VERSION ""

NS_ :

BS_:

BU_: MBMU PC SBMU IMM ETH DCDC LEMS

BO_ 2336485024 M2P_SUMDATA60__16: 8 MBMU
 SG_ M2P_Measure_Vol_B10_16 : 0|16@1+ (0.1,0) [0|6553.5] "V"  PC,SBMU
 SG_ M2P_Current_B10_16 : 16|16@1+ (1,-20000) [-20000|45535] "A"  PC,SBMU
 SG_ M2P_PermitMaxCharge_I_B10_16 : 32|16@1+ (1,-20000) [-20000|45535] "A"  PC
 SG_ M2P_PermitMaxDisCharge_I_B10_16 : 48|16@1+ (1,-20000) [-20000|45535] "A"  PC

BO_ 2336485025 M2P_SUMDATA60__17: 8 MBMU
 SG_ M2P_Measure_Vol_B10_17 : 0|16@1+ (0.1,0) [0|6553.5] "V"  PC,SBMU
 SG_ M2P_Current_B10_17 : 16|16@1+ (1,-20000) [-20000|45535] "A"  PC,SBMU
 SG_ M2P_PermitMaxCharge_I_B10_17 : 32|16@1+ (1,-20000) [-20000|45535] "A"  PC
 SG_ M2P_PermitMaxDisCharge_I_B10_17 : 48|16@1+ (1,-20000) [-20000|45535] "A"  PC

BO_ 2336485026 M2P_SUMDATA60__18: 8 MBMU
 SG_ M2P_Measure_Vol_B10_18 : 0|16@1+ (0.1,0) [0|6553.5] "V"  PC,SBMU
 SG_ M2P_Current_B10_18 : 16|16@1+ (1,-20000) [-20000|45535] "A"  PC,SBMU
 SG_ M2P_PermitMaxCharge_I_B10_18 : 32|16@1+ (1,-20000) [-20000|45535] "A"  PC
 SG_ M2P_PermitMaxDisCharge_I_B10_18 : 48|16@1+ (1,-20000) [-20000|45535] "A"  PC

BO_ 2336485027 M2P_SUMDATA60__19: 8 MBMU
 SG_ M2P_Measure_Vol_B10_19 : 0|16@1+ (0.1,0) [0|6553.5] "V"  PC,SBMU
 SG_ M2P_Current_B10_19 : 16|16@1+ (1,-20000) [-20000|45535] "A"  PC,SBMU
 SG_ M2P_PermitMaxCharge_I_B10_19 : 32|16@1+ (1,-20000) [-20000|45535] "A"  PC
 SG_ M2P_PermitMaxDisCharge_I_B10_19 : 48|16@1+ (1,-20000) [-20000|45535] "A"  PC

BO_ 2336485028 M2P_SUMDATA60__20: 8 MBMU
 SG_ M2P_Measure_Vol_B10_20 : 0|16@1+ (0.1,0) [0|6553.5] "V"  PC,SBMU
 SG_ M2P_Current_B10_20 : 16|16@1+ (1,-20000) [-20000|45535] "A"  PC,SBMU
 SG_ M2P_PermitMaxCharge_I_B10_20 : 32|16@1+ (1,-20000) [-20000|45535] "A"  PC
 SG_ M2P_PermitMaxDisCharge_I_B10_20 : 48|16@1+ (1,-20000) [-20000|45535] "A"  PC

BO_ 2336485029 M2P_SUMDATA60__21: 8 MBMU
 SG_ M2P_Measure_Vol_B10_21 : 0|16@1+ (0.1,0) [0|6553.5] "V"  PC,SBMU
 SG_ M2P_Current_B10_21 : 16|16@1+ (1,-20000) [-20000|45535] "A"  PC,SBMU
 SG_ M2P_PermitMaxCharge_I_B10_21 : 32|16@1+ (1,-20000) [-20000|45535] "A"  PC
 SG_ M2P_PermitMaxDisCharge_I_B10_21 : 48|16@1+ (1,-20000) [-20000|45535] "A"  PC

BO_ 2336485030 M2P_SUMDATA60__22: 8 MBMU
 SG_ M2P_Measure_Vol_B10_22 : 0|16@1+ (0.1,0) [0|6553.5] "V"  PC,SBMU
 SG_ M2P_Current_B10_22 : 16|16@1+ (1,-20000) [-20000|45535] "A"  PC,SBMU
 SG_ M2P_PermitMaxCharge_I_B10_22 : 32|16@1+ (1,-20000) [-20000|45535] "A"  PC
 SG_ M2P_PermitMaxDisCharge_I_B10_22 : 48|16@1+ (1,-20000) [-20000|45535] "A"  PC

BO_ 2336485031 M2P_SUMDATA60__23: 8 MBMU
 SG_ M2P_Measure_Vol_B10_23 : 0|16@1+ (0.1,0) [0|6553.5] "V"  PC,SBMU
 SG_ M2P_Current_B10_23 : 16|16@1+ (1,-20000) [-20000|45535] "A"  PC,SBMU
 SG_ M2P_PermitMaxCharge_I_B10_23 : 32|16@1+ (1,-20000) [-20000|45535] "A"  PC
 SG_ M2P_PermitMaxDisCharge_I_B10_23 : 48|16@1+ (1,-20000) [-20000|45535] "A"  PC

BO_ 2336485032 M2P_SUMDATA60__24: 8 MBMU
 SG_ M2P_Measure_Vol_B10_24 : 0|16@1+ (0.1,0) [0|6553.5] "V"  PC,SBMU
 SG_ M2P_Current_B10_24 : 16|16@1+ (1,-20000) [-20000|45535] "A"  PC,SBMU
 SG_ M2P_PermitMaxCharge_I_B10_24 : 32|16@1+ (1,-20000) [-20000|45535] "A"  PC
 SG_ M2P_PermitMaxDisCharge_I_B10_24 : 48|16@1+ (1,-20000) [-20000|45535] "A"  PC

BO_ 2336485033 M2P_SUMDATA60__25: 8 MBMU
 SG_ M2P_Measure_Vol_B10_25 : 0|16@1+ (0.1,0) [0|6553.5] "V"  PC,SBMU
 SG_ M2P_Current_B10_25 : 16|16@1+ (1,-20000) [-20000|45535] "A"  PC,SBMU
 SG_ M2P_PermitMaxCharge_I_B10_25 : 32|16@1+ (1,-20000) [-20000|45535] "A"  PC
 SG_ M2P_PermitMaxDisCharge_I_B10_25 : 48|16@1+ (1,-20000) [-20000|45535] "A"  PC

BO_ 2336485034 M2P_SUMDATA60__26: 8 MBMU
 SG_ M2P_Measure_Vol_B10_26 : 0|16@1+ (0.1,0) [0|6553.5] "V"  PC,SBMU
 SG_ M2P_Current_B10_26 : 16|16@1+ (1,-20000) [-20000|45535] "A"  PC,SBMU
 SG_ M2P_PermitMaxCharge_I_B10_26 : 32|16@1+ (1,-20000) [-20000|45535] "A"  PC
 SG_ M2P_PermitMaxDisCharge_I_B10_26 : 48|16@1+ (1,-20000) [-20000|45535] "A"  PC

BO_ 2336485035 M2P_SUMDATA60__27: 8 MBMU
 SG_ M2P_Measure_Vol_B10_27 : 0|16@1+ (0.1,0) [0|6553.5] "V"  PC,SBMU
 SG_ M2P_Current_B10_27 : 16|16@1+ (1,-20000) [-20000|45535] "A"  PC,SBMU
 SG_ M2P_PermitMaxCharge_I_B10_27 : 32|16@1+ (1,-20000) [-20000|45535] "A"  PC
 SG_ M2P_PermitMaxDisCharge_I_B10_27 : 48|16@1+ (1,-20000) [-20000|45535] "A"  PC

BO_ 2336485036 M2P_SUMDATA60__28: 8 MBMU
 SG_ M2P_Measure_Vol_B10_28 : 0|16@1+ (0.1,0) [0|6553.5] "V"  PC,SBMU
 SG_ M2P_Current_B10_28 : 16|16@1+ (1,-20000) [-20000|45535] "A"  PC,SBMU
 SG_ M2P_PermitMaxCharge_I_B10_28 : 32|16@1+ (1,-20000) [-20000|45535] "A"  PC
 SG_ M2P_PermitMaxDisCharge_I_B10_28 : 48|16@1+ (1,-20000) [-20000|45535] "A"  PC

BO_ 2336485037 M2P_SUMDATA60__29: 8 MBMU
 SG_ M2P_Measure_Vol_B10_29 : 0|16@1+ (0.1,0) [0|6553.5] "V"  PC,SBMU
 SG_ M2P_Current_B10_29 : 16|16@1+ (1,-20000) [-20000|45535] "A"  PC,SBMU
 SG_ M2P_PermitMaxCharge_I_B10_29 : 32|16@1+ (1,-20000) [-20000|45535] "A"  PC
 SG_ M2P_PermitMaxDisCharge_I_B10_29 : 48|16@1+ (1,-20000) [-20000|45535] "A"  PC

BO_ 2336485038 M2P_SUMDATA60__30: 8 MBMU
 SG_ M2P_Measure_Vol_B10_30 : 0|16@1+ (0.1,0) [0|6553.5] "V"  PC,SBMU
 SG_ M2P_Current_B10_30 : 16|16@1+ (1,-20000) [-20000|45535] "A"  PC,SBMU
 SG_ M2P_PermitMaxCharge_I_B10_30 : 32|16@1+ (1,-20000) [-20000|45535] "A"  PC
 SG_ M2P_PermitMaxDisCharge_I_B10_30 : 48|16@1+ (1,-20000) [-20000|45535] "A"  PC

BO_ 2336485039 M2P_SUMDATA60__31: 8 MBMU
 SG_ M2P_Measure_Vol_B10_31 : 0|16@1+ (0.1,0) [0|6553.5] "V"  PC,SBMU
 SG_ M2P_Current_B10_31 : 16|16@1+ (1,-20000) [-20000|45535] "A"  PC,SBMU
 SG_ M2P_PermitMaxCharge_I_B10_31 : 32|16@1+ (1,-20000) [-20000|45535] "A"  PC
 SG_ M2P_PermitMaxDisCharge_I_B10_31 : 48|16@1+ (1,-20000) [-20000|45535] "A"  PC

BO_ 2336550545 M2P_SUMDATA61__01: 8 MBMU
 SG_ M2P_PermitMaxVolt_B10_01 : 0|16@1+ (0.1,0) [0|6553.5] "V"  PC
 SG_ M2P_PermitMinVolt_B10_01 : 16|16@1+ (0.1,0) [0|6553.5] "V"  PC
 SG_ M2P_PermitMaxPow_Chg_B10_01 : 32|16@1+ (1,-20000) [-20000|45535] "Kw"  PC
 SG_ M2P_PermitMaxPow_DisChg_B10_01 : 48|16@1+ (1,-20000) [-20000|45535] "Kw"  PC

BO_ 2336550546 M2P_SUMDATA61__02: 8 MBMU
 SG_ M2P_PermitMaxVolt_B10_02 : 0|16@1+ (0.1,0) [0|6553.5] "V"  PC
 SG_ M2P_PermitMinVolt_B10_02 : 16|16@1+ (0.1,0) [0|6553.5] "V"  PC
 SG_ M2P_PermitMaxPow_Chg_B10_02 : 32|16@1+ (1,-20000) [-20000|45535] "Kw"  PC
 SG_ M2P_PermitMaxPow_DisChg_B10_02 : 48|16@1+ (1,-20000) [-20000|45535] "Kw"  PC

BO_ 2336550547 M2P_SUMDATA61__03: 8 MBMU
 SG_ M2P_PermitMaxVolt_B10_03 : 0|16@1+ (0.1,0) [0|6553.5] "V"  PC
 SG_ M2P_PermitMinVolt_B10_03 : 16|16@1+ (0.1,0) [0|6553.5] "V"  PC
 SG_ M2P_PermitMaxPow_Chg_B10_03 : 32|16@1+ (1,-20000) [-20000|45535] "Kw"  PC
 SG_ M2P_PermitMaxPow_DisChg_B10_03 : 48|16@1+ (1,-20000) [-20000|45535] "Kw"  PC

BO_ 2336550548 M2P_SUMDATA61__04: 8 MBMU
 SG_ M2P_PermitMaxVolt_B10_04 : 0|16@1+ (0.1,0) [0|6553.5] "V"  PC
 SG_ M2P_PermitMinVolt_B10_04 : 16|16@1+ (0.1,0) [0|6553.5] "V"  PC
 SG_ M2P_PermitMaxPow_Chg_B10_04 : 32|16@1+ (1,-20000) [-20000|45535] "Kw"  PC
 SG_ M2P_PermitMaxPow_DisChg_B10_04 : 48|16@1+ (1,-20000) [-20000|45535] "Kw"  PC

BO_ 2336550549 M2P_SUMDATA61__05: 8 MBMU
 SG_ M2P_PermitMaxVolt_B10_05 : 0|16@1+ (0.1,0) [0|6553.5] "V"  PC
 SG_ M2P_PermitMinVolt_B10_05 : 16|16@1+ (0.1,0) [0|6553.5] "V"  PC
 SG_ M2P_PermitMaxPow_Chg_B10_05 : 32|16@1+ (1,-20000) [-20000|45535] "Kw"  PC
 SG_ M2P_PermitMaxPow_DisChg_B10_05 : 48|16@1+ (1,-20000) [-20000|45535] "Kw"  PC

BO_ 2336550550 M2P_SUMDATA61__06: 8 MBMU
 SG_ M2P_PermitMaxVolt_B10_06 : 0|16@1+ (0.1,0) [0|6553.5] "V"  PC
 SG_ M2P_PermitMinVolt_B10_06 : 16|16@1+ (0.1,0) [0|6553.5] "V"  PC
 SG_ M2P_PermitMaxPow_Chg_B10_06 : 32|16@1+ (1,-20000) [-20000|45535] "Kw"  PC
 SG_ M2P_PermitMaxPow_DisChg_B10_06 : 48|16@1+ (1,-20000) [-20000|45535] "Kw"  PC

BO_ 2336550551 M2P_SUMDATA61__07: 8 MBMU
 SG_ M2P_PermitMaxVolt_B10_07 : 0|16@1+ (0.1,0) [0|6553.5] "V"  PC
 SG_ M2P_PermitMinVolt_B10_07 : 16|16@1+ (0.1,0) [0|6553.5] "V"  PC
 SG_ M2P_PermitMaxPow_Chg_B10_07 : 32|16@1+ (1,-20000) [-20000|45535] "Kw"  PC
 SG_ M2P_PermitMaxPow_DisChg_B10_07 : 48|16@1+ (1,-20000) [-20000|45535] "Kw"  PC

BO_ 2336550552 M2P_SUMDATA61__08: 8 MBMU
 SG_ M2P_PermitMaxVolt_B10_08 : 0|16@1+ (0.1,0) [0|6553.5] "V"  PC
 SG_ M2P_PermitMinVolt_B10_08 : 16|16@1+ (0.1,0) [0|6553.5] "V"  PC
 SG_ M2P_PermitMaxPow_Chg_B10_08 : 32|16@1+ (1,-20000) [-20000|45535] "Kw"  PC
 SG_ M2P_PermitMaxPow_DisChg_B10_08 : 48|16@1+ (1,-20000) [-20000|45535] "Kw"  PC

BO_ 2336550553 M2P_SUMDATA61__09: 8 MBMU
 SG_ M2P_PermitMaxVolt_B10_09 : 0|16@1+ (0.1,0) [0|6553.5] "V"  PC
 SG_ M2P_PermitMinVolt_B10_09 : 16|16@1+ (0.1,0) [0|6553.5] "V"  PC
 SG_ M2P_PermitMaxPow_Chg_B10_09 : 32|16@1+ (1,-20000) [-20000|45535] "Kw"  PC
 SG_ M2P_PermitMaxPow_DisChg_B10_09 : 48|16@1+ (1,-20000) [-20000|45535] "Kw"  PC

BO_ 2336550554 M2P_SUMDATA61__10: 8 MBMU
 SG_ M2P_PermitMaxVolt_B10_10 : 0|16@1+ (0.1,0) [0|6553.5] "V"  PC
 SG_ M2P_PermitMinVolt_B10_10 : 16|16@1+ (0.1,0) [0|6553.5] "V"  PC
 SG_ M2P_PermitMaxPow_Chg_B10_10 : 32|16@1+ (1,-20000) [-20000|45535] "Kw"  PC
 SG_ M2P_PermitMaxPow_DisChg_B10_10 : 48|16@1+ (1,-20000) [-20000|45535] "Kw"  PC

BO_ 2336550555 M2P_SUMDATA61__11: 8 MBMU
 SG_ M2P_PermitMaxVolt_B10_11 : 0|16@1+ (0.1,0) [0|6553.5] "V"  PC
 SG_ M2P_PermitMinVolt_B10_11 : 16|16@1+ (0.1,0) [0|6553.5] "V"  PC
 SG_ M2P_PermitMaxPow_Chg_B10_11 : 32|16@1+ (1,-20000) [-20000|45535] "Kw"  PC
 SG_ M2P_PermitMaxPow_DisChg_B10_11 : 48|16@1+ (1,-20000) [-20000|45535] "Kw"  PC

BO_ 2336550556 M2P_SUMDATA61__12: 8 MBMU
 SG_ M2P_PermitMaxVolt_B10_12 : 0|16@1+ (0.1,0) [0|6553.5] "V"  PC
 SG_ M2P_PermitMinVolt_B10_12 : 16|16@1+ (0.1,0) [0|6553.5] "V"  PC
 SG_ M2P_PermitMaxPow_Chg_B10_12 : 32|16@1+ (1,-20000) [-20000|45535] "Kw"  PC
 SG_ M2P_PermitMaxPow_DisChg_B10_12 : 48|16@1+ (1,-20000) [-20000|45535] "Kw"  PC

BO_ 2336550557 M2P_SUMDATA61__13: 8 MBMU
 SG_ M2P_PermitMaxVolt_B10_13 : 0|16@1+ (0.1,0) [0|6553.5] "V"  PC
 SG_ M2P_PermitMinVolt_B10_13 : 16|16@1+ (0.1,0) [0|6553.5] "V"  PC
 SG_ M2P_PermitMaxPow_Chg_B10_13 : 32|16@1+ (1,-20000) [-20000|45535] "Kw"  PC
 SG_ M2P_PermitMaxPow_DisChg_B10_13 : 48|16@1+ (1,-20000) [-20000|45535] "Kw"  PC

BO_ 2336550558 M2P_SUMDATA61__14: 8 MBMU
 SG_ M2P_PermitMaxVolt_B10_14 : 0|16@1+ (0.1,0) [0|6553.5] "V"  PC
 SG_ M2P_PermitMinVolt_B10_14 : 16|16@1+ (0.1,0) [0|6553.5] "V"  PC
 SG_ M2P_PermitMaxPow_Chg_B10_14 : 32|16@1+ (1,-20000) [-20000|45535] "Kw"  PC
 SG_ M2P_PermitMaxPow_DisChg_B10_14 : 48|16@1+ (1,-20000) [-20000|45535] "Kw"  PC

BO_ 2336550559 M2P_SUMDATA61__15: 8 MBMU
 SG_ M2P_PermitMaxVolt_B10_15 : 0|16@1+ (0.1,0) [0|6553.5] "V"  PC
 SG_ M2P_PermitMinVolt_B10_15 : 16|16@1+ (0.1,0) [0|6553.5] "V"  PC
 SG_ M2P_PermitMaxPow_Chg_B10_15 : 32|16@1+ (1,-20000) [-20000|45535] "Kw"  PC
 SG_ M2P_PermitMaxPow_DisChg_B10_15 : 48|16@1+ (1,-20000) [-20000|45535] "Kw"  PC

BO_ 2336550560 M2P_SUMDATA61__16: 8 MBMU
 SG_ M2P_PermitMaxVolt_B10_16 : 0|16@1+ (0.1,0) [0|6553.5] "V"  PC
 SG_ M2P_PermitMinVolt_B10_16 : 16|16@1+ (0.1,0) [0|6553.5] "V"  PC
 SG_ M2P_PermitMaxPow_Chg_B10_16 : 32|16@1+ (1,-20000) [-20000|45535] "Kw"  PC
 SG_ M2P_PermitMaxPow_DisChg_B10_16 : 48|16@1+ (1,-20000) [-20000|45535] "Kw"  PC

BO_ 2336550561 M2P_SUMDATA61__17: 8 MBMU
 SG_ M2P_PermitMaxVolt_B10_17 : 0|16@1+ (0.1,0) [0|6553.5] "V"  PC
 SG_ M2P_PermitMinVolt_B10_17 : 16|16@1+ (0.1,0) [0|6553.5] "V"  PC
 SG_ M2P_PermitMaxPow_Chg_B10_17 : 32|16@1+ (1,-20000) [-20000|45535] "Kw"  PC
 SG_ M2P_PermitMaxPow_DisChg_B10_17 : 48|16@1+ (1,-20000) [-20000|45535] "Kw"  PC

BO_ 2336550562 M2P_SUMDATA61__18: 8 MBMU
 SG_ M2P_PermitMaxVolt_B10_18 : 0|16@1+ (0.1,0) [0|6553.5] "V"  PC
 SG_ M2P_PermitMinVolt_B10_18 : 16|16@1+ (0.1,0) [0|6553.5] "V"  PC
 SG_ M2P_PermitMaxPow_Chg_B10_18 : 32|16@1+ (1,-20000) [-20000|45535] "Kw"  PC
 SG_ M2P_PermitMaxPow_DisChg_B10_18 : 48|16@1+ (1,-20000) [-20000|45535] "Kw"  PC

BO_ 2336550563 M2P_SUMDATA61__19: 8 MBMU
 SG_ M2P_PermitMaxVolt_B10_19 : 0|16@1+ (0.1,0) [0|6553.5] "V"  PC
 SG_ M2P_PermitMinVolt_B10_19 : 16|16@1+ (0.1,0) [0|6553.5] "V"  PC
 SG_ M2P_PermitMaxPow_Chg_B10_19 : 32|16@1+ (1,-20000) [-20000|45535] "Kw"  PC
 SG_ M2P_PermitMaxPow_DisChg_B10_19 : 48|16@1+ (1,-20000) [-20000|45535] "Kw"  PC

BO_ 2336550564 M2P_SUMDATA61__20: 8 MBMU
 SG_ M2P_PermitMaxVolt_B10_20 : 0|16@1+ (0.1,0) [0|6553.5] "V"  PC
 SG_ M2P_PermitMinVolt_B10_20 : 16|16@1+ (0.1,0) [0|6553.5] "V"  PC
 SG_ M2P_PermitMaxPow_Chg_B10_20 : 32|16@1+ (1,-20000) [-20000|45535] "Kw"  PC
 SG_ M2P_PermitMaxPow_DisChg_B10_20 : 48|16@1+ (1,-20000) [-20000|45535] "Kw"  PC

BO_ 2336550565 M2P_SUMDATA61__21: 8 MBMU
 SG_ M2P_PermitMaxVolt_B10_21 : 0|16@1+ (0.1,0) [0|6553.5] "V"  PC
 SG_ M2P_PermitMinVolt_B10_21 : 16|16@1+ (0.1,0) [0|6553.5] "V"  PC
 SG_ M2P_PermitMaxPow_Chg_B10_21 : 32|16@1+ (1,-20000) [-20000|45535] "Kw"  PC
 SG_ M2P_PermitMaxPow_DisChg_B10_21 : 48|16@1+ (1,-20000) [-20000|45535] "Kw"  PC

BO_ 2336550566 M2P_SUMDATA61__22: 8 MBMU
 SG_ M2P_PermitMaxVolt_B10_22 : 0|16@1+ (0.1,0) [0|6553.5] "V"  PC
 SG_ M2P_PermitMinVolt_B10_22 : 16|16@1+ (0.1,0) [0|6553.5] "V"  PC
 SG_ M2P_PermitMaxPow_Chg_B10_22 : 32|16@1+ (1,-20000) [-20000|45535] "Kw"  PC
 SG_ M2P_PermitMaxPow_DisChg_B10_22 : 48|16@1+ (1,-20000) [-20000|45535] "Kw"  PC

BO_ 2336550567 M2P_SUMDATA61__23: 8 MBMU
 SG_ M2P_PermitMaxVolt_B10_23 : 0|16@1+ (0.1,0) [0|6553.5] "V"  PC
 SG_ M2P_PermitMinVolt_B10_23 : 16|16@1+ (0.1,0) [0|6553.5] "V"  PC
 SG_ M2P_PermitMaxPow_Chg_B10_23 : 32|16@1+ (1,-20000) [-20000|45535] "Kw"  PC
 SG_ M2P_PermitMaxPow_DisChg_B10_23 : 48|16@1+ (1,-20000) [-20000|45535] "Kw"  PC

BO_ 2336550568 M2P_SUMDATA61__24: 8 MBMU
 SG_ M2P_PermitMaxVolt_B10_24 : 0|16@1+ (0.1,0) [0|6553.5] "V"  PC
 SG_ M2P_PermitMinVolt_B10_24 : 16|16@1+ (0.1,0) [0|6553.5] "V"  PC
 SG_ M2P_PermitMaxPow_Chg_B10_24 : 32|16@1+ (1,-20000) [-20000|45535] "Kw"  PC
 SG_ M2P_PermitMaxPow_DisChg_B10_24 : 48|16@1+ (1,-20000) [-20000|45535] "Kw"  PC

BO_ 2336550569 M2P_SUMDATA61__25: 8 MBMU
 SG_ M2P_PermitMaxVolt_B10_25 : 0|16@1+ (0.1,0) [0|6553.5] "V"  PC
 SG_ M2P_PermitMinVolt_B10_25 : 16|16@1+ (0.1,0) [0|6553.5] "V"  PC
 SG_ M2P_PermitMaxPow_Chg_B10_25 : 32|16@1+ (1,-20000) [-20000|45535] "Kw"  PC
 SG_ M2P_PermitMaxPow_DisChg_B10_25 : 48|16@1+ (1,-20000) [-20000|45535] "Kw"  PC

BO_ 2336550570 M2P_SUMDATA61__26: 8 MBMU
 SG_ M2P_PermitMaxVolt_B10_26 : 0|16@1+ (0.1,0) [0|6553.5] "V"  PC
 SG_ M2P_PermitMinVolt_B10_26 : 16|16@1+ (0.1,0) [0|6553.5] "V"  PC
 SG_ M2P_PermitMaxPow_Chg_B10_26 : 32|16@1+ (1,-20000) [-20000|45535] "Kw"  PC
 SG_ M2P_PermitMaxPow_DisChg_B10_26 : 48|16@1+ (1,-20000) [-20000|45535] "Kw"  PC

BO_ 2336550571 M2P_SUMDATA61__27: 8 MBMU
 SG_ M2P_PermitMaxVolt_B10_27 : 0|16@1+ (0.1,0) [0|6553.5] "V"  PC
 SG_ M2P_PermitMinVolt_B10_27 : 16|16@1+ (0.1,0) [0|6553.5] "V"  PC
 SG_ M2P_PermitMaxPow_Chg_B10_27 : 32|16@1+ (1,-20000) [-20000|45535] "Kw"  PC
 SG_ M2P_PermitMaxPow_DisChg_B10_27 : 48|16@1+ (1,-20000) [-20000|45535] "Kw"  PC

BO_ 2336550572 M2P_SUMDATA61__28: 8 MBMU
 SG_ M2P_PermitMaxVolt_B10_28 : 0|16@1+ (0.1,0) [0|6553.5] "V"  PC
 SG_ M2P_PermitMinVolt_B10_28 : 16|16@1+ (0.1,0) [0|6553.5] "V"  PC
 SG_ M2P_PermitMaxPow_Chg_B10_28 : 32|16@1+ (1,-20000) [-20000|45535] "Kw"  PC
 SG_ M2P_PermitMaxPow_DisChg_B10_28 : 48|16@1+ (1,-20000) [-20000|45535] "Kw"  PC

BO_ 2336550573 M2P_SUMDATA61__29: 8 MBMU
 SG_ M2P_PermitMaxVolt_B10_29 : 0|16@1+ (0.1,0) [0|6553.5] "V"  PC
 SG_ M2P_PermitMinVolt_B10_29 : 16|16@1+ (0.1,0) [0|6553.5] "V"  PC
 SG_ M2P_PermitMaxPow_Chg_B10_29 : 32|16@1+ (1,-20000) [-20000|45535] "Kw"  PC
 SG_ M2P_PermitMaxPow_DisChg_B10_29 : 48|16@1+ (1,-20000) [-20000|45535] "Kw"  PC

BO_ 2336550574 M2P_SUMDATA61__30: 8 MBMU
 SG_ M2P_PermitMaxVolt_B10_30 : 0|16@1+ (0.1,0) [0|6553.5] "V"  PC
 SG_ M2P_PermitMinVolt_B10_30 : 16|16@1+ (0.1,0) [0|6553.5] "V"  PC
 SG_ M2P_PermitMaxPow_Chg_B10_30 : 32|16@1+ (1,-20000) [-20000|45535] "Kw"  PC
 SG_ M2P_PermitMaxPow_DisChg_B10_30 : 48|16@1+ (1,-20000) [-20000|45535] "Kw"  PC

BO_ 2336550575 M2P_SUMDATA61__31: 8 MBMU
 SG_ M2P_PermitMaxVolt_B10_31 : 0|16@1+ (0.1,0) [0|6553.5] "V"  PC
 SG_ M2P_PermitMinVolt_B10_31 : 16|16@1+ (0.1,0) [0|6553.5] "V"  PC
 SG_ M2P_PermitMaxPow_Chg_B10_31 : 32|16@1+ (1,-20000) [-20000|45535] "Kw"  PC
 SG_ M2P_PermitMaxPow_DisChg_B10_31 : 48|16@1+ (1,-20000) [-20000|45535] "Kw"  PC

BO_ 2336616081 M2P_SUMDATA62__01: 8 MBMU
 SG_ M2P_Power_B10_01 : 0|16@1+ (1,-20000) [-20000|45535] "Kw"  PC
 SG_ M2P_SysremEngy_Chg_B10_01 : 16|16@1+ (1,0) [0|65535] "Kwh"  PC
 SG_ M2P_SysremEngy_DisChg_B10_01 : 32|16@1+ (1,0) [0|65535] "Kwh"  PC
 SG_ M2P_SysMaxVolt_B10_01 : 48|16@1+ (1,0) [0|65535] "mv"  PC

BO_ 2336616082 M2P_SUMDATA62__02: 8 MBMU
 SG_ M2P_Power_B10_02 : 0|16@1+ (1,-20000) [-20000|45535] "Kw"  PC
 SG_ M2P_SysremEngy_Chg_B10_02 : 16|16@1+ (1,0) [0|65535] "Kwh"  PC
 SG_ M2P_SysremEngy_DisChg_B10_02 : 32|16@1+ (1,0) [0|65535] "Kwh"  PC
 SG_ M2P_SysMaxVolt_B10_02 : 48|16@1+ (1,0) [0|65535] "mv"  PC

BO_ 2336616083 M2P_SUMDATA62__03: 8 MBMU
 SG_ M2P_Power_B10_03 : 0|16@1+ (1,-20000) [-20000|45535] "Kw"  PC
 SG_ M2P_SysremEngy_Chg_B10_03 : 16|16@1+ (1,0) [0|65535] "Kwh"  PC
 SG_ M2P_SysremEngy_DisChg_B10_03 : 32|16@1+ (1,0) [0|65535] "Kwh"  PC
 SG_ M2P_SysMaxVolt_B10_03 : 48|16@1+ (1,0) [0|65535] "mv"  PC

BO_ 2336616084 M2P_SUMDATA62__04: 8 MBMU
 SG_ M2P_Power_B10_04 : 0|16@1+ (1,-20000) [-20000|45535] "Kw"  PC
 SG_ M2P_SysremEngy_Chg_B10_04 : 16|16@1+ (1,0) [0|65535] "Kwh"  PC
 SG_ M2P_SysremEngy_DisChg_B10_04 : 32|16@1+ (1,0) [0|65535] "Kwh"  PC
 SG_ M2P_SysMaxVolt_B10_04 : 48|16@1+ (1,0) [0|65535] "mv"  PC

BO_ 2336616085 M2P_SUMDATA62__05: 8 MBMU
 SG_ M2P_Power_B10_05 : 0|16@1+ (1,-20000) [-20000|45535] "Kw"  PC
 SG_ M2P_SysremEngy_Chg_B10_05 : 16|16@1+ (1,0) [0|65535] "Kwh"  PC
 SG_ M2P_SysremEngy_DisChg_B10_05 : 32|16@1+ (1,0) [0|65535] "Kwh"  PC
 SG_ M2P_SysMaxVolt_B10_05 : 48|16@1+ (1,0) [0|65535] "mv"  PC

BO_ 2336616086 M2P_SUMDATA62__06: 8 MBMU
 SG_ M2P_Power_B10_06 : 0|16@1+ (1,-20000) [-20000|45535] "Kw"  PC
 SG_ M2P_SysremEngy_Chg_B10_06 : 16|16@1+ (1,0) [0|65535] "Kwh"  PC
 SG_ M2P_SysremEngy_DisChg_B10_06 : 32|16@1+ (1,0) [0|65535] "Kwh"  PC
 SG_ M2P_SysMaxVolt_B10_06 : 48|16@1+ (1,0) [0|65535] "mv"  PC

BO_ 2336616087 M2P_SUMDATA62__07: 8 MBMU
 SG_ M2P_Power_B10_07 : 0|16@1+ (1,-20000) [-20000|45535] "Kw"  PC
 SG_ M2P_SysremEngy_Chg_B10_07 : 16|16@1+ (1,0) [0|65535] "Kwh"  PC
 SG_ M2P_SysremEngy_DisChg_B10_07 : 32|16@1+ (1,0) [0|65535] "Kwh"  PC
 SG_ M2P_SysMaxVolt_B10_07 : 48|16@1+ (1,0) [0|65535] "mv"  PC

BO_ 2336616088 M2P_SUMDATA62__08: 8 MBMU
 SG_ M2P_Power_B10_08 : 0|16@1+ (1,-20000) [-20000|45535] "Kw"  PC
 SG_ M2P_SysremEngy_Chg_B10_08 : 16|16@1+ (1,0) [0|65535] "Kwh"  PC
 SG_ M2P_SysremEngy_DisChg_B10_08 : 32|16@1+ (1,0) [0|65535] "Kwh"  PC
 SG_ M2P_SysMaxVolt_B10_08 : 48|16@1+ (1,0) [0|65535] "mv"  PC

BO_ 2336616089 M2P_SUMDATA62__09: 8 MBMU
 SG_ M2P_Power_B10_09 : 0|16@1+ (1,-20000) [-20000|45535] "Kw"  PC
 SG_ M2P_SysremEngy_Chg_B10_09 : 16|16@1+ (1,0) [0|65535] "Kwh"  PC
 SG_ M2P_SysremEngy_DisChg_B10_09 : 32|16@1+ (1,0) [0|65535] "Kwh"  PC
 SG_ M2P_SysMaxVolt_B10_09 : 48|16@1+ (1,0) [0|65535] "mv"  PC

BO_ 2336616090 M2P_SUMDATA62__10: 8 MBMU
 SG_ M2P_Power_B10_10 : 0|16@1+ (1,-20000) [-20000|45535] "Kw"  PC
 SG_ M2P_SysremEngy_Chg_B10_10 : 16|16@1+ (1,0) [0|65535] "Kwh"  PC
 SG_ M2P_SysremEngy_DisChg_B10_10 : 32|16@1+ (1,0) [0|65535] "Kwh"  PC
 SG_ M2P_SysMaxVolt_B10_10 : 48|16@1+ (1,0) [0|65535] "mv"  PC

BO_ 2336616091 M2P_SUMDATA62__11: 8 MBMU
 SG_ M2P_Power_B10_11 : 0|16@1+ (1,-20000) [-20000|45535] "Kw"  PC
 SG_ M2P_SysremEngy_Chg_B10_11 : 16|16@1+ (1,0) [0|65535] "Kwh"  PC
 SG_ M2P_SysremEngy_DisChg_B10_11 : 32|16@1+ (1,0) [0|65535] "Kwh"  PC
 SG_ M2P_SysMaxVolt_B10_11 : 48|16@1+ (1,0) [0|65535] "mv"  PC

BO_ 2336616092 M2P_SUMDATA62__12: 8 MBMU
 SG_ M2P_Power_B10_12 : 0|16@1+ (1,-20000) [-20000|45535] "Kw"  PC
 SG_ M2P_SysremEngy_Chg_B10_12 : 16|16@1+ (1,0) [0|65535] "Kwh"  PC
 SG_ M2P_SysremEngy_DisChg_B10_12 : 32|16@1+ (1,0) [0|65535] "Kwh"  PC
 SG_ M2P_SysMaxVolt_B10_12 : 48|16@1+ (1,0) [0|65535] "mv"  PC

BO_ 2336616093 M2P_SUMDATA62__13: 8 MBMU
 SG_ M2P_Power_B10_13 : 0|16@1+ (1,-20000) [-20000|45535] "Kw"  PC
 SG_ M2P_SysremEngy_Chg_B10_13 : 16|16@1+ (1,0) [0|65535] "Kwh"  PC
 SG_ M2P_SysremEngy_DisChg_B10_13 : 32|16@1+ (1,0) [0|65535] "Kwh"  PC
 SG_ M2P_SysMaxVolt_B10_13 : 48|16@1+ (1,0) [0|65535] "mv"  PC

BO_ 2336616094 M2P_SUMDATA62__14: 8 MBMU
 SG_ M2P_Power_B10_14 : 0|16@1+ (1,-20000) [-20000|45535] "Kw"  PC
 SG_ M2P_SysremEngy_Chg_B10_14 : 16|16@1+ (1,0) [0|65535] "Kwh"  PC
 SG_ M2P_SysremEngy_DisChg_B10_14 : 32|16@1+ (1,0) [0|65535] "Kwh"  PC
 SG_ M2P_SysMaxVolt_B10_14 : 48|16@1+ (1,0) [0|65535] "mv"  PC

BO_ 2336616095 M2P_SUMDATA62__15: 8 MBMU
 SG_ M2P_Power_B10_15 : 0|16@1+ (1,-20000) [-20000|45535] "Kw"  PC
 SG_ M2P_SysremEngy_Chg_B10_15 : 16|16@1+ (1,0) [0|65535] "Kwh"  PC
 SG_ M2P_SysremEngy_DisChg_B10_15 : 32|16@1+ (1,0) [0|65535] "Kwh"  PC
 SG_ M2P_SysMaxVolt_B10_15 : 48|16@1+ (1,0) [0|65535] "mv"  PC

BO_ 2336616096 M2P_SUMDATA62__16: 8 MBMU
 SG_ M2P_Power_B10_16 : 0|16@1+ (1,-20000) [-20000|45535] "Kw"  PC
 SG_ M2P_SysremEngy_Chg_B10_16 : 16|16@1+ (1,0) [0|65535] "Kwh"  PC
 SG_ M2P_SysremEngy_DisChg_B10_16 : 32|16@1+ (1,0) [0|65535] "Kwh"  PC
 SG_ M2P_SysMaxVolt_B10_16 : 48|16@1+ (1,0) [0|65535] "mv"  PC

BO_ 2336616097 M2P_SUMDATA62__17: 8 MBMU
 SG_ M2P_Power_B10_17 : 0|16@1+ (1,-20000) [-20000|45535] "Kw"  PC
 SG_ M2P_SysremEngy_Chg_B10_17 : 16|16@1+ (1,0) [0|65535] "Kwh"  PC
 SG_ M2P_SysremEngy_DisChg_B10_17 : 32|16@1+ (1,0) [0|65535] "Kwh"  PC
 SG_ M2P_SysMaxVolt_B10_17 : 48|16@1+ (1,0) [0|65535] "mv"  PC

BO_ 2336616098 M2P_SUMDATA62__18: 8 MBMU
 SG_ M2P_Power_B10_18 : 0|16@1+ (1,-20000) [-20000|45535] "Kw"  PC
 SG_ M2P_SysremEngy_Chg_B10_18 : 16|16@1+ (1,0) [0|65535] "Kwh"  PC
 SG_ M2P_SysremEngy_DisChg_B10_18 : 32|16@1+ (1,0) [0|65535] "Kwh"  PC
 SG_ M2P_SysMaxVolt_B10_18 : 48|16@1+ (1,0) [0|65535] "mv"  PC

BO_ 2336616099 M2P_SUMDATA62__19: 8 MBMU
 SG_ M2P_Power_B10_19 : 0|16@1+ (1,-20000) [-20000|45535] "Kw"  PC
 SG_ M2P_SysremEngy_Chg_B10_19 : 16|16@1+ (1,0) [0|65535] "Kwh"  PC
 SG_ M2P_SysremEngy_DisChg_B10_19 : 32|16@1+ (1,0) [0|65535] "Kwh"  PC
 SG_ M2P_SysMaxVolt_B10_19 : 48|16@1+ (1,0) [0|65535] "mv"  PC

BO_ 2336616100 M2P_SUMDATA62__20: 8 MBMU
 SG_ M2P_Power_B10_20 : 0|16@1+ (1,-20000) [-20000|45535] "Kw"  PC
 SG_ M2P_SysremEngy_Chg_B10_20 : 16|16@1+ (1,0) [0|65535] "Kwh"  PC
 SG_ M2P_SysremEngy_DisChg_B10_20 : 32|16@1+ (1,0) [0|65535] "Kwh"  PC
 SG_ M2P_SysMaxVolt_B10_20 : 48|16@1+ (1,0) [0|65535] "mv"  PC

BO_ 2336616101 M2P_SUMDATA62__21: 8 MBMU
 SG_ M2P_Power_B10_21 : 0|16@1+ (1,-20000) [-20000|45535] "Kw"  PC
 SG_ M2P_SysremEngy_Chg_B10_21 : 16|16@1+ (1,0) [0|65535] "Kwh"  PC
 SG_ M2P_SysremEngy_DisChg_B10_21 : 32|16@1+ (1,0) [0|65535] "Kwh"  PC
 SG_ M2P_SysMaxVolt_B10_21 : 48|16@1+ (1,0) [0|65535] "mv"  PC

BO_ 2336616102 M2P_SUMDATA62__22: 8 MBMU
 SG_ M2P_Power_B10_22 : 0|16@1+ (1,-20000) [-20000|45535] "Kw"  PC
 SG_ M2P_SysremEngy_Chg_B10_22 : 16|16@1+ (1,0) [0|65535] "Kwh"  PC
 SG_ M2P_SysremEngy_DisChg_B10_22 : 32|16@1+ (1,0) [0|65535] "Kwh"  PC
 SG_ M2P_SysMaxVolt_B10_22 : 48|16@1+ (1,0) [0|65535] "mv"  PC

BO_ 2336616103 M2P_SUMDATA62__23: 8 MBMU
 SG_ M2P_Power_B10_23 : 0|16@1+ (1,-20000) [-20000|45535] "Kw"  PC
 SG_ M2P_SysremEngy_Chg_B10_23 : 16|16@1+ (1,0) [0|65535] "Kwh"  PC
 SG_ M2P_SysremEngy_DisChg_B10_23 : 32|16@1+ (1,0) [0|65535] "Kwh"  PC
 SG_ M2P_SysMaxVolt_B10_23 : 48|16@1+ (1,0) [0|65535] "mv"  PC

BO_ 2336616104 M2P_SUMDATA62__24: 8 MBMU
 SG_ M2P_Power_B10_24 : 0|16@1+ (1,-20000) [-20000|45535] "Kw"  PC
 SG_ M2P_SysremEngy_Chg_B10_24 : 16|16@1+ (1,0) [0|65535] "Kwh"  PC
 SG_ M2P_SysremEngy_DisChg_B10_24 : 32|16@1+ (1,0) [0|65535] "Kwh"  PC
 SG_ M2P_SysMaxVolt_B10_24 : 48|16@1+ (1,0) [0|65535] "mv"  PC

BO_ 2336616105 M2P_SUMDATA62__25: 8 MBMU
 SG_ M2P_Power_B10_25 : 0|16@1+ (1,-20000) [-20000|45535] "Kw"  PC
 SG_ M2P_SysremEngy_Chg_B10_25 : 16|16@1+ (1,0) [0|65535] "Kwh"  PC
 SG_ M2P_SysremEngy_DisChg_B10_25 : 32|16@1+ (1,0) [0|65535] "Kwh"  PC
 SG_ M2P_SysMaxVolt_B10_25 : 48|16@1+ (1,0) [0|65535] "mv"  PC

BO_ 2336616106 M2P_SUMDATA62__26: 8 MBMU
 SG_ M2P_Power_B10_26 : 0|16@1+ (1,-20000) [-20000|45535] "Kw"  PC
 SG_ M2P_SysremEngy_Chg_B10_26 : 16|16@1+ (1,0) [0|65535] "Kwh"  PC
 SG_ M2P_SysremEngy_DisChg_B10_26 : 32|16@1+ (1,0) [0|65535] "Kwh"  PC
 SG_ M2P_SysMaxVolt_B10_26 : 48|16@1+ (1,0) [0|65535] "mv"  PC

BO_ 2336616107 M2P_SUMDATA62__27: 8 MBMU
 SG_ M2P_Power_B10_27 : 0|16@1+ (1,-20000) [-20000|45535] "Kw"  PC
 SG_ M2P_SysremEngy_Chg_B10_27 : 16|16@1+ (1,0) [0|65535] "Kwh"  PC
 SG_ M2P_SysremEngy_DisChg_B10_27 : 32|16@1+ (1,0) [0|65535] "Kwh"  PC
 SG_ M2P_SysMaxVolt_B10_27 : 48|16@1+ (1,0) [0|65535] "mv"  PC

BO_ 2336616108 M2P_SUMDATA62__28: 8 MBMU
 SG_ M2P_Power_B10_28 : 0|16@1+ (1,-20000) [-20000|45535] "Kw"  PC
 SG_ M2P_SysremEngy_Chg_B10_28 : 16|16@1+ (1,0) [0|65535] "Kwh"  PC
 SG_ M2P_SysremEngy_DisChg_B10_28 : 32|16@1+ (1,0) [0|65535] "Kwh"  PC
 SG_ M2P_SysMaxVolt_B10_28 : 48|16@1+ (1,0) [0|65535] "mv"  PC

BO_ 2336616109 M2P_SUMDATA62__29: 8 MBMU
 SG_ M2P_Power_B10_29 : 0|16@1+ (1,-20000) [-20000|45535] "Kw"  PC
 SG_ M2P_SysremEngy_Chg_B10_29 : 16|16@1+ (1,0) [0|65535] "Kwh"  PC
 SG_ M2P_SysremEngy_DisChg_B10_29 : 32|16@1+ (1,0) [0|65535] "Kwh"  PC
 SG_ M2P_SysMaxVolt_B10_29 : 48|16@1+ (1,0) [0|65535] "mv"  PC

BO_ 2336616110 M2P_SUMDATA62__30: 8 MBMU
 SG_ M2P_Power_B10_30 : 0|16@1+ (1,-20000) [-20000|45535] "Kw"  PC
 SG_ M2P_SysremEngy_Chg_B10_30 : 16|16@1+ (1,0) [0|65535] "Kwh"  PC
 SG_ M2P_SysremEngy_DisChg_B10_30 : 32|16@1+ (1,0) [0|65535] "Kwh"  PC
 SG_ M2P_SysMaxVolt_B10_30 : 48|16@1+ (1,0) [0|65535] "mv"  PC

BO_ 2336616111 M2P_SUMDATA62__31: 8 MBMU
 SG_ M2P_Power_B10_31 : 0|16@1+ (1,-20000) [-20000|45535] "Kw"  PC
 SG_ M2P_SysremEngy_Chg_B10_31 : 16|16@1+ (1,0) [0|65535] "Kwh"  PC
 SG_ M2P_SysremEngy_DisChg_B10_31 : 32|16@1+ (1,0) [0|65535] "Kwh"  PC
 SG_ M2P_SysMaxVolt_B10_31 : 48|16@1+ (1,0) [0|65535] "mv"  PC

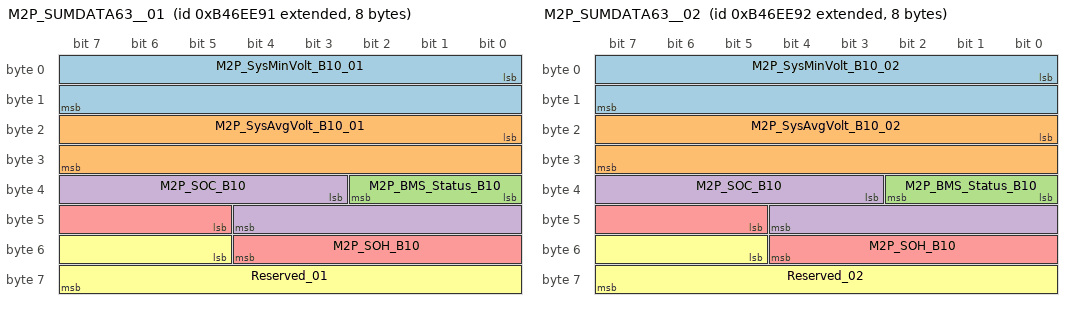
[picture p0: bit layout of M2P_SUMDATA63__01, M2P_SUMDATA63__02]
BO_ 2336681617 M2P_SUMDATA63__01: 8 MBMU
 SG_ M2P_SysMinVolt_B10_01 : 0|16@1+ (1,0) [0|65535] "mv"  PC
 SG_ M2P_SysAvgVolt_B10_01 : 16|16@1+ (1,0) [0|65535] "mv"  PC
 SG_ M2P_BMS_Status_B10 : 32|3@1+ (1,0) [0|7] ""  PC
 SG_ M2P_SOC_B10 : 35|10@1+ (0.1,0) [0|102.3] "%"  PC
 SG_ M2P_SOH_B10 : 45|8@1+ (1,0) [0|255] "%"  PC
 SG_ Reserved_01 : 53|11@1+ (1,0) [0|2047] ""  PC

BO_ 2336681618 M2P_SUMDATA63__02: 8 MBMU
 SG_ M2P_SysMinVolt_B10_02 : 0|16@1+ (1,0) [0|65535] "mv"  PC
 SG_ M2P_SysAvgVolt_B10_02 : 16|16@1+ (1,0) [0|65535] "mv"  PC
 SG_ M2P_BMS_Status_B10 : 32|3@1+ (1,0) [0|7] ""  PC
 SG_ M2P_SOC_B10 : 35|10@1+ (0.1,0) [0|102.3] "%"  PC
 SG_ M2P_SOH_B10 : 45|8@1+ (1,0) [0|255] "%"  PC
 SG_ Reserved_02 : 53|11@1+ (1,0) [0|2047] ""  PC

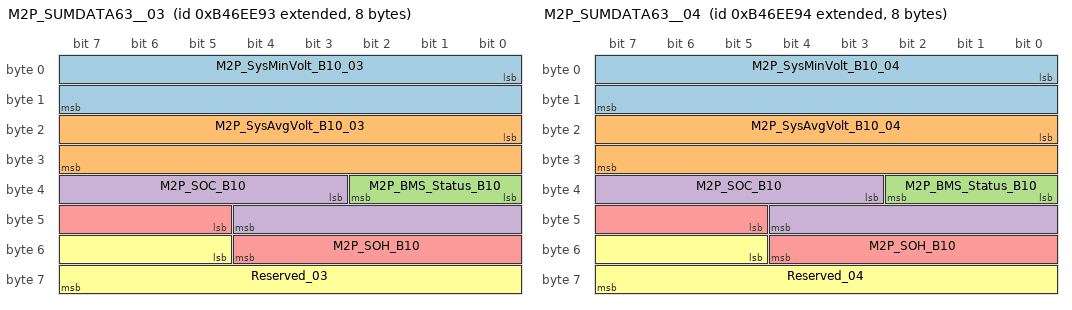
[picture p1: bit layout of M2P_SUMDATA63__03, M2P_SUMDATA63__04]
BO_ 2336681619 M2P_SUMDATA63__03: 8 MBMU
 SG_ M2P_SysMinVolt_B10_03 : 0|16@1+ (1,0) [0|65535] "mv"  PC
 SG_ M2P_SysAvgVolt_B10_03 : 16|16@1+ (1,0) [0|65535] "mv"  PC
 SG_ M2P_BMS_Status_B10 : 32|3@1+ (1,0) [0|7] ""  PC
 SG_ M2P_SOC_B10 : 35|10@1+ (0.1,0) [0|102.3] "%"  PC
 SG_ M2P_SOH_B10 : 45|8@1+ (1,0) [0|255] "%"  PC
 SG_ Reserved_03 : 53|11@1+ (1,0) [0|2047] ""  PC

BO_ 2336681620 M2P_SUMDATA63__04: 8 MBMU
 SG_ M2P_SysMinVolt_B10_04 : 0|16@1+ (1,0) [0|65535] "mv"  PC
 SG_ M2P_SysAvgVolt_B10_04 : 16|16@1+ (1,0) [0|65535] "mv"  PC
 SG_ M2P_BMS_Status_B10 : 32|3@1+ (1,0) [0|7] ""  PC
 SG_ M2P_SOC_B10 : 35|10@1+ (0.1,0) [0|102.3] "%"  PC
 SG_ M2P_SOH_B10 : 45|8@1+ (1,0) [0|255] "%"  PC
 SG_ Reserved_04 : 53|11@1+ (1,0) [0|2047] ""  PC

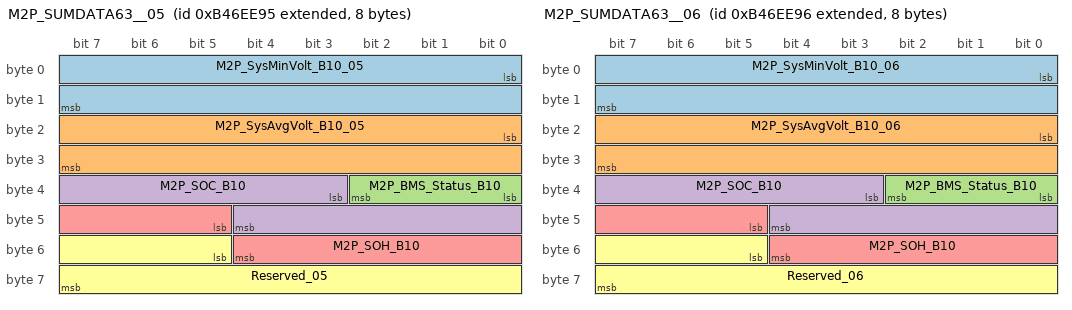
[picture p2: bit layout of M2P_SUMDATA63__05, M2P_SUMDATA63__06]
BO_ 2336681621 M2P_SUMDATA63__05: 8 MBMU
 SG_ M2P_SysMinVolt_B10_05 : 0|16@1+ (1,0) [0|65535] "mv"  PC
 SG_ M2P_SysAvgVolt_B10_05 : 16|16@1+ (1,0) [0|65535] "mv"  PC
 SG_ M2P_BMS_Status_B10 : 32|3@1+ (1,0) [0|7] ""  PC
 SG_ M2P_SOC_B10 : 35|10@1+ (0.1,0) [0|102.3] "%"  PC
 SG_ M2P_SOH_B10 : 45|8@1+ (1,0) [0|255] "%"  PC
 SG_ Reserved_05 : 53|11@1+ (1,0) [0|2047] ""  PC

BO_ 2336681622 M2P_SUMDATA63__06: 8 MBMU
 SG_ M2P_SysMinVolt_B10_06 : 0|16@1+ (1,0) [0|65535] "mv"  PC
 SG_ M2P_SysAvgVolt_B10_06 : 16|16@1+ (1,0) [0|65535] "mv"  PC
 SG_ M2P_BMS_Status_B10 : 32|3@1+ (1,0) [0|7] ""  PC
 SG_ M2P_SOC_B10 : 35|10@1+ (0.1,0) [0|102.3] "%"  PC
 SG_ M2P_SOH_B10 : 45|8@1+ (1,0) [0|255] "%"  PC
 SG_ Reserved_06 : 53|11@1+ (1,0) [0|2047] ""  PC

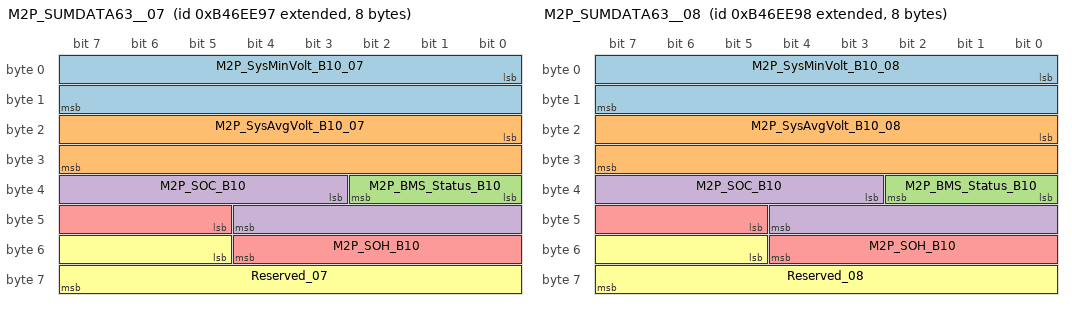
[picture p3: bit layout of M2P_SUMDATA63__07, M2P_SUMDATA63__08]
BO_ 2336681623 M2P_SUMDATA63__07: 8 MBMU
 SG_ M2P_SysMinVolt_B10_07 : 0|16@1+ (1,0) [0|65535] "mv"  PC
 SG_ M2P_SysAvgVolt_B10_07 : 16|16@1+ (1,0) [0|65535] "mv"  PC
 SG_ M2P_BMS_Status_B10 : 32|3@1+ (1,0) [0|7] ""  PC
 SG_ M2P_SOC_B10 : 35|10@1+ (0.1,0) [0|102.3] "%"  PC
 SG_ M2P_SOH_B10 : 45|8@1+ (1,0) [0|255] "%"  PC
 SG_ Reserved_07 : 53|11@1+ (1,0) [0|2047] ""  PC

BO_ 2336681624 M2P_SUMDATA63__08: 8 MBMU
 SG_ M2P_SysMinVolt_B10_08 : 0|16@1+ (1,0) [0|65535] "mv"  PC
 SG_ M2P_SysAvgVolt_B10_08 : 16|16@1+ (1,0) [0|65535] "mv"  PC
 SG_ M2P_BMS_Status_B10 : 32|3@1+ (1,0) [0|7] ""  PC
 SG_ M2P_SOC_B10 : 35|10@1+ (0.1,0) [0|102.3] "%"  PC
 SG_ M2P_SOH_B10 : 45|8@1+ (1,0) [0|255] "%"  PC
 SG_ Reserved_08 : 53|11@1+ (1,0) [0|2047] ""  PC

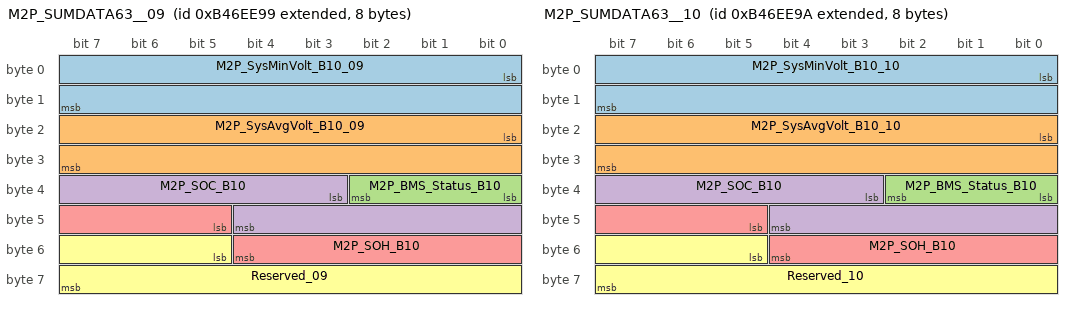
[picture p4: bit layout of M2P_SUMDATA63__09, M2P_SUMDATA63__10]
BO_ 2336681625 M2P_SUMDATA63__09: 8 MBMU
 SG_ M2P_SysMinVolt_B10_09 : 0|16@1+ (1,0) [0|65535] "mv"  PC
 SG_ M2P_SysAvgVolt_B10_09 : 16|16@1+ (1,0) [0|65535] "mv"  PC
 SG_ M2P_BMS_Status_B10 : 32|3@1+ (1,0) [0|7] ""  PC
 SG_ M2P_SOC_B10 : 35|10@1+ (0.1,0) [0|102.3] "%"  PC
 SG_ M2P_SOH_B10 : 45|8@1+ (1,0) [0|255] "%"  PC
 SG_ Reserved_09 : 53|11@1+ (1,0) [0|2047] ""  PC

BO_ 2336681626 M2P_SUMDATA63__10: 8 MBMU
 SG_ M2P_SysMinVolt_B10_10 : 0|16@1+ (1,0) [0|65535] "mv"  PC
 SG_ M2P_SysAvgVolt_B10_10 : 16|16@1+ (1,0) [0|65535] "mv"  PC
 SG_ M2P_BMS_Status_B10 : 32|3@1+ (1,0) [0|7] ""  PC
 SG_ M2P_SOC_B10 : 35|10@1+ (0.1,0) [0|102.3] "%"  PC
 SG_ M2P_SOH_B10 : 45|8@1+ (1,0) [0|255] "%"  PC
 SG_ Reserved_10 : 53|11@1+ (1,0) [0|2047] ""  PC

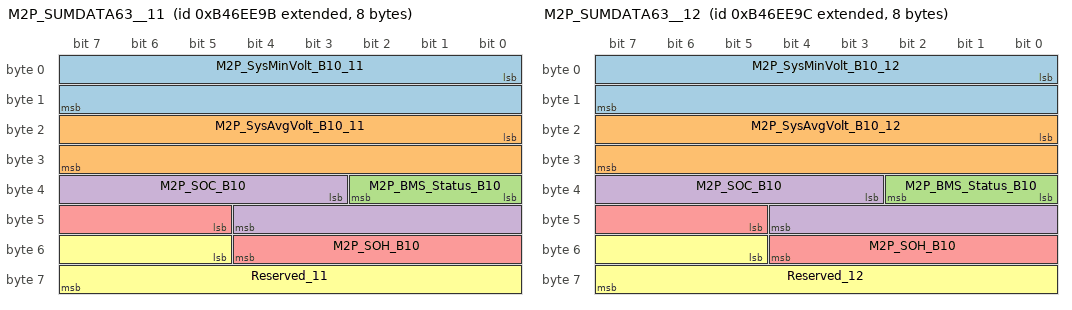
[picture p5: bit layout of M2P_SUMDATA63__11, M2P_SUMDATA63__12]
BO_ 2336681627 M2P_SUMDATA63__11: 8 MBMU
 SG_ M2P_SysMinVolt_B10_11 : 0|16@1+ (1,0) [0|65535] "mv"  PC
 SG_ M2P_SysAvgVolt_B10_11 : 16|16@1+ (1,0) [0|65535] "mv"  PC
 SG_ M2P_BMS_Status_B10 : 32|3@1+ (1,0) [0|7] ""  PC
 SG_ M2P_SOC_B10 : 35|10@1+ (0.1,0) [0|102.3] "%"  PC
 SG_ M2P_SOH_B10 : 45|8@1+ (1,0) [0|255] "%"  PC
 SG_ Reserved_11 : 53|11@1+ (1,0) [0|2047] ""  PC

BO_ 2336681628 M2P_SUMDATA63__12: 8 MBMU
 SG_ M2P_SysMinVolt_B10_12 : 0|16@1+ (1,0) [0|65535] "mv"  PC
 SG_ M2P_SysAvgVolt_B10_12 : 16|16@1+ (1,0) [0|65535] "mv"  PC
 SG_ M2P_BMS_Status_B10 : 32|3@1+ (1,0) [0|7] ""  PC
 SG_ M2P_SOC_B10 : 35|10@1+ (0.1,0) [0|102.3] "%"  PC
 SG_ M2P_SOH_B10 : 45|8@1+ (1,0) [0|255] "%"  PC
 SG_ Reserved_12 : 53|11@1+ (1,0) [0|2047] ""  PC

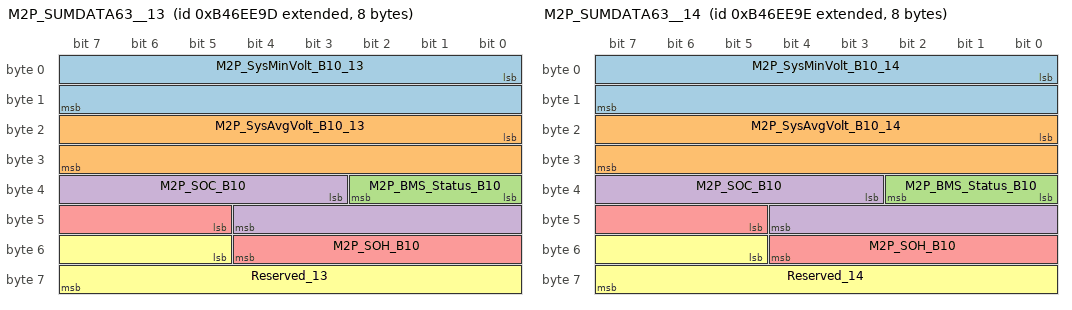
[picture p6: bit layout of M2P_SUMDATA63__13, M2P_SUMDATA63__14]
BO_ 2336681629 M2P_SUMDATA63__13: 8 MBMU
 SG_ M2P_SysMinVolt_B10_13 : 0|16@1+ (1,0) [0|65535] "mv"  PC
 SG_ M2P_SysAvgVolt_B10_13 : 16|16@1+ (1,0) [0|65535] "mv"  PC
 SG_ M2P_BMS_Status_B10 : 32|3@1+ (1,0) [0|7] ""  PC
 SG_ M2P_SOC_B10 : 35|10@1+ (0.1,0) [0|102.3] "%"  PC
 SG_ M2P_SOH_B10 : 45|8@1+ (1,0) [0|255] "%"  PC
 SG_ Reserved_13 : 53|11@1+ (1,0) [0|2047] ""  PC

BO_ 2336681630 M2P_SUMDATA63__14: 8 MBMU
 SG_ M2P_SysMinVolt_B10_14 : 0|16@1+ (1,0) [0|65535] "mv"  PC
 SG_ M2P_SysAvgVolt_B10_14 : 16|16@1+ (1,0) [0|65535] "mv"  PC
 SG_ M2P_BMS_Status_B10 : 32|3@1+ (1,0) [0|7] ""  PC
 SG_ M2P_SOC_B10 : 35|10@1+ (0.1,0) [0|102.3] "%"  PC
 SG_ M2P_SOH_B10 : 45|8@1+ (1,0) [0|255] "%"  PC
 SG_ Reserved_14 : 53|11@1+ (1,0) [0|2047] ""  PC

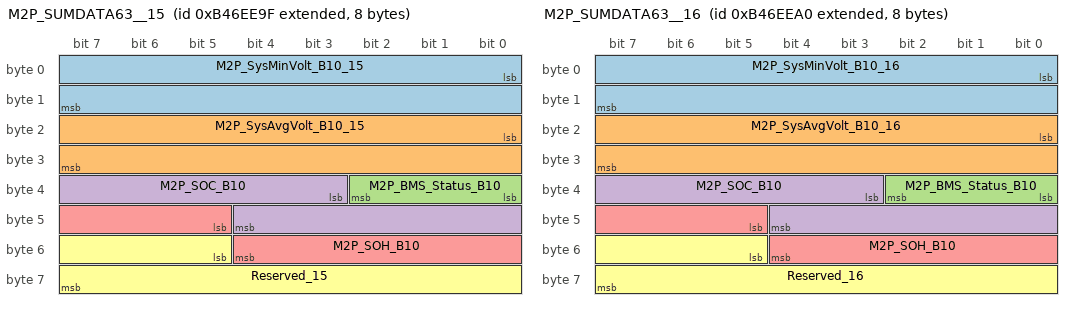
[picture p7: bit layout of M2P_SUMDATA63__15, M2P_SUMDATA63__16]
BO_ 2336681631 M2P_SUMDATA63__15: 8 MBMU
 SG_ M2P_SysMinVolt_B10_15 : 0|16@1+ (1,0) [0|65535] "mv"  PC
 SG_ M2P_SysAvgVolt_B10_15 : 16|16@1+ (1,0) [0|65535] "mv"  PC
 SG_ M2P_BMS_Status_B10 : 32|3@1+ (1,0) [0|7] ""  PC
 SG_ M2P_SOC_B10 : 35|10@1+ (0.1,0) [0|102.3] "%"  PC
 SG_ M2P_SOH_B10 : 45|8@1+ (1,0) [0|255] "%"  PC
 SG_ Reserved_15 : 53|11@1+ (1,0) [0|2047] ""  PC

BO_ 2336681632 M2P_SUMDATA63__16: 8 MBMU
 SG_ M2P_SysMinVolt_B10_16 : 0|16@1+ (1,0) [0|65535] "mv"  PC
 SG_ M2P_SysAvgVolt_B10_16 : 16|16@1+ (1,0) [0|65535] "mv"  PC
 SG_ M2P_BMS_Status_B10 : 32|3@1+ (1,0) [0|7] ""  PC
 SG_ M2P_SOC_B10 : 35|10@1+ (0.1,0) [0|102.3] "%"  PC
 SG_ M2P_SOH_B10 : 45|8@1+ (1,0) [0|255] "%"  PC
 SG_ Reserved_16 : 53|11@1+ (1,0) [0|2047] ""  PC

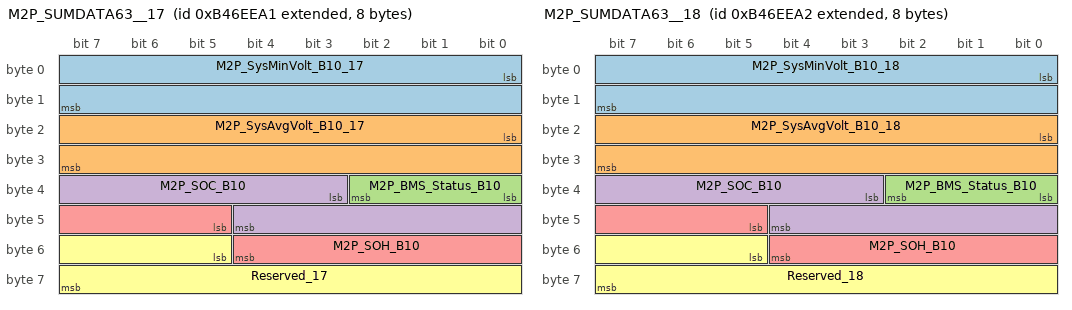
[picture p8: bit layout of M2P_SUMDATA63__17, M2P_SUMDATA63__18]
BO_ 2336681633 M2P_SUMDATA63__17: 8 MBMU
 SG_ M2P_SysMinVolt_B10_17 : 0|16@1+ (1,0) [0|65535] "mv"  PC
 SG_ M2P_SysAvgVolt_B10_17 : 16|16@1+ (1,0) [0|65535] "mv"  PC
 SG_ M2P_BMS_Status_B10 : 32|3@1+ (1,0) [0|7] ""  PC
 SG_ M2P_SOC_B10 : 35|10@1+ (0.1,0) [0|102.3] "%"  PC
 SG_ M2P_SOH_B10 : 45|8@1+ (1,0) [0|255] "%"  PC
 SG_ Reserved_17 : 53|11@1+ (1,0) [0|2047] ""  PC

BO_ 2336681634 M2P_SUMDATA63__18: 8 MBMU
 SG_ M2P_SysMinVolt_B10_18 : 0|16@1+ (1,0) [0|65535] "mv"  PC
 SG_ M2P_SysAvgVolt_B10_18 : 16|16@1+ (1,0) [0|65535] "mv"  PC
 SG_ M2P_BMS_Status_B10 : 32|3@1+ (1,0) [0|7] ""  PC
 SG_ M2P_SOC_B10 : 35|10@1+ (0.1,0) [0|102.3] "%"  PC
 SG_ M2P_SOH_B10 : 45|8@1+ (1,0) [0|255] "%"  PC
 SG_ Reserved_18 : 53|11@1+ (1,0) [0|2047] ""  PC

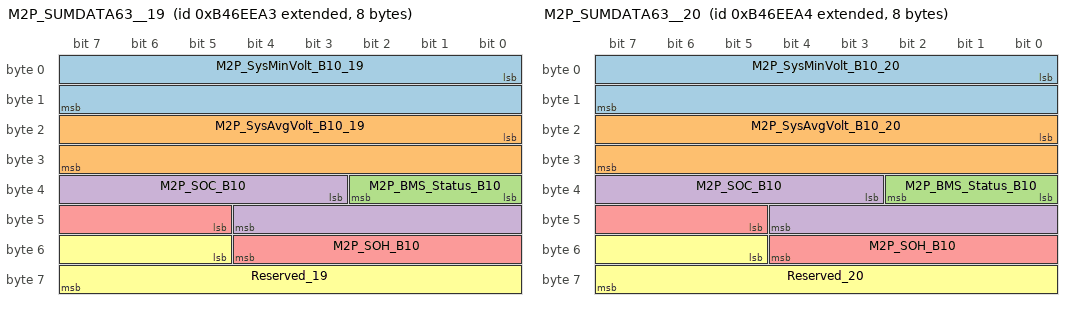
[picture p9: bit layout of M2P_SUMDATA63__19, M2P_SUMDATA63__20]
BO_ 2336681635 M2P_SUMDATA63__19: 8 MBMU
 SG_ M2P_SysMinVolt_B10_19 : 0|16@1+ (1,0) [0|65535] "mv"  PC
 SG_ M2P_SysAvgVolt_B10_19 : 16|16@1+ (1,0) [0|65535] "mv"  PC
 SG_ M2P_BMS_Status_B10 : 32|3@1+ (1,0) [0|7] ""  PC
 SG_ M2P_SOC_B10 : 35|10@1+ (0.1,0) [0|102.3] "%"  PC
 SG_ M2P_SOH_B10 : 45|8@1+ (1,0) [0|255] "%"  PC
 SG_ Reserved_19 : 53|11@1+ (1,0) [0|2047] ""  PC

BO_ 2336681636 M2P_SUMDATA63__20: 8 MBMU
 SG_ M2P_SysMinVolt_B10_20 : 0|16@1+ (1,0) [0|65535] "mv"  PC
 SG_ M2P_SysAvgVolt_B10_20 : 16|16@1+ (1,0) [0|65535] "mv"  PC
 SG_ M2P_BMS_Status_B10 : 32|3@1+ (1,0) [0|7] ""  PC
 SG_ M2P_SOC_B10 : 35|10@1+ (0.1,0) [0|102.3] "%"  PC
 SG_ M2P_SOH_B10 : 45|8@1+ (1,0) [0|255] "%"  PC
 SG_ Reserved_20 : 53|11@1+ (1,0) [0|2047] ""  PC

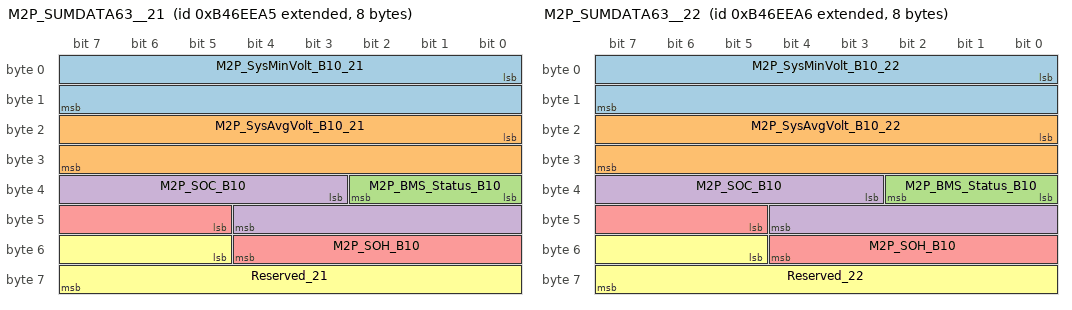
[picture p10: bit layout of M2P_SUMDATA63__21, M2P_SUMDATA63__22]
BO_ 2336681637 M2P_SUMDATA63__21: 8 MBMU
 SG_ M2P_SysMinVolt_B10_21 : 0|16@1+ (1,0) [0|65535] "mv"  PC
 SG_ M2P_SysAvgVolt_B10_21 : 16|16@1+ (1,0) [0|65535] "mv"  PC
 SG_ M2P_BMS_Status_B10 : 32|3@1+ (1,0) [0|7] ""  PC
 SG_ M2P_SOC_B10 : 35|10@1+ (0.1,0) [0|102.3] "%"  PC
 SG_ M2P_SOH_B10 : 45|8@1+ (1,0) [0|255] "%"  PC
 SG_ Reserved_21 : 53|11@1+ (1,0) [0|2047] ""  PC

BO_ 2336681638 M2P_SUMDATA63__22: 8 MBMU
 SG_ M2P_SysMinVolt_B10_22 : 0|16@1+ (1,0) [0|65535] "mv"  PC
 SG_ M2P_SysAvgVolt_B10_22 : 16|16@1+ (1,0) [0|65535] "mv"  PC
 SG_ M2P_BMS_Status_B10 : 32|3@1+ (1,0) [0|7] ""  PC
 SG_ M2P_SOC_B10 : 35|10@1+ (0.1,0) [0|102.3] "%"  PC
 SG_ M2P_SOH_B10 : 45|8@1+ (1,0) [0|255] "%"  PC
 SG_ Reserved_22 : 53|11@1+ (1,0) [0|2047] ""  PC

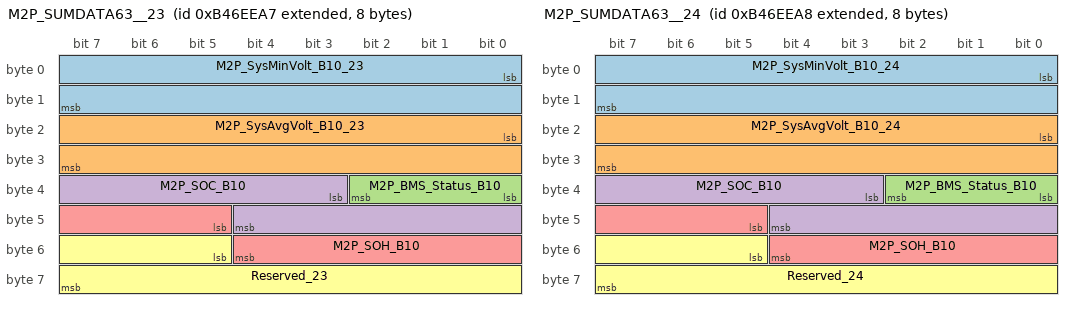
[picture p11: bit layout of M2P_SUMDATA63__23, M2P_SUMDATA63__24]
BO_ 2336681639 M2P_SUMDATA63__23: 8 MBMU
 SG_ M2P_SysMinVolt_B10_23 : 0|16@1+ (1,0) [0|65535] "mv"  PC
 SG_ M2P_SysAvgVolt_B10_23 : 16|16@1+ (1,0) [0|65535] "mv"  PC
 SG_ M2P_BMS_Status_B10 : 32|3@1+ (1,0) [0|7] ""  PC
 SG_ M2P_SOC_B10 : 35|10@1+ (0.1,0) [0|102.3] "%"  PC
 SG_ M2P_SOH_B10 : 45|8@1+ (1,0) [0|255] "%"  PC
 SG_ Reserved_23 : 53|11@1+ (1,0) [0|2047] ""  PC

BO_ 2336681640 M2P_SUMDATA63__24: 8 MBMU
 SG_ M2P_SysMinVolt_B10_24 : 0|16@1+ (1,0) [0|65535] "mv"  PC
 SG_ M2P_SysAvgVolt_B10_24 : 16|16@1+ (1,0) [0|65535] "mv"  PC
 SG_ M2P_BMS_Status_B10 : 32|3@1+ (1,0) [0|7] ""  PC
 SG_ M2P_SOC_B10 : 35|10@1+ (0.1,0) [0|102.3] "%"  PC
 SG_ M2P_SOH_B10 : 45|8@1+ (1,0) [0|255] "%"  PC
 SG_ Reserved_24 : 53|11@1+ (1,0) [0|2047] ""  PC

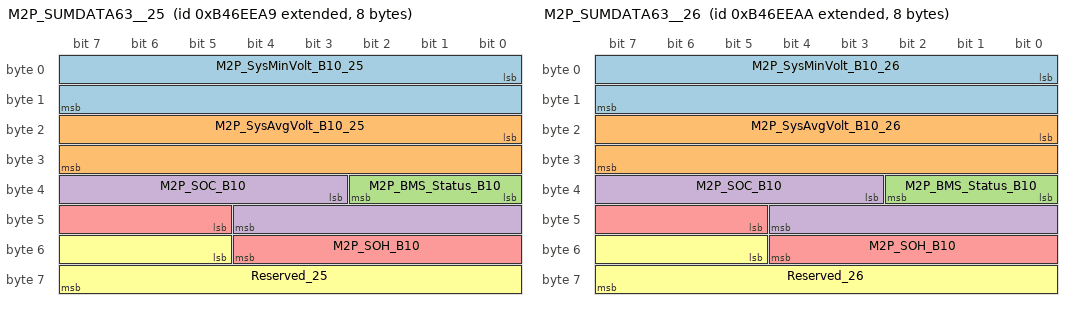
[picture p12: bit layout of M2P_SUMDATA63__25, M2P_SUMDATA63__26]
BO_ 2336681641 M2P_SUMDATA63__25: 8 MBMU
 SG_ M2P_SysMinVolt_B10_25 : 0|16@1+ (1,0) [0|65535] "mv"  PC
 SG_ M2P_SysAvgVolt_B10_25 : 16|16@1+ (1,0) [0|65535] "mv"  PC
 SG_ M2P_BMS_Status_B10 : 32|3@1+ (1,0) [0|7] ""  PC
 SG_ M2P_SOC_B10 : 35|10@1+ (0.1,0) [0|102.3] "%"  PC
 SG_ M2P_SOH_B10 : 45|8@1+ (1,0) [0|255] "%"  PC
 SG_ Reserved_25 : 53|11@1+ (1,0) [0|2047] ""  PC

BO_ 2336681642 M2P_SUMDATA63__26: 8 MBMU
 SG_ M2P_SysMinVolt_B10_26 : 0|16@1+ (1,0) [0|65535] "mv"  PC
 SG_ M2P_SysAvgVolt_B10_26 : 16|16@1+ (1,0) [0|65535] "mv"  PC
 SG_ M2P_BMS_Status_B10 : 32|3@1+ (1,0) [0|7] ""  PC
 SG_ M2P_SOC_B10 : 35|10@1+ (0.1,0) [0|102.3] "%"  PC
 SG_ M2P_SOH_B10 : 45|8@1+ (1,0) [0|255] "%"  PC
 SG_ Reserved_26 : 53|11@1+ (1,0) [0|2047] ""  PC

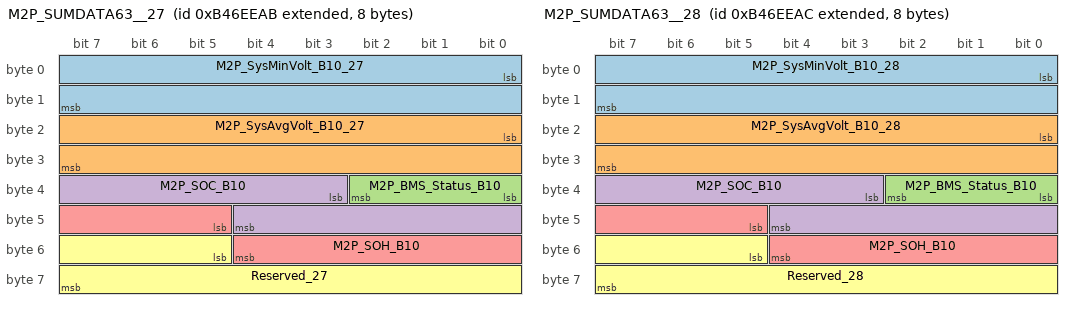
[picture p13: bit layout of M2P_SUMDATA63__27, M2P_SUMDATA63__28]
BO_ 2336681643 M2P_SUMDATA63__27: 8 MBMU
 SG_ M2P_SysMinVolt_B10_27 : 0|16@1+ (1,0) [0|65535] "mv"  PC
 SG_ M2P_SysAvgVolt_B10_27 : 16|16@1+ (1,0) [0|65535] "mv"  PC
 SG_ M2P_BMS_Status_B10 : 32|3@1+ (1,0) [0|7] ""  PC
 SG_ M2P_SOC_B10 : 35|10@1+ (0.1,0) [0|102.3] "%"  PC
 SG_ M2P_SOH_B10 : 45|8@1+ (1,0) [0|255] "%"  PC
 SG_ Reserved_27 : 53|11@1+ (1,0) [0|2047] ""  PC

BO_ 2336681644 M2P_SUMDATA63__28: 8 MBMU
 SG_ M2P_SysMinVolt_B10_28 : 0|16@1+ (1,0) [0|65535] "mv"  PC
 SG_ M2P_SysAvgVolt_B10_28 : 16|16@1+ (1,0) [0|65535] "mv"  PC
 SG_ M2P_BMS_Status_B10 : 32|3@1+ (1,0) [0|7] ""  PC
 SG_ M2P_SOC_B10 : 35|10@1+ (0.1,0) [0|102.3] "%"  PC
 SG_ M2P_SOH_B10 : 45|8@1+ (1,0) [0|255] "%"  PC
 SG_ Reserved_28 : 53|11@1+ (1,0) [0|2047] ""  PC

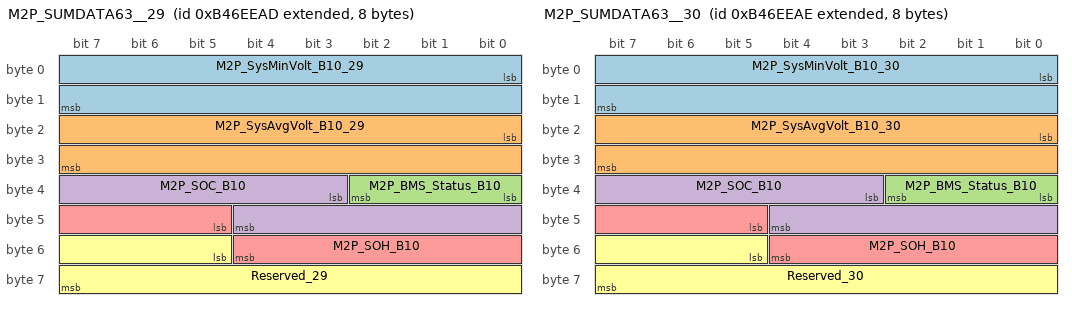
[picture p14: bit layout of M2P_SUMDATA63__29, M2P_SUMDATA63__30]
BO_ 2336681645 M2P_SUMDATA63__29: 8 MBMU
 SG_ M2P_SysMinVolt_B10_29 : 0|16@1+ (1,0) [0|65535] "mv"  PC
 SG_ M2P_SysAvgVolt_B10_29 : 16|16@1+ (1,0) [0|65535] "mv"  PC
 SG_ M2P_BMS_Status_B10 : 32|3@1+ (1,0) [0|7] ""  PC
 SG_ M2P_SOC_B10 : 35|10@1+ (0.1,0) [0|102.3] "%"  PC
 SG_ M2P_SOH_B10 : 45|8@1+ (1,0) [0|255] "%"  PC
 SG_ Reserved_29 : 53|11@1+ (1,0) [0|2047] ""  PC

BO_ 2336681646 M2P_SUMDATA63__30: 8 MBMU
 SG_ M2P_SysMinVolt_B10_30 : 0|16@1+ (1,0) [0|65535] "mv"  PC
 SG_ M2P_SysAvgVolt_B10_30 : 16|16@1+ (1,0) [0|65535] "mv"  PC
 SG_ M2P_BMS_Status_B10 : 32|3@1+ (1,0) [0|7] ""  PC
 SG_ M2P_SOC_B10 : 35|10@1+ (0.1,0) [0|102.3] "%"  PC
 SG_ M2P_SOH_B10 : 45|8@1+ (1,0) [0|255] "%"  PC
 SG_ Reserved_30 : 53|11@1+ (1,0) [0|2047] ""  PC

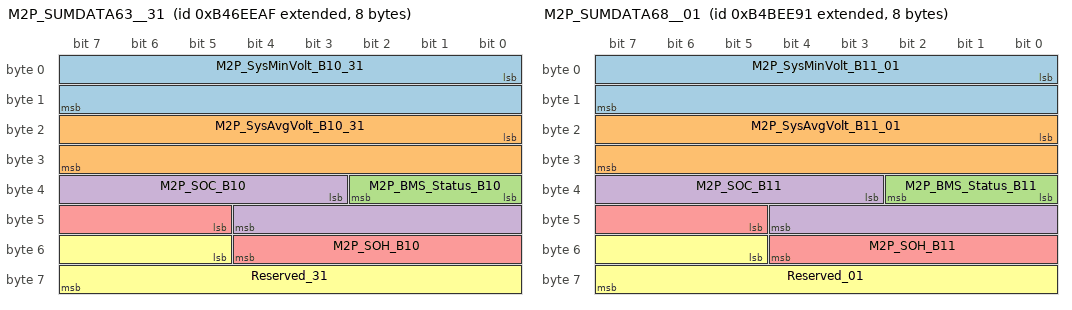
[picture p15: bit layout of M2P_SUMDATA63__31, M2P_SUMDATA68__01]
BO_ 2336681647 M2P_SUMDATA63__31: 8 MBMU
 SG_ M2P_SysMinVolt_B10_31 : 0|16@1+ (1,0) [0|65535] "mv"  PC
 SG_ M2P_SysAvgVolt_B10_31 : 16|16@1+ (1,0) [0|65535] "mv"  PC
 SG_ M2P_BMS_Status_B10 : 32|3@1+ (1,0) [0|7] ""  PC
 SG_ M2P_SOC_B10 : 35|10@1+ (0.1,0) [0|102.3] "%"  PC
 SG_ M2P_SOH_B10 : 45|8@1+ (1,0) [0|255] "%"  PC
 SG_ Reserved_31 : 53|11@1+ (1,0) [0|2047] ""  PC

BO_ 2336747153 M2P_SUMDATA64__01: 8 MBMU
 SG_ M2P_SOE_Charge_B10 : 0|10@1+ (0.1,0) [0|102.3] "%"  PC
 SG_ M2P_SOE_Discharge_B10 : 10|10@1+ (0.1,0) [0|102.3] "%"  PC
 SG_ Reserved_01 : 20|44@1+ (1,0) [0|17592186044415] ""  PC

BO_ 2336747154 M2P_SUMDATA64__02: 8 MBMU
 SG_ M2P_SOE_Charge_B10 : 0|10@1+ (0.1,0) [0|102.3] "%"  PC
 SG_ M2P_SOE_Discharge_B10 : 10|10@1+ (0.1,0) [0|102.3] "%"  PC
 SG_ Reserved_02 : 20|44@1+ (1,0) [0|17592186044415] ""  PC

BO_ 2336747155 M2P_SUMDATA64__03: 8 MBMU
 SG_ M2P_SOE_Charge_B10 : 0|10@1+ (0.1,0) [0|102.3] "%"  PC
 SG_ M2P_SOE_Discharge_B10 : 10|10@1+ (0.1,0) [0|102.3] "%"  PC
 SG_ Reserved_03 : 20|44@1+ (1,0) [0|17592186044415] ""  PC

BO_ 2336747156 M2P_SUMDATA64__04: 8 MBMU
 SG_ M2P_SOE_Charge_B10 : 0|10@1+ (0.1,0) [0|102.3] "%"  PC
 SG_ M2P_SOE_Discharge_B10 : 10|10@1+ (0.1,0) [0|102.3] "%"  PC
 SG_ Reserved_04 : 20|44@1+ (1,0) [0|17592186044415] ""  PC

BO_ 2336747157 M2P_SUMDATA64__05: 8 MBMU
 SG_ M2P_SOE_Charge_B10 : 0|10@1+ (0.1,0) [0|102.3] "%"  PC
 SG_ M2P_SOE_Discharge_B10 : 10|10@1+ (0.1,0) [0|102.3] "%"  PC
 SG_ Reserved_05 : 20|44@1+ (1,0) [0|17592186044415] ""  PC

BO_ 2336747158 M2P_SUMDATA64__06: 8 MBMU
 SG_ M2P_SOE_Charge_B10 : 0|10@1+ (0.1,0) [0|102.3] "%"  PC
 SG_ M2P_SOE_Discharge_B10 : 10|10@1+ (0.1,0) [0|102.3] "%"  PC
 SG_ Reserved_06 : 20|44@1+ (1,0) [0|17592186044415] ""  PC

BO_ 2336747159 M2P_SUMDATA64__07: 8 MBMU
 SG_ M2P_SOE_Charge_B10 : 0|10@1+ (0.1,0) [0|102.3] "%"  PC
 SG_ M2P_SOE_Discharge_B10 : 10|10@1+ (0.1,0) [0|102.3] "%"  PC
 SG_ Reserved_07 : 20|44@1+ (1,0) [0|17592186044415] ""  PC

BO_ 2336747160 M2P_SUMDATA64__08: 8 MBMU
 SG_ M2P_SOE_Charge_B10 : 0|10@1+ (0.1,0) [0|102.3] "%"  PC
 SG_ M2P_SOE_Discharge_B10 : 10|10@1+ (0.1,0) [0|102.3] "%"  PC
 SG_ Reserved_08 : 20|44@1+ (1,0) [0|17592186044415] ""  PC

BO_ 2336747161 M2P_SUMDATA64__09: 8 MBMU
 SG_ M2P_SOE_Charge_B10 : 0|10@1+ (0.1,0) [0|102.3] "%"  PC
 SG_ M2P_SOE_Discharge_B10 : 10|10@1+ (0.1,0) [0|102.3] "%"  PC
 SG_ Reserved_09 : 20|44@1+ (1,0) [0|17592186044415] ""  PC

BO_ 2336747162 M2P_SUMDATA64__10: 8 MBMU
 SG_ M2P_SOE_Charge_B10 : 0|10@1+ (0.1,0) [0|102.3] "%"  PC
 SG_ M2P_SOE_Discharge_B10 : 10|10@1+ (0.1,0) [0|102.3] "%"  PC
 SG_ Reserved_10 : 20|44@1+ (1,0) [0|17592186044415] ""  PC

BO_ 2336747163 M2P_SUMDATA64__11: 8 MBMU
 SG_ M2P_SOE_Charge_B10 : 0|10@1+ (0.1,0) [0|102.3] "%"  PC
 SG_ M2P_SOE_Discharge_B10 : 10|10@1+ (0.1,0) [0|102.3] "%"  PC
 SG_ Reserved_11 : 20|44@1+ (1,0) [0|17592186044415] ""  PC

BO_ 2336747164 M2P_SUMDATA64__12: 8 MBMU
 SG_ M2P_SOE_Charge_B10 : 0|10@1+ (0.1,0) [0|102.3] "%"  PC
 SG_ M2P_SOE_Discharge_B10 : 10|10@1+ (0.1,0) [0|102.3] "%"  PC
 SG_ Reserved_12 : 20|44@1+ (1,0) [0|17592186044415] ""  PC

BO_ 2336747165 M2P_SUMDATA64__13: 8 MBMU
 SG_ M2P_SOE_Charge_B10 : 0|10@1+ (0.1,0) [0|102.3] "%"  PC
 SG_ M2P_SOE_Discharge_B10 : 10|10@1+ (0.1,0) [0|102.3] "%"  PC
 SG_ Reserved_13 : 20|44@1+ (1,0) [0|17592186044415] ""  PC

BO_ 2336747166 M2P_SUMDATA64__14: 8 MBMU
 SG_ M2P_SOE_Charge_B10 : 0|10@1+ (0.1,0) [0|102.3] "%"  PC
 SG_ M2P_SOE_Discharge_B10 : 10|10@1+ (0.1,0) [0|102.3] "%"  PC
 SG_ Reserved_14 : 20|44@1+ (1,0) [0|17592186044415] ""  PC

BO_ 2336747167 M2P_SUMDATA64__15: 8 MBMU
 SG_ M2P_SOE_Charge_B10 : 0|10@1+ (0.1,0) [0|102.3] "%"  PC
 SG_ M2P_SOE_Discharge_B10 : 10|10@1+ (0.1,0) [0|102.3] "%"  PC
 SG_ Reserved_15 : 20|44@1+ (1,0) [0|17592186044415] ""  PC

BO_ 2336747168 M2P_SUMDATA64__16: 8 MBMU
 SG_ M2P_SOE_Charge_B10 : 0|10@1+ (0.1,0) [0|102.3] "%"  PC
 SG_ M2P_SOE_Discharge_B10 : 10|10@1+ (0.1,0) [0|102.3] "%"  PC
 SG_ Reserved_16 : 20|44@1+ (1,0) [0|17592186044415] ""  PC

BO_ 2336747169 M2P_SUMDATA64__17: 8 MBMU
 SG_ M2P_SOE_Charge_B10 : 0|10@1+ (0.1,0) [0|102.3] "%"  PC
 SG_ M2P_SOE_Discharge_B10 : 10|10@1+ (0.1,0) [0|102.3] "%"  PC
 SG_ Reserved_17 : 20|44@1+ (1,0) [0|17592186044415] ""  PC

BO_ 2336747170 M2P_SUMDATA64__18: 8 MBMU
 SG_ M2P_SOE_Charge_B10 : 0|10@1+ (0.1,0) [0|102.3] "%"  PC
 SG_ M2P_SOE_Discharge_B10 : 10|10@1+ (0.1,0) [0|102.3] "%"  PC
 SG_ Reserved_18 : 20|44@1+ (1,0) [0|17592186044415] ""  PC

BO_ 2336747171 M2P_SUMDATA64__19: 8 MBMU
 SG_ M2P_SOE_Charge_B10 : 0|10@1+ (0.1,0) [0|102.3] "%"  PC
 SG_ M2P_SOE_Discharge_B10 : 10|10@1+ (0.1,0) [0|102.3] "%"  PC
 SG_ Reserved_19 : 20|44@1+ (1,0) [0|17592186044415] ""  PC

BO_ 2336747172 M2P_SUMDATA64__20: 8 MBMU
 SG_ M2P_SOE_Charge_B10 : 0|10@1+ (0.1,0) [0|102.3] "%"  PC
 SG_ M2P_SOE_Discharge_B10 : 10|10@1+ (0.1,0) [0|102.3] "%"  PC
 SG_ Reserved_20 : 20|44@1+ (1,0) [0|17592186044415] ""  PC

BO_ 2336747173 M2P_SUMDATA64__21: 8 MBMU
 SG_ M2P_SOE_Charge_B10 : 0|10@1+ (0.1,0) [0|102.3] "%"  PC
 SG_ M2P_SOE_Discharge_B10 : 10|10@1+ (0.1,0) [0|102.3] "%"  PC
 SG_ Reserved_21 : 20|44@1+ (1,0) [0|17592186044415] ""  PC

BO_ 2336747174 M2P_SUMDATA64__22: 8 MBMU
 SG_ M2P_SOE_Charge_B10 : 0|10@1+ (0.1,0) [0|102.3] "%"  PC
 SG_ M2P_SOE_Discharge_B10 : 10|10@1+ (0.1,0) [0|102.3] "%"  PC
 SG_ Reserved_22 : 20|44@1+ (1,0) [0|17592186044415] ""  PC

BO_ 2336747175 M2P_SUMDATA64__23: 8 MBMU
 SG_ M2P_SOE_Charge_B10 : 0|10@1+ (0.1,0) [0|102.3] "%"  PC
 SG_ M2P_SOE_Discharge_B10 : 10|10@1+ (0.1,0) [0|102.3] "%"  PC
 SG_ Reserved_23 : 20|44@1+ (1,0) [0|17592186044415] ""  PC

BO_ 2336747176 M2P_SUMDATA64__24: 8 MBMU
 SG_ M2P_SOE_Charge_B10 : 0|10@1+ (0.1,0) [0|102.3] "%"  PC
 SG_ M2P_SOE_Discharge_B10 : 10|10@1+ (0.1,0) [0|102.3] "%"  PC
 SG_ Reserved_24 : 20|44@1+ (1,0) [0|17592186044415] ""  PC

BO_ 2336747177 M2P_SUMDATA64__25: 8 MBMU
 SG_ M2P_SOE_Charge_B10 : 0|10@1+ (0.1,0) [0|102.3] "%"  PC
 SG_ M2P_SOE_Discharge_B10 : 10|10@1+ (0.1,0) [0|102.3] "%"  PC
 SG_ Reserved_25 : 20|44@1+ (1,0) [0|17592186044415] ""  PC

BO_ 2336747178 M2P_SUMDATA64__26: 8 MBMU
 SG_ M2P_SOE_Charge_B10 : 0|10@1+ (0.1,0) [0|102.3] "%"  PC
 SG_ M2P_SOE_Discharge_B10 : 10|10@1+ (0.1,0) [0|102.3] "%"  PC
 SG_ Reserved_26 : 20|44@1+ (1,0) [0|17592186044415] ""  PC

BO_ 2336747179 M2P_SUMDATA64__27: 8 MBMU
 SG_ M2P_SOE_Charge_B10 : 0|10@1+ (0.1,0) [0|102.3] "%"  PC
 SG_ M2P_SOE_Discharge_B10 : 10|10@1+ (0.1,0) [0|102.3] "%"  PC
 SG_ Reserved_27 : 20|44@1+ (1,0) [0|17592186044415] ""  PC

BO_ 2336747180 M2P_SUMDATA64__28: 8 MBMU
 SG_ M2P_SOE_Charge_B10 : 0|10@1+ (0.1,0) [0|102.3] "%"  PC
 SG_ M2P_SOE_Discharge_B10 : 10|10@1+ (0.1,0) [0|102.3] "%"  PC
 SG_ Reserved_28 : 20|44@1+ (1,0) [0|17592186044415] ""  PC

BO_ 2336747181 M2P_SUMDATA64__29: 8 MBMU
 SG_ M2P_SOE_Charge_B10 : 0|10@1+ (0.1,0) [0|102.3] "%"  PC
 SG_ M2P_SOE_Discharge_B10 : 10|10@1+ (0.1,0) [0|102.3] "%"  PC
 SG_ Reserved_29 : 20|44@1+ (1,0) [0|17592186044415] ""  PC

BO_ 2336747182 M2P_SUMDATA64__30: 8 MBMU
 SG_ M2P_SOE_Charge_B10 : 0|10@1+ (0.1,0) [0|102.3] "%"  PC
 SG_ M2P_SOE_Discharge_B10 : 10|10@1+ (0.1,0) [0|102.3] "%"  PC
 SG_ Reserved_30 : 20|44@1+ (1,0) [0|17592186044415] ""  PC

BO_ 2336747183 M2P_SUMDATA64__31: 8 MBMU
 SG_ M2P_SOE_Charge_B10 : 0|10@1+ (0.1,0) [0|102.3] "%"  PC
 SG_ M2P_SOE_Discharge_B10 : 10|10@1+ (0.1,0) [0|102.3] "%"  PC
 SG_ Reserved_31 : 20|44@1+ (1,0) [0|17592186044415] ""  PC

BO_ 2336812689 M2P_SUMDATA65__01: 8 MBMU
 SG_ M2P_Measure_Vol_B11_01 : 0|16@1+ (0.1,0) [0|6553.5] "V"  PC,SBMU
 SG_ M2P_Current_B11_01 : 16|16@1+ (1,-20000) [-20000|45535] "A"  PC,SBMU
 SG_ M2P_PermitMaxCharge_I_B11_01 : 32|16@1+ (1,-20000) [-20000|45535] "A"  PC
 SG_ M2P_PermitMaxDisCharge_I_B11_01 : 48|16@1+ (1,-20000) [-20000|45535] "A"  PC

BO_ 2336812690 M2P_SUMDATA65__02: 8 MBMU
 SG_ M2P_Measure_Vol_B11_02 : 0|16@1+ (0.1,0) [0|6553.5] "V"  PC,SBMU
 SG_ M2P_Current_B11_02 : 16|16@1+ (1,-20000) [-20000|45535] "A"  PC,SBMU
 SG_ M2P_PermitMaxCharge_I_B11_02 : 32|16@1+ (1,-20000) [-20000|45535] "A"  PC
 SG_ M2P_PermitMaxDisCharge_I_B11_02 : 48|16@1+ (1,-20000) [-20000|45535] "A"  PC

BO_ 2336812691 M2P_SUMDATA65__03: 8 MBMU
 SG_ M2P_Measure_Vol_B11_03 : 0|16@1+ (0.1,0) [0|6553.5] "V"  PC,SBMU
 SG_ M2P_Current_B11_03 : 16|16@1+ (1,-20000) [-20000|45535] "A"  PC,SBMU
 SG_ M2P_PermitMaxCharge_I_B11_03 : 32|16@1+ (1,-20000) [-20000|45535] "A"  PC
 SG_ M2P_PermitMaxDisCharge_I_B11_03 : 48|16@1+ (1,-20000) [-20000|45535] "A"  PC

BO_ 2336812692 M2P_SUMDATA65__04: 8 MBMU
 SG_ M2P_Measure_Vol_B11_04 : 0|16@1+ (0.1,0) [0|6553.5] "V"  PC,SBMU
 SG_ M2P_Current_B11_04 : 16|16@1+ (1,-20000) [-20000|45535] "A"  PC,SBMU
 SG_ M2P_PermitMaxCharge_I_B11_04 : 32|16@1+ (1,-20000) [-20000|45535] "A"  PC
 SG_ M2P_PermitMaxDisCharge_I_B11_04 : 48|16@1+ (1,-20000) [-20000|45535] "A"  PC

BO_ 2336812693 M2P_SUMDATA65__05: 8 MBMU
 SG_ M2P_Measure_Vol_B11_05 : 0|16@1+ (0.1,0) [0|6553.5] "V"  PC,SBMU
 SG_ M2P_Current_B11_05 : 16|16@1+ (1,-20000) [-20000|45535] "A"  PC,SBMU
 SG_ M2P_PermitMaxCharge_I_B11_05 : 32|16@1+ (1,-20000) [-20000|45535] "A"  PC
 SG_ M2P_PermitMaxDisCharge_I_B11_05 : 48|16@1+ (1,-20000) [-20000|45535] "A"  PC

BO_ 2336812694 M2P_SUMDATA65__06: 8 MBMU
 SG_ M2P_Measure_Vol_B11_06 : 0|16@1+ (0.1,0) [0|6553.5] "V"  PC,SBMU
 SG_ M2P_Current_B11_06 : 16|16@1+ (1,-20000) [-20000|45535] "A"  PC,SBMU
 SG_ M2P_PermitMaxCharge_I_B11_06 : 32|16@1+ (1,-20000) [-20000|45535] "A"  PC
 SG_ M2P_PermitMaxDisCharge_I_B11_06 : 48|16@1+ (1,-20000) [-20000|45535] "A"  PC

BO_ 2336812695 M2P_SUMDATA65__07: 8 MBMU
 SG_ M2P_Measure_Vol_B11_07 : 0|16@1+ (0.1,0) [0|6553.5] "V"  PC,SBMU
 SG_ M2P_Current_B11_07 : 16|16@1+ (1,-20000) [-20000|45535] "A"  PC,SBMU
 SG_ M2P_PermitMaxCharge_I_B11_07 : 32|16@1+ (1,-20000) [-20000|45535] "A"  PC
 SG_ M2P_PermitMaxDisCharge_I_B11_07 : 48|16@1+ (1,-20000) [-20000|45535] "A"  PC

BO_ 2336812696 M2P_SUMDATA65__08: 8 MBMU
 SG_ M2P_Measure_Vol_B11_08 : 0|16@1+ (0.1,0) [0|6553.5] "V"  PC,SBMU
 SG_ M2P_Current_B11_08 : 16|16@1+ (1,-20000) [-20000|45535] "A"  PC,SBMU
 SG_ M2P_PermitMaxCharge_I_B11_08 : 32|16@1+ (1,-20000) [-20000|45535] "A"  PC
 SG_ M2P_PermitMaxDisCharge_I_B11_08 : 48|16@1+ (1,-20000) [-20000|45535] "A"  PC

BO_ 2336812697 M2P_SUMDATA65__09: 8 MBMU
 SG_ M2P_Measure_Vol_B11_09 : 0|16@1+ (0.1,0) [0|6553.5] "V"  PC,SBMU
 SG_ M2P_Current_B11_09 : 16|16@1+ (1,-20000) [-20000|45535] "A"  PC,SBMU
 SG_ M2P_PermitMaxCharge_I_B11_09 : 32|16@1+ (1,-20000) [-20000|45535] "A"  PC
 SG_ M2P_PermitMaxDisCharge_I_B11_09 : 48|16@1+ (1,-20000) [-20000|45535] "A"  PC

BO_ 2336812698 M2P_SUMDATA65__10: 8 MBMU
 SG_ M2P_Measure_Vol_B11_10 : 0|16@1+ (0.1,0) [0|6553.5] "V"  PC,SBMU
 SG_ M2P_Current_B11_10 : 16|16@1+ (1,-20000) [-20000|45535] "A"  PC,SBMU
 SG_ M2P_PermitMaxCharge_I_B11_10 : 32|16@1+ (1,-20000) [-20000|45535] "A"  PC
 SG_ M2P_PermitMaxDisCharge_I_B11_10 : 48|16@1+ (1,-20000) [-20000|45535] "A"  PC

BO_ 2336812699 M2P_SUMDATA65__11: 8 MBMU
 SG_ M2P_Measure_Vol_B11_11 : 0|16@1+ (0.1,0) [0|6553.5] "V"  PC,SBMU
 SG_ M2P_Current_B11_11 : 16|16@1+ (1,-20000) [-20000|45535] "A"  PC,SBMU
 SG_ M2P_PermitMaxCharge_I_B11_11 : 32|16@1+ (1,-20000) [-20000|45535] "A"  PC
 SG_ M2P_PermitMaxDisCharge_I_B11_11 : 48|16@1+ (1,-20000) [-20000|45535] "A"  PC

BO_ 2336812700 M2P_SUMDATA65__12: 8 MBMU
 SG_ M2P_Measure_Vol_B11_12 : 0|16@1+ (0.1,0) [0|6553.5] "V"  PC,SBMU
 SG_ M2P_Current_B11_12 : 16|16@1+ (1,-20000) [-20000|45535] "A"  PC,SBMU
 SG_ M2P_PermitMaxCharge_I_B11_12 : 32|16@1+ (1,-20000) [-20000|45535] "A"  PC
 SG_ M2P_PermitMaxDisCharge_I_B11_12 : 48|16@1+ (1,-20000) [-20000|45535] "A"  PC

BO_ 2336812701 M2P_SUMDATA65__13: 8 MBMU
 SG_ M2P_Measure_Vol_B11_13 : 0|16@1+ (0.1,0) [0|6553.5] "V"  PC,SBMU
 SG_ M2P_Current_B11_13 : 16|16@1+ (1,-20000) [-20000|45535] "A"  PC,SBMU
 SG_ M2P_PermitMaxCharge_I_B11_13 : 32|16@1+ (1,-20000) [-20000|45535] "A"  PC
 SG_ M2P_PermitMaxDisCharge_I_B11_13 : 48|16@1+ (1,-20000) [-20000|45535] "A"  PC

BO_ 2336812702 M2P_SUMDATA65__14: 8 MBMU
 SG_ M2P_Measure_Vol_B11_14 : 0|16@1+ (0.1,0) [0|6553.5] "V"  PC,SBMU
 SG_ M2P_Current_B11_14 : 16|16@1+ (1,-20000) [-20000|45535] "A"  PC,SBMU
 SG_ M2P_PermitMaxCharge_I_B11_14 : 32|16@1+ (1,-20000) [-20000|45535] "A"  PC
 SG_ M2P_PermitMaxDisCharge_I_B11_14 : 48|16@1+ (1,-20000) [-20000|45535] "A"  PC

BO_ 2336812703 M2P_SUMDATA65__15: 8 MBMU
 SG_ M2P_Measure_Vol_B11_15 : 0|16@1+ (0.1,0) [0|6553.5] "V"  PC,SBMU
 SG_ M2P_Current_B11_15 : 16|16@1+ (1,-20000) [-20000|45535] "A"  PC,SBMU
 SG_ M2P_PermitMaxCharge_I_B11_15 : 32|16@1+ (1,-20000) [-20000|45535] "A"  PC
 SG_ M2P_PermitMaxDisCharge_I_B11_15 : 48|16@1+ (1,-20000) [-20000|45535] "A"  PC

BO_ 2336812704 M2P_SUMDATA65__16: 8 MBMU
 SG_ M2P_Measure_Vol_B11_16 : 0|16@1+ (0.1,0) [0|6553.5] "V"  PC,SBMU
 SG_ M2P_Current_B11_16 : 16|16@1+ (1,-20000) [-20000|45535] "A"  PC,SBMU
 SG_ M2P_PermitMaxCharge_I_B11_16 : 32|16@1+ (1,-20000) [-20000|45535] "A"  PC
 SG_ M2P_PermitMaxDisCharge_I_B11_16 : 48|16@1+ (1,-20000) [-20000|45535] "A"  PC

BO_ 2336812705 M2P_SUMDATA65__17: 8 MBMU
 SG_ M2P_Measure_Vol_B11_17 : 0|16@1+ (0.1,0) [0|6553.5] "V"  PC,SBMU
 SG_ M2P_Current_B11_17 : 16|16@1+ (1,-20000) [-20000|45535] "A"  PC,SBMU
 SG_ M2P_PermitMaxCharge_I_B11_17 : 32|16@1+ (1,-20000) [-20000|45535] "A"  PC
 SG_ M2P_PermitMaxDisCharge_I_B11_17 : 48|16@1+ (1,-20000) [-20000|45535] "A"  PC

BO_ 2336812706 M2P_SUMDATA65__18: 8 MBMU
 SG_ M2P_Measure_Vol_B11_18 : 0|16@1+ (0.1,0) [0|6553.5] "V"  PC,SBMU
 SG_ M2P_Current_B11_18 : 16|16@1+ (1,-20000) [-20000|45535] "A"  PC,SBMU
 SG_ M2P_PermitMaxCharge_I_B11_18 : 32|16@1+ (1,-20000) [-20000|45535] "A"  PC
 SG_ M2P_PermitMaxDisCharge_I_B11_18 : 48|16@1+ (1,-20000) [-20000|45535] "A"  PC

BO_ 2336812707 M2P_SUMDATA65__19: 8 MBMU
 SG_ M2P_Measure_Vol_B11_19 : 0|16@1+ (0.1,0) [0|6553.5] "V"  PC,SBMU
 SG_ M2P_Current_B11_19 : 16|16@1+ (1,-20000) [-20000|45535] "A"  PC,SBMU
 SG_ M2P_PermitMaxCharge_I_B11_19 : 32|16@1+ (1,-20000) [-20000|45535] "A"  PC
 SG_ M2P_PermitMaxDisCharge_I_B11_19 : 48|16@1+ (1,-20000) [-20000|45535] "A"  PC

BO_ 2336812708 M2P_SUMDATA65__20: 8 MBMU
 SG_ M2P_Measure_Vol_B11_20 : 0|16@1+ (0.1,0) [0|6553.5] "V"  PC,SBMU
 SG_ M2P_Current_B11_20 : 16|16@1+ (1,-20000) [-20000|45535] "A"  PC,SBMU
 SG_ M2P_PermitMaxCharge_I_B11_20 : 32|16@1+ (1,-20000) [-20000|45535] "A"  PC
 SG_ M2P_PermitMaxDisCharge_I_B11_20 : 48|16@1+ (1,-20000) [-20000|45535] "A"  PC

BO_ 2336812709 M2P_SUMDATA65__21: 8 MBMU
 SG_ M2P_Measure_Vol_B11_21 : 0|16@1+ (0.1,0) [0|6553.5] "V"  PC,SBMU
 SG_ M2P_Current_B11_21 : 16|16@1+ (1,-20000) [-20000|45535] "A"  PC,SBMU
 SG_ M2P_PermitMaxCharge_I_B11_21 : 32|16@1+ (1,-20000) [-20000|45535] "A"  PC
 SG_ M2P_PermitMaxDisCharge_I_B11_21 : 48|16@1+ (1,-20000) [-20000|45535] "A"  PC

BO_ 2336812710 M2P_SUMDATA65__22: 8 MBMU
 SG_ M2P_Measure_Vol_B11_22 : 0|16@1+ (0.1,0) [0|6553.5] "V"  PC,SBMU
 SG_ M2P_Current_B11_22 : 16|16@1+ (1,-20000) [-20000|45535] "A"  PC,SBMU
 SG_ M2P_PermitMaxCharge_I_B11_22 : 32|16@1+ (1,-20000) [-20000|45535] "A"  PC
 SG_ M2P_PermitMaxDisCharge_I_B11_22 : 48|16@1+ (1,-20000) [-20000|45535] "A"  PC

BO_ 2336812711 M2P_SUMDATA65__23: 8 MBMU
 SG_ M2P_Measure_Vol_B11_23 : 0|16@1+ (0.1,0) [0|6553.5] "V"  PC,SBMU
 SG_ M2P_Current_B11_23 : 16|16@1+ (1,-20000) [-20000|45535] "A"  PC,SBMU
 SG_ M2P_PermitMaxCharge_I_B11_23 : 32|16@1+ (1,-20000) [-20000|45535] "A"  PC
 SG_ M2P_PermitMaxDisCharge_I_B11_23 : 48|16@1+ (1,-20000) [-20000|45535] "A"  PC

BO_ 2336812712 M2P_SUMDATA65__24: 8 MBMU
 SG_ M2P_Measure_Vol_B11_24 : 0|16@1+ (0.1,0) [0|6553.5] "V"  PC,SBMU
 SG_ M2P_Current_B11_24 : 16|16@1+ (1,-20000) [-20000|45535] "A"  PC,SBMU
 SG_ M2P_PermitMaxCharge_I_B11_24 : 32|16@1+ (1,-20000) [-20000|45535] "A"  PC
 SG_ M2P_PermitMaxDisCharge_I_B11_24 : 48|16@1+ (1,-20000) [-20000|45535] "A"  PC

BO_ 2336812713 M2P_SUMDATA65__25: 8 MBMU
 SG_ M2P_Measure_Vol_B11_25 : 0|16@1+ (0.1,0) [0|6553.5] "V"  PC,SBMU
 SG_ M2P_Current_B11_25 : 16|16@1+ (1,-20000) [-20000|45535] "A"  PC,SBMU
 SG_ M2P_PermitMaxCharge_I_B11_25 : 32|16@1+ (1,-20000) [-20000|45535] "A"  PC
 SG_ M2P_PermitMaxDisCharge_I_B11_25 : 48|16@1+ (1,-20000) [-20000|45535] "A"  PC

BO_ 2336812714 M2P_SUMDATA65__26: 8 MBMU
 SG_ M2P_Measure_Vol_B11_26 : 0|16@1+ (0.1,0) [0|6553.5] "V"  PC,SBMU
 SG_ M2P_Current_B11_26 : 16|16@1+ (1,-20000) [-20000|45535] "A"  PC,SBMU
 SG_ M2P_PermitMaxCharge_I_B11_26 : 32|16@1+ (1,-20000) [-20000|45535] "A"  PC
 SG_ M2P_PermitMaxDisCharge_I_B11_26 : 48|16@1+ (1,-20000) [-20000|45535] "A"  PC

BO_ 2336812715 M2P_SUMDATA65__27: 8 MBMU
 SG_ M2P_Measure_Vol_B11_27 : 0|16@1+ (0.1,0) [0|6553.5] "V"  PC,SBMU
 SG_ M2P_Current_B11_27 : 16|16@1+ (1,-20000) [-20000|45535] "A"  PC,SBMU
 SG_ M2P_PermitMaxCharge_I_B11_27 : 32|16@1+ (1,-20000) [-20000|45535] "A"  PC
 SG_ M2P_PermitMaxDisCharge_I_B11_27 : 48|16@1+ (1,-20000) [-20000|45535] "A"  PC

BO_ 2336812716 M2P_SUMDATA65__28: 8 MBMU
 SG_ M2P_Measure_Vol_B11_28 : 0|16@1+ (0.1,0) [0|6553.5] "V"  PC,SBMU
 SG_ M2P_Current_B11_28 : 16|16@1+ (1,-20000) [-20000|45535] "A"  PC,SBMU
 SG_ M2P_PermitMaxCharge_I_B11_28 : 32|16@1+ (1,-20000) [-20000|45535] "A"  PC
 SG_ M2P_PermitMaxDisCharge_I_B11_28 : 48|16@1+ (1,-20000) [-20000|45535] "A"  PC

BO_ 2336812717 M2P_SUMDATA65__29: 8 MBMU
 SG_ M2P_Measure_Vol_B11_29 : 0|16@1+ (0.1,0) [0|6553.5] "V"  PC,SBMU
 SG_ M2P_Current_B11_29 : 16|16@1+ (1,-20000) [-20000|45535] "A"  PC,SBMU
 SG_ M2P_PermitMaxCharge_I_B11_29 : 32|16@1+ (1,-20000) [-20000|45535] "A"  PC
 SG_ M2P_PermitMaxDisCharge_I_B11_29 : 48|16@1+ (1,-20000) [-20000|45535] "A"  PC

BO_ 2336812718 M2P_SUMDATA65__30: 8 MBMU
 SG_ M2P_Measure_Vol_B11_30 : 0|16@1+ (0.1,0) [0|6553.5] "V"  PC,SBMU
 SG_ M2P_Current_B11_30 : 16|16@1+ (1,-20000) [-20000|45535] "A"  PC,SBMU
 SG_ M2P_PermitMaxCharge_I_B11_30 : 32|16@1+ (1,-20000) [-20000|45535] "A"  PC
 SG_ M2P_PermitMaxDisCharge_I_B11_30 : 48|16@1+ (1,-20000) [-20000|45535] "A"  PC

BO_ 2336812719 M2P_SUMDATA65__31: 8 MBMU
 SG_ M2P_Measure_Vol_B11_31 : 0|16@1+ (0.1,0) [0|6553.5] "V"  PC,SBMU
 SG_ M2P_Current_B11_31 : 16|16@1+ (1,-20000) [-20000|45535] "A"  PC,SBMU
 SG_ M2P_PermitMaxCharge_I_B11_31 : 32|16@1+ (1,-20000) [-20000|45535] "A"  PC
 SG_ M2P_PermitMaxDisCharge_I_B11_31 : 48|16@1+ (1,-20000) [-20000|45535] "A"  PC

BO_ 2336878225 M2P_SUMDATA66__01: 8 MBMU
 SG_ M2P_PermitMaxVolt_B11_01 : 0|16@1+ (0.1,0) [0|6553.5] "V"  PC
 SG_ M2P_PermitMinVolt_B11_01 : 16|16@1+ (0.1,0) [0|6553.5] "V"  PC
 SG_ M2P_PermitMaxPow_Chg_B11_01 : 32|16@1+ (1,-20000) [-20000|45535] "Kw"  PC
 SG_ M2P_PermitMaxPow_DisChg_B11_01 : 48|16@1+ (1,-20000) [-20000|45535] "Kw"  PC

BO_ 2336878226 M2P_SUMDATA66__02: 8 MBMU
 SG_ M2P_PermitMaxVolt_B11_02 : 0|16@1+ (0.1,0) [0|6553.5] "V"  PC
 SG_ M2P_PermitMinVolt_B11_02 : 16|16@1+ (0.1,0) [0|6553.5] "V"  PC
 SG_ M2P_PermitMaxPow_Chg_B11_02 : 32|16@1+ (1,-20000) [-20000|45535] "Kw"  PC
 SG_ M2P_PermitMaxPow_DisChg_B11_02 : 48|16@1+ (1,-20000) [-20000|45535] "Kw"  PC

BO_ 2336878227 M2P_SUMDATA66__03: 8 MBMU
 SG_ M2P_PermitMaxVolt_B11_03 : 0|16@1+ (0.1,0) [0|6553.5] "V"  PC
 SG_ M2P_PermitMinVolt_B11_03 : 16|16@1+ (0.1,0) [0|6553.5] "V"  PC
 SG_ M2P_PermitMaxPow_Chg_B11_03 : 32|16@1+ (1,-20000) [-20000|45535] "Kw"  PC
 SG_ M2P_PermitMaxPow_DisChg_B11_03 : 48|16@1+ (1,-20000) [-20000|45535] "Kw"  PC

BO_ 2336878228 M2P_SUMDATA66__04: 8 MBMU
 SG_ M2P_PermitMaxVolt_B11_04 : 0|16@1+ (0.1,0) [0|6553.5] "V"  PC
 SG_ M2P_PermitMinVolt_B11_04 : 16|16@1+ (0.1,0) [0|6553.5] "V"  PC
 SG_ M2P_PermitMaxPow_Chg_B11_04 : 32|16@1+ (1,-20000) [-20000|45535] "Kw"  PC
 SG_ M2P_PermitMaxPow_DisChg_B11_04 : 48|16@1+ (1,-20000) [-20000|45535] "Kw"  PC

BO_ 2336878229 M2P_SUMDATA66__05: 8 MBMU
 SG_ M2P_PermitMaxVolt_B11_05 : 0|16@1+ (0.1,0) [0|6553.5] "V"  PC
 SG_ M2P_PermitMinVolt_B11_05 : 16|16@1+ (0.1,0) [0|6553.5] "V"  PC
 SG_ M2P_PermitMaxPow_Chg_B11_05 : 32|16@1+ (1,-20000) [-20000|45535] "Kw"  PC
 SG_ M2P_PermitMaxPow_DisChg_B11_05 : 48|16@1+ (1,-20000) [-20000|45535] "Kw"  PC

BO_ 2336878230 M2P_SUMDATA66__06: 8 MBMU
 SG_ M2P_PermitMaxVolt_B11_06 : 0|16@1+ (0.1,0) [0|6553.5] "V"  PC
 SG_ M2P_PermitMinVolt_B11_06 : 16|16@1+ (0.1,0) [0|6553.5] "V"  PC
 SG_ M2P_PermitMaxPow_Chg_B11_06 : 32|16@1+ (1,-20000) [-20000|45535] "Kw"  PC
 SG_ M2P_PermitMaxPow_DisChg_B11_06 : 48|16@1+ (1,-20000) [-20000|45535] "Kw"  PC

BO_ 2336878231 M2P_SUMDATA66__07: 8 MBMU
 SG_ M2P_PermitMaxVolt_B11_07 : 0|16@1+ (0.1,0) [0|6553.5] "V"  PC
 SG_ M2P_PermitMinVolt_B11_07 : 16|16@1+ (0.1,0) [0|6553.5] "V"  PC
 SG_ M2P_PermitMaxPow_Chg_B11_07 : 32|16@1+ (1,-20000) [-20000|45535] "Kw"  PC
 SG_ M2P_PermitMaxPow_DisChg_B11_07 : 48|16@1+ (1,-20000) [-20000|45535] "Kw"  PC

BO_ 2336878232 M2P_SUMDATA66__08: 8 MBMU
 SG_ M2P_PermitMaxVolt_B11_08 : 0|16@1+ (0.1,0) [0|6553.5] "V"  PC
 SG_ M2P_PermitMinVolt_B11_08 : 16|16@1+ (0.1,0) [0|6553.5] "V"  PC
 SG_ M2P_PermitMaxPow_Chg_B11_08 : 32|16@1+ (1,-20000) [-20000|45535] "Kw"  PC
 SG_ M2P_PermitMaxPow_DisChg_B11_08 : 48|16@1+ (1,-20000) [-20000|45535] "Kw"  PC

BO_ 2336878233 M2P_SUMDATA66__09: 8 MBMU
 SG_ M2P_PermitMaxVolt_B11_09 : 0|16@1+ (0.1,0) [0|6553.5] "V"  PC
 SG_ M2P_PermitMinVolt_B11_09 : 16|16@1+ (0.1,0) [0|6553.5] "V"  PC
 SG_ M2P_PermitMaxPow_Chg_B11_09 : 32|16@1+ (1,-20000) [-20000|45535] "Kw"  PC
 SG_ M2P_PermitMaxPow_DisChg_B11_09 : 48|16@1+ (1,-20000) [-20000|45535] "Kw"  PC

BO_ 2336878234 M2P_SUMDATA66__10: 8 MBMU
 SG_ M2P_PermitMaxVolt_B11_10 : 0|16@1+ (0.1,0) [0|6553.5] "V"  PC
 SG_ M2P_PermitMinVolt_B11_10 : 16|16@1+ (0.1,0) [0|6553.5] "V"  PC
 SG_ M2P_PermitMaxPow_Chg_B11_10 : 32|16@1+ (1,-20000) [-20000|45535] "Kw"  PC
 SG_ M2P_PermitMaxPow_DisChg_B11_10 : 48|16@1+ (1,-20000) [-20000|45535] "Kw"  PC

BO_ 2336878235 M2P_SUMDATA66__11: 8 MBMU
 SG_ M2P_PermitMaxVolt_B11_11 : 0|16@1+ (0.1,0) [0|6553.5] "V"  PC
 SG_ M2P_PermitMinVolt_B11_11 : 16|16@1+ (0.1,0) [0|6553.5] "V"  PC
 SG_ M2P_PermitMaxPow_Chg_B11_11 : 32|16@1+ (1,-20000) [-20000|45535] "Kw"  PC
 SG_ M2P_PermitMaxPow_DisChg_B11_11 : 48|16@1+ (1,-20000) [-20000|45535] "Kw"  PC

BO_ 2336878236 M2P_SUMDATA66__12: 8 MBMU
 SG_ M2P_PermitMaxVolt_B11_12 : 0|16@1+ (0.1,0) [0|6553.5] "V"  PC
 SG_ M2P_PermitMinVolt_B11_12 : 16|16@1+ (0.1,0) [0|6553.5] "V"  PC
 SG_ M2P_PermitMaxPow_Chg_B11_12 : 32|16@1+ (1,-20000) [-20000|45535] "Kw"  PC
 SG_ M2P_PermitMaxPow_DisChg_B11_12 : 48|16@1+ (1,-20000) [-20000|45535] "Kw"  PC

BO_ 2336878237 M2P_SUMDATA66__13: 8 MBMU
 SG_ M2P_PermitMaxVolt_B11_13 : 0|16@1+ (0.1,0) [0|6553.5] "V"  PC
 SG_ M2P_PermitMinVolt_B11_13 : 16|16@1+ (0.1,0) [0|6553.5] "V"  PC
 SG_ M2P_PermitMaxPow_Chg_B11_13 : 32|16@1+ (1,-20000) [-20000|45535] "Kw"  PC
 SG_ M2P_PermitMaxPow_DisChg_B11_13 : 48|16@1+ (1,-20000) [-20000|45535] "Kw"  PC

BO_ 2336878238 M2P_SUMDATA66__14: 8 MBMU
 SG_ M2P_PermitMaxVolt_B11_14 : 0|16@1+ (0.1,0) [0|6553.5] "V"  PC
 SG_ M2P_PermitMinVolt_B11_14 : 16|16@1+ (0.1,0) [0|6553.5] "V"  PC
 SG_ M2P_PermitMaxPow_Chg_B11_14 : 32|16@1+ (1,-20000) [-20000|45535] "Kw"  PC
 SG_ M2P_PermitMaxPow_DisChg_B11_14 : 48|16@1+ (1,-20000) [-20000|45535] "Kw"  PC

BO_ 2336878239 M2P_SUMDATA66__15: 8 MBMU
 SG_ M2P_PermitMaxVolt_B11_15 : 0|16@1+ (0.1,0) [0|6553.5] "V"  PC
 SG_ M2P_PermitMinVolt_B11_15 : 16|16@1+ (0.1,0) [0|6553.5] "V"  PC
 SG_ M2P_PermitMaxPow_Chg_B11_15 : 32|16@1+ (1,-20000) [-20000|45535] "Kw"  PC
 SG_ M2P_PermitMaxPow_DisChg_B11_15 : 48|16@1+ (1,-20000) [-20000|45535] "Kw"  PC

BO_ 2336878240 M2P_SUMDATA66__16: 8 MBMU
 SG_ M2P_PermitMaxVolt_B11_16 : 0|16@1+ (0.1,0) [0|6553.5] "V"  PC
 SG_ M2P_PermitMinVolt_B11_16 : 16|16@1+ (0.1,0) [0|6553.5] "V"  PC
 SG_ M2P_PermitMaxPow_Chg_B11_16 : 32|16@1+ (1,-20000) [-20000|45535] "Kw"  PC
 SG_ M2P_PermitMaxPow_DisChg_B11_16 : 48|16@1+ (1,-20000) [-20000|45535] "Kw"  PC

BO_ 2336878241 M2P_SUMDATA66__17: 8 MBMU
 SG_ M2P_PermitMaxVolt_B11_17 : 0|16@1+ (0.1,0) [0|6553.5] "V"  PC
 SG_ M2P_PermitMinVolt_B11_17 : 16|16@1+ (0.1,0) [0|6553.5] "V"  PC
 SG_ M2P_PermitMaxPow_Chg_B11_17 : 32|16@1+ (1,-20000) [-20000|45535] "Kw"  PC
 SG_ M2P_PermitMaxPow_DisChg_B11_17 : 48|16@1+ (1,-20000) [-20000|45535] "Kw"  PC

BO_ 2336878242 M2P_SUMDATA66__18: 8 MBMU
 SG_ M2P_PermitMaxVolt_B11_18 : 0|16@1+ (0.1,0) [0|6553.5] "V"  PC
 SG_ M2P_PermitMinVolt_B11_18 : 16|16@1+ (0.1,0) [0|6553.5] "V"  PC
 SG_ M2P_PermitMaxPow_Chg_B11_18 : 32|16@1+ (1,-20000) [-20000|45535] "Kw"  PC
 SG_ M2P_PermitMaxPow_DisChg_B11_18 : 48|16@1+ (1,-20000) [-20000|45535] "Kw"  PC

BO_ 2336878243 M2P_SUMDATA66__19: 8 MBMU
 SG_ M2P_PermitMaxVolt_B11_19 : 0|16@1+ (0.1,0) [0|6553.5] "V"  PC
 SG_ M2P_PermitMinVolt_B11_19 : 16|16@1+ (0.1,0) [0|6553.5] "V"  PC
 SG_ M2P_PermitMaxPow_Chg_B11_19 : 32|16@1+ (1,-20000) [-20000|45535] "Kw"  PC
 SG_ M2P_PermitMaxPow_DisChg_B11_19 : 48|16@1+ (1,-20000) [-20000|45535] "Kw"  PC

BO_ 2336878244 M2P_SUMDATA66__20: 8 MBMU
 SG_ M2P_PermitMaxVolt_B11_20 : 0|16@1+ (0.1,0) [0|6553.5] "V"  PC
 SG_ M2P_PermitMinVolt_B11_20 : 16|16@1+ (0.1,0) [0|6553.5] "V"  PC
 SG_ M2P_PermitMaxPow_Chg_B11_20 : 32|16@1+ (1,-20000) [-20000|45535] "Kw"  PC
 SG_ M2P_PermitMaxPow_DisChg_B11_20 : 48|16@1+ (1,-20000) [-20000|45535] "Kw"  PC

BO_ 2336878245 M2P_SUMDATA66__21: 8 MBMU
 SG_ M2P_PermitMaxVolt_B11_21 : 0|16@1+ (0.1,0) [0|6553.5] "V"  PC
 SG_ M2P_PermitMinVolt_B11_21 : 16|16@1+ (0.1,0) [0|6553.5] "V"  PC
 SG_ M2P_PermitMaxPow_Chg_B11_21 : 32|16@1+ (1,-20000) [-20000|45535] "Kw"  PC
 SG_ M2P_PermitMaxPow_DisChg_B11_21 : 48|16@1+ (1,-20000) [-20000|45535] "Kw"  PC

BO_ 2336878246 M2P_SUMDATA66__22: 8 MBMU
 SG_ M2P_PermitMaxVolt_B11_22 : 0|16@1+ (0.1,0) [0|6553.5] "V"  PC
 SG_ M2P_PermitMinVolt_B11_22 : 16|16@1+ (0.1,0) [0|6553.5] "V"  PC
 SG_ M2P_PermitMaxPow_Chg_B11_22 : 32|16@1+ (1,-20000) [-20000|45535] "Kw"  PC
 SG_ M2P_PermitMaxPow_DisChg_B11_22 : 48|16@1+ (1,-20000) [-20000|45535] "Kw"  PC

BO_ 2336878247 M2P_SUMDATA66__23: 8 MBMU
 SG_ M2P_PermitMaxVolt_B11_23 : 0|16@1+ (0.1,0) [0|6553.5] "V"  PC
 SG_ M2P_PermitMinVolt_B11_23 : 16|16@1+ (0.1,0) [0|6553.5] "V"  PC
 SG_ M2P_PermitMaxPow_Chg_B11_23 : 32|16@1+ (1,-20000) [-20000|45535] "Kw"  PC
 SG_ M2P_PermitMaxPow_DisChg_B11_23 : 48|16@1+ (1,-20000) [-20000|45535] "Kw"  PC

BO_ 2336878248 M2P_SUMDATA66__24: 8 MBMU
 SG_ M2P_PermitMaxVolt_B11_24 : 0|16@1+ (0.1,0) [0|6553.5] "V"  PC
 SG_ M2P_PermitMinVolt_B11_24 : 16|16@1+ (0.1,0) [0|6553.5] "V"  PC
 SG_ M2P_PermitMaxPow_Chg_B11_24 : 32|16@1+ (1,-20000) [-20000|45535] "Kw"  PC
 SG_ M2P_PermitMaxPow_DisChg_B11_24 : 48|16@1+ (1,-20000) [-20000|45535] "Kw"  PC

BO_ 2336878249 M2P_SUMDATA66__25: 8 MBMU
 SG_ M2P_PermitMaxVolt_B11_25 : 0|16@1+ (0.1,0) [0|6553.5] "V"  PC
 SG_ M2P_PermitMinVolt_B11_25 : 16|16@1+ (0.1,0) [0|6553.5] "V"  PC
 SG_ M2P_PermitMaxPow_Chg_B11_25 : 32|16@1+ (1,-20000) [-20000|45535] "Kw"  PC
 SG_ M2P_PermitMaxPow_DisChg_B11_25 : 48|16@1+ (1,-20000) [-20000|45535] "Kw"  PC

BO_ 2336878250 M2P_SUMDATA66__26: 8 MBMU
 SG_ M2P_PermitMaxVolt_B11_26 : 0|16@1+ (0.1,0) [0|6553.5] "V"  PC
 SG_ M2P_PermitMinVolt_B11_26 : 16|16@1+ (0.1,0) [0|6553.5] "V"  PC
 SG_ M2P_PermitMaxPow_Chg_B11_26 : 32|16@1+ (1,-20000) [-20000|45535] "Kw"  PC
 SG_ M2P_PermitMaxPow_DisChg_B11_26 : 48|16@1+ (1,-20000) [-20000|45535] "Kw"  PC

BO_ 2336878251 M2P_SUMDATA66__27: 8 MBMU
 SG_ M2P_PermitMaxVolt_B11_27 : 0|16@1+ (0.1,0) [0|6553.5] "V"  PC
 SG_ M2P_PermitMinVolt_B11_27 : 16|16@1+ (0.1,0) [0|6553.5] "V"  PC
 SG_ M2P_PermitMaxPow_Chg_B11_27 : 32|16@1+ (1,-20000) [-20000|45535] "Kw"  PC
 SG_ M2P_PermitMaxPow_DisChg_B11_27 : 48|16@1+ (1,-20000) [-20000|45535] "Kw"  PC

BO_ 2336878252 M2P_SUMDATA66__28: 8 MBMU
 SG_ M2P_PermitMaxVolt_B11_28 : 0|16@1+ (0.1,0) [0|6553.5] "V"  PC
 SG_ M2P_PermitMinVolt_B11_28 : 16|16@1+ (0.1,0) [0|6553.5] "V"  PC
 SG_ M2P_PermitMaxPow_Chg_B11_28 : 32|16@1+ (1,-20000) [-20000|45535] "Kw"  PC
 SG_ M2P_PermitMaxPow_DisChg_B11_28 : 48|16@1+ (1,-20000) [-20000|45535] "Kw"  PC

BO_ 2336878253 M2P_SUMDATA66__29: 8 MBMU
 SG_ M2P_PermitMaxVolt_B11_29 : 0|16@1+ (0.1,0) [0|6553.5] "V"  PC
 SG_ M2P_PermitMinVolt_B11_29 : 16|16@1+ (0.1,0) [0|6553.5] "V"  PC
 SG_ M2P_PermitMaxPow_Chg_B11_29 : 32|16@1+ (1,-20000) [-20000|45535] "Kw"  PC
 SG_ M2P_PermitMaxPow_DisChg_B11_29 : 48|16@1+ (1,-20000) [-20000|45535] "Kw"  PC

BO_ 2336878254 M2P_SUMDATA66__30: 8 MBMU
 SG_ M2P_PermitMaxVolt_B11_30 : 0|16@1+ (0.1,0) [0|6553.5] "V"  PC
 SG_ M2P_PermitMinVolt_B11_30 : 16|16@1+ (0.1,0) [0|6553.5] "V"  PC
 SG_ M2P_PermitMaxPow_Chg_B11_30 : 32|16@1+ (1,-20000) [-20000|45535] "Kw"  PC
 SG_ M2P_PermitMaxPow_DisChg_B11_30 : 48|16@1+ (1,-20000) [-20000|45535] "Kw"  PC

BO_ 2336878255 M2P_SUMDATA66__31: 8 MBMU
 SG_ M2P_PermitMaxVolt_B11_31 : 0|16@1+ (0.1,0) [0|6553.5] "V"  PC
 SG_ M2P_PermitMinVolt_B11_31 : 16|16@1+ (0.1,0) [0|6553.5] "V"  PC
 SG_ M2P_PermitMaxPow_Chg_B11_31 : 32|16@1+ (1,-20000) [-20000|45535] "Kw"  PC
 SG_ M2P_PermitMaxPow_DisChg_B11_31 : 48|16@1+ (1,-20000) [-20000|45535] "Kw"  PC

BO_ 2336943761 M2P_SUMDATA67__01: 8 MBMU
 SG_ M2P_Power_B11_01 : 0|16@1+ (1,-20000) [-20000|45535] "Kw"  PC
 SG_ M2P_SysremEngy_Chg_B11_01 : 16|16@1+ (1,0) [0|65535] "Kwh"  PC
 SG_ M2P_SysremEngy_DisChg_B11_01 : 32|16@1+ (1,0) [0|65535] "Kwh"  PC
 SG_ M2P_SysMaxVolt_B11_01 : 48|16@1+ (1,0) [0|65535] "mv"  PC

BO_ 2336943762 M2P_SUMDATA67__02: 8 MBMU
 SG_ M2P_Power_B11_02 : 0|16@1+ (1,-20000) [-20000|45535] "Kw"  PC
 SG_ M2P_SysremEngy_Chg_B11_02 : 16|16@1+ (1,0) [0|65535] "Kwh"  PC
 SG_ M2P_SysremEngy_DisChg_B11_02 : 32|16@1+ (1,0) [0|65535] "Kwh"  PC
 SG_ M2P_SysMaxVolt_B11_02 : 48|16@1+ (1,0) [0|65535] "mv"  PC

BO_ 2336943763 M2P_SUMDATA67__03: 8 MBMU
 SG_ M2P_Power_B11_03 : 0|16@1+ (1,-20000) [-20000|45535] "Kw"  PC
 SG_ M2P_SysremEngy_Chg_B11_03 : 16|16@1+ (1,0) [0|65535] "Kwh"  PC
 SG_ M2P_SysremEngy_DisChg_B11_03 : 32|16@1+ (1,0) [0|65535] "Kwh"  PC
 SG_ M2P_SysMaxVolt_B11_03 : 48|16@1+ (1,0) [0|65535] "mv"  PC

BO_ 2336943764 M2P_SUMDATA67__04: 8 MBMU
 SG_ M2P_Power_B11_04 : 0|16@1+ (1,-20000) [-20000|45535] "Kw"  PC
 SG_ M2P_SysremEngy_Chg_B11_04 : 16|16@1+ (1,0) [0|65535] "Kwh"  PC
 SG_ M2P_SysremEngy_DisChg_B11_04 : 32|16@1+ (1,0) [0|65535] "Kwh"  PC
 SG_ M2P_SysMaxVolt_B11_04 : 48|16@1+ (1,0) [0|65535] "mv"  PC

BO_ 2336943765 M2P_SUMDATA67__05: 8 MBMU
 SG_ M2P_Power_B11_05 : 0|16@1+ (1,-20000) [-20000|45535] "Kw"  PC
 SG_ M2P_SysremEngy_Chg_B11_05 : 16|16@1+ (1,0) [0|65535] "Kwh"  PC
 SG_ M2P_SysremEngy_DisChg_B11_05 : 32|16@1+ (1,0) [0|65535] "Kwh"  PC
 SG_ M2P_SysMaxVolt_B11_05 : 48|16@1+ (1,0) [0|65535] "mv"  PC

BO_ 2336943766 M2P_SUMDATA67__06: 8 MBMU
 SG_ M2P_Power_B11_06 : 0|16@1+ (1,-20000) [-20000|45535] "Kw"  PC
 SG_ M2P_SysremEngy_Chg_B11_06 : 16|16@1+ (1,0) [0|65535] "Kwh"  PC
 SG_ M2P_SysremEngy_DisChg_B11_06 : 32|16@1+ (1,0) [0|65535] "Kwh"  PC
 SG_ M2P_SysMaxVolt_B11_06 : 48|16@1+ (1,0) [0|65535] "mv"  PC

BO_ 2336943767 M2P_SUMDATA67__07: 8 MBMU
 SG_ M2P_Power_B11_07 : 0|16@1+ (1,-20000) [-20000|45535] "Kw"  PC
 SG_ M2P_SysremEngy_Chg_B11_07 : 16|16@1+ (1,0) [0|65535] "Kwh"  PC
 SG_ M2P_SysremEngy_DisChg_B11_07 : 32|16@1+ (1,0) [0|65535] "Kwh"  PC
 SG_ M2P_SysMaxVolt_B11_07 : 48|16@1+ (1,0) [0|65535] "mv"  PC

BO_ 2336943768 M2P_SUMDATA67__08: 8 MBMU
 SG_ M2P_Power_B11_08 : 0|16@1+ (1,-20000) [-20000|45535] "Kw"  PC
 SG_ M2P_SysremEngy_Chg_B11_08 : 16|16@1+ (1,0) [0|65535] "Kwh"  PC
 SG_ M2P_SysremEngy_DisChg_B11_08 : 32|16@1+ (1,0) [0|65535] "Kwh"  PC
 SG_ M2P_SysMaxVolt_B11_08 : 48|16@1+ (1,0) [0|65535] "mv"  PC

BO_ 2336943769 M2P_SUMDATA67__09: 8 MBMU
 SG_ M2P_Power_B11_09 : 0|16@1+ (1,-20000) [-20000|45535] "Kw"  PC
 SG_ M2P_SysremEngy_Chg_B11_09 : 16|16@1+ (1,0) [0|65535] "Kwh"  PC
 SG_ M2P_SysremEngy_DisChg_B11_09 : 32|16@1+ (1,0) [0|65535] "Kwh"  PC
 SG_ M2P_SysMaxVolt_B11_09 : 48|16@1+ (1,0) [0|65535] "mv"  PC

BO_ 2336943770 M2P_SUMDATA67__10: 8 MBMU
 SG_ M2P_Power_B11_10 : 0|16@1+ (1,-20000) [-20000|45535] "Kw"  PC
 SG_ M2P_SysremEngy_Chg_B11_10 : 16|16@1+ (1,0) [0|65535] "Kwh"  PC
 SG_ M2P_SysremEngy_DisChg_B11_10 : 32|16@1+ (1,0) [0|65535] "Kwh"  PC
 SG_ M2P_SysMaxVolt_B11_10 : 48|16@1+ (1,0) [0|65535] "mv"  PC

BO_ 2336943771 M2P_SUMDATA67__11: 8 MBMU
 SG_ M2P_Power_B11_11 : 0|16@1+ (1,-20000) [-20000|45535] "Kw"  PC
 SG_ M2P_SysremEngy_Chg_B11_11 : 16|16@1+ (1,0) [0|65535] "Kwh"  PC
 SG_ M2P_SysremEngy_DisChg_B11_11 : 32|16@1+ (1,0) [0|65535] "Kwh"  PC
 SG_ M2P_SysMaxVolt_B11_11 : 48|16@1+ (1,0) [0|65535] "mv"  PC

BO_ 2336943772 M2P_SUMDATA67__12: 8 MBMU
 SG_ M2P_Power_B11_12 : 0|16@1+ (1,-20000) [-20000|45535] "Kw"  PC
 SG_ M2P_SysremEngy_Chg_B11_12 : 16|16@1+ (1,0) [0|65535] "Kwh"  PC
 SG_ M2P_SysremEngy_DisChg_B11_12 : 32|16@1+ (1,0) [0|65535] "Kwh"  PC
 SG_ M2P_SysMaxVolt_B11_12 : 48|16@1+ (1,0) [0|65535] "mv"  PC

BO_ 2336943773 M2P_SUMDATA67__13: 8 MBMU
 SG_ M2P_Power_B11_13 : 0|16@1+ (1,-20000) [-20000|45535] "Kw"  PC
 SG_ M2P_SysremEngy_Chg_B11_13 : 16|16@1+ (1,0) [0|65535] "Kwh"  PC
 SG_ M2P_SysremEngy_DisChg_B11_13 : 32|16@1+ (1,0) [0|65535] "Kwh"  PC
 SG_ M2P_SysMaxVolt_B11_13 : 48|16@1+ (1,0) [0|65535] "mv"  PC

BO_ 2336943774 M2P_SUMDATA67__14: 8 MBMU
 SG_ M2P_Power_B11_14 : 0|16@1+ (1,-20000) [-20000|45535] "Kw"  PC
 SG_ M2P_SysremEngy_Chg_B11_14 : 16|16@1+ (1,0) [0|65535] "Kwh"  PC
 SG_ M2P_SysremEngy_DisChg_B11_14 : 32|16@1+ (1,0) [0|65535] "Kwh"  PC
 SG_ M2P_SysMaxVolt_B11_14 : 48|16@1+ (1,0) [0|65535] "mv"  PC

BO_ 2336943775 M2P_SUMDATA67__15: 8 MBMU
 SG_ M2P_Power_B11_15 : 0|16@1+ (1,-20000) [-20000|45535] "Kw"  PC
 SG_ M2P_SysremEngy_Chg_B11_15 : 16|16@1+ (1,0) [0|65535] "Kwh"  PC
 SG_ M2P_SysremEngy_DisChg_B11_15 : 32|16@1+ (1,0) [0|65535] "Kwh"  PC
 SG_ M2P_SysMaxVolt_B11_15 : 48|16@1+ (1,0) [0|65535] "mv"  PC

BO_ 2336943776 M2P_SUMDATA67__16: 8 MBMU
 SG_ M2P_Power_B11_16 : 0|16@1+ (1,-20000) [-20000|45535] "Kw"  PC
 SG_ M2P_SysremEngy_Chg_B11_16 : 16|16@1+ (1,0) [0|65535] "Kwh"  PC
 SG_ M2P_SysremEngy_DisChg_B11_16 : 32|16@1+ (1,0) [0|65535] "Kwh"  PC
 SG_ M2P_SysMaxVolt_B11_16 : 48|16@1+ (1,0) [0|65535] "mv"  PC

BO_ 2336943777 M2P_SUMDATA67__17: 8 MBMU
 SG_ M2P_Power_B11_17 : 0|16@1+ (1,-20000) [-20000|45535] "Kw"  PC
 SG_ M2P_SysremEngy_Chg_B11_17 : 16|16@1+ (1,0) [0|65535] "Kwh"  PC
 SG_ M2P_SysremEngy_DisChg_B11_17 : 32|16@1+ (1,0) [0|65535] "Kwh"  PC
 SG_ M2P_SysMaxVolt_B11_17 : 48|16@1+ (1,0) [0|65535] "mv"  PC

BO_ 2336943778 M2P_SUMDATA67__18: 8 MBMU
 SG_ M2P_Power_B11_18 : 0|16@1+ (1,-20000) [-20000|45535] "Kw"  PC
 SG_ M2P_SysremEngy_Chg_B11_18 : 16|16@1+ (1,0) [0|65535] "Kwh"  PC
 SG_ M2P_SysremEngy_DisChg_B11_18 : 32|16@1+ (1,0) [0|65535] "Kwh"  PC
 SG_ M2P_SysMaxVolt_B11_18 : 48|16@1+ (1,0) [0|65535] "mv"  PC

BO_ 2336943779 M2P_SUMDATA67__19: 8 MBMU
 SG_ M2P_Power_B11_19 : 0|16@1+ (1,-20000) [-20000|45535] "Kw"  PC
 SG_ M2P_SysremEngy_Chg_B11_19 : 16|16@1+ (1,0) [0|65535] "Kwh"  PC
 SG_ M2P_SysremEngy_DisChg_B11_19 : 32|16@1+ (1,0) [0|65535] "Kwh"  PC
 SG_ M2P_SysMaxVolt_B11_19 : 48|16@1+ (1,0) [0|65535] "mv"  PC

BO_ 2336943780 M2P_SUMDATA67__20: 8 MBMU
 SG_ M2P_Power_B11_20 : 0|16@1+ (1,-20000) [-20000|45535] "Kw"  PC
 SG_ M2P_SysremEngy_Chg_B11_20 : 16|16@1+ (1,0) [0|65535] "Kwh"  PC
 SG_ M2P_SysremEngy_DisChg_B11_20 : 32|16@1+ (1,0) [0|65535] "Kwh"  PC
 SG_ M2P_SysMaxVolt_B11_20 : 48|16@1+ (1,0) [0|65535] "mv"  PC

BO_ 2336943781 M2P_SUMDATA67__21: 8 MBMU
 SG_ M2P_Power_B11_21 : 0|16@1+ (1,-20000) [-20000|45535] "Kw"  PC
 SG_ M2P_SysremEngy_Chg_B11_21 : 16|16@1+ (1,0) [0|65535] "Kwh"  PC
 SG_ M2P_SysremEngy_DisChg_B11_21 : 32|16@1+ (1,0) [0|65535] "Kwh"  PC
 SG_ M2P_SysMaxVolt_B11_21 : 48|16@1+ (1,0) [0|65535] "mv"  PC

BO_ 2336943782 M2P_SUMDATA67__22: 8 MBMU
 SG_ M2P_Power_B11_22 : 0|16@1+ (1,-20000) [-20000|45535] "Kw"  PC
 SG_ M2P_SysremEngy_Chg_B11_22 : 16|16@1+ (1,0) [0|65535] "Kwh"  PC
 SG_ M2P_SysremEngy_DisChg_B11_22 : 32|16@1+ (1,0) [0|65535] "Kwh"  PC
 SG_ M2P_SysMaxVolt_B11_22 : 48|16@1+ (1,0) [0|65535] "mv"  PC

BO_ 2336943783 M2P_SUMDATA67__23: 8 MBMU
 SG_ M2P_Power_B11_23 : 0|16@1+ (1,-20000) [-20000|45535] "Kw"  PC
 SG_ M2P_SysremEngy_Chg_B11_23 : 16|16@1+ (1,0) [0|65535] "Kwh"  PC
 SG_ M2P_SysremEngy_DisChg_B11_23 : 32|16@1+ (1,0) [0|65535] "Kwh"  PC
 SG_ M2P_SysMaxVolt_B11_23 : 48|16@1+ (1,0) [0|65535] "mv"  PC

BO_ 2336943784 M2P_SUMDATA67__24: 8 MBMU
 SG_ M2P_Power_B11_24 : 0|16@1+ (1,-20000) [-20000|45535] "Kw"  PC
 SG_ M2P_SysremEngy_Chg_B11_24 : 16|16@1+ (1,0) [0|65535] "Kwh"  PC
 SG_ M2P_SysremEngy_DisChg_B11_24 : 32|16@1+ (1,0) [0|65535] "Kwh"  PC
 SG_ M2P_SysMaxVolt_B11_24 : 48|16@1+ (1,0) [0|65535] "mv"  PC

BO_ 2336943785 M2P_SUMDATA67__25: 8 MBMU
 SG_ M2P_Power_B11_25 : 0|16@1+ (1,-20000) [-20000|45535] "Kw"  PC
 SG_ M2P_SysremEngy_Chg_B11_25 : 16|16@1+ (1,0) [0|65535] "Kwh"  PC
 SG_ M2P_SysremEngy_DisChg_B11_25 : 32|16@1+ (1,0) [0|65535] "Kwh"  PC
 SG_ M2P_SysMaxVolt_B11_25 : 48|16@1+ (1,0) [0|65535] "mv"  PC

BO_ 2336943786 M2P_SUMDATA67__26: 8 MBMU
 SG_ M2P_Power_B11_26 : 0|16@1+ (1,-20000) [-20000|45535] "Kw"  PC
 SG_ M2P_SysremEngy_Chg_B11_26 : 16|16@1+ (1,0) [0|65535] "Kwh"  PC
 SG_ M2P_SysremEngy_DisChg_B11_26 : 32|16@1+ (1,0) [0|65535] "Kwh"  PC
 SG_ M2P_SysMaxVolt_B11_26 : 48|16@1+ (1,0) [0|65535] "mv"  PC

BO_ 2336943787 M2P_SUMDATA67__27: 8 MBMU
 SG_ M2P_Power_B11_27 : 0|16@1+ (1,-20000) [-20000|45535] "Kw"  PC
 SG_ M2P_SysremEngy_Chg_B11_27 : 16|16@1+ (1,0) [0|65535] "Kwh"  PC
 SG_ M2P_SysremEngy_DisChg_B11_27 : 32|16@1+ (1,0) [0|65535] "Kwh"  PC
 SG_ M2P_SysMaxVolt_B11_27 : 48|16@1+ (1,0) [0|65535] "mv"  PC

BO_ 2336943788 M2P_SUMDATA67__28: 8 MBMU
 SG_ M2P_Power_B11_28 : 0|16@1+ (1,-20000) [-20000|45535] "Kw"  PC
 SG_ M2P_SysremEngy_Chg_B11_28 : 16|16@1+ (1,0) [0|65535] "Kwh"  PC
 SG_ M2P_SysremEngy_DisChg_B11_28 : 32|16@1+ (1,0) [0|65535] "Kwh"  PC
 SG_ M2P_SysMaxVolt_B11_28 : 48|16@1+ (1,0) [0|65535] "mv"  PC

BO_ 2336943789 M2P_SUMDATA67__29: 8 MBMU
 SG_ M2P_Power_B11_29 : 0|16@1+ (1,-20000) [-20000|45535] "Kw"  PC
 SG_ M2P_SysremEngy_Chg_B11_29 : 16|16@1+ (1,0) [0|65535] "Kwh"  PC
 SG_ M2P_SysremEngy_DisChg_B11_29 : 32|16@1+ (1,0) [0|65535] "Kwh"  PC
 SG_ M2P_SysMaxVolt_B11_29 : 48|16@1+ (1,0) [0|65535] "mv"  PC

BO_ 2336943790 M2P_SUMDATA67__30: 8 MBMU
 SG_ M2P_Power_B11_30 : 0|16@1+ (1,-20000) [-20000|45535] "Kw"  PC
 SG_ M2P_SysremEngy_Chg_B11_30 : 16|16@1+ (1,0) [0|65535] "Kwh"  PC
 SG_ M2P_SysremEngy_DisChg_B11_30 : 32|16@1+ (1,0) [0|65535] "Kwh"  PC
 SG_ M2P_SysMaxVolt_B11_30 : 48|16@1+ (1,0) [0|65535] "mv"  PC

BO_ 2336943791 M2P_SUMDATA67__31: 8 MBMU
 SG_ M2P_Power_B11_31 : 0|16@1+ (1,-20000) [-20000|45535] "Kw"  PC
 SG_ M2P_SysremEngy_Chg_B11_31 : 16|16@1+ (1,0) [0|65535] "Kwh"  PC
 SG_ M2P_SysremEngy_DisChg_B11_31 : 32|16@1+ (1,0) [0|65535] "Kwh"  PC
 SG_ M2P_SysMaxVolt_B11_31 : 48|16@1+ (1,0) [0|65535] "mv"  PC

BO_ 2337009297 M2P_SUMDATA68__01: 8 MBMU
 SG_ M2P_SysMinVolt_B11_01 : 0|16@1+ (1,0) [0|65535] "mv"  PC
 SG_ M2P_SysAvgVolt_B11_01 : 16|16@1+ (1,0) [0|65535] "mv"  PC
 SG_ M2P_BMS_Status_B11 : 32|3@1+ (1,0) [0|7] ""  PC
 SG_ M2P_SOC_B11 : 35|10@1+ (0.1,0) [0|102.3] "%"  PC
 SG_ M2P_SOH_B11 : 45|8@1+ (1,0) [0|255] "%"  PC
 SG_ Reserved_01 : 53|11@1+ (1,0) [0|2047] ""  PC

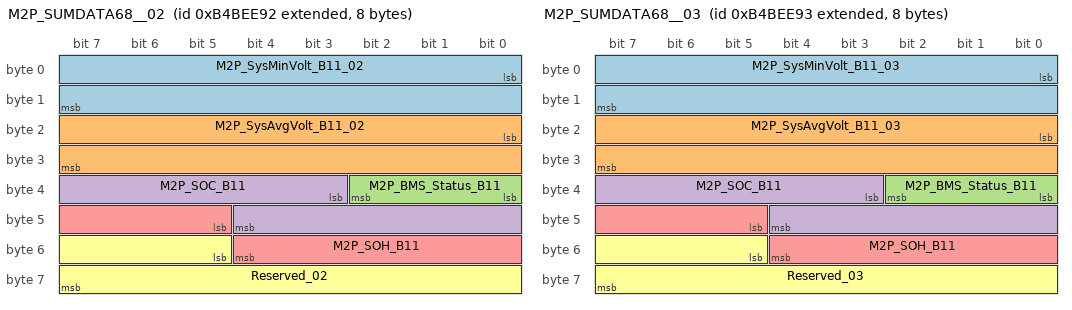
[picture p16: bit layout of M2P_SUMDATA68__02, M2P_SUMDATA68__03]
BO_ 2337009298 M2P_SUMDATA68__02: 8 MBMU
 SG_ M2P_SysMinVolt_B11_02 : 0|16@1+ (1,0) [0|65535] "mv"  PC
 SG_ M2P_SysAvgVolt_B11_02 : 16|16@1+ (1,0) [0|65535] "mv"  PC
 SG_ M2P_BMS_Status_B11 : 32|3@1+ (1,0) [0|7] ""  PC
 SG_ M2P_SOC_B11 : 35|10@1+ (0.1,0) [0|102.3] "%"  PC
 SG_ M2P_SOH_B11 : 45|8@1+ (1,0) [0|255] "%"  PC
 SG_ Reserved_02 : 53|11@1+ (1,0) [0|2047] ""  PC

BO_ 2337009299 M2P_SUMDATA68__03: 8 MBMU
 SG_ M2P_SysMinVolt_B11_03 : 0|16@1+ (1,0) [0|65535] "mv"  PC
 SG_ M2P_SysAvgVolt_B11_03 : 16|16@1+ (1,0) [0|65535] "mv"  PC
 SG_ M2P_BMS_Status_B11 : 32|3@1+ (1,0) [0|7] ""  PC
 SG_ M2P_SOC_B11 : 35|10@1+ (0.1,0) [0|102.3] "%"  PC
 SG_ M2P_SOH_B11 : 45|8@1+ (1,0) [0|255] "%"  PC
 SG_ Reserved_03 : 53|11@1+ (1,0) [0|2047] ""  PC

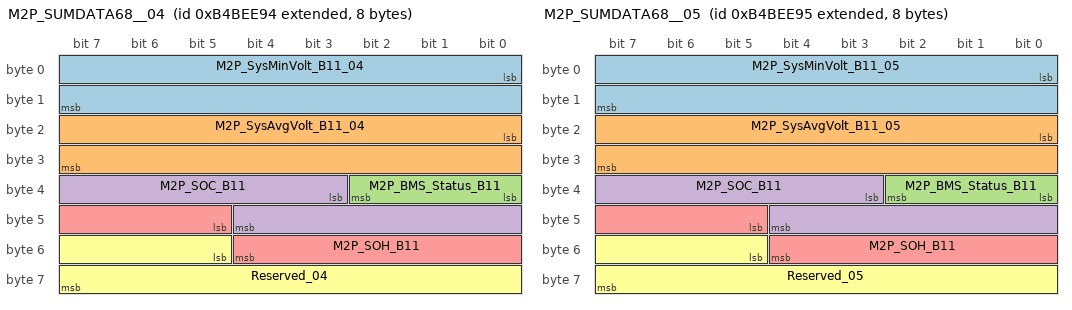
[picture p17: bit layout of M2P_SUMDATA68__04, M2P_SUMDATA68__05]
BO_ 2337009300 M2P_SUMDATA68__04: 8 MBMU
 SG_ M2P_SysMinVolt_B11_04 : 0|16@1+ (1,0) [0|65535] "mv"  PC
 SG_ M2P_SysAvgVolt_B11_04 : 16|16@1+ (1,0) [0|65535] "mv"  PC
 SG_ M2P_BMS_Status_B11 : 32|3@1+ (1,0) [0|7] ""  PC
 SG_ M2P_SOC_B11 : 35|10@1+ (0.1,0) [0|102.3] "%"  PC
 SG_ M2P_SOH_B11 : 45|8@1+ (1,0) [0|255] "%"  PC
 SG_ Reserved_04 : 53|11@1+ (1,0) [0|2047] ""  PC

BO_ 2337009301 M2P_SUMDATA68__05: 8 MBMU
 SG_ M2P_SysMinVolt_B11_05 : 0|16@1+ (1,0) [0|65535] "mv"  PC
 SG_ M2P_SysAvgVolt_B11_05 : 16|16@1+ (1,0) [0|65535] "mv"  PC
 SG_ M2P_BMS_Status_B11 : 32|3@1+ (1,0) [0|7] ""  PC
 SG_ M2P_SOC_B11 : 35|10@1+ (0.1,0) [0|102.3] "%"  PC
 SG_ M2P_SOH_B11 : 45|8@1+ (1,0) [0|255] "%"  PC
 SG_ Reserved_05 : 53|11@1+ (1,0) [0|2047] ""  PC

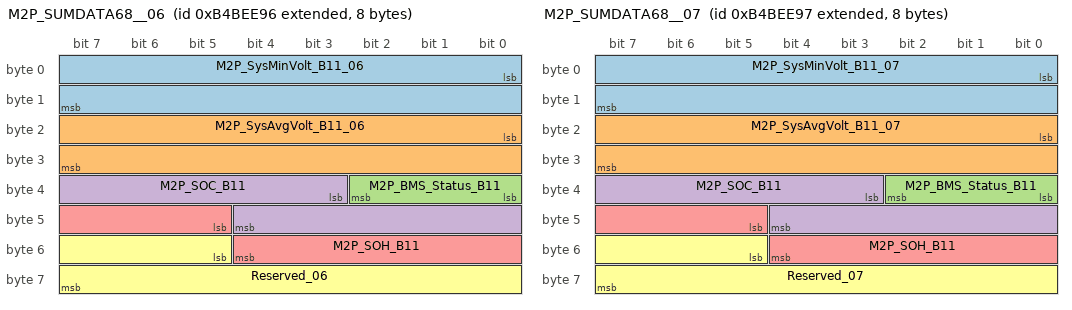
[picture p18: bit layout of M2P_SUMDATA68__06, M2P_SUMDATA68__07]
BO_ 2337009302 M2P_SUMDATA68__06: 8 MBMU
 SG_ M2P_SysMinVolt_B11_06 : 0|16@1+ (1,0) [0|65535] "mv"  PC
 SG_ M2P_SysAvgVolt_B11_06 : 16|16@1+ (1,0) [0|65535] "mv"  PC
 SG_ M2P_BMS_Status_B11 : 32|3@1+ (1,0) [0|7] ""  PC
 SG_ M2P_SOC_B11 : 35|10@1+ (0.1,0) [0|102.3] "%"  PC
 SG_ M2P_SOH_B11 : 45|8@1+ (1,0) [0|255] "%"  PC
 SG_ Reserved_06 : 53|11@1+ (1,0) [0|2047] ""  PC

BO_ 2337009303 M2P_SUMDATA68__07: 8 MBMU
 SG_ M2P_SysMinVolt_B11_07 : 0|16@1+ (1,0) [0|65535] "mv"  PC
 SG_ M2P_SysAvgVolt_B11_07 : 16|16@1+ (1,0) [0|65535] "mv"  PC
 SG_ M2P_BMS_Status_B11 : 32|3@1+ (1,0) [0|7] ""  PC
 SG_ M2P_SOC_B11 : 35|10@1+ (0.1,0) [0|102.3] "%"  PC
 SG_ M2P_SOH_B11 : 45|8@1+ (1,0) [0|255] "%"  PC
 SG_ Reserved_07 : 53|11@1+ (1,0) [0|2047] ""  PC

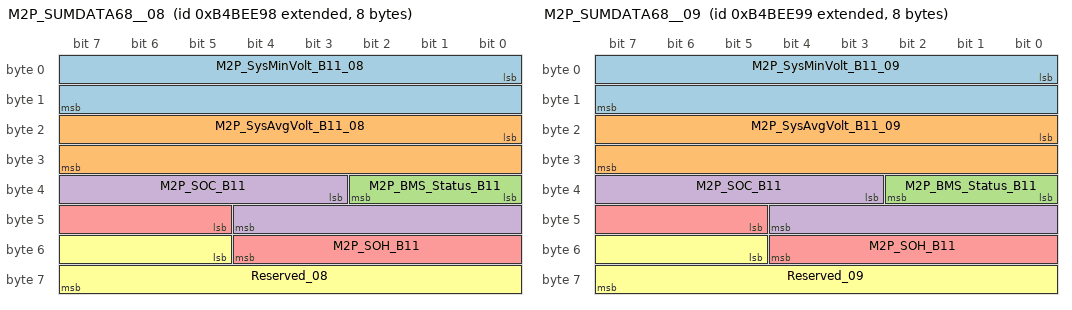
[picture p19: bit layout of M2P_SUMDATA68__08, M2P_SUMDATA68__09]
BO_ 2337009304 M2P_SUMDATA68__08: 8 MBMU
 SG_ M2P_SysMinVolt_B11_08 : 0|16@1+ (1,0) [0|65535] "mv"  PC
 SG_ M2P_SysAvgVolt_B11_08 : 16|16@1+ (1,0) [0|65535] "mv"  PC
 SG_ M2P_BMS_Status_B11 : 32|3@1+ (1,0) [0|7] ""  PC
 SG_ M2P_SOC_B11 : 35|10@1+ (0.1,0) [0|102.3] "%"  PC
 SG_ M2P_SOH_B11 : 45|8@1+ (1,0) [0|255] "%"  PC
 SG_ Reserved_08 : 53|11@1+ (1,0) [0|2047] ""  PC

BO_ 2337009305 M2P_SUMDATA68__09: 8 MBMU
 SG_ M2P_SysMinVolt_B11_09 : 0|16@1+ (1,0) [0|65535] "mv"  PC
 SG_ M2P_SysAvgVolt_B11_09 : 16|16@1+ (1,0) [0|65535] "mv"  PC
 SG_ M2P_BMS_Status_B11 : 32|3@1+ (1,0) [0|7] ""  PC
 SG_ M2P_SOC_B11 : 35|10@1+ (0.1,0) [0|102.3] "%"  PC
 SG_ M2P_SOH_B11 : 45|8@1+ (1,0) [0|255] "%"  PC
 SG_ Reserved_09 : 53|11@1+ (1,0) [0|2047] ""  PC

BO_ 2337009306 M2P_SUMDATA68__10: 8 MBMU
 SG_ M2P_SysMinVolt_B11_10 : 0|16@1+ (1,0) [0|65535] "mv"  PC
 SG_ M2P_SysAvgVolt_B11_10 : 16|16@1+ (1,0) [0|65535] "mv"  PC
 SG_ M2P_BMS_Status_B11 : 32|3@1+ (1,0) [0|7] ""  PC
 SG_ M2P_SOC_B11 : 35|10@1+ (0.1,0) [0|102.3] "%"  PC
 SG_ M2P_SOH_B11 : 45|8@1+ (1,0) [0|255] "%"  PC
 SG_ Reserved_10 : 53|11@1+ (1,0) [0|2047] ""  PC

BO_ 2337009307 M2P_SUMDATA68__11: 8 MBMU
 SG_ M2P_SysMinVolt_B11_11 : 0|16@1+ (1,0) [0|65535] "mv"  PC
 SG_ M2P_SysAvgVolt_B11_11 : 16|16@1+ (1,0) [0|65535] "mv"  PC
 SG_ M2P_BMS_Status_B11 : 32|3@1+ (1,0) [0|7] ""  PC
 SG_ M2P_SOC_B11 : 35|10@1+ (0.1,0) [0|102.3] "%"  PC
 SG_ M2P_SOH_B11 : 45|8@1+ (1,0) [0|255] "%"  PC
 SG_ Reserved_11 : 53|11@1+ (1,0) [0|2047] ""  PC

BO_ 2337009308 M2P_SUMDATA68__12: 8 MBMU
 SG_ M2P_SysMinVolt_B11_12 : 0|16@1+ (1,0) [0|65535] "mv"  PC
 SG_ M2P_SysAvgVolt_B11_12 : 16|16@1+ (1,0) [0|65535] "mv"  PC
 SG_ M2P_BMS_Status_B11 : 32|3@1+ (1,0) [0|7] ""  PC
 SG_ M2P_SOC_B11 : 35|10@1+ (0.1,0) [0|102.3] "%"  PC
 SG_ M2P_SOH_B11 : 45|8@1+ (1,0) [0|255] "%"  PC
 SG_ Reserved_12 : 53|11@1+ (1,0) [0|2047] ""  PC

BO_ 2337009309 M2P_SUMDATA68__13: 8 MBMU
 SG_ M2P_SysMinVolt_B11_13 : 0|16@1+ (1,0) [0|65535] "mv"  PC
 SG_ M2P_SysAvgVolt_B11_13 : 16|16@1+ (1,0) [0|65535] "mv"  PC
 SG_ M2P_BMS_Status_B11 : 32|3@1+ (1,0) [0|7] ""  PC
 SG_ M2P_SOC_B11 : 35|10@1+ (0.1,0) [0|102.3] "%"  PC
 SG_ M2P_SOH_B11 : 45|8@1+ (1,0) [0|255] "%"  PC
 SG_ Reserved_13 : 53|11@1+ (1,0) [0|2047] ""  PC

BO_ 2337009310 M2P_SUMDATA68__14: 8 MBMU
 SG_ M2P_SysMinVolt_B11_14 : 0|16@1+ (1,0) [0|65535] "mv"  PC
 SG_ M2P_SysAvgVolt_B11_14 : 16|16@1+ (1,0) [0|65535] "mv"  PC
 SG_ M2P_BMS_Status_B11 : 32|3@1+ (1,0) [0|7] ""  PC
 SG_ M2P_SOC_B11 : 35|10@1+ (0.1,0) [0|102.3] "%"  PC
 SG_ M2P_SOH_B11 : 45|8@1+ (1,0) [0|255] "%"  PC
 SG_ Reserved_14 : 53|11@1+ (1,0) [0|2047] ""  PC

BO_ 2337009311 M2P_SUMDATA68__15: 8 MBMU
 SG_ M2P_SysMinVolt_B11_15 : 0|16@1+ (1,0) [0|65535] "mv"  PC
 SG_ M2P_SysAvgVolt_B11_15 : 16|16@1+ (1,0) [0|65535] "mv"  PC
 SG_ M2P_BMS_Status_B11 : 32|3@1+ (1,0) [0|7] ""  PC
 SG_ M2P_SOC_B11 : 35|10@1+ (0.1,0) [0|102.3] "%"  PC
 SG_ M2P_SOH_B11 : 45|8@1+ (1,0) [0|255] "%"  PC
 SG_ Reserved_15 : 53|11@1+ (1,0) [0|2047] ""  PC

BO_ 2337009312 M2P_SUMDATA68__16: 8 MBMU
 SG_ M2P_SysMinVolt_B11_16 : 0|16@1+ (1,0) [0|65535] "mv"  PC
 SG_ M2P_SysAvgVolt_B11_16 : 16|16@1+ (1,0) [0|65535] "mv"  PC
 SG_ M2P_BMS_Status_B11 : 32|3@1+ (1,0) [0|7] ""  PC
 SG_ M2P_SOC_B11 : 35|10@1+ (0.1,0) [0|102.3] "%"  PC
 SG_ M2P_SOH_B11 : 45|8@1+ (1,0) [0|255] "%"  PC
 SG_ Reserved_16 : 53|11@1+ (1,0) [0|2047] ""  PC

BO_ 2337009313 M2P_SUMDATA68__17: 8 MBMU
 SG_ M2P_SysMinVolt_B11_17 : 0|16@1+ (1,0) [0|65535] "mv"  PC
 SG_ M2P_SysAvgVolt_B11_17 : 16|16@1+ (1,0) [0|65535] "mv"  PC
 SG_ M2P_BMS_Status_B11 : 32|3@1+ (1,0) [0|7] ""  PC
 SG_ M2P_SOC_B11 : 35|10@1+ (0.1,0) [0|102.3] "%"  PC
 SG_ M2P_SOH_B11 : 45|8@1+ (1,0) [0|255] "%"  PC
 SG_ Reserved_17 : 53|11@1+ (1,0) [0|2047] ""  PC

BO_ 2337009314 M2P_SUMDATA68__18: 8 MBMU
 SG_ M2P_SysMinVolt_B11_18 : 0|16@1+ (1,0) [0|65535] "mv"  PC
 SG_ M2P_SysAvgVolt_B11_18 : 16|16@1+ (1,0) [0|65535] "mv"  PC
 SG_ M2P_BMS_Status_B11 : 32|3@1+ (1,0) [0|7] ""  PC
 SG_ M2P_SOC_B11 : 35|10@1+ (0.1,0) [0|102.3] "%"  PC
 SG_ M2P_SOH_B11 : 45|8@1+ (1,0) [0|255] "%"  PC
 SG_ Reserved_18 : 53|11@1+ (1,0) [0|2047] ""  PC

BO_ 2337009315 M2P_SUMDATA68__19: 8 MBMU
 SG_ M2P_SysMinVolt_B11_19 : 0|16@1+ (1,0) [0|65535] "mv"  PC
 SG_ M2P_SysAvgVolt_B11_19 : 16|16@1+ (1,0) [0|65535] "mv"  PC
 SG_ M2P_BMS_Status_B11 : 32|3@1+ (1,0) [0|7] ""  PC
 SG_ M2P_SOC_B11 : 35|10@1+ (0.1,0) [0|102.3] "%"  PC
 SG_ M2P_SOH_B11 : 45|8@1+ (1,0) [0|255] "%"  PC
 SG_ Reserved_19 : 53|11@1+ (1,0) [0|2047] ""  PC

BO_ 2337009316 M2P_SUMDATA68__20: 8 MBMU
 SG_ M2P_SysMinVolt_B11_20 : 0|16@1+ (1,0) [0|65535] "mv"  PC
 SG_ M2P_SysAvgVolt_B11_20 : 16|16@1+ (1,0) [0|65535] "mv"  PC
 SG_ M2P_BMS_Status_B11 : 32|3@1+ (1,0) [0|7] ""  PC
 SG_ M2P_SOC_B11 : 35|10@1+ (0.1,0) [0|102.3] "%"  PC
 SG_ M2P_SOH_B11 : 45|8@1+ (1,0) [0|255] "%"  PC
 SG_ Reserved_20 : 53|11@1+ (1,0) [0|2047] ""  PC

BO_ 2337009317 M2P_SUMDATA68__21: 8 MBMU
 SG_ M2P_SysMinVolt_B11_21 : 0|16@1+ (1,0) [0|65535] "mv"  PC
 SG_ M2P_SysAvgVolt_B11_21 : 16|16@1+ (1,0) [0|65535] "mv"  PC
 SG_ M2P_BMS_Status_B11 : 32|3@1+ (1,0) [0|7] ""  PC
 SG_ M2P_SOC_B11 : 35|10@1+ (0.1,0) [0|102.3] "%"  PC
 SG_ M2P_SOH_B11 : 45|8@1+ (1,0) [0|255] "%"  PC
 SG_ Reserved_21 : 53|11@1+ (1,0) [0|2047] ""  PC

BO_ 2337009318 M2P_SUMDATA68__22: 8 MBMU
 SG_ M2P_SysMinVolt_B11_22 : 0|16@1+ (1,0) [0|65535] "mv"  PC
 SG_ M2P_SysAvgVolt_B11_22 : 16|16@1+ (1,0) [0|65535] "mv"  PC
 SG_ M2P_BMS_Status_B11 : 32|3@1+ (1,0) [0|7] ""  PC
 SG_ M2P_SOC_B11 : 35|10@1+ (0.1,0) [0|102.3] "%"  PC
 SG_ M2P_SOH_B11 : 45|8@1+ (1,0) [0|255] "%"  PC
 SG_ Reserved_22 : 53|11@1+ (1,0) [0|2047] ""  PC

BO_ 2337009319 M2P_SUMDATA68__23: 8 MBMU
 SG_ M2P_SysMinVolt_B11_23 : 0|16@1+ (1,0) [0|65535] "mv"  PC
 SG_ M2P_SysAvgVolt_B11_23 : 16|16@1+ (1,0) [0|65535] "mv"  PC
 SG_ M2P_BMS_Status_B11 : 32|3@1+ (1,0) [0|7] ""  PC
 SG_ M2P_SOC_B11 : 35|10@1+ (0.1,0) [0|102.3] "%"  PC
 SG_ M2P_SOH_B11 : 45|8@1+ (1,0) [0|255] "%"  PC
 SG_ Reserved_23 : 53|11@1+ (1,0) [0|2047] ""  PC

BO_ 2337009320 M2P_SUMDATA68__24: 8 MBMU
 SG_ M2P_SysMinVolt_B11_24 : 0|16@1+ (1,0) [0|65535] "mv"  PC
 SG_ M2P_SysAvgVolt_B11_24 : 16|16@1+ (1,0) [0|65535] "mv"  PC
 SG_ M2P_BMS_Status_B11 : 32|3@1+ (1,0) [0|7] ""  PC
 SG_ M2P_SOC_B11 : 35|10@1+ (0.1,0) [0|102.3] "%"  PC
 SG_ M2P_SOH_B11 : 45|8@1+ (1,0) [0|255] "%"  PC
 SG_ Reserved_24 : 53|11@1+ (1,0) [0|2047] ""  PC

BO_ 2337009321 M2P_SUMDATA68__25: 8 MBMU
 SG_ M2P_SysMinVolt_B11_25 : 0|16@1+ (1,0) [0|65535] "mv"  PC
 SG_ M2P_SysAvgVolt_B11_25 : 16|16@1+ (1,0) [0|65535] "mv"  PC
 SG_ M2P_BMS_Status_B11 : 32|3@1+ (1,0) [0|7] ""  PC
 SG_ M2P_SOC_B11 : 35|10@1+ (0.1,0) [0|102.3] "%"  PC
 SG_ M2P_SOH_B11 : 45|8@1+ (1,0) [0|255] "%"  PC
 SG_ Reserved_25 : 53|11@1+ (1,0) [0|2047] ""  PC

BO_ 2337009322 M2P_SUMDATA68__26: 8 MBMU
 SG_ M2P_SysMinVolt_B11_26 : 0|16@1+ (1,0) [0|65535] "mv"  PC
 SG_ M2P_SysAvgVolt_B11_26 : 16|16@1+ (1,0) [0|65535] "mv"  PC
 SG_ M2P_BMS_Status_B11 : 32|3@1+ (1,0) [0|7] ""  PC
 SG_ M2P_SOC_B11 : 35|10@1+ (0.1,0) [0|102.3] "%"  PC
 SG_ M2P_SOH_B11 : 45|8@1+ (1,0) [0|255] "%"  PC
 SG_ Reserved_26 : 53|11@1+ (1,0) [0|2047] ""  PC

BO_ 2337009323 M2P_SUMDATA68__27: 8 MBMU
 SG_ M2P_SysMinVolt_B11_27 : 0|16@1+ (1,0) [0|65535] "mv"  PC
 SG_ M2P_SysAvgVolt_B11_27 : 16|16@1+ (1,0) [0|65535] "mv"  PC
 SG_ M2P_BMS_Status_B11 : 32|3@1+ (1,0) [0|7] ""  PC
 SG_ M2P_SOC_B11 : 35|10@1+ (0.1,0) [0|102.3] "%"  PC
 SG_ M2P_SOH_B11 : 45|8@1+ (1,0) [0|255] "%"  PC
 SG_ Reserved_27 : 53|11@1+ (1,0) [0|2047] ""  PC

BO_ 2337009324 M2P_SUMDATA68__28: 8 MBMU
 SG_ M2P_SysMinVolt_B11_28 : 0|16@1+ (1,0) [0|65535] "mv"  PC
 SG_ M2P_SysAvgVolt_B11_28 : 16|16@1+ (1,0) [0|65535] "mv"  PC
 SG_ M2P_BMS_Status_B11 : 32|3@1+ (1,0) [0|7] ""  PC
 SG_ M2P_SOC_B11 : 35|10@1+ (0.1,0) [0|102.3] "%"  PC
 SG_ M2P_SOH_B11 : 45|8@1+ (1,0) [0|255] "%"  PC
 SG_ Reserved_28 : 53|11@1+ (1,0) [0|2047] ""  PC

BO_ 2337009325 M2P_SUMDATA68__29: 8 MBMU
 SG_ M2P_SysMinVolt_B11_29 : 0|16@1+ (1,0) [0|65535] "mv"  PC
 SG_ M2P_SysAvgVolt_B11_29 : 16|16@1+ (1,0) [0|65535] "mv"  PC
 SG_ M2P_BMS_Status_B11 : 32|3@1+ (1,0) [0|7] ""  PC
 SG_ M2P_SOC_B11 : 35|10@1+ (0.1,0) [0|102.3] "%"  PC
 SG_ M2P_SOH_B11 : 45|8@1+ (1,0) [0|255] "%"  PC
 SG_ Reserved_29 : 53|11@1+ (1,0) [0|2047] ""  PC

BO_ 2337009326 M2P_SUMDATA68__30: 8 MBMU
 SG_ M2P_SysMinVolt_B11_30 : 0|16@1+ (1,0) [0|65535] "mv"  PC
 SG_ M2P_SysAvgVolt_B11_30 : 16|16@1+ (1,0) [0|65535] "mv"  PC
 SG_ M2P_BMS_Status_B11 : 32|3@1+ (1,0) [0|7] ""  PC
 SG_ M2P_SOC_B11 : 35|10@1+ (0.1,0) [0|102.3] "%"  PC
 SG_ M2P_SOH_B11 : 45|8@1+ (1,0) [0|255] "%"  PC
 SG_ Reserved_30 : 53|11@1+ (1,0) [0|2047] ""  PC

BO_ 2337009327 M2P_SUMDATA68__31: 8 MBMU
 SG_ M2P_SysMinVolt_B11_31 : 0|16@1+ (1,0) [0|65535] "mv"  PC
 SG_ M2P_SysAvgVolt_B11_31 : 16|16@1+ (1,0) [0|65535] "mv"  PC
 SG_ M2P_BMS_Status_B11 : 32|3@1+ (1,0) [0|7] ""  PC
 SG_ M2P_SOC_B11 : 35|10@1+ (0.1,0) [0|102.3] "%"  PC
 SG_ M2P_SOH_B11 : 45|8@1+ (1,0) [0|255] "%"  PC
 SG_ Reserved_31 : 53|11@1+ (1,0) [0|2047] ""  PC

BO_ 2337074833 M2P_SUMDATA69__01: 8 MBMU
 SG_ M2P_SOE_Charge_B11 : 0|10@1+ (0.1,0) [0|102.3] "%"  PC
 SG_ M2P_SOE_Discharge_B11 : 10|10@1+ (0.1,0) [0|102.3] "%"  PC
 SG_ Reserved_01 : 20|44@1+ (1,0) [0|17592186044415] ""  PC

CM_ SG_ 2336485024 M2P_Measure_Vol_B10_16 "汇流排10所有高压在线电柜外侧电压平均值    ";
CM_ SG_ 2336485024 M2P_Current_B10_16 "汇流排10所有电柜电流累加和";
CM_ SG_ 2336485024 M2P_PermitMaxCharge_I_B10_16 "汇流排10最大允许充电电流";
CM_ SG_ 2336485024 M2P_PermitMaxDisCharge_I_B10_16 "汇流排10最大允许放电电流";
CM_ SG_ 2336485025 M2P_Measure_Vol_B10_17 "汇流排10所有高压在线电柜外侧电压平均值    ";
CM_ SG_ 2336485025 M2P_Current_B10_17 "汇流排10所有电柜电流累加和";
CM_ SG_ 2336485025 M2P_PermitMaxCharge_I_B10_17 "汇流排10最大允许充电电流";
CM_ SG_ 2336485025 M2P_PermitMaxDisCharge_I_B10_17 "汇流排10最大允许放电电流";
CM_ SG_ 2336485026 M2P_Measure_Vol_B10_18 "汇流排10所有高压在线电柜外侧电压平均值    ";
CM_ SG_ 2336485026 M2P_Current_B10_18 "汇流排10所有电柜电流累加和";
CM_ SG_ 2336485026 M2P_PermitMaxCharge_I_B10_18 "汇流排10最大允许充电电流";
CM_ SG_ 2336485026 M2P_PermitMaxDisCharge_I_B10_18 "汇流排10最大允许放电电流";
CM_ SG_ 2336485027 M2P_Measure_Vol_B10_19 "汇流排10所有高压在线电柜外侧电压平均值    ";
CM_ SG_ 2336485027 M2P_Current_B10_19 "汇流排10所有电柜电流累加和";
CM_ SG_ 2336485027 M2P_PermitMaxCharge_I_B10_19 "汇流排10最大允许充电电流";
CM_ SG_ 2336485027 M2P_PermitMaxDisCharge_I_B10_19 "汇流排10最大允许放电电流";
CM_ SG_ 2336485028 M2P_Measure_Vol_B10_20 "汇流排10所有高压在线电柜外侧电压平均值    ";
CM_ SG_ 2336485028 M2P_Current_B10_20 "汇流排10所有电柜电流累加和";
CM_ SG_ 2336485028 M2P_PermitMaxCharge_I_B10_20 "汇流排10最大允许充电电流";
CM_ SG_ 2336485028 M2P_PermitMaxDisCharge_I_B10_20 "汇流排10最大允许放电电流";
CM_ SG_ 2336485029 M2P_Measure_Vol_B10_21 "汇流排10所有高压在线电柜外侧电压平均值    ";
CM_ SG_ 2336485029 M2P_Current_B10_21 "汇流排10所有电柜电流累加和";
CM_ SG_ 2336485029 M2P_PermitMaxCharge_I_B10_21 "汇流排10最大允许充电电流";
CM_ SG_ 2336485029 M2P_PermitMaxDisCharge_I_B10_21 "汇流排10最大允许放电电流";
CM_ SG_ 2336485030 M2P_Measure_Vol_B10_22 "汇流排10所有高压在线电柜外侧电压平均值    ";
CM_ SG_ 2336485030 M2P_Current_B10_22 "汇流排10所有电柜电流累加和";
CM_ SG_ 2336485030 M2P_PermitMaxCharge_I_B10_22 "汇流排10最大允许充电电流";
CM_ SG_ 2336485030 M2P_PermitMaxDisCharge_I_B10_22 "汇流排10最大允许放电电流";
CM_ SG_ 2336485031 M2P_Measure_Vol_B10_23 "汇流排10所有高压在线电柜外侧电压平均值    ";
CM_ SG_ 2336485031 M2P_Current_B10_23 "汇流排10所有电柜电流累加和";
CM_ SG_ 2336485031 M2P_PermitMaxCharge_I_B10_23 "汇流排10最大允许充电电流";
CM_ SG_ 2336485031 M2P_PermitMaxDisCharge_I_B10_23 "汇流排10最大允许放电电流";
CM_ SG_ 2336485032 M2P_Measure_Vol_B10_24 "汇流排10所有高压在线电柜外侧电压平均值    ";
CM_ SG_ 2336485032 M2P_Current_B10_24 "汇流排10所有电柜电流累加和";
CM_ SG_ 2336485032 M2P_PermitMaxCharge_I_B10_24 "汇流排10最大允许充电电流";
CM_ SG_ 2336485032 M2P_PermitMaxDisCharge_I_B10_24 "汇流排10最大允许放电电流";
CM_ SG_ 2336485033 M2P_Measure_Vol_B10_25 "汇流排10所有高压在线电柜外侧电压平均值    ";
CM_ SG_ 2336485033 M2P_Current_B10_25 "汇流排10所有电柜电流累加和";
CM_ SG_ 2336485033 M2P_PermitMaxCharge_I_B10_25 "汇流排10最大允许充电电流";
CM_ SG_ 2336485033 M2P_PermitMaxDisCharge_I_B10_25 "汇流排10最大允许放电电流";
CM_ SG_ 2336485034 M2P_Measure_Vol_B10_26 "汇流排10所有高压在线电柜外侧电压平均值    ";
CM_ SG_ 2336485034 M2P_Current_B10_26 "汇流排10所有电柜电流累加和";
CM_ SG_ 2336485034 M2P_PermitMaxCharge_I_B10_26 "汇流排10最大允许充电电流";
CM_ SG_ 2336485034 M2P_PermitMaxDisCharge_I_B10_26 "汇流排10最大允许放电电流";
CM_ SG_ 2336485035 M2P_Measure_Vol_B10_27 "汇流排10所有高压在线电柜外侧电压平均值    ";
CM_ SG_ 2336485035 M2P_Current_B10_27 "汇流排10所有电柜电流累加和";
CM_ SG_ 2336485035 M2P_PermitMaxCharge_I_B10_27 "汇流排10最大允许充电电流";
CM_ SG_ 2336485035 M2P_PermitMaxDisCharge_I_B10_27 "汇流排10最大允许放电电流";
CM_ SG_ 2336485036 M2P_Measure_Vol_B10_28 "汇流排10所有高压在线电柜外侧电压平均值    ";
CM_ SG_ 2336485036 M2P_Current_B10_28 "汇流排10所有电柜电流累加和";
CM_ SG_ 2336485036 M2P_PermitMaxCharge_I_B10_28 "汇流排10最大允许充电电流";
CM_ SG_ 2336485036 M2P_PermitMaxDisCharge_I_B10_28 "汇流排10最大允许放电电流";
CM_ SG_ 2336485037 M2P_Measure_Vol_B10_29 "汇流排10所有高压在线电柜外侧电压平均值    ";
CM_ SG_ 2336485037 M2P_Current_B10_29 "汇流排10所有电柜电流累加和";
CM_ SG_ 2336485037 M2P_PermitMaxCharge_I_B10_29 "汇流排10最大允许充电电流";
CM_ SG_ 2336485037 M2P_PermitMaxDisCharge_I_B10_29 "汇流排10最大允许放电电流";
CM_ SG_ 2336485038 M2P_Measure_Vol_B10_30 "汇流排10所有高压在线电柜外侧电压平均值    ";
CM_ SG_ 2336485038 M2P_Current_B10_30 "汇流排10所有电柜电流累加和";
CM_ SG_ 2336485038 M2P_PermitMaxCharge_I_B10_30 "汇流排10最大允许充电电流";
CM_ SG_ 2336485038 M2P_PermitMaxDisCharge_I_B10_30 "汇流排10最大允许放电电流";
CM_ SG_ 2336485039 M2P_Measure_Vol_B10_31 "汇流排10所有高压在线电柜外侧电压平均值    ";
CM_ SG_ 2336485039 M2P_Current_B10_31 "汇流排10所有电柜电流累加和";
CM_ SG_ 2336485039 M2P_PermitMaxCharge_I_B10_31 "汇流排10最大允许充电电流";
CM_ SG_ 2336485039 M2P_PermitMaxDisCharge_I_B10_31 "汇流排10最大允许放电电流";
CM_ SG_ 2336550545 M2P_PermitMaxVolt_B10_01 "汇流排10最高允许充电电压 （配置量）";
CM_ SG_ 2336550545 M2P_PermitMinVolt_B10_01 "汇流排10最低允许放电电压 （配置量）";
CM_ SG_ 2336550545 M2P_PermitMaxPow_Chg_B10_01 "汇流排10最大允许充电功率";
CM_ SG_ 2336550545 M2P_PermitMaxPow_DisChg_B10_01 "汇流排10最大允许放电功率";
CM_ SG_ 2336550546 M2P_PermitMaxVolt_B10_02 "汇流排10最高允许充电电压 （配置量）";
CM_ SG_ 2336550546 M2P_PermitMinVolt_B10_02 "汇流排10最低允许放电电压 （配置量）";
CM_ SG_ 2336550546 M2P_PermitMaxPow_Chg_B10_02 "汇流排10最大允许充电功率";
CM_ SG_ 2336550546 M2P_PermitMaxPow_DisChg_B10_02 "汇流排10最大允许放电功率";
CM_ SG_ 2336550547 M2P_PermitMaxVolt_B10_03 "汇流排10最高允许充电电压 （配置量）";
CM_ SG_ 2336550547 M2P_PermitMinVolt_B10_03 "汇流排10最低允许放电电压 （配置量）";
CM_ SG_ 2336550547 M2P_PermitMaxPow_Chg_B10_03 "汇流排10最大允许充电功率";
CM_ SG_ 2336550547 M2P_PermitMaxPow_DisChg_B10_03 "汇流排10最大允许放电功率";
CM_ SG_ 2336550548 M2P_PermitMaxVolt_B10_04 "汇流排10最高允许充电电压 （配置量）";
CM_ SG_ 2336550548 M2P_PermitMinVolt_B10_04 "汇流排10最低允许放电电压 （配置量）";
CM_ SG_ 2336550548 M2P_PermitMaxPow_Chg_B10_04 "汇流排10最大允许充电功率";
CM_ SG_ 2336550548 M2P_PermitMaxPow_DisChg_B10_04 "汇流排10最大允许放电功率";
CM_ SG_ 2336550549 M2P_PermitMaxVolt_B10_05 "汇流排10最高允许充电电压 （配置量）";
CM_ SG_ 2336550549 M2P_PermitMinVolt_B10_05 "汇流排10最低允许放电电压 （配置量）";
CM_ SG_ 2336550549 M2P_PermitMaxPow_Chg_B10_05 "汇流排10最大允许充电功率";
CM_ SG_ 2336550549 M2P_PermitMaxPow_DisChg_B10_05 "汇流排10最大允许放电功率";
CM_ SG_ 2336550550 M2P_PermitMaxVolt_B10_06 "汇流排10最高允许充电电压 （配置量）";
CM_ SG_ 2336550550 M2P_PermitMinVolt_B10_06 "汇流排10最低允许放电电压 （配置量）";
CM_ SG_ 2336550550 M2P_PermitMaxPow_Chg_B10_06 "汇流排10最大允许充电功率";
CM_ SG_ 2336550550 M2P_PermitMaxPow_DisChg_B10_06 "汇流排10最大允许放电功率";
CM_ SG_ 2336550551 M2P_PermitMaxVolt_B10_07 "汇流排10最高允许充电电压 （配置量）";
CM_ SG_ 2336550551 M2P_PermitMinVolt_B10_07 "汇流排10最低允许放电电压 （配置量）";
CM_ SG_ 2336550551 M2P_PermitMaxPow_Chg_B10_07 "汇流排10最大允许充电功率";
CM_ SG_ 2336550551 M2P_PermitMaxPow_DisChg_B10_07 "汇流排10最大允许放电功率";
CM_ SG_ 2336550552 M2P_PermitMaxVolt_B10_08 "汇流排10最高允许充电电压 （配置量）";
CM_ SG_ 2336550552 M2P_PermitMinVolt_B10_08 "汇流排10最低允许放电电压 （配置量）";
CM_ SG_ 2336550552 M2P_PermitMaxPow_Chg_B10_08 "汇流排10最大允许充电功率";
CM_ SG_ 2336550552 M2P_PermitMaxPow_DisChg_B10_08 "汇流排10最大允许放电功率";
CM_ SG_ 2336550553 M2P_PermitMaxVolt_B10_09 "汇流排10最高允许充电电压 （配置量）";
CM_ SG_ 2336550553 M2P_PermitMinVolt_B10_09 "汇流排10最低允许放电电压 （配置量）";
CM_ SG_ 2336550553 M2P_PermitMaxPow_Chg_B10_09 "汇流排10最大允许充电功率";
CM_ SG_ 2336550553 M2P_PermitMaxPow_DisChg_B10_09 "汇流排10最大允许放电功率";
CM_ SG_ 2336550554 M2P_PermitMaxVolt_B10_10 "汇流排10最高允许充电电压 （配置量）";
CM_ SG_ 2336550554 M2P_PermitMinVolt_B10_10 "汇流排10最低允许放电电压 （配置量）";
CM_ SG_ 2336550554 M2P_PermitMaxPow_Chg_B10_10 "汇流排10最大允许充电功率";
CM_ SG_ 2336550554 M2P_PermitMaxPow_DisChg_B10_10 "汇流排10最大允许放电功率";
CM_ SG_ 2336550555 M2P_PermitMaxVolt_B10_11 "汇流排10最高允许充电电压 （配置量）";
CM_ SG_ 2336550555 M2P_PermitMinVolt_B10_11 "汇流排10最低允许放电电压 （配置量）";
CM_ SG_ 2336550555 M2P_PermitMaxPow_Chg_B10_11 "汇流排10最大允许充电功率";
CM_ SG_ 2336550555 M2P_PermitMaxPow_DisChg_B10_11 "汇流排10最大允许放电功率";
CM_ SG_ 2336550556 M2P_PermitMaxVolt_B10_12 "汇流排10最高允许充电电压 （配置量）";
CM_ SG_ 2336550556 M2P_PermitMinVolt_B10_12 "汇流排10最低允许放电电压 （配置量）";
CM_ SG_ 2336550556 M2P_PermitMaxPow_Chg_B10_12 "汇流排10最大允许充电功率";
CM_ SG_ 2336550556 M2P_PermitMaxPow_DisChg_B10_12 "汇流排10最大允许放电功率";
CM_ SG_ 2336550557 M2P_PermitMaxVolt_B10_13 "汇流排10最高允许充电电压 （配置量）";
CM_ SG_ 2336550557 M2P_PermitMinVolt_B10_13 "汇流排10最低允许放电电压 （配置量）";
CM_ SG_ 2336550557 M2P_PermitMaxPow_Chg_B10_13 "汇流排10最大允许充电功率";
CM_ SG_ 2336550557 M2P_PermitMaxPow_DisChg_B10_13 "汇流排10最大允许放电功率";
CM_ SG_ 2336550558 M2P_PermitMaxVolt_B10_14 "汇流排10最高允许充电电压 （配置量）";
CM_ SG_ 2336550558 M2P_PermitMinVolt_B10_14 "汇流排10最低允许放电电压 （配置量）";
CM_ SG_ 2336550558 M2P_PermitMaxPow_Chg_B10_14 "汇流排10最大允许充电功率";
CM_ SG_ 2336550558 M2P_PermitMaxPow_DisChg_B10_14 "汇流排10最大允许放电功率";
CM_ SG_ 2336550559 M2P_PermitMaxVolt_B10_15 "汇流排10最高允许充电电压 （配置量）";
CM_ SG_ 2336550559 M2P_PermitMinVolt_B10_15 "汇流排10最低允许放电电压 （配置量）";
CM_ SG_ 2336550559 M2P_PermitMaxPow_Chg_B10_15 "汇流排10最大允许充电功率";
CM_ SG_ 2336550559 M2P_PermitMaxPow_DisChg_B10_15 "汇流排10最大允许放电功率";
CM_ SG_ 2336550560 M2P_PermitMaxVolt_B10_16 "汇流排10最高允许充电电压 （配置量）";
CM_ SG_ 2336550560 M2P_PermitMinVolt_B10_16 "汇流排10最低允许放电电压 （配置量）";
CM_ SG_ 2336550560 M2P_PermitMaxPow_Chg_B10_16 "汇流排10最大允许充电功率";
CM_ SG_ 2336550560 M2P_PermitMaxPow_DisChg_B10_16 "汇流排10最大允许放电功率";
CM_ SG_ 2336550561 M2P_PermitMaxVolt_B10_17 "汇流排10最高允许充电电压 （配置量）";
CM_ SG_ 2336550561 M2P_PermitMinVolt_B10_17 "汇流排10最低允许放电电压 （配置量）";
CM_ SG_ 2336550561 M2P_PermitMaxPow_Chg_B10_17 "汇流排10最大允许充电功率";
CM_ SG_ 2336550561 M2P_PermitMaxPow_DisChg_B10_17 "汇流排10最大允许放电功率";
CM_ SG_ 2336550562 M2P_PermitMaxVolt_B10_18 "汇流排10最高允许充电电压 （配置量）";
CM_ SG_ 2336550562 M2P_PermitMinVolt_B10_18 "汇流排10最低允许放电电压 （配置量）";
CM_ SG_ 2336550562 M2P_PermitMaxPow_Chg_B10_18 "汇流排10最大允许充电功率";
CM_ SG_ 2336550562 M2P_PermitMaxPow_DisChg_B10_18 "汇流排10最大允许放电功率";
CM_ SG_ 2336550563 M2P_PermitMaxVolt_B10_19 "汇流排10最高允许充电电压 （配置量）";
CM_ SG_ 2336550563 M2P_PermitMinVolt_B10_19 "汇流排10最低允许放电电压 （配置量）";
CM_ SG_ 2336550563 M2P_PermitMaxPow_Chg_B10_19 "汇流排10最大允许充电功率";
CM_ SG_ 2336550563 M2P_PermitMaxPow_DisChg_B10_19 "汇流排10最大允许放电功率";
CM_ SG_ 2336550564 M2P_PermitMaxVolt_B10_20 "汇流排10最高允许充电电压 （配置量）";
CM_ SG_ 2336550564 M2P_PermitMinVolt_B10_20 "汇流排10最低允许放电电压 （配置量）";
CM_ SG_ 2336550564 M2P_PermitMaxPow_Chg_B10_20 "汇流排10最大允许充电功率";
CM_ SG_ 2336550564 M2P_PermitMaxPow_DisChg_B10_20 "汇流排10最大允许放电功率";
CM_ SG_ 2336550565 M2P_PermitMaxVolt_B10_21 "汇流排10最高允许充电电压 （配置量）";
CM_ SG_ 2336550565 M2P_PermitMinVolt_B10_21 "汇流排10最低允许放电电压 （配置量）";
CM_ SG_ 2336550565 M2P_PermitMaxPow_Chg_B10_21 "汇流排10最大允许充电功率";
CM_ SG_ 2336550565 M2P_PermitMaxPow_DisChg_B10_21 "汇流排10最大允许放电功率";
CM_ SG_ 2336550566 M2P_PermitMaxVolt_B10_22 "汇流排10最高允许充电电压 （配置量）";
CM_ SG_ 2336550566 M2P_PermitMinVolt_B10_22 "汇流排10最低允许放电电压 （配置量）";
CM_ SG_ 2336550566 M2P_PermitMaxPow_Chg_B10_22 "汇流排10最大允许充电功率";
CM_ SG_ 2336550566 M2P_PermitMaxPow_DisChg_B10_22 "汇流排10最大允许放电功率";
CM_ SG_ 2336550567 M2P_PermitMaxVolt_B10_23 "汇流排10最高允许充电电压 （配置量）";
CM_ SG_ 2336550567 M2P_PermitMinVolt_B10_23 "汇流排10最低允许放电电压 （配置量）";
CM_ SG_ 2336550567 M2P_PermitMaxPow_Chg_B10_23 "汇流排10最大允许充电功率";
CM_ SG_ 2336550567 M2P_PermitMaxPow_DisChg_B10_23 "汇流排10最大允许放电功率";
CM_ SG_ 2336550568 M2P_PermitMaxVolt_B10_24 "汇流排10最高允许充电电压 （配置量）";
CM_ SG_ 2336550568 M2P_PermitMinVolt_B10_24 "汇流排10最低允许放电电压 （配置量）";
CM_ SG_ 2336550568 M2P_PermitMaxPow_Chg_B10_24 "汇流排10最大允许充电功率";
CM_ SG_ 2336550568 M2P_PermitMaxPow_DisChg_B10_24 "汇流排10最大允许放电功率";
CM_ SG_ 2336550569 M2P_PermitMaxVolt_B10_25 "汇流排10最高允许充电电压 （配置量）";
CM_ SG_ 2336550569 M2P_PermitMinVolt_B10_25 "汇流排10最低允许放电电压 （配置量）";
CM_ SG_ 2336550569 M2P_PermitMaxPow_Chg_B10_25 "汇流排10最大允许充电功率";
CM_ SG_ 2336550569 M2P_PermitMaxPow_DisChg_B10_25 "汇流排10最大允许放电功率";
CM_ SG_ 2336550570 M2P_PermitMaxVolt_B10_26 "汇流排10最高允许充电电压 （配置量）";
CM_ SG_ 2336550570 M2P_PermitMinVolt_B10_26 "汇流排10最低允许放电电压 （配置量）";
CM_ SG_ 2336550570 M2P_PermitMaxPow_Chg_B10_26 "汇流排10最大允许充电功率";
CM_ SG_ 2336550570 M2P_PermitMaxPow_DisChg_B10_26 "汇流排10最大允许放电功率";
CM_ SG_ 2336550571 M2P_PermitMaxVolt_B10_27 "汇流排10最高允许充电电压 （配置量）";
CM_ SG_ 2336550571 M2P_PermitMinVolt_B10_27 "汇流排10最低允许放电电压 （配置量）";
CM_ SG_ 2336550571 M2P_PermitMaxPow_Chg_B10_27 "汇流排10最大允许充电功率";
CM_ SG_ 2336550571 M2P_PermitMaxPow_DisChg_B10_27 "汇流排10最大允许放电功率";
CM_ SG_ 2336550572 M2P_PermitMaxVolt_B10_28 "汇流排10最高允许充电电压 （配置量）";
CM_ SG_ 2336550572 M2P_PermitMinVolt_B10_28 "汇流排10最低允许放电电压 （配置量）";
CM_ SG_ 2336550572 M2P_PermitMaxPow_Chg_B10_28 "汇流排10最大允许充电功率";
CM_ SG_ 2336550572 M2P_PermitMaxPow_DisChg_B10_28 "汇流排10最大允许放电功率";
CM_ SG_ 2336550573 M2P_PermitMaxVolt_B10_29 "汇流排10最高允许充电电压 （配置量）";
CM_ SG_ 2336550573 M2P_PermitMinVolt_B10_29 "汇流排10最低允许放电电压 （配置量）";
CM_ SG_ 2336550573 M2P_PermitMaxPow_Chg_B10_29 "汇流排10最大允许充电功率";
CM_ SG_ 2336550573 M2P_PermitMaxPow_DisChg_B10_29 "汇流排10最大允许放电功率";
CM_ SG_ 2336550574 M2P_PermitMaxVolt_B10_30 "汇流排10最高允许充电电压 （配置量）";
CM_ SG_ 2336550574 M2P_PermitMinVolt_B10_30 "汇流排10最低允许放电电压 （配置量）";
CM_ SG_ 2336550574 M2P_PermitMaxPow_Chg_B10_30 "汇流排10最大允许充电功率";
CM_ SG_ 2336550574 M2P_PermitMaxPow_DisChg_B10_30 "汇流排10最大允许放电功率";
CM_ SG_ 2336550575 M2P_PermitMaxVolt_B10_31 "汇流排10最高允许充电电压 （配置量）";
CM_ SG_ 2336550575 M2P_PermitMinVolt_B10_31 "汇流排10最低允许放电电压 （配置量）";
CM_ SG_ 2336550575 M2P_PermitMaxPow_Chg_B10_31 "汇流排10最大允许充电功率";
CM_ SG_ 2336550575 M2P_PermitMaxPow_DisChg_B10_31 "汇流排10最大允许放电功率";
CM_ SG_ 2336616081 M2P_Power_B10_01 "汇流排10实时功率";
CM_ SG_ 2336616081 M2P_SysremEngy_Chg_B10_01 "汇流排10充电剩余能量";
CM_ SG_ 2336616081 M2P_SysremEngy_DisChg_B10_01 "汇流排10放电剩余能量";
CM_ SG_ 2336616081 M2P_SysMaxVolt_B10_01 "汇流排10单体最大电压  ";
CM_ SG_ 2336616082 M2P_Power_B10_02 "汇流排10实时功率";
CM_ SG_ 2336616082 M2P_SysremEngy_Chg_B10_02 "汇流排10充电剩余能量";
CM_ SG_ 2336616082 M2P_SysremEngy_DisChg_B10_02 "汇流排10放电剩余能量";
CM_ SG_ 2336616082 M2P_SysMaxVolt_B10_02 "汇流排10单体最大电压  ";
CM_ SG_ 2336616083 M2P_Power_B10_03 "汇流排10实时功率";
CM_ SG_ 2336616083 M2P_SysremEngy_Chg_B10_03 "汇流排10充电剩余能量";
CM_ SG_ 2336616083 M2P_SysremEngy_DisChg_B10_03 "汇流排10放电剩余能量";
CM_ SG_ 2336616083 M2P_SysMaxVolt_B10_03 "汇流排10单体最大电压  ";
CM_ SG_ 2336616084 M2P_Power_B10_04 "汇流排10实时功率";
CM_ SG_ 2336616084 M2P_SysremEngy_Chg_B10_04 "汇流排10充电剩余能量";
CM_ SG_ 2336616084 M2P_SysremEngy_DisChg_B10_04 "汇流排10放电剩余能量";
CM_ SG_ 2336616084 M2P_SysMaxVolt_B10_04 "汇流排10单体最大电压  ";
CM_ SG_ 2336616085 M2P_Power_B10_05 "汇流排10实时功率";
CM_ SG_ 2336616085 M2P_SysremEngy_Chg_B10_05 "汇流排10充电剩余能量";
CM_ SG_ 2336616085 M2P_SysremEngy_DisChg_B10_05 "汇流排10放电剩余能量";
CM_ SG_ 2336616085 M2P_SysMaxVolt_B10_05 "汇流排10单体最大电压  ";
CM_ SG_ 2336616086 M2P_Power_B10_06 "汇流排10实时功率";
CM_ SG_ 2336616086 M2P_SysremEngy_Chg_B10_06 "汇流排10充电剩余能量";
CM_ SG_ 2336616086 M2P_SysremEngy_DisChg_B10_06 "汇流排10放电剩余能量";
CM_ SG_ 2336616086 M2P_SysMaxVolt_B10_06 "汇流排10单体最大电压  ";
CM_ SG_ 2336616087 M2P_Power_B10_07 "汇流排10实时功率";
CM_ SG_ 2336616087 M2P_SysremEngy_Chg_B10_07 "汇流排10充电剩余能量";
CM_ SG_ 2336616087 M2P_SysremEngy_DisChg_B10_07 "汇流排10放电剩余能量";
CM_ SG_ 2336616087 M2P_SysMaxVolt_B10_07 "汇流排10单体最大电压  ";
CM_ SG_ 2336616088 M2P_Power_B10_08 "汇流排10实时功率";
CM_ SG_ 2336616088 M2P_SysremEngy_Chg_B10_08 "汇流排10充电剩余能量";
CM_ SG_ 2336616088 M2P_SysremEngy_DisChg_B10_08 "汇流排10放电剩余能量";
CM_ SG_ 2336616088 M2P_SysMaxVolt_B10_08 "汇流排10单体最大电压  ";
CM_ SG_ 2336616089 M2P_Power_B10_09 "汇流排10实时功率";
CM_ SG_ 2336616089 M2P_SysremEngy_Chg_B10_09 "汇流排10充电剩余能量";
CM_ SG_ 2336616089 M2P_SysremEngy_DisChg_B10_09 "汇流排10放电剩余能量";
CM_ SG_ 2336616089 M2P_SysMaxVolt_B10_09 "汇流排10单体最大电压  ";
CM_ SG_ 2336616090 M2P_Power_B10_10 "汇流排10实时功率";
CM_ SG_ 2336616090 M2P_SysremEngy_Chg_B10_10 "汇流排10充电剩余能量";
CM_ SG_ 2336616090 M2P_SysremEngy_DisChg_B10_10 "汇流排10放电剩余能量";
CM_ SG_ 2336616090 M2P_SysMaxVolt_B10_10 "汇流排10单体最大电压  ";
CM_ SG_ 2336616091 M2P_Power_B10_11 "汇流排10实时功率";
CM_ SG_ 2336616091 M2P_SysremEngy_Chg_B10_11 "汇流排10充电剩余能量";
CM_ SG_ 2336616091 M2P_SysremEngy_DisChg_B10_11 "汇流排10放电剩余能量";
CM_ SG_ 2336616091 M2P_SysMaxVolt_B10_11 "汇流排10单体最大电压  ";
CM_ SG_ 2336616092 M2P_Power_B10_12 "汇流排10实时功率";
CM_ SG_ 2336616092 M2P_SysremEngy_Chg_B10_12 "汇流排10充电剩余能量";
CM_ SG_ 2336616092 M2P_SysremEngy_DisChg_B10_12 "汇流排10放电剩余能量";
CM_ SG_ 2336616092 M2P_SysMaxVolt_B10_12 "汇流排10单体最大电压  ";
CM_ SG_ 2336616093 M2P_Power_B10_13 "汇流排10实时功率";
CM_ SG_ 2336616093 M2P_SysremEngy_Chg_B10_13 "汇流排10充电剩余能量";
CM_ SG_ 2336616093 M2P_SysremEngy_DisChg_B10_13 "汇流排10放电剩余能量";
CM_ SG_ 2336616093 M2P_SysMaxVolt_B10_13 "汇流排10单体最大电压  ";
CM_ SG_ 2336616094 M2P_Power_B10_14 "汇流排10实时功率";
CM_ SG_ 2336616094 M2P_SysremEngy_Chg_B10_14 "汇流排10充电剩余能量";
CM_ SG_ 2336616094 M2P_SysremEngy_DisChg_B10_14 "汇流排10放电剩余能量";
CM_ SG_ 2336616094 M2P_SysMaxVolt_B10_14 "汇流排10单体最大电压  ";
CM_ SG_ 2336616095 M2P_Power_B10_15 "汇流排10实时功率";
CM_ SG_ 2336616095 M2P_SysremEngy_Chg_B10_15 "汇流排10充电剩余能量";
CM_ SG_ 2336616095 M2P_SysremEngy_DisChg_B10_15 "汇流排10放电剩余能量";
CM_ SG_ 2336616095 M2P_SysMaxVolt_B10_15 "汇流排10单体最大电压  ";
CM_ SG_ 2336616096 M2P_Power_B10_16 "汇流排10实时功率";
CM_ SG_ 2336616096 M2P_SysremEngy_Chg_B10_16 "汇流排10充电剩余能量";
CM_ SG_ 2336616096 M2P_SysremEngy_DisChg_B10_16 "汇流排10放电剩余能量";
CM_ SG_ 2336616096 M2P_SysMaxVolt_B10_16 "汇流排10单体最大电压  ";
CM_ SG_ 2336616097 M2P_Power_B10_17 "汇流排10实时功率";
CM_ SG_ 2336616097 M2P_SysremEngy_Chg_B10_17 "汇流排10充电剩余能量";
CM_ SG_ 2336616097 M2P_SysremEngy_DisChg_B10_17 "汇流排10放电剩余能量";
CM_ SG_ 2336616097 M2P_SysMaxVolt_B10_17 "汇流排10单体最大电压  ";
CM_ SG_ 2336616098 M2P_Power_B10_18 "汇流排10实时功率";
CM_ SG_ 2336616098 M2P_SysremEngy_Chg_B10_18 "汇流排10充电剩余能量";
CM_ SG_ 2336616098 M2P_SysremEngy_DisChg_B10_18 "汇流排10放电剩余能量";
CM_ SG_ 2336616098 M2P_SysMaxVolt_B10_18 "汇流排10单体最大电压  ";
CM_ SG_ 2336616099 M2P_Power_B10_19 "汇流排10实时功率";
CM_ SG_ 2336616099 M2P_SysremEngy_Chg_B10_19 "汇流排10充电剩余能量";
CM_ SG_ 2336616099 M2P_SysremEngy_DisChg_B10_19 "汇流排10放电剩余能量";
CM_ SG_ 2336616099 M2P_SysMaxVolt_B10_19 "汇流排10单体最大电压  ";
CM_ SG_ 2336616100 M2P_Power_B10_20 "汇流排10实时功率";
CM_ SG_ 2336616100 M2P_SysremEngy_Chg_B10_20 "汇流排10充电剩余能量";
CM_ SG_ 2336616100 M2P_SysremEngy_DisChg_B10_20 "汇流排10放电剩余能量";
CM_ SG_ 2336616100 M2P_SysMaxVolt_B10_20 "汇流排10单体最大电压  ";
CM_ SG_ 2336616101 M2P_Power_B10_21 "汇流排10实时功率";
CM_ SG_ 2336616101 M2P_SysremEngy_Chg_B10_21 "汇流排10充电剩余能量";
CM_ SG_ 2336616101 M2P_SysremEngy_DisChg_B10_21 "汇流排10放电剩余能量";
CM_ SG_ 2336616101 M2P_SysMaxVolt_B10_21 "汇流排10单体最大电压  ";
CM_ SG_ 2336616102 M2P_Power_B10_22 "汇流排10实时功率";
CM_ SG_ 2336616102 M2P_SysremEngy_Chg_B10_22 "汇流排10充电剩余能量";
CM_ SG_ 2336616102 M2P_SysremEngy_DisChg_B10_22 "汇流排10放电剩余能量";
CM_ SG_ 2336616102 M2P_SysMaxVolt_B10_22 "汇流排10单体最大电压  ";
CM_ SG_ 2336616103 M2P_Power_B10_23 "汇流排10实时功率";
CM_ SG_ 2336616103 M2P_SysremEngy_Chg_B10_23 "汇流排10充电剩余能量";
CM_ SG_ 2336616103 M2P_SysremEngy_DisChg_B10_23 "汇流排10放电剩余能量";
CM_ SG_ 2336616103 M2P_SysMaxVolt_B10_23 "汇流排10单体最大电压  ";
CM_ SG_ 2336616104 M2P_Power_B10_24 "汇流排10实时功率";
CM_ SG_ 2336616104 M2P_SysremEngy_Chg_B10_24 "汇流排10充电剩余能量";
CM_ SG_ 2336616104 M2P_SysremEngy_DisChg_B10_24 "汇流排10放电剩余能量";
CM_ SG_ 2336616104 M2P_SysMaxVolt_B10_24 "汇流排10单体最大电压  ";
CM_ SG_ 2336616105 M2P_Power_B10_25 "汇流排10实时功率";
CM_ SG_ 2336616105 M2P_SysremEngy_Chg_B10_25 "汇流排10充电剩余能量";
CM_ SG_ 2336616105 M2P_SysremEngy_DisChg_B10_25 "汇流排10放电剩余能量";
CM_ SG_ 2336616105 M2P_SysMaxVolt_B10_25 "汇流排10单体最大电压  ";
CM_ SG_ 2336616106 M2P_Power_B10_26 "汇流排10实时功率";
CM_ SG_ 2336616106 M2P_SysremEngy_Chg_B10_26 "汇流排10充电剩余能量";
CM_ SG_ 2336616106 M2P_SysremEngy_DisChg_B10_26 "汇流排10放电剩余能量";
CM_ SG_ 2336616106 M2P_SysMaxVolt_B10_26 "汇流排10单体最大电压  ";
CM_ SG_ 2336616107 M2P_Power_B10_27 "汇流排10实时功率";
CM_ SG_ 2336616107 M2P_SysremEngy_Chg_B10_27 "汇流排10充电剩余能量";
CM_ SG_ 2336616107 M2P_SysremEngy_DisChg_B10_27 "汇流排10放电剩余能量";
CM_ SG_ 2336616107 M2P_SysMaxVolt_B10_27 "汇流排10单体最大电压  ";
CM_ SG_ 2336616108 M2P_Power_B10_28 "汇流排10实时功率";
CM_ SG_ 2336616108 M2P_SysremEngy_Chg_B10_28 "汇流排10充电剩余能量";
CM_ SG_ 2336616108 M2P_SysremEngy_DisChg_B10_28 "汇流排10放电剩余能量";
CM_ SG_ 2336616108 M2P_SysMaxVolt_B10_28 "汇流排10单体最大电压  ";
CM_ SG_ 2336616109 M2P_Power_B10_29 "汇流排10实时功率";
CM_ SG_ 2336616109 M2P_SysremEngy_Chg_B10_29 "汇流排10充电剩余能量";
CM_ SG_ 2336616109 M2P_SysremEngy_DisChg_B10_29 "汇流排10放电剩余能量";
CM_ SG_ 2336616109 M2P_SysMaxVolt_B10_29 "汇流排10单体最大电压  ";
CM_ SG_ 2336616110 M2P_Power_B10_30 "汇流排10实时功率";
CM_ SG_ 2336616110 M2P_SysremEngy_Chg_B10_30 "汇流排10充电剩余能量";
CM_ SG_ 2336616110 M2P_SysremEngy_DisChg_B10_30 "汇流排10放电剩余能量";
CM_ SG_ 2336616110 M2P_SysMaxVolt_B10_30 "汇流排10单体最大电压  ";
CM_ SG_ 2336616111 M2P_Power_B10_31 "汇流排10实时功率";
CM_ SG_ 2336616111 M2P_SysremEngy_Chg_B10_31 "汇流排10充电剩余能量";
CM_ SG_ 2336616111 M2P_SysremEngy_DisChg_B10_31 "汇流排10放电剩余能量";
CM_ SG_ 2336616111 M2P_SysMaxVolt_B10_31 "汇流排10单体最大电压  ";
CM_ SG_ 2336681617 M2P_SysMinVolt_B10_01 "汇流排10单体最小电压";
CM_ SG_ 2336681617 M2P_SysAvgVolt_B10_01 "汇流排10单体平均电压";
CM_ SG_ 2336681617 M2P_BMS_Status_B10 "汇流排10能量状态";
CM_ SG_ 2336681617 M2P_SOC_B10 "汇流排10系统SOC";
CM_ SG_ 2336681617 M2P_SOH_B10 "汇流排10系统SOH";
CM_ SG_ 2336681617 Reserved_01 "预留";
CM_ SG_ 2336681618 M2P_SysMinVolt_B10_02 "汇流排10单体最小电压";
CM_ SG_ 2336681618 M2P_SysAvgVolt_B10_02 "汇流排10单体平均电压";
CM_ SG_ 2336681618 M2P_BMS_Status_B10 "汇流排10能量状态";
CM_ SG_ 2336681618 M2P_SOC_B10 "汇流排10系统SOC";
CM_ SG_ 2336681618 M2P_SOH_B10 "汇流排10系统SOH";
CM_ SG_ 2336681618 Reserved_02 "预留";
CM_ SG_ 2336681619 M2P_SysMinVolt_B10_03 "汇流排10单体最小电压";
CM_ SG_ 2336681619 M2P_SysAvgVolt_B10_03 "汇流排10单体平均电压";
CM_ SG_ 2336681619 M2P_BMS_Status_B10 "汇流排10能量状态";
CM_ SG_ 2336681619 M2P_SOC_B10 "汇流排10系统SOC";
CM_ SG_ 2336681619 M2P_SOH_B10 "汇流排10系统SOH";
CM_ SG_ 2336681619 Reserved_03 "预留";
CM_ SG_ 2336681620 M2P_SysMinVolt_B10_04 "汇流排10单体最小电压";
CM_ SG_ 2336681620 M2P_SysAvgVolt_B10_04 "汇流排10单体平均电压";
CM_ SG_ 2336681620 M2P_BMS_Status_B10 "汇流排10能量状态";
CM_ SG_ 2336681620 M2P_SOC_B10 "汇流排10系统SOC";
CM_ SG_ 2336681620 M2P_SOH_B10 "汇流排10系统SOH";
CM_ SG_ 2336681620 Reserved_04 "预留";
CM_ SG_ 2336681621 M2P_SysMinVolt_B10_05 "汇流排10单体最小电压";
CM_ SG_ 2336681621 M2P_SysAvgVolt_B10_05 "汇流排10单体平均电压";
CM_ SG_ 2336681621 M2P_BMS_Status_B10 "汇流排10能量状态";
CM_ SG_ 2336681621 M2P_SOC_B10 "汇流排10系统SOC";
CM_ SG_ 2336681621 M2P_SOH_B10 "汇流排10系统SOH";
CM_ SG_ 2336681621 Reserved_05 "预留";
CM_ SG_ 2336681622 M2P_SysMinVolt_B10_06 "汇流排10单体最小电压";
CM_ SG_ 2336681622 M2P_SysAvgVolt_B10_06 "汇流排10单体平均电压";
CM_ SG_ 2336681622 M2P_BMS_Status_B10 "汇流排10能量状态";
CM_ SG_ 2336681622 M2P_SOC_B10 "汇流排10系统SOC";
CM_ SG_ 2336681622 M2P_SOH_B10 "汇流排10系统SOH";
CM_ SG_ 2336681622 Reserved_06 "预留";
CM_ SG_ 2336681623 M2P_SysMinVolt_B10_07 "汇流排10单体最小电压";
CM_ SG_ 2336681623 M2P_SysAvgVolt_B10_07 "汇流排10单体平均电压";
CM_ SG_ 2336681623 M2P_BMS_Status_B10 "汇流排10能量状态";
CM_ SG_ 2336681623 M2P_SOC_B10 "汇流排10系统SOC";
CM_ SG_ 2336681623 M2P_SOH_B10 "汇流排10系统SOH";
CM_ SG_ 2336681623 Reserved_07 "预留";
CM_ SG_ 2336681624 M2P_SysMinVolt_B10_08 "汇流排10单体最小电压";
CM_ SG_ 2336681624 M2P_SysAvgVolt_B10_08 "汇流排10单体平均电压";
CM_ SG_ 2336681624 M2P_BMS_Status_B10 "汇流排10能量状态";
CM_ SG_ 2336681624 M2P_SOC_B10 "汇流排10系统SOC";
CM_ SG_ 2336681624 M2P_SOH_B10 "汇流排10系统SOH";
CM_ SG_ 2336681624 Reserved_08 "预留";
CM_ SG_ 2336681625 M2P_SysMinVolt_B10_09 "汇流排10单体最小电压";
CM_ SG_ 2336681625 M2P_SysAvgVolt_B10_09 "汇流排10单体平均电压";
CM_ SG_ 2336681625 M2P_BMS_Status_B10 "汇流排10能量状态";
CM_ SG_ 2336681625 M2P_SOC_B10 "汇流排10系统SOC";
CM_ SG_ 2336681625 M2P_SOH_B10 "汇流排10系统SOH";
CM_ SG_ 2336681625 Reserved_09 "预留";
CM_ SG_ 2336681626 M2P_SysMinVolt_B10_10 "汇流排10单体最小电压";
CM_ SG_ 2336681626 M2P_SysAvgVolt_B10_10 "汇流排10单体平均电压";
CM_ SG_ 2336681626 M2P_BMS_Status_B10 "汇流排10能量状态";
CM_ SG_ 2336681626 M2P_SOC_B10 "汇流排10系统SOC";
CM_ SG_ 2336681626 M2P_SOH_B10 "汇流排10系统SOH";
CM_ SG_ 2336681626 Reserved_10 "预留";
CM_ SG_ 2336681627 M2P_SysMinVolt_B10_11 "汇流排10单体最小电压";
CM_ SG_ 2336681627 M2P_SysAvgVolt_B10_11 "汇流排10单体平均电压";
CM_ SG_ 2336681627 M2P_BMS_Status_B10 "汇流排10能量状态";
CM_ SG_ 2336681627 M2P_SOC_B10 "汇流排10系统SOC";
CM_ SG_ 2336681627 M2P_SOH_B10 "汇流排10系统SOH";
CM_ SG_ 2336681627 Reserved_11 "预留";
CM_ SG_ 2336681628 M2P_SysMinVolt_B10_12 "汇流排10单体最小电压";
CM_ SG_ 2336681628 M2P_SysAvgVolt_B10_12 "汇流排10单体平均电压";
CM_ SG_ 2336681628 M2P_BMS_Status_B10 "汇流排10能量状态";
CM_ SG_ 2336681628 M2P_SOC_B10 "汇流排10系统SOC";
CM_ SG_ 2336681628 M2P_SOH_B10 "汇流排10系统SOH";
CM_ SG_ 2336681628 Reserved_12 "预留";
CM_ SG_ 2336681629 M2P_SysMinVolt_B10_13 "汇流排10单体最小电压";
CM_ SG_ 2336681629 M2P_SysAvgVolt_B10_13 "汇流排10单体平均电压";
CM_ SG_ 2336681629 M2P_BMS_Status_B10 "汇流排10能量状态";
CM_ SG_ 2336681629 M2P_SOC_B10 "汇流排10系统SOC";
CM_ SG_ 2336681629 M2P_SOH_B10 "汇流排10系统SOH";
CM_ SG_ 2336681629 Reserved_13 "预留";
CM_ SG_ 2336681630 M2P_SysMinVolt_B10_14 "汇流排10单体最小电压";
CM_ SG_ 2336681630 M2P_SysAvgVolt_B10_14 "汇流排10单体平均电压";
CM_ SG_ 2336681630 M2P_BMS_Status_B10 "汇流排10能量状态";
CM_ SG_ 2336681630 M2P_SOC_B10 "汇流排10系统SOC";
CM_ SG_ 2336681630 M2P_SOH_B10 "汇流排10系统SOH";
CM_ SG_ 2336681630 Reserved_14 "预留";
CM_ SG_ 2336681631 M2P_SysMinVolt_B10_15 "汇流排10单体最小电压";
CM_ SG_ 2336681631 M2P_SysAvgVolt_B10_15 "汇流排10单体平均电压";
CM_ SG_ 2336681631 M2P_BMS_Status_B10 "汇流排10能量状态";
CM_ SG_ 2336681631 M2P_SOC_B10 "汇流排10系统SOC";
CM_ SG_ 2336681631 M2P_SOH_B10 "汇流排10系统SOH";
CM_ SG_ 2336681631 Reserved_15 "预留";
CM_ SG_ 2336681632 M2P_SysMinVolt_B10_16 "汇流排10单体最小电压";
CM_ SG_ 2336681632 M2P_SysAvgVolt_B10_16 "汇流排10单体平均电压";
CM_ SG_ 2336681632 M2P_BMS_Status_B10 "汇流排10能量状态";
CM_ SG_ 2336681632 M2P_SOC_B10 "汇流排10系统SOC";
CM_ SG_ 2336681632 M2P_SOH_B10 "汇流排10系统SOH";
CM_ SG_ 2336681632 Reserved_16 "预留";
CM_ SG_ 2336681633 M2P_SysMinVolt_B10_17 "汇流排10单体最小电压";
CM_ SG_ 2336681633 M2P_SysAvgVolt_B10_17 "汇流排10单体平均电压";
CM_ SG_ 2336681633 M2P_BMS_Status_B10 "汇流排10能量状态";
CM_ SG_ 2336681633 M2P_SOC_B10 "汇流排10系统SOC";
CM_ SG_ 2336681633 M2P_SOH_B10 "汇流排10系统SOH";
CM_ SG_ 2336681633 Reserved_17 "预留";
CM_ SG_ 2336681634 M2P_SysMinVolt_B10_18 "汇流排10单体最小电压";
CM_ SG_ 2336681634 M2P_SysAvgVolt_B10_18 "汇流排10单体平均电压";
CM_ SG_ 2336681634 M2P_BMS_Status_B10 "汇流排10能量状态";
CM_ SG_ 2336681634 M2P_SOC_B10 "汇流排10系统SOC";
CM_ SG_ 2336681634 M2P_SOH_B10 "汇流排10系统SOH";
CM_ SG_ 2336681634 Reserved_18 "预留";
CM_ SG_ 2336681635 M2P_SysMinVolt_B10_19 "汇流排10单体最小电压";
CM_ SG_ 2336681635 M2P_SysAvgVolt_B10_19 "汇流排10单体平均电压";
CM_ SG_ 2336681635 M2P_BMS_Status_B10 "汇流排10能量状态";
CM_ SG_ 2336681635 M2P_SOC_B10 "汇流排10系统SOC";
CM_ SG_ 2336681635 M2P_SOH_B10 "汇流排10系统SOH";
CM_ SG_ 2336681635 Reserved_19 "预留";
CM_ SG_ 2336681636 M2P_SysMinVolt_B10_20 "汇流排10单体最小电压";
CM_ SG_ 2336681636 M2P_SysAvgVolt_B10_20 "汇流排10单体平均电压";
CM_ SG_ 2336681636 M2P_BMS_Status_B10 "汇流排10能量状态";
CM_ SG_ 2336681636 M2P_SOC_B10 "汇流排10系统SOC";
CM_ SG_ 2336681636 M2P_SOH_B10 "汇流排10系统SOH";
CM_ SG_ 2336681636 Reserved_20 "预留";
CM_ SG_ 2336681637 M2P_SysMinVolt_B10_21 "汇流排10单体最小电压";
CM_ SG_ 2336681637 M2P_SysAvgVolt_B10_21 "汇流排10单体平均电压";
CM_ SG_ 2336681637 M2P_BMS_Status_B10 "汇流排10能量状态";
CM_ SG_ 2336681637 M2P_SOC_B10 "汇流排10系统SOC";
CM_ SG_ 2336681637 M2P_SOH_B10 "汇流排10系统SOH";
CM_ SG_ 2336681637 Reserved_21 "预留";
CM_ SG_ 2336681638 M2P_SysMinVolt_B10_22 "汇流排10单体最小电压";
CM_ SG_ 2336681638 M2P_SysAvgVolt_B10_22 "汇流排10单体平均电压";
CM_ SG_ 2336681638 M2P_BMS_Status_B10 "汇流排10能量状态";
CM_ SG_ 2336681638 M2P_SOC_B10 "汇流排10系统SOC";
CM_ SG_ 2336681638 M2P_SOH_B10 "汇流排10系统SOH";
CM_ SG_ 2336681638 Reserved_22 "预留";
CM_ SG_ 2336681639 M2P_SysMinVolt_B10_23 "汇流排10单体最小电压";
CM_ SG_ 2336681639 M2P_SysAvgVolt_B10_23 "汇流排10单体平均电压";
CM_ SG_ 2336681639 M2P_BMS_Status_B10 "汇流排10能量状态";
CM_ SG_ 2336681639 M2P_SOC_B10 "汇流排10系统SOC";
CM_ SG_ 2336681639 M2P_SOH_B10 "汇流排10系统SOH";
CM_ SG_ 2336681639 Reserved_23 "预留";
CM_ SG_ 2336681640 M2P_SysMinVolt_B10_24 "汇流排10单体最小电压";
CM_ SG_ 2336681640 M2P_SysAvgVolt_B10_24 "汇流排10单体平均电压";
CM_ SG_ 2336681640 M2P_BMS_Status_B10 "汇流排10能量状态";
CM_ SG_ 2336681640 M2P_SOC_B10 "汇流排10系统SOC";
CM_ SG_ 2336681640 M2P_SOH_B10 "汇流排10系统SOH";
CM_ SG_ 2336681640 Reserved_24 "预留";
CM_ SG_ 2336681641 M2P_SysMinVolt_B10_25 "汇流排10单体最小电压";
CM_ SG_ 2336681641 M2P_SysAvgVolt_B10_25 "汇流排10单体平均电压";
CM_ SG_ 2336681641 M2P_BMS_Status_B10 "汇流排10能量状态";
CM_ SG_ 2336681641 M2P_SOC_B10 "汇流排10系统SOC";
CM_ SG_ 2336681641 M2P_SOH_B10 "汇流排10系统SOH";
CM_ SG_ 2336681641 Reserved_25 "预留";
CM_ SG_ 2336681642 M2P_SysMinVolt_B10_26 "汇流排10单体最小电压";
CM_ SG_ 2336681642 M2P_SysAvgVolt_B10_26 "汇流排10单体平均电压";
CM_ SG_ 2336681642 M2P_BMS_Status_B10 "汇流排10能量状态";
CM_ SG_ 2336681642 M2P_SOC_B10 "汇流排10系统SOC";
CM_ SG_ 2336681642 M2P_SOH_B10 "汇流排10系统SOH";
CM_ SG_ 2336681642 Reserved_26 "预留";
CM_ SG_ 2336681643 M2P_SysMinVolt_B10_27 "汇流排10单体最小电压";
CM_ SG_ 2336681643 M2P_SysAvgVolt_B10_27 "汇流排10单体平均电压";
CM_ SG_ 2336681643 M2P_BMS_Status_B10 "汇流排10能量状态";
CM_ SG_ 2336681643 M2P_SOC_B10 "汇流排10系统SOC";
CM_ SG_ 2336681643 M2P_SOH_B10 "汇流排10系统SOH";
CM_ SG_ 2336681643 Reserved_27 "预留";
CM_ SG_ 2336681644 M2P_SysMinVolt_B10_28 "汇流排10单体最小电压";
CM_ SG_ 2336681644 M2P_SysAvgVolt_B10_28 "汇流排10单体平均电压";
CM_ SG_ 2336681644 M2P_BMS_Status_B10 "汇流排10能量状态";
CM_ SG_ 2336681644 M2P_SOC_B10 "汇流排10系统SOC";
CM_ SG_ 2336681644 M2P_SOH_B10 "汇流排10系统SOH";
CM_ SG_ 2336681644 Reserved_28 "预留";
CM_ SG_ 2336681645 M2P_SysMinVolt_B10_29 "汇流排10单体最小电压";
CM_ SG_ 2336681645 M2P_SysAvgVolt_B10_29 "汇流排10单体平均电压";
CM_ SG_ 2336681645 M2P_BMS_Status_B10 "汇流排10能量状态";
CM_ SG_ 2336681645 M2P_SOC_B10 "汇流排10系统SOC";
CM_ SG_ 2336681645 M2P_SOH_B10 "汇流排10系统SOH";
CM_ SG_ 2336681645 Reserved_29 "预留";
CM_ SG_ 2336681646 M2P_SysMinVolt_B10_30 "汇流排10单体最小电压";
CM_ SG_ 2336681646 M2P_SysAvgVolt_B10_30 "汇流排10单体平均电压";
CM_ SG_ 2336681646 M2P_BMS_Status_B10 "汇流排10能量状态";
CM_ SG_ 2336681646 M2P_SOC_B10 "汇流排10系统SOC";
CM_ SG_ 2336681646 M2P_SOH_B10 "汇流排10系统SOH";
CM_ SG_ 2336681646 Reserved_30 "预留";
CM_ SG_ 2336681647 M2P_SysMinVolt_B10_31 "汇流排10单体最小电压";
CM_ SG_ 2336681647 M2P_SysAvgVolt_B10_31 "汇流排10单体平均电压";
CM_ SG_ 2336681647 M2P_BMS_Status_B10 "汇流排10能量状态";
CM_ SG_ 2336681647 M2P_SOC_B10 "汇流排10系统SOC";
CM_ SG_ 2336681647 M2P_SOH_B10 "汇流排10系统SOH";
CM_ SG_ 2336681647 Reserved_31 "预留";
CM_ SG_ 2336747153 M2P_SOE_Charge_B10 "汇流排10系可充电SOE";
CM_ SG_ 2336747153 M2P_SOE_Discharge_B10 "汇流排10系可放电SOE";
CM_ SG_ 2336747153 Reserved_01 "预留";
CM_ SG_ 2336747154 M2P_SOE_Charge_B10 "汇流排10系可充电SOE";
CM_ SG_ 2336747154 M2P_SOE_Discharge_B10 "汇流排10系可放电SOE";
CM_ SG_ 2336747154 Reserved_02 "预留";
CM_ SG_ 2336747155 M2P_SOE_Charge_B10 "汇流排10系可充电SOE";
CM_ SG_ 2336747155 M2P_SOE_Discharge_B10 "汇流排10系可放电SOE";
CM_ SG_ 2336747155 Reserved_03 "预留";
CM_ SG_ 2336747156 M2P_SOE_Charge_B10 "汇流排10系可充电SOE";
CM_ SG_ 2336747156 M2P_SOE_Discharge_B10 "汇流排10系可放电SOE";
CM_ SG_ 2336747156 Reserved_04 "预留";
CM_ SG_ 2336747157 M2P_SOE_Charge_B10 "汇流排10系可充电SOE";
CM_ SG_ 2336747157 M2P_SOE_Discharge_B10 "汇流排10系可放电SOE";
CM_ SG_ 2336747157 Reserved_05 "预留";
CM_ SG_ 2336747158 M2P_SOE_Charge_B10 "汇流排10系可充电SOE";
CM_ SG_ 2336747158 M2P_SOE_Discharge_B10 "汇流排10系可放电SOE";
CM_ SG_ 2336747158 Reserved_06 "预留";
CM_ SG_ 2336747159 M2P_SOE_Charge_B10 "汇流排10系可充电SOE";
CM_ SG_ 2336747159 M2P_SOE_Discharge_B10 "汇流排10系可放电SOE";
CM_ SG_ 2336747159 Reserved_07 "预留";
CM_ SG_ 2336747160 M2P_SOE_Charge_B10 "汇流排10系可充电SOE";
CM_ SG_ 2336747160 M2P_SOE_Discharge_B10 "汇流排10系可放电SOE";
CM_ SG_ 2336747160 Reserved_08 "预留";
CM_ SG_ 2336747161 M2P_SOE_Charge_B10 "汇流排10系可充电SOE";
CM_ SG_ 2336747161 M2P_SOE_Discharge_B10 "汇流排10系可放电SOE";
CM_ SG_ 2336747161 Reserved_09 "预留";
CM_ SG_ 2336747162 M2P_SOE_Charge_B10 "汇流排10系可充电SOE";
CM_ SG_ 2336747162 M2P_SOE_Discharge_B10 "汇流排10系可放电SOE";
CM_ SG_ 2336747162 Reserved_10 "预留";
CM_ SG_ 2336747163 M2P_SOE_Charge_B10 "汇流排10系可充电SOE";
CM_ SG_ 2336747163 M2P_SOE_Discharge_B10 "汇流排10系可放电SOE";
CM_ SG_ 2336747163 Reserved_11 "预留";
CM_ SG_ 2336747164 M2P_SOE_Charge_B10 "汇流排10系可充电SOE";
CM_ SG_ 2336747164 M2P_SOE_Discharge_B10 "汇流排10系可放电SOE";
CM_ SG_ 2336747164 Reserved_12 "预留";
CM_ SG_ 2336747165 M2P_SOE_Charge_B10 "汇流排10系可充电SOE";
CM_ SG_ 2336747165 M2P_SOE_Discharge_B10 "汇流排10系可放电SOE";
CM_ SG_ 2336747165 Reserved_13 "预留";
CM_ SG_ 2336747166 M2P_SOE_Charge_B10 "汇流排10系可充电SOE";
CM_ SG_ 2336747166 M2P_SOE_Discharge_B10 "汇流排10系可放电SOE";
CM_ SG_ 2336747166 Reserved_14 "预留";
CM_ SG_ 2336747167 M2P_SOE_Charge_B10 "汇流排10系可充电SOE";
CM_ SG_ 2336747167 M2P_SOE_Discharge_B10 "汇流排10系可放电SOE";
CM_ SG_ 2336747167 Reserved_15 "预留";
CM_ SG_ 2336747168 M2P_SOE_Charge_B10 "汇流排10系可充电SOE";
CM_ SG_ 2336747168 M2P_SOE_Discharge_B10 "汇流排10系可放电SOE";
CM_ SG_ 2336747168 Reserved_16 "预留";
CM_ SG_ 2336747169 M2P_SOE_Charge_B10 "汇流排10系可充电SOE";
CM_ SG_ 2336747169 M2P_SOE_Discharge_B10 "汇流排10系可放电SOE";
CM_ SG_ 2336747169 Reserved_17 "预留";
CM_ SG_ 2336747170 M2P_SOE_Charge_B10 "汇流排10系可充电SOE";
CM_ SG_ 2336747170 M2P_SOE_Discharge_B10 "汇流排10系可放电SOE";
CM_ SG_ 2336747170 Reserved_18 "预留";
CM_ SG_ 2336747171 M2P_SOE_Charge_B10 "汇流排10系可充电SOE";
CM_ SG_ 2336747171 M2P_SOE_Discharge_B10 "汇流排10系可放电SOE";
CM_ SG_ 2336747171 Reserved_19 "预留";
CM_ SG_ 2336747172 M2P_SOE_Charge_B10 "汇流排10系可充电SOE";
CM_ SG_ 2336747172 M2P_SOE_Discharge_B10 "汇流排10系可放电SOE";
CM_ SG_ 2336747172 Reserved_20 "预留";
CM_ SG_ 2336747173 M2P_SOE_Charge_B10 "汇流排10系可充电SOE";
CM_ SG_ 2336747173 M2P_SOE_Discharge_B10 "汇流排10系可放电SOE";
CM_ SG_ 2336747173 Reserved_21 "预留";
CM_ SG_ 2336747174 M2P_SOE_Charge_B10 "汇流排10系可充电SOE";
CM_ SG_ 2336747174 M2P_SOE_Discharge_B10 "汇流排10系可放电SOE";
CM_ SG_ 2336747174 Reserved_22 "预留";
CM_ SG_ 2336747175 M2P_SOE_Charge_B10 "汇流排10系可充电SOE";
CM_ SG_ 2336747175 M2P_SOE_Discharge_B10 "汇流排10系可放电SOE";
CM_ SG_ 2336747175 Reserved_23 "预留";
CM_ SG_ 2336747176 M2P_SOE_Charge_B10 "汇流排10系可充电SOE";
CM_ SG_ 2336747176 M2P_SOE_Discharge_B10 "汇流排10系可放电SOE";
CM_ SG_ 2336747176 Reserved_24 "预留";
CM_ SG_ 2336747177 M2P_SOE_Charge_B10 "汇流排10系可充电SOE";
CM_ SG_ 2336747177 M2P_SOE_Discharge_B10 "汇流排10系可放电SOE";
CM_ SG_ 2336747177 Reserved_25 "预留";
CM_ SG_ 2336747178 M2P_SOE_Charge_B10 "汇流排10系可充电SOE";
CM_ SG_ 2336747178 M2P_SOE_Discharge_B10 "汇流排10系可放电SOE";
CM_ SG_ 2336747178 Reserved_26 "预留";
CM_ SG_ 2336747179 M2P_SOE_Charge_B10 "汇流排10系可充电SOE";
CM_ SG_ 2336747179 M2P_SOE_Discharge_B10 "汇流排10系可放电SOE";
CM_ SG_ 2336747179 Reserved_27 "预留";
CM_ SG_ 2336747180 M2P_SOE_Charge_B10 "汇流排10系可充电SOE";
CM_ SG_ 2336747180 M2P_SOE_Discharge_B10 "汇流排10系可放电SOE";
CM_ SG_ 2336747180 Reserved_28 "预留";
CM_ SG_ 2336747181 M2P_SOE_Charge_B10 "汇流排10系可充电SOE";
CM_ SG_ 2336747181 M2P_SOE_Discharge_B10 "汇流排10系可放电SOE";
CM_ SG_ 2336747181 Reserved_29 "预留";
CM_ SG_ 2336747182 M2P_SOE_Charge_B10 "汇流排10系可充电SOE";
CM_ SG_ 2336747182 M2P_SOE_Discharge_B10 "汇流排10系可放电SOE";
CM_ SG_ 2336747182 Reserved_30 "预留";
CM_ SG_ 2336747183 M2P_SOE_Charge_B10 "汇流排10系可充电SOE";
CM_ SG_ 2336747183 M2P_SOE_Discharge_B10 "汇流排10系可放电SOE";
CM_ SG_ 2336747183 Reserved_31 "预留";
CM_ SG_ 2336812689 M2P_Measure_Vol_B11_01 "汇流排11所有高压在线电柜外侧电压平均值    ";
CM_ SG_ 2336812689 M2P_Current_B11_01 "汇流排11所有电柜电流累加和";
CM_ SG_ 2336812689 M2P_PermitMaxCharge_I_B11_01 "汇流排11最大允许充电电流";
CM_ SG_ 2336812689 M2P_PermitMaxDisCharge_I_B11_01 "汇流排11最大允许放电电流";
CM_ SG_ 2336812690 M2P_Measure_Vol_B11_02 "汇流排11所有高压在线电柜外侧电压平均值    ";
CM_ SG_ 2336812690 M2P_Current_B11_02 "汇流排11所有电柜电流累加和";
CM_ SG_ 2336812690 M2P_PermitMaxCharge_I_B11_02 "汇流排11最大允许充电电流";
CM_ SG_ 2336812690 M2P_PermitMaxDisCharge_I_B11_02 "汇流排11最大允许放电电流";
CM_ SG_ 2336812691 M2P_Measure_Vol_B11_03 "汇流排11所有高压在线电柜外侧电压平均值    ";
CM_ SG_ 2336812691 M2P_Current_B11_03 "汇流排11所有电柜电流累加和";
CM_ SG_ 2336812691 M2P_PermitMaxCharge_I_B11_03 "汇流排11最大允许充电电流";
CM_ SG_ 2336812691 M2P_PermitMaxDisCharge_I_B11_03 "汇流排11最大允许放电电流";
CM_ SG_ 2336812692 M2P_Measure_Vol_B11_04 "汇流排11所有高压在线电柜外侧电压平均值    ";
CM_ SG_ 2336812692 M2P_Current_B11_04 "汇流排11所有电柜电流累加和";
CM_ SG_ 2336812692 M2P_PermitMaxCharge_I_B11_04 "汇流排11最大允许充电电流";
CM_ SG_ 2336812692 M2P_PermitMaxDisCharge_I_B11_04 "汇流排11最大允许放电电流";
CM_ SG_ 2336812693 M2P_Measure_Vol_B11_05 "汇流排11所有高压在线电柜外侧电压平均值    ";
CM_ SG_ 2336812693 M2P_Current_B11_05 "汇流排11所有电柜电流累加和";
CM_ SG_ 2336812693 M2P_PermitMaxCharge_I_B11_05 "汇流排11最大允许充电电流";
CM_ SG_ 2336812693 M2P_PermitMaxDisCharge_I_B11_05 "汇流排11最大允许放电电流";
CM_ SG_ 2336812694 M2P_Measure_Vol_B11_06 "汇流排11所有高压在线电柜外侧电压平均值    ";
CM_ SG_ 2336812694 M2P_Current_B11_06 "汇流排11所有电柜电流累加和";
CM_ SG_ 2336812694 M2P_PermitMaxCharge_I_B11_06 "汇流排11最大允许充电电流";
CM_ SG_ 2336812694 M2P_PermitMaxDisCharge_I_B11_06 "汇流排11最大允许放电电流";
CM_ SG_ 2336812695 M2P_Measure_Vol_B11_07 "汇流排11所有高压在线电柜外侧电压平均值    ";
CM_ SG_ 2336812695 M2P_Current_B11_07 "汇流排11所有电柜电流累加和";
CM_ SG_ 2336812695 M2P_PermitMaxCharge_I_B11_07 "汇流排11最大允许充电电流";
CM_ SG_ 2336812695 M2P_PermitMaxDisCharge_I_B11_07 "汇流排11最大允许放电电流";
CM_ SG_ 2336812696 M2P_Measure_Vol_B11_08 "汇流排11所有高压在线电柜外侧电压平均值    ";
CM_ SG_ 2336812696 M2P_Current_B11_08 "汇流排11所有电柜电流累加和";
CM_ SG_ 2336812696 M2P_PermitMaxCharge_I_B11_08 "汇流排11最大允许充电电流";
CM_ SG_ 2336812696 M2P_PermitMaxDisCharge_I_B11_08 "汇流排11最大允许放电电流";
CM_ SG_ 2336812697 M2P_Measure_Vol_B11_09 "汇流排11所有高压在线电柜外侧电压平均值    ";
CM_ SG_ 2336812697 M2P_Current_B11_09 "汇流排11所有电柜电流累加和";
CM_ SG_ 2336812697 M2P_PermitMaxCharge_I_B11_09 "汇流排11最大允许充电电流";
CM_ SG_ 2336812697 M2P_PermitMaxDisCharge_I_B11_09 "汇流排11最大允许放电电流";
CM_ SG_ 2336812698 M2P_Measure_Vol_B11_10 "汇流排11所有高压在线电柜外侧电压平均值    ";
CM_ SG_ 2336812698 M2P_Current_B11_10 "汇流排11所有电柜电流累加和";
CM_ SG_ 2336812698 M2P_PermitMaxCharge_I_B11_10 "汇流排11最大允许充电电流";
CM_ SG_ 2336812698 M2P_PermitMaxDisCharge_I_B11_10 "汇流排11最大允许放电电流";
CM_ SG_ 2336812699 M2P_Measure_Vol_B11_11 "汇流排11所有高压在线电柜外侧电压平均值    ";
CM_ SG_ 2336812699 M2P_Current_B11_11 "汇流排11所有电柜电流累加和";
CM_ SG_ 2336812699 M2P_PermitMaxCharge_I_B11_11 "汇流排11最大允许充电电流";
CM_ SG_ 2336812699 M2P_PermitMaxDisCharge_I_B11_11 "汇流排11最大允许放电电流";
CM_ SG_ 2336812700 M2P_Measure_Vol_B11_12 "汇流排11所有高压在线电柜外侧电压平均值    ";
CM_ SG_ 2336812700 M2P_Current_B11_12 "汇流排11所有电柜电流累加和";
CM_ SG_ 2336812700 M2P_PermitMaxCharge_I_B11_12 "汇流排11最大允许充电电流";
CM_ SG_ 2336812700 M2P_PermitMaxDisCharge_I_B11_12 "汇流排11最大允许放电电流";
CM_ SG_ 2336812701 M2P_Measure_Vol_B11_13 "汇流排11所有高压在线电柜外侧电压平均值    ";
CM_ SG_ 2336812701 M2P_Current_B11_13 "汇流排11所有电柜电流累加和";
CM_ SG_ 2336812701 M2P_PermitMaxCharge_I_B11_13 "汇流排11最大允许充电电流";
CM_ SG_ 2336812701 M2P_PermitMaxDisCharge_I_B11_13 "汇流排11最大允许放电电流";
CM_ SG_ 2336812702 M2P_Measure_Vol_B11_14 "汇流排11所有高压在线电柜外侧电压平均值    ";
CM_ SG_ 2336812702 M2P_Current_B11_14 "汇流排11所有电柜电流累加和";
CM_ SG_ 2336812702 M2P_PermitMaxCharge_I_B11_14 "汇流排11最大允许充电电流";
CM_ SG_ 2336812702 M2P_PermitMaxDisCharge_I_B11_14 "汇流排11最大允许放电电流";
CM_ SG_ 2336812703 M2P_Measure_Vol_B11_15 "汇流排11所有高压在线电柜外侧电压平均值    ";
CM_ SG_ 2336812703 M2P_Current_B11_15 "汇流排11所有电柜电流累加和";
CM_ SG_ 2336812703 M2P_PermitMaxCharge_I_B11_15 "汇流排11最大允许充电电流";
CM_ SG_ 2336812703 M2P_PermitMaxDisCharge_I_B11_15 "汇流排11最大允许放电电流";
CM_ SG_ 2336812704 M2P_Measure_Vol_B11_16 "汇流排11所有高压在线电柜外侧电压平均值    ";
CM_ SG_ 2336812704 M2P_Current_B11_16 "汇流排11所有电柜电流累加和";
CM_ SG_ 2336812704 M2P_PermitMaxCharge_I_B11_16 "汇流排11最大允许充电电流";
CM_ SG_ 2336812704 M2P_PermitMaxDisCharge_I_B11_16 "汇流排11最大允许放电电流";
CM_ SG_ 2336812705 M2P_Measure_Vol_B11_17 "汇流排11所有高压在线电柜外侧电压平均值    ";
CM_ SG_ 2336812705 M2P_Current_B11_17 "汇流排11所有电柜电流累加和";
CM_ SG_ 2336812705 M2P_PermitMaxCharge_I_B11_17 "汇流排11最大允许充电电流";
CM_ SG_ 2336812705 M2P_PermitMaxDisCharge_I_B11_17 "汇流排11最大允许放电电流";
CM_ SG_ 2336812706 M2P_Measure_Vol_B11_18 "汇流排11所有高压在线电柜外侧电压平均值    ";
CM_ SG_ 2336812706 M2P_Current_B11_18 "汇流排11所有电柜电流累加和";
CM_ SG_ 2336812706 M2P_PermitMaxCharge_I_B11_18 "汇流排11最大允许充电电流";
CM_ SG_ 2336812706 M2P_PermitMaxDisCharge_I_B11_18 "汇流排11最大允许放电电流";
CM_ SG_ 2336812707 M2P_Measure_Vol_B11_19 "汇流排11所有高压在线电柜外侧电压平均值    ";
CM_ SG_ 2336812707 M2P_Current_B11_19 "汇流排11所有电柜电流累加和";
CM_ SG_ 2336812707 M2P_PermitMaxCharge_I_B11_19 "汇流排11最大允许充电电流";
CM_ SG_ 2336812707 M2P_PermitMaxDisCharge_I_B11_19 "汇流排11最大允许放电电流";
CM_ SG_ 2336812708 M2P_Measure_Vol_B11_20 "汇流排11所有高压在线电柜外侧电压平均值    ";
CM_ SG_ 2336812708 M2P_Current_B11_20 "汇流排11所有电柜电流累加和";
CM_ SG_ 2336812708 M2P_PermitMaxCharge_I_B11_20 "汇流排11最大允许充电电流";
CM_ SG_ 2336812708 M2P_PermitMaxDisCharge_I_B11_20 "汇流排11最大允许放电电流";
CM_ SG_ 2336812709 M2P_Measure_Vol_B11_21 "汇流排11所有高压在线电柜外侧电压平均值    ";
CM_ SG_ 2336812709 M2P_Current_B11_21 "汇流排11所有电柜电流累加和";
CM_ SG_ 2336812709 M2P_PermitMaxCharge_I_B11_21 "汇流排11最大允许充电电流";
CM_ SG_ 2336812709 M2P_PermitMaxDisCharge_I_B11_21 "汇流排11最大允许放电电流";
CM_ SG_ 2336812710 M2P_Measure_Vol_B11_22 "汇流排11所有高压在线电柜外侧电压平均值    ";
CM_ SG_ 2336812710 M2P_Current_B11_22 "汇流排11所有电柜电流累加和";
CM_ SG_ 2336812710 M2P_PermitMaxCharge_I_B11_22 "汇流排11最大允许充电电流";
CM_ SG_ 2336812710 M2P_PermitMaxDisCharge_I_B11_22 "汇流排11最大允许放电电流";
CM_ SG_ 2336812711 M2P_Measure_Vol_B11_23 "汇流排11所有高压在线电柜外侧电压平均值    ";
CM_ SG_ 2336812711 M2P_Current_B11_23 "汇流排11所有电柜电流累加和";
CM_ SG_ 2336812711 M2P_PermitMaxCharge_I_B11_23 "汇流排11最大允许充电电流";
CM_ SG_ 2336812711 M2P_PermitMaxDisCharge_I_B11_23 "汇流排11最大允许放电电流";
CM_ SG_ 2336812712 M2P_Measure_Vol_B11_24 "汇流排11所有高压在线电柜外侧电压平均值    ";
CM_ SG_ 2336812712 M2P_Current_B11_24 "汇流排11所有电柜电流累加和";
CM_ SG_ 2336812712 M2P_PermitMaxCharge_I_B11_24 "汇流排11最大允许充电电流";
CM_ SG_ 2336812712 M2P_PermitMaxDisCharge_I_B11_24 "汇流排11最大允许放电电流";
CM_ SG_ 2336812713 M2P_Measure_Vol_B11_25 "汇流排11所有高压在线电柜外侧电压平均值    ";
CM_ SG_ 2336812713 M2P_Current_B11_25 "汇流排11所有电柜电流累加和";
CM_ SG_ 2336812713 M2P_PermitMaxCharge_I_B11_25 "汇流排11最大允许充电电流";
CM_ SG_ 2336812713 M2P_PermitMaxDisCharge_I_B11_25 "汇流排11最大允许放电电流";
CM_ SG_ 2336812714 M2P_Measure_Vol_B11_26 "汇流排11所有高压在线电柜外侧电压平均值    ";
CM_ SG_ 2336812714 M2P_Current_B11_26 "汇流排11所有电柜电流累加和";
CM_ SG_ 2336812714 M2P_PermitMaxCharge_I_B11_26 "汇流排11最大允许充电电流";
CM_ SG_ 2336812714 M2P_PermitMaxDisCharge_I_B11_26 "汇流排11最大允许放电电流";
CM_ SG_ 2336812715 M2P_Measure_Vol_B11_27 "汇流排11所有高压在线电柜外侧电压平均值    ";
CM_ SG_ 2336812715 M2P_Current_B11_27 "汇流排11所有电柜电流累加和";
CM_ SG_ 2336812715 M2P_PermitMaxCharge_I_B11_27 "汇流排11最大允许充电电流";
CM_ SG_ 2336812715 M2P_PermitMaxDisCharge_I_B11_27 "汇流排11最大允许放电电流";
CM_ SG_ 2336812716 M2P_Measure_Vol_B11_28 "汇流排11所有高压在线电柜外侧电压平均值    ";
CM_ SG_ 2336812716 M2P_Current_B11_28 "汇流排11所有电柜电流累加和";
CM_ SG_ 2336812716 M2P_PermitMaxCharge_I_B11_28 "汇流排11最大允许充电电流";
CM_ SG_ 2336812716 M2P_PermitMaxDisCharge_I_B11_28 "汇流排11最大允许放电电流";
CM_ SG_ 2336812717 M2P_Measure_Vol_B11_29 "汇流排11所有高压在线电柜外侧电压平均值    ";
CM_ SG_ 2336812717 M2P_Current_B11_29 "汇流排11所有电柜电流累加和";
CM_ SG_ 2336812717 M2P_PermitMaxCharge_I_B11_29 "汇流排11最大允许充电电流";
CM_ SG_ 2336812717 M2P_PermitMaxDisCharge_I_B11_29 "汇流排11最大允许放电电流";
CM_ SG_ 2336812718 M2P_Measure_Vol_B11_30 "汇流排11所有高压在线电柜外侧电压平均值    ";
CM_ SG_ 2336812718 M2P_Current_B11_30 "汇流排11所有电柜电流累加和";
CM_ SG_ 2336812718 M2P_PermitMaxCharge_I_B11_30 "汇流排11最大允许充电电流";
CM_ SG_ 2336812718 M2P_PermitMaxDisCharge_I_B11_30 "汇流排11最大允许放电电流";
CM_ SG_ 2336812719 M2P_Measure_Vol_B11_31 "汇流排11所有高压在线电柜外侧电压平均值    ";
CM_ SG_ 2336812719 M2P_Current_B11_31 "汇流排11所有电柜电流累加和";
CM_ SG_ 2336812719 M2P_PermitMaxCharge_I_B11_31 "汇流排11最大允许充电电流";
CM_ SG_ 2336812719 M2P_PermitMaxDisCharge_I_B11_31 "汇流排11最大允许放电电流";
CM_ SG_ 2336878225 M2P_PermitMaxVolt_B11_01 "汇流排11最高允许充电电压 （配置量）";
CM_ SG_ 2336878225 M2P_PermitMinVolt_B11_01 "汇流排11最低允许放电电压 （配置量）";
CM_ SG_ 2336878225 M2P_PermitMaxPow_Chg_B11_01 "汇流排11最大允许充电功率";
CM_ SG_ 2336878225 M2P_PermitMaxPow_DisChg_B11_01 "汇流排11最大允许放电功率";
CM_ SG_ 2336878226 M2P_PermitMaxVolt_B11_02 "汇流排11最高允许充电电压 （配置量）";
CM_ SG_ 2336878226 M2P_PermitMinVolt_B11_02 "汇流排11最低允许放电电压 （配置量）";
CM_ SG_ 2336878226 M2P_PermitMaxPow_Chg_B11_02 "汇流排11最大允许充电功率";
CM_ SG_ 2336878226 M2P_PermitMaxPow_DisChg_B11_02 "汇流排11最大允许放电功率";
CM_ SG_ 2336878227 M2P_PermitMaxVolt_B11_03 "汇流排11最高允许充电电压 （配置量）";
CM_ SG_ 2336878227 M2P_PermitMinVolt_B11_03 "汇流排11最低允许放电电压 （配置量）";
CM_ SG_ 2336878227 M2P_PermitMaxPow_Chg_B11_03 "汇流排11最大允许充电功率";
CM_ SG_ 2336878227 M2P_PermitMaxPow_DisChg_B11_03 "汇流排11最大允许放电功率";
CM_ SG_ 2336878228 M2P_PermitMaxVolt_B11_04 "汇流排11最高允许充电电压 （配置量）";
CM_ SG_ 2336878228 M2P_PermitMinVolt_B11_04 "汇流排11最低允许放电电压 （配置量）";
CM_ SG_ 2336878228 M2P_PermitMaxPow_Chg_B11_04 "汇流排11最大允许充电功率";
CM_ SG_ 2336878228 M2P_PermitMaxPow_DisChg_B11_04 "汇流排11最大允许放电功率";
CM_ SG_ 2336878229 M2P_PermitMaxVolt_B11_05 "汇流排11最高允许充电电压 （配置量）";
CM_ SG_ 2336878229 M2P_PermitMinVolt_B11_05 "汇流排11最低允许放电电压 （配置量）";
CM_ SG_ 2336878229 M2P_PermitMaxPow_Chg_B11_05 "汇流排11最大允许充电功率";
CM_ SG_ 2336878229 M2P_PermitMaxPow_DisChg_B11_05 "汇流排11最大允许放电功率";
CM_ SG_ 2336878230 M2P_PermitMaxVolt_B11_06 "汇流排11最高允许充电电压 （配置量）";
CM_ SG_ 2336878230 M2P_PermitMinVolt_B11_06 "汇流排11最低允许放电电压 （配置量）";
CM_ SG_ 2336878230 M2P_PermitMaxPow_Chg_B11_06 "汇流排11最大允许充电功率";
CM_ SG_ 2336878230 M2P_PermitMaxPow_DisChg_B11_06 "汇流排11最大允许放电功率";
CM_ SG_ 2336878231 M2P_PermitMaxVolt_B11_07 "汇流排11最高允许充电电压 （配置量）";
CM_ SG_ 2336878231 M2P_PermitMinVolt_B11_07 "汇流排11最低允许放电电压 （配置量）";
CM_ SG_ 2336878231 M2P_PermitMaxPow_Chg_B11_07 "汇流排11最大允许充电功率";
CM_ SG_ 2336878231 M2P_PermitMaxPow_DisChg_B11_07 "汇流排11最大允许放电功率";
CM_ SG_ 2336878232 M2P_PermitMaxVolt_B11_08 "汇流排11最高允许充电电压 （配置量）";
CM_ SG_ 2336878232 M2P_PermitMinVolt_B11_08 "汇流排11最低允许放电电压 （配置量）";
CM_ SG_ 2336878232 M2P_PermitMaxPow_Chg_B11_08 "汇流排11最大允许充电功率";
CM_ SG_ 2336878232 M2P_PermitMaxPow_DisChg_B11_08 "汇流排11最大允许放电功率";
CM_ SG_ 2336878233 M2P_PermitMaxVolt_B11_09 "汇流排11最高允许充电电压 （配置量）";
CM_ SG_ 2336878233 M2P_PermitMinVolt_B11_09 "汇流排11最低允许放电电压 （配置量）";
CM_ SG_ 2336878233 M2P_PermitMaxPow_Chg_B11_09 "汇流排11最大允许充电功率";
CM_ SG_ 2336878233 M2P_PermitMaxPow_DisChg_B11_09 "汇流排11最大允许放电功率";
CM_ SG_ 2336878234 M2P_PermitMaxVolt_B11_10 "汇流排11最高允许充电电压 （配置量）";
CM_ SG_ 2336878234 M2P_PermitMinVolt_B11_10 "汇流排11最低允许放电电压 （配置量）";
CM_ SG_ 2336878234 M2P_PermitMaxPow_Chg_B11_10 "汇流排11最大允许充电功率";
CM_ SG_ 2336878234 M2P_PermitMaxPow_DisChg_B11_10 "汇流排11最大允许放电功率";
CM_ SG_ 2336878235 M2P_PermitMaxVolt_B11_11 "汇流排11最高允许充电电压 （配置量）";
CM_ SG_ 2336878235 M2P_PermitMinVolt_B11_11 "汇流排11最低允许放电电压 （配置量）";
CM_ SG_ 2336878235 M2P_PermitMaxPow_Chg_B11_11 "汇流排11最大允许充电功率";
CM_ SG_ 2336878235 M2P_PermitMaxPow_DisChg_B11_11 "汇流排11最大允许放电功率";
CM_ SG_ 2336878236 M2P_PermitMaxVolt_B11_12 "汇流排11最高允许充电电压 （配置量）";
CM_ SG_ 2336878236 M2P_PermitMinVolt_B11_12 "汇流排11最低允许放电电压 （配置量）";
CM_ SG_ 2336878236 M2P_PermitMaxPow_Chg_B11_12 "汇流排11最大允许充电功率";
CM_ SG_ 2336878236 M2P_PermitMaxPow_DisChg_B11_12 "汇流排11最大允许放电功率";
CM_ SG_ 2336878237 M2P_PermitMaxVolt_B11_13 "汇流排11最高允许充电电压 （配置量）";
CM_ SG_ 2336878237 M2P_PermitMinVolt_B11_13 "汇流排11最低允许放电电压 （配置量）";
CM_ SG_ 2336878237 M2P_PermitMaxPow_Chg_B11_13 "汇流排11最大允许充电功率";
CM_ SG_ 2336878237 M2P_PermitMaxPow_DisChg_B11_13 "汇流排11最大允许放电功率";
CM_ SG_ 2336878238 M2P_PermitMaxVolt_B11_14 "汇流排11最高允许充电电压 （配置量）";
CM_ SG_ 2336878238 M2P_PermitMinVolt_B11_14 "汇流排11最低允许放电电压 （配置量）";
CM_ SG_ 2336878238 M2P_PermitMaxPow_Chg_B11_14 "汇流排11最大允许充电功率";
CM_ SG_ 2336878238 M2P_PermitMaxPow_DisChg_B11_14 "汇流排11最大允许放电功率";
CM_ SG_ 2336878239 M2P_PermitMaxVolt_B11_15 "汇流排11最高允许充电电压 （配置量）";
CM_ SG_ 2336878239 M2P_PermitMinVolt_B11_15 "汇流排11最低允许放电电压 （配置量）";
CM_ SG_ 2336878239 M2P_PermitMaxPow_Chg_B11_15 "汇流排11最大允许充电功率";
CM_ SG_ 2336878239 M2P_PermitMaxPow_DisChg_B11_15 "汇流排11最大允许放电功率";
CM_ SG_ 2336878240 M2P_PermitMaxVolt_B11_16 "汇流排11最高允许充电电压 （配置量）";
CM_ SG_ 2336878240 M2P_PermitMinVolt_B11_16 "汇流排11最低允许放电电压 （配置量）";
CM_ SG_ 2336878240 M2P_PermitMaxPow_Chg_B11_16 "汇流排11最大允许充电功率";
CM_ SG_ 2336878240 M2P_PermitMaxPow_DisChg_B11_16 "汇流排11最大允许放电功率";
CM_ SG_ 2336878241 M2P_PermitMaxVolt_B11_17 "汇流排11最高允许充电电压 （配置量）";
CM_ SG_ 2336878241 M2P_PermitMinVolt_B11_17 "汇流排11最低允许放电电压 （配置量）";
CM_ SG_ 2336878241 M2P_PermitMaxPow_Chg_B11_17 "汇流排11最大允许充电功率";
CM_ SG_ 2336878241 M2P_PermitMaxPow_DisChg_B11_17 "汇流排11最大允许放电功率";
CM_ SG_ 2336878242 M2P_PermitMaxVolt_B11_18 "汇流排11最高允许充电电压 （配置量）";
CM_ SG_ 2336878242 M2P_PermitMinVolt_B11_18 "汇流排11最低允许放电电压 （配置量）";
CM_ SG_ 2336878242 M2P_PermitMaxPow_Chg_B11_18 "汇流排11最大允许充电功率";
CM_ SG_ 2336878242 M2P_PermitMaxPow_DisChg_B11_18 "汇流排11最大允许放电功率";
CM_ SG_ 2336878243 M2P_PermitMaxVolt_B11_19 "汇流排11最高允许充电电压 （配置量）";
CM_ SG_ 2336878243 M2P_PermitMinVolt_B11_19 "汇流排11最低允许放电电压 （配置量）";
CM_ SG_ 2336878243 M2P_PermitMaxPow_Chg_B11_19 "汇流排11最大允许充电功率";
CM_ SG_ 2336878243 M2P_PermitMaxPow_DisChg_B11_19 "汇流排11最大允许放电功率";
CM_ SG_ 2336878244 M2P_PermitMaxVolt_B11_20 "汇流排11最高允许充电电压 （配置量）";
CM_ SG_ 2336878244 M2P_PermitMinVolt_B11_20 "汇流排11最低允许放电电压 （配置量）";
CM_ SG_ 2336878244 M2P_PermitMaxPow_Chg_B11_20 "汇流排11最大允许充电功率";
CM_ SG_ 2336878244 M2P_PermitMaxPow_DisChg_B11_20 "汇流排11最大允许放电功率";
CM_ SG_ 2336878245 M2P_PermitMaxVolt_B11_21 "汇流排11最高允许充电电压 （配置量）";
CM_ SG_ 2336878245 M2P_PermitMinVolt_B11_21 "汇流排11最低允许放电电压 （配置量）";
CM_ SG_ 2336878245 M2P_PermitMaxPow_Chg_B11_21 "汇流排11最大允许充电功率";
CM_ SG_ 2336878245 M2P_PermitMaxPow_DisChg_B11_21 "汇流排11最大允许放电功率";
CM_ SG_ 2336878246 M2P_PermitMaxVolt_B11_22 "汇流排11最高允许充电电压 （配置量）";
CM_ SG_ 2336878246 M2P_PermitMinVolt_B11_22 "汇流排11最低允许放电电压 （配置量）";
CM_ SG_ 2336878246 M2P_PermitMaxPow_Chg_B11_22 "汇流排11最大允许充电功率";
CM_ SG_ 2336878246 M2P_PermitMaxPow_DisChg_B11_22 "汇流排11最大允许放电功率";
CM_ SG_ 2336878247 M2P_PermitMaxVolt_B11_23 "汇流排11最高允许充电电压 （配置量）";
CM_ SG_ 2336878247 M2P_PermitMinVolt_B11_23 "汇流排11最低允许放电电压 （配置量）";
CM_ SG_ 2336878247 M2P_PermitMaxPow_Chg_B11_23 "汇流排11最大允许充电功率";
CM_ SG_ 2336878247 M2P_PermitMaxPow_DisChg_B11_23 "汇流排11最大允许放电功率";
CM_ SG_ 2336878248 M2P_PermitMaxVolt_B11_24 "汇流排11最高允许充电电压 （配置量）";
CM_ SG_ 2336878248 M2P_PermitMinVolt_B11_24 "汇流排11最低允许放电电压 （配置量）";
CM_ SG_ 2336878248 M2P_PermitMaxPow_Chg_B11_24 "汇流排11最大允许充电功率";
CM_ SG_ 2336878248 M2P_PermitMaxPow_DisChg_B11_24 "汇流排11最大允许放电功率";
CM_ SG_ 2336878249 M2P_PermitMaxVolt_B11_25 "汇流排11最高允许充电电压 （配置量）";
CM_ SG_ 2336878249 M2P_PermitMinVolt_B11_25 "汇流排11最低允许放电电压 （配置量）";
CM_ SG_ 2336878249 M2P_PermitMaxPow_Chg_B11_25 "汇流排11最大允许充电功率";
CM_ SG_ 2336878249 M2P_PermitMaxPow_DisChg_B11_25 "汇流排11最大允许放电功率";
CM_ SG_ 2336878250 M2P_PermitMaxVolt_B11_26 "汇流排11最高允许充电电压 （配置量）";
CM_ SG_ 2336878250 M2P_PermitMinVolt_B11_26 "汇流排11最低允许放电电压 （配置量）";
CM_ SG_ 2336878250 M2P_PermitMaxPow_Chg_B11_26 "汇流排11最大允许充电功率";
CM_ SG_ 2336878250 M2P_PermitMaxPow_DisChg_B11_26 "汇流排11最大允许放电功率";
CM_ SG_ 2336878251 M2P_PermitMaxVolt_B11_27 "汇流排11最高允许充电电压 （配置量）";
CM_ SG_ 2336878251 M2P_PermitMinVolt_B11_27 "汇流排11最低允许放电电压 （配置量）";
CM_ SG_ 2336878251 M2P_PermitMaxPow_Chg_B11_27 "汇流排11最大允许充电功率";
CM_ SG_ 2336878251 M2P_PermitMaxPow_DisChg_B11_27 "汇流排11最大允许放电功率";
CM_ SG_ 2336878252 M2P_PermitMaxVolt_B11_28 "汇流排11最高允许充电电压 （配置量）";
CM_ SG_ 2336878252 M2P_PermitMinVolt_B11_28 "汇流排11最低允许放电电压 （配置量）";
CM_ SG_ 2336878252 M2P_PermitMaxPow_Chg_B11_28 "汇流排11最大允许充电功率";
CM_ SG_ 2336878252 M2P_PermitMaxPow_DisChg_B11_28 "汇流排11最大允许放电功率";
CM_ SG_ 2336878253 M2P_PermitMaxVolt_B11_29 "汇流排11最高允许充电电压 （配置量）";
CM_ SG_ 2336878253 M2P_PermitMinVolt_B11_29 "汇流排11最低允许放电电压 （配置量）";
CM_ SG_ 2336878253 M2P_PermitMaxPow_Chg_B11_29 "汇流排11最大允许充电功率";
CM_ SG_ 2336878253 M2P_PermitMaxPow_DisChg_B11_29 "汇流排11最大允许放电功率";
CM_ SG_ 2336878254 M2P_PermitMaxVolt_B11_30 "汇流排11最高允许充电电压 （配置量）";
CM_ SG_ 2336878254 M2P_PermitMinVolt_B11_30 "汇流排11最低允许放电电压 （配置量）";
CM_ SG_ 2336878254 M2P_PermitMaxPow_Chg_B11_30 "汇流排11最大允许充电功率";
CM_ SG_ 2336878254 M2P_PermitMaxPow_DisChg_B11_30 "汇流排11最大允许放电功率";
CM_ SG_ 2336878255 M2P_PermitMaxVolt_B11_31 "汇流排11最高允许充电电压 （配置量）";
CM_ SG_ 2336878255 M2P_PermitMinVolt_B11_31 "汇流排11最低允许放电电压 （配置量）";
CM_ SG_ 2336878255 M2P_PermitMaxPow_Chg_B11_31 "汇流排11最大允许充电功率";
CM_ SG_ 2336878255 M2P_PermitMaxPow_DisChg_B11_31 "汇流排11最大允许放电功率";
CM_ SG_ 2336943761 M2P_Power_B11_01 "汇流排11实时功率";
CM_ SG_ 2336943761 M2P_SysremEngy_Chg_B11_01 "汇流排11充电剩余能量";
CM_ SG_ 2336943761 M2P_SysremEngy_DisChg_B11_01 "汇流排11放电剩余能量";
CM_ SG_ 2336943761 M2P_SysMaxVolt_B11_01 "汇流排11单体最大电压  ";
CM_ SG_ 2336943762 M2P_Power_B11_02 "汇流排11实时功率";
CM_ SG_ 2336943762 M2P_SysremEngy_Chg_B11_02 "汇流排11充电剩余能量";
CM_ SG_ 2336943762 M2P_SysremEngy_DisChg_B11_02 "汇流排11放电剩余能量";
CM_ SG_ 2336943762 M2P_SysMaxVolt_B11_02 "汇流排11单体最大电压  ";
CM_ SG_ 2336943763 M2P_Power_B11_03 "汇流排11实时功率";
CM_ SG_ 2336943763 M2P_SysremEngy_Chg_B11_03 "汇流排11充电剩余能量";
CM_ SG_ 2336943763 M2P_SysremEngy_DisChg_B11_03 "汇流排11放电剩余能量";
CM_ SG_ 2336943763 M2P_SysMaxVolt_B11_03 "汇流排11单体最大电压  ";
CM_ SG_ 2336943764 M2P_Power_B11_04 "汇流排11实时功率";
CM_ SG_ 2336943764 M2P_SysremEngy_Chg_B11_04 "汇流排11充电剩余能量";
CM_ SG_ 2336943764 M2P_SysremEngy_DisChg_B11_04 "汇流排11放电剩余能量";
CM_ SG_ 2336943764 M2P_SysMaxVolt_B11_04 "汇流排11单体最大电压  ";
CM_ SG_ 2336943765 M2P_Power_B11_05 "汇流排11实时功率";
CM_ SG_ 2336943765 M2P_SysremEngy_Chg_B11_05 "汇流排11充电剩余能量";
CM_ SG_ 2336943765 M2P_SysremEngy_DisChg_B11_05 "汇流排11放电剩余能量";
CM_ SG_ 2336943765 M2P_SysMaxVolt_B11_05 "汇流排11单体最大电压  ";
CM_ SG_ 2336943766 M2P_Power_B11_06 "汇流排11实时功率";
CM_ SG_ 2336943766 M2P_SysremEngy_Chg_B11_06 "汇流排11充电剩余能量";
CM_ SG_ 2336943766 M2P_SysremEngy_DisChg_B11_06 "汇流排11放电剩余能量";
CM_ SG_ 2336943766 M2P_SysMaxVolt_B11_06 "汇流排11单体最大电压  ";
CM_ SG_ 2336943767 M2P_Power_B11_07 "汇流排11实时功率";
CM_ SG_ 2336943767 M2P_SysremEngy_Chg_B11_07 "汇流排11充电剩余能量";
CM_ SG_ 2336943767 M2P_SysremEngy_DisChg_B11_07 "汇流排11放电剩余能量";
CM_ SG_ 2336943767 M2P_SysMaxVolt_B11_07 "汇流排11单体最大电压  ";
CM_ SG_ 2336943768 M2P_Power_B11_08 "汇流排11实时功率";
CM_ SG_ 2336943768 M2P_SysremEngy_Chg_B11_08 "汇流排11充电剩余能量";
CM_ SG_ 2336943768 M2P_SysremEngy_DisChg_B11_08 "汇流排11放电剩余能量";
CM_ SG_ 2336943768 M2P_SysMaxVolt_B11_08 "汇流排11单体最大电压  ";
CM_ SG_ 2336943769 M2P_Power_B11_09 "汇流排11实时功率";
CM_ SG_ 2336943769 M2P_SysremEngy_Chg_B11_09 "汇流排11充电剩余能量";
CM_ SG_ 2336943769 M2P_SysremEngy_DisChg_B11_09 "汇流排11放电剩余能量";
CM_ SG_ 2336943769 M2P_SysMaxVolt_B11_09 "汇流排11单体最大电压  ";
CM_ SG_ 2336943770 M2P_Power_B11_10 "汇流排11实时功率";
CM_ SG_ 2336943770 M2P_SysremEngy_Chg_B11_10 "汇流排11充电剩余能量";
CM_ SG_ 2336943770 M2P_SysremEngy_DisChg_B11_10 "汇流排11放电剩余能量";
CM_ SG_ 2336943770 M2P_SysMaxVolt_B11_10 "汇流排11单体最大电压  ";
CM_ SG_ 2336943771 M2P_Power_B11_11 "汇流排11实时功率";
CM_ SG_ 2336943771 M2P_SysremEngy_Chg_B11_11 "汇流排11充电剩余能量";
CM_ SG_ 2336943771 M2P_SysremEngy_DisChg_B11_11 "汇流排11放电剩余能量";
CM_ SG_ 2336943771 M2P_SysMaxVolt_B11_11 "汇流排11单体最大电压  ";
CM_ SG_ 2336943772 M2P_Power_B11_12 "汇流排11实时功率";
CM_ SG_ 2336943772 M2P_SysremEngy_Chg_B11_12 "汇流排11充电剩余能量";
CM_ SG_ 2336943772 M2P_SysremEngy_DisChg_B11_12 "汇流排11放电剩余能量";
CM_ SG_ 2336943772 M2P_SysMaxVolt_B11_12 "汇流排11单体最大电压  ";
CM_ SG_ 2336943773 M2P_Power_B11_13 "汇流排11实时功率";
CM_ SG_ 2336943773 M2P_SysremEngy_Chg_B11_13 "汇流排11充电剩余能量";
CM_ SG_ 2336943773 M2P_SysremEngy_DisChg_B11_13 "汇流排11放电剩余能量";
CM_ SG_ 2336943773 M2P_SysMaxVolt_B11_13 "汇流排11单体最大电压  ";
CM_ SG_ 2336943774 M2P_Power_B11_14 "汇流排11实时功率";
CM_ SG_ 2336943774 M2P_SysremEngy_Chg_B11_14 "汇流排11充电剩余能量";
CM_ SG_ 2336943774 M2P_SysremEngy_DisChg_B11_14 "汇流排11放电剩余能量";
CM_ SG_ 2336943774 M2P_SysMaxVolt_B11_14 "汇流排11单体最大电压  ";
CM_ SG_ 2336943775 M2P_Power_B11_15 "汇流排11实时功率";
CM_ SG_ 2336943775 M2P_SysremEngy_Chg_B11_15 "汇流排11充电剩余能量";
CM_ SG_ 2336943775 M2P_SysremEngy_DisChg_B11_15 "汇流排11放电剩余能量";
CM_ SG_ 2336943775 M2P_SysMaxVolt_B11_15 "汇流排11单体最大电压  ";
CM_ SG_ 2336943776 M2P_Power_B11_16 "汇流排11实时功率";
CM_ SG_ 2336943776 M2P_SysremEngy_Chg_B11_16 "汇流排11充电剩余能量";
CM_ SG_ 2336943776 M2P_SysremEngy_DisChg_B11_16 "汇流排11放电剩余能量";
CM_ SG_ 2336943776 M2P_SysMaxVolt_B11_16 "汇流排11单体最大电压  ";
CM_ SG_ 2336943777 M2P_Power_B11_17 "汇流排11实时功率";
CM_ SG_ 2336943777 M2P_SysremEngy_Chg_B11_17 "汇流排11充电剩余能量";
CM_ SG_ 2336943777 M2P_SysremEngy_DisChg_B11_17 "汇流排11放电剩余能量";
CM_ SG_ 2336943777 M2P_SysMaxVolt_B11_17 "汇流排11单体最大电压  ";
CM_ SG_ 2336943778 M2P_Power_B11_18 "汇流排11实时功率";
CM_ SG_ 2336943778 M2P_SysremEngy_Chg_B11_18 "汇流排11充电剩余能量";
CM_ SG_ 2336943778 M2P_SysremEngy_DisChg_B11_18 "汇流排11放电剩余能量";
CM_ SG_ 2336943778 M2P_SysMaxVolt_B11_18 "汇流排11单体最大电压  ";
CM_ SG_ 2336943779 M2P_Power_B11_19 "汇流排11实时功率";
CM_ SG_ 2336943779 M2P_SysremEngy_Chg_B11_19 "汇流排11充电剩余能量";
CM_ SG_ 2336943779 M2P_SysremEngy_DisChg_B11_19 "汇流排11放电剩余能量";
CM_ SG_ 2336943779 M2P_SysMaxVolt_B11_19 "汇流排11单体最大电压  ";
CM_ SG_ 2336943780 M2P_Power_B11_20 "汇流排11实时功率";
CM_ SG_ 2336943780 M2P_SysremEngy_Chg_B11_20 "汇流排11充电剩余能量";
CM_ SG_ 2336943780 M2P_SysremEngy_DisChg_B11_20 "汇流排11放电剩余能量";
CM_ SG_ 2336943780 M2P_SysMaxVolt_B11_20 "汇流排11单体最大电压  ";
CM_ SG_ 2336943781 M2P_Power_B11_21 "汇流排11实时功率";
CM_ SG_ 2336943781 M2P_SysremEngy_Chg_B11_21 "汇流排11充电剩余能量";
CM_ SG_ 2336943781 M2P_SysremEngy_DisChg_B11_21 "汇流排11放电剩余能量";
CM_ SG_ 2336943781 M2P_SysMaxVolt_B11_21 "汇流排11单体最大电压  ";
CM_ SG_ 2336943782 M2P_Power_B11_22 "汇流排11实时功率";
CM_ SG_ 2336943782 M2P_SysremEngy_Chg_B11_22 "汇流排11充电剩余能量";
CM_ SG_ 2336943782 M2P_SysremEngy_DisChg_B11_22 "汇流排11放电剩余能量";
CM_ SG_ 2336943782 M2P_SysMaxVolt_B11_22 "汇流排11单体最大电压  ";
CM_ SG_ 2336943783 M2P_Power_B11_23 "汇流排11实时功率";
CM_ SG_ 2336943783 M2P_SysremEngy_Chg_B11_23 "汇流排11充电剩余能量";
CM_ SG_ 2336943783 M2P_SysremEngy_DisChg_B11_23 "汇流排11放电剩余能量";
CM_ SG_ 2336943783 M2P_SysMaxVolt_B11_23 "汇流排11单体最大电压  ";
CM_ SG_ 2336943784 M2P_Power_B11_24 "汇流排11实时功率";
CM_ SG_ 2336943784 M2P_SysremEngy_Chg_B11_24 "汇流排11充电剩余能量";
CM_ SG_ 2336943784 M2P_SysremEngy_DisChg_B11_24 "汇流排11放电剩余能量";
CM_ SG_ 2336943784 M2P_SysMaxVolt_B11_24 "汇流排11单体最大电压  ";
CM_ SG_ 2336943785 M2P_Power_B11_25 "汇流排11实时功率";
CM_ SG_ 2336943785 M2P_SysremEngy_Chg_B11_25 "汇流排11充电剩余能量";
CM_ SG_ 2336943785 M2P_SysremEngy_DisChg_B11_25 "汇流排11放电剩余能量";
CM_ SG_ 2336943785 M2P_SysMaxVolt_B11_25 "汇流排11单体最大电压  ";
CM_ SG_ 2336943786 M2P_Power_B11_26 "汇流排11实时功率";
CM_ SG_ 2336943786 M2P_SysremEngy_Chg_B11_26 "汇流排11充电剩余能量";
CM_ SG_ 2336943786 M2P_SysremEngy_DisChg_B11_26 "汇流排11放电剩余能量";
CM_ SG_ 2336943786 M2P_SysMaxVolt_B11_26 "汇流排11单体最大电压  ";
CM_ SG_ 2336943787 M2P_Power_B11_27 "汇流排11实时功率";
CM_ SG_ 2336943787 M2P_SysremEngy_Chg_B11_27 "汇流排11充电剩余能量";
CM_ SG_ 2336943787 M2P_SysremEngy_DisChg_B11_27 "汇流排11放电剩余能量";
CM_ SG_ 2336943787 M2P_SysMaxVolt_B11_27 "汇流排11单体最大电压  ";
CM_ SG_ 2336943788 M2P_Power_B11_28 "汇流排11实时功率";
CM_ SG_ 2336943788 M2P_SysremEngy_Chg_B11_28 "汇流排11充电剩余能量";
CM_ SG_ 2336943788 M2P_SysremEngy_DisChg_B11_28 "汇流排11放电剩余能量";
CM_ SG_ 2336943788 M2P_SysMaxVolt_B11_28 "汇流排11单体最大电压  ";
CM_ SG_ 2336943789 M2P_Power_B11_29 "汇流排11实时功率";
CM_ SG_ 2336943789 M2P_SysremEngy_Chg_B11_29 "汇流排11充电剩余能量";
CM_ SG_ 2336943789 M2P_SysremEngy_DisChg_B11_29 "汇流排11放电剩余能量";
CM_ SG_ 2336943789 M2P_SysMaxVolt_B11_29 "汇流排11单体最大电压  ";
CM_ SG_ 2336943790 M2P_Power_B11_30 "汇流排11实时功率";
CM_ SG_ 2336943790 M2P_SysremEngy_Chg_B11_30 "汇流排11充电剩余能量";
CM_ SG_ 2336943790 M2P_SysremEngy_DisChg_B11_30 "汇流排11放电剩余能量";
CM_ SG_ 2336943790 M2P_SysMaxVolt_B11_30 "汇流排11单体最大电压  ";
CM_ SG_ 2336943791 M2P_Power_B11_31 "汇流排11实时功率";
CM_ SG_ 2336943791 M2P_SysremEngy_Chg_B11_31 "汇流排11充电剩余能量";
CM_ SG_ 2336943791 M2P_SysremEngy_DisChg_B11_31 "汇流排11放电剩余能量";
CM_ SG_ 2336943791 M2P_SysMaxVolt_B11_31 "汇流排11单体最大电压  ";
CM_ SG_ 2337009297 M2P_SysMinVolt_B11_01 "汇流排11单体最小电压";
CM_ SG_ 2337009297 M2P_SysAvgVolt_B11_01 "汇流排11单体平均电压";
CM_ SG_ 2337009297 M2P_BMS_Status_B11 "汇流排11能量状态";
CM_ SG_ 2337009297 M2P_SOC_B11 "汇流排11系统SOC";
CM_ SG_ 2337009297 M2P_SOH_B11 "汇流排11系统SOH";
CM_ SG_ 2337009297 Reserved_01 "预留";
CM_ SG_ 2337009298 M2P_SysMinVolt_B11_02 "汇流排11单体最小电压";
CM_ SG_ 2337009298 M2P_SysAvgVolt_B11_02 "汇流排11单体平均电压";
CM_ SG_ 2337009298 M2P_BMS_Status_B11 "汇流排11能量状态";
CM_ SG_ 2337009298 M2P_SOC_B11 "汇流排11系统SOC";
CM_ SG_ 2337009298 M2P_SOH_B11 "汇流排11系统SOH";
CM_ SG_ 2337009298 Reserved_02 "预留";
CM_ SG_ 2337009299 M2P_SysMinVolt_B11_03 "汇流排11单体最小电压";
CM_ SG_ 2337009299 M2P_SysAvgVolt_B11_03 "汇流排11单体平均电压";
CM_ SG_ 2337009299 M2P_BMS_Status_B11 "汇流排11能量状态";
CM_ SG_ 2337009299 M2P_SOC_B11 "汇流排11系统SOC";
CM_ SG_ 2337009299 M2P_SOH_B11 "汇流排11系统SOH";
CM_ SG_ 2337009299 Reserved_03 "预留";
CM_ SG_ 2337009300 M2P_SysMinVolt_B11_04 "汇流排11单体最小电压";
CM_ SG_ 2337009300 M2P_SysAvgVolt_B11_04 "汇流排11单体平均电压";
CM_ SG_ 2337009300 M2P_BMS_Status_B11 "汇流排11能量状态";
CM_ SG_ 2337009300 M2P_SOC_B11 "汇流排11系统SOC";
CM_ SG_ 2337009300 M2P_SOH_B11 "汇流排11系统SOH";
CM_ SG_ 2337009300 Reserved_04 "预留";
CM_ SG_ 2337009301 M2P_SysMinVolt_B11_05 "汇流排11单体最小电压";
CM_ SG_ 2337009301 M2P_SysAvgVolt_B11_05 "汇流排11单体平均电压";
CM_ SG_ 2337009301 M2P_BMS_Status_B11 "汇流排11能量状态";
CM_ SG_ 2337009301 M2P_SOC_B11 "汇流排11系统SOC";
CM_ SG_ 2337009301 M2P_SOH_B11 "汇流排11系统SOH";
CM_ SG_ 2337009301 Reserved_05 "预留";
CM_ SG_ 2337009302 M2P_SysMinVolt_B11_06 "汇流排11单体最小电压";
CM_ SG_ 2337009302 M2P_SysAvgVolt_B11_06 "汇流排11单体平均电压";
CM_ SG_ 2337009302 M2P_BMS_Status_B11 "汇流排11能量状态";
CM_ SG_ 2337009302 M2P_SOC_B11 "汇流排11系统SOC";
CM_ SG_ 2337009302 M2P_SOH_B11 "汇流排11系统SOH";
CM_ SG_ 2337009302 Reserved_06 "预留";
CM_ SG_ 2337009303 M2P_SysMinVolt_B11_07 "汇流排11单体最小电压";
CM_ SG_ 2337009303 M2P_SysAvgVolt_B11_07 "汇流排11单体平均电压";
CM_ SG_ 2337009303 M2P_BMS_Status_B11 "汇流排11能量状态";
CM_ SG_ 2337009303 M2P_SOC_B11 "汇流排11系统SOC";
CM_ SG_ 2337009303 M2P_SOH_B11 "汇流排11系统SOH";
CM_ SG_ 2337009303 Reserved_07 "预留";
CM_ SG_ 2337009304 M2P_SysMinVolt_B11_08 "汇流排11单体最小电压";
CM_ SG_ 2337009304 M2P_SysAvgVolt_B11_08 "汇流排11单体平均电压";
CM_ SG_ 2337009304 M2P_BMS_Status_B11 "汇流排11能量状态";
CM_ SG_ 2337009304 M2P_SOC_B11 "汇流排11系统SOC";
CM_ SG_ 2337009304 M2P_SOH_B11 "汇流排11系统SOH";
CM_ SG_ 2337009304 Reserved_08 "预留";
CM_ SG_ 2337009305 M2P_SysMinVolt_B11_09 "汇流排11单体最小电压";
CM_ SG_ 2337009305 M2P_SysAvgVolt_B11_09 "汇流排11单体平均电压";
CM_ SG_ 2337009305 M2P_BMS_Status_B11 "汇流排11能量状态";
CM_ SG_ 2337009305 M2P_SOC_B11 "汇流排11系统SOC";
CM_ SG_ 2337009305 M2P_SOH_B11 "汇流排11系统SOH";
CM_ SG_ 2337009305 Reserved_09 "预留";
CM_ SG_ 2337009306 M2P_SysMinVolt_B11_10 "汇流排11单体最小电压";
CM_ SG_ 2337009306 M2P_SysAvgVolt_B11_10 "汇流排11单体平均电压";
CM_ SG_ 2337009306 M2P_BMS_Status_B11 "汇流排11能量状态";
CM_ SG_ 2337009306 M2P_SOC_B11 "汇流排11系统SOC";
CM_ SG_ 2337009306 M2P_SOH_B11 "汇流排11系统SOH";
CM_ SG_ 2337009306 Reserved_10 "预留";
CM_ SG_ 2337009307 M2P_SysMinVolt_B11_11 "汇流排11单体最小电压";
CM_ SG_ 2337009307 M2P_SysAvgVolt_B11_11 "汇流排11单体平均电压";
CM_ SG_ 2337009307 M2P_BMS_Status_B11 "汇流排11能量状态";
CM_ SG_ 2337009307 M2P_SOC_B11 "汇流排11系统SOC";
CM_ SG_ 2337009307 M2P_SOH_B11 "汇流排11系统SOH";
CM_ SG_ 2337009307 Reserved_11 "预留";
CM_ SG_ 2337009308 M2P_SysMinVolt_B11_12 "汇流排11单体最小电压";
CM_ SG_ 2337009308 M2P_SysAvgVolt_B11_12 "汇流排11单体平均电压";
CM_ SG_ 2337009308 M2P_BMS_Status_B11 "汇流排11能量状态";
CM_ SG_ 2337009308 M2P_SOC_B11 "汇流排11系统SOC";
CM_ SG_ 2337009308 M2P_SOH_B11 "汇流排11系统SOH";
CM_ SG_ 2337009308 Reserved_12 "预留";
CM_ SG_ 2337009309 M2P_SysMinVolt_B11_13 "汇流排11单体最小电压";
CM_ SG_ 2337009309 M2P_SysAvgVolt_B11_13 "汇流排11单体平均电压";
CM_ SG_ 2337009309 M2P_BMS_Status_B11 "汇流排11能量状态";
CM_ SG_ 2337009309 M2P_SOC_B11 "汇流排11系统SOC";
CM_ SG_ 2337009309 M2P_SOH_B11 "汇流排11系统SOH";
CM_ SG_ 2337009309 Reserved_13 "预留";
CM_ SG_ 2337009310 M2P_SysMinVolt_B11_14 "汇流排11单体最小电压";
CM_ SG_ 2337009310 M2P_SysAvgVolt_B11_14 "汇流排11单体平均电压";
CM_ SG_ 2337009310 M2P_BMS_Status_B11 "汇流排11能量状态";
CM_ SG_ 2337009310 M2P_SOC_B11 "汇流排11系统SOC";
CM_ SG_ 2337009310 M2P_SOH_B11 "汇流排11系统SOH";
CM_ SG_ 2337009310 Reserved_14 "预留";
CM_ SG_ 2337009311 M2P_SysMinVolt_B11_15 "汇流排11单体最小电压";
CM_ SG_ 2337009311 M2P_SysAvgVolt_B11_15 "汇流排11单体平均电压";
CM_ SG_ 2337009311 M2P_BMS_Status_B11 "汇流排11能量状态";
CM_ SG_ 2337009311 M2P_SOC_B11 "汇流排11系统SOC";
CM_ SG_ 2337009311 M2P_SOH_B11 "汇流排11系统SOH";
CM_ SG_ 2337009311 Reserved_15 "预留";
CM_ SG_ 2337009312 M2P_SysMinVolt_B11_16 "汇流排11单体最小电压";
CM_ SG_ 2337009312 M2P_SysAvgVolt_B11_16 "汇流排11单体平均电压";
CM_ SG_ 2337009312 M2P_BMS_Status_B11 "汇流排11能量状态";
CM_ SG_ 2337009312 M2P_SOC_B11 "汇流排11系统SOC";
CM_ SG_ 2337009312 M2P_SOH_B11 "汇流排11系统SOH";
CM_ SG_ 2337009312 Reserved_16 "预留";
CM_ SG_ 2337009313 M2P_SysMinVolt_B11_17 "汇流排11单体最小电压";
CM_ SG_ 2337009313 M2P_SysAvgVolt_B11_17 "汇流排11单体平均电压";
CM_ SG_ 2337009313 M2P_BMS_Status_B11 "汇流排11能量状态";
CM_ SG_ 2337009313 M2P_SOC_B11 "汇流排11系统SOC";
CM_ SG_ 2337009313 M2P_SOH_B11 "汇流排11系统SOH";
CM_ SG_ 2337009313 Reserved_17 "预留";
CM_ SG_ 2337009314 M2P_SysMinVolt_B11_18 "汇流排11单体最小电压";
CM_ SG_ 2337009314 M2P_SysAvgVolt_B11_18 "汇流排11单体平均电压";
CM_ SG_ 2337009314 M2P_BMS_Status_B11 "汇流排11能量状态";
CM_ SG_ 2337009314 M2P_SOC_B11 "汇流排11系统SOC";
CM_ SG_ 2337009314 M2P_SOH_B11 "汇流排11系统SOH";
CM_ SG_ 2337009314 Reserved_18 "预留";
CM_ SG_ 2337009315 M2P_SysMinVolt_B11_19 "汇流排11单体最小电压";
CM_ SG_ 2337009315 M2P_SysAvgVolt_B11_19 "汇流排11单体平均电压";
CM_ SG_ 2337009315 M2P_BMS_Status_B11 "汇流排11能量状态";
CM_ SG_ 2337009315 M2P_SOC_B11 "汇流排11系统SOC";
CM_ SG_ 2337009315 M2P_SOH_B11 "汇流排11系统SOH";
CM_ SG_ 2337009315 Reserved_19 "预留";
CM_ SG_ 2337009316 M2P_SysMinVolt_B11_20 "汇流排11单体最小电压";
CM_ SG_ 2337009316 M2P_SysAvgVolt_B11_20 "汇流排11单体平均电压";
CM_ SG_ 2337009316 M2P_BMS_Status_B11 "汇流排11能量状态";
CM_ SG_ 2337009316 M2P_SOC_B11 "汇流排11系统SOC";
CM_ SG_ 2337009316 M2P_SOH_B11 "汇流排11系统SOH";
CM_ SG_ 2337009316 Reserved_20 "预留";
CM_ SG_ 2337009317 M2P_SysMinVolt_B11_21 "汇流排11单体最小电压";
CM_ SG_ 2337009317 M2P_SysAvgVolt_B11_21 "汇流排11单体平均电压";
CM_ SG_ 2337009317 M2P_BMS_Status_B11 "汇流排11能量状态";
CM_ SG_ 2337009317 M2P_SOC_B11 "汇流排11系统SOC";
CM_ SG_ 2337009317 M2P_SOH_B11 "汇流排11系统SOH";
CM_ SG_ 2337009317 Reserved_21 "预留";
CM_ SG_ 2337009318 M2P_SysMinVolt_B11_22 "汇流排11单体最小电压";
CM_ SG_ 2337009318 M2P_SysAvgVolt_B11_22 "汇流排11单体平均电压";
CM_ SG_ 2337009318 M2P_BMS_Status_B11 "汇流排11能量状态";
CM_ SG_ 2337009318 M2P_SOC_B11 "汇流排11系统SOC";
CM_ SG_ 2337009318 M2P_SOH_B11 "汇流排11系统SOH";
CM_ SG_ 2337009318 Reserved_22 "预留";
CM_ SG_ 2337009319 M2P_SysMinVolt_B11_23 "汇流排11单体最小电压";
CM_ SG_ 2337009319 M2P_SysAvgVolt_B11_23 "汇流排11单体平均电压";
CM_ SG_ 2337009319 M2P_BMS_Status_B11 "汇流排11能量状态";
CM_ SG_ 2337009319 M2P_SOC_B11 "汇流排11系统SOC";
CM_ SG_ 2337009319 M2P_SOH_B11 "汇流排11系统SOH";
CM_ SG_ 2337009319 Reserved_23 "预留";
CM_ SG_ 2337009320 M2P_SysMinVolt_B11_24 "汇流排11单体最小电压";
CM_ SG_ 2337009320 M2P_SysAvgVolt_B11_24 "汇流排11单体平均电压";
CM_ SG_ 2337009320 M2P_BMS_Status_B11 "汇流排11能量状态";
CM_ SG_ 2337009320 M2P_SOC_B11 "汇流排11系统SOC";
CM_ SG_ 2337009320 M2P_SOH_B11 "汇流排11系统SOH";
CM_ SG_ 2337009320 Reserved_24 "预留";
CM_ SG_ 2337009321 M2P_SysMinVolt_B11_25 "汇流排11单体最小电压";
CM_ SG_ 2337009321 M2P_SysAvgVolt_B11_25 "汇流排11单体平均电压";
CM_ SG_ 2337009321 M2P_BMS_Status_B11 "汇流排11能量状态";
CM_ SG_ 2337009321 M2P_SOC_B11 "汇流排11系统SOC";
CM_ SG_ 2337009321 M2P_SOH_B11 "汇流排11系统SOH";
CM_ SG_ 2337009321 Reserved_25 "预留";
CM_ SG_ 2337009322 M2P_SysMinVolt_B11_26 "汇流排11单体最小电压";
CM_ SG_ 2337009322 M2P_SysAvgVolt_B11_26 "汇流排11单体平均电压";
CM_ SG_ 2337009322 M2P_BMS_Status_B11 "汇流排11能量状态";
CM_ SG_ 2337009322 M2P_SOC_B11 "汇流排11系统SOC";
CM_ SG_ 2337009322 M2P_SOH_B11 "汇流排11系统SOH";
CM_ SG_ 2337009322 Reserved_26 "预留";
CM_ SG_ 2337009323 M2P_SysMinVolt_B11_27 "汇流排11单体最小电压";
CM_ SG_ 2337009323 M2P_SysAvgVolt_B11_27 "汇流排11单体平均电压";
CM_ SG_ 2337009323 M2P_BMS_Status_B11 "汇流排11能量状态";
CM_ SG_ 2337009323 M2P_SOC_B11 "汇流排11系统SOC";
CM_ SG_ 2337009323 M2P_SOH_B11 "汇流排11系统SOH";
CM_ SG_ 2337009323 Reserved_27 "预留";
CM_ SG_ 2337009324 M2P_SysMinVolt_B11_28 "汇流排11单体最小电压";
CM_ SG_ 2337009324 M2P_SysAvgVolt_B11_28 "汇流排11单体平均电压";
CM_ SG_ 2337009324 M2P_BMS_Status_B11 "汇流排11能量状态";
CM_ SG_ 2337009324 M2P_SOC_B11 "汇流排11系统SOC";
CM_ SG_ 2337009324 M2P_SOH_B11 "汇流排11系统SOH";
CM_ SG_ 2337009324 Reserved_28 "预留";
CM_ SG_ 2337009325 M2P_SysMinVolt_B11_29 "汇流排11单体最小电压";
CM_ SG_ 2337009325 M2P_SysAvgVolt_B11_29 "汇流排11单体平均电压";
CM_ SG_ 2337009325 M2P_BMS_Status_B11 "汇流排11能量状态";
CM_ SG_ 2337009325 M2P_SOC_B11 "汇流排11系统SOC";
CM_ SG_ 2337009325 M2P_SOH_B11 "汇流排11系统SOH";
CM_ SG_ 2337009325 Reserved_29 "预留";
CM_ SG_ 2337009326 M2P_SysMinVolt_B11_30 "汇流排11单体最小电压";
CM_ SG_ 2337009326 M2P_SysAvgVolt_B11_30 "汇流排11单体平均电压";
CM_ SG_ 2337009326 M2P_BMS_Status_B11 "汇流排11能量状态";
CM_ SG_ 2337009326 M2P_SOC_B11 "汇流排11系统SOC";
CM_ SG_ 2337009326 M2P_SOH_B11 "汇流排11系统SOH";
CM_ SG_ 2337009326 Reserved_30 "预留";
CM_ SG_ 2337009327 M2P_SysMinVolt_B11_31 "汇流排11单体最小电压";
CM_ SG_ 2337009327 M2P_SysAvgVolt_B11_31 "汇流排11单体平均电压";
CM_ SG_ 2337009327 M2P_BMS_Status_B11 "汇流排11能量状态";
CM_ SG_ 2337009327 M2P_SOC_B11 "汇流排11系统SOC";
CM_ SG_ 2337009327 M2P_SOH_B11 "汇流排11系统SOH";
CM_ SG_ 2337009327 Reserved_31 "预留";
CM_ SG_ 2337074833 M2P_SOE_Charge_B11 "汇流排11系可充电SOE";
CM_ SG_ 2337074833 M2P_SOE_Discharge_B11 "汇流排11系可放电SOE";
CM_ SG_ 2337074833 Reserved_01 "预留";
VAL_ 2336485024 M2P_Measure_Vol_B10_16 65535 "Invalid" ;
VAL_ 2336485024 M2P_Current_B10_16 65535 "Invalid" ;
VAL_ 2336485024 M2P_PermitMaxCharge_I_B10_16 65535 "Invalid" ;
VAL_ 2336485024 M2P_PermitMaxDisCharge_I_B10_16 65535 "Invalid" ;
VAL_ 2336485025 M2P_Measure_Vol_B10_17 65535 "Invalid" ;
VAL_ 2336485025 M2P_Current_B10_17 65535 "Invalid" ;
VAL_ 2336485025 M2P_PermitMaxCharge_I_B10_17 65535 "Invalid" ;
VAL_ 2336485025 M2P_PermitMaxDisCharge_I_B10_17 65535 "Invalid" ;
VAL_ 2336485026 M2P_Measure_Vol_B10_18 65535 "Invalid" ;
VAL_ 2336485026 M2P_Current_B10_18 65535 "Invalid" ;
VAL_ 2336485026 M2P_PermitMaxCharge_I_B10_18 65535 "Invalid" ;
VAL_ 2336485026 M2P_PermitMaxDisCharge_I_B10_18 65535 "Invalid" ;
VAL_ 2336485027 M2P_Measure_Vol_B10_19 65535 "Invalid" ;
VAL_ 2336485027 M2P_Current_B10_19 65535 "Invalid" ;
VAL_ 2336485027 M2P_PermitMaxCharge_I_B10_19 65535 "Invalid" ;
VAL_ 2336485027 M2P_PermitMaxDisCharge_I_B10_19 65535 "Invalid" ;
VAL_ 2336485028 M2P_Measure_Vol_B10_20 65535 "Invalid" ;
VAL_ 2336485028 M2P_Current_B10_20 65535 "Invalid" ;
VAL_ 2336485028 M2P_PermitMaxCharge_I_B10_20 65535 "Invalid" ;
VAL_ 2336485028 M2P_PermitMaxDisCharge_I_B10_20 65535 "Invalid" ;
VAL_ 2336485029 M2P_Measure_Vol_B10_21 65535 "Invalid" ;
VAL_ 2336485029 M2P_Current_B10_21 65535 "Invalid" ;
VAL_ 2336485029 M2P_PermitMaxCharge_I_B10_21 65535 "Invalid" ;
VAL_ 2336485029 M2P_PermitMaxDisCharge_I_B10_21 65535 "Invalid" ;
VAL_ 2336485030 M2P_Measure_Vol_B10_22 65535 "Invalid" ;
VAL_ 2336485030 M2P_Current_B10_22 65535 "Invalid" ;
VAL_ 2336485030 M2P_PermitMaxCharge_I_B10_22 65535 "Invalid" ;
VAL_ 2336485030 M2P_PermitMaxDisCharge_I_B10_22 65535 "Invalid" ;
VAL_ 2336485031 M2P_Measure_Vol_B10_23 65535 "Invalid" ;
VAL_ 2336485031 M2P_Current_B10_23 65535 "Invalid" ;
VAL_ 2336485031 M2P_PermitMaxCharge_I_B10_23 65535 "Invalid" ;
VAL_ 2336485031 M2P_PermitMaxDisCharge_I_B10_23 65535 "Invalid" ;
VAL_ 2336485032 M2P_Measure_Vol_B10_24 65535 "Invalid" ;
VAL_ 2336485032 M2P_Current_B10_24 65535 "Invalid" ;
VAL_ 2336485032 M2P_PermitMaxCharge_I_B10_24 65535 "Invalid" ;
VAL_ 2336485032 M2P_PermitMaxDisCharge_I_B10_24 65535 "Invalid" ;
VAL_ 2336485033 M2P_Measure_Vol_B10_25 65535 "Invalid" ;
VAL_ 2336485033 M2P_Current_B10_25 65535 "Invalid" ;
VAL_ 2336485033 M2P_PermitMaxCharge_I_B10_25 65535 "Invalid" ;
VAL_ 2336485033 M2P_PermitMaxDisCharge_I_B10_25 65535 "Invalid" ;
VAL_ 2336485034 M2P_Measure_Vol_B10_26 65535 "Invalid" ;
VAL_ 2336485034 M2P_Current_B10_26 65535 "Invalid" ;
VAL_ 2336485034 M2P_PermitMaxCharge_I_B10_26 65535 "Invalid" ;
VAL_ 2336485034 M2P_PermitMaxDisCharge_I_B10_26 65535 "Invalid" ;
VAL_ 2336485035 M2P_Measure_Vol_B10_27 65535 "Invalid" ;
VAL_ 2336485035 M2P_Current_B10_27 65535 "Invalid" ;
VAL_ 2336485035 M2P_PermitMaxCharge_I_B10_27 65535 "Invalid" ;
VAL_ 2336485035 M2P_PermitMaxDisCharge_I_B10_27 65535 "Invalid" ;
VAL_ 2336485036 M2P_Measure_Vol_B10_28 65535 "Invalid" ;
VAL_ 2336485036 M2P_Current_B10_28 65535 "Invalid" ;
VAL_ 2336485036 M2P_PermitMaxCharge_I_B10_28 65535 "Invalid" ;
VAL_ 2336485036 M2P_PermitMaxDisCharge_I_B10_28 65535 "Invalid" ;
VAL_ 2336485037 M2P_Measure_Vol_B10_29 65535 "Invalid" ;
VAL_ 2336485037 M2P_Current_B10_29 65535 "Invalid" ;
VAL_ 2336485037 M2P_PermitMaxCharge_I_B10_29 65535 "Invalid" ;
VAL_ 2336485037 M2P_PermitMaxDisCharge_I_B10_29 65535 "Invalid" ;
VAL_ 2336485038 M2P_Measure_Vol_B10_30 65535 "Invalid" ;
VAL_ 2336485038 M2P_Current_B10_30 65535 "Invalid" ;
VAL_ 2336485038 M2P_PermitMaxCharge_I_B10_30 65535 "Invalid" ;
VAL_ 2336485038 M2P_PermitMaxDisCharge_I_B10_30 65535 "Invalid" ;
VAL_ 2336485039 M2P_Measure_Vol_B10_31 65535 "Invalid" ;
VAL_ 2336485039 M2P_Current_B10_31 65535 "Invalid" ;
VAL_ 2336485039 M2P_PermitMaxCharge_I_B10_31 65535 "Invalid" ;
VAL_ 2336485039 M2P_PermitMaxDisCharge_I_B10_31 65535 "Invalid" ;
VAL_ 2336616081 M2P_SysremEngy_Chg_B10_01 65535 "Invalid" ;
VAL_ 2336616081 M2P_SysremEngy_DisChg_B10_01 65535 "Invalid" ;
VAL_ 2336616082 M2P_SysremEngy_Chg_B10_02 65535 "Invalid" ;
VAL_ 2336616082 M2P_SysremEngy_DisChg_B10_02 65535 "Invalid" ;
VAL_ 2336616083 M2P_SysremEngy_Chg_B10_03 65535 "Invalid" ;
VAL_ 2336616083 M2P_SysremEngy_DisChg_B10_03 65535 "Invalid" ;
VAL_ 2336616084 M2P_SysremEngy_Chg_B10_04 65535 "Invalid" ;
VAL_ 2336616084 M2P_SysremEngy_DisChg_B10_04 65535 "Invalid" ;
VAL_ 2336616085 M2P_SysremEngy_Chg_B10_05 65535 "Invalid" ;
VAL_ 2336616085 M2P_SysremEngy_DisChg_B10_05 65535 "Invalid" ;
VAL_ 2336616086 M2P_SysremEngy_Chg_B10_06 65535 "Invalid" ;
VAL_ 2336616086 M2P_SysremEngy_DisChg_B10_06 65535 "Invalid" ;
VAL_ 2336616087 M2P_SysremEngy_Chg_B10_07 65535 "Invalid" ;
VAL_ 2336616087 M2P_SysremEngy_DisChg_B10_07 65535 "Invalid" ;
VAL_ 2336616088 M2P_SysremEngy_Chg_B10_08 65535 "Invalid" ;
VAL_ 2336616088 M2P_SysremEngy_DisChg_B10_08 65535 "Invalid" ;
VAL_ 2336616089 M2P_SysremEngy_Chg_B10_09 65535 "Invalid" ;
VAL_ 2336616089 M2P_SysremEngy_DisChg_B10_09 65535 "Invalid" ;
VAL_ 2336616090 M2P_SysremEngy_Chg_B10_10 65535 "Invalid" ;
VAL_ 2336616090 M2P_SysremEngy_DisChg_B10_10 65535 "Invalid" ;
VAL_ 2336616091 M2P_SysremEngy_Chg_B10_11 65535 "Invalid" ;
VAL_ 2336616091 M2P_SysremEngy_DisChg_B10_11 65535 "Invalid" ;
VAL_ 2336616092 M2P_SysremEngy_Chg_B10_12 65535 "Invalid" ;
VAL_ 2336616092 M2P_SysremEngy_DisChg_B10_12 65535 "Invalid" ;
VAL_ 2336616093 M2P_SysremEngy_Chg_B10_13 65535 "Invalid" ;
VAL_ 2336616093 M2P_SysremEngy_DisChg_B10_13 65535 "Invalid" ;
VAL_ 2336616094 M2P_SysremEngy_Chg_B10_14 65535 "Invalid" ;
VAL_ 2336616094 M2P_SysremEngy_DisChg_B10_14 65535 "Invalid" ;
VAL_ 2336616095 M2P_SysremEngy_Chg_B10_15 65535 "Invalid" ;
VAL_ 2336616095 M2P_SysremEngy_DisChg_B10_15 65535 "Invalid" ;
VAL_ 2336616096 M2P_SysremEngy_Chg_B10_16 65535 "Invalid" ;
VAL_ 2336616096 M2P_SysremEngy_DisChg_B10_16 65535 "Invalid" ;
VAL_ 2336616097 M2P_SysremEngy_Chg_B10_17 65535 "Invalid" ;
VAL_ 2336616097 M2P_SysremEngy_DisChg_B10_17 65535 "Invalid" ;
VAL_ 2336616098 M2P_SysremEngy_Chg_B10_18 65535 "Invalid" ;
VAL_ 2336616098 M2P_SysremEngy_DisChg_B10_18 65535 "Invalid" ;
VAL_ 2336616099 M2P_SysremEngy_Chg_B10_19 65535 "Invalid" ;
VAL_ 2336616099 M2P_SysremEngy_DisChg_B10_19 65535 "Invalid" ;
VAL_ 2336616100 M2P_SysremEngy_Chg_B10_20 65535 "Invalid" ;
VAL_ 2336616100 M2P_SysremEngy_DisChg_B10_20 65535 "Invalid" ;
VAL_ 2336616101 M2P_SysremEngy_Chg_B10_21 65535 "Invalid" ;
VAL_ 2336616101 M2P_SysremEngy_DisChg_B10_21 65535 "Invalid" ;
VAL_ 2336616102 M2P_SysremEngy_Chg_B10_22 65535 "Invalid" ;
VAL_ 2336616102 M2P_SysremEngy_DisChg_B10_22 65535 "Invalid" ;
VAL_ 2336616103 M2P_SysremEngy_Chg_B10_23 65535 "Invalid" ;
VAL_ 2336616103 M2P_SysremEngy_DisChg_B10_23 65535 "Invalid" ;
VAL_ 2336616104 M2P_SysremEngy_Chg_B10_24 65535 "Invalid" ;
VAL_ 2336616104 M2P_SysremEngy_DisChg_B10_24 65535 "Invalid" ;
VAL_ 2336616105 M2P_SysremEngy_Chg_B10_25 65535 "Invalid" ;
VAL_ 2336616105 M2P_SysremEngy_DisChg_B10_25 65535 "Invalid" ;
VAL_ 2336616106 M2P_SysremEngy_Chg_B10_26 65535 "Invalid" ;
VAL_ 2336616106 M2P_SysremEngy_DisChg_B10_26 65535 "Invalid" ;
VAL_ 2336616107 M2P_SysremEngy_Chg_B10_27 65535 "Invalid" ;
VAL_ 2336616107 M2P_SysremEngy_DisChg_B10_27 65535 "Invalid" ;
VAL_ 2336616108 M2P_SysremEngy_Chg_B10_28 65535 "Invalid" ;
VAL_ 2336616108 M2P_SysremEngy_DisChg_B10_28 65535 "Invalid" ;
VAL_ 2336616109 M2P_SysremEngy_Chg_B10_29 65535 "Invalid" ;
VAL_ 2336616109 M2P_SysremEngy_DisChg_B10_29 65535 "Invalid" ;
VAL_ 2336616110 M2P_SysremEngy_Chg_B10_30 65535 "Invalid" ;
VAL_ 2336616110 M2P_SysremEngy_DisChg_B10_30 65535 "Invalid" ;
VAL_ 2336616111 M2P_SysremEngy_Chg_B10_31 65535 "Invalid" ;
VAL_ 2336616111 M2P_SysremEngy_DisChg_B10_31 65535 "Invalid" ;
VAL_ 2336681617 M2P_BMS_Status_B10 0 "初始化状态" 1 "非满充满放状态" 2 "满充状态" 3 "满放状态" ;
VAL_ 2336681617 M2P_SOC_B10 1023 "Null" ;
VAL_ 2336681617 M2P_SOH_B10 255 "Null" ;
VAL_ 2336681618 M2P_BMS_Status_B10 0 "初始化状态" 1 "非满充满放状态" 2 "满充状态" 3 "满放状态" ;
VAL_ 2336681618 M2P_SOC_B10 1023 "Null" ;
VAL_ 2336681618 M2P_SOH_B10 255 "Null" ;
VAL_ 2336681619 M2P_BMS_Status_B10 0 "初始化状态" 1 "非满充满放状态" 2 "满充状态" 3 "满放状态" ;
VAL_ 2336681619 M2P_SOC_B10 1023 "Null" ;
VAL_ 2336681619 M2P_SOH_B10 255 "Null" ;
VAL_ 2336681620 M2P_BMS_Status_B10 0 "初始化状态" 1 "非满充满放状态" 2 "满充状态" 3 "满放状态" ;
VAL_ 2336681620 M2P_SOC_B10 1023 "Null" ;
VAL_ 2336681620 M2P_SOH_B10 255 "Null" ;
VAL_ 2336681621 M2P_BMS_Status_B10 0 "初始化状态" 1 "非满充满放状态" 2 "满充状态" 3 "满放状态" ;
VAL_ 2336681621 M2P_SOC_B10 1023 "Null" ;
VAL_ 2336681621 M2P_SOH_B10 255 "Null" ;
VAL_ 2336681622 M2P_BMS_Status_B10 0 "初始化状态" 1 "非满充满放状态" 2 "满充状态" 3 "满放状态" ;
VAL_ 2336681622 M2P_SOC_B10 1023 "Null" ;
VAL_ 2336681622 M2P_SOH_B10 255 "Null" ;
VAL_ 2336681623 M2P_BMS_Status_B10 0 "初始化状态" 1 "非满充满放状态" 2 "满充状态" 3 "满放状态" ;
VAL_ 2336681623 M2P_SOC_B10 1023 "Null" ;
VAL_ 2336681623 M2P_SOH_B10 255 "Null" ;
VAL_ 2336681624 M2P_BMS_Status_B10 0 "初始化状态" 1 "非满充满放状态" 2 "满充状态" 3 "满放状态" ;
VAL_ 2336681624 M2P_SOC_B10 1023 "Null" ;
VAL_ 2336681624 M2P_SOH_B10 255 "Null" ;
VAL_ 2336681625 M2P_BMS_Status_B10 0 "初始化状态" 1 "非满充满放状态" 2 "满充状态" 3 "满放状态" ;
VAL_ 2336681625 M2P_SOC_B10 1023 "Null" ;
VAL_ 2336681625 M2P_SOH_B10 255 "Null" ;
VAL_ 2336681626 M2P_BMS_Status_B10 0 "初始化状态" 1 "非满充满放状态" 2 "满充状态" 3 "满放状态" ;
VAL_ 2336681626 M2P_SOC_B10 1023 "Null" ;
VAL_ 2336681626 M2P_SOH_B10 255 "Null" ;
VAL_ 2336681627 M2P_BMS_Status_B10 0 "初始化状态" 1 "非满充满放状态" 2 "满充状态" 3 "满放状态" ;
VAL_ 2336681627 M2P_SOC_B10 1023 "Null" ;
VAL_ 2336681627 M2P_SOH_B10 255 "Null" ;
VAL_ 2336681628 M2P_BMS_Status_B10 0 "初始化状态" 1 "非满充满放状态" 2 "满充状态" 3 "满放状态" ;
VAL_ 2336681628 M2P_SOC_B10 1023 "Null" ;
VAL_ 2336681628 M2P_SOH_B10 255 "Null" ;
VAL_ 2336681629 M2P_BMS_Status_B10 0 "初始化状态" 1 "非满充满放状态" 2 "满充状态" 3 "满放状态" ;
VAL_ 2336681629 M2P_SOC_B10 1023 "Null" ;
VAL_ 2336681629 M2P_SOH_B10 255 "Null" ;
VAL_ 2336681630 M2P_BMS_Status_B10 0 "初始化状态" 1 "非满充满放状态" 2 "满充状态" 3 "满放状态" ;
VAL_ 2336681630 M2P_SOC_B10 1023 "Null" ;
VAL_ 2336681630 M2P_SOH_B10 255 "Null" ;
VAL_ 2336681631 M2P_BMS_Status_B10 0 "初始化状态" 1 "非满充满放状态" 2 "满充状态" 3 "满放状态" ;
VAL_ 2336681631 M2P_SOC_B10 1023 "Null" ;
VAL_ 2336681631 M2P_SOH_B10 255 "Null" ;
VAL_ 2336681632 M2P_BMS_Status_B10 0 "初始化状态" 1 "非满充满放状态" 2 "满充状态" 3 "满放状态" ;
VAL_ 2336681632 M2P_SOC_B10 1023 "Null" ;
VAL_ 2336681632 M2P_SOH_B10 255 "Null" ;
VAL_ 2336681633 M2P_BMS_Status_B10 0 "初始化状态" 1 "非满充满放状态" 2 "满充状态" 3 "满放状态" ;
VAL_ 2336681633 M2P_SOC_B10 1023 "Null" ;
VAL_ 2336681633 M2P_SOH_B10 255 "Null" ;
VAL_ 2336681634 M2P_BMS_Status_B10 0 "初始化状态" 1 "非满充满放状态" 2 "满充状态" 3 "满放状态" ;
VAL_ 2336681634 M2P_SOC_B10 1023 "Null" ;
VAL_ 2336681634 M2P_SOH_B10 255 "Null" ;
VAL_ 2336681635 M2P_BMS_Status_B10 0 "初始化状态" 1 "非满充满放状态" 2 "满充状态" 3 "满放状态" ;
VAL_ 2336681635 M2P_SOC_B10 1023 "Null" ;
VAL_ 2336681635 M2P_SOH_B10 255 "Null" ;
VAL_ 2336681636 M2P_BMS_Status_B10 0 "初始化状态" 1 "非满充满放状态" 2 "满充状态" 3 "满放状态" ;
VAL_ 2336681636 M2P_SOC_B10 1023 "Null" ;
VAL_ 2336681636 M2P_SOH_B10 255 "Null" ;
VAL_ 2336681637 M2P_BMS_Status_B10 0 "初始化状态" 1 "非满充满放状态" 2 "满充状态" 3 "满放状态" ;
VAL_ 2336681637 M2P_SOC_B10 1023 "Null" ;
VAL_ 2336681637 M2P_SOH_B10 255 "Null" ;
VAL_ 2336681638 M2P_BMS_Status_B10 0 "初始化状态" 1 "非满充满放状态" 2 "满充状态" 3 "满放状态" ;
VAL_ 2336681638 M2P_SOC_B10 1023 "Null" ;
VAL_ 2336681638 M2P_SOH_B10 255 "Null" ;
VAL_ 2336681639 M2P_BMS_Status_B10 0 "初始化状态" 1 "非满充满放状态" 2 "满充状态" 3 "满放状态" ;
VAL_ 2336681639 M2P_SOC_B10 1023 "Null" ;
VAL_ 2336681639 M2P_SOH_B10 255 "Null" ;
VAL_ 2336681640 M2P_BMS_Status_B10 0 "初始化状态" 1 "非满充满放状态" 2 "满充状态" 3 "满放状态" ;
VAL_ 2336681640 M2P_SOC_B10 1023 "Null" ;
VAL_ 2336681640 M2P_SOH_B10 255 "Null" ;
VAL_ 2336681641 M2P_BMS_Status_B10 0 "初始化状态" 1 "非满充满放状态" 2 "满充状态" 3 "满放状态" ;
VAL_ 2336681641 M2P_SOC_B10 1023 "Null" ;
VAL_ 2336681641 M2P_SOH_B10 255 "Null" ;
VAL_ 2336681642 M2P_BMS_Status_B10 0 "初始化状态" 1 "非满充满放状态" 2 "满充状态" 3 "满放状态" ;
VAL_ 2336681642 M2P_SOC_B10 1023 "Null" ;
VAL_ 2336681642 M2P_SOH_B10 255 "Null" ;
VAL_ 2336681643 M2P_BMS_Status_B10 0 "初始化状态" 1 "非满充满放状态" 2 "满充状态" 3 "满放状态" ;
VAL_ 2336681643 M2P_SOC_B10 1023 "Null" ;
VAL_ 2336681643 M2P_SOH_B10 255 "Null" ;
VAL_ 2336681644 M2P_BMS_Status_B10 0 "初始化状态" 1 "非满充满放状态" 2 "满充状态" 3 "满放状态" ;
VAL_ 2336681644 M2P_SOC_B10 1023 "Null" ;
VAL_ 2336681644 M2P_SOH_B10 255 "Null" ;
VAL_ 2336681645 M2P_BMS_Status_B10 0 "初始化状态" 1 "非满充满放状态" 2 "满充状态" 3 "满放状态" ;
VAL_ 2336681645 M2P_SOC_B10 1023 "Null" ;
VAL_ 2336681645 M2P_SOH_B10 255 "Null" ;
VAL_ 2336681646 M2P_BMS_Status_B10 0 "初始化状态" 1 "非满充满放状态" 2 "满充状态" 3 "满放状态" ;
VAL_ 2336681646 M2P_SOC_B10 1023 "Null" ;
VAL_ 2336681646 M2P_SOH_B10 255 "Null" ;
VAL_ 2336681647 M2P_BMS_Status_B10 0 "初始化状态" 1 "非满充满放状态" 2 "满充状态" 3 "满放状态" ;
VAL_ 2336681647 M2P_SOC_B10 1023 "Null" ;
VAL_ 2336681647 M2P_SOH_B10 255 "Null" ;
VAL_ 2336747153 M2P_SOE_Charge_B10 1023 "Null" ;
VAL_ 2336747153 M2P_SOE_Discharge_B10 1023 "Null" ;
VAL_ 2336747154 M2P_SOE_Charge_B10 1023 "Null" ;
VAL_ 2336747154 M2P_SOE_Discharge_B10 1023 "Null" ;
VAL_ 2336747155 M2P_SOE_Charge_B10 1023 "Null" ;
VAL_ 2336747155 M2P_SOE_Discharge_B10 1023 "Null" ;
VAL_ 2336747156 M2P_SOE_Charge_B10 1023 "Null" ;
VAL_ 2336747156 M2P_SOE_Discharge_B10 1023 "Null" ;
VAL_ 2336747157 M2P_SOE_Charge_B10 1023 "Null" ;
VAL_ 2336747157 M2P_SOE_Discharge_B10 1023 "Null" ;
VAL_ 2336747158 M2P_SOE_Charge_B10 1023 "Null" ;
VAL_ 2336747158 M2P_SOE_Discharge_B10 1023 "Null" ;
VAL_ 2336747159 M2P_SOE_Charge_B10 1023 "Null" ;
VAL_ 2336747159 M2P_SOE_Discharge_B10 1023 "Null" ;
VAL_ 2336747160 M2P_SOE_Charge_B10 1023 "Null" ;
VAL_ 2336747160 M2P_SOE_Discharge_B10 1023 "Null" ;
VAL_ 2336747161 M2P_SOE_Charge_B10 1023 "Null" ;
VAL_ 2336747161 M2P_SOE_Discharge_B10 1023 "Null" ;
VAL_ 2336747162 M2P_SOE_Charge_B10 1023 "Null" ;
VAL_ 2336747162 M2P_SOE_Discharge_B10 1023 "Null" ;
VAL_ 2336747163 M2P_SOE_Charge_B10 1023 "Null" ;
VAL_ 2336747163 M2P_SOE_Discharge_B10 1023 "Null" ;
VAL_ 2336747164 M2P_SOE_Charge_B10 1023 "Null" ;
VAL_ 2336747164 M2P_SOE_Discharge_B10 1023 "Null" ;
VAL_ 2336747165 M2P_SOE_Charge_B10 1023 "Null" ;
VAL_ 2336747165 M2P_SOE_Discharge_B10 1023 "Null" ;
VAL_ 2336747166 M2P_SOE_Charge_B10 1023 "Null" ;
VAL_ 2336747166 M2P_SOE_Discharge_B10 1023 "Null" ;
VAL_ 2336747167 M2P_SOE_Charge_B10 1023 "Null" ;
VAL_ 2336747167 M2P_SOE_Discharge_B10 1023 "Null" ;
VAL_ 2336747168 M2P_SOE_Charge_B10 1023 "Null" ;
VAL_ 2336747168 M2P_SOE_Discharge_B10 1023 "Null" ;
VAL_ 2336747169 M2P_SOE_Charge_B10 1023 "Null" ;
VAL_ 2336747169 M2P_SOE_Discharge_B10 1023 "Null" ;
VAL_ 2336747170 M2P_SOE_Charge_B10 1023 "Null" ;
VAL_ 2336747170 M2P_SOE_Discharge_B10 1023 "Null" ;
VAL_ 2336747171 M2P_SOE_Charge_B10 1023 "Null" ;
VAL_ 2336747171 M2P_SOE_Discharge_B10 1023 "Null" ;
VAL_ 2336747172 M2P_SOE_Charge_B10 1023 "Null" ;
VAL_ 2336747172 M2P_SOE_Discharge_B10 1023 "Null" ;
VAL_ 2336747173 M2P_SOE_Charge_B10 1023 "Null" ;
VAL_ 2336747173 M2P_SOE_Discharge_B10 1023 "Null" ;
VAL_ 2336747174 M2P_SOE_Charge_B10 1023 "Null" ;
VAL_ 2336747174 M2P_SOE_Discharge_B10 1023 "Null" ;
VAL_ 2336747175 M2P_SOE_Charge_B10 1023 "Null" ;
VAL_ 2336747175 M2P_SOE_Discharge_B10 1023 "Null" ;
VAL_ 2336747176 M2P_SOE_Charge_B10 1023 "Null" ;
VAL_ 2336747176 M2P_SOE_Discharge_B10 1023 "Null" ;
VAL_ 2336747177 M2P_SOE_Charge_B10 1023 "Null" ;
VAL_ 2336747177 M2P_SOE_Discharge_B10 1023 "Null" ;
VAL_ 2336747178 M2P_SOE_Charge_B10 1023 "Null" ;
VAL_ 2336747178 M2P_SOE_Discharge_B10 1023 "Null" ;
VAL_ 2336747179 M2P_SOE_Charge_B10 1023 "Null" ;
VAL_ 2336747179 M2P_SOE_Discharge_B10 1023 "Null" ;
VAL_ 2336747180 M2P_SOE_Charge_B10 1023 "Null" ;
VAL_ 2336747180 M2P_SOE_Discharge_B10 1023 "Null" ;
VAL_ 2336747181 M2P_SOE_Charge_B10 1023 "Null" ;
VAL_ 2336747181 M2P_SOE_Discharge_B10 1023 "Null" ;
VAL_ 2336747182 M2P_SOE_Charge_B10 1023 "Null" ;
VAL_ 2336747182 M2P_SOE_Discharge_B10 1023 "Null" ;
VAL_ 2336747183 M2P_SOE_Charge_B10 1023 "Null" ;
VAL_ 2336747183 M2P_SOE_Discharge_B10 1023 "Null" ;
VAL_ 2336812689 M2P_Measure_Vol_B11_01 65535 "Invalid" ;
VAL_ 2336812689 M2P_Current_B11_01 65535 "Invalid" ;
VAL_ 2336812689 M2P_PermitMaxCharge_I_B11_01 65535 "Invalid" ;
VAL_ 2336812689 M2P_PermitMaxDisCharge_I_B11_01 65535 "Invalid" ;
VAL_ 2336812690 M2P_Measure_Vol_B11_02 65535 "Invalid" ;
VAL_ 2336812690 M2P_Current_B11_02 65535 "Invalid" ;
VAL_ 2336812690 M2P_PermitMaxCharge_I_B11_02 65535 "Invalid" ;
VAL_ 2336812690 M2P_PermitMaxDisCharge_I_B11_02 65535 "Invalid" ;
VAL_ 2336812691 M2P_Measure_Vol_B11_03 65535 "Invalid" ;
VAL_ 2336812691 M2P_Current_B11_03 65535 "Invalid" ;
VAL_ 2336812691 M2P_PermitMaxCharge_I_B11_03 65535 "Invalid" ;
VAL_ 2336812691 M2P_PermitMaxDisCharge_I_B11_03 65535 "Invalid" ;
VAL_ 2336812692 M2P_Measure_Vol_B11_04 65535 "Invalid" ;
VAL_ 2336812692 M2P_Current_B11_04 65535 "Invalid" ;
VAL_ 2336812692 M2P_PermitMaxCharge_I_B11_04 65535 "Invalid" ;
VAL_ 2336812692 M2P_PermitMaxDisCharge_I_B11_04 65535 "Invalid" ;
VAL_ 2336812693 M2P_Measure_Vol_B11_05 65535 "Invalid" ;
VAL_ 2336812693 M2P_Current_B11_05 65535 "Invalid" ;
VAL_ 2336812693 M2P_PermitMaxCharge_I_B11_05 65535 "Invalid" ;
VAL_ 2336812693 M2P_PermitMaxDisCharge_I_B11_05 65535 "Invalid" ;
VAL_ 2336812694 M2P_Measure_Vol_B11_06 65535 "Invalid" ;
VAL_ 2336812694 M2P_Current_B11_06 65535 "Invalid" ;
VAL_ 2336812694 M2P_PermitMaxCharge_I_B11_06 65535 "Invalid" ;
VAL_ 2336812694 M2P_PermitMaxDisCharge_I_B11_06 65535 "Invalid" ;
VAL_ 2336812695 M2P_Measure_Vol_B11_07 65535 "Invalid" ;
VAL_ 2336812695 M2P_Current_B11_07 65535 "Invalid" ;
VAL_ 2336812695 M2P_PermitMaxCharge_I_B11_07 65535 "Invalid" ;
VAL_ 2336812695 M2P_PermitMaxDisCharge_I_B11_07 65535 "Invalid" ;
VAL_ 2336812696 M2P_Measure_Vol_B11_08 65535 "Invalid" ;
VAL_ 2336812696 M2P_Current_B11_08 65535 "Invalid" ;
VAL_ 2336812696 M2P_PermitMaxCharge_I_B11_08 65535 "Invalid" ;
VAL_ 2336812696 M2P_PermitMaxDisCharge_I_B11_08 65535 "Invalid" ;
VAL_ 2336812697 M2P_Measure_Vol_B11_09 65535 "Invalid" ;
VAL_ 2336812697 M2P_Current_B11_09 65535 "Invalid" ;
VAL_ 2336812697 M2P_PermitMaxCharge_I_B11_09 65535 "Invalid" ;
VAL_ 2336812697 M2P_PermitMaxDisCharge_I_B11_09 65535 "Invalid" ;
VAL_ 2336812698 M2P_Measure_Vol_B11_10 65535 "Invalid" ;
VAL_ 2336812698 M2P_Current_B11_10 65535 "Invalid" ;
VAL_ 2336812698 M2P_PermitMaxCharge_I_B11_10 65535 "Invalid" ;
VAL_ 2336812698 M2P_PermitMaxDisCharge_I_B11_10 65535 "Invalid" ;
VAL_ 2336812699 M2P_Measure_Vol_B11_11 65535 "Invalid" ;
VAL_ 2336812699 M2P_Current_B11_11 65535 "Invalid" ;
VAL_ 2336812699 M2P_PermitMaxCharge_I_B11_11 65535 "Invalid" ;
VAL_ 2336812699 M2P_PermitMaxDisCharge_I_B11_11 65535 "Invalid" ;
VAL_ 2336812700 M2P_Measure_Vol_B11_12 65535 "Invalid" ;
VAL_ 2336812700 M2P_Current_B11_12 65535 "Invalid" ;
VAL_ 2336812700 M2P_PermitMaxCharge_I_B11_12 65535 "Invalid" ;
VAL_ 2336812700 M2P_PermitMaxDisCharge_I_B11_12 65535 "Invalid" ;
VAL_ 2336812701 M2P_Measure_Vol_B11_13 65535 "Invalid" ;
VAL_ 2336812701 M2P_Current_B11_13 65535 "Invalid" ;
VAL_ 2336812701 M2P_PermitMaxCharge_I_B11_13 65535 "Invalid" ;
VAL_ 2336812701 M2P_PermitMaxDisCharge_I_B11_13 65535 "Invalid" ;
VAL_ 2336812702 M2P_Measure_Vol_B11_14 65535 "Invalid" ;
VAL_ 2336812702 M2P_Current_B11_14 65535 "Invalid" ;
VAL_ 2336812702 M2P_PermitMaxCharge_I_B11_14 65535 "Invalid" ;
VAL_ 2336812702 M2P_PermitMaxDisCharge_I_B11_14 65535 "Invalid" ;
VAL_ 2336812703 M2P_Measure_Vol_B11_15 65535 "Invalid" ;
VAL_ 2336812703 M2P_Current_B11_15 65535 "Invalid" ;
VAL_ 2336812703 M2P_PermitMaxCharge_I_B11_15 65535 "Invalid" ;
VAL_ 2336812703 M2P_PermitMaxDisCharge_I_B11_15 65535 "Invalid" ;
VAL_ 2336812704 M2P_Measure_Vol_B11_16 65535 "Invalid" ;
VAL_ 2336812704 M2P_Current_B11_16 65535 "Invalid" ;
VAL_ 2336812704 M2P_PermitMaxCharge_I_B11_16 65535 "Invalid" ;
VAL_ 2336812704 M2P_PermitMaxDisCharge_I_B11_16 65535 "Invalid" ;
VAL_ 2336812705 M2P_Measure_Vol_B11_17 65535 "Invalid" ;
VAL_ 2336812705 M2P_Current_B11_17 65535 "Invalid" ;
VAL_ 2336812705 M2P_PermitMaxCharge_I_B11_17 65535 "Invalid" ;
VAL_ 2336812705 M2P_PermitMaxDisCharge_I_B11_17 65535 "Invalid" ;
VAL_ 2336812706 M2P_Measure_Vol_B11_18 65535 "Invalid" ;
VAL_ 2336812706 M2P_Current_B11_18 65535 "Invalid" ;
VAL_ 2336812706 M2P_PermitMaxCharge_I_B11_18 65535 "Invalid" ;
VAL_ 2336812706 M2P_PermitMaxDisCharge_I_B11_18 65535 "Invalid" ;
VAL_ 2336812707 M2P_Measure_Vol_B11_19 65535 "Invalid" ;
VAL_ 2336812707 M2P_Current_B11_19 65535 "Invalid" ;
VAL_ 2336812707 M2P_PermitMaxCharge_I_B11_19 65535 "Invalid" ;
VAL_ 2336812707 M2P_PermitMaxDisCharge_I_B11_19 65535 "Invalid" ;
VAL_ 2336812708 M2P_Measure_Vol_B11_20 65535 "Invalid" ;
VAL_ 2336812708 M2P_Current_B11_20 65535 "Invalid" ;
VAL_ 2336812708 M2P_PermitMaxCharge_I_B11_20 65535 "Invalid" ;
VAL_ 2336812708 M2P_PermitMaxDisCharge_I_B11_20 65535 "Invalid" ;
VAL_ 2336812709 M2P_Measure_Vol_B11_21 65535 "Invalid" ;
VAL_ 2336812709 M2P_Current_B11_21 65535 "Invalid" ;
VAL_ 2336812709 M2P_PermitMaxCharge_I_B11_21 65535 "Invalid" ;
VAL_ 2336812709 M2P_PermitMaxDisCharge_I_B11_21 65535 "Invalid" ;
VAL_ 2336812710 M2P_Measure_Vol_B11_22 65535 "Invalid" ;
VAL_ 2336812710 M2P_Current_B11_22 65535 "Invalid" ;
VAL_ 2336812710 M2P_PermitMaxCharge_I_B11_22 65535 "Invalid" ;
VAL_ 2336812710 M2P_PermitMaxDisCharge_I_B11_22 65535 "Invalid" ;
VAL_ 2336812711 M2P_Measure_Vol_B11_23 65535 "Invalid" ;
VAL_ 2336812711 M2P_Current_B11_23 65535 "Invalid" ;
VAL_ 2336812711 M2P_PermitMaxCharge_I_B11_23 65535 "Invalid" ;
VAL_ 2336812711 M2P_PermitMaxDisCharge_I_B11_23 65535 "Invalid" ;
VAL_ 2336812712 M2P_Measure_Vol_B11_24 65535 "Invalid" ;
VAL_ 2336812712 M2P_Current_B11_24 65535 "Invalid" ;
VAL_ 2336812712 M2P_PermitMaxCharge_I_B11_24 65535 "Invalid" ;
VAL_ 2336812712 M2P_PermitMaxDisCharge_I_B11_24 65535 "Invalid" ;
VAL_ 2336812713 M2P_Measure_Vol_B11_25 65535 "Invalid" ;
VAL_ 2336812713 M2P_Current_B11_25 65535 "Invalid" ;
VAL_ 2336812713 M2P_PermitMaxCharge_I_B11_25 65535 "Invalid" ;
VAL_ 2336812713 M2P_PermitMaxDisCharge_I_B11_25 65535 "Invalid" ;
VAL_ 2336812714 M2P_Measure_Vol_B11_26 65535 "Invalid" ;
VAL_ 2336812714 M2P_Current_B11_26 65535 "Invalid" ;
VAL_ 2336812714 M2P_PermitMaxCharge_I_B11_26 65535 "Invalid" ;
VAL_ 2336812714 M2P_PermitMaxDisCharge_I_B11_26 65535 "Invalid" ;
VAL_ 2336812715 M2P_Measure_Vol_B11_27 65535 "Invalid" ;
VAL_ 2336812715 M2P_Current_B11_27 65535 "Invalid" ;
VAL_ 2336812715 M2P_PermitMaxCharge_I_B11_27 65535 "Invalid" ;
VAL_ 2336812715 M2P_PermitMaxDisCharge_I_B11_27 65535 "Invalid" ;
VAL_ 2336812716 M2P_Measure_Vol_B11_28 65535 "Invalid" ;
VAL_ 2336812716 M2P_Current_B11_28 65535 "Invalid" ;
VAL_ 2336812716 M2P_PermitMaxCharge_I_B11_28 65535 "Invalid" ;
VAL_ 2336812716 M2P_PermitMaxDisCharge_I_B11_28 65535 "Invalid" ;
VAL_ 2336812717 M2P_Measure_Vol_B11_29 65535 "Invalid" ;
VAL_ 2336812717 M2P_Current_B11_29 65535 "Invalid" ;
VAL_ 2336812717 M2P_PermitMaxCharge_I_B11_29 65535 "Invalid" ;
VAL_ 2336812717 M2P_PermitMaxDisCharge_I_B11_29 65535 "Invalid" ;
VAL_ 2336812718 M2P_Measure_Vol_B11_30 65535 "Invalid" ;
VAL_ 2336812718 M2P_Current_B11_30 65535 "Invalid" ;
VAL_ 2336812718 M2P_PermitMaxCharge_I_B11_30 65535 "Invalid" ;
VAL_ 2336812718 M2P_PermitMaxDisCharge_I_B11_30 65535 "Invalid" ;
VAL_ 2336812719 M2P_Measure_Vol_B11_31 65535 "Invalid" ;
VAL_ 2336812719 M2P_Current_B11_31 65535 "Invalid" ;
VAL_ 2336812719 M2P_PermitMaxCharge_I_B11_31 65535 "Invalid" ;
VAL_ 2336812719 M2P_PermitMaxDisCharge_I_B11_31 65535 "Invalid" ;
VAL_ 2336943761 M2P_SysremEngy_Chg_B11_01 65535 "Invalid" ;
VAL_ 2336943761 M2P_SysremEngy_DisChg_B11_01 65535 "Invalid" ;
VAL_ 2336943762 M2P_SysremEngy_Chg_B11_02 65535 "Invalid" ;
VAL_ 2336943762 M2P_SysremEngy_DisChg_B11_02 65535 "Invalid" ;
VAL_ 2336943763 M2P_SysremEngy_Chg_B11_03 65535 "Invalid" ;
VAL_ 2336943763 M2P_SysremEngy_DisChg_B11_03 65535 "Invalid" ;
VAL_ 2336943764 M2P_SysremEngy_Chg_B11_04 65535 "Invalid" ;
VAL_ 2336943764 M2P_SysremEngy_DisChg_B11_04 65535 "Invalid" ;
VAL_ 2336943765 M2P_SysremEngy_Chg_B11_05 65535 "Invalid" ;
VAL_ 2336943765 M2P_SysremEngy_DisChg_B11_05 65535 "Invalid" ;
VAL_ 2336943766 M2P_SysremEngy_Chg_B11_06 65535 "Invalid" ;
VAL_ 2336943766 M2P_SysremEngy_DisChg_B11_06 65535 "Invalid" ;
VAL_ 2336943767 M2P_SysremEngy_Chg_B11_07 65535 "Invalid" ;
VAL_ 2336943767 M2P_SysremEngy_DisChg_B11_07 65535 "Invalid" ;
VAL_ 2336943768 M2P_SysremEngy_Chg_B11_08 65535 "Invalid" ;
VAL_ 2336943768 M2P_SysremEngy_DisChg_B11_08 65535 "Invalid" ;
VAL_ 2336943769 M2P_SysremEngy_Chg_B11_09 65535 "Invalid" ;
VAL_ 2336943769 M2P_SysremEngy_DisChg_B11_09 65535 "Invalid" ;
VAL_ 2336943770 M2P_SysremEngy_Chg_B11_10 65535 "Invalid" ;
VAL_ 2336943770 M2P_SysremEngy_DisChg_B11_10 65535 "Invalid" ;
VAL_ 2336943771 M2P_SysremEngy_Chg_B11_11 65535 "Invalid" ;
VAL_ 2336943771 M2P_SysremEngy_DisChg_B11_11 65535 "Invalid" ;
VAL_ 2336943772 M2P_SysremEngy_Chg_B11_12 65535 "Invalid" ;
VAL_ 2336943772 M2P_SysremEngy_DisChg_B11_12 65535 "Invalid" ;
VAL_ 2336943773 M2P_SysremEngy_Chg_B11_13 65535 "Invalid" ;
VAL_ 2336943773 M2P_SysremEngy_DisChg_B11_13 65535 "Invalid" ;
VAL_ 2336943774 M2P_SysremEngy_Chg_B11_14 65535 "Invalid" ;
VAL_ 2336943774 M2P_SysremEngy_DisChg_B11_14 65535 "Invalid" ;
VAL_ 2336943775 M2P_SysremEngy_Chg_B11_15 65535 "Invalid" ;
VAL_ 2336943775 M2P_SysremEngy_DisChg_B11_15 65535 "Invalid" ;
VAL_ 2336943776 M2P_SysremEngy_Chg_B11_16 65535 "Invalid" ;
VAL_ 2336943776 M2P_SysremEngy_DisChg_B11_16 65535 "Invalid" ;
VAL_ 2336943777 M2P_SysremEngy_Chg_B11_17 65535 "Invalid" ;
VAL_ 2336943777 M2P_SysremEngy_DisChg_B11_17 65535 "Invalid" ;
VAL_ 2336943778 M2P_SysremEngy_Chg_B11_18 65535 "Invalid" ;
VAL_ 2336943778 M2P_SysremEngy_DisChg_B11_18 65535 "Invalid" ;
VAL_ 2336943779 M2P_SysremEngy_Chg_B11_19 65535 "Invalid" ;
VAL_ 2336943779 M2P_SysremEngy_DisChg_B11_19 65535 "Invalid" ;
VAL_ 2336943780 M2P_SysremEngy_Chg_B11_20 65535 "Invalid" ;
VAL_ 2336943780 M2P_SysremEngy_DisChg_B11_20 65535 "Invalid" ;
VAL_ 2336943781 M2P_SysremEngy_Chg_B11_21 65535 "Invalid" ;
VAL_ 2336943781 M2P_SysremEngy_DisChg_B11_21 65535 "Invalid" ;
VAL_ 2336943782 M2P_SysremEngy_Chg_B11_22 65535 "Invalid" ;
VAL_ 2336943782 M2P_SysremEngy_DisChg_B11_22 65535 "Invalid" ;
VAL_ 2336943783 M2P_SysremEngy_Chg_B11_23 65535 "Invalid" ;
VAL_ 2336943783 M2P_SysremEngy_DisChg_B11_23 65535 "Invalid" ;
VAL_ 2336943784 M2P_SysremEngy_Chg_B11_24 65535 "Invalid" ;
VAL_ 2336943784 M2P_SysremEngy_DisChg_B11_24 65535 "Invalid" ;
VAL_ 2336943785 M2P_SysremEngy_Chg_B11_25 65535 "Invalid" ;
VAL_ 2336943785 M2P_SysremEngy_DisChg_B11_25 65535 "Invalid" ;
VAL_ 2336943786 M2P_SysremEngy_Chg_B11_26 65535 "Invalid" ;
VAL_ 2336943786 M2P_SysremEngy_DisChg_B11_26 65535 "Invalid" ;
VAL_ 2336943787 M2P_SysremEngy_Chg_B11_27 65535 "Invalid" ;
VAL_ 2336943787 M2P_SysremEngy_DisChg_B11_27 65535 "Invalid" ;
VAL_ 2336943788 M2P_SysremEngy_Chg_B11_28 65535 "Invalid" ;
VAL_ 2336943788 M2P_SysremEngy_DisChg_B11_28 65535 "Invalid" ;
VAL_ 2336943789 M2P_SysremEngy_Chg_B11_29 65535 "Invalid" ;
VAL_ 2336943789 M2P_SysremEngy_DisChg_B11_29 65535 "Invalid" ;
VAL_ 2336943790 M2P_SysremEngy_Chg_B11_30 65535 "Invalid" ;
VAL_ 2336943790 M2P_SysremEngy_DisChg_B11_30 65535 "Invalid" ;
VAL_ 2336943791 M2P_SysremEngy_Chg_B11_31 65535 "Invalid" ;
VAL_ 2336943791 M2P_SysremEngy_DisChg_B11_31 65535 "Invalid" ;
VAL_ 2337009297 M2P_BMS_Status_B11 0 "初始化状态" 1 "非满充满放状态" 2 "满充状态" 3 "满放状态" ;
VAL_ 2337009297 M2P_SOC_B11 1023 "Null" ;
VAL_ 2337009297 M2P_SOH_B11 255 "Null" ;
VAL_ 2337009298 M2P_BMS_Status_B11 0 "初始化状态" 1 "非满充满放状态" 2 "满充状态" 3 "满放状态" ;
VAL_ 2337009298 M2P_SOC_B11 1023 "Null" ;
VAL_ 2337009298 M2P_SOH_B11 255 "Null" ;
VAL_ 2337009299 M2P_BMS_Status_B11 0 "初始化状态" 1 "非满充满放状态" 2 "满充状态" 3 "满放状态" ;
VAL_ 2337009299 M2P_SOC_B11 1023 "Null" ;
VAL_ 2337009299 M2P_SOH_B11 255 "Null" ;
VAL_ 2337009300 M2P_BMS_Status_B11 0 "初始化状态" 1 "非满充满放状态" 2 "满充状态" 3 "满放状态" ;
VAL_ 2337009300 M2P_SOC_B11 1023 "Null" ;
VAL_ 2337009300 M2P_SOH_B11 255 "Null" ;
VAL_ 2337009301 M2P_BMS_Status_B11 0 "初始化状态" 1 "非满充满放状态" 2 "满充状态" 3 "满放状态" ;
VAL_ 2337009301 M2P_SOC_B11 1023 "Null" ;
VAL_ 2337009301 M2P_SOH_B11 255 "Null" ;
VAL_ 2337009302 M2P_BMS_Status_B11 0 "初始化状态" 1 "非满充满放状态" 2 "满充状态" 3 "满放状态" ;
VAL_ 2337009302 M2P_SOC_B11 1023 "Null" ;
VAL_ 2337009302 M2P_SOH_B11 255 "Null" ;
VAL_ 2337009303 M2P_BMS_Status_B11 0 "初始化状态" 1 "非满充满放状态" 2 "满充状态" 3 "满放状态" ;
VAL_ 2337009303 M2P_SOC_B11 1023 "Null" ;
VAL_ 2337009303 M2P_SOH_B11 255 "Null" ;
VAL_ 2337009304 M2P_BMS_Status_B11 0 "初始化状态" 1 "非满充满放状态" 2 "满充状态" 3 "满放状态" ;
VAL_ 2337009304 M2P_SOC_B11 1023 "Null" ;
VAL_ 2337009304 M2P_SOH_B11 255 "Null" ;
VAL_ 2337009305 M2P_BMS_Status_B11 0 "初始化状态" 1 "非满充满放状态" 2 "满充状态" 3 "满放状态" ;
VAL_ 2337009305 M2P_SOC_B11 1023 "Null" ;
VAL_ 2337009305 M2P_SOH_B11 255 "Null" ;
VAL_ 2337009306 M2P_BMS_Status_B11 0 "初始化状态" 1 "非满充满放状态" 2 "满充状态" 3 "满放状态" ;
VAL_ 2337009306 M2P_SOC_B11 1023 "Null" ;
VAL_ 2337009306 M2P_SOH_B11 255 "Null" ;
VAL_ 2337009307 M2P_BMS_Status_B11 0 "初始化状态" 1 "非满充满放状态" 2 "满充状态" 3 "满放状态" ;
VAL_ 2337009307 M2P_SOC_B11 1023 "Null" ;
VAL_ 2337009307 M2P_SOH_B11 255 "Null" ;
VAL_ 2337009308 M2P_BMS_Status_B11 0 "初始化状态" 1 "非满充满放状态" 2 "满充状态" 3 "满放状态" ;
VAL_ 2337009308 M2P_SOC_B11 1023 "Null" ;
VAL_ 2337009308 M2P_SOH_B11 255 "Null" ;
VAL_ 2337009309 M2P_BMS_Status_B11 0 "初始化状态" 1 "非满充满放状态" 2 "满充状态" 3 "满放状态" ;
VAL_ 2337009309 M2P_SOC_B11 1023 "Null" ;
VAL_ 2337009309 M2P_SOH_B11 255 "Null" ;
VAL_ 2337009310 M2P_BMS_Status_B11 0 "初始化状态" 1 "非满充满放状态" 2 "满充状态" 3 "满放状态" ;
VAL_ 2337009310 M2P_SOC_B11 1023 "Null" ;
VAL_ 2337009310 M2P_SOH_B11 255 "Null" ;
VAL_ 2337009311 M2P_BMS_Status_B11 0 "初始化状态" 1 "非满充满放状态" 2 "满充状态" 3 "满放状态" ;
VAL_ 2337009311 M2P_SOC_B11 1023 "Null" ;
VAL_ 2337009311 M2P_SOH_B11 255 "Null" ;
VAL_ 2337009312 M2P_BMS_Status_B11 0 "初始化状态" 1 "非满充满放状态" 2 "满充状态" 3 "满放状态" ;
VAL_ 2337009312 M2P_SOC_B11 1023 "Null" ;
VAL_ 2337009312 M2P_SOH_B11 255 "Null" ;
VAL_ 2337009313 M2P_BMS_Status_B11 0 "初始化状态" 1 "非满充满放状态" 2 "满充状态" 3 "满放状态" ;
VAL_ 2337009313 M2P_SOC_B11 1023 "Null" ;
VAL_ 2337009313 M2P_SOH_B11 255 "Null" ;
VAL_ 2337009314 M2P_BMS_Status_B11 0 "初始化状态" 1 "非满充满放状态" 2 "满充状态" 3 "满放状态" ;
VAL_ 2337009314 M2P_SOC_B11 1023 "Null" ;
VAL_ 2337009314 M2P_SOH_B11 255 "Null" ;
VAL_ 2337009315 M2P_BMS_Status_B11 0 "初始化状态" 1 "非满充满放状态" 2 "满充状态" 3 "满放状态" ;
VAL_ 2337009315 M2P_SOC_B11 1023 "Null" ;
VAL_ 2337009315 M2P_SOH_B11 255 "Null" ;
VAL_ 2337009316 M2P_BMS_Status_B11 0 "初始化状态" 1 "非满充满放状态" 2 "满充状态" 3 "满放状态" ;
VAL_ 2337009316 M2P_SOC_B11 1023 "Null" ;
VAL_ 2337009316 M2P_SOH_B11 255 "Null" ;
VAL_ 2337009317 M2P_BMS_Status_B11 0 "初始化状态" 1 "非满充满放状态" 2 "满充状态" 3 "满放状态" ;
VAL_ 2337009317 M2P_SOC_B11 1023 "Null" ;
VAL_ 2337009317 M2P_SOH_B11 255 "Null" ;
VAL_ 2337009318 M2P_BMS_Status_B11 0 "初始化状态" 1 "非满充满放状态" 2 "满充状态" 3 "满放状态" ;
VAL_ 2337009318 M2P_SOC_B11 1023 "Null" ;
VAL_ 2337009318 M2P_SOH_B11 255 "Null" ;
VAL_ 2337009319 M2P_BMS_Status_B11 0 "初始化状态" 1 "非满充满放状态" 2 "满充状态" 3 "满放状态" ;
VAL_ 2337009319 M2P_SOC_B11 1023 "Null" ;
VAL_ 2337009319 M2P_SOH_B11 255 "Null" ;
VAL_ 2337009320 M2P_BMS_Status_B11 0 "初始化状态" 1 "非满充满放状态" 2 "满充状态" 3 "满放状态" ;
VAL_ 2337009320 M2P_SOC_B11 1023 "Null" ;
VAL_ 2337009320 M2P_SOH_B11 255 "Null" ;
VAL_ 2337009321 M2P_BMS_Status_B11 0 "初始化状态" 1 "非满充满放状态" 2 "满充状态" 3 "满放状态" ;
VAL_ 2337009321 M2P_SOC_B11 1023 "Null" ;
VAL_ 2337009321 M2P_SOH_B11 255 "Null" ;
VAL_ 2337009322 M2P_BMS_Status_B11 0 "初始化状态" 1 "非满充满放状态" 2 "满充状态" 3 "满放状态" ;
VAL_ 2337009322 M2P_SOC_B11 1023 "Null" ;
VAL_ 2337009322 M2P_SOH_B11 255 "Null" ;
VAL_ 2337009323 M2P_BMS_Status_B11 0 "初始化状态" 1 "非满充满放状态" 2 "满充状态" 3 "满放状态" ;
VAL_ 2337009323 M2P_SOC_B11 1023 "Null" ;
VAL_ 2337009323 M2P_SOH_B11 255 "Null" ;
VAL_ 2337009324 M2P_BMS_Status_B11 0 "初始化状态" 1 "非满充满放状态" 2 "满充状态" 3 "满放状态" ;
VAL_ 2337009324 M2P_SOC_B11 1023 "Null" ;
VAL_ 2337009324 M2P_SOH_B11 255 "Null" ;
VAL_ 2337009325 M2P_BMS_Status_B11 0 "初始化状态" 1 "非满充满放状态" 2 "满充状态" 3 "满放状态" ;
VAL_ 2337009325 M2P_SOC_B11 1023 "Null" ;
VAL_ 2337009325 M2P_SOH_B11 255 "Null" ;
VAL_ 2337009326 M2P_BMS_Status_B11 0 "初始化状态" 1 "非满充满放状态" 2 "满充状态" 3 "满放状态" ;
VAL_ 2337009326 M2P_SOC_B11 1023 "Null" ;
VAL_ 2337009326 M2P_SOH_B11 255 "Null" ;
VAL_ 2337009327 M2P_BMS_Status_B11 0 "初始化状态" 1 "非满充满放状态" 2 "满充状态" 3 "满放状态" ;
VAL_ 2337009327 M2P_SOC_B11 1023 "Null" ;
VAL_ 2337009327 M2P_SOH_B11 255 "Null" ;
VAL_ 2337074833 M2P_SOE_Charge_B11 1023 "Null" ;
VAL_ 2337074833 M2P_SOE_Discharge_B11 1023 "Null" ;
VERSION ""

NS_ :

BS_:

BU_: MBMU PC SBMU IMM ETH DCDC LEMS

BO_ 2337074834 M2P_SUMDATA69__02: 8 MBMU
 SG_ M2P_SOE_Charge_B11 : 0|10@1+ (0.1,0) [0|102.3] "%"  PC
 SG_ M2P_SOE_Discharge_B11 : 10|10@1+ (0.1,0) [0|102.3] "%"  PC
 SG_ Reserved_02 : 20|44@1+ (1,0) [0|17592186044415] ""  PC

BO_ 2337074835 M2P_SUMDATA69__03: 8 MBMU
 SG_ M2P_SOE_Charge_B11 : 0|10@1+ (0.1,0) [0|102.3] "%"  PC
 SG_ M2P_SOE_Discharge_B11 : 10|10@1+ (0.1,0) [0|102.3] "%"  PC
 SG_ Reserved_03 : 20|44@1+ (1,0) [0|17592186044415] ""  PC

BO_ 2337074836 M2P_SUMDATA69__04: 8 MBMU
 SG_ M2P_SOE_Charge_B11 : 0|10@1+ (0.1,0) [0|102.3] "%"  PC
 SG_ M2P_SOE_Discharge_B11 : 10|10@1+ (0.1,0) [0|102.3] "%"  PC
 SG_ Reserved_04 : 20|44@1+ (1,0) [0|17592186044415] ""  PC

BO_ 2337074837 M2P_SUMDATA69__05: 8 MBMU
 SG_ M2P_SOE_Charge_B11 : 0|10@1+ (0.1,0) [0|102.3] "%"  PC
 SG_ M2P_SOE_Discharge_B11 : 10|10@1+ (0.1,0) [0|102.3] "%"  PC
 SG_ Reserved_05 : 20|44@1+ (1,0) [0|17592186044415] ""  PC

BO_ 2337074838 M2P_SUMDATA69__06: 8 MBMU
 SG_ M2P_SOE_Charge_B11 : 0|10@1+ (0.1,0) [0|102.3] "%"  PC
 SG_ M2P_SOE_Discharge_B11 : 10|10@1+ (0.1,0) [0|102.3] "%"  PC
 SG_ Reserved_06 : 20|44@1+ (1,0) [0|17592186044415] ""  PC

BO_ 2337074839 M2P_SUMDATA69__07: 8 MBMU
 SG_ M2P_SOE_Charge_B11 : 0|10@1+ (0.1,0) [0|102.3] "%"  PC
 SG_ M2P_SOE_Discharge_B11 : 10|10@1+ (0.1,0) [0|102.3] "%"  PC
 SG_ Reserved_07 : 20|44@1+ (1,0) [0|17592186044415] ""  PC

BO_ 2337074840 M2P_SUMDATA69__08: 8 MBMU
 SG_ M2P_SOE_Charge_B11 : 0|10@1+ (0.1,0) [0|102.3] "%"  PC
 SG_ M2P_SOE_Discharge_B11 : 10|10@1+ (0.1,0) [0|102.3] "%"  PC
 SG_ Reserved_08 : 20|44@1+ (1,0) [0|17592186044415] ""  PC

BO_ 2337074841 M2P_SUMDATA69__09: 8 MBMU
 SG_ M2P_SOE_Charge_B11 : 0|10@1+ (0.1,0) [0|102.3] "%"  PC
 SG_ M2P_SOE_Discharge_B11 : 10|10@1+ (0.1,0) [0|102.3] "%"  PC
 SG_ Reserved_09 : 20|44@1+ (1,0) [0|17592186044415] ""  PC

BO_ 2337074842 M2P_SUMDATA69__10: 8 MBMU
 SG_ M2P_SOE_Charge_B11 : 0|10@1+ (0.1,0) [0|102.3] "%"  PC
 SG_ M2P_SOE_Discharge_B11 : 10|10@1+ (0.1,0) [0|102.3] "%"  PC
 SG_ Reserved_10 : 20|44@1+ (1,0) [0|17592186044415] ""  PC

BO_ 2337074843 M2P_SUMDATA69__11: 8 MBMU
 SG_ M2P_SOE_Charge_B11 : 0|10@1+ (0.1,0) [0|102.3] "%"  PC
 SG_ M2P_SOE_Discharge_B11 : 10|10@1+ (0.1,0) [0|102.3] "%"  PC
 SG_ Reserved_11 : 20|44@1+ (1,0) [0|17592186044415] ""  PC

BO_ 2337074844 M2P_SUMDATA69__12: 8 MBMU
 SG_ M2P_SOE_Charge_B11 : 0|10@1+ (0.1,0) [0|102.3] "%"  PC
 SG_ M2P_SOE_Discharge_B11 : 10|10@1+ (0.1,0) [0|102.3] "%"  PC
 SG_ Reserved_12 : 20|44@1+ (1,0) [0|17592186044415] ""  PC

BO_ 2337074845 M2P_SUMDATA69__13: 8 MBMU
 SG_ M2P_SOE_Charge_B11 : 0|10@1+ (0.1,0) [0|102.3] "%"  PC
 SG_ M2P_SOE_Discharge_B11 : 10|10@1+ (0.1,0) [0|102.3] "%"  PC
 SG_ Reserved_13 : 20|44@1+ (1,0) [0|17592186044415] ""  PC

BO_ 2337074846 M2P_SUMDATA69__14: 8 MBMU
 SG_ M2P_SOE_Charge_B11 : 0|10@1+ (0.1,0) [0|102.3] "%"  PC
 SG_ M2P_SOE_Discharge_B11 : 10|10@1+ (0.1,0) [0|102.3] "%"  PC
 SG_ Reserved_14 : 20|44@1+ (1,0) [0|17592186044415] ""  PC

BO_ 2337074847 M2P_SUMDATA69__15: 8 MBMU
 SG_ M2P_SOE_Charge_B11 : 0|10@1+ (0.1,0) [0|102.3] "%"  PC
 SG_ M2P_SOE_Discharge_B11 : 10|10@1+ (0.1,0) [0|102.3] "%"  PC
 SG_ Reserved_15 : 20|44@1+ (1,0) [0|17592186044415] ""  PC

BO_ 2337074848 M2P_SUMDATA69__16: 8 MBMU
 SG_ M2P_SOE_Charge_B11 : 0|10@1+ (0.1,0) [0|102.3] "%"  PC
 SG_ M2P_SOE_Discharge_B11 : 10|10@1+ (0.1,0) [0|102.3] "%"  PC
 SG_ Reserved_16 : 20|44@1+ (1,0) [0|17592186044415] ""  PC

BO_ 2337074849 M2P_SUMDATA69__17: 8 MBMU
 SG_ M2P_SOE_Charge_B11 : 0|10@1+ (0.1,0) [0|102.3] "%"  PC
 SG_ M2P_SOE_Discharge_B11 : 10|10@1+ (0.1,0) [0|102.3] "%"  PC
 SG_ Reserved_17 : 20|44@1+ (1,0) [0|17592186044415] ""  PC

BO_ 2337074850 M2P_SUMDATA69__18: 8 MBMU
 SG_ M2P_SOE_Charge_B11 : 0|10@1+ (0.1,0) [0|102.3] "%"  PC
 SG_ M2P_SOE_Discharge_B11 : 10|10@1+ (0.1,0) [0|102.3] "%"  PC
 SG_ Reserved_18 : 20|44@1+ (1,0) [0|17592186044415] ""  PC

BO_ 2337074851 M2P_SUMDATA69__19: 8 MBMU
 SG_ M2P_SOE_Charge_B11 : 0|10@1+ (0.1,0) [0|102.3] "%"  PC
 SG_ M2P_SOE_Discharge_B11 : 10|10@1+ (0.1,0) [0|102.3] "%"  PC
 SG_ Reserved_19 : 20|44@1+ (1,0) [0|17592186044415] ""  PC

BO_ 2337074852 M2P_SUMDATA69__20: 8 MBMU
 SG_ M2P_SOE_Charge_B11 : 0|10@1+ (0.1,0) [0|102.3] "%"  PC
 SG_ M2P_SOE_Discharge_B11 : 10|10@1+ (0.1,0) [0|102.3] "%"  PC
 SG_ Reserved_20 : 20|44@1+ (1,0) [0|17592186044415] ""  PC

BO_ 2337074853 M2P_SUMDATA69__21: 8 MBMU
 SG_ M2P_SOE_Charge_B11 : 0|10@1+ (0.1,0) [0|102.3] "%"  PC
 SG_ M2P_SOE_Discharge_B11 : 10|10@1+ (0.1,0) [0|102.3] "%"  PC
 SG_ Reserved_21 : 20|44@1+ (1,0) [0|17592186044415] ""  PC

BO_ 2337074854 M2P_SUMDATA69__22: 8 MBMU
 SG_ M2P_SOE_Charge_B11 : 0|10@1+ (0.1,0) [0|102.3] "%"  PC
 SG_ M2P_SOE_Discharge_B11 : 10|10@1+ (0.1,0) [0|102.3] "%"  PC
 SG_ Reserved_22 : 20|44@1+ (1,0) [0|17592186044415] ""  PC

BO_ 2337074855 M2P_SUMDATA69__23: 8 MBMU
 SG_ M2P_SOE_Charge_B11 : 0|10@1+ (0.1,0) [0|102.3] "%"  PC
 SG_ M2P_SOE_Discharge_B11 : 10|10@1+ (0.1,0) [0|102.3] "%"  PC
 SG_ Reserved_23 : 20|44@1+ (1,0) [0|17592186044415] ""  PC

BO_ 2337074856 M2P_SUMDATA69__24: 8 MBMU
 SG_ M2P_SOE_Charge_B11 : 0|10@1+ (0.1,0) [0|102.3] "%"  PC
 SG_ M2P_SOE_Discharge_B11 : 10|10@1+ (0.1,0) [0|102.3] "%"  PC
 SG_ Reserved_24 : 20|44@1+ (1,0) [0|17592186044415] ""  PC

BO_ 2337074857 M2P_SUMDATA69__25: 8 MBMU
 SG_ M2P_SOE_Charge_B11 : 0|10@1+ (0.1,0) [0|102.3] "%"  PC
 SG_ M2P_SOE_Discharge_B11 : 10|10@1+ (0.1,0) [0|102.3] "%"  PC
 SG_ Reserved_25 : 20|44@1+ (1,0) [0|17592186044415] ""  PC

BO_ 2337074858 M2P_SUMDATA69__26: 8 MBMU
 SG_ M2P_SOE_Charge_B11 : 0|10@1+ (0.1,0) [0|102.3] "%"  PC
 SG_ M2P_SOE_Discharge_B11 : 10|10@1+ (0.1,0) [0|102.3] "%"  PC
 SG_ Reserved_26 : 20|44@1+ (1,0) [0|17592186044415] ""  PC

BO_ 2337074859 M2P_SUMDATA69__27: 8 MBMU
 SG_ M2P_SOE_Charge_B11 : 0|10@1+ (0.1,0) [0|102.3] "%"  PC
 SG_ M2P_SOE_Discharge_B11 : 10|10@1+ (0.1,0) [0|102.3] "%"  PC
 SG_ Reserved_27 : 20|44@1+ (1,0) [0|17592186044415] ""  PC

BO_ 2337074860 M2P_SUMDATA69__28: 8 MBMU
 SG_ M2P_SOE_Charge_B11 : 0|10@1+ (0.1,0) [0|102.3] "%"  PC
 SG_ M2P_SOE_Discharge_B11 : 10|10@1+ (0.1,0) [0|102.3] "%"  PC
 SG_ Reserved_28 : 20|44@1+ (1,0) [0|17592186044415] ""  PC

BO_ 2337074861 M2P_SUMDATA69__29: 8 MBMU
 SG_ M2P_SOE_Charge_B11 : 0|10@1+ (0.1,0) [0|102.3] "%"  PC
 SG_ M2P_SOE_Discharge_B11 : 10|10@1+ (0.1,0) [0|102.3] "%"  PC
 SG_ Reserved_29 : 20|44@1+ (1,0) [0|17592186044415] ""  PC

BO_ 2337074862 M2P_SUMDATA69__30: 8 MBMU
 SG_ M2P_SOE_Charge_B11 : 0|10@1+ (0.1,0) [0|102.3] "%"  PC
 SG_ M2P_SOE_Discharge_B11 : 10|10@1+ (0.1,0) [0|102.3] "%"  PC
 SG_ Reserved_30 : 20|44@1+ (1,0) [0|17592186044415] ""  PC

BO_ 2337074863 M2P_SUMDATA69__31: 8 MBMU
 SG_ M2P_SOE_Charge_B11 : 0|10@1+ (0.1,0) [0|102.3] "%"  PC
 SG_ M2P_SOE_Discharge_B11 : 10|10@1+ (0.1,0) [0|102.3] "%"  PC
 SG_ Reserved_31 : 20|44@1+ (1,0) [0|17592186044415] ""  PC

BO_ 2337140369 M2P_SUMDATA70__01: 8 MBMU
 SG_ M2P_Measure_Vol_B12_01 : 0|16@1+ (0.1,0) [0|6553.5] "V"  PC,SBMU
 SG_ M2P_Current_B12_01 : 16|16@1+ (1,-20000) [-20000|45535] "A"  PC,SBMU
 SG_ M2P_PermitMaxCharge_I_B12_01 : 32|16@1+ (1,-20000) [-20000|45535] "A"  PC
 SG_ M2P_PermitMaxDisCharge_I_B12_01 : 48|16@1+ (1,-20000) [-20000|45535] "A"  PC

BO_ 2337140370 M2P_SUMDATA70__02: 8 MBMU
 SG_ M2P_Measure_Vol_B12_02 : 0|16@1+ (0.1,0) [0|6553.5] "V"  PC,SBMU
 SG_ M2P_Current_B12_02 : 16|16@1+ (1,-20000) [-20000|45535] "A"  PC,SBMU
 SG_ M2P_PermitMaxCharge_I_B12_02 : 32|16@1+ (1,-20000) [-20000|45535] "A"  PC
 SG_ M2P_PermitMaxDisCharge_I_B12_02 : 48|16@1+ (1,-20000) [-20000|45535] "A"  PC

BO_ 2337140371 M2P_SUMDATA70__03: 8 MBMU
 SG_ M2P_Measure_Vol_B12_03 : 0|16@1+ (0.1,0) [0|6553.5] "V"  PC,SBMU
 SG_ M2P_Current_B12_03 : 16|16@1+ (1,-20000) [-20000|45535] "A"  PC,SBMU
 SG_ M2P_PermitMaxCharge_I_B12_03 : 32|16@1+ (1,-20000) [-20000|45535] "A"  PC
 SG_ M2P_PermitMaxDisCharge_I_B12_03 : 48|16@1+ (1,-20000) [-20000|45535] "A"  PC

BO_ 2337140372 M2P_SUMDATA70__04: 8 MBMU
 SG_ M2P_Measure_Vol_B12_04 : 0|16@1+ (0.1,0) [0|6553.5] "V"  PC,SBMU
 SG_ M2P_Current_B12_04 : 16|16@1+ (1,-20000) [-20000|45535] "A"  PC,SBMU
 SG_ M2P_PermitMaxCharge_I_B12_04 : 32|16@1+ (1,-20000) [-20000|45535] "A"  PC
 SG_ M2P_PermitMaxDisCharge_I_B12_04 : 48|16@1+ (1,-20000) [-20000|45535] "A"  PC

BO_ 2337140373 M2P_SUMDATA70__05: 8 MBMU
 SG_ M2P_Measure_Vol_B12_05 : 0|16@1+ (0.1,0) [0|6553.5] "V"  PC,SBMU
 SG_ M2P_Current_B12_05 : 16|16@1+ (1,-20000) [-20000|45535] "A"  PC,SBMU
 SG_ M2P_PermitMaxCharge_I_B12_05 : 32|16@1+ (1,-20000) [-20000|45535] "A"  PC
 SG_ M2P_PermitMaxDisCharge_I_B12_05 : 48|16@1+ (1,-20000) [-20000|45535] "A"  PC

BO_ 2337140374 M2P_SUMDATA70__06: 8 MBMU
 SG_ M2P_Measure_Vol_B12_06 : 0|16@1+ (0.1,0) [0|6553.5] "V"  PC,SBMU
 SG_ M2P_Current_B12_06 : 16|16@1+ (1,-20000) [-20000|45535] "A"  PC,SBMU
 SG_ M2P_PermitMaxCharge_I_B12_06 : 32|16@1+ (1,-20000) [-20000|45535] "A"  PC
 SG_ M2P_PermitMaxDisCharge_I_B12_06 : 48|16@1+ (1,-20000) [-20000|45535] "A"  PC

BO_ 2337140375 M2P_SUMDATA70__07: 8 MBMU
 SG_ M2P_Measure_Vol_B12_07 : 0|16@1+ (0.1,0) [0|6553.5] "V"  PC,SBMU
 SG_ M2P_Current_B12_07 : 16|16@1+ (1,-20000) [-20000|45535] "A"  PC,SBMU
 SG_ M2P_PermitMaxCharge_I_B12_07 : 32|16@1+ (1,-20000) [-20000|45535] "A"  PC
 SG_ M2P_PermitMaxDisCharge_I_B12_07 : 48|16@1+ (1,-20000) [-20000|45535] "A"  PC

BO_ 2337140376 M2P_SUMDATA70__08: 8 MBMU
 SG_ M2P_Measure_Vol_B12_08 : 0|16@1+ (0.1,0) [0|6553.5] "V"  PC,SBMU
 SG_ M2P_Current_B12_08 : 16|16@1+ (1,-20000) [-20000|45535] "A"  PC,SBMU
 SG_ M2P_PermitMaxCharge_I_B12_08 : 32|16@1+ (1,-20000) [-20000|45535] "A"  PC
 SG_ M2P_PermitMaxDisCharge_I_B12_08 : 48|16@1+ (1,-20000) [-20000|45535] "A"  PC

BO_ 2337140377 M2P_SUMDATA70__09: 8 MBMU
 SG_ M2P_Measure_Vol_B12_09 : 0|16@1+ (0.1,0) [0|6553.5] "V"  PC,SBMU
 SG_ M2P_Current_B12_09 : 16|16@1+ (1,-20000) [-20000|45535] "A"  PC,SBMU
 SG_ M2P_PermitMaxCharge_I_B12_09 : 32|16@1+ (1,-20000) [-20000|45535] "A"  PC
 SG_ M2P_PermitMaxDisCharge_I_B12_09 : 48|16@1+ (1,-20000) [-20000|45535] "A"  PC

BO_ 2337140378 M2P_SUMDATA70__10: 8 MBMU
 SG_ M2P_Measure_Vol_B12_10 : 0|16@1+ (0.1,0) [0|6553.5] "V"  PC,SBMU
 SG_ M2P_Current_B12_10 : 16|16@1+ (1,-20000) [-20000|45535] "A"  PC,SBMU
 SG_ M2P_PermitMaxCharge_I_B12_10 : 32|16@1+ (1,-20000) [-20000|45535] "A"  PC
 SG_ M2P_PermitMaxDisCharge_I_B12_10 : 48|16@1+ (1,-20000) [-20000|45535] "A"  PC

BO_ 2337140379 M2P_SUMDATA70__11: 8 MBMU
 SG_ M2P_Measure_Vol_B12_11 : 0|16@1+ (0.1,0) [0|6553.5] "V"  PC,SBMU
 SG_ M2P_Current_B12_11 : 16|16@1+ (1,-20000) [-20000|45535] "A"  PC,SBMU
 SG_ M2P_PermitMaxCharge_I_B12_11 : 32|16@1+ (1,-20000) [-20000|45535] "A"  PC
 SG_ M2P_PermitMaxDisCharge_I_B12_11 : 48|16@1+ (1,-20000) [-20000|45535] "A"  PC

BO_ 2337140380 M2P_SUMDATA70__12: 8 MBMU
 SG_ M2P_Measure_Vol_B12_12 : 0|16@1+ (0.1,0) [0|6553.5] "V"  PC,SBMU
 SG_ M2P_Current_B12_12 : 16|16@1+ (1,-20000) [-20000|45535] "A"  PC,SBMU
 SG_ M2P_PermitMaxCharge_I_B12_12 : 32|16@1+ (1,-20000) [-20000|45535] "A"  PC
 SG_ M2P_PermitMaxDisCharge_I_B12_12 : 48|16@1+ (1,-20000) [-20000|45535] "A"  PC

BO_ 2337140381 M2P_SUMDATA70__13: 8 MBMU
 SG_ M2P_Measure_Vol_B12_13 : 0|16@1+ (0.1,0) [0|6553.5] "V"  PC,SBMU
 SG_ M2P_Current_B12_13 : 16|16@1+ (1,-20000) [-20000|45535] "A"  PC,SBMU
 SG_ M2P_PermitMaxCharge_I_B12_13 : 32|16@1+ (1,-20000) [-20000|45535] "A"  PC
 SG_ M2P_PermitMaxDisCharge_I_B12_13 : 48|16@1+ (1,-20000) [-20000|45535] "A"  PC

BO_ 2337140382 M2P_SUMDATA70__14: 8 MBMU
 SG_ M2P_Measure_Vol_B12_14 : 0|16@1+ (0.1,0) [0|6553.5] "V"  PC,SBMU
 SG_ M2P_Current_B12_14 : 16|16@1+ (1,-20000) [-20000|45535] "A"  PC,SBMU
 SG_ M2P_PermitMaxCharge_I_B12_14 : 32|16@1+ (1,-20000) [-20000|45535] "A"  PC
 SG_ M2P_PermitMaxDisCharge_I_B12_14 : 48|16@1+ (1,-20000) [-20000|45535] "A"  PC

BO_ 2337140383 M2P_SUMDATA70__15: 8 MBMU
 SG_ M2P_Measure_Vol_B12_15 : 0|16@1+ (0.1,0) [0|6553.5] "V"  PC,SBMU
 SG_ M2P_Current_B12_15 : 16|16@1+ (1,-20000) [-20000|45535] "A"  PC,SBMU
 SG_ M2P_PermitMaxCharge_I_B12_15 : 32|16@1+ (1,-20000) [-20000|45535] "A"  PC
 SG_ M2P_PermitMaxDisCharge_I_B12_15 : 48|16@1+ (1,-20000) [-20000|45535] "A"  PC

BO_ 2337140384 M2P_SUMDATA70__16: 8 MBMU
 SG_ M2P_Measure_Vol_B12_16 : 0|16@1+ (0.1,0) [0|6553.5] "V"  PC,SBMU
 SG_ M2P_Current_B12_16 : 16|16@1+ (1,-20000) [-20000|45535] "A"  PC,SBMU
 SG_ M2P_PermitMaxCharge_I_B12_16 : 32|16@1+ (1,-20000) [-20000|45535] "A"  PC
 SG_ M2P_PermitMaxDisCharge_I_B12_16 : 48|16@1+ (1,-20000) [-20000|45535] "A"  PC

BO_ 2337140385 M2P_SUMDATA70__17: 8 MBMU
 SG_ M2P_Measure_Vol_B12_17 : 0|16@1+ (0.1,0) [0|6553.5] "V"  PC,SBMU
 SG_ M2P_Current_B12_17 : 16|16@1+ (1,-20000) [-20000|45535] "A"  PC,SBMU
 SG_ M2P_PermitMaxCharge_I_B12_17 : 32|16@1+ (1,-20000) [-20000|45535] "A"  PC
 SG_ M2P_PermitMaxDisCharge_I_B12_17 : 48|16@1+ (1,-20000) [-20000|45535] "A"  PC

BO_ 2337140386 M2P_SUMDATA70__18: 8 MBMU
 SG_ M2P_Measure_Vol_B12_18 : 0|16@1+ (0.1,0) [0|6553.5] "V"  PC,SBMU
 SG_ M2P_Current_B12_18 : 16|16@1+ (1,-20000) [-20000|45535] "A"  PC,SBMU
 SG_ M2P_PermitMaxCharge_I_B12_18 : 32|16@1+ (1,-20000) [-20000|45535] "A"  PC
 SG_ M2P_PermitMaxDisCharge_I_B12_18 : 48|16@1+ (1,-20000) [-20000|45535] "A"  PC

BO_ 2337140387 M2P_SUMDATA70__19: 8 MBMU
 SG_ M2P_Measure_Vol_B12_19 : 0|16@1+ (0.1,0) [0|6553.5] "V"  PC,SBMU
 SG_ M2P_Current_B12_19 : 16|16@1+ (1,-20000) [-20000|45535] "A"  PC,SBMU
 SG_ M2P_PermitMaxCharge_I_B12_19 : 32|16@1+ (1,-20000) [-20000|45535] "A"  PC
 SG_ M2P_PermitMaxDisCharge_I_B12_19 : 48|16@1+ (1,-20000) [-20000|45535] "A"  PC

BO_ 2337140388 M2P_SUMDATA70__20: 8 MBMU
 SG_ M2P_Measure_Vol_B12_20 : 0|16@1+ (0.1,0) [0|6553.5] "V"  PC,SBMU
 SG_ M2P_Current_B12_20 : 16|16@1+ (1,-20000) [-20000|45535] "A"  PC,SBMU
 SG_ M2P_PermitMaxCharge_I_B12_20 : 32|16@1+ (1,-20000) [-20000|45535] "A"  PC
 SG_ M2P_PermitMaxDisCharge_I_B12_20 : 48|16@1+ (1,-20000) [-20000|45535] "A"  PC

BO_ 2337140389 M2P_SUMDATA70__21: 8 MBMU
 SG_ M2P_Measure_Vol_B12_21 : 0|16@1+ (0.1,0) [0|6553.5] "V"  PC,SBMU
 SG_ M2P_Current_B12_21 : 16|16@1+ (1,-20000) [-20000|45535] "A"  PC,SBMU
 SG_ M2P_PermitMaxCharge_I_B12_21 : 32|16@1+ (1,-20000) [-20000|45535] "A"  PC
 SG_ M2P_PermitMaxDisCharge_I_B12_21 : 48|16@1+ (1,-20000) [-20000|45535] "A"  PC

BO_ 2337140390 M2P_SUMDATA70__22: 8 MBMU
 SG_ M2P_Measure_Vol_B12_22 : 0|16@1+ (0.1,0) [0|6553.5] "V"  PC,SBMU
 SG_ M2P_Current_B12_22 : 16|16@1+ (1,-20000) [-20000|45535] "A"  PC,SBMU
 SG_ M2P_PermitMaxCharge_I_B12_22 : 32|16@1+ (1,-20000) [-20000|45535] "A"  PC
 SG_ M2P_PermitMaxDisCharge_I_B12_22 : 48|16@1+ (1,-20000) [-20000|45535] "A"  PC

BO_ 2337140391 M2P_SUMDATA70__23: 8 MBMU
 SG_ M2P_Measure_Vol_B12_23 : 0|16@1+ (0.1,0) [0|6553.5] "V"  PC,SBMU
 SG_ M2P_Current_B12_23 : 16|16@1+ (1,-20000) [-20000|45535] "A"  PC,SBMU
 SG_ M2P_PermitMaxCharge_I_B12_23 : 32|16@1+ (1,-20000) [-20000|45535] "A"  PC
 SG_ M2P_PermitMaxDisCharge_I_B12_23 : 48|16@1+ (1,-20000) [-20000|45535] "A"  PC

BO_ 2337140392 M2P_SUMDATA70__24: 8 MBMU
 SG_ M2P_Measure_Vol_B12_24 : 0|16@1+ (0.1,0) [0|6553.5] "V"  PC,SBMU
 SG_ M2P_Current_B12_24 : 16|16@1+ (1,-20000) [-20000|45535] "A"  PC,SBMU
 SG_ M2P_PermitMaxCharge_I_B12_24 : 32|16@1+ (1,-20000) [-20000|45535] "A"  PC
 SG_ M2P_PermitMaxDisCharge_I_B12_24 : 48|16@1+ (1,-20000) [-20000|45535] "A"  PC

BO_ 2337140393 M2P_SUMDATA70__25: 8 MBMU
 SG_ M2P_Measure_Vol_B12_25 : 0|16@1+ (0.1,0) [0|6553.5] "V"  PC,SBMU
 SG_ M2P_Current_B12_25 : 16|16@1+ (1,-20000) [-20000|45535] "A"  PC,SBMU
 SG_ M2P_PermitMaxCharge_I_B12_25 : 32|16@1+ (1,-20000) [-20000|45535] "A"  PC
 SG_ M2P_PermitMaxDisCharge_I_B12_25 : 48|16@1+ (1,-20000) [-20000|45535] "A"  PC

BO_ 2337140394 M2P_SUMDATA70__26: 8 MBMU
 SG_ M2P_Measure_Vol_B12_26 : 0|16@1+ (0.1,0) [0|6553.5] "V"  PC,SBMU
 SG_ M2P_Current_B12_26 : 16|16@1+ (1,-20000) [-20000|45535] "A"  PC,SBMU
 SG_ M2P_PermitMaxCharge_I_B12_26 : 32|16@1+ (1,-20000) [-20000|45535] "A"  PC
 SG_ M2P_PermitMaxDisCharge_I_B12_26 : 48|16@1+ (1,-20000) [-20000|45535] "A"  PC

BO_ 2337140395 M2P_SUMDATA70__27: 8 MBMU
 SG_ M2P_Measure_Vol_B12_27 : 0|16@1+ (0.1,0) [0|6553.5] "V"  PC,SBMU
 SG_ M2P_Current_B12_27 : 16|16@1+ (1,-20000) [-20000|45535] "A"  PC,SBMU
 SG_ M2P_PermitMaxCharge_I_B12_27 : 32|16@1+ (1,-20000) [-20000|45535] "A"  PC
 SG_ M2P_PermitMaxDisCharge_I_B12_27 : 48|16@1+ (1,-20000) [-20000|45535] "A"  PC

BO_ 2337140396 M2P_SUMDATA70__28: 8 MBMU
 SG_ M2P_Measure_Vol_B12_28 : 0|16@1+ (0.1,0) [0|6553.5] "V"  PC,SBMU
 SG_ M2P_Current_B12_28 : 16|16@1+ (1,-20000) [-20000|45535] "A"  PC,SBMU
 SG_ M2P_PermitMaxCharge_I_B12_28 : 32|16@1+ (1,-20000) [-20000|45535] "A"  PC
 SG_ M2P_PermitMaxDisCharge_I_B12_28 : 48|16@1+ (1,-20000) [-20000|45535] "A"  PC

BO_ 2337140397 M2P_SUMDATA70__29: 8 MBMU
 SG_ M2P_Measure_Vol_B12_29 : 0|16@1+ (0.1,0) [0|6553.5] "V"  PC,SBMU
 SG_ M2P_Current_B12_29 : 16|16@1+ (1,-20000) [-20000|45535] "A"  PC,SBMU
 SG_ M2P_PermitMaxCharge_I_B12_29 : 32|16@1+ (1,-20000) [-20000|45535] "A"  PC
 SG_ M2P_PermitMaxDisCharge_I_B12_29 : 48|16@1+ (1,-20000) [-20000|45535] "A"  PC

BO_ 2337140398 M2P_SUMDATA70__30: 8 MBMU
 SG_ M2P_Measure_Vol_B12_30 : 0|16@1+ (0.1,0) [0|6553.5] "V"  PC,SBMU
 SG_ M2P_Current_B12_30 : 16|16@1+ (1,-20000) [-20000|45535] "A"  PC,SBMU
 SG_ M2P_PermitMaxCharge_I_B12_30 : 32|16@1+ (1,-20000) [-20000|45535] "A"  PC
 SG_ M2P_PermitMaxDisCharge_I_B12_30 : 48|16@1+ (1,-20000) [-20000|45535] "A"  PC

BO_ 2337140399 M2P_SUMDATA70__31: 8 MBMU
 SG_ M2P_Measure_Vol_B12_31 : 0|16@1+ (0.1,0) [0|6553.5] "V"  PC,SBMU
 SG_ M2P_Current_B12_31 : 16|16@1+ (1,-20000) [-20000|45535] "A"  PC,SBMU
 SG_ M2P_PermitMaxCharge_I_B12_31 : 32|16@1+ (1,-20000) [-20000|45535] "A"  PC
 SG_ M2P_PermitMaxDisCharge_I_B12_31 : 48|16@1+ (1,-20000) [-20000|45535] "A"  PC

BO_ 2337205905 M2P_SUMDATA71__01: 8 MBMU
 SG_ M2P_PermitMaxVolt_B12_01 : 0|16@1+ (0.1,0) [0|6553.5] "V"  PC
 SG_ M2P_PermitMinVolt_B12_01 : 16|16@1+ (0.1,0) [0|6553.5] "V"  PC
 SG_ M2P_PermitMaxPow_Chg_B12_01 : 32|16@1+ (1,-20000) [-20000|45535] "Kw"  PC
 SG_ M2P_PermitMaxPow_DisChg_B12_01 : 48|16@1+ (1,-20000) [-20000|45535] "Kw"  PC

BO_ 2337205906 M2P_SUMDATA71__02: 8 MBMU
 SG_ M2P_PermitMaxVolt_B12_02 : 0|16@1+ (0.1,0) [0|6553.5] "V"  PC
 SG_ M2P_PermitMinVolt_B12_02 : 16|16@1+ (0.1,0) [0|6553.5] "V"  PC
 SG_ M2P_PermitMaxPow_Chg_B12_02 : 32|16@1+ (1,-20000) [-20000|45535] "Kw"  PC
 SG_ M2P_PermitMaxPow_DisChg_B12_02 : 48|16@1+ (1,-20000) [-20000|45535] "Kw"  PC

BO_ 2337205907 M2P_SUMDATA71__03: 8 MBMU
 SG_ M2P_PermitMaxVolt_B12_03 : 0|16@1+ (0.1,0) [0|6553.5] "V"  PC
 SG_ M2P_PermitMinVolt_B12_03 : 16|16@1+ (0.1,0) [0|6553.5] "V"  PC
 SG_ M2P_PermitMaxPow_Chg_B12_03 : 32|16@1+ (1,-20000) [-20000|45535] "Kw"  PC
 SG_ M2P_PermitMaxPow_DisChg_B12_03 : 48|16@1+ (1,-20000) [-20000|45535] "Kw"  PC

BO_ 2337205908 M2P_SUMDATA71__04: 8 MBMU
 SG_ M2P_PermitMaxVolt_B12_04 : 0|16@1+ (0.1,0) [0|6553.5] "V"  PC
 SG_ M2P_PermitMinVolt_B12_04 : 16|16@1+ (0.1,0) [0|6553.5] "V"  PC
 SG_ M2P_PermitMaxPow_Chg_B12_04 : 32|16@1+ (1,-20000) [-20000|45535] "Kw"  PC
 SG_ M2P_PermitMaxPow_DisChg_B12_04 : 48|16@1+ (1,-20000) [-20000|45535] "Kw"  PC

BO_ 2337205909 M2P_SUMDATA71__05: 8 MBMU
 SG_ M2P_PermitMaxVolt_B12_05 : 0|16@1+ (0.1,0) [0|6553.5] "V"  PC
 SG_ M2P_PermitMinVolt_B12_05 : 16|16@1+ (0.1,0) [0|6553.5] "V"  PC
 SG_ M2P_PermitMaxPow_Chg_B12_05 : 32|16@1+ (1,-20000) [-20000|45535] "Kw"  PC
 SG_ M2P_PermitMaxPow_DisChg_B12_05 : 48|16@1+ (1,-20000) [-20000|45535] "Kw"  PC

BO_ 2337205910 M2P_SUMDATA71__06: 8 MBMU
 SG_ M2P_PermitMaxVolt_B12_06 : 0|16@1+ (0.1,0) [0|6553.5] "V"  PC
 SG_ M2P_PermitMinVolt_B12_06 : 16|16@1+ (0.1,0) [0|6553.5] "V"  PC
 SG_ M2P_PermitMaxPow_Chg_B12_06 : 32|16@1+ (1,-20000) [-20000|45535] "Kw"  PC
 SG_ M2P_PermitMaxPow_DisChg_B12_06 : 48|16@1+ (1,-20000) [-20000|45535] "Kw"  PC

BO_ 2337205911 M2P_SUMDATA71__07: 8 MBMU
 SG_ M2P_PermitMaxVolt_B12_07 : 0|16@1+ (0.1,0) [0|6553.5] "V"  PC
 SG_ M2P_PermitMinVolt_B12_07 : 16|16@1+ (0.1,0) [0|6553.5] "V"  PC
 SG_ M2P_PermitMaxPow_Chg_B12_07 : 32|16@1+ (1,-20000) [-20000|45535] "Kw"  PC
 SG_ M2P_PermitMaxPow_DisChg_B12_07 : 48|16@1+ (1,-20000) [-20000|45535] "Kw"  PC

BO_ 2337205912 M2P_SUMDATA71__08: 8 MBMU
 SG_ M2P_PermitMaxVolt_B12_08 : 0|16@1+ (0.1,0) [0|6553.5] "V"  PC
 SG_ M2P_PermitMinVolt_B12_08 : 16|16@1+ (0.1,0) [0|6553.5] "V"  PC
 SG_ M2P_PermitMaxPow_Chg_B12_08 : 32|16@1+ (1,-20000) [-20000|45535] "Kw"  PC
 SG_ M2P_PermitMaxPow_DisChg_B12_08 : 48|16@1+ (1,-20000) [-20000|45535] "Kw"  PC

BO_ 2337205913 M2P_SUMDATA71__09: 8 MBMU
 SG_ M2P_PermitMaxVolt_B12_09 : 0|16@1+ (0.1,0) [0|6553.5] "V"  PC
 SG_ M2P_PermitMinVolt_B12_09 : 16|16@1+ (0.1,0) [0|6553.5] "V"  PC
 SG_ M2P_PermitMaxPow_Chg_B12_09 : 32|16@1+ (1,-20000) [-20000|45535] "Kw"  PC
 SG_ M2P_PermitMaxPow_DisChg_B12_09 : 48|16@1+ (1,-20000) [-20000|45535] "Kw"  PC

BO_ 2337205914 M2P_SUMDATA71__10: 8 MBMU
 SG_ M2P_PermitMaxVolt_B12_10 : 0|16@1+ (0.1,0) [0|6553.5] "V"  PC
 SG_ M2P_PermitMinVolt_B12_10 : 16|16@1+ (0.1,0) [0|6553.5] "V"  PC
 SG_ M2P_PermitMaxPow_Chg_B12_10 : 32|16@1+ (1,-20000) [-20000|45535] "Kw"  PC
 SG_ M2P_PermitMaxPow_DisChg_B12_10 : 48|16@1+ (1,-20000) [-20000|45535] "Kw"  PC

BO_ 2337205915 M2P_SUMDATA71__11: 8 MBMU
 SG_ M2P_PermitMaxVolt_B12_11 : 0|16@1+ (0.1,0) [0|6553.5] "V"  PC
 SG_ M2P_PermitMinVolt_B12_11 : 16|16@1+ (0.1,0) [0|6553.5] "V"  PC
 SG_ M2P_PermitMaxPow_Chg_B12_11 : 32|16@1+ (1,-20000) [-20000|45535] "Kw"  PC
 SG_ M2P_PermitMaxPow_DisChg_B12_11 : 48|16@1+ (1,-20000) [-20000|45535] "Kw"  PC

BO_ 2337205916 M2P_SUMDATA71__12: 8 MBMU
 SG_ M2P_PermitMaxVolt_B12_12 : 0|16@1+ (0.1,0) [0|6553.5] "V"  PC
 SG_ M2P_PermitMinVolt_B12_12 : 16|16@1+ (0.1,0) [0|6553.5] "V"  PC
 SG_ M2P_PermitMaxPow_Chg_B12_12 : 32|16@1+ (1,-20000) [-20000|45535] "Kw"  PC
 SG_ M2P_PermitMaxPow_DisChg_B12_12 : 48|16@1+ (1,-20000) [-20000|45535] "Kw"  PC

BO_ 2337205917 M2P_SUMDATA71__13: 8 MBMU
 SG_ M2P_PermitMaxVolt_B12_13 : 0|16@1+ (0.1,0) [0|6553.5] "V"  PC
 SG_ M2P_PermitMinVolt_B12_13 : 16|16@1+ (0.1,0) [0|6553.5] "V"  PC
 SG_ M2P_PermitMaxPow_Chg_B12_13 : 32|16@1+ (1,-20000) [-20000|45535] "Kw"  PC
 SG_ M2P_PermitMaxPow_DisChg_B12_13 : 48|16@1+ (1,-20000) [-20000|45535] "Kw"  PC

BO_ 2337205918 M2P_SUMDATA71__14: 8 MBMU
 SG_ M2P_PermitMaxVolt_B12_14 : 0|16@1+ (0.1,0) [0|6553.5] "V"  PC
 SG_ M2P_PermitMinVolt_B12_14 : 16|16@1+ (0.1,0) [0|6553.5] "V"  PC
 SG_ M2P_PermitMaxPow_Chg_B12_14 : 32|16@1+ (1,-20000) [-20000|45535] "Kw"  PC
 SG_ M2P_PermitMaxPow_DisChg_B12_14 : 48|16@1+ (1,-20000) [-20000|45535] "Kw"  PC

BO_ 2337205919 M2P_SUMDATA71__15: 8 MBMU
 SG_ M2P_PermitMaxVolt_B12_15 : 0|16@1+ (0.1,0) [0|6553.5] "V"  PC
 SG_ M2P_PermitMinVolt_B12_15 : 16|16@1+ (0.1,0) [0|6553.5] "V"  PC
 SG_ M2P_PermitMaxPow_Chg_B12_15 : 32|16@1+ (1,-20000) [-20000|45535] "Kw"  PC
 SG_ M2P_PermitMaxPow_DisChg_B12_15 : 48|16@1+ (1,-20000) [-20000|45535] "Kw"  PC

BO_ 2337205920 M2P_SUMDATA71__16: 8 MBMU
 SG_ M2P_PermitMaxVolt_B12_16 : 0|16@1+ (0.1,0) [0|6553.5] "V"  PC
 SG_ M2P_PermitMinVolt_B12_16 : 16|16@1+ (0.1,0) [0|6553.5] "V"  PC
 SG_ M2P_PermitMaxPow_Chg_B12_16 : 32|16@1+ (1,-20000) [-20000|45535] "Kw"  PC
 SG_ M2P_PermitMaxPow_DisChg_B12_16 : 48|16@1+ (1,-20000) [-20000|45535] "Kw"  PC

BO_ 2337205921 M2P_SUMDATA71__17: 8 MBMU
 SG_ M2P_PermitMaxVolt_B12_17 : 0|16@1+ (0.1,0) [0|6553.5] "V"  PC
 SG_ M2P_PermitMinVolt_B12_17 : 16|16@1+ (0.1,0) [0|6553.5] "V"  PC
 SG_ M2P_PermitMaxPow_Chg_B12_17 : 32|16@1+ (1,-20000) [-20000|45535] "Kw"  PC
 SG_ M2P_PermitMaxPow_DisChg_B12_17 : 48|16@1+ (1,-20000) [-20000|45535] "Kw"  PC

BO_ 2337205922 M2P_SUMDATA71__18: 8 MBMU
 SG_ M2P_PermitMaxVolt_B12_18 : 0|16@1+ (0.1,0) [0|6553.5] "V"  PC
 SG_ M2P_PermitMinVolt_B12_18 : 16|16@1+ (0.1,0) [0|6553.5] "V"  PC
 SG_ M2P_PermitMaxPow_Chg_B12_18 : 32|16@1+ (1,-20000) [-20000|45535] "Kw"  PC
 SG_ M2P_PermitMaxPow_DisChg_B12_18 : 48|16@1+ (1,-20000) [-20000|45535] "Kw"  PC

BO_ 2337205923 M2P_SUMDATA71__19: 8 MBMU
 SG_ M2P_PermitMaxVolt_B12_19 : 0|16@1+ (0.1,0) [0|6553.5] "V"  PC
 SG_ M2P_PermitMinVolt_B12_19 : 16|16@1+ (0.1,0) [0|6553.5] "V"  PC
 SG_ M2P_PermitMaxPow_Chg_B12_19 : 32|16@1+ (1,-20000) [-20000|45535] "Kw"  PC
 SG_ M2P_PermitMaxPow_DisChg_B12_19 : 48|16@1+ (1,-20000) [-20000|45535] "Kw"  PC

BO_ 2337205924 M2P_SUMDATA71__20: 8 MBMU
 SG_ M2P_PermitMaxVolt_B12_20 : 0|16@1+ (0.1,0) [0|6553.5] "V"  PC
 SG_ M2P_PermitMinVolt_B12_20 : 16|16@1+ (0.1,0) [0|6553.5] "V"  PC
 SG_ M2P_PermitMaxPow_Chg_B12_20 : 32|16@1+ (1,-20000) [-20000|45535] "Kw"  PC
 SG_ M2P_PermitMaxPow_DisChg_B12_20 : 48|16@1+ (1,-20000) [-20000|45535] "Kw"  PC

BO_ 2337205925 M2P_SUMDATA71__21: 8 MBMU
 SG_ M2P_PermitMaxVolt_B12_21 : 0|16@1+ (0.1,0) [0|6553.5] "V"  PC
 SG_ M2P_PermitMinVolt_B12_21 : 16|16@1+ (0.1,0) [0|6553.5] "V"  PC
 SG_ M2P_PermitMaxPow_Chg_B12_21 : 32|16@1+ (1,-20000) [-20000|45535] "Kw"  PC
 SG_ M2P_PermitMaxPow_DisChg_B12_21 : 48|16@1+ (1,-20000) [-20000|45535] "Kw"  PC

BO_ 2337205926 M2P_SUMDATA71__22: 8 MBMU
 SG_ M2P_PermitMaxVolt_B12_22 : 0|16@1+ (0.1,0) [0|6553.5] "V"  PC
 SG_ M2P_PermitMinVolt_B12_22 : 16|16@1+ (0.1,0) [0|6553.5] "V"  PC
 SG_ M2P_PermitMaxPow_Chg_B12_22 : 32|16@1+ (1,-20000) [-20000|45535] "Kw"  PC
 SG_ M2P_PermitMaxPow_DisChg_B12_22 : 48|16@1+ (1,-20000) [-20000|45535] "Kw"  PC

BO_ 2337205927 M2P_SUMDATA71__23: 8 MBMU
 SG_ M2P_PermitMaxVolt_B12_23 : 0|16@1+ (0.1,0) [0|6553.5] "V"  PC
 SG_ M2P_PermitMinVolt_B12_23 : 16|16@1+ (0.1,0) [0|6553.5] "V"  PC
 SG_ M2P_PermitMaxPow_Chg_B12_23 : 32|16@1+ (1,-20000) [-20000|45535] "Kw"  PC
 SG_ M2P_PermitMaxPow_DisChg_B12_23 : 48|16@1+ (1,-20000) [-20000|45535] "Kw"  PC

BO_ 2337205928 M2P_SUMDATA71__24: 8 MBMU
 SG_ M2P_PermitMaxVolt_B12_24 : 0|16@1+ (0.1,0) [0|6553.5] "V"  PC
 SG_ M2P_PermitMinVolt_B12_24 : 16|16@1+ (0.1,0) [0|6553.5] "V"  PC
 SG_ M2P_PermitMaxPow_Chg_B12_24 : 32|16@1+ (1,-20000) [-20000|45535] "Kw"  PC
 SG_ M2P_PermitMaxPow_DisChg_B12_24 : 48|16@1+ (1,-20000) [-20000|45535] "Kw"  PC

BO_ 2337205929 M2P_SUMDATA71__25: 8 MBMU
 SG_ M2P_PermitMaxVolt_B12_25 : 0|16@1+ (0.1,0) [0|6553.5] "V"  PC
 SG_ M2P_PermitMinVolt_B12_25 : 16|16@1+ (0.1,0) [0|6553.5] "V"  PC
 SG_ M2P_PermitMaxPow_Chg_B12_25 : 32|16@1+ (1,-20000) [-20000|45535] "Kw"  PC
 SG_ M2P_PermitMaxPow_DisChg_B12_25 : 48|16@1+ (1,-20000) [-20000|45535] "Kw"  PC

BO_ 2337205930 M2P_SUMDATA71__26: 8 MBMU
 SG_ M2P_PermitMaxVolt_B12_26 : 0|16@1+ (0.1,0) [0|6553.5] "V"  PC
 SG_ M2P_PermitMinVolt_B12_26 : 16|16@1+ (0.1,0) [0|6553.5] "V"  PC
 SG_ M2P_PermitMaxPow_Chg_B12_26 : 32|16@1+ (1,-20000) [-20000|45535] "Kw"  PC
 SG_ M2P_PermitMaxPow_DisChg_B12_26 : 48|16@1+ (1,-20000) [-20000|45535] "Kw"  PC

BO_ 2337205931 M2P_SUMDATA71__27: 8 MBMU
 SG_ M2P_PermitMaxVolt_B12_27 : 0|16@1+ (0.1,0) [0|6553.5] "V"  PC
 SG_ M2P_PermitMinVolt_B12_27 : 16|16@1+ (0.1,0) [0|6553.5] "V"  PC
 SG_ M2P_PermitMaxPow_Chg_B12_27 : 32|16@1+ (1,-20000) [-20000|45535] "Kw"  PC
 SG_ M2P_PermitMaxPow_DisChg_B12_27 : 48|16@1+ (1,-20000) [-20000|45535] "Kw"  PC

BO_ 2337205932 M2P_SUMDATA71__28: 8 MBMU
 SG_ M2P_PermitMaxVolt_B12_28 : 0|16@1+ (0.1,0) [0|6553.5] "V"  PC
 SG_ M2P_PermitMinVolt_B12_28 : 16|16@1+ (0.1,0) [0|6553.5] "V"  PC
 SG_ M2P_PermitMaxPow_Chg_B12_28 : 32|16@1+ (1,-20000) [-20000|45535] "Kw"  PC
 SG_ M2P_PermitMaxPow_DisChg_B12_28 : 48|16@1+ (1,-20000) [-20000|45535] "Kw"  PC

BO_ 2337205933 M2P_SUMDATA71__29: 8 MBMU
 SG_ M2P_PermitMaxVolt_B12_29 : 0|16@1+ (0.1,0) [0|6553.5] "V"  PC
 SG_ M2P_PermitMinVolt_B12_29 : 16|16@1+ (0.1,0) [0|6553.5] "V"  PC
 SG_ M2P_PermitMaxPow_Chg_B12_29 : 32|16@1+ (1,-20000) [-20000|45535] "Kw"  PC
 SG_ M2P_PermitMaxPow_DisChg_B12_29 : 48|16@1+ (1,-20000) [-20000|45535] "Kw"  PC

BO_ 2337205934 M2P_SUMDATA71__30: 8 MBMU
 SG_ M2P_PermitMaxVolt_B12_30 : 0|16@1+ (0.1,0) [0|6553.5] "V"  PC
 SG_ M2P_PermitMinVolt_B12_30 : 16|16@1+ (0.1,0) [0|6553.5] "V"  PC
 SG_ M2P_PermitMaxPow_Chg_B12_30 : 32|16@1+ (1,-20000) [-20000|45535] "Kw"  PC
 SG_ M2P_PermitMaxPow_DisChg_B12_30 : 48|16@1+ (1,-20000) [-20000|45535] "Kw"  PC

BO_ 2337205935 M2P_SUMDATA71__31: 8 MBMU
 SG_ M2P_PermitMaxVolt_B12_31 : 0|16@1+ (0.1,0) [0|6553.5] "V"  PC
 SG_ M2P_PermitMinVolt_B12_31 : 16|16@1+ (0.1,0) [0|6553.5] "V"  PC
 SG_ M2P_PermitMaxPow_Chg_B12_31 : 32|16@1+ (1,-20000) [-20000|45535] "Kw"  PC
 SG_ M2P_PermitMaxPow_DisChg_B12_31 : 48|16@1+ (1,-20000) [-20000|45535] "Kw"  PC

BO_ 2337271441 M2P_SUMDATA72__01: 8 MBMU
 SG_ M2P_Power_B12_01 : 0|16@1+ (1,-20000) [-20000|45535] "Kw"  PC
 SG_ M2P_SysremEngy_Chg_B12_01 : 16|16@1+ (1,0) [0|65535] "Kwh"  PC
 SG_ M2P_SysremEngy_DisChg_B12_01 : 32|16@1+ (1,0) [0|65535] "Kwh"  PC
 SG_ M2P_SysMaxVolt_B12_01 : 48|16@1+ (1,0) [0|65535] "mv"  PC

BO_ 2337271442 M2P_SUMDATA72__02: 8 MBMU
 SG_ M2P_Power_B12_02 : 0|16@1+ (1,-20000) [-20000|45535] "Kw"  PC
 SG_ M2P_SysremEngy_Chg_B12_02 : 16|16@1+ (1,0) [0|65535] "Kwh"  PC
 SG_ M2P_SysremEngy_DisChg_B12_02 : 32|16@1+ (1,0) [0|65535] "Kwh"  PC
 SG_ M2P_SysMaxVolt_B12_02 : 48|16@1+ (1,0) [0|65535] "mv"  PC

BO_ 2337271443 M2P_SUMDATA72__03: 8 MBMU
 SG_ M2P_Power_B12_03 : 0|16@1+ (1,-20000) [-20000|45535] "Kw"  PC
 SG_ M2P_SysremEngy_Chg_B12_03 : 16|16@1+ (1,0) [0|65535] "Kwh"  PC
 SG_ M2P_SysremEngy_DisChg_B12_03 : 32|16@1+ (1,0) [0|65535] "Kwh"  PC
 SG_ M2P_SysMaxVolt_B12_03 : 48|16@1+ (1,0) [0|65535] "mv"  PC

BO_ 2337271444 M2P_SUMDATA72__04: 8 MBMU
 SG_ M2P_Power_B12_04 : 0|16@1+ (1,-20000) [-20000|45535] "Kw"  PC
 SG_ M2P_SysremEngy_Chg_B12_04 : 16|16@1+ (1,0) [0|65535] "Kwh"  PC
 SG_ M2P_SysremEngy_DisChg_B12_04 : 32|16@1+ (1,0) [0|65535] "Kwh"  PC
 SG_ M2P_SysMaxVolt_B12_04 : 48|16@1+ (1,0) [0|65535] "mv"  PC

BO_ 2337271445 M2P_SUMDATA72__05: 8 MBMU
 SG_ M2P_Power_B12_05 : 0|16@1+ (1,-20000) [-20000|45535] "Kw"  PC
 SG_ M2P_SysremEngy_Chg_B12_05 : 16|16@1+ (1,0) [0|65535] "Kwh"  PC
 SG_ M2P_SysremEngy_DisChg_B12_05 : 32|16@1+ (1,0) [0|65535] "Kwh"  PC
 SG_ M2P_SysMaxVolt_B12_05 : 48|16@1+ (1,0) [0|65535] "mv"  PC

BO_ 2337271446 M2P_SUMDATA72__06: 8 MBMU
 SG_ M2P_Power_B12_06 : 0|16@1+ (1,-20000) [-20000|45535] "Kw"  PC
 SG_ M2P_SysremEngy_Chg_B12_06 : 16|16@1+ (1,0) [0|65535] "Kwh"  PC
 SG_ M2P_SysremEngy_DisChg_B12_06 : 32|16@1+ (1,0) [0|65535] "Kwh"  PC
 SG_ M2P_SysMaxVolt_B12_06 : 48|16@1+ (1,0) [0|65535] "mv"  PC

BO_ 2337271447 M2P_SUMDATA72__07: 8 MBMU
 SG_ M2P_Power_B12_07 : 0|16@1+ (1,-20000) [-20000|45535] "Kw"  PC
 SG_ M2P_SysremEngy_Chg_B12_07 : 16|16@1+ (1,0) [0|65535] "Kwh"  PC
 SG_ M2P_SysremEngy_DisChg_B12_07 : 32|16@1+ (1,0) [0|65535] "Kwh"  PC
 SG_ M2P_SysMaxVolt_B12_07 : 48|16@1+ (1,0) [0|65535] "mv"  PC

BO_ 2337271448 M2P_SUMDATA72__08: 8 MBMU
 SG_ M2P_Power_B12_08 : 0|16@1+ (1,-20000) [-20000|45535] "Kw"  PC
 SG_ M2P_SysremEngy_Chg_B12_08 : 16|16@1+ (1,0) [0|65535] "Kwh"  PC
 SG_ M2P_SysremEngy_DisChg_B12_08 : 32|16@1+ (1,0) [0|65535] "Kwh"  PC
 SG_ M2P_SysMaxVolt_B12_08 : 48|16@1+ (1,0) [0|65535] "mv"  PC

BO_ 2337271449 M2P_SUMDATA72__09: 8 MBMU
 SG_ M2P_Power_B12_09 : 0|16@1+ (1,-20000) [-20000|45535] "Kw"  PC
 SG_ M2P_SysremEngy_Chg_B12_09 : 16|16@1+ (1,0) [0|65535] "Kwh"  PC
 SG_ M2P_SysremEngy_DisChg_B12_09 : 32|16@1+ (1,0) [0|65535] "Kwh"  PC
 SG_ M2P_SysMaxVolt_B12_09 : 48|16@1+ (1,0) [0|65535] "mv"  PC

BO_ 2337271450 M2P_SUMDATA72__10: 8 MBMU
 SG_ M2P_Power_B12_10 : 0|16@1+ (1,-20000) [-20000|45535] "Kw"  PC
 SG_ M2P_SysremEngy_Chg_B12_10 : 16|16@1+ (1,0) [0|65535] "Kwh"  PC
 SG_ M2P_SysremEngy_DisChg_B12_10 : 32|16@1+ (1,0) [0|65535] "Kwh"  PC
 SG_ M2P_SysMaxVolt_B12_10 : 48|16@1+ (1,0) [0|65535] "mv"  PC

BO_ 2337271451 M2P_SUMDATA72__11: 8 MBMU
 SG_ M2P_Power_B12_11 : 0|16@1+ (1,-20000) [-20000|45535] "Kw"  PC
 SG_ M2P_SysremEngy_Chg_B12_11 : 16|16@1+ (1,0) [0|65535] "Kwh"  PC
 SG_ M2P_SysremEngy_DisChg_B12_11 : 32|16@1+ (1,0) [0|65535] "Kwh"  PC
 SG_ M2P_SysMaxVolt_B12_11 : 48|16@1+ (1,0) [0|65535] "mv"  PC

BO_ 2337271452 M2P_SUMDATA72__12: 8 MBMU
 SG_ M2P_Power_B12_12 : 0|16@1+ (1,-20000) [-20000|45535] "Kw"  PC
 SG_ M2P_SysremEngy_Chg_B12_12 : 16|16@1+ (1,0) [0|65535] "Kwh"  PC
 SG_ M2P_SysremEngy_DisChg_B12_12 : 32|16@1+ (1,0) [0|65535] "Kwh"  PC
 SG_ M2P_SysMaxVolt_B12_12 : 48|16@1+ (1,0) [0|65535] "mv"  PC

BO_ 2337271453 M2P_SUMDATA72__13: 8 MBMU
 SG_ M2P_Power_B12_13 : 0|16@1+ (1,-20000) [-20000|45535] "Kw"  PC
 SG_ M2P_SysremEngy_Chg_B12_13 : 16|16@1+ (1,0) [0|65535] "Kwh"  PC
 SG_ M2P_SysremEngy_DisChg_B12_13 : 32|16@1+ (1,0) [0|65535] "Kwh"  PC
 SG_ M2P_SysMaxVolt_B12_13 : 48|16@1+ (1,0) [0|65535] "mv"  PC

BO_ 2337271454 M2P_SUMDATA72__14: 8 MBMU
 SG_ M2P_Power_B12_14 : 0|16@1+ (1,-20000) [-20000|45535] "Kw"  PC
 SG_ M2P_SysremEngy_Chg_B12_14 : 16|16@1+ (1,0) [0|65535] "Kwh"  PC
 SG_ M2P_SysremEngy_DisChg_B12_14 : 32|16@1+ (1,0) [0|65535] "Kwh"  PC
 SG_ M2P_SysMaxVolt_B12_14 : 48|16@1+ (1,0) [0|65535] "mv"  PC

BO_ 2337271455 M2P_SUMDATA72__15: 8 MBMU
 SG_ M2P_Power_B12_15 : 0|16@1+ (1,-20000) [-20000|45535] "Kw"  PC
 SG_ M2P_SysremEngy_Chg_B12_15 : 16|16@1+ (1,0) [0|65535] "Kwh"  PC
 SG_ M2P_SysremEngy_DisChg_B12_15 : 32|16@1+ (1,0) [0|65535] "Kwh"  PC
 SG_ M2P_SysMaxVolt_B12_15 : 48|16@1+ (1,0) [0|65535] "mv"  PC

BO_ 2337271456 M2P_SUMDATA72__16: 8 MBMU
 SG_ M2P_Power_B12_16 : 0|16@1+ (1,-20000) [-20000|45535] "Kw"  PC
 SG_ M2P_SysremEngy_Chg_B12_16 : 16|16@1+ (1,0) [0|65535] "Kwh"  PC
 SG_ M2P_SysremEngy_DisChg_B12_16 : 32|16@1+ (1,0) [0|65535] "Kwh"  PC
 SG_ M2P_SysMaxVolt_B12_16 : 48|16@1+ (1,0) [0|65535] "mv"  PC

BO_ 2337271457 M2P_SUMDATA72__17: 8 MBMU
 SG_ M2P_Power_B12_17 : 0|16@1+ (1,-20000) [-20000|45535] "Kw"  PC
 SG_ M2P_SysremEngy_Chg_B12_17 : 16|16@1+ (1,0) [0|65535] "Kwh"  PC
 SG_ M2P_SysremEngy_DisChg_B12_17 : 32|16@1+ (1,0) [0|65535] "Kwh"  PC
 SG_ M2P_SysMaxVolt_B12_17 : 48|16@1+ (1,0) [0|65535] "mv"  PC

BO_ 2337271458 M2P_SUMDATA72__18: 8 MBMU
 SG_ M2P_Power_B12_18 : 0|16@1+ (1,-20000) [-20000|45535] "Kw"  PC
 SG_ M2P_SysremEngy_Chg_B12_18 : 16|16@1+ (1,0) [0|65535] "Kwh"  PC
 SG_ M2P_SysremEngy_DisChg_B12_18 : 32|16@1+ (1,0) [0|65535] "Kwh"  PC
 SG_ M2P_SysMaxVolt_B12_18 : 48|16@1+ (1,0) [0|65535] "mv"  PC

BO_ 2337271459 M2P_SUMDATA72__19: 8 MBMU
 SG_ M2P_Power_B12_19 : 0|16@1+ (1,-20000) [-20000|45535] "Kw"  PC
 SG_ M2P_SysremEngy_Chg_B12_19 : 16|16@1+ (1,0) [0|65535] "Kwh"  PC
 SG_ M2P_SysremEngy_DisChg_B12_19 : 32|16@1+ (1,0) [0|65535] "Kwh"  PC
 SG_ M2P_SysMaxVolt_B12_19 : 48|16@1+ (1,0) [0|65535] "mv"  PC

BO_ 2337271460 M2P_SUMDATA72__20: 8 MBMU
 SG_ M2P_Power_B12_20 : 0|16@1+ (1,-20000) [-20000|45535] "Kw"  PC
 SG_ M2P_SysremEngy_Chg_B12_20 : 16|16@1+ (1,0) [0|65535] "Kwh"  PC
 SG_ M2P_SysremEngy_DisChg_B12_20 : 32|16@1+ (1,0) [0|65535] "Kwh"  PC
 SG_ M2P_SysMaxVolt_B12_20 : 48|16@1+ (1,0) [0|65535] "mv"  PC

BO_ 2337271461 M2P_SUMDATA72__21: 8 MBMU
 SG_ M2P_Power_B12_21 : 0|16@1+ (1,-20000) [-20000|45535] "Kw"  PC
 SG_ M2P_SysremEngy_Chg_B12_21 : 16|16@1+ (1,0) [0|65535] "Kwh"  PC
 SG_ M2P_SysremEngy_DisChg_B12_21 : 32|16@1+ (1,0) [0|65535] "Kwh"  PC
 SG_ M2P_SysMaxVolt_B12_21 : 48|16@1+ (1,0) [0|65535] "mv"  PC

BO_ 2337271462 M2P_SUMDATA72__22: 8 MBMU
 SG_ M2P_Power_B12_22 : 0|16@1+ (1,-20000) [-20000|45535] "Kw"  PC
 SG_ M2P_SysremEngy_Chg_B12_22 : 16|16@1+ (1,0) [0|65535] "Kwh"  PC
 SG_ M2P_SysremEngy_DisChg_B12_22 : 32|16@1+ (1,0) [0|65535] "Kwh"  PC
 SG_ M2P_SysMaxVolt_B12_22 : 48|16@1+ (1,0) [0|65535] "mv"  PC

BO_ 2337271463 M2P_SUMDATA72__23: 8 MBMU
 SG_ M2P_Power_B12_23 : 0|16@1+ (1,-20000) [-20000|45535] "Kw"  PC
 SG_ M2P_SysremEngy_Chg_B12_23 : 16|16@1+ (1,0) [0|65535] "Kwh"  PC
 SG_ M2P_SysremEngy_DisChg_B12_23 : 32|16@1+ (1,0) [0|65535] "Kwh"  PC
 SG_ M2P_SysMaxVolt_B12_23 : 48|16@1+ (1,0) [0|65535] "mv"  PC

BO_ 2337271464 M2P_SUMDATA72__24: 8 MBMU
 SG_ M2P_Power_B12_24 : 0|16@1+ (1,-20000) [-20000|45535] "Kw"  PC
 SG_ M2P_SysremEngy_Chg_B12_24 : 16|16@1+ (1,0) [0|65535] "Kwh"  PC
 SG_ M2P_SysremEngy_DisChg_B12_24 : 32|16@1+ (1,0) [0|65535] "Kwh"  PC
 SG_ M2P_SysMaxVolt_B12_24 : 48|16@1+ (1,0) [0|65535] "mv"  PC

BO_ 2337271465 M2P_SUMDATA72__25: 8 MBMU
 SG_ M2P_Power_B12_25 : 0|16@1+ (1,-20000) [-20000|45535] "Kw"  PC
 SG_ M2P_SysremEngy_Chg_B12_25 : 16|16@1+ (1,0) [0|65535] "Kwh"  PC
 SG_ M2P_SysremEngy_DisChg_B12_25 : 32|16@1+ (1,0) [0|65535] "Kwh"  PC
 SG_ M2P_SysMaxVolt_B12_25 : 48|16@1+ (1,0) [0|65535] "mv"  PC

BO_ 2337271466 M2P_SUMDATA72__26: 8 MBMU
 SG_ M2P_Power_B12_26 : 0|16@1+ (1,-20000) [-20000|45535] "Kw"  PC
 SG_ M2P_SysremEngy_Chg_B12_26 : 16|16@1+ (1,0) [0|65535] "Kwh"  PC
 SG_ M2P_SysremEngy_DisChg_B12_26 : 32|16@1+ (1,0) [0|65535] "Kwh"  PC
 SG_ M2P_SysMaxVolt_B12_26 : 48|16@1+ (1,0) [0|65535] "mv"  PC

BO_ 2337271467 M2P_SUMDATA72__27: 8 MBMU
 SG_ M2P_Power_B12_27 : 0|16@1+ (1,-20000) [-20000|45535] "Kw"  PC
 SG_ M2P_SysremEngy_Chg_B12_27 : 16|16@1+ (1,0) [0|65535] "Kwh"  PC
 SG_ M2P_SysremEngy_DisChg_B12_27 : 32|16@1+ (1,0) [0|65535] "Kwh"  PC
 SG_ M2P_SysMaxVolt_B12_27 : 48|16@1+ (1,0) [0|65535] "mv"  PC

BO_ 2337271468 M2P_SUMDATA72__28: 8 MBMU
 SG_ M2P_Power_B12_28 : 0|16@1+ (1,-20000) [-20000|45535] "Kw"  PC
 SG_ M2P_SysremEngy_Chg_B12_28 : 16|16@1+ (1,0) [0|65535] "Kwh"  PC
 SG_ M2P_SysremEngy_DisChg_B12_28 : 32|16@1+ (1,0) [0|65535] "Kwh"  PC
 SG_ M2P_SysMaxVolt_B12_28 : 48|16@1+ (1,0) [0|65535] "mv"  PC

BO_ 2337271469 M2P_SUMDATA72__29: 8 MBMU
 SG_ M2P_Power_B12_29 : 0|16@1+ (1,-20000) [-20000|45535] "Kw"  PC
 SG_ M2P_SysremEngy_Chg_B12_29 : 16|16@1+ (1,0) [0|65535] "Kwh"  PC
 SG_ M2P_SysremEngy_DisChg_B12_29 : 32|16@1+ (1,0) [0|65535] "Kwh"  PC
 SG_ M2P_SysMaxVolt_B12_29 : 48|16@1+ (1,0) [0|65535] "mv"  PC

BO_ 2337271470 M2P_SUMDATA72__30: 8 MBMU
 SG_ M2P_Power_B12_30 : 0|16@1+ (1,-20000) [-20000|45535] "Kw"  PC
 SG_ M2P_SysremEngy_Chg_B12_30 : 16|16@1+ (1,0) [0|65535] "Kwh"  PC
 SG_ M2P_SysremEngy_DisChg_B12_30 : 32|16@1+ (1,0) [0|65535] "Kwh"  PC
 SG_ M2P_SysMaxVolt_B12_30 : 48|16@1+ (1,0) [0|65535] "mv"  PC

BO_ 2337271471 M2P_SUMDATA72__31: 8 MBMU
 SG_ M2P_Power_B12_31 : 0|16@1+ (1,-20000) [-20000|45535] "Kw"  PC
 SG_ M2P_SysremEngy_Chg_B12_31 : 16|16@1+ (1,0) [0|65535] "Kwh"  PC
 SG_ M2P_SysremEngy_DisChg_B12_31 : 32|16@1+ (1,0) [0|65535] "Kwh"  PC
 SG_ M2P_SysMaxVolt_B12_31 : 48|16@1+ (1,0) [0|65535] "mv"  PC

BO_ 2337336977 M2P_SUMDATA73__01: 8 MBMU
 SG_ M2P_SysMinVolt_B12_01 : 0|16@1+ (1,0) [0|65535] "mv"  PC
 SG_ M2P_SysAvgVolt_B12_01 : 16|16@1+ (1,0) [0|65535] "mv"  PC
 SG_ M2P_BMS_Status_B12 : 32|3@1+ (1,0) [0|7] ""  PC
 SG_ M2P_SOC_B12 : 35|10@1+ (0.1,0) [0|102.3] "%"  PC
 SG_ M2P_SOH_B12 : 45|8@1+ (1,0) [0|255] "%"  PC
 SG_ Reserved_01 : 53|11@1+ (1,0) [0|2047] ""  PC

BO_ 2337336978 M2P_SUMDATA73__02: 8 MBMU
 SG_ M2P_SysMinVolt_B12_02 : 0|16@1+ (1,0) [0|65535] "mv"  PC
 SG_ M2P_SysAvgVolt_B12_02 : 16|16@1+ (1,0) [0|65535] "mv"  PC
 SG_ M2P_BMS_Status_B12 : 32|3@1+ (1,0) [0|7] ""  PC
 SG_ M2P_SOC_B12 : 35|10@1+ (0.1,0) [0|102.3] "%"  PC
 SG_ M2P_SOH_B12 : 45|8@1+ (1,0) [0|255] "%"  PC
 SG_ Reserved_02 : 53|11@1+ (1,0) [0|2047] ""  PC

BO_ 2337336979 M2P_SUMDATA73__03: 8 MBMU
 SG_ M2P_SysMinVolt_B12_03 : 0|16@1+ (1,0) [0|65535] "mv"  PC
 SG_ M2P_SysAvgVolt_B12_03 : 16|16@1+ (1,0) [0|65535] "mv"  PC
 SG_ M2P_BMS_Status_B12 : 32|3@1+ (1,0) [0|7] ""  PC
 SG_ M2P_SOC_B12 : 35|10@1+ (0.1,0) [0|102.3] "%"  PC
 SG_ M2P_SOH_B12 : 45|8@1+ (1,0) [0|255] "%"  PC
 SG_ Reserved_03 : 53|11@1+ (1,0) [0|2047] ""  PC

BO_ 2337336980 M2P_SUMDATA73__04: 8 MBMU
 SG_ M2P_SysMinVolt_B12_04 : 0|16@1+ (1,0) [0|65535] "mv"  PC
 SG_ M2P_SysAvgVolt_B12_04 : 16|16@1+ (1,0) [0|65535] "mv"  PC
 SG_ M2P_BMS_Status_B12 : 32|3@1+ (1,0) [0|7] ""  PC
 SG_ M2P_SOC_B12 : 35|10@1+ (0.1,0) [0|102.3] "%"  PC
 SG_ M2P_SOH_B12 : 45|8@1+ (1,0) [0|255] "%"  PC
 SG_ Reserved_04 : 53|11@1+ (1,0) [0|2047] ""  PC

BO_ 2337336981 M2P_SUMDATA73__05: 8 MBMU
 SG_ M2P_SysMinVolt_B12_05 : 0|16@1+ (1,0) [0|65535] "mv"  PC
 SG_ M2P_SysAvgVolt_B12_05 : 16|16@1+ (1,0) [0|65535] "mv"  PC
 SG_ M2P_BMS_Status_B12 : 32|3@1+ (1,0) [0|7] ""  PC
 SG_ M2P_SOC_B12 : 35|10@1+ (0.1,0) [0|102.3] "%"  PC
 SG_ M2P_SOH_B12 : 45|8@1+ (1,0) [0|255] "%"  PC
 SG_ Reserved_05 : 53|11@1+ (1,0) [0|2047] ""  PC

BO_ 2337336982 M2P_SUMDATA73__06: 8 MBMU
 SG_ M2P_SysMinVolt_B12_06 : 0|16@1+ (1,0) [0|65535] "mv"  PC
 SG_ M2P_SysAvgVolt_B12_06 : 16|16@1+ (1,0) [0|65535] "mv"  PC
 SG_ M2P_BMS_Status_B12 : 32|3@1+ (1,0) [0|7] ""  PC
 SG_ M2P_SOC_B12 : 35|10@1+ (0.1,0) [0|102.3] "%"  PC
 SG_ M2P_SOH_B12 : 45|8@1+ (1,0) [0|255] "%"  PC
 SG_ Reserved_06 : 53|11@1+ (1,0) [0|2047] ""  PC

BO_ 2337336983 M2P_SUMDATA73__07: 8 MBMU
 SG_ M2P_SysMinVolt_B12_07 : 0|16@1+ (1,0) [0|65535] "mv"  PC
 SG_ M2P_SysAvgVolt_B12_07 : 16|16@1+ (1,0) [0|65535] "mv"  PC
 SG_ M2P_BMS_Status_B12 : 32|3@1+ (1,0) [0|7] ""  PC
 SG_ M2P_SOC_B12 : 35|10@1+ (0.1,0) [0|102.3] "%"  PC
 SG_ M2P_SOH_B12 : 45|8@1+ (1,0) [0|255] "%"  PC
 SG_ Reserved_07 : 53|11@1+ (1,0) [0|2047] ""  PC

BO_ 2337336984 M2P_SUMDATA73__08: 8 MBMU
 SG_ M2P_SysMinVolt_B12_08 : 0|16@1+ (1,0) [0|65535] "mv"  PC
 SG_ M2P_SysAvgVolt_B12_08 : 16|16@1+ (1,0) [0|65535] "mv"  PC
 SG_ M2P_BMS_Status_B12 : 32|3@1+ (1,0) [0|7] ""  PC
 SG_ M2P_SOC_B12 : 35|10@1+ (0.1,0) [0|102.3] "%"  PC
 SG_ M2P_SOH_B12 : 45|8@1+ (1,0) [0|255] "%"  PC
 SG_ Reserved_08 : 53|11@1+ (1,0) [0|2047] ""  PC

BO_ 2337336985 M2P_SUMDATA73__09: 8 MBMU
 SG_ M2P_SysMinVolt_B12_09 : 0|16@1+ (1,0) [0|65535] "mv"  PC
 SG_ M2P_SysAvgVolt_B12_09 : 16|16@1+ (1,0) [0|65535] "mv"  PC
 SG_ M2P_BMS_Status_B12 : 32|3@1+ (1,0) [0|7] ""  PC
 SG_ M2P_SOC_B12 : 35|10@1+ (0.1,0) [0|102.3] "%"  PC
 SG_ M2P_SOH_B12 : 45|8@1+ (1,0) [0|255] "%"  PC
 SG_ Reserved_09 : 53|11@1+ (1,0) [0|2047] ""  PC

BO_ 2337336986 M2P_SUMDATA73__10: 8 MBMU
 SG_ M2P_SysMinVolt_B12_10 : 0|16@1+ (1,0) [0|65535] "mv"  PC
 SG_ M2P_SysAvgVolt_B12_10 : 16|16@1+ (1,0) [0|65535] "mv"  PC
 SG_ M2P_BMS_Status_B12 : 32|3@1+ (1,0) [0|7] ""  PC
 SG_ M2P_SOC_B12 : 35|10@1+ (0.1,0) [0|102.3] "%"  PC
 SG_ M2P_SOH_B12 : 45|8@1+ (1,0) [0|255] "%"  PC
 SG_ Reserved_10 : 53|11@1+ (1,0) [0|2047] ""  PC

BO_ 2337336987 M2P_SUMDATA73__11: 8 MBMU
 SG_ M2P_SysMinVolt_B12_11 : 0|16@1+ (1,0) [0|65535] "mv"  PC
 SG_ M2P_SysAvgVolt_B12_11 : 16|16@1+ (1,0) [0|65535] "mv"  PC
 SG_ M2P_BMS_Status_B12 : 32|3@1+ (1,0) [0|7] ""  PC
 SG_ M2P_SOC_B12 : 35|10@1+ (0.1,0) [0|102.3] "%"  PC
 SG_ M2P_SOH_B12 : 45|8@1+ (1,0) [0|255] "%"  PC
 SG_ Reserved_11 : 53|11@1+ (1,0) [0|2047] ""  PC

BO_ 2337336988 M2P_SUMDATA73__12: 8 MBMU
 SG_ M2P_SysMinVolt_B12_12 : 0|16@1+ (1,0) [0|65535] "mv"  PC
 SG_ M2P_SysAvgVolt_B12_12 : 16|16@1+ (1,0) [0|65535] "mv"  PC
 SG_ M2P_BMS_Status_B12 : 32|3@1+ (1,0) [0|7] ""  PC
 SG_ M2P_SOC_B12 : 35|10@1+ (0.1,0) [0|102.3] "%"  PC
 SG_ M2P_SOH_B12 : 45|8@1+ (1,0) [0|255] "%"  PC
 SG_ Reserved_12 : 53|11@1+ (1,0) [0|2047] ""  PC

BO_ 2337336989 M2P_SUMDATA73__13: 8 MBMU
 SG_ M2P_SysMinVolt_B12_13 : 0|16@1+ (1,0) [0|65535] "mv"  PC
 SG_ M2P_SysAvgVolt_B12_13 : 16|16@1+ (1,0) [0|65535] "mv"  PC
 SG_ M2P_BMS_Status_B12 : 32|3@1+ (1,0) [0|7] ""  PC
 SG_ M2P_SOC_B12 : 35|10@1+ (0.1,0) [0|102.3] "%"  PC
 SG_ M2P_SOH_B12 : 45|8@1+ (1,0) [0|255] "%"  PC
 SG_ Reserved_13 : 53|11@1+ (1,0) [0|2047] ""  PC

BO_ 2337336990 M2P_SUMDATA73__14: 8 MBMU
 SG_ M2P_SysMinVolt_B12_14 : 0|16@1+ (1,0) [0|65535] "mv"  PC
 SG_ M2P_SysAvgVolt_B12_14 : 16|16@1+ (1,0) [0|65535] "mv"  PC
 SG_ M2P_BMS_Status_B12 : 32|3@1+ (1,0) [0|7] ""  PC
 SG_ M2P_SOC_B12 : 35|10@1+ (0.1,0) [0|102.3] "%"  PC
 SG_ M2P_SOH_B12 : 45|8@1+ (1,0) [0|255] "%"  PC
 SG_ Reserved_14 : 53|11@1+ (1,0) [0|2047] ""  PC

BO_ 2337336991 M2P_SUMDATA73__15: 8 MBMU
 SG_ M2P_SysMinVolt_B12_15 : 0|16@1+ (1,0) [0|65535] "mv"  PC
 SG_ M2P_SysAvgVolt_B12_15 : 16|16@1+ (1,0) [0|65535] "mv"  PC
 SG_ M2P_BMS_Status_B12 : 32|3@1+ (1,0) [0|7] ""  PC
 SG_ M2P_SOC_B12 : 35|10@1+ (0.1,0) [0|102.3] "%"  PC
 SG_ M2P_SOH_B12 : 45|8@1+ (1,0) [0|255] "%"  PC
 SG_ Reserved_15 : 53|11@1+ (1,0) [0|2047] ""  PC

BO_ 2337336992 M2P_SUMDATA73__16: 8 MBMU
 SG_ M2P_SysMinVolt_B12_16 : 0|16@1+ (1,0) [0|65535] "mv"  PC
 SG_ M2P_SysAvgVolt_B12_16 : 16|16@1+ (1,0) [0|65535] "mv"  PC
 SG_ M2P_BMS_Status_B12 : 32|3@1+ (1,0) [0|7] ""  PC
 SG_ M2P_SOC_B12 : 35|10@1+ (0.1,0) [0|102.3] "%"  PC
 SG_ M2P_SOH_B12 : 45|8@1+ (1,0) [0|255] "%"  PC
 SG_ Reserved_16 : 53|11@1+ (1,0) [0|2047] ""  PC

BO_ 2337336993 M2P_SUMDATA73__17: 8 MBMU
 SG_ M2P_SysMinVolt_B12_17 : 0|16@1+ (1,0) [0|65535] "mv"  PC
 SG_ M2P_SysAvgVolt_B12_17 : 16|16@1+ (1,0) [0|65535] "mv"  PC
 SG_ M2P_BMS_Status_B12 : 32|3@1+ (1,0) [0|7] ""  PC
 SG_ M2P_SOC_B12 : 35|10@1+ (0.1,0) [0|102.3] "%"  PC
 SG_ M2P_SOH_B12 : 45|8@1+ (1,0) [0|255] "%"  PC
 SG_ Reserved_17 : 53|11@1+ (1,0) [0|2047] ""  PC

BO_ 2337336994 M2P_SUMDATA73__18: 8 MBMU
 SG_ M2P_SysMinVolt_B12_18 : 0|16@1+ (1,0) [0|65535] "mv"  PC
 SG_ M2P_SysAvgVolt_B12_18 : 16|16@1+ (1,0) [0|65535] "mv"  PC
 SG_ M2P_BMS_Status_B12 : 32|3@1+ (1,0) [0|7] ""  PC
 SG_ M2P_SOC_B12 : 35|10@1+ (0.1,0) [0|102.3] "%"  PC
 SG_ M2P_SOH_B12 : 45|8@1+ (1,0) [0|255] "%"  PC
 SG_ Reserved_18 : 53|11@1+ (1,0) [0|2047] ""  PC

BO_ 2337336995 M2P_SUMDATA73__19: 8 MBMU
 SG_ M2P_SysMinVolt_B12_19 : 0|16@1+ (1,0) [0|65535] "mv"  PC
 SG_ M2P_SysAvgVolt_B12_19 : 16|16@1+ (1,0) [0|65535] "mv"  PC
 SG_ M2P_BMS_Status_B12 : 32|3@1+ (1,0) [0|7] ""  PC
 SG_ M2P_SOC_B12 : 35|10@1+ (0.1,0) [0|102.3] "%"  PC
 SG_ M2P_SOH_B12 : 45|8@1+ (1,0) [0|255] "%"  PC
 SG_ Reserved_19 : 53|11@1+ (1,0) [0|2047] ""  PC

BO_ 2337336996 M2P_SUMDATA73__20: 8 MBMU
 SG_ M2P_SysMinVolt_B12_20 : 0|16@1+ (1,0) [0|65535] "mv"  PC
 SG_ M2P_SysAvgVolt_B12_20 : 16|16@1+ (1,0) [0|65535] "mv"  PC
 SG_ M2P_BMS_Status_B12 : 32|3@1+ (1,0) [0|7] ""  PC
 SG_ M2P_SOC_B12 : 35|10@1+ (0.1,0) [0|102.3] "%"  PC
 SG_ M2P_SOH_B12 : 45|8@1+ (1,0) [0|255] "%"  PC
 SG_ Reserved_20 : 53|11@1+ (1,0) [0|2047] ""  PC

BO_ 2337336997 M2P_SUMDATA73__21: 8 MBMU
 SG_ M2P_SysMinVolt_B12_21 : 0|16@1+ (1,0) [0|65535] "mv"  PC
 SG_ M2P_SysAvgVolt_B12_21 : 16|16@1+ (1,0) [0|65535] "mv"  PC
 SG_ M2P_BMS_Status_B12 : 32|3@1+ (1,0) [0|7] ""  PC
 SG_ M2P_SOC_B12 : 35|10@1+ (0.1,0) [0|102.3] "%"  PC
 SG_ M2P_SOH_B12 : 45|8@1+ (1,0) [0|255] "%"  PC
 SG_ Reserved_21 : 53|11@1+ (1,0) [0|2047] ""  PC

BO_ 2337336998 M2P_SUMDATA73__22: 8 MBMU
 SG_ M2P_SysMinVolt_B12_22 : 0|16@1+ (1,0) [0|65535] "mv"  PC
 SG_ M2P_SysAvgVolt_B12_22 : 16|16@1+ (1,0) [0|65535] "mv"  PC
 SG_ M2P_BMS_Status_B12 : 32|3@1+ (1,0) [0|7] ""  PC
 SG_ M2P_SOC_B12 : 35|10@1+ (0.1,0) [0|102.3] "%"  PC
 SG_ M2P_SOH_B12 : 45|8@1+ (1,0) [0|255] "%"  PC
 SG_ Reserved_22 : 53|11@1+ (1,0) [0|2047] ""  PC

BO_ 2337336999 M2P_SUMDATA73__23: 8 MBMU
 SG_ M2P_SysMinVolt_B12_23 : 0|16@1+ (1,0) [0|65535] "mv"  PC
 SG_ M2P_SysAvgVolt_B12_23 : 16|16@1+ (1,0) [0|65535] "mv"  PC
 SG_ M2P_BMS_Status_B12 : 32|3@1+ (1,0) [0|7] ""  PC
 SG_ M2P_SOC_B12 : 35|10@1+ (0.1,0) [0|102.3] "%"  PC
 SG_ M2P_SOH_B12 : 45|8@1+ (1,0) [0|255] "%"  PC
 SG_ Reserved_23 : 53|11@1+ (1,0) [0|2047] ""  PC

BO_ 2337337000 M2P_SUMDATA73__24: 8 MBMU
 SG_ M2P_SysMinVolt_B12_24 : 0|16@1+ (1,0) [0|65535] "mv"  PC
 SG_ M2P_SysAvgVolt_B12_24 : 16|16@1+ (1,0) [0|65535] "mv"  PC
 SG_ M2P_BMS_Status_B12 : 32|3@1+ (1,0) [0|7] ""  PC
 SG_ M2P_SOC_B12 : 35|10@1+ (0.1,0) [0|102.3] "%"  PC
 SG_ M2P_SOH_B12 : 45|8@1+ (1,0) [0|255] "%"  PC
 SG_ Reserved_24 : 53|11@1+ (1,0) [0|2047] ""  PC

BO_ 2337337001 M2P_SUMDATA73__25: 8 MBMU
 SG_ M2P_SysMinVolt_B12_25 : 0|16@1+ (1,0) [0|65535] "mv"  PC
 SG_ M2P_SysAvgVolt_B12_25 : 16|16@1+ (1,0) [0|65535] "mv"  PC
 SG_ M2P_BMS_Status_B12 : 32|3@1+ (1,0) [0|7] ""  PC
 SG_ M2P_SOC_B12 : 35|10@1+ (0.1,0) [0|102.3] "%"  PC
 SG_ M2P_SOH_B12 : 45|8@1+ (1,0) [0|255] "%"  PC
 SG_ Reserved_25 : 53|11@1+ (1,0) [0|2047] ""  PC

BO_ 2337337002 M2P_SUMDATA73__26: 8 MBMU
 SG_ M2P_SysMinVolt_B12_26 : 0|16@1+ (1,0) [0|65535] "mv"  PC
 SG_ M2P_SysAvgVolt_B12_26 : 16|16@1+ (1,0) [0|65535] "mv"  PC
 SG_ M2P_BMS_Status_B12 : 32|3@1+ (1,0) [0|7] ""  PC
 SG_ M2P_SOC_B12 : 35|10@1+ (0.1,0) [0|102.3] "%"  PC
 SG_ M2P_SOH_B12 : 45|8@1+ (1,0) [0|255] "%"  PC
 SG_ Reserved_26 : 53|11@1+ (1,0) [0|2047] ""  PC

BO_ 2337337003 M2P_SUMDATA73__27: 8 MBMU
 SG_ M2P_SysMinVolt_B12_27 : 0|16@1+ (1,0) [0|65535] "mv"  PC
 SG_ M2P_SysAvgVolt_B12_27 : 16|16@1+ (1,0) [0|65535] "mv"  PC
 SG_ M2P_BMS_Status_B12 : 32|3@1+ (1,0) [0|7] ""  PC
 SG_ M2P_SOC_B12 : 35|10@1+ (0.1,0) [0|102.3] "%"  PC
 SG_ M2P_SOH_B12 : 45|8@1+ (1,0) [0|255] "%"  PC
 SG_ Reserved_27 : 53|11@1+ (1,0) [0|2047] ""  PC

BO_ 2337337004 M2P_SUMDATA73__28: 8 MBMU
 SG_ M2P_SysMinVolt_B12_28 : 0|16@1+ (1,0) [0|65535] "mv"  PC
 SG_ M2P_SysAvgVolt_B12_28 : 16|16@1+ (1,0) [0|65535] "mv"  PC
 SG_ M2P_BMS_Status_B12 : 32|3@1+ (1,0) [0|7] ""  PC
 SG_ M2P_SOC_B12 : 35|10@1+ (0.1,0) [0|102.3] "%"  PC
 SG_ M2P_SOH_B12 : 45|8@1+ (1,0) [0|255] "%"  PC
 SG_ Reserved_28 : 53|11@1+ (1,0) [0|2047] ""  PC

BO_ 2337337005 M2P_SUMDATA73__29: 8 MBMU
 SG_ M2P_SysMinVolt_B12_29 : 0|16@1+ (1,0) [0|65535] "mv"  PC
 SG_ M2P_SysAvgVolt_B12_29 : 16|16@1+ (1,0) [0|65535] "mv"  PC
 SG_ M2P_BMS_Status_B12 : 32|3@1+ (1,0) [0|7] ""  PC
 SG_ M2P_SOC_B12 : 35|10@1+ (0.1,0) [0|102.3] "%"  PC
 SG_ M2P_SOH_B12 : 45|8@1+ (1,0) [0|255] "%"  PC
 SG_ Reserved_29 : 53|11@1+ (1,0) [0|2047] ""  PC

BO_ 2337337006 M2P_SUMDATA73__30: 8 MBMU
 SG_ M2P_SysMinVolt_B12_30 : 0|16@1+ (1,0) [0|65535] "mv"  PC
 SG_ M2P_SysAvgVolt_B12_30 : 16|16@1+ (1,0) [0|65535] "mv"  PC
 SG_ M2P_BMS_Status_B12 : 32|3@1+ (1,0) [0|7] ""  PC
 SG_ M2P_SOC_B12 : 35|10@1+ (0.1,0) [0|102.3] "%"  PC
 SG_ M2P_SOH_B12 : 45|8@1+ (1,0) [0|255] "%"  PC
 SG_ Reserved_30 : 53|11@1+ (1,0) [0|2047] ""  PC

BO_ 2337337007 M2P_SUMDATA73__31: 8 MBMU
 SG_ M2P_SysMinVolt_B12_31 : 0|16@1+ (1,0) [0|65535] "mv"  PC
 SG_ M2P_SysAvgVolt_B12_31 : 16|16@1+ (1,0) [0|65535] "mv"  PC
 SG_ M2P_BMS_Status_B12 : 32|3@1+ (1,0) [0|7] ""  PC
 SG_ M2P_SOC_B12 : 35|10@1+ (0.1,0) [0|102.3] "%"  PC
 SG_ M2P_SOH_B12 : 45|8@1+ (1,0) [0|255] "%"  PC
 SG_ Reserved_31 : 53|11@1+ (1,0) [0|2047] ""  PC

BO_ 2337402513 M2P_SUMDATA74__01: 8 MBMU
 SG_ M2P_SOE_Charge_B12 : 0|10@1+ (0.1,0) [0|102.3] "%"  PC
 SG_ M2P_SOE_Discharge_B12 : 10|10@1+ (0.1,0) [0|102.3] "%"  PC
 SG_ Reserved_01 : 20|44@1+ (1,0) [0|17592186044415] ""  PC

BO_ 2337402514 M2P_SUMDATA74__02: 8 MBMU
 SG_ M2P_SOE_Charge_B12 : 0|10@1+ (0.1,0) [0|102.3] "%"  PC
 SG_ M2P_SOE_Discharge_B12 : 10|10@1+ (0.1,0) [0|102.3] "%"  PC
 SG_ Reserved_02 : 20|44@1+ (1,0) [0|17592186044415] ""  PC

BO_ 2337402515 M2P_SUMDATA74__03: 8 MBMU
 SG_ M2P_SOE_Charge_B12 : 0|10@1+ (0.1,0) [0|102.3] "%"  PC
 SG_ M2P_SOE_Discharge_B12 : 10|10@1+ (0.1,0) [0|102.3] "%"  PC
 SG_ Reserved_03 : 20|44@1+ (1,0) [0|17592186044415] ""  PC

BO_ 2337402516 M2P_SUMDATA74__04: 8 MBMU
 SG_ M2P_SOE_Charge_B12 : 0|10@1+ (0.1,0) [0|102.3] "%"  PC
 SG_ M2P_SOE_Discharge_B12 : 10|10@1+ (0.1,0) [0|102.3] "%"  PC
 SG_ Reserved_04 : 20|44@1+ (1,0) [0|17592186044415] ""  PC

BO_ 2337402517 M2P_SUMDATA74__05: 8 MBMU
 SG_ M2P_SOE_Charge_B12 : 0|10@1+ (0.1,0) [0|102.3] "%"  PC
 SG_ M2P_SOE_Discharge_B12 : 10|10@1+ (0.1,0) [0|102.3] "%"  PC
 SG_ Reserved_05 : 20|44@1+ (1,0) [0|17592186044415] ""  PC

BO_ 2337402518 M2P_SUMDATA74__06: 8 MBMU
 SG_ M2P_SOE_Charge_B12 : 0|10@1+ (0.1,0) [0|102.3] "%"  PC
 SG_ M2P_SOE_Discharge_B12 : 10|10@1+ (0.1,0) [0|102.3] "%"  PC
 SG_ Reserved_06 : 20|44@1+ (1,0) [0|17592186044415] ""  PC

BO_ 2337402519 M2P_SUMDATA74__07: 8 MBMU
 SG_ M2P_SOE_Charge_B12 : 0|10@1+ (0.1,0) [0|102.3] "%"  PC
 SG_ M2P_SOE_Discharge_B12 : 10|10@1+ (0.1,0) [0|102.3] "%"  PC
 SG_ Reserved_07 : 20|44@1+ (1,0) [0|17592186044415] ""  PC

BO_ 2337402520 M2P_SUMDATA74__08: 8 MBMU
 SG_ M2P_SOE_Charge_B12 : 0|10@1+ (0.1,0) [0|102.3] "%"  PC
 SG_ M2P_SOE_Discharge_B12 : 10|10@1+ (0.1,0) [0|102.3] "%"  PC
 SG_ Reserved_08 : 20|44@1+ (1,0) [0|17592186044415] ""  PC

BO_ 2337402521 M2P_SUMDATA74__09: 8 MBMU
 SG_ M2P_SOE_Charge_B12 : 0|10@1+ (0.1,0) [0|102.3] "%"  PC
 SG_ M2P_SOE_Discharge_B12 : 10|10@1+ (0.1,0) [0|102.3] "%"  PC
 SG_ Reserved_09 : 20|44@1+ (1,0) [0|17592186044415] ""  PC

BO_ 2337402522 M2P_SUMDATA74__10: 8 MBMU
 SG_ M2P_SOE_Charge_B12 : 0|10@1+ (0.1,0) [0|102.3] "%"  PC
 SG_ M2P_SOE_Discharge_B12 : 10|10@1+ (0.1,0) [0|102.3] "%"  PC
 SG_ Reserved_10 : 20|44@1+ (1,0) [0|17592186044415] ""  PC

BO_ 2337402523 M2P_SUMDATA74__11: 8 MBMU
 SG_ M2P_SOE_Charge_B12 : 0|10@1+ (0.1,0) [0|102.3] "%"  PC
 SG_ M2P_SOE_Discharge_B12 : 10|10@1+ (0.1,0) [0|102.3] "%"  PC
 SG_ Reserved_11 : 20|44@1+ (1,0) [0|17592186044415] ""  PC

BO_ 2337402524 M2P_SUMDATA74__12: 8 MBMU
 SG_ M2P_SOE_Charge_B12 : 0|10@1+ (0.1,0) [0|102.3] "%"  PC
 SG_ M2P_SOE_Discharge_B12 : 10|10@1+ (0.1,0) [0|102.3] "%"  PC
 SG_ Reserved_12 : 20|44@1+ (1,0) [0|17592186044415] ""  PC

BO_ 2337402525 M2P_SUMDATA74__13: 8 MBMU
 SG_ M2P_SOE_Charge_B12 : 0|10@1+ (0.1,0) [0|102.3] "%"  PC
 SG_ M2P_SOE_Discharge_B12 : 10|10@1+ (0.1,0) [0|102.3] "%"  PC
 SG_ Reserved_13 : 20|44@1+ (1,0) [0|17592186044415] ""  PC

BO_ 2337402526 M2P_SUMDATA74__14: 8 MBMU
 SG_ M2P_SOE_Charge_B12 : 0|10@1+ (0.1,0) [0|102.3] "%"  PC
 SG_ M2P_SOE_Discharge_B12 : 10|10@1+ (0.1,0) [0|102.3] "%"  PC
 SG_ Reserved_14 : 20|44@1+ (1,0) [0|17592186044415] ""  PC

BO_ 2337402527 M2P_SUMDATA74__15: 8 MBMU
 SG_ M2P_SOE_Charge_B12 : 0|10@1+ (0.1,0) [0|102.3] "%"  PC
 SG_ M2P_SOE_Discharge_B12 : 10|10@1+ (0.1,0) [0|102.3] "%"  PC
 SG_ Reserved_15 : 20|44@1+ (1,0) [0|17592186044415] ""  PC

BO_ 2337402528 M2P_SUMDATA74__16: 8 MBMU
 SG_ M2P_SOE_Charge_B12 : 0|10@1+ (0.1,0) [0|102.3] "%"  PC
 SG_ M2P_SOE_Discharge_B12 : 10|10@1+ (0.1,0) [0|102.3] "%"  PC
 SG_ Reserved_16 : 20|44@1+ (1,0) [0|17592186044415] ""  PC

BO_ 2337402529 M2P_SUMDATA74__17: 8 MBMU
 SG_ M2P_SOE_Charge_B12 : 0|10@1+ (0.1,0) [0|102.3] "%"  PC
 SG_ M2P_SOE_Discharge_B12 : 10|10@1+ (0.1,0) [0|102.3] "%"  PC
 SG_ Reserved_17 : 20|44@1+ (1,0) [0|17592186044415] ""  PC

BO_ 2337402530 M2P_SUMDATA74__18: 8 MBMU
 SG_ M2P_SOE_Charge_B12 : 0|10@1+ (0.1,0) [0|102.3] "%"  PC
 SG_ M2P_SOE_Discharge_B12 : 10|10@1+ (0.1,0) [0|102.3] "%"  PC
 SG_ Reserved_18 : 20|44@1+ (1,0) [0|17592186044415] ""  PC

BO_ 2337402531 M2P_SUMDATA74__19: 8 MBMU
 SG_ M2P_SOE_Charge_B12 : 0|10@1+ (0.1,0) [0|102.3] "%"  PC
 SG_ M2P_SOE_Discharge_B12 : 10|10@1+ (0.1,0) [0|102.3] "%"  PC
 SG_ Reserved_19 : 20|44@1+ (1,0) [0|17592186044415] ""  PC

BO_ 2337402532 M2P_SUMDATA74__20: 8 MBMU
 SG_ M2P_SOE_Charge_B12 : 0|10@1+ (0.1,0) [0|102.3] "%"  PC
 SG_ M2P_SOE_Discharge_B12 : 10|10@1+ (0.1,0) [0|102.3] "%"  PC
 SG_ Reserved_20 : 20|44@1+ (1,0) [0|17592186044415] ""  PC

BO_ 2337402533 M2P_SUMDATA74__21: 8 MBMU
 SG_ M2P_SOE_Charge_B12 : 0|10@1+ (0.1,0) [0|102.3] "%"  PC
 SG_ M2P_SOE_Discharge_B12 : 10|10@1+ (0.1,0) [0|102.3] "%"  PC
 SG_ Reserved_21 : 20|44@1+ (1,0) [0|17592186044415] ""  PC

BO_ 2337402534 M2P_SUMDATA74__22: 8 MBMU
 SG_ M2P_SOE_Charge_B12 : 0|10@1+ (0.1,0) [0|102.3] "%"  PC
 SG_ M2P_SOE_Discharge_B12 : 10|10@1+ (0.1,0) [0|102.3] "%"  PC
 SG_ Reserved_22 : 20|44@1+ (1,0) [0|17592186044415] ""  PC

BO_ 2337402535 M2P_SUMDATA74__23: 8 MBMU
 SG_ M2P_SOE_Charge_B12 : 0|10@1+ (0.1,0) [0|102.3] "%"  PC
 SG_ M2P_SOE_Discharge_B12 : 10|10@1+ (0.1,0) [0|102.3] "%"  PC
 SG_ Reserved_23 : 20|44@1+ (1,0) [0|17592186044415] ""  PC

BO_ 2337402536 M2P_SUMDATA74__24: 8 MBMU
 SG_ M2P_SOE_Charge_B12 : 0|10@1+ (0.1,0) [0|102.3] "%"  PC
 SG_ M2P_SOE_Discharge_B12 : 10|10@1+ (0.1,0) [0|102.3] "%"  PC
 SG_ Reserved_24 : 20|44@1+ (1,0) [0|17592186044415] ""  PC

BO_ 2337402537 M2P_SUMDATA74__25: 8 MBMU
 SG_ M2P_SOE_Charge_B12 : 0|10@1+ (0.1,0) [0|102.3] "%"  PC
 SG_ M2P_SOE_Discharge_B12 : 10|10@1+ (0.1,0) [0|102.3] "%"  PC
 SG_ Reserved_25 : 20|44@1+ (1,0) [0|17592186044415] ""  PC

BO_ 2337402538 M2P_SUMDATA74__26: 8 MBMU
 SG_ M2P_SOE_Charge_B12 : 0|10@1+ (0.1,0) [0|102.3] "%"  PC
 SG_ M2P_SOE_Discharge_B12 : 10|10@1+ (0.1,0) [0|102.3] "%"  PC
 SG_ Reserved_26 : 20|44@1+ (1,0) [0|17592186044415] ""  PC

BO_ 2337402539 M2P_SUMDATA74__27: 8 MBMU
 SG_ M2P_SOE_Charge_B12 : 0|10@1+ (0.1,0) [0|102.3] "%"  PC
 SG_ M2P_SOE_Discharge_B12 : 10|10@1+ (0.1,0) [0|102.3] "%"  PC
 SG_ Reserved_27 : 20|44@1+ (1,0) [0|17592186044415] ""  PC

BO_ 2337402540 M2P_SUMDATA74__28: 8 MBMU
 SG_ M2P_SOE_Charge_B12 : 0|10@1+ (0.1,0) [0|102.3] "%"  PC
 SG_ M2P_SOE_Discharge_B12 : 10|10@1+ (0.1,0) [0|102.3] "%"  PC
 SG_ Reserved_28 : 20|44@1+ (1,0) [0|17592186044415] ""  PC

BO_ 2337402541 M2P_SUMDATA74__29: 8 MBMU
 SG_ M2P_SOE_Charge_B12 : 0|10@1+ (0.1,0) [0|102.3] "%"  PC
 SG_ M2P_SOE_Discharge_B12 : 10|10@1+ (0.1,0) [0|102.3] "%"  PC
 SG_ Reserved_29 : 20|44@1+ (1,0) [0|17592186044415] ""  PC

BO_ 2337402542 M2P_SUMDATA74__30: 8 MBMU
 SG_ M2P_SOE_Charge_B12 : 0|10@1+ (0.1,0) [0|102.3] "%"  PC
 SG_ M2P_SOE_Discharge_B12 : 10|10@1+ (0.1,0) [0|102.3] "%"  PC
 SG_ Reserved_30 : 20|44@1+ (1,0) [0|17592186044415] ""  PC

BO_ 2337402543 M2P_SUMDATA74__31: 8 MBMU
 SG_ M2P_SOE_Charge_B12 : 0|10@1+ (0.1,0) [0|102.3] "%"  PC
 SG_ M2P_SOE_Discharge_B12 : 10|10@1+ (0.1,0) [0|102.3] "%"  PC
 SG_ Reserved_31 : 20|44@1+ (1,0) [0|17592186044415] ""  PC

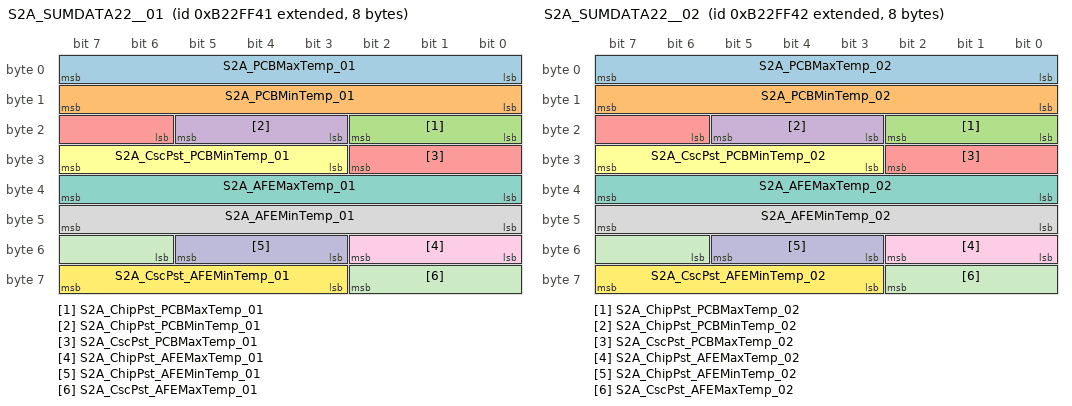
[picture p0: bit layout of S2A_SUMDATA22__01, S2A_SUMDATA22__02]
BO_ 2334326593 S2A_SUMDATA22__01: 8 SBMU
 SG_ S2A_PCBMaxTemp_01 : 0|8@1+ (1,-50) [-50|205] "℃"  PC
 SG_ S2A_PCBMinTemp_01 : 8|8@1+ (1,-50) [-50|205] "℃"  PC
 SG_ S2A_ChipPst_PCBMaxTemp_01 : 16|3@1+ (1,0) [0|7] ""  PC
 SG_ S2A_ChipPst_PCBMinTemp_01 : 19|3@1+ (1,0) [0|7] ""  PC
 SG_ S2A_CscPst_PCBMaxTemp_01 : 22|5@1+ (1,0) [0|31] ""  PC
 SG_ S2A_CscPst_PCBMinTemp_01 : 27|5@1+ (1,0) [0|31] ""  PC
 SG_ S2A_AFEMaxTemp_01 : 32|8@1+ (1,-50) [-50|205] "℃"  PC
 SG_ S2A_AFEMinTemp_01 : 40|8@1+ (1,-50) [-50|205] "℃"  PC
 SG_ S2A_ChipPst_AFEMaxTemp_01 : 48|3@1+ (1,0) [0|7] ""  PC
 SG_ S2A_ChipPst_AFEMinTemp_01 : 51|3@1+ (1,0) [0|7] ""  PC
 SG_ S2A_CscPst_AFEMaxTemp_01 : 54|5@1+ (1,0) [0|31] ""  PC
 SG_ S2A_CscPst_AFEMinTemp_01 : 59|5@1+ (1,0) [0|31] ""  PC

BO_ 2334326594 S2A_SUMDATA22__02: 8 SBMU
 SG_ S2A_PCBMaxTemp_02 : 0|8@1+ (1,-50) [-50|205] "℃"  PC
 SG_ S2A_PCBMinTemp_02 : 8|8@1+ (1,-50) [-50|205] "℃"  PC
 SG_ S2A_ChipPst_PCBMaxTemp_02 : 16|3@1+ (1,0) [0|7] ""  PC
 SG_ S2A_ChipPst_PCBMinTemp_02 : 19|3@1+ (1,0) [0|7] ""  PC
 SG_ S2A_CscPst_PCBMaxTemp_02 : 22|5@1+ (1,0) [0|31] ""  PC
 SG_ S2A_CscPst_PCBMinTemp_02 : 27|5@1+ (1,0) [0|31] ""  PC
 SG_ S2A_AFEMaxTemp_02 : 32|8@1+ (1,-50) [-50|205] "℃"  PC
 SG_ S2A_AFEMinTemp_02 : 40|8@1+ (1,-50) [-50|205] "℃"  PC
 SG_ S2A_ChipPst_AFEMaxTemp_02 : 48|3@1+ (1,0) [0|7] ""  PC
 SG_ S2A_ChipPst_AFEMinTemp_02 : 51|3@1+ (1,0) [0|7] ""  PC
 SG_ S2A_CscPst_AFEMaxTemp_02 : 54|5@1+ (1,0) [0|31] ""  PC
 SG_ S2A_CscPst_AFEMinTemp_02 : 59|5@1+ (1,0) [0|31] ""  PC

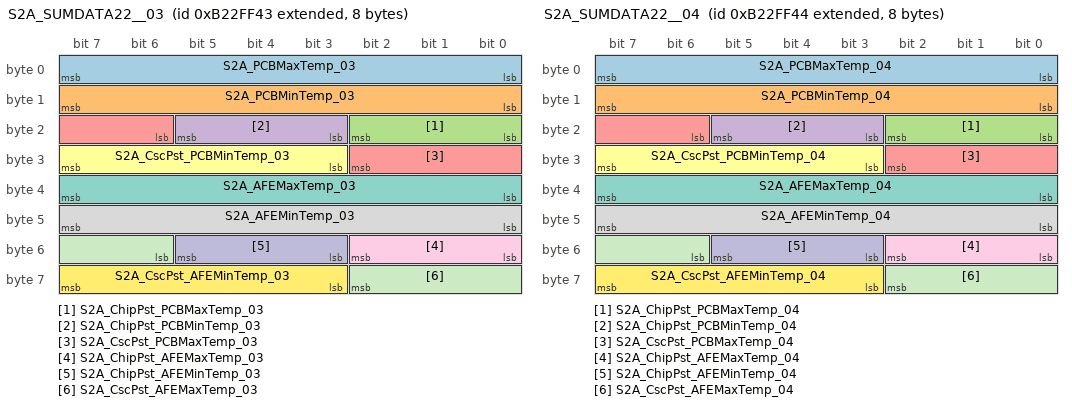
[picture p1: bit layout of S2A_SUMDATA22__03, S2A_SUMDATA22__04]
BO_ 2334326595 S2A_SUMDATA22__03: 8 SBMU
 SG_ S2A_PCBMaxTemp_03 : 0|8@1+ (1,-50) [-50|205] "℃"  PC
 SG_ S2A_PCBMinTemp_03 : 8|8@1+ (1,-50) [-50|205] "℃"  PC
 SG_ S2A_ChipPst_PCBMaxTemp_03 : 16|3@1+ (1,0) [0|7] ""  PC
 SG_ S2A_ChipPst_PCBMinTemp_03 : 19|3@1+ (1,0) [0|7] ""  PC
 SG_ S2A_CscPst_PCBMaxTemp_03 : 22|5@1+ (1,0) [0|31] ""  PC
 SG_ S2A_CscPst_PCBMinTemp_03 : 27|5@1+ (1,0) [0|31] ""  PC
 SG_ S2A_AFEMaxTemp_03 : 32|8@1+ (1,-50) [-50|205] "℃"  PC
 SG_ S2A_AFEMinTemp_03 : 40|8@1+ (1,-50) [-50|205] "℃"  PC
 SG_ S2A_ChipPst_AFEMaxTemp_03 : 48|3@1+ (1,0) [0|7] ""  PC
 SG_ S2A_ChipPst_AFEMinTemp_03 : 51|3@1+ (1,0) [0|7] ""  PC
 SG_ S2A_CscPst_AFEMaxTemp_03 : 54|5@1+ (1,0) [0|31] ""  PC
 SG_ S2A_CscPst_AFEMinTemp_03 : 59|5@1+ (1,0) [0|31] ""  PC

BO_ 2334326596 S2A_SUMDATA22__04: 8 SBMU
 SG_ S2A_PCBMaxTemp_04 : 0|8@1+ (1,-50) [-50|205] "℃"  PC
 SG_ S2A_PCBMinTemp_04 : 8|8@1+ (1,-50) [-50|205] "℃"  PC
 SG_ S2A_ChipPst_PCBMaxTemp_04 : 16|3@1+ (1,0) [0|7] ""  PC
 SG_ S2A_ChipPst_PCBMinTemp_04 : 19|3@1+ (1,0) [0|7] ""  PC
 SG_ S2A_CscPst_PCBMaxTemp_04 : 22|5@1+ (1,0) [0|31] ""  PC
 SG_ S2A_CscPst_PCBMinTemp_04 : 27|5@1+ (1,0) [0|31] ""  PC
 SG_ S2A_AFEMaxTemp_04 : 32|8@1+ (1,-50) [-50|205] "℃"  PC
 SG_ S2A_AFEMinTemp_04 : 40|8@1+ (1,-50) [-50|205] "℃"  PC
 SG_ S2A_ChipPst_AFEMaxTemp_04 : 48|3@1+ (1,0) [0|7] ""  PC
 SG_ S2A_ChipPst_AFEMinTemp_04 : 51|3@1+ (1,0) [0|7] ""  PC
 SG_ S2A_CscPst_AFEMaxTemp_04 : 54|5@1+ (1,0) [0|31] ""  PC
 SG_ S2A_CscPst_AFEMinTemp_04 : 59|5@1+ (1,0) [0|31] ""  PC

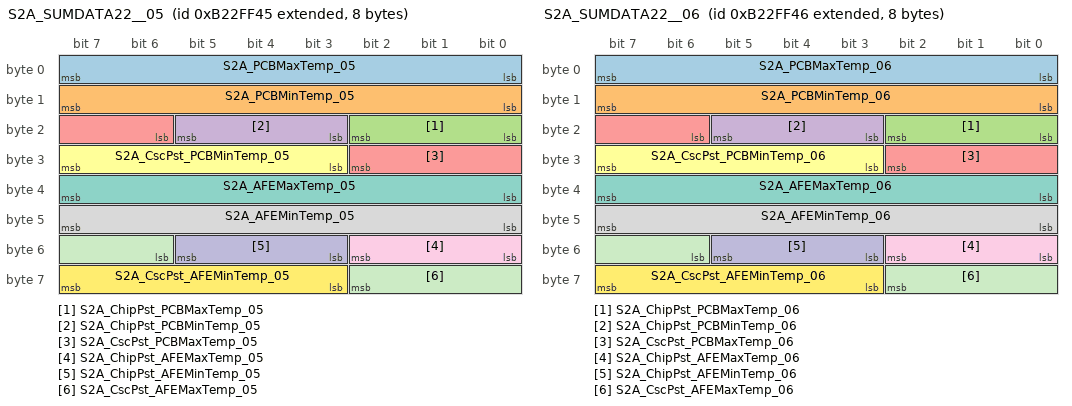
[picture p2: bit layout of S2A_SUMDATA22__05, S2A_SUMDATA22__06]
BO_ 2334326597 S2A_SUMDATA22__05: 8 SBMU
 SG_ S2A_PCBMaxTemp_05 : 0|8@1+ (1,-50) [-50|205] "℃"  PC
 SG_ S2A_PCBMinTemp_05 : 8|8@1+ (1,-50) [-50|205] "℃"  PC
 SG_ S2A_ChipPst_PCBMaxTemp_05 : 16|3@1+ (1,0) [0|7] ""  PC
 SG_ S2A_ChipPst_PCBMinTemp_05 : 19|3@1+ (1,0) [0|7] ""  PC
 SG_ S2A_CscPst_PCBMaxTemp_05 : 22|5@1+ (1,0) [0|31] ""  PC
 SG_ S2A_CscPst_PCBMinTemp_05 : 27|5@1+ (1,0) [0|31] ""  PC
 SG_ S2A_AFEMaxTemp_05 : 32|8@1+ (1,-50) [-50|205] "℃"  PC
 SG_ S2A_AFEMinTemp_05 : 40|8@1+ (1,-50) [-50|205] "℃"  PC
 SG_ S2A_ChipPst_AFEMaxTemp_05 : 48|3@1+ (1,0) [0|7] ""  PC
 SG_ S2A_ChipPst_AFEMinTemp_05 : 51|3@1+ (1,0) [0|7] ""  PC
 SG_ S2A_CscPst_AFEMaxTemp_05 : 54|5@1+ (1,0) [0|31] ""  PC
 SG_ S2A_CscPst_AFEMinTemp_05 : 59|5@1+ (1,0) [0|31] ""  PC

BO_ 2334326598 S2A_SUMDATA22__06: 8 SBMU
 SG_ S2A_PCBMaxTemp_06 : 0|8@1+ (1,-50) [-50|205] "℃"  PC
 SG_ S2A_PCBMinTemp_06 : 8|8@1+ (1,-50) [-50|205] "℃"  PC
 SG_ S2A_ChipPst_PCBMaxTemp_06 : 16|3@1+ (1,0) [0|7] ""  PC
 SG_ S2A_ChipPst_PCBMinTemp_06 : 19|3@1+ (1,0) [0|7] ""  PC
 SG_ S2A_CscPst_PCBMaxTemp_06 : 22|5@1+ (1,0) [0|31] ""  PC
 SG_ S2A_CscPst_PCBMinTemp_06 : 27|5@1+ (1,0) [0|31] ""  PC
 SG_ S2A_AFEMaxTemp_06 : 32|8@1+ (1,-50) [-50|205] "℃"  PC
 SG_ S2A_AFEMinTemp_06 : 40|8@1+ (1,-50) [-50|205] "℃"  PC
 SG_ S2A_ChipPst_AFEMaxTemp_06 : 48|3@1+ (1,0) [0|7] ""  PC
 SG_ S2A_ChipPst_AFEMinTemp_06 : 51|3@1+ (1,0) [0|7] ""  PC
 SG_ S2A_CscPst_AFEMaxTemp_06 : 54|5@1+ (1,0) [0|31] ""  PC
 SG_ S2A_CscPst_AFEMinTemp_06 : 59|5@1+ (1,0) [0|31] ""  PC

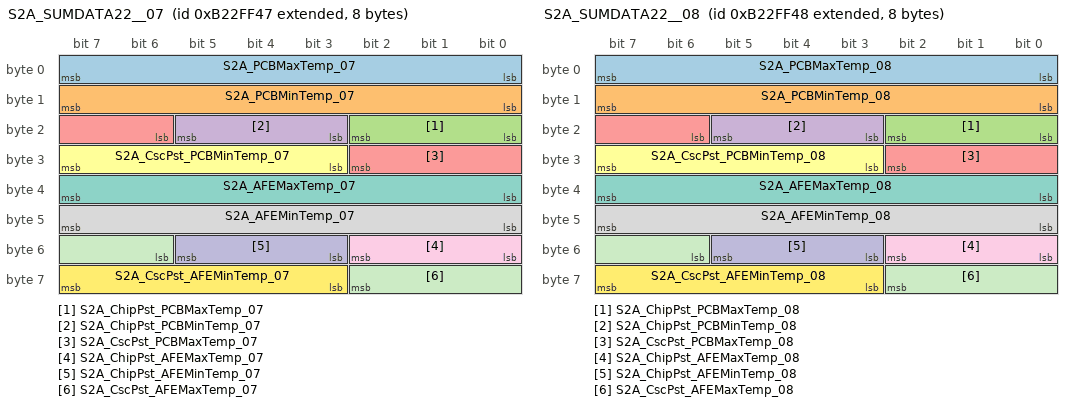
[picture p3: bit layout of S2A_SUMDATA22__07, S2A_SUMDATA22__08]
BO_ 2334326599 S2A_SUMDATA22__07: 8 SBMU
 SG_ S2A_PCBMaxTemp_07 : 0|8@1+ (1,-50) [-50|205] "℃"  PC
 SG_ S2A_PCBMinTemp_07 : 8|8@1+ (1,-50) [-50|205] "℃"  PC
 SG_ S2A_ChipPst_PCBMaxTemp_07 : 16|3@1+ (1,0) [0|7] ""  PC
 SG_ S2A_ChipPst_PCBMinTemp_07 : 19|3@1+ (1,0) [0|7] ""  PC
 SG_ S2A_CscPst_PCBMaxTemp_07 : 22|5@1+ (1,0) [0|31] ""  PC
 SG_ S2A_CscPst_PCBMinTemp_07 : 27|5@1+ (1,0) [0|31] ""  PC
 SG_ S2A_AFEMaxTemp_07 : 32|8@1+ (1,-50) [-50|205] "℃"  PC
 SG_ S2A_AFEMinTemp_07 : 40|8@1+ (1,-50) [-50|205] "℃"  PC
 SG_ S2A_ChipPst_AFEMaxTemp_07 : 48|3@1+ (1,0) [0|7] ""  PC
 SG_ S2A_ChipPst_AFEMinTemp_07 : 51|3@1+ (1,0) [0|7] ""  PC
 SG_ S2A_CscPst_AFEMaxTemp_07 : 54|5@1+ (1,0) [0|31] ""  PC
 SG_ S2A_CscPst_AFEMinTemp_07 : 59|5@1+ (1,0) [0|31] ""  PC

BO_ 2334326600 S2A_SUMDATA22__08: 8 SBMU
 SG_ S2A_PCBMaxTemp_08 : 0|8@1+ (1,-50) [-50|205] "℃"  PC
 SG_ S2A_PCBMinTemp_08 : 8|8@1+ (1,-50) [-50|205] "℃"  PC
 SG_ S2A_ChipPst_PCBMaxTemp_08 : 16|3@1+ (1,0) [0|7] ""  PC
 SG_ S2A_ChipPst_PCBMinTemp_08 : 19|3@1+ (1,0) [0|7] ""  PC
 SG_ S2A_CscPst_PCBMaxTemp_08 : 22|5@1+ (1,0) [0|31] ""  PC
 SG_ S2A_CscPst_PCBMinTemp_08 : 27|5@1+ (1,0) [0|31] ""  PC
 SG_ S2A_AFEMaxTemp_08 : 32|8@1+ (1,-50) [-50|205] "℃"  PC
 SG_ S2A_AFEMinTemp_08 : 40|8@1+ (1,-50) [-50|205] "℃"  PC
 SG_ S2A_ChipPst_AFEMaxTemp_08 : 48|3@1+ (1,0) [0|7] ""  PC
 SG_ S2A_ChipPst_AFEMinTemp_08 : 51|3@1+ (1,0) [0|7] ""  PC
 SG_ S2A_CscPst_AFEMaxTemp_08 : 54|5@1+ (1,0) [0|31] ""  PC
 SG_ S2A_CscPst_AFEMinTemp_08 : 59|5@1+ (1,0) [0|31] ""  PC

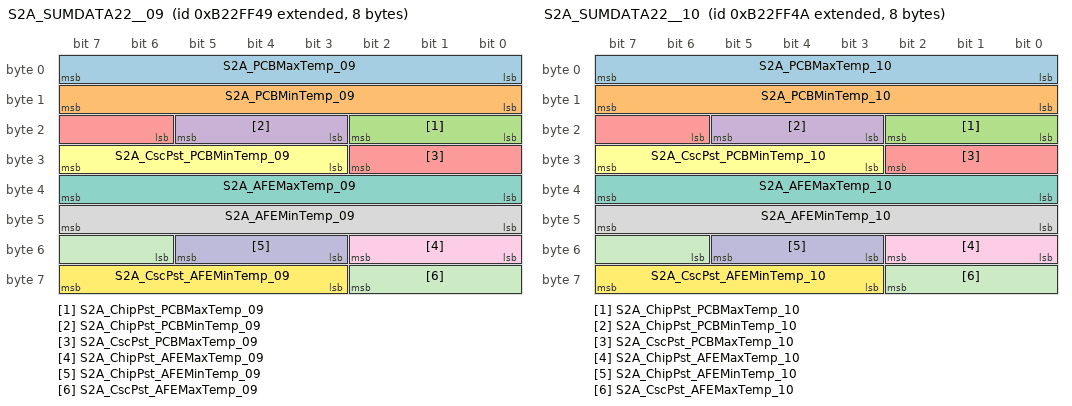
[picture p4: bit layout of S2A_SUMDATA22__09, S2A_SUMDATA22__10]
BO_ 2334326601 S2A_SUMDATA22__09: 8 SBMU
 SG_ S2A_PCBMaxTemp_09 : 0|8@1+ (1,-50) [-50|205] "℃"  PC
 SG_ S2A_PCBMinTemp_09 : 8|8@1+ (1,-50) [-50|205] "℃"  PC
 SG_ S2A_ChipPst_PCBMaxTemp_09 : 16|3@1+ (1,0) [0|7] ""  PC
 SG_ S2A_ChipPst_PCBMinTemp_09 : 19|3@1+ (1,0) [0|7] ""  PC
 SG_ S2A_CscPst_PCBMaxTemp_09 : 22|5@1+ (1,0) [0|31] ""  PC
 SG_ S2A_CscPst_PCBMinTemp_09 : 27|5@1+ (1,0) [0|31] ""  PC
 SG_ S2A_AFEMaxTemp_09 : 32|8@1+ (1,-50) [-50|205] "℃"  PC
 SG_ S2A_AFEMinTemp_09 : 40|8@1+ (1,-50) [-50|205] "℃"  PC
 SG_ S2A_ChipPst_AFEMaxTemp_09 : 48|3@1+ (1,0) [0|7] ""  PC
 SG_ S2A_ChipPst_AFEMinTemp_09 : 51|3@1+ (1,0) [0|7] ""  PC
 SG_ S2A_CscPst_AFEMaxTemp_09 : 54|5@1+ (1,0) [0|31] ""  PC
 SG_ S2A_CscPst_AFEMinTemp_09 : 59|5@1+ (1,0) [0|31] ""  PC

BO_ 2334326602 S2A_SUMDATA22__10: 8 SBMU
 SG_ S2A_PCBMaxTemp_10 : 0|8@1+ (1,-50) [-50|205] "℃"  PC
 SG_ S2A_PCBMinTemp_10 : 8|8@1+ (1,-50) [-50|205] "℃"  PC
 SG_ S2A_ChipPst_PCBMaxTemp_10 : 16|3@1+ (1,0) [0|7] ""  PC
 SG_ S2A_ChipPst_PCBMinTemp_10 : 19|3@1+ (1,0) [0|7] ""  PC
 SG_ S2A_CscPst_PCBMaxTemp_10 : 22|5@1+ (1,0) [0|31] ""  PC
 SG_ S2A_CscPst_PCBMinTemp_10 : 27|5@1+ (1,0) [0|31] ""  PC
 SG_ S2A_AFEMaxTemp_10 : 32|8@1+ (1,-50) [-50|205] "℃"  PC
 SG_ S2A_AFEMinTemp_10 : 40|8@1+ (1,-50) [-50|205] "℃"  PC
 SG_ S2A_ChipPst_AFEMaxTemp_10 : 48|3@1+ (1,0) [0|7] ""  PC
 SG_ S2A_ChipPst_AFEMinTemp_10 : 51|3@1+ (1,0) [0|7] ""  PC
 SG_ S2A_CscPst_AFEMaxTemp_10 : 54|5@1+ (1,0) [0|31] ""  PC
 SG_ S2A_CscPst_AFEMinTemp_10 : 59|5@1+ (1,0) [0|31] ""  PC

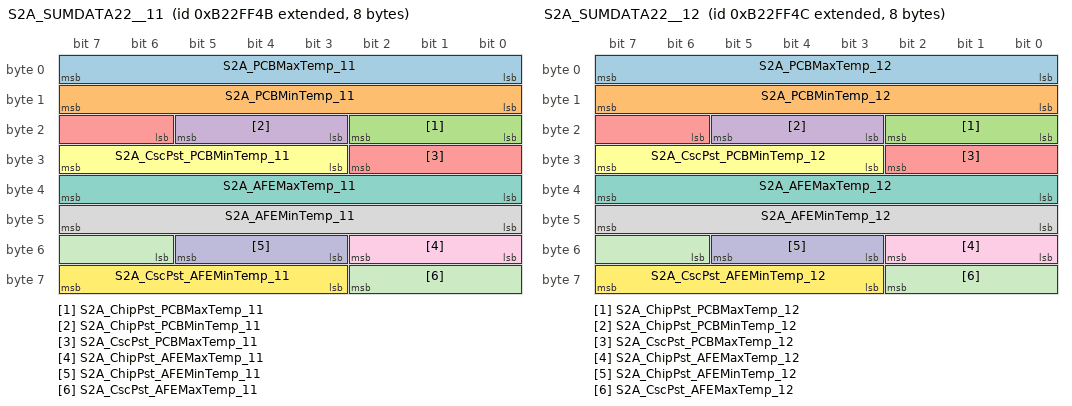
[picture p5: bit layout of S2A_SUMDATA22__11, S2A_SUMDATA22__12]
BO_ 2334326603 S2A_SUMDATA22__11: 8 SBMU
 SG_ S2A_PCBMaxTemp_11 : 0|8@1+ (1,-50) [-50|205] "℃"  PC
 SG_ S2A_PCBMinTemp_11 : 8|8@1+ (1,-50) [-50|205] "℃"  PC
 SG_ S2A_ChipPst_PCBMaxTemp_11 : 16|3@1+ (1,0) [0|7] ""  PC
 SG_ S2A_ChipPst_PCBMinTemp_11 : 19|3@1+ (1,0) [0|7] ""  PC
 SG_ S2A_CscPst_PCBMaxTemp_11 : 22|5@1+ (1,0) [0|31] ""  PC
 SG_ S2A_CscPst_PCBMinTemp_11 : 27|5@1+ (1,0) [0|31] ""  PC
 SG_ S2A_AFEMaxTemp_11 : 32|8@1+ (1,-50) [-50|205] "℃"  PC
 SG_ S2A_AFEMinTemp_11 : 40|8@1+ (1,-50) [-50|205] "℃"  PC
 SG_ S2A_ChipPst_AFEMaxTemp_11 : 48|3@1+ (1,0) [0|7] ""  PC
 SG_ S2A_ChipPst_AFEMinTemp_11 : 51|3@1+ (1,0) [0|7] ""  PC
 SG_ S2A_CscPst_AFEMaxTemp_11 : 54|5@1+ (1,0) [0|31] ""  PC
 SG_ S2A_CscPst_AFEMinTemp_11 : 59|5@1+ (1,0) [0|31] ""  PC

BO_ 2334326604 S2A_SUMDATA22__12: 8 SBMU
 SG_ S2A_PCBMaxTemp_12 : 0|8@1+ (1,-50) [-50|205] "℃"  PC
 SG_ S2A_PCBMinTemp_12 : 8|8@1+ (1,-50) [-50|205] "℃"  PC
 SG_ S2A_ChipPst_PCBMaxTemp_12 : 16|3@1+ (1,0) [0|7] ""  PC
 SG_ S2A_ChipPst_PCBMinTemp_12 : 19|3@1+ (1,0) [0|7] ""  PC
 SG_ S2A_CscPst_PCBMaxTemp_12 : 22|5@1+ (1,0) [0|31] ""  PC
 SG_ S2A_CscPst_PCBMinTemp_12 : 27|5@1+ (1,0) [0|31] ""  PC
 SG_ S2A_AFEMaxTemp_12 : 32|8@1+ (1,-50) [-50|205] "℃"  PC
 SG_ S2A_AFEMinTemp_12 : 40|8@1+ (1,-50) [-50|205] "℃"  PC
 SG_ S2A_ChipPst_AFEMaxTemp_12 : 48|3@1+ (1,0) [0|7] ""  PC
 SG_ S2A_ChipPst_AFEMinTemp_12 : 51|3@1+ (1,0) [0|7] ""  PC
 SG_ S2A_CscPst_AFEMaxTemp_12 : 54|5@1+ (1,0) [0|31] ""  PC
 SG_ S2A_CscPst_AFEMinTemp_12 : 59|5@1+ (1,0) [0|31] ""  PC

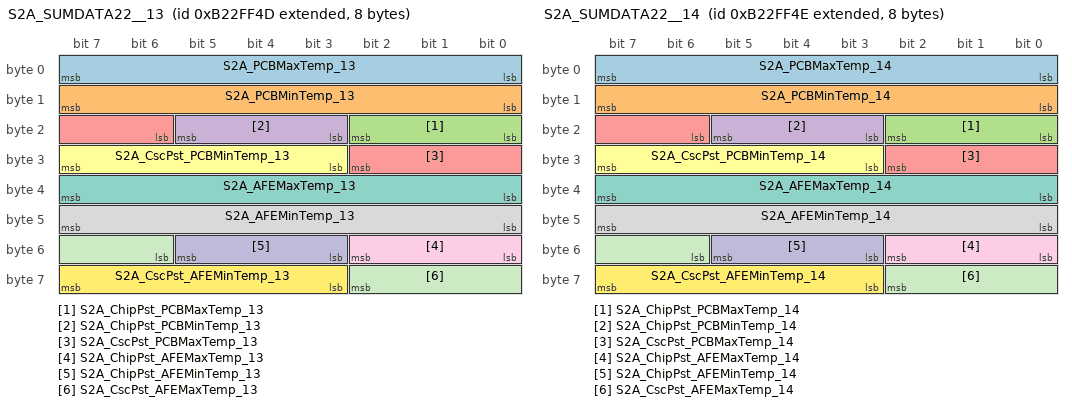
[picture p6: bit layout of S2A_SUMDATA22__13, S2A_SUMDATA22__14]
BO_ 2334326605 S2A_SUMDATA22__13: 8 SBMU
 SG_ S2A_PCBMaxTemp_13 : 0|8@1+ (1,-50) [-50|205] "℃"  PC
 SG_ S2A_PCBMinTemp_13 : 8|8@1+ (1,-50) [-50|205] "℃"  PC
 SG_ S2A_ChipPst_PCBMaxTemp_13 : 16|3@1+ (1,0) [0|7] ""  PC
 SG_ S2A_ChipPst_PCBMinTemp_13 : 19|3@1+ (1,0) [0|7] ""  PC
 SG_ S2A_CscPst_PCBMaxTemp_13 : 22|5@1+ (1,0) [0|31] ""  PC
 SG_ S2A_CscPst_PCBMinTemp_13 : 27|5@1+ (1,0) [0|31] ""  PC
 SG_ S2A_AFEMaxTemp_13 : 32|8@1+ (1,-50) [-50|205] "℃"  PC
 SG_ S2A_AFEMinTemp_13 : 40|8@1+ (1,-50) [-50|205] "℃"  PC
 SG_ S2A_ChipPst_AFEMaxTemp_13 : 48|3@1+ (1,0) [0|7] ""  PC
 SG_ S2A_ChipPst_AFEMinTemp_13 : 51|3@1+ (1,0) [0|7] ""  PC
 SG_ S2A_CscPst_AFEMaxTemp_13 : 54|5@1+ (1,0) [0|31] ""  PC
 SG_ S2A_CscPst_AFEMinTemp_13 : 59|5@1+ (1,0) [0|31] ""  PC

BO_ 2334326606 S2A_SUMDATA22__14: 8 SBMU
 SG_ S2A_PCBMaxTemp_14 : 0|8@1+ (1,-50) [-50|205] "℃"  PC
 SG_ S2A_PCBMinTemp_14 : 8|8@1+ (1,-50) [-50|205] "℃"  PC
 SG_ S2A_ChipPst_PCBMaxTemp_14 : 16|3@1+ (1,0) [0|7] ""  PC
 SG_ S2A_ChipPst_PCBMinTemp_14 : 19|3@1+ (1,0) [0|7] ""  PC
 SG_ S2A_CscPst_PCBMaxTemp_14 : 22|5@1+ (1,0) [0|31] ""  PC
 SG_ S2A_CscPst_PCBMinTemp_14 : 27|5@1+ (1,0) [0|31] ""  PC
 SG_ S2A_AFEMaxTemp_14 : 32|8@1+ (1,-50) [-50|205] "℃"  PC
 SG_ S2A_AFEMinTemp_14 : 40|8@1+ (1,-50) [-50|205] "℃"  PC
 SG_ S2A_ChipPst_AFEMaxTemp_14 : 48|3@1+ (1,0) [0|7] ""  PC
 SG_ S2A_ChipPst_AFEMinTemp_14 : 51|3@1+ (1,0) [0|7] ""  PC
 SG_ S2A_CscPst_AFEMaxTemp_14 : 54|5@1+ (1,0) [0|31] ""  PC
 SG_ S2A_CscPst_AFEMinTemp_14 : 59|5@1+ (1,0) [0|31] ""  PC

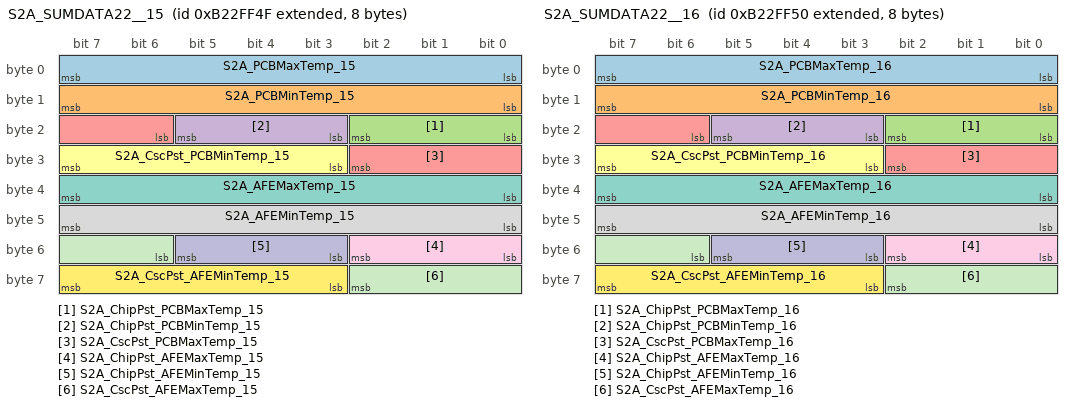
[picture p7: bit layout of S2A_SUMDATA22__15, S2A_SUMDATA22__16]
BO_ 2334326607 S2A_SUMDATA22__15: 8 SBMU
 SG_ S2A_PCBMaxTemp_15 : 0|8@1+ (1,-50) [-50|205] "℃"  PC
 SG_ S2A_PCBMinTemp_15 : 8|8@1+ (1,-50) [-50|205] "℃"  PC
 SG_ S2A_ChipPst_PCBMaxTemp_15 : 16|3@1+ (1,0) [0|7] ""  PC
 SG_ S2A_ChipPst_PCBMinTemp_15 : 19|3@1+ (1,0) [0|7] ""  PC
 SG_ S2A_CscPst_PCBMaxTemp_15 : 22|5@1+ (1,0) [0|31] ""  PC
 SG_ S2A_CscPst_PCBMinTemp_15 : 27|5@1+ (1,0) [0|31] ""  PC
 SG_ S2A_AFEMaxTemp_15 : 32|8@1+ (1,-50) [-50|205] "℃"  PC
 SG_ S2A_AFEMinTemp_15 : 40|8@1+ (1,-50) [-50|205] "℃"  PC
 SG_ S2A_ChipPst_AFEMaxTemp_15 : 48|3@1+ (1,0) [0|7] ""  PC
 SG_ S2A_ChipPst_AFEMinTemp_15 : 51|3@1+ (1,0) [0|7] ""  PC
 SG_ S2A_CscPst_AFEMaxTemp_15 : 54|5@1+ (1,0) [0|31] ""  PC
 SG_ S2A_CscPst_AFEMinTemp_15 : 59|5@1+ (1,0) [0|31] ""  PC

BO_ 2334326608 S2A_SUMDATA22__16: 8 SBMU
 SG_ S2A_PCBMaxTemp_16 : 0|8@1+ (1,-50) [-50|205] "℃"  PC
 SG_ S2A_PCBMinTemp_16 : 8|8@1+ (1,-50) [-50|205] "℃"  PC
 SG_ S2A_ChipPst_PCBMaxTemp_16 : 16|3@1+ (1,0) [0|7] ""  PC
 SG_ S2A_ChipPst_PCBMinTemp_16 : 19|3@1+ (1,0) [0|7] ""  PC
 SG_ S2A_CscPst_PCBMaxTemp_16 : 22|5@1+ (1,0) [0|31] ""  PC
 SG_ S2A_CscPst_PCBMinTemp_16 : 27|5@1+ (1,0) [0|31] ""  PC
 SG_ S2A_AFEMaxTemp_16 : 32|8@1+ (1,-50) [-50|205] "℃"  PC
 SG_ S2A_AFEMinTemp_16 : 40|8@1+ (1,-50) [-50|205] "℃"  PC
 SG_ S2A_ChipPst_AFEMaxTemp_16 : 48|3@1+ (1,0) [0|7] ""  PC
 SG_ S2A_ChipPst_AFEMinTemp_16 : 51|3@1+ (1,0) [0|7] ""  PC
 SG_ S2A_CscPst_AFEMaxTemp_16 : 54|5@1+ (1,0) [0|31] ""  PC
 SG_ S2A_CscPst_AFEMinTemp_16 : 59|5@1+ (1,0) [0|31] ""  PC

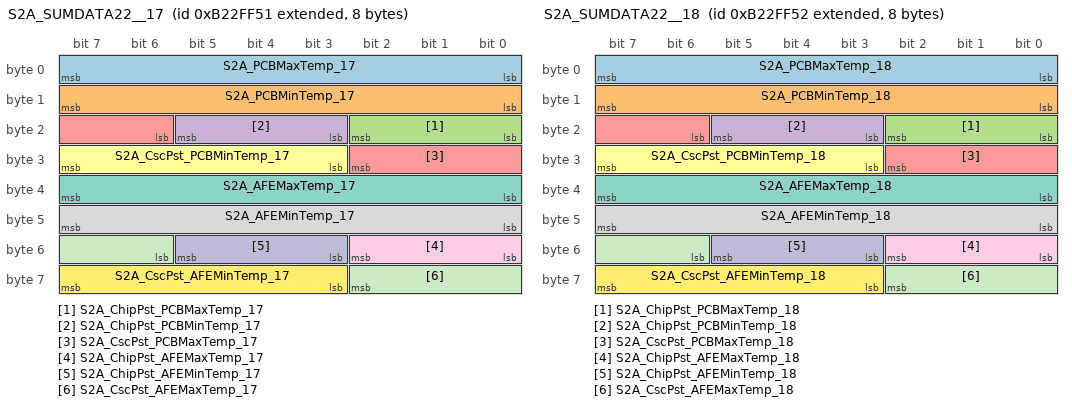
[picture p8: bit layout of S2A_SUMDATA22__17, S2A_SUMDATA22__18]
BO_ 2334326609 S2A_SUMDATA22__17: 8 SBMU
 SG_ S2A_PCBMaxTemp_17 : 0|8@1+ (1,-50) [-50|205] "℃"  PC
 SG_ S2A_PCBMinTemp_17 : 8|8@1+ (1,-50) [-50|205] "℃"  PC
 SG_ S2A_ChipPst_PCBMaxTemp_17 : 16|3@1+ (1,0) [0|7] ""  PC
 SG_ S2A_ChipPst_PCBMinTemp_17 : 19|3@1+ (1,0) [0|7] ""  PC
 SG_ S2A_CscPst_PCBMaxTemp_17 : 22|5@1+ (1,0) [0|31] ""  PC
 SG_ S2A_CscPst_PCBMinTemp_17 : 27|5@1+ (1,0) [0|31] ""  PC
 SG_ S2A_AFEMaxTemp_17 : 32|8@1+ (1,-50) [-50|205] "℃"  PC
 SG_ S2A_AFEMinTemp_17 : 40|8@1+ (1,-50) [-50|205] "℃"  PC
 SG_ S2A_ChipPst_AFEMaxTemp_17 : 48|3@1+ (1,0) [0|7] ""  PC
 SG_ S2A_ChipPst_AFEMinTemp_17 : 51|3@1+ (1,0) [0|7] ""  PC
 SG_ S2A_CscPst_AFEMaxTemp_17 : 54|5@1+ (1,0) [0|31] ""  PC
 SG_ S2A_CscPst_AFEMinTemp_17 : 59|5@1+ (1,0) [0|31] ""  PC

BO_ 2334326610 S2A_SUMDATA22__18: 8 SBMU
 SG_ S2A_PCBMaxTemp_18 : 0|8@1+ (1,-50) [-50|205] "℃"  PC
 SG_ S2A_PCBMinTemp_18 : 8|8@1+ (1,-50) [-50|205] "℃"  PC
 SG_ S2A_ChipPst_PCBMaxTemp_18 : 16|3@1+ (1,0) [0|7] ""  PC
 SG_ S2A_ChipPst_PCBMinTemp_18 : 19|3@1+ (1,0) [0|7] ""  PC
 SG_ S2A_CscPst_PCBMaxTemp_18 : 22|5@1+ (1,0) [0|31] ""  PC
 SG_ S2A_CscPst_PCBMinTemp_18 : 27|5@1+ (1,0) [0|31] ""  PC
 SG_ S2A_AFEMaxTemp_18 : 32|8@1+ (1,-50) [-50|205] "℃"  PC
 SG_ S2A_AFEMinTemp_18 : 40|8@1+ (1,-50) [-50|205] "℃"  PC
 SG_ S2A_ChipPst_AFEMaxTemp_18 : 48|3@1+ (1,0) [0|7] ""  PC
 SG_ S2A_ChipPst_AFEMinTemp_18 : 51|3@1+ (1,0) [0|7] ""  PC
 SG_ S2A_CscPst_AFEMaxTemp_18 : 54|5@1+ (1,0) [0|31] ""  PC
 SG_ S2A_CscPst_AFEMinTemp_18 : 59|5@1+ (1,0) [0|31] ""  PC

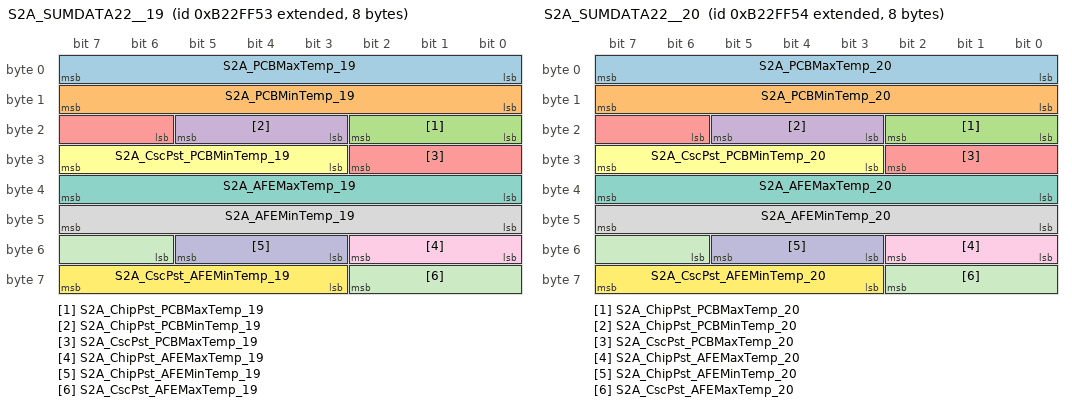
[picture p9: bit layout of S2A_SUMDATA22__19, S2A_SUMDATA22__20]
BO_ 2334326611 S2A_SUMDATA22__19: 8 SBMU
 SG_ S2A_PCBMaxTemp_19 : 0|8@1+ (1,-50) [-50|205] "℃"  PC
 SG_ S2A_PCBMinTemp_19 : 8|8@1+ (1,-50) [-50|205] "℃"  PC
 SG_ S2A_ChipPst_PCBMaxTemp_19 : 16|3@1+ (1,0) [0|7] ""  PC
 SG_ S2A_ChipPst_PCBMinTemp_19 : 19|3@1+ (1,0) [0|7] ""  PC
 SG_ S2A_CscPst_PCBMaxTemp_19 : 22|5@1+ (1,0) [0|31] ""  PC
 SG_ S2A_CscPst_PCBMinTemp_19 : 27|5@1+ (1,0) [0|31] ""  PC
 SG_ S2A_AFEMaxTemp_19 : 32|8@1+ (1,-50) [-50|205] "℃"  PC
 SG_ S2A_AFEMinTemp_19 : 40|8@1+ (1,-50) [-50|205] "℃"  PC
 SG_ S2A_ChipPst_AFEMaxTemp_19 : 48|3@1+ (1,0) [0|7] ""  PC
 SG_ S2A_ChipPst_AFEMinTemp_19 : 51|3@1+ (1,0) [0|7] ""  PC
 SG_ S2A_CscPst_AFEMaxTemp_19 : 54|5@1+ (1,0) [0|31] ""  PC
 SG_ S2A_CscPst_AFEMinTemp_19 : 59|5@1+ (1,0) [0|31] ""  PC

BO_ 2334326612 S2A_SUMDATA22__20: 8 SBMU
 SG_ S2A_PCBMaxTemp_20 : 0|8@1+ (1,-50) [-50|205] "℃"  PC
 SG_ S2A_PCBMinTemp_20 : 8|8@1+ (1,-50) [-50|205] "℃"  PC
 SG_ S2A_ChipPst_PCBMaxTemp_20 : 16|3@1+ (1,0) [0|7] ""  PC
 SG_ S2A_ChipPst_PCBMinTemp_20 : 19|3@1+ (1,0) [0|7] ""  PC
 SG_ S2A_CscPst_PCBMaxTemp_20 : 22|5@1+ (1,0) [0|31] ""  PC
 SG_ S2A_CscPst_PCBMinTemp_20 : 27|5@1+ (1,0) [0|31] ""  PC
 SG_ S2A_AFEMaxTemp_20 : 32|8@1+ (1,-50) [-50|205] "℃"  PC
 SG_ S2A_AFEMinTemp_20 : 40|8@1+ (1,-50) [-50|205] "℃"  PC
 SG_ S2A_ChipPst_AFEMaxTemp_20 : 48|3@1+ (1,0) [0|7] ""  PC
 SG_ S2A_ChipPst_AFEMinTemp_20 : 51|3@1+ (1,0) [0|7] ""  PC
 SG_ S2A_CscPst_AFEMaxTemp_20 : 54|5@1+ (1,0) [0|31] ""  PC
 SG_ S2A_CscPst_AFEMinTemp_20 : 59|5@1+ (1,0) [0|31] ""  PC

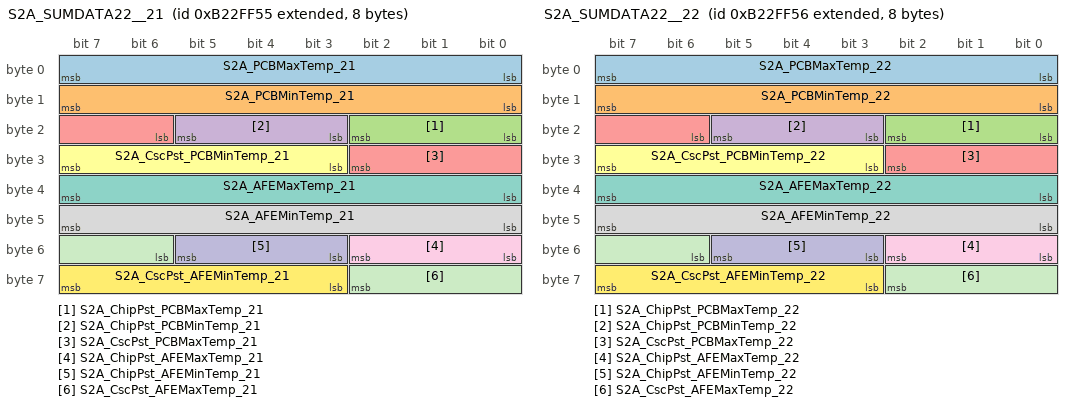
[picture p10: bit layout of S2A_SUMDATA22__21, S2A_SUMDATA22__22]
BO_ 2334326613 S2A_SUMDATA22__21: 8 SBMU
 SG_ S2A_PCBMaxTemp_21 : 0|8@1+ (1,-50) [-50|205] "℃"  PC
 SG_ S2A_PCBMinTemp_21 : 8|8@1+ (1,-50) [-50|205] "℃"  PC
 SG_ S2A_ChipPst_PCBMaxTemp_21 : 16|3@1+ (1,0) [0|7] ""  PC
 SG_ S2A_ChipPst_PCBMinTemp_21 : 19|3@1+ (1,0) [0|7] ""  PC
 SG_ S2A_CscPst_PCBMaxTemp_21 : 22|5@1+ (1,0) [0|31] ""  PC
 SG_ S2A_CscPst_PCBMinTemp_21 : 27|5@1+ (1,0) [0|31] ""  PC
 SG_ S2A_AFEMaxTemp_21 : 32|8@1+ (1,-50) [-50|205] "℃"  PC
 SG_ S2A_AFEMinTemp_21 : 40|8@1+ (1,-50) [-50|205] "℃"  PC
 SG_ S2A_ChipPst_AFEMaxTemp_21 : 48|3@1+ (1,0) [0|7] ""  PC
 SG_ S2A_ChipPst_AFEMinTemp_21 : 51|3@1+ (1,0) [0|7] ""  PC
 SG_ S2A_CscPst_AFEMaxTemp_21 : 54|5@1+ (1,0) [0|31] ""  PC
 SG_ S2A_CscPst_AFEMinTemp_21 : 59|5@1+ (1,0) [0|31] ""  PC

BO_ 2334326614 S2A_SUMDATA22__22: 8 SBMU
 SG_ S2A_PCBMaxTemp_22 : 0|8@1+ (1,-50) [-50|205] "℃"  PC
 SG_ S2A_PCBMinTemp_22 : 8|8@1+ (1,-50) [-50|205] "℃"  PC
 SG_ S2A_ChipPst_PCBMaxTemp_22 : 16|3@1+ (1,0) [0|7] ""  PC
 SG_ S2A_ChipPst_PCBMinTemp_22 : 19|3@1+ (1,0) [0|7] ""  PC
 SG_ S2A_CscPst_PCBMaxTemp_22 : 22|5@1+ (1,0) [0|31] ""  PC
 SG_ S2A_CscPst_PCBMinTemp_22 : 27|5@1+ (1,0) [0|31] ""  PC
 SG_ S2A_AFEMaxTemp_22 : 32|8@1+ (1,-50) [-50|205] "℃"  PC
 SG_ S2A_AFEMinTemp_22 : 40|8@1+ (1,-50) [-50|205] "℃"  PC
 SG_ S2A_ChipPst_AFEMaxTemp_22 : 48|3@1+ (1,0) [0|7] ""  PC
 SG_ S2A_ChipPst_AFEMinTemp_22 : 51|3@1+ (1,0) [0|7] ""  PC
 SG_ S2A_CscPst_AFEMaxTemp_22 : 54|5@1+ (1,0) [0|31] ""  PC
 SG_ S2A_CscPst_AFEMinTemp_22 : 59|5@1+ (1,0) [0|31] ""  PC

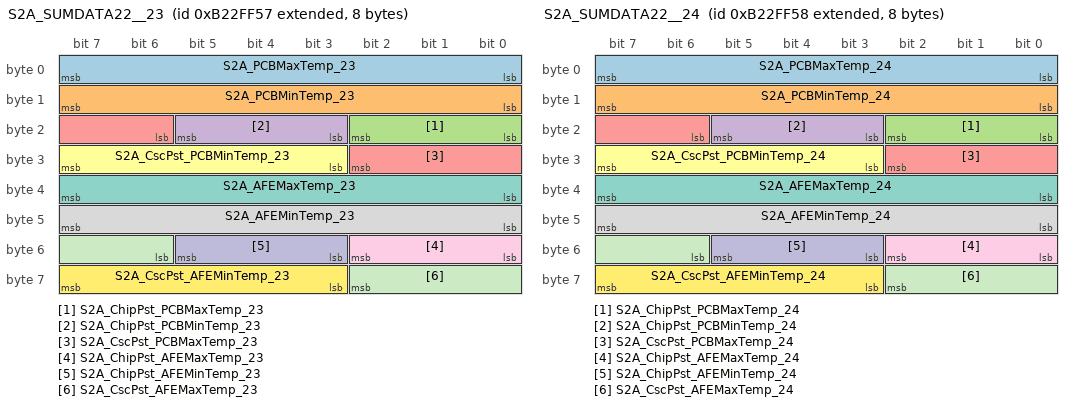
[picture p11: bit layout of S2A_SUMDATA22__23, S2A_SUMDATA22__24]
BO_ 2334326615 S2A_SUMDATA22__23: 8 SBMU
 SG_ S2A_PCBMaxTemp_23 : 0|8@1+ (1,-50) [-50|205] "℃"  PC
 SG_ S2A_PCBMinTemp_23 : 8|8@1+ (1,-50) [-50|205] "℃"  PC
 SG_ S2A_ChipPst_PCBMaxTemp_23 : 16|3@1+ (1,0) [0|7] ""  PC
 SG_ S2A_ChipPst_PCBMinTemp_23 : 19|3@1+ (1,0) [0|7] ""  PC
 SG_ S2A_CscPst_PCBMaxTemp_23 : 22|5@1+ (1,0) [0|31] ""  PC
 SG_ S2A_CscPst_PCBMinTemp_23 : 27|5@1+ (1,0) [0|31] ""  PC
 SG_ S2A_AFEMaxTemp_23 : 32|8@1+ (1,-50) [-50|205] "℃"  PC
 SG_ S2A_AFEMinTemp_23 : 40|8@1+ (1,-50) [-50|205] "℃"  PC
 SG_ S2A_ChipPst_AFEMaxTemp_23 : 48|3@1+ (1,0) [0|7] ""  PC
 SG_ S2A_ChipPst_AFEMinTemp_23 : 51|3@1+ (1,0) [0|7] ""  PC
 SG_ S2A_CscPst_AFEMaxTemp_23 : 54|5@1+ (1,0) [0|31] ""  PC
 SG_ S2A_CscPst_AFEMinTemp_23 : 59|5@1+ (1,0) [0|31] ""  PC

BO_ 2334326616 S2A_SUMDATA22__24: 8 SBMU
 SG_ S2A_PCBMaxTemp_24 : 0|8@1+ (1,-50) [-50|205] "℃"  PC
 SG_ S2A_PCBMinTemp_24 : 8|8@1+ (1,-50) [-50|205] "℃"  PC
 SG_ S2A_ChipPst_PCBMaxTemp_24 : 16|3@1+ (1,0) [0|7] ""  PC
 SG_ S2A_ChipPst_PCBMinTemp_24 : 19|3@1+ (1,0) [0|7] ""  PC
 SG_ S2A_CscPst_PCBMaxTemp_24 : 22|5@1+ (1,0) [0|31] ""  PC
 SG_ S2A_CscPst_PCBMinTemp_24 : 27|5@1+ (1,0) [0|31] ""  PC
 SG_ S2A_AFEMaxTemp_24 : 32|8@1+ (1,-50) [-50|205] "℃"  PC
 SG_ S2A_AFEMinTemp_24 : 40|8@1+ (1,-50) [-50|205] "℃"  PC
 SG_ S2A_ChipPst_AFEMaxTemp_24 : 48|3@1+ (1,0) [0|7] ""  PC
 SG_ S2A_ChipPst_AFEMinTemp_24 : 51|3@1+ (1,0) [0|7] ""  PC
 SG_ S2A_CscPst_AFEMaxTemp_24 : 54|5@1+ (1,0) [0|31] ""  PC
 SG_ S2A_CscPst_AFEMinTemp_24 : 59|5@1+ (1,0) [0|31] ""  PC

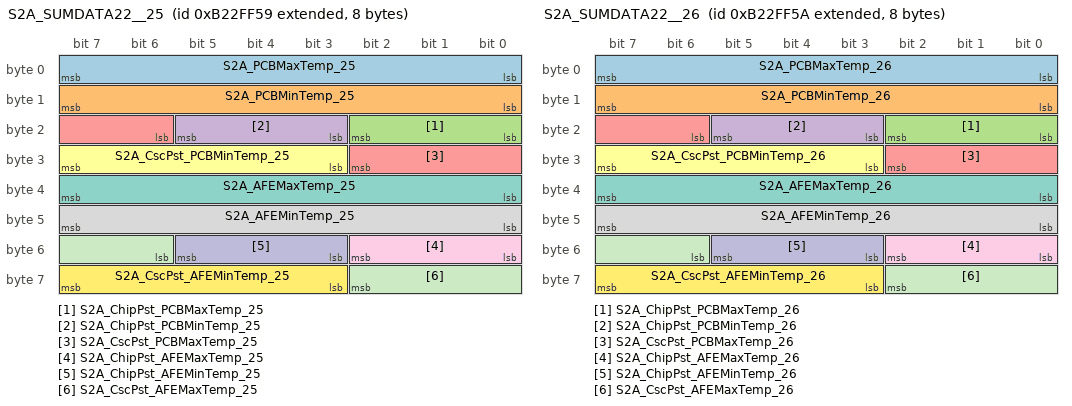
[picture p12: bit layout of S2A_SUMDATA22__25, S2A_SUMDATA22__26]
BO_ 2334326617 S2A_SUMDATA22__25: 8 SBMU
 SG_ S2A_PCBMaxTemp_25 : 0|8@1+ (1,-50) [-50|205] "℃"  PC
 SG_ S2A_PCBMinTemp_25 : 8|8@1+ (1,-50) [-50|205] "℃"  PC
 SG_ S2A_ChipPst_PCBMaxTemp_25 : 16|3@1+ (1,0) [0|7] ""  PC
 SG_ S2A_ChipPst_PCBMinTemp_25 : 19|3@1+ (1,0) [0|7] ""  PC
 SG_ S2A_CscPst_PCBMaxTemp_25 : 22|5@1+ (1,0) [0|31] ""  PC
 SG_ S2A_CscPst_PCBMinTemp_25 : 27|5@1+ (1,0) [0|31] ""  PC
 SG_ S2A_AFEMaxTemp_25 : 32|8@1+ (1,-50) [-50|205] "℃"  PC
 SG_ S2A_AFEMinTemp_25 : 40|8@1+ (1,-50) [-50|205] "℃"  PC
 SG_ S2A_ChipPst_AFEMaxTemp_25 : 48|3@1+ (1,0) [0|7] ""  PC
 SG_ S2A_ChipPst_AFEMinTemp_25 : 51|3@1+ (1,0) [0|7] ""  PC
 SG_ S2A_CscPst_AFEMaxTemp_25 : 54|5@1+ (1,0) [0|31] ""  PC
 SG_ S2A_CscPst_AFEMinTemp_25 : 59|5@1+ (1,0) [0|31] ""  PC

BO_ 2334326618 S2A_SUMDATA22__26: 8 SBMU
 SG_ S2A_PCBMaxTemp_26 : 0|8@1+ (1,-50) [-50|205] "℃"  PC
 SG_ S2A_PCBMinTemp_26 : 8|8@1+ (1,-50) [-50|205] "℃"  PC
 SG_ S2A_ChipPst_PCBMaxTemp_26 : 16|3@1+ (1,0) [0|7] ""  PC
 SG_ S2A_ChipPst_PCBMinTemp_26 : 19|3@1+ (1,0) [0|7] ""  PC
 SG_ S2A_CscPst_PCBMaxTemp_26 : 22|5@1+ (1,0) [0|31] ""  PC
 SG_ S2A_CscPst_PCBMinTemp_26 : 27|5@1+ (1,0) [0|31] ""  PC
 SG_ S2A_AFEMaxTemp_26 : 32|8@1+ (1,-50) [-50|205] "℃"  PC
 SG_ S2A_AFEMinTemp_26 : 40|8@1+ (1,-50) [-50|205] "℃"  PC
 SG_ S2A_ChipPst_AFEMaxTemp_26 : 48|3@1+ (1,0) [0|7] ""  PC
 SG_ S2A_ChipPst_AFEMinTemp_26 : 51|3@1+ (1,0) [0|7] ""  PC
 SG_ S2A_CscPst_AFEMaxTemp_26 : 54|5@1+ (1,0) [0|31] ""  PC
 SG_ S2A_CscPst_AFEMinTemp_26 : 59|5@1+ (1,0) [0|31] ""  PC

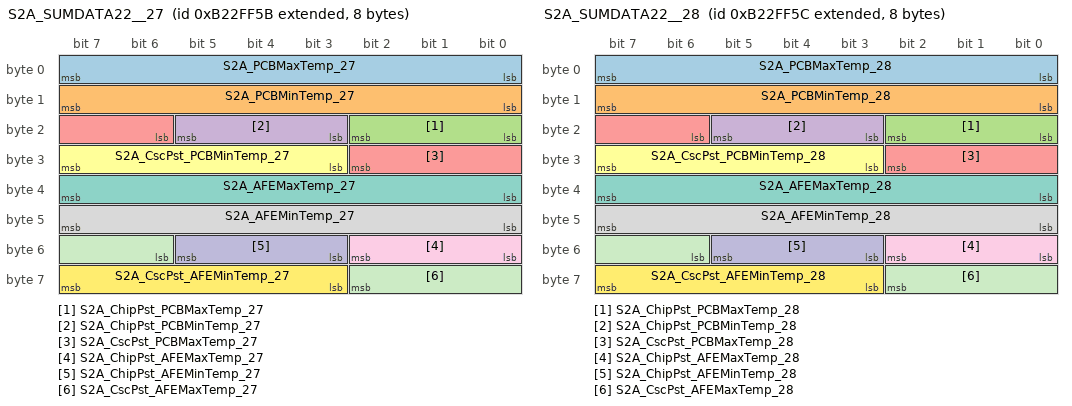
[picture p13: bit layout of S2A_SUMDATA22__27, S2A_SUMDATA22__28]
BO_ 2334326619 S2A_SUMDATA22__27: 8 SBMU
 SG_ S2A_PCBMaxTemp_27 : 0|8@1+ (1,-50) [-50|205] "℃"  PC
 SG_ S2A_PCBMinTemp_27 : 8|8@1+ (1,-50) [-50|205] "℃"  PC
 SG_ S2A_ChipPst_PCBMaxTemp_27 : 16|3@1+ (1,0) [0|7] ""  PC
 SG_ S2A_ChipPst_PCBMinTemp_27 : 19|3@1+ (1,0) [0|7] ""  PC
 SG_ S2A_CscPst_PCBMaxTemp_27 : 22|5@1+ (1,0) [0|31] ""  PC
 SG_ S2A_CscPst_PCBMinTemp_27 : 27|5@1+ (1,0) [0|31] ""  PC
 SG_ S2A_AFEMaxTemp_27 : 32|8@1+ (1,-50) [-50|205] "℃"  PC
 SG_ S2A_AFEMinTemp_27 : 40|8@1+ (1,-50) [-50|205] "℃"  PC
 SG_ S2A_ChipPst_AFEMaxTemp_27 : 48|3@1+ (1,0) [0|7] ""  PC
 SG_ S2A_ChipPst_AFEMinTemp_27 : 51|3@1+ (1,0) [0|7] ""  PC
 SG_ S2A_CscPst_AFEMaxTemp_27 : 54|5@1+ (1,0) [0|31] ""  PC
 SG_ S2A_CscPst_AFEMinTemp_27 : 59|5@1+ (1,0) [0|31] ""  PC

BO_ 2334326620 S2A_SUMDATA22__28: 8 SBMU
 SG_ S2A_PCBMaxTemp_28 : 0|8@1+ (1,-50) [-50|205] "℃"  PC
 SG_ S2A_PCBMinTemp_28 : 8|8@1+ (1,-50) [-50|205] "℃"  PC
 SG_ S2A_ChipPst_PCBMaxTemp_28 : 16|3@1+ (1,0) [0|7] ""  PC
 SG_ S2A_ChipPst_PCBMinTemp_28 : 19|3@1+ (1,0) [0|7] ""  PC
 SG_ S2A_CscPst_PCBMaxTemp_28 : 22|5@1+ (1,0) [0|31] ""  PC
 SG_ S2A_CscPst_PCBMinTemp_28 : 27|5@1+ (1,0) [0|31] ""  PC
 SG_ S2A_AFEMaxTemp_28 : 32|8@1+ (1,-50) [-50|205] "℃"  PC
 SG_ S2A_AFEMinTemp_28 : 40|8@1+ (1,-50) [-50|205] "℃"  PC
 SG_ S2A_ChipPst_AFEMaxTemp_28 : 48|3@1+ (1,0) [0|7] ""  PC
 SG_ S2A_ChipPst_AFEMinTemp_28 : 51|3@1+ (1,0) [0|7] ""  PC
 SG_ S2A_CscPst_AFEMaxTemp_28 : 54|5@1+ (1,0) [0|31] ""  PC
 SG_ S2A_CscPst_AFEMinTemp_28 : 59|5@1+ (1,0) [0|31] ""  PC

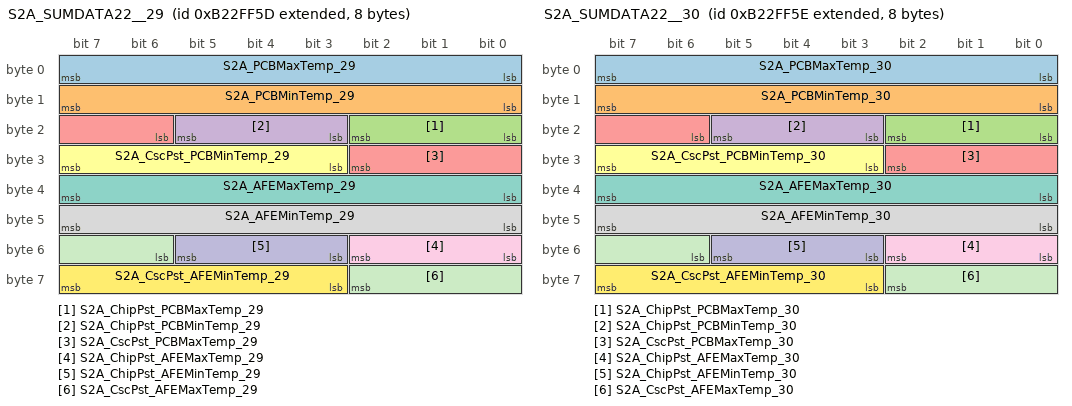
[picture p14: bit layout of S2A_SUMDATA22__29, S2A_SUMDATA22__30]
BO_ 2334326621 S2A_SUMDATA22__29: 8 SBMU
 SG_ S2A_PCBMaxTemp_29 : 0|8@1+ (1,-50) [-50|205] "℃"  PC
 SG_ S2A_PCBMinTemp_29 : 8|8@1+ (1,-50) [-50|205] "℃"  PC
 SG_ S2A_ChipPst_PCBMaxTemp_29 : 16|3@1+ (1,0) [0|7] ""  PC
 SG_ S2A_ChipPst_PCBMinTemp_29 : 19|3@1+ (1,0) [0|7] ""  PC
 SG_ S2A_CscPst_PCBMaxTemp_29 : 22|5@1+ (1,0) [0|31] ""  PC
 SG_ S2A_CscPst_PCBMinTemp_29 : 27|5@1+ (1,0) [0|31] ""  PC
 SG_ S2A_AFEMaxTemp_29 : 32|8@1+ (1,-50) [-50|205] "℃"  PC
 SG_ S2A_AFEMinTemp_29 : 40|8@1+ (1,-50) [-50|205] "℃"  PC
 SG_ S2A_ChipPst_AFEMaxTemp_29 : 48|3@1+ (1,0) [0|7] ""  PC
 SG_ S2A_ChipPst_AFEMinTemp_29 : 51|3@1+ (1,0) [0|7] ""  PC
 SG_ S2A_CscPst_AFEMaxTemp_29 : 54|5@1+ (1,0) [0|31] ""  PC
 SG_ S2A_CscPst_AFEMinTemp_29 : 59|5@1+ (1,0) [0|31] ""  PC

BO_ 2334326622 S2A_SUMDATA22__30: 8 SBMU
 SG_ S2A_PCBMaxTemp_30 : 0|8@1+ (1,-50) [-50|205] "℃"  PC
 SG_ S2A_PCBMinTemp_30 : 8|8@1+ (1,-50) [-50|205] "℃"  PC
 SG_ S2A_ChipPst_PCBMaxTemp_30 : 16|3@1+ (1,0) [0|7] ""  PC
 SG_ S2A_ChipPst_PCBMinTemp_30 : 19|3@1+ (1,0) [0|7] ""  PC
 SG_ S2A_CscPst_PCBMaxTemp_30 : 22|5@1+ (1,0) [0|31] ""  PC
 SG_ S2A_CscPst_PCBMinTemp_30 : 27|5@1+ (1,0) [0|31] ""  PC
 SG_ S2A_AFEMaxTemp_30 : 32|8@1+ (1,-50) [-50|205] "℃"  PC
 SG_ S2A_AFEMinTemp_30 : 40|8@1+ (1,-50) [-50|205] "℃"  PC
 SG_ S2A_ChipPst_AFEMaxTemp_30 : 48|3@1+ (1,0) [0|7] ""  PC
 SG_ S2A_ChipPst_AFEMinTemp_30 : 51|3@1+ (1,0) [0|7] ""  PC
 SG_ S2A_CscPst_AFEMaxTemp_30 : 54|5@1+ (1,0) [0|31] ""  PC
 SG_ S2A_CscPst_AFEMinTemp_30 : 59|5@1+ (1,0) [0|31] ""  PC

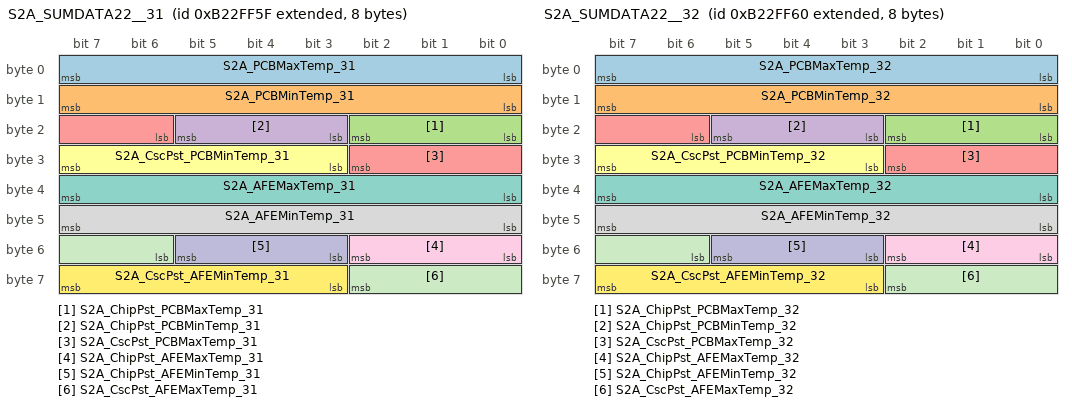
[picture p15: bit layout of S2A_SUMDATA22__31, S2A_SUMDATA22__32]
BO_ 2334326623 S2A_SUMDATA22__31: 8 SBMU
 SG_ S2A_PCBMaxTemp_31 : 0|8@1+ (1,-50) [-50|205] "℃"  PC
 SG_ S2A_PCBMinTemp_31 : 8|8@1+ (1,-50) [-50|205] "℃"  PC
 SG_ S2A_ChipPst_PCBMaxTemp_31 : 16|3@1+ (1,0) [0|7] ""  PC
 SG_ S2A_ChipPst_PCBMinTemp_31 : 19|3@1+ (1,0) [0|7] ""  PC
 SG_ S2A_CscPst_PCBMaxTemp_31 : 22|5@1+ (1,0) [0|31] ""  PC
 SG_ S2A_CscPst_PCBMinTemp_31 : 27|5@1+ (1,0) [0|31] ""  PC
 SG_ S2A_AFEMaxTemp_31 : 32|8@1+ (1,-50) [-50|205] "℃"  PC
 SG_ S2A_AFEMinTemp_31 : 40|8@1+ (1,-50) [-50|205] "℃"  PC
 SG_ S2A_ChipPst_AFEMaxTemp_31 : 48|3@1+ (1,0) [0|7] ""  PC
 SG_ S2A_ChipPst_AFEMinTemp_31 : 51|3@1+ (1,0) [0|7] ""  PC
 SG_ S2A_CscPst_AFEMaxTemp_31 : 54|5@1+ (1,0) [0|31] ""  PC
 SG_ S2A_CscPst_AFEMinTemp_31 : 59|5@1+ (1,0) [0|31] ""  PC

BO_ 2334326624 S2A_SUMDATA22__32: 8 SBMU
 SG_ S2A_PCBMaxTemp_32 : 0|8@1+ (1,-50) [-50|205] "℃"  PC
 SG_ S2A_PCBMinTemp_32 : 8|8@1+ (1,-50) [-50|205] "℃"  PC
 SG_ S2A_ChipPst_PCBMaxTemp_32 : 16|3@1+ (1,0) [0|7] ""  PC
 SG_ S2A_ChipPst_PCBMinTemp_32 : 19|3@1+ (1,0) [0|7] ""  PC
 SG_ S2A_CscPst_PCBMaxTemp_32 : 22|5@1+ (1,0) [0|31] ""  PC
 SG_ S2A_CscPst_PCBMinTemp_32 : 27|5@1+ (1,0) [0|31] ""  PC
 SG_ S2A_AFEMaxTemp_32 : 32|8@1+ (1,-50) [-50|205] "℃"  PC
 SG_ S2A_AFEMinTemp_32 : 40|8@1+ (1,-50) [-50|205] "℃"  PC
 SG_ S2A_ChipPst_AFEMaxTemp_32 : 48|3@1+ (1,0) [0|7] ""  PC
 SG_ S2A_ChipPst_AFEMinTemp_32 : 51|3@1+ (1,0) [0|7] ""  PC
 SG_ S2A_CscPst_AFEMaxTemp_32 : 54|5@1+ (1,0) [0|31] ""  PC
 SG_ S2A_CscPst_AFEMinTemp_32 : 59|5@1+ (1,0) [0|31] ""  PC

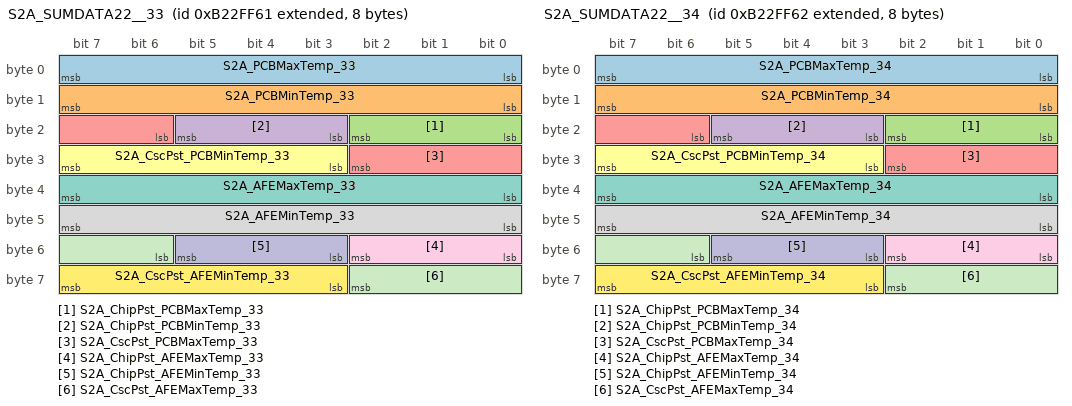
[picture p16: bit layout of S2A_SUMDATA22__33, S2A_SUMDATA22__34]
BO_ 2334326625 S2A_SUMDATA22__33: 8 SBMU
 SG_ S2A_PCBMaxTemp_33 : 0|8@1+ (1,-50) [-50|205] "℃"  PC
 SG_ S2A_PCBMinTemp_33 : 8|8@1+ (1,-50) [-50|205] "℃"  PC
 SG_ S2A_ChipPst_PCBMaxTemp_33 : 16|3@1+ (1,0) [0|7] ""  PC
 SG_ S2A_ChipPst_PCBMinTemp_33 : 19|3@1+ (1,0) [0|7] ""  PC
 SG_ S2A_CscPst_PCBMaxTemp_33 : 22|5@1+ (1,0) [0|31] ""  PC
 SG_ S2A_CscPst_PCBMinTemp_33 : 27|5@1+ (1,0) [0|31] ""  PC
 SG_ S2A_AFEMaxTemp_33 : 32|8@1+ (1,-50) [-50|205] "℃"  PC
 SG_ S2A_AFEMinTemp_33 : 40|8@1+ (1,-50) [-50|205] "℃"  PC
 SG_ S2A_ChipPst_AFEMaxTemp_33 : 48|3@1+ (1,0) [0|7] ""  PC
 SG_ S2A_ChipPst_AFEMinTemp_33 : 51|3@1+ (1,0) [0|7] ""  PC
 SG_ S2A_CscPst_AFEMaxTemp_33 : 54|5@1+ (1,0) [0|31] ""  PC
 SG_ S2A_CscPst_AFEMinTemp_33 : 59|5@1+ (1,0) [0|31] ""  PC

BO_ 2334326626 S2A_SUMDATA22__34: 8 SBMU
 SG_ S2A_PCBMaxTemp_34 : 0|8@1+ (1,-50) [-50|205] "℃"  PC
 SG_ S2A_PCBMinTemp_34 : 8|8@1+ (1,-50) [-50|205] "℃"  PC
 SG_ S2A_ChipPst_PCBMaxTemp_34 : 16|3@1+ (1,0) [0|7] ""  PC
 SG_ S2A_ChipPst_PCBMinTemp_34 : 19|3@1+ (1,0) [0|7] ""  PC
 SG_ S2A_CscPst_PCBMaxTemp_34 : 22|5@1+ (1,0) [0|31] ""  PC
 SG_ S2A_CscPst_PCBMinTemp_34 : 27|5@1+ (1,0) [0|31] ""  PC
 SG_ S2A_AFEMaxTemp_34 : 32|8@1+ (1,-50) [-50|205] "℃"  PC
 SG_ S2A_AFEMinTemp_34 : 40|8@1+ (1,-50) [-50|205] "℃"  PC
 SG_ S2A_ChipPst_AFEMaxTemp_34 : 48|3@1+ (1,0) [0|7] ""  PC
 SG_ S2A_ChipPst_AFEMinTemp_34 : 51|3@1+ (1,0) [0|7] ""  PC
 SG_ S2A_CscPst_AFEMaxTemp_34 : 54|5@1+ (1,0) [0|31] ""  PC
 SG_ S2A_CscPst_AFEMinTemp_34 : 59|5@1+ (1,0) [0|31] ""  PC

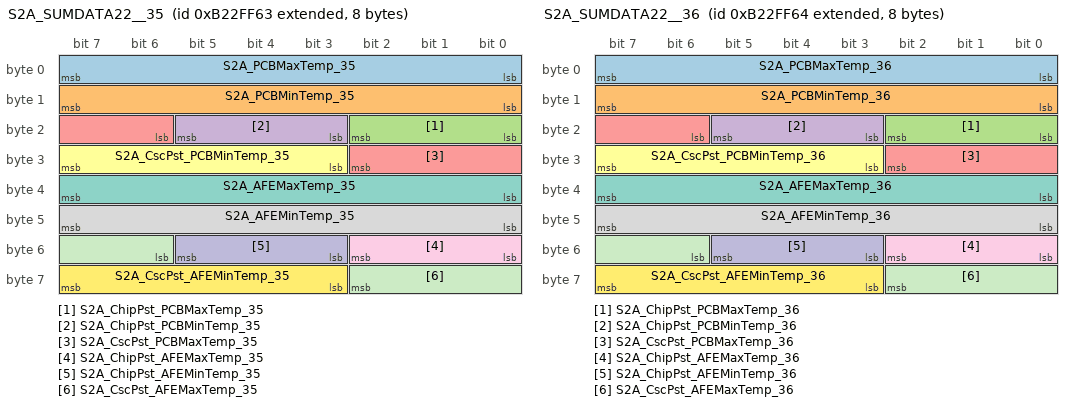
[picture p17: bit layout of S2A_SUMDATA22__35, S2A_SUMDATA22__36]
BO_ 2334326627 S2A_SUMDATA22__35: 8 SBMU
 SG_ S2A_PCBMaxTemp_35 : 0|8@1+ (1,-50) [-50|205] "℃"  PC
 SG_ S2A_PCBMinTemp_35 : 8|8@1+ (1,-50) [-50|205] "℃"  PC
 SG_ S2A_ChipPst_PCBMaxTemp_35 : 16|3@1+ (1,0) [0|7] ""  PC
 SG_ S2A_ChipPst_PCBMinTemp_35 : 19|3@1+ (1,0) [0|7] ""  PC
 SG_ S2A_CscPst_PCBMaxTemp_35 : 22|5@1+ (1,0) [0|31] ""  PC
 SG_ S2A_CscPst_PCBMinTemp_35 : 27|5@1+ (1,0) [0|31] ""  PC
 SG_ S2A_AFEMaxTemp_35 : 32|8@1+ (1,-50) [-50|205] "℃"  PC
 SG_ S2A_AFEMinTemp_35 : 40|8@1+ (1,-50) [-50|205] "℃"  PC
 SG_ S2A_ChipPst_AFEMaxTemp_35 : 48|3@1+ (1,0) [0|7] ""  PC
 SG_ S2A_ChipPst_AFEMinTemp_35 : 51|3@1+ (1,0) [0|7] ""  PC
 SG_ S2A_CscPst_AFEMaxTemp_35 : 54|5@1+ (1,0) [0|31] ""  PC
 SG_ S2A_CscPst_AFEMinTemp_35 : 59|5@1+ (1,0) [0|31] ""  PC

BO_ 2334326628 S2A_SUMDATA22__36: 8 SBMU
 SG_ S2A_PCBMaxTemp_36 : 0|8@1+ (1,-50) [-50|205] "℃"  PC
 SG_ S2A_PCBMinTemp_36 : 8|8@1+ (1,-50) [-50|205] "℃"  PC
 SG_ S2A_ChipPst_PCBMaxTemp_36 : 16|3@1+ (1,0) [0|7] ""  PC
 SG_ S2A_ChipPst_PCBMinTemp_36 : 19|3@1+ (1,0) [0|7] ""  PC
 SG_ S2A_CscPst_PCBMaxTemp_36 : 22|5@1+ (1,0) [0|31] ""  PC
 SG_ S2A_CscPst_PCBMinTemp_36 : 27|5@1+ (1,0) [0|31] ""  PC
 SG_ S2A_AFEMaxTemp_36 : 32|8@1+ (1,-50) [-50|205] "℃"  PC
 SG_ S2A_AFEMinTemp_36 : 40|8@1+ (1,-50) [-50|205] "℃"  PC
 SG_ S2A_ChipPst_AFEMaxTemp_36 : 48|3@1+ (1,0) [0|7] ""  PC
 SG_ S2A_ChipPst_AFEMinTemp_36 : 51|3@1+ (1,0) [0|7] ""  PC
 SG_ S2A_CscPst_AFEMaxTemp_36 : 54|5@1+ (1,0) [0|31] ""  PC
 SG_ S2A_CscPst_AFEMinTemp_36 : 59|5@1+ (1,0) [0|31] ""  PC

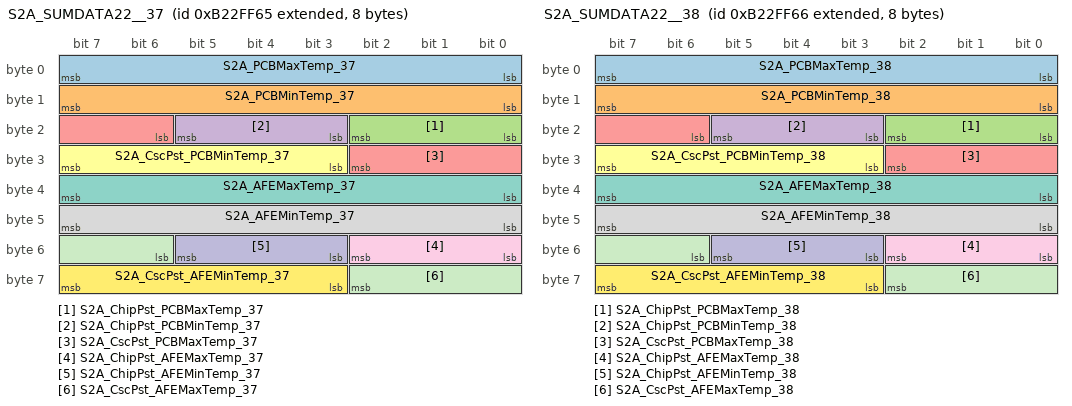
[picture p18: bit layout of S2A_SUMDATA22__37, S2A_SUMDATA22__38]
BO_ 2334326629 S2A_SUMDATA22__37: 8 SBMU
 SG_ S2A_PCBMaxTemp_37 : 0|8@1+ (1,-50) [-50|205] "℃"  PC
 SG_ S2A_PCBMinTemp_37 : 8|8@1+ (1,-50) [-50|205] "℃"  PC
 SG_ S2A_ChipPst_PCBMaxTemp_37 : 16|3@1+ (1,0) [0|7] ""  PC
 SG_ S2A_ChipPst_PCBMinTemp_37 : 19|3@1+ (1,0) [0|7] ""  PC
 SG_ S2A_CscPst_PCBMaxTemp_37 : 22|5@1+ (1,0) [0|31] ""  PC
 SG_ S2A_CscPst_PCBMinTemp_37 : 27|5@1+ (1,0) [0|31] ""  PC
 SG_ S2A_AFEMaxTemp_37 : 32|8@1+ (1,-50) [-50|205] "℃"  PC
 SG_ S2A_AFEMinTemp_37 : 40|8@1+ (1,-50) [-50|205] "℃"  PC
 SG_ S2A_ChipPst_AFEMaxTemp_37 : 48|3@1+ (1,0) [0|7] ""  PC
 SG_ S2A_ChipPst_AFEMinTemp_37 : 51|3@1+ (1,0) [0|7] ""  PC
 SG_ S2A_CscPst_AFEMaxTemp_37 : 54|5@1+ (1,0) [0|31] ""  PC
 SG_ S2A_CscPst_AFEMinTemp_37 : 59|5@1+ (1,0) [0|31] ""  PC

BO_ 2334326630 S2A_SUMDATA22__38: 8 SBMU
 SG_ S2A_PCBMaxTemp_38 : 0|8@1+ (1,-50) [-50|205] "℃"  PC
 SG_ S2A_PCBMinTemp_38 : 8|8@1+ (1,-50) [-50|205] "℃"  PC
 SG_ S2A_ChipPst_PCBMaxTemp_38 : 16|3@1+ (1,0) [0|7] ""  PC
 SG_ S2A_ChipPst_PCBMinTemp_38 : 19|3@1+ (1,0) [0|7] ""  PC
 SG_ S2A_CscPst_PCBMaxTemp_38 : 22|5@1+ (1,0) [0|31] ""  PC
 SG_ S2A_CscPst_PCBMinTemp_38 : 27|5@1+ (1,0) [0|31] ""  PC
 SG_ S2A_AFEMaxTemp_38 : 32|8@1+ (1,-50) [-50|205] "℃"  PC
 SG_ S2A_AFEMinTemp_38 : 40|8@1+ (1,-50) [-50|205] "℃"  PC
 SG_ S2A_ChipPst_AFEMaxTemp_38 : 48|3@1+ (1,0) [0|7] ""  PC
 SG_ S2A_ChipPst_AFEMinTemp_38 : 51|3@1+ (1,0) [0|7] ""  PC
 SG_ S2A_CscPst_AFEMaxTemp_38 : 54|5@1+ (1,0) [0|31] ""  PC
 SG_ S2A_CscPst_AFEMinTemp_38 : 59|5@1+ (1,0) [0|31] ""  PC

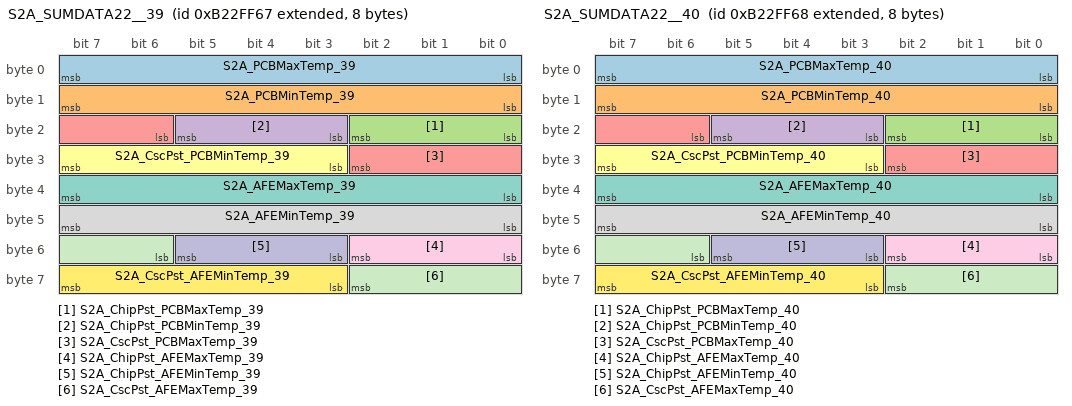
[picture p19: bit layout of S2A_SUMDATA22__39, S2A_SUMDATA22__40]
BO_ 2334326631 S2A_SUMDATA22__39: 8 SBMU
 SG_ S2A_PCBMaxTemp_39 : 0|8@1+ (1,-50) [-50|205] "℃"  PC
 SG_ S2A_PCBMinTemp_39 : 8|8@1+ (1,-50) [-50|205] "℃"  PC
 SG_ S2A_ChipPst_PCBMaxTemp_39 : 16|3@1+ (1,0) [0|7] ""  PC
 SG_ S2A_ChipPst_PCBMinTemp_39 : 19|3@1+ (1,0) [0|7] ""  PC
 SG_ S2A_CscPst_PCBMaxTemp_39 : 22|5@1+ (1,0) [0|31] ""  PC
 SG_ S2A_CscPst_PCBMinTemp_39 : 27|5@1+ (1,0) [0|31] ""  PC
 SG_ S2A_AFEMaxTemp_39 : 32|8@1+ (1,-50) [-50|205] "℃"  PC
 SG_ S2A_AFEMinTemp_39 : 40|8@1+ (1,-50) [-50|205] "℃"  PC
 SG_ S2A_ChipPst_AFEMaxTemp_39 : 48|3@1+ (1,0) [0|7] ""  PC
 SG_ S2A_ChipPst_AFEMinTemp_39 : 51|3@1+ (1,0) [0|7] ""  PC
 SG_ S2A_CscPst_AFEMaxTemp_39 : 54|5@1+ (1,0) [0|31] ""  PC
 SG_ S2A_CscPst_AFEMinTemp_39 : 59|5@1+ (1,0) [0|31] ""  PC

BO_ 2334326632 S2A_SUMDATA22__40: 8 SBMU
 SG_ S2A_PCBMaxTemp_40 : 0|8@1+ (1,-50) [-50|205] "℃"  PC
 SG_ S2A_PCBMinTemp_40 : 8|8@1+ (1,-50) [-50|205] "℃"  PC
 SG_ S2A_ChipPst_PCBMaxTemp_40 : 16|3@1+ (1,0) [0|7] ""  PC
 SG_ S2A_ChipPst_PCBMinTemp_40 : 19|3@1+ (1,0) [0|7] ""  PC
 SG_ S2A_CscPst_PCBMaxTemp_40 : 22|5@1+ (1,0) [0|31] ""  PC
 SG_ S2A_CscPst_PCBMinTemp_40 : 27|5@1+ (1,0) [0|31] ""  PC
 SG_ S2A_AFEMaxTemp_40 : 32|8@1+ (1,-50) [-50|205] "℃"  PC
 SG_ S2A_AFEMinTemp_40 : 40|8@1+ (1,-50) [-50|205] "℃"  PC
 SG_ S2A_ChipPst_AFEMaxTemp_40 : 48|3@1+ (1,0) [0|7] ""  PC
 SG_ S2A_ChipPst_AFEMinTemp_40 : 51|3@1+ (1,0) [0|7] ""  PC
 SG_ S2A_CscPst_AFEMaxTemp_40 : 54|5@1+ (1,0) [0|31] ""  PC
 SG_ S2A_CscPst_AFEMinTemp_40 : 59|5@1+ (1,0) [0|31] ""  PC

BO_ 2334326633 S2A_SUMDATA22__41: 8 SBMU
 SG_ S2A_PCBMaxTemp_41 : 0|8@1+ (1,-50) [-50|205] "℃"  PC
 SG_ S2A_PCBMinTemp_41 : 8|8@1+ (1,-50) [-50|205] "℃"  PC
 SG_ S2A_ChipPst_PCBMaxTemp_41 : 16|3@1+ (1,0) [0|7] ""  PC
 SG_ S2A_ChipPst_PCBMinTemp_41 : 19|3@1+ (1,0) [0|7] ""  PC
 SG_ S2A_CscPst_PCBMaxTemp_41 : 22|5@1+ (1,0) [0|31] ""  PC
 SG_ S2A_CscPst_PCBMinTemp_41 : 27|5@1+ (1,0) [0|31] ""  PC
 SG_ S2A_AFEMaxTemp_41 : 32|8@1+ (1,-50) [-50|205] "℃"  PC
 SG_ S2A_AFEMinTemp_41 : 40|8@1+ (1,-50) [-50|205] "℃"  PC
 SG_ S2A_ChipPst_AFEMaxTemp_41 : 48|3@1+ (1,0) [0|7] ""  PC
 SG_ S2A_ChipPst_AFEMinTemp_41 : 51|3@1+ (1,0) [0|7] ""  PC
 SG_ S2A_CscPst_AFEMaxTemp_41 : 54|5@1+ (1,0) [0|31] ""  PC
 SG_ S2A_CscPst_AFEMinTemp_41 : 59|5@1+ (1,0) [0|31] ""  PC

BO_ 2334326634 S2A_SUMDATA22__42: 8 SBMU
 SG_ S2A_PCBMaxTemp_42 : 0|8@1+ (1,-50) [-50|205] "℃"  PC
 SG_ S2A_PCBMinTemp_42 : 8|8@1+ (1,-50) [-50|205] "℃"  PC
 SG_ S2A_ChipPst_PCBMaxTemp_42 : 16|3@1+ (1,0) [0|7] ""  PC
 SG_ S2A_ChipPst_PCBMinTemp_42 : 19|3@1+ (1,0) [0|7] ""  PC
 SG_ S2A_CscPst_PCBMaxTemp_42 : 22|5@1+ (1,0) [0|31] ""  PC
 SG_ S2A_CscPst_PCBMinTemp_42 : 27|5@1+ (1,0) [0|31] ""  PC
 SG_ S2A_AFEMaxTemp_42 : 32|8@1+ (1,-50) [-50|205] "℃"  PC
 SG_ S2A_AFEMinTemp_42 : 40|8@1+ (1,-50) [-50|205] "℃"  PC
 SG_ S2A_ChipPst_AFEMaxTemp_42 : 48|3@1+ (1,0) [0|7] ""  PC
 SG_ S2A_ChipPst_AFEMinTemp_42 : 51|3@1+ (1,0) [0|7] ""  PC
 SG_ S2A_CscPst_AFEMaxTemp_42 : 54|5@1+ (1,0) [0|31] ""  PC
 SG_ S2A_CscPst_AFEMinTemp_42 : 59|5@1+ (1,0) [0|31] ""  PC

BO_ 2334326635 S2A_SUMDATA22__43: 8 SBMU
 SG_ S2A_PCBMaxTemp_43 : 0|8@1+ (1,-50) [-50|205] "℃"  PC
 SG_ S2A_PCBMinTemp_43 : 8|8@1+ (1,-50) [-50|205] "℃"  PC
 SG_ S2A_ChipPst_PCBMaxTemp_43 : 16|3@1+ (1,0) [0|7] ""  PC
 SG_ S2A_ChipPst_PCBMinTemp_43 : 19|3@1+ (1,0) [0|7] ""  PC
 SG_ S2A_CscPst_PCBMaxTemp_43 : 22|5@1+ (1,0) [0|31] ""  PC
 SG_ S2A_CscPst_PCBMinTemp_43 : 27|5@1+ (1,0) [0|31] ""  PC
 SG_ S2A_AFEMaxTemp_43 : 32|8@1+ (1,-50) [-50|205] "℃"  PC
 SG_ S2A_AFEMinTemp_43 : 40|8@1+ (1,-50) [-50|205] "℃"  PC
 SG_ S2A_ChipPst_AFEMaxTemp_43 : 48|3@1+ (1,0) [0|7] ""  PC
 SG_ S2A_ChipPst_AFEMinTemp_43 : 51|3@1+ (1,0) [0|7] ""  PC
 SG_ S2A_CscPst_AFEMaxTemp_43 : 54|5@1+ (1,0) [0|31] ""  PC
 SG_ S2A_CscPst_AFEMinTemp_43 : 59|5@1+ (1,0) [0|31] ""  PC

CM_ SG_ 2337074834 M2P_SOE_Charge_B11 "汇流排11系可充电SOE";
CM_ SG_ 2337074834 M2P_SOE_Discharge_B11 "汇流排11系可放电SOE";
CM_ SG_ 2337074834 Reserved_02 "预留";
CM_ SG_ 2337074835 M2P_SOE_Charge_B11 "汇流排11系可充电SOE";
CM_ SG_ 2337074835 M2P_SOE_Discharge_B11 "汇流排11系可放电SOE";
CM_ SG_ 2337074835 Reserved_03 "预留";
CM_ SG_ 2337074836 M2P_SOE_Charge_B11 "汇流排11系可充电SOE";
CM_ SG_ 2337074836 M2P_SOE_Discharge_B11 "汇流排11系可放电SOE";
CM_ SG_ 2337074836 Reserved_04 "预留";
CM_ SG_ 2337074837 M2P_SOE_Charge_B11 "汇流排11系可充电SOE";
CM_ SG_ 2337074837 M2P_SOE_Discharge_B11 "汇流排11系可放电SOE";
CM_ SG_ 2337074837 Reserved_05 "预留";
CM_ SG_ 2337074838 M2P_SOE_Charge_B11 "汇流排11系可充电SOE";
CM_ SG_ 2337074838 M2P_SOE_Discharge_B11 "汇流排11系可放电SOE";
CM_ SG_ 2337074838 Reserved_06 "预留";
CM_ SG_ 2337074839 M2P_SOE_Charge_B11 "汇流排11系可充电SOE";
CM_ SG_ 2337074839 M2P_SOE_Discharge_B11 "汇流排11系可放电SOE";
CM_ SG_ 2337074839 Reserved_07 "预留";
CM_ SG_ 2337074840 M2P_SOE_Charge_B11 "汇流排11系可充电SOE";
CM_ SG_ 2337074840 M2P_SOE_Discharge_B11 "汇流排11系可放电SOE";
CM_ SG_ 2337074840 Reserved_08 "预留";
CM_ SG_ 2337074841 M2P_SOE_Charge_B11 "汇流排11系可充电SOE";
CM_ SG_ 2337074841 M2P_SOE_Discharge_B11 "汇流排11系可放电SOE";
CM_ SG_ 2337074841 Reserved_09 "预留";
CM_ SG_ 2337074842 M2P_SOE_Charge_B11 "汇流排11系可充电SOE";
CM_ SG_ 2337074842 M2P_SOE_Discharge_B11 "汇流排11系可放电SOE";
CM_ SG_ 2337074842 Reserved_10 "预留";
CM_ SG_ 2337074843 M2P_SOE_Charge_B11 "汇流排11系可充电SOE";
CM_ SG_ 2337074843 M2P_SOE_Discharge_B11 "汇流排11系可放电SOE";
CM_ SG_ 2337074843 Reserved_11 "预留";
CM_ SG_ 2337074844 M2P_SOE_Charge_B11 "汇流排11系可充电SOE";
CM_ SG_ 2337074844 M2P_SOE_Discharge_B11 "汇流排11系可放电SOE";
CM_ SG_ 2337074844 Reserved_12 "预留";
CM_ SG_ 2337074845 M2P_SOE_Charge_B11 "汇流排11系可充电SOE";
CM_ SG_ 2337074845 M2P_SOE_Discharge_B11 "汇流排11系可放电SOE";
CM_ SG_ 2337074845 Reserved_13 "预留";
CM_ SG_ 2337074846 M2P_SOE_Charge_B11 "汇流排11系可充电SOE";
CM_ SG_ 2337074846 M2P_SOE_Discharge_B11 "汇流排11系可放电SOE";
CM_ SG_ 2337074846 Reserved_14 "预留";
CM_ SG_ 2337074847 M2P_SOE_Charge_B11 "汇流排11系可充电SOE";
CM_ SG_ 2337074847 M2P_SOE_Discharge_B11 "汇流排11系可放电SOE";
CM_ SG_ 2337074847 Reserved_15 "预留";
CM_ SG_ 2337074848 M2P_SOE_Charge_B11 "汇流排11系可充电SOE";
CM_ SG_ 2337074848 M2P_SOE_Discharge_B11 "汇流排11系可放电SOE";
CM_ SG_ 2337074848 Reserved_16 "预留";
CM_ SG_ 2337074849 M2P_SOE_Charge_B11 "汇流排11系可充电SOE";
CM_ SG_ 2337074849 M2P_SOE_Discharge_B11 "汇流排11系可放电SOE";
CM_ SG_ 2337074849 Reserved_17 "预留";
CM_ SG_ 2337074850 M2P_SOE_Charge_B11 "汇流排11系可充电SOE";
CM_ SG_ 2337074850 M2P_SOE_Discharge_B11 "汇流排11系可放电SOE";
CM_ SG_ 2337074850 Reserved_18 "预留";
CM_ SG_ 2337074851 M2P_SOE_Charge_B11 "汇流排11系可充电SOE";
CM_ SG_ 2337074851 M2P_SOE_Discharge_B11 "汇流排11系可放电SOE";
CM_ SG_ 2337074851 Reserved_19 "预留";
CM_ SG_ 2337074852 M2P_SOE_Charge_B11 "汇流排11系可充电SOE";
CM_ SG_ 2337074852 M2P_SOE_Discharge_B11 "汇流排11系可放电SOE";
CM_ SG_ 2337074852 Reserved_20 "预留";
CM_ SG_ 2337074853 M2P_SOE_Charge_B11 "汇流排11系可充电SOE";
CM_ SG_ 2337074853 M2P_SOE_Discharge_B11 "汇流排11系可放电SOE";
CM_ SG_ 2337074853 Reserved_21 "预留";
CM_ SG_ 2337074854 M2P_SOE_Charge_B11 "汇流排11系可充电SOE";
CM_ SG_ 2337074854 M2P_SOE_Discharge_B11 "汇流排11系可放电SOE";
CM_ SG_ 2337074854 Reserved_22 "预留";
CM_ SG_ 2337074855 M2P_SOE_Charge_B11 "汇流排11系可充电SOE";
CM_ SG_ 2337074855 M2P_SOE_Discharge_B11 "汇流排11系可放电SOE";
CM_ SG_ 2337074855 Reserved_23 "预留";
CM_ SG_ 2337074856 M2P_SOE_Charge_B11 "汇流排11系可充电SOE";
CM_ SG_ 2337074856 M2P_SOE_Discharge_B11 "汇流排11系可放电SOE";
CM_ SG_ 2337074856 Reserved_24 "预留";
CM_ SG_ 2337074857 M2P_SOE_Charge_B11 "汇流排11系可充电SOE";
CM_ SG_ 2337074857 M2P_SOE_Discharge_B11 "汇流排11系可放电SOE";
CM_ SG_ 2337074857 Reserved_25 "预留";
CM_ SG_ 2337074858 M2P_SOE_Charge_B11 "汇流排11系可充电SOE";
CM_ SG_ 2337074858 M2P_SOE_Discharge_B11 "汇流排11系可放电SOE";
CM_ SG_ 2337074858 Reserved_26 "预留";
CM_ SG_ 2337074859 M2P_SOE_Charge_B11 "汇流排11系可充电SOE";
CM_ SG_ 2337074859 M2P_SOE_Discharge_B11 "汇流排11系可放电SOE";
CM_ SG_ 2337074859 Reserved_27 "预留";
CM_ SG_ 2337074860 M2P_SOE_Charge_B11 "汇流排11系可充电SOE";
CM_ SG_ 2337074860 M2P_SOE_Discharge_B11 "汇流排11系可放电SOE";
CM_ SG_ 2337074860 Reserved_28 "预留";
CM_ SG_ 2337074861 M2P_SOE_Charge_B11 "汇流排11系可充电SOE";
CM_ SG_ 2337074861 M2P_SOE_Discharge_B11 "汇流排11系可放电SOE";
CM_ SG_ 2337074861 Reserved_29 "预留";
CM_ SG_ 2337074862 M2P_SOE_Charge_B11 "汇流排11系可充电SOE";
CM_ SG_ 2337074862 M2P_SOE_Discharge_B11 "汇流排11系可放电SOE";
CM_ SG_ 2337074862 Reserved_30 "预留";
CM_ SG_ 2337074863 M2P_SOE_Charge_B11 "汇流排11系可充电SOE";
CM_ SG_ 2337074863 M2P_SOE_Discharge_B11 "汇流排11系可放电SOE";
CM_ SG_ 2337074863 Reserved_31 "预留";
CM_ SG_ 2337140369 M2P_Measure_Vol_B12_01 "汇流排12所有高压在线电柜外侧电压平均值    ";
CM_ SG_ 2337140369 M2P_Current_B12_01 "汇流排12所有电柜电流累加和";
CM_ SG_ 2337140369 M2P_PermitMaxCharge_I_B12_01 "汇流排12最大允许充电电流";
CM_ SG_ 2337140369 M2P_PermitMaxDisCharge_I_B12_01 "汇流排12最大允许放电电流";
CM_ SG_ 2337140370 M2P_Measure_Vol_B12_02 "汇流排12所有高压在线电柜外侧电压平均值    ";
CM_ SG_ 2337140370 M2P_Current_B12_02 "汇流排12所有电柜电流累加和";
CM_ SG_ 2337140370 M2P_PermitMaxCharge_I_B12_02 "汇流排12最大允许充电电流";
CM_ SG_ 2337140370 M2P_PermitMaxDisCharge_I_B12_02 "汇流排12最大允许放电电流";
CM_ SG_ 2337140371 M2P_Measure_Vol_B12_03 "汇流排12所有高压在线电柜外侧电压平均值    ";
CM_ SG_ 2337140371 M2P_Current_B12_03 "汇流排12所有电柜电流累加和";
CM_ SG_ 2337140371 M2P_PermitMaxCharge_I_B12_03 "汇流排12最大允许充电电流";
CM_ SG_ 2337140371 M2P_PermitMaxDisCharge_I_B12_03 "汇流排12最大允许放电电流";
CM_ SG_ 2337140372 M2P_Measure_Vol_B12_04 "汇流排12所有高压在线电柜外侧电压平均值    ";
CM_ SG_ 2337140372 M2P_Current_B12_04 "汇流排12所有电柜电流累加和";
CM_ SG_ 2337140372 M2P_PermitMaxCharge_I_B12_04 "汇流排12最大允许充电电流";
CM_ SG_ 2337140372 M2P_PermitMaxDisCharge_I_B12_04 "汇流排12最大允许放电电流";
CM_ SG_ 2337140373 M2P_Measure_Vol_B12_05 "汇流排12所有高压在线电柜外侧电压平均值    ";
CM_ SG_ 2337140373 M2P_Current_B12_05 "汇流排12所有电柜电流累加和";
CM_ SG_ 2337140373 M2P_PermitMaxCharge_I_B12_05 "汇流排12最大允许充电电流";
CM_ SG_ 2337140373 M2P_PermitMaxDisCharge_I_B12_05 "汇流排12最大允许放电电流";
CM_ SG_ 2337140374 M2P_Measure_Vol_B12_06 "汇流排12所有高压在线电柜外侧电压平均值    ";
CM_ SG_ 2337140374 M2P_Current_B12_06 "汇流排12所有电柜电流累加和";
CM_ SG_ 2337140374 M2P_PermitMaxCharge_I_B12_06 "汇流排12最大允许充电电流";
CM_ SG_ 2337140374 M2P_PermitMaxDisCharge_I_B12_06 "汇流排12最大允许放电电流";
CM_ SG_ 2337140375 M2P_Measure_Vol_B12_07 "汇流排12所有高压在线电柜外侧电压平均值    ";
CM_ SG_ 2337140375 M2P_Current_B12_07 "汇流排12所有电柜电流累加和";
CM_ SG_ 2337140375 M2P_PermitMaxCharge_I_B12_07 "汇流排12最大允许充电电流";
CM_ SG_ 2337140375 M2P_PermitMaxDisCharge_I_B12_07 "汇流排12最大允许放电电流";
CM_ SG_ 2337140376 M2P_Measure_Vol_B12_08 "汇流排12所有高压在线电柜外侧电压平均值    ";
CM_ SG_ 2337140376 M2P_Current_B12_08 "汇流排12所有电柜电流累加和";
CM_ SG_ 2337140376 M2P_PermitMaxCharge_I_B12_08 "汇流排12最大允许充电电流";
CM_ SG_ 2337140376 M2P_PermitMaxDisCharge_I_B12_08 "汇流排12最大允许放电电流";
CM_ SG_ 2337140377 M2P_Measure_Vol_B12_09 "汇流排12所有高压在线电柜外侧电压平均值    ";
CM_ SG_ 2337140377 M2P_Current_B12_09 "汇流排12所有电柜电流累加和";
CM_ SG_ 2337140377 M2P_PermitMaxCharge_I_B12_09 "汇流排12最大允许充电电流";
CM_ SG_ 2337140377 M2P_PermitMaxDisCharge_I_B12_09 "汇流排12最大允许放电电流";
CM_ SG_ 2337140378 M2P_Measure_Vol_B12_10 "汇流排12所有高压在线电柜外侧电压平均值    ";
CM_ SG_ 2337140378 M2P_Current_B12_10 "汇流排12所有电柜电流累加和";
CM_ SG_ 2337140378 M2P_PermitMaxCharge_I_B12_10 "汇流排12最大允许充电电流";
CM_ SG_ 2337140378 M2P_PermitMaxDisCharge_I_B12_10 "汇流排12最大允许放电电流";
CM_ SG_ 2337140379 M2P_Measure_Vol_B12_11 "汇流排12所有高压在线电柜外侧电压平均值    ";
CM_ SG_ 2337140379 M2P_Current_B12_11 "汇流排12所有电柜电流累加和";
CM_ SG_ 2337140379 M2P_PermitMaxCharge_I_B12_11 "汇流排12最大允许充电电流";
CM_ SG_ 2337140379 M2P_PermitMaxDisCharge_I_B12_11 "汇流排12最大允许放电电流";
CM_ SG_ 2337140380 M2P_Measure_Vol_B12_12 "汇流排12所有高压在线电柜外侧电压平均值    ";
CM_ SG_ 2337140380 M2P_Current_B12_12 "汇流排12所有电柜电流累加和";
CM_ SG_ 2337140380 M2P_PermitMaxCharge_I_B12_12 "汇流排12最大允许充电电流";
CM_ SG_ 2337140380 M2P_PermitMaxDisCharge_I_B12_12 "汇流排12最大允许放电电流";
CM_ SG_ 2337140381 M2P_Measure_Vol_B12_13 "汇流排12所有高压在线电柜外侧电压平均值    ";
CM_ SG_ 2337140381 M2P_Current_B12_13 "汇流排12所有电柜电流累加和";
CM_ SG_ 2337140381 M2P_PermitMaxCharge_I_B12_13 "汇流排12最大允许充电电流";
CM_ SG_ 2337140381 M2P_PermitMaxDisCharge_I_B12_13 "汇流排12最大允许放电电流";
CM_ SG_ 2337140382 M2P_Measure_Vol_B12_14 "汇流排12所有高压在线电柜外侧电压平均值    ";
CM_ SG_ 2337140382 M2P_Current_B12_14 "汇流排12所有电柜电流累加和";
CM_ SG_ 2337140382 M2P_PermitMaxCharge_I_B12_14 "汇流排12最大允许充电电流";
CM_ SG_ 2337140382 M2P_PermitMaxDisCharge_I_B12_14 "汇流排12最大允许放电电流";
CM_ SG_ 2337140383 M2P_Measure_Vol_B12_15 "汇流排12所有高压在线电柜外侧电压平均值    ";
CM_ SG_ 2337140383 M2P_Current_B12_15 "汇流排12所有电柜电流累加和";
CM_ SG_ 2337140383 M2P_PermitMaxCharge_I_B12_15 "汇流排12最大允许充电电流";
CM_ SG_ 2337140383 M2P_PermitMaxDisCharge_I_B12_15 "汇流排12最大允许放电电流";
CM_ SG_ 2337140384 M2P_Measure_Vol_B12_16 "汇流排12所有高压在线电柜外侧电压平均值    ";
CM_ SG_ 2337140384 M2P_Current_B12_16 "汇流排12所有电柜电流累加和";
CM_ SG_ 2337140384 M2P_PermitMaxCharge_I_B12_16 "汇流排12最大允许充电电流";
CM_ SG_ 2337140384 M2P_PermitMaxDisCharge_I_B12_16 "汇流排12最大允许放电电流";
CM_ SG_ 2337140385 M2P_Measure_Vol_B12_17 "汇流排12所有高压在线电柜外侧电压平均值    ";
CM_ SG_ 2337140385 M2P_Current_B12_17 "汇流排12所有电柜电流累加和";
CM_ SG_ 2337140385 M2P_PermitMaxCharge_I_B12_17 "汇流排12最大允许充电电流";
CM_ SG_ 2337140385 M2P_PermitMaxDisCharge_I_B12_17 "汇流排12最大允许放电电流";
CM_ SG_ 2337140386 M2P_Measure_Vol_B12_18 "汇流排12所有高压在线电柜外侧电压平均值    ";
CM_ SG_ 2337140386 M2P_Current_B12_18 "汇流排12所有电柜电流累加和";
CM_ SG_ 2337140386 M2P_PermitMaxCharge_I_B12_18 "汇流排12最大允许充电电流";
CM_ SG_ 2337140386 M2P_PermitMaxDisCharge_I_B12_18 "汇流排12最大允许放电电流";
CM_ SG_ 2337140387 M2P_Measure_Vol_B12_19 "汇流排12所有高压在线电柜外侧电压平均值    ";
CM_ SG_ 2337140387 M2P_Current_B12_19 "汇流排12所有电柜电流累加和";
CM_ SG_ 2337140387 M2P_PermitMaxCharge_I_B12_19 "汇流排12最大允许充电电流";
CM_ SG_ 2337140387 M2P_PermitMaxDisCharge_I_B12_19 "汇流排12最大允许放电电流";
CM_ SG_ 2337140388 M2P_Measure_Vol_B12_20 "汇流排12所有高压在线电柜外侧电压平均值    ";
CM_ SG_ 2337140388 M2P_Current_B12_20 "汇流排12所有电柜电流累加和";
CM_ SG_ 2337140388 M2P_PermitMaxCharge_I_B12_20 "汇流排12最大允许充电电流";
CM_ SG_ 2337140388 M2P_PermitMaxDisCharge_I_B12_20 "汇流排12最大允许放电电流";
CM_ SG_ 2337140389 M2P_Measure_Vol_B12_21 "汇流排12所有高压在线电柜外侧电压平均值    ";
CM_ SG_ 2337140389 M2P_Current_B12_21 "汇流排12所有电柜电流累加和";
CM_ SG_ 2337140389 M2P_PermitMaxCharge_I_B12_21 "汇流排12最大允许充电电流";
CM_ SG_ 2337140389 M2P_PermitMaxDisCharge_I_B12_21 "汇流排12最大允许放电电流";
CM_ SG_ 2337140390 M2P_Measure_Vol_B12_22 "汇流排12所有高压在线电柜外侧电压平均值    ";
CM_ SG_ 2337140390 M2P_Current_B12_22 "汇流排12所有电柜电流累加和";
CM_ SG_ 2337140390 M2P_PermitMaxCharge_I_B12_22 "汇流排12最大允许充电电流";
CM_ SG_ 2337140390 M2P_PermitMaxDisCharge_I_B12_22 "汇流排12最大允许放电电流";
CM_ SG_ 2337140391 M2P_Measure_Vol_B12_23 "汇流排12所有高压在线电柜外侧电压平均值    ";
CM_ SG_ 2337140391 M2P_Current_B12_23 "汇流排12所有电柜电流累加和";
CM_ SG_ 2337140391 M2P_PermitMaxCharge_I_B12_23 "汇流排12最大允许充电电流";
CM_ SG_ 2337140391 M2P_PermitMaxDisCharge_I_B12_23 "汇流排12最大允许放电电流";
CM_ SG_ 2337140392 M2P_Measure_Vol_B12_24 "汇流排12所有高压在线电柜外侧电压平均值    ";
CM_ SG_ 2337140392 M2P_Current_B12_24 "汇流排12所有电柜电流累加和";
CM_ SG_ 2337140392 M2P_PermitMaxCharge_I_B12_24 "汇流排12最大允许充电电流";
CM_ SG_ 2337140392 M2P_PermitMaxDisCharge_I_B12_24 "汇流排12最大允许放电电流";
CM_ SG_ 2337140393 M2P_Measure_Vol_B12_25 "汇流排12所有高压在线电柜外侧电压平均值    ";
CM_ SG_ 2337140393 M2P_Current_B12_25 "汇流排12所有电柜电流累加和";
CM_ SG_ 2337140393 M2P_PermitMaxCharge_I_B12_25 "汇流排12最大允许充电电流";
CM_ SG_ 2337140393 M2P_PermitMaxDisCharge_I_B12_25 "汇流排12最大允许放电电流";
CM_ SG_ 2337140394 M2P_Measure_Vol_B12_26 "汇流排12所有高压在线电柜外侧电压平均值    ";
CM_ SG_ 2337140394 M2P_Current_B12_26 "汇流排12所有电柜电流累加和";
CM_ SG_ 2337140394 M2P_PermitMaxCharge_I_B12_26 "汇流排12最大允许充电电流";
CM_ SG_ 2337140394 M2P_PermitMaxDisCharge_I_B12_26 "汇流排12最大允许放电电流";
CM_ SG_ 2337140395 M2P_Measure_Vol_B12_27 "汇流排12所有高压在线电柜外侧电压平均值    ";
CM_ SG_ 2337140395 M2P_Current_B12_27 "汇流排12所有电柜电流累加和";
CM_ SG_ 2337140395 M2P_PermitMaxCharge_I_B12_27 "汇流排12最大允许充电电流";
CM_ SG_ 2337140395 M2P_PermitMaxDisCharge_I_B12_27 "汇流排12最大允许放电电流";
CM_ SG_ 2337140396 M2P_Measure_Vol_B12_28 "汇流排12所有高压在线电柜外侧电压平均值    ";
CM_ SG_ 2337140396 M2P_Current_B12_28 "汇流排12所有电柜电流累加和";
CM_ SG_ 2337140396 M2P_PermitMaxCharge_I_B12_28 "汇流排12最大允许充电电流";
CM_ SG_ 2337140396 M2P_PermitMaxDisCharge_I_B12_28 "汇流排12最大允许放电电流";
CM_ SG_ 2337140397 M2P_Measure_Vol_B12_29 "汇流排12所有高压在线电柜外侧电压平均值    ";
CM_ SG_ 2337140397 M2P_Current_B12_29 "汇流排12所有电柜电流累加和";
CM_ SG_ 2337140397 M2P_PermitMaxCharge_I_B12_29 "汇流排12最大允许充电电流";
CM_ SG_ 2337140397 M2P_PermitMaxDisCharge_I_B12_29 "汇流排12最大允许放电电流";
CM_ SG_ 2337140398 M2P_Measure_Vol_B12_30 "汇流排12所有高压在线电柜外侧电压平均值    ";
CM_ SG_ 2337140398 M2P_Current_B12_30 "汇流排12所有电柜电流累加和";
CM_ SG_ 2337140398 M2P_PermitMaxCharge_I_B12_30 "汇流排12最大允许充电电流";
CM_ SG_ 2337140398 M2P_PermitMaxDisCharge_I_B12_30 "汇流排12最大允许放电电流";
CM_ SG_ 2337140399 M2P_Measure_Vol_B12_31 "汇流排12所有高压在线电柜外侧电压平均值    ";
CM_ SG_ 2337140399 M2P_Current_B12_31 "汇流排12所有电柜电流累加和";
CM_ SG_ 2337140399 M2P_PermitMaxCharge_I_B12_31 "汇流排12最大允许充电电流";
CM_ SG_ 2337140399 M2P_PermitMaxDisCharge_I_B12_31 "汇流排12最大允许放电电流";
CM_ SG_ 2337205905 M2P_PermitMaxVolt_B12_01 "汇流排12最高允许充电电压 （配置量）";
CM_ SG_ 2337205905 M2P_PermitMinVolt_B12_01 "汇流排12最低允许放电电压 （配置量）";
CM_ SG_ 2337205905 M2P_PermitMaxPow_Chg_B12_01 "汇流排12最大允许充电功率";
CM_ SG_ 2337205905 M2P_PermitMaxPow_DisChg_B12_01 "汇流排12最大允许放电功率";
CM_ SG_ 2337205906 M2P_PermitMaxVolt_B12_02 "汇流排12最高允许充电电压 （配置量）";
CM_ SG_ 2337205906 M2P_PermitMinVolt_B12_02 "汇流排12最低允许放电电压 （配置量）";
CM_ SG_ 2337205906 M2P_PermitMaxPow_Chg_B12_02 "汇流排12最大允许充电功率";
CM_ SG_ 2337205906 M2P_PermitMaxPow_DisChg_B12_02 "汇流排12最大允许放电功率";
CM_ SG_ 2337205907 M2P_PermitMaxVolt_B12_03 "汇流排12最高允许充电电压 （配置量）";
CM_ SG_ 2337205907 M2P_PermitMinVolt_B12_03 "汇流排12最低允许放电电压 （配置量）";
CM_ SG_ 2337205907 M2P_PermitMaxPow_Chg_B12_03 "汇流排12最大允许充电功率";
CM_ SG_ 2337205907 M2P_PermitMaxPow_DisChg_B12_03 "汇流排12最大允许放电功率";
CM_ SG_ 2337205908 M2P_PermitMaxVolt_B12_04 "汇流排12最高允许充电电压 （配置量）";
CM_ SG_ 2337205908 M2P_PermitMinVolt_B12_04 "汇流排12最低允许放电电压 （配置量）";
CM_ SG_ 2337205908 M2P_PermitMaxPow_Chg_B12_04 "汇流排12最大允许充电功率";
CM_ SG_ 2337205908 M2P_PermitMaxPow_DisChg_B12_04 "汇流排12最大允许放电功率";
CM_ SG_ 2337205909 M2P_PermitMaxVolt_B12_05 "汇流排12最高允许充电电压 （配置量）";
CM_ SG_ 2337205909 M2P_PermitMinVolt_B12_05 "汇流排12最低允许放电电压 （配置量）";
CM_ SG_ 2337205909 M2P_PermitMaxPow_Chg_B12_05 "汇流排12最大允许充电功率";
CM_ SG_ 2337205909 M2P_PermitMaxPow_DisChg_B12_05 "汇流排12最大允许放电功率";
CM_ SG_ 2337205910 M2P_PermitMaxVolt_B12_06 "汇流排12最高允许充电电压 （配置量）";
CM_ SG_ 2337205910 M2P_PermitMinVolt_B12_06 "汇流排12最低允许放电电压 （配置量）";
CM_ SG_ 2337205910 M2P_PermitMaxPow_Chg_B12_06 "汇流排12最大允许充电功率";
CM_ SG_ 2337205910 M2P_PermitMaxPow_DisChg_B12_06 "汇流排12最大允许放电功率";
CM_ SG_ 2337205911 M2P_PermitMaxVolt_B12_07 "汇流排12最高允许充电电压 （配置量）";
CM_ SG_ 2337205911 M2P_PermitMinVolt_B12_07 "汇流排12最低允许放电电压 （配置量）";
CM_ SG_ 2337205911 M2P_PermitMaxPow_Chg_B12_07 "汇流排12最大允许充电功率";
CM_ SG_ 2337205911 M2P_PermitMaxPow_DisChg_B12_07 "汇流排12最大允许放电功率";
CM_ SG_ 2337205912 M2P_PermitMaxVolt_B12_08 "汇流排12最高允许充电电压 （配置量）";
CM_ SG_ 2337205912 M2P_PermitMinVolt_B12_08 "汇流排12最低允许放电电压 （配置量）";
CM_ SG_ 2337205912 M2P_PermitMaxPow_Chg_B12_08 "汇流排12最大允许充电功率";
CM_ SG_ 2337205912 M2P_PermitMaxPow_DisChg_B12_08 "汇流排12最大允许放电功率";
CM_ SG_ 2337205913 M2P_PermitMaxVolt_B12_09 "汇流排12最高允许充电电压 （配置量）";
CM_ SG_ 2337205913 M2P_PermitMinVolt_B12_09 "汇流排12最低允许放电电压 （配置量）";
CM_ SG_ 2337205913 M2P_PermitMaxPow_Chg_B12_09 "汇流排12最大允许充电功率";
CM_ SG_ 2337205913 M2P_PermitMaxPow_DisChg_B12_09 "汇流排12最大允许放电功率";
CM_ SG_ 2337205914 M2P_PermitMaxVolt_B12_10 "汇流排12最高允许充电电压 （配置量）";
CM_ SG_ 2337205914 M2P_PermitMinVolt_B12_10 "汇流排12最低允许放电电压 （配置量）";
CM_ SG_ 2337205914 M2P_PermitMaxPow_Chg_B12_10 "汇流排12最大允许充电功率";
CM_ SG_ 2337205914 M2P_PermitMaxPow_DisChg_B12_10 "汇流排12最大允许放电功率";
CM_ SG_ 2337205915 M2P_PermitMaxVolt_B12_11 "汇流排12最高允许充电电压 （配置量）";
CM_ SG_ 2337205915 M2P_PermitMinVolt_B12_11 "汇流排12最低允许放电电压 （配置量）";
CM_ SG_ 2337205915 M2P_PermitMaxPow_Chg_B12_11 "汇流排12最大允许充电功率";
CM_ SG_ 2337205915 M2P_PermitMaxPow_DisChg_B12_11 "汇流排12最大允许放电功率";
CM_ SG_ 2337205916 M2P_PermitMaxVolt_B12_12 "汇流排12最高允许充电电压 （配置量）";
CM_ SG_ 2337205916 M2P_PermitMinVolt_B12_12 "汇流排12最低允许放电电压 （配置量）";
CM_ SG_ 2337205916 M2P_PermitMaxPow_Chg_B12_12 "汇流排12最大允许充电功率";
CM_ SG_ 2337205916 M2P_PermitMaxPow_DisChg_B12_12 "汇流排12最大允许放电功率";
CM_ SG_ 2337205917 M2P_PermitMaxVolt_B12_13 "汇流排12最高允许充电电压 （配置量）";
CM_ SG_ 2337205917 M2P_PermitMinVolt_B12_13 "汇流排12最低允许放电电压 （配置量）";
CM_ SG_ 2337205917 M2P_PermitMaxPow_Chg_B12_13 "汇流排12最大允许充电功率";
CM_ SG_ 2337205917 M2P_PermitMaxPow_DisChg_B12_13 "汇流排12最大允许放电功率";
CM_ SG_ 2337205918 M2P_PermitMaxVolt_B12_14 "汇流排12最高允许充电电压 （配置量）";
CM_ SG_ 2337205918 M2P_PermitMinVolt_B12_14 "汇流排12最低允许放电电压 （配置量）";
CM_ SG_ 2337205918 M2P_PermitMaxPow_Chg_B12_14 "汇流排12最大允许充电功率";
CM_ SG_ 2337205918 M2P_PermitMaxPow_DisChg_B12_14 "汇流排12最大允许放电功率";
CM_ SG_ 2337205919 M2P_PermitMaxVolt_B12_15 "汇流排12最高允许充电电压 （配置量）";
CM_ SG_ 2337205919 M2P_PermitMinVolt_B12_15 "汇流排12最低允许放电电压 （配置量）";
CM_ SG_ 2337205919 M2P_PermitMaxPow_Chg_B12_15 "汇流排12最大允许充电功率";
CM_ SG_ 2337205919 M2P_PermitMaxPow_DisChg_B12_15 "汇流排12最大允许放电功率";
CM_ SG_ 2337205920 M2P_PermitMaxVolt_B12_16 "汇流排12最高允许充电电压 （配置量）";
CM_ SG_ 2337205920 M2P_PermitMinVolt_B12_16 "汇流排12最低允许放电电压 （配置量）";
CM_ SG_ 2337205920 M2P_PermitMaxPow_Chg_B12_16 "汇流排12最大允许充电功率";
CM_ SG_ 2337205920 M2P_PermitMaxPow_DisChg_B12_16 "汇流排12最大允许放电功率";
CM_ SG_ 2337205921 M2P_PermitMaxVolt_B12_17 "汇流排12最高允许充电电压 （配置量）";
CM_ SG_ 2337205921 M2P_PermitMinVolt_B12_17 "汇流排12最低允许放电电压 （配置量）";
CM_ SG_ 2337205921 M2P_PermitMaxPow_Chg_B12_17 "汇流排12最大允许充电功率";
CM_ SG_ 2337205921 M2P_PermitMaxPow_DisChg_B12_17 "汇流排12最大允许放电功率";
CM_ SG_ 2337205922 M2P_PermitMaxVolt_B12_18 "汇流排12最高允许充电电压 （配置量）";
CM_ SG_ 2337205922 M2P_PermitMinVolt_B12_18 "汇流排12最低允许放电电压 （配置量）";
CM_ SG_ 2337205922 M2P_PermitMaxPow_Chg_B12_18 "汇流排12最大允许充电功率";
CM_ SG_ 2337205922 M2P_PermitMaxPow_DisChg_B12_18 "汇流排12最大允许放电功率";
CM_ SG_ 2337205923 M2P_PermitMaxVolt_B12_19 "汇流排12最高允许充电电压 （配置量）";
CM_ SG_ 2337205923 M2P_PermitMinVolt_B12_19 "汇流排12最低允许放电电压 （配置量）";
CM_ SG_ 2337205923 M2P_PermitMaxPow_Chg_B12_19 "汇流排12最大允许充电功率";
CM_ SG_ 2337205923 M2P_PermitMaxPow_DisChg_B12_19 "汇流排12最大允许放电功率";
CM_ SG_ 2337205924 M2P_PermitMaxVolt_B12_20 "汇流排12最高允许充电电压 （配置量）";
CM_ SG_ 2337205924 M2P_PermitMinVolt_B12_20 "汇流排12最低允许放电电压 （配置量）";
CM_ SG_ 2337205924 M2P_PermitMaxPow_Chg_B12_20 "汇流排12最大允许充电功率";
CM_ SG_ 2337205924 M2P_PermitMaxPow_DisChg_B12_20 "汇流排12最大允许放电功率";
CM_ SG_ 2337205925 M2P_PermitMaxVolt_B12_21 "汇流排12最高允许充电电压 （配置量）";
CM_ SG_ 2337205925 M2P_PermitMinVolt_B12_21 "汇流排12最低允许放电电压 （配置量）";
CM_ SG_ 2337205925 M2P_PermitMaxPow_Chg_B12_21 "汇流排12最大允许充电功率";
CM_ SG_ 2337205925 M2P_PermitMaxPow_DisChg_B12_21 "汇流排12最大允许放电功率";
CM_ SG_ 2337205926 M2P_PermitMaxVolt_B12_22 "汇流排12最高允许充电电压 （配置量）";
CM_ SG_ 2337205926 M2P_PermitMinVolt_B12_22 "汇流排12最低允许放电电压 （配置量）";
CM_ SG_ 2337205926 M2P_PermitMaxPow_Chg_B12_22 "汇流排12最大允许充电功率";
CM_ SG_ 2337205926 M2P_PermitMaxPow_DisChg_B12_22 "汇流排12最大允许放电功率";
CM_ SG_ 2337205927 M2P_PermitMaxVolt_B12_23 "汇流排12最高允许充电电压 （配置量）";
CM_ SG_ 2337205927 M2P_PermitMinVolt_B12_23 "汇流排12最低允许放电电压 （配置量）";
CM_ SG_ 2337205927 M2P_PermitMaxPow_Chg_B12_23 "汇流排12最大允许充电功率";
CM_ SG_ 2337205927 M2P_PermitMaxPow_DisChg_B12_23 "汇流排12最大允许放电功率";
CM_ SG_ 2337205928 M2P_PermitMaxVolt_B12_24 "汇流排12最高允许充电电压 （配置量）";
CM_ SG_ 2337205928 M2P_PermitMinVolt_B12_24 "汇流排12最低允许放电电压 （配置量）";
CM_ SG_ 2337205928 M2P_PermitMaxPow_Chg_B12_24 "汇流排12最大允许充电功率";
CM_ SG_ 2337205928 M2P_PermitMaxPow_DisChg_B12_24 "汇流排12最大允许放电功率";
CM_ SG_ 2337205929 M2P_PermitMaxVolt_B12_25 "汇流排12最高允许充电电压 （配置量）";
CM_ SG_ 2337205929 M2P_PermitMinVolt_B12_25 "汇流排12最低允许放电电压 （配置量）";
CM_ SG_ 2337205929 M2P_PermitMaxPow_Chg_B12_25 "汇流排12最大允许充电功率";
CM_ SG_ 2337205929 M2P_PermitMaxPow_DisChg_B12_25 "汇流排12最大允许放电功率";
CM_ SG_ 2337205930 M2P_PermitMaxVolt_B12_26 "汇流排12最高允许充电电压 （配置量）";
CM_ SG_ 2337205930 M2P_PermitMinVolt_B12_26 "汇流排12最低允许放电电压 （配置量）";
CM_ SG_ 2337205930 M2P_PermitMaxPow_Chg_B12_26 "汇流排12最大允许充电功率";
CM_ SG_ 2337205930 M2P_PermitMaxPow_DisChg_B12_26 "汇流排12最大允许放电功率";
CM_ SG_ 2337205931 M2P_PermitMaxVolt_B12_27 "汇流排12最高允许充电电压 （配置量）";
CM_ SG_ 2337205931 M2P_PermitMinVolt_B12_27 "汇流排12最低允许放电电压 （配置量）";
CM_ SG_ 2337205931 M2P_PermitMaxPow_Chg_B12_27 "汇流排12最大允许充电功率";
CM_ SG_ 2337205931 M2P_PermitMaxPow_DisChg_B12_27 "汇流排12最大允许放电功率";
CM_ SG_ 2337205932 M2P_PermitMaxVolt_B12_28 "汇流排12最高允许充电电压 （配置量）";
CM_ SG_ 2337205932 M2P_PermitMinVolt_B12_28 "汇流排12最低允许放电电压 （配置量）";
CM_ SG_ 2337205932 M2P_PermitMaxPow_Chg_B12_28 "汇流排12最大允许充电功率";
CM_ SG_ 2337205932 M2P_PermitMaxPow_DisChg_B12_28 "汇流排12最大允许放电功率";
CM_ SG_ 2337205933 M2P_PermitMaxVolt_B12_29 "汇流排12最高允许充电电压 （配置量）";
CM_ SG_ 2337205933 M2P_PermitMinVolt_B12_29 "汇流排12最低允许放电电压 （配置量）";
CM_ SG_ 2337205933 M2P_PermitMaxPow_Chg_B12_29 "汇流排12最大允许充电功率";
CM_ SG_ 2337205933 M2P_PermitMaxPow_DisChg_B12_29 "汇流排12最大允许放电功率";
CM_ SG_ 2337205934 M2P_PermitMaxVolt_B12_30 "汇流排12最高允许充电电压 （配置量）";
CM_ SG_ 2337205934 M2P_PermitMinVolt_B12_30 "汇流排12最低允许放电电压 （配置量）";
CM_ SG_ 2337205934 M2P_PermitMaxPow_Chg_B12_30 "汇流排12最大允许充电功率";
CM_ SG_ 2337205934 M2P_PermitMaxPow_DisChg_B12_30 "汇流排12最大允许放电功率";
CM_ SG_ 2337205935 M2P_PermitMaxVolt_B12_31 "汇流排12最高允许充电电压 （配置量）";
CM_ SG_ 2337205935 M2P_PermitMinVolt_B12_31 "汇流排12最低允许放电电压 （配置量）";
CM_ SG_ 2337205935 M2P_PermitMaxPow_Chg_B12_31 "汇流排12最大允许充电功率";
CM_ SG_ 2337205935 M2P_PermitMaxPow_DisChg_B12_31 "汇流排12最大允许放电功率";
CM_ SG_ 2337271441 M2P_Power_B12_01 "汇流排12实时功率";
CM_ SG_ 2337271441 M2P_SysremEngy_Chg_B12_01 "汇流排12充电剩余能量";
CM_ SG_ 2337271441 M2P_SysremEngy_DisChg_B12_01 "汇流排12放电剩余能量";
CM_ SG_ 2337271441 M2P_SysMaxVolt_B12_01 "汇流排12单体最大电压  ";
CM_ SG_ 2337271442 M2P_Power_B12_02 "汇流排12实时功率";
CM_ SG_ 2337271442 M2P_SysremEngy_Chg_B12_02 "汇流排12充电剩余能量";
CM_ SG_ 2337271442 M2P_SysremEngy_DisChg_B12_02 "汇流排12放电剩余能量";
CM_ SG_ 2337271442 M2P_SysMaxVolt_B12_02 "汇流排12单体最大电压  ";
CM_ SG_ 2337271443 M2P_Power_B12_03 "汇流排12实时功率";
CM_ SG_ 2337271443 M2P_SysremEngy_Chg_B12_03 "汇流排12充电剩余能量";
CM_ SG_ 2337271443 M2P_SysremEngy_DisChg_B12_03 "汇流排12放电剩余能量";
CM_ SG_ 2337271443 M2P_SysMaxVolt_B12_03 "汇流排12单体最大电压  ";
CM_ SG_ 2337271444 M2P_Power_B12_04 "汇流排12实时功率";
CM_ SG_ 2337271444 M2P_SysremEngy_Chg_B12_04 "汇流排12充电剩余能量";
CM_ SG_ 2337271444 M2P_SysremEngy_DisChg_B12_04 "汇流排12放电剩余能量";
CM_ SG_ 2337271444 M2P_SysMaxVolt_B12_04 "汇流排12单体最大电压  ";
CM_ SG_ 2337271445 M2P_Power_B12_05 "汇流排12实时功率";
CM_ SG_ 2337271445 M2P_SysremEngy_Chg_B12_05 "汇流排12充电剩余能量";
CM_ SG_ 2337271445 M2P_SysremEngy_DisChg_B12_05 "汇流排12放电剩余能量";
CM_ SG_ 2337271445 M2P_SysMaxVolt_B12_05 "汇流排12单体最大电压  ";
CM_ SG_ 2337271446 M2P_Power_B12_06 "汇流排12实时功率";
CM_ SG_ 2337271446 M2P_SysremEngy_Chg_B12_06 "汇流排12充电剩余能量";
CM_ SG_ 2337271446 M2P_SysremEngy_DisChg_B12_06 "汇流排12放电剩余能量";
CM_ SG_ 2337271446 M2P_SysMaxVolt_B12_06 "汇流排12单体最大电压  ";
CM_ SG_ 2337271447 M2P_Power_B12_07 "汇流排12实时功率";
CM_ SG_ 2337271447 M2P_SysremEngy_Chg_B12_07 "汇流排12充电剩余能量";
CM_ SG_ 2337271447 M2P_SysremEngy_DisChg_B12_07 "汇流排12放电剩余能量";
CM_ SG_ 2337271447 M2P_SysMaxVolt_B12_07 "汇流排12单体最大电压  ";
CM_ SG_ 2337271448 M2P_Power_B12_08 "汇流排12实时功率";
CM_ SG_ 2337271448 M2P_SysremEngy_Chg_B12_08 "汇流排12充电剩余能量";
CM_ SG_ 2337271448 M2P_SysremEngy_DisChg_B12_08 "汇流排12放电剩余能量";
CM_ SG_ 2337271448 M2P_SysMaxVolt_B12_08 "汇流排12单体最大电压  ";
CM_ SG_ 2337271449 M2P_Power_B12_09 "汇流排12实时功率";
CM_ SG_ 2337271449 M2P_SysremEngy_Chg_B12_09 "汇流排12充电剩余能量";
CM_ SG_ 2337271449 M2P_SysremEngy_DisChg_B12_09 "汇流排12放电剩余能量";
CM_ SG_ 2337271449 M2P_SysMaxVolt_B12_09 "汇流排12单体最大电压  ";
CM_ SG_ 2337271450 M2P_Power_B12_10 "汇流排12实时功率";
CM_ SG_ 2337271450 M2P_SysremEngy_Chg_B12_10 "汇流排12充电剩余能量";
CM_ SG_ 2337271450 M2P_SysremEngy_DisChg_B12_10 "汇流排12放电剩余能量";
CM_ SG_ 2337271450 M2P_SysMaxVolt_B12_10 "汇流排12单体最大电压  ";
CM_ SG_ 2337271451 M2P_Power_B12_11 "汇流排12实时功率";
CM_ SG_ 2337271451 M2P_SysremEngy_Chg_B12_11 "汇流排12充电剩余能量";
CM_ SG_ 2337271451 M2P_SysremEngy_DisChg_B12_11 "汇流排12放电剩余能量";
CM_ SG_ 2337271451 M2P_SysMaxVolt_B12_11 "汇流排12单体最大电压  ";
CM_ SG_ 2337271452 M2P_Power_B12_12 "汇流排12实时功率";
CM_ SG_ 2337271452 M2P_SysremEngy_Chg_B12_12 "汇流排12充电剩余能量";
CM_ SG_ 2337271452 M2P_SysremEngy_DisChg_B12_12 "汇流排12放电剩余能量";
CM_ SG_ 2337271452 M2P_SysMaxVolt_B12_12 "汇流排12单体最大电压  ";
CM_ SG_ 2337271453 M2P_Power_B12_13 "汇流排12实时功率";
CM_ SG_ 2337271453 M2P_SysremEngy_Chg_B12_13 "汇流排12充电剩余能量";
CM_ SG_ 2337271453 M2P_SysremEngy_DisChg_B12_13 "汇流排12放电剩余能量";
CM_ SG_ 2337271453 M2P_SysMaxVolt_B12_13 "汇流排12单体最大电压  ";
CM_ SG_ 2337271454 M2P_Power_B12_14 "汇流排12实时功率";
CM_ SG_ 2337271454 M2P_SysremEngy_Chg_B12_14 "汇流排12充电剩余能量";
CM_ SG_ 2337271454 M2P_SysremEngy_DisChg_B12_14 "汇流排12放电剩余能量";
CM_ SG_ 2337271454 M2P_SysMaxVolt_B12_14 "汇流排12单体最大电压  ";
CM_ SG_ 2337271455 M2P_Power_B12_15 "汇流排12实时功率";
CM_ SG_ 2337271455 M2P_SysremEngy_Chg_B12_15 "汇流排12充电剩余能量";
CM_ SG_ 2337271455 M2P_SysremEngy_DisChg_B12_15 "汇流排12放电剩余能量";
CM_ SG_ 2337271455 M2P_SysMaxVolt_B12_15 "汇流排12单体最大电压  ";
CM_ SG_ 2337271456 M2P_Power_B12_16 "汇流排12实时功率";
CM_ SG_ 2337271456 M2P_SysremEngy_Chg_B12_16 "汇流排12充电剩余能量";
CM_ SG_ 2337271456 M2P_SysremEngy_DisChg_B12_16 "汇流排12放电剩余能量";
CM_ SG_ 2337271456 M2P_SysMaxVolt_B12_16 "汇流排12单体最大电压  ";
CM_ SG_ 2337271457 M2P_Power_B12_17 "汇流排12实时功率";
CM_ SG_ 2337271457 M2P_SysremEngy_Chg_B12_17 "汇流排12充电剩余能量";
CM_ SG_ 2337271457 M2P_SysremEngy_DisChg_B12_17 "汇流排12放电剩余能量";
CM_ SG_ 2337271457 M2P_SysMaxVolt_B12_17 "汇流排12单体最大电压  ";
CM_ SG_ 2337271458 M2P_Power_B12_18 "汇流排12实时功率";
CM_ SG_ 2337271458 M2P_SysremEngy_Chg_B12_18 "汇流排12充电剩余能量";
CM_ SG_ 2337271458 M2P_SysremEngy_DisChg_B12_18 "汇流排12放电剩余能量";
CM_ SG_ 2337271458 M2P_SysMaxVolt_B12_18 "汇流排12单体最大电压  ";
CM_ SG_ 2337271459 M2P_Power_B12_19 "汇流排12实时功率";
CM_ SG_ 2337271459 M2P_SysremEngy_Chg_B12_19 "汇流排12充电剩余能量";
CM_ SG_ 2337271459 M2P_SysremEngy_DisChg_B12_19 "汇流排12放电剩余能量";
CM_ SG_ 2337271459 M2P_SysMaxVolt_B12_19 "汇流排12单体最大电压  ";
CM_ SG_ 2337271460 M2P_Power_B12_20 "汇流排12实时功率";
CM_ SG_ 2337271460 M2P_SysremEngy_Chg_B12_20 "汇流排12充电剩余能量";
CM_ SG_ 2337271460 M2P_SysremEngy_DisChg_B12_20 "汇流排12放电剩余能量";
CM_ SG_ 2337271460 M2P_SysMaxVolt_B12_20 "汇流排12单体最大电压  ";
CM_ SG_ 2337271461 M2P_Power_B12_21 "汇流排12实时功率";
CM_ SG_ 2337271461 M2P_SysremEngy_Chg_B12_21 "汇流排12充电剩余能量";
CM_ SG_ 2337271461 M2P_SysremEngy_DisChg_B12_21 "汇流排12放电剩余能量";
CM_ SG_ 2337271461 M2P_SysMaxVolt_B12_21 "汇流排12单体最大电压  ";
CM_ SG_ 2337271462 M2P_Power_B12_22 "汇流排12实时功率";
CM_ SG_ 2337271462 M2P_SysremEngy_Chg_B12_22 "汇流排12充电剩余能量";
CM_ SG_ 2337271462 M2P_SysremEngy_DisChg_B12_22 "汇流排12放电剩余能量";
CM_ SG_ 2337271462 M2P_SysMaxVolt_B12_22 "汇流排12单体最大电压  ";
CM_ SG_ 2337271463 M2P_Power_B12_23 "汇流排12实时功率";
CM_ SG_ 2337271463 M2P_SysremEngy_Chg_B12_23 "汇流排12充电剩余能量";
CM_ SG_ 2337271463 M2P_SysremEngy_DisChg_B12_23 "汇流排12放电剩余能量";
CM_ SG_ 2337271463 M2P_SysMaxVolt_B12_23 "汇流排12单体最大电压  ";
CM_ SG_ 2337271464 M2P_Power_B12_24 "汇流排12实时功率";
CM_ SG_ 2337271464 M2P_SysremEngy_Chg_B12_24 "汇流排12充电剩余能量";
CM_ SG_ 2337271464 M2P_SysremEngy_DisChg_B12_24 "汇流排12放电剩余能量";
CM_ SG_ 2337271464 M2P_SysMaxVolt_B12_24 "汇流排12单体最大电压  ";
CM_ SG_ 2337271465 M2P_Power_B12_25 "汇流排12实时功率";
CM_ SG_ 2337271465 M2P_SysremEngy_Chg_B12_25 "汇流排12充电剩余能量";
CM_ SG_ 2337271465 M2P_SysremEngy_DisChg_B12_25 "汇流排12放电剩余能量";
CM_ SG_ 2337271465 M2P_SysMaxVolt_B12_25 "汇流排12单体最大电压  ";
CM_ SG_ 2337271466 M2P_Power_B12_26 "汇流排12实时功率";
CM_ SG_ 2337271466 M2P_SysremEngy_Chg_B12_26 "汇流排12充电剩余能量";
CM_ SG_ 2337271466 M2P_SysremEngy_DisChg_B12_26 "汇流排12放电剩余能量";
CM_ SG_ 2337271466 M2P_SysMaxVolt_B12_26 "汇流排12单体最大电压  ";
CM_ SG_ 2337271467 M2P_Power_B12_27 "汇流排12实时功率";
CM_ SG_ 2337271467 M2P_SysremEngy_Chg_B12_27 "汇流排12充电剩余能量";
CM_ SG_ 2337271467 M2P_SysremEngy_DisChg_B12_27 "汇流排12放电剩余能量";
CM_ SG_ 2337271467 M2P_SysMaxVolt_B12_27 "汇流排12单体最大电压  ";
CM_ SG_ 2337271468 M2P_Power_B12_28 "汇流排12实时功率";
CM_ SG_ 2337271468 M2P_SysremEngy_Chg_B12_28 "汇流排12充电剩余能量";
CM_ SG_ 2337271468 M2P_SysremEngy_DisChg_B12_28 "汇流排12放电剩余能量";
CM_ SG_ 2337271468 M2P_SysMaxVolt_B12_28 "汇流排12单体最大电压  ";
CM_ SG_ 2337271469 M2P_Power_B12_29 "汇流排12实时功率";
CM_ SG_ 2337271469 M2P_SysremEngy_Chg_B12_29 "汇流排12充电剩余能量";
CM_ SG_ 2337271469 M2P_SysremEngy_DisChg_B12_29 "汇流排12放电剩余能量";
CM_ SG_ 2337271469 M2P_SysMaxVolt_B12_29 "汇流排12单体最大电压  ";
CM_ SG_ 2337271470 M2P_Power_B12_30 "汇流排12实时功率";
CM_ SG_ 2337271470 M2P_SysremEngy_Chg_B12_30 "汇流排12充电剩余能量";
CM_ SG_ 2337271470 M2P_SysremEngy_DisChg_B12_30 "汇流排12放电剩余能量";
CM_ SG_ 2337271470 M2P_SysMaxVolt_B12_30 "汇流排12单体最大电压  ";
CM_ SG_ 2337271471 M2P_Power_B12_31 "汇流排12实时功率";
CM_ SG_ 2337271471 M2P_SysremEngy_Chg_B12_31 "汇流排12充电剩余能量";
CM_ SG_ 2337271471 M2P_SysremEngy_DisChg_B12_31 "汇流排12放电剩余能量";
CM_ SG_ 2337271471 M2P_SysMaxVolt_B12_31 "汇流排12单体最大电压  ";
CM_ SG_ 2337336977 M2P_SysMinVolt_B12_01 "汇流排12单体最小电压";
CM_ SG_ 2337336977 M2P_SysAvgVolt_B12_01 "汇流排12单体平均电压";
CM_ SG_ 2337336977 M2P_BMS_Status_B12 "汇流排12能量状态";
CM_ SG_ 2337336977 M2P_SOC_B12 "汇流排12系统SOC";
CM_ SG_ 2337336977 M2P_SOH_B12 "汇流排12系统SOH";
CM_ SG_ 2337336977 Reserved_01 "预留";
CM_ SG_ 2337336978 M2P_SysMinVolt_B12_02 "汇流排12单体最小电压";
CM_ SG_ 2337336978 M2P_SysAvgVolt_B12_02 "汇流排12单体平均电压";
CM_ SG_ 2337336978 M2P_BMS_Status_B12 "汇流排12能量状态";
CM_ SG_ 2337336978 M2P_SOC_B12 "汇流排12系统SOC";
CM_ SG_ 2337336978 M2P_SOH_B12 "汇流排12系统SOH";
CM_ SG_ 2337336978 Reserved_02 "预留";
CM_ SG_ 2337336979 M2P_SysMinVolt_B12_03 "汇流排12单体最小电压";
CM_ SG_ 2337336979 M2P_SysAvgVolt_B12_03 "汇流排12单体平均电压";
CM_ SG_ 2337336979 M2P_BMS_Status_B12 "汇流排12能量状态";
CM_ SG_ 2337336979 M2P_SOC_B12 "汇流排12系统SOC";
CM_ SG_ 2337336979 M2P_SOH_B12 "汇流排12系统SOH";
CM_ SG_ 2337336979 Reserved_03 "预留";
CM_ SG_ 2337336980 M2P_SysMinVolt_B12_04 "汇流排12单体最小电压";
CM_ SG_ 2337336980 M2P_SysAvgVolt_B12_04 "汇流排12单体平均电压";
CM_ SG_ 2337336980 M2P_BMS_Status_B12 "汇流排12能量状态";
CM_ SG_ 2337336980 M2P_SOC_B12 "汇流排12系统SOC";
CM_ SG_ 2337336980 M2P_SOH_B12 "汇流排12系统SOH";
CM_ SG_ 2337336980 Reserved_04 "预留";
CM_ SG_ 2337336981 M2P_SysMinVolt_B12_05 "汇流排12单体最小电压";
CM_ SG_ 2337336981 M2P_SysAvgVolt_B12_05 "汇流排12单体平均电压";
CM_ SG_ 2337336981 M2P_BMS_Status_B12 "汇流排12能量状态";
CM_ SG_ 2337336981 M2P_SOC_B12 "汇流排12系统SOC";
CM_ SG_ 2337336981 M2P_SOH_B12 "汇流排12系统SOH";
CM_ SG_ 2337336981 Reserved_05 "预留";
CM_ SG_ 2337336982 M2P_SysMinVolt_B12_06 "汇流排12单体最小电压";
CM_ SG_ 2337336982 M2P_SysAvgVolt_B12_06 "汇流排12单体平均电压";
CM_ SG_ 2337336982 M2P_BMS_Status_B12 "汇流排12能量状态";
CM_ SG_ 2337336982 M2P_SOC_B12 "汇流排12系统SOC";
CM_ SG_ 2337336982 M2P_SOH_B12 "汇流排12系统SOH";
CM_ SG_ 2337336982 Reserved_06 "预留";
CM_ SG_ 2337336983 M2P_SysMinVolt_B12_07 "汇流排12单体最小电压";
CM_ SG_ 2337336983 M2P_SysAvgVolt_B12_07 "汇流排12单体平均电压";
CM_ SG_ 2337336983 M2P_BMS_Status_B12 "汇流排12能量状态";
CM_ SG_ 2337336983 M2P_SOC_B12 "汇流排12系统SOC";
CM_ SG_ 2337336983 M2P_SOH_B12 "汇流排12系统SOH";
CM_ SG_ 2337336983 Reserved_07 "预留";
CM_ SG_ 2337336984 M2P_SysMinVolt_B12_08 "汇流排12单体最小电压";
CM_ SG_ 2337336984 M2P_SysAvgVolt_B12_08 "汇流排12单体平均电压";
CM_ SG_ 2337336984 M2P_BMS_Status_B12 "汇流排12能量状态";
CM_ SG_ 2337336984 M2P_SOC_B12 "汇流排12系统SOC";
CM_ SG_ 2337336984 M2P_SOH_B12 "汇流排12系统SOH";
CM_ SG_ 2337336984 Reserved_08 "预留";
CM_ SG_ 2337336985 M2P_SysMinVolt_B12_09 "汇流排12单体最小电压";
CM_ SG_ 2337336985 M2P_SysAvgVolt_B12_09 "汇流排12单体平均电压";
CM_ SG_ 2337336985 M2P_BMS_Status_B12 "汇流排12能量状态";
CM_ SG_ 2337336985 M2P_SOC_B12 "汇流排12系统SOC";
CM_ SG_ 2337336985 M2P_SOH_B12 "汇流排12系统SOH";
CM_ SG_ 2337336985 Reserved_09 "预留";
CM_ SG_ 2337336986 M2P_SysMinVolt_B12_10 "汇流排12单体最小电压";
CM_ SG_ 2337336986 M2P_SysAvgVolt_B12_10 "汇流排12单体平均电压";
CM_ SG_ 2337336986 M2P_BMS_Status_B12 "汇流排12能量状态";
CM_ SG_ 2337336986 M2P_SOC_B12 "汇流排12系统SOC";
CM_ SG_ 2337336986 M2P_SOH_B12 "汇流排12系统SOH";
CM_ SG_ 2337336986 Reserved_10 "预留";
CM_ SG_ 2337336987 M2P_SysMinVolt_B12_11 "汇流排12单体最小电压";
CM_ SG_ 2337336987 M2P_SysAvgVolt_B12_11 "汇流排12单体平均电压";
CM_ SG_ 2337336987 M2P_BMS_Status_B12 "汇流排12能量状态";
CM_ SG_ 2337336987 M2P_SOC_B12 "汇流排12系统SOC";
CM_ SG_ 2337336987 M2P_SOH_B12 "汇流排12系统SOH";
CM_ SG_ 2337336987 Reserved_11 "预留";
CM_ SG_ 2337336988 M2P_SysMinVolt_B12_12 "汇流排12单体最小电压";
CM_ SG_ 2337336988 M2P_SysAvgVolt_B12_12 "汇流排12单体平均电压";
CM_ SG_ 2337336988 M2P_BMS_Status_B12 "汇流排12能量状态";
CM_ SG_ 2337336988 M2P_SOC_B12 "汇流排12系统SOC";
CM_ SG_ 2337336988 M2P_SOH_B12 "汇流排12系统SOH";
CM_ SG_ 2337336988 Reserved_12 "预留";
CM_ SG_ 2337336989 M2P_SysMinVolt_B12_13 "汇流排12单体最小电压";
CM_ SG_ 2337336989 M2P_SysAvgVolt_B12_13 "汇流排12单体平均电压";
CM_ SG_ 2337336989 M2P_BMS_Status_B12 "汇流排12能量状态";
CM_ SG_ 2337336989 M2P_SOC_B12 "汇流排12系统SOC";
CM_ SG_ 2337336989 M2P_SOH_B12 "汇流排12系统SOH";
CM_ SG_ 2337336989 Reserved_13 "预留";
CM_ SG_ 2337336990 M2P_SysMinVolt_B12_14 "汇流排12单体最小电压";
CM_ SG_ 2337336990 M2P_SysAvgVolt_B12_14 "汇流排12单体平均电压";
CM_ SG_ 2337336990 M2P_BMS_Status_B12 "汇流排12能量状态";
CM_ SG_ 2337336990 M2P_SOC_B12 "汇流排12系统SOC";
CM_ SG_ 2337336990 M2P_SOH_B12 "汇流排12系统SOH";
CM_ SG_ 2337336990 Reserved_14 "预留";
CM_ SG_ 2337336991 M2P_SysMinVolt_B12_15 "汇流排12单体最小电压";
CM_ SG_ 2337336991 M2P_SysAvgVolt_B12_15 "汇流排12单体平均电压";
CM_ SG_ 2337336991 M2P_BMS_Status_B12 "汇流排12能量状态";
CM_ SG_ 2337336991 M2P_SOC_B12 "汇流排12系统SOC";
CM_ SG_ 2337336991 M2P_SOH_B12 "汇流排12系统SOH";
CM_ SG_ 2337336991 Reserved_15 "预留";
CM_ SG_ 2337336992 M2P_SysMinVolt_B12_16 "汇流排12单体最小电压";
CM_ SG_ 2337336992 M2P_SysAvgVolt_B12_16 "汇流排12单体平均电压";
CM_ SG_ 2337336992 M2P_BMS_Status_B12 "汇流排12能量状态";
CM_ SG_ 2337336992 M2P_SOC_B12 "汇流排12系统SOC";
CM_ SG_ 2337336992 M2P_SOH_B12 "汇流排12系统SOH";
CM_ SG_ 2337336992 Reserved_16 "预留";
CM_ SG_ 2337336993 M2P_SysMinVolt_B12_17 "汇流排12单体最小电压";
CM_ SG_ 2337336993 M2P_SysAvgVolt_B12_17 "汇流排12单体平均电压";
CM_ SG_ 2337336993 M2P_BMS_Status_B12 "汇流排12能量状态";
CM_ SG_ 2337336993 M2P_SOC_B12 "汇流排12系统SOC";
CM_ SG_ 2337336993 M2P_SOH_B12 "汇流排12系统SOH";
CM_ SG_ 2337336993 Reserved_17 "预留";
CM_ SG_ 2337336994 M2P_SysMinVolt_B12_18 "汇流排12单体最小电压";
CM_ SG_ 2337336994 M2P_SysAvgVolt_B12_18 "汇流排12单体平均电压";
CM_ SG_ 2337336994 M2P_BMS_Status_B12 "汇流排12能量状态";
CM_ SG_ 2337336994 M2P_SOC_B12 "汇流排12系统SOC";
CM_ SG_ 2337336994 M2P_SOH_B12 "汇流排12系统SOH";
CM_ SG_ 2337336994 Reserved_18 "预留";
CM_ SG_ 2337336995 M2P_SysMinVolt_B12_19 "汇流排12单体最小电压";
CM_ SG_ 2337336995 M2P_SysAvgVolt_B12_19 "汇流排12单体平均电压";
CM_ SG_ 2337336995 M2P_BMS_Status_B12 "汇流排12能量状态";
CM_ SG_ 2337336995 M2P_SOC_B12 "汇流排12系统SOC";
CM_ SG_ 2337336995 M2P_SOH_B12 "汇流排12系统SOH";
CM_ SG_ 2337336995 Reserved_19 "预留";
CM_ SG_ 2337336996 M2P_SysMinVolt_B12_20 "汇流排12单体最小电压";
CM_ SG_ 2337336996 M2P_SysAvgVolt_B12_20 "汇流排12单体平均电压";
CM_ SG_ 2337336996 M2P_BMS_Status_B12 "汇流排12能量状态";
CM_ SG_ 2337336996 M2P_SOC_B12 "汇流排12系统SOC";
CM_ SG_ 2337336996 M2P_SOH_B12 "汇流排12系统SOH";
CM_ SG_ 2337336996 Reserved_20 "预留";
CM_ SG_ 2337336997 M2P_SysMinVolt_B12_21 "汇流排12单体最小电压";
CM_ SG_ 2337336997 M2P_SysAvgVolt_B12_21 "汇流排12单体平均电压";
CM_ SG_ 2337336997 M2P_BMS_Status_B12 "汇流排12能量状态";
CM_ SG_ 2337336997 M2P_SOC_B12 "汇流排12系统SOC";
CM_ SG_ 2337336997 M2P_SOH_B12 "汇流排12系统SOH";
CM_ SG_ 2337336997 Reserved_21 "预留";
CM_ SG_ 2337336998 M2P_SysMinVolt_B12_22 "汇流排12单体最小电压";
CM_ SG_ 2337336998 M2P_SysAvgVolt_B12_22 "汇流排12单体平均电压";
CM_ SG_ 2337336998 M2P_BMS_Status_B12 "汇流排12能量状态";
CM_ SG_ 2337336998 M2P_SOC_B12 "汇流排12系统SOC";
CM_ SG_ 2337336998 M2P_SOH_B12 "汇流排12系统SOH";
CM_ SG_ 2337336998 Reserved_22 "预留";
CM_ SG_ 2337336999 M2P_SysMinVolt_B12_23 "汇流排12单体最小电压";
CM_ SG_ 2337336999 M2P_SysAvgVolt_B12_23 "汇流排12单体平均电压";
CM_ SG_ 2337336999 M2P_BMS_Status_B12 "汇流排12能量状态";
CM_ SG_ 2337336999 M2P_SOC_B12 "汇流排12系统SOC";
CM_ SG_ 2337336999 M2P_SOH_B12 "汇流排12系统SOH";
CM_ SG_ 2337336999 Reserved_23 "预留";
CM_ SG_ 2337337000 M2P_SysMinVolt_B12_24 "汇流排12单体最小电压";
CM_ SG_ 2337337000 M2P_SysAvgVolt_B12_24 "汇流排12单体平均电压";
CM_ SG_ 2337337000 M2P_BMS_Status_B12 "汇流排12能量状态";
CM_ SG_ 2337337000 M2P_SOC_B12 "汇流排12系统SOC";
CM_ SG_ 2337337000 M2P_SOH_B12 "汇流排12系统SOH";
CM_ SG_ 2337337000 Reserved_24 "预留";
CM_ SG_ 2337337001 M2P_SysMinVolt_B12_25 "汇流排12单体最小电压";
CM_ SG_ 2337337001 M2P_SysAvgVolt_B12_25 "汇流排12单体平均电压";
CM_ SG_ 2337337001 M2P_BMS_Status_B12 "汇流排12能量状态";
CM_ SG_ 2337337001 M2P_SOC_B12 "汇流排12系统SOC";
CM_ SG_ 2337337001 M2P_SOH_B12 "汇流排12系统SOH";
CM_ SG_ 2337337001 Reserved_25 "预留";
CM_ SG_ 2337337002 M2P_SysMinVolt_B12_26 "汇流排12单体最小电压";
CM_ SG_ 2337337002 M2P_SysAvgVolt_B12_26 "汇流排12单体平均电压";
CM_ SG_ 2337337002 M2P_BMS_Status_B12 "汇流排12能量状态";
CM_ SG_ 2337337002 M2P_SOC_B12 "汇流排12系统SOC";
CM_ SG_ 2337337002 M2P_SOH_B12 "汇流排12系统SOH";
CM_ SG_ 2337337002 Reserved_26 "预留";
CM_ SG_ 2337337003 M2P_SysMinVolt_B12_27 "汇流排12单体最小电压";
CM_ SG_ 2337337003 M2P_SysAvgVolt_B12_27 "汇流排12单体平均电压";
CM_ SG_ 2337337003 M2P_BMS_Status_B12 "汇流排12能量状态";
CM_ SG_ 2337337003 M2P_SOC_B12 "汇流排12系统SOC";
CM_ SG_ 2337337003 M2P_SOH_B12 "汇流排12系统SOH";
CM_ SG_ 2337337003 Reserved_27 "预留";
CM_ SG_ 2337337004 M2P_SysMinVolt_B12_28 "汇流排12单体最小电压";
CM_ SG_ 2337337004 M2P_SysAvgVolt_B12_28 "汇流排12单体平均电压";
CM_ SG_ 2337337004 M2P_BMS_Status_B12 "汇流排12能量状态";
CM_ SG_ 2337337004 M2P_SOC_B12 "汇流排12系统SOC";
CM_ SG_ 2337337004 M2P_SOH_B12 "汇流排12系统SOH";
CM_ SG_ 2337337004 Reserved_28 "预留";
CM_ SG_ 2337337005 M2P_SysMinVolt_B12_29 "汇流排12单体最小电压";
CM_ SG_ 2337337005 M2P_SysAvgVolt_B12_29 "汇流排12单体平均电压";
CM_ SG_ 2337337005 M2P_BMS_Status_B12 "汇流排12能量状态";
CM_ SG_ 2337337005 M2P_SOC_B12 "汇流排12系统SOC";
CM_ SG_ 2337337005 M2P_SOH_B12 "汇流排12系统SOH";
CM_ SG_ 2337337005 Reserved_29 "预留";
CM_ SG_ 2337337006 M2P_SysMinVolt_B12_30 "汇流排12单体最小电压";
CM_ SG_ 2337337006 M2P_SysAvgVolt_B12_30 "汇流排12单体平均电压";
CM_ SG_ 2337337006 M2P_BMS_Status_B12 "汇流排12能量状态";
CM_ SG_ 2337337006 M2P_SOC_B12 "汇流排12系统SOC";
CM_ SG_ 2337337006 M2P_SOH_B12 "汇流排12系统SOH";
CM_ SG_ 2337337006 Reserved_30 "预留";
CM_ SG_ 2337337007 M2P_SysMinVolt_B12_31 "汇流排12单体最小电压";
CM_ SG_ 2337337007 M2P_SysAvgVolt_B12_31 "汇流排12单体平均电压";
CM_ SG_ 2337337007 M2P_BMS_Status_B12 "汇流排12能量状态";
CM_ SG_ 2337337007 M2P_SOC_B12 "汇流排12系统SOC";
CM_ SG_ 2337337007 M2P_SOH_B12 "汇流排12系统SOH";
CM_ SG_ 2337337007 Reserved_31 "预留";
CM_ SG_ 2337402513 M2P_SOE_Charge_B12 "汇流排12系可充电SOE";
CM_ SG_ 2337402513 M2P_SOE_Discharge_B12 "汇流排12系可放电SOE";
CM_ SG_ 2337402513 Reserved_01 "预留";
CM_ SG_ 2337402514 M2P_SOE_Charge_B12 "汇流排12系可充电SOE";
CM_ SG_ 2337402514 M2P_SOE_Discharge_B12 "汇流排12系可放电SOE";
CM_ SG_ 2337402514 Reserved_02 "预留";
CM_ SG_ 2337402515 M2P_SOE_Charge_B12 "汇流排12系可充电SOE";
CM_ SG_ 2337402515 M2P_SOE_Discharge_B12 "汇流排12系可放电SOE";
CM_ SG_ 2337402515 Reserved_03 "预留";
CM_ SG_ 2337402516 M2P_SOE_Charge_B12 "汇流排12系可充电SOE";
CM_ SG_ 2337402516 M2P_SOE_Discharge_B12 "汇流排12系可放电SOE";
CM_ SG_ 2337402516 Reserved_04 "预留";
CM_ SG_ 2337402517 M2P_SOE_Charge_B12 "汇流排12系可充电SOE";
CM_ SG_ 2337402517 M2P_SOE_Discharge_B12 "汇流排12系可放电SOE";
CM_ SG_ 2337402517 Reserved_05 "预留";
CM_ SG_ 2337402518 M2P_SOE_Charge_B12 "汇流排12系可充电SOE";
CM_ SG_ 2337402518 M2P_SOE_Discharge_B12 "汇流排12系可放电SOE";
CM_ SG_ 2337402518 Reserved_06 "预留";
CM_ SG_ 2337402519 M2P_SOE_Charge_B12 "汇流排12系可充电SOE";
CM_ SG_ 2337402519 M2P_SOE_Discharge_B12 "汇流排12系可放电SOE";
CM_ SG_ 2337402519 Reserved_07 "预留";
CM_ SG_ 2337402520 M2P_SOE_Charge_B12 "汇流排12系可充电SOE";
CM_ SG_ 2337402520 M2P_SOE_Discharge_B12 "汇流排12系可放电SOE";
CM_ SG_ 2337402520 Reserved_08 "预留";
CM_ SG_ 2337402521 M2P_SOE_Charge_B12 "汇流排12系可充电SOE";
CM_ SG_ 2337402521 M2P_SOE_Discharge_B12 "汇流排12系可放电SOE";
CM_ SG_ 2337402521 Reserved_09 "预留";
CM_ SG_ 2337402522 M2P_SOE_Charge_B12 "汇流排12系可充电SOE";
CM_ SG_ 2337402522 M2P_SOE_Discharge_B12 "汇流排12系可放电SOE";
CM_ SG_ 2337402522 Reserved_10 "预留";
CM_ SG_ 2337402523 M2P_SOE_Charge_B12 "汇流排12系可充电SOE";
CM_ SG_ 2337402523 M2P_SOE_Discharge_B12 "汇流排12系可放电SOE";
CM_ SG_ 2337402523 Reserved_11 "预留";
CM_ SG_ 2337402524 M2P_SOE_Charge_B12 "汇流排12系可充电SOE";
CM_ SG_ 2337402524 M2P_SOE_Discharge_B12 "汇流排12系可放电SOE";
CM_ SG_ 2337402524 Reserved_12 "预留";
CM_ SG_ 2337402525 M2P_SOE_Charge_B12 "汇流排12系可充电SOE";
CM_ SG_ 2337402525 M2P_SOE_Discharge_B12 "汇流排12系可放电SOE";
CM_ SG_ 2337402525 Reserved_13 "预留";
CM_ SG_ 2337402526 M2P_SOE_Charge_B12 "汇流排12系可充电SOE";
CM_ SG_ 2337402526 M2P_SOE_Discharge_B12 "汇流排12系可放电SOE";
CM_ SG_ 2337402526 Reserved_14 "预留";
CM_ SG_ 2337402527 M2P_SOE_Charge_B12 "汇流排12系可充电SOE";
CM_ SG_ 2337402527 M2P_SOE_Discharge_B12 "汇流排12系可放电SOE";
CM_ SG_ 2337402527 Reserved_15 "预留";
CM_ SG_ 2337402528 M2P_SOE_Charge_B12 "汇流排12系可充电SOE";
CM_ SG_ 2337402528 M2P_SOE_Discharge_B12 "汇流排12系可放电SOE";
CM_ SG_ 2337402528 Reserved_16 "预留";
CM_ SG_ 2337402529 M2P_SOE_Charge_B12 "汇流排12系可充电SOE";
CM_ SG_ 2337402529 M2P_SOE_Discharge_B12 "汇流排12系可放电SOE";
CM_ SG_ 2337402529 Reserved_17 "预留";
CM_ SG_ 2337402530 M2P_SOE_Charge_B12 "汇流排12系可充电SOE";
CM_ SG_ 2337402530 M2P_SOE_Discharge_B12 "汇流排12系可放电SOE";
CM_ SG_ 2337402530 Reserved_18 "预留";
CM_ SG_ 2337402531 M2P_SOE_Charge_B12 "汇流排12系可充电SOE";
CM_ SG_ 2337402531 M2P_SOE_Discharge_B12 "汇流排12系可放电SOE";
CM_ SG_ 2337402531 Reserved_19 "预留";
CM_ SG_ 2337402532 M2P_SOE_Charge_B12 "汇流排12系可充电SOE";
CM_ SG_ 2337402532 M2P_SOE_Discharge_B12 "汇流排12系可放电SOE";
CM_ SG_ 2337402532 Reserved_20 "预留";
CM_ SG_ 2337402533 M2P_SOE_Charge_B12 "汇流排12系可充电SOE";
CM_ SG_ 2337402533 M2P_SOE_Discharge_B12 "汇流排12系可放电SOE";
CM_ SG_ 2337402533 Reserved_21 "预留";
CM_ SG_ 2337402534 M2P_SOE_Charge_B12 "汇流排12系可充电SOE";
CM_ SG_ 2337402534 M2P_SOE_Discharge_B12 "汇流排12系可放电SOE";
CM_ SG_ 2337402534 Reserved_22 "预留";
CM_ SG_ 2337402535 M2P_SOE_Charge_B12 "汇流排12系可充电SOE";
CM_ SG_ 2337402535 M2P_SOE_Discharge_B12 "汇流排12系可放电SOE";
CM_ SG_ 2337402535 Reserved_23 "预留";
CM_ SG_ 2337402536 M2P_SOE_Charge_B12 "汇流排12系可充电SOE";
CM_ SG_ 2337402536 M2P_SOE_Discharge_B12 "汇流排12系可放电SOE";
CM_ SG_ 2337402536 Reserved_24 "预留";
CM_ SG_ 2337402537 M2P_SOE_Charge_B12 "汇流排12系可充电SOE";
CM_ SG_ 2337402537 M2P_SOE_Discharge_B12 "汇流排12系可放电SOE";
CM_ SG_ 2337402537 Reserved_25 "预留";
CM_ SG_ 2337402538 M2P_SOE_Charge_B12 "汇流排12系可充电SOE";
CM_ SG_ 2337402538 M2P_SOE_Discharge_B12 "汇流排12系可放电SOE";
CM_ SG_ 2337402538 Reserved_26 "预留";
CM_ SG_ 2337402539 M2P_SOE_Charge_B12 "汇流排12系可充电SOE";
CM_ SG_ 2337402539 M2P_SOE_Discharge_B12 "汇流排12系可放电SOE";
CM_ SG_ 2337402539 Reserved_27 "预留";
CM_ SG_ 2337402540 M2P_SOE_Charge_B12 "汇流排12系可充电SOE";
CM_ SG_ 2337402540 M2P_SOE_Discharge_B12 "汇流排12系可放电SOE";
CM_ SG_ 2337402540 Reserved_28 "预留";
CM_ SG_ 2337402541 M2P_SOE_Charge_B12 "汇流排12系可充电SOE";
CM_ SG_ 2337402541 M2P_SOE_Discharge_B12 "汇流排12系可放电SOE";
CM_ SG_ 2337402541 Reserved_29 "预留";
CM_ SG_ 2337402542 M2P_SOE_Charge_B12 "汇流排12系可充电SOE";
CM_ SG_ 2337402542 M2P_SOE_Discharge_B12 "汇流排12系可放电SOE";
CM_ SG_ 2337402542 Reserved_30 "预留";
CM_ SG_ 2337402543 M2P_SOE_Charge_B12 "汇流排12系可充电SOE";
CM_ SG_ 2337402543 M2P_SOE_Discharge_B12 "汇流排12系可放电SOE";
CM_ SG_ 2337402543 Reserved_31 "预留";
CM_ SG_ 2334326593 S2A_PCBMaxTemp_01 "最高板温";
CM_ SG_ 2334326593 S2A_PCBMinTemp_01 "最低板温";
CM_ SG_ 2334326593 S2A_ChipPst_PCBMaxTemp_01 "最高板温所在chip号";
CM_ SG_ 2334326593 S2A_ChipPst_PCBMinTemp_01 "最低板温所在chip号";
CM_ SG_ 2334326593 S2A_CscPst_PCBMaxTemp_01 "最高板温所在CSC编号";
CM_ SG_ 2334326593 S2A_CscPst_PCBMinTemp_01 "最低板温所在CSC编号";
CM_ SG_ 2334326593 S2A_AFEMaxTemp_01 "最高AFE温度(只使用104S CSC)";
CM_ SG_ 2334326593 S2A_AFEMinTemp_01 "最低AFE温度(只使用104S CSC)";
CM_ SG_ 2334326593 S2A_ChipPst_AFEMaxTemp_01 "最高AFE温度的chip编号(只使用104S CSC)";
CM_ SG_ 2334326593 S2A_ChipPst_AFEMinTemp_01 "最低AFE温度的chip编号(只使用104S CSC)";
CM_ SG_ 2334326593 S2A_CscPst_AFEMaxTemp_01 "最高AFE温度所在CSC编号(只使用104S CSC)";
CM_ SG_ 2334326593 S2A_CscPst_AFEMinTemp_01 "最低AFE温度所在CSC编号(只使用104S CSC)";
CM_ SG_ 2334326594 S2A_PCBMaxTemp_02 "最高板温";
CM_ SG_ 2334326594 S2A_PCBMinTemp_02 "最低板温";
CM_ SG_ 2334326594 S2A_ChipPst_PCBMaxTemp_02 "最高板温所在chip号";
CM_ SG_ 2334326594 S2A_ChipPst_PCBMinTemp_02 "最低板温所在chip号";
CM_ SG_ 2334326594 S2A_CscPst_PCBMaxTemp_02 "最高板温所在CSC编号";
CM_ SG_ 2334326594 S2A_CscPst_PCBMinTemp_02 "最低板温所在CSC编号";
CM_ SG_ 2334326594 S2A_AFEMaxTemp_02 "最高AFE温度(只使用104S CSC)";
CM_ SG_ 2334326594 S2A_AFEMinTemp_02 "最低AFE温度(只使用104S CSC)";
CM_ SG_ 2334326594 S2A_ChipPst_AFEMaxTemp_02 "最高AFE温度的chip编号(只使用104S CSC)";
CM_ SG_ 2334326594 S2A_ChipPst_AFEMinTemp_02 "最低AFE温度的chip编号(只使用104S CSC)";
CM_ SG_ 2334326594 S2A_CscPst_AFEMaxTemp_02 "最高AFE温度所在CSC编号(只使用104S CSC)";
CM_ SG_ 2334326594 S2A_CscPst_AFEMinTemp_02 "最低AFE温度所在CSC编号(只使用104S CSC)";
CM_ SG_ 2334326595 S2A_PCBMaxTemp_03 "最高板温";
CM_ SG_ 2334326595 S2A_PCBMinTemp_03 "最低板温";
CM_ SG_ 2334326595 S2A_ChipPst_PCBMaxTemp_03 "最高板温所在chip号";
CM_ SG_ 2334326595 S2A_ChipPst_PCBMinTemp_03 "最低板温所在chip号";
CM_ SG_ 2334326595 S2A_CscPst_PCBMaxTemp_03 "最高板温所在CSC编号";
CM_ SG_ 2334326595 S2A_CscPst_PCBMinTemp_03 "最低板温所在CSC编号";
CM_ SG_ 2334326595 S2A_AFEMaxTemp_03 "最高AFE温度(只使用104S CSC)";
CM_ SG_ 2334326595 S2A_AFEMinTemp_03 "最低AFE温度(只使用104S CSC)";
CM_ SG_ 2334326595 S2A_ChipPst_AFEMaxTemp_03 "最高AFE温度的chip编号(只使用104S CSC)";
CM_ SG_ 2334326595 S2A_ChipPst_AFEMinTemp_03 "最低AFE温度的chip编号(只使用104S CSC)";
CM_ SG_ 2334326595 S2A_CscPst_AFEMaxTemp_03 "最高AFE温度所在CSC编号(只使用104S CSC)";
CM_ SG_ 2334326595 S2A_CscPst_AFEMinTemp_03 "最低AFE温度所在CSC编号(只使用104S CSC)";
CM_ SG_ 2334326596 S2A_PCBMaxTemp_04 "最高板温";
CM_ SG_ 2334326596 S2A_PCBMinTemp_04 "最低板温";
CM_ SG_ 2334326596 S2A_ChipPst_PCBMaxTemp_04 "最高板温所在chip号";
CM_ SG_ 2334326596 S2A_ChipPst_PCBMinTemp_04 "最低板温所在chip号";
CM_ SG_ 2334326596 S2A_CscPst_PCBMaxTemp_04 "最高板温所在CSC编号";
CM_ SG_ 2334326596 S2A_CscPst_PCBMinTemp_04 "最低板温所在CSC编号";
CM_ SG_ 2334326596 S2A_AFEMaxTemp_04 "最高AFE温度(只使用104S CSC)";
CM_ SG_ 2334326596 S2A_AFEMinTemp_04 "最低AFE温度(只使用104S CSC)";
CM_ SG_ 2334326596 S2A_ChipPst_AFEMaxTemp_04 "最高AFE温度的chip编号(只使用104S CSC)";
CM_ SG_ 2334326596 S2A_ChipPst_AFEMinTemp_04 "最低AFE温度的chip编号(只使用104S CSC)";
CM_ SG_ 2334326596 S2A_CscPst_AFEMaxTemp_04 "最高AFE温度所在CSC编号(只使用104S CSC)";
CM_ SG_ 2334326596 S2A_CscPst_AFEMinTemp_04 "最低AFE温度所在CSC编号(只使用104S CSC)";
CM_ SG_ 2334326597 S2A_PCBMaxTemp_05 "最高板温";
CM_ SG_ 2334326597 S2A_PCBMinTemp_05 "最低板温";
CM_ SG_ 2334326597 S2A_ChipPst_PCBMaxTemp_05 "最高板温所在chip号";
CM_ SG_ 2334326597 S2A_ChipPst_PCBMinTemp_05 "最低板温所在chip号";
CM_ SG_ 2334326597 S2A_CscPst_PCBMaxTemp_05 "最高板温所在CSC编号";
CM_ SG_ 2334326597 S2A_CscPst_PCBMinTemp_05 "最低板温所在CSC编号";
CM_ SG_ 2334326597 S2A_AFEMaxTemp_05 "最高AFE温度(只使用104S CSC)";
CM_ SG_ 2334326597 S2A_AFEMinTemp_05 "最低AFE温度(只使用104S CSC)";
CM_ SG_ 2334326597 S2A_ChipPst_AFEMaxTemp_05 "最高AFE温度的chip编号(只使用104S CSC)";
CM_ SG_ 2334326597 S2A_ChipPst_AFEMinTemp_05 "最低AFE温度的chip编号(只使用104S CSC)";
CM_ SG_ 2334326597 S2A_CscPst_AFEMaxTemp_05 "最高AFE温度所在CSC编号(只使用104S CSC)";
CM_ SG_ 2334326597 S2A_CscPst_AFEMinTemp_05 "最低AFE温度所在CSC编号(只使用104S CSC)";
CM_ SG_ 2334326598 S2A_PCBMaxTemp_06 "最高板温";
CM_ SG_ 2334326598 S2A_PCBMinTemp_06 "最低板温";
CM_ SG_ 2334326598 S2A_ChipPst_PCBMaxTemp_06 "最高板温所在chip号";
CM_ SG_ 2334326598 S2A_ChipPst_PCBMinTemp_06 "最低板温所在chip号";
CM_ SG_ 2334326598 S2A_CscPst_PCBMaxTemp_06 "最高板温所在CSC编号";
CM_ SG_ 2334326598 S2A_CscPst_PCBMinTemp_06 "最低板温所在CSC编号";
CM_ SG_ 2334326598 S2A_AFEMaxTemp_06 "最高AFE温度(只使用104S CSC)";
CM_ SG_ 2334326598 S2A_AFEMinTemp_06 "最低AFE温度(只使用104S CSC)";
CM_ SG_ 2334326598 S2A_ChipPst_AFEMaxTemp_06 "最高AFE温度的chip编号(只使用104S CSC)";
CM_ SG_ 2334326598 S2A_ChipPst_AFEMinTemp_06 "最低AFE温度的chip编号(只使用104S CSC)";
CM_ SG_ 2334326598 S2A_CscPst_AFEMaxTemp_06 "最高AFE温度所在CSC编号(只使用104S CSC)";
CM_ SG_ 2334326598 S2A_CscPst_AFEMinTemp_06 "最低AFE温度所在CSC编号(只使用104S CSC)";
CM_ SG_ 2334326599 S2A_PCBMaxTemp_07 "最高板温";
CM_ SG_ 2334326599 S2A_PCBMinTemp_07 "最低板温";
CM_ SG_ 2334326599 S2A_ChipPst_PCBMaxTemp_07 "最高板温所在chip号";
CM_ SG_ 2334326599 S2A_ChipPst_PCBMinTemp_07 "最低板温所在chip号";
CM_ SG_ 2334326599 S2A_CscPst_PCBMaxTemp_07 "最高板温所在CSC编号";
CM_ SG_ 2334326599 S2A_CscPst_PCBMinTemp_07 "最低板温所在CSC编号";
CM_ SG_ 2334326599 S2A_AFEMaxTemp_07 "最高AFE温度(只使用104S CSC)";
CM_ SG_ 2334326599 S2A_AFEMinTemp_07 "最低AFE温度(只使用104S CSC)";
CM_ SG_ 2334326599 S2A_ChipPst_AFEMaxTemp_07 "最高AFE温度的chip编号(只使用104S CSC)";
CM_ SG_ 2334326599 S2A_ChipPst_AFEMinTemp_07 "最低AFE温度的chip编号(只使用104S CSC)";
CM_ SG_ 2334326599 S2A_CscPst_AFEMaxTemp_07 "最高AFE温度所在CSC编号(只使用104S CSC)";
CM_ SG_ 2334326599 S2A_CscPst_AFEMinTemp_07 "最低AFE温度所在CSC编号(只使用104S CSC)";
CM_ SG_ 2334326600 S2A_PCBMaxTemp_08 "最高板温";
CM_ SG_ 2334326600 S2A_PCBMinTemp_08 "最低板温";
CM_ SG_ 2334326600 S2A_ChipPst_PCBMaxTemp_08 "最高板温所在chip号";
CM_ SG_ 2334326600 S2A_ChipPst_PCBMinTemp_08 "最低板温所在chip号";
CM_ SG_ 2334326600 S2A_CscPst_PCBMaxTemp_08 "最高板温所在CSC编号";
CM_ SG_ 2334326600 S2A_CscPst_PCBMinTemp_08 "最低板温所在CSC编号";
CM_ SG_ 2334326600 S2A_AFEMaxTemp_08 "最高AFE温度(只使用104S CSC)";
CM_ SG_ 2334326600 S2A_AFEMinTemp_08 "最低AFE温度(只使用104S CSC)";
CM_ SG_ 2334326600 S2A_ChipPst_AFEMaxTemp_08 "最高AFE温度的chip编号(只使用104S CSC)";
CM_ SG_ 2334326600 S2A_ChipPst_AFEMinTemp_08 "最低AFE温度的chip编号(只使用104S CSC)";
CM_ SG_ 2334326600 S2A_CscPst_AFEMaxTemp_08 "最高AFE温度所在CSC编号(只使用104S CSC)";
CM_ SG_ 2334326600 S2A_CscPst_AFEMinTemp_08 "最低AFE温度所在CSC编号(只使用104S CSC)";
CM_ SG_ 2334326601 S2A_PCBMaxTemp_09 "最高板温";
CM_ SG_ 2334326601 S2A_PCBMinTemp_09 "最低板温";
CM_ SG_ 2334326601 S2A_ChipPst_PCBMaxTemp_09 "最高板温所在chip号";
CM_ SG_ 2334326601 S2A_ChipPst_PCBMinTemp_09 "最低板温所在chip号";
CM_ SG_ 2334326601 S2A_CscPst_PCBMaxTemp_09 "最高板温所在CSC编号";
CM_ SG_ 2334326601 S2A_CscPst_PCBMinTemp_09 "最低板温所在CSC编号";
CM_ SG_ 2334326601 S2A_AFEMaxTemp_09 "最高AFE温度(只使用104S CSC)";
CM_ SG_ 2334326601 S2A_AFEMinTemp_09 "最低AFE温度(只使用104S CSC)";
CM_ SG_ 2334326601 S2A_ChipPst_AFEMaxTemp_09 "最高AFE温度的chip编号(只使用104S CSC)";
CM_ SG_ 2334326601 S2A_ChipPst_AFEMinTemp_09 "最低AFE温度的chip编号(只使用104S CSC)";
CM_ SG_ 2334326601 S2A_CscPst_AFEMaxTemp_09 "最高AFE温度所在CSC编号(只使用104S CSC)";
CM_ SG_ 2334326601 S2A_CscPst_AFEMinTemp_09 "最低AFE温度所在CSC编号(只使用104S CSC)";
CM_ SG_ 2334326602 S2A_PCBMaxTemp_10 "最高板温";
CM_ SG_ 2334326602 S2A_PCBMinTemp_10 "最低板温";
CM_ SG_ 2334326602 S2A_ChipPst_PCBMaxTemp_10 "最高板温所在chip号";
CM_ SG_ 2334326602 S2A_ChipPst_PCBMinTemp_10 "最低板温所在chip号";
CM_ SG_ 2334326602 S2A_CscPst_PCBMaxTemp_10 "最高板温所在CSC编号";
CM_ SG_ 2334326602 S2A_CscPst_PCBMinTemp_10 "最低板温所在CSC编号";
CM_ SG_ 2334326602 S2A_AFEMaxTemp_10 "最高AFE温度(只使用104S CSC)";
CM_ SG_ 2334326602 S2A_AFEMinTemp_10 "最低AFE温度(只使用104S CSC)";
CM_ SG_ 2334326602 S2A_ChipPst_AFEMaxTemp_10 "最高AFE温度的chip编号(只使用104S CSC)";
CM_ SG_ 2334326602 S2A_ChipPst_AFEMinTemp_10 "最低AFE温度的chip编号(只使用104S CSC)";
CM_ SG_ 2334326602 S2A_CscPst_AFEMaxTemp_10 "最高AFE温度所在CSC编号(只使用104S CSC)";
CM_ SG_ 2334326602 S2A_CscPst_AFEMinTemp_10 "最低AFE温度所在CSC编号(只使用104S CSC)";
CM_ SG_ 2334326603 S2A_PCBMaxTemp_11 "最高板温";
CM_ SG_ 2334326603 S2A_PCBMinTemp_11 "最低板温";
CM_ SG_ 2334326603 S2A_ChipPst_PCBMaxTemp_11 "最高板温所在chip号";
CM_ SG_ 2334326603 S2A_ChipPst_PCBMinTemp_11 "最低板温所在chip号";
CM_ SG_ 2334326603 S2A_CscPst_PCBMaxTemp_11 "最高板温所在CSC编号";
CM_ SG_ 2334326603 S2A_CscPst_PCBMinTemp_11 "最低板温所在CSC编号";
CM_ SG_ 2334326603 S2A_AFEMaxTemp_11 "最高AFE温度(只使用104S CSC)";
CM_ SG_ 2334326603 S2A_AFEMinTemp_11 "最低AFE温度(只使用104S CSC)";
CM_ SG_ 2334326603 S2A_ChipPst_AFEMaxTemp_11 "最高AFE温度的chip编号(只使用104S CSC)";
CM_ SG_ 2334326603 S2A_ChipPst_AFEMinTemp_11 "最低AFE温度的chip编号(只使用104S CSC)";
CM_ SG_ 2334326603 S2A_CscPst_AFEMaxTemp_11 "最高AFE温度所在CSC编号(只使用104S CSC)";
CM_ SG_ 2334326603 S2A_CscPst_AFEMinTemp_11 "最低AFE温度所在CSC编号(只使用104S CSC)";
CM_ SG_ 2334326604 S2A_PCBMaxTemp_12 "最高板温";
CM_ SG_ 2334326604 S2A_PCBMinTemp_12 "最低板温";
CM_ SG_ 2334326604 S2A_ChipPst_PCBMaxTemp_12 "最高板温所在chip号";
CM_ SG_ 2334326604 S2A_ChipPst_PCBMinTemp_12 "最低板温所在chip号";
CM_ SG_ 2334326604 S2A_CscPst_PCBMaxTemp_12 "最高板温所在CSC编号";
CM_ SG_ 2334326604 S2A_CscPst_PCBMinTemp_12 "最低板温所在CSC编号";
CM_ SG_ 2334326604 S2A_AFEMaxTemp_12 "最高AFE温度(只使用104S CSC)";
CM_ SG_ 2334326604 S2A_AFEMinTemp_12 "最低AFE温度(只使用104S CSC)";
CM_ SG_ 2334326604 S2A_ChipPst_AFEMaxTemp_12 "最高AFE温度的chip编号(只使用104S CSC)";
CM_ SG_ 2334326604 S2A_ChipPst_AFEMinTemp_12 "最低AFE温度的chip编号(只使用104S CSC)";
CM_ SG_ 2334326604 S2A_CscPst_AFEMaxTemp_12 "最高AFE温度所在CSC编号(只使用104S CSC)";
CM_ SG_ 2334326604 S2A_CscPst_AFEMinTemp_12 "最低AFE温度所在CSC编号(只使用104S CSC)";
CM_ SG_ 2334326605 S2A_PCBMaxTemp_13 "最高板温";
CM_ SG_ 2334326605 S2A_PCBMinTemp_13 "最低板温";
CM_ SG_ 2334326605 S2A_ChipPst_PCBMaxTemp_13 "最高板温所在chip号";
CM_ SG_ 2334326605 S2A_ChipPst_PCBMinTemp_13 "最低板温所在chip号";
CM_ SG_ 2334326605 S2A_CscPst_PCBMaxTemp_13 "最高板温所在CSC编号";
CM_ SG_ 2334326605 S2A_CscPst_PCBMinTemp_13 "最低板温所在CSC编号";
CM_ SG_ 2334326605 S2A_AFEMaxTemp_13 "最高AFE温度(只使用104S CSC)";
CM_ SG_ 2334326605 S2A_AFEMinTemp_13 "最低AFE温度(只使用104S CSC)";
CM_ SG_ 2334326605 S2A_ChipPst_AFEMaxTemp_13 "最高AFE温度的chip编号(只使用104S CSC)";
CM_ SG_ 2334326605 S2A_ChipPst_AFEMinTemp_13 "最低AFE温度的chip编号(只使用104S CSC)";
CM_ SG_ 2334326605 S2A_CscPst_AFEMaxTemp_13 "最高AFE温度所在CSC编号(只使用104S CSC)";
CM_ SG_ 2334326605 S2A_CscPst_AFEMinTemp_13 "最低AFE温度所在CSC编号(只使用104S CSC)";
CM_ SG_ 2334326606 S2A_PCBMaxTemp_14 "最高板温";
CM_ SG_ 2334326606 S2A_PCBMinTemp_14 "最低板温";
CM_ SG_ 2334326606 S2A_ChipPst_PCBMaxTemp_14 "最高板温所在chip号";
CM_ SG_ 2334326606 S2A_ChipPst_PCBMinTemp_14 "最低板温所在chip号";
CM_ SG_ 2334326606 S2A_CscPst_PCBMaxTemp_14 "最高板温所在CSC编号";
CM_ SG_ 2334326606 S2A_CscPst_PCBMinTemp_14 "最低板温所在CSC编号";
CM_ SG_ 2334326606 S2A_AFEMaxTemp_14 "最高AFE温度(只使用104S CSC)";
CM_ SG_ 2334326606 S2A_AFEMinTemp_14 "最低AFE温度(只使用104S CSC)";
CM_ SG_ 2334326606 S2A_ChipPst_AFEMaxTemp_14 "最高AFE温度的chip编号(只使用104S CSC)";
CM_ SG_ 2334326606 S2A_ChipPst_AFEMinTemp_14 "最低AFE温度的chip编号(只使用104S CSC)";
CM_ SG_ 2334326606 S2A_CscPst_AFEMaxTemp_14 "最高AFE温度所在CSC编号(只使用104S CSC)";
CM_ SG_ 2334326606 S2A_CscPst_AFEMinTemp_14 "最低AFE温度所在CSC编号(只使用104S CSC)";
CM_ SG_ 2334326607 S2A_PCBMaxTemp_15 "最高板温";
CM_ SG_ 2334326607 S2A_PCBMinTemp_15 "最低板温";
CM_ SG_ 2334326607 S2A_ChipPst_PCBMaxTemp_15 "最高板温所在chip号";
CM_ SG_ 2334326607 S2A_ChipPst_PCBMinTemp_15 "最低板温所在chip号";
CM_ SG_ 2334326607 S2A_CscPst_PCBMaxTemp_15 "最高板温所在CSC编号";
CM_ SG_ 2334326607 S2A_CscPst_PCBMinTemp_15 "最低板温所在CSC编号";
CM_ SG_ 2334326607 S2A_AFEMaxTemp_15 "最高AFE温度(只使用104S CSC)";
CM_ SG_ 2334326607 S2A_AFEMinTemp_15 "最低AFE温度(只使用104S CSC)";
CM_ SG_ 2334326607 S2A_ChipPst_AFEMaxTemp_15 "最高AFE温度的chip编号(只使用104S CSC)";
CM_ SG_ 2334326607 S2A_ChipPst_AFEMinTemp_15 "最低AFE温度的chip编号(只使用104S CSC)";
CM_ SG_ 2334326607 S2A_CscPst_AFEMaxTemp_15 "最高AFE温度所在CSC编号(只使用104S CSC)";
CM_ SG_ 2334326607 S2A_CscPst_AFEMinTemp_15 "最低AFE温度所在CSC编号(只使用104S CSC)";
CM_ SG_ 2334326608 S2A_PCBMaxTemp_16 "最高板温";
CM_ SG_ 2334326608 S2A_PCBMinTemp_16 "最低板温";
CM_ SG_ 2334326608 S2A_ChipPst_PCBMaxTemp_16 "最高板温所在chip号";
CM_ SG_ 2334326608 S2A_ChipPst_PCBMinTemp_16 "最低板温所在chip号";
CM_ SG_ 2334326608 S2A_CscPst_PCBMaxTemp_16 "最高板温所在CSC编号";
CM_ SG_ 2334326608 S2A_CscPst_PCBMinTemp_16 "最低板温所在CSC编号";
CM_ SG_ 2334326608 S2A_AFEMaxTemp_16 "最高AFE温度(只使用104S CSC)";
CM_ SG_ 2334326608 S2A_AFEMinTemp_16 "最低AFE温度(只使用104S CSC)";
CM_ SG_ 2334326608 S2A_ChipPst_AFEMaxTemp_16 "最高AFE温度的chip编号(只使用104S CSC)";
CM_ SG_ 2334326608 S2A_ChipPst_AFEMinTemp_16 "最低AFE温度的chip编号(只使用104S CSC)";
CM_ SG_ 2334326608 S2A_CscPst_AFEMaxTemp_16 "最高AFE温度所在CSC编号(只使用104S CSC)";
CM_ SG_ 2334326608 S2A_CscPst_AFEMinTemp_16 "最低AFE温度所在CSC编号(只使用104S CSC)";
CM_ SG_ 2334326609 S2A_PCBMaxTemp_17 "最高板温";
CM_ SG_ 2334326609 S2A_PCBMinTemp_17 "最低板温";
CM_ SG_ 2334326609 S2A_ChipPst_PCBMaxTemp_17 "最高板温所在chip号";
CM_ SG_ 2334326609 S2A_ChipPst_PCBMinTemp_17 "最低板温所在chip号";
CM_ SG_ 2334326609 S2A_CscPst_PCBMaxTemp_17 "最高板温所在CSC编号";
CM_ SG_ 2334326609 S2A_CscPst_PCBMinTemp_17 "最低板温所在CSC编号";
CM_ SG_ 2334326609 S2A_AFEMaxTemp_17 "最高AFE温度(只使用104S CSC)";
CM_ SG_ 2334326609 S2A_AFEMinTemp_17 "最低AFE温度(只使用104S CSC)";
CM_ SG_ 2334326609 S2A_ChipPst_AFEMaxTemp_17 "最高AFE温度的chip编号(只使用104S CSC)";
CM_ SG_ 2334326609 S2A_ChipPst_AFEMinTemp_17 "最低AFE温度的chip编号(只使用104S CSC)";
CM_ SG_ 2334326609 S2A_CscPst_AFEMaxTemp_17 "最高AFE温度所在CSC编号(只使用104S CSC)";
CM_ SG_ 2334326609 S2A_CscPst_AFEMinTemp_17 "最低AFE温度所在CSC编号(只使用104S CSC)";
CM_ SG_ 2334326610 S2A_PCBMaxTemp_18 "最高板温";
CM_ SG_ 2334326610 S2A_PCBMinTemp_18 "最低板温";
CM_ SG_ 2334326610 S2A_ChipPst_PCBMaxTemp_18 "最高板温所在chip号";
CM_ SG_ 2334326610 S2A_ChipPst_PCBMinTemp_18 "最低板温所在chip号";
CM_ SG_ 2334326610 S2A_CscPst_PCBMaxTemp_18 "最高板温所在CSC编号";
CM_ SG_ 2334326610 S2A_CscPst_PCBMinTemp_18 "最低板温所在CSC编号";
CM_ SG_ 2334326610 S2A_AFEMaxTemp_18 "最高AFE温度(只使用104S CSC)";
CM_ SG_ 2334326610 S2A_AFEMinTemp_18 "最低AFE温度(只使用104S CSC)";
CM_ SG_ 2334326610 S2A_ChipPst_AFEMaxTemp_18 "最高AFE温度的chip编号(只使用104S CSC)";
CM_ SG_ 2334326610 S2A_ChipPst_AFEMinTemp_18 "最低AFE温度的chip编号(只使用104S CSC)";
CM_ SG_ 2334326610 S2A_CscPst_AFEMaxTemp_18 "最高AFE温度所在CSC编号(只使用104S CSC)";
CM_ SG_ 2334326610 S2A_CscPst_AFEMinTemp_18 "最低AFE温度所在CSC编号(只使用104S CSC)";
CM_ SG_ 2334326611 S2A_PCBMaxTemp_19 "最高板温";
CM_ SG_ 2334326611 S2A_PCBMinTemp_19 "最低板温";
CM_ SG_ 2334326611 S2A_ChipPst_PCBMaxTemp_19 "最高板温所在chip号";
CM_ SG_ 2334326611 S2A_ChipPst_PCBMinTemp_19 "最低板温所在chip号";
CM_ SG_ 2334326611 S2A_CscPst_PCBMaxTemp_19 "最高板温所在CSC编号";
CM_ SG_ 2334326611 S2A_CscPst_PCBMinTemp_19 "最低板温所在CSC编号";
CM_ SG_ 2334326611 S2A_AFEMaxTemp_19 "最高AFE温度(只使用104S CSC)";
CM_ SG_ 2334326611 S2A_AFEMinTemp_19 "最低AFE温度(只使用104S CSC)";
CM_ SG_ 2334326611 S2A_ChipPst_AFEMaxTemp_19 "最高AFE温度的chip编号(只使用104S CSC)";
CM_ SG_ 2334326611 S2A_ChipPst_AFEMinTemp_19 "最低AFE温度的chip编号(只使用104S CSC)";
CM_ SG_ 2334326611 S2A_CscPst_AFEMaxTemp_19 "最高AFE温度所在CSC编号(只使用104S CSC)";
CM_ SG_ 2334326611 S2A_CscPst_AFEMinTemp_19 "最低AFE温度所在CSC编号(只使用104S CSC)";
CM_ SG_ 2334326612 S2A_PCBMaxTemp_20 "最高板温";
CM_ SG_ 2334326612 S2A_PCBMinTemp_20 "最低板温";
CM_ SG_ 2334326612 S2A_ChipPst_PCBMaxTemp_20 "最高板温所在chip号";
CM_ SG_ 2334326612 S2A_ChipPst_PCBMinTemp_20 "最低板温所在chip号";
CM_ SG_ 2334326612 S2A_CscPst_PCBMaxTemp_20 "最高板温所在CSC编号";
CM_ SG_ 2334326612 S2A_CscPst_PCBMinTemp_20 "最低板温所在CSC编号";
CM_ SG_ 2334326612 S2A_AFEMaxTemp_20 "最高AFE温度(只使用104S CSC)";
CM_ SG_ 2334326612 S2A_AFEMinTemp_20 "最低AFE温度(只使用104S CSC)";
CM_ SG_ 2334326612 S2A_ChipPst_AFEMaxTemp_20 "最高AFE温度的chip编号(只使用104S CSC)";
CM_ SG_ 2334326612 S2A_ChipPst_AFEMinTemp_20 "最低AFE温度的chip编号(只使用104S CSC)";
CM_ SG_ 2334326612 S2A_CscPst_AFEMaxTemp_20 "最高AFE温度所在CSC编号(只使用104S CSC)";
CM_ SG_ 2334326612 S2A_CscPst_AFEMinTemp_20 "最低AFE温度所在CSC编号(只使用104S CSC)";
CM_ SG_ 2334326613 S2A_PCBMaxTemp_21 "最高板温";
CM_ SG_ 2334326613 S2A_PCBMinTemp_21 "最低板温";
CM_ SG_ 2334326613 S2A_ChipPst_PCBMaxTemp_21 "最高板温所在chip号";
CM_ SG_ 2334326613 S2A_ChipPst_PCBMinTemp_21 "最低板温所在chip号";
CM_ SG_ 2334326613 S2A_CscPst_PCBMaxTemp_21 "最高板温所在CSC编号";
CM_ SG_ 2334326613 S2A_CscPst_PCBMinTemp_21 "最低板温所在CSC编号";
CM_ SG_ 2334326613 S2A_AFEMaxTemp_21 "最高AFE温度(只使用104S CSC)";
CM_ SG_ 2334326613 S2A_AFEMinTemp_21 "最低AFE温度(只使用104S CSC)";
CM_ SG_ 2334326613 S2A_ChipPst_AFEMaxTemp_21 "最高AFE温度的chip编号(只使用104S CSC)";
CM_ SG_ 2334326613 S2A_ChipPst_AFEMinTemp_21 "最低AFE温度的chip编号(只使用104S CSC)";
CM_ SG_ 2334326613 S2A_CscPst_AFEMaxTemp_21 "最高AFE温度所在CSC编号(只使用104S CSC)";
CM_ SG_ 2334326613 S2A_CscPst_AFEMinTemp_21 "最低AFE温度所在CSC编号(只使用104S CSC)";
CM_ SG_ 2334326614 S2A_PCBMaxTemp_22 "最高板温";
CM_ SG_ 2334326614 S2A_PCBMinTemp_22 "最低板温";
CM_ SG_ 2334326614 S2A_ChipPst_PCBMaxTemp_22 "最高板温所在chip号";
CM_ SG_ 2334326614 S2A_ChipPst_PCBMinTemp_22 "最低板温所在chip号";
CM_ SG_ 2334326614 S2A_CscPst_PCBMaxTemp_22 "最高板温所在CSC编号";
CM_ SG_ 2334326614 S2A_CscPst_PCBMinTemp_22 "最低板温所在CSC编号";
CM_ SG_ 2334326614 S2A_AFEMaxTemp_22 "最高AFE温度(只使用104S CSC)";
CM_ SG_ 2334326614 S2A_AFEMinTemp_22 "最低AFE温度(只使用104S CSC)";
CM_ SG_ 2334326614 S2A_ChipPst_AFEMaxTemp_22 "最高AFE温度的chip编号(只使用104S CSC)";
CM_ SG_ 2334326614 S2A_ChipPst_AFEMinTemp_22 "最低AFE温度的chip编号(只使用104S CSC)";
CM_ SG_ 2334326614 S2A_CscPst_AFEMaxTemp_22 "最高AFE温度所在CSC编号(只使用104S CSC)";
CM_ SG_ 2334326614 S2A_CscPst_AFEMinTemp_22 "最低AFE温度所在CSC编号(只使用104S CSC)";
CM_ SG_ 2334326615 S2A_PCBMaxTemp_23 "最高板温";
CM_ SG_ 2334326615 S2A_PCBMinTemp_23 "最低板温";
CM_ SG_ 2334326615 S2A_ChipPst_PCBMaxTemp_23 "最高板温所在chip号";
CM_ SG_ 2334326615 S2A_ChipPst_PCBMinTemp_23 "最低板温所在chip号";
CM_ SG_ 2334326615 S2A_CscPst_PCBMaxTemp_23 "最高板温所在CSC编号";
CM_ SG_ 2334326615 S2A_CscPst_PCBMinTemp_23 "最低板温所在CSC编号";
CM_ SG_ 2334326615 S2A_AFEMaxTemp_23 "最高AFE温度(只使用104S CSC)";
CM_ SG_ 2334326615 S2A_AFEMinTemp_23 "最低AFE温度(只使用104S CSC)";
CM_ SG_ 2334326615 S2A_ChipPst_AFEMaxTemp_23 "最高AFE温度的chip编号(只使用104S CSC)";
CM_ SG_ 2334326615 S2A_ChipPst_AFEMinTemp_23 "最低AFE温度的chip编号(只使用104S CSC)";
CM_ SG_ 2334326615 S2A_CscPst_AFEMaxTemp_23 "最高AFE温度所在CSC编号(只使用104S CSC)";
CM_ SG_ 2334326615 S2A_CscPst_AFEMinTemp_23 "最低AFE温度所在CSC编号(只使用104S CSC)";
CM_ SG_ 2334326616 S2A_PCBMaxTemp_24 "最高板温";
CM_ SG_ 2334326616 S2A_PCBMinTemp_24 "最低板温";
CM_ SG_ 2334326616 S2A_ChipPst_PCBMaxTemp_24 "最高板温所在chip号";
CM_ SG_ 2334326616 S2A_ChipPst_PCBMinTemp_24 "最低板温所在chip号";
CM_ SG_ 2334326616 S2A_CscPst_PCBMaxTemp_24 "最高板温所在CSC编号";
CM_ SG_ 2334326616 S2A_CscPst_PCBMinTemp_24 "最低板温所在CSC编号";
CM_ SG_ 2334326616 S2A_AFEMaxTemp_24 "最高AFE温度(只使用104S CSC)";
CM_ SG_ 2334326616 S2A_AFEMinTemp_24 "最低AFE温度(只使用104S CSC)";
CM_ SG_ 2334326616 S2A_ChipPst_AFEMaxTemp_24 "最高AFE温度的chip编号(只使用104S CSC)";
CM_ SG_ 2334326616 S2A_ChipPst_AFEMinTemp_24 "最低AFE温度的chip编号(只使用104S CSC)";
CM_ SG_ 2334326616 S2A_CscPst_AFEMaxTemp_24 "最高AFE温度所在CSC编号(只使用104S CSC)";
CM_ SG_ 2334326616 S2A_CscPst_AFEMinTemp_24 "最低AFE温度所在CSC编号(只使用104S CSC)";
CM_ SG_ 2334326617 S2A_PCBMaxTemp_25 "最高板温";
CM_ SG_ 2334326617 S2A_PCBMinTemp_25 "最低板温";
CM_ SG_ 2334326617 S2A_ChipPst_PCBMaxTemp_25 "最高板温所在chip号";
CM_ SG_ 2334326617 S2A_ChipPst_PCBMinTemp_25 "最低板温所在chip号";
CM_ SG_ 2334326617 S2A_CscPst_PCBMaxTemp_25 "最高板温所在CSC编号";
CM_ SG_ 2334326617 S2A_CscPst_PCBMinTemp_25 "最低板温所在CSC编号";
CM_ SG_ 2334326617 S2A_AFEMaxTemp_25 "最高AFE温度(只使用104S CSC)";
CM_ SG_ 2334326617 S2A_AFEMinTemp_25 "最低AFE温度(只使用104S CSC)";
CM_ SG_ 2334326617 S2A_ChipPst_AFEMaxTemp_25 "最高AFE温度的chip编号(只使用104S CSC)";
CM_ SG_ 2334326617 S2A_ChipPst_AFEMinTemp_25 "最低AFE温度的chip编号(只使用104S CSC)";
CM_ SG_ 2334326617 S2A_CscPst_AFEMaxTemp_25 "最高AFE温度所在CSC编号(只使用104S CSC)";
CM_ SG_ 2334326617 S2A_CscPst_AFEMinTemp_25 "最低AFE温度所在CSC编号(只使用104S CSC)";
CM_ SG_ 2334326618 S2A_PCBMaxTemp_26 "最高板温";
CM_ SG_ 2334326618 S2A_PCBMinTemp_26 "最低板温";
CM_ SG_ 2334326618 S2A_ChipPst_PCBMaxTemp_26 "最高板温所在chip号";
CM_ SG_ 2334326618 S2A_ChipPst_PCBMinTemp_26 "最低板温所在chip号";
CM_ SG_ 2334326618 S2A_CscPst_PCBMaxTemp_26 "最高板温所在CSC编号";
CM_ SG_ 2334326618 S2A_CscPst_PCBMinTemp_26 "最低板温所在CSC编号";
CM_ SG_ 2334326618 S2A_AFEMaxTemp_26 "最高AFE温度(只使用104S CSC)";
CM_ SG_ 2334326618 S2A_AFEMinTemp_26 "最低AFE温度(只使用104S CSC)";
CM_ SG_ 2334326618 S2A_ChipPst_AFEMaxTemp_26 "最高AFE温度的chip编号(只使用104S CSC)";
CM_ SG_ 2334326618 S2A_ChipPst_AFEMinTemp_26 "最低AFE温度的chip编号(只使用104S CSC)";
CM_ SG_ 2334326618 S2A_CscPst_AFEMaxTemp_26 "最高AFE温度所在CSC编号(只使用104S CSC)";
CM_ SG_ 2334326618 S2A_CscPst_AFEMinTemp_26 "最低AFE温度所在CSC编号(只使用104S CSC)";
CM_ SG_ 2334326619 S2A_PCBMaxTemp_27 "最高板温";
CM_ SG_ 2334326619 S2A_PCBMinTemp_27 "最低板温";
CM_ SG_ 2334326619 S2A_ChipPst_PCBMaxTemp_27 "最高板温所在chip号";
CM_ SG_ 2334326619 S2A_ChipPst_PCBMinTemp_27 "最低板温所在chip号";
CM_ SG_ 2334326619 S2A_CscPst_PCBMaxTemp_27 "最高板温所在CSC编号";
CM_ SG_ 2334326619 S2A_CscPst_PCBMinTemp_27 "最低板温所在CSC编号";
CM_ SG_ 2334326619 S2A_AFEMaxTemp_27 "最高AFE温度(只使用104S CSC)";
CM_ SG_ 2334326619 S2A_AFEMinTemp_27 "最低AFE温度(只使用104S CSC)";
CM_ SG_ 2334326619 S2A_ChipPst_AFEMaxTemp_27 "最高AFE温度的chip编号(只使用104S CSC)";
CM_ SG_ 2334326619 S2A_ChipPst_AFEMinTemp_27 "最低AFE温度的chip编号(只使用104S CSC)";
CM_ SG_ 2334326619 S2A_CscPst_AFEMaxTemp_27 "最高AFE温度所在CSC编号(只使用104S CSC)";
CM_ SG_ 2334326619 S2A_CscPst_AFEMinTemp_27 "最低AFE温度所在CSC编号(只使用104S CSC)";
CM_ SG_ 2334326620 S2A_PCBMaxTemp_28 "最高板温";
CM_ SG_ 2334326620 S2A_PCBMinTemp_28 "最低板温";
CM_ SG_ 2334326620 S2A_ChipPst_PCBMaxTemp_28 "最高板温所在chip号";
CM_ SG_ 2334326620 S2A_ChipPst_PCBMinTemp_28 "最低板温所在chip号";
CM_ SG_ 2334326620 S2A_CscPst_PCBMaxTemp_28 "最高板温所在CSC编号";
CM_ SG_ 2334326620 S2A_CscPst_PCBMinTemp_28 "最低板温所在CSC编号";
CM_ SG_ 2334326620 S2A_AFEMaxTemp_28 "最高AFE温度(只使用104S CSC)";
CM_ SG_ 2334326620 S2A_AFEMinTemp_28 "最低AFE温度(只使用104S CSC)";
CM_ SG_ 2334326620 S2A_ChipPst_AFEMaxTemp_28 "最高AFE温度的chip编号(只使用104S CSC)";
CM_ SG_ 2334326620 S2A_ChipPst_AFEMinTemp_28 "最低AFE温度的chip编号(只使用104S CSC)";
CM_ SG_ 2334326620 S2A_CscPst_AFEMaxTemp_28 "最高AFE温度所在CSC编号(只使用104S CSC)";
CM_ SG_ 2334326620 S2A_CscPst_AFEMinTemp_28 "最低AFE温度所在CSC编号(只使用104S CSC)";
CM_ SG_ 2334326621 S2A_PCBMaxTemp_29 "最高板温";
CM_ SG_ 2334326621 S2A_PCBMinTemp_29 "最低板温";
CM_ SG_ 2334326621 S2A_ChipPst_PCBMaxTemp_29 "最高板温所在chip号";
CM_ SG_ 2334326621 S2A_ChipPst_PCBMinTemp_29 "最低板温所在chip号";
CM_ SG_ 2334326621 S2A_CscPst_PCBMaxTemp_29 "最高板温所在CSC编号";
CM_ SG_ 2334326621 S2A_CscPst_PCBMinTemp_29 "最低板温所在CSC编号";
CM_ SG_ 2334326621 S2A_AFEMaxTemp_29 "最高AFE温度(只使用104S CSC)";
CM_ SG_ 2334326621 S2A_AFEMinTemp_29 "最低AFE温度(只使用104S CSC)";
CM_ SG_ 2334326621 S2A_ChipPst_AFEMaxTemp_29 "最高AFE温度的chip编号(只使用104S CSC)";
CM_ SG_ 2334326621 S2A_ChipPst_AFEMinTemp_29 "最低AFE温度的chip编号(只使用104S CSC)";
CM_ SG_ 2334326621 S2A_CscPst_AFEMaxTemp_29 "最高AFE温度所在CSC编号(只使用104S CSC)";
CM_ SG_ 2334326621 S2A_CscPst_AFEMinTemp_29 "最低AFE温度所在CSC编号(只使用104S CSC)";
CM_ SG_ 2334326622 S2A_PCBMaxTemp_30 "最高板温";
CM_ SG_ 2334326622 S2A_PCBMinTemp_30 "最低板温";
CM_ SG_ 2334326622 S2A_ChipPst_PCBMaxTemp_30 "最高板温所在chip号";
CM_ SG_ 2334326622 S2A_ChipPst_PCBMinTemp_30 "最低板温所在chip号";
CM_ SG_ 2334326622 S2A_CscPst_PCBMaxTemp_30 "最高板温所在CSC编号";
CM_ SG_ 2334326622 S2A_CscPst_PCBMinTemp_30 "最低板温所在CSC编号";
CM_ SG_ 2334326622 S2A_AFEMaxTemp_30 "最高AFE温度(只使用104S CSC)";
CM_ SG_ 2334326622 S2A_AFEMinTemp_30 "最低AFE温度(只使用104S CSC)";
CM_ SG_ 2334326622 S2A_ChipPst_AFEMaxTemp_30 "最高AFE温度的chip编号(只使用104S CSC)";
CM_ SG_ 2334326622 S2A_ChipPst_AFEMinTemp_30 "最低AFE温度的chip编号(只使用104S CSC)";
CM_ SG_ 2334326622 S2A_CscPst_AFEMaxTemp_30 "最高AFE温度所在CSC编号(只使用104S CSC)";
CM_ SG_ 2334326622 S2A_CscPst_AFEMinTemp_30 "最低AFE温度所在CSC编号(只使用104S CSC)";
CM_ SG_ 2334326623 S2A_PCBMaxTemp_31 "最高板温";
CM_ SG_ 2334326623 S2A_PCBMinTemp_31 "最低板温";
CM_ SG_ 2334326623 S2A_ChipPst_PCBMaxTemp_31 "最高板温所在chip号";
CM_ SG_ 2334326623 S2A_ChipPst_PCBMinTemp_31 "最低板温所在chip号";
CM_ SG_ 2334326623 S2A_CscPst_PCBMaxTemp_31 "最高板温所在CSC编号";
CM_ SG_ 2334326623 S2A_CscPst_PCBMinTemp_31 "最低板温所在CSC编号";
CM_ SG_ 2334326623 S2A_AFEMaxTemp_31 "最高AFE温度(只使用104S CSC)";
CM_ SG_ 2334326623 S2A_AFEMinTemp_31 "最低AFE温度(只使用104S CSC)";
CM_ SG_ 2334326623 S2A_ChipPst_AFEMaxTemp_31 "最高AFE温度的chip编号(只使用104S CSC)";
CM_ SG_ 2334326623 S2A_ChipPst_AFEMinTemp_31 "最低AFE温度的chip编号(只使用104S CSC)";
CM_ SG_ 2334326623 S2A_CscPst_AFEMaxTemp_31 "最高AFE温度所在CSC编号(只使用104S CSC)";
CM_ SG_ 2334326623 S2A_CscPst_AFEMinTemp_31 "最低AFE温度所在CSC编号(只使用104S CSC)";
CM_ SG_ 2334326624 S2A_PCBMaxTemp_32 "最高板温";
CM_ SG_ 2334326624 S2A_PCBMinTemp_32 "最低板温";
CM_ SG_ 2334326624 S2A_ChipPst_PCBMaxTemp_32 "最高板温所在chip号";
CM_ SG_ 2334326624 S2A_ChipPst_PCBMinTemp_32 "最低板温所在chip号";
CM_ SG_ 2334326624 S2A_CscPst_PCBMaxTemp_32 "最高板温所在CSC编号";
CM_ SG_ 2334326624 S2A_CscPst_PCBMinTemp_32 "最低板温所在CSC编号";
CM_ SG_ 2334326624 S2A_AFEMaxTemp_32 "最高AFE温度(只使用104S CSC)";
CM_ SG_ 2334326624 S2A_AFEMinTemp_32 "最低AFE温度(只使用104S CSC)";
CM_ SG_ 2334326624 S2A_ChipPst_AFEMaxTemp_32 "最高AFE温度的chip编号(只使用104S CSC)";
CM_ SG_ 2334326624 S2A_ChipPst_AFEMinTemp_32 "最低AFE温度的chip编号(只使用104S CSC)";
CM_ SG_ 2334326624 S2A_CscPst_AFEMaxTemp_32 "最高AFE温度所在CSC编号(只使用104S CSC)";
CM_ SG_ 2334326624 S2A_CscPst_AFEMinTemp_32 "最低AFE温度所在CSC编号(只使用104S CSC)";
CM_ SG_ 2334326625 S2A_PCBMaxTemp_33 "最高板温";
CM_ SG_ 2334326625 S2A_PCBMinTemp_33 "最低板温";
CM_ SG_ 2334326625 S2A_ChipPst_PCBMaxTemp_33 "最高板温所在chip号";
CM_ SG_ 2334326625 S2A_ChipPst_PCBMinTemp_33 "最低板温所在chip号";
CM_ SG_ 2334326625 S2A_CscPst_PCBMaxTemp_33 "最高板温所在CSC编号";
CM_ SG_ 2334326625 S2A_CscPst_PCBMinTemp_33 "最低板温所在CSC编号";
CM_ SG_ 2334326625 S2A_AFEMaxTemp_33 "最高AFE温度(只使用104S CSC)";
CM_ SG_ 2334326625 S2A_AFEMinTemp_33 "最低AFE温度(只使用104S CSC)";
CM_ SG_ 2334326625 S2A_ChipPst_AFEMaxTemp_33 "最高AFE温度的chip编号(只使用104S CSC)";
CM_ SG_ 2334326625 S2A_ChipPst_AFEMinTemp_33 "最低AFE温度的chip编号(只使用104S CSC)";
CM_ SG_ 2334326625 S2A_CscPst_AFEMaxTemp_33 "最高AFE温度所在CSC编号(只使用104S CSC)";
CM_ SG_ 2334326625 S2A_CscPst_AFEMinTemp_33 "最低AFE温度所在CSC编号(只使用104S CSC)";
CM_ SG_ 2334326626 S2A_PCBMaxTemp_34 "最高板温";
CM_ SG_ 2334326626 S2A_PCBMinTemp_34 "最低板温";
CM_ SG_ 2334326626 S2A_ChipPst_PCBMaxTemp_34 "最高板温所在chip号";
CM_ SG_ 2334326626 S2A_ChipPst_PCBMinTemp_34 "最低板温所在chip号";
CM_ SG_ 2334326626 S2A_CscPst_PCBMaxTemp_34 "最高板温所在CSC编号";
CM_ SG_ 2334326626 S2A_CscPst_PCBMinTemp_34 "最低板温所在CSC编号";
CM_ SG_ 2334326626 S2A_AFEMaxTemp_34 "最高AFE温度(只使用104S CSC)";
CM_ SG_ 2334326626 S2A_AFEMinTemp_34 "最低AFE温度(只使用104S CSC)";
CM_ SG_ 2334326626 S2A_ChipPst_AFEMaxTemp_34 "最高AFE温度的chip编号(只使用104S CSC)";
CM_ SG_ 2334326626 S2A_ChipPst_AFEMinTemp_34 "最低AFE温度的chip编号(只使用104S CSC)";
CM_ SG_ 2334326626 S2A_CscPst_AFEMaxTemp_34 "最高AFE温度所在CSC编号(只使用104S CSC)";
CM_ SG_ 2334326626 S2A_CscPst_AFEMinTemp_34 "最低AFE温度所在CSC编号(只使用104S CSC)";
CM_ SG_ 2334326627 S2A_PCBMaxTemp_35 "最高板温";
CM_ SG_ 2334326627 S2A_PCBMinTemp_35 "最低板温";
CM_ SG_ 2334326627 S2A_ChipPst_PCBMaxTemp_35 "最高板温所在chip号";
CM_ SG_ 2334326627 S2A_ChipPst_PCBMinTemp_35 "最低板温所在chip号";
CM_ SG_ 2334326627 S2A_CscPst_PCBMaxTemp_35 "最高板温所在CSC编号";
CM_ SG_ 2334326627 S2A_CscPst_PCBMinTemp_35 "最低板温所在CSC编号";
CM_ SG_ 2334326627 S2A_AFEMaxTemp_35 "最高AFE温度(只使用104S CSC)";
CM_ SG_ 2334326627 S2A_AFEMinTemp_35 "最低AFE温度(只使用104S CSC)";
CM_ SG_ 2334326627 S2A_ChipPst_AFEMaxTemp_35 "最高AFE温度的chip编号(只使用104S CSC)";
CM_ SG_ 2334326627 S2A_ChipPst_AFEMinTemp_35 "最低AFE温度的chip编号(只使用104S CSC)";
CM_ SG_ 2334326627 S2A_CscPst_AFEMaxTemp_35 "最高AFE温度所在CSC编号(只使用104S CSC)";
CM_ SG_ 2334326627 S2A_CscPst_AFEMinTemp_35 "最低AFE温度所在CSC编号(只使用104S CSC)";
CM_ SG_ 2334326628 S2A_PCBMaxTemp_36 "最高板温";
CM_ SG_ 2334326628 S2A_PCBMinTemp_36 "最低板温";
CM_ SG_ 2334326628 S2A_ChipPst_PCBMaxTemp_36 "最高板温所在chip号";
CM_ SG_ 2334326628 S2A_ChipPst_PCBMinTemp_36 "最低板温所在chip号";
CM_ SG_ 2334326628 S2A_CscPst_PCBMaxTemp_36 "最高板温所在CSC编号";
CM_ SG_ 2334326628 S2A_CscPst_PCBMinTemp_36 "最低板温所在CSC编号";
CM_ SG_ 2334326628 S2A_AFEMaxTemp_36 "最高AFE温度(只使用104S CSC)";
CM_ SG_ 2334326628 S2A_AFEMinTemp_36 "最低AFE温度(只使用104S CSC)";
CM_ SG_ 2334326628 S2A_ChipPst_AFEMaxTemp_36 "最高AFE温度的chip编号(只使用104S CSC)";
CM_ SG_ 2334326628 S2A_ChipPst_AFEMinTemp_36 "最低AFE温度的chip编号(只使用104S CSC)";
CM_ SG_ 2334326628 S2A_CscPst_AFEMaxTemp_36 "最高AFE温度所在CSC编号(只使用104S CSC)";
CM_ SG_ 2334326628 S2A_CscPst_AFEMinTemp_36 "最低AFE温度所在CSC编号(只使用104S CSC)";
CM_ SG_ 2334326629 S2A_PCBMaxTemp_37 "最高板温";
CM_ SG_ 2334326629 S2A_PCBMinTemp_37 "最低板温";
CM_ SG_ 2334326629 S2A_ChipPst_PCBMaxTemp_37 "最高板温所在chip号";
CM_ SG_ 2334326629 S2A_ChipPst_PCBMinTemp_37 "最低板温所在chip号";
CM_ SG_ 2334326629 S2A_CscPst_PCBMaxTemp_37 "最高板温所在CSC编号";
CM_ SG_ 2334326629 S2A_CscPst_PCBMinTemp_37 "最低板温所在CSC编号";
CM_ SG_ 2334326629 S2A_AFEMaxTemp_37 "最高AFE温度(只使用104S CSC)";
CM_ SG_ 2334326629 S2A_AFEMinTemp_37 "最低AFE温度(只使用104S CSC)";
CM_ SG_ 2334326629 S2A_ChipPst_AFEMaxTemp_37 "最高AFE温度的chip编号(只使用104S CSC)";
CM_ SG_ 2334326629 S2A_ChipPst_AFEMinTemp_37 "最低AFE温度的chip编号(只使用104S CSC)";
CM_ SG_ 2334326629 S2A_CscPst_AFEMaxTemp_37 "最高AFE温度所在CSC编号(只使用104S CSC)";
CM_ SG_ 2334326629 S2A_CscPst_AFEMinTemp_37 "最低AFE温度所在CSC编号(只使用104S CSC)";
CM_ SG_ 2334326630 S2A_PCBMaxTemp_38 "最高板温";
CM_ SG_ 2334326630 S2A_PCBMinTemp_38 "最低板温";
CM_ SG_ 2334326630 S2A_ChipPst_PCBMaxTemp_38 "最高板温所在chip号";
CM_ SG_ 2334326630 S2A_ChipPst_PCBMinTemp_38 "最低板温所在chip号";
CM_ SG_ 2334326630 S2A_CscPst_PCBMaxTemp_38 "最高板温所在CSC编号";
CM_ SG_ 2334326630 S2A_CscPst_PCBMinTemp_38 "最低板温所在CSC编号";
CM_ SG_ 2334326630 S2A_AFEMaxTemp_38 "最高AFE温度(只使用104S CSC)";
CM_ SG_ 2334326630 S2A_AFEMinTemp_38 "最低AFE温度(只使用104S CSC)";
CM_ SG_ 2334326630 S2A_ChipPst_AFEMaxTemp_38 "最高AFE温度的chip编号(只使用104S CSC)";
CM_ SG_ 2334326630 S2A_ChipPst_AFEMinTemp_38 "最低AFE温度的chip编号(只使用104S CSC)";
CM_ SG_ 2334326630 S2A_CscPst_AFEMaxTemp_38 "最高AFE温度所在CSC编号(只使用104S CSC)";
CM_ SG_ 2334326630 S2A_CscPst_AFEMinTemp_38 "最低AFE温度所在CSC编号(只使用104S CSC)";
CM_ SG_ 2334326631 S2A_PCBMaxTemp_39 "最高板温";
CM_ SG_ 2334326631 S2A_PCBMinTemp_39 "最低板温";
CM_ SG_ 2334326631 S2A_ChipPst_PCBMaxTemp_39 "最高板温所在chip号";
CM_ SG_ 2334326631 S2A_ChipPst_PCBMinTemp_39 "最低板温所在chip号";
CM_ SG_ 2334326631 S2A_CscPst_PCBMaxTemp_39 "最高板温所在CSC编号";
CM_ SG_ 2334326631 S2A_CscPst_PCBMinTemp_39 "最低板温所在CSC编号";
CM_ SG_ 2334326631 S2A_AFEMaxTemp_39 "最高AFE温度(只使用104S CSC)";
CM_ SG_ 2334326631 S2A_AFEMinTemp_39 "最低AFE温度(只使用104S CSC)";
CM_ SG_ 2334326631 S2A_ChipPst_AFEMaxTemp_39 "最高AFE温度的chip编号(只使用104S CSC)";
CM_ SG_ 2334326631 S2A_ChipPst_AFEMinTemp_39 "最低AFE温度的chip编号(只使用104S CSC)";
CM_ SG_ 2334326631 S2A_CscPst_AFEMaxTemp_39 "最高AFE温度所在CSC编号(只使用104S CSC)";
CM_ SG_ 2334326631 S2A_CscPst_AFEMinTemp_39 "最低AFE温度所在CSC编号(只使用104S CSC)";
CM_ SG_ 2334326632 S2A_PCBMaxTemp_40 "最高板温";
CM_ SG_ 2334326632 S2A_PCBMinTemp_40 "最低板温";
CM_ SG_ 2334326632 S2A_ChipPst_PCBMaxTemp_40 "最高板温所在chip号";
CM_ SG_ 2334326632 S2A_ChipPst_PCBMinTemp_40 "最低板温所在chip号";
CM_ SG_ 2334326632 S2A_CscPst_PCBMaxTemp_40 "最高板温所在CSC编号";
CM_ SG_ 2334326632 S2A_CscPst_PCBMinTemp_40 "最低板温所在CSC编号";
CM_ SG_ 2334326632 S2A_AFEMaxTemp_40 "最高AFE温度(只使用104S CSC)";
CM_ SG_ 2334326632 S2A_AFEMinTemp_40 "最低AFE温度(只使用104S CSC)";
CM_ SG_ 2334326632 S2A_ChipPst_AFEMaxTemp_40 "最高AFE温度的chip编号(只使用104S CSC)";
CM_ SG_ 2334326632 S2A_ChipPst_AFEMinTemp_40 "最低AFE温度的chip编号(只使用104S CSC)";
CM_ SG_ 2334326632 S2A_CscPst_AFEMaxTemp_40 "最高AFE温度所在CSC编号(只使用104S CSC)";
CM_ SG_ 2334326632 S2A_CscPst_AFEMinTemp_40 "最低AFE温度所在CSC编号(只使用104S CSC)";
CM_ SG_ 2334326633 S2A_PCBMaxTemp_41 "最高板温";
CM_ SG_ 2334326633 S2A_PCBMinTemp_41 "最低板温";
CM_ SG_ 2334326633 S2A_ChipPst_PCBMaxTemp_41 "最高板温所在chip号";
CM_ SG_ 2334326633 S2A_ChipPst_PCBMinTemp_41 "最低板温所在chip号";
CM_ SG_ 2334326633 S2A_CscPst_PCBMaxTemp_41 "最高板温所在CSC编号";
CM_ SG_ 2334326633 S2A_CscPst_PCBMinTemp_41 "最低板温所在CSC编号";
CM_ SG_ 2334326633 S2A_AFEMaxTemp_41 "最高AFE温度(只使用104S CSC)";
CM_ SG_ 2334326633 S2A_AFEMinTemp_41 "最低AFE温度(只使用104S CSC)";
CM_ SG_ 2334326633 S2A_ChipPst_AFEMaxTemp_41 "最高AFE温度的chip编号(只使用104S CSC)";
CM_ SG_ 2334326633 S2A_ChipPst_AFEMinTemp_41 "最低AFE温度的chip编号(只使用104S CSC)";
CM_ SG_ 2334326633 S2A_CscPst_AFEMaxTemp_41 "最高AFE温度所在CSC编号(只使用104S CSC)";
CM_ SG_ 2334326633 S2A_CscPst_AFEMinTemp_41 "最低AFE温度所在CSC编号(只使用104S CSC)";
CM_ SG_ 2334326634 S2A_PCBMaxTemp_42 "最高板温";
CM_ SG_ 2334326634 S2A_PCBMinTemp_42 "最低板温";
CM_ SG_ 2334326634 S2A_ChipPst_PCBMaxTemp_42 "最高板温所在chip号";
CM_ SG_ 2334326634 S2A_ChipPst_PCBMinTemp_42 "最低板温所在chip号";
CM_ SG_ 2334326634 S2A_CscPst_PCBMaxTemp_42 "最高板温所在CSC编号";
CM_ SG_ 2334326634 S2A_CscPst_PCBMinTemp_42 "最低板温所在CSC编号";
CM_ SG_ 2334326634 S2A_AFEMaxTemp_42 "最高AFE温度(只使用104S CSC)";
CM_ SG_ 2334326634 S2A_AFEMinTemp_42 "最低AFE温度(只使用104S CSC)";
CM_ SG_ 2334326634 S2A_ChipPst_AFEMaxTemp_42 "最高AFE温度的chip编号(只使用104S CSC)";
CM_ SG_ 2334326634 S2A_ChipPst_AFEMinTemp_42 "最低AFE温度的chip编号(只使用104S CSC)";
CM_ SG_ 2334326634 S2A_CscPst_AFEMaxTemp_42 "最高AFE温度所在CSC编号(只使用104S CSC)";
CM_ SG_ 2334326634 S2A_CscPst_AFEMinTemp_42 "最低AFE温度所在CSC编号(只使用104S CSC)";
CM_ SG_ 2334326635 S2A_PCBMaxTemp_43 "最高板温";
CM_ SG_ 2334326635 S2A_PCBMinTemp_43 "最低板温";
CM_ SG_ 2334326635 S2A_ChipPst_PCBMaxTemp_43 "最高板温所在chip号";
CM_ SG_ 2334326635 S2A_ChipPst_PCBMinTemp_43 "最低板温所在chip号";
CM_ SG_ 2334326635 S2A_CscPst_PCBMaxTemp_43 "最高板温所在CSC编号";
CM_ SG_ 2334326635 S2A_CscPst_PCBMinTemp_43 "最低板温所在CSC编号";
CM_ SG_ 2334326635 S2A_AFEMaxTemp_43 "最高AFE温度(只使用104S CSC)";
CM_ SG_ 2334326635 S2A_AFEMinTemp_43 "最低AFE温度(只使用104S CSC)";
CM_ SG_ 2334326635 S2A_ChipPst_AFEMaxTemp_43 "最高AFE温度的chip编号(只使用104S CSC)";
CM_ SG_ 2334326635 S2A_ChipPst_AFEMinTemp_43 "最低AFE温度的chip编号(只使用104S CSC)";
CM_ SG_ 2334326635 S2A_CscPst_AFEMaxTemp_43 "最高AFE温度所在CSC编号(只使用104S CSC)";
CM_ SG_ 2334326635 S2A_CscPst_AFEMinTemp_43 "最低AFE温度所在CSC编号(只使用104S CSC)";
VAL_ 2337074834 M2P_SOE_Charge_B11 1023 "Null" ;
VAL_ 2337074834 M2P_SOE_Discharge_B11 1023 "Null" ;
VAL_ 2337074835 M2P_SOE_Charge_B11 1023 "Null" ;
VAL_ 2337074835 M2P_SOE_Discharge_B11 1023 "Null" ;
VAL_ 2337074836 M2P_SOE_Charge_B11 1023 "Null" ;
VAL_ 2337074836 M2P_SOE_Discharge_B11 1023 "Null" ;
VAL_ 2337074837 M2P_SOE_Charge_B11 1023 "Null" ;
VAL_ 2337074837 M2P_SOE_Discharge_B11 1023 "Null" ;
VAL_ 2337074838 M2P_SOE_Charge_B11 1023 "Null" ;
VAL_ 2337074838 M2P_SOE_Discharge_B11 1023 "Null" ;
VAL_ 2337074839 M2P_SOE_Charge_B11 1023 "Null" ;
VAL_ 2337074839 M2P_SOE_Discharge_B11 1023 "Null" ;
VAL_ 2337074840 M2P_SOE_Charge_B11 1023 "Null" ;
VAL_ 2337074840 M2P_SOE_Discharge_B11 1023 "Null" ;
VAL_ 2337074841 M2P_SOE_Charge_B11 1023 "Null" ;
VAL_ 2337074841 M2P_SOE_Discharge_B11 1023 "Null" ;
VAL_ 2337074842 M2P_SOE_Charge_B11 1023 "Null" ;
VAL_ 2337074842 M2P_SOE_Discharge_B11 1023 "Null" ;
VAL_ 2337074843 M2P_SOE_Charge_B11 1023 "Null" ;
VAL_ 2337074843 M2P_SOE_Discharge_B11 1023 "Null" ;
VAL_ 2337074844 M2P_SOE_Charge_B11 1023 "Null" ;
VAL_ 2337074844 M2P_SOE_Discharge_B11 1023 "Null" ;
VAL_ 2337074845 M2P_SOE_Charge_B11 1023 "Null" ;
VAL_ 2337074845 M2P_SOE_Discharge_B11 1023 "Null" ;
VAL_ 2337074846 M2P_SOE_Charge_B11 1023 "Null" ;
VAL_ 2337074846 M2P_SOE_Discharge_B11 1023 "Null" ;
VAL_ 2337074847 M2P_SOE_Charge_B11 1023 "Null" ;
VAL_ 2337074847 M2P_SOE_Discharge_B11 1023 "Null" ;
VAL_ 2337074848 M2P_SOE_Charge_B11 1023 "Null" ;
VAL_ 2337074848 M2P_SOE_Discharge_B11 1023 "Null" ;
VAL_ 2337074849 M2P_SOE_Charge_B11 1023 "Null" ;
VAL_ 2337074849 M2P_SOE_Discharge_B11 1023 "Null" ;
VAL_ 2337074850 M2P_SOE_Charge_B11 1023 "Null" ;
VAL_ 2337074850 M2P_SOE_Discharge_B11 1023 "Null" ;
VAL_ 2337074851 M2P_SOE_Charge_B11 1023 "Null" ;
VAL_ 2337074851 M2P_SOE_Discharge_B11 1023 "Null" ;
VAL_ 2337074852 M2P_SOE_Charge_B11 1023 "Null" ;
VAL_ 2337074852 M2P_SOE_Discharge_B11 1023 "Null" ;
VAL_ 2337074853 M2P_SOE_Charge_B11 1023 "Null" ;
VAL_ 2337074853 M2P_SOE_Discharge_B11 1023 "Null" ;
VAL_ 2337074854 M2P_SOE_Charge_B11 1023 "Null" ;
VAL_ 2337074854 M2P_SOE_Discharge_B11 1023 "Null" ;
VAL_ 2337074855 M2P_SOE_Charge_B11 1023 "Null" ;
VAL_ 2337074855 M2P_SOE_Discharge_B11 1023 "Null" ;
VAL_ 2337074856 M2P_SOE_Charge_B11 1023 "Null" ;
VAL_ 2337074856 M2P_SOE_Discharge_B11 1023 "Null" ;
VAL_ 2337074857 M2P_SOE_Charge_B11 1023 "Null" ;
VAL_ 2337074857 M2P_SOE_Discharge_B11 1023 "Null" ;
VAL_ 2337074858 M2P_SOE_Charge_B11 1023 "Null" ;
VAL_ 2337074858 M2P_SOE_Discharge_B11 1023 "Null" ;
VAL_ 2337074859 M2P_SOE_Charge_B11 1023 "Null" ;
VAL_ 2337074859 M2P_SOE_Discharge_B11 1023 "Null" ;
VAL_ 2337074860 M2P_SOE_Charge_B11 1023 "Null" ;
VAL_ 2337074860 M2P_SOE_Discharge_B11 1023 "Null" ;
VAL_ 2337074861 M2P_SOE_Charge_B11 1023 "Null" ;
VAL_ 2337074861 M2P_SOE_Discharge_B11 1023 "Null" ;
VAL_ 2337074862 M2P_SOE_Charge_B11 1023 "Null" ;
VAL_ 2337074862 M2P_SOE_Discharge_B11 1023 "Null" ;
VAL_ 2337074863 M2P_SOE_Charge_B11 1023 "Null" ;
VAL_ 2337074863 M2P_SOE_Discharge_B11 1023 "Null" ;
VAL_ 2337140369 M2P_Measure_Vol_B12_01 65535 "Invalid" ;
VAL_ 2337140369 M2P_Current_B12_01 65535 "Invalid" ;
VAL_ 2337140369 M2P_PermitMaxCharge_I_B12_01 65535 "Invalid" ;
VAL_ 2337140369 M2P_PermitMaxDisCharge_I_B12_01 65535 "Invalid" ;
VAL_ 2337140370 M2P_Measure_Vol_B12_02 65535 "Invalid" ;
VAL_ 2337140370 M2P_Current_B12_02 65535 "Invalid" ;
VAL_ 2337140370 M2P_PermitMaxCharge_I_B12_02 65535 "Invalid" ;
VAL_ 2337140370 M2P_PermitMaxDisCharge_I_B12_02 65535 "Invalid" ;
VAL_ 2337140371 M2P_Measure_Vol_B12_03 65535 "Invalid" ;
VAL_ 2337140371 M2P_Current_B12_03 65535 "Invalid" ;
VAL_ 2337140371 M2P_PermitMaxCharge_I_B12_03 65535 "Invalid" ;
VAL_ 2337140371 M2P_PermitMaxDisCharge_I_B12_03 65535 "Invalid" ;
VAL_ 2337140372 M2P_Measure_Vol_B12_04 65535 "Invalid" ;
VAL_ 2337140372 M2P_Current_B12_04 65535 "Invalid" ;
VAL_ 2337140372 M2P_PermitMaxCharge_I_B12_04 65535 "Invalid" ;
VAL_ 2337140372 M2P_PermitMaxDisCharge_I_B12_04 65535 "Invalid" ;
VAL_ 2337140373 M2P_Measure_Vol_B12_05 65535 "Invalid" ;
VAL_ 2337140373 M2P_Current_B12_05 65535 "Invalid" ;
VAL_ 2337140373 M2P_PermitMaxCharge_I_B12_05 65535 "Invalid" ;
VAL_ 2337140373 M2P_PermitMaxDisCharge_I_B12_05 65535 "Invalid" ;
VAL_ 2337140374 M2P_Measure_Vol_B12_06 65535 "Invalid" ;
VAL_ 2337140374 M2P_Current_B12_06 65535 "Invalid" ;
VAL_ 2337140374 M2P_PermitMaxCharge_I_B12_06 65535 "Invalid" ;
VAL_ 2337140374 M2P_PermitMaxDisCharge_I_B12_06 65535 "Invalid" ;
VAL_ 2337140375 M2P_Measure_Vol_B12_07 65535 "Invalid" ;
VAL_ 2337140375 M2P_Current_B12_07 65535 "Invalid" ;
VAL_ 2337140375 M2P_PermitMaxCharge_I_B12_07 65535 "Invalid" ;
VAL_ 2337140375 M2P_PermitMaxDisCharge_I_B12_07 65535 "Invalid" ;
VAL_ 2337140376 M2P_Measure_Vol_B12_08 65535 "Invalid" ;
VAL_ 2337140376 M2P_Current_B12_08 65535 "Invalid" ;
VAL_ 2337140376 M2P_PermitMaxCharge_I_B12_08 65535 "Invalid" ;
VAL_ 2337140376 M2P_PermitMaxDisCharge_I_B12_08 65535 "Invalid" ;
VAL_ 2337140377 M2P_Measure_Vol_B12_09 65535 "Invalid" ;
VAL_ 2337140377 M2P_Current_B12_09 65535 "Invalid" ;
VAL_ 2337140377 M2P_PermitMaxCharge_I_B12_09 65535 "Invalid" ;
VAL_ 2337140377 M2P_PermitMaxDisCharge_I_B12_09 65535 "Invalid" ;
VAL_ 2337140378 M2P_Measure_Vol_B12_10 65535 "Invalid" ;
VAL_ 2337140378 M2P_Current_B12_10 65535 "Invalid" ;
VAL_ 2337140378 M2P_PermitMaxCharge_I_B12_10 65535 "Invalid" ;
VAL_ 2337140378 M2P_PermitMaxDisCharge_I_B12_10 65535 "Invalid" ;
VAL_ 2337140379 M2P_Measure_Vol_B12_11 65535 "Invalid" ;
VAL_ 2337140379 M2P_Current_B12_11 65535 "Invalid" ;
VAL_ 2337140379 M2P_PermitMaxCharge_I_B12_11 65535 "Invalid" ;
VAL_ 2337140379 M2P_PermitMaxDisCharge_I_B12_11 65535 "Invalid" ;
VAL_ 2337140380 M2P_Measure_Vol_B12_12 65535 "Invalid" ;
VAL_ 2337140380 M2P_Current_B12_12 65535 "Invalid" ;
VAL_ 2337140380 M2P_PermitMaxCharge_I_B12_12 65535 "Invalid" ;
VAL_ 2337140380 M2P_PermitMaxDisCharge_I_B12_12 65535 "Invalid" ;
VAL_ 2337140381 M2P_Measure_Vol_B12_13 65535 "Invalid" ;
VAL_ 2337140381 M2P_Current_B12_13 65535 "Invalid" ;
VAL_ 2337140381 M2P_PermitMaxCharge_I_B12_13 65535 "Invalid" ;
VAL_ 2337140381 M2P_PermitMaxDisCharge_I_B12_13 65535 "Invalid" ;
VAL_ 2337140382 M2P_Measure_Vol_B12_14 65535 "Invalid" ;
VAL_ 2337140382 M2P_Current_B12_14 65535 "Invalid" ;
VAL_ 2337140382 M2P_PermitMaxCharge_I_B12_14 65535 "Invalid" ;
VAL_ 2337140382 M2P_PermitMaxDisCharge_I_B12_14 65535 "Invalid" ;
VAL_ 2337140383 M2P_Measure_Vol_B12_15 65535 "Invalid" ;
VAL_ 2337140383 M2P_Current_B12_15 65535 "Invalid" ;
VAL_ 2337140383 M2P_PermitMaxCharge_I_B12_15 65535 "Invalid" ;
VAL_ 2337140383 M2P_PermitMaxDisCharge_I_B12_15 65535 "Invalid" ;
VAL_ 2337140384 M2P_Measure_Vol_B12_16 65535 "Invalid" ;
VAL_ 2337140384 M2P_Current_B12_16 65535 "Invalid" ;
VAL_ 2337140384 M2P_PermitMaxCharge_I_B12_16 65535 "Invalid" ;
VAL_ 2337140384 M2P_PermitMaxDisCharge_I_B12_16 65535 "Invalid" ;
VAL_ 2337140385 M2P_Measure_Vol_B12_17 65535 "Invalid" ;
VAL_ 2337140385 M2P_Current_B12_17 65535 "Invalid" ;
VAL_ 2337140385 M2P_PermitMaxCharge_I_B12_17 65535 "Invalid" ;
VAL_ 2337140385 M2P_PermitMaxDisCharge_I_B12_17 65535 "Invalid" ;
VAL_ 2337140386 M2P_Measure_Vol_B12_18 65535 "Invalid" ;
VAL_ 2337140386 M2P_Current_B12_18 65535 "Invalid" ;
VAL_ 2337140386 M2P_PermitMaxCharge_I_B12_18 65535 "Invalid" ;
VAL_ 2337140386 M2P_PermitMaxDisCharge_I_B12_18 65535 "Invalid" ;
VAL_ 2337140387 M2P_Measure_Vol_B12_19 65535 "Invalid" ;
VAL_ 2337140387 M2P_Current_B12_19 65535 "Invalid" ;
VAL_ 2337140387 M2P_PermitMaxCharge_I_B12_19 65535 "Invalid" ;
VAL_ 2337140387 M2P_PermitMaxDisCharge_I_B12_19 65535 "Invalid" ;
VAL_ 2337140388 M2P_Measure_Vol_B12_20 65535 "Invalid" ;
VAL_ 2337140388 M2P_Current_B12_20 65535 "Invalid" ;
VAL_ 2337140388 M2P_PermitMaxCharge_I_B12_20 65535 "Invalid" ;
VAL_ 2337140388 M2P_PermitMaxDisCharge_I_B12_20 65535 "Invalid" ;
VAL_ 2337140389 M2P_Measure_Vol_B12_21 65535 "Invalid" ;
VAL_ 2337140389 M2P_Current_B12_21 65535 "Invalid" ;
VAL_ 2337140389 M2P_PermitMaxCharge_I_B12_21 65535 "Invalid" ;
VAL_ 2337140389 M2P_PermitMaxDisCharge_I_B12_21 65535 "Invalid" ;
VAL_ 2337140390 M2P_Measure_Vol_B12_22 65535 "Invalid" ;
VAL_ 2337140390 M2P_Current_B12_22 65535 "Invalid" ;
VAL_ 2337140390 M2P_PermitMaxCharge_I_B12_22 65535 "Invalid" ;
VAL_ 2337140390 M2P_PermitMaxDisCharge_I_B12_22 65535 "Invalid" ;
VAL_ 2337140391 M2P_Measure_Vol_B12_23 65535 "Invalid" ;
VAL_ 2337140391 M2P_Current_B12_23 65535 "Invalid" ;
VAL_ 2337140391 M2P_PermitMaxCharge_I_B12_23 65535 "Invalid" ;
VAL_ 2337140391 M2P_PermitMaxDisCharge_I_B12_23 65535 "Invalid" ;
VAL_ 2337140392 M2P_Measure_Vol_B12_24 65535 "Invalid" ;
VAL_ 2337140392 M2P_Current_B12_24 65535 "Invalid" ;
VAL_ 2337140392 M2P_PermitMaxCharge_I_B12_24 65535 "Invalid" ;
VAL_ 2337140392 M2P_PermitMaxDisCharge_I_B12_24 65535 "Invalid" ;
VAL_ 2337140393 M2P_Measure_Vol_B12_25 65535 "Invalid" ;
VAL_ 2337140393 M2P_Current_B12_25 65535 "Invalid" ;
VAL_ 2337140393 M2P_PermitMaxCharge_I_B12_25 65535 "Invalid" ;
VAL_ 2337140393 M2P_PermitMaxDisCharge_I_B12_25 65535 "Invalid" ;
VAL_ 2337140394 M2P_Measure_Vol_B12_26 65535 "Invalid" ;
VAL_ 2337140394 M2P_Current_B12_26 65535 "Invalid" ;
VAL_ 2337140394 M2P_PermitMaxCharge_I_B12_26 65535 "Invalid" ;
VAL_ 2337140394 M2P_PermitMaxDisCharge_I_B12_26 65535 "Invalid" ;
VAL_ 2337140395 M2P_Measure_Vol_B12_27 65535 "Invalid" ;
VAL_ 2337140395 M2P_Current_B12_27 65535 "Invalid" ;
VAL_ 2337140395 M2P_PermitMaxCharge_I_B12_27 65535 "Invalid" ;
VAL_ 2337140395 M2P_PermitMaxDisCharge_I_B12_27 65535 "Invalid" ;
VAL_ 2337140396 M2P_Measure_Vol_B12_28 65535 "Invalid" ;
VAL_ 2337140396 M2P_Current_B12_28 65535 "Invalid" ;
VAL_ 2337140396 M2P_PermitMaxCharge_I_B12_28 65535 "Invalid" ;
VAL_ 2337140396 M2P_PermitMaxDisCharge_I_B12_28 65535 "Invalid" ;
VAL_ 2337140397 M2P_Measure_Vol_B12_29 65535 "Invalid" ;
VAL_ 2337140397 M2P_Current_B12_29 65535 "Invalid" ;
VAL_ 2337140397 M2P_PermitMaxCharge_I_B12_29 65535 "Invalid" ;
VAL_ 2337140397 M2P_PermitMaxDisCharge_I_B12_29 65535 "Invalid" ;
VAL_ 2337140398 M2P_Measure_Vol_B12_30 65535 "Invalid" ;
VAL_ 2337140398 M2P_Current_B12_30 65535 "Invalid" ;
VAL_ 2337140398 M2P_PermitMaxCharge_I_B12_30 65535 "Invalid" ;
VAL_ 2337140398 M2P_PermitMaxDisCharge_I_B12_30 65535 "Invalid" ;
VAL_ 2337140399 M2P_Measure_Vol_B12_31 65535 "Invalid" ;
VAL_ 2337140399 M2P_Current_B12_31 65535 "Invalid" ;
VAL_ 2337140399 M2P_PermitMaxCharge_I_B12_31 65535 "Invalid" ;
VAL_ 2337140399 M2P_PermitMaxDisCharge_I_B12_31 65535 "Invalid" ;
VAL_ 2337271441 M2P_SysremEngy_Chg_B12_01 65535 "Invalid" ;
VAL_ 2337271441 M2P_SysremEngy_DisChg_B12_01 65535 "Invalid" ;
VAL_ 2337271442 M2P_SysremEngy_Chg_B12_02 65535 "Invalid" ;
VAL_ 2337271442 M2P_SysremEngy_DisChg_B12_02 65535 "Invalid" ;
VAL_ 2337271443 M2P_SysremEngy_Chg_B12_03 65535 "Invalid" ;
VAL_ 2337271443 M2P_SysremEngy_DisChg_B12_03 65535 "Invalid" ;
VAL_ 2337271444 M2P_SysremEngy_Chg_B12_04 65535 "Invalid" ;
VAL_ 2337271444 M2P_SysremEngy_DisChg_B12_04 65535 "Invalid" ;
VAL_ 2337271445 M2P_SysremEngy_Chg_B12_05 65535 "Invalid" ;
VAL_ 2337271445 M2P_SysremEngy_DisChg_B12_05 65535 "Invalid" ;
VAL_ 2337271446 M2P_SysremEngy_Chg_B12_06 65535 "Invalid" ;
VAL_ 2337271446 M2P_SysremEngy_DisChg_B12_06 65535 "Invalid" ;
VAL_ 2337271447 M2P_SysremEngy_Chg_B12_07 65535 "Invalid" ;
VAL_ 2337271447 M2P_SysremEngy_DisChg_B12_07 65535 "Invalid" ;
VAL_ 2337271448 M2P_SysremEngy_Chg_B12_08 65535 "Invalid" ;
VAL_ 2337271448 M2P_SysremEngy_DisChg_B12_08 65535 "Invalid" ;
VAL_ 2337271449 M2P_SysremEngy_Chg_B12_09 65535 "Invalid" ;
VAL_ 2337271449 M2P_SysremEngy_DisChg_B12_09 65535 "Invalid" ;
VAL_ 2337271450 M2P_SysremEngy_Chg_B12_10 65535 "Invalid" ;
VAL_ 2337271450 M2P_SysremEngy_DisChg_B12_10 65535 "Invalid" ;
VAL_ 2337271451 M2P_SysremEngy_Chg_B12_11 65535 "Invalid" ;
VAL_ 2337271451 M2P_SysremEngy_DisChg_B12_11 65535 "Invalid" ;
VAL_ 2337271452 M2P_SysremEngy_Chg_B12_12 65535 "Invalid" ;
VAL_ 2337271452 M2P_SysremEngy_DisChg_B12_12 65535 "Invalid" ;
VAL_ 2337271453 M2P_SysremEngy_Chg_B12_13 65535 "Invalid" ;
VAL_ 2337271453 M2P_SysremEngy_DisChg_B12_13 65535 "Invalid" ;
VAL_ 2337271454 M2P_SysremEngy_Chg_B12_14 65535 "Invalid" ;
VAL_ 2337271454 M2P_SysremEngy_DisChg_B12_14 65535 "Invalid" ;
VAL_ 2337271455 M2P_SysremEngy_Chg_B12_15 65535 "Invalid" ;
VAL_ 2337271455 M2P_SysremEngy_DisChg_B12_15 65535 "Invalid" ;
VAL_ 2337271456 M2P_SysremEngy_Chg_B12_16 65535 "Invalid" ;
VAL_ 2337271456 M2P_SysremEngy_DisChg_B12_16 65535 "Invalid" ;
VAL_ 2337271457 M2P_SysremEngy_Chg_B12_17 65535 "Invalid" ;
VAL_ 2337271457 M2P_SysremEngy_DisChg_B12_17 65535 "Invalid" ;
VAL_ 2337271458 M2P_SysremEngy_Chg_B12_18 65535 "Invalid" ;
VAL_ 2337271458 M2P_SysremEngy_DisChg_B12_18 65535 "Invalid" ;
VAL_ 2337271459 M2P_SysremEngy_Chg_B12_19 65535 "Invalid" ;
VAL_ 2337271459 M2P_SysremEngy_DisChg_B12_19 65535 "Invalid" ;
VAL_ 2337271460 M2P_SysremEngy_Chg_B12_20 65535 "Invalid" ;
VAL_ 2337271460 M2P_SysremEngy_DisChg_B12_20 65535 "Invalid" ;
VAL_ 2337271461 M2P_SysremEngy_Chg_B12_21 65535 "Invalid" ;
VAL_ 2337271461 M2P_SysremEngy_DisChg_B12_21 65535 "Invalid" ;
VAL_ 2337271462 M2P_SysremEngy_Chg_B12_22 65535 "Invalid" ;
VAL_ 2337271462 M2P_SysremEngy_DisChg_B12_22 65535 "Invalid" ;
VAL_ 2337271463 M2P_SysremEngy_Chg_B12_23 65535 "Invalid" ;
VAL_ 2337271463 M2P_SysremEngy_DisChg_B12_23 65535 "Invalid" ;
VAL_ 2337271464 M2P_SysremEngy_Chg_B12_24 65535 "Invalid" ;
VAL_ 2337271464 M2P_SysremEngy_DisChg_B12_24 65535 "Invalid" ;
VAL_ 2337271465 M2P_SysremEngy_Chg_B12_25 65535 "Invalid" ;
VAL_ 2337271465 M2P_SysremEngy_DisChg_B12_25 65535 "Invalid" ;
VAL_ 2337271466 M2P_SysremEngy_Chg_B12_26 65535 "Invalid" ;
VAL_ 2337271466 M2P_SysremEngy_DisChg_B12_26 65535 "Invalid" ;
VAL_ 2337271467 M2P_SysremEngy_Chg_B12_27 65535 "Invalid" ;
VAL_ 2337271467 M2P_SysremEngy_DisChg_B12_27 65535 "Invalid" ;
VAL_ 2337271468 M2P_SysremEngy_Chg_B12_28 65535 "Invalid" ;
VAL_ 2337271468 M2P_SysremEngy_DisChg_B12_28 65535 "Invalid" ;
VAL_ 2337271469 M2P_SysremEngy_Chg_B12_29 65535 "Invalid" ;
VAL_ 2337271469 M2P_SysremEngy_DisChg_B12_29 65535 "Invalid" ;
VAL_ 2337271470 M2P_SysremEngy_Chg_B12_30 65535 "Invalid" ;
VAL_ 2337271470 M2P_SysremEngy_DisChg_B12_30 65535 "Invalid" ;
VAL_ 2337271471 M2P_SysremEngy_Chg_B12_31 65535 "Invalid" ;
VAL_ 2337271471 M2P_SysremEngy_DisChg_B12_31 65535 "Invalid" ;
VAL_ 2337336977 M2P_BMS_Status_B12 0 "初始化状态" 1 "非满充满放状态" 2 "满充状态" 3 "满放状态" ;
VAL_ 2337336977 M2P_SOC_B12 1023 "Null" ;
VAL_ 2337336977 M2P_SOH_B12 255 "Null" ;
VAL_ 2337336978 M2P_BMS_Status_B12 0 "初始化状态" 1 "非满充满放状态" 2 "满充状态" 3 "满放状态" ;
VAL_ 2337336978 M2P_SOC_B12 1023 "Null" ;
VAL_ 2337336978 M2P_SOH_B12 255 "Null" ;
VAL_ 2337336979 M2P_BMS_Status_B12 0 "初始化状态" 1 "非满充满放状态" 2 "满充状态" 3 "满放状态" ;
VAL_ 2337336979 M2P_SOC_B12 1023 "Null" ;
VAL_ 2337336979 M2P_SOH_B12 255 "Null" ;
VAL_ 2337336980 M2P_BMS_Status_B12 0 "初始化状态" 1 "非满充满放状态" 2 "满充状态" 3 "满放状态" ;
VAL_ 2337336980 M2P_SOC_B12 1023 "Null" ;
VAL_ 2337336980 M2P_SOH_B12 255 "Null" ;
VAL_ 2337336981 M2P_BMS_Status_B12 0 "初始化状态" 1 "非满充满放状态" 2 "满充状态" 3 "满放状态" ;
VAL_ 2337336981 M2P_SOC_B12 1023 "Null" ;
VAL_ 2337336981 M2P_SOH_B12 255 "Null" ;
VAL_ 2337336982 M2P_BMS_Status_B12 0 "初始化状态" 1 "非满充满放状态" 2 "满充状态" 3 "满放状态" ;
VAL_ 2337336982 M2P_SOC_B12 1023 "Null" ;
VAL_ 2337336982 M2P_SOH_B12 255 "Null" ;
VAL_ 2337336983 M2P_BMS_Status_B12 0 "初始化状态" 1 "非满充满放状态" 2 "满充状态" 3 "满放状态" ;
VAL_ 2337336983 M2P_SOC_B12 1023 "Null" ;
VAL_ 2337336983 M2P_SOH_B12 255 "Null" ;
VAL_ 2337336984 M2P_BMS_Status_B12 0 "初始化状态" 1 "非满充满放状态" 2 "满充状态" 3 "满放状态" ;
VAL_ 2337336984 M2P_SOC_B12 1023 "Null" ;
VAL_ 2337336984 M2P_SOH_B12 255 "Null" ;
VAL_ 2337336985 M2P_BMS_Status_B12 0 "初始化状态" 1 "非满充满放状态" 2 "满充状态" 3 "满放状态" ;
VAL_ 2337336985 M2P_SOC_B12 1023 "Null" ;
VAL_ 2337336985 M2P_SOH_B12 255 "Null" ;
VAL_ 2337336986 M2P_BMS_Status_B12 0 "初始化状态" 1 "非满充满放状态" 2 "满充状态" 3 "满放状态" ;
VAL_ 2337336986 M2P_SOC_B12 1023 "Null" ;
VAL_ 2337336986 M2P_SOH_B12 255 "Null" ;
VAL_ 2337336987 M2P_BMS_Status_B12 0 "初始化状态" 1 "非满充满放状态" 2 "满充状态" 3 "满放状态" ;
VAL_ 2337336987 M2P_SOC_B12 1023 "Null" ;
VAL_ 2337336987 M2P_SOH_B12 255 "Null" ;
VAL_ 2337336988 M2P_BMS_Status_B12 0 "初始化状态" 1 "非满充满放状态" 2 "满充状态" 3 "满放状态" ;
VAL_ 2337336988 M2P_SOC_B12 1023 "Null" ;
VAL_ 2337336988 M2P_SOH_B12 255 "Null" ;
VAL_ 2337336989 M2P_BMS_Status_B12 0 "初始化状态" 1 "非满充满放状态" 2 "满充状态" 3 "满放状态" ;
VAL_ 2337336989 M2P_SOC_B12 1023 "Null" ;
VAL_ 2337336989 M2P_SOH_B12 255 "Null" ;
VAL_ 2337336990 M2P_BMS_Status_B12 0 "初始化状态" 1 "非满充满放状态" 2 "满充状态" 3 "满放状态" ;
VAL_ 2337336990 M2P_SOC_B12 1023 "Null" ;
VAL_ 2337336990 M2P_SOH_B12 255 "Null" ;
VAL_ 2337336991 M2P_BMS_Status_B12 0 "初始化状态" 1 "非满充满放状态" 2 "满充状态" 3 "满放状态" ;
VAL_ 2337336991 M2P_SOC_B12 1023 "Null" ;
VAL_ 2337336991 M2P_SOH_B12 255 "Null" ;
VAL_ 2337336992 M2P_BMS_Status_B12 0 "初始化状态" 1 "非满充满放状态" 2 "满充状态" 3 "满放状态" ;
VAL_ 2337336992 M2P_SOC_B12 1023 "Null" ;
VAL_ 2337336992 M2P_SOH_B12 255 "Null" ;
VAL_ 2337336993 M2P_BMS_Status_B12 0 "初始化状态" 1 "非满充满放状态" 2 "满充状态" 3 "满放状态" ;
VAL_ 2337336993 M2P_SOC_B12 1023 "Null" ;
VAL_ 2337336993 M2P_SOH_B12 255 "Null" ;
VAL_ 2337336994 M2P_BMS_Status_B12 0 "初始化状态" 1 "非满充满放状态" 2 "满充状态" 3 "满放状态" ;
VAL_ 2337336994 M2P_SOC_B12 1023 "Null" ;
VAL_ 2337336994 M2P_SOH_B12 255 "Null" ;
VAL_ 2337336995 M2P_BMS_Status_B12 0 "初始化状态" 1 "非满充满放状态" 2 "满充状态" 3 "满放状态" ;
VAL_ 2337336995 M2P_SOC_B12 1023 "Null" ;
VAL_ 2337336995 M2P_SOH_B12 255 "Null" ;
VAL_ 2337336996 M2P_BMS_Status_B12 0 "初始化状态" 1 "非满充满放状态" 2 "满充状态" 3 "满放状态" ;
VAL_ 2337336996 M2P_SOC_B12 1023 "Null" ;
VAL_ 2337336996 M2P_SOH_B12 255 "Null" ;
VAL_ 2337336997 M2P_BMS_Status_B12 0 "初始化状态" 1 "非满充满放状态" 2 "满充状态" 3 "满放状态" ;
VAL_ 2337336997 M2P_SOC_B12 1023 "Null" ;
VAL_ 2337336997 M2P_SOH_B12 255 "Null" ;
VAL_ 2337336998 M2P_BMS_Status_B12 0 "初始化状态" 1 "非满充满放状态" 2 "满充状态" 3 "满放状态" ;
VAL_ 2337336998 M2P_SOC_B12 1023 "Null" ;
VAL_ 2337336998 M2P_SOH_B12 255 "Null" ;
VAL_ 2337336999 M2P_BMS_Status_B12 0 "初始化状态" 1 "非满充满放状态" 2 "满充状态" 3 "满放状态" ;
VAL_ 2337336999 M2P_SOC_B12 1023 "Null" ;
VAL_ 2337336999 M2P_SOH_B12 255 "Null" ;
VAL_ 2337337000 M2P_BMS_Status_B12 0 "初始化状态" 1 "非满充满放状态" 2 "满充状态" 3 "满放状态" ;
VAL_ 2337337000 M2P_SOC_B12 1023 "Null" ;
VAL_ 2337337000 M2P_SOH_B12 255 "Null" ;
VAL_ 2337337001 M2P_BMS_Status_B12 0 "初始化状态" 1 "非满充满放状态" 2 "满充状态" 3 "满放状态" ;
VAL_ 2337337001 M2P_SOC_B12 1023 "Null" ;
VAL_ 2337337001 M2P_SOH_B12 255 "Null" ;
VAL_ 2337337002 M2P_BMS_Status_B12 0 "初始化状态" 1 "非满充满放状态" 2 "满充状态" 3 "满放状态" ;
VAL_ 2337337002 M2P_SOC_B12 1023 "Null" ;
VAL_ 2337337002 M2P_SOH_B12 255 "Null" ;
VAL_ 2337337003 M2P_BMS_Status_B12 0 "初始化状态" 1 "非满充满放状态" 2 "满充状态" 3 "满放状态" ;
VAL_ 2337337003 M2P_SOC_B12 1023 "Null" ;
VAL_ 2337337003 M2P_SOH_B12 255 "Null" ;
VAL_ 2337337004 M2P_BMS_Status_B12 0 "初始化状态" 1 "非满充满放状态" 2 "满充状态" 3 "满放状态" ;
VAL_ 2337337004 M2P_SOC_B12 1023 "Null" ;
VAL_ 2337337004 M2P_SOH_B12 255 "Null" ;
VAL_ 2337337005 M2P_BMS_Status_B12 0 "初始化状态" 1 "非满充满放状态" 2 "满充状态" 3 "满放状态" ;
VAL_ 2337337005 M2P_SOC_B12 1023 "Null" ;
VAL_ 2337337005 M2P_SOH_B12 255 "Null" ;
VAL_ 2337337006 M2P_BMS_Status_B12 0 "初始化状态" 1 "非满充满放状态" 2 "满充状态" 3 "满放状态" ;
VAL_ 2337337006 M2P_SOC_B12 1023 "Null" ;
VAL_ 2337337006 M2P_SOH_B12 255 "Null" ;
VAL_ 2337337007 M2P_BMS_Status_B12 0 "初始化状态" 1 "非满充满放状态" 2 "满充状态" 3 "满放状态" ;
VAL_ 2337337007 M2P_SOC_B12 1023 "Null" ;
VAL_ 2337337007 M2P_SOH_B12 255 "Null" ;
VAL_ 2337402513 M2P_SOE_Charge_B12 1023 "Null" ;
VAL_ 2337402513 M2P_SOE_Discharge_B12 1023 "Null" ;
VAL_ 2337402514 M2P_SOE_Charge_B12 1023 "Null" ;
VAL_ 2337402514 M2P_SOE_Discharge_B12 1023 "Null" ;
VAL_ 2337402515 M2P_SOE_Charge_B12 1023 "Null" ;
VAL_ 2337402515 M2P_SOE_Discharge_B12 1023 "Null" ;
VAL_ 2337402516 M2P_SOE_Charge_B12 1023 "Null" ;
VAL_ 2337402516 M2P_SOE_Discharge_B12 1023 "Null" ;
VAL_ 2337402517 M2P_SOE_Charge_B12 1023 "Null" ;
VAL_ 2337402517 M2P_SOE_Discharge_B12 1023 "Null" ;
VAL_ 2337402518 M2P_SOE_Charge_B12 1023 "Null" ;
VAL_ 2337402518 M2P_SOE_Discharge_B12 1023 "Null" ;
VAL_ 2337402519 M2P_SOE_Charge_B12 1023 "Null" ;
VAL_ 2337402519 M2P_SOE_Discharge_B12 1023 "Null" ;
VAL_ 2337402520 M2P_SOE_Charge_B12 1023 "Null" ;
VAL_ 2337402520 M2P_SOE_Discharge_B12 1023 "Null" ;
VAL_ 2337402521 M2P_SOE_Charge_B12 1023 "Null" ;
VAL_ 2337402521 M2P_SOE_Discharge_B12 1023 "Null" ;
VAL_ 2337402522 M2P_SOE_Charge_B12 1023 "Null" ;
VAL_ 2337402522 M2P_SOE_Discharge_B12 1023 "Null" ;
VAL_ 2337402523 M2P_SOE_Charge_B12 1023 "Null" ;
VAL_ 2337402523 M2P_SOE_Discharge_B12 1023 "Null" ;
VAL_ 2337402524 M2P_SOE_Charge_B12 1023 "Null" ;
VAL_ 2337402524 M2P_SOE_Discharge_B12 1023 "Null" ;
VAL_ 2337402525 M2P_SOE_Charge_B12 1023 "Null" ;
VAL_ 2337402525 M2P_SOE_Discharge_B12 1023 "Null" ;
VAL_ 2337402526 M2P_SOE_Charge_B12 1023 "Null" ;
VAL_ 2337402526 M2P_SOE_Discharge_B12 1023 "Null" ;
VAL_ 2337402527 M2P_SOE_Charge_B12 1023 "Null" ;
VAL_ 2337402527 M2P_SOE_Discharge_B12 1023 "Null" ;
VAL_ 2337402528 M2P_SOE_Charge_B12 1023 "Null" ;
VAL_ 2337402528 M2P_SOE_Discharge_B12 1023 "Null" ;
VAL_ 2337402529 M2P_SOE_Charge_B12 1023 "Null" ;
VAL_ 2337402529 M2P_SOE_Discharge_B12 1023 "Null" ;
VAL_ 2337402530 M2P_SOE_Charge_B12 1023 "Null" ;
VAL_ 2337402530 M2P_SOE_Discharge_B12 1023 "Null" ;
VAL_ 2337402531 M2P_SOE_Charge_B12 1023 "Null" ;
VAL_ 2337402531 M2P_SOE_Discharge_B12 1023 "Null" ;
VAL_ 2337402532 M2P_SOE_Charge_B12 1023 "Null" ;
VAL_ 2337402532 M2P_SOE_Discharge_B12 1023 "Null" ;
VAL_ 2337402533 M2P_SOE_Charge_B12 1023 "Null" ;
VAL_ 2337402533 M2P_SOE_Discharge_B12 1023 "Null" ;
VAL_ 2337402534 M2P_SOE_Charge_B12 1023 "Null" ;
VAL_ 2337402534 M2P_SOE_Discharge_B12 1023 "Null" ;
VAL_ 2337402535 M2P_SOE_Charge_B12 1023 "Null" ;
VAL_ 2337402535 M2P_SOE_Discharge_B12 1023 "Null" ;
VAL_ 2337402536 M2P_SOE_Charge_B12 1023 "Null" ;
VAL_ 2337402536 M2P_SOE_Discharge_B12 1023 "Null" ;
VAL_ 2337402537 M2P_SOE_Charge_B12 1023 "Null" ;
VAL_ 2337402537 M2P_SOE_Discharge_B12 1023 "Null" ;
VAL_ 2337402538 M2P_SOE_Charge_B12 1023 "Null" ;
VAL_ 2337402538 M2P_SOE_Discharge_B12 1023 "Null" ;
VAL_ 2337402539 M2P_SOE_Charge_B12 1023 "Null" ;
VAL_ 2337402539 M2P_SOE_Discharge_B12 1023 "Null" ;
VAL_ 2337402540 M2P_SOE_Charge_B12 1023 "Null" ;
VAL_ 2337402540 M2P_SOE_Discharge_B12 1023 "Null" ;
VAL_ 2337402541 M2P_SOE_Charge_B12 1023 "Null" ;
VAL_ 2337402541 M2P_SOE_Discharge_B12 1023 "Null" ;
VAL_ 2337402542 M2P_SOE_Charge_B12 1023 "Null" ;
VAL_ 2337402542 M2P_SOE_Discharge_B12 1023 "Null" ;
VAL_ 2337402543 M2P_SOE_Charge_B12 1023 "Null" ;
VAL_ 2337402543 M2P_SOE_Discharge_B12 1023 "Null" ;
VERSION ""

NS_ :

BS_:

BU_: MBMU PC SBMU IMM ETH DCDC LEMS

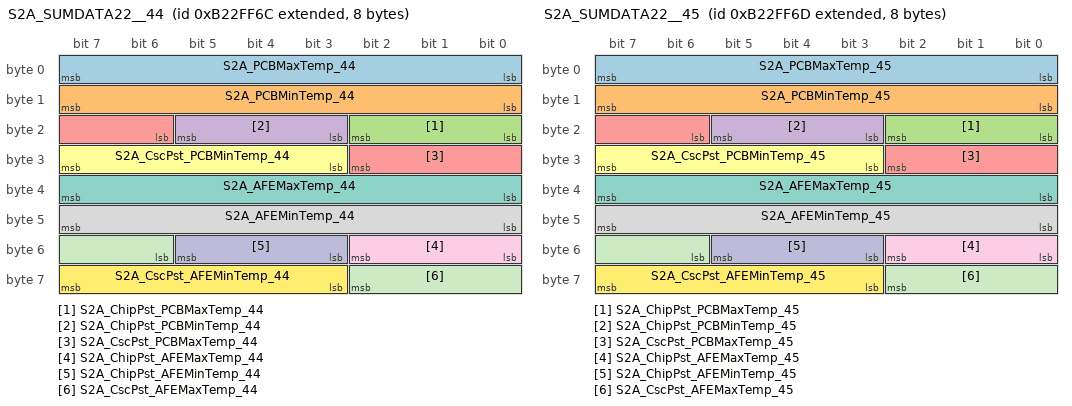
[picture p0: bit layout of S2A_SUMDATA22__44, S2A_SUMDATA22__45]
BO_ 2334326636 S2A_SUMDATA22__44: 8 SBMU
 SG_ S2A_PCBMaxTemp_44 : 0|8@1+ (1,-50) [-50|205] "℃"  PC
 SG_ S2A_PCBMinTemp_44 : 8|8@1+ (1,-50) [-50|205] "℃"  PC
 SG_ S2A_ChipPst_PCBMaxTemp_44 : 16|3@1+ (1,0) [0|7] ""  PC
 SG_ S2A_ChipPst_PCBMinTemp_44 : 19|3@1+ (1,0) [0|7] ""  PC
 SG_ S2A_CscPst_PCBMaxTemp_44 : 22|5@1+ (1,0) [0|31] ""  PC
 SG_ S2A_CscPst_PCBMinTemp_44 : 27|5@1+ (1,0) [0|31] ""  PC
 SG_ S2A_AFEMaxTemp_44 : 32|8@1+ (1,-50) [-50|205] "℃"  PC
 SG_ S2A_AFEMinTemp_44 : 40|8@1+ (1,-50) [-50|205] "℃"  PC
 SG_ S2A_ChipPst_AFEMaxTemp_44 : 48|3@1+ (1,0) [0|7] ""  PC
 SG_ S2A_ChipPst_AFEMinTemp_44 : 51|3@1+ (1,0) [0|7] ""  PC
 SG_ S2A_CscPst_AFEMaxTemp_44 : 54|5@1+ (1,0) [0|31] ""  PC
 SG_ S2A_CscPst_AFEMinTemp_44 : 59|5@1+ (1,0) [0|31] ""  PC

BO_ 2334326637 S2A_SUMDATA22__45: 8 SBMU
 SG_ S2A_PCBMaxTemp_45 : 0|8@1+ (1,-50) [-50|205] "℃"  PC
 SG_ S2A_PCBMinTemp_45 : 8|8@1+ (1,-50) [-50|205] "℃"  PC
 SG_ S2A_ChipPst_PCBMaxTemp_45 : 16|3@1+ (1,0) [0|7] ""  PC
 SG_ S2A_ChipPst_PCBMinTemp_45 : 19|3@1+ (1,0) [0|7] ""  PC
 SG_ S2A_CscPst_PCBMaxTemp_45 : 22|5@1+ (1,0) [0|31] ""  PC
 SG_ S2A_CscPst_PCBMinTemp_45 : 27|5@1+ (1,0) [0|31] ""  PC
 SG_ S2A_AFEMaxTemp_45 : 32|8@1+ (1,-50) [-50|205] "℃"  PC
 SG_ S2A_AFEMinTemp_45 : 40|8@1+ (1,-50) [-50|205] "℃"  PC
 SG_ S2A_ChipPst_AFEMaxTemp_45 : 48|3@1+ (1,0) [0|7] ""  PC
 SG_ S2A_ChipPst_AFEMinTemp_45 : 51|3@1+ (1,0) [0|7] ""  PC
 SG_ S2A_CscPst_AFEMaxTemp_45 : 54|5@1+ (1,0) [0|31] ""  PC
 SG_ S2A_CscPst_AFEMinTemp_45 : 59|5@1+ (1,0) [0|31] ""  PC

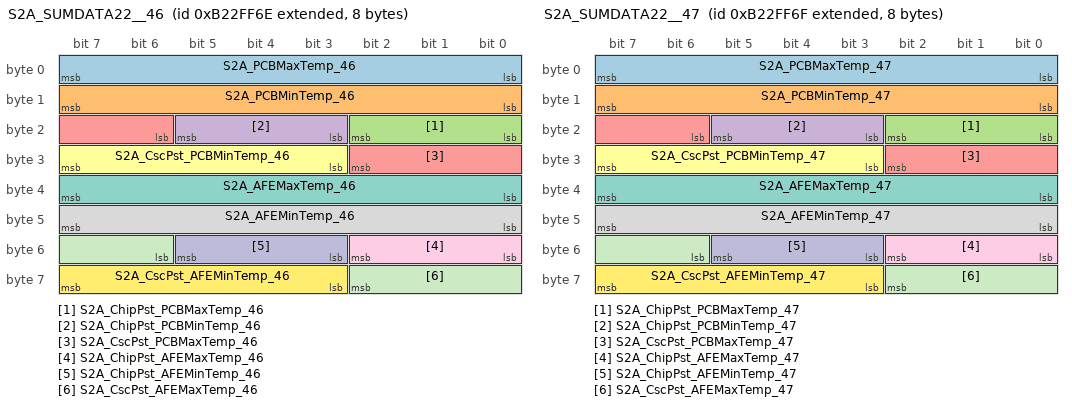
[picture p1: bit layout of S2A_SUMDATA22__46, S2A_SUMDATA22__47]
BO_ 2334326638 S2A_SUMDATA22__46: 8 SBMU
 SG_ S2A_PCBMaxTemp_46 : 0|8@1+ (1,-50) [-50|205] "℃"  PC
 SG_ S2A_PCBMinTemp_46 : 8|8@1+ (1,-50) [-50|205] "℃"  PC
 SG_ S2A_ChipPst_PCBMaxTemp_46 : 16|3@1+ (1,0) [0|7] ""  PC
 SG_ S2A_ChipPst_PCBMinTemp_46 : 19|3@1+ (1,0) [0|7] ""  PC
 SG_ S2A_CscPst_PCBMaxTemp_46 : 22|5@1+ (1,0) [0|31] ""  PC
 SG_ S2A_CscPst_PCBMinTemp_46 : 27|5@1+ (1,0) [0|31] ""  PC
 SG_ S2A_AFEMaxTemp_46 : 32|8@1+ (1,-50) [-50|205] "℃"  PC
 SG_ S2A_AFEMinTemp_46 : 40|8@1+ (1,-50) [-50|205] "℃"  PC
 SG_ S2A_ChipPst_AFEMaxTemp_46 : 48|3@1+ (1,0) [0|7] ""  PC
 SG_ S2A_ChipPst_AFEMinTemp_46 : 51|3@1+ (1,0) [0|7] ""  PC
 SG_ S2A_CscPst_AFEMaxTemp_46 : 54|5@1+ (1,0) [0|31] ""  PC
 SG_ S2A_CscPst_AFEMinTemp_46 : 59|5@1+ (1,0) [0|31] ""  PC

BO_ 2334326639 S2A_SUMDATA22__47: 8 SBMU
 SG_ S2A_PCBMaxTemp_47 : 0|8@1+ (1,-50) [-50|205] "℃"  PC
 SG_ S2A_PCBMinTemp_47 : 8|8@1+ (1,-50) [-50|205] "℃"  PC
 SG_ S2A_ChipPst_PCBMaxTemp_47 : 16|3@1+ (1,0) [0|7] ""  PC
 SG_ S2A_ChipPst_PCBMinTemp_47 : 19|3@1+ (1,0) [0|7] ""  PC
 SG_ S2A_CscPst_PCBMaxTemp_47 : 22|5@1+ (1,0) [0|31] ""  PC
 SG_ S2A_CscPst_PCBMinTemp_47 : 27|5@1+ (1,0) [0|31] ""  PC
 SG_ S2A_AFEMaxTemp_47 : 32|8@1+ (1,-50) [-50|205] "℃"  PC
 SG_ S2A_AFEMinTemp_47 : 40|8@1+ (1,-50) [-50|205] "℃"  PC
 SG_ S2A_ChipPst_AFEMaxTemp_47 : 48|3@1+ (1,0) [0|7] ""  PC
 SG_ S2A_ChipPst_AFEMinTemp_47 : 51|3@1+ (1,0) [0|7] ""  PC
 SG_ S2A_CscPst_AFEMaxTemp_47 : 54|5@1+ (1,0) [0|31] ""  PC
 SG_ S2A_CscPst_AFEMinTemp_47 : 59|5@1+ (1,0) [0|31] ""  PC

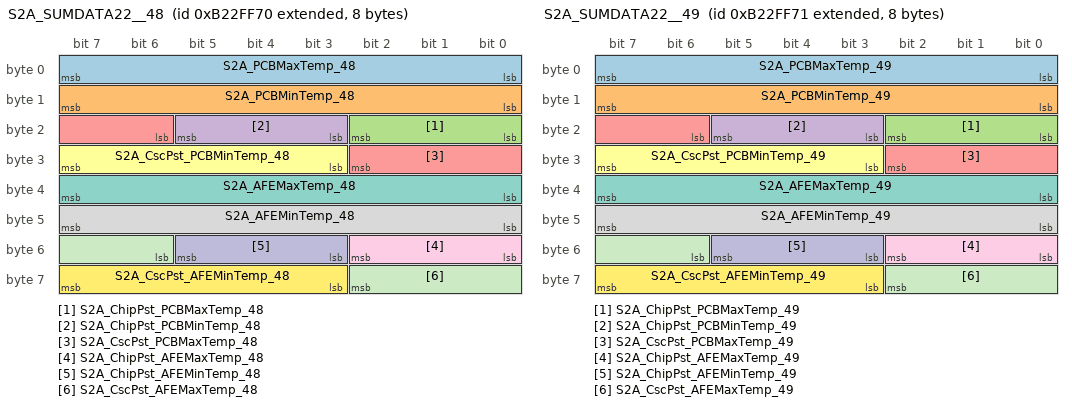
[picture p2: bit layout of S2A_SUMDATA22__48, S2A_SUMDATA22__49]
BO_ 2334326640 S2A_SUMDATA22__48: 8 SBMU
 SG_ S2A_PCBMaxTemp_48 : 0|8@1+ (1,-50) [-50|205] "℃"  PC
 SG_ S2A_PCBMinTemp_48 : 8|8@1+ (1,-50) [-50|205] "℃"  PC
 SG_ S2A_ChipPst_PCBMaxTemp_48 : 16|3@1+ (1,0) [0|7] ""  PC
 SG_ S2A_ChipPst_PCBMinTemp_48 : 19|3@1+ (1,0) [0|7] ""  PC
 SG_ S2A_CscPst_PCBMaxTemp_48 : 22|5@1+ (1,0) [0|31] ""  PC
 SG_ S2A_CscPst_PCBMinTemp_48 : 27|5@1+ (1,0) [0|31] ""  PC
 SG_ S2A_AFEMaxTemp_48 : 32|8@1+ (1,-50) [-50|205] "℃"  PC
 SG_ S2A_AFEMinTemp_48 : 40|8@1+ (1,-50) [-50|205] "℃"  PC
 SG_ S2A_ChipPst_AFEMaxTemp_48 : 48|3@1+ (1,0) [0|7] ""  PC
 SG_ S2A_ChipPst_AFEMinTemp_48 : 51|3@1+ (1,0) [0|7] ""  PC
 SG_ S2A_CscPst_AFEMaxTemp_48 : 54|5@1+ (1,0) [0|31] ""  PC
 SG_ S2A_CscPst_AFEMinTemp_48 : 59|5@1+ (1,0) [0|31] ""  PC

BO_ 2334326641 S2A_SUMDATA22__49: 8 SBMU
 SG_ S2A_PCBMaxTemp_49 : 0|8@1+ (1,-50) [-50|205] "℃"  PC
 SG_ S2A_PCBMinTemp_49 : 8|8@1+ (1,-50) [-50|205] "℃"  PC
 SG_ S2A_ChipPst_PCBMaxTemp_49 : 16|3@1+ (1,0) [0|7] ""  PC
 SG_ S2A_ChipPst_PCBMinTemp_49 : 19|3@1+ (1,0) [0|7] ""  PC
 SG_ S2A_CscPst_PCBMaxTemp_49 : 22|5@1+ (1,0) [0|31] ""  PC
 SG_ S2A_CscPst_PCBMinTemp_49 : 27|5@1+ (1,0) [0|31] ""  PC
 SG_ S2A_AFEMaxTemp_49 : 32|8@1+ (1,-50) [-50|205] "℃"  PC
 SG_ S2A_AFEMinTemp_49 : 40|8@1+ (1,-50) [-50|205] "℃"  PC
 SG_ S2A_ChipPst_AFEMaxTemp_49 : 48|3@1+ (1,0) [0|7] ""  PC
 SG_ S2A_ChipPst_AFEMinTemp_49 : 51|3@1+ (1,0) [0|7] ""  PC
 SG_ S2A_CscPst_AFEMaxTemp_49 : 54|5@1+ (1,0) [0|31] ""  PC
 SG_ S2A_CscPst_AFEMinTemp_49 : 59|5@1+ (1,0) [0|31] ""  PC

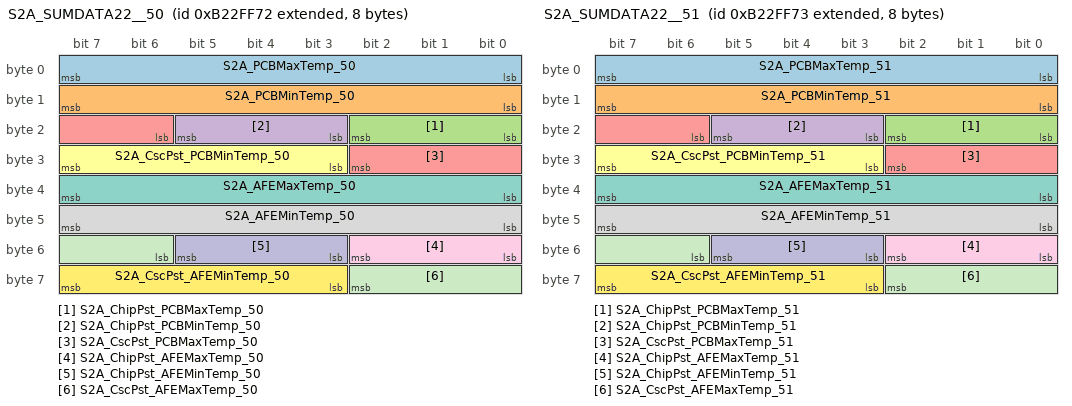
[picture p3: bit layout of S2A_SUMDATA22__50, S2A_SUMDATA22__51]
BO_ 2334326642 S2A_SUMDATA22__50: 8 SBMU
 SG_ S2A_PCBMaxTemp_50 : 0|8@1+ (1,-50) [-50|205] "℃"  PC
 SG_ S2A_PCBMinTemp_50 : 8|8@1+ (1,-50) [-50|205] "℃"  PC
 SG_ S2A_ChipPst_PCBMaxTemp_50 : 16|3@1+ (1,0) [0|7] ""  PC
 SG_ S2A_ChipPst_PCBMinTemp_50 : 19|3@1+ (1,0) [0|7] ""  PC
 SG_ S2A_CscPst_PCBMaxTemp_50 : 22|5@1+ (1,0) [0|31] ""  PC
 SG_ S2A_CscPst_PCBMinTemp_50 : 27|5@1+ (1,0) [0|31] ""  PC
 SG_ S2A_AFEMaxTemp_50 : 32|8@1+ (1,-50) [-50|205] "℃"  PC
 SG_ S2A_AFEMinTemp_50 : 40|8@1+ (1,-50) [-50|205] "℃"  PC
 SG_ S2A_ChipPst_AFEMaxTemp_50 : 48|3@1+ (1,0) [0|7] ""  PC
 SG_ S2A_ChipPst_AFEMinTemp_50 : 51|3@1+ (1,0) [0|7] ""  PC
 SG_ S2A_CscPst_AFEMaxTemp_50 : 54|5@1+ (1,0) [0|31] ""  PC
 SG_ S2A_CscPst_AFEMinTemp_50 : 59|5@1+ (1,0) [0|31] ""  PC

BO_ 2334326643 S2A_SUMDATA22__51: 8 SBMU
 SG_ S2A_PCBMaxTemp_51 : 0|8@1+ (1,-50) [-50|205] "℃"  PC
 SG_ S2A_PCBMinTemp_51 : 8|8@1+ (1,-50) [-50|205] "℃"  PC
 SG_ S2A_ChipPst_PCBMaxTemp_51 : 16|3@1+ (1,0) [0|7] ""  PC
 SG_ S2A_ChipPst_PCBMinTemp_51 : 19|3@1+ (1,0) [0|7] ""  PC
 SG_ S2A_CscPst_PCBMaxTemp_51 : 22|5@1+ (1,0) [0|31] ""  PC
 SG_ S2A_CscPst_PCBMinTemp_51 : 27|5@1+ (1,0) [0|31] ""  PC
 SG_ S2A_AFEMaxTemp_51 : 32|8@1+ (1,-50) [-50|205] "℃"  PC
 SG_ S2A_AFEMinTemp_51 : 40|8@1+ (1,-50) [-50|205] "℃"  PC
 SG_ S2A_ChipPst_AFEMaxTemp_51 : 48|3@1+ (1,0) [0|7] ""  PC
 SG_ S2A_ChipPst_AFEMinTemp_51 : 51|3@1+ (1,0) [0|7] ""  PC
 SG_ S2A_CscPst_AFEMaxTemp_51 : 54|5@1+ (1,0) [0|31] ""  PC
 SG_ S2A_CscPst_AFEMinTemp_51 : 59|5@1+ (1,0) [0|31] ""  PC

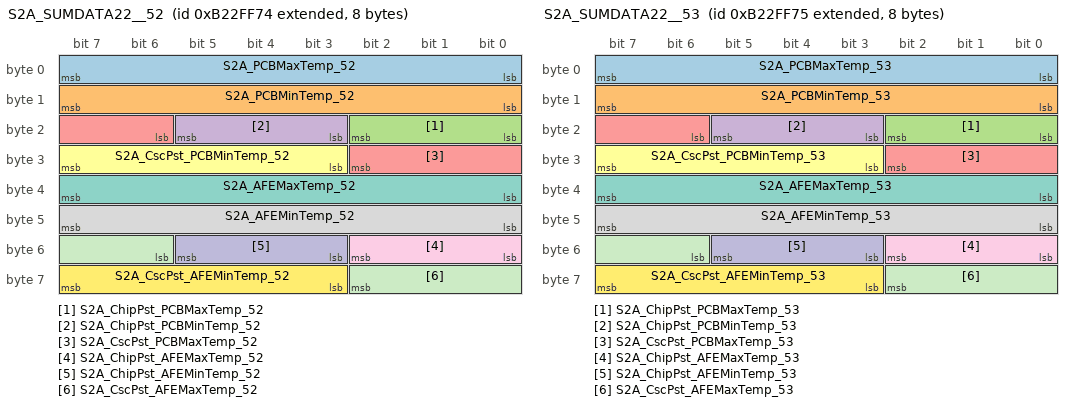
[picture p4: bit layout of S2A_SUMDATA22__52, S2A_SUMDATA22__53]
BO_ 2334326644 S2A_SUMDATA22__52: 8 SBMU
 SG_ S2A_PCBMaxTemp_52 : 0|8@1+ (1,-50) [-50|205] "℃"  PC
 SG_ S2A_PCBMinTemp_52 : 8|8@1+ (1,-50) [-50|205] "℃"  PC
 SG_ S2A_ChipPst_PCBMaxTemp_52 : 16|3@1+ (1,0) [0|7] ""  PC
 SG_ S2A_ChipPst_PCBMinTemp_52 : 19|3@1+ (1,0) [0|7] ""  PC
 SG_ S2A_CscPst_PCBMaxTemp_52 : 22|5@1+ (1,0) [0|31] ""  PC
 SG_ S2A_CscPst_PCBMinTemp_52 : 27|5@1+ (1,0) [0|31] ""  PC
 SG_ S2A_AFEMaxTemp_52 : 32|8@1+ (1,-50) [-50|205] "℃"  PC
 SG_ S2A_AFEMinTemp_52 : 40|8@1+ (1,-50) [-50|205] "℃"  PC
 SG_ S2A_ChipPst_AFEMaxTemp_52 : 48|3@1+ (1,0) [0|7] ""  PC
 SG_ S2A_ChipPst_AFEMinTemp_52 : 51|3@1+ (1,0) [0|7] ""  PC
 SG_ S2A_CscPst_AFEMaxTemp_52 : 54|5@1+ (1,0) [0|31] ""  PC
 SG_ S2A_CscPst_AFEMinTemp_52 : 59|5@1+ (1,0) [0|31] ""  PC

BO_ 2334326645 S2A_SUMDATA22__53: 8 SBMU
 SG_ S2A_PCBMaxTemp_53 : 0|8@1+ (1,-50) [-50|205] "℃"  PC
 SG_ S2A_PCBMinTemp_53 : 8|8@1+ (1,-50) [-50|205] "℃"  PC
 SG_ S2A_ChipPst_PCBMaxTemp_53 : 16|3@1+ (1,0) [0|7] ""  PC
 SG_ S2A_ChipPst_PCBMinTemp_53 : 19|3@1+ (1,0) [0|7] ""  PC
 SG_ S2A_CscPst_PCBMaxTemp_53 : 22|5@1+ (1,0) [0|31] ""  PC
 SG_ S2A_CscPst_PCBMinTemp_53 : 27|5@1+ (1,0) [0|31] ""  PC
 SG_ S2A_AFEMaxTemp_53 : 32|8@1+ (1,-50) [-50|205] "℃"  PC
 SG_ S2A_AFEMinTemp_53 : 40|8@1+ (1,-50) [-50|205] "℃"  PC
 SG_ S2A_ChipPst_AFEMaxTemp_53 : 48|3@1+ (1,0) [0|7] ""  PC
 SG_ S2A_ChipPst_AFEMinTemp_53 : 51|3@1+ (1,0) [0|7] ""  PC
 SG_ S2A_CscPst_AFEMaxTemp_53 : 54|5@1+ (1,0) [0|31] ""  PC
 SG_ S2A_CscPst_AFEMinTemp_53 : 59|5@1+ (1,0) [0|31] ""  PC

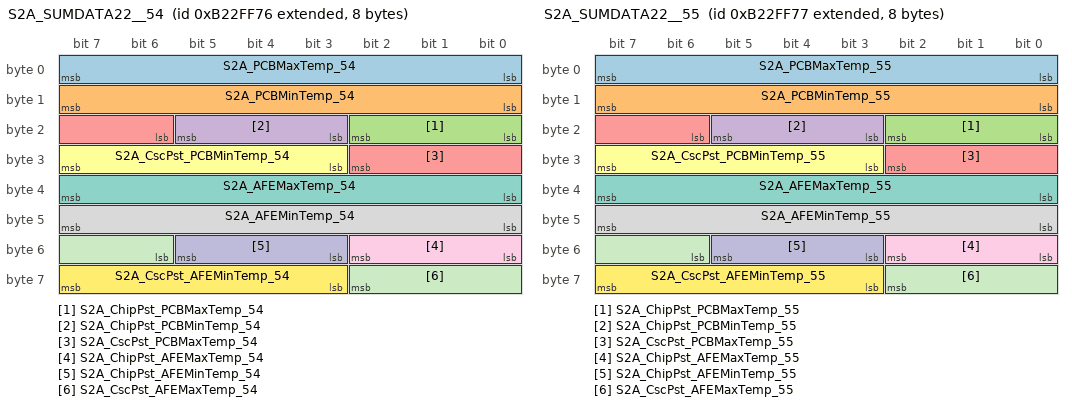
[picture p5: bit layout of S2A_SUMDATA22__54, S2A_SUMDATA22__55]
BO_ 2334326646 S2A_SUMDATA22__54: 8 SBMU
 SG_ S2A_PCBMaxTemp_54 : 0|8@1+ (1,-50) [-50|205] "℃"  PC
 SG_ S2A_PCBMinTemp_54 : 8|8@1+ (1,-50) [-50|205] "℃"  PC
 SG_ S2A_ChipPst_PCBMaxTemp_54 : 16|3@1+ (1,0) [0|7] ""  PC
 SG_ S2A_ChipPst_PCBMinTemp_54 : 19|3@1+ (1,0) [0|7] ""  PC
 SG_ S2A_CscPst_PCBMaxTemp_54 : 22|5@1+ (1,0) [0|31] ""  PC
 SG_ S2A_CscPst_PCBMinTemp_54 : 27|5@1+ (1,0) [0|31] ""  PC
 SG_ S2A_AFEMaxTemp_54 : 32|8@1+ (1,-50) [-50|205] "℃"  PC
 SG_ S2A_AFEMinTemp_54 : 40|8@1+ (1,-50) [-50|205] "℃"  PC
 SG_ S2A_ChipPst_AFEMaxTemp_54 : 48|3@1+ (1,0) [0|7] ""  PC
 SG_ S2A_ChipPst_AFEMinTemp_54 : 51|3@1+ (1,0) [0|7] ""  PC
 SG_ S2A_CscPst_AFEMaxTemp_54 : 54|5@1+ (1,0) [0|31] ""  PC
 SG_ S2A_CscPst_AFEMinTemp_54 : 59|5@1+ (1,0) [0|31] ""  PC

BO_ 2334326647 S2A_SUMDATA22__55: 8 SBMU
 SG_ S2A_PCBMaxTemp_55 : 0|8@1+ (1,-50) [-50|205] "℃"  PC
 SG_ S2A_PCBMinTemp_55 : 8|8@1+ (1,-50) [-50|205] "℃"  PC
 SG_ S2A_ChipPst_PCBMaxTemp_55 : 16|3@1+ (1,0) [0|7] ""  PC
 SG_ S2A_ChipPst_PCBMinTemp_55 : 19|3@1+ (1,0) [0|7] ""  PC
 SG_ S2A_CscPst_PCBMaxTemp_55 : 22|5@1+ (1,0) [0|31] ""  PC
 SG_ S2A_CscPst_PCBMinTemp_55 : 27|5@1+ (1,0) [0|31] ""  PC
 SG_ S2A_AFEMaxTemp_55 : 32|8@1+ (1,-50) [-50|205] "℃"  PC
 SG_ S2A_AFEMinTemp_55 : 40|8@1+ (1,-50) [-50|205] "℃"  PC
 SG_ S2A_ChipPst_AFEMaxTemp_55 : 48|3@1+ (1,0) [0|7] ""  PC
 SG_ S2A_ChipPst_AFEMinTemp_55 : 51|3@1+ (1,0) [0|7] ""  PC
 SG_ S2A_CscPst_AFEMaxTemp_55 : 54|5@1+ (1,0) [0|31] ""  PC
 SG_ S2A_CscPst_AFEMinTemp_55 : 59|5@1+ (1,0) [0|31] ""  PC

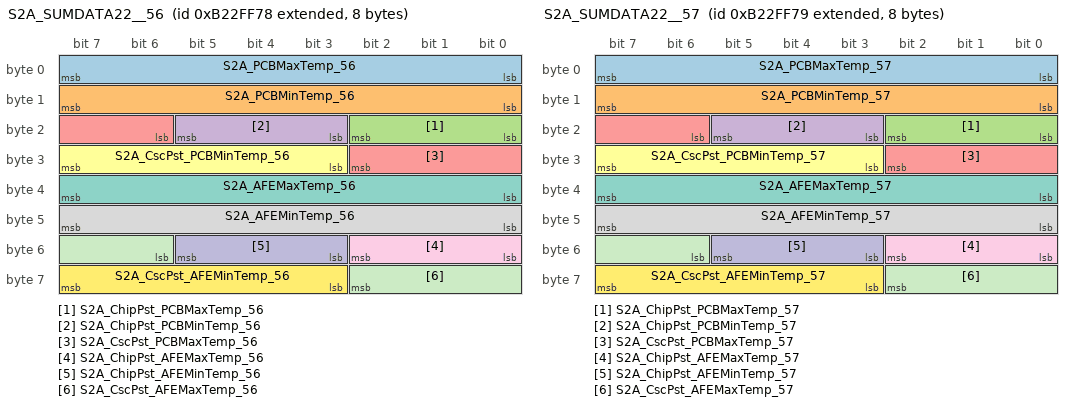
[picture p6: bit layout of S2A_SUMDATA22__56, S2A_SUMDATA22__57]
BO_ 2334326648 S2A_SUMDATA22__56: 8 SBMU
 SG_ S2A_PCBMaxTemp_56 : 0|8@1+ (1,-50) [-50|205] "℃"  PC
 SG_ S2A_PCBMinTemp_56 : 8|8@1+ (1,-50) [-50|205] "℃"  PC
 SG_ S2A_ChipPst_PCBMaxTemp_56 : 16|3@1+ (1,0) [0|7] ""  PC
 SG_ S2A_ChipPst_PCBMinTemp_56 : 19|3@1+ (1,0) [0|7] ""  PC
 SG_ S2A_CscPst_PCBMaxTemp_56 : 22|5@1+ (1,0) [0|31] ""  PC
 SG_ S2A_CscPst_PCBMinTemp_56 : 27|5@1+ (1,0) [0|31] ""  PC
 SG_ S2A_AFEMaxTemp_56 : 32|8@1+ (1,-50) [-50|205] "℃"  PC
 SG_ S2A_AFEMinTemp_56 : 40|8@1+ (1,-50) [-50|205] "℃"  PC
 SG_ S2A_ChipPst_AFEMaxTemp_56 : 48|3@1+ (1,0) [0|7] ""  PC
 SG_ S2A_ChipPst_AFEMinTemp_56 : 51|3@1+ (1,0) [0|7] ""  PC
 SG_ S2A_CscPst_AFEMaxTemp_56 : 54|5@1+ (1,0) [0|31] ""  PC
 SG_ S2A_CscPst_AFEMinTemp_56 : 59|5@1+ (1,0) [0|31] ""  PC

BO_ 2334326649 S2A_SUMDATA22__57: 8 SBMU
 SG_ S2A_PCBMaxTemp_57 : 0|8@1+ (1,-50) [-50|205] "℃"  PC
 SG_ S2A_PCBMinTemp_57 : 8|8@1+ (1,-50) [-50|205] "℃"  PC
 SG_ S2A_ChipPst_PCBMaxTemp_57 : 16|3@1+ (1,0) [0|7] ""  PC
 SG_ S2A_ChipPst_PCBMinTemp_57 : 19|3@1+ (1,0) [0|7] ""  PC
 SG_ S2A_CscPst_PCBMaxTemp_57 : 22|5@1+ (1,0) [0|31] ""  PC
 SG_ S2A_CscPst_PCBMinTemp_57 : 27|5@1+ (1,0) [0|31] ""  PC
 SG_ S2A_AFEMaxTemp_57 : 32|8@1+ (1,-50) [-50|205] "℃"  PC
 SG_ S2A_AFEMinTemp_57 : 40|8@1+ (1,-50) [-50|205] "℃"  PC
 SG_ S2A_ChipPst_AFEMaxTemp_57 : 48|3@1+ (1,0) [0|7] ""  PC
 SG_ S2A_ChipPst_AFEMinTemp_57 : 51|3@1+ (1,0) [0|7] ""  PC
 SG_ S2A_CscPst_AFEMaxTemp_57 : 54|5@1+ (1,0) [0|31] ""  PC
 SG_ S2A_CscPst_AFEMinTemp_57 : 59|5@1+ (1,0) [0|31] ""  PC

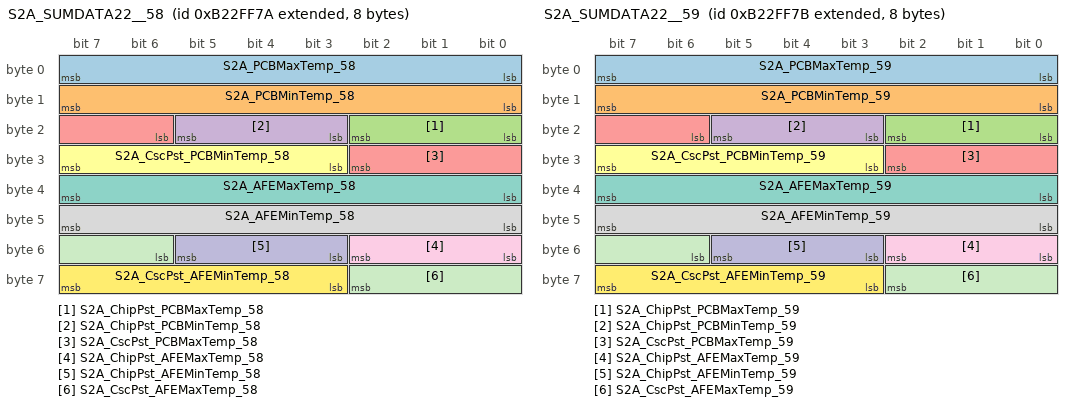
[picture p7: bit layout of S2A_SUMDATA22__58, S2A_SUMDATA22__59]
BO_ 2334326650 S2A_SUMDATA22__58: 8 SBMU
 SG_ S2A_PCBMaxTemp_58 : 0|8@1+ (1,-50) [-50|205] "℃"  PC
 SG_ S2A_PCBMinTemp_58 : 8|8@1+ (1,-50) [-50|205] "℃"  PC
 SG_ S2A_ChipPst_PCBMaxTemp_58 : 16|3@1+ (1,0) [0|7] ""  PC
 SG_ S2A_ChipPst_PCBMinTemp_58 : 19|3@1+ (1,0) [0|7] ""  PC
 SG_ S2A_CscPst_PCBMaxTemp_58 : 22|5@1+ (1,0) [0|31] ""  PC
 SG_ S2A_CscPst_PCBMinTemp_58 : 27|5@1+ (1,0) [0|31] ""  PC
 SG_ S2A_AFEMaxTemp_58 : 32|8@1+ (1,-50) [-50|205] "℃"  PC
 SG_ S2A_AFEMinTemp_58 : 40|8@1+ (1,-50) [-50|205] "℃"  PC
 SG_ S2A_ChipPst_AFEMaxTemp_58 : 48|3@1+ (1,0) [0|7] ""  PC
 SG_ S2A_ChipPst_AFEMinTemp_58 : 51|3@1+ (1,0) [0|7] ""  PC
 SG_ S2A_CscPst_AFEMaxTemp_58 : 54|5@1+ (1,0) [0|31] ""  PC
 SG_ S2A_CscPst_AFEMinTemp_58 : 59|5@1+ (1,0) [0|31] ""  PC

BO_ 2334326651 S2A_SUMDATA22__59: 8 SBMU
 SG_ S2A_PCBMaxTemp_59 : 0|8@1+ (1,-50) [-50|205] "℃"  PC
 SG_ S2A_PCBMinTemp_59 : 8|8@1+ (1,-50) [-50|205] "℃"  PC
 SG_ S2A_ChipPst_PCBMaxTemp_59 : 16|3@1+ (1,0) [0|7] ""  PC
 SG_ S2A_ChipPst_PCBMinTemp_59 : 19|3@1+ (1,0) [0|7] ""  PC
 SG_ S2A_CscPst_PCBMaxTemp_59 : 22|5@1+ (1,0) [0|31] ""  PC
 SG_ S2A_CscPst_PCBMinTemp_59 : 27|5@1+ (1,0) [0|31] ""  PC
 SG_ S2A_AFEMaxTemp_59 : 32|8@1+ (1,-50) [-50|205] "℃"  PC
 SG_ S2A_AFEMinTemp_59 : 40|8@1+ (1,-50) [-50|205] "℃"  PC
 SG_ S2A_ChipPst_AFEMaxTemp_59 : 48|3@1+ (1,0) [0|7] ""  PC
 SG_ S2A_ChipPst_AFEMinTemp_59 : 51|3@1+ (1,0) [0|7] ""  PC
 SG_ S2A_CscPst_AFEMaxTemp_59 : 54|5@1+ (1,0) [0|31] ""  PC
 SG_ S2A_CscPst_AFEMinTemp_59 : 59|5@1+ (1,0) [0|31] ""  PC

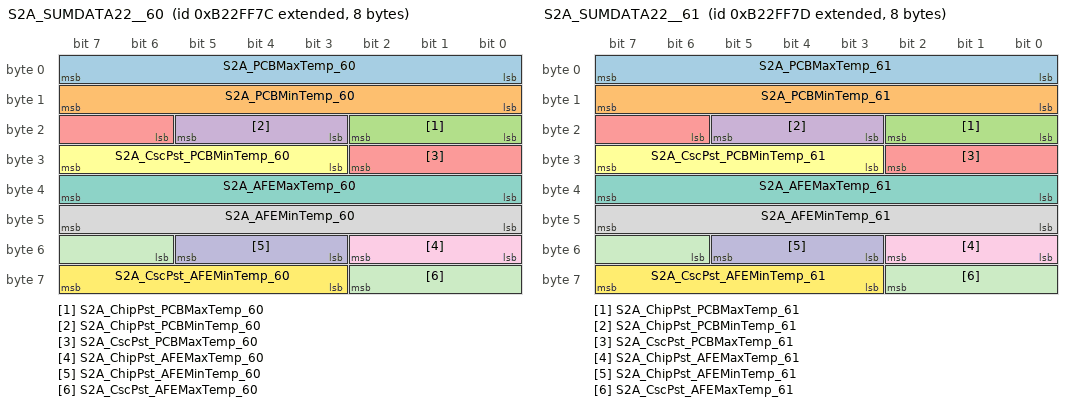
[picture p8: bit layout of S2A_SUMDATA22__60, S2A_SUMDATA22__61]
BO_ 2334326652 S2A_SUMDATA22__60: 8 SBMU
 SG_ S2A_PCBMaxTemp_60 : 0|8@1+ (1,-50) [-50|205] "℃"  PC
 SG_ S2A_PCBMinTemp_60 : 8|8@1+ (1,-50) [-50|205] "℃"  PC
 SG_ S2A_ChipPst_PCBMaxTemp_60 : 16|3@1+ (1,0) [0|7] ""  PC
 SG_ S2A_ChipPst_PCBMinTemp_60 : 19|3@1+ (1,0) [0|7] ""  PC
 SG_ S2A_CscPst_PCBMaxTemp_60 : 22|5@1+ (1,0) [0|31] ""  PC
 SG_ S2A_CscPst_PCBMinTemp_60 : 27|5@1+ (1,0) [0|31] ""  PC
 SG_ S2A_AFEMaxTemp_60 : 32|8@1+ (1,-50) [-50|205] "℃"  PC
 SG_ S2A_AFEMinTemp_60 : 40|8@1+ (1,-50) [-50|205] "℃"  PC
 SG_ S2A_ChipPst_AFEMaxTemp_60 : 48|3@1+ (1,0) [0|7] ""  PC
 SG_ S2A_ChipPst_AFEMinTemp_60 : 51|3@1+ (1,0) [0|7] ""  PC
 SG_ S2A_CscPst_AFEMaxTemp_60 : 54|5@1+ (1,0) [0|31] ""  PC
 SG_ S2A_CscPst_AFEMinTemp_60 : 59|5@1+ (1,0) [0|31] ""  PC

BO_ 2334326653 S2A_SUMDATA22__61: 8 SBMU
 SG_ S2A_PCBMaxTemp_61 : 0|8@1+ (1,-50) [-50|205] "℃"  PC
 SG_ S2A_PCBMinTemp_61 : 8|8@1+ (1,-50) [-50|205] "℃"  PC
 SG_ S2A_ChipPst_PCBMaxTemp_61 : 16|3@1+ (1,0) [0|7] ""  PC
 SG_ S2A_ChipPst_PCBMinTemp_61 : 19|3@1+ (1,0) [0|7] ""  PC
 SG_ S2A_CscPst_PCBMaxTemp_61 : 22|5@1+ (1,0) [0|31] ""  PC
 SG_ S2A_CscPst_PCBMinTemp_61 : 27|5@1+ (1,0) [0|31] ""  PC
 SG_ S2A_AFEMaxTemp_61 : 32|8@1+ (1,-50) [-50|205] "℃"  PC
 SG_ S2A_AFEMinTemp_61 : 40|8@1+ (1,-50) [-50|205] "℃"  PC
 SG_ S2A_ChipPst_AFEMaxTemp_61 : 48|3@1+ (1,0) [0|7] ""  PC
 SG_ S2A_ChipPst_AFEMinTemp_61 : 51|3@1+ (1,0) [0|7] ""  PC
 SG_ S2A_CscPst_AFEMaxTemp_61 : 54|5@1+ (1,0) [0|31] ""  PC
 SG_ S2A_CscPst_AFEMinTemp_61 : 59|5@1+ (1,0) [0|31] ""  PC

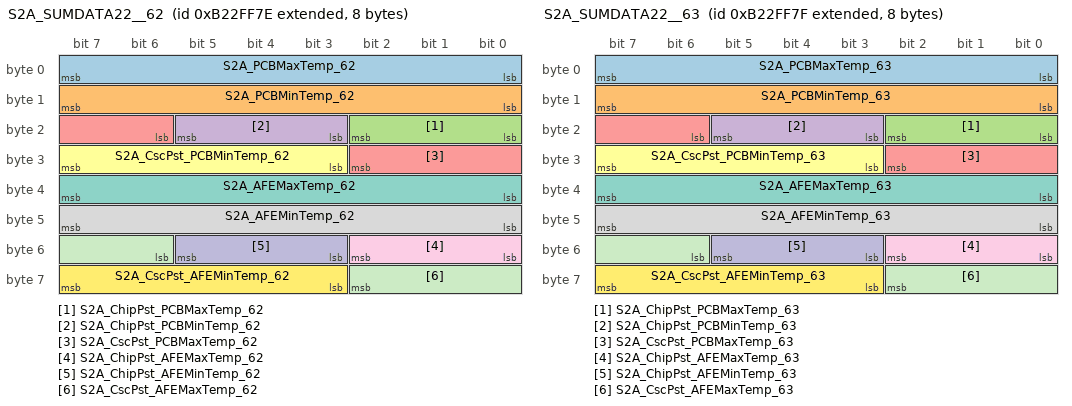
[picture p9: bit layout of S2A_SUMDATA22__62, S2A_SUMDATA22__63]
BO_ 2334326654 S2A_SUMDATA22__62: 8 SBMU
 SG_ S2A_PCBMaxTemp_62 : 0|8@1+ (1,-50) [-50|205] "℃"  PC
 SG_ S2A_PCBMinTemp_62 : 8|8@1+ (1,-50) [-50|205] "℃"  PC
 SG_ S2A_ChipPst_PCBMaxTemp_62 : 16|3@1+ (1,0) [0|7] ""  PC
 SG_ S2A_ChipPst_PCBMinTemp_62 : 19|3@1+ (1,0) [0|7] ""  PC
 SG_ S2A_CscPst_PCBMaxTemp_62 : 22|5@1+ (1,0) [0|31] ""  PC
 SG_ S2A_CscPst_PCBMinTemp_62 : 27|5@1+ (1,0) [0|31] ""  PC
 SG_ S2A_AFEMaxTemp_62 : 32|8@1+ (1,-50) [-50|205] "℃"  PC
 SG_ S2A_AFEMinTemp_62 : 40|8@1+ (1,-50) [-50|205] "℃"  PC
 SG_ S2A_ChipPst_AFEMaxTemp_62 : 48|3@1+ (1,0) [0|7] ""  PC
 SG_ S2A_ChipPst_AFEMinTemp_62 : 51|3@1+ (1,0) [0|7] ""  PC
 SG_ S2A_CscPst_AFEMaxTemp_62 : 54|5@1+ (1,0) [0|31] ""  PC
 SG_ S2A_CscPst_AFEMinTemp_62 : 59|5@1+ (1,0) [0|31] ""  PC

BO_ 2334326655 S2A_SUMDATA22__63: 8 SBMU
 SG_ S2A_PCBMaxTemp_63 : 0|8@1+ (1,-50) [-50|205] "℃"  PC
 SG_ S2A_PCBMinTemp_63 : 8|8@1+ (1,-50) [-50|205] "℃"  PC
 SG_ S2A_ChipPst_PCBMaxTemp_63 : 16|3@1+ (1,0) [0|7] ""  PC
 SG_ S2A_ChipPst_PCBMinTemp_63 : 19|3@1+ (1,0) [0|7] ""  PC
 SG_ S2A_CscPst_PCBMaxTemp_63 : 22|5@1+ (1,0) [0|31] ""  PC
 SG_ S2A_CscPst_PCBMinTemp_63 : 27|5@1+ (1,0) [0|31] ""  PC
 SG_ S2A_AFEMaxTemp_63 : 32|8@1+ (1,-50) [-50|205] "℃"  PC
 SG_ S2A_AFEMinTemp_63 : 40|8@1+ (1,-50) [-50|205] "℃"  PC
 SG_ S2A_ChipPst_AFEMaxTemp_63 : 48|3@1+ (1,0) [0|7] ""  PC
 SG_ S2A_ChipPst_AFEMinTemp_63 : 51|3@1+ (1,0) [0|7] ""  PC
 SG_ S2A_CscPst_AFEMaxTemp_63 : 54|5@1+ (1,0) [0|31] ""  PC
 SG_ S2A_CscPst_AFEMinTemp_63 : 59|5@1+ (1,0) [0|31] ""  PC

BO_ 2400841281 S2P_Detail_Ucell20__01: 8 SBMU
 SG_ CSC_U_No_01 : 0|8@1+ (1,0) [0|255] ""  PC
 SG_ CSC_Ucell_Frame_Index_01 M : 8|8@1+ (1,0) [0|255] ""  PC
 SG_ CSC_Ucell_58_01 m0 : 16|16@1+ (1,0) [0|65535] "mV"  PC
 SG_ CSC_Ucell_59_01 m0 : 32|16@1+ (1,0) [0|65535] "mV"  PC
 SG_ CSC_Ucell_60_01 m0 : 48|16@1+ (1,0) [0|65535] "mV"  PC
 SG_ CSC_Ucell_61_01 m1 : 16|16@1+ (1,0) [0|65535] "mV"  PC
 SG_ CSC_Ucell_62_01 m1 : 32|16@1+ (1,0) [0|65535] "mV"  PC
 SG_ CSC_Ucell_63_01 m1 : 48|16@1+ (1,0) [0|65535] "mV"  PC
 SG_ CSC_Ucell_64_01 m2 : 16|16@1+ (1,0) [0|65535] "mV"  PC
 SG_ CSC_Ucell_65_01 m2 : 32|16@1+ (1,0) [0|65535] "mV"  PC
 SG_ CSC_Ucell_66_01 m2 : 48|16@1+ (1,0) [0|65535] "mV"  PC
 SG_ CSC_Ucell_67_01 m3 : 16|16@1+ (1,0) [0|65535] "mV"  PC
 SG_ CSC_Ucell_68_01 m3 : 32|16@1+ (1,0) [0|65535] "mV"  PC
 SG_ CSC_Ucell_69_01 m3 : 48|16@1+ (1,0) [0|65535] "mV"  PC
 SG_ CSC_Ucell_70_01 m4 : 16|16@1+ (1,0) [0|65535] "mV"  PC
 SG_ CSC_Ucell_71_01 m4 : 32|16@1+ (1,0) [0|65535] "mV"  PC
 SG_ CSC_Ucell_72_01 m4 : 48|16@1+ (1,0) [0|65535] "mV"  PC
 SG_ CSC_Ucell_73_01 m5 : 16|16@1+ (1,0) [0|65535] "mV"  PC
 SG_ CSC_Ucell_74_01 m5 : 32|16@1+ (1,0) [0|65535] "mV"  PC
 SG_ CSC_Ucell_75_01 m5 : 48|16@1+ (1,0) [0|65535] "mV"  PC
 SG_ CSC_Ucell_76_01 m6 : 16|16@1+ (1,0) [0|65535] "mV"  PC
 SG_ CSC_Ucell_77_01 m6 : 32|16@1+ (1,0) [0|65535] "mV"  PC
 SG_ CSC_Ucell_78_01 m6 : 48|16@1+ (1,0) [0|65535] "mV"  PC
 SG_ CSC_Ucell_79_01 m7 : 16|16@1+ (1,0) [0|65535] "mV"  PC
 SG_ CSC_Ucell_80_01 m7 : 32|16@1+ (1,0) [0|65535] "mV"  PC
 SG_ CSC_Ucell_81_01 m7 : 48|16@1+ (1,0) [0|65535] "mV"  PC
 SG_ CSC_Ucell_82_01 m8 : 16|16@1+ (1,0) [0|65535] "mV"  PC
 SG_ CSC_Ucell_83_01 m8 : 32|16@1+ (1,0) [0|65535] "mV"  PC
 SG_ CSC_Ucell_84_01 m8 : 48|16@1+ (1,0) [0|65535] "mV"  PC
 SG_ CSC_Ucell_85_01 m9 : 16|16@1+ (1,0) [0|65535] "mV"  PC
 SG_ CSC_Ucell_86_01 m9 : 32|16@1+ (1,0) [0|65535] "mV"  PC
 SG_ CSC_Ucell_87_01 m9 : 48|16@1+ (1,0) [0|65535] "mV"  PC
 SG_ CSC_Ucell_88_01 m10 : 16|16@1+ (1,0) [0|65535] "mV"  PC
 SG_ CSC_Ucell_89_01 m10 : 32|16@1+ (1,0) [0|65535] "mV"  PC
 SG_ CSC_Ucell_90_01 m10 : 48|16@1+ (1,0) [0|65535] "mV"  PC
 SG_ CSC_Ucell_91_01 m11 : 16|16@1+ (1,0) [0|65535] "mV"  PC
 SG_ CSC_Ucell_92_01 m11 : 32|16@1+ (1,0) [0|65535] "mV"  PC
 SG_ CSC_Ucell_93_01 m11 : 48|16@1+ (1,0) [0|65535] "mV"  PC
 SG_ CSC_Ucell_94_01 m12 : 16|16@1+ (1,0) [0|65535] "mV"  PC
 SG_ CSC_Ucell_95_01 m12 : 32|16@1+ (1,0) [0|65535] "mV"  PC
 SG_ CSC_Ucell_96_01 m12 : 48|16@1+ (1,0) [0|65535] "mV"  PC
 SG_ CSC_Ucell_97_01 m13 : 16|16@1+ (1,0) [0|65535] "mV"  PC
 SG_ CSC_Ucell_98_01 m13 : 32|16@1+ (1,0) [0|65535] "mV"  PC
 SG_ CSC_Ucell_99_01 m13 : 48|16@1+ (1,0) [0|65535] "mV"  PC
 SG_ CSC_Ucell_100_01 m14 : 16|16@1+ (1,0) [0|65535] "mV"  PC
 SG_ CSC_Ucell_101_01 m14 : 32|16@1+ (1,0) [0|65535] "mV"  PC
 SG_ CSC_Ucell_102_01 m14 : 48|16@1+ (1,0) [0|65535] "mV"  PC
 SG_ CSC_Ucell_103_01 m15 : 16|16@1+ (1,0) [0|65535] "mV"  PC
 SG_ CSC_Ucell_104_01 m15 : 32|16@1+ (1,0) [0|65535] "mV"  PC
 SG_ CSC_Ucell_105_01 m15 : 48|16@1+ (1,0) [0|65535] "mV"  PC
 SG_ CSC_Ucell_106_01 m16 : 16|16@1+ (1,0) [0|65535] "mV"  PC
 SG_ CSC_Ucell_107_01 m16 : 32|16@1+ (1,0) [0|65535] "mV"  PC
 SG_ CSC_Ucell_108_01 m16 : 48|16@1+ (1,0) [0|65535] "mV"  PC

BO_ 2400841282 S2P_Detail_Ucell20__02: 8 SBMU
 SG_ CSC_U_No_02 : 0|8@1+ (1,0) [0|255] ""  PC
 SG_ CSC_Ucell_Frame_Index_02 M : 8|8@1+ (1,0) [0|255] ""  PC
 SG_ CSC_Ucell_58_02 m0 : 16|16@1+ (1,0) [0|65535] "mV"  PC
 SG_ CSC_Ucell_59_02 m0 : 32|16@1+ (1,0) [0|65535] "mV"  PC
 SG_ CSC_Ucell_60_02 m0 : 48|16@1+ (1,0) [0|65535] "mV"  PC
 SG_ CSC_Ucell_61_02 m1 : 16|16@1+ (1,0) [0|65535] "mV"  PC
 SG_ CSC_Ucell_62_02 m1 : 32|16@1+ (1,0) [0|65535] "mV"  PC
 SG_ CSC_Ucell_63_02 m1 : 48|16@1+ (1,0) [0|65535] "mV"  PC
 SG_ CSC_Ucell_64_02 m2 : 16|16@1+ (1,0) [0|65535] "mV"  PC
 SG_ CSC_Ucell_65_02 m2 : 32|16@1+ (1,0) [0|65535] "mV"  PC
 SG_ CSC_Ucell_66_02 m2 : 48|16@1+ (1,0) [0|65535] "mV"  PC
 SG_ CSC_Ucell_67_02 m3 : 16|16@1+ (1,0) [0|65535] "mV"  PC
 SG_ CSC_Ucell_68_02 m3 : 32|16@1+ (1,0) [0|65535] "mV"  PC
 SG_ CSC_Ucell_69_02 m3 : 48|16@1+ (1,0) [0|65535] "mV"  PC
 SG_ CSC_Ucell_70_02 m4 : 16|16@1+ (1,0) [0|65535] "mV"  PC
 SG_ CSC_Ucell_71_02 m4 : 32|16@1+ (1,0) [0|65535] "mV"  PC
 SG_ CSC_Ucell_72_02 m4 : 48|16@1+ (1,0) [0|65535] "mV"  PC
 SG_ CSC_Ucell_73_02 m5 : 16|16@1+ (1,0) [0|65535] "mV"  PC
 SG_ CSC_Ucell_74_02 m5 : 32|16@1+ (1,0) [0|65535] "mV"  PC
 SG_ CSC_Ucell_75_02 m5 : 48|16@1+ (1,0) [0|65535] "mV"  PC
 SG_ CSC_Ucell_76_02 m6 : 16|16@1+ (1,0) [0|65535] "mV"  PC
 SG_ CSC_Ucell_77_02 m6 : 32|16@1+ (1,0) [0|65535] "mV"  PC
 SG_ CSC_Ucell_78_02 m6 : 48|16@1+ (1,0) [0|65535] "mV"  PC
 SG_ CSC_Ucell_79_02 m7 : 16|16@1+ (1,0) [0|65535] "mV"  PC
 SG_ CSC_Ucell_80_02 m7 : 32|16@1+ (1,0) [0|65535] "mV"  PC
 SG_ CSC_Ucell_81_02 m7 : 48|16@1+ (1,0) [0|65535] "mV"  PC
 SG_ CSC_Ucell_82_02 m8 : 16|16@1+ (1,0) [0|65535] "mV"  PC
 SG_ CSC_Ucell_83_02 m8 : 32|16@1+ (1,0) [0|65535] "mV"  PC
 SG_ CSC_Ucell_84_02 m8 : 48|16@1+ (1,0) [0|65535] "mV"  PC
 SG_ CSC_Ucell_85_02 m9 : 16|16@1+ (1,0) [0|65535] "mV"  PC
 SG_ CSC_Ucell_86_02 m9 : 32|16@1+ (1,0) [0|65535] "mV"  PC
 SG_ CSC_Ucell_87_02 m9 : 48|16@1+ (1,0) [0|65535] "mV"  PC
 SG_ CSC_Ucell_88_02 m10 : 16|16@1+ (1,0) [0|65535] "mV"  PC
 SG_ CSC_Ucell_89_02 m10 : 32|16@1+ (1,0) [0|65535] "mV"  PC
 SG_ CSC_Ucell_90_02 m10 : 48|16@1+ (1,0) [0|65535] "mV"  PC
 SG_ CSC_Ucell_91_02 m11 : 16|16@1+ (1,0) [0|65535] "mV"  PC
 SG_ CSC_Ucell_92_02 m11 : 32|16@1+ (1,0) [0|65535] "mV"  PC
 SG_ CSC_Ucell_93_02 m11 : 48|16@1+ (1,0) [0|65535] "mV"  PC
 SG_ CSC_Ucell_94_02 m12 : 16|16@1+ (1,0) [0|65535] "mV"  PC
 SG_ CSC_Ucell_95_02 m12 : 32|16@1+ (1,0) [0|65535] "mV"  PC
 SG_ CSC_Ucell_96_02 m12 : 48|16@1+ (1,0) [0|65535] "mV"  PC
 SG_ CSC_Ucell_97_02 m13 : 16|16@1+ (1,0) [0|65535] "mV"  PC
 SG_ CSC_Ucell_98_02 m13 : 32|16@1+ (1,0) [0|65535] "mV"  PC
 SG_ CSC_Ucell_99_02 m13 : 48|16@1+ (1,0) [0|65535] "mV"  PC
 SG_ CSC_Ucell_100_02 m14 : 16|16@1+ (1,0) [0|65535] "mV"  PC
 SG_ CSC_Ucell_101_02 m14 : 32|16@1+ (1,0) [0|65535] "mV"  PC
 SG_ CSC_Ucell_102_02 m14 : 48|16@1+ (1,0) [0|65535] "mV"  PC
 SG_ CSC_Ucell_103_02 m15 : 16|16@1+ (1,0) [0|65535] "mV"  PC
 SG_ CSC_Ucell_104_02 m15 : 32|16@1+ (1,0) [0|65535] "mV"  PC
 SG_ CSC_Ucell_105_02 m15 : 48|16@1+ (1,0) [0|65535] "mV"  PC
 SG_ CSC_Ucell_106_02 m16 : 16|16@1+ (1,0) [0|65535] "mV"  PC
 SG_ CSC_Ucell_107_02 m16 : 32|16@1+ (1,0) [0|65535] "mV"  PC
 SG_ CSC_Ucell_108_02 m16 : 48|16@1+ (1,0) [0|65535] "mV"  PC

BO_ 2400841283 S2P_Detail_Ucell20__03: 8 SBMU
 SG_ CSC_U_No_03 : 0|8@1+ (1,0) [0|255] ""  PC
 SG_ CSC_Ucell_Frame_Index_03 M : 8|8@1+ (1,0) [0|255] ""  PC
 SG_ CSC_Ucell_58_03 m0 : 16|16@1+ (1,0) [0|65535] "mV"  PC
 SG_ CSC_Ucell_59_03 m0 : 32|16@1+ (1,0) [0|65535] "mV"  PC
 SG_ CSC_Ucell_60_03 m0 : 48|16@1+ (1,0) [0|65535] "mV"  PC
 SG_ CSC_Ucell_61_03 m1 : 16|16@1+ (1,0) [0|65535] "mV"  PC
 SG_ CSC_Ucell_62_03 m1 : 32|16@1+ (1,0) [0|65535] "mV"  PC
 SG_ CSC_Ucell_63_03 m1 : 48|16@1+ (1,0) [0|65535] "mV"  PC
 SG_ CSC_Ucell_64_03 m2 : 16|16@1+ (1,0) [0|65535] "mV"  PC
 SG_ CSC_Ucell_65_03 m2 : 32|16@1+ (1,0) [0|65535] "mV"  PC
 SG_ CSC_Ucell_66_03 m2 : 48|16@1+ (1,0) [0|65535] "mV"  PC
 SG_ CSC_Ucell_67_03 m3 : 16|16@1+ (1,0) [0|65535] "mV"  PC
 SG_ CSC_Ucell_68_03 m3 : 32|16@1+ (1,0) [0|65535] "mV"  PC
 SG_ CSC_Ucell_69_03 m3 : 48|16@1+ (1,0) [0|65535] "mV"  PC
 SG_ CSC_Ucell_70_03 m4 : 16|16@1+ (1,0) [0|65535] "mV"  PC
 SG_ CSC_Ucell_71_03 m4 : 32|16@1+ (1,0) [0|65535] "mV"  PC
 SG_ CSC_Ucell_72_03 m4 : 48|16@1+ (1,0) [0|65535] "mV"  PC
 SG_ CSC_Ucell_73_03 m5 : 16|16@1+ (1,0) [0|65535] "mV"  PC
 SG_ CSC_Ucell_74_03 m5 : 32|16@1+ (1,0) [0|65535] "mV"  PC
 SG_ CSC_Ucell_75_03 m5 : 48|16@1+ (1,0) [0|65535] "mV"  PC
 SG_ CSC_Ucell_76_03 m6 : 16|16@1+ (1,0) [0|65535] "mV"  PC
 SG_ CSC_Ucell_77_03 m6 : 32|16@1+ (1,0) [0|65535] "mV"  PC
 SG_ CSC_Ucell_78_03 m6 : 48|16@1+ (1,0) [0|65535] "mV"  PC
 SG_ CSC_Ucell_79_03 m7 : 16|16@1+ (1,0) [0|65535] "mV"  PC
 SG_ CSC_Ucell_80_03 m7 : 32|16@1+ (1,0) [0|65535] "mV"  PC
 SG_ CSC_Ucell_81_03 m7 : 48|16@1+ (1,0) [0|65535] "mV"  PC
 SG_ CSC_Ucell_82_03 m8 : 16|16@1+ (1,0) [0|65535] "mV"  PC
 SG_ CSC_Ucell_83_03 m8 : 32|16@1+ (1,0) [0|65535] "mV"  PC
 SG_ CSC_Ucell_84_03 m8 : 48|16@1+ (1,0) [0|65535] "mV"  PC
 SG_ CSC_Ucell_85_03 m9 : 16|16@1+ (1,0) [0|65535] "mV"  PC
 SG_ CSC_Ucell_86_03 m9 : 32|16@1+ (1,0) [0|65535] "mV"  PC
 SG_ CSC_Ucell_87_03 m9 : 48|16@1+ (1,0) [0|65535] "mV"  PC
 SG_ CSC_Ucell_88_03 m10 : 16|16@1+ (1,0) [0|65535] "mV"  PC
 SG_ CSC_Ucell_89_03 m10 : 32|16@1+ (1,0) [0|65535] "mV"  PC
 SG_ CSC_Ucell_90_03 m10 : 48|16@1+ (1,0) [0|65535] "mV"  PC
 SG_ CSC_Ucell_91_03 m11 : 16|16@1+ (1,0) [0|65535] "mV"  PC
 SG_ CSC_Ucell_92_03 m11 : 32|16@1+ (1,0) [0|65535] "mV"  PC
 SG_ CSC_Ucell_93_03 m11 : 48|16@1+ (1,0) [0|65535] "mV"  PC
 SG_ CSC_Ucell_94_03 m12 : 16|16@1+ (1,0) [0|65535] "mV"  PC
 SG_ CSC_Ucell_95_03 m12 : 32|16@1+ (1,0) [0|65535] "mV"  PC
 SG_ CSC_Ucell_96_03 m12 : 48|16@1+ (1,0) [0|65535] "mV"  PC
 SG_ CSC_Ucell_97_03 m13 : 16|16@1+ (1,0) [0|65535] "mV"  PC
 SG_ CSC_Ucell_98_03 m13 : 32|16@1+ (1,0) [0|65535] "mV"  PC
 SG_ CSC_Ucell_99_03 m13 : 48|16@1+ (1,0) [0|65535] "mV"  PC
 SG_ CSC_Ucell_100_03 m14 : 16|16@1+ (1,0) [0|65535] "mV"  PC
 SG_ CSC_Ucell_101_03 m14 : 32|16@1+ (1,0) [0|65535] "mV"  PC
 SG_ CSC_Ucell_102_03 m14 : 48|16@1+ (1,0) [0|65535] "mV"  PC
 SG_ CSC_Ucell_103_03 m15 : 16|16@1+ (1,0) [0|65535] "mV"  PC
 SG_ CSC_Ucell_104_03 m15 : 32|16@1+ (1,0) [0|65535] "mV"  PC
 SG_ CSC_Ucell_105_03 m15 : 48|16@1+ (1,0) [0|65535] "mV"  PC
 SG_ CSC_Ucell_106_03 m16 : 16|16@1+ (1,0) [0|65535] "mV"  PC
 SG_ CSC_Ucell_107_03 m16 : 32|16@1+ (1,0) [0|65535] "mV"  PC
 SG_ CSC_Ucell_108_03 m16 : 48|16@1+ (1,0) [0|65535] "mV"  PC

BO_ 2400841284 S2P_Detail_Ucell20__04: 8 SBMU
 SG_ CSC_U_No_04 : 0|8@1+ (1,0) [0|255] ""  PC
 SG_ CSC_Ucell_Frame_Index_04 M : 8|8@1+ (1,0) [0|255] ""  PC
 SG_ CSC_Ucell_58_04 m0 : 16|16@1+ (1,0) [0|65535] "mV"  PC
 SG_ CSC_Ucell_59_04 m0 : 32|16@1+ (1,0) [0|65535] "mV"  PC
 SG_ CSC_Ucell_60_04 m0 : 48|16@1+ (1,0) [0|65535] "mV"  PC
 SG_ CSC_Ucell_61_04 m1 : 16|16@1+ (1,0) [0|65535] "mV"  PC
 SG_ CSC_Ucell_62_04 m1 : 32|16@1+ (1,0) [0|65535] "mV"  PC
 SG_ CSC_Ucell_63_04 m1 : 48|16@1+ (1,0) [0|65535] "mV"  PC
 SG_ CSC_Ucell_64_04 m2 : 16|16@1+ (1,0) [0|65535] "mV"  PC
 SG_ CSC_Ucell_65_04 m2 : 32|16@1+ (1,0) [0|65535] "mV"  PC
 SG_ CSC_Ucell_66_04 m2 : 48|16@1+ (1,0) [0|65535] "mV"  PC
 SG_ CSC_Ucell_67_04 m3 : 16|16@1+ (1,0) [0|65535] "mV"  PC
 SG_ CSC_Ucell_68_04 m3 : 32|16@1+ (1,0) [0|65535] "mV"  PC
 SG_ CSC_Ucell_69_04 m3 : 48|16@1+ (1,0) [0|65535] "mV"  PC
 SG_ CSC_Ucell_70_04 m4 : 16|16@1+ (1,0) [0|65535] "mV"  PC
 SG_ CSC_Ucell_71_04 m4 : 32|16@1+ (1,0) [0|65535] "mV"  PC
 SG_ CSC_Ucell_72_04 m4 : 48|16@1+ (1,0) [0|65535] "mV"  PC
 SG_ CSC_Ucell_73_04 m5 : 16|16@1+ (1,0) [0|65535] "mV"  PC
 SG_ CSC_Ucell_74_04 m5 : 32|16@1+ (1,0) [0|65535] "mV"  PC
 SG_ CSC_Ucell_75_04 m5 : 48|16@1+ (1,0) [0|65535] "mV"  PC
 SG_ CSC_Ucell_76_04 m6 : 16|16@1+ (1,0) [0|65535] "mV"  PC
 SG_ CSC_Ucell_77_04 m6 : 32|16@1+ (1,0) [0|65535] "mV"  PC
 SG_ CSC_Ucell_78_04 m6 : 48|16@1+ (1,0) [0|65535] "mV"  PC
 SG_ CSC_Ucell_79_04 m7 : 16|16@1+ (1,0) [0|65535] "mV"  PC
 SG_ CSC_Ucell_80_04 m7 : 32|16@1+ (1,0) [0|65535] "mV"  PC
 SG_ CSC_Ucell_81_04 m7 : 48|16@1+ (1,0) [0|65535] "mV"  PC
 SG_ CSC_Ucell_82_04 m8 : 16|16@1+ (1,0) [0|65535] "mV"  PC
 SG_ CSC_Ucell_83_04 m8 : 32|16@1+ (1,0) [0|65535] "mV"  PC
 SG_ CSC_Ucell_84_04 m8 : 48|16@1+ (1,0) [0|65535] "mV"  PC
 SG_ CSC_Ucell_85_04 m9 : 16|16@1+ (1,0) [0|65535] "mV"  PC
 SG_ CSC_Ucell_86_04 m9 : 32|16@1+ (1,0) [0|65535] "mV"  PC
 SG_ CSC_Ucell_87_04 m9 : 48|16@1+ (1,0) [0|65535] "mV"  PC
 SG_ CSC_Ucell_88_04 m10 : 16|16@1+ (1,0) [0|65535] "mV"  PC
 SG_ CSC_Ucell_89_04 m10 : 32|16@1+ (1,0) [0|65535] "mV"  PC
 SG_ CSC_Ucell_90_04 m10 : 48|16@1+ (1,0) [0|65535] "mV"  PC
 SG_ CSC_Ucell_91_04 m11 : 16|16@1+ (1,0) [0|65535] "mV"  PC
 SG_ CSC_Ucell_92_04 m11 : 32|16@1+ (1,0) [0|65535] "mV"  PC
 SG_ CSC_Ucell_93_04 m11 : 48|16@1+ (1,0) [0|65535] "mV"  PC
 SG_ CSC_Ucell_94_04 m12 : 16|16@1+ (1,0) [0|65535] "mV"  PC
 SG_ CSC_Ucell_95_04 m12 : 32|16@1+ (1,0) [0|65535] "mV"  PC
 SG_ CSC_Ucell_96_04 m12 : 48|16@1+ (1,0) [0|65535] "mV"  PC
 SG_ CSC_Ucell_97_04 m13 : 16|16@1+ (1,0) [0|65535] "mV"  PC
 SG_ CSC_Ucell_98_04 m13 : 32|16@1+ (1,0) [0|65535] "mV"  PC
 SG_ CSC_Ucell_99_04 m13 : 48|16@1+ (1,0) [0|65535] "mV"  PC
 SG_ CSC_Ucell_100_04 m14 : 16|16@1+ (1,0) [0|65535] "mV"  PC
 SG_ CSC_Ucell_101_04 m14 : 32|16@1+ (1,0) [0|65535] "mV"  PC
 SG_ CSC_Ucell_102_04 m14 : 48|16@1+ (1,0) [0|65535] "mV"  PC
 SG_ CSC_Ucell_103_04 m15 : 16|16@1+ (1,0) [0|65535] "mV"  PC
 SG_ CSC_Ucell_104_04 m15 : 32|16@1+ (1,0) [0|65535] "mV"  PC
 SG_ CSC_Ucell_105_04 m15 : 48|16@1+ (1,0) [0|65535] "mV"  PC
 SG_ CSC_Ucell_106_04 m16 : 16|16@1+ (1,0) [0|65535] "mV"  PC
 SG_ CSC_Ucell_107_04 m16 : 32|16@1+ (1,0) [0|65535] "mV"  PC
 SG_ CSC_Ucell_108_04 m16 : 48|16@1+ (1,0) [0|65535] "mV"  PC

BO_ 2400841285 S2P_Detail_Ucell20__05: 8 SBMU
 SG_ CSC_U_No_05 : 0|8@1+ (1,0) [0|255] ""  PC
 SG_ CSC_Ucell_Frame_Index_05 M : 8|8@1+ (1,0) [0|255] ""  PC
 SG_ CSC_Ucell_58_05 m0 : 16|16@1+ (1,0) [0|65535] "mV"  PC
 SG_ CSC_Ucell_59_05 m0 : 32|16@1+ (1,0) [0|65535] "mV"  PC
 SG_ CSC_Ucell_60_05 m0 : 48|16@1+ (1,0) [0|65535] "mV"  PC
 SG_ CSC_Ucell_61_05 m1 : 16|16@1+ (1,0) [0|65535] "mV"  PC
 SG_ CSC_Ucell_62_05 m1 : 32|16@1+ (1,0) [0|65535] "mV"  PC
 SG_ CSC_Ucell_63_05 m1 : 48|16@1+ (1,0) [0|65535] "mV"  PC
 SG_ CSC_Ucell_64_05 m2 : 16|16@1+ (1,0) [0|65535] "mV"  PC
 SG_ CSC_Ucell_65_05 m2 : 32|16@1+ (1,0) [0|65535] "mV"  PC
 SG_ CSC_Ucell_66_05 m2 : 48|16@1+ (1,0) [0|65535] "mV"  PC
 SG_ CSC_Ucell_67_05 m3 : 16|16@1+ (1,0) [0|65535] "mV"  PC
 SG_ CSC_Ucell_68_05 m3 : 32|16@1+ (1,0) [0|65535] "mV"  PC
 SG_ CSC_Ucell_69_05 m3 : 48|16@1+ (1,0) [0|65535] "mV"  PC
 SG_ CSC_Ucell_70_05 m4 : 16|16@1+ (1,0) [0|65535] "mV"  PC
 SG_ CSC_Ucell_71_05 m4 : 32|16@1+ (1,0) [0|65535] "mV"  PC
 SG_ CSC_Ucell_72_05 m4 : 48|16@1+ (1,0) [0|65535] "mV"  PC
 SG_ CSC_Ucell_73_05 m5 : 16|16@1+ (1,0) [0|65535] "mV"  PC
 SG_ CSC_Ucell_74_05 m5 : 32|16@1+ (1,0) [0|65535] "mV"  PC
 SG_ CSC_Ucell_75_05 m5 : 48|16@1+ (1,0) [0|65535] "mV"  PC
 SG_ CSC_Ucell_76_05 m6 : 16|16@1+ (1,0) [0|65535] "mV"  PC
 SG_ CSC_Ucell_77_05 m6 : 32|16@1+ (1,0) [0|65535] "mV"  PC
 SG_ CSC_Ucell_78_05 m6 : 48|16@1+ (1,0) [0|65535] "mV"  PC
 SG_ CSC_Ucell_79_05 m7 : 16|16@1+ (1,0) [0|65535] "mV"  PC
 SG_ CSC_Ucell_80_05 m7 : 32|16@1+ (1,0) [0|65535] "mV"  PC
 SG_ CSC_Ucell_81_05 m7 : 48|16@1+ (1,0) [0|65535] "mV"  PC
 SG_ CSC_Ucell_82_05 m8 : 16|16@1+ (1,0) [0|65535] "mV"  PC
 SG_ CSC_Ucell_83_05 m8 : 32|16@1+ (1,0) [0|65535] "mV"  PC
 SG_ CSC_Ucell_84_05 m8 : 48|16@1+ (1,0) [0|65535] "mV"  PC
 SG_ CSC_Ucell_85_05 m9 : 16|16@1+ (1,0) [0|65535] "mV"  PC
 SG_ CSC_Ucell_86_05 m9 : 32|16@1+ (1,0) [0|65535] "mV"  PC
 SG_ CSC_Ucell_87_05 m9 : 48|16@1+ (1,0) [0|65535] "mV"  PC
 SG_ CSC_Ucell_88_05 m10 : 16|16@1+ (1,0) [0|65535] "mV"  PC
 SG_ CSC_Ucell_89_05 m10 : 32|16@1+ (1,0) [0|65535] "mV"  PC
 SG_ CSC_Ucell_90_05 m10 : 48|16@1+ (1,0) [0|65535] "mV"  PC
 SG_ CSC_Ucell_91_05 m11 : 16|16@1+ (1,0) [0|65535] "mV"  PC
 SG_ CSC_Ucell_92_05 m11 : 32|16@1+ (1,0) [0|65535] "mV"  PC
 SG_ CSC_Ucell_93_05 m11 : 48|16@1+ (1,0) [0|65535] "mV"  PC
 SG_ CSC_Ucell_94_05 m12 : 16|16@1+ (1,0) [0|65535] "mV"  PC
 SG_ CSC_Ucell_95_05 m12 : 32|16@1+ (1,0) [0|65535] "mV"  PC
 SG_ CSC_Ucell_96_05 m12 : 48|16@1+ (1,0) [0|65535] "mV"  PC
 SG_ CSC_Ucell_97_05 m13 : 16|16@1+ (1,0) [0|65535] "mV"  PC
 SG_ CSC_Ucell_98_05 m13 : 32|16@1+ (1,0) [0|65535] "mV"  PC
 SG_ CSC_Ucell_99_05 m13 : 48|16@1+ (1,0) [0|65535] "mV"  PC
 SG_ CSC_Ucell_100_05 m14 : 16|16@1+ (1,0) [0|65535] "mV"  PC
 SG_ CSC_Ucell_101_05 m14 : 32|16@1+ (1,0) [0|65535] "mV"  PC
 SG_ CSC_Ucell_102_05 m14 : 48|16@1+ (1,0) [0|65535] "mV"  PC
 SG_ CSC_Ucell_103_05 m15 : 16|16@1+ (1,0) [0|65535] "mV"  PC
 SG_ CSC_Ucell_104_05 m15 : 32|16@1+ (1,0) [0|65535] "mV"  PC
 SG_ CSC_Ucell_105_05 m15 : 48|16@1+ (1,0) [0|65535] "mV"  PC
 SG_ CSC_Ucell_106_05 m16 : 16|16@1+ (1,0) [0|65535] "mV"  PC
 SG_ CSC_Ucell_107_05 m16 : 32|16@1+ (1,0) [0|65535] "mV"  PC
 SG_ CSC_Ucell_108_05 m16 : 48|16@1+ (1,0) [0|65535] "mV"  PC

BO_ 2400841286 S2P_Detail_Ucell20__06: 8 SBMU
 SG_ CSC_U_No_06 : 0|8@1+ (1,0) [0|255] ""  PC
 SG_ CSC_Ucell_Frame_Index_06 M : 8|8@1+ (1,0) [0|255] ""  PC
 SG_ CSC_Ucell_58_06 m0 : 16|16@1+ (1,0) [0|65535] "mV"  PC
 SG_ CSC_Ucell_59_06 m0 : 32|16@1+ (1,0) [0|65535] "mV"  PC
 SG_ CSC_Ucell_60_06 m0 : 48|16@1+ (1,0) [0|65535] "mV"  PC
 SG_ CSC_Ucell_61_06 m1 : 16|16@1+ (1,0) [0|65535] "mV"  PC
 SG_ CSC_Ucell_62_06 m1 : 32|16@1+ (1,0) [0|65535] "mV"  PC
 SG_ CSC_Ucell_63_06 m1 : 48|16@1+ (1,0) [0|65535] "mV"  PC
 SG_ CSC_Ucell_64_06 m2 : 16|16@1+ (1,0) [0|65535] "mV"  PC
 SG_ CSC_Ucell_65_06 m2 : 32|16@1+ (1,0) [0|65535] "mV"  PC
 SG_ CSC_Ucell_66_06 m2 : 48|16@1+ (1,0) [0|65535] "mV"  PC
 SG_ CSC_Ucell_67_06 m3 : 16|16@1+ (1,0) [0|65535] "mV"  PC
 SG_ CSC_Ucell_68_06 m3 : 32|16@1+ (1,0) [0|65535] "mV"  PC
 SG_ CSC_Ucell_69_06 m3 : 48|16@1+ (1,0) [0|65535] "mV"  PC
 SG_ CSC_Ucell_70_06 m4 : 16|16@1+ (1,0) [0|65535] "mV"  PC
 SG_ CSC_Ucell_71_06 m4 : 32|16@1+ (1,0) [0|65535] "mV"  PC
 SG_ CSC_Ucell_72_06 m4 : 48|16@1+ (1,0) [0|65535] "mV"  PC
 SG_ CSC_Ucell_73_06 m5 : 16|16@1+ (1,0) [0|65535] "mV"  PC
 SG_ CSC_Ucell_74_06 m5 : 32|16@1+ (1,0) [0|65535] "mV"  PC
 SG_ CSC_Ucell_75_06 m5 : 48|16@1+ (1,0) [0|65535] "mV"  PC
 SG_ CSC_Ucell_76_06 m6 : 16|16@1+ (1,0) [0|65535] "mV"  PC
 SG_ CSC_Ucell_77_06 m6 : 32|16@1+ (1,0) [0|65535] "mV"  PC
 SG_ CSC_Ucell_78_06 m6 : 48|16@1+ (1,0) [0|65535] "mV"  PC
 SG_ CSC_Ucell_79_06 m7 : 16|16@1+ (1,0) [0|65535] "mV"  PC
 SG_ CSC_Ucell_80_06 m7 : 32|16@1+ (1,0) [0|65535] "mV"  PC
 SG_ CSC_Ucell_81_06 m7 : 48|16@1+ (1,0) [0|65535] "mV"  PC
 SG_ CSC_Ucell_82_06 m8 : 16|16@1+ (1,0) [0|65535] "mV"  PC
 SG_ CSC_Ucell_83_06 m8 : 32|16@1+ (1,0) [0|65535] "mV"  PC
 SG_ CSC_Ucell_84_06 m8 : 48|16@1+ (1,0) [0|65535] "mV"  PC
 SG_ CSC_Ucell_85_06 m9 : 16|16@1+ (1,0) [0|65535] "mV"  PC
 SG_ CSC_Ucell_86_06 m9 : 32|16@1+ (1,0) [0|65535] "mV"  PC
 SG_ CSC_Ucell_87_06 m9 : 48|16@1+ (1,0) [0|65535] "mV"  PC
 SG_ CSC_Ucell_88_06 m10 : 16|16@1+ (1,0) [0|65535] "mV"  PC
 SG_ CSC_Ucell_89_06 m10 : 32|16@1+ (1,0) [0|65535] "mV"  PC
 SG_ CSC_Ucell_90_06 m10 : 48|16@1+ (1,0) [0|65535] "mV"  PC
 SG_ CSC_Ucell_91_06 m11 : 16|16@1+ (1,0) [0|65535] "mV"  PC
 SG_ CSC_Ucell_92_06 m11 : 32|16@1+ (1,0) [0|65535] "mV"  PC
 SG_ CSC_Ucell_93_06 m11 : 48|16@1+ (1,0) [0|65535] "mV"  PC
 SG_ CSC_Ucell_94_06 m12 : 16|16@1+ (1,0) [0|65535] "mV"  PC
 SG_ CSC_Ucell_95_06 m12 : 32|16@1+ (1,0) [0|65535] "mV"  PC
 SG_ CSC_Ucell_96_06 m12 : 48|16@1+ (1,0) [0|65535] "mV"  PC
 SG_ CSC_Ucell_97_06 m13 : 16|16@1+ (1,0) [0|65535] "mV"  PC
 SG_ CSC_Ucell_98_06 m13 : 32|16@1+ (1,0) [0|65535] "mV"  PC
 SG_ CSC_Ucell_99_06 m13 : 48|16@1+ (1,0) [0|65535] "mV"  PC
 SG_ CSC_Ucell_100_06 m14 : 16|16@1+ (1,0) [0|65535] "mV"  PC
 SG_ CSC_Ucell_101_06 m14 : 32|16@1+ (1,0) [0|65535] "mV"  PC
 SG_ CSC_Ucell_102_06 m14 : 48|16@1+ (1,0) [0|65535] "mV"  PC
 SG_ CSC_Ucell_103_06 m15 : 16|16@1+ (1,0) [0|65535] "mV"  PC
 SG_ CSC_Ucell_104_06 m15 : 32|16@1+ (1,0) [0|65535] "mV"  PC
 SG_ CSC_Ucell_105_06 m15 : 48|16@1+ (1,0) [0|65535] "mV"  PC
 SG_ CSC_Ucell_106_06 m16 : 16|16@1+ (1,0) [0|65535] "mV"  PC
 SG_ CSC_Ucell_107_06 m16 : 32|16@1+ (1,0) [0|65535] "mV"  PC
 SG_ CSC_Ucell_108_06 m16 : 48|16@1+ (1,0) [0|65535] "mV"  PC

BO_ 2400841287 S2P_Detail_Ucell20__07: 8 SBMU
 SG_ CSC_U_No_07 : 0|8@1+ (1,0) [0|255] ""  PC
 SG_ CSC_Ucell_Frame_Index_07 M : 8|8@1+ (1,0) [0|255] ""  PC
 SG_ CSC_Ucell_58_07 m0 : 16|16@1+ (1,0) [0|65535] "mV"  PC
 SG_ CSC_Ucell_59_07 m0 : 32|16@1+ (1,0) [0|65535] "mV"  PC
 SG_ CSC_Ucell_60_07 m0 : 48|16@1+ (1,0) [0|65535] "mV"  PC
 SG_ CSC_Ucell_61_07 m1 : 16|16@1+ (1,0) [0|65535] "mV"  PC
 SG_ CSC_Ucell_62_07 m1 : 32|16@1+ (1,0) [0|65535] "mV"  PC
 SG_ CSC_Ucell_63_07 m1 : 48|16@1+ (1,0) [0|65535] "mV"  PC
 SG_ CSC_Ucell_64_07 m2 : 16|16@1+ (1,0) [0|65535] "mV"  PC
 SG_ CSC_Ucell_65_07 m2 : 32|16@1+ (1,0) [0|65535] "mV"  PC
 SG_ CSC_Ucell_66_07 m2 : 48|16@1+ (1,0) [0|65535] "mV"  PC
 SG_ CSC_Ucell_67_07 m3 : 16|16@1+ (1,0) [0|65535] "mV"  PC
 SG_ CSC_Ucell_68_07 m3 : 32|16@1+ (1,0) [0|65535] "mV"  PC
 SG_ CSC_Ucell_69_07 m3 : 48|16@1+ (1,0) [0|65535] "mV"  PC
 SG_ CSC_Ucell_70_07 m4 : 16|16@1+ (1,0) [0|65535] "mV"  PC
 SG_ CSC_Ucell_71_07 m4 : 32|16@1+ (1,0) [0|65535] "mV"  PC
 SG_ CSC_Ucell_72_07 m4 : 48|16@1+ (1,0) [0|65535] "mV"  PC
 SG_ CSC_Ucell_73_07 m5 : 16|16@1+ (1,0) [0|65535] "mV"  PC
 SG_ CSC_Ucell_74_07 m5 : 32|16@1+ (1,0) [0|65535] "mV"  PC
 SG_ CSC_Ucell_75_07 m5 : 48|16@1+ (1,0) [0|65535] "mV"  PC
 SG_ CSC_Ucell_76_07 m6 : 16|16@1+ (1,0) [0|65535] "mV"  PC
 SG_ CSC_Ucell_77_07 m6 : 32|16@1+ (1,0) [0|65535] "mV"  PC
 SG_ CSC_Ucell_78_07 m6 : 48|16@1+ (1,0) [0|65535] "mV"  PC
 SG_ CSC_Ucell_79_07 m7 : 16|16@1+ (1,0) [0|65535] "mV"  PC
 SG_ CSC_Ucell_80_07 m7 : 32|16@1+ (1,0) [0|65535] "mV"  PC
 SG_ CSC_Ucell_81_07 m7 : 48|16@1+ (1,0) [0|65535] "mV"  PC
 SG_ CSC_Ucell_82_07 m8 : 16|16@1+ (1,0) [0|65535] "mV"  PC
 SG_ CSC_Ucell_83_07 m8 : 32|16@1+ (1,0) [0|65535] "mV"  PC
 SG_ CSC_Ucell_84_07 m8 : 48|16@1+ (1,0) [0|65535] "mV"  PC
 SG_ CSC_Ucell_85_07 m9 : 16|16@1+ (1,0) [0|65535] "mV"  PC
 SG_ CSC_Ucell_86_07 m9 : 32|16@1+ (1,0) [0|65535] "mV"  PC
 SG_ CSC_Ucell_87_07 m9 : 48|16@1+ (1,0) [0|65535] "mV"  PC
 SG_ CSC_Ucell_88_07 m10 : 16|16@1+ (1,0) [0|65535] "mV"  PC
 SG_ CSC_Ucell_89_07 m10 : 32|16@1+ (1,0) [0|65535] "mV"  PC
 SG_ CSC_Ucell_90_07 m10 : 48|16@1+ (1,0) [0|65535] "mV"  PC
 SG_ CSC_Ucell_91_07 m11 : 16|16@1+ (1,0) [0|65535] "mV"  PC
 SG_ CSC_Ucell_92_07 m11 : 32|16@1+ (1,0) [0|65535] "mV"  PC
 SG_ CSC_Ucell_93_07 m11 : 48|16@1+ (1,0) [0|65535] "mV"  PC
 SG_ CSC_Ucell_94_07 m12 : 16|16@1+ (1,0) [0|65535] "mV"  PC
 SG_ CSC_Ucell_95_07 m12 : 32|16@1+ (1,0) [0|65535] "mV"  PC
 SG_ CSC_Ucell_96_07 m12 : 48|16@1+ (1,0) [0|65535] "mV"  PC
 SG_ CSC_Ucell_97_07 m13 : 16|16@1+ (1,0) [0|65535] "mV"  PC
 SG_ CSC_Ucell_98_07 m13 : 32|16@1+ (1,0) [0|65535] "mV"  PC
 SG_ CSC_Ucell_99_07 m13 : 48|16@1+ (1,0) [0|65535] "mV"  PC
 SG_ CSC_Ucell_100_07 m14 : 16|16@1+ (1,0) [0|65535] "mV"  PC
 SG_ CSC_Ucell_101_07 m14 : 32|16@1+ (1,0) [0|65535] "mV"  PC
 SG_ CSC_Ucell_102_07 m14 : 48|16@1+ (1,0) [0|65535] "mV"  PC
 SG_ CSC_Ucell_103_07 m15 : 16|16@1+ (1,0) [0|65535] "mV"  PC
 SG_ CSC_Ucell_104_07 m15 : 32|16@1+ (1,0) [0|65535] "mV"  PC
 SG_ CSC_Ucell_105_07 m15 : 48|16@1+ (1,0) [0|65535] "mV"  PC
 SG_ CSC_Ucell_106_07 m16 : 16|16@1+ (1,0) [0|65535] "mV"  PC
 SG_ CSC_Ucell_107_07 m16 : 32|16@1+ (1,0) [0|65535] "mV"  PC
 SG_ CSC_Ucell_108_07 m16 : 48|16@1+ (1,0) [0|65535] "mV"  PC

BO_ 2400841288 S2P_Detail_Ucell20__08: 8 SBMU
 SG_ CSC_U_No_08 : 0|8@1+ (1,0) [0|255] ""  PC
 SG_ CSC_Ucell_Frame_Index_08 M : 8|8@1+ (1,0) [0|255] ""  PC
 SG_ CSC_Ucell_58_08 m0 : 16|16@1+ (1,0) [0|65535] "mV"  PC
 SG_ CSC_Ucell_59_08 m0 : 32|16@1+ (1,0) [0|65535] "mV"  PC
 SG_ CSC_Ucell_60_08 m0 : 48|16@1+ (1,0) [0|65535] "mV"  PC
 SG_ CSC_Ucell_61_08 m1 : 16|16@1+ (1,0) [0|65535] "mV"  PC
 SG_ CSC_Ucell_62_08 m1 : 32|16@1+ (1,0) [0|65535] "mV"  PC
 SG_ CSC_Ucell_63_08 m1 : 48|16@1+ (1,0) [0|65535] "mV"  PC
 SG_ CSC_Ucell_64_08 m2 : 16|16@1+ (1,0) [0|65535] "mV"  PC
 SG_ CSC_Ucell_65_08 m2 : 32|16@1+ (1,0) [0|65535] "mV"  PC
 SG_ CSC_Ucell_66_08 m2 : 48|16@1+ (1,0) [0|65535] "mV"  PC
 SG_ CSC_Ucell_67_08 m3 : 16|16@1+ (1,0) [0|65535] "mV"  PC
 SG_ CSC_Ucell_68_08 m3 : 32|16@1+ (1,0) [0|65535] "mV"  PC
 SG_ CSC_Ucell_69_08 m3 : 48|16@1+ (1,0) [0|65535] "mV"  PC
 SG_ CSC_Ucell_70_08 m4 : 16|16@1+ (1,0) [0|65535] "mV"  PC
 SG_ CSC_Ucell_71_08 m4 : 32|16@1+ (1,0) [0|65535] "mV"  PC
 SG_ CSC_Ucell_72_08 m4 : 48|16@1+ (1,0) [0|65535] "mV"  PC
 SG_ CSC_Ucell_73_08 m5 : 16|16@1+ (1,0) [0|65535] "mV"  PC
 SG_ CSC_Ucell_74_08 m5 : 32|16@1+ (1,0) [0|65535] "mV"  PC
 SG_ CSC_Ucell_75_08 m5 : 48|16@1+ (1,0) [0|65535] "mV"  PC
 SG_ CSC_Ucell_76_08 m6 : 16|16@1+ (1,0) [0|65535] "mV"  PC
 SG_ CSC_Ucell_77_08 m6 : 32|16@1+ (1,0) [0|65535] "mV"  PC
 SG_ CSC_Ucell_78_08 m6 : 48|16@1+ (1,0) [0|65535] "mV"  PC
 SG_ CSC_Ucell_79_08 m7 : 16|16@1+ (1,0) [0|65535] "mV"  PC
 SG_ CSC_Ucell_80_08 m7 : 32|16@1+ (1,0) [0|65535] "mV"  PC
 SG_ CSC_Ucell_81_08 m7 : 48|16@1+ (1,0) [0|65535] "mV"  PC
 SG_ CSC_Ucell_82_08 m8 : 16|16@1+ (1,0) [0|65535] "mV"  PC
 SG_ CSC_Ucell_83_08 m8 : 32|16@1+ (1,0) [0|65535] "mV"  PC
 SG_ CSC_Ucell_84_08 m8 : 48|16@1+ (1,0) [0|65535] "mV"  PC
 SG_ CSC_Ucell_85_08 m9 : 16|16@1+ (1,0) [0|65535] "mV"  PC
 SG_ CSC_Ucell_86_08 m9 : 32|16@1+ (1,0) [0|65535] "mV"  PC
 SG_ CSC_Ucell_87_08 m9 : 48|16@1+ (1,0) [0|65535] "mV"  PC
 SG_ CSC_Ucell_88_08 m10 : 16|16@1+ (1,0) [0|65535] "mV"  PC
 SG_ CSC_Ucell_89_08 m10 : 32|16@1+ (1,0) [0|65535] "mV"  PC
 SG_ CSC_Ucell_90_08 m10 : 48|16@1+ (1,0) [0|65535] "mV"  PC
 SG_ CSC_Ucell_91_08 m11 : 16|16@1+ (1,0) [0|65535] "mV"  PC
 SG_ CSC_Ucell_92_08 m11 : 32|16@1+ (1,0) [0|65535] "mV"  PC
 SG_ CSC_Ucell_93_08 m11 : 48|16@1+ (1,0) [0|65535] "mV"  PC
 SG_ CSC_Ucell_94_08 m12 : 16|16@1+ (1,0) [0|65535] "mV"  PC
 SG_ CSC_Ucell_95_08 m12 : 32|16@1+ (1,0) [0|65535] "mV"  PC
 SG_ CSC_Ucell_96_08 m12 : 48|16@1+ (1,0) [0|65535] "mV"  PC
 SG_ CSC_Ucell_97_08 m13 : 16|16@1+ (1,0) [0|65535] "mV"  PC
 SG_ CSC_Ucell_98_08 m13 : 32|16@1+ (1,0) [0|65535] "mV"  PC
 SG_ CSC_Ucell_99_08 m13 : 48|16@1+ (1,0) [0|65535] "mV"  PC
 SG_ CSC_Ucell_100_08 m14 : 16|16@1+ (1,0) [0|65535] "mV"  PC
 SG_ CSC_Ucell_101_08 m14 : 32|16@1+ (1,0) [0|65535] "mV"  PC
 SG_ CSC_Ucell_102_08 m14 : 48|16@1+ (1,0) [0|65535] "mV"  PC
 SG_ CSC_Ucell_103_08 m15 : 16|16@1+ (1,0) [0|65535] "mV"  PC
 SG_ CSC_Ucell_104_08 m15 : 32|16@1+ (1,0) [0|65535] "mV"  PC
 SG_ CSC_Ucell_105_08 m15 : 48|16@1+ (1,0) [0|65535] "mV"  PC
 SG_ CSC_Ucell_106_08 m16 : 16|16@1+ (1,0) [0|65535] "mV"  PC
 SG_ CSC_Ucell_107_08 m16 : 32|16@1+ (1,0) [0|65535] "mV"  PC
 SG_ CSC_Ucell_108_08 m16 : 48|16@1+ (1,0) [0|65535] "mV"  PC

BO_ 2400841289 S2P_Detail_Ucell20__09: 8 SBMU
 SG_ CSC_U_No_09 : 0|8@1+ (1,0) [0|255] ""  PC
 SG_ CSC_Ucell_Frame_Index_09 M : 8|8@1+ (1,0) [0|255] ""  PC
 SG_ CSC_Ucell_58_09 m0 : 16|16@1+ (1,0) [0|65535] "mV"  PC
 SG_ CSC_Ucell_59_09 m0 : 32|16@1+ (1,0) [0|65535] "mV"  PC
 SG_ CSC_Ucell_60_09 m0 : 48|16@1+ (1,0) [0|65535] "mV"  PC
 SG_ CSC_Ucell_61_09 m1 : 16|16@1+ (1,0) [0|65535] "mV"  PC
 SG_ CSC_Ucell_62_09 m1 : 32|16@1+ (1,0) [0|65535] "mV"  PC
 SG_ CSC_Ucell_63_09 m1 : 48|16@1+ (1,0) [0|65535] "mV"  PC
 SG_ CSC_Ucell_64_09 m2 : 16|16@1+ (1,0) [0|65535] "mV"  PC
 SG_ CSC_Ucell_65_09 m2 : 32|16@1+ (1,0) [0|65535] "mV"  PC
 SG_ CSC_Ucell_66_09 m2 : 48|16@1+ (1,0) [0|65535] "mV"  PC
 SG_ CSC_Ucell_67_09 m3 : 16|16@1+ (1,0) [0|65535] "mV"  PC
 SG_ CSC_Ucell_68_09 m3 : 32|16@1+ (1,0) [0|65535] "mV"  PC
 SG_ CSC_Ucell_69_09 m3 : 48|16@1+ (1,0) [0|65535] "mV"  PC
 SG_ CSC_Ucell_70_09 m4 : 16|16@1+ (1,0) [0|65535] "mV"  PC
 SG_ CSC_Ucell_71_09 m4 : 32|16@1+ (1,0) [0|65535] "mV"  PC
 SG_ CSC_Ucell_72_09 m4 : 48|16@1+ (1,0) [0|65535] "mV"  PC
 SG_ CSC_Ucell_73_09 m5 : 16|16@1+ (1,0) [0|65535] "mV"  PC
 SG_ CSC_Ucell_74_09 m5 : 32|16@1+ (1,0) [0|65535] "mV"  PC
 SG_ CSC_Ucell_75_09 m5 : 48|16@1+ (1,0) [0|65535] "mV"  PC
 SG_ CSC_Ucell_76_09 m6 : 16|16@1+ (1,0) [0|65535] "mV"  PC
 SG_ CSC_Ucell_77_09 m6 : 32|16@1+ (1,0) [0|65535] "mV"  PC
 SG_ CSC_Ucell_78_09 m6 : 48|16@1+ (1,0) [0|65535] "mV"  PC
 SG_ CSC_Ucell_79_09 m7 : 16|16@1+ (1,0) [0|65535] "mV"  PC
 SG_ CSC_Ucell_80_09 m7 : 32|16@1+ (1,0) [0|65535] "mV"  PC
 SG_ CSC_Ucell_81_09 m7 : 48|16@1+ (1,0) [0|65535] "mV"  PC
 SG_ CSC_Ucell_82_09 m8 : 16|16@1+ (1,0) [0|65535] "mV"  PC
 SG_ CSC_Ucell_83_09 m8 : 32|16@1+ (1,0) [0|65535] "mV"  PC
 SG_ CSC_Ucell_84_09 m8 : 48|16@1+ (1,0) [0|65535] "mV"  PC
 SG_ CSC_Ucell_85_09 m9 : 16|16@1+ (1,0) [0|65535] "mV"  PC
 SG_ CSC_Ucell_86_09 m9 : 32|16@1+ (1,0) [0|65535] "mV"  PC
 SG_ CSC_Ucell_87_09 m9 : 48|16@1+ (1,0) [0|65535] "mV"  PC
 SG_ CSC_Ucell_88_09 m10 : 16|16@1+ (1,0) [0|65535] "mV"  PC
 SG_ CSC_Ucell_89_09 m10 : 32|16@1+ (1,0) [0|65535] "mV"  PC
 SG_ CSC_Ucell_90_09 m10 : 48|16@1+ (1,0) [0|65535] "mV"  PC
 SG_ CSC_Ucell_91_09 m11 : 16|16@1+ (1,0) [0|65535] "mV"  PC
 SG_ CSC_Ucell_92_09 m11 : 32|16@1+ (1,0) [0|65535] "mV"  PC
 SG_ CSC_Ucell_93_09 m11 : 48|16@1+ (1,0) [0|65535] "mV"  PC
 SG_ CSC_Ucell_94_09 m12 : 16|16@1+ (1,0) [0|65535] "mV"  PC
 SG_ CSC_Ucell_95_09 m12 : 32|16@1+ (1,0) [0|65535] "mV"  PC
 SG_ CSC_Ucell_96_09 m12 : 48|16@1+ (1,0) [0|65535] "mV"  PC
 SG_ CSC_Ucell_97_09 m13 : 16|16@1+ (1,0) [0|65535] "mV"  PC
 SG_ CSC_Ucell_98_09 m13 : 32|16@1+ (1,0) [0|65535] "mV"  PC
 SG_ CSC_Ucell_99_09 m13 : 48|16@1+ (1,0) [0|65535] "mV"  PC
 SG_ CSC_Ucell_100_09 m14 : 16|16@1+ (1,0) [0|65535] "mV"  PC
 SG_ CSC_Ucell_101_09 m14 : 32|16@1+ (1,0) [0|65535] "mV"  PC
 SG_ CSC_Ucell_102_09 m14 : 48|16@1+ (1,0) [0|65535] "mV"  PC
 SG_ CSC_Ucell_103_09 m15 : 16|16@1+ (1,0) [0|65535] "mV"  PC
 SG_ CSC_Ucell_104_09 m15 : 32|16@1+ (1,0) [0|65535] "mV"  PC
 SG_ CSC_Ucell_105_09 m15 : 48|16@1+ (1,0) [0|65535] "mV"  PC
 SG_ CSC_Ucell_106_09 m16 : 16|16@1+ (1,0) [0|65535] "mV"  PC
 SG_ CSC_Ucell_107_09 m16 : 32|16@1+ (1,0) [0|65535] "mV"  PC
 SG_ CSC_Ucell_108_09 m16 : 48|16@1+ (1,0) [0|65535] "mV"  PC

BO_ 2400841290 S2P_Detail_Ucell20__10: 8 SBMU
 SG_ CSC_U_No_10 : 0|8@1+ (1,0) [0|255] ""  PC
 SG_ CSC_Ucell_Frame_Index_10 M : 8|8@1+ (1,0) [0|255] ""  PC
 SG_ CSC_Ucell_58_10 m0 : 16|16@1+ (1,0) [0|65535] "mV"  PC
 SG_ CSC_Ucell_59_10 m0 : 32|16@1+ (1,0) [0|65535] "mV"  PC
 SG_ CSC_Ucell_60_10 m0 : 48|16@1+ (1,0) [0|65535] "mV"  PC
 SG_ CSC_Ucell_61_10 m1 : 16|16@1+ (1,0) [0|65535] "mV"  PC
 SG_ CSC_Ucell_62_10 m1 : 32|16@1+ (1,0) [0|65535] "mV"  PC
 SG_ CSC_Ucell_63_10 m1 : 48|16@1+ (1,0) [0|65535] "mV"  PC
 SG_ CSC_Ucell_64_10 m2 : 16|16@1+ (1,0) [0|65535] "mV"  PC
 SG_ CSC_Ucell_65_10 m2 : 32|16@1+ (1,0) [0|65535] "mV"  PC
 SG_ CSC_Ucell_66_10 m2 : 48|16@1+ (1,0) [0|65535] "mV"  PC
 SG_ CSC_Ucell_67_10 m3 : 16|16@1+ (1,0) [0|65535] "mV"  PC
 SG_ CSC_Ucell_68_10 m3 : 32|16@1+ (1,0) [0|65535] "mV"  PC
 SG_ CSC_Ucell_69_10 m3 : 48|16@1+ (1,0) [0|65535] "mV"  PC
 SG_ CSC_Ucell_70_10 m4 : 16|16@1+ (1,0) [0|65535] "mV"  PC
 SG_ CSC_Ucell_71_10 m4 : 32|16@1+ (1,0) [0|65535] "mV"  PC
 SG_ CSC_Ucell_72_10 m4 : 48|16@1+ (1,0) [0|65535] "mV"  PC
 SG_ CSC_Ucell_73_10 m5 : 16|16@1+ (1,0) [0|65535] "mV"  PC
 SG_ CSC_Ucell_74_10 m5 : 32|16@1+ (1,0) [0|65535] "mV"  PC
 SG_ CSC_Ucell_75_10 m5 : 48|16@1+ (1,0) [0|65535] "mV"  PC
 SG_ CSC_Ucell_76_10 m6 : 16|16@1+ (1,0) [0|65535] "mV"  PC
 SG_ CSC_Ucell_77_10 m6 : 32|16@1+ (1,0) [0|65535] "mV"  PC
 SG_ CSC_Ucell_78_10 m6 : 48|16@1+ (1,0) [0|65535] "mV"  PC
 SG_ CSC_Ucell_79_10 m7 : 16|16@1+ (1,0) [0|65535] "mV"  PC
 SG_ CSC_Ucell_80_10 m7 : 32|16@1+ (1,0) [0|65535] "mV"  PC
 SG_ CSC_Ucell_81_10 m7 : 48|16@1+ (1,0) [0|65535] "mV"  PC
 SG_ CSC_Ucell_82_10 m8 : 16|16@1+ (1,0) [0|65535] "mV"  PC
 SG_ CSC_Ucell_83_10 m8 : 32|16@1+ (1,0) [0|65535] "mV"  PC
 SG_ CSC_Ucell_84_10 m8 : 48|16@1+ (1,0) [0|65535] "mV"  PC
 SG_ CSC_Ucell_85_10 m9 : 16|16@1+ (1,0) [0|65535] "mV"  PC
 SG_ CSC_Ucell_86_10 m9 : 32|16@1+ (1,0) [0|65535] "mV"  PC
 SG_ CSC_Ucell_87_10 m9 : 48|16@1+ (1,0) [0|65535] "mV"  PC
 SG_ CSC_Ucell_88_10 m10 : 16|16@1+ (1,0) [0|65535] "mV"  PC
 SG_ CSC_Ucell_89_10 m10 : 32|16@1+ (1,0) [0|65535] "mV"  PC
 SG_ CSC_Ucell_90_10 m10 : 48|16@1+ (1,0) [0|65535] "mV"  PC
 SG_ CSC_Ucell_91_10 m11 : 16|16@1+ (1,0) [0|65535] "mV"  PC
 SG_ CSC_Ucell_92_10 m11 : 32|16@1+ (1,0) [0|65535] "mV"  PC
 SG_ CSC_Ucell_93_10 m11 : 48|16@1+ (1,0) [0|65535] "mV"  PC
 SG_ CSC_Ucell_94_10 m12 : 16|16@1+ (1,0) [0|65535] "mV"  PC
 SG_ CSC_Ucell_95_10 m12 : 32|16@1+ (1,0) [0|65535] "mV"  PC
 SG_ CSC_Ucell_96_10 m12 : 48|16@1+ (1,0) [0|65535] "mV"  PC
 SG_ CSC_Ucell_97_10 m13 : 16|16@1+ (1,0) [0|65535] "mV"  PC
 SG_ CSC_Ucell_98_10 m13 : 32|16@1+ (1,0) [0|65535] "mV"  PC
 SG_ CSC_Ucell_99_10 m13 : 48|16@1+ (1,0) [0|65535] "mV"  PC
 SG_ CSC_Ucell_100_10 m14 : 16|16@1+ (1,0) [0|65535] "mV"  PC
 SG_ CSC_Ucell_101_10 m14 : 32|16@1+ (1,0) [0|65535] "mV"  PC
 SG_ CSC_Ucell_102_10 m14 : 48|16@1+ (1,0) [0|65535] "mV"  PC
 SG_ CSC_Ucell_103_10 m15 : 16|16@1+ (1,0) [0|65535] "mV"  PC
 SG_ CSC_Ucell_104_10 m15 : 32|16@1+ (1,0) [0|65535] "mV"  PC
 SG_ CSC_Ucell_105_10 m15 : 48|16@1+ (1,0) [0|65535] "mV"  PC
 SG_ CSC_Ucell_106_10 m16 : 16|16@1+ (1,0) [0|65535] "mV"  PC
 SG_ CSC_Ucell_107_10 m16 : 32|16@1+ (1,0) [0|65535] "mV"  PC
 SG_ CSC_Ucell_108_10 m16 : 48|16@1+ (1,0) [0|65535] "mV"  PC

BO_ 2400841291 S2P_Detail_Ucell20__11: 8 SBMU
 SG_ CSC_U_No_11 : 0|8@1+ (1,0) [0|255] ""  PC
 SG_ CSC_Ucell_Frame_Index_11 M : 8|8@1+ (1,0) [0|255] ""  PC
 SG_ CSC_Ucell_58_11 m0 : 16|16@1+ (1,0) [0|65535] "mV"  PC
 SG_ CSC_Ucell_59_11 m0 : 32|16@1+ (1,0) [0|65535] "mV"  PC
 SG_ CSC_Ucell_60_11 m0 : 48|16@1+ (1,0) [0|65535] "mV"  PC
 SG_ CSC_Ucell_61_11 m1 : 16|16@1+ (1,0) [0|65535] "mV"  PC
 SG_ CSC_Ucell_62_11 m1 : 32|16@1+ (1,0) [0|65535] "mV"  PC
 SG_ CSC_Ucell_63_11 m1 : 48|16@1+ (1,0) [0|65535] "mV"  PC
 SG_ CSC_Ucell_64_11 m2 : 16|16@1+ (1,0) [0|65535] "mV"  PC
 SG_ CSC_Ucell_65_11 m2 : 32|16@1+ (1,0) [0|65535] "mV"  PC
 SG_ CSC_Ucell_66_11 m2 : 48|16@1+ (1,0) [0|65535] "mV"  PC
 SG_ CSC_Ucell_67_11 m3 : 16|16@1+ (1,0) [0|65535] "mV"  PC
 SG_ CSC_Ucell_68_11 m3 : 32|16@1+ (1,0) [0|65535] "mV"  PC
 SG_ CSC_Ucell_69_11 m3 : 48|16@1+ (1,0) [0|65535] "mV"  PC
 SG_ CSC_Ucell_70_11 m4 : 16|16@1+ (1,0) [0|65535] "mV"  PC
 SG_ CSC_Ucell_71_11 m4 : 32|16@1+ (1,0) [0|65535] "mV"  PC
 SG_ CSC_Ucell_72_11 m4 : 48|16@1+ (1,0) [0|65535] "mV"  PC
 SG_ CSC_Ucell_73_11 m5 : 16|16@1+ (1,0) [0|65535] "mV"  PC
 SG_ CSC_Ucell_74_11 m5 : 32|16@1+ (1,0) [0|65535] "mV"  PC
 SG_ CSC_Ucell_75_11 m5 : 48|16@1+ (1,0) [0|65535] "mV"  PC
 SG_ CSC_Ucell_76_11 m6 : 16|16@1+ (1,0) [0|65535] "mV"  PC
 SG_ CSC_Ucell_77_11 m6 : 32|16@1+ (1,0) [0|65535] "mV"  PC
 SG_ CSC_Ucell_78_11 m6 : 48|16@1+ (1,0) [0|65535] "mV"  PC
 SG_ CSC_Ucell_79_11 m7 : 16|16@1+ (1,0) [0|65535] "mV"  PC
 SG_ CSC_Ucell_80_11 m7 : 32|16@1+ (1,0) [0|65535] "mV"  PC
 SG_ CSC_Ucell_81_11 m7 : 48|16@1+ (1,0) [0|65535] "mV"  PC
 SG_ CSC_Ucell_82_11 m8 : 16|16@1+ (1,0) [0|65535] "mV"  PC
 SG_ CSC_Ucell_83_11 m8 : 32|16@1+ (1,0) [0|65535] "mV"  PC
 SG_ CSC_Ucell_84_11 m8 : 48|16@1+ (1,0) [0|65535] "mV"  PC
 SG_ CSC_Ucell_85_11 m9 : 16|16@1+ (1,0) [0|65535] "mV"  PC
 SG_ CSC_Ucell_86_11 m9 : 32|16@1+ (1,0) [0|65535] "mV"  PC
 SG_ CSC_Ucell_87_11 m9 : 48|16@1+ (1,0) [0|65535] "mV"  PC
 SG_ CSC_Ucell_88_11 m10 : 16|16@1+ (1,0) [0|65535] "mV"  PC
 SG_ CSC_Ucell_89_11 m10 : 32|16@1+ (1,0) [0|65535] "mV"  PC
 SG_ CSC_Ucell_90_11 m10 : 48|16@1+ (1,0) [0|65535] "mV"  PC
 SG_ CSC_Ucell_91_11 m11 : 16|16@1+ (1,0) [0|65535] "mV"  PC
 SG_ CSC_Ucell_92_11 m11 : 32|16@1+ (1,0) [0|65535] "mV"  PC
 SG_ CSC_Ucell_93_11 m11 : 48|16@1+ (1,0) [0|65535] "mV"  PC
 SG_ CSC_Ucell_94_11 m12 : 16|16@1+ (1,0) [0|65535] "mV"  PC
 SG_ CSC_Ucell_95_11 m12 : 32|16@1+ (1,0) [0|65535] "mV"  PC
 SG_ CSC_Ucell_96_11 m12 : 48|16@1+ (1,0) [0|65535] "mV"  PC
 SG_ CSC_Ucell_97_11 m13 : 16|16@1+ (1,0) [0|65535] "mV"  PC
 SG_ CSC_Ucell_98_11 m13 : 32|16@1+ (1,0) [0|65535] "mV"  PC
 SG_ CSC_Ucell_99_11 m13 : 48|16@1+ (1,0) [0|65535] "mV"  PC
 SG_ CSC_Ucell_100_11 m14 : 16|16@1+ (1,0) [0|65535] "mV"  PC
 SG_ CSC_Ucell_101_11 m14 : 32|16@1+ (1,0) [0|65535] "mV"  PC
 SG_ CSC_Ucell_102_11 m14 : 48|16@1+ (1,0) [0|65535] "mV"  PC
 SG_ CSC_Ucell_103_11 m15 : 16|16@1+ (1,0) [0|65535] "mV"  PC
 SG_ CSC_Ucell_104_11 m15 : 32|16@1+ (1,0) [0|65535] "mV"  PC
 SG_ CSC_Ucell_105_11 m15 : 48|16@1+ (1,0) [0|65535] "mV"  PC
 SG_ CSC_Ucell_106_11 m16 : 16|16@1+ (1,0) [0|65535] "mV"  PC
 SG_ CSC_Ucell_107_11 m16 : 32|16@1+ (1,0) [0|65535] "mV"  PC
 SG_ CSC_Ucell_108_11 m16 : 48|16@1+ (1,0) [0|65535] "mV"  PC

BO_ 2400841292 S2P_Detail_Ucell20__12: 8 SBMU
 SG_ CSC_U_No_12 : 0|8@1+ (1,0) [0|255] ""  PC
 SG_ CSC_Ucell_Frame_Index_12 M : 8|8@1+ (1,0) [0|255] ""  PC
 SG_ CSC_Ucell_58_12 m0 : 16|16@1+ (1,0) [0|65535] "mV"  PC
 SG_ CSC_Ucell_59_12 m0 : 32|16@1+ (1,0) [0|65535] "mV"  PC
 SG_ CSC_Ucell_60_12 m0 : 48|16@1+ (1,0) [0|65535] "mV"  PC
 SG_ CSC_Ucell_61_12 m1 : 16|16@1+ (1,0) [0|65535] "mV"  PC
 SG_ CSC_Ucell_62_12 m1 : 32|16@1+ (1,0) [0|65535] "mV"  PC
 SG_ CSC_Ucell_63_12 m1 : 48|16@1+ (1,0) [0|65535] "mV"  PC
 SG_ CSC_Ucell_64_12 m2 : 16|16@1+ (1,0) [0|65535] "mV"  PC
 SG_ CSC_Ucell_65_12 m2 : 32|16@1+ (1,0) [0|65535] "mV"  PC
 SG_ CSC_Ucell_66_12 m2 : 48|16@1+ (1,0) [0|65535] "mV"  PC
 SG_ CSC_Ucell_67_12 m3 : 16|16@1+ (1,0) [0|65535] "mV"  PC
 SG_ CSC_Ucell_68_12 m3 : 32|16@1+ (1,0) [0|65535] "mV"  PC
 SG_ CSC_Ucell_69_12 m3 : 48|16@1+ (1,0) [0|65535] "mV"  PC
 SG_ CSC_Ucell_70_12 m4 : 16|16@1+ (1,0) [0|65535] "mV"  PC
 SG_ CSC_Ucell_71_12 m4 : 32|16@1+ (1,0) [0|65535] "mV"  PC
 SG_ CSC_Ucell_72_12 m4 : 48|16@1+ (1,0) [0|65535] "mV"  PC
 SG_ CSC_Ucell_73_12 m5 : 16|16@1+ (1,0) [0|65535] "mV"  PC
 SG_ CSC_Ucell_74_12 m5 : 32|16@1+ (1,0) [0|65535] "mV"  PC
 SG_ CSC_Ucell_75_12 m5 : 48|16@1+ (1,0) [0|65535] "mV"  PC
 SG_ CSC_Ucell_76_12 m6 : 16|16@1+ (1,0) [0|65535] "mV"  PC
 SG_ CSC_Ucell_77_12 m6 : 32|16@1+ (1,0) [0|65535] "mV"  PC
 SG_ CSC_Ucell_78_12 m6 : 48|16@1+ (1,0) [0|65535] "mV"  PC
 SG_ CSC_Ucell_79_12 m7 : 16|16@1+ (1,0) [0|65535] "mV"  PC
 SG_ CSC_Ucell_80_12 m7 : 32|16@1+ (1,0) [0|65535] "mV"  PC
 SG_ CSC_Ucell_81_12 m7 : 48|16@1+ (1,0) [0|65535] "mV"  PC
 SG_ CSC_Ucell_82_12 m8 : 16|16@1+ (1,0) [0|65535] "mV"  PC
 SG_ CSC_Ucell_83_12 m8 : 32|16@1+ (1,0) [0|65535] "mV"  PC
 SG_ CSC_Ucell_84_12 m8 : 48|16@1+ (1,0) [0|65535] "mV"  PC
 SG_ CSC_Ucell_85_12 m9 : 16|16@1+ (1,0) [0|65535] "mV"  PC
 SG_ CSC_Ucell_86_12 m9 : 32|16@1+ (1,0) [0|65535] "mV"  PC
 SG_ CSC_Ucell_87_12 m9 : 48|16@1+ (1,0) [0|65535] "mV"  PC
 SG_ CSC_Ucell_88_12 m10 : 16|16@1+ (1,0) [0|65535] "mV"  PC
 SG_ CSC_Ucell_89_12 m10 : 32|16@1+ (1,0) [0|65535] "mV"  PC
 SG_ CSC_Ucell_90_12 m10 : 48|16@1+ (1,0) [0|65535] "mV"  PC
 SG_ CSC_Ucell_91_12 m11 : 16|16@1+ (1,0) [0|65535] "mV"  PC
 SG_ CSC_Ucell_92_12 m11 : 32|16@1+ (1,0) [0|65535] "mV"  PC
 SG_ CSC_Ucell_93_12 m11 : 48|16@1+ (1,0) [0|65535] "mV"  PC
 SG_ CSC_Ucell_94_12 m12 : 16|16@1+ (1,0) [0|65535] "mV"  PC
 SG_ CSC_Ucell_95_12 m12 : 32|16@1+ (1,0) [0|65535] "mV"  PC
 SG_ CSC_Ucell_96_12 m12 : 48|16@1+ (1,0) [0|65535] "mV"  PC
 SG_ CSC_Ucell_97_12 m13 : 16|16@1+ (1,0) [0|65535] "mV"  PC
 SG_ CSC_Ucell_98_12 m13 : 32|16@1+ (1,0) [0|65535] "mV"  PC
 SG_ CSC_Ucell_99_12 m13 : 48|16@1+ (1,0) [0|65535] "mV"  PC
 SG_ CSC_Ucell_100_12 m14 : 16|16@1+ (1,0) [0|65535] "mV"  PC
 SG_ CSC_Ucell_101_12 m14 : 32|16@1+ (1,0) [0|65535] "mV"  PC
 SG_ CSC_Ucell_102_12 m14 : 48|16@1+ (1,0) [0|65535] "mV"  PC
 SG_ CSC_Ucell_103_12 m15 : 16|16@1+ (1,0) [0|65535] "mV"  PC
 SG_ CSC_Ucell_104_12 m15 : 32|16@1+ (1,0) [0|65535] "mV"  PC
 SG_ CSC_Ucell_105_12 m15 : 48|16@1+ (1,0) [0|65535] "mV"  PC
 SG_ CSC_Ucell_106_12 m16 : 16|16@1+ (1,0) [0|65535] "mV"  PC
 SG_ CSC_Ucell_107_12 m16 : 32|16@1+ (1,0) [0|65535] "mV"  PC
 SG_ CSC_Ucell_108_12 m16 : 48|16@1+ (1,0) [0|65535] "mV"  PC

BO_ 2400841293 S2P_Detail_Ucell20__13: 8 SBMU
 SG_ CSC_U_No_13 : 0|8@1+ (1,0) [0|255] ""  PC
 SG_ CSC_Ucell_Frame_Index_13 M : 8|8@1+ (1,0) [0|255] ""  PC
 SG_ CSC_Ucell_58_13 m0 : 16|16@1+ (1,0) [0|65535] "mV"  PC
 SG_ CSC_Ucell_59_13 m0 : 32|16@1+ (1,0) [0|65535] "mV"  PC
 SG_ CSC_Ucell_60_13 m0 : 48|16@1+ (1,0) [0|65535] "mV"  PC
 SG_ CSC_Ucell_61_13 m1 : 16|16@1+ (1,0) [0|65535] "mV"  PC
 SG_ CSC_Ucell_62_13 m1 : 32|16@1+ (1,0) [0|65535] "mV"  PC
 SG_ CSC_Ucell_63_13 m1 : 48|16@1+ (1,0) [0|65535] "mV"  PC
 SG_ CSC_Ucell_64_13 m2 : 16|16@1+ (1,0) [0|65535] "mV"  PC
 SG_ CSC_Ucell_65_13 m2 : 32|16@1+ (1,0) [0|65535] "mV"  PC
 SG_ CSC_Ucell_66_13 m2 : 48|16@1+ (1,0) [0|65535] "mV"  PC
 SG_ CSC_Ucell_67_13 m3 : 16|16@1+ (1,0) [0|65535] "mV"  PC
 SG_ CSC_Ucell_68_13 m3 : 32|16@1+ (1,0) [0|65535] "mV"  PC
 SG_ CSC_Ucell_69_13 m3 : 48|16@1+ (1,0) [0|65535] "mV"  PC
 SG_ CSC_Ucell_70_13 m4 : 16|16@1+ (1,0) [0|65535] "mV"  PC
 SG_ CSC_Ucell_71_13 m4 : 32|16@1+ (1,0) [0|65535] "mV"  PC
 SG_ CSC_Ucell_72_13 m4 : 48|16@1+ (1,0) [0|65535] "mV"  PC
 SG_ CSC_Ucell_73_13 m5 : 16|16@1+ (1,0) [0|65535] "mV"  PC
 SG_ CSC_Ucell_74_13 m5 : 32|16@1+ (1,0) [0|65535] "mV"  PC
 SG_ CSC_Ucell_75_13 m5 : 48|16@1+ (1,0) [0|65535] "mV"  PC
 SG_ CSC_Ucell_76_13 m6 : 16|16@1+ (1,0) [0|65535] "mV"  PC
 SG_ CSC_Ucell_77_13 m6 : 32|16@1+ (1,0) [0|65535] "mV"  PC
 SG_ CSC_Ucell_78_13 m6 : 48|16@1+ (1,0) [0|65535] "mV"  PC
 SG_ CSC_Ucell_79_13 m7 : 16|16@1+ (1,0) [0|65535] "mV"  PC
 SG_ CSC_Ucell_80_13 m7 : 32|16@1+ (1,0) [0|65535] "mV"  PC
 SG_ CSC_Ucell_81_13 m7 : 48|16@1+ (1,0) [0|65535] "mV"  PC
 SG_ CSC_Ucell_82_13 m8 : 16|16@1+ (1,0) [0|65535] "mV"  PC
 SG_ CSC_Ucell_83_13 m8 : 32|16@1+ (1,0) [0|65535] "mV"  PC
 SG_ CSC_Ucell_84_13 m8 : 48|16@1+ (1,0) [0|65535] "mV"  PC
 SG_ CSC_Ucell_85_13 m9 : 16|16@1+ (1,0) [0|65535] "mV"  PC
 SG_ CSC_Ucell_86_13 m9 : 32|16@1+ (1,0) [0|65535] "mV"  PC
 SG_ CSC_Ucell_87_13 m9 : 48|16@1+ (1,0) [0|65535] "mV"  PC
 SG_ CSC_Ucell_88_13 m10 : 16|16@1+ (1,0) [0|65535] "mV"  PC
 SG_ CSC_Ucell_89_13 m10 : 32|16@1+ (1,0) [0|65535] "mV"  PC
 SG_ CSC_Ucell_90_13 m10 : 48|16@1+ (1,0) [0|65535] "mV"  PC
 SG_ CSC_Ucell_91_13 m11 : 16|16@1+ (1,0) [0|65535] "mV"  PC
 SG_ CSC_Ucell_92_13 m11 : 32|16@1+ (1,0) [0|65535] "mV"  PC
 SG_ CSC_Ucell_93_13 m11 : 48|16@1+ (1,0) [0|65535] "mV"  PC
 SG_ CSC_Ucell_94_13 m12 : 16|16@1+ (1,0) [0|65535] "mV"  PC
 SG_ CSC_Ucell_95_13 m12 : 32|16@1+ (1,0) [0|65535] "mV"  PC
 SG_ CSC_Ucell_96_13 m12 : 48|16@1+ (1,0) [0|65535] "mV"  PC
 SG_ CSC_Ucell_97_13 m13 : 16|16@1+ (1,0) [0|65535] "mV"  PC
 SG_ CSC_Ucell_98_13 m13 : 32|16@1+ (1,0) [0|65535] "mV"  PC
 SG_ CSC_Ucell_99_13 m13 : 48|16@1+ (1,0) [0|65535] "mV"  PC
 SG_ CSC_Ucell_100_13 m14 : 16|16@1+ (1,0) [0|65535] "mV"  PC
 SG_ CSC_Ucell_101_13 m14 : 32|16@1+ (1,0) [0|65535] "mV"  PC
 SG_ CSC_Ucell_102_13 m14 : 48|16@1+ (1,0) [0|65535] "mV"  PC
 SG_ CSC_Ucell_103_13 m15 : 16|16@1+ (1,0) [0|65535] "mV"  PC
 SG_ CSC_Ucell_104_13 m15 : 32|16@1+ (1,0) [0|65535] "mV"  PC
 SG_ CSC_Ucell_105_13 m15 : 48|16@1+ (1,0) [0|65535] "mV"  PC
 SG_ CSC_Ucell_106_13 m16 : 16|16@1+ (1,0) [0|65535] "mV"  PC
 SG_ CSC_Ucell_107_13 m16 : 32|16@1+ (1,0) [0|65535] "mV"  PC
 SG_ CSC_Ucell_108_13 m16 : 48|16@1+ (1,0) [0|65535] "mV"  PC

BO_ 2400841294 S2P_Detail_Ucell20__14: 8 SBMU
 SG_ CSC_U_No_14 : 0|8@1+ (1,0) [0|255] ""  PC
 SG_ CSC_Ucell_Frame_Index_14 M : 8|8@1+ (1,0) [0|255] ""  PC
 SG_ CSC_Ucell_58_14 m0 : 16|16@1+ (1,0) [0|65535] "mV"  PC
 SG_ CSC_Ucell_59_14 m0 : 32|16@1+ (1,0) [0|65535] "mV"  PC
 SG_ CSC_Ucell_60_14 m0 : 48|16@1+ (1,0) [0|65535] "mV"  PC
 SG_ CSC_Ucell_61_14 m1 : 16|16@1+ (1,0) [0|65535] "mV"  PC
 SG_ CSC_Ucell_62_14 m1 : 32|16@1+ (1,0) [0|65535] "mV"  PC
 SG_ CSC_Ucell_63_14 m1 : 48|16@1+ (1,0) [0|65535] "mV"  PC
 SG_ CSC_Ucell_64_14 m2 : 16|16@1+ (1,0) [0|65535] "mV"  PC
 SG_ CSC_Ucell_65_14 m2 : 32|16@1+ (1,0) [0|65535] "mV"  PC
 SG_ CSC_Ucell_66_14 m2 : 48|16@1+ (1,0) [0|65535] "mV"  PC
 SG_ CSC_Ucell_67_14 m3 : 16|16@1+ (1,0) [0|65535] "mV"  PC
 SG_ CSC_Ucell_68_14 m3 : 32|16@1+ (1,0) [0|65535] "mV"  PC
 SG_ CSC_Ucell_69_14 m3 : 48|16@1+ (1,0) [0|65535] "mV"  PC
 SG_ CSC_Ucell_70_14 m4 : 16|16@1+ (1,0) [0|65535] "mV"  PC
 SG_ CSC_Ucell_71_14 m4 : 32|16@1+ (1,0) [0|65535] "mV"  PC
 SG_ CSC_Ucell_72_14 m4 : 48|16@1+ (1,0) [0|65535] "mV"  PC
 SG_ CSC_Ucell_73_14 m5 : 16|16@1+ (1,0) [0|65535] "mV"  PC
 SG_ CSC_Ucell_74_14 m5 : 32|16@1+ (1,0) [0|65535] "mV"  PC
 SG_ CSC_Ucell_75_14 m5 : 48|16@1+ (1,0) [0|65535] "mV"  PC
 SG_ CSC_Ucell_76_14 m6 : 16|16@1+ (1,0) [0|65535] "mV"  PC
 SG_ CSC_Ucell_77_14 m6 : 32|16@1+ (1,0) [0|65535] "mV"  PC
 SG_ CSC_Ucell_78_14 m6 : 48|16@1+ (1,0) [0|65535] "mV"  PC
 SG_ CSC_Ucell_79_14 m7 : 16|16@1+ (1,0) [0|65535] "mV"  PC
 SG_ CSC_Ucell_80_14 m7 : 32|16@1+ (1,0) [0|65535] "mV"  PC
 SG_ CSC_Ucell_81_14 m7 : 48|16@1+ (1,0) [0|65535] "mV"  PC
 SG_ CSC_Ucell_82_14 m8 : 16|16@1+ (1,0) [0|65535] "mV"  PC
 SG_ CSC_Ucell_83_14 m8 : 32|16@1+ (1,0) [0|65535] "mV"  PC
 SG_ CSC_Ucell_84_14 m8 : 48|16@1+ (1,0) [0|65535] "mV"  PC
 SG_ CSC_Ucell_85_14 m9 : 16|16@1+ (1,0) [0|65535] "mV"  PC
 SG_ CSC_Ucell_86_14 m9 : 32|16@1+ (1,0) [0|65535] "mV"  PC
 SG_ CSC_Ucell_87_14 m9 : 48|16@1+ (1,0) [0|65535] "mV"  PC
 SG_ CSC_Ucell_88_14 m10 : 16|16@1+ (1,0) [0|65535] "mV"  PC
 SG_ CSC_Ucell_89_14 m10 : 32|16@1+ (1,0) [0|65535] "mV"  PC
 SG_ CSC_Ucell_90_14 m10 : 48|16@1+ (1,0) [0|65535] "mV"  PC
 SG_ CSC_Ucell_91_14 m11 : 16|16@1+ (1,0) [0|65535] "mV"  PC
 SG_ CSC_Ucell_92_14 m11 : 32|16@1+ (1,0) [0|65535] "mV"  PC
 SG_ CSC_Ucell_93_14 m11 : 48|16@1+ (1,0) [0|65535] "mV"  PC
 SG_ CSC_Ucell_94_14 m12 : 16|16@1+ (1,0) [0|65535] "mV"  PC
 SG_ CSC_Ucell_95_14 m12 : 32|16@1+ (1,0) [0|65535] "mV"  PC
 SG_ CSC_Ucell_96_14 m12 : 48|16@1+ (1,0) [0|65535] "mV"  PC
 SG_ CSC_Ucell_97_14 m13 : 16|16@1+ (1,0) [0|65535] "mV"  PC
 SG_ CSC_Ucell_98_14 m13 : 32|16@1+ (1,0) [0|65535] "mV"  PC
 SG_ CSC_Ucell_99_14 m13 : 48|16@1+ (1,0) [0|65535] "mV"  PC
 SG_ CSC_Ucell_100_14 m14 : 16|16@1+ (1,0) [0|65535] "mV"  PC
 SG_ CSC_Ucell_101_14 m14 : 32|16@1+ (1,0) [0|65535] "mV"  PC
 SG_ CSC_Ucell_102_14 m14 : 48|16@1+ (1,0) [0|65535] "mV"  PC
 SG_ CSC_Ucell_103_14 m15 : 16|16@1+ (1,0) [0|65535] "mV"  PC
 SG_ CSC_Ucell_104_14 m15 : 32|16@1+ (1,0) [0|65535] "mV"  PC
 SG_ CSC_Ucell_105_14 m15 : 48|16@1+ (1,0) [0|65535] "mV"  PC
 SG_ CSC_Ucell_106_14 m16 : 16|16@1+ (1,0) [0|65535] "mV"  PC
 SG_ CSC_Ucell_107_14 m16 : 32|16@1+ (1,0) [0|65535] "mV"  PC
 SG_ CSC_Ucell_108_14 m16 : 48|16@1+ (1,0) [0|65535] "mV"  PC

BO_ 2400841295 S2P_Detail_Ucell20__15: 8 SBMU
 SG_ CSC_U_No_15 : 0|8@1+ (1,0) [0|255] ""  PC
 SG_ CSC_Ucell_Frame_Index_15 M : 8|8@1+ (1,0) [0|255] ""  PC
 SG_ CSC_Ucell_58_15 m0 : 16|16@1+ (1,0) [0|65535] "mV"  PC
 SG_ CSC_Ucell_59_15 m0 : 32|16@1+ (1,0) [0|65535] "mV"  PC
 SG_ CSC_Ucell_60_15 m0 : 48|16@1+ (1,0) [0|65535] "mV"  PC
 SG_ CSC_Ucell_61_15 m1 : 16|16@1+ (1,0) [0|65535] "mV"  PC
 SG_ CSC_Ucell_62_15 m1 : 32|16@1+ (1,0) [0|65535] "mV"  PC
 SG_ CSC_Ucell_63_15 m1 : 48|16@1+ (1,0) [0|65535] "mV"  PC
 SG_ CSC_Ucell_64_15 m2 : 16|16@1+ (1,0) [0|65535] "mV"  PC
 SG_ CSC_Ucell_65_15 m2 : 32|16@1+ (1,0) [0|65535] "mV"  PC
 SG_ CSC_Ucell_66_15 m2 : 48|16@1+ (1,0) [0|65535] "mV"  PC
 SG_ CSC_Ucell_67_15 m3 : 16|16@1+ (1,0) [0|65535] "mV"  PC
 SG_ CSC_Ucell_68_15 m3 : 32|16@1+ (1,0) [0|65535] "mV"  PC
 SG_ CSC_Ucell_69_15 m3 : 48|16@1+ (1,0) [0|65535] "mV"  PC
 SG_ CSC_Ucell_70_15 m4 : 16|16@1+ (1,0) [0|65535] "mV"  PC
 SG_ CSC_Ucell_71_15 m4 : 32|16@1+ (1,0) [0|65535] "mV"  PC
 SG_ CSC_Ucell_72_15 m4 : 48|16@1+ (1,0) [0|65535] "mV"  PC
 SG_ CSC_Ucell_73_15 m5 : 16|16@1+ (1,0) [0|65535] "mV"  PC
 SG_ CSC_Ucell_74_15 m5 : 32|16@1+ (1,0) [0|65535] "mV"  PC
 SG_ CSC_Ucell_75_15 m5 : 48|16@1+ (1,0) [0|65535] "mV"  PC
 SG_ CSC_Ucell_76_15 m6 : 16|16@1+ (1,0) [0|65535] "mV"  PC
 SG_ CSC_Ucell_77_15 m6 : 32|16@1+ (1,0) [0|65535] "mV"  PC
 SG_ CSC_Ucell_78_15 m6 : 48|16@1+ (1,0) [0|65535] "mV"  PC
 SG_ CSC_Ucell_79_15 m7 : 16|16@1+ (1,0) [0|65535] "mV"  PC
 SG_ CSC_Ucell_80_15 m7 : 32|16@1+ (1,0) [0|65535] "mV"  PC
 SG_ CSC_Ucell_81_15 m7 : 48|16@1+ (1,0) [0|65535] "mV"  PC
 SG_ CSC_Ucell_82_15 m8 : 16|16@1+ (1,0) [0|65535] "mV"  PC
 SG_ CSC_Ucell_83_15 m8 : 32|16@1+ (1,0) [0|65535] "mV"  PC
 SG_ CSC_Ucell_84_15 m8 : 48|16@1+ (1,0) [0|65535] "mV"  PC
 SG_ CSC_Ucell_85_15 m9 : 16|16@1+ (1,0) [0|65535] "mV"  PC
 SG_ CSC_Ucell_86_15 m9 : 32|16@1+ (1,0) [0|65535] "mV"  PC
 SG_ CSC_Ucell_87_15 m9 : 48|16@1+ (1,0) [0|65535] "mV"  PC
 SG_ CSC_Ucell_88_15 m10 : 16|16@1+ (1,0) [0|65535] "mV"  PC
 SG_ CSC_Ucell_89_15 m10 : 32|16@1+ (1,0) [0|65535] "mV"  PC
 SG_ CSC_Ucell_90_15 m10 : 48|16@1+ (1,0) [0|65535] "mV"  PC
 SG_ CSC_Ucell_91_15 m11 : 16|16@1+ (1,0) [0|65535] "mV"  PC
 SG_ CSC_Ucell_92_15 m11 : 32|16@1+ (1,0) [0|65535] "mV"  PC
 SG_ CSC_Ucell_93_15 m11 : 48|16@1+ (1,0) [0|65535] "mV"  PC
 SG_ CSC_Ucell_94_15 m12 : 16|16@1+ (1,0) [0|65535] "mV"  PC
 SG_ CSC_Ucell_95_15 m12 : 32|16@1+ (1,0) [0|65535] "mV"  PC
 SG_ CSC_Ucell_96_15 m12 : 48|16@1+ (1,0) [0|65535] "mV"  PC
 SG_ CSC_Ucell_97_15 m13 : 16|16@1+ (1,0) [0|65535] "mV"  PC
 SG_ CSC_Ucell_98_15 m13 : 32|16@1+ (1,0) [0|65535] "mV"  PC
 SG_ CSC_Ucell_99_15 m13 : 48|16@1+ (1,0) [0|65535] "mV"  PC
 SG_ CSC_Ucell_100_15 m14 : 16|16@1+ (1,0) [0|65535] "mV"  PC
 SG_ CSC_Ucell_101_15 m14 : 32|16@1+ (1,0) [0|65535] "mV"  PC
 SG_ CSC_Ucell_102_15 m14 : 48|16@1+ (1,0) [0|65535] "mV"  PC
 SG_ CSC_Ucell_103_15 m15 : 16|16@1+ (1,0) [0|65535] "mV"  PC
 SG_ CSC_Ucell_104_15 m15 : 32|16@1+ (1,0) [0|65535] "mV"  PC
 SG_ CSC_Ucell_105_15 m15 : 48|16@1+ (1,0) [0|65535] "mV"  PC
 SG_ CSC_Ucell_106_15 m16 : 16|16@1+ (1,0) [0|65535] "mV"  PC
 SG_ CSC_Ucell_107_15 m16 : 32|16@1+ (1,0) [0|65535] "mV"  PC
 SG_ CSC_Ucell_108_15 m16 : 48|16@1+ (1,0) [0|65535] "mV"  PC

BO_ 2400841296 S2P_Detail_Ucell20__16: 8 SBMU
 SG_ CSC_U_No_16 : 0|8@1+ (1,0) [0|255] ""  PC
 SG_ CSC_Ucell_Frame_Index_16 M : 8|8@1+ (1,0) [0|255] ""  PC
 SG_ CSC_Ucell_58_16 m0 : 16|16@1+ (1,0) [0|65535] "mV"  PC
 SG_ CSC_Ucell_59_16 m0 : 32|16@1+ (1,0) [0|65535] "mV"  PC
 SG_ CSC_Ucell_60_16 m0 : 48|16@1+ (1,0) [0|65535] "mV"  PC
 SG_ CSC_Ucell_61_16 m1 : 16|16@1+ (1,0) [0|65535] "mV"  PC
 SG_ CSC_Ucell_62_16 m1 : 32|16@1+ (1,0) [0|65535] "mV"  PC
 SG_ CSC_Ucell_63_16 m1 : 48|16@1+ (1,0) [0|65535] "mV"  PC
 SG_ CSC_Ucell_64_16 m2 : 16|16@1+ (1,0) [0|65535] "mV"  PC
 SG_ CSC_Ucell_65_16 m2 : 32|16@1+ (1,0) [0|65535] "mV"  PC
 SG_ CSC_Ucell_66_16 m2 : 48|16@1+ (1,0) [0|65535] "mV"  PC
 SG_ CSC_Ucell_67_16 m3 : 16|16@1+ (1,0) [0|65535] "mV"  PC
 SG_ CSC_Ucell_68_16 m3 : 32|16@1+ (1,0) [0|65535] "mV"  PC
 SG_ CSC_Ucell_69_16 m3 : 48|16@1+ (1,0) [0|65535] "mV"  PC
 SG_ CSC_Ucell_70_16 m4 : 16|16@1+ (1,0) [0|65535] "mV"  PC
 SG_ CSC_Ucell_71_16 m4 : 32|16@1+ (1,0) [0|65535] "mV"  PC
 SG_ CSC_Ucell_72_16 m4 : 48|16@1+ (1,0) [0|65535] "mV"  PC
 SG_ CSC_Ucell_73_16 m5 : 16|16@1+ (1,0) [0|65535] "mV"  PC
 SG_ CSC_Ucell_74_16 m5 : 32|16@1+ (1,0) [0|65535] "mV"  PC
 SG_ CSC_Ucell_75_16 m5 : 48|16@1+ (1,0) [0|65535] "mV"  PC
 SG_ CSC_Ucell_76_16 m6 : 16|16@1+ (1,0) [0|65535] "mV"  PC
 SG_ CSC_Ucell_77_16 m6 : 32|16@1+ (1,0) [0|65535] "mV"  PC
 SG_ CSC_Ucell_78_16 m6 : 48|16@1+ (1,0) [0|65535] "mV"  PC
 SG_ CSC_Ucell_79_16 m7 : 16|16@1+ (1,0) [0|65535] "mV"  PC
 SG_ CSC_Ucell_80_16 m7 : 32|16@1+ (1,0) [0|65535] "mV"  PC
 SG_ CSC_Ucell_81_16 m7 : 48|16@1+ (1,0) [0|65535] "mV"  PC
 SG_ CSC_Ucell_82_16 m8 : 16|16@1+ (1,0) [0|65535] "mV"  PC
 SG_ CSC_Ucell_83_16 m8 : 32|16@1+ (1,0) [0|65535] "mV"  PC
 SG_ CSC_Ucell_84_16 m8 : 48|16@1+ (1,0) [0|65535] "mV"  PC
 SG_ CSC_Ucell_85_16 m9 : 16|16@1+ (1,0) [0|65535] "mV"  PC
 SG_ CSC_Ucell_86_16 m9 : 32|16@1+ (1,0) [0|65535] "mV"  PC
 SG_ CSC_Ucell_87_16 m9 : 48|16@1+ (1,0) [0|65535] "mV"  PC
 SG_ CSC_Ucell_88_16 m10 : 16|16@1+ (1,0) [0|65535] "mV"  PC
 SG_ CSC_Ucell_89_16 m10 : 32|16@1+ (1,0) [0|65535] "mV"  PC
 SG_ CSC_Ucell_90_16 m10 : 48|16@1+ (1,0) [0|65535] "mV"  PC
 SG_ CSC_Ucell_91_16 m11 : 16|16@1+ (1,0) [0|65535] "mV"  PC
 SG_ CSC_Ucell_92_16 m11 : 32|16@1+ (1,0) [0|65535] "mV"  PC
 SG_ CSC_Ucell_93_16 m11 : 48|16@1+ (1,0) [0|65535] "mV"  PC
 SG_ CSC_Ucell_94_16 m12 : 16|16@1+ (1,0) [0|65535] "mV"  PC
 SG_ CSC_Ucell_95_16 m12 : 32|16@1+ (1,0) [0|65535] "mV"  PC
 SG_ CSC_Ucell_96_16 m12 : 48|16@1+ (1,0) [0|65535] "mV"  PC
 SG_ CSC_Ucell_97_16 m13 : 16|16@1+ (1,0) [0|65535] "mV"  PC
 SG_ CSC_Ucell_98_16 m13 : 32|16@1+ (1,0) [0|65535] "mV"  PC
 SG_ CSC_Ucell_99_16 m13 : 48|16@1+ (1,0) [0|65535] "mV"  PC
 SG_ CSC_Ucell_100_16 m14 : 16|16@1+ (1,0) [0|65535] "mV"  PC
 SG_ CSC_Ucell_101_16 m14 : 32|16@1+ (1,0) [0|65535] "mV"  PC
 SG_ CSC_Ucell_102_16 m14 : 48|16@1+ (1,0) [0|65535] "mV"  PC
 SG_ CSC_Ucell_103_16 m15 : 16|16@1+ (1,0) [0|65535] "mV"  PC
 SG_ CSC_Ucell_104_16 m15 : 32|16@1+ (1,0) [0|65535] "mV"  PC
 SG_ CSC_Ucell_105_16 m15 : 48|16@1+ (1,0) [0|65535] "mV"  PC
 SG_ CSC_Ucell_106_16 m16 : 16|16@1+ (1,0) [0|65535] "mV"  PC
 SG_ CSC_Ucell_107_16 m16 : 32|16@1+ (1,0) [0|65535] "mV"  PC
 SG_ CSC_Ucell_108_16 m16 : 48|16@1+ (1,0) [0|65535] "mV"  PC

BO_ 2400841297 S2P_Detail_Ucell20__17: 8 SBMU
 SG_ CSC_U_No_17 : 0|8@1+ (1,0) [0|255] ""  PC
 SG_ CSC_Ucell_Frame_Index_17 M : 8|8@1+ (1,0) [0|255] ""  PC
 SG_ CSC_Ucell_58_17 m0 : 16|16@1+ (1,0) [0|65535] "mV"  PC
 SG_ CSC_Ucell_59_17 m0 : 32|16@1+ (1,0) [0|65535] "mV"  PC
 SG_ CSC_Ucell_60_17 m0 : 48|16@1+ (1,0) [0|65535] "mV"  PC
 SG_ CSC_Ucell_61_17 m1 : 16|16@1+ (1,0) [0|65535] "mV"  PC
 SG_ CSC_Ucell_62_17 m1 : 32|16@1+ (1,0) [0|65535] "mV"  PC
 SG_ CSC_Ucell_63_17 m1 : 48|16@1+ (1,0) [0|65535] "mV"  PC
 SG_ CSC_Ucell_64_17 m2 : 16|16@1+ (1,0) [0|65535] "mV"  PC
 SG_ CSC_Ucell_65_17 m2 : 32|16@1+ (1,0) [0|65535] "mV"  PC
 SG_ CSC_Ucell_66_17 m2 : 48|16@1+ (1,0) [0|65535] "mV"  PC
 SG_ CSC_Ucell_67_17 m3 : 16|16@1+ (1,0) [0|65535] "mV"  PC
 SG_ CSC_Ucell_68_17 m3 : 32|16@1+ (1,0) [0|65535] "mV"  PC
 SG_ CSC_Ucell_69_17 m3 : 48|16@1+ (1,0) [0|65535] "mV"  PC
 SG_ CSC_Ucell_70_17 m4 : 16|16@1+ (1,0) [0|65535] "mV"  PC
 SG_ CSC_Ucell_71_17 m4 : 32|16@1+ (1,0) [0|65535] "mV"  PC
 SG_ CSC_Ucell_72_17 m4 : 48|16@1+ (1,0) [0|65535] "mV"  PC
 SG_ CSC_Ucell_73_17 m5 : 16|16@1+ (1,0) [0|65535] "mV"  PC
 SG_ CSC_Ucell_74_17 m5 : 32|16@1+ (1,0) [0|65535] "mV"  PC
 SG_ CSC_Ucell_75_17 m5 : 48|16@1+ (1,0) [0|65535] "mV"  PC
 SG_ CSC_Ucell_76_17 m6 : 16|16@1+ (1,0) [0|65535] "mV"  PC
 SG_ CSC_Ucell_77_17 m6 : 32|16@1+ (1,0) [0|65535] "mV"  PC
 SG_ CSC_Ucell_78_17 m6 : 48|16@1+ (1,0) [0|65535] "mV"  PC
 SG_ CSC_Ucell_79_17 m7 : 16|16@1+ (1,0) [0|65535] "mV"  PC
 SG_ CSC_Ucell_80_17 m7 : 32|16@1+ (1,0) [0|65535] "mV"  PC
 SG_ CSC_Ucell_81_17 m7 : 48|16@1+ (1,0) [0|65535] "mV"  PC
 SG_ CSC_Ucell_82_17 m8 : 16|16@1+ (1,0) [0|65535] "mV"  PC
 SG_ CSC_Ucell_83_17 m8 : 32|16@1+ (1,0) [0|65535] "mV"  PC
 SG_ CSC_Ucell_84_17 m8 : 48|16@1+ (1,0) [0|65535] "mV"  PC
 SG_ CSC_Ucell_85_17 m9 : 16|16@1+ (1,0) [0|65535] "mV"  PC
 SG_ CSC_Ucell_86_17 m9 : 32|16@1+ (1,0) [0|65535] "mV"  PC
 SG_ CSC_Ucell_87_17 m9 : 48|16@1+ (1,0) [0|65535] "mV"  PC
 SG_ CSC_Ucell_88_17 m10 : 16|16@1+ (1,0) [0|65535] "mV"  PC
 SG_ CSC_Ucell_89_17 m10 : 32|16@1+ (1,0) [0|65535] "mV"  PC
 SG_ CSC_Ucell_90_17 m10 : 48|16@1+ (1,0) [0|65535] "mV"  PC
 SG_ CSC_Ucell_91_17 m11 : 16|16@1+ (1,0) [0|65535] "mV"  PC
 SG_ CSC_Ucell_92_17 m11 : 32|16@1+ (1,0) [0|65535] "mV"  PC
 SG_ CSC_Ucell_93_17 m11 : 48|16@1+ (1,0) [0|65535] "mV"  PC
 SG_ CSC_Ucell_94_17 m12 : 16|16@1+ (1,0) [0|65535] "mV"  PC
 SG_ CSC_Ucell_95_17 m12 : 32|16@1+ (1,0) [0|65535] "mV"  PC
 SG_ CSC_Ucell_96_17 m12 : 48|16@1+ (1,0) [0|65535] "mV"  PC
 SG_ CSC_Ucell_97_17 m13 : 16|16@1+ (1,0) [0|65535] "mV"  PC
 SG_ CSC_Ucell_98_17 m13 : 32|16@1+ (1,0) [0|65535] "mV"  PC
 SG_ CSC_Ucell_99_17 m13 : 48|16@1+ (1,0) [0|65535] "mV"  PC
 SG_ CSC_Ucell_100_17 m14 : 16|16@1+ (1,0) [0|65535] "mV"  PC
 SG_ CSC_Ucell_101_17 m14 : 32|16@1+ (1,0) [0|65535] "mV"  PC
 SG_ CSC_Ucell_102_17 m14 : 48|16@1+ (1,0) [0|65535] "mV"  PC
 SG_ CSC_Ucell_103_17 m15 : 16|16@1+ (1,0) [0|65535] "mV"  PC
 SG_ CSC_Ucell_104_17 m15 : 32|16@1+ (1,0) [0|65535] "mV"  PC
 SG_ CSC_Ucell_105_17 m15 : 48|16@1+ (1,0) [0|65535] "mV"  PC
 SG_ CSC_Ucell_106_17 m16 : 16|16@1+ (1,0) [0|65535] "mV"  PC
 SG_ CSC_Ucell_107_17 m16 : 32|16@1+ (1,0) [0|65535] "mV"  PC
 SG_ CSC_Ucell_108_17 m16 : 48|16@1+ (1,0) [0|65535] "mV"  PC

BO_ 2400841298 S2P_Detail_Ucell20__18: 8 SBMU
 SG_ CSC_U_No_18 : 0|8@1+ (1,0) [0|255] ""  PC
 SG_ CSC_Ucell_Frame_Index_18 M : 8|8@1+ (1,0) [0|255] ""  PC
 SG_ CSC_Ucell_58_18 m0 : 16|16@1+ (1,0) [0|65535] "mV"  PC
 SG_ CSC_Ucell_59_18 m0 : 32|16@1+ (1,0) [0|65535] "mV"  PC
 SG_ CSC_Ucell_60_18 m0 : 48|16@1+ (1,0) [0|65535] "mV"  PC
 SG_ CSC_Ucell_61_18 m1 : 16|16@1+ (1,0) [0|65535] "mV"  PC
 SG_ CSC_Ucell_62_18 m1 : 32|16@1+ (1,0) [0|65535] "mV"  PC
 SG_ CSC_Ucell_63_18 m1 : 48|16@1+ (1,0) [0|65535] "mV"  PC
 SG_ CSC_Ucell_64_18 m2 : 16|16@1+ (1,0) [0|65535] "mV"  PC
 SG_ CSC_Ucell_65_18 m2 : 32|16@1+ (1,0) [0|65535] "mV"  PC
 SG_ CSC_Ucell_66_18 m2 : 48|16@1+ (1,0) [0|65535] "mV"  PC
 SG_ CSC_Ucell_67_18 m3 : 16|16@1+ (1,0) [0|65535] "mV"  PC
 SG_ CSC_Ucell_68_18 m3 : 32|16@1+ (1,0) [0|65535] "mV"  PC
 SG_ CSC_Ucell_69_18 m3 : 48|16@1+ (1,0) [0|65535] "mV"  PC
 SG_ CSC_Ucell_70_18 m4 : 16|16@1+ (1,0) [0|65535] "mV"  PC
 SG_ CSC_Ucell_71_18 m4 : 32|16@1+ (1,0) [0|65535] "mV"  PC
 SG_ CSC_Ucell_72_18 m4 : 48|16@1+ (1,0) [0|65535] "mV"  PC
 SG_ CSC_Ucell_73_18 m5 : 16|16@1+ (1,0) [0|65535] "mV"  PC
 SG_ CSC_Ucell_74_18 m5 : 32|16@1+ (1,0) [0|65535] "mV"  PC
 SG_ CSC_Ucell_75_18 m5 : 48|16@1+ (1,0) [0|65535] "mV"  PC
 SG_ CSC_Ucell_76_18 m6 : 16|16@1+ (1,0) [0|65535] "mV"  PC
 SG_ CSC_Ucell_77_18 m6 : 32|16@1+ (1,0) [0|65535] "mV"  PC
 SG_ CSC_Ucell_78_18 m6 : 48|16@1+ (1,0) [0|65535] "mV"  PC
 SG_ CSC_Ucell_79_18 m7 : 16|16@1+ (1,0) [0|65535] "mV"  PC
 SG_ CSC_Ucell_80_18 m7 : 32|16@1+ (1,0) [0|65535] "mV"  PC
 SG_ CSC_Ucell_81_18 m7 : 48|16@1+ (1,0) [0|65535] "mV"  PC
 SG_ CSC_Ucell_82_18 m8 : 16|16@1+ (1,0) [0|65535] "mV"  PC
 SG_ CSC_Ucell_83_18 m8 : 32|16@1+ (1,0) [0|65535] "mV"  PC
 SG_ CSC_Ucell_84_18 m8 : 48|16@1+ (1,0) [0|65535] "mV"  PC
 SG_ CSC_Ucell_85_18 m9 : 16|16@1+ (1,0) [0|65535] "mV"  PC
 SG_ CSC_Ucell_86_18 m9 : 32|16@1+ (1,0) [0|65535] "mV"  PC
 SG_ CSC_Ucell_87_18 m9 : 48|16@1+ (1,0) [0|65535] "mV"  PC
 SG_ CSC_Ucell_88_18 m10 : 16|16@1+ (1,0) [0|65535] "mV"  PC
 SG_ CSC_Ucell_89_18 m10 : 32|16@1+ (1,0) [0|65535] "mV"  PC
 SG_ CSC_Ucell_90_18 m10 : 48|16@1+ (1,0) [0|65535] "mV"  PC
 SG_ CSC_Ucell_91_18 m11 : 16|16@1+ (1,0) [0|65535] "mV"  PC
 SG_ CSC_Ucell_92_18 m11 : 32|16@1+ (1,0) [0|65535] "mV"  PC
 SG_ CSC_Ucell_93_18 m11 : 48|16@1+ (1,0) [0|65535] "mV"  PC
 SG_ CSC_Ucell_94_18 m12 : 16|16@1+ (1,0) [0|65535] "mV"  PC
 SG_ CSC_Ucell_95_18 m12 : 32|16@1+ (1,0) [0|65535] "mV"  PC
 SG_ CSC_Ucell_96_18 m12 : 48|16@1+ (1,0) [0|65535] "mV"  PC
 SG_ CSC_Ucell_97_18 m13 : 16|16@1+ (1,0) [0|65535] "mV"  PC
 SG_ CSC_Ucell_98_18 m13 : 32|16@1+ (1,0) [0|65535] "mV"  PC
 SG_ CSC_Ucell_99_18 m13 : 48|16@1+ (1,0) [0|65535] "mV"  PC
 SG_ CSC_Ucell_100_18 m14 : 16|16@1+ (1,0) [0|65535] "mV"  PC
 SG_ CSC_Ucell_101_18 m14 : 32|16@1+ (1,0) [0|65535] "mV"  PC
 SG_ CSC_Ucell_102_18 m14 : 48|16@1+ (1,0) [0|65535] "mV"  PC
 SG_ CSC_Ucell_103_18 m15 : 16|16@1+ (1,0) [0|65535] "mV"  PC
 SG_ CSC_Ucell_104_18 m15 : 32|16@1+ (1,0) [0|65535] "mV"  PC
 SG_ CSC_Ucell_105_18 m15 : 48|16@1+ (1,0) [0|65535] "mV"  PC
 SG_ CSC_Ucell_106_18 m16 : 16|16@1+ (1,0) [0|65535] "mV"  PC
 SG_ CSC_Ucell_107_18 m16 : 32|16@1+ (1,0) [0|65535] "mV"  PC
 SG_ CSC_Ucell_108_18 m16 : 48|16@1+ (1,0) [0|65535] "mV"  PC

CM_ SG_ 2334326636 S2A_PCBMaxTemp_44 "最高板温";
CM_ SG_ 2334326636 S2A_PCBMinTemp_44 "最低板温";
CM_ SG_ 2334326636 S2A_ChipPst_PCBMaxTemp_44 "最高板温所在chip号";
CM_ SG_ 2334326636 S2A_ChipPst_PCBMinTemp_44 "最低板温所在chip号";
CM_ SG_ 2334326636 S2A_CscPst_PCBMaxTemp_44 "最高板温所在CSC编号";
CM_ SG_ 2334326636 S2A_CscPst_PCBMinTemp_44 "最低板温所在CSC编号";
CM_ SG_ 2334326636 S2A_AFEMaxTemp_44 "最高AFE温度(只使用104S CSC)";
CM_ SG_ 2334326636 S2A_AFEMinTemp_44 "最低AFE温度(只使用104S CSC)";
CM_ SG_ 2334326636 S2A_ChipPst_AFEMaxTemp_44 "最高AFE温度的chip编号(只使用104S CSC)";
CM_ SG_ 2334326636 S2A_ChipPst_AFEMinTemp_44 "最低AFE温度的chip编号(只使用104S CSC)";
CM_ SG_ 2334326636 S2A_CscPst_AFEMaxTemp_44 "最高AFE温度所在CSC编号(只使用104S CSC)";
CM_ SG_ 2334326636 S2A_CscPst_AFEMinTemp_44 "最低AFE温度所在CSC编号(只使用104S CSC)";
CM_ SG_ 2334326637 S2A_PCBMaxTemp_45 "最高板温";
CM_ SG_ 2334326637 S2A_PCBMinTemp_45 "最低板温";
CM_ SG_ 2334326637 S2A_ChipPst_PCBMaxTemp_45 "最高板温所在chip号";
CM_ SG_ 2334326637 S2A_ChipPst_PCBMinTemp_45 "最低板温所在chip号";
CM_ SG_ 2334326637 S2A_CscPst_PCBMaxTemp_45 "最高板温所在CSC编号";
CM_ SG_ 2334326637 S2A_CscPst_PCBMinTemp_45 "最低板温所在CSC编号";
CM_ SG_ 2334326637 S2A_AFEMaxTemp_45 "最高AFE温度(只使用104S CSC)";
CM_ SG_ 2334326637 S2A_AFEMinTemp_45 "最低AFE温度(只使用104S CSC)";
CM_ SG_ 2334326637 S2A_ChipPst_AFEMaxTemp_45 "最高AFE温度的chip编号(只使用104S CSC)";
CM_ SG_ 2334326637 S2A_ChipPst_AFEMinTemp_45 "最低AFE温度的chip编号(只使用104S CSC)";
CM_ SG_ 2334326637 S2A_CscPst_AFEMaxTemp_45 "最高AFE温度所在CSC编号(只使用104S CSC)";
CM_ SG_ 2334326637 S2A_CscPst_AFEMinTemp_45 "最低AFE温度所在CSC编号(只使用104S CSC)";
CM_ SG_ 2334326638 S2A_PCBMaxTemp_46 "最高板温";
CM_ SG_ 2334326638 S2A_PCBMinTemp_46 "最低板温";
CM_ SG_ 2334326638 S2A_ChipPst_PCBMaxTemp_46 "最高板温所在chip号";
CM_ SG_ 2334326638 S2A_ChipPst_PCBMinTemp_46 "最低板温所在chip号";
CM_ SG_ 2334326638 S2A_CscPst_PCBMaxTemp_46 "最高板温所在CSC编号";
CM_ SG_ 2334326638 S2A_CscPst_PCBMinTemp_46 "最低板温所在CSC编号";
CM_ SG_ 2334326638 S2A_AFEMaxTemp_46 "最高AFE温度(只使用104S CSC)";
CM_ SG_ 2334326638 S2A_AFEMinTemp_46 "最低AFE温度(只使用104S CSC)";
CM_ SG_ 2334326638 S2A_ChipPst_AFEMaxTemp_46 "最高AFE温度的chip编号(只使用104S CSC)";
CM_ SG_ 2334326638 S2A_ChipPst_AFEMinTemp_46 "最低AFE温度的chip编号(只使用104S CSC)";
CM_ SG_ 2334326638 S2A_CscPst_AFEMaxTemp_46 "最高AFE温度所在CSC编号(只使用104S CSC)";
CM_ SG_ 2334326638 S2A_CscPst_AFEMinTemp_46 "最低AFE温度所在CSC编号(只使用104S CSC)";
CM_ SG_ 2334326639 S2A_PCBMaxTemp_47 "最高板温";
CM_ SG_ 2334326639 S2A_PCBMinTemp_47 "最低板温";
CM_ SG_ 2334326639 S2A_ChipPst_PCBMaxTemp_47 "最高板温所在chip号";
CM_ SG_ 2334326639 S2A_ChipPst_PCBMinTemp_47 "最低板温所在chip号";
CM_ SG_ 2334326639 S2A_CscPst_PCBMaxTemp_47 "最高板温所在CSC编号";
CM_ SG_ 2334326639 S2A_CscPst_PCBMinTemp_47 "最低板温所在CSC编号";
CM_ SG_ 2334326639 S2A_AFEMaxTemp_47 "最高AFE温度(只使用104S CSC)";
CM_ SG_ 2334326639 S2A_AFEMinTemp_47 "最低AFE温度(只使用104S CSC)";
CM_ SG_ 2334326639 S2A_ChipPst_AFEMaxTemp_47 "最高AFE温度的chip编号(只使用104S CSC)";
CM_ SG_ 2334326639 S2A_ChipPst_AFEMinTemp_47 "最低AFE温度的chip编号(只使用104S CSC)";
CM_ SG_ 2334326639 S2A_CscPst_AFEMaxTemp_47 "最高AFE温度所在CSC编号(只使用104S CSC)";
CM_ SG_ 2334326639 S2A_CscPst_AFEMinTemp_47 "最低AFE温度所在CSC编号(只使用104S CSC)";
CM_ SG_ 2334326640 S2A_PCBMaxTemp_48 "最高板温";
CM_ SG_ 2334326640 S2A_PCBMinTemp_48 "最低板温";
CM_ SG_ 2334326640 S2A_ChipPst_PCBMaxTemp_48 "最高板温所在chip号";
CM_ SG_ 2334326640 S2A_ChipPst_PCBMinTemp_48 "最低板温所在chip号";
CM_ SG_ 2334326640 S2A_CscPst_PCBMaxTemp_48 "最高板温所在CSC编号";
CM_ SG_ 2334326640 S2A_CscPst_PCBMinTemp_48 "最低板温所在CSC编号";
CM_ SG_ 2334326640 S2A_AFEMaxTemp_48 "最高AFE温度(只使用104S CSC)";
CM_ SG_ 2334326640 S2A_AFEMinTemp_48 "最低AFE温度(只使用104S CSC)";
CM_ SG_ 2334326640 S2A_ChipPst_AFEMaxTemp_48 "最高AFE温度的chip编号(只使用104S CSC)";
CM_ SG_ 2334326640 S2A_ChipPst_AFEMinTemp_48 "最低AFE温度的chip编号(只使用104S CSC)";
CM_ SG_ 2334326640 S2A_CscPst_AFEMaxTemp_48 "最高AFE温度所在CSC编号(只使用104S CSC)";
CM_ SG_ 2334326640 S2A_CscPst_AFEMinTemp_48 "最低AFE温度所在CSC编号(只使用104S CSC)";
CM_ SG_ 2334326641 S2A_PCBMaxTemp_49 "最高板温";
CM_ SG_ 2334326641 S2A_PCBMinTemp_49 "最低板温";
CM_ SG_ 2334326641 S2A_ChipPst_PCBMaxTemp_49 "最高板温所在chip号";
CM_ SG_ 2334326641 S2A_ChipPst_PCBMinTemp_49 "最低板温所在chip号";
CM_ SG_ 2334326641 S2A_CscPst_PCBMaxTemp_49 "最高板温所在CSC编号";
CM_ SG_ 2334326641 S2A_CscPst_PCBMinTemp_49 "最低板温所在CSC编号";
CM_ SG_ 2334326641 S2A_AFEMaxTemp_49 "最高AFE温度(只使用104S CSC)";
CM_ SG_ 2334326641 S2A_AFEMinTemp_49 "最低AFE温度(只使用104S CSC)";
CM_ SG_ 2334326641 S2A_ChipPst_AFEMaxTemp_49 "最高AFE温度的chip编号(只使用104S CSC)";
CM_ SG_ 2334326641 S2A_ChipPst_AFEMinTemp_49 "最低AFE温度的chip编号(只使用104S CSC)";
CM_ SG_ 2334326641 S2A_CscPst_AFEMaxTemp_49 "最高AFE温度所在CSC编号(只使用104S CSC)";
CM_ SG_ 2334326641 S2A_CscPst_AFEMinTemp_49 "最低AFE温度所在CSC编号(只使用104S CSC)";
CM_ SG_ 2334326642 S2A_PCBMaxTemp_50 "最高板温";
CM_ SG_ 2334326642 S2A_PCBMinTemp_50 "最低板温";
CM_ SG_ 2334326642 S2A_ChipPst_PCBMaxTemp_50 "最高板温所在chip号";
CM_ SG_ 2334326642 S2A_ChipPst_PCBMinTemp_50 "最低板温所在chip号";
CM_ SG_ 2334326642 S2A_CscPst_PCBMaxTemp_50 "最高板温所在CSC编号";
CM_ SG_ 2334326642 S2A_CscPst_PCBMinTemp_50 "最低板温所在CSC编号";
CM_ SG_ 2334326642 S2A_AFEMaxTemp_50 "最高AFE温度(只使用104S CSC)";
CM_ SG_ 2334326642 S2A_AFEMinTemp_50 "最低AFE温度(只使用104S CSC)";
CM_ SG_ 2334326642 S2A_ChipPst_AFEMaxTemp_50 "最高AFE温度的chip编号(只使用104S CSC)";
CM_ SG_ 2334326642 S2A_ChipPst_AFEMinTemp_50 "最低AFE温度的chip编号(只使用104S CSC)";
CM_ SG_ 2334326642 S2A_CscPst_AFEMaxTemp_50 "最高AFE温度所在CSC编号(只使用104S CSC)";
CM_ SG_ 2334326642 S2A_CscPst_AFEMinTemp_50 "最低AFE温度所在CSC编号(只使用104S CSC)";
CM_ SG_ 2334326643 S2A_PCBMaxTemp_51 "最高板温";
CM_ SG_ 2334326643 S2A_PCBMinTemp_51 "最低板温";
CM_ SG_ 2334326643 S2A_ChipPst_PCBMaxTemp_51 "最高板温所在chip号";
CM_ SG_ 2334326643 S2A_ChipPst_PCBMinTemp_51 "最低板温所在chip号";
CM_ SG_ 2334326643 S2A_CscPst_PCBMaxTemp_51 "最高板温所在CSC编号";
CM_ SG_ 2334326643 S2A_CscPst_PCBMinTemp_51 "最低板温所在CSC编号";
CM_ SG_ 2334326643 S2A_AFEMaxTemp_51 "最高AFE温度(只使用104S CSC)";
CM_ SG_ 2334326643 S2A_AFEMinTemp_51 "最低AFE温度(只使用104S CSC)";
CM_ SG_ 2334326643 S2A_ChipPst_AFEMaxTemp_51 "最高AFE温度的chip编号(只使用104S CSC)";
CM_ SG_ 2334326643 S2A_ChipPst_AFEMinTemp_51 "最低AFE温度的chip编号(只使用104S CSC)";
CM_ SG_ 2334326643 S2A_CscPst_AFEMaxTemp_51 "最高AFE温度所在CSC编号(只使用104S CSC)";
CM_ SG_ 2334326643 S2A_CscPst_AFEMinTemp_51 "最低AFE温度所在CSC编号(只使用104S CSC)";
CM_ SG_ 2334326644 S2A_PCBMaxTemp_52 "最高板温";
CM_ SG_ 2334326644 S2A_PCBMinTemp_52 "最低板温";
CM_ SG_ 2334326644 S2A_ChipPst_PCBMaxTemp_52 "最高板温所在chip号";
CM_ SG_ 2334326644 S2A_ChipPst_PCBMinTemp_52 "最低板温所在chip号";
CM_ SG_ 2334326644 S2A_CscPst_PCBMaxTemp_52 "最高板温所在CSC编号";
CM_ SG_ 2334326644 S2A_CscPst_PCBMinTemp_52 "最低板温所在CSC编号";
CM_ SG_ 2334326644 S2A_AFEMaxTemp_52 "最高AFE温度(只使用104S CSC)";
CM_ SG_ 2334326644 S2A_AFEMinTemp_52 "最低AFE温度(只使用104S CSC)";
CM_ SG_ 2334326644 S2A_ChipPst_AFEMaxTemp_52 "最高AFE温度的chip编号(只使用104S CSC)";
CM_ SG_ 2334326644 S2A_ChipPst_AFEMinTemp_52 "最低AFE温度的chip编号(只使用104S CSC)";
CM_ SG_ 2334326644 S2A_CscPst_AFEMaxTemp_52 "最高AFE温度所在CSC编号(只使用104S CSC)";
CM_ SG_ 2334326644 S2A_CscPst_AFEMinTemp_52 "最低AFE温度所在CSC编号(只使用104S CSC)";
CM_ SG_ 2334326645 S2A_PCBMaxTemp_53 "最高板温";
CM_ SG_ 2334326645 S2A_PCBMinTemp_53 "最低板温";
CM_ SG_ 2334326645 S2A_ChipPst_PCBMaxTemp_53 "最高板温所在chip号";
CM_ SG_ 2334326645 S2A_ChipPst_PCBMinTemp_53 "最低板温所在chip号";
CM_ SG_ 2334326645 S2A_CscPst_PCBMaxTemp_53 "最高板温所在CSC编号";
CM_ SG_ 2334326645 S2A_CscPst_PCBMinTemp_53 "最低板温所在CSC编号";
CM_ SG_ 2334326645 S2A_AFEMaxTemp_53 "最高AFE温度(只使用104S CSC)";
CM_ SG_ 2334326645 S2A_AFEMinTemp_53 "最低AFE温度(只使用104S CSC)";
CM_ SG_ 2334326645 S2A_ChipPst_AFEMaxTemp_53 "最高AFE温度的chip编号(只使用104S CSC)";
CM_ SG_ 2334326645 S2A_ChipPst_AFEMinTemp_53 "最低AFE温度的chip编号(只使用104S CSC)";
CM_ SG_ 2334326645 S2A_CscPst_AFEMaxTemp_53 "最高AFE温度所在CSC编号(只使用104S CSC)";
CM_ SG_ 2334326645 S2A_CscPst_AFEMinTemp_53 "最低AFE温度所在CSC编号(只使用104S CSC)";
CM_ SG_ 2334326646 S2A_PCBMaxTemp_54 "最高板温";
CM_ SG_ 2334326646 S2A_PCBMinTemp_54 "最低板温";
CM_ SG_ 2334326646 S2A_ChipPst_PCBMaxTemp_54 "最高板温所在chip号";
CM_ SG_ 2334326646 S2A_ChipPst_PCBMinTemp_54 "最低板温所在chip号";
CM_ SG_ 2334326646 S2A_CscPst_PCBMaxTemp_54 "最高板温所在CSC编号";
CM_ SG_ 2334326646 S2A_CscPst_PCBMinTemp_54 "最低板温所在CSC编号";
CM_ SG_ 2334326646 S2A_AFEMaxTemp_54 "最高AFE温度(只使用104S CSC)";
CM_ SG_ 2334326646 S2A_AFEMinTemp_54 "最低AFE温度(只使用104S CSC)";
CM_ SG_ 2334326646 S2A_ChipPst_AFEMaxTemp_54 "最高AFE温度的chip编号(只使用104S CSC)";
CM_ SG_ 2334326646 S2A_ChipPst_AFEMinTemp_54 "最低AFE温度的chip编号(只使用104S CSC)";
CM_ SG_ 2334326646 S2A_CscPst_AFEMaxTemp_54 "最高AFE温度所在CSC编号(只使用104S CSC)";
CM_ SG_ 2334326646 S2A_CscPst_AFEMinTemp_54 "最低AFE温度所在CSC编号(只使用104S CSC)";
CM_ SG_ 2334326647 S2A_PCBMaxTemp_55 "最高板温";
CM_ SG_ 2334326647 S2A_PCBMinTemp_55 "最低板温";
CM_ SG_ 2334326647 S2A_ChipPst_PCBMaxTemp_55 "最高板温所在chip号";
CM_ SG_ 2334326647 S2A_ChipPst_PCBMinTemp_55 "最低板温所在chip号";
CM_ SG_ 2334326647 S2A_CscPst_PCBMaxTemp_55 "最高板温所在CSC编号";
CM_ SG_ 2334326647 S2A_CscPst_PCBMinTemp_55 "最低板温所在CSC编号";
CM_ SG_ 2334326647 S2A_AFEMaxTemp_55 "最高AFE温度(只使用104S CSC)";
CM_ SG_ 2334326647 S2A_AFEMinTemp_55 "最低AFE温度(只使用104S CSC)";
CM_ SG_ 2334326647 S2A_ChipPst_AFEMaxTemp_55 "最高AFE温度的chip编号(只使用104S CSC)";
CM_ SG_ 2334326647 S2A_ChipPst_AFEMinTemp_55 "最低AFE温度的chip编号(只使用104S CSC)";
CM_ SG_ 2334326647 S2A_CscPst_AFEMaxTemp_55 "最高AFE温度所在CSC编号(只使用104S CSC)";
CM_ SG_ 2334326647 S2A_CscPst_AFEMinTemp_55 "最低AFE温度所在CSC编号(只使用104S CSC)";
CM_ SG_ 2334326648 S2A_PCBMaxTemp_56 "最高板温";
CM_ SG_ 2334326648 S2A_PCBMinTemp_56 "最低板温";
CM_ SG_ 2334326648 S2A_ChipPst_PCBMaxTemp_56 "最高板温所在chip号";
CM_ SG_ 2334326648 S2A_ChipPst_PCBMinTemp_56 "最低板温所在chip号";
CM_ SG_ 2334326648 S2A_CscPst_PCBMaxTemp_56 "最高板温所在CSC编号";
CM_ SG_ 2334326648 S2A_CscPst_PCBMinTemp_56 "最低板温所在CSC编号";
CM_ SG_ 2334326648 S2A_AFEMaxTemp_56 "最高AFE温度(只使用104S CSC)";
CM_ SG_ 2334326648 S2A_AFEMinTemp_56 "最低AFE温度(只使用104S CSC)";
CM_ SG_ 2334326648 S2A_ChipPst_AFEMaxTemp_56 "最高AFE温度的chip编号(只使用104S CSC)";
CM_ SG_ 2334326648 S2A_ChipPst_AFEMinTemp_56 "最低AFE温度的chip编号(只使用104S CSC)";
CM_ SG_ 2334326648 S2A_CscPst_AFEMaxTemp_56 "最高AFE温度所在CSC编号(只使用104S CSC)";
CM_ SG_ 2334326648 S2A_CscPst_AFEMinTemp_56 "最低AFE温度所在CSC编号(只使用104S CSC)";
CM_ SG_ 2334326649 S2A_PCBMaxTemp_57 "最高板温";
CM_ SG_ 2334326649 S2A_PCBMinTemp_57 "最低板温";
CM_ SG_ 2334326649 S2A_ChipPst_PCBMaxTemp_57 "最高板温所在chip号";
CM_ SG_ 2334326649 S2A_ChipPst_PCBMinTemp_57 "最低板温所在chip号";
CM_ SG_ 2334326649 S2A_CscPst_PCBMaxTemp_57 "最高板温所在CSC编号";
CM_ SG_ 2334326649 S2A_CscPst_PCBMinTemp_57 "最低板温所在CSC编号";
CM_ SG_ 2334326649 S2A_AFEMaxTemp_57 "最高AFE温度(只使用104S CSC)";
CM_ SG_ 2334326649 S2A_AFEMinTemp_57 "最低AFE温度(只使用104S CSC)";
CM_ SG_ 2334326649 S2A_ChipPst_AFEMaxTemp_57 "最高AFE温度的chip编号(只使用104S CSC)";
CM_ SG_ 2334326649 S2A_ChipPst_AFEMinTemp_57 "最低AFE温度的chip编号(只使用104S CSC)";
CM_ SG_ 2334326649 S2A_CscPst_AFEMaxTemp_57 "最高AFE温度所在CSC编号(只使用104S CSC)";
CM_ SG_ 2334326649 S2A_CscPst_AFEMinTemp_57 "最低AFE温度所在CSC编号(只使用104S CSC)";
CM_ SG_ 2334326650 S2A_PCBMaxTemp_58 "最高板温";
CM_ SG_ 2334326650 S2A_PCBMinTemp_58 "最低板温";
CM_ SG_ 2334326650 S2A_ChipPst_PCBMaxTemp_58 "最高板温所在chip号";
CM_ SG_ 2334326650 S2A_ChipPst_PCBMinTemp_58 "最低板温所在chip号";
CM_ SG_ 2334326650 S2A_CscPst_PCBMaxTemp_58 "最高板温所在CSC编号";
CM_ SG_ 2334326650 S2A_CscPst_PCBMinTemp_58 "最低板温所在CSC编号";
CM_ SG_ 2334326650 S2A_AFEMaxTemp_58 "最高AFE温度(只使用104S CSC)";
CM_ SG_ 2334326650 S2A_AFEMinTemp_58 "最低AFE温度(只使用104S CSC)";
CM_ SG_ 2334326650 S2A_ChipPst_AFEMaxTemp_58 "最高AFE温度的chip编号(只使用104S CSC)";
CM_ SG_ 2334326650 S2A_ChipPst_AFEMinTemp_58 "最低AFE温度的chip编号(只使用104S CSC)";
CM_ SG_ 2334326650 S2A_CscPst_AFEMaxTemp_58 "最高AFE温度所在CSC编号(只使用104S CSC)";
CM_ SG_ 2334326650 S2A_CscPst_AFEMinTemp_58 "最低AFE温度所在CSC编号(只使用104S CSC)";
CM_ SG_ 2334326651 S2A_PCBMaxTemp_59 "最高板温";
CM_ SG_ 2334326651 S2A_PCBMinTemp_59 "最低板温";
CM_ SG_ 2334326651 S2A_ChipPst_PCBMaxTemp_59 "最高板温所在chip号";
CM_ SG_ 2334326651 S2A_ChipPst_PCBMinTemp_59 "最低板温所在chip号";
CM_ SG_ 2334326651 S2A_CscPst_PCBMaxTemp_59 "最高板温所在CSC编号";
CM_ SG_ 2334326651 S2A_CscPst_PCBMinTemp_59 "最低板温所在CSC编号";
CM_ SG_ 2334326651 S2A_AFEMaxTemp_59 "最高AFE温度(只使用104S CSC)";
CM_ SG_ 2334326651 S2A_AFEMinTemp_59 "最低AFE温度(只使用104S CSC)";
CM_ SG_ 2334326651 S2A_ChipPst_AFEMaxTemp_59 "最高AFE温度的chip编号(只使用104S CSC)";
CM_ SG_ 2334326651 S2A_ChipPst_AFEMinTemp_59 "最低AFE温度的chip编号(只使用104S CSC)";
CM_ SG_ 2334326651 S2A_CscPst_AFEMaxTemp_59 "最高AFE温度所在CSC编号(只使用104S CSC)";
CM_ SG_ 2334326651 S2A_CscPst_AFEMinTemp_59 "最低AFE温度所在CSC编号(只使用104S CSC)";
CM_ SG_ 2334326652 S2A_PCBMaxTemp_60 "最高板温";
CM_ SG_ 2334326652 S2A_PCBMinTemp_60 "最低板温";
CM_ SG_ 2334326652 S2A_ChipPst_PCBMaxTemp_60 "最高板温所在chip号";
CM_ SG_ 2334326652 S2A_ChipPst_PCBMinTemp_60 "最低板温所在chip号";
CM_ SG_ 2334326652 S2A_CscPst_PCBMaxTemp_60 "最高板温所在CSC编号";
CM_ SG_ 2334326652 S2A_CscPst_PCBMinTemp_60 "最低板温所在CSC编号";
CM_ SG_ 2334326652 S2A_AFEMaxTemp_60 "最高AFE温度(只使用104S CSC)";
CM_ SG_ 2334326652 S2A_AFEMinTemp_60 "最低AFE温度(只使用104S CSC)";
CM_ SG_ 2334326652 S2A_ChipPst_AFEMaxTemp_60 "最高AFE温度的chip编号(只使用104S CSC)";
CM_ SG_ 2334326652 S2A_ChipPst_AFEMinTemp_60 "最低AFE温度的chip编号(只使用104S CSC)";
CM_ SG_ 2334326652 S2A_CscPst_AFEMaxTemp_60 "最高AFE温度所在CSC编号(只使用104S CSC)";
CM_ SG_ 2334326652 S2A_CscPst_AFEMinTemp_60 "最低AFE温度所在CSC编号(只使用104S CSC)";
CM_ SG_ 2334326653 S2A_PCBMaxTemp_61 "最高板温";
CM_ SG_ 2334326653 S2A_PCBMinTemp_61 "最低板温";
CM_ SG_ 2334326653 S2A_ChipPst_PCBMaxTemp_61 "最高板温所在chip号";
CM_ SG_ 2334326653 S2A_ChipPst_PCBMinTemp_61 "最低板温所在chip号";
CM_ SG_ 2334326653 S2A_CscPst_PCBMaxTemp_61 "最高板温所在CSC编号";
CM_ SG_ 2334326653 S2A_CscPst_PCBMinTemp_61 "最低板温所在CSC编号";
CM_ SG_ 2334326653 S2A_AFEMaxTemp_61 "最高AFE温度(只使用104S CSC)";
CM_ SG_ 2334326653 S2A_AFEMinTemp_61 "最低AFE温度(只使用104S CSC)";
CM_ SG_ 2334326653 S2A_ChipPst_AFEMaxTemp_61 "最高AFE温度的chip编号(只使用104S CSC)";
CM_ SG_ 2334326653 S2A_ChipPst_AFEMinTemp_61 "最低AFE温度的chip编号(只使用104S CSC)";
CM_ SG_ 2334326653 S2A_CscPst_AFEMaxTemp_61 "最高AFE温度所在CSC编号(只使用104S CSC)";
CM_ SG_ 2334326653 S2A_CscPst_AFEMinTemp_61 "最低AFE温度所在CSC编号(只使用104S CSC)";
CM_ SG_ 2334326654 S2A_PCBMaxTemp_62 "最高板温";
CM_ SG_ 2334326654 S2A_PCBMinTemp_62 "最低板温";
CM_ SG_ 2334326654 S2A_ChipPst_PCBMaxTemp_62 "最高板温所在chip号";
CM_ SG_ 2334326654 S2A_ChipPst_PCBMinTemp_62 "最低板温所在chip号";
CM_ SG_ 2334326654 S2A_CscPst_PCBMaxTemp_62 "最高板温所在CSC编号";
CM_ SG_ 2334326654 S2A_CscPst_PCBMinTemp_62 "最低板温所在CSC编号";
CM_ SG_ 2334326654 S2A_AFEMaxTemp_62 "最高AFE温度(只使用104S CSC)";
CM_ SG_ 2334326654 S2A_AFEMinTemp_62 "最低AFE温度(只使用104S CSC)";
CM_ SG_ 2334326654 S2A_ChipPst_AFEMaxTemp_62 "最高AFE温度的chip编号(只使用104S CSC)";
CM_ SG_ 2334326654 S2A_ChipPst_AFEMinTemp_62 "最低AFE温度的chip编号(只使用104S CSC)";
CM_ SG_ 2334326654 S2A_CscPst_AFEMaxTemp_62 "最高AFE温度所在CSC编号(只使用104S CSC)";
CM_ SG_ 2334326654 S2A_CscPst_AFEMinTemp_62 "最低AFE温度所在CSC编号(只使用104S CSC)";
CM_ SG_ 2334326655 S2A_PCBMaxTemp_63 "最高板温";
CM_ SG_ 2334326655 S2A_PCBMinTemp_63 "最低板温";
CM_ SG_ 2334326655 S2A_ChipPst_PCBMaxTemp_63 "最高板温所在chip号";
CM_ SG_ 2334326655 S2A_ChipPst_PCBMinTemp_63 "最低板温所在chip号";
CM_ SG_ 2334326655 S2A_CscPst_PCBMaxTemp_63 "最高板温所在CSC编号";
CM_ SG_ 2334326655 S2A_CscPst_PCBMinTemp_63 "最低板温所在CSC编号";
CM_ SG_ 2334326655 S2A_AFEMaxTemp_63 "最高AFE温度(只使用104S CSC)";
CM_ SG_ 2334326655 S2A_AFEMinTemp_63 "最低AFE温度(只使用104S CSC)";
CM_ SG_ 2334326655 S2A_ChipPst_AFEMaxTemp_63 "最高AFE温度的chip编号(只使用104S CSC)";
CM_ SG_ 2334326655 S2A_ChipPst_AFEMinTemp_63 "最低AFE温度的chip编号(只使用104S CSC)";
CM_ SG_ 2334326655 S2A_CscPst_AFEMaxTemp_63 "最高AFE温度所在CSC编号(只使用104S CSC)";
CM_ SG_ 2334326655 S2A_CscPst_AFEMinTemp_63 "最低AFE温度所在CSC编号(只使用104S CSC)";
CM_ SG_ 2400841281 CSC_U_No_01 "CSC号";
CM_ SG_ 2400841281 CSC_Ucell_Frame_Index_01 "当前CSC中单体电压数据帧序号";
CM_ SG_ 2400841281 CSC_Ucell_58_01 "58 电池单体电压";
CM_ SG_ 2400841281 CSC_Ucell_59_01 "59 电池单体电压";
CM_ SG_ 2400841281 CSC_Ucell_60_01 "60 电池单体电压";
CM_ SG_ 2400841281 CSC_Ucell_61_01 "61 电池单体电压";
CM_ SG_ 2400841281 CSC_Ucell_62_01 "62 电池单体电压";
CM_ SG_ 2400841281 CSC_Ucell_63_01 "63 电池单体电压";
CM_ SG_ 2400841281 CSC_Ucell_64_01 "64 电池单体电压";
CM_ SG_ 2400841281 CSC_Ucell_65_01 "65 电池单体电压";
CM_ SG_ 2400841281 CSC_Ucell_66_01 "66 电池单体电压";
CM_ SG_ 2400841281 CSC_Ucell_67_01 "67 电池单体电压";
CM_ SG_ 2400841281 CSC_Ucell_68_01 "68 电池单体电压";
CM_ SG_ 2400841281 CSC_Ucell_69_01 "69 电池单体电压";
CM_ SG_ 2400841281 CSC_Ucell_70_01 "70 电池单体电压";
CM_ SG_ 2400841281 CSC_Ucell_71_01 "71 电池单体电压";
CM_ SG_ 2400841281 CSC_Ucell_72_01 "72 电池单体电压";
CM_ SG_ 2400841281 CSC_Ucell_73_01 "73 电池单体电压";
CM_ SG_ 2400841281 CSC_Ucell_74_01 "74 电池单体电压";
CM_ SG_ 2400841281 CSC_Ucell_75_01 "75 电池单体电压";
CM_ SG_ 2400841281 CSC_Ucell_76_01 "76 电池单体电压";
CM_ SG_ 2400841281 CSC_Ucell_77_01 "77 电池单体电压";
CM_ SG_ 2400841281 CSC_Ucell_78_01 "78 电池单体电压";
CM_ SG_ 2400841281 CSC_Ucell_79_01 "79 电池单体电压";
CM_ SG_ 2400841281 CSC_Ucell_80_01 "80 电池单体电压";
CM_ SG_ 2400841281 CSC_Ucell_81_01 "81 电池单体电压";
CM_ SG_ 2400841281 CSC_Ucell_82_01 "82 电池单体电压";
CM_ SG_ 2400841281 CSC_Ucell_83_01 "83 电池单体电压";
CM_ SG_ 2400841281 CSC_Ucell_84_01 "84 电池单体电压";
CM_ SG_ 2400841281 CSC_Ucell_85_01 "85 电池单体电压";
CM_ SG_ 2400841281 CSC_Ucell_86_01 "86 电池单体电压";
CM_ SG_ 2400841281 CSC_Ucell_87_01 "87 电池单体电压";
CM_ SG_ 2400841281 CSC_Ucell_88_01 "88 电池单体电压";
CM_ SG_ 2400841281 CSC_Ucell_89_01 "89 电池单体电压";
CM_ SG_ 2400841281 CSC_Ucell_90_01 "90 电池单体电压";
CM_ SG_ 2400841281 CSC_Ucell_91_01 "91 电池单体电压";
CM_ SG_ 2400841281 CSC_Ucell_92_01 "92 电池单体电压";
CM_ SG_ 2400841281 CSC_Ucell_93_01 "93 电池单体电压";
CM_ SG_ 2400841281 CSC_Ucell_94_01 "94 电池单体电压";
CM_ SG_ 2400841281 CSC_Ucell_95_01 "95 电池单体电压";
CM_ SG_ 2400841281 CSC_Ucell_96_01 "96 电池单体电压";
CM_ SG_ 2400841281 CSC_Ucell_97_01 "97 电池单体电压";
CM_ SG_ 2400841281 CSC_Ucell_98_01 "98 电池单体电压";
CM_ SG_ 2400841281 CSC_Ucell_99_01 "99 电池单体电压";
CM_ SG_ 2400841281 CSC_Ucell_100_01 "100 电池单体电压";
CM_ SG_ 2400841281 CSC_Ucell_101_01 "101 电池单体电压";
CM_ SG_ 2400841281 CSC_Ucell_102_01 "102 电池单体电压";
CM_ SG_ 2400841281 CSC_Ucell_103_01 "103 电池单体电压";
CM_ SG_ 2400841281 CSC_Ucell_104_01 "104 电池单体电压";
CM_ SG_ 2400841281 CSC_Ucell_105_01 "105 电池单体电压";
CM_ SG_ 2400841281 CSC_Ucell_106_01 "106 电池单体电压";
CM_ SG_ 2400841281 CSC_Ucell_107_01 "107 电池单体电压";
CM_ SG_ 2400841281 CSC_Ucell_108_01 "108 电池单体电压";
CM_ SG_ 2400841282 CSC_U_No_02 "CSC号";
CM_ SG_ 2400841282 CSC_Ucell_Frame_Index_02 "当前CSC中单体电压数据帧序号";
CM_ SG_ 2400841282 CSC_Ucell_58_02 "58 电池单体电压";
CM_ SG_ 2400841282 CSC_Ucell_59_02 "59 电池单体电压";
CM_ SG_ 2400841282 CSC_Ucell_60_02 "60 电池单体电压";
CM_ SG_ 2400841282 CSC_Ucell_61_02 "61 电池单体电压";
CM_ SG_ 2400841282 CSC_Ucell_62_02 "62 电池单体电压";
CM_ SG_ 2400841282 CSC_Ucell_63_02 "63 电池单体电压";
CM_ SG_ 2400841282 CSC_Ucell_64_02 "64 电池单体电压";
CM_ SG_ 2400841282 CSC_Ucell_65_02 "65 电池单体电压";
CM_ SG_ 2400841282 CSC_Ucell_66_02 "66 电池单体电压";
CM_ SG_ 2400841282 CSC_Ucell_67_02 "67 电池单体电压";
CM_ SG_ 2400841282 CSC_Ucell_68_02 "68 电池单体电压";
CM_ SG_ 2400841282 CSC_Ucell_69_02 "69 电池单体电压";
CM_ SG_ 2400841282 CSC_Ucell_70_02 "70 电池单体电压";
CM_ SG_ 2400841282 CSC_Ucell_71_02 "71 电池单体电压";
CM_ SG_ 2400841282 CSC_Ucell_72_02 "72 电池单体电压";
CM_ SG_ 2400841282 CSC_Ucell_73_02 "73 电池单体电压";
CM_ SG_ 2400841282 CSC_Ucell_74_02 "74 电池单体电压";
CM_ SG_ 2400841282 CSC_Ucell_75_02 "75 电池单体电压";
CM_ SG_ 2400841282 CSC_Ucell_76_02 "76 电池单体电压";
CM_ SG_ 2400841282 CSC_Ucell_77_02 "77 电池单体电压";
CM_ SG_ 2400841282 CSC_Ucell_78_02 "78 电池单体电压";
CM_ SG_ 2400841282 CSC_Ucell_79_02 "79 电池单体电压";
CM_ SG_ 2400841282 CSC_Ucell_80_02 "80 电池单体电压";
CM_ SG_ 2400841282 CSC_Ucell_81_02 "81 电池单体电压";
CM_ SG_ 2400841282 CSC_Ucell_82_02 "82 电池单体电压";
CM_ SG_ 2400841282 CSC_Ucell_83_02 "83 电池单体电压";
CM_ SG_ 2400841282 CSC_Ucell_84_02 "84 电池单体电压";
CM_ SG_ 2400841282 CSC_Ucell_85_02 "85 电池单体电压";
CM_ SG_ 2400841282 CSC_Ucell_86_02 "86 电池单体电压";
CM_ SG_ 2400841282 CSC_Ucell_87_02 "87 电池单体电压";
CM_ SG_ 2400841282 CSC_Ucell_88_02 "88 电池单体电压";
CM_ SG_ 2400841282 CSC_Ucell_89_02 "89 电池单体电压";
CM_ SG_ 2400841282 CSC_Ucell_90_02 "90 电池单体电压";
CM_ SG_ 2400841282 CSC_Ucell_91_02 "91 电池单体电压";
CM_ SG_ 2400841282 CSC_Ucell_92_02 "92 电池单体电压";
CM_ SG_ 2400841282 CSC_Ucell_93_02 "93 电池单体电压";
CM_ SG_ 2400841282 CSC_Ucell_94_02 "94 电池单体电压";
CM_ SG_ 2400841282 CSC_Ucell_95_02 "95 电池单体电压";
CM_ SG_ 2400841282 CSC_Ucell_96_02 "96 电池单体电压";
CM_ SG_ 2400841282 CSC_Ucell_97_02 "97 电池单体电压";
CM_ SG_ 2400841282 CSC_Ucell_98_02 "98 电池单体电压";
CM_ SG_ 2400841282 CSC_Ucell_99_02 "99 电池单体电压";
CM_ SG_ 2400841282 CSC_Ucell_100_02 "100 电池单体电压";
CM_ SG_ 2400841282 CSC_Ucell_101_02 "101 电池单体电压";
CM_ SG_ 2400841282 CSC_Ucell_102_02 "102 电池单体电压";
CM_ SG_ 2400841282 CSC_Ucell_103_02 "103 电池单体电压";
CM_ SG_ 2400841282 CSC_Ucell_104_02 "104 电池单体电压";
CM_ SG_ 2400841282 CSC_Ucell_105_02 "105 电池单体电压";
CM_ SG_ 2400841282 CSC_Ucell_106_02 "106 电池单体电压";
CM_ SG_ 2400841282 CSC_Ucell_107_02 "107 电池单体电压";
CM_ SG_ 2400841282 CSC_Ucell_108_02 "108 电池单体电压";
CM_ SG_ 2400841283 CSC_U_No_03 "CSC号";
CM_ SG_ 2400841283 CSC_Ucell_Frame_Index_03 "当前CSC中单体电压数据帧序号";
CM_ SG_ 2400841283 CSC_Ucell_58_03 "58 电池单体电压";
CM_ SG_ 2400841283 CSC_Ucell_59_03 "59 电池单体电压";
CM_ SG_ 2400841283 CSC_Ucell_60_03 "60 电池单体电压";
CM_ SG_ 2400841283 CSC_Ucell_61_03 "61 电池单体电压";
CM_ SG_ 2400841283 CSC_Ucell_62_03 "62 电池单体电压";
CM_ SG_ 2400841283 CSC_Ucell_63_03 "63 电池单体电压";
CM_ SG_ 2400841283 CSC_Ucell_64_03 "64 电池单体电压";
CM_ SG_ 2400841283 CSC_Ucell_65_03 "65 电池单体电压";
CM_ SG_ 2400841283 CSC_Ucell_66_03 "66 电池单体电压";
CM_ SG_ 2400841283 CSC_Ucell_67_03 "67 电池单体电压";
CM_ SG_ 2400841283 CSC_Ucell_68_03 "68 电池单体电压";
CM_ SG_ 2400841283 CSC_Ucell_69_03 "69 电池单体电压";
CM_ SG_ 2400841283 CSC_Ucell_70_03 "70 电池单体电压";
CM_ SG_ 2400841283 CSC_Ucell_71_03 "71 电池单体电压";
CM_ SG_ 2400841283 CSC_Ucell_72_03 "72 电池单体电压";
CM_ SG_ 2400841283 CSC_Ucell_73_03 "73 电池单体电压";
CM_ SG_ 2400841283 CSC_Ucell_74_03 "74 电池单体电压";
CM_ SG_ 2400841283 CSC_Ucell_75_03 "75 电池单体电压";
CM_ SG_ 2400841283 CSC_Ucell_76_03 "76 电池单体电压";
CM_ SG_ 2400841283 CSC_Ucell_77_03 "77 电池单体电压";
CM_ SG_ 2400841283 CSC_Ucell_78_03 "78 电池单体电压";
CM_ SG_ 2400841283 CSC_Ucell_79_03 "79 电池单体电压";
CM_ SG_ 2400841283 CSC_Ucell_80_03 "80 电池单体电压";
CM_ SG_ 2400841283 CSC_Ucell_81_03 "81 电池单体电压";
CM_ SG_ 2400841283 CSC_Ucell_82_03 "82 电池单体电压";
CM_ SG_ 2400841283 CSC_Ucell_83_03 "83 电池单体电压";
CM_ SG_ 2400841283 CSC_Ucell_84_03 "84 电池单体电压";
CM_ SG_ 2400841283 CSC_Ucell_85_03 "85 电池单体电压";
CM_ SG_ 2400841283 CSC_Ucell_86_03 "86 电池单体电压";
CM_ SG_ 2400841283 CSC_Ucell_87_03 "87 电池单体电压";
CM_ SG_ 2400841283 CSC_Ucell_88_03 "88 电池单体电压";
CM_ SG_ 2400841283 CSC_Ucell_89_03 "89 电池单体电压";
CM_ SG_ 2400841283 CSC_Ucell_90_03 "90 电池单体电压";
CM_ SG_ 2400841283 CSC_Ucell_91_03 "91 电池单体电压";
CM_ SG_ 2400841283 CSC_Ucell_92_03 "92 电池单体电压";
CM_ SG_ 2400841283 CSC_Ucell_93_03 "93 电池单体电压";
CM_ SG_ 2400841283 CSC_Ucell_94_03 "94 电池单体电压";
CM_ SG_ 2400841283 CSC_Ucell_95_03 "95 电池单体电压";
CM_ SG_ 2400841283 CSC_Ucell_96_03 "96 电池单体电压";
CM_ SG_ 2400841283 CSC_Ucell_97_03 "97 电池单体电压";
CM_ SG_ 2400841283 CSC_Ucell_98_03 "98 电池单体电压";
CM_ SG_ 2400841283 CSC_Ucell_99_03 "99 电池单体电压";
CM_ SG_ 2400841283 CSC_Ucell_100_03 "100 电池单体电压";
CM_ SG_ 2400841283 CSC_Ucell_101_03 "101 电池单体电压";
CM_ SG_ 2400841283 CSC_Ucell_102_03 "102 电池单体电压";
CM_ SG_ 2400841283 CSC_Ucell_103_03 "103 电池单体电压";
CM_ SG_ 2400841283 CSC_Ucell_104_03 "104 电池单体电压";
CM_ SG_ 2400841283 CSC_Ucell_105_03 "105 电池单体电压";
CM_ SG_ 2400841283 CSC_Ucell_106_03 "106 电池单体电压";
CM_ SG_ 2400841283 CSC_Ucell_107_03 "107 电池单体电压";
CM_ SG_ 2400841283 CSC_Ucell_108_03 "108 电池单体电压";
CM_ SG_ 2400841284 CSC_U_No_04 "CSC号";
CM_ SG_ 2400841284 CSC_Ucell_Frame_Index_04 "当前CSC中单体电压数据帧序号";
CM_ SG_ 2400841284 CSC_Ucell_58_04 "58 电池单体电压";
CM_ SG_ 2400841284 CSC_Ucell_59_04 "59 电池单体电压";
CM_ SG_ 2400841284 CSC_Ucell_60_04 "60 电池单体电压";
CM_ SG_ 2400841284 CSC_Ucell_61_04 "61 电池单体电压";
CM_ SG_ 2400841284 CSC_Ucell_62_04 "62 电池单体电压";
CM_ SG_ 2400841284 CSC_Ucell_63_04 "63 电池单体电压";
CM_ SG_ 2400841284 CSC_Ucell_64_04 "64 电池单体电压";
CM_ SG_ 2400841284 CSC_Ucell_65_04 "65 电池单体电压";
CM_ SG_ 2400841284 CSC_Ucell_66_04 "66 电池单体电压";
CM_ SG_ 2400841284 CSC_Ucell_67_04 "67 电池单体电压";
CM_ SG_ 2400841284 CSC_Ucell_68_04 "68 电池单体电压";
CM_ SG_ 2400841284 CSC_Ucell_69_04 "69 电池单体电压";
CM_ SG_ 2400841284 CSC_Ucell_70_04 "70 电池单体电压";
CM_ SG_ 2400841284 CSC_Ucell_71_04 "71 电池单体电压";
CM_ SG_ 2400841284 CSC_Ucell_72_04 "72 电池单体电压";
CM_ SG_ 2400841284 CSC_Ucell_73_04 "73 电池单体电压";
CM_ SG_ 2400841284 CSC_Ucell_74_04 "74 电池单体电压";
CM_ SG_ 2400841284 CSC_Ucell_75_04 "75 电池单体电压";
CM_ SG_ 2400841284 CSC_Ucell_76_04 "76 电池单体电压";
CM_ SG_ 2400841284 CSC_Ucell_77_04 "77 电池单体电压";
CM_ SG_ 2400841284 CSC_Ucell_78_04 "78 电池单体电压";
CM_ SG_ 2400841284 CSC_Ucell_79_04 "79 电池单体电压";
CM_ SG_ 2400841284 CSC_Ucell_80_04 "80 电池单体电压";
CM_ SG_ 2400841284 CSC_Ucell_81_04 "81 电池单体电压";
CM_ SG_ 2400841284 CSC_Ucell_82_04 "82 电池单体电压";
CM_ SG_ 2400841284 CSC_Ucell_83_04 "83 电池单体电压";
CM_ SG_ 2400841284 CSC_Ucell_84_04 "84 电池单体电压";
CM_ SG_ 2400841284 CSC_Ucell_85_04 "85 电池单体电压";
CM_ SG_ 2400841284 CSC_Ucell_86_04 "86 电池单体电压";
CM_ SG_ 2400841284 CSC_Ucell_87_04 "87 电池单体电压";
CM_ SG_ 2400841284 CSC_Ucell_88_04 "88 电池单体电压";
CM_ SG_ 2400841284 CSC_Ucell_89_04 "89 电池单体电压";
CM_ SG_ 2400841284 CSC_Ucell_90_04 "90 电池单体电压";
CM_ SG_ 2400841284 CSC_Ucell_91_04 "91 电池单体电压";
CM_ SG_ 2400841284 CSC_Ucell_92_04 "92 电池单体电压";
CM_ SG_ 2400841284 CSC_Ucell_93_04 "93 电池单体电压";
CM_ SG_ 2400841284 CSC_Ucell_94_04 "94 电池单体电压";
CM_ SG_ 2400841284 CSC_Ucell_95_04 "95 电池单体电压";
CM_ SG_ 2400841284 CSC_Ucell_96_04 "96 电池单体电压";
CM_ SG_ 2400841284 CSC_Ucell_97_04 "97 电池单体电压";
CM_ SG_ 2400841284 CSC_Ucell_98_04 "98 电池单体电压";
CM_ SG_ 2400841284 CSC_Ucell_99_04 "99 电池单体电压";
CM_ SG_ 2400841284 CSC_Ucell_100_04 "100 电池单体电压";
CM_ SG_ 2400841284 CSC_Ucell_101_04 "101 电池单体电压";
CM_ SG_ 2400841284 CSC_Ucell_102_04 "102 电池单体电压";
CM_ SG_ 2400841284 CSC_Ucell_103_04 "103 电池单体电压";
CM_ SG_ 2400841284 CSC_Ucell_104_04 "104 电池单体电压";
CM_ SG_ 2400841284 CSC_Ucell_105_04 "105 电池单体电压";
CM_ SG_ 2400841284 CSC_Ucell_106_04 "106 电池单体电压";
CM_ SG_ 2400841284 CSC_Ucell_107_04 "107 电池单体电压";
CM_ SG_ 2400841284 CSC_Ucell_108_04 "108 电池单体电压";
CM_ SG_ 2400841285 CSC_U_No_05 "CSC号";
CM_ SG_ 2400841285 CSC_Ucell_Frame_Index_05 "当前CSC中单体电压数据帧序号";
CM_ SG_ 2400841285 CSC_Ucell_58_05 "58 电池单体电压";
CM_ SG_ 2400841285 CSC_Ucell_59_05 "59 电池单体电压";
CM_ SG_ 2400841285 CSC_Ucell_60_05 "60 电池单体电压";
CM_ SG_ 2400841285 CSC_Ucell_61_05 "61 电池单体电压";
CM_ SG_ 2400841285 CSC_Ucell_62_05 "62 电池单体电压";
CM_ SG_ 2400841285 CSC_Ucell_63_05 "63 电池单体电压";
CM_ SG_ 2400841285 CSC_Ucell_64_05 "64 电池单体电压";
CM_ SG_ 2400841285 CSC_Ucell_65_05 "65 电池单体电压";
CM_ SG_ 2400841285 CSC_Ucell_66_05 "66 电池单体电压";
CM_ SG_ 2400841285 CSC_Ucell_67_05 "67 电池单体电压";
CM_ SG_ 2400841285 CSC_Ucell_68_05 "68 电池单体电压";
CM_ SG_ 2400841285 CSC_Ucell_69_05 "69 电池单体电压";
CM_ SG_ 2400841285 CSC_Ucell_70_05 "70 电池单体电压";
CM_ SG_ 2400841285 CSC_Ucell_71_05 "71 电池单体电压";
CM_ SG_ 2400841285 CSC_Ucell_72_05 "72 电池单体电压";
CM_ SG_ 2400841285 CSC_Ucell_73_05 "73 电池单体电压";
CM_ SG_ 2400841285 CSC_Ucell_74_05 "74 电池单体电压";
CM_ SG_ 2400841285 CSC_Ucell_75_05 "75 电池单体电压";
CM_ SG_ 2400841285 CSC_Ucell_76_05 "76 电池单体电压";
CM_ SG_ 2400841285 CSC_Ucell_77_05 "77 电池单体电压";
CM_ SG_ 2400841285 CSC_Ucell_78_05 "78 电池单体电压";
CM_ SG_ 2400841285 CSC_Ucell_79_05 "79 电池单体电压";
CM_ SG_ 2400841285 CSC_Ucell_80_05 "80 电池单体电压";
CM_ SG_ 2400841285 CSC_Ucell_81_05 "81 电池单体电压";
CM_ SG_ 2400841285 CSC_Ucell_82_05 "82 电池单体电压";
CM_ SG_ 2400841285 CSC_Ucell_83_05 "83 电池单体电压";
CM_ SG_ 2400841285 CSC_Ucell_84_05 "84 电池单体电压";
CM_ SG_ 2400841285 CSC_Ucell_85_05 "85 电池单体电压";
CM_ SG_ 2400841285 CSC_Ucell_86_05 "86 电池单体电压";
CM_ SG_ 2400841285 CSC_Ucell_87_05 "87 电池单体电压";
CM_ SG_ 2400841285 CSC_Ucell_88_05 "88 电池单体电压";
CM_ SG_ 2400841285 CSC_Ucell_89_05 "89 电池单体电压";
CM_ SG_ 2400841285 CSC_Ucell_90_05 "90 电池单体电压";
CM_ SG_ 2400841285 CSC_Ucell_91_05 "91 电池单体电压";
CM_ SG_ 2400841285 CSC_Ucell_92_05 "92 电池单体电压";
CM_ SG_ 2400841285 CSC_Ucell_93_05 "93 电池单体电压";
CM_ SG_ 2400841285 CSC_Ucell_94_05 "94 电池单体电压";
CM_ SG_ 2400841285 CSC_Ucell_95_05 "95 电池单体电压";
CM_ SG_ 2400841285 CSC_Ucell_96_05 "96 电池单体电压";
CM_ SG_ 2400841285 CSC_Ucell_97_05 "97 电池单体电压";
CM_ SG_ 2400841285 CSC_Ucell_98_05 "98 电池单体电压";
CM_ SG_ 2400841285 CSC_Ucell_99_05 "99 电池单体电压";
CM_ SG_ 2400841285 CSC_Ucell_100_05 "100 电池单体电压";
CM_ SG_ 2400841285 CSC_Ucell_101_05 "101 电池单体电压";
CM_ SG_ 2400841285 CSC_Ucell_102_05 "102 电池单体电压";
CM_ SG_ 2400841285 CSC_Ucell_103_05 "103 电池单体电压";
CM_ SG_ 2400841285 CSC_Ucell_104_05 "104 电池单体电压";
CM_ SG_ 2400841285 CSC_Ucell_105_05 "105 电池单体电压";
CM_ SG_ 2400841285 CSC_Ucell_106_05 "106 电池单体电压";
CM_ SG_ 2400841285 CSC_Ucell_107_05 "107 电池单体电压";
CM_ SG_ 2400841285 CSC_Ucell_108_05 "108 电池单体电压";
CM_ SG_ 2400841286 CSC_U_No_06 "CSC号";
CM_ SG_ 2400841286 CSC_Ucell_Frame_Index_06 "当前CSC中单体电压数据帧序号";
CM_ SG_ 2400841286 CSC_Ucell_58_06 "58 电池单体电压";
CM_ SG_ 2400841286 CSC_Ucell_59_06 "59 电池单体电压";
CM_ SG_ 2400841286 CSC_Ucell_60_06 "60 电池单体电压";
CM_ SG_ 2400841286 CSC_Ucell_61_06 "61 电池单体电压";
CM_ SG_ 2400841286 CSC_Ucell_62_06 "62 电池单体电压";
CM_ SG_ 2400841286 CSC_Ucell_63_06 "63 电池单体电压";
CM_ SG_ 2400841286 CSC_Ucell_64_06 "64 电池单体电压";
CM_ SG_ 2400841286 CSC_Ucell_65_06 "65 电池单体电压";
CM_ SG_ 2400841286 CSC_Ucell_66_06 "66 电池单体电压";
CM_ SG_ 2400841286 CSC_Ucell_67_06 "67 电池单体电压";
CM_ SG_ 2400841286 CSC_Ucell_68_06 "68 电池单体电压";
CM_ SG_ 2400841286 CSC_Ucell_69_06 "69 电池单体电压";
CM_ SG_ 2400841286 CSC_Ucell_70_06 "70 电池单体电压";
CM_ SG_ 2400841286 CSC_Ucell_71_06 "71 电池单体电压";
CM_ SG_ 2400841286 CSC_Ucell_72_06 "72 电池单体电压";
CM_ SG_ 2400841286 CSC_Ucell_73_06 "73 电池单体电压";
CM_ SG_ 2400841286 CSC_Ucell_74_06 "74 电池单体电压";
CM_ SG_ 2400841286 CSC_Ucell_75_06 "75 电池单体电压";
CM_ SG_ 2400841286 CSC_Ucell_76_06 "76 电池单体电压";
CM_ SG_ 2400841286 CSC_Ucell_77_06 "77 电池单体电压";
CM_ SG_ 2400841286 CSC_Ucell_78_06 "78 电池单体电压";
CM_ SG_ 2400841286 CSC_Ucell_79_06 "79 电池单体电压";
CM_ SG_ 2400841286 CSC_Ucell_80_06 "80 电池单体电压";
CM_ SG_ 2400841286 CSC_Ucell_81_06 "81 电池单体电压";
CM_ SG_ 2400841286 CSC_Ucell_82_06 "82 电池单体电压";
CM_ SG_ 2400841286 CSC_Ucell_83_06 "83 电池单体电压";
CM_ SG_ 2400841286 CSC_Ucell_84_06 "84 电池单体电压";
CM_ SG_ 2400841286 CSC_Ucell_85_06 "85 电池单体电压";
CM_ SG_ 2400841286 CSC_Ucell_86_06 "86 电池单体电压";
CM_ SG_ 2400841286 CSC_Ucell_87_06 "87 电池单体电压";
CM_ SG_ 2400841286 CSC_Ucell_88_06 "88 电池单体电压";
CM_ SG_ 2400841286 CSC_Ucell_89_06 "89 电池单体电压";
CM_ SG_ 2400841286 CSC_Ucell_90_06 "90 电池单体电压";
CM_ SG_ 2400841286 CSC_Ucell_91_06 "91 电池单体电压";
CM_ SG_ 2400841286 CSC_Ucell_92_06 "92 电池单体电压";
CM_ SG_ 2400841286 CSC_Ucell_93_06 "93 电池单体电压";
CM_ SG_ 2400841286 CSC_Ucell_94_06 "94 电池单体电压";
CM_ SG_ 2400841286 CSC_Ucell_95_06 "95 电池单体电压";
CM_ SG_ 2400841286 CSC_Ucell_96_06 "96 电池单体电压";
CM_ SG_ 2400841286 CSC_Ucell_97_06 "97 电池单体电压";
CM_ SG_ 2400841286 CSC_Ucell_98_06 "98 电池单体电压";
CM_ SG_ 2400841286 CSC_Ucell_99_06 "99 电池单体电压";
CM_ SG_ 2400841286 CSC_Ucell_100_06 "100 电池单体电压";
CM_ SG_ 2400841286 CSC_Ucell_101_06 "101 电池单体电压";
CM_ SG_ 2400841286 CSC_Ucell_102_06 "102 电池单体电压";
CM_ SG_ 2400841286 CSC_Ucell_103_06 "103 电池单体电压";
CM_ SG_ 2400841286 CSC_Ucell_104_06 "104 电池单体电压";
CM_ SG_ 2400841286 CSC_Ucell_105_06 "105 电池单体电压";
CM_ SG_ 2400841286 CSC_Ucell_106_06 "106 电池单体电压";
CM_ SG_ 2400841286 CSC_Ucell_107_06 "107 电池单体电压";
CM_ SG_ 2400841286 CSC_Ucell_108_06 "108 电池单体电压";
CM_ SG_ 2400841287 CSC_U_No_07 "CSC号";
CM_ SG_ 2400841287 CSC_Ucell_Frame_Index_07 "当前CSC中单体电压数据帧序号";
CM_ SG_ 2400841287 CSC_Ucell_58_07 "58 电池单体电压";
CM_ SG_ 2400841287 CSC_Ucell_59_07 "59 电池单体电压";
CM_ SG_ 2400841287 CSC_Ucell_60_07 "60 电池单体电压";
CM_ SG_ 2400841287 CSC_Ucell_61_07 "61 电池单体电压";
CM_ SG_ 2400841287 CSC_Ucell_62_07 "62 电池单体电压";
CM_ SG_ 2400841287 CSC_Ucell_63_07 "63 电池单体电压";
CM_ SG_ 2400841287 CSC_Ucell_64_07 "64 电池单体电压";
CM_ SG_ 2400841287 CSC_Ucell_65_07 "65 电池单体电压";
CM_ SG_ 2400841287 CSC_Ucell_66_07 "66 电池单体电压";
CM_ SG_ 2400841287 CSC_Ucell_67_07 "67 电池单体电压";
CM_ SG_ 2400841287 CSC_Ucell_68_07 "68 电池单体电压";
CM_ SG_ 2400841287 CSC_Ucell_69_07 "69 电池单体电压";
CM_ SG_ 2400841287 CSC_Ucell_70_07 "70 电池单体电压";
CM_ SG_ 2400841287 CSC_Ucell_71_07 "71 电池单体电压";
CM_ SG_ 2400841287 CSC_Ucell_72_07 "72 电池单体电压";
CM_ SG_ 2400841287 CSC_Ucell_73_07 "73 电池单体电压";
CM_ SG_ 2400841287 CSC_Ucell_74_07 "74 电池单体电压";
CM_ SG_ 2400841287 CSC_Ucell_75_07 "75 电池单体电压";
CM_ SG_ 2400841287 CSC_Ucell_76_07 "76 电池单体电压";
CM_ SG_ 2400841287 CSC_Ucell_77_07 "77 电池单体电压";
CM_ SG_ 2400841287 CSC_Ucell_78_07 "78 电池单体电压";
CM_ SG_ 2400841287 CSC_Ucell_79_07 "79 电池单体电压";
CM_ SG_ 2400841287 CSC_Ucell_80_07 "80 电池单体电压";
CM_ SG_ 2400841287 CSC_Ucell_81_07 "81 电池单体电压";
CM_ SG_ 2400841287 CSC_Ucell_82_07 "82 电池单体电压";
CM_ SG_ 2400841287 CSC_Ucell_83_07 "83 电池单体电压";
CM_ SG_ 2400841287 CSC_Ucell_84_07 "84 电池单体电压";
CM_ SG_ 2400841287 CSC_Ucell_85_07 "85 电池单体电压";
CM_ SG_ 2400841287 CSC_Ucell_86_07 "86 电池单体电压";
CM_ SG_ 2400841287 CSC_Ucell_87_07 "87 电池单体电压";
CM_ SG_ 2400841287 CSC_Ucell_88_07 "88 电池单体电压";
CM_ SG_ 2400841287 CSC_Ucell_89_07 "89 电池单体电压";
CM_ SG_ 2400841287 CSC_Ucell_90_07 "90 电池单体电压";
CM_ SG_ 2400841287 CSC_Ucell_91_07 "91 电池单体电压";
CM_ SG_ 2400841287 CSC_Ucell_92_07 "92 电池单体电压";
CM_ SG_ 2400841287 CSC_Ucell_93_07 "93 电池单体电压";
CM_ SG_ 2400841287 CSC_Ucell_94_07 "94 电池单体电压";
CM_ SG_ 2400841287 CSC_Ucell_95_07 "95 电池单体电压";
CM_ SG_ 2400841287 CSC_Ucell_96_07 "96 电池单体电压";
CM_ SG_ 2400841287 CSC_Ucell_97_07 "97 电池单体电压";
CM_ SG_ 2400841287 CSC_Ucell_98_07 "98 电池单体电压";
CM_ SG_ 2400841287 CSC_Ucell_99_07 "99 电池单体电压";
CM_ SG_ 2400841287 CSC_Ucell_100_07 "100 电池单体电压";
CM_ SG_ 2400841287 CSC_Ucell_101_07 "101 电池单体电压";
CM_ SG_ 2400841287 CSC_Ucell_102_07 "102 电池单体电压";
CM_ SG_ 2400841287 CSC_Ucell_103_07 "103 电池单体电压";
CM_ SG_ 2400841287 CSC_Ucell_104_07 "104 电池单体电压";
CM_ SG_ 2400841287 CSC_Ucell_105_07 "105 电池单体电压";
CM_ SG_ 2400841287 CSC_Ucell_106_07 "106 电池单体电压";
CM_ SG_ 2400841287 CSC_Ucell_107_07 "107 电池单体电压";
CM_ SG_ 2400841287 CSC_Ucell_108_07 "108 电池单体电压";
CM_ SG_ 2400841288 CSC_U_No_08 "CSC号";
CM_ SG_ 2400841288 CSC_Ucell_Frame_Index_08 "当前CSC中单体电压数据帧序号";
CM_ SG_ 2400841288 CSC_Ucell_58_08 "58 电池单体电压";
CM_ SG_ 2400841288 CSC_Ucell_59_08 "59 电池单体电压";
CM_ SG_ 2400841288 CSC_Ucell_60_08 "60 电池单体电压";
CM_ SG_ 2400841288 CSC_Ucell_61_08 "61 电池单体电压";
CM_ SG_ 2400841288 CSC_Ucell_62_08 "62 电池单体电压";
CM_ SG_ 2400841288 CSC_Ucell_63_08 "63 电池单体电压";
CM_ SG_ 2400841288 CSC_Ucell_64_08 "64 电池单体电压";
CM_ SG_ 2400841288 CSC_Ucell_65_08 "65 电池单体电压";
CM_ SG_ 2400841288 CSC_Ucell_66_08 "66 电池单体电压";
CM_ SG_ 2400841288 CSC_Ucell_67_08 "67 电池单体电压";
CM_ SG_ 2400841288 CSC_Ucell_68_08 "68 电池单体电压";
CM_ SG_ 2400841288 CSC_Ucell_69_08 "69 电池单体电压";
CM_ SG_ 2400841288 CSC_Ucell_70_08 "70 电池单体电压";
CM_ SG_ 2400841288 CSC_Ucell_71_08 "71 电池单体电压";
CM_ SG_ 2400841288 CSC_Ucell_72_08 "72 电池单体电压";
CM_ SG_ 2400841288 CSC_Ucell_73_08 "73 电池单体电压";
CM_ SG_ 2400841288 CSC_Ucell_74_08 "74 电池单体电压";
CM_ SG_ 2400841288 CSC_Ucell_75_08 "75 电池单体电压";
CM_ SG_ 2400841288 CSC_Ucell_76_08 "76 电池单体电压";
CM_ SG_ 2400841288 CSC_Ucell_77_08 "77 电池单体电压";
CM_ SG_ 2400841288 CSC_Ucell_78_08 "78 电池单体电压";
CM_ SG_ 2400841288 CSC_Ucell_79_08 "79 电池单体电压";
CM_ SG_ 2400841288 CSC_Ucell_80_08 "80 电池单体电压";
CM_ SG_ 2400841288 CSC_Ucell_81_08 "81 电池单体电压";
CM_ SG_ 2400841288 CSC_Ucell_82_08 "82 电池单体电压";
CM_ SG_ 2400841288 CSC_Ucell_83_08 "83 电池单体电压";
CM_ SG_ 2400841288 CSC_Ucell_84_08 "84 电池单体电压";
CM_ SG_ 2400841288 CSC_Ucell_85_08 "85 电池单体电压";
CM_ SG_ 2400841288 CSC_Ucell_86_08 "86 电池单体电压";
CM_ SG_ 2400841288 CSC_Ucell_87_08 "87 电池单体电压";
CM_ SG_ 2400841288 CSC_Ucell_88_08 "88 电池单体电压";
CM_ SG_ 2400841288 CSC_Ucell_89_08 "89 电池单体电压";
CM_ SG_ 2400841288 CSC_Ucell_90_08 "90 电池单体电压";
CM_ SG_ 2400841288 CSC_Ucell_91_08 "91 电池单体电压";
CM_ SG_ 2400841288 CSC_Ucell_92_08 "92 电池单体电压";
CM_ SG_ 2400841288 CSC_Ucell_93_08 "93 电池单体电压";
CM_ SG_ 2400841288 CSC_Ucell_94_08 "94 电池单体电压";
CM_ SG_ 2400841288 CSC_Ucell_95_08 "95 电池单体电压";
CM_ SG_ 2400841288 CSC_Ucell_96_08 "96 电池单体电压";
CM_ SG_ 2400841288 CSC_Ucell_97_08 "97 电池单体电压";
CM_ SG_ 2400841288 CSC_Ucell_98_08 "98 电池单体电压";
CM_ SG_ 2400841288 CSC_Ucell_99_08 "99 电池单体电压";
CM_ SG_ 2400841288 CSC_Ucell_100_08 "100 电池单体电压";
CM_ SG_ 2400841288 CSC_Ucell_101_08 "101 电池单体电压";
CM_ SG_ 2400841288 CSC_Ucell_102_08 "102 电池单体电压";
CM_ SG_ 2400841288 CSC_Ucell_103_08 "103 电池单体电压";
CM_ SG_ 2400841288 CSC_Ucell_104_08 "104 电池单体电压";
CM_ SG_ 2400841288 CSC_Ucell_105_08 "105 电池单体电压";
CM_ SG_ 2400841288 CSC_Ucell_106_08 "106 电池单体电压";
CM_ SG_ 2400841288 CSC_Ucell_107_08 "107 电池单体电压";
CM_ SG_ 2400841288 CSC_Ucell_108_08 "108 电池单体电压";
CM_ SG_ 2400841289 CSC_U_No_09 "CSC号";
CM_ SG_ 2400841289 CSC_Ucell_Frame_Index_09 "当前CSC中单体电压数据帧序号";
CM_ SG_ 2400841289 CSC_Ucell_58_09 "58 电池单体电压";
CM_ SG_ 2400841289 CSC_Ucell_59_09 "59 电池单体电压";
CM_ SG_ 2400841289 CSC_Ucell_60_09 "60 电池单体电压";
CM_ SG_ 2400841289 CSC_Ucell_61_09 "61 电池单体电压";
CM_ SG_ 2400841289 CSC_Ucell_62_09 "62 电池单体电压";
CM_ SG_ 2400841289 CSC_Ucell_63_09 "63 电池单体电压";
CM_ SG_ 2400841289 CSC_Ucell_64_09 "64 电池单体电压";
CM_ SG_ 2400841289 CSC_Ucell_65_09 "65 电池单体电压";
CM_ SG_ 2400841289 CSC_Ucell_66_09 "66 电池单体电压";
CM_ SG_ 2400841289 CSC_Ucell_67_09 "67 电池单体电压";
CM_ SG_ 2400841289 CSC_Ucell_68_09 "68 电池单体电压";
CM_ SG_ 2400841289 CSC_Ucell_69_09 "69 电池单体电压";
CM_ SG_ 2400841289 CSC_Ucell_70_09 "70 电池单体电压";
CM_ SG_ 2400841289 CSC_Ucell_71_09 "71 电池单体电压";
CM_ SG_ 2400841289 CSC_Ucell_72_09 "72 电池单体电压";
CM_ SG_ 2400841289 CSC_Ucell_73_09 "73 电池单体电压";
CM_ SG_ 2400841289 CSC_Ucell_74_09 "74 电池单体电压";
CM_ SG_ 2400841289 CSC_Ucell_75_09 "75 电池单体电压";
CM_ SG_ 2400841289 CSC_Ucell_76_09 "76 电池单体电压";
CM_ SG_ 2400841289 CSC_Ucell_77_09 "77 电池单体电压";
CM_ SG_ 2400841289 CSC_Ucell_78_09 "78 电池单体电压";
CM_ SG_ 2400841289 CSC_Ucell_79_09 "79 电池单体电压";
CM_ SG_ 2400841289 CSC_Ucell_80_09 "80 电池单体电压";
CM_ SG_ 2400841289 CSC_Ucell_81_09 "81 电池单体电压";
CM_ SG_ 2400841289 CSC_Ucell_82_09 "82 电池单体电压";
CM_ SG_ 2400841289 CSC_Ucell_83_09 "83 电池单体电压";
CM_ SG_ 2400841289 CSC_Ucell_84_09 "84 电池单体电压";
CM_ SG_ 2400841289 CSC_Ucell_85_09 "85 电池单体电压";
CM_ SG_ 2400841289 CSC_Ucell_86_09 "86 电池单体电压";
CM_ SG_ 2400841289 CSC_Ucell_87_09 "87 电池单体电压";
CM_ SG_ 2400841289 CSC_Ucell_88_09 "88 电池单体电压";
CM_ SG_ 2400841289 CSC_Ucell_89_09 "89 电池单体电压";
CM_ SG_ 2400841289 CSC_Ucell_90_09 "90 电池单体电压";
CM_ SG_ 2400841289 CSC_Ucell_91_09 "91 电池单体电压";
CM_ SG_ 2400841289 CSC_Ucell_92_09 "92 电池单体电压";
CM_ SG_ 2400841289 CSC_Ucell_93_09 "93 电池单体电压";
CM_ SG_ 2400841289 CSC_Ucell_94_09 "94 电池单体电压";
CM_ SG_ 2400841289 CSC_Ucell_95_09 "95 电池单体电压";
CM_ SG_ 2400841289 CSC_Ucell_96_09 "96 电池单体电压";
CM_ SG_ 2400841289 CSC_Ucell_97_09 "97 电池单体电压";
CM_ SG_ 2400841289 CSC_Ucell_98_09 "98 电池单体电压";
CM_ SG_ 2400841289 CSC_Ucell_99_09 "99 电池单体电压";
CM_ SG_ 2400841289 CSC_Ucell_100_09 "100 电池单体电压";
CM_ SG_ 2400841289 CSC_Ucell_101_09 "101 电池单体电压";
CM_ SG_ 2400841289 CSC_Ucell_102_09 "102 电池单体电压";
CM_ SG_ 2400841289 CSC_Ucell_103_09 "103 电池单体电压";
CM_ SG_ 2400841289 CSC_Ucell_104_09 "104 电池单体电压";
CM_ SG_ 2400841289 CSC_Ucell_105_09 "105 电池单体电压";
CM_ SG_ 2400841289 CSC_Ucell_106_09 "106 电池单体电压";
CM_ SG_ 2400841289 CSC_Ucell_107_09 "107 电池单体电压";
CM_ SG_ 2400841289 CSC_Ucell_108_09 "108 电池单体电压";
CM_ SG_ 2400841290 CSC_U_No_10 "CSC号";
CM_ SG_ 2400841290 CSC_Ucell_Frame_Index_10 "当前CSC中单体电压数据帧序号";
CM_ SG_ 2400841290 CSC_Ucell_58_10 "58 电池单体电压";
CM_ SG_ 2400841290 CSC_Ucell_59_10 "59 电池单体电压";
CM_ SG_ 2400841290 CSC_Ucell_60_10 "60 电池单体电压";
CM_ SG_ 2400841290 CSC_Ucell_61_10 "61 电池单体电压";
CM_ SG_ 2400841290 CSC_Ucell_62_10 "62 电池单体电压";
CM_ SG_ 2400841290 CSC_Ucell_63_10 "63 电池单体电压";
CM_ SG_ 2400841290 CSC_Ucell_64_10 "64 电池单体电压";
CM_ SG_ 2400841290 CSC_Ucell_65_10 "65 电池单体电压";
CM_ SG_ 2400841290 CSC_Ucell_66_10 "66 电池单体电压";
CM_ SG_ 2400841290 CSC_Ucell_67_10 "67 电池单体电压";
CM_ SG_ 2400841290 CSC_Ucell_68_10 "68 电池单体电压";
CM_ SG_ 2400841290 CSC_Ucell_69_10 "69 电池单体电压";
CM_ SG_ 2400841290 CSC_Ucell_70_10 "70 电池单体电压";
CM_ SG_ 2400841290 CSC_Ucell_71_10 "71 电池单体电压";
CM_ SG_ 2400841290 CSC_Ucell_72_10 "72 电池单体电压";
CM_ SG_ 2400841290 CSC_Ucell_73_10 "73 电池单体电压";
CM_ SG_ 2400841290 CSC_Ucell_74_10 "74 电池单体电压";
CM_ SG_ 2400841290 CSC_Ucell_75_10 "75 电池单体电压";
CM_ SG_ 2400841290 CSC_Ucell_76_10 "76 电池单体电压";
CM_ SG_ 2400841290 CSC_Ucell_77_10 "77 电池单体电压";
CM_ SG_ 2400841290 CSC_Ucell_78_10 "78 电池单体电压";
CM_ SG_ 2400841290 CSC_Ucell_79_10 "79 电池单体电压";
CM_ SG_ 2400841290 CSC_Ucell_80_10 "80 电池单体电压";
CM_ SG_ 2400841290 CSC_Ucell_81_10 "81 电池单体电压";
CM_ SG_ 2400841290 CSC_Ucell_82_10 "82 电池单体电压";
CM_ SG_ 2400841290 CSC_Ucell_83_10 "83 电池单体电压";
CM_ SG_ 2400841290 CSC_Ucell_84_10 "84 电池单体电压";
CM_ SG_ 2400841290 CSC_Ucell_85_10 "85 电池单体电压";
CM_ SG_ 2400841290 CSC_Ucell_86_10 "86 电池单体电压";
CM_ SG_ 2400841290 CSC_Ucell_87_10 "87 电池单体电压";
CM_ SG_ 2400841290 CSC_Ucell_88_10 "88 电池单体电压";
CM_ SG_ 2400841290 CSC_Ucell_89_10 "89 电池单体电压";
CM_ SG_ 2400841290 CSC_Ucell_90_10 "90 电池单体电压";
CM_ SG_ 2400841290 CSC_Ucell_91_10 "91 电池单体电压";
CM_ SG_ 2400841290 CSC_Ucell_92_10 "92 电池单体电压";
CM_ SG_ 2400841290 CSC_Ucell_93_10 "93 电池单体电压";
CM_ SG_ 2400841290 CSC_Ucell_94_10 "94 电池单体电压";
CM_ SG_ 2400841290 CSC_Ucell_95_10 "95 电池单体电压";
CM_ SG_ 2400841290 CSC_Ucell_96_10 "96 电池单体电压";
CM_ SG_ 2400841290 CSC_Ucell_97_10 "97 电池单体电压";
CM_ SG_ 2400841290 CSC_Ucell_98_10 "98 电池单体电压";
CM_ SG_ 2400841290 CSC_Ucell_99_10 "99 电池单体电压";
CM_ SG_ 2400841290 CSC_Ucell_100_10 "100 电池单体电压";
CM_ SG_ 2400841290 CSC_Ucell_101_10 "101 电池单体电压";
CM_ SG_ 2400841290 CSC_Ucell_102_10 "102 电池单体电压";
CM_ SG_ 2400841290 CSC_Ucell_103_10 "103 电池单体电压";
CM_ SG_ 2400841290 CSC_Ucell_104_10 "104 电池单体电压";
CM_ SG_ 2400841290 CSC_Ucell_105_10 "105 电池单体电压";
CM_ SG_ 2400841290 CSC_Ucell_106_10 "106 电池单体电压";
CM_ SG_ 2400841290 CSC_Ucell_107_10 "107 电池单体电压";
CM_ SG_ 2400841290 CSC_Ucell_108_10 "108 电池单体电压";
CM_ SG_ 2400841291 CSC_U_No_11 "CSC号";
CM_ SG_ 2400841291 CSC_Ucell_Frame_Index_11 "当前CSC中单体电压数据帧序号";
CM_ SG_ 2400841291 CSC_Ucell_58_11 "58 电池单体电压";
CM_ SG_ 2400841291 CSC_Ucell_59_11 "59 电池单体电压";
CM_ SG_ 2400841291 CSC_Ucell_60_11 "60 电池单体电压";
CM_ SG_ 2400841291 CSC_Ucell_61_11 "61 电池单体电压";
CM_ SG_ 2400841291 CSC_Ucell_62_11 "62 电池单体电压";
CM_ SG_ 2400841291 CSC_Ucell_63_11 "63 电池单体电压";
CM_ SG_ 2400841291 CSC_Ucell_64_11 "64 电池单体电压";
CM_ SG_ 2400841291 CSC_Ucell_65_11 "65 电池单体电压";
CM_ SG_ 2400841291 CSC_Ucell_66_11 "66 电池单体电压";
CM_ SG_ 2400841291 CSC_Ucell_67_11 "67 电池单体电压";
CM_ SG_ 2400841291 CSC_Ucell_68_11 "68 电池单体电压";
CM_ SG_ 2400841291 CSC_Ucell_69_11 "69 电池单体电压";
CM_ SG_ 2400841291 CSC_Ucell_70_11 "70 电池单体电压";
CM_ SG_ 2400841291 CSC_Ucell_71_11 "71 电池单体电压";
CM_ SG_ 2400841291 CSC_Ucell_72_11 "72 电池单体电压";
CM_ SG_ 2400841291 CSC_Ucell_73_11 "73 电池单体电压";
CM_ SG_ 2400841291 CSC_Ucell_74_11 "74 电池单体电压";
CM_ SG_ 2400841291 CSC_Ucell_75_11 "75 电池单体电压";
CM_ SG_ 2400841291 CSC_Ucell_76_11 "76 电池单体电压";
CM_ SG_ 2400841291 CSC_Ucell_77_11 "77 电池单体电压";
CM_ SG_ 2400841291 CSC_Ucell_78_11 "78 电池单体电压";
CM_ SG_ 2400841291 CSC_Ucell_79_11 "79 电池单体电压";
CM_ SG_ 2400841291 CSC_Ucell_80_11 "80 电池单体电压";
CM_ SG_ 2400841291 CSC_Ucell_81_11 "81 电池单体电压";
CM_ SG_ 2400841291 CSC_Ucell_82_11 "82 电池单体电压";
CM_ SG_ 2400841291 CSC_Ucell_83_11 "83 电池单体电压";
CM_ SG_ 2400841291 CSC_Ucell_84_11 "84 电池单体电压";
CM_ SG_ 2400841291 CSC_Ucell_85_11 "85 电池单体电压";
CM_ SG_ 2400841291 CSC_Ucell_86_11 "86 电池单体电压";
CM_ SG_ 2400841291 CSC_Ucell_87_11 "87 电池单体电压";
CM_ SG_ 2400841291 CSC_Ucell_88_11 "88 电池单体电压";
CM_ SG_ 2400841291 CSC_Ucell_89_11 "89 电池单体电压";
CM_ SG_ 2400841291 CSC_Ucell_90_11 "90 电池单体电压";
CM_ SG_ 2400841291 CSC_Ucell_91_11 "91 电池单体电压";
CM_ SG_ 2400841291 CSC_Ucell_92_11 "92 电池单体电压";
CM_ SG_ 2400841291 CSC_Ucell_93_11 "93 电池单体电压";
CM_ SG_ 2400841291 CSC_Ucell_94_11 "94 电池单体电压";
CM_ SG_ 2400841291 CSC_Ucell_95_11 "95 电池单体电压";
CM_ SG_ 2400841291 CSC_Ucell_96_11 "96 电池单体电压";
CM_ SG_ 2400841291 CSC_Ucell_97_11 "97 电池单体电压";
CM_ SG_ 2400841291 CSC_Ucell_98_11 "98 电池单体电压";
CM_ SG_ 2400841291 CSC_Ucell_99_11 "99 电池单体电压";
CM_ SG_ 2400841291 CSC_Ucell_100_11 "100 电池单体电压";
CM_ SG_ 2400841291 CSC_Ucell_101_11 "101 电池单体电压";
CM_ SG_ 2400841291 CSC_Ucell_102_11 "102 电池单体电压";
CM_ SG_ 2400841291 CSC_Ucell_103_11 "103 电池单体电压";
CM_ SG_ 2400841291 CSC_Ucell_104_11 "104 电池单体电压";
CM_ SG_ 2400841291 CSC_Ucell_105_11 "105 电池单体电压";
CM_ SG_ 2400841291 CSC_Ucell_106_11 "106 电池单体电压";
CM_ SG_ 2400841291 CSC_Ucell_107_11 "107 电池单体电压";
CM_ SG_ 2400841291 CSC_Ucell_108_11 "108 电池单体电压";
CM_ SG_ 2400841292 CSC_U_No_12 "CSC号";
CM_ SG_ 2400841292 CSC_Ucell_Frame_Index_12 "当前CSC中单体电压数据帧序号";
CM_ SG_ 2400841292 CSC_Ucell_58_12 "58 电池单体电压";
CM_ SG_ 2400841292 CSC_Ucell_59_12 "59 电池单体电压";
CM_ SG_ 2400841292 CSC_Ucell_60_12 "60 电池单体电压";
CM_ SG_ 2400841292 CSC_Ucell_61_12 "61 电池单体电压";
CM_ SG_ 2400841292 CSC_Ucell_62_12 "62 电池单体电压";
CM_ SG_ 2400841292 CSC_Ucell_63_12 "63 电池单体电压";
CM_ SG_ 2400841292 CSC_Ucell_64_12 "64 电池单体电压";
CM_ SG_ 2400841292 CSC_Ucell_65_12 "65 电池单体电压";
CM_ SG_ 2400841292 CSC_Ucell_66_12 "66 电池单体电压";
CM_ SG_ 2400841292 CSC_Ucell_67_12 "67 电池单体电压";
CM_ SG_ 2400841292 CSC_Ucell_68_12 "68 电池单体电压";
CM_ SG_ 2400841292 CSC_Ucell_69_12 "69 电池单体电压";
CM_ SG_ 2400841292 CSC_Ucell_70_12 "70 电池单体电压";
CM_ SG_ 2400841292 CSC_Ucell_71_12 "71 电池单体电压";
CM_ SG_ 2400841292 CSC_Ucell_72_12 "72 电池单体电压";
CM_ SG_ 2400841292 CSC_Ucell_73_12 "73 电池单体电压";
CM_ SG_ 2400841292 CSC_Ucell_74_12 "74 电池单体电压";
CM_ SG_ 2400841292 CSC_Ucell_75_12 "75 电池单体电压";
CM_ SG_ 2400841292 CSC_Ucell_76_12 "76 电池单体电压";
CM_ SG_ 2400841292 CSC_Ucell_77_12 "77 电池单体电压";
CM_ SG_ 2400841292 CSC_Ucell_78_12 "78 电池单体电压";
CM_ SG_ 2400841292 CSC_Ucell_79_12 "79 电池单体电压";
CM_ SG_ 2400841292 CSC_Ucell_80_12 "80 电池单体电压";
CM_ SG_ 2400841292 CSC_Ucell_81_12 "81 电池单体电压";
CM_ SG_ 2400841292 CSC_Ucell_82_12 "82 电池单体电压";
CM_ SG_ 2400841292 CSC_Ucell_83_12 "83 电池单体电压";
CM_ SG_ 2400841292 CSC_Ucell_84_12 "84 电池单体电压";
CM_ SG_ 2400841292 CSC_Ucell_85_12 "85 电池单体电压";
CM_ SG_ 2400841292 CSC_Ucell_86_12 "86 电池单体电压";
CM_ SG_ 2400841292 CSC_Ucell_87_12 "87 电池单体电压";
CM_ SG_ 2400841292 CSC_Ucell_88_12 "88 电池单体电压";
CM_ SG_ 2400841292 CSC_Ucell_89_12 "89 电池单体电压";
CM_ SG_ 2400841292 CSC_Ucell_90_12 "90 电池单体电压";
CM_ SG_ 2400841292 CSC_Ucell_91_12 "91 电池单体电压";
CM_ SG_ 2400841292 CSC_Ucell_92_12 "92 电池单体电压";
CM_ SG_ 2400841292 CSC_Ucell_93_12 "93 电池单体电压";
CM_ SG_ 2400841292 CSC_Ucell_94_12 "94 电池单体电压";
CM_ SG_ 2400841292 CSC_Ucell_95_12 "95 电池单体电压";
CM_ SG_ 2400841292 CSC_Ucell_96_12 "96 电池单体电压";
CM_ SG_ 2400841292 CSC_Ucell_97_12 "97 电池单体电压";
CM_ SG_ 2400841292 CSC_Ucell_98_12 "98 电池单体电压";
CM_ SG_ 2400841292 CSC_Ucell_99_12 "99 电池单体电压";
CM_ SG_ 2400841292 CSC_Ucell_100_12 "100 电池单体电压";
CM_ SG_ 2400841292 CSC_Ucell_101_12 "101 电池单体电压";
CM_ SG_ 2400841292 CSC_Ucell_102_12 "102 电池单体电压";
CM_ SG_ 2400841292 CSC_Ucell_103_12 "103 电池单体电压";
CM_ SG_ 2400841292 CSC_Ucell_104_12 "104 电池单体电压";
CM_ SG_ 2400841292 CSC_Ucell_105_12 "105 电池单体电压";
CM_ SG_ 2400841292 CSC_Ucell_106_12 "106 电池单体电压";
CM_ SG_ 2400841292 CSC_Ucell_107_12 "107 电池单体电压";
CM_ SG_ 2400841292 CSC_Ucell_108_12 "108 电池单体电压";
CM_ SG_ 2400841293 CSC_U_No_13 "CSC号";
CM_ SG_ 2400841293 CSC_Ucell_Frame_Index_13 "当前CSC中单体电压数据帧序号";
CM_ SG_ 2400841293 CSC_Ucell_58_13 "58 电池单体电压";
CM_ SG_ 2400841293 CSC_Ucell_59_13 "59 电池单体电压";
CM_ SG_ 2400841293 CSC_Ucell_60_13 "60 电池单体电压";
CM_ SG_ 2400841293 CSC_Ucell_61_13 "61 电池单体电压";
CM_ SG_ 2400841293 CSC_Ucell_62_13 "62 电池单体电压";
CM_ SG_ 2400841293 CSC_Ucell_63_13 "63 电池单体电压";
CM_ SG_ 2400841293 CSC_Ucell_64_13 "64 电池单体电压";
CM_ SG_ 2400841293 CSC_Ucell_65_13 "65 电池单体电压";
CM_ SG_ 2400841293 CSC_Ucell_66_13 "66 电池单体电压";
CM_ SG_ 2400841293 CSC_Ucell_67_13 "67 电池单体电压";
CM_ SG_ 2400841293 CSC_Ucell_68_13 "68 电池单体电压";
CM_ SG_ 2400841293 CSC_Ucell_69_13 "69 电池单体电压";
CM_ SG_ 2400841293 CSC_Ucell_70_13 "70 电池单体电压";
CM_ SG_ 2400841293 CSC_Ucell_71_13 "71 电池单体电压";
CM_ SG_ 2400841293 CSC_Ucell_72_13 "72 电池单体电压";
CM_ SG_ 2400841293 CSC_Ucell_73_13 "73 电池单体电压";
CM_ SG_ 2400841293 CSC_Ucell_74_13 "74 电池单体电压";
CM_ SG_ 2400841293 CSC_Ucell_75_13 "75 电池单体电压";
CM_ SG_ 2400841293 CSC_Ucell_76_13 "76 电池单体电压";
CM_ SG_ 2400841293 CSC_Ucell_77_13 "77 电池单体电压";
CM_ SG_ 2400841293 CSC_Ucell_78_13 "78 电池单体电压";
CM_ SG_ 2400841293 CSC_Ucell_79_13 "79 电池单体电压";
CM_ SG_ 2400841293 CSC_Ucell_80_13 "80 电池单体电压";
CM_ SG_ 2400841293 CSC_Ucell_81_13 "81 电池单体电压";
CM_ SG_ 2400841293 CSC_Ucell_82_13 "82 电池单体电压";
CM_ SG_ 2400841293 CSC_Ucell_83_13 "83 电池单体电压";
CM_ SG_ 2400841293 CSC_Ucell_84_13 "84 电池单体电压";
CM_ SG_ 2400841293 CSC_Ucell_85_13 "85 电池单体电压";
CM_ SG_ 2400841293 CSC_Ucell_86_13 "86 电池单体电压";
CM_ SG_ 2400841293 CSC_Ucell_87_13 "87 电池单体电压";
CM_ SG_ 2400841293 CSC_Ucell_88_13 "88 电池单体电压";
CM_ SG_ 2400841293 CSC_Ucell_89_13 "89 电池单体电压";
CM_ SG_ 2400841293 CSC_Ucell_90_13 "90 电池单体电压";
CM_ SG_ 2400841293 CSC_Ucell_91_13 "91 电池单体电压";
CM_ SG_ 2400841293 CSC_Ucell_92_13 "92 电池单体电压";
CM_ SG_ 2400841293 CSC_Ucell_93_13 "93 电池单体电压";
CM_ SG_ 2400841293 CSC_Ucell_94_13 "94 电池单体电压";
CM_ SG_ 2400841293 CSC_Ucell_95_13 "95 电池单体电压";
CM_ SG_ 2400841293 CSC_Ucell_96_13 "96 电池单体电压";
CM_ SG_ 2400841293 CSC_Ucell_97_13 "97 电池单体电压";
CM_ SG_ 2400841293 CSC_Ucell_98_13 "98 电池单体电压";
CM_ SG_ 2400841293 CSC_Ucell_99_13 "99 电池单体电压";
CM_ SG_ 2400841293 CSC_Ucell_100_13 "100 电池单体电压";
CM_ SG_ 2400841293 CSC_Ucell_101_13 "101 电池单体电压";
CM_ SG_ 2400841293 CSC_Ucell_102_13 "102 电池单体电压";
CM_ SG_ 2400841293 CSC_Ucell_103_13 "103 电池单体电压";
CM_ SG_ 2400841293 CSC_Ucell_104_13 "104 电池单体电压";
CM_ SG_ 2400841293 CSC_Ucell_105_13 "105 电池单体电压";
CM_ SG_ 2400841293 CSC_Ucell_106_13 "106 电池单体电压";
CM_ SG_ 2400841293 CSC_Ucell_107_13 "107 电池单体电压";
CM_ SG_ 2400841293 CSC_Ucell_108_13 "108 电池单体电压";
CM_ SG_ 2400841294 CSC_U_No_14 "CSC号";
CM_ SG_ 2400841294 CSC_Ucell_Frame_Index_14 "当前CSC中单体电压数据帧序号";
CM_ SG_ 2400841294 CSC_Ucell_58_14 "58 电池单体电压";
CM_ SG_ 2400841294 CSC_Ucell_59_14 "59 电池单体电压";
CM_ SG_ 2400841294 CSC_Ucell_60_14 "60 电池单体电压";
CM_ SG_ 2400841294 CSC_Ucell_61_14 "61 电池单体电压";
CM_ SG_ 2400841294 CSC_Ucell_62_14 "62 电池单体电压";
CM_ SG_ 2400841294 CSC_Ucell_63_14 "63 电池单体电压";
CM_ SG_ 2400841294 CSC_Ucell_64_14 "64 电池单体电压";
CM_ SG_ 2400841294 CSC_Ucell_65_14 "65 电池单体电压";
CM_ SG_ 2400841294 CSC_Ucell_66_14 "66 电池单体电压";
CM_ SG_ 2400841294 CSC_Ucell_67_14 "67 电池单体电压";
CM_ SG_ 2400841294 CSC_Ucell_68_14 "68 电池单体电压";
CM_ SG_ 2400841294 CSC_Ucell_69_14 "69 电池单体电压";
CM_ SG_ 2400841294 CSC_Ucell_70_14 "70 电池单体电压";
CM_ SG_ 2400841294 CSC_Ucell_71_14 "71 电池单体电压";
CM_ SG_ 2400841294 CSC_Ucell_72_14 "72 电池单体电压";
CM_ SG_ 2400841294 CSC_Ucell_73_14 "73 电池单体电压";
CM_ SG_ 2400841294 CSC_Ucell_74_14 "74 电池单体电压";
CM_ SG_ 2400841294 CSC_Ucell_75_14 "75 电池单体电压";
CM_ SG_ 2400841294 CSC_Ucell_76_14 "76 电池单体电压";
CM_ SG_ 2400841294 CSC_Ucell_77_14 "77 电池单体电压";
CM_ SG_ 2400841294 CSC_Ucell_78_14 "78 电池单体电压";
CM_ SG_ 2400841294 CSC_Ucell_79_14 "79 电池单体电压";
CM_ SG_ 2400841294 CSC_Ucell_80_14 "80 电池单体电压";
CM_ SG_ 2400841294 CSC_Ucell_81_14 "81 电池单体电压";
CM_ SG_ 2400841294 CSC_Ucell_82_14 "82 电池单体电压";
CM_ SG_ 2400841294 CSC_Ucell_83_14 "83 电池单体电压";
CM_ SG_ 2400841294 CSC_Ucell_84_14 "84 电池单体电压";
CM_ SG_ 2400841294 CSC_Ucell_85_14 "85 电池单体电压";
CM_ SG_ 2400841294 CSC_Ucell_86_14 "86 电池单体电压";
CM_ SG_ 2400841294 CSC_Ucell_87_14 "87 电池单体电压";
CM_ SG_ 2400841294 CSC_Ucell_88_14 "88 电池单体电压";
CM_ SG_ 2400841294 CSC_Ucell_89_14 "89 电池单体电压";
CM_ SG_ 2400841294 CSC_Ucell_90_14 "90 电池单体电压";
CM_ SG_ 2400841294 CSC_Ucell_91_14 "91 电池单体电压";
CM_ SG_ 2400841294 CSC_Ucell_92_14 "92 电池单体电压";
CM_ SG_ 2400841294 CSC_Ucell_93_14 "93 电池单体电压";
CM_ SG_ 2400841294 CSC_Ucell_94_14 "94 电池单体电压";
CM_ SG_ 2400841294 CSC_Ucell_95_14 "95 电池单体电压";
CM_ SG_ 2400841294 CSC_Ucell_96_14 "96 电池单体电压";
CM_ SG_ 2400841294 CSC_Ucell_97_14 "97 电池单体电压";
CM_ SG_ 2400841294 CSC_Ucell_98_14 "98 电池单体电压";
CM_ SG_ 2400841294 CSC_Ucell_99_14 "99 电池单体电压";
CM_ SG_ 2400841294 CSC_Ucell_100_14 "100 电池单体电压";
CM_ SG_ 2400841294 CSC_Ucell_101_14 "101 电池单体电压";
CM_ SG_ 2400841294 CSC_Ucell_102_14 "102 电池单体电压";
CM_ SG_ 2400841294 CSC_Ucell_103_14 "103 电池单体电压";
CM_ SG_ 2400841294 CSC_Ucell_104_14 "104 电池单体电压";
CM_ SG_ 2400841294 CSC_Ucell_105_14 "105 电池单体电压";
CM_ SG_ 2400841294 CSC_Ucell_106_14 "106 电池单体电压";
CM_ SG_ 2400841294 CSC_Ucell_107_14 "107 电池单体电压";
CM_ SG_ 2400841294 CSC_Ucell_108_14 "108 电池单体电压";
CM_ SG_ 2400841295 CSC_U_No_15 "CSC号";
CM_ SG_ 2400841295 CSC_Ucell_Frame_Index_15 "当前CSC中单体电压数据帧序号";
CM_ SG_ 2400841295 CSC_Ucell_58_15 "58 电池单体电压";
CM_ SG_ 2400841295 CSC_Ucell_59_15 "59 电池单体电压";
CM_ SG_ 2400841295 CSC_Ucell_60_15 "60 电池单体电压";
CM_ SG_ 2400841295 CSC_Ucell_61_15 "61 电池单体电压";
CM_ SG_ 2400841295 CSC_Ucell_62_15 "62 电池单体电压";
CM_ SG_ 2400841295 CSC_Ucell_63_15 "63 电池单体电压";
CM_ SG_ 2400841295 CSC_Ucell_64_15 "64 电池单体电压";
CM_ SG_ 2400841295 CSC_Ucell_65_15 "65 电池单体电压";
CM_ SG_ 2400841295 CSC_Ucell_66_15 "66 电池单体电压";
CM_ SG_ 2400841295 CSC_Ucell_67_15 "67 电池单体电压";
CM_ SG_ 2400841295 CSC_Ucell_68_15 "68 电池单体电压";
CM_ SG_ 2400841295 CSC_Ucell_69_15 "69 电池单体电压";
CM_ SG_ 2400841295 CSC_Ucell_70_15 "70 电池单体电压";
CM_ SG_ 2400841295 CSC_Ucell_71_15 "71 电池单体电压";
CM_ SG_ 2400841295 CSC_Ucell_72_15 "72 电池单体电压";
CM_ SG_ 2400841295 CSC_Ucell_73_15 "73 电池单体电压";
CM_ SG_ 2400841295 CSC_Ucell_74_15 "74 电池单体电压";
CM_ SG_ 2400841295 CSC_Ucell_75_15 "75 电池单体电压";
CM_ SG_ 2400841295 CSC_Ucell_76_15 "76 电池单体电压";
CM_ SG_ 2400841295 CSC_Ucell_77_15 "77 电池单体电压";
CM_ SG_ 2400841295 CSC_Ucell_78_15 "78 电池单体电压";
CM_ SG_ 2400841295 CSC_Ucell_79_15 "79 电池单体电压";
CM_ SG_ 2400841295 CSC_Ucell_80_15 "80 电池单体电压";
CM_ SG_ 2400841295 CSC_Ucell_81_15 "81 电池单体电压";
CM_ SG_ 2400841295 CSC_Ucell_82_15 "82 电池单体电压";
CM_ SG_ 2400841295 CSC_Ucell_83_15 "83 电池单体电压";
CM_ SG_ 2400841295 CSC_Ucell_84_15 "84 电池单体电压";
CM_ SG_ 2400841295 CSC_Ucell_85_15 "85 电池单体电压";
CM_ SG_ 2400841295 CSC_Ucell_86_15 "86 电池单体电压";
CM_ SG_ 2400841295 CSC_Ucell_87_15 "87 电池单体电压";
CM_ SG_ 2400841295 CSC_Ucell_88_15 "88 电池单体电压";
CM_ SG_ 2400841295 CSC_Ucell_89_15 "89 电池单体电压";
CM_ SG_ 2400841295 CSC_Ucell_90_15 "90 电池单体电压";
CM_ SG_ 2400841295 CSC_Ucell_91_15 "91 电池单体电压";
CM_ SG_ 2400841295 CSC_Ucell_92_15 "92 电池单体电压";
CM_ SG_ 2400841295 CSC_Ucell_93_15 "93 电池单体电压";
CM_ SG_ 2400841295 CSC_Ucell_94_15 "94 电池单体电压";
CM_ SG_ 2400841295 CSC_Ucell_95_15 "95 电池单体电压";
CM_ SG_ 2400841295 CSC_Ucell_96_15 "96 电池单体电压";
CM_ SG_ 2400841295 CSC_Ucell_97_15 "97 电池单体电压";
CM_ SG_ 2400841295 CSC_Ucell_98_15 "98 电池单体电压";
CM_ SG_ 2400841295 CSC_Ucell_99_15 "99 电池单体电压";
CM_ SG_ 2400841295 CSC_Ucell_100_15 "100 电池单体电压";
CM_ SG_ 2400841295 CSC_Ucell_101_15 "101 电池单体电压";
CM_ SG_ 2400841295 CSC_Ucell_102_15 "102 电池单体电压";
CM_ SG_ 2400841295 CSC_Ucell_103_15 "103 电池单体电压";
CM_ SG_ 2400841295 CSC_Ucell_104_15 "104 电池单体电压";
CM_ SG_ 2400841295 CSC_Ucell_105_15 "105 电池单体电压";
CM_ SG_ 2400841295 CSC_Ucell_106_15 "106 电池单体电压";
CM_ SG_ 2400841295 CSC_Ucell_107_15 "107 电池单体电压";
CM_ SG_ 2400841295 CSC_Ucell_108_15 "108 电池单体电压";
CM_ SG_ 2400841296 CSC_U_No_16 "CSC号";
CM_ SG_ 2400841296 CSC_Ucell_Frame_Index_16 "当前CSC中单体电压数据帧序号";
CM_ SG_ 2400841296 CSC_Ucell_58_16 "58 电池单体电压";
CM_ SG_ 2400841296 CSC_Ucell_59_16 "59 电池单体电压";
CM_ SG_ 2400841296 CSC_Ucell_60_16 "60 电池单体电压";
CM_ SG_ 2400841296 CSC_Ucell_61_16 "61 电池单体电压";
CM_ SG_ 2400841296 CSC_Ucell_62_16 "62 电池单体电压";
CM_ SG_ 2400841296 CSC_Ucell_63_16 "63 电池单体电压";
CM_ SG_ 2400841296 CSC_Ucell_64_16 "64 电池单体电压";
CM_ SG_ 2400841296 CSC_Ucell_65_16 "65 电池单体电压";
CM_ SG_ 2400841296 CSC_Ucell_66_16 "66 电池单体电压";
CM_ SG_ 2400841296 CSC_Ucell_67_16 "67 电池单体电压";
CM_ SG_ 2400841296 CSC_Ucell_68_16 "68 电池单体电压";
CM_ SG_ 2400841296 CSC_Ucell_69_16 "69 电池单体电压";
CM_ SG_ 2400841296 CSC_Ucell_70_16 "70 电池单体电压";
CM_ SG_ 2400841296 CSC_Ucell_71_16 "71 电池单体电压";
CM_ SG_ 2400841296 CSC_Ucell_72_16 "72 电池单体电压";
CM_ SG_ 2400841296 CSC_Ucell_73_16 "73 电池单体电压";
CM_ SG_ 2400841296 CSC_Ucell_74_16 "74 电池单体电压";
CM_ SG_ 2400841296 CSC_Ucell_75_16 "75 电池单体电压";
CM_ SG_ 2400841296 CSC_Ucell_76_16 "76 电池单体电压";
CM_ SG_ 2400841296 CSC_Ucell_77_16 "77 电池单体电压";
CM_ SG_ 2400841296 CSC_Ucell_78_16 "78 电池单体电压";
CM_ SG_ 2400841296 CSC_Ucell_79_16 "79 电池单体电压";
CM_ SG_ 2400841296 CSC_Ucell_80_16 "80 电池单体电压";
CM_ SG_ 2400841296 CSC_Ucell_81_16 "81 电池单体电压";
CM_ SG_ 2400841296 CSC_Ucell_82_16 "82 电池单体电压";
CM_ SG_ 2400841296 CSC_Ucell_83_16 "83 电池单体电压";
CM_ SG_ 2400841296 CSC_Ucell_84_16 "84 电池单体电压";
CM_ SG_ 2400841296 CSC_Ucell_85_16 "85 电池单体电压";
CM_ SG_ 2400841296 CSC_Ucell_86_16 "86 电池单体电压";
CM_ SG_ 2400841296 CSC_Ucell_87_16 "87 电池单体电压";
CM_ SG_ 2400841296 CSC_Ucell_88_16 "88 电池单体电压";
CM_ SG_ 2400841296 CSC_Ucell_89_16 "89 电池单体电压";
CM_ SG_ 2400841296 CSC_Ucell_90_16 "90 电池单体电压";
CM_ SG_ 2400841296 CSC_Ucell_91_16 "91 电池单体电压";
CM_ SG_ 2400841296 CSC_Ucell_92_16 "92 电池单体电压";
CM_ SG_ 2400841296 CSC_Ucell_93_16 "93 电池单体电压";
CM_ SG_ 2400841296 CSC_Ucell_94_16 "94 电池单体电压";
CM_ SG_ 2400841296 CSC_Ucell_95_16 "95 电池单体电压";
CM_ SG_ 2400841296 CSC_Ucell_96_16 "96 电池单体电压";
CM_ SG_ 2400841296 CSC_Ucell_97_16 "97 电池单体电压";
CM_ SG_ 2400841296 CSC_Ucell_98_16 "98 电池单体电压";
CM_ SG_ 2400841296 CSC_Ucell_99_16 "99 电池单体电压";
CM_ SG_ 2400841296 CSC_Ucell_100_16 "100 电池单体电压";
CM_ SG_ 2400841296 CSC_Ucell_101_16 "101 电池单体电压";
CM_ SG_ 2400841296 CSC_Ucell_102_16 "102 电池单体电压";
CM_ SG_ 2400841296 CSC_Ucell_103_16 "103 电池单体电压";
CM_ SG_ 2400841296 CSC_Ucell_104_16 "104 电池单体电压";
CM_ SG_ 2400841296 CSC_Ucell_105_16 "105 电池单体电压";
CM_ SG_ 2400841296 CSC_Ucell_106_16 "106 电池单体电压";
CM_ SG_ 2400841296 CSC_Ucell_107_16 "107 电池单体电压";
CM_ SG_ 2400841296 CSC_Ucell_108_16 "108 电池单体电压";
CM_ SG_ 2400841297 CSC_U_No_17 "CSC号";
CM_ SG_ 2400841297 CSC_Ucell_Frame_Index_17 "当前CSC中单体电压数据帧序号";
CM_ SG_ 2400841297 CSC_Ucell_58_17 "58 电池单体电压";
CM_ SG_ 2400841297 CSC_Ucell_59_17 "59 电池单体电压";
CM_ SG_ 2400841297 CSC_Ucell_60_17 "60 电池单体电压";
CM_ SG_ 2400841297 CSC_Ucell_61_17 "61 电池单体电压";
CM_ SG_ 2400841297 CSC_Ucell_62_17 "62 电池单体电压";
CM_ SG_ 2400841297 CSC_Ucell_63_17 "63 电池单体电压";
CM_ SG_ 2400841297 CSC_Ucell_64_17 "64 电池单体电压";
CM_ SG_ 2400841297 CSC_Ucell_65_17 "65 电池单体电压";
CM_ SG_ 2400841297 CSC_Ucell_66_17 "66 电池单体电压";
CM_ SG_ 2400841297 CSC_Ucell_67_17 "67 电池单体电压";
CM_ SG_ 2400841297 CSC_Ucell_68_17 "68 电池单体电压";
CM_ SG_ 2400841297 CSC_Ucell_69_17 "69 电池单体电压";
CM_ SG_ 2400841297 CSC_Ucell_70_17 "70 电池单体电压";
CM_ SG_ 2400841297 CSC_Ucell_71_17 "71 电池单体电压";
CM_ SG_ 2400841297 CSC_Ucell_72_17 "72 电池单体电压";
CM_ SG_ 2400841297 CSC_Ucell_73_17 "73 电池单体电压";
CM_ SG_ 2400841297 CSC_Ucell_74_17 "74 电池单体电压";
CM_ SG_ 2400841297 CSC_Ucell_75_17 "75 电池单体电压";
CM_ SG_ 2400841297 CSC_Ucell_76_17 "76 电池单体电压";
CM_ SG_ 2400841297 CSC_Ucell_77_17 "77 电池单体电压";
CM_ SG_ 2400841297 CSC_Ucell_78_17 "78 电池单体电压";
CM_ SG_ 2400841297 CSC_Ucell_79_17 "79 电池单体电压";
CM_ SG_ 2400841297 CSC_Ucell_80_17 "80 电池单体电压";
CM_ SG_ 2400841297 CSC_Ucell_81_17 "81 电池单体电压";
CM_ SG_ 2400841297 CSC_Ucell_82_17 "82 电池单体电压";
CM_ SG_ 2400841297 CSC_Ucell_83_17 "83 电池单体电压";
CM_ SG_ 2400841297 CSC_Ucell_84_17 "84 电池单体电压";
CM_ SG_ 2400841297 CSC_Ucell_85_17 "85 电池单体电压";
CM_ SG_ 2400841297 CSC_Ucell_86_17 "86 电池单体电压";
CM_ SG_ 2400841297 CSC_Ucell_87_17 "87 电池单体电压";
CM_ SG_ 2400841297 CSC_Ucell_88_17 "88 电池单体电压";
CM_ SG_ 2400841297 CSC_Ucell_89_17 "89 电池单体电压";
CM_ SG_ 2400841297 CSC_Ucell_90_17 "90 电池单体电压";
CM_ SG_ 2400841297 CSC_Ucell_91_17 "91 电池单体电压";
CM_ SG_ 2400841297 CSC_Ucell_92_17 "92 电池单体电压";
CM_ SG_ 2400841297 CSC_Ucell_93_17 "93 电池单体电压";
CM_ SG_ 2400841297 CSC_Ucell_94_17 "94 电池单体电压";
CM_ SG_ 2400841297 CSC_Ucell_95_17 "95 电池单体电压";
CM_ SG_ 2400841297 CSC_Ucell_96_17 "96 电池单体电压";
CM_ SG_ 2400841297 CSC_Ucell_97_17 "97 电池单体电压";
CM_ SG_ 2400841297 CSC_Ucell_98_17 "98 电池单体电压";
CM_ SG_ 2400841297 CSC_Ucell_99_17 "99 电池单体电压";
CM_ SG_ 2400841297 CSC_Ucell_100_17 "100 电池单体电压";
CM_ SG_ 2400841297 CSC_Ucell_101_17 "101 电池单体电压";
CM_ SG_ 2400841297 CSC_Ucell_102_17 "102 电池单体电压";
CM_ SG_ 2400841297 CSC_Ucell_103_17 "103 电池单体电压";
CM_ SG_ 2400841297 CSC_Ucell_104_17 "104 电池单体电压";
CM_ SG_ 2400841297 CSC_Ucell_105_17 "105 电池单体电压";
CM_ SG_ 2400841297 CSC_Ucell_106_17 "106 电池单体电压";
CM_ SG_ 2400841297 CSC_Ucell_107_17 "107 电池单体电压";
CM_ SG_ 2400841297 CSC_Ucell_108_17 "108 电池单体电压";
CM_ SG_ 2400841298 CSC_U_No_18 "CSC号";
CM_ SG_ 2400841298 CSC_Ucell_Frame_Index_18 "当前CSC中单体电压数据帧序号";
CM_ SG_ 2400841298 CSC_Ucell_58_18 "58 电池单体电压";
CM_ SG_ 2400841298 CSC_Ucell_59_18 "59 电池单体电压";
CM_ SG_ 2400841298 CSC_Ucell_60_18 "60 电池单体电压";
CM_ SG_ 2400841298 CSC_Ucell_61_18 "61 电池单体电压";
CM_ SG_ 2400841298 CSC_Ucell_62_18 "62 电池单体电压";
CM_ SG_ 2400841298 CSC_Ucell_63_18 "63 电池单体电压";
CM_ SG_ 2400841298 CSC_Ucell_64_18 "64 电池单体电压";
CM_ SG_ 2400841298 CSC_Ucell_65_18 "65 电池单体电压";
CM_ SG_ 2400841298 CSC_Ucell_66_18 "66 电池单体电压";
CM_ SG_ 2400841298 CSC_Ucell_67_18 "67 电池单体电压";
CM_ SG_ 2400841298 CSC_Ucell_68_18 "68 电池单体电压";
CM_ SG_ 2400841298 CSC_Ucell_69_18 "69 电池单体电压";
CM_ SG_ 2400841298 CSC_Ucell_70_18 "70 电池单体电压";
CM_ SG_ 2400841298 CSC_Ucell_71_18 "71 电池单体电压";
CM_ SG_ 2400841298 CSC_Ucell_72_18 "72 电池单体电压";
CM_ SG_ 2400841298 CSC_Ucell_73_18 "73 电池单体电压";
CM_ SG_ 2400841298 CSC_Ucell_74_18 "74 电池单体电压";
CM_ SG_ 2400841298 CSC_Ucell_75_18 "75 电池单体电压";
CM_ SG_ 2400841298 CSC_Ucell_76_18 "76 电池单体电压";
CM_ SG_ 2400841298 CSC_Ucell_77_18 "77 电池单体电压";
CM_ SG_ 2400841298 CSC_Ucell_78_18 "78 电池单体电压";
CM_ SG_ 2400841298 CSC_Ucell_79_18 "79 电池单体电压";
CM_ SG_ 2400841298 CSC_Ucell_80_18 "80 电池单体电压";
CM_ SG_ 2400841298 CSC_Ucell_81_18 "81 电池单体电压";
CM_ SG_ 2400841298 CSC_Ucell_82_18 "82 电池单体电压";
CM_ SG_ 2400841298 CSC_Ucell_83_18 "83 电池单体电压";
CM_ SG_ 2400841298 CSC_Ucell_84_18 "84 电池单体电压";
CM_ SG_ 2400841298 CSC_Ucell_85_18 "85 电池单体电压";
CM_ SG_ 2400841298 CSC_Ucell_86_18 "86 电池单体电压";
CM_ SG_ 2400841298 CSC_Ucell_87_18 "87 电池单体电压";
CM_ SG_ 2400841298 CSC_Ucell_88_18 "88 电池单体电压";
CM_ SG_ 2400841298 CSC_Ucell_89_18 "89 电池单体电压";
CM_ SG_ 2400841298 CSC_Ucell_90_18 "90 电池单体电压";
CM_ SG_ 2400841298 CSC_Ucell_91_18 "91 电池单体电压";
CM_ SG_ 2400841298 CSC_Ucell_92_18 "92 电池单体电压";
CM_ SG_ 2400841298 CSC_Ucell_93_18 "93 电池单体电压";
CM_ SG_ 2400841298 CSC_Ucell_94_18 "94 电池单体电压";
CM_ SG_ 2400841298 CSC_Ucell_95_18 "95 电池单体电压";
CM_ SG_ 2400841298 CSC_Ucell_96_18 "96 电池单体电压";
CM_ SG_ 2400841298 CSC_Ucell_97_18 "97 电池单体电压";
CM_ SG_ 2400841298 CSC_Ucell_98_18 "98 电池单体电压";
CM_ SG_ 2400841298 CSC_Ucell_99_18 "99 电池单体电压";
CM_ SG_ 2400841298 CSC_Ucell_100_18 "100 电池单体电压";
CM_ SG_ 2400841298 CSC_Ucell_101_18 "101 电池单体电压";
CM_ SG_ 2400841298 CSC_Ucell_102_18 "102 电池单体电压";
CM_ SG_ 2400841298 CSC_Ucell_103_18 "103 电池单体电压";
CM_ SG_ 2400841298 CSC_Ucell_104_18 "104 电池单体电压";
CM_ SG_ 2400841298 CSC_Ucell_105_18 "105 电池单体电压";
CM_ SG_ 2400841298 CSC_Ucell_106_18 "106 电池单体电压";
CM_ SG_ 2400841298 CSC_Ucell_107_18 "107 电池单体电压";
CM_ SG_ 2400841298 CSC_Ucell_108_18 "108 电池单体电压";
VAL_ 2400841281 CSC_U_No_01 1 "CSC 1" 2 "CSC 2" 3 "CSC 3" 4 "CSC 4" 5 "CSC 5" 6 "CSC 6" ;
VAL_ 2400841281 CSC_Ucell_58_01 65535 "Invalid" ;
VAL_ 2400841281 CSC_Ucell_59_01 65535 "Invalid" ;
VAL_ 2400841281 CSC_Ucell_60_01 65535 "Invalid" ;
VAL_ 2400841281 CSC_Ucell_61_01 65535 "Invalid" ;
VAL_ 2400841281 CSC_Ucell_62_01 65535 "Invalid" ;
VAL_ 2400841281 CSC_Ucell_63_01 65535 "Invalid" ;
VAL_ 2400841281 CSC_Ucell_64_01 65535 "Invalid" ;
VAL_ 2400841281 CSC_Ucell_65_01 65535 "Invalid" ;
VAL_ 2400841281 CSC_Ucell_66_01 65535 "Invalid" ;
VAL_ 2400841281 CSC_Ucell_67_01 65535 "Invalid" ;
VAL_ 2400841281 CSC_Ucell_68_01 65535 "Invalid" ;
VAL_ 2400841281 CSC_Ucell_69_01 65535 "Invalid" ;
VAL_ 2400841281 CSC_Ucell_70_01 65535 "Invalid" ;
VAL_ 2400841281 CSC_Ucell_71_01 65535 "Invalid" ;
VAL_ 2400841281 CSC_Ucell_72_01 65535 "Invalid" ;
VAL_ 2400841281 CSC_Ucell_73_01 65535 "Invalid" ;
VAL_ 2400841281 CSC_Ucell_74_01 65535 "Invalid" ;
VAL_ 2400841281 CSC_Ucell_75_01 65535 "Invalid" ;
VAL_ 2400841281 CSC_Ucell_76_01 65535 "Invalid" ;
VAL_ 2400841281 CSC_Ucell_77_01 65535 "Invalid" ;
VAL_ 2400841281 CSC_Ucell_78_01 65535 "Invalid" ;
VAL_ 2400841281 CSC_Ucell_79_01 65535 "Invalid" ;
VAL_ 2400841281 CSC_Ucell_80_01 65535 "Invalid" ;
VAL_ 2400841281 CSC_Ucell_81_01 65535 "Invalid" ;
VAL_ 2400841281 CSC_Ucell_82_01 65535 "Invalid" ;
VAL_ 2400841281 CSC_Ucell_83_01 65535 "Invalid" ;
VAL_ 2400841281 CSC_Ucell_84_01 65535 "Invalid" ;
VAL_ 2400841281 CSC_Ucell_85_01 65535 "Invalid" ;
VAL_ 2400841281 CSC_Ucell_86_01 65535 "Invalid" ;
VAL_ 2400841281 CSC_Ucell_87_01 65535 "Invalid" ;
VAL_ 2400841281 CSC_Ucell_88_01 65535 "Invalid" ;
VAL_ 2400841281 CSC_Ucell_89_01 65535 "Invalid" ;
VAL_ 2400841281 CSC_Ucell_90_01 65535 "Invalid" ;
VAL_ 2400841281 CSC_Ucell_91_01 65535 "Invalid" ;
VAL_ 2400841281 CSC_Ucell_92_01 65535 "Invalid" ;
VAL_ 2400841281 CSC_Ucell_93_01 65535 "Invalid" ;
VAL_ 2400841281 CSC_Ucell_94_01 65535 "Invalid" ;
VAL_ 2400841281 CSC_Ucell_95_01 65535 "Invalid" ;
VAL_ 2400841281 CSC_Ucell_96_01 65535 "Invalid" ;
VAL_ 2400841281 CSC_Ucell_97_01 65535 "Invalid" ;
VAL_ 2400841281 CSC_Ucell_98_01 65535 "Invalid" ;
VAL_ 2400841281 CSC_Ucell_99_01 65535 "Invalid" ;
VAL_ 2400841281 CSC_Ucell_100_01 65535 "Invalid" ;
VAL_ 2400841281 CSC_Ucell_101_01 65535 "Invalid" ;
VAL_ 2400841281 CSC_Ucell_102_01 65535 "Invalid" ;
VAL_ 2400841281 CSC_Ucell_103_01 65535 "Invalid" ;
VAL_ 2400841281 CSC_Ucell_104_01 65535 "Invalid" ;
VAL_ 2400841281 CSC_Ucell_105_01 65535 "Invalid" ;
VAL_ 2400841281 CSC_Ucell_106_01 65535 "Invalid" ;
VAL_ 2400841281 CSC_Ucell_107_01 65535 "Invalid" ;
VAL_ 2400841281 CSC_Ucell_108_01 65535 "Invalid" ;
VAL_ 2400841282 CSC_U_No_02 1 "CSC 1" 2 "CSC 2" 3 "CSC 3" 4 "CSC 4" 5 "CSC 5" 6 "CSC 6" ;
VAL_ 2400841282 CSC_Ucell_58_02 65535 "Invalid" ;
VAL_ 2400841282 CSC_Ucell_59_02 65535 "Invalid" ;
VAL_ 2400841282 CSC_Ucell_60_02 65535 "Invalid" ;
VAL_ 2400841282 CSC_Ucell_61_02 65535 "Invalid" ;
VAL_ 2400841282 CSC_Ucell_62_02 65535 "Invalid" ;
VAL_ 2400841282 CSC_Ucell_63_02 65535 "Invalid" ;
VAL_ 2400841282 CSC_Ucell_64_02 65535 "Invalid" ;
VAL_ 2400841282 CSC_Ucell_65_02 65535 "Invalid" ;
VAL_ 2400841282 CSC_Ucell_66_02 65535 "Invalid" ;
VAL_ 2400841282 CSC_Ucell_67_02 65535 "Invalid" ;
VAL_ 2400841282 CSC_Ucell_68_02 65535 "Invalid" ;
VAL_ 2400841282 CSC_Ucell_69_02 65535 "Invalid" ;
VAL_ 2400841282 CSC_Ucell_70_02 65535 "Invalid" ;
VAL_ 2400841282 CSC_Ucell_71_02 65535 "Invalid" ;
VAL_ 2400841282 CSC_Ucell_72_02 65535 "Invalid" ;
VAL_ 2400841282 CSC_Ucell_73_02 65535 "Invalid" ;
VAL_ 2400841282 CSC_Ucell_74_02 65535 "Invalid" ;
VAL_ 2400841282 CSC_Ucell_75_02 65535 "Invalid" ;
VAL_ 2400841282 CSC_Ucell_76_02 65535 "Invalid" ;
VAL_ 2400841282 CSC_Ucell_77_02 65535 "Invalid" ;
VAL_ 2400841282 CSC_Ucell_78_02 65535 "Invalid" ;
VAL_ 2400841282 CSC_Ucell_79_02 65535 "Invalid" ;
VAL_ 2400841282 CSC_Ucell_80_02 65535 "Invalid" ;
VAL_ 2400841282 CSC_Ucell_81_02 65535 "Invalid" ;
VAL_ 2400841282 CSC_Ucell_82_02 65535 "Invalid" ;
VAL_ 2400841282 CSC_Ucell_83_02 65535 "Invalid" ;
VAL_ 2400841282 CSC_Ucell_84_02 65535 "Invalid" ;
VAL_ 2400841282 CSC_Ucell_85_02 65535 "Invalid" ;
VAL_ 2400841282 CSC_Ucell_86_02 65535 "Invalid" ;
VAL_ 2400841282 CSC_Ucell_87_02 65535 "Invalid" ;
VAL_ 2400841282 CSC_Ucell_88_02 65535 "Invalid" ;
VAL_ 2400841282 CSC_Ucell_89_02 65535 "Invalid" ;
VAL_ 2400841282 CSC_Ucell_90_02 65535 "Invalid" ;
VAL_ 2400841282 CSC_Ucell_91_02 65535 "Invalid" ;
VAL_ 2400841282 CSC_Ucell_92_02 65535 "Invalid" ;
VAL_ 2400841282 CSC_Ucell_93_02 65535 "Invalid" ;
VAL_ 2400841282 CSC_Ucell_94_02 65535 "Invalid" ;
VAL_ 2400841282 CSC_Ucell_95_02 65535 "Invalid" ;
VAL_ 2400841282 CSC_Ucell_96_02 65535 "Invalid" ;
VAL_ 2400841282 CSC_Ucell_97_02 65535 "Invalid" ;
VAL_ 2400841282 CSC_Ucell_98_02 65535 "Invalid" ;
VAL_ 2400841282 CSC_Ucell_99_02 65535 "Invalid" ;
VAL_ 2400841282 CSC_Ucell_100_02 65535 "Invalid" ;
VAL_ 2400841282 CSC_Ucell_101_02 65535 "Invalid" ;
VAL_ 2400841282 CSC_Ucell_102_02 65535 "Invalid" ;
VAL_ 2400841282 CSC_Ucell_103_02 65535 "Invalid" ;
VAL_ 2400841282 CSC_Ucell_104_02 65535 "Invalid" ;
VAL_ 2400841282 CSC_Ucell_105_02 65535 "Invalid" ;
VAL_ 2400841282 CSC_Ucell_106_02 65535 "Invalid" ;
VAL_ 2400841282 CSC_Ucell_107_02 65535 "Invalid" ;
VAL_ 2400841282 CSC_Ucell_108_02 65535 "Invalid" ;
VAL_ 2400841283 CSC_U_No_03 1 "CSC 1" 2 "CSC 2" 3 "CSC 3" 4 "CSC 4" 5 "CSC 5" 6 "CSC 6" ;
VAL_ 2400841283 CSC_Ucell_58_03 65535 "Invalid" ;
VAL_ 2400841283 CSC_Ucell_59_03 65535 "Invalid" ;
VAL_ 2400841283 CSC_Ucell_60_03 65535 "Invalid" ;
VAL_ 2400841283 CSC_Ucell_61_03 65535 "Invalid" ;
VAL_ 2400841283 CSC_Ucell_62_03 65535 "Invalid" ;
VAL_ 2400841283 CSC_Ucell_63_03 65535 "Invalid" ;
VAL_ 2400841283 CSC_Ucell_64_03 65535 "Invalid" ;
VAL_ 2400841283 CSC_Ucell_65_03 65535 "Invalid" ;
VAL_ 2400841283 CSC_Ucell_66_03 65535 "Invalid" ;
VAL_ 2400841283 CSC_Ucell_67_03 65535 "Invalid" ;
VAL_ 2400841283 CSC_Ucell_68_03 65535 "Invalid" ;
VAL_ 2400841283 CSC_Ucell_69_03 65535 "Invalid" ;
VAL_ 2400841283 CSC_Ucell_70_03 65535 "Invalid" ;
VAL_ 2400841283 CSC_Ucell_71_03 65535 "Invalid" ;
VAL_ 2400841283 CSC_Ucell_72_03 65535 "Invalid" ;
VAL_ 2400841283 CSC_Ucell_73_03 65535 "Invalid" ;
VAL_ 2400841283 CSC_Ucell_74_03 65535 "Invalid" ;
VAL_ 2400841283 CSC_Ucell_75_03 65535 "Invalid" ;
VAL_ 2400841283 CSC_Ucell_76_03 65535 "Invalid" ;
VAL_ 2400841283 CSC_Ucell_77_03 65535 "Invalid" ;
VAL_ 2400841283 CSC_Ucell_78_03 65535 "Invalid" ;
VAL_ 2400841283 CSC_Ucell_79_03 65535 "Invalid" ;
VAL_ 2400841283 CSC_Ucell_80_03 65535 "Invalid" ;
VAL_ 2400841283 CSC_Ucell_81_03 65535 "Invalid" ;
VAL_ 2400841283 CSC_Ucell_82_03 65535 "Invalid" ;
VAL_ 2400841283 CSC_Ucell_83_03 65535 "Invalid" ;
VAL_ 2400841283 CSC_Ucell_84_03 65535 "Invalid" ;
VAL_ 2400841283 CSC_Ucell_85_03 65535 "Invalid" ;
VAL_ 2400841283 CSC_Ucell_86_03 65535 "Invalid" ;
VAL_ 2400841283 CSC_Ucell_87_03 65535 "Invalid" ;
VAL_ 2400841283 CSC_Ucell_88_03 65535 "Invalid" ;
VAL_ 2400841283 CSC_Ucell_89_03 65535 "Invalid" ;
VAL_ 2400841283 CSC_Ucell_90_03 65535 "Invalid" ;
VAL_ 2400841283 CSC_Ucell_91_03 65535 "Invalid" ;
VAL_ 2400841283 CSC_Ucell_92_03 65535 "Invalid" ;
VAL_ 2400841283 CSC_Ucell_93_03 65535 "Invalid" ;
VAL_ 2400841283 CSC_Ucell_94_03 65535 "Invalid" ;
VAL_ 2400841283 CSC_Ucell_95_03 65535 "Invalid" ;
VAL_ 2400841283 CSC_Ucell_96_03 65535 "Invalid" ;
VAL_ 2400841283 CSC_Ucell_97_03 65535 "Invalid" ;
VAL_ 2400841283 CSC_Ucell_98_03 65535 "Invalid" ;
VAL_ 2400841283 CSC_Ucell_99_03 65535 "Invalid" ;
VAL_ 2400841283 CSC_Ucell_100_03 65535 "Invalid" ;
VAL_ 2400841283 CSC_Ucell_101_03 65535 "Invalid" ;
VAL_ 2400841283 CSC_Ucell_102_03 65535 "Invalid" ;
VAL_ 2400841283 CSC_Ucell_103_03 65535 "Invalid" ;
VAL_ 2400841283 CSC_Ucell_104_03 65535 "Invalid" ;
VAL_ 2400841283 CSC_Ucell_105_03 65535 "Invalid" ;
VAL_ 2400841283 CSC_Ucell_106_03 65535 "Invalid" ;
VAL_ 2400841283 CSC_Ucell_107_03 65535 "Invalid" ;
VAL_ 2400841283 CSC_Ucell_108_03 65535 "Invalid" ;
VAL_ 2400841284 CSC_U_No_04 1 "CSC 1" 2 "CSC 2" 3 "CSC 3" 4 "CSC 4" 5 "CSC 5" 6 "CSC 6" ;
VAL_ 2400841284 CSC_Ucell_58_04 65535 "Invalid" ;
VAL_ 2400841284 CSC_Ucell_59_04 65535 "Invalid" ;
VAL_ 2400841284 CSC_Ucell_60_04 65535 "Invalid" ;
VAL_ 2400841284 CSC_Ucell_61_04 65535 "Invalid" ;
VAL_ 2400841284 CSC_Ucell_62_04 65535 "Invalid" ;
VAL_ 2400841284 CSC_Ucell_63_04 65535 "Invalid" ;
VAL_ 2400841284 CSC_Ucell_64_04 65535 "Invalid" ;
VAL_ 2400841284 CSC_Ucell_65_04 65535 "Invalid" ;
VAL_ 2400841284 CSC_Ucell_66_04 65535 "Invalid" ;
VAL_ 2400841284 CSC_Ucell_67_04 65535 "Invalid" ;
VAL_ 2400841284 CSC_Ucell_68_04 65535 "Invalid" ;
VAL_ 2400841284 CSC_Ucell_69_04 65535 "Invalid" ;
VAL_ 2400841284 CSC_Ucell_70_04 65535 "Invalid" ;
VAL_ 2400841284 CSC_Ucell_71_04 65535 "Invalid" ;
VAL_ 2400841284 CSC_Ucell_72_04 65535 "Invalid" ;
VAL_ 2400841284 CSC_Ucell_73_04 65535 "Invalid" ;
VAL_ 2400841284 CSC_Ucell_74_04 65535 "Invalid" ;
VAL_ 2400841284 CSC_Ucell_75_04 65535 "Invalid" ;
VAL_ 2400841284 CSC_Ucell_76_04 65535 "Invalid" ;
VAL_ 2400841284 CSC_Ucell_77_04 65535 "Invalid" ;
VAL_ 2400841284 CSC_Ucell_78_04 65535 "Invalid" ;
VAL_ 2400841284 CSC_Ucell_79_04 65535 "Invalid" ;
VAL_ 2400841284 CSC_Ucell_80_04 65535 "Invalid" ;
VAL_ 2400841284 CSC_Ucell_81_04 65535 "Invalid" ;
VAL_ 2400841284 CSC_Ucell_82_04 65535 "Invalid" ;
VAL_ 2400841284 CSC_Ucell_83_04 65535 "Invalid" ;
VAL_ 2400841284 CSC_Ucell_84_04 65535 "Invalid" ;
VAL_ 2400841284 CSC_Ucell_85_04 65535 "Invalid" ;
VAL_ 2400841284 CSC_Ucell_86_04 65535 "Invalid" ;
VAL_ 2400841284 CSC_Ucell_87_04 65535 "Invalid" ;
VAL_ 2400841284 CSC_Ucell_88_04 65535 "Invalid" ;
VAL_ 2400841284 CSC_Ucell_89_04 65535 "Invalid" ;
VAL_ 2400841284 CSC_Ucell_90_04 65535 "Invalid" ;
VAL_ 2400841284 CSC_Ucell_91_04 65535 "Invalid" ;
VAL_ 2400841284 CSC_Ucell_92_04 65535 "Invalid" ;
VAL_ 2400841284 CSC_Ucell_93_04 65535 "Invalid" ;
VAL_ 2400841284 CSC_Ucell_94_04 65535 "Invalid" ;
VAL_ 2400841284 CSC_Ucell_95_04 65535 "Invalid" ;
VAL_ 2400841284 CSC_Ucell_96_04 65535 "Invalid" ;
VAL_ 2400841284 CSC_Ucell_97_04 65535 "Invalid" ;
VAL_ 2400841284 CSC_Ucell_98_04 65535 "Invalid" ;
VAL_ 2400841284 CSC_Ucell_99_04 65535 "Invalid" ;
VAL_ 2400841284 CSC_Ucell_100_04 65535 "Invalid" ;
VAL_ 2400841284 CSC_Ucell_101_04 65535 "Invalid" ;
VAL_ 2400841284 CSC_Ucell_102_04 65535 "Invalid" ;
VAL_ 2400841284 CSC_Ucell_103_04 65535 "Invalid" ;
VAL_ 2400841284 CSC_Ucell_104_04 65535 "Invalid" ;
VAL_ 2400841284 CSC_Ucell_105_04 65535 "Invalid" ;
VAL_ 2400841284 CSC_Ucell_106_04 65535 "Invalid" ;
VAL_ 2400841284 CSC_Ucell_107_04 65535 "Invalid" ;
VAL_ 2400841284 CSC_Ucell_108_04 65535 "Invalid" ;
VAL_ 2400841285 CSC_U_No_05 1 "CSC 1" 2 "CSC 2" 3 "CSC 3" 4 "CSC 4" 5 "CSC 5" 6 "CSC 6" ;
VAL_ 2400841285 CSC_Ucell_58_05 65535 "Invalid" ;
VAL_ 2400841285 CSC_Ucell_59_05 65535 "Invalid" ;
VAL_ 2400841285 CSC_Ucell_60_05 65535 "Invalid" ;
VAL_ 2400841285 CSC_Ucell_61_05 65535 "Invalid" ;
VAL_ 2400841285 CSC_Ucell_62_05 65535 "Invalid" ;
VAL_ 2400841285 CSC_Ucell_63_05 65535 "Invalid" ;
VAL_ 2400841285 CSC_Ucell_64_05 65535 "Invalid" ;
VAL_ 2400841285 CSC_Ucell_65_05 65535 "Invalid" ;
VAL_ 2400841285 CSC_Ucell_66_05 65535 "Invalid" ;
VAL_ 2400841285 CSC_Ucell_67_05 65535 "Invalid" ;
VAL_ 2400841285 CSC_Ucell_68_05 65535 "Invalid" ;
VAL_ 2400841285 CSC_Ucell_69_05 65535 "Invalid" ;
VAL_ 2400841285 CSC_Ucell_70_05 65535 "Invalid" ;
VAL_ 2400841285 CSC_Ucell_71_05 65535 "Invalid" ;
VAL_ 2400841285 CSC_Ucell_72_05 65535 "Invalid" ;
VAL_ 2400841285 CSC_Ucell_73_05 65535 "Invalid" ;
VAL_ 2400841285 CSC_Ucell_74_05 65535 "Invalid" ;
VAL_ 2400841285 CSC_Ucell_75_05 65535 "Invalid" ;
VAL_ 2400841285 CSC_Ucell_76_05 65535 "Invalid" ;
VAL_ 2400841285 CSC_Ucell_77_05 65535 "Invalid" ;
VAL_ 2400841285 CSC_Ucell_78_05 65535 "Invalid" ;
VAL_ 2400841285 CSC_Ucell_79_05 65535 "Invalid" ;
VAL_ 2400841285 CSC_Ucell_80_05 65535 "Invalid" ;
VAL_ 2400841285 CSC_Ucell_81_05 65535 "Invalid" ;
VAL_ 2400841285 CSC_Ucell_82_05 65535 "Invalid" ;
VAL_ 2400841285 CSC_Ucell_83_05 65535 "Invalid" ;
VAL_ 2400841285 CSC_Ucell_84_05 65535 "Invalid" ;
VAL_ 2400841285 CSC_Ucell_85_05 65535 "Invalid" ;
VAL_ 2400841285 CSC_Ucell_86_05 65535 "Invalid" ;
VAL_ 2400841285 CSC_Ucell_87_05 65535 "Invalid" ;
VAL_ 2400841285 CSC_Ucell_88_05 65535 "Invalid" ;
VAL_ 2400841285 CSC_Ucell_89_05 65535 "Invalid" ;
VAL_ 2400841285 CSC_Ucell_90_05 65535 "Invalid" ;
VAL_ 2400841285 CSC_Ucell_91_05 65535 "Invalid" ;
VAL_ 2400841285 CSC_Ucell_92_05 65535 "Invalid" ;
VAL_ 2400841285 CSC_Ucell_93_05 65535 "Invalid" ;
VAL_ 2400841285 CSC_Ucell_94_05 65535 "Invalid" ;
VAL_ 2400841285 CSC_Ucell_95_05 65535 "Invalid" ;
VAL_ 2400841285 CSC_Ucell_96_05 65535 "Invalid" ;
VAL_ 2400841285 CSC_Ucell_97_05 65535 "Invalid" ;
VAL_ 2400841285 CSC_Ucell_98_05 65535 "Invalid" ;
VAL_ 2400841285 CSC_Ucell_99_05 65535 "Invalid" ;
VAL_ 2400841285 CSC_Ucell_100_05 65535 "Invalid" ;
VAL_ 2400841285 CSC_Ucell_101_05 65535 "Invalid" ;
VAL_ 2400841285 CSC_Ucell_102_05 65535 "Invalid" ;
VAL_ 2400841285 CSC_Ucell_103_05 65535 "Invalid" ;
VAL_ 2400841285 CSC_Ucell_104_05 65535 "Invalid" ;
VAL_ 2400841285 CSC_Ucell_105_05 65535 "Invalid" ;
VAL_ 2400841285 CSC_Ucell_106_05 65535 "Invalid" ;
VAL_ 2400841285 CSC_Ucell_107_05 65535 "Invalid" ;
VAL_ 2400841285 CSC_Ucell_108_05 65535 "Invalid" ;
VAL_ 2400841286 CSC_U_No_06 1 "CSC 1" 2 "CSC 2" 3 "CSC 3" 4 "CSC 4" 5 "CSC 5" 6 "CSC 6" ;
VAL_ 2400841286 CSC_Ucell_58_06 65535 "Invalid" ;
VAL_ 2400841286 CSC_Ucell_59_06 65535 "Invalid" ;
VAL_ 2400841286 CSC_Ucell_60_06 65535 "Invalid" ;
VAL_ 2400841286 CSC_Ucell_61_06 65535 "Invalid" ;
VAL_ 2400841286 CSC_Ucell_62_06 65535 "Invalid" ;
VAL_ 2400841286 CSC_Ucell_63_06 65535 "Invalid" ;
VAL_ 2400841286 CSC_Ucell_64_06 65535 "Invalid" ;
VAL_ 2400841286 CSC_Ucell_65_06 65535 "Invalid" ;
VAL_ 2400841286 CSC_Ucell_66_06 65535 "Invalid" ;
VAL_ 2400841286 CSC_Ucell_67_06 65535 "Invalid" ;
VAL_ 2400841286 CSC_Ucell_68_06 65535 "Invalid" ;
VAL_ 2400841286 CSC_Ucell_69_06 65535 "Invalid" ;
VAL_ 2400841286 CSC_Ucell_70_06 65535 "Invalid" ;
VAL_ 2400841286 CSC_Ucell_71_06 65535 "Invalid" ;
VAL_ 2400841286 CSC_Ucell_72_06 65535 "Invalid" ;
VAL_ 2400841286 CSC_Ucell_73_06 65535 "Invalid" ;
VAL_ 2400841286 CSC_Ucell_74_06 65535 "Invalid" ;
VAL_ 2400841286 CSC_Ucell_75_06 65535 "Invalid" ;
VAL_ 2400841286 CSC_Ucell_76_06 65535 "Invalid" ;
VAL_ 2400841286 CSC_Ucell_77_06 65535 "Invalid" ;
VAL_ 2400841286 CSC_Ucell_78_06 65535 "Invalid" ;
VAL_ 2400841286 CSC_Ucell_79_06 65535 "Invalid" ;
VAL_ 2400841286 CSC_Ucell_80_06 65535 "Invalid" ;
VAL_ 2400841286 CSC_Ucell_81_06 65535 "Invalid" ;
VAL_ 2400841286 CSC_Ucell_82_06 65535 "Invalid" ;
VAL_ 2400841286 CSC_Ucell_83_06 65535 "Invalid" ;
VAL_ 2400841286 CSC_Ucell_84_06 65535 "Invalid" ;
VAL_ 2400841286 CSC_Ucell_85_06 65535 "Invalid" ;
VAL_ 2400841286 CSC_Ucell_86_06 65535 "Invalid" ;
VAL_ 2400841286 CSC_Ucell_87_06 65535 "Invalid" ;
VAL_ 2400841286 CSC_Ucell_88_06 65535 "Invalid" ;
VAL_ 2400841286 CSC_Ucell_89_06 65535 "Invalid" ;
VAL_ 2400841286 CSC_Ucell_90_06 65535 "Invalid" ;
VAL_ 2400841286 CSC_Ucell_91_06 65535 "Invalid" ;
VAL_ 2400841286 CSC_Ucell_92_06 65535 "Invalid" ;
VAL_ 2400841286 CSC_Ucell_93_06 65535 "Invalid" ;
VAL_ 2400841286 CSC_Ucell_94_06 65535 "Invalid" ;
VAL_ 2400841286 CSC_Ucell_95_06 65535 "Invalid" ;
VAL_ 2400841286 CSC_Ucell_96_06 65535 "Invalid" ;
VAL_ 2400841286 CSC_Ucell_97_06 65535 "Invalid" ;
VAL_ 2400841286 CSC_Ucell_98_06 65535 "Invalid" ;
VAL_ 2400841286 CSC_Ucell_99_06 65535 "Invalid" ;
VAL_ 2400841286 CSC_Ucell_100_06 65535 "Invalid" ;
VAL_ 2400841286 CSC_Ucell_101_06 65535 "Invalid" ;
VAL_ 2400841286 CSC_Ucell_102_06 65535 "Invalid" ;
VAL_ 2400841286 CSC_Ucell_103_06 65535 "Invalid" ;
VAL_ 2400841286 CSC_Ucell_104_06 65535 "Invalid" ;
VAL_ 2400841286 CSC_Ucell_105_06 65535 "Invalid" ;
VAL_ 2400841286 CSC_Ucell_106_06 65535 "Invalid" ;
VAL_ 2400841286 CSC_Ucell_107_06 65535 "Invalid" ;
VAL_ 2400841286 CSC_Ucell_108_06 65535 "Invalid" ;
VAL_ 2400841287 CSC_U_No_07 1 "CSC 1" 2 "CSC 2" 3 "CSC 3" 4 "CSC 4" 5 "CSC 5" 6 "CSC 6" ;
VAL_ 2400841287 CSC_Ucell_58_07 65535 "Invalid" ;
VAL_ 2400841287 CSC_Ucell_59_07 65535 "Invalid" ;
VAL_ 2400841287 CSC_Ucell_60_07 65535 "Invalid" ;
VAL_ 2400841287 CSC_Ucell_61_07 65535 "Invalid" ;
VAL_ 2400841287 CSC_Ucell_62_07 65535 "Invalid" ;
VAL_ 2400841287 CSC_Ucell_63_07 65535 "Invalid" ;
VAL_ 2400841287 CSC_Ucell_64_07 65535 "Invalid" ;
VAL_ 2400841287 CSC_Ucell_65_07 65535 "Invalid" ;
VAL_ 2400841287 CSC_Ucell_66_07 65535 "Invalid" ;
VAL_ 2400841287 CSC_Ucell_67_07 65535 "Invalid" ;
VAL_ 2400841287 CSC_Ucell_68_07 65535 "Invalid" ;
VAL_ 2400841287 CSC_Ucell_69_07 65535 "Invalid" ;
VAL_ 2400841287 CSC_Ucell_70_07 65535 "Invalid" ;
VAL_ 2400841287 CSC_Ucell_71_07 65535 "Invalid" ;
VAL_ 2400841287 CSC_Ucell_72_07 65535 "Invalid" ;
VAL_ 2400841287 CSC_Ucell_73_07 65535 "Invalid" ;
VAL_ 2400841287 CSC_Ucell_74_07 65535 "Invalid" ;
VAL_ 2400841287 CSC_Ucell_75_07 65535 "Invalid" ;
VAL_ 2400841287 CSC_Ucell_76_07 65535 "Invalid" ;
VAL_ 2400841287 CSC_Ucell_77_07 65535 "Invalid" ;
VAL_ 2400841287 CSC_Ucell_78_07 65535 "Invalid" ;
VAL_ 2400841287 CSC_Ucell_79_07 65535 "Invalid" ;
VAL_ 2400841287 CSC_Ucell_80_07 65535 "Invalid" ;
VAL_ 2400841287 CSC_Ucell_81_07 65535 "Invalid" ;
VAL_ 2400841287 CSC_Ucell_82_07 65535 "Invalid" ;
VAL_ 2400841287 CSC_Ucell_83_07 65535 "Invalid" ;
VAL_ 2400841287 CSC_Ucell_84_07 65535 "Invalid" ;
VAL_ 2400841287 CSC_Ucell_85_07 65535 "Invalid" ;
VAL_ 2400841287 CSC_Ucell_86_07 65535 "Invalid" ;
VAL_ 2400841287 CSC_Ucell_87_07 65535 "Invalid" ;
VAL_ 2400841287 CSC_Ucell_88_07 65535 "Invalid" ;
VAL_ 2400841287 CSC_Ucell_89_07 65535 "Invalid" ;
VAL_ 2400841287 CSC_Ucell_90_07 65535 "Invalid" ;
VAL_ 2400841287 CSC_Ucell_91_07 65535 "Invalid" ;
VAL_ 2400841287 CSC_Ucell_92_07 65535 "Invalid" ;
VAL_ 2400841287 CSC_Ucell_93_07 65535 "Invalid" ;
VAL_ 2400841287 CSC_Ucell_94_07 65535 "Invalid" ;
VAL_ 2400841287 CSC_Ucell_95_07 65535 "Invalid" ;
VAL_ 2400841287 CSC_Ucell_96_07 65535 "Invalid" ;
VAL_ 2400841287 CSC_Ucell_97_07 65535 "Invalid" ;
VAL_ 2400841287 CSC_Ucell_98_07 65535 "Invalid" ;
VAL_ 2400841287 CSC_Ucell_99_07 65535 "Invalid" ;
VAL_ 2400841287 CSC_Ucell_100_07 65535 "Invalid" ;
VAL_ 2400841287 CSC_Ucell_101_07 65535 "Invalid" ;
VAL_ 2400841287 CSC_Ucell_102_07 65535 "Invalid" ;
VAL_ 2400841287 CSC_Ucell_103_07 65535 "Invalid" ;
VAL_ 2400841287 CSC_Ucell_104_07 65535 "Invalid" ;
VAL_ 2400841287 CSC_Ucell_105_07 65535 "Invalid" ;
VAL_ 2400841287 CSC_Ucell_106_07 65535 "Invalid" ;
VAL_ 2400841287 CSC_Ucell_107_07 65535 "Invalid" ;
VAL_ 2400841287 CSC_Ucell_108_07 65535 "Invalid" ;
VAL_ 2400841288 CSC_U_No_08 1 "CSC 1" 2 "CSC 2" 3 "CSC 3" 4 "CSC 4" 5 "CSC 5" 6 "CSC 6" ;
VAL_ 2400841288 CSC_Ucell_58_08 65535 "Invalid" ;
VAL_ 2400841288 CSC_Ucell_59_08 65535 "Invalid" ;
VAL_ 2400841288 CSC_Ucell_60_08 65535 "Invalid" ;
VAL_ 2400841288 CSC_Ucell_61_08 65535 "Invalid" ;
VAL_ 2400841288 CSC_Ucell_62_08 65535 "Invalid" ;
VAL_ 2400841288 CSC_Ucell_63_08 65535 "Invalid" ;
VAL_ 2400841288 CSC_Ucell_64_08 65535 "Invalid" ;
VAL_ 2400841288 CSC_Ucell_65_08 65535 "Invalid" ;
VAL_ 2400841288 CSC_Ucell_66_08 65535 "Invalid" ;
VAL_ 2400841288 CSC_Ucell_67_08 65535 "Invalid" ;
VAL_ 2400841288 CSC_Ucell_68_08 65535 "Invalid" ;
VAL_ 2400841288 CSC_Ucell_69_08 65535 "Invalid" ;
VAL_ 2400841288 CSC_Ucell_70_08 65535 "Invalid" ;
VAL_ 2400841288 CSC_Ucell_71_08 65535 "Invalid" ;
VAL_ 2400841288 CSC_Ucell_72_08 65535 "Invalid" ;
VAL_ 2400841288 CSC_Ucell_73_08 65535 "Invalid" ;
VAL_ 2400841288 CSC_Ucell_74_08 65535 "Invalid" ;
VAL_ 2400841288 CSC_Ucell_75_08 65535 "Invalid" ;
VAL_ 2400841288 CSC_Ucell_76_08 65535 "Invalid" ;
VAL_ 2400841288 CSC_Ucell_77_08 65535 "Invalid" ;
VAL_ 2400841288 CSC_Ucell_78_08 65535 "Invalid" ;
VAL_ 2400841288 CSC_Ucell_79_08 65535 "Invalid" ;
VAL_ 2400841288 CSC_Ucell_80_08 65535 "Invalid" ;
VAL_ 2400841288 CSC_Ucell_81_08 65535 "Invalid" ;
VAL_ 2400841288 CSC_Ucell_82_08 65535 "Invalid" ;
VAL_ 2400841288 CSC_Ucell_83_08 65535 "Invalid" ;
VAL_ 2400841288 CSC_Ucell_84_08 65535 "Invalid" ;
VAL_ 2400841288 CSC_Ucell_85_08 65535 "Invalid" ;
VAL_ 2400841288 CSC_Ucell_86_08 65535 "Invalid" ;
VAL_ 2400841288 CSC_Ucell_87_08 65535 "Invalid" ;
VAL_ 2400841288 CSC_Ucell_88_08 65535 "Invalid" ;
VAL_ 2400841288 CSC_Ucell_89_08 65535 "Invalid" ;
VAL_ 2400841288 CSC_Ucell_90_08 65535 "Invalid" ;
VAL_ 2400841288 CSC_Ucell_91_08 65535 "Invalid" ;
VAL_ 2400841288 CSC_Ucell_92_08 65535 "Invalid" ;
VAL_ 2400841288 CSC_Ucell_93_08 65535 "Invalid" ;
VAL_ 2400841288 CSC_Ucell_94_08 65535 "Invalid" ;
VAL_ 2400841288 CSC_Ucell_95_08 65535 "Invalid" ;
VAL_ 2400841288 CSC_Ucell_96_08 65535 "Invalid" ;
VAL_ 2400841288 CSC_Ucell_97_08 65535 "Invalid" ;
VAL_ 2400841288 CSC_Ucell_98_08 65535 "Invalid" ;
VAL_ 2400841288 CSC_Ucell_99_08 65535 "Invalid" ;
VAL_ 2400841288 CSC_Ucell_100_08 65535 "Invalid" ;
VAL_ 2400841288 CSC_Ucell_101_08 65535 "Invalid" ;
VAL_ 2400841288 CSC_Ucell_102_08 65535 "Invalid" ;
VAL_ 2400841288 CSC_Ucell_103_08 65535 "Invalid" ;
VAL_ 2400841288 CSC_Ucell_104_08 65535 "Invalid" ;
VAL_ 2400841288 CSC_Ucell_105_08 65535 "Invalid" ;
VAL_ 2400841288 CSC_Ucell_106_08 65535 "Invalid" ;
VAL_ 2400841288 CSC_Ucell_107_08 65535 "Invalid" ;
VAL_ 2400841288 CSC_Ucell_108_08 65535 "Invalid" ;
VAL_ 2400841289 CSC_U_No_09 1 "CSC 1" 2 "CSC 2" 3 "CSC 3" 4 "CSC 4" 5 "CSC 5" 6 "CSC 6" ;
VAL_ 2400841289 CSC_Ucell_58_09 65535 "Invalid" ;
VAL_ 2400841289 CSC_Ucell_59_09 65535 "Invalid" ;
VAL_ 2400841289 CSC_Ucell_60_09 65535 "Invalid" ;
VAL_ 2400841289 CSC_Ucell_61_09 65535 "Invalid" ;
VAL_ 2400841289 CSC_Ucell_62_09 65535 "Invalid" ;
VAL_ 2400841289 CSC_Ucell_63_09 65535 "Invalid" ;
VAL_ 2400841289 CSC_Ucell_64_09 65535 "Invalid" ;
VAL_ 2400841289 CSC_Ucell_65_09 65535 "Invalid" ;
VAL_ 2400841289 CSC_Ucell_66_09 65535 "Invalid" ;
VAL_ 2400841289 CSC_Ucell_67_09 65535 "Invalid" ;
VAL_ 2400841289 CSC_Ucell_68_09 65535 "Invalid" ;
VAL_ 2400841289 CSC_Ucell_69_09 65535 "Invalid" ;
VAL_ 2400841289 CSC_Ucell_70_09 65535 "Invalid" ;
VAL_ 2400841289 CSC_Ucell_71_09 65535 "Invalid" ;
VAL_ 2400841289 CSC_Ucell_72_09 65535 "Invalid" ;
VAL_ 2400841289 CSC_Ucell_73_09 65535 "Invalid" ;
VAL_ 2400841289 CSC_Ucell_74_09 65535 "Invalid" ;
VAL_ 2400841289 CSC_Ucell_75_09 65535 "Invalid" ;
VAL_ 2400841289 CSC_Ucell_76_09 65535 "Invalid" ;
VAL_ 2400841289 CSC_Ucell_77_09 65535 "Invalid" ;
VAL_ 2400841289 CSC_Ucell_78_09 65535 "Invalid" ;
VAL_ 2400841289 CSC_Ucell_79_09 65535 "Invalid" ;
VAL_ 2400841289 CSC_Ucell_80_09 65535 "Invalid" ;
VAL_ 2400841289 CSC_Ucell_81_09 65535 "Invalid" ;
VAL_ 2400841289 CSC_Ucell_82_09 65535 "Invalid" ;
VAL_ 2400841289 CSC_Ucell_83_09 65535 "Invalid" ;
VAL_ 2400841289 CSC_Ucell_84_09 65535 "Invalid" ;
VAL_ 2400841289 CSC_Ucell_85_09 65535 "Invalid" ;
VAL_ 2400841289 CSC_Ucell_86_09 65535 "Invalid" ;
VAL_ 2400841289 CSC_Ucell_87_09 65535 "Invalid" ;
VAL_ 2400841289 CSC_Ucell_88_09 65535 "Invalid" ;
VAL_ 2400841289 CSC_Ucell_89_09 65535 "Invalid" ;
VAL_ 2400841289 CSC_Ucell_90_09 65535 "Invalid" ;
VAL_ 2400841289 CSC_Ucell_91_09 65535 "Invalid" ;
VAL_ 2400841289 CSC_Ucell_92_09 65535 "Invalid" ;
VAL_ 2400841289 CSC_Ucell_93_09 65535 "Invalid" ;
VAL_ 2400841289 CSC_Ucell_94_09 65535 "Invalid" ;
VAL_ 2400841289 CSC_Ucell_95_09 65535 "Invalid" ;
VAL_ 2400841289 CSC_Ucell_96_09 65535 "Invalid" ;
VAL_ 2400841289 CSC_Ucell_97_09 65535 "Invalid" ;
VAL_ 2400841289 CSC_Ucell_98_09 65535 "Invalid" ;
VAL_ 2400841289 CSC_Ucell_99_09 65535 "Invalid" ;
VAL_ 2400841289 CSC_Ucell_100_09 65535 "Invalid" ;
VAL_ 2400841289 CSC_Ucell_101_09 65535 "Invalid" ;
VAL_ 2400841289 CSC_Ucell_102_09 65535 "Invalid" ;
VAL_ 2400841289 CSC_Ucell_103_09 65535 "Invalid" ;
VAL_ 2400841289 CSC_Ucell_104_09 65535 "Invalid" ;
VAL_ 2400841289 CSC_Ucell_105_09 65535 "Invalid" ;
VAL_ 2400841289 CSC_Ucell_106_09 65535 "Invalid" ;
VAL_ 2400841289 CSC_Ucell_107_09 65535 "Invalid" ;
VAL_ 2400841289 CSC_Ucell_108_09 65535 "Invalid" ;
VAL_ 2400841290 CSC_U_No_10 1 "CSC 1" 2 "CSC 2" 3 "CSC 3" 4 "CSC 4" 5 "CSC 5" 6 "CSC 6" ;
VAL_ 2400841290 CSC_Ucell_58_10 65535 "Invalid" ;
VAL_ 2400841290 CSC_Ucell_59_10 65535 "Invalid" ;
VAL_ 2400841290 CSC_Ucell_60_10 65535 "Invalid" ;
VAL_ 2400841290 CSC_Ucell_61_10 65535 "Invalid" ;
VAL_ 2400841290 CSC_Ucell_62_10 65535 "Invalid" ;
VAL_ 2400841290 CSC_Ucell_63_10 65535 "Invalid" ;
VAL_ 2400841290 CSC_Ucell_64_10 65535 "Invalid" ;
VAL_ 2400841290 CSC_Ucell_65_10 65535 "Invalid" ;
VAL_ 2400841290 CSC_Ucell_66_10 65535 "Invalid" ;
VAL_ 2400841290 CSC_Ucell_67_10 65535 "Invalid" ;
VAL_ 2400841290 CSC_Ucell_68_10 65535 "Invalid" ;
VAL_ 2400841290 CSC_Ucell_69_10 65535 "Invalid" ;
VAL_ 2400841290 CSC_Ucell_70_10 65535 "Invalid" ;
VAL_ 2400841290 CSC_Ucell_71_10 65535 "Invalid" ;
VAL_ 2400841290 CSC_Ucell_72_10 65535 "Invalid" ;
VAL_ 2400841290 CSC_Ucell_73_10 65535 "Invalid" ;
VAL_ 2400841290 CSC_Ucell_74_10 65535 "Invalid" ;
VAL_ 2400841290 CSC_Ucell_75_10 65535 "Invalid" ;
VAL_ 2400841290 CSC_Ucell_76_10 65535 "Invalid" ;
VAL_ 2400841290 CSC_Ucell_77_10 65535 "Invalid" ;
VAL_ 2400841290 CSC_Ucell_78_10 65535 "Invalid" ;
VAL_ 2400841290 CSC_Ucell_79_10 65535 "Invalid" ;
VAL_ 2400841290 CSC_Ucell_80_10 65535 "Invalid" ;
VAL_ 2400841290 CSC_Ucell_81_10 65535 "Invalid" ;
VAL_ 2400841290 CSC_Ucell_82_10 65535 "Invalid" ;
VAL_ 2400841290 CSC_Ucell_83_10 65535 "Invalid" ;
VAL_ 2400841290 CSC_Ucell_84_10 65535 "Invalid" ;
VAL_ 2400841290 CSC_Ucell_85_10 65535 "Invalid" ;
VAL_ 2400841290 CSC_Ucell_86_10 65535 "Invalid" ;
VAL_ 2400841290 CSC_Ucell_87_10 65535 "Invalid" ;
VAL_ 2400841290 CSC_Ucell_88_10 65535 "Invalid" ;
VAL_ 2400841290 CSC_Ucell_89_10 65535 "Invalid" ;
VAL_ 2400841290 CSC_Ucell_90_10 65535 "Invalid" ;
VAL_ 2400841290 CSC_Ucell_91_10 65535 "Invalid" ;
VAL_ 2400841290 CSC_Ucell_92_10 65535 "Invalid" ;
VAL_ 2400841290 CSC_Ucell_93_10 65535 "Invalid" ;
VAL_ 2400841290 CSC_Ucell_94_10 65535 "Invalid" ;
VAL_ 2400841290 CSC_Ucell_95_10 65535 "Invalid" ;
VAL_ 2400841290 CSC_Ucell_96_10 65535 "Invalid" ;
VAL_ 2400841290 CSC_Ucell_97_10 65535 "Invalid" ;
VAL_ 2400841290 CSC_Ucell_98_10 65535 "Invalid" ;
VAL_ 2400841290 CSC_Ucell_99_10 65535 "Invalid" ;
VAL_ 2400841290 CSC_Ucell_100_10 65535 "Invalid" ;
VAL_ 2400841290 CSC_Ucell_101_10 65535 "Invalid" ;
VAL_ 2400841290 CSC_Ucell_102_10 65535 "Invalid" ;
VAL_ 2400841290 CSC_Ucell_103_10 65535 "Invalid" ;
VAL_ 2400841290 CSC_Ucell_104_10 65535 "Invalid" ;
VAL_ 2400841290 CSC_Ucell_105_10 65535 "Invalid" ;
VAL_ 2400841290 CSC_Ucell_106_10 65535 "Invalid" ;
VAL_ 2400841290 CSC_Ucell_107_10 65535 "Invalid" ;
VAL_ 2400841290 CSC_Ucell_108_10 65535 "Invalid" ;
VAL_ 2400841291 CSC_U_No_11 1 "CSC 1" 2 "CSC 2" 3 "CSC 3" 4 "CSC 4" 5 "CSC 5" 6 "CSC 6" ;
VAL_ 2400841291 CSC_Ucell_58_11 65535 "Invalid" ;
VAL_ 2400841291 CSC_Ucell_59_11 65535 "Invalid" ;
VAL_ 2400841291 CSC_Ucell_60_11 65535 "Invalid" ;
VAL_ 2400841291 CSC_Ucell_61_11 65535 "Invalid" ;
VAL_ 2400841291 CSC_Ucell_62_11 65535 "Invalid" ;
VAL_ 2400841291 CSC_Ucell_63_11 65535 "Invalid" ;
VAL_ 2400841291 CSC_Ucell_64_11 65535 "Invalid" ;
VAL_ 2400841291 CSC_Ucell_65_11 65535 "Invalid" ;
VAL_ 2400841291 CSC_Ucell_66_11 65535 "Invalid" ;
VAL_ 2400841291 CSC_Ucell_67_11 65535 "Invalid" ;
VAL_ 2400841291 CSC_Ucell_68_11 65535 "Invalid" ;
VAL_ 2400841291 CSC_Ucell_69_11 65535 "Invalid" ;
VAL_ 2400841291 CSC_Ucell_70_11 65535 "Invalid" ;
VAL_ 2400841291 CSC_Ucell_71_11 65535 "Invalid" ;
VAL_ 2400841291 CSC_Ucell_72_11 65535 "Invalid" ;
VAL_ 2400841291 CSC_Ucell_73_11 65535 "Invalid" ;
VAL_ 2400841291 CSC_Ucell_74_11 65535 "Invalid" ;
VAL_ 2400841291 CSC_Ucell_75_11 65535 "Invalid" ;
VAL_ 2400841291 CSC_Ucell_76_11 65535 "Invalid" ;
VAL_ 2400841291 CSC_Ucell_77_11 65535 "Invalid" ;
VAL_ 2400841291 CSC_Ucell_78_11 65535 "Invalid" ;
VAL_ 2400841291 CSC_Ucell_79_11 65535 "Invalid" ;
VAL_ 2400841291 CSC_Ucell_80_11 65535 "Invalid" ;
VAL_ 2400841291 CSC_Ucell_81_11 65535 "Invalid" ;
VAL_ 2400841291 CSC_Ucell_82_11 65535 "Invalid" ;
VAL_ 2400841291 CSC_Ucell_83_11 65535 "Invalid" ;
VAL_ 2400841291 CSC_Ucell_84_11 65535 "Invalid" ;
VAL_ 2400841291 CSC_Ucell_85_11 65535 "Invalid" ;
VAL_ 2400841291 CSC_Ucell_86_11 65535 "Invalid" ;
VAL_ 2400841291 CSC_Ucell_87_11 65535 "Invalid" ;
VAL_ 2400841291 CSC_Ucell_88_11 65535 "Invalid" ;
VAL_ 2400841291 CSC_Ucell_89_11 65535 "Invalid" ;
VAL_ 2400841291 CSC_Ucell_90_11 65535 "Invalid" ;
VAL_ 2400841291 CSC_Ucell_91_11 65535 "Invalid" ;
VAL_ 2400841291 CSC_Ucell_92_11 65535 "Invalid" ;
VAL_ 2400841291 CSC_Ucell_93_11 65535 "Invalid" ;
VAL_ 2400841291 CSC_Ucell_94_11 65535 "Invalid" ;
VAL_ 2400841291 CSC_Ucell_95_11 65535 "Invalid" ;
VAL_ 2400841291 CSC_Ucell_96_11 65535 "Invalid" ;
VAL_ 2400841291 CSC_Ucell_97_11 65535 "Invalid" ;
VAL_ 2400841291 CSC_Ucell_98_11 65535 "Invalid" ;
VAL_ 2400841291 CSC_Ucell_99_11 65535 "Invalid" ;
VAL_ 2400841291 CSC_Ucell_100_11 65535 "Invalid" ;
VAL_ 2400841291 CSC_Ucell_101_11 65535 "Invalid" ;
VAL_ 2400841291 CSC_Ucell_102_11 65535 "Invalid" ;
VAL_ 2400841291 CSC_Ucell_103_11 65535 "Invalid" ;
VAL_ 2400841291 CSC_Ucell_104_11 65535 "Invalid" ;
VAL_ 2400841291 CSC_Ucell_105_11 65535 "Invalid" ;
VAL_ 2400841291 CSC_Ucell_106_11 65535 "Invalid" ;
VAL_ 2400841291 CSC_Ucell_107_11 65535 "Invalid" ;
VAL_ 2400841291 CSC_Ucell_108_11 65535 "Invalid" ;
VAL_ 2400841292 CSC_U_No_12 1 "CSC 1" 2 "CSC 2" 3 "CSC 3" 4 "CSC 4" 5 "CSC 5" 6 "CSC 6" ;
VAL_ 2400841292 CSC_Ucell_58_12 65535 "Invalid" ;
VAL_ 2400841292 CSC_Ucell_59_12 65535 "Invalid" ;
VAL_ 2400841292 CSC_Ucell_60_12 65535 "Invalid" ;
VAL_ 2400841292 CSC_Ucell_61_12 65535 "Invalid" ;
VAL_ 2400841292 CSC_Ucell_62_12 65535 "Invalid" ;
VAL_ 2400841292 CSC_Ucell_63_12 65535 "Invalid" ;
VAL_ 2400841292 CSC_Ucell_64_12 65535 "Invalid" ;
VAL_ 2400841292 CSC_Ucell_65_12 65535 "Invalid" ;
VAL_ 2400841292 CSC_Ucell_66_12 65535 "Invalid" ;
VAL_ 2400841292 CSC_Ucell_67_12 65535 "Invalid" ;
VAL_ 2400841292 CSC_Ucell_68_12 65535 "Invalid" ;
VAL_ 2400841292 CSC_Ucell_69_12 65535 "Invalid" ;
VAL_ 2400841292 CSC_Ucell_70_12 65535 "Invalid" ;
VAL_ 2400841292 CSC_Ucell_71_12 65535 "Invalid" ;
VAL_ 2400841292 CSC_Ucell_72_12 65535 "Invalid" ;
VAL_ 2400841292 CSC_Ucell_73_12 65535 "Invalid" ;
VAL_ 2400841292 CSC_Ucell_74_12 65535 "Invalid" ;
VAL_ 2400841292 CSC_Ucell_75_12 65535 "Invalid" ;
VAL_ 2400841292 CSC_Ucell_76_12 65535 "Invalid" ;
VAL_ 2400841292 CSC_Ucell_77_12 65535 "Invalid" ;
VAL_ 2400841292 CSC_Ucell_78_12 65535 "Invalid" ;
VAL_ 2400841292 CSC_Ucell_79_12 65535 "Invalid" ;
VAL_ 2400841292 CSC_Ucell_80_12 65535 "Invalid" ;
VAL_ 2400841292 CSC_Ucell_81_12 65535 "Invalid" ;
VAL_ 2400841292 CSC_Ucell_82_12 65535 "Invalid" ;
VAL_ 2400841292 CSC_Ucell_83_12 65535 "Invalid" ;
VAL_ 2400841292 CSC_Ucell_84_12 65535 "Invalid" ;
VAL_ 2400841292 CSC_Ucell_85_12 65535 "Invalid" ;
VAL_ 2400841292 CSC_Ucell_86_12 65535 "Invalid" ;
VAL_ 2400841292 CSC_Ucell_87_12 65535 "Invalid" ;
VAL_ 2400841292 CSC_Ucell_88_12 65535 "Invalid" ;
VAL_ 2400841292 CSC_Ucell_89_12 65535 "Invalid" ;
VAL_ 2400841292 CSC_Ucell_90_12 65535 "Invalid" ;
VAL_ 2400841292 CSC_Ucell_91_12 65535 "Invalid" ;
VAL_ 2400841292 CSC_Ucell_92_12 65535 "Invalid" ;
VAL_ 2400841292 CSC_Ucell_93_12 65535 "Invalid" ;
VAL_ 2400841292 CSC_Ucell_94_12 65535 "Invalid" ;
VAL_ 2400841292 CSC_Ucell_95_12 65535 "Invalid" ;
VAL_ 2400841292 CSC_Ucell_96_12 65535 "Invalid" ;
VAL_ 2400841292 CSC_Ucell_97_12 65535 "Invalid" ;
VAL_ 2400841292 CSC_Ucell_98_12 65535 "Invalid" ;
VAL_ 2400841292 CSC_Ucell_99_12 65535 "Invalid" ;
VAL_ 2400841292 CSC_Ucell_100_12 65535 "Invalid" ;
VAL_ 2400841292 CSC_Ucell_101_12 65535 "Invalid" ;
VAL_ 2400841292 CSC_Ucell_102_12 65535 "Invalid" ;
VAL_ 2400841292 CSC_Ucell_103_12 65535 "Invalid" ;
VAL_ 2400841292 CSC_Ucell_104_12 65535 "Invalid" ;
VAL_ 2400841292 CSC_Ucell_105_12 65535 "Invalid" ;
VAL_ 2400841292 CSC_Ucell_106_12 65535 "Invalid" ;
VAL_ 2400841292 CSC_Ucell_107_12 65535 "Invalid" ;
VAL_ 2400841292 CSC_Ucell_108_12 65535 "Invalid" ;
VAL_ 2400841293 CSC_U_No_13 1 "CSC 1" 2 "CSC 2" 3 "CSC 3" 4 "CSC 4" 5 "CSC 5" 6 "CSC 6" ;
VAL_ 2400841293 CSC_Ucell_58_13 65535 "Invalid" ;
VAL_ 2400841293 CSC_Ucell_59_13 65535 "Invalid" ;
VAL_ 2400841293 CSC_Ucell_60_13 65535 "Invalid" ;
VAL_ 2400841293 CSC_Ucell_61_13 65535 "Invalid" ;
VAL_ 2400841293 CSC_Ucell_62_13 65535 "Invalid" ;
VAL_ 2400841293 CSC_Ucell_63_13 65535 "Invalid" ;
VAL_ 2400841293 CSC_Ucell_64_13 65535 "Invalid" ;
VAL_ 2400841293 CSC_Ucell_65_13 65535 "Invalid" ;
VAL_ 2400841293 CSC_Ucell_66_13 65535 "Invalid" ;
VAL_ 2400841293 CSC_Ucell_67_13 65535 "Invalid" ;
VAL_ 2400841293 CSC_Ucell_68_13 65535 "Invalid" ;
VAL_ 2400841293 CSC_Ucell_69_13 65535 "Invalid" ;
VAL_ 2400841293 CSC_Ucell_70_13 65535 "Invalid" ;
VAL_ 2400841293 CSC_Ucell_71_13 65535 "Invalid" ;
VAL_ 2400841293 CSC_Ucell_72_13 65535 "Invalid" ;
VAL_ 2400841293 CSC_Ucell_73_13 65535 "Invalid" ;
VAL_ 2400841293 CSC_Ucell_74_13 65535 "Invalid" ;
VAL_ 2400841293 CSC_Ucell_75_13 65535 "Invalid" ;
VAL_ 2400841293 CSC_Ucell_76_13 65535 "Invalid" ;
VAL_ 2400841293 CSC_Ucell_77_13 65535 "Invalid" ;
VAL_ 2400841293 CSC_Ucell_78_13 65535 "Invalid" ;
VAL_ 2400841293 CSC_Ucell_79_13 65535 "Invalid" ;
VAL_ 2400841293 CSC_Ucell_80_13 65535 "Invalid" ;
VAL_ 2400841293 CSC_Ucell_81_13 65535 "Invalid" ;
VAL_ 2400841293 CSC_Ucell_82_13 65535 "Invalid" ;
VAL_ 2400841293 CSC_Ucell_83_13 65535 "Invalid" ;
VAL_ 2400841293 CSC_Ucell_84_13 65535 "Invalid" ;
VAL_ 2400841293 CSC_Ucell_85_13 65535 "Invalid" ;
VAL_ 2400841293 CSC_Ucell_86_13 65535 "Invalid" ;
VAL_ 2400841293 CSC_Ucell_87_13 65535 "Invalid" ;
VAL_ 2400841293 CSC_Ucell_88_13 65535 "Invalid" ;
VAL_ 2400841293 CSC_Ucell_89_13 65535 "Invalid" ;
VAL_ 2400841293 CSC_Ucell_90_13 65535 "Invalid" ;
VAL_ 2400841293 CSC_Ucell_91_13 65535 "Invalid" ;
VAL_ 2400841293 CSC_Ucell_92_13 65535 "Invalid" ;
VAL_ 2400841293 CSC_Ucell_93_13 65535 "Invalid" ;
VAL_ 2400841293 CSC_Ucell_94_13 65535 "Invalid" ;
VAL_ 2400841293 CSC_Ucell_95_13 65535 "Invalid" ;
VAL_ 2400841293 CSC_Ucell_96_13 65535 "Invalid" ;
VAL_ 2400841293 CSC_Ucell_97_13 65535 "Invalid" ;
VAL_ 2400841293 CSC_Ucell_98_13 65535 "Invalid" ;
VAL_ 2400841293 CSC_Ucell_99_13 65535 "Invalid" ;
VAL_ 2400841293 CSC_Ucell_100_13 65535 "Invalid" ;
VAL_ 2400841293 CSC_Ucell_101_13 65535 "Invalid" ;
VAL_ 2400841293 CSC_Ucell_102_13 65535 "Invalid" ;
VAL_ 2400841293 CSC_Ucell_103_13 65535 "Invalid" ;
VAL_ 2400841293 CSC_Ucell_104_13 65535 "Invalid" ;
VAL_ 2400841293 CSC_Ucell_105_13 65535 "Invalid" ;
VAL_ 2400841293 CSC_Ucell_106_13 65535 "Invalid" ;
VAL_ 2400841293 CSC_Ucell_107_13 65535 "Invalid" ;
VAL_ 2400841293 CSC_Ucell_108_13 65535 "Invalid" ;
VAL_ 2400841294 CSC_U_No_14 1 "CSC 1" 2 "CSC 2" 3 "CSC 3" 4 "CSC 4" 5 "CSC 5" 6 "CSC 6" ;
VAL_ 2400841294 CSC_Ucell_58_14 65535 "Invalid" ;
VAL_ 2400841294 CSC_Ucell_59_14 65535 "Invalid" ;
VAL_ 2400841294 CSC_Ucell_60_14 65535 "Invalid" ;
VAL_ 2400841294 CSC_Ucell_61_14 65535 "Invalid" ;
VAL_ 2400841294 CSC_Ucell_62_14 65535 "Invalid" ;
VAL_ 2400841294 CSC_Ucell_63_14 65535 "Invalid" ;
VAL_ 2400841294 CSC_Ucell_64_14 65535 "Invalid" ;
VAL_ 2400841294 CSC_Ucell_65_14 65535 "Invalid" ;
VAL_ 2400841294 CSC_Ucell_66_14 65535 "Invalid" ;
VAL_ 2400841294 CSC_Ucell_67_14 65535 "Invalid" ;
VAL_ 2400841294 CSC_Ucell_68_14 65535 "Invalid" ;
VAL_ 2400841294 CSC_Ucell_69_14 65535 "Invalid" ;
VAL_ 2400841294 CSC_Ucell_70_14 65535 "Invalid" ;
VAL_ 2400841294 CSC_Ucell_71_14 65535 "Invalid" ;
VAL_ 2400841294 CSC_Ucell_72_14 65535 "Invalid" ;
VAL_ 2400841294 CSC_Ucell_73_14 65535 "Invalid" ;
VAL_ 2400841294 CSC_Ucell_74_14 65535 "Invalid" ;
VAL_ 2400841294 CSC_Ucell_75_14 65535 "Invalid" ;
VAL_ 2400841294 CSC_Ucell_76_14 65535 "Invalid" ;
VAL_ 2400841294 CSC_Ucell_77_14 65535 "Invalid" ;
VAL_ 2400841294 CSC_Ucell_78_14 65535 "Invalid" ;
VAL_ 2400841294 CSC_Ucell_79_14 65535 "Invalid" ;
VAL_ 2400841294 CSC_Ucell_80_14 65535 "Invalid" ;
VAL_ 2400841294 CSC_Ucell_81_14 65535 "Invalid" ;
VAL_ 2400841294 CSC_Ucell_82_14 65535 "Invalid" ;
VAL_ 2400841294 CSC_Ucell_83_14 65535 "Invalid" ;
VAL_ 2400841294 CSC_Ucell_84_14 65535 "Invalid" ;
VAL_ 2400841294 CSC_Ucell_85_14 65535 "Invalid" ;
VAL_ 2400841294 CSC_Ucell_86_14 65535 "Invalid" ;
VAL_ 2400841294 CSC_Ucell_87_14 65535 "Invalid" ;
VAL_ 2400841294 CSC_Ucell_88_14 65535 "Invalid" ;
VAL_ 2400841294 CSC_Ucell_89_14 65535 "Invalid" ;
VAL_ 2400841294 CSC_Ucell_90_14 65535 "Invalid" ;
VAL_ 2400841294 CSC_Ucell_91_14 65535 "Invalid" ;
VAL_ 2400841294 CSC_Ucell_92_14 65535 "Invalid" ;
VAL_ 2400841294 CSC_Ucell_93_14 65535 "Invalid" ;
VAL_ 2400841294 CSC_Ucell_94_14 65535 "Invalid" ;
VAL_ 2400841294 CSC_Ucell_95_14 65535 "Invalid" ;
VAL_ 2400841294 CSC_Ucell_96_14 65535 "Invalid" ;
VAL_ 2400841294 CSC_Ucell_97_14 65535 "Invalid" ;
VAL_ 2400841294 CSC_Ucell_98_14 65535 "Invalid" ;
VAL_ 2400841294 CSC_Ucell_99_14 65535 "Invalid" ;
VAL_ 2400841294 CSC_Ucell_100_14 65535 "Invalid" ;
VAL_ 2400841294 CSC_Ucell_101_14 65535 "Invalid" ;
VAL_ 2400841294 CSC_Ucell_102_14 65535 "Invalid" ;
VAL_ 2400841294 CSC_Ucell_103_14 65535 "Invalid" ;
VAL_ 2400841294 CSC_Ucell_104_14 65535 "Invalid" ;
VAL_ 2400841294 CSC_Ucell_105_14 65535 "Invalid" ;
VAL_ 2400841294 CSC_Ucell_106_14 65535 "Invalid" ;
VAL_ 2400841294 CSC_Ucell_107_14 65535 "Invalid" ;
VAL_ 2400841294 CSC_Ucell_108_14 65535 "Invalid" ;
VAL_ 2400841295 CSC_U_No_15 1 "CSC 1" 2 "CSC 2" 3 "CSC 3" 4 "CSC 4" 5 "CSC 5" 6 "CSC 6" ;
VAL_ 2400841295 CSC_Ucell_58_15 65535 "Invalid" ;
VAL_ 2400841295 CSC_Ucell_59_15 65535 "Invalid" ;
VAL_ 2400841295 CSC_Ucell_60_15 65535 "Invalid" ;
VAL_ 2400841295 CSC_Ucell_61_15 65535 "Invalid" ;
VAL_ 2400841295 CSC_Ucell_62_15 65535 "Invalid" ;
VAL_ 2400841295 CSC_Ucell_63_15 65535 "Invalid" ;
VAL_ 2400841295 CSC_Ucell_64_15 65535 "Invalid" ;
VAL_ 2400841295 CSC_Ucell_65_15 65535 "Invalid" ;
VAL_ 2400841295 CSC_Ucell_66_15 65535 "Invalid" ;
VAL_ 2400841295 CSC_Ucell_67_15 65535 "Invalid" ;
VAL_ 2400841295 CSC_Ucell_68_15 65535 "Invalid" ;
VAL_ 2400841295 CSC_Ucell_69_15 65535 "Invalid" ;
VAL_ 2400841295 CSC_Ucell_70_15 65535 "Invalid" ;
VAL_ 2400841295 CSC_Ucell_71_15 65535 "Invalid" ;
VAL_ 2400841295 CSC_Ucell_72_15 65535 "Invalid" ;
VAL_ 2400841295 CSC_Ucell_73_15 65535 "Invalid" ;
VAL_ 2400841295 CSC_Ucell_74_15 65535 "Invalid" ;
VAL_ 2400841295 CSC_Ucell_75_15 65535 "Invalid" ;
VAL_ 2400841295 CSC_Ucell_76_15 65535 "Invalid" ;
VAL_ 2400841295 CSC_Ucell_77_15 65535 "Invalid" ;
VAL_ 2400841295 CSC_Ucell_78_15 65535 "Invalid" ;
VAL_ 2400841295 CSC_Ucell_79_15 65535 "Invalid" ;
VAL_ 2400841295 CSC_Ucell_80_15 65535 "Invalid" ;
VAL_ 2400841295 CSC_Ucell_81_15 65535 "Invalid" ;
VAL_ 2400841295 CSC_Ucell_82_15 65535 "Invalid" ;
VAL_ 2400841295 CSC_Ucell_83_15 65535 "Invalid" ;
VAL_ 2400841295 CSC_Ucell_84_15 65535 "Invalid" ;
VAL_ 2400841295 CSC_Ucell_85_15 65535 "Invalid" ;
VAL_ 2400841295 CSC_Ucell_86_15 65535 "Invalid" ;
VAL_ 2400841295 CSC_Ucell_87_15 65535 "Invalid" ;
VAL_ 2400841295 CSC_Ucell_88_15 65535 "Invalid" ;
VAL_ 2400841295 CSC_Ucell_89_15 65535 "Invalid" ;
VAL_ 2400841295 CSC_Ucell_90_15 65535 "Invalid" ;
VAL_ 2400841295 CSC_Ucell_91_15 65535 "Invalid" ;
VAL_ 2400841295 CSC_Ucell_92_15 65535 "Invalid" ;
VAL_ 2400841295 CSC_Ucell_93_15 65535 "Invalid" ;
VAL_ 2400841295 CSC_Ucell_94_15 65535 "Invalid" ;
VAL_ 2400841295 CSC_Ucell_95_15 65535 "Invalid" ;
VAL_ 2400841295 CSC_Ucell_96_15 65535 "Invalid" ;
VAL_ 2400841295 CSC_Ucell_97_15 65535 "Invalid" ;
VAL_ 2400841295 CSC_Ucell_98_15 65535 "Invalid" ;
VAL_ 2400841295 CSC_Ucell_99_15 65535 "Invalid" ;
VAL_ 2400841295 CSC_Ucell_100_15 65535 "Invalid" ;
VAL_ 2400841295 CSC_Ucell_101_15 65535 "Invalid" ;
VAL_ 2400841295 CSC_Ucell_102_15 65535 "Invalid" ;
VAL_ 2400841295 CSC_Ucell_103_15 65535 "Invalid" ;
VAL_ 2400841295 CSC_Ucell_104_15 65535 "Invalid" ;
VAL_ 2400841295 CSC_Ucell_105_15 65535 "Invalid" ;
VAL_ 2400841295 CSC_Ucell_106_15 65535 "Invalid" ;
VAL_ 2400841295 CSC_Ucell_107_15 65535 "Invalid" ;
VAL_ 2400841295 CSC_Ucell_108_15 65535 "Invalid" ;
VAL_ 2400841296 CSC_U_No_16 1 "CSC 1" 2 "CSC 2" 3 "CSC 3" 4 "CSC 4" 5 "CSC 5" 6 "CSC 6" ;
VAL_ 2400841296 CSC_Ucell_58_16 65535 "Invalid" ;
VAL_ 2400841296 CSC_Ucell_59_16 65535 "Invalid" ;
VAL_ 2400841296 CSC_Ucell_60_16 65535 "Invalid" ;
VAL_ 2400841296 CSC_Ucell_61_16 65535 "Invalid" ;
VAL_ 2400841296 CSC_Ucell_62_16 65535 "Invalid" ;
VAL_ 2400841296 CSC_Ucell_63_16 65535 "Invalid" ;
VAL_ 2400841296 CSC_Ucell_64_16 65535 "Invalid" ;
VAL_ 2400841296 CSC_Ucell_65_16 65535 "Invalid" ;
VAL_ 2400841296 CSC_Ucell_66_16 65535 "Invalid" ;
VAL_ 2400841296 CSC_Ucell_67_16 65535 "Invalid" ;
VAL_ 2400841296 CSC_Ucell_68_16 65535 "Invalid" ;
VAL_ 2400841296 CSC_Ucell_69_16 65535 "Invalid" ;
VAL_ 2400841296 CSC_Ucell_70_16 65535 "Invalid" ;
VAL_ 2400841296 CSC_Ucell_71_16 65535 "Invalid" ;
VAL_ 2400841296 CSC_Ucell_72_16 65535 "Invalid" ;
VAL_ 2400841296 CSC_Ucell_73_16 65535 "Invalid" ;
VAL_ 2400841296 CSC_Ucell_74_16 65535 "Invalid" ;
VAL_ 2400841296 CSC_Ucell_75_16 65535 "Invalid" ;
VAL_ 2400841296 CSC_Ucell_76_16 65535 "Invalid" ;
VAL_ 2400841296 CSC_Ucell_77_16 65535 "Invalid" ;
VAL_ 2400841296 CSC_Ucell_78_16 65535 "Invalid" ;
VAL_ 2400841296 CSC_Ucell_79_16 65535 "Invalid" ;
VAL_ 2400841296 CSC_Ucell_80_16 65535 "Invalid" ;
VAL_ 2400841296 CSC_Ucell_81_16 65535 "Invalid" ;
VAL_ 2400841296 CSC_Ucell_82_16 65535 "Invalid" ;
VAL_ 2400841296 CSC_Ucell_83_16 65535 "Invalid" ;
VAL_ 2400841296 CSC_Ucell_84_16 65535 "Invalid" ;
VAL_ 2400841296 CSC_Ucell_85_16 65535 "Invalid" ;
VAL_ 2400841296 CSC_Ucell_86_16 65535 "Invalid" ;
VAL_ 2400841296 CSC_Ucell_87_16 65535 "Invalid" ;
VAL_ 2400841296 CSC_Ucell_88_16 65535 "Invalid" ;
VAL_ 2400841296 CSC_Ucell_89_16 65535 "Invalid" ;
VAL_ 2400841296 CSC_Ucell_90_16 65535 "Invalid" ;
VAL_ 2400841296 CSC_Ucell_91_16 65535 "Invalid" ;
VAL_ 2400841296 CSC_Ucell_92_16 65535 "Invalid" ;
VAL_ 2400841296 CSC_Ucell_93_16 65535 "Invalid" ;
VAL_ 2400841296 CSC_Ucell_94_16 65535 "Invalid" ;
VAL_ 2400841296 CSC_Ucell_95_16 65535 "Invalid" ;
VAL_ 2400841296 CSC_Ucell_96_16 65535 "Invalid" ;
VAL_ 2400841296 CSC_Ucell_97_16 65535 "Invalid" ;
VAL_ 2400841296 CSC_Ucell_98_16 65535 "Invalid" ;
VAL_ 2400841296 CSC_Ucell_99_16 65535 "Invalid" ;
VAL_ 2400841296 CSC_Ucell_100_16 65535 "Invalid" ;
VAL_ 2400841296 CSC_Ucell_101_16 65535 "Invalid" ;
VAL_ 2400841296 CSC_Ucell_102_16 65535 "Invalid" ;
VAL_ 2400841296 CSC_Ucell_103_16 65535 "Invalid" ;
VAL_ 2400841296 CSC_Ucell_104_16 65535 "Invalid" ;
VAL_ 2400841296 CSC_Ucell_105_16 65535 "Invalid" ;
VAL_ 2400841296 CSC_Ucell_106_16 65535 "Invalid" ;
VAL_ 2400841296 CSC_Ucell_107_16 65535 "Invalid" ;
VAL_ 2400841296 CSC_Ucell_108_16 65535 "Invalid" ;
VAL_ 2400841297 CSC_U_No_17 1 "CSC 1" 2 "CSC 2" 3 "CSC 3" 4 "CSC 4" 5 "CSC 5" 6 "CSC 6" ;
VAL_ 2400841297 CSC_Ucell_58_17 65535 "Invalid" ;
VAL_ 2400841297 CSC_Ucell_59_17 65535 "Invalid" ;
VAL_ 2400841297 CSC_Ucell_60_17 65535 "Invalid" ;
VAL_ 2400841297 CSC_Ucell_61_17 65535 "Invalid" ;
VAL_ 2400841297 CSC_Ucell_62_17 65535 "Invalid" ;
VAL_ 2400841297 CSC_Ucell_63_17 65535 "Invalid" ;
VAL_ 2400841297 CSC_Ucell_64_17 65535 "Invalid" ;
VAL_ 2400841297 CSC_Ucell_65_17 65535 "Invalid" ;
VAL_ 2400841297 CSC_Ucell_66_17 65535 "Invalid" ;
VAL_ 2400841297 CSC_Ucell_67_17 65535 "Invalid" ;
VAL_ 2400841297 CSC_Ucell_68_17 65535 "Invalid" ;
VAL_ 2400841297 CSC_Ucell_69_17 65535 "Invalid" ;
VAL_ 2400841297 CSC_Ucell_70_17 65535 "Invalid" ;
VAL_ 2400841297 CSC_Ucell_71_17 65535 "Invalid" ;
VAL_ 2400841297 CSC_Ucell_72_17 65535 "Invalid" ;
VAL_ 2400841297 CSC_Ucell_73_17 65535 "Invalid" ;
VAL_ 2400841297 CSC_Ucell_74_17 65535 "Invalid" ;
VAL_ 2400841297 CSC_Ucell_75_17 65535 "Invalid" ;
VAL_ 2400841297 CSC_Ucell_76_17 65535 "Invalid" ;
VAL_ 2400841297 CSC_Ucell_77_17 65535 "Invalid" ;
VAL_ 2400841297 CSC_Ucell_78_17 65535 "Invalid" ;
VAL_ 2400841297 CSC_Ucell_79_17 65535 "Invalid" ;
VAL_ 2400841297 CSC_Ucell_80_17 65535 "Invalid" ;
VAL_ 2400841297 CSC_Ucell_81_17 65535 "Invalid" ;
VAL_ 2400841297 CSC_Ucell_82_17 65535 "Invalid" ;
VAL_ 2400841297 CSC_Ucell_83_17 65535 "Invalid" ;
VAL_ 2400841297 CSC_Ucell_84_17 65535 "Invalid" ;
VAL_ 2400841297 CSC_Ucell_85_17 65535 "Invalid" ;
VAL_ 2400841297 CSC_Ucell_86_17 65535 "Invalid" ;
VAL_ 2400841297 CSC_Ucell_87_17 65535 "Invalid" ;
VAL_ 2400841297 CSC_Ucell_88_17 65535 "Invalid" ;
VAL_ 2400841297 CSC_Ucell_89_17 65535 "Invalid" ;
VAL_ 2400841297 CSC_Ucell_90_17 65535 "Invalid" ;
VAL_ 2400841297 CSC_Ucell_91_17 65535 "Invalid" ;
VAL_ 2400841297 CSC_Ucell_92_17 65535 "Invalid" ;
VAL_ 2400841297 CSC_Ucell_93_17 65535 "Invalid" ;
VAL_ 2400841297 CSC_Ucell_94_17 65535 "Invalid" ;
VAL_ 2400841297 CSC_Ucell_95_17 65535 "Invalid" ;
VAL_ 2400841297 CSC_Ucell_96_17 65535 "Invalid" ;
VAL_ 2400841297 CSC_Ucell_97_17 65535 "Invalid" ;
VAL_ 2400841297 CSC_Ucell_98_17 65535 "Invalid" ;
VAL_ 2400841297 CSC_Ucell_99_17 65535 "Invalid" ;
VAL_ 2400841297 CSC_Ucell_100_17 65535 "Invalid" ;
VAL_ 2400841297 CSC_Ucell_101_17 65535 "Invalid" ;
VAL_ 2400841297 CSC_Ucell_102_17 65535 "Invalid" ;
VAL_ 2400841297 CSC_Ucell_103_17 65535 "Invalid" ;
VAL_ 2400841297 CSC_Ucell_104_17 65535 "Invalid" ;
VAL_ 2400841297 CSC_Ucell_105_17 65535 "Invalid" ;
VAL_ 2400841297 CSC_Ucell_106_17 65535 "Invalid" ;
VAL_ 2400841297 CSC_Ucell_107_17 65535 "Invalid" ;
VAL_ 2400841297 CSC_Ucell_108_17 65535 "Invalid" ;
VAL_ 2400841298 CSC_U_No_18 1 "CSC 1" 2 "CSC 2" 3 "CSC 3" 4 "CSC 4" 5 "CSC 5" 6 "CSC 6" ;
VAL_ 2400841298 CSC_Ucell_58_18 65535 "Invalid" ;
VAL_ 2400841298 CSC_Ucell_59_18 65535 "Invalid" ;
VAL_ 2400841298 CSC_Ucell_60_18 65535 "Invalid" ;
VAL_ 2400841298 CSC_Ucell_61_18 65535 "Invalid" ;
VAL_ 2400841298 CSC_Ucell_62_18 65535 "Invalid" ;
VAL_ 2400841298 CSC_Ucell_63_18 65535 "Invalid" ;
VAL_ 2400841298 CSC_Ucell_64_18 65535 "Invalid" ;
VAL_ 2400841298 CSC_Ucell_65_18 65535 "Invalid" ;
VAL_ 2400841298 CSC_Ucell_66_18 65535 "Invalid" ;
VAL_ 2400841298 CSC_Ucell_67_18 65535 "Invalid" ;
VAL_ 2400841298 CSC_Ucell_68_18 65535 "Invalid" ;
VAL_ 2400841298 CSC_Ucell_69_18 65535 "Invalid" ;
VAL_ 2400841298 CSC_Ucell_70_18 65535 "Invalid" ;
VAL_ 2400841298 CSC_Ucell_71_18 65535 "Invalid" ;
VAL_ 2400841298 CSC_Ucell_72_18 65535 "Invalid" ;
VAL_ 2400841298 CSC_Ucell_73_18 65535 "Invalid" ;
VAL_ 2400841298 CSC_Ucell_74_18 65535 "Invalid" ;
VAL_ 2400841298 CSC_Ucell_75_18 65535 "Invalid" ;
VAL_ 2400841298 CSC_Ucell_76_18 65535 "Invalid" ;
VAL_ 2400841298 CSC_Ucell_77_18 65535 "Invalid" ;
VAL_ 2400841298 CSC_Ucell_78_18 65535 "Invalid" ;
VAL_ 2400841298 CSC_Ucell_79_18 65535 "Invalid" ;
VAL_ 2400841298 CSC_Ucell_80_18 65535 "Invalid" ;
VAL_ 2400841298 CSC_Ucell_81_18 65535 "Invalid" ;
VAL_ 2400841298 CSC_Ucell_82_18 65535 "Invalid" ;
VAL_ 2400841298 CSC_Ucell_83_18 65535 "Invalid" ;
VAL_ 2400841298 CSC_Ucell_84_18 65535 "Invalid" ;
VAL_ 2400841298 CSC_Ucell_85_18 65535 "Invalid" ;
VAL_ 2400841298 CSC_Ucell_86_18 65535 "Invalid" ;
VAL_ 2400841298 CSC_Ucell_87_18 65535 "Invalid" ;
VAL_ 2400841298 CSC_Ucell_88_18 65535 "Invalid" ;
VAL_ 2400841298 CSC_Ucell_89_18 65535 "Invalid" ;
VAL_ 2400841298 CSC_Ucell_90_18 65535 "Invalid" ;
VAL_ 2400841298 CSC_Ucell_91_18 65535 "Invalid" ;
VAL_ 2400841298 CSC_Ucell_92_18 65535 "Invalid" ;
VAL_ 2400841298 CSC_Ucell_93_18 65535 "Invalid" ;
VAL_ 2400841298 CSC_Ucell_94_18 65535 "Invalid" ;
VAL_ 2400841298 CSC_Ucell_95_18 65535 "Invalid" ;
VAL_ 2400841298 CSC_Ucell_96_18 65535 "Invalid" ;
VAL_ 2400841298 CSC_Ucell_97_18 65535 "Invalid" ;
VAL_ 2400841298 CSC_Ucell_98_18 65535 "Invalid" ;
VAL_ 2400841298 CSC_Ucell_99_18 65535 "Invalid" ;
VAL_ 2400841298 CSC_Ucell_100_18 65535 "Invalid" ;
VAL_ 2400841298 CSC_Ucell_101_18 65535 "Invalid" ;
VAL_ 2400841298 CSC_Ucell_102_18 65535 "Invalid" ;
VAL_ 2400841298 CSC_Ucell_103_18 65535 "Invalid" ;
VAL_ 2400841298 CSC_Ucell_104_18 65535 "Invalid" ;
VAL_ 2400841298 CSC_Ucell_105_18 65535 "Invalid" ;
VAL_ 2400841298 CSC_Ucell_106_18 65535 "Invalid" ;
VAL_ 2400841298 CSC_Ucell_107_18 65535 "Invalid" ;
VAL_ 2400841298 CSC_Ucell_108_18 65535 "Invalid" ;
VERSION ""

NS_ :

BS_:

BU_: MBMU PC SBMU IMM ETH DCDC LEMS

BO_ 2400841343 S2P_Detail_Ucell20__63: 8 SBMU
 SG_ CSC_U_No_63 : 0|8@1+ (1,0) [0|255] ""  PC
 SG_ CSC_Ucell_Frame_Index_63 M : 8|8@1+ (1,0) [0|255] ""  PC
 SG_ CSC_Ucell_58_63 m0 : 16|16@1+ (1,0) [0|65535] "mV"  PC
 SG_ CSC_Ucell_59_63 m0 : 32|16@1+ (1,0) [0|65535] "mV"  PC
 SG_ CSC_Ucell_60_63 m0 : 48|16@1+ (1,0) [0|65535] "mV"  PC
 SG_ CSC_Ucell_61_63 m1 : 16|16@1+ (1,0) [0|65535] "mV"  PC
 SG_ CSC_Ucell_62_63 m1 : 32|16@1+ (1,0) [0|65535] "mV"  PC
 SG_ CSC_Ucell_63_63 m1 : 48|16@1+ (1,0) [0|65535] "mV"  PC
 SG_ CSC_Ucell_64_63 m2 : 16|16@1+ (1,0) [0|65535] "mV"  PC
 SG_ CSC_Ucell_65_63 m2 : 32|16@1+ (1,0) [0|65535] "mV"  PC
 SG_ CSC_Ucell_66_63 m2 : 48|16@1+ (1,0) [0|65535] "mV"  PC
 SG_ CSC_Ucell_67_63 m3 : 16|16@1+ (1,0) [0|65535] "mV"  PC
 SG_ CSC_Ucell_68_63 m3 : 32|16@1+ (1,0) [0|65535] "mV"  PC
 SG_ CSC_Ucell_69_63 m3 : 48|16@1+ (1,0) [0|65535] "mV"  PC
 SG_ CSC_Ucell_70_63 m4 : 16|16@1+ (1,0) [0|65535] "mV"  PC
 SG_ CSC_Ucell_71_63 m4 : 32|16@1+ (1,0) [0|65535] "mV"  PC
 SG_ CSC_Ucell_72_63 m4 : 48|16@1+ (1,0) [0|65535] "mV"  PC
 SG_ CSC_Ucell_73_63 m5 : 16|16@1+ (1,0) [0|65535] "mV"  PC
 SG_ CSC_Ucell_74_63 m5 : 32|16@1+ (1,0) [0|65535] "mV"  PC
 SG_ CSC_Ucell_75_63 m5 : 48|16@1+ (1,0) [0|65535] "mV"  PC
 SG_ CSC_Ucell_76_63 m6 : 16|16@1+ (1,0) [0|65535] "mV"  PC
 SG_ CSC_Ucell_77_63 m6 : 32|16@1+ (1,0) [0|65535] "mV"  PC
 SG_ CSC_Ucell_78_63 m6 : 48|16@1+ (1,0) [0|65535] "mV"  PC
 SG_ CSC_Ucell_79_63 m7 : 16|16@1+ (1,0) [0|65535] "mV"  PC
 SG_ CSC_Ucell_80_63 m7 : 32|16@1+ (1,0) [0|65535] "mV"  PC
 SG_ CSC_Ucell_81_63 m7 : 48|16@1+ (1,0) [0|65535] "mV"  PC
 SG_ CSC_Ucell_82_63 m8 : 16|16@1+ (1,0) [0|65535] "mV"  PC
 SG_ CSC_Ucell_83_63 m8 : 32|16@1+ (1,0) [0|65535] "mV"  PC
 SG_ CSC_Ucell_84_63 m8 : 48|16@1+ (1,0) [0|65535] "mV"  PC
 SG_ CSC_Ucell_85_63 m9 : 16|16@1+ (1,0) [0|65535] "mV"  PC
 SG_ CSC_Ucell_86_63 m9 : 32|16@1+ (1,0) [0|65535] "mV"  PC
 SG_ CSC_Ucell_87_63 m9 : 48|16@1+ (1,0) [0|65535] "mV"  PC
 SG_ CSC_Ucell_88_63 m10 : 16|16@1+ (1,0) [0|65535] "mV"  PC
 SG_ CSC_Ucell_89_63 m10 : 32|16@1+ (1,0) [0|65535] "mV"  PC
 SG_ CSC_Ucell_90_63 m10 : 48|16@1+ (1,0) [0|65535] "mV"  PC
 SG_ CSC_Ucell_91_63 m11 : 16|16@1+ (1,0) [0|65535] "mV"  PC
 SG_ CSC_Ucell_92_63 m11 : 32|16@1+ (1,0) [0|65535] "mV"  PC
 SG_ CSC_Ucell_93_63 m11 : 48|16@1+ (1,0) [0|65535] "mV"  PC
 SG_ CSC_Ucell_94_63 m12 : 16|16@1+ (1,0) [0|65535] "mV"  PC
 SG_ CSC_Ucell_95_63 m12 : 32|16@1+ (1,0) [0|65535] "mV"  PC
 SG_ CSC_Ucell_96_63 m12 : 48|16@1+ (1,0) [0|65535] "mV"  PC
 SG_ CSC_Ucell_97_63 m13 : 16|16@1+ (1,0) [0|65535] "mV"  PC
 SG_ CSC_Ucell_98_63 m13 : 32|16@1+ (1,0) [0|65535] "mV"  PC
 SG_ CSC_Ucell_99_63 m13 : 48|16@1+ (1,0) [0|65535] "mV"  PC
 SG_ CSC_Ucell_100_63 m14 : 16|16@1+ (1,0) [0|65535] "mV"  PC
 SG_ CSC_Ucell_101_63 m14 : 32|16@1+ (1,0) [0|65535] "mV"  PC
 SG_ CSC_Ucell_102_63 m14 : 48|16@1+ (1,0) [0|65535] "mV"  PC
 SG_ CSC_Ucell_103_63 m15 : 16|16@1+ (1,0) [0|65535] "mV"  PC
 SG_ CSC_Ucell_104_63 m15 : 32|16@1+ (1,0) [0|65535] "mV"  PC
 SG_ CSC_Ucell_105_63 m15 : 48|16@1+ (1,0) [0|65535] "mV"  PC
 SG_ CSC_Ucell_106_63 m16 : 16|16@1+ (1,0) [0|65535] "mV"  PC
 SG_ CSC_Ucell_107_63 m16 : 32|16@1+ (1,0) [0|65535] "mV"  PC
 SG_ CSC_Ucell_108_63 m16 : 48|16@1+ (1,0) [0|65535] "mV"  PC

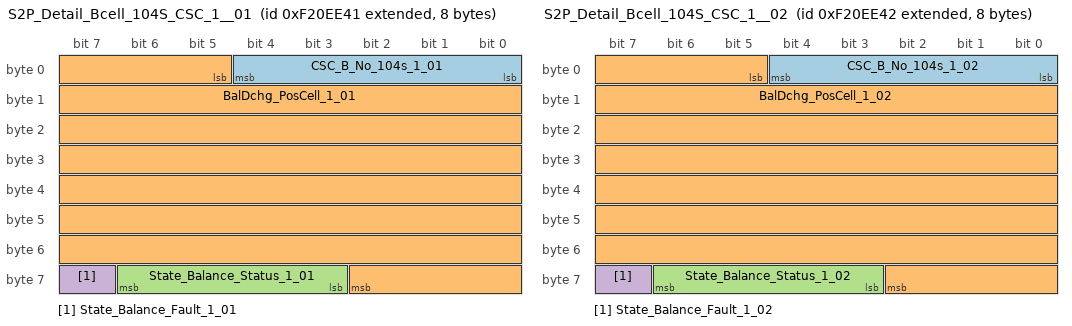
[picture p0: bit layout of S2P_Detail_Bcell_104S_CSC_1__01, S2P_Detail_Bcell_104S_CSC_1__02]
BO_ 2401300033 S2P_Detail_Bcell_104S_CSC_1__01: 8 SBMU
 SG_ CSC_B_No_104s_1_01 : 0|5@1+ (1,0) [0|31] ""  PC
 SG_ BalDchg_PosCell_1_01 : 5|54@1+ (1,0) [0|1.8014398509482E+016] ""  PC
 SG_ State_Balance_Status_1_01 : 59|4@1+ (1,0) [0|15] ""  PC
 SG_ State_Balance_Fault_1_01 : 63|1@1+ (1,0) [0|1] ""  PC

BO_ 2401300034 S2P_Detail_Bcell_104S_CSC_1__02: 8 SBMU
 SG_ CSC_B_No_104s_1_02 : 0|5@1+ (1,0) [0|31] ""  PC
 SG_ BalDchg_PosCell_1_02 : 5|54@1+ (1,0) [0|1.8014398509482E+016] ""  PC
 SG_ State_Balance_Status_1_02 : 59|4@1+ (1,0) [0|15] ""  PC
 SG_ State_Balance_Fault_1_02 : 63|1@1+ (1,0) [0|1] ""  PC

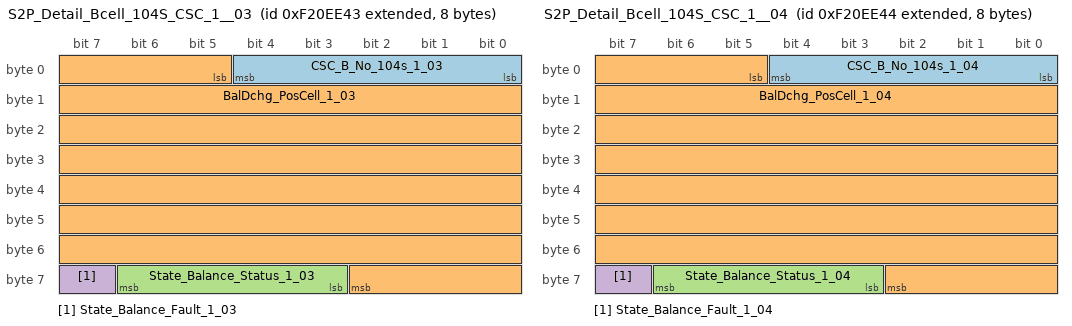
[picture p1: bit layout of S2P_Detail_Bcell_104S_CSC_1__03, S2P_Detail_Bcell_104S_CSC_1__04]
BO_ 2401300035 S2P_Detail_Bcell_104S_CSC_1__03: 8 SBMU
 SG_ CSC_B_No_104s_1_03 : 0|5@1+ (1,0) [0|31] ""  PC
 SG_ BalDchg_PosCell_1_03 : 5|54@1+ (1,0) [0|1.8014398509482E+016] ""  PC
 SG_ State_Balance_Status_1_03 : 59|4@1+ (1,0) [0|15] ""  PC
 SG_ State_Balance_Fault_1_03 : 63|1@1+ (1,0) [0|1] ""  PC

BO_ 2401300036 S2P_Detail_Bcell_104S_CSC_1__04: 8 SBMU
 SG_ CSC_B_No_104s_1_04 : 0|5@1+ (1,0) [0|31] ""  PC
 SG_ BalDchg_PosCell_1_04 : 5|54@1+ (1,0) [0|1.8014398509482E+016] ""  PC
 SG_ State_Balance_Status_1_04 : 59|4@1+ (1,0) [0|15] ""  PC
 SG_ State_Balance_Fault_1_04 : 63|1@1+ (1,0) [0|1] ""  PC

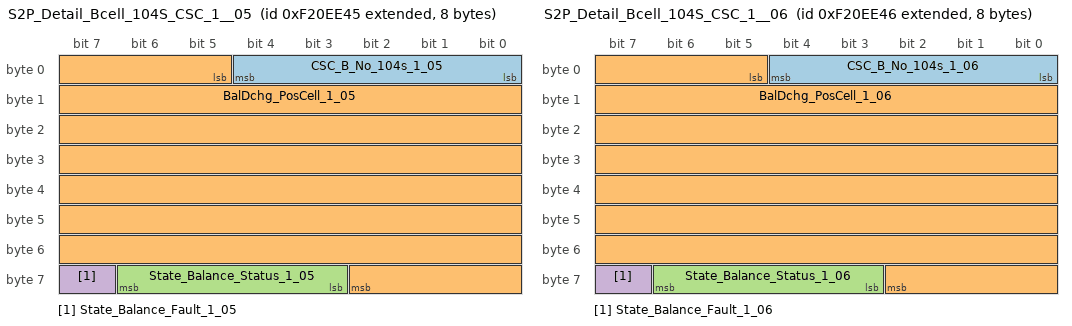
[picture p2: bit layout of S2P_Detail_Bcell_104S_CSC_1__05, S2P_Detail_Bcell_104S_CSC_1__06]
BO_ 2401300037 S2P_Detail_Bcell_104S_CSC_1__05: 8 SBMU
 SG_ CSC_B_No_104s_1_05 : 0|5@1+ (1,0) [0|31] ""  PC
 SG_ BalDchg_PosCell_1_05 : 5|54@1+ (1,0) [0|1.8014398509482E+016] ""  PC
 SG_ State_Balance_Status_1_05 : 59|4@1+ (1,0) [0|15] ""  PC
 SG_ State_Balance_Fault_1_05 : 63|1@1+ (1,0) [0|1] ""  PC

BO_ 2401300038 S2P_Detail_Bcell_104S_CSC_1__06: 8 SBMU
 SG_ CSC_B_No_104s_1_06 : 0|5@1+ (1,0) [0|31] ""  PC
 SG_ BalDchg_PosCell_1_06 : 5|54@1+ (1,0) [0|1.8014398509482E+016] ""  PC
 SG_ State_Balance_Status_1_06 : 59|4@1+ (1,0) [0|15] ""  PC
 SG_ State_Balance_Fault_1_06 : 63|1@1+ (1,0) [0|1] ""  PC

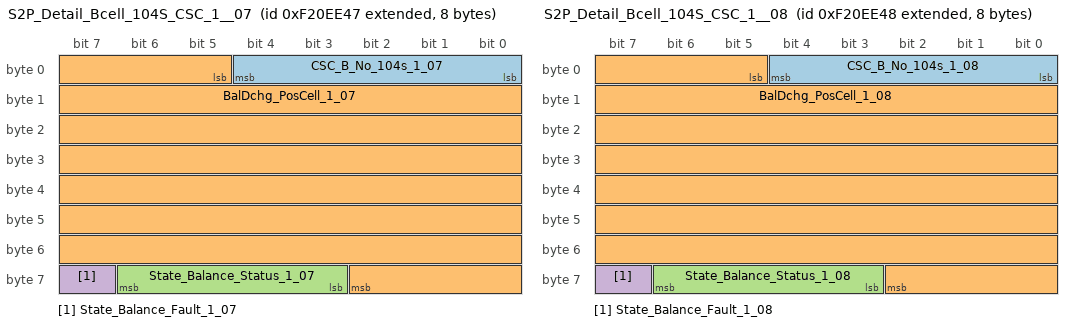
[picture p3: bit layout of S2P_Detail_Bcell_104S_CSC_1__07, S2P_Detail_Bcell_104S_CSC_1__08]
BO_ 2401300039 S2P_Detail_Bcell_104S_CSC_1__07: 8 SBMU
 SG_ CSC_B_No_104s_1_07 : 0|5@1+ (1,0) [0|31] ""  PC
 SG_ BalDchg_PosCell_1_07 : 5|54@1+ (1,0) [0|1.8014398509482E+016] ""  PC
 SG_ State_Balance_Status_1_07 : 59|4@1+ (1,0) [0|15] ""  PC
 SG_ State_Balance_Fault_1_07 : 63|1@1+ (1,0) [0|1] ""  PC

BO_ 2401300040 S2P_Detail_Bcell_104S_CSC_1__08: 8 SBMU
 SG_ CSC_B_No_104s_1_08 : 0|5@1+ (1,0) [0|31] ""  PC
 SG_ BalDchg_PosCell_1_08 : 5|54@1+ (1,0) [0|1.8014398509482E+016] ""  PC
 SG_ State_Balance_Status_1_08 : 59|4@1+ (1,0) [0|15] ""  PC
 SG_ State_Balance_Fault_1_08 : 63|1@1+ (1,0) [0|1] ""  PC

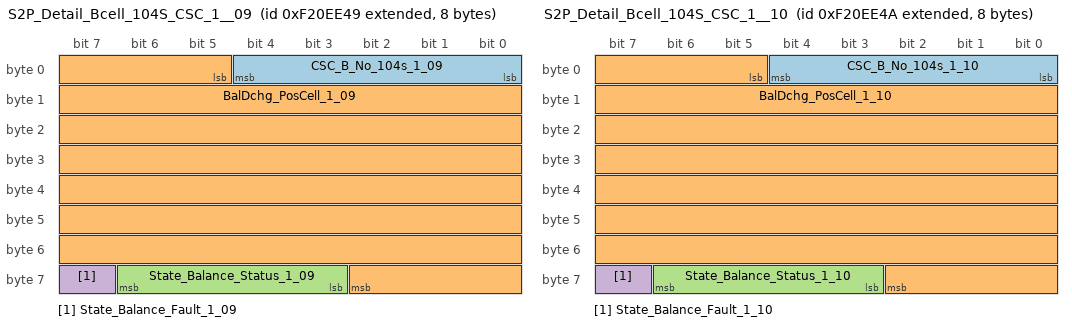
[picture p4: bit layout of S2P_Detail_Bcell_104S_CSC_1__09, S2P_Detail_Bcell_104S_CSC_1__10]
BO_ 2401300041 S2P_Detail_Bcell_104S_CSC_1__09: 8 SBMU
 SG_ CSC_B_No_104s_1_09 : 0|5@1+ (1,0) [0|31] ""  PC
 SG_ BalDchg_PosCell_1_09 : 5|54@1+ (1,0) [0|1.8014398509482E+016] ""  PC
 SG_ State_Balance_Status_1_09 : 59|4@1+ (1,0) [0|15] ""  PC
 SG_ State_Balance_Fault_1_09 : 63|1@1+ (1,0) [0|1] ""  PC

BO_ 2401300042 S2P_Detail_Bcell_104S_CSC_1__10: 8 SBMU
 SG_ CSC_B_No_104s_1_10 : 0|5@1+ (1,0) [0|31] ""  PC
 SG_ BalDchg_PosCell_1_10 : 5|54@1+ (1,0) [0|1.8014398509482E+016] ""  PC
 SG_ State_Balance_Status_1_10 : 59|4@1+ (1,0) [0|15] ""  PC
 SG_ State_Balance_Fault_1_10 : 63|1@1+ (1,0) [0|1] ""  PC

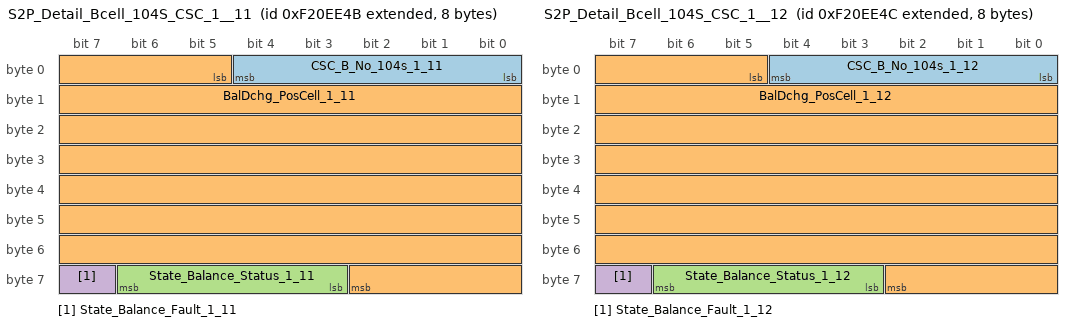
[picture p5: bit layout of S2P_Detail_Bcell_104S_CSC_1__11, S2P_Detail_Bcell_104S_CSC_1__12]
BO_ 2401300043 S2P_Detail_Bcell_104S_CSC_1__11: 8 SBMU
 SG_ CSC_B_No_104s_1_11 : 0|5@1+ (1,0) [0|31] ""  PC
 SG_ BalDchg_PosCell_1_11 : 5|54@1+ (1,0) [0|1.8014398509482E+016] ""  PC
 SG_ State_Balance_Status_1_11 : 59|4@1+ (1,0) [0|15] ""  PC
 SG_ State_Balance_Fault_1_11 : 63|1@1+ (1,0) [0|1] ""  PC

BO_ 2401300044 S2P_Detail_Bcell_104S_CSC_1__12: 8 SBMU
 SG_ CSC_B_No_104s_1_12 : 0|5@1+ (1,0) [0|31] ""  PC
 SG_ BalDchg_PosCell_1_12 : 5|54@1+ (1,0) [0|1.8014398509482E+016] ""  PC
 SG_ State_Balance_Status_1_12 : 59|4@1+ (1,0) [0|15] ""  PC
 SG_ State_Balance_Fault_1_12 : 63|1@1+ (1,0) [0|1] ""  PC

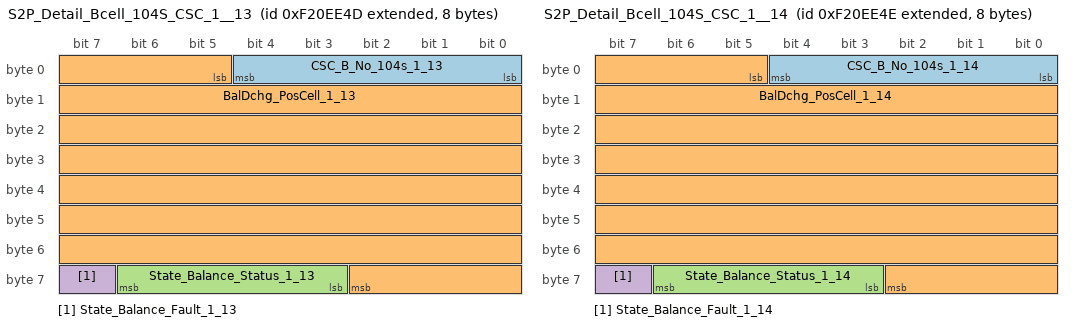
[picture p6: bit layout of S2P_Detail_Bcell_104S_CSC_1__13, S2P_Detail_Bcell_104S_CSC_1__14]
BO_ 2401300045 S2P_Detail_Bcell_104S_CSC_1__13: 8 SBMU
 SG_ CSC_B_No_104s_1_13 : 0|5@1+ (1,0) [0|31] ""  PC
 SG_ BalDchg_PosCell_1_13 : 5|54@1+ (1,0) [0|1.8014398509482E+016] ""  PC
 SG_ State_Balance_Status_1_13 : 59|4@1+ (1,0) [0|15] ""  PC
 SG_ State_Balance_Fault_1_13 : 63|1@1+ (1,0) [0|1] ""  PC

BO_ 2401300046 S2P_Detail_Bcell_104S_CSC_1__14: 8 SBMU
 SG_ CSC_B_No_104s_1_14 : 0|5@1+ (1,0) [0|31] ""  PC
 SG_ BalDchg_PosCell_1_14 : 5|54@1+ (1,0) [0|1.8014398509482E+016] ""  PC
 SG_ State_Balance_Status_1_14 : 59|4@1+ (1,0) [0|15] ""  PC
 SG_ State_Balance_Fault_1_14 : 63|1@1+ (1,0) [0|1] ""  PC

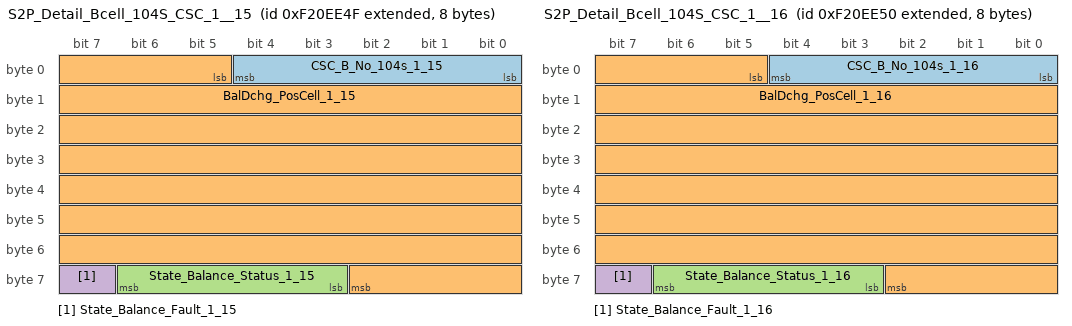
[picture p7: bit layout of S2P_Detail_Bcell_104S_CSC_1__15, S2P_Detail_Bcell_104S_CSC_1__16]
BO_ 2401300047 S2P_Detail_Bcell_104S_CSC_1__15: 8 SBMU
 SG_ CSC_B_No_104s_1_15 : 0|5@1+ (1,0) [0|31] ""  PC
 SG_ BalDchg_PosCell_1_15 : 5|54@1+ (1,0) [0|1.8014398509482E+016] ""  PC
 SG_ State_Balance_Status_1_15 : 59|4@1+ (1,0) [0|15] ""  PC
 SG_ State_Balance_Fault_1_15 : 63|1@1+ (1,0) [0|1] ""  PC

BO_ 2401300048 S2P_Detail_Bcell_104S_CSC_1__16: 8 SBMU
 SG_ CSC_B_No_104s_1_16 : 0|5@1+ (1,0) [0|31] ""  PC
 SG_ BalDchg_PosCell_1_16 : 5|54@1+ (1,0) [0|1.8014398509482E+016] ""  PC
 SG_ State_Balance_Status_1_16 : 59|4@1+ (1,0) [0|15] ""  PC
 SG_ State_Balance_Fault_1_16 : 63|1@1+ (1,0) [0|1] ""  PC

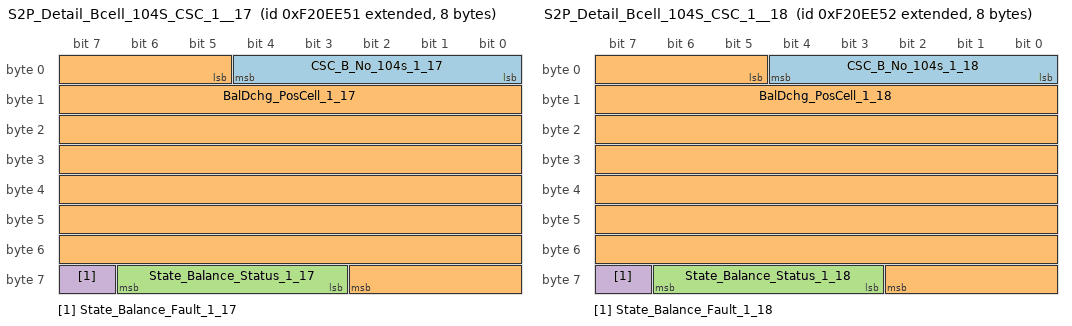
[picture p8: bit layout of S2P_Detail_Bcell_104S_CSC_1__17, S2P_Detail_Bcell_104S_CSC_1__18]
BO_ 2401300049 S2P_Detail_Bcell_104S_CSC_1__17: 8 SBMU
 SG_ CSC_B_No_104s_1_17 : 0|5@1+ (1,0) [0|31] ""  PC
 SG_ BalDchg_PosCell_1_17 : 5|54@1+ (1,0) [0|1.8014398509482E+016] ""  PC
 SG_ State_Balance_Status_1_17 : 59|4@1+ (1,0) [0|15] ""  PC
 SG_ State_Balance_Fault_1_17 : 63|1@1+ (1,0) [0|1] ""  PC

BO_ 2401300050 S2P_Detail_Bcell_104S_CSC_1__18: 8 SBMU
 SG_ CSC_B_No_104s_1_18 : 0|5@1+ (1,0) [0|31] ""  PC
 SG_ BalDchg_PosCell_1_18 : 5|54@1+ (1,0) [0|1.8014398509482E+016] ""  PC
 SG_ State_Balance_Status_1_18 : 59|4@1+ (1,0) [0|15] ""  PC
 SG_ State_Balance_Fault_1_18 : 63|1@1+ (1,0) [0|1] ""  PC

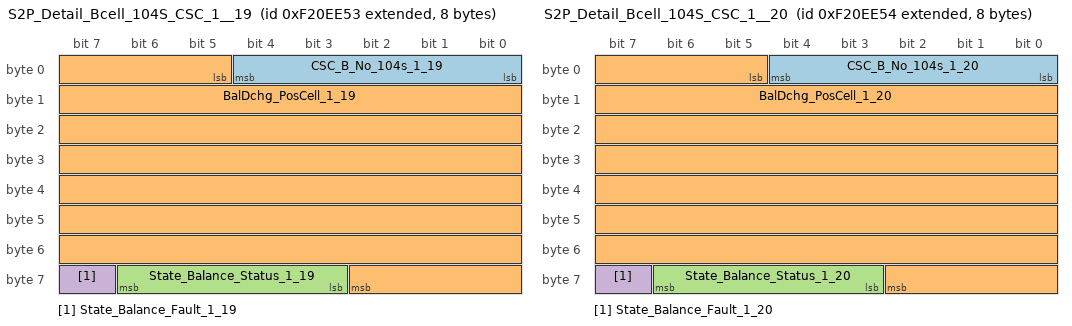
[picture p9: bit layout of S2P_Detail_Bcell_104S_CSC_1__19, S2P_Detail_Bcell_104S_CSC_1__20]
BO_ 2401300051 S2P_Detail_Bcell_104S_CSC_1__19: 8 SBMU
 SG_ CSC_B_No_104s_1_19 : 0|5@1+ (1,0) [0|31] ""  PC
 SG_ BalDchg_PosCell_1_19 : 5|54@1+ (1,0) [0|1.8014398509482E+016] ""  PC
 SG_ State_Balance_Status_1_19 : 59|4@1+ (1,0) [0|15] ""  PC
 SG_ State_Balance_Fault_1_19 : 63|1@1+ (1,0) [0|1] ""  PC

BO_ 2401300052 S2P_Detail_Bcell_104S_CSC_1__20: 8 SBMU
 SG_ CSC_B_No_104s_1_20 : 0|5@1+ (1,0) [0|31] ""  PC
 SG_ BalDchg_PosCell_1_20 : 5|54@1+ (1,0) [0|1.8014398509482E+016] ""  PC
 SG_ State_Balance_Status_1_20 : 59|4@1+ (1,0) [0|15] ""  PC
 SG_ State_Balance_Fault_1_20 : 63|1@1+ (1,0) [0|1] ""  PC

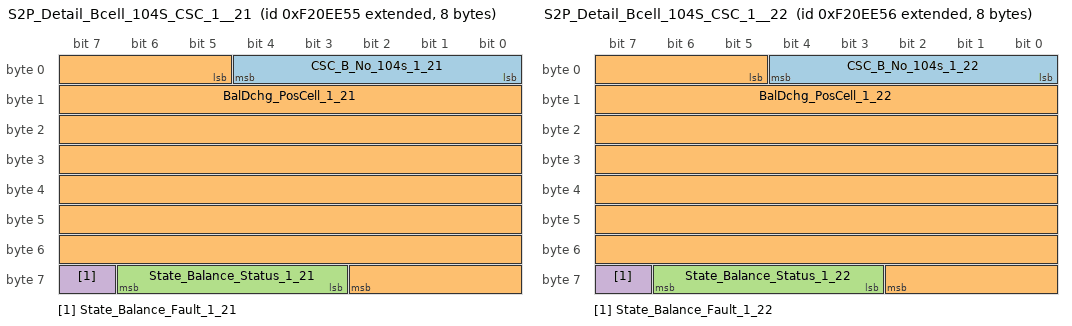
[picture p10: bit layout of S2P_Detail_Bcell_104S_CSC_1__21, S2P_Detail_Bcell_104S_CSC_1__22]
BO_ 2401300053 S2P_Detail_Bcell_104S_CSC_1__21: 8 SBMU
 SG_ CSC_B_No_104s_1_21 : 0|5@1+ (1,0) [0|31] ""  PC
 SG_ BalDchg_PosCell_1_21 : 5|54@1+ (1,0) [0|1.8014398509482E+016] ""  PC
 SG_ State_Balance_Status_1_21 : 59|4@1+ (1,0) [0|15] ""  PC
 SG_ State_Balance_Fault_1_21 : 63|1@1+ (1,0) [0|1] ""  PC

BO_ 2401300054 S2P_Detail_Bcell_104S_CSC_1__22: 8 SBMU
 SG_ CSC_B_No_104s_1_22 : 0|5@1+ (1,0) [0|31] ""  PC
 SG_ BalDchg_PosCell_1_22 : 5|54@1+ (1,0) [0|1.8014398509482E+016] ""  PC
 SG_ State_Balance_Status_1_22 : 59|4@1+ (1,0) [0|15] ""  PC
 SG_ State_Balance_Fault_1_22 : 63|1@1+ (1,0) [0|1] ""  PC

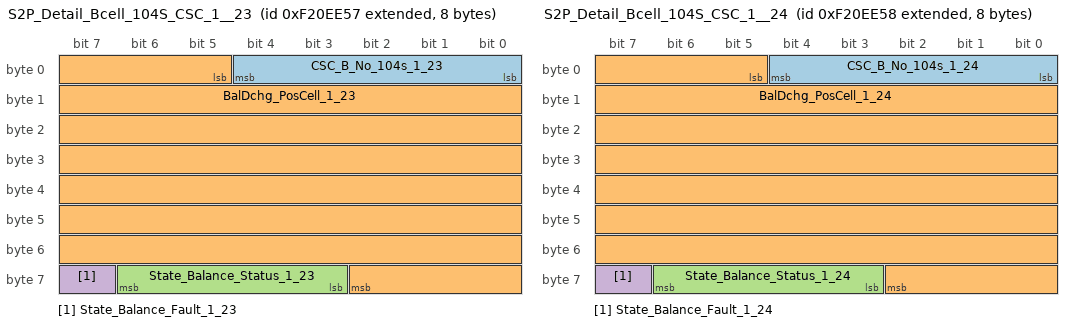
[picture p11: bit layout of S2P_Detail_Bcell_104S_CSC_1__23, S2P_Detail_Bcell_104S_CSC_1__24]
BO_ 2401300055 S2P_Detail_Bcell_104S_CSC_1__23: 8 SBMU
 SG_ CSC_B_No_104s_1_23 : 0|5@1+ (1,0) [0|31] ""  PC
 SG_ BalDchg_PosCell_1_23 : 5|54@1+ (1,0) [0|1.8014398509482E+016] ""  PC
 SG_ State_Balance_Status_1_23 : 59|4@1+ (1,0) [0|15] ""  PC
 SG_ State_Balance_Fault_1_23 : 63|1@1+ (1,0) [0|1] ""  PC

BO_ 2401300056 S2P_Detail_Bcell_104S_CSC_1__24: 8 SBMU
 SG_ CSC_B_No_104s_1_24 : 0|5@1+ (1,0) [0|31] ""  PC
 SG_ BalDchg_PosCell_1_24 : 5|54@1+ (1,0) [0|1.8014398509482E+016] ""  PC
 SG_ State_Balance_Status_1_24 : 59|4@1+ (1,0) [0|15] ""  PC
 SG_ State_Balance_Fault_1_24 : 63|1@1+ (1,0) [0|1] ""  PC

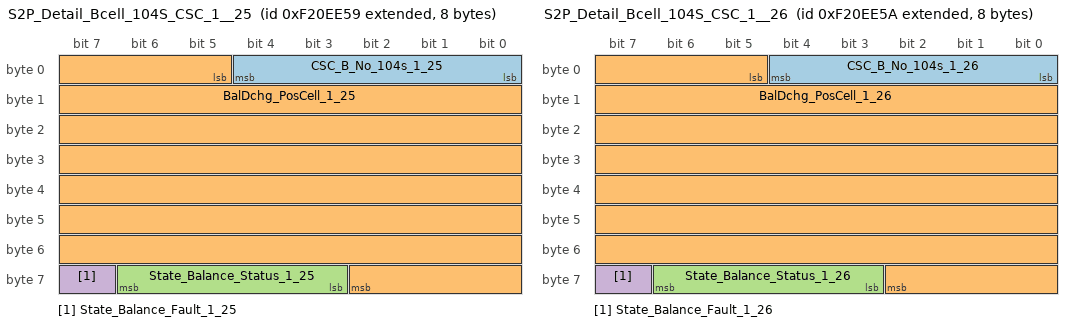
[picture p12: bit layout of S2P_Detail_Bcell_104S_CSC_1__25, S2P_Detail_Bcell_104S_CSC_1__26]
BO_ 2401300057 S2P_Detail_Bcell_104S_CSC_1__25: 8 SBMU
 SG_ CSC_B_No_104s_1_25 : 0|5@1+ (1,0) [0|31] ""  PC
 SG_ BalDchg_PosCell_1_25 : 5|54@1+ (1,0) [0|1.8014398509482E+016] ""  PC
 SG_ State_Balance_Status_1_25 : 59|4@1+ (1,0) [0|15] ""  PC
 SG_ State_Balance_Fault_1_25 : 63|1@1+ (1,0) [0|1] ""  PC

BO_ 2401300058 S2P_Detail_Bcell_104S_CSC_1__26: 8 SBMU
 SG_ CSC_B_No_104s_1_26 : 0|5@1+ (1,0) [0|31] ""  PC
 SG_ BalDchg_PosCell_1_26 : 5|54@1+ (1,0) [0|1.8014398509482E+016] ""  PC
 SG_ State_Balance_Status_1_26 : 59|4@1+ (1,0) [0|15] ""  PC
 SG_ State_Balance_Fault_1_26 : 63|1@1+ (1,0) [0|1] ""  PC

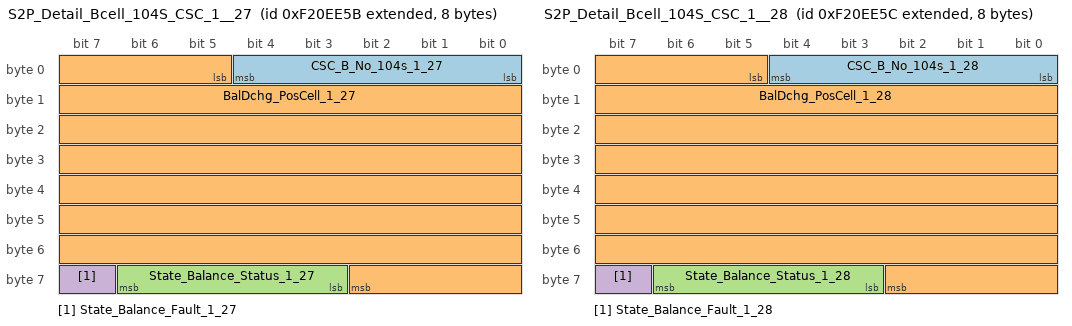
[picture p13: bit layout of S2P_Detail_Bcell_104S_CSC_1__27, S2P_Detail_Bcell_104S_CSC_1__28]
BO_ 2401300059 S2P_Detail_Bcell_104S_CSC_1__27: 8 SBMU
 SG_ CSC_B_No_104s_1_27 : 0|5@1+ (1,0) [0|31] ""  PC
 SG_ BalDchg_PosCell_1_27 : 5|54@1+ (1,0) [0|1.8014398509482E+016] ""  PC
 SG_ State_Balance_Status_1_27 : 59|4@1+ (1,0) [0|15] ""  PC
 SG_ State_Balance_Fault_1_27 : 63|1@1+ (1,0) [0|1] ""  PC

BO_ 2401300060 S2P_Detail_Bcell_104S_CSC_1__28: 8 SBMU
 SG_ CSC_B_No_104s_1_28 : 0|5@1+ (1,0) [0|31] ""  PC
 SG_ BalDchg_PosCell_1_28 : 5|54@1+ (1,0) [0|1.8014398509482E+016] ""  PC
 SG_ State_Balance_Status_1_28 : 59|4@1+ (1,0) [0|15] ""  PC
 SG_ State_Balance_Fault_1_28 : 63|1@1+ (1,0) [0|1] ""  PC

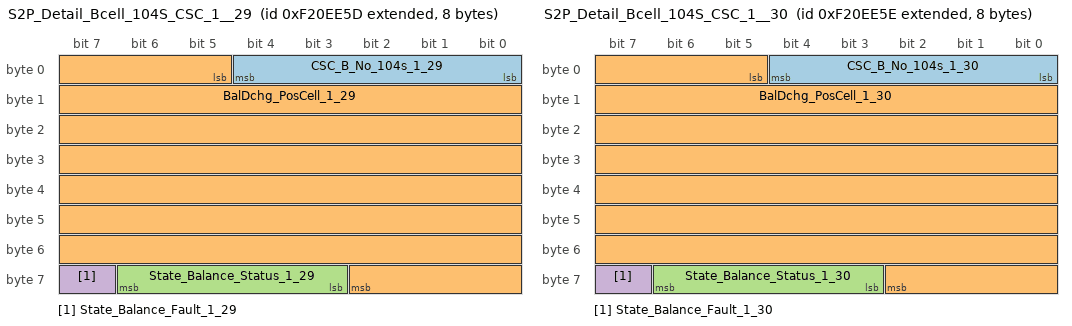
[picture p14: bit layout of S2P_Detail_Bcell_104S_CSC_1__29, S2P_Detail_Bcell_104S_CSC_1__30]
BO_ 2401300061 S2P_Detail_Bcell_104S_CSC_1__29: 8 SBMU
 SG_ CSC_B_No_104s_1_29 : 0|5@1+ (1,0) [0|31] ""  PC
 SG_ BalDchg_PosCell_1_29 : 5|54@1+ (1,0) [0|1.8014398509482E+016] ""  PC
 SG_ State_Balance_Status_1_29 : 59|4@1+ (1,0) [0|15] ""  PC
 SG_ State_Balance_Fault_1_29 : 63|1@1+ (1,0) [0|1] ""  PC

BO_ 2401300062 S2P_Detail_Bcell_104S_CSC_1__30: 8 SBMU
 SG_ CSC_B_No_104s_1_30 : 0|5@1+ (1,0) [0|31] ""  PC
 SG_ BalDchg_PosCell_1_30 : 5|54@1+ (1,0) [0|1.8014398509482E+016] ""  PC
 SG_ State_Balance_Status_1_30 : 59|4@1+ (1,0) [0|15] ""  PC
 SG_ State_Balance_Fault_1_30 : 63|1@1+ (1,0) [0|1] ""  PC

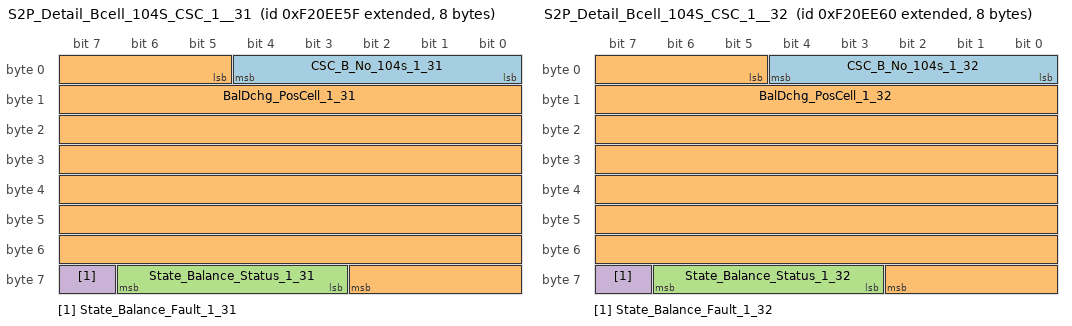
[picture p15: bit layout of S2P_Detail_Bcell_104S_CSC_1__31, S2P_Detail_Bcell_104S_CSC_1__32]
BO_ 2401300063 S2P_Detail_Bcell_104S_CSC_1__31: 8 SBMU
 SG_ CSC_B_No_104s_1_31 : 0|5@1+ (1,0) [0|31] ""  PC
 SG_ BalDchg_PosCell_1_31 : 5|54@1+ (1,0) [0|1.8014398509482E+016] ""  PC
 SG_ State_Balance_Status_1_31 : 59|4@1+ (1,0) [0|15] ""  PC
 SG_ State_Balance_Fault_1_31 : 63|1@1+ (1,0) [0|1] ""  PC

BO_ 2401300064 S2P_Detail_Bcell_104S_CSC_1__32: 8 SBMU
 SG_ CSC_B_No_104s_1_32 : 0|5@1+ (1,0) [0|31] ""  PC
 SG_ BalDchg_PosCell_1_32 : 5|54@1+ (1,0) [0|1.8014398509482E+016] ""  PC
 SG_ State_Balance_Status_1_32 : 59|4@1+ (1,0) [0|15] ""  PC
 SG_ State_Balance_Fault_1_32 : 63|1@1+ (1,0) [0|1] ""  PC

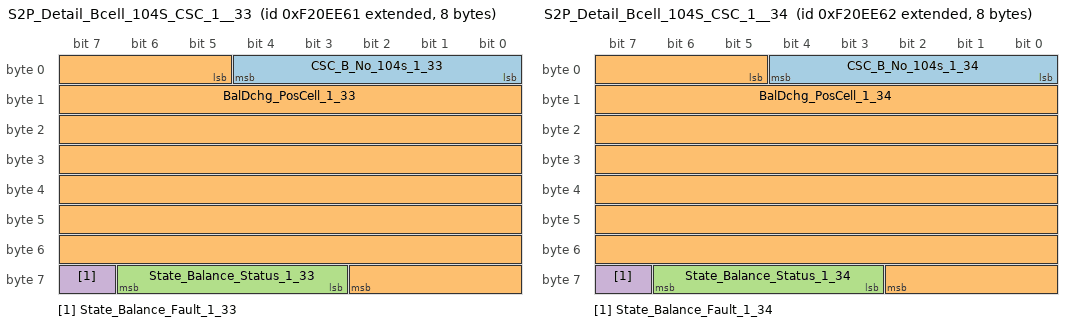
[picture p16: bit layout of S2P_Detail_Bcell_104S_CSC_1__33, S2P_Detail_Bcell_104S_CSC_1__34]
BO_ 2401300065 S2P_Detail_Bcell_104S_CSC_1__33: 8 SBMU
 SG_ CSC_B_No_104s_1_33 : 0|5@1+ (1,0) [0|31] ""  PC
 SG_ BalDchg_PosCell_1_33 : 5|54@1+ (1,0) [0|1.8014398509482E+016] ""  PC
 SG_ State_Balance_Status_1_33 : 59|4@1+ (1,0) [0|15] ""  PC
 SG_ State_Balance_Fault_1_33 : 63|1@1+ (1,0) [0|1] ""  PC

BO_ 2401300066 S2P_Detail_Bcell_104S_CSC_1__34: 8 SBMU
 SG_ CSC_B_No_104s_1_34 : 0|5@1+ (1,0) [0|31] ""  PC
 SG_ BalDchg_PosCell_1_34 : 5|54@1+ (1,0) [0|1.8014398509482E+016] ""  PC
 SG_ State_Balance_Status_1_34 : 59|4@1+ (1,0) [0|15] ""  PC
 SG_ State_Balance_Fault_1_34 : 63|1@1+ (1,0) [0|1] ""  PC

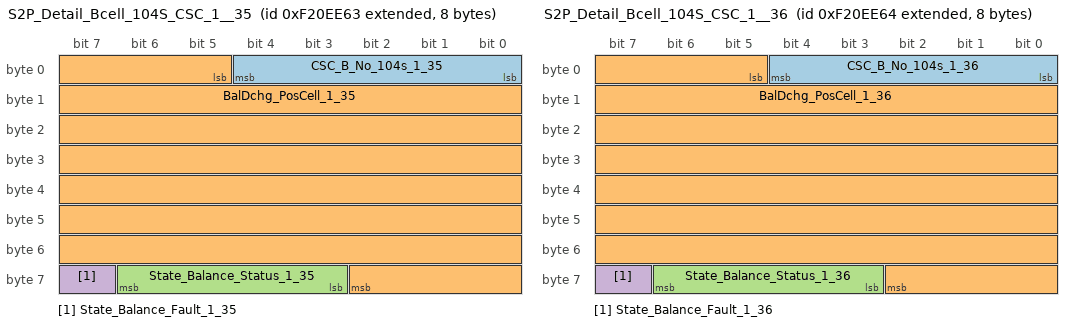
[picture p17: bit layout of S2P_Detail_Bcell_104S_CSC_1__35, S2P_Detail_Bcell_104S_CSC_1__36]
BO_ 2401300067 S2P_Detail_Bcell_104S_CSC_1__35: 8 SBMU
 SG_ CSC_B_No_104s_1_35 : 0|5@1+ (1,0) [0|31] ""  PC
 SG_ BalDchg_PosCell_1_35 : 5|54@1+ (1,0) [0|1.8014398509482E+016] ""  PC
 SG_ State_Balance_Status_1_35 : 59|4@1+ (1,0) [0|15] ""  PC
 SG_ State_Balance_Fault_1_35 : 63|1@1+ (1,0) [0|1] ""  PC

BO_ 2401300068 S2P_Detail_Bcell_104S_CSC_1__36: 8 SBMU
 SG_ CSC_B_No_104s_1_36 : 0|5@1+ (1,0) [0|31] ""  PC
 SG_ BalDchg_PosCell_1_36 : 5|54@1+ (1,0) [0|1.8014398509482E+016] ""  PC
 SG_ State_Balance_Status_1_36 : 59|4@1+ (1,0) [0|15] ""  PC
 SG_ State_Balance_Fault_1_36 : 63|1@1+ (1,0) [0|1] ""  PC

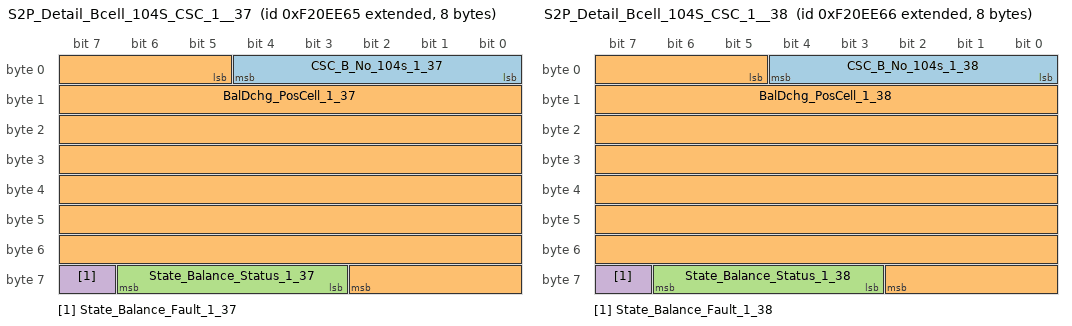
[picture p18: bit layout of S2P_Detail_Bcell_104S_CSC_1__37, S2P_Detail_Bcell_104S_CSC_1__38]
BO_ 2401300069 S2P_Detail_Bcell_104S_CSC_1__37: 8 SBMU
 SG_ CSC_B_No_104s_1_37 : 0|5@1+ (1,0) [0|31] ""  PC
 SG_ BalDchg_PosCell_1_37 : 5|54@1+ (1,0) [0|1.8014398509482E+016] ""  PC
 SG_ State_Balance_Status_1_37 : 59|4@1+ (1,0) [0|15] ""  PC
 SG_ State_Balance_Fault_1_37 : 63|1@1+ (1,0) [0|1] ""  PC

BO_ 2401300070 S2P_Detail_Bcell_104S_CSC_1__38: 8 SBMU
 SG_ CSC_B_No_104s_1_38 : 0|5@1+ (1,0) [0|31] ""  PC
 SG_ BalDchg_PosCell_1_38 : 5|54@1+ (1,0) [0|1.8014398509482E+016] ""  PC
 SG_ State_Balance_Status_1_38 : 59|4@1+ (1,0) [0|15] ""  PC
 SG_ State_Balance_Fault_1_38 : 63|1@1+ (1,0) [0|1] ""  PC

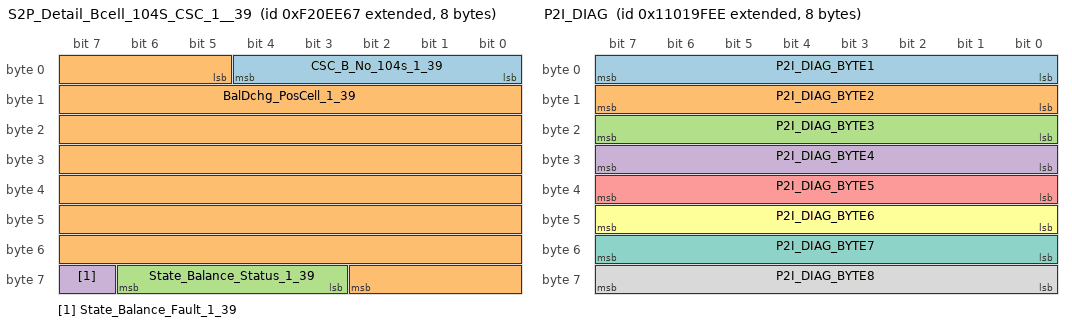
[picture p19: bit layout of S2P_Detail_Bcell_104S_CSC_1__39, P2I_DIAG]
BO_ 2401300071 S2P_Detail_Bcell_104S_CSC_1__39: 8 SBMU
 SG_ CSC_B_No_104s_1_39 : 0|5@1+ (1,0) [0|31] ""  PC
 SG_ BalDchg_PosCell_1_39 : 5|54@1+ (1,0) [0|1.8014398509482E+016] ""  PC
 SG_ State_Balance_Status_1_39 : 59|4@1+ (1,0) [0|15] ""  PC
 SG_ State_Balance_Fault_1_39 : 63|1@1+ (1,0) [0|1] ""  PC

BO_ 2401300072 S2P_Detail_Bcell_104S_CSC_1__40: 8 SBMU
 SG_ CSC_B_No_104s_1_40 : 0|5@1+ (1,0) [0|31] ""  PC
 SG_ BalDchg_PosCell_1_40 : 5|54@1+ (1,0) [0|1.8014398509482E+016] ""  PC
 SG_ State_Balance_Status_1_40 : 59|4@1+ (1,0) [0|15] ""  PC
 SG_ State_Balance_Fault_1_40 : 63|1@1+ (1,0) [0|1] ""  PC

BO_ 2401300073 S2P_Detail_Bcell_104S_CSC_1__41: 8 SBMU
 SG_ CSC_B_No_104s_1_41 : 0|5@1+ (1,0) [0|31] ""  PC
 SG_ BalDchg_PosCell_1_41 : 5|54@1+ (1,0) [0|1.8014398509482E+016] ""  PC
 SG_ State_Balance_Status_1_41 : 59|4@1+ (1,0) [0|15] ""  PC
 SG_ State_Balance_Fault_1_41 : 63|1@1+ (1,0) [0|1] ""  PC

BO_ 2401300074 S2P_Detail_Bcell_104S_CSC_1__42: 8 SBMU
 SG_ CSC_B_No_104s_1_42 : 0|5@1+ (1,0) [0|31] ""  PC
 SG_ BalDchg_PosCell_1_42 : 5|54@1+ (1,0) [0|1.8014398509482E+016] ""  PC
 SG_ State_Balance_Status_1_42 : 59|4@1+ (1,0) [0|15] ""  PC
 SG_ State_Balance_Fault_1_42 : 63|1@1+ (1,0) [0|1] ""  PC

BO_ 2401300075 S2P_Detail_Bcell_104S_CSC_1__43: 8 SBMU
 SG_ CSC_B_No_104s_1_43 : 0|5@1+ (1,0) [0|31] ""  PC
 SG_ BalDchg_PosCell_1_43 : 5|54@1+ (1,0) [0|1.8014398509482E+016] ""  PC
 SG_ State_Balance_Status_1_43 : 59|4@1+ (1,0) [0|15] ""  PC
 SG_ State_Balance_Fault_1_43 : 63|1@1+ (1,0) [0|1] ""  PC

BO_ 2401300076 S2P_Detail_Bcell_104S_CSC_1__44: 8 SBMU
 SG_ CSC_B_No_104s_1_44 : 0|5@1+ (1,0) [0|31] ""  PC
 SG_ BalDchg_PosCell_1_44 : 5|54@1+ (1,0) [0|1.8014398509482E+016] ""  PC
 SG_ State_Balance_Status_1_44 : 59|4@1+ (1,0) [0|15] ""  PC
 SG_ State_Balance_Fault_1_44 : 63|1@1+ (1,0) [0|1] ""  PC

BO_ 2401300077 S2P_Detail_Bcell_104S_CSC_1__45: 8 SBMU
 SG_ CSC_B_No_104s_1_45 : 0|5@1+ (1,0) [0|31] ""  PC
 SG_ BalDchg_PosCell_1_45 : 5|54@1+ (1,0) [0|1.8014398509482E+016] ""  PC
 SG_ State_Balance_Status_1_45 : 59|4@1+ (1,0) [0|15] ""  PC
 SG_ State_Balance_Fault_1_45 : 63|1@1+ (1,0) [0|1] ""  PC

BO_ 2401300078 S2P_Detail_Bcell_104S_CSC_1__46: 8 SBMU
 SG_ CSC_B_No_104s_1_46 : 0|5@1+ (1,0) [0|31] ""  PC
 SG_ BalDchg_PosCell_1_46 : 5|54@1+ (1,0) [0|1.8014398509482E+016] ""  PC
 SG_ State_Balance_Status_1_46 : 59|4@1+ (1,0) [0|15] ""  PC
 SG_ State_Balance_Fault_1_46 : 63|1@1+ (1,0) [0|1] ""  PC

BO_ 2401300079 S2P_Detail_Bcell_104S_CSC_1__47: 8 SBMU
 SG_ CSC_B_No_104s_1_47 : 0|5@1+ (1,0) [0|31] ""  PC
 SG_ BalDchg_PosCell_1_47 : 5|54@1+ (1,0) [0|1.8014398509482E+016] ""  PC
 SG_ State_Balance_Status_1_47 : 59|4@1+ (1,0) [0|15] ""  PC
 SG_ State_Balance_Fault_1_47 : 63|1@1+ (1,0) [0|1] ""  PC

BO_ 2401300080 S2P_Detail_Bcell_104S_CSC_1__48: 8 SBMU
 SG_ CSC_B_No_104s_1_48 : 0|5@1+ (1,0) [0|31] ""  PC
 SG_ BalDchg_PosCell_1_48 : 5|54@1+ (1,0) [0|1.8014398509482E+016] ""  PC
 SG_ State_Balance_Status_1_48 : 59|4@1+ (1,0) [0|15] ""  PC
 SG_ State_Balance_Fault_1_48 : 63|1@1+ (1,0) [0|1] ""  PC

BO_ 2401300081 S2P_Detail_Bcell_104S_CSC_1__49: 8 SBMU
 SG_ CSC_B_No_104s_1_49 : 0|5@1+ (1,0) [0|31] ""  PC
 SG_ BalDchg_PosCell_1_49 : 5|54@1+ (1,0) [0|1.8014398509482E+016] ""  PC
 SG_ State_Balance_Status_1_49 : 59|4@1+ (1,0) [0|15] ""  PC
 SG_ State_Balance_Fault_1_49 : 63|1@1+ (1,0) [0|1] ""  PC

BO_ 2401300082 S2P_Detail_Bcell_104S_CSC_1__50: 8 SBMU
 SG_ CSC_B_No_104s_1_50 : 0|5@1+ (1,0) [0|31] ""  PC
 SG_ BalDchg_PosCell_1_50 : 5|54@1+ (1,0) [0|1.8014398509482E+016] ""  PC
 SG_ State_Balance_Status_1_50 : 59|4@1+ (1,0) [0|15] ""  PC
 SG_ State_Balance_Fault_1_50 : 63|1@1+ (1,0) [0|1] ""  PC

BO_ 2401300083 S2P_Detail_Bcell_104S_CSC_1__51: 8 SBMU
 SG_ CSC_B_No_104s_1_51 : 0|5@1+ (1,0) [0|31] ""  PC
 SG_ BalDchg_PosCell_1_51 : 5|54@1+ (1,0) [0|1.8014398509482E+016] ""  PC
 SG_ State_Balance_Status_1_51 : 59|4@1+ (1,0) [0|15] ""  PC
 SG_ State_Balance_Fault_1_51 : 63|1@1+ (1,0) [0|1] ""  PC

BO_ 2401300084 S2P_Detail_Bcell_104S_CSC_1__52: 8 SBMU
 SG_ CSC_B_No_104s_1_52 : 0|5@1+ (1,0) [0|31] ""  PC
 SG_ BalDchg_PosCell_1_52 : 5|54@1+ (1,0) [0|1.8014398509482E+016] ""  PC
 SG_ State_Balance_Status_1_52 : 59|4@1+ (1,0) [0|15] ""  PC
 SG_ State_Balance_Fault_1_52 : 63|1@1+ (1,0) [0|1] ""  PC

BO_ 2401300085 S2P_Detail_Bcell_104S_CSC_1__53: 8 SBMU
 SG_ CSC_B_No_104s_1_53 : 0|5@1+ (1,0) [0|31] ""  PC
 SG_ BalDchg_PosCell_1_53 : 5|54@1+ (1,0) [0|1.8014398509482E+016] ""  PC
 SG_ State_Balance_Status_1_53 : 59|4@1+ (1,0) [0|15] ""  PC
 SG_ State_Balance_Fault_1_53 : 63|1@1+ (1,0) [0|1] ""  PC

BO_ 2401300086 S2P_Detail_Bcell_104S_CSC_1__54: 8 SBMU
 SG_ CSC_B_No_104s_1_54 : 0|5@1+ (1,0) [0|31] ""  PC
 SG_ BalDchg_PosCell_1_54 : 5|54@1+ (1,0) [0|1.8014398509482E+016] ""  PC
 SG_ State_Balance_Status_1_54 : 59|4@1+ (1,0) [0|15] ""  PC
 SG_ State_Balance_Fault_1_54 : 63|1@1+ (1,0) [0|1] ""  PC

BO_ 2401300087 S2P_Detail_Bcell_104S_CSC_1__55: 8 SBMU
 SG_ CSC_B_No_104s_1_55 : 0|5@1+ (1,0) [0|31] ""  PC
 SG_ BalDchg_PosCell_1_55 : 5|54@1+ (1,0) [0|1.8014398509482E+016] ""  PC
 SG_ State_Balance_Status_1_55 : 59|4@1+ (1,0) [0|15] ""  PC
 SG_ State_Balance_Fault_1_55 : 63|1@1+ (1,0) [0|1] ""  PC

BO_ 2401300088 S2P_Detail_Bcell_104S_CSC_1__56: 8 SBMU
 SG_ CSC_B_No_104s_1_56 : 0|5@1+ (1,0) [0|31] ""  PC
 SG_ BalDchg_PosCell_1_56 : 5|54@1+ (1,0) [0|1.8014398509482E+016] ""  PC
 SG_ State_Balance_Status_1_56 : 59|4@1+ (1,0) [0|15] ""  PC
 SG_ State_Balance_Fault_1_56 : 63|1@1+ (1,0) [0|1] ""  PC

BO_ 2401300089 S2P_Detail_Bcell_104S_CSC_1__57: 8 SBMU
 SG_ CSC_B_No_104s_1_57 : 0|5@1+ (1,0) [0|31] ""  PC
 SG_ BalDchg_PosCell_1_57 : 5|54@1+ (1,0) [0|1.8014398509482E+016] ""  PC
 SG_ State_Balance_Status_1_57 : 59|4@1+ (1,0) [0|15] ""  PC
 SG_ State_Balance_Fault_1_57 : 63|1@1+ (1,0) [0|1] ""  PC

BO_ 2401300090 S2P_Detail_Bcell_104S_CSC_1__58: 8 SBMU
 SG_ CSC_B_No_104s_1_58 : 0|5@1+ (1,0) [0|31] ""  PC
 SG_ BalDchg_PosCell_1_58 : 5|54@1+ (1,0) [0|1.8014398509482E+016] ""  PC
 SG_ State_Balance_Status_1_58 : 59|4@1+ (1,0) [0|15] ""  PC
 SG_ State_Balance_Fault_1_58 : 63|1@1+ (1,0) [0|1] ""  PC

BO_ 2401300091 S2P_Detail_Bcell_104S_CSC_1__59: 8 SBMU
 SG_ CSC_B_No_104s_1_59 : 0|5@1+ (1,0) [0|31] ""  PC
 SG_ BalDchg_PosCell_1_59 : 5|54@1+ (1,0) [0|1.8014398509482E+016] ""  PC
 SG_ State_Balance_Status_1_59 : 59|4@1+ (1,0) [0|15] ""  PC
 SG_ State_Balance_Fault_1_59 : 63|1@1+ (1,0) [0|1] ""  PC

BO_ 2401300092 S2P_Detail_Bcell_104S_CSC_1__60: 8 SBMU
 SG_ CSC_B_No_104s_1_60 : 0|5@1+ (1,0) [0|31] ""  PC
 SG_ BalDchg_PosCell_1_60 : 5|54@1+ (1,0) [0|1.8014398509482E+016] ""  PC
 SG_ State_Balance_Status_1_60 : 59|4@1+ (1,0) [0|15] ""  PC
 SG_ State_Balance_Fault_1_60 : 63|1@1+ (1,0) [0|1] ""  PC

BO_ 2401300093 S2P_Detail_Bcell_104S_CSC_1__61: 8 SBMU
 SG_ CSC_B_No_104s_1_61 : 0|5@1+ (1,0) [0|31] ""  PC
 SG_ BalDchg_PosCell_1_61 : 5|54@1+ (1,0) [0|1.8014398509482E+016] ""  PC
 SG_ State_Balance_Status_1_61 : 59|4@1+ (1,0) [0|15] ""  PC
 SG_ State_Balance_Fault_1_61 : 63|1@1+ (1,0) [0|1] ""  PC

BO_ 2401300094 S2P_Detail_Bcell_104S_CSC_1__62: 8 SBMU
 SG_ CSC_B_No_104s_1_62 : 0|5@1+ (1,0) [0|31] ""  PC
 SG_ BalDchg_PosCell_1_62 : 5|54@1+ (1,0) [0|1.8014398509482E+016] ""  PC
 SG_ State_Balance_Status_1_62 : 59|4@1+ (1,0) [0|15] ""  PC
 SG_ State_Balance_Fault_1_62 : 63|1@1+ (1,0) [0|1] ""  PC

BO_ 2401300095 S2P_Detail_Bcell_104S_CSC_1__63: 8 SBMU
 SG_ CSC_B_No_104s_1_63 : 0|5@1+ (1,0) [0|31] ""  PC
 SG_ BalDchg_PosCell_1_63 : 5|54@1+ (1,0) [0|1.8014398509482E+016] ""  PC
 SG_ State_Balance_Status_1_63 : 59|4@1+ (1,0) [0|15] ""  PC
 SG_ State_Balance_Fault_1_63 : 63|1@1+ (1,0) [0|1] ""  PC

BO_ 2401365569 S2P_Detail_Bcell_104S_CSC_2__01: 8 SBMU
 SG_ CSC_B_No_104s_2_01 : 0|5@1+ (1,0) [0|31] ""  PC
 SG_ BalDchg_PosCell_2_01 : 5|54@1+ (1,0) [0|1.8014398509482E+016] ""  PC
 SG_ State_Balance_Status_2_01 : 59|4@1+ (1,0) [0|15] ""  PC
 SG_ State_Balance_Fault_2_01 : 63|1@1+ (1,0) [0|1] ""  PC

BO_ 2401365570 S2P_Detail_Bcell_104S_CSC_2__02: 8 SBMU
 SG_ CSC_B_No_104s_2_02 : 0|5@1+ (1,0) [0|31] ""  PC
 SG_ BalDchg_PosCell_2_02 : 5|54@1+ (1,0) [0|1.8014398509482E+016] ""  PC
 SG_ State_Balance_Status_2_02 : 59|4@1+ (1,0) [0|15] ""  PC
 SG_ State_Balance_Fault_2_02 : 63|1@1+ (1,0) [0|1] ""  PC

BO_ 2401365571 S2P_Detail_Bcell_104S_CSC_2__03: 8 SBMU
 SG_ CSC_B_No_104s_2_03 : 0|5@1+ (1,0) [0|31] ""  PC
 SG_ BalDchg_PosCell_2_03 : 5|54@1+ (1,0) [0|1.8014398509482E+016] ""  PC
 SG_ State_Balance_Status_2_03 : 59|4@1+ (1,0) [0|15] ""  PC
 SG_ State_Balance_Fault_2_03 : 63|1@1+ (1,0) [0|1] ""  PC

BO_ 2401365572 S2P_Detail_Bcell_104S_CSC_2__04: 8 SBMU
 SG_ CSC_B_No_104s_2_04 : 0|5@1+ (1,0) [0|31] ""  PC
 SG_ BalDchg_PosCell_2_04 : 5|54@1+ (1,0) [0|1.8014398509482E+016] ""  PC
 SG_ State_Balance_Status_2_04 : 59|4@1+ (1,0) [0|15] ""  PC
 SG_ State_Balance_Fault_2_04 : 63|1@1+ (1,0) [0|1] ""  PC

BO_ 2401365573 S2P_Detail_Bcell_104S_CSC_2__05: 8 SBMU
 SG_ CSC_B_No_104s_2_05 : 0|5@1+ (1,0) [0|31] ""  PC
 SG_ BalDchg_PosCell_2_05 : 5|54@1+ (1,0) [0|1.8014398509482E+016] ""  PC
 SG_ State_Balance_Status_2_05 : 59|4@1+ (1,0) [0|15] ""  PC
 SG_ State_Balance_Fault_2_05 : 63|1@1+ (1,0) [0|1] ""  PC

BO_ 2401365574 S2P_Detail_Bcell_104S_CSC_2__06: 8 SBMU
 SG_ CSC_B_No_104s_2_06 : 0|5@1+ (1,0) [0|31] ""  PC
 SG_ BalDchg_PosCell_2_06 : 5|54@1+ (1,0) [0|1.8014398509482E+016] ""  PC
 SG_ State_Balance_Status_2_06 : 59|4@1+ (1,0) [0|15] ""  PC
 SG_ State_Balance_Fault_2_06 : 63|1@1+ (1,0) [0|1] ""  PC

BO_ 2401365575 S2P_Detail_Bcell_104S_CSC_2__07: 8 SBMU
 SG_ CSC_B_No_104s_2_07 : 0|5@1+ (1,0) [0|31] ""  PC
 SG_ BalDchg_PosCell_2_07 : 5|54@1+ (1,0) [0|1.8014398509482E+016] ""  PC
 SG_ State_Balance_Status_2_07 : 59|4@1+ (1,0) [0|15] ""  PC
 SG_ State_Balance_Fault_2_07 : 63|1@1+ (1,0) [0|1] ""  PC

BO_ 2401365576 S2P_Detail_Bcell_104S_CSC_2__08: 8 SBMU
 SG_ CSC_B_No_104s_2_08 : 0|5@1+ (1,0) [0|31] ""  PC
 SG_ BalDchg_PosCell_2_08 : 5|54@1+ (1,0) [0|1.8014398509482E+016] ""  PC
 SG_ State_Balance_Status_2_08 : 59|4@1+ (1,0) [0|15] ""  PC
 SG_ State_Balance_Fault_2_08 : 63|1@1+ (1,0) [0|1] ""  PC

BO_ 2401365577 S2P_Detail_Bcell_104S_CSC_2__09: 8 SBMU
 SG_ CSC_B_No_104s_2_09 : 0|5@1+ (1,0) [0|31] ""  PC
 SG_ BalDchg_PosCell_2_09 : 5|54@1+ (1,0) [0|1.8014398509482E+016] ""  PC
 SG_ State_Balance_Status_2_09 : 59|4@1+ (1,0) [0|15] ""  PC
 SG_ State_Balance_Fault_2_09 : 63|1@1+ (1,0) [0|1] ""  PC

BO_ 2401365578 S2P_Detail_Bcell_104S_CSC_2__10: 8 SBMU
 SG_ CSC_B_No_104s_2_10 : 0|5@1+ (1,0) [0|31] ""  PC
 SG_ BalDchg_PosCell_2_10 : 5|54@1+ (1,0) [0|1.8014398509482E+016] ""  PC
 SG_ State_Balance_Status_2_10 : 59|4@1+ (1,0) [0|15] ""  PC
 SG_ State_Balance_Fault_2_10 : 63|1@1+ (1,0) [0|1] ""  PC

BO_ 2401365579 S2P_Detail_Bcell_104S_CSC_2__11: 8 SBMU
 SG_ CSC_B_No_104s_2_11 : 0|5@1+ (1,0) [0|31] ""  PC
 SG_ BalDchg_PosCell_2_11 : 5|54@1+ (1,0) [0|1.8014398509482E+016] ""  PC
 SG_ State_Balance_Status_2_11 : 59|4@1+ (1,0) [0|15] ""  PC
 SG_ State_Balance_Fault_2_11 : 63|1@1+ (1,0) [0|1] ""  PC

BO_ 2401365580 S2P_Detail_Bcell_104S_CSC_2__12: 8 SBMU
 SG_ CSC_B_No_104s_2_12 : 0|5@1+ (1,0) [0|31] ""  PC
 SG_ BalDchg_PosCell_2_12 : 5|54@1+ (1,0) [0|1.8014398509482E+016] ""  PC
 SG_ State_Balance_Status_2_12 : 59|4@1+ (1,0) [0|15] ""  PC
 SG_ State_Balance_Fault_2_12 : 63|1@1+ (1,0) [0|1] ""  PC

BO_ 2401365581 S2P_Detail_Bcell_104S_CSC_2__13: 8 SBMU
 SG_ CSC_B_No_104s_2_13 : 0|5@1+ (1,0) [0|31] ""  PC
 SG_ BalDchg_PosCell_2_13 : 5|54@1+ (1,0) [0|1.8014398509482E+016] ""  PC
 SG_ State_Balance_Status_2_13 : 59|4@1+ (1,0) [0|15] ""  PC
 SG_ State_Balance_Fault_2_13 : 63|1@1+ (1,0) [0|1] ""  PC

BO_ 2401365582 S2P_Detail_Bcell_104S_CSC_2__14: 8 SBMU
 SG_ CSC_B_No_104s_2_14 : 0|5@1+ (1,0) [0|31] ""  PC
 SG_ BalDchg_PosCell_2_14 : 5|54@1+ (1,0) [0|1.8014398509482E+016] ""  PC
 SG_ State_Balance_Status_2_14 : 59|4@1+ (1,0) [0|15] ""  PC
 SG_ State_Balance_Fault_2_14 : 63|1@1+ (1,0) [0|1] ""  PC

BO_ 2401365583 S2P_Detail_Bcell_104S_CSC_2__15: 8 SBMU
 SG_ CSC_B_No_104s_2_15 : 0|5@1+ (1,0) [0|31] ""  PC
 SG_ BalDchg_PosCell_2_15 : 5|54@1+ (1,0) [0|1.8014398509482E+016] ""  PC
 SG_ State_Balance_Status_2_15 : 59|4@1+ (1,0) [0|15] ""  PC
 SG_ State_Balance_Fault_2_15 : 63|1@1+ (1,0) [0|1] ""  PC

BO_ 2401365584 S2P_Detail_Bcell_104S_CSC_2__16: 8 SBMU
 SG_ CSC_B_No_104s_2_16 : 0|5@1+ (1,0) [0|31] ""  PC
 SG_ BalDchg_PosCell_2_16 : 5|54@1+ (1,0) [0|1.8014398509482E+016] ""  PC
 SG_ State_Balance_Status_2_16 : 59|4@1+ (1,0) [0|15] ""  PC
 SG_ State_Balance_Fault_2_16 : 63|1@1+ (1,0) [0|1] ""  PC

BO_ 2401365585 S2P_Detail_Bcell_104S_CSC_2__17: 8 SBMU
 SG_ CSC_B_No_104s_2_17 : 0|5@1+ (1,0) [0|31] ""  PC
 SG_ BalDchg_PosCell_2_17 : 5|54@1+ (1,0) [0|1.8014398509482E+016] ""  PC
 SG_ State_Balance_Status_2_17 : 59|4@1+ (1,0) [0|15] ""  PC
 SG_ State_Balance_Fault_2_17 : 63|1@1+ (1,0) [0|1] ""  PC

BO_ 2401365586 S2P_Detail_Bcell_104S_CSC_2__18: 8 SBMU
 SG_ CSC_B_No_104s_2_18 : 0|5@1+ (1,0) [0|31] ""  PC
 SG_ BalDchg_PosCell_2_18 : 5|54@1+ (1,0) [0|1.8014398509482E+016] ""  PC
 SG_ State_Balance_Status_2_18 : 59|4@1+ (1,0) [0|15] ""  PC
 SG_ State_Balance_Fault_2_18 : 63|1@1+ (1,0) [0|1] ""  PC

BO_ 2401365587 S2P_Detail_Bcell_104S_CSC_2__19: 8 SBMU
 SG_ CSC_B_No_104s_2_19 : 0|5@1+ (1,0) [0|31] ""  PC
 SG_ BalDchg_PosCell_2_19 : 5|54@1+ (1,0) [0|1.8014398509482E+016] ""  PC
 SG_ State_Balance_Status_2_19 : 59|4@1+ (1,0) [0|15] ""  PC
 SG_ State_Balance_Fault_2_19 : 63|1@1+ (1,0) [0|1] ""  PC

BO_ 2401365588 S2P_Detail_Bcell_104S_CSC_2__20: 8 SBMU
 SG_ CSC_B_No_104s_2_20 : 0|5@1+ (1,0) [0|31] ""  PC
 SG_ BalDchg_PosCell_2_20 : 5|54@1+ (1,0) [0|1.8014398509482E+016] ""  PC
 SG_ State_Balance_Status_2_20 : 59|4@1+ (1,0) [0|15] ""  PC
 SG_ State_Balance_Fault_2_20 : 63|1@1+ (1,0) [0|1] ""  PC

BO_ 2401365589 S2P_Detail_Bcell_104S_CSC_2__21: 8 SBMU
 SG_ CSC_B_No_104s_2_21 : 0|5@1+ (1,0) [0|31] ""  PC
 SG_ BalDchg_PosCell_2_21 : 5|54@1+ (1,0) [0|1.8014398509482E+016] ""  PC
 SG_ State_Balance_Status_2_21 : 59|4@1+ (1,0) [0|15] ""  PC
 SG_ State_Balance_Fault_2_21 : 63|1@1+ (1,0) [0|1] ""  PC

BO_ 2401365590 S2P_Detail_Bcell_104S_CSC_2__22: 8 SBMU
 SG_ CSC_B_No_104s_2_22 : 0|5@1+ (1,0) [0|31] ""  PC
 SG_ BalDchg_PosCell_2_22 : 5|54@1+ (1,0) [0|1.8014398509482E+016] ""  PC
 SG_ State_Balance_Status_2_22 : 59|4@1+ (1,0) [0|15] ""  PC
 SG_ State_Balance_Fault_2_22 : 63|1@1+ (1,0) [0|1] ""  PC

BO_ 2401365591 S2P_Detail_Bcell_104S_CSC_2__23: 8 SBMU
 SG_ CSC_B_No_104s_2_23 : 0|5@1+ (1,0) [0|31] ""  PC
 SG_ BalDchg_PosCell_2_23 : 5|54@1+ (1,0) [0|1.8014398509482E+016] ""  PC
 SG_ State_Balance_Status_2_23 : 59|4@1+ (1,0) [0|15] ""  PC
 SG_ State_Balance_Fault_2_23 : 63|1@1+ (1,0) [0|1] ""  PC

BO_ 2401365592 S2P_Detail_Bcell_104S_CSC_2__24: 8 SBMU
 SG_ CSC_B_No_104s_2_24 : 0|5@1+ (1,0) [0|31] ""  PC
 SG_ BalDchg_PosCell_2_24 : 5|54@1+ (1,0) [0|1.8014398509482E+016] ""  PC
 SG_ State_Balance_Status_2_24 : 59|4@1+ (1,0) [0|15] ""  PC
 SG_ State_Balance_Fault_2_24 : 63|1@1+ (1,0) [0|1] ""  PC

BO_ 2401365593 S2P_Detail_Bcell_104S_CSC_2__25: 8 SBMU
 SG_ CSC_B_No_104s_2_25 : 0|5@1+ (1,0) [0|31] ""  PC
 SG_ BalDchg_PosCell_2_25 : 5|54@1+ (1,0) [0|1.8014398509482E+016] ""  PC
 SG_ State_Balance_Status_2_25 : 59|4@1+ (1,0) [0|15] ""  PC
 SG_ State_Balance_Fault_2_25 : 63|1@1+ (1,0) [0|1] ""  PC

BO_ 2401365594 S2P_Detail_Bcell_104S_CSC_2__26: 8 SBMU
 SG_ CSC_B_No_104s_2_26 : 0|5@1+ (1,0) [0|31] ""  PC
 SG_ BalDchg_PosCell_2_26 : 5|54@1+ (1,0) [0|1.8014398509482E+016] ""  PC
 SG_ State_Balance_Status_2_26 : 59|4@1+ (1,0) [0|15] ""  PC
 SG_ State_Balance_Fault_2_26 : 63|1@1+ (1,0) [0|1] ""  PC

BO_ 2401365595 S2P_Detail_Bcell_104S_CSC_2__27: 8 SBMU
 SG_ CSC_B_No_104s_2_27 : 0|5@1+ (1,0) [0|31] ""  PC
 SG_ BalDchg_PosCell_2_27 : 5|54@1+ (1,0) [0|1.8014398509482E+016] ""  PC
 SG_ State_Balance_Status_2_27 : 59|4@1+ (1,0) [0|15] ""  PC
 SG_ State_Balance_Fault_2_27 : 63|1@1+ (1,0) [0|1] ""  PC

BO_ 2401365596 S2P_Detail_Bcell_104S_CSC_2__28: 8 SBMU
 SG_ CSC_B_No_104s_2_28 : 0|5@1+ (1,0) [0|31] ""  PC
 SG_ BalDchg_PosCell_2_28 : 5|54@1+ (1,0) [0|1.8014398509482E+016] ""  PC
 SG_ State_Balance_Status_2_28 : 59|4@1+ (1,0) [0|15] ""  PC
 SG_ State_Balance_Fault_2_28 : 63|1@1+ (1,0) [0|1] ""  PC

BO_ 2401365597 S2P_Detail_Bcell_104S_CSC_2__29: 8 SBMU
 SG_ CSC_B_No_104s_2_29 : 0|5@1+ (1,0) [0|31] ""  PC
 SG_ BalDchg_PosCell_2_29 : 5|54@1+ (1,0) [0|1.8014398509482E+016] ""  PC
 SG_ State_Balance_Status_2_29 : 59|4@1+ (1,0) [0|15] ""  PC
 SG_ State_Balance_Fault_2_29 : 63|1@1+ (1,0) [0|1] ""  PC

BO_ 2401365598 S2P_Detail_Bcell_104S_CSC_2__30: 8 SBMU
 SG_ CSC_B_No_104s_2_30 : 0|5@1+ (1,0) [0|31] ""  PC
 SG_ BalDchg_PosCell_2_30 : 5|54@1+ (1,0) [0|1.8014398509482E+016] ""  PC
 SG_ State_Balance_Status_2_30 : 59|4@1+ (1,0) [0|15] ""  PC
 SG_ State_Balance_Fault_2_30 : 63|1@1+ (1,0) [0|1] ""  PC

BO_ 2401365599 S2P_Detail_Bcell_104S_CSC_2__31: 8 SBMU
 SG_ CSC_B_No_104s_2_31 : 0|5@1+ (1,0) [0|31] ""  PC
 SG_ BalDchg_PosCell_2_31 : 5|54@1+ (1,0) [0|1.8014398509482E+016] ""  PC
 SG_ State_Balance_Status_2_31 : 59|4@1+ (1,0) [0|15] ""  PC
 SG_ State_Balance_Fault_2_31 : 63|1@1+ (1,0) [0|1] ""  PC

BO_ 2401365600 S2P_Detail_Bcell_104S_CSC_2__32: 8 SBMU
 SG_ CSC_B_No_104s_2_32 : 0|5@1+ (1,0) [0|31] ""  PC
 SG_ BalDchg_PosCell_2_32 : 5|54@1+ (1,0) [0|1.8014398509482E+016] ""  PC
 SG_ State_Balance_Status_2_32 : 59|4@1+ (1,0) [0|15] ""  PC
 SG_ State_Balance_Fault_2_32 : 63|1@1+ (1,0) [0|1] ""  PC

BO_ 2401365601 S2P_Detail_Bcell_104S_CSC_2__33: 8 SBMU
 SG_ CSC_B_No_104s_2_33 : 0|5@1+ (1,0) [0|31] ""  PC
 SG_ BalDchg_PosCell_2_33 : 5|54@1+ (1,0) [0|1.8014398509482E+016] ""  PC
 SG_ State_Balance_Status_2_33 : 59|4@1+ (1,0) [0|15] ""  PC
 SG_ State_Balance_Fault_2_33 : 63|1@1+ (1,0) [0|1] ""  PC

BO_ 2401365602 S2P_Detail_Bcell_104S_CSC_2__34: 8 SBMU
 SG_ CSC_B_No_104s_2_34 : 0|5@1+ (1,0) [0|31] ""  PC
 SG_ BalDchg_PosCell_2_34 : 5|54@1+ (1,0) [0|1.8014398509482E+016] ""  PC
 SG_ State_Balance_Status_2_34 : 59|4@1+ (1,0) [0|15] ""  PC
 SG_ State_Balance_Fault_2_34 : 63|1@1+ (1,0) [0|1] ""  PC

BO_ 2401365603 S2P_Detail_Bcell_104S_CSC_2__35: 8 SBMU
 SG_ CSC_B_No_104s_2_35 : 0|5@1+ (1,0) [0|31] ""  PC
 SG_ BalDchg_PosCell_2_35 : 5|54@1+ (1,0) [0|1.8014398509482E+016] ""  PC
 SG_ State_Balance_Status_2_35 : 59|4@1+ (1,0) [0|15] ""  PC
 SG_ State_Balance_Fault_2_35 : 63|1@1+ (1,0) [0|1] ""  PC

BO_ 2401365604 S2P_Detail_Bcell_104S_CSC_2__36: 8 SBMU
 SG_ CSC_B_No_104s_2_36 : 0|5@1+ (1,0) [0|31] ""  PC
 SG_ BalDchg_PosCell_2_36 : 5|54@1+ (1,0) [0|1.8014398509482E+016] ""  PC
 SG_ State_Balance_Status_2_36 : 59|4@1+ (1,0) [0|15] ""  PC
 SG_ State_Balance_Fault_2_36 : 63|1@1+ (1,0) [0|1] ""  PC

BO_ 2401365605 S2P_Detail_Bcell_104S_CSC_2__37: 8 SBMU
 SG_ CSC_B_No_104s_2_37 : 0|5@1+ (1,0) [0|31] ""  PC
 SG_ BalDchg_PosCell_2_37 : 5|54@1+ (1,0) [0|1.8014398509482E+016] ""  PC
 SG_ State_Balance_Status_2_37 : 59|4@1+ (1,0) [0|15] ""  PC
 SG_ State_Balance_Fault_2_37 : 63|1@1+ (1,0) [0|1] ""  PC

BO_ 2401365606 S2P_Detail_Bcell_104S_CSC_2__38: 8 SBMU
 SG_ CSC_B_No_104s_2_38 : 0|5@1+ (1,0) [0|31] ""  PC
 SG_ BalDchg_PosCell_2_38 : 5|54@1+ (1,0) [0|1.8014398509482E+016] ""  PC
 SG_ State_Balance_Status_2_38 : 59|4@1+ (1,0) [0|15] ""  PC
 SG_ State_Balance_Fault_2_38 : 63|1@1+ (1,0) [0|1] ""  PC

BO_ 2401365607 S2P_Detail_Bcell_104S_CSC_2__39: 8 SBMU
 SG_ CSC_B_No_104s_2_39 : 0|5@1+ (1,0) [0|31] ""  PC
 SG_ BalDchg_PosCell_2_39 : 5|54@1+ (1,0) [0|1.8014398509482E+016] ""  PC
 SG_ State_Balance_Status_2_39 : 59|4@1+ (1,0) [0|15] ""  PC
 SG_ State_Balance_Fault_2_39 : 63|1@1+ (1,0) [0|1] ""  PC

BO_ 2401365608 S2P_Detail_Bcell_104S_CSC_2__40: 8 SBMU
 SG_ CSC_B_No_104s_2_40 : 0|5@1+ (1,0) [0|31] ""  PC
 SG_ BalDchg_PosCell_2_40 : 5|54@1+ (1,0) [0|1.8014398509482E+016] ""  PC
 SG_ State_Balance_Status_2_40 : 59|4@1+ (1,0) [0|15] ""  PC
 SG_ State_Balance_Fault_2_40 : 63|1@1+ (1,0) [0|1] ""  PC

BO_ 2401365609 S2P_Detail_Bcell_104S_CSC_2__41: 8 SBMU
 SG_ CSC_B_No_104s_2_41 : 0|5@1+ (1,0) [0|31] ""  PC
 SG_ BalDchg_PosCell_2_41 : 5|54@1+ (1,0) [0|1.8014398509482E+016] ""  PC
 SG_ State_Balance_Status_2_41 : 59|4@1+ (1,0) [0|15] ""  PC
 SG_ State_Balance_Fault_2_41 : 63|1@1+ (1,0) [0|1] ""  PC

BO_ 2401365610 S2P_Detail_Bcell_104S_CSC_2__42: 8 SBMU
 SG_ CSC_B_No_104s_2_42 : 0|5@1+ (1,0) [0|31] ""  PC
 SG_ BalDchg_PosCell_2_42 : 5|54@1+ (1,0) [0|1.8014398509482E+016] ""  PC
 SG_ State_Balance_Status_2_42 : 59|4@1+ (1,0) [0|15] ""  PC
 SG_ State_Balance_Fault_2_42 : 63|1@1+ (1,0) [0|1] ""  PC

BO_ 2401365611 S2P_Detail_Bcell_104S_CSC_2__43: 8 SBMU
 SG_ CSC_B_No_104s_2_43 : 0|5@1+ (1,0) [0|31] ""  PC
 SG_ BalDchg_PosCell_2_43 : 5|54@1+ (1,0) [0|1.8014398509482E+016] ""  PC
 SG_ State_Balance_Status_2_43 : 59|4@1+ (1,0) [0|15] ""  PC
 SG_ State_Balance_Fault_2_43 : 63|1@1+ (1,0) [0|1] ""  PC

BO_ 2401365612 S2P_Detail_Bcell_104S_CSC_2__44: 8 SBMU
 SG_ CSC_B_No_104s_2_44 : 0|5@1+ (1,0) [0|31] ""  PC
 SG_ BalDchg_PosCell_2_44 : 5|54@1+ (1,0) [0|1.8014398509482E+016] ""  PC
 SG_ State_Balance_Status_2_44 : 59|4@1+ (1,0) [0|15] ""  PC
 SG_ State_Balance_Fault_2_44 : 63|1@1+ (1,0) [0|1] ""  PC

BO_ 2401365613 S2P_Detail_Bcell_104S_CSC_2__45: 8 SBMU
 SG_ CSC_B_No_104s_2_45 : 0|5@1+ (1,0) [0|31] ""  PC
 SG_ BalDchg_PosCell_2_45 : 5|54@1+ (1,0) [0|1.8014398509482E+016] ""  PC
 SG_ State_Balance_Status_2_45 : 59|4@1+ (1,0) [0|15] ""  PC
 SG_ State_Balance_Fault_2_45 : 63|1@1+ (1,0) [0|1] ""  PC

BO_ 2401365614 S2P_Detail_Bcell_104S_CSC_2__46: 8 SBMU
 SG_ CSC_B_No_104s_2_46 : 0|5@1+ (1,0) [0|31] ""  PC
 SG_ BalDchg_PosCell_2_46 : 5|54@1+ (1,0) [0|1.8014398509482E+016] ""  PC
 SG_ State_Balance_Status_2_46 : 59|4@1+ (1,0) [0|15] ""  PC
 SG_ State_Balance_Fault_2_46 : 63|1@1+ (1,0) [0|1] ""  PC

BO_ 2401365615 S2P_Detail_Bcell_104S_CSC_2__47: 8 SBMU
 SG_ CSC_B_No_104s_2_47 : 0|5@1+ (1,0) [0|31] ""  PC
 SG_ BalDchg_PosCell_2_47 : 5|54@1+ (1,0) [0|1.8014398509482E+016] ""  PC
 SG_ State_Balance_Status_2_47 : 59|4@1+ (1,0) [0|15] ""  PC
 SG_ State_Balance_Fault_2_47 : 63|1@1+ (1,0) [0|1] ""  PC

BO_ 2401365616 S2P_Detail_Bcell_104S_CSC_2__48: 8 SBMU
 SG_ CSC_B_No_104s_2_48 : 0|5@1+ (1,0) [0|31] ""  PC
 SG_ BalDchg_PosCell_2_48 : 5|54@1+ (1,0) [0|1.8014398509482E+016] ""  PC
 SG_ State_Balance_Status_2_48 : 59|4@1+ (1,0) [0|15] ""  PC
 SG_ State_Balance_Fault_2_48 : 63|1@1+ (1,0) [0|1] ""  PC

BO_ 2401365617 S2P_Detail_Bcell_104S_CSC_2__49: 8 SBMU
 SG_ CSC_B_No_104s_2_49 : 0|5@1+ (1,0) [0|31] ""  PC
 SG_ BalDchg_PosCell_2_49 : 5|54@1+ (1,0) [0|1.8014398509482E+016] ""  PC
 SG_ State_Balance_Status_2_49 : 59|4@1+ (1,0) [0|15] ""  PC
 SG_ State_Balance_Fault_2_49 : 63|1@1+ (1,0) [0|1] ""  PC

BO_ 2401365618 S2P_Detail_Bcell_104S_CSC_2__50: 8 SBMU
 SG_ CSC_B_No_104s_2_50 : 0|5@1+ (1,0) [0|31] ""  PC
 SG_ BalDchg_PosCell_2_50 : 5|54@1+ (1,0) [0|1.8014398509482E+016] ""  PC
 SG_ State_Balance_Status_2_50 : 59|4@1+ (1,0) [0|15] ""  PC
 SG_ State_Balance_Fault_2_50 : 63|1@1+ (1,0) [0|1] ""  PC

BO_ 2401365619 S2P_Detail_Bcell_104S_CSC_2__51: 8 SBMU
 SG_ CSC_B_No_104s_2_51 : 0|5@1+ (1,0) [0|31] ""  PC
 SG_ BalDchg_PosCell_2_51 : 5|54@1+ (1,0) [0|1.8014398509482E+016] ""  PC
 SG_ State_Balance_Status_2_51 : 59|4@1+ (1,0) [0|15] ""  PC
 SG_ State_Balance_Fault_2_51 : 63|1@1+ (1,0) [0|1] ""  PC

BO_ 2401365620 S2P_Detail_Bcell_104S_CSC_2__52: 8 SBMU
 SG_ CSC_B_No_104s_2_52 : 0|5@1+ (1,0) [0|31] ""  PC
 SG_ BalDchg_PosCell_2_52 : 5|54@1+ (1,0) [0|1.8014398509482E+016] ""  PC
 SG_ State_Balance_Status_2_52 : 59|4@1+ (1,0) [0|15] ""  PC
 SG_ State_Balance_Fault_2_52 : 63|1@1+ (1,0) [0|1] ""  PC

BO_ 2401365621 S2P_Detail_Bcell_104S_CSC_2__53: 8 SBMU
 SG_ CSC_B_No_104s_2_53 : 0|5@1+ (1,0) [0|31] ""  PC
 SG_ BalDchg_PosCell_2_53 : 5|54@1+ (1,0) [0|1.8014398509482E+016] ""  PC
 SG_ State_Balance_Status_2_53 : 59|4@1+ (1,0) [0|15] ""  PC
 SG_ State_Balance_Fault_2_53 : 63|1@1+ (1,0) [0|1] ""  PC

BO_ 2401365622 S2P_Detail_Bcell_104S_CSC_2__54: 8 SBMU
 SG_ CSC_B_No_104s_2_54 : 0|5@1+ (1,0) [0|31] ""  PC
 SG_ BalDchg_PosCell_2_54 : 5|54@1+ (1,0) [0|1.8014398509482E+016] ""  PC
 SG_ State_Balance_Status_2_54 : 59|4@1+ (1,0) [0|15] ""  PC
 SG_ State_Balance_Fault_2_54 : 63|1@1+ (1,0) [0|1] ""  PC

BO_ 2401365623 S2P_Detail_Bcell_104S_CSC_2__55: 8 SBMU
 SG_ CSC_B_No_104s_2_55 : 0|5@1+ (1,0) [0|31] ""  PC
 SG_ BalDchg_PosCell_2_55 : 5|54@1+ (1,0) [0|1.8014398509482E+016] ""  PC
 SG_ State_Balance_Status_2_55 : 59|4@1+ (1,0) [0|15] ""  PC
 SG_ State_Balance_Fault_2_55 : 63|1@1+ (1,0) [0|1] ""  PC

BO_ 2401365624 S2P_Detail_Bcell_104S_CSC_2__56: 8 SBMU
 SG_ CSC_B_No_104s_2_56 : 0|5@1+ (1,0) [0|31] ""  PC
 SG_ BalDchg_PosCell_2_56 : 5|54@1+ (1,0) [0|1.8014398509482E+016] ""  PC
 SG_ State_Balance_Status_2_56 : 59|4@1+ (1,0) [0|15] ""  PC
 SG_ State_Balance_Fault_2_56 : 63|1@1+ (1,0) [0|1] ""  PC

BO_ 2401365625 S2P_Detail_Bcell_104S_CSC_2__57: 8 SBMU
 SG_ CSC_B_No_104s_2_57 : 0|5@1+ (1,0) [0|31] ""  PC
 SG_ BalDchg_PosCell_2_57 : 5|54@1+ (1,0) [0|1.8014398509482E+016] ""  PC
 SG_ State_Balance_Status_2_57 : 59|4@1+ (1,0) [0|15] ""  PC
 SG_ State_Balance_Fault_2_57 : 63|1@1+ (1,0) [0|1] ""  PC

BO_ 2401365626 S2P_Detail_Bcell_104S_CSC_2__58: 8 SBMU
 SG_ CSC_B_No_104s_2_58 : 0|5@1+ (1,0) [0|31] ""  PC
 SG_ BalDchg_PosCell_2_58 : 5|54@1+ (1,0) [0|1.8014398509482E+016] ""  PC
 SG_ State_Balance_Status_2_58 : 59|4@1+ (1,0) [0|15] ""  PC
 SG_ State_Balance_Fault_2_58 : 63|1@1+ (1,0) [0|1] ""  PC

BO_ 2401365627 S2P_Detail_Bcell_104S_CSC_2__59: 8 SBMU
 SG_ CSC_B_No_104s_2_59 : 0|5@1+ (1,0) [0|31] ""  PC
 SG_ BalDchg_PosCell_2_59 : 5|54@1+ (1,0) [0|1.8014398509482E+016] ""  PC
 SG_ State_Balance_Status_2_59 : 59|4@1+ (1,0) [0|15] ""  PC
 SG_ State_Balance_Fault_2_59 : 63|1@1+ (1,0) [0|1] ""  PC

BO_ 2401365628 S2P_Detail_Bcell_104S_CSC_2__60: 8 SBMU
 SG_ CSC_B_No_104s_2_60 : 0|5@1+ (1,0) [0|31] ""  PC
 SG_ BalDchg_PosCell_2_60 : 5|54@1+ (1,0) [0|1.8014398509482E+016] ""  PC
 SG_ State_Balance_Status_2_60 : 59|4@1+ (1,0) [0|15] ""  PC
 SG_ State_Balance_Fault_2_60 : 63|1@1+ (1,0) [0|1] ""  PC

BO_ 2401365629 S2P_Detail_Bcell_104S_CSC_2__61: 8 SBMU
 SG_ CSC_B_No_104s_2_61 : 0|5@1+ (1,0) [0|31] ""  PC
 SG_ BalDchg_PosCell_2_61 : 5|54@1+ (1,0) [0|1.8014398509482E+016] ""  PC
 SG_ State_Balance_Status_2_61 : 59|4@1+ (1,0) [0|15] ""  PC
 SG_ State_Balance_Fault_2_61 : 63|1@1+ (1,0) [0|1] ""  PC

BO_ 2401365630 S2P_Detail_Bcell_104S_CSC_2__62: 8 SBMU
 SG_ CSC_B_No_104s_2_62 : 0|5@1+ (1,0) [0|31] ""  PC
 SG_ BalDchg_PosCell_2_62 : 5|54@1+ (1,0) [0|1.8014398509482E+016] ""  PC
 SG_ State_Balance_Status_2_62 : 59|4@1+ (1,0) [0|15] ""  PC
 SG_ State_Balance_Fault_2_62 : 63|1@1+ (1,0) [0|1] ""  PC

BO_ 2401365631 S2P_Detail_Bcell_104S_CSC_2__63: 8 SBMU
 SG_ CSC_B_No_104s_2_63 : 0|5@1+ (1,0) [0|31] ""  PC
 SG_ BalDchg_PosCell_2_63 : 5|54@1+ (1,0) [0|1.8014398509482E+016] ""  PC
 SG_ State_Balance_Status_2_63 : 59|4@1+ (1,0) [0|15] ""  PC
 SG_ State_Balance_Fault_2_63 : 63|1@1+ (1,0) [0|1] ""  PC

BO_ 2432802798 P2I_DIAG: 8 PC
 SG_ P2I_DIAG_BYTE1 : 0|8@1+ (1,0) [0|255] ""  MBMU
 SG_ P2I_DIAG_BYTE2 : 8|8@1+ (1,0) [0|255] ""  MBMU
 SG_ P2I_DIAG_BYTE3 : 16|8@1+ (1,0) [0|255] ""  MBMU
 SG_ P2I_DIAG_BYTE4 : 24|8@1+ (1,0) [0|255] ""  MBMU
 SG_ P2I_DIAG_BYTE5 : 32|8@1+ (1,0) [0|255] ""  MBMU
 SG_ P2I_DIAG_BYTE6 : 40|8@1+ (1,0) [0|255] ""  MBMU
 SG_ P2I_DIAG_BYTE7 : 48|8@1+ (1,0) [0|255] ""  MBMU
 SG_ P2I_DIAG_BYTE8 : 56|8@1+ (1,0) [0|255] ""  MBMU

BO_ 2418273857 S2P_Lmt18__01: 8 SBMU
 SG_ S2P_Lmt18_Over_Idischarge1_01 : 0|16@1+ (0.01,0) [0|655.35] "A"  PC
 SG_ S2P_Lmt18_Over_Idischarge2_01 : 16|16@1+ (0.01,0) [0|655.35] "A"  PC
 SG_ S2P_Lmt18_Over_Idischarge3_01 : 32|16@1+ (0.01,0) [0|655.35] "A"  PC
 SG_ S2P_Lmt18_Over_Idischarge4_01 : 48|16@1+ (0.01,0) [0|655.35] "A"  PC

BO_ 2418273858 S2P_Lmt18__02: 8 SBMU
 SG_ S2P_Lmt18_Over_Idischarge1_02 : 0|16@1+ (0.01,0) [0|655.35] "A"  PC
 SG_ S2P_Lmt18_Over_Idischarge2_02 : 16|16@1+ (0.01,0) [0|655.35] "A"  PC
 SG_ S2P_Lmt18_Over_Idischarge3_02 : 32|16@1+ (0.01,0) [0|655.35] "A"  PC
 SG_ S2P_Lmt18_Over_Idischarge4_02 : 48|16@1+ (0.01,0) [0|655.35] "A"  PC

BO_ 2418273859 S2P_Lmt18__03: 8 SBMU
 SG_ S2P_Lmt18_Over_Idischarge1_03 : 0|16@1+ (0.01,0) [0|655.35] "A"  PC
 SG_ S2P_Lmt18_Over_Idischarge2_03 : 16|16@1+ (0.01,0) [0|655.35] "A"  PC
 SG_ S2P_Lmt18_Over_Idischarge3_03 : 32|16@1+ (0.01,0) [0|655.35] "A"  PC
 SG_ S2P_Lmt18_Over_Idischarge4_03 : 48|16@1+ (0.01,0) [0|655.35] "A"  PC

BO_ 2418273860 S2P_Lmt18__04: 8 SBMU
 SG_ S2P_Lmt18_Over_Idischarge1_04 : 0|16@1+ (0.01,0) [0|655.35] "A"  PC
 SG_ S2P_Lmt18_Over_Idischarge2_04 : 16|16@1+ (0.01,0) [0|655.35] "A"  PC
 SG_ S2P_Lmt18_Over_Idischarge3_04 : 32|16@1+ (0.01,0) [0|655.35] "A"  PC
 SG_ S2P_Lmt18_Over_Idischarge4_04 : 48|16@1+ (0.01,0) [0|655.35] "A"  PC

BO_ 2418273861 S2P_Lmt18__05: 8 SBMU
 SG_ S2P_Lmt18_Over_Idischarge1_05 : 0|16@1+ (0.01,0) [0|655.35] "A"  PC
 SG_ S2P_Lmt18_Over_Idischarge2_05 : 16|16@1+ (0.01,0) [0|655.35] "A"  PC
 SG_ S2P_Lmt18_Over_Idischarge3_05 : 32|16@1+ (0.01,0) [0|655.35] "A"  PC
 SG_ S2P_Lmt18_Over_Idischarge4_05 : 48|16@1+ (0.01,0) [0|655.35] "A"  PC

BO_ 2418273862 S2P_Lmt18__06: 8 SBMU
 SG_ S2P_Lmt18_Over_Idischarge1_06 : 0|16@1+ (0.01,0) [0|655.35] "A"  PC
 SG_ S2P_Lmt18_Over_Idischarge2_06 : 16|16@1+ (0.01,0) [0|655.35] "A"  PC
 SG_ S2P_Lmt18_Over_Idischarge3_06 : 32|16@1+ (0.01,0) [0|655.35] "A"  PC
 SG_ S2P_Lmt18_Over_Idischarge4_06 : 48|16@1+ (0.01,0) [0|655.35] "A"  PC

BO_ 2418273863 S2P_Lmt18__07: 8 SBMU
 SG_ S2P_Lmt18_Over_Idischarge1_07 : 0|16@1+ (0.01,0) [0|655.35] "A"  PC
 SG_ S2P_Lmt18_Over_Idischarge2_07 : 16|16@1+ (0.01,0) [0|655.35] "A"  PC
 SG_ S2P_Lmt18_Over_Idischarge3_07 : 32|16@1+ (0.01,0) [0|655.35] "A"  PC
 SG_ S2P_Lmt18_Over_Idischarge4_07 : 48|16@1+ (0.01,0) [0|655.35] "A"  PC

BO_ 2418273864 S2P_Lmt18__08: 8 SBMU
 SG_ S2P_Lmt18_Over_Idischarge1_08 : 0|16@1+ (0.01,0) [0|655.35] "A"  PC
 SG_ S2P_Lmt18_Over_Idischarge2_08 : 16|16@1+ (0.01,0) [0|655.35] "A"  PC
 SG_ S2P_Lmt18_Over_Idischarge3_08 : 32|16@1+ (0.01,0) [0|655.35] "A"  PC
 SG_ S2P_Lmt18_Over_Idischarge4_08 : 48|16@1+ (0.01,0) [0|655.35] "A"  PC

BO_ 2418273865 S2P_Lmt18__09: 8 SBMU
 SG_ S2P_Lmt18_Over_Idischarge1_09 : 0|16@1+ (0.01,0) [0|655.35] "A"  PC
 SG_ S2P_Lmt18_Over_Idischarge2_09 : 16|16@1+ (0.01,0) [0|655.35] "A"  PC
 SG_ S2P_Lmt18_Over_Idischarge3_09 : 32|16@1+ (0.01,0) [0|655.35] "A"  PC
 SG_ S2P_Lmt18_Over_Idischarge4_09 : 48|16@1+ (0.01,0) [0|655.35] "A"  PC

BO_ 2418273866 S2P_Lmt18__10: 8 SBMU
 SG_ S2P_Lmt18_Over_Idischarge1_10 : 0|16@1+ (0.01,0) [0|655.35] "A"  PC
 SG_ S2P_Lmt18_Over_Idischarge2_10 : 16|16@1+ (0.01,0) [0|655.35] "A"  PC
 SG_ S2P_Lmt18_Over_Idischarge3_10 : 32|16@1+ (0.01,0) [0|655.35] "A"  PC
 SG_ S2P_Lmt18_Over_Idischarge4_10 : 48|16@1+ (0.01,0) [0|655.35] "A"  PC

BO_ 2418273867 S2P_Lmt18__11: 8 SBMU
 SG_ S2P_Lmt18_Over_Idischarge1_11 : 0|16@1+ (0.01,0) [0|655.35] "A"  PC
 SG_ S2P_Lmt18_Over_Idischarge2_11 : 16|16@1+ (0.01,0) [0|655.35] "A"  PC
 SG_ S2P_Lmt18_Over_Idischarge3_11 : 32|16@1+ (0.01,0) [0|655.35] "A"  PC
 SG_ S2P_Lmt18_Over_Idischarge4_11 : 48|16@1+ (0.01,0) [0|655.35] "A"  PC

BO_ 2418273868 S2P_Lmt18__12: 8 SBMU
 SG_ S2P_Lmt18_Over_Idischarge1_12 : 0|16@1+ (0.01,0) [0|655.35] "A"  PC
 SG_ S2P_Lmt18_Over_Idischarge2_12 : 16|16@1+ (0.01,0) [0|655.35] "A"  PC
 SG_ S2P_Lmt18_Over_Idischarge3_12 : 32|16@1+ (0.01,0) [0|655.35] "A"  PC
 SG_ S2P_Lmt18_Over_Idischarge4_12 : 48|16@1+ (0.01,0) [0|655.35] "A"  PC

BO_ 2418273869 S2P_Lmt18__13: 8 SBMU
 SG_ S2P_Lmt18_Over_Idischarge1_13 : 0|16@1+ (0.01,0) [0|655.35] "A"  PC
 SG_ S2P_Lmt18_Over_Idischarge2_13 : 16|16@1+ (0.01,0) [0|655.35] "A"  PC
 SG_ S2P_Lmt18_Over_Idischarge3_13 : 32|16@1+ (0.01,0) [0|655.35] "A"  PC
 SG_ S2P_Lmt18_Over_Idischarge4_13 : 48|16@1+ (0.01,0) [0|655.35] "A"  PC

BO_ 2418273870 S2P_Lmt18__14: 8 SBMU
 SG_ S2P_Lmt18_Over_Idischarge1_14 : 0|16@1+ (0.01,0) [0|655.35] "A"  PC
 SG_ S2P_Lmt18_Over_Idischarge2_14 : 16|16@1+ (0.01,0) [0|655.35] "A"  PC
 SG_ S2P_Lmt18_Over_Idischarge3_14 : 32|16@1+ (0.01,0) [0|655.35] "A"  PC
 SG_ S2P_Lmt18_Over_Idischarge4_14 : 48|16@1+ (0.01,0) [0|655.35] "A"  PC

BO_ 2418273871 S2P_Lmt18__15: 8 SBMU
 SG_ S2P_Lmt18_Over_Idischarge1_15 : 0|16@1+ (0.01,0) [0|655.35] "A"  PC
 SG_ S2P_Lmt18_Over_Idischarge2_15 : 16|16@1+ (0.01,0) [0|655.35] "A"  PC
 SG_ S2P_Lmt18_Over_Idischarge3_15 : 32|16@1+ (0.01,0) [0|655.35] "A"  PC
 SG_ S2P_Lmt18_Over_Idischarge4_15 : 48|16@1+ (0.01,0) [0|655.35] "A"  PC

BO_ 2418273872 S2P_Lmt18__16: 8 SBMU
 SG_ S2P_Lmt18_Over_Idischarge1_16 : 0|16@1+ (0.01,0) [0|655.35] "A"  PC
 SG_ S2P_Lmt18_Over_Idischarge2_16 : 16|16@1+ (0.01,0) [0|655.35] "A"  PC
 SG_ S2P_Lmt18_Over_Idischarge3_16 : 32|16@1+ (0.01,0) [0|655.35] "A"  PC
 SG_ S2P_Lmt18_Over_Idischarge4_16 : 48|16@1+ (0.01,0) [0|655.35] "A"  PC

BO_ 2418273873 S2P_Lmt18__17: 8 SBMU
 SG_ S2P_Lmt18_Over_Idischarge1_17 : 0|16@1+ (0.01,0) [0|655.35] "A"  PC
 SG_ S2P_Lmt18_Over_Idischarge2_17 : 16|16@1+ (0.01,0) [0|655.35] "A"  PC
 SG_ S2P_Lmt18_Over_Idischarge3_17 : 32|16@1+ (0.01,0) [0|655.35] "A"  PC
 SG_ S2P_Lmt18_Over_Idischarge4_17 : 48|16@1+ (0.01,0) [0|655.35] "A"  PC

BO_ 2418273874 S2P_Lmt18__18: 8 SBMU
 SG_ S2P_Lmt18_Over_Idischarge1_18 : 0|16@1+ (0.01,0) [0|655.35] "A"  PC
 SG_ S2P_Lmt18_Over_Idischarge2_18 : 16|16@1+ (0.01,0) [0|655.35] "A"  PC
 SG_ S2P_Lmt18_Over_Idischarge3_18 : 32|16@1+ (0.01,0) [0|655.35] "A"  PC
 SG_ S2P_Lmt18_Over_Idischarge4_18 : 48|16@1+ (0.01,0) [0|655.35] "A"  PC

BO_ 2418273875 S2P_Lmt18__19: 8 SBMU
 SG_ S2P_Lmt18_Over_Idischarge1_19 : 0|16@1+ (0.01,0) [0|655.35] "A"  PC
 SG_ S2P_Lmt18_Over_Idischarge2_19 : 16|16@1+ (0.01,0) [0|655.35] "A"  PC
 SG_ S2P_Lmt18_Over_Idischarge3_19 : 32|16@1+ (0.01,0) [0|655.35] "A"  PC
 SG_ S2P_Lmt18_Over_Idischarge4_19 : 48|16@1+ (0.01,0) [0|655.35] "A"  PC

BO_ 2418273876 S2P_Lmt18__20: 8 SBMU
 SG_ S2P_Lmt18_Over_Idischarge1_20 : 0|16@1+ (0.01,0) [0|655.35] "A"  PC
 SG_ S2P_Lmt18_Over_Idischarge2_20 : 16|16@1+ (0.01,0) [0|655.35] "A"  PC
 SG_ S2P_Lmt18_Over_Idischarge3_20 : 32|16@1+ (0.01,0) [0|655.35] "A"  PC
 SG_ S2P_Lmt18_Over_Idischarge4_20 : 48|16@1+ (0.01,0) [0|655.35] "A"  PC

BO_ 2418273877 S2P_Lmt18__21: 8 SBMU
 SG_ S2P_Lmt18_Over_Idischarge1_21 : 0|16@1+ (0.01,0) [0|655.35] "A"  PC
 SG_ S2P_Lmt18_Over_Idischarge2_21 : 16|16@1+ (0.01,0) [0|655.35] "A"  PC
 SG_ S2P_Lmt18_Over_Idischarge3_21 : 32|16@1+ (0.01,0) [0|655.35] "A"  PC
 SG_ S2P_Lmt18_Over_Idischarge4_21 : 48|16@1+ (0.01,0) [0|655.35] "A"  PC

BO_ 2418273878 S2P_Lmt18__22: 8 SBMU
 SG_ S2P_Lmt18_Over_Idischarge1_22 : 0|16@1+ (0.01,0) [0|655.35] "A"  PC
 SG_ S2P_Lmt18_Over_Idischarge2_22 : 16|16@1+ (0.01,0) [0|655.35] "A"  PC
 SG_ S2P_Lmt18_Over_Idischarge3_22 : 32|16@1+ (0.01,0) [0|655.35] "A"  PC
 SG_ S2P_Lmt18_Over_Idischarge4_22 : 48|16@1+ (0.01,0) [0|655.35] "A"  PC

BO_ 2418273879 S2P_Lmt18__23: 8 SBMU
 SG_ S2P_Lmt18_Over_Idischarge1_23 : 0|16@1+ (0.01,0) [0|655.35] "A"  PC
 SG_ S2P_Lmt18_Over_Idischarge2_23 : 16|16@1+ (0.01,0) [0|655.35] "A"  PC
 SG_ S2P_Lmt18_Over_Idischarge3_23 : 32|16@1+ (0.01,0) [0|655.35] "A"  PC
 SG_ S2P_Lmt18_Over_Idischarge4_23 : 48|16@1+ (0.01,0) [0|655.35] "A"  PC

BO_ 2418273880 S2P_Lmt18__24: 8 SBMU
 SG_ S2P_Lmt18_Over_Idischarge1_24 : 0|16@1+ (0.01,0) [0|655.35] "A"  PC
 SG_ S2P_Lmt18_Over_Idischarge2_24 : 16|16@1+ (0.01,0) [0|655.35] "A"  PC
 SG_ S2P_Lmt18_Over_Idischarge3_24 : 32|16@1+ (0.01,0) [0|655.35] "A"  PC
 SG_ S2P_Lmt18_Over_Idischarge4_24 : 48|16@1+ (0.01,0) [0|655.35] "A"  PC

BO_ 2418273881 S2P_Lmt18__25: 8 SBMU
 SG_ S2P_Lmt18_Over_Idischarge1_25 : 0|16@1+ (0.01,0) [0|655.35] "A"  PC
 SG_ S2P_Lmt18_Over_Idischarge2_25 : 16|16@1+ (0.01,0) [0|655.35] "A"  PC
 SG_ S2P_Lmt18_Over_Idischarge3_25 : 32|16@1+ (0.01,0) [0|655.35] "A"  PC
 SG_ S2P_Lmt18_Over_Idischarge4_25 : 48|16@1+ (0.01,0) [0|655.35] "A"  PC

BO_ 2418273882 S2P_Lmt18__26: 8 SBMU
 SG_ S2P_Lmt18_Over_Idischarge1_26 : 0|16@1+ (0.01,0) [0|655.35] "A"  PC
 SG_ S2P_Lmt18_Over_Idischarge2_26 : 16|16@1+ (0.01,0) [0|655.35] "A"  PC
 SG_ S2P_Lmt18_Over_Idischarge3_26 : 32|16@1+ (0.01,0) [0|655.35] "A"  PC
 SG_ S2P_Lmt18_Over_Idischarge4_26 : 48|16@1+ (0.01,0) [0|655.35] "A"  PC

BO_ 2418273883 S2P_Lmt18__27: 8 SBMU
 SG_ S2P_Lmt18_Over_Idischarge1_27 : 0|16@1+ (0.01,0) [0|655.35] "A"  PC
 SG_ S2P_Lmt18_Over_Idischarge2_27 : 16|16@1+ (0.01,0) [0|655.35] "A"  PC
 SG_ S2P_Lmt18_Over_Idischarge3_27 : 32|16@1+ (0.01,0) [0|655.35] "A"  PC
 SG_ S2P_Lmt18_Over_Idischarge4_27 : 48|16@1+ (0.01,0) [0|655.35] "A"  PC

BO_ 2418273884 S2P_Lmt18__28: 8 SBMU
 SG_ S2P_Lmt18_Over_Idischarge1_28 : 0|16@1+ (0.01,0) [0|655.35] "A"  PC
 SG_ S2P_Lmt18_Over_Idischarge2_28 : 16|16@1+ (0.01,0) [0|655.35] "A"  PC
 SG_ S2P_Lmt18_Over_Idischarge3_28 : 32|16@1+ (0.01,0) [0|655.35] "A"  PC
 SG_ S2P_Lmt18_Over_Idischarge4_28 : 48|16@1+ (0.01,0) [0|655.35] "A"  PC

BO_ 2418273885 S2P_Lmt18__29: 8 SBMU
 SG_ S2P_Lmt18_Over_Idischarge1_29 : 0|16@1+ (0.01,0) [0|655.35] "A"  PC
 SG_ S2P_Lmt18_Over_Idischarge2_29 : 16|16@1+ (0.01,0) [0|655.35] "A"  PC
 SG_ S2P_Lmt18_Over_Idischarge3_29 : 32|16@1+ (0.01,0) [0|655.35] "A"  PC
 SG_ S2P_Lmt18_Over_Idischarge4_29 : 48|16@1+ (0.01,0) [0|655.35] "A"  PC

BO_ 2418273886 S2P_Lmt18__30: 8 SBMU
 SG_ S2P_Lmt18_Over_Idischarge1_30 : 0|16@1+ (0.01,0) [0|655.35] "A"  PC
 SG_ S2P_Lmt18_Over_Idischarge2_30 : 16|16@1+ (0.01,0) [0|655.35] "A"  PC
 SG_ S2P_Lmt18_Over_Idischarge3_30 : 32|16@1+ (0.01,0) [0|655.35] "A"  PC
 SG_ S2P_Lmt18_Over_Idischarge4_30 : 48|16@1+ (0.01,0) [0|655.35] "A"  PC

BO_ 2418273887 S2P_Lmt18__31: 8 SBMU
 SG_ S2P_Lmt18_Over_Idischarge1_31 : 0|16@1+ (0.01,0) [0|655.35] "A"  PC
 SG_ S2P_Lmt18_Over_Idischarge2_31 : 16|16@1+ (0.01,0) [0|655.35] "A"  PC
 SG_ S2P_Lmt18_Over_Idischarge3_31 : 32|16@1+ (0.01,0) [0|655.35] "A"  PC
 SG_ S2P_Lmt18_Over_Idischarge4_31 : 48|16@1+ (0.01,0) [0|655.35] "A"  PC

BO_ 2418273888 S2P_Lmt18__32: 8 SBMU
 SG_ S2P_Lmt18_Over_Idischarge1_32 : 0|16@1+ (0.01,0) [0|655.35] "A"  PC
 SG_ S2P_Lmt18_Over_Idischarge2_32 : 16|16@1+ (0.01,0) [0|655.35] "A"  PC
 SG_ S2P_Lmt18_Over_Idischarge3_32 : 32|16@1+ (0.01,0) [0|655.35] "A"  PC
 SG_ S2P_Lmt18_Over_Idischarge4_32 : 48|16@1+ (0.01,0) [0|655.35] "A"  PC

BO_ 2418273889 S2P_Lmt18__33: 8 SBMU
 SG_ S2P_Lmt18_Over_Idischarge1_33 : 0|16@1+ (0.01,0) [0|655.35] "A"  PC
 SG_ S2P_Lmt18_Over_Idischarge2_33 : 16|16@1+ (0.01,0) [0|655.35] "A"  PC
 SG_ S2P_Lmt18_Over_Idischarge3_33 : 32|16@1+ (0.01,0) [0|655.35] "A"  PC
 SG_ S2P_Lmt18_Over_Idischarge4_33 : 48|16@1+ (0.01,0) [0|655.35] "A"  PC

BO_ 2418273890 S2P_Lmt18__34: 8 SBMU
 SG_ S2P_Lmt18_Over_Idischarge1_34 : 0|16@1+ (0.01,0) [0|655.35] "A"  PC
 SG_ S2P_Lmt18_Over_Idischarge2_34 : 16|16@1+ (0.01,0) [0|655.35] "A"  PC
 SG_ S2P_Lmt18_Over_Idischarge3_34 : 32|16@1+ (0.01,0) [0|655.35] "A"  PC
 SG_ S2P_Lmt18_Over_Idischarge4_34 : 48|16@1+ (0.01,0) [0|655.35] "A"  PC

BO_ 2418273891 S2P_Lmt18__35: 8 SBMU
 SG_ S2P_Lmt18_Over_Idischarge1_35 : 0|16@1+ (0.01,0) [0|655.35] "A"  PC
 SG_ S2P_Lmt18_Over_Idischarge2_35 : 16|16@1+ (0.01,0) [0|655.35] "A"  PC
 SG_ S2P_Lmt18_Over_Idischarge3_35 : 32|16@1+ (0.01,0) [0|655.35] "A"  PC
 SG_ S2P_Lmt18_Over_Idischarge4_35 : 48|16@1+ (0.01,0) [0|655.35] "A"  PC

BO_ 2418273892 S2P_Lmt18__36: 8 SBMU
 SG_ S2P_Lmt18_Over_Idischarge1_36 : 0|16@1+ (0.01,0) [0|655.35] "A"  PC
 SG_ S2P_Lmt18_Over_Idischarge2_36 : 16|16@1+ (0.01,0) [0|655.35] "A"  PC
 SG_ S2P_Lmt18_Over_Idischarge3_36 : 32|16@1+ (0.01,0) [0|655.35] "A"  PC
 SG_ S2P_Lmt18_Over_Idischarge4_36 : 48|16@1+ (0.01,0) [0|655.35] "A"  PC

BO_ 2418273893 S2P_Lmt18__37: 8 SBMU
 SG_ S2P_Lmt18_Over_Idischarge1_37 : 0|16@1+ (0.01,0) [0|655.35] "A"  PC
 SG_ S2P_Lmt18_Over_Idischarge2_37 : 16|16@1+ (0.01,0) [0|655.35] "A"  PC
 SG_ S2P_Lmt18_Over_Idischarge3_37 : 32|16@1+ (0.01,0) [0|655.35] "A"  PC
 SG_ S2P_Lmt18_Over_Idischarge4_37 : 48|16@1+ (0.01,0) [0|655.35] "A"  PC

BO_ 2418273894 S2P_Lmt18__38: 8 SBMU
 SG_ S2P_Lmt18_Over_Idischarge1_38 : 0|16@1+ (0.01,0) [0|655.35] "A"  PC
 SG_ S2P_Lmt18_Over_Idischarge2_38 : 16|16@1+ (0.01,0) [0|655.35] "A"  PC
 SG_ S2P_Lmt18_Over_Idischarge3_38 : 32|16@1+ (0.01,0) [0|655.35] "A"  PC
 SG_ S2P_Lmt18_Over_Idischarge4_38 : 48|16@1+ (0.01,0) [0|655.35] "A"  PC

BO_ 2418273895 S2P_Lmt18__39: 8 SBMU
 SG_ S2P_Lmt18_Over_Idischarge1_39 : 0|16@1+ (0.01,0) [0|655.35] "A"  PC
 SG_ S2P_Lmt18_Over_Idischarge2_39 : 16|16@1+ (0.01,0) [0|655.35] "A"  PC
 SG_ S2P_Lmt18_Over_Idischarge3_39 : 32|16@1+ (0.01,0) [0|655.35] "A"  PC
 SG_ S2P_Lmt18_Over_Idischarge4_39 : 48|16@1+ (0.01,0) [0|655.35] "A"  PC

BO_ 2418273896 S2P_Lmt18__40: 8 SBMU
 SG_ S2P_Lmt18_Over_Idischarge1_40 : 0|16@1+ (0.01,0) [0|655.35] "A"  PC
 SG_ S2P_Lmt18_Over_Idischarge2_40 : 16|16@1+ (0.01,0) [0|655.35] "A"  PC
 SG_ S2P_Lmt18_Over_Idischarge3_40 : 32|16@1+ (0.01,0) [0|655.35] "A"  PC
 SG_ S2P_Lmt18_Over_Idischarge4_40 : 48|16@1+ (0.01,0) [0|655.35] "A"  PC

BO_ 2418273897 S2P_Lmt18__41: 8 SBMU
 SG_ S2P_Lmt18_Over_Idischarge1_41 : 0|16@1+ (0.01,0) [0|655.35] "A"  PC
 SG_ S2P_Lmt18_Over_Idischarge2_41 : 16|16@1+ (0.01,0) [0|655.35] "A"  PC
 SG_ S2P_Lmt18_Over_Idischarge3_41 : 32|16@1+ (0.01,0) [0|655.35] "A"  PC
 SG_ S2P_Lmt18_Over_Idischarge4_41 : 48|16@1+ (0.01,0) [0|655.35] "A"  PC

BO_ 2418273898 S2P_Lmt18__42: 8 SBMU
 SG_ S2P_Lmt18_Over_Idischarge1_42 : 0|16@1+ (0.01,0) [0|655.35] "A"  PC
 SG_ S2P_Lmt18_Over_Idischarge2_42 : 16|16@1+ (0.01,0) [0|655.35] "A"  PC
 SG_ S2P_Lmt18_Over_Idischarge3_42 : 32|16@1+ (0.01,0) [0|655.35] "A"  PC
 SG_ S2P_Lmt18_Over_Idischarge4_42 : 48|16@1+ (0.01,0) [0|655.35] "A"  PC

BO_ 2418273899 S2P_Lmt18__43: 8 SBMU
 SG_ S2P_Lmt18_Over_Idischarge1_43 : 0|16@1+ (0.01,0) [0|655.35] "A"  PC
 SG_ S2P_Lmt18_Over_Idischarge2_43 : 16|16@1+ (0.01,0) [0|655.35] "A"  PC
 SG_ S2P_Lmt18_Over_Idischarge3_43 : 32|16@1+ (0.01,0) [0|655.35] "A"  PC
 SG_ S2P_Lmt18_Over_Idischarge4_43 : 48|16@1+ (0.01,0) [0|655.35] "A"  PC

BO_ 2418273900 S2P_Lmt18__44: 8 SBMU
 SG_ S2P_Lmt18_Over_Idischarge1_44 : 0|16@1+ (0.01,0) [0|655.35] "A"  PC
 SG_ S2P_Lmt18_Over_Idischarge2_44 : 16|16@1+ (0.01,0) [0|655.35] "A"  PC
 SG_ S2P_Lmt18_Over_Idischarge3_44 : 32|16@1+ (0.01,0) [0|655.35] "A"  PC
 SG_ S2P_Lmt18_Over_Idischarge4_44 : 48|16@1+ (0.01,0) [0|655.35] "A"  PC

BO_ 2418273901 S2P_Lmt18__45: 8 SBMU
 SG_ S2P_Lmt18_Over_Idischarge1_45 : 0|16@1+ (0.01,0) [0|655.35] "A"  PC
 SG_ S2P_Lmt18_Over_Idischarge2_45 : 16|16@1+ (0.01,0) [0|655.35] "A"  PC
 SG_ S2P_Lmt18_Over_Idischarge3_45 : 32|16@1+ (0.01,0) [0|655.35] "A"  PC
 SG_ S2P_Lmt18_Over_Idischarge4_45 : 48|16@1+ (0.01,0) [0|655.35] "A"  PC

BO_ 2418273902 S2P_Lmt18__46: 8 SBMU
 SG_ S2P_Lmt18_Over_Idischarge1_46 : 0|16@1+ (0.01,0) [0|655.35] "A"  PC
 SG_ S2P_Lmt18_Over_Idischarge2_46 : 16|16@1+ (0.01,0) [0|655.35] "A"  PC
 SG_ S2P_Lmt18_Over_Idischarge3_46 : 32|16@1+ (0.01,0) [0|655.35] "A"  PC
 SG_ S2P_Lmt18_Over_Idischarge4_46 : 48|16@1+ (0.01,0) [0|655.35] "A"  PC

BO_ 2418273903 S2P_Lmt18__47: 8 SBMU
 SG_ S2P_Lmt18_Over_Idischarge1_47 : 0|16@1+ (0.01,0) [0|655.35] "A"  PC
 SG_ S2P_Lmt18_Over_Idischarge2_47 : 16|16@1+ (0.01,0) [0|655.35] "A"  PC
 SG_ S2P_Lmt18_Over_Idischarge3_47 : 32|16@1+ (0.01,0) [0|655.35] "A"  PC
 SG_ S2P_Lmt18_Over_Idischarge4_47 : 48|16@1+ (0.01,0) [0|655.35] "A"  PC

BO_ 2418273904 S2P_Lmt18__48: 8 SBMU
 SG_ S2P_Lmt18_Over_Idischarge1_48 : 0|16@1+ (0.01,0) [0|655.35] "A"  PC
 SG_ S2P_Lmt18_Over_Idischarge2_48 : 16|16@1+ (0.01,0) [0|655.35] "A"  PC
 SG_ S2P_Lmt18_Over_Idischarge3_48 : 32|16@1+ (0.01,0) [0|655.35] "A"  PC
 SG_ S2P_Lmt18_Over_Idischarge4_48 : 48|16@1+ (0.01,0) [0|655.35] "A"  PC

BO_ 2418273905 S2P_Lmt18__49: 8 SBMU
 SG_ S2P_Lmt18_Over_Idischarge1_49 : 0|16@1+ (0.01,0) [0|655.35] "A"  PC
 SG_ S2P_Lmt18_Over_Idischarge2_49 : 16|16@1+ (0.01,0) [0|655.35] "A"  PC
 SG_ S2P_Lmt18_Over_Idischarge3_49 : 32|16@1+ (0.01,0) [0|655.35] "A"  PC
 SG_ S2P_Lmt18_Over_Idischarge4_49 : 48|16@1+ (0.01,0) [0|655.35] "A"  PC

BO_ 2418273906 S2P_Lmt18__50: 8 SBMU
 SG_ S2P_Lmt18_Over_Idischarge1_50 : 0|16@1+ (0.01,0) [0|655.35] "A"  PC
 SG_ S2P_Lmt18_Over_Idischarge2_50 : 16|16@1+ (0.01,0) [0|655.35] "A"  PC
 SG_ S2P_Lmt18_Over_Idischarge3_50 : 32|16@1+ (0.01,0) [0|655.35] "A"  PC
 SG_ S2P_Lmt18_Over_Idischarge4_50 : 48|16@1+ (0.01,0) [0|655.35] "A"  PC

BO_ 2418273907 S2P_Lmt18__51: 8 SBMU
 SG_ S2P_Lmt18_Over_Idischarge1_51 : 0|16@1+ (0.01,0) [0|655.35] "A"  PC
 SG_ S2P_Lmt18_Over_Idischarge2_51 : 16|16@1+ (0.01,0) [0|655.35] "A"  PC
 SG_ S2P_Lmt18_Over_Idischarge3_51 : 32|16@1+ (0.01,0) [0|655.35] "A"  PC
 SG_ S2P_Lmt18_Over_Idischarge4_51 : 48|16@1+ (0.01,0) [0|655.35] "A"  PC

BO_ 2418273908 S2P_Lmt18__52: 8 SBMU
 SG_ S2P_Lmt18_Over_Idischarge1_52 : 0|16@1+ (0.01,0) [0|655.35] "A"  PC
 SG_ S2P_Lmt18_Over_Idischarge2_52 : 16|16@1+ (0.01,0) [0|655.35] "A"  PC
 SG_ S2P_Lmt18_Over_Idischarge3_52 : 32|16@1+ (0.01,0) [0|655.35] "A"  PC
 SG_ S2P_Lmt18_Over_Idischarge4_52 : 48|16@1+ (0.01,0) [0|655.35] "A"  PC

BO_ 2418273909 S2P_Lmt18__53: 8 SBMU
 SG_ S2P_Lmt18_Over_Idischarge1_53 : 0|16@1+ (0.01,0) [0|655.35] "A"  PC
 SG_ S2P_Lmt18_Over_Idischarge2_53 : 16|16@1+ (0.01,0) [0|655.35] "A"  PC
 SG_ S2P_Lmt18_Over_Idischarge3_53 : 32|16@1+ (0.01,0) [0|655.35] "A"  PC
 SG_ S2P_Lmt18_Over_Idischarge4_53 : 48|16@1+ (0.01,0) [0|655.35] "A"  PC

BO_ 2418273910 S2P_Lmt18__54: 8 SBMU
 SG_ S2P_Lmt18_Over_Idischarge1_54 : 0|16@1+ (0.01,0) [0|655.35] "A"  PC
 SG_ S2P_Lmt18_Over_Idischarge2_54 : 16|16@1+ (0.01,0) [0|655.35] "A"  PC
 SG_ S2P_Lmt18_Over_Idischarge3_54 : 32|16@1+ (0.01,0) [0|655.35] "A"  PC
 SG_ S2P_Lmt18_Over_Idischarge4_54 : 48|16@1+ (0.01,0) [0|655.35] "A"  PC

BO_ 2418273911 S2P_Lmt18__55: 8 SBMU
 SG_ S2P_Lmt18_Over_Idischarge1_55 : 0|16@1+ (0.01,0) [0|655.35] "A"  PC
 SG_ S2P_Lmt18_Over_Idischarge2_55 : 16|16@1+ (0.01,0) [0|655.35] "A"  PC
 SG_ S2P_Lmt18_Over_Idischarge3_55 : 32|16@1+ (0.01,0) [0|655.35] "A"  PC
 SG_ S2P_Lmt18_Over_Idischarge4_55 : 48|16@1+ (0.01,0) [0|655.35] "A"  PC

BO_ 2418273912 S2P_Lmt18__56: 8 SBMU
 SG_ S2P_Lmt18_Over_Idischarge1_56 : 0|16@1+ (0.01,0) [0|655.35] "A"  PC
 SG_ S2P_Lmt18_Over_Idischarge2_56 : 16|16@1+ (0.01,0) [0|655.35] "A"  PC
 SG_ S2P_Lmt18_Over_Idischarge3_56 : 32|16@1+ (0.01,0) [0|655.35] "A"  PC
 SG_ S2P_Lmt18_Over_Idischarge4_56 : 48|16@1+ (0.01,0) [0|655.35] "A"  PC

BO_ 2418273913 S2P_Lmt18__57: 8 SBMU
 SG_ S2P_Lmt18_Over_Idischarge1_57 : 0|16@1+ (0.01,0) [0|655.35] "A"  PC
 SG_ S2P_Lmt18_Over_Idischarge2_57 : 16|16@1+ (0.01,0) [0|655.35] "A"  PC
 SG_ S2P_Lmt18_Over_Idischarge3_57 : 32|16@1+ (0.01,0) [0|655.35] "A"  PC
 SG_ S2P_Lmt18_Over_Idischarge4_57 : 48|16@1+ (0.01,0) [0|655.35] "A"  PC

BO_ 2418273914 S2P_Lmt18__58: 8 SBMU
 SG_ S2P_Lmt18_Over_Idischarge1_58 : 0|16@1+ (0.01,0) [0|655.35] "A"  PC
 SG_ S2P_Lmt18_Over_Idischarge2_58 : 16|16@1+ (0.01,0) [0|655.35] "A"  PC
 SG_ S2P_Lmt18_Over_Idischarge3_58 : 32|16@1+ (0.01,0) [0|655.35] "A"  PC
 SG_ S2P_Lmt18_Over_Idischarge4_58 : 48|16@1+ (0.01,0) [0|655.35] "A"  PC

BO_ 2418273915 S2P_Lmt18__59: 8 SBMU
 SG_ S2P_Lmt18_Over_Idischarge1_59 : 0|16@1+ (0.01,0) [0|655.35] "A"  PC
 SG_ S2P_Lmt18_Over_Idischarge2_59 : 16|16@1+ (0.01,0) [0|655.35] "A"  PC
 SG_ S2P_Lmt18_Over_Idischarge3_59 : 32|16@1+ (0.01,0) [0|655.35] "A"  PC
 SG_ S2P_Lmt18_Over_Idischarge4_59 : 48|16@1+ (0.01,0) [0|655.35] "A"  PC

BO_ 2418273916 S2P_Lmt18__60: 8 SBMU
 SG_ S2P_Lmt18_Over_Idischarge1_60 : 0|16@1+ (0.01,0) [0|655.35] "A"  PC
 SG_ S2P_Lmt18_Over_Idischarge2_60 : 16|16@1+ (0.01,0) [0|655.35] "A"  PC
 SG_ S2P_Lmt18_Over_Idischarge3_60 : 32|16@1+ (0.01,0) [0|655.35] "A"  PC
 SG_ S2P_Lmt18_Over_Idischarge4_60 : 48|16@1+ (0.01,0) [0|655.35] "A"  PC

BO_ 2418273917 S2P_Lmt18__61: 8 SBMU
 SG_ S2P_Lmt18_Over_Idischarge1_61 : 0|16@1+ (0.01,0) [0|655.35] "A"  PC
 SG_ S2P_Lmt18_Over_Idischarge2_61 : 16|16@1+ (0.01,0) [0|655.35] "A"  PC
 SG_ S2P_Lmt18_Over_Idischarge3_61 : 32|16@1+ (0.01,0) [0|655.35] "A"  PC
 SG_ S2P_Lmt18_Over_Idischarge4_61 : 48|16@1+ (0.01,0) [0|655.35] "A"  PC

BO_ 2418273918 S2P_Lmt18__62: 8 SBMU
 SG_ S2P_Lmt18_Over_Idischarge1_62 : 0|16@1+ (0.01,0) [0|655.35] "A"  PC
 SG_ S2P_Lmt18_Over_Idischarge2_62 : 16|16@1+ (0.01,0) [0|655.35] "A"  PC
 SG_ S2P_Lmt18_Over_Idischarge3_62 : 32|16@1+ (0.01,0) [0|655.35] "A"  PC
 SG_ S2P_Lmt18_Over_Idischarge4_62 : 48|16@1+ (0.01,0) [0|655.35] "A"  PC

BO_ 2418273919 S2P_Lmt18__63: 8 SBMU
 SG_ S2P_Lmt18_Over_Idischarge1_63 : 0|16@1+ (0.01,0) [0|655.35] "A"  PC
 SG_ S2P_Lmt18_Over_Idischarge2_63 : 16|16@1+ (0.01,0) [0|655.35] "A"  PC
 SG_ S2P_Lmt18_Over_Idischarge3_63 : 32|16@1+ (0.01,0) [0|655.35] "A"  PC
 SG_ S2P_Lmt18_Over_Idischarge4_63 : 48|16@1+ (0.01,0) [0|655.35] "A"  PC

BO_ 2418339393 S2P_Lmt19__01: 8 SBMU
 SG_ S2P_Lmt19_Over_DeltUModule1_01 : 0|16@1+ (1,0) [0|65535] "V"  PC
 SG_ S2P_Lmt19_Over_DeltUModule2_01 : 16|16@1+ (1,0) [0|65535] "V"  PC
 SG_ S2P_Lmt19_Over_DeltUModule3_01 : 32|16@1+ (1,0) [0|65535] "V"  PC
 SG_ S2P_Lmt19_Over_DeltUModule4_01 : 48|16@1+ (1,0) [0|65535] "mV"  PC

BO_ 2418339394 S2P_Lmt19__02: 8 SBMU
 SG_ S2P_Lmt19_Over_DeltUModule1_02 : 0|16@1+ (1,0) [0|65535] "V"  PC
 SG_ S2P_Lmt19_Over_DeltUModule2_02 : 16|16@1+ (1,0) [0|65535] "V"  PC
 SG_ S2P_Lmt19_Over_DeltUModule3_02 : 32|16@1+ (1,0) [0|65535] "V"  PC
 SG_ S2P_Lmt19_Over_DeltUModule4_02 : 48|16@1+ (1,0) [0|65535] "mV"  PC

BO_ 2418339395 S2P_Lmt19__03: 8 SBMU
 SG_ S2P_Lmt19_Over_DeltUModule1_03 : 0|16@1+ (1,0) [0|65535] "V"  PC
 SG_ S2P_Lmt19_Over_DeltUModule2_03 : 16|16@1+ (1,0) [0|65535] "V"  PC
 SG_ S2P_Lmt19_Over_DeltUModule3_03 : 32|16@1+ (1,0) [0|65535] "V"  PC
 SG_ S2P_Lmt19_Over_DeltUModule4_03 : 48|16@1+ (1,0) [0|65535] "mV"  PC

BO_ 2418339396 S2P_Lmt19__04: 8 SBMU
 SG_ S2P_Lmt19_Over_DeltUModule1_04 : 0|16@1+ (1,0) [0|65535] "V"  PC
 SG_ S2P_Lmt19_Over_DeltUModule2_04 : 16|16@1+ (1,0) [0|65535] "V"  PC
 SG_ S2P_Lmt19_Over_DeltUModule3_04 : 32|16@1+ (1,0) [0|65535] "V"  PC
 SG_ S2P_Lmt19_Over_DeltUModule4_04 : 48|16@1+ (1,0) [0|65535] "mV"  PC

BO_ 2418339397 S2P_Lmt19__05: 8 SBMU
 SG_ S2P_Lmt19_Over_DeltUModule1_05 : 0|16@1+ (1,0) [0|65535] "V"  PC
 SG_ S2P_Lmt19_Over_DeltUModule2_05 : 16|16@1+ (1,0) [0|65535] "V"  PC
 SG_ S2P_Lmt19_Over_DeltUModule3_05 : 32|16@1+ (1,0) [0|65535] "V"  PC
 SG_ S2P_Lmt19_Over_DeltUModule4_05 : 48|16@1+ (1,0) [0|65535] "mV"  PC

BO_ 2418339398 S2P_Lmt19__06: 8 SBMU
 SG_ S2P_Lmt19_Over_DeltUModule1_06 : 0|16@1+ (1,0) [0|65535] "V"  PC
 SG_ S2P_Lmt19_Over_DeltUModule2_06 : 16|16@1+ (1,0) [0|65535] "V"  PC
 SG_ S2P_Lmt19_Over_DeltUModule3_06 : 32|16@1+ (1,0) [0|65535] "V"  PC
 SG_ S2P_Lmt19_Over_DeltUModule4_06 : 48|16@1+ (1,0) [0|65535] "mV"  PC

BO_ 2418339399 S2P_Lmt19__07: 8 SBMU
 SG_ S2P_Lmt19_Over_DeltUModule1_07 : 0|16@1+ (1,0) [0|65535] "V"  PC
 SG_ S2P_Lmt19_Over_DeltUModule2_07 : 16|16@1+ (1,0) [0|65535] "V"  PC
 SG_ S2P_Lmt19_Over_DeltUModule3_07 : 32|16@1+ (1,0) [0|65535] "V"  PC
 SG_ S2P_Lmt19_Over_DeltUModule4_07 : 48|16@1+ (1,0) [0|65535] "mV"  PC

BO_ 2418339400 S2P_Lmt19__08: 8 SBMU
 SG_ S2P_Lmt19_Over_DeltUModule1_08 : 0|16@1+ (1,0) [0|65535] "V"  PC
 SG_ S2P_Lmt19_Over_DeltUModule2_08 : 16|16@1+ (1,0) [0|65535] "V"  PC
 SG_ S2P_Lmt19_Over_DeltUModule3_08 : 32|16@1+ (1,0) [0|65535] "V"  PC
 SG_ S2P_Lmt19_Over_DeltUModule4_08 : 48|16@1+ (1,0) [0|65535] "mV"  PC

BO_ 2418339401 S2P_Lmt19__09: 8 SBMU
 SG_ S2P_Lmt19_Over_DeltUModule1_09 : 0|16@1+ (1,0) [0|65535] "V"  PC
 SG_ S2P_Lmt19_Over_DeltUModule2_09 : 16|16@1+ (1,0) [0|65535] "V"  PC
 SG_ S2P_Lmt19_Over_DeltUModule3_09 : 32|16@1+ (1,0) [0|65535] "V"  PC
 SG_ S2P_Lmt19_Over_DeltUModule4_09 : 48|16@1+ (1,0) [0|65535] "mV"  PC

BO_ 2418339402 S2P_Lmt19__10: 8 SBMU
 SG_ S2P_Lmt19_Over_DeltUModule1_10 : 0|16@1+ (1,0) [0|65535] "V"  PC
 SG_ S2P_Lmt19_Over_DeltUModule2_10 : 16|16@1+ (1,0) [0|65535] "V"  PC
 SG_ S2P_Lmt19_Over_DeltUModule3_10 : 32|16@1+ (1,0) [0|65535] "V"  PC
 SG_ S2P_Lmt19_Over_DeltUModule4_10 : 48|16@1+ (1,0) [0|65535] "mV"  PC

BO_ 2418339403 S2P_Lmt19__11: 8 SBMU
 SG_ S2P_Lmt19_Over_DeltUModule1_11 : 0|16@1+ (1,0) [0|65535] "V"  PC
 SG_ S2P_Lmt19_Over_DeltUModule2_11 : 16|16@1+ (1,0) [0|65535] "V"  PC
 SG_ S2P_Lmt19_Over_DeltUModule3_11 : 32|16@1+ (1,0) [0|65535] "V"  PC
 SG_ S2P_Lmt19_Over_DeltUModule4_11 : 48|16@1+ (1,0) [0|65535] "mV"  PC

BO_ 2418339404 S2P_Lmt19__12: 8 SBMU
 SG_ S2P_Lmt19_Over_DeltUModule1_12 : 0|16@1+ (1,0) [0|65535] "V"  PC
 SG_ S2P_Lmt19_Over_DeltUModule2_12 : 16|16@1+ (1,0) [0|65535] "V"  PC
 SG_ S2P_Lmt19_Over_DeltUModule3_12 : 32|16@1+ (1,0) [0|65535] "V"  PC
 SG_ S2P_Lmt19_Over_DeltUModule4_12 : 48|16@1+ (1,0) [0|65535] "mV"  PC

BO_ 2418339405 S2P_Lmt19__13: 8 SBMU
 SG_ S2P_Lmt19_Over_DeltUModule1_13 : 0|16@1+ (1,0) [0|65535] "V"  PC
 SG_ S2P_Lmt19_Over_DeltUModule2_13 : 16|16@1+ (1,0) [0|65535] "V"  PC
 SG_ S2P_Lmt19_Over_DeltUModule3_13 : 32|16@1+ (1,0) [0|65535] "V"  PC
 SG_ S2P_Lmt19_Over_DeltUModule4_13 : 48|16@1+ (1,0) [0|65535] "mV"  PC

BO_ 2418339406 S2P_Lmt19__14: 8 SBMU
 SG_ S2P_Lmt19_Over_DeltUModule1_14 : 0|16@1+ (1,0) [0|65535] "V"  PC
 SG_ S2P_Lmt19_Over_DeltUModule2_14 : 16|16@1+ (1,0) [0|65535] "V"  PC
 SG_ S2P_Lmt19_Over_DeltUModule3_14 : 32|16@1+ (1,0) [0|65535] "V"  PC
 SG_ S2P_Lmt19_Over_DeltUModule4_14 : 48|16@1+ (1,0) [0|65535] "mV"  PC

BO_ 2418339407 S2P_Lmt19__15: 8 SBMU
 SG_ S2P_Lmt19_Over_DeltUModule1_15 : 0|16@1+ (1,0) [0|65535] "V"  PC
 SG_ S2P_Lmt19_Over_DeltUModule2_15 : 16|16@1+ (1,0) [0|65535] "V"  PC
 SG_ S2P_Lmt19_Over_DeltUModule3_15 : 32|16@1+ (1,0) [0|65535] "V"  PC
 SG_ S2P_Lmt19_Over_DeltUModule4_15 : 48|16@1+ (1,0) [0|65535] "mV"  PC

BO_ 2418339408 S2P_Lmt19__16: 8 SBMU
 SG_ S2P_Lmt19_Over_DeltUModule1_16 : 0|16@1+ (1,0) [0|65535] "V"  PC
 SG_ S2P_Lmt19_Over_DeltUModule2_16 : 16|16@1+ (1,0) [0|65535] "V"  PC
 SG_ S2P_Lmt19_Over_DeltUModule3_16 : 32|16@1+ (1,0) [0|65535] "V"  PC
 SG_ S2P_Lmt19_Over_DeltUModule4_16 : 48|16@1+ (1,0) [0|65535] "mV"  PC

BO_ 2418339409 S2P_Lmt19__17: 8 SBMU
 SG_ S2P_Lmt19_Over_DeltUModule1_17 : 0|16@1+ (1,0) [0|65535] "V"  PC
 SG_ S2P_Lmt19_Over_DeltUModule2_17 : 16|16@1+ (1,0) [0|65535] "V"  PC
 SG_ S2P_Lmt19_Over_DeltUModule3_17 : 32|16@1+ (1,0) [0|65535] "V"  PC
 SG_ S2P_Lmt19_Over_DeltUModule4_17 : 48|16@1+ (1,0) [0|65535] "mV"  PC

BO_ 2418339410 S2P_Lmt19__18: 8 SBMU
 SG_ S2P_Lmt19_Over_DeltUModule1_18 : 0|16@1+ (1,0) [0|65535] "V"  PC
 SG_ S2P_Lmt19_Over_DeltUModule2_18 : 16|16@1+ (1,0) [0|65535] "V"  PC
 SG_ S2P_Lmt19_Over_DeltUModule3_18 : 32|16@1+ (1,0) [0|65535] "V"  PC
 SG_ S2P_Lmt19_Over_DeltUModule4_18 : 48|16@1+ (1,0) [0|65535] "mV"  PC

BO_ 2418339411 S2P_Lmt19__19: 8 SBMU
 SG_ S2P_Lmt19_Over_DeltUModule1_19 : 0|16@1+ (1,0) [0|65535] "V"  PC
 SG_ S2P_Lmt19_Over_DeltUModule2_19 : 16|16@1+ (1,0) [0|65535] "V"  PC
 SG_ S2P_Lmt19_Over_DeltUModule3_19 : 32|16@1+ (1,0) [0|65535] "V"  PC
 SG_ S2P_Lmt19_Over_DeltUModule4_19 : 48|16@1+ (1,0) [0|65535] "mV"  PC

BO_ 2418339412 S2P_Lmt19__20: 8 SBMU
 SG_ S2P_Lmt19_Over_DeltUModule1_20 : 0|16@1+ (1,0) [0|65535] "V"  PC
 SG_ S2P_Lmt19_Over_DeltUModule2_20 : 16|16@1+ (1,0) [0|65535] "V"  PC
 SG_ S2P_Lmt19_Over_DeltUModule3_20 : 32|16@1+ (1,0) [0|65535] "V"  PC
 SG_ S2P_Lmt19_Over_DeltUModule4_20 : 48|16@1+ (1,0) [0|65535] "mV"  PC

BO_ 2418339413 S2P_Lmt19__21: 8 SBMU
 SG_ S2P_Lmt19_Over_DeltUModule1_21 : 0|16@1+ (1,0) [0|65535] "V"  PC
 SG_ S2P_Lmt19_Over_DeltUModule2_21 : 16|16@1+ (1,0) [0|65535] "V"  PC
 SG_ S2P_Lmt19_Over_DeltUModule3_21 : 32|16@1+ (1,0) [0|65535] "V"  PC
 SG_ S2P_Lmt19_Over_DeltUModule4_21 : 48|16@1+ (1,0) [0|65535] "mV"  PC

BO_ 2418339414 S2P_Lmt19__22: 8 SBMU
 SG_ S2P_Lmt19_Over_DeltUModule1_22 : 0|16@1+ (1,0) [0|65535] "V"  PC
 SG_ S2P_Lmt19_Over_DeltUModule2_22 : 16|16@1+ (1,0) [0|65535] "V"  PC
 SG_ S2P_Lmt19_Over_DeltUModule3_22 : 32|16@1+ (1,0) [0|65535] "V"  PC
 SG_ S2P_Lmt19_Over_DeltUModule4_22 : 48|16@1+ (1,0) [0|65535] "mV"  PC

BO_ 2418339415 S2P_Lmt19__23: 8 SBMU
 SG_ S2P_Lmt19_Over_DeltUModule1_23 : 0|16@1+ (1,0) [0|65535] "V"  PC
 SG_ S2P_Lmt19_Over_DeltUModule2_23 : 16|16@1+ (1,0) [0|65535] "V"  PC
 SG_ S2P_Lmt19_Over_DeltUModule3_23 : 32|16@1+ (1,0) [0|65535] "V"  PC
 SG_ S2P_Lmt19_Over_DeltUModule4_23 : 48|16@1+ (1,0) [0|65535] "mV"  PC

BO_ 2418339416 S2P_Lmt19__24: 8 SBMU
 SG_ S2P_Lmt19_Over_DeltUModule1_24 : 0|16@1+ (1,0) [0|65535] "V"  PC
 SG_ S2P_Lmt19_Over_DeltUModule2_24 : 16|16@1+ (1,0) [0|65535] "V"  PC
 SG_ S2P_Lmt19_Over_DeltUModule3_24 : 32|16@1+ (1,0) [0|65535] "V"  PC
 SG_ S2P_Lmt19_Over_DeltUModule4_24 : 48|16@1+ (1,0) [0|65535] "mV"  PC

BO_ 2418339417 S2P_Lmt19__25: 8 SBMU
 SG_ S2P_Lmt19_Over_DeltUModule1_25 : 0|16@1+ (1,0) [0|65535] "V"  PC
 SG_ S2P_Lmt19_Over_DeltUModule2_25 : 16|16@1+ (1,0) [0|65535] "V"  PC
 SG_ S2P_Lmt19_Over_DeltUModule3_25 : 32|16@1+ (1,0) [0|65535] "V"  PC
 SG_ S2P_Lmt19_Over_DeltUModule4_25 : 48|16@1+ (1,0) [0|65535] "mV"  PC

BO_ 2418339418 S2P_Lmt19__26: 8 SBMU
 SG_ S2P_Lmt19_Over_DeltUModule1_26 : 0|16@1+ (1,0) [0|65535] "V"  PC
 SG_ S2P_Lmt19_Over_DeltUModule2_26 : 16|16@1+ (1,0) [0|65535] "V"  PC
 SG_ S2P_Lmt19_Over_DeltUModule3_26 : 32|16@1+ (1,0) [0|65535] "V"  PC
 SG_ S2P_Lmt19_Over_DeltUModule4_26 : 48|16@1+ (1,0) [0|65535] "mV"  PC

BO_ 2418339419 S2P_Lmt19__27: 8 SBMU
 SG_ S2P_Lmt19_Over_DeltUModule1_27 : 0|16@1+ (1,0) [0|65535] "V"  PC
 SG_ S2P_Lmt19_Over_DeltUModule2_27 : 16|16@1+ (1,0) [0|65535] "V"  PC
 SG_ S2P_Lmt19_Over_DeltUModule3_27 : 32|16@1+ (1,0) [0|65535] "V"  PC
 SG_ S2P_Lmt19_Over_DeltUModule4_27 : 48|16@1+ (1,0) [0|65535] "mV"  PC

BO_ 2418339420 S2P_Lmt19__28: 8 SBMU
 SG_ S2P_Lmt19_Over_DeltUModule1_28 : 0|16@1+ (1,0) [0|65535] "V"  PC
 SG_ S2P_Lmt19_Over_DeltUModule2_28 : 16|16@1+ (1,0) [0|65535] "V"  PC
 SG_ S2P_Lmt19_Over_DeltUModule3_28 : 32|16@1+ (1,0) [0|65535] "V"  PC
 SG_ S2P_Lmt19_Over_DeltUModule4_28 : 48|16@1+ (1,0) [0|65535] "mV"  PC

BO_ 2418339421 S2P_Lmt19__29: 8 SBMU
 SG_ S2P_Lmt19_Over_DeltUModule1_29 : 0|16@1+ (1,0) [0|65535] "V"  PC
 SG_ S2P_Lmt19_Over_DeltUModule2_29 : 16|16@1+ (1,0) [0|65535] "V"  PC
 SG_ S2P_Lmt19_Over_DeltUModule3_29 : 32|16@1+ (1,0) [0|65535] "V"  PC
 SG_ S2P_Lmt19_Over_DeltUModule4_29 : 48|16@1+ (1,0) [0|65535] "mV"  PC

BO_ 2418339422 S2P_Lmt19__30: 8 SBMU
 SG_ S2P_Lmt19_Over_DeltUModule1_30 : 0|16@1+ (1,0) [0|65535] "V"  PC
 SG_ S2P_Lmt19_Over_DeltUModule2_30 : 16|16@1+ (1,0) [0|65535] "V"  PC
 SG_ S2P_Lmt19_Over_DeltUModule3_30 : 32|16@1+ (1,0) [0|65535] "V"  PC
 SG_ S2P_Lmt19_Over_DeltUModule4_30 : 48|16@1+ (1,0) [0|65535] "mV"  PC

BO_ 2418339423 S2P_Lmt19__31: 8 SBMU
 SG_ S2P_Lmt19_Over_DeltUModule1_31 : 0|16@1+ (1,0) [0|65535] "V"  PC
 SG_ S2P_Lmt19_Over_DeltUModule2_31 : 16|16@1+ (1,0) [0|65535] "V"  PC
 SG_ S2P_Lmt19_Over_DeltUModule3_31 : 32|16@1+ (1,0) [0|65535] "V"  PC
 SG_ S2P_Lmt19_Over_DeltUModule4_31 : 48|16@1+ (1,0) [0|65535] "mV"  PC

BO_ 2418339424 S2P_Lmt19__32: 8 SBMU
 SG_ S2P_Lmt19_Over_DeltUModule1_32 : 0|16@1+ (1,0) [0|65535] "V"  PC
 SG_ S2P_Lmt19_Over_DeltUModule2_32 : 16|16@1+ (1,0) [0|65535] "V"  PC
 SG_ S2P_Lmt19_Over_DeltUModule3_32 : 32|16@1+ (1,0) [0|65535] "V"  PC
 SG_ S2P_Lmt19_Over_DeltUModule4_32 : 48|16@1+ (1,0) [0|65535] "mV"  PC

BO_ 2418339425 S2P_Lmt19__33: 8 SBMU
 SG_ S2P_Lmt19_Over_DeltUModule1_33 : 0|16@1+ (1,0) [0|65535] "V"  PC
 SG_ S2P_Lmt19_Over_DeltUModule2_33 : 16|16@1+ (1,0) [0|65535] "V"  PC
 SG_ S2P_Lmt19_Over_DeltUModule3_33 : 32|16@1+ (1,0) [0|65535] "V"  PC
 SG_ S2P_Lmt19_Over_DeltUModule4_33 : 48|16@1+ (1,0) [0|65535] "mV"  PC

BO_ 2418339426 S2P_Lmt19__34: 8 SBMU
 SG_ S2P_Lmt19_Over_DeltUModule1_34 : 0|16@1+ (1,0) [0|65535] "V"  PC
 SG_ S2P_Lmt19_Over_DeltUModule2_34 : 16|16@1+ (1,0) [0|65535] "V"  PC
 SG_ S2P_Lmt19_Over_DeltUModule3_34 : 32|16@1+ (1,0) [0|65535] "V"  PC
 SG_ S2P_Lmt19_Over_DeltUModule4_34 : 48|16@1+ (1,0) [0|65535] "mV"  PC

BO_ 2418339427 S2P_Lmt19__35: 8 SBMU
 SG_ S2P_Lmt19_Over_DeltUModule1_35 : 0|16@1+ (1,0) [0|65535] "V"  PC
 SG_ S2P_Lmt19_Over_DeltUModule2_35 : 16|16@1+ (1,0) [0|65535] "V"  PC
 SG_ S2P_Lmt19_Over_DeltUModule3_35 : 32|16@1+ (1,0) [0|65535] "V"  PC
 SG_ S2P_Lmt19_Over_DeltUModule4_35 : 48|16@1+ (1,0) [0|65535] "mV"  PC

BO_ 2418339428 S2P_Lmt19__36: 8 SBMU
 SG_ S2P_Lmt19_Over_DeltUModule1_36 : 0|16@1+ (1,0) [0|65535] "V"  PC
 SG_ S2P_Lmt19_Over_DeltUModule2_36 : 16|16@1+ (1,0) [0|65535] "V"  PC
 SG_ S2P_Lmt19_Over_DeltUModule3_36 : 32|16@1+ (1,0) [0|65535] "V"  PC
 SG_ S2P_Lmt19_Over_DeltUModule4_36 : 48|16@1+ (1,0) [0|65535] "mV"  PC

BO_ 2418339429 S2P_Lmt19__37: 8 SBMU
 SG_ S2P_Lmt19_Over_DeltUModule1_37 : 0|16@1+ (1,0) [0|65535] "V"  PC
 SG_ S2P_Lmt19_Over_DeltUModule2_37 : 16|16@1+ (1,0) [0|65535] "V"  PC
 SG_ S2P_Lmt19_Over_DeltUModule3_37 : 32|16@1+ (1,0) [0|65535] "V"  PC
 SG_ S2P_Lmt19_Over_DeltUModule4_37 : 48|16@1+ (1,0) [0|65535] "mV"  PC

BO_ 2418339430 S2P_Lmt19__38: 8 SBMU
 SG_ S2P_Lmt19_Over_DeltUModule1_38 : 0|16@1+ (1,0) [0|65535] "V"  PC
 SG_ S2P_Lmt19_Over_DeltUModule2_38 : 16|16@1+ (1,0) [0|65535] "V"  PC
 SG_ S2P_Lmt19_Over_DeltUModule3_38 : 32|16@1+ (1,0) [0|65535] "V"  PC
 SG_ S2P_Lmt19_Over_DeltUModule4_38 : 48|16@1+ (1,0) [0|65535] "mV"  PC

BO_ 2418339431 S2P_Lmt19__39: 8 SBMU
 SG_ S2P_Lmt19_Over_DeltUModule1_39 : 0|16@1+ (1,0) [0|65535] "V"  PC
 SG_ S2P_Lmt19_Over_DeltUModule2_39 : 16|16@1+ (1,0) [0|65535] "V"  PC
 SG_ S2P_Lmt19_Over_DeltUModule3_39 : 32|16@1+ (1,0) [0|65535] "V"  PC
 SG_ S2P_Lmt19_Over_DeltUModule4_39 : 48|16@1+ (1,0) [0|65535] "mV"  PC

BO_ 2418339432 S2P_Lmt19__40: 8 SBMU
 SG_ S2P_Lmt19_Over_DeltUModule1_40 : 0|16@1+ (1,0) [0|65535] "V"  PC
 SG_ S2P_Lmt19_Over_DeltUModule2_40 : 16|16@1+ (1,0) [0|65535] "V"  PC
 SG_ S2P_Lmt19_Over_DeltUModule3_40 : 32|16@1+ (1,0) [0|65535] "V"  PC
 SG_ S2P_Lmt19_Over_DeltUModule4_40 : 48|16@1+ (1,0) [0|65535] "mV"  PC

BO_ 2418339433 S2P_Lmt19__41: 8 SBMU
 SG_ S2P_Lmt19_Over_DeltUModule1_41 : 0|16@1+ (1,0) [0|65535] "V"  PC
 SG_ S2P_Lmt19_Over_DeltUModule2_41 : 16|16@1+ (1,0) [0|65535] "V"  PC
 SG_ S2P_Lmt19_Over_DeltUModule3_41 : 32|16@1+ (1,0) [0|65535] "V"  PC
 SG_ S2P_Lmt19_Over_DeltUModule4_41 : 48|16@1+ (1,0) [0|65535] "mV"  PC

BO_ 2418339434 S2P_Lmt19__42: 8 SBMU
 SG_ S2P_Lmt19_Over_DeltUModule1_42 : 0|16@1+ (1,0) [0|65535] "V"  PC
 SG_ S2P_Lmt19_Over_DeltUModule2_42 : 16|16@1+ (1,0) [0|65535] "V"  PC
 SG_ S2P_Lmt19_Over_DeltUModule3_42 : 32|16@1+ (1,0) [0|65535] "V"  PC
 SG_ S2P_Lmt19_Over_DeltUModule4_42 : 48|16@1+ (1,0) [0|65535] "mV"  PC

BO_ 2418339435 S2P_Lmt19__43: 8 SBMU
 SG_ S2P_Lmt19_Over_DeltUModule1_43 : 0|16@1+ (1,0) [0|65535] "V"  PC
 SG_ S2P_Lmt19_Over_DeltUModule2_43 : 16|16@1+ (1,0) [0|65535] "V"  PC
 SG_ S2P_Lmt19_Over_DeltUModule3_43 : 32|16@1+ (1,0) [0|65535] "V"  PC
 SG_ S2P_Lmt19_Over_DeltUModule4_43 : 48|16@1+ (1,0) [0|65535] "mV"  PC

BO_ 2418339436 S2P_Lmt19__44: 8 SBMU
 SG_ S2P_Lmt19_Over_DeltUModule1_44 : 0|16@1+ (1,0) [0|65535] "V"  PC
 SG_ S2P_Lmt19_Over_DeltUModule2_44 : 16|16@1+ (1,0) [0|65535] "V"  PC
 SG_ S2P_Lmt19_Over_DeltUModule3_44 : 32|16@1+ (1,0) [0|65535] "V"  PC
 SG_ S2P_Lmt19_Over_DeltUModule4_44 : 48|16@1+ (1,0) [0|65535] "mV"  PC

BO_ 2418339437 S2P_Lmt19__45: 8 SBMU
 SG_ S2P_Lmt19_Over_DeltUModule1_45 : 0|16@1+ (1,0) [0|65535] "V"  PC
 SG_ S2P_Lmt19_Over_DeltUModule2_45 : 16|16@1+ (1,0) [0|65535] "V"  PC
 SG_ S2P_Lmt19_Over_DeltUModule3_45 : 32|16@1+ (1,0) [0|65535] "V"  PC
 SG_ S2P_Lmt19_Over_DeltUModule4_45 : 48|16@1+ (1,0) [0|65535] "mV"  PC

BO_ 2418339438 S2P_Lmt19__46: 8 SBMU
 SG_ S2P_Lmt19_Over_DeltUModule1_46 : 0|16@1+ (1,0) [0|65535] "V"  PC
 SG_ S2P_Lmt19_Over_DeltUModule2_46 : 16|16@1+ (1,0) [0|65535] "V"  PC
 SG_ S2P_Lmt19_Over_DeltUModule3_46 : 32|16@1+ (1,0) [0|65535] "V"  PC
 SG_ S2P_Lmt19_Over_DeltUModule4_46 : 48|16@1+ (1,0) [0|65535] "mV"  PC

BO_ 2418339439 S2P_Lmt19__47: 8 SBMU
 SG_ S2P_Lmt19_Over_DeltUModule1_47 : 0|16@1+ (1,0) [0|65535] "V"  PC
 SG_ S2P_Lmt19_Over_DeltUModule2_47 : 16|16@1+ (1,0) [0|65535] "V"  PC
 SG_ S2P_Lmt19_Over_DeltUModule3_47 : 32|16@1+ (1,0) [0|65535] "V"  PC
 SG_ S2P_Lmt19_Over_DeltUModule4_47 : 48|16@1+ (1,0) [0|65535] "mV"  PC

BO_ 2418339440 S2P_Lmt19__48: 8 SBMU
 SG_ S2P_Lmt19_Over_DeltUModule1_48 : 0|16@1+ (1,0) [0|65535] "V"  PC
 SG_ S2P_Lmt19_Over_DeltUModule2_48 : 16|16@1+ (1,0) [0|65535] "V"  PC
 SG_ S2P_Lmt19_Over_DeltUModule3_48 : 32|16@1+ (1,0) [0|65535] "V"  PC
 SG_ S2P_Lmt19_Over_DeltUModule4_48 : 48|16@1+ (1,0) [0|65535] "mV"  PC

BO_ 2418339441 S2P_Lmt19__49: 8 SBMU
 SG_ S2P_Lmt19_Over_DeltUModule1_49 : 0|16@1+ (1,0) [0|65535] "V"  PC
 SG_ S2P_Lmt19_Over_DeltUModule2_49 : 16|16@1+ (1,0) [0|65535] "V"  PC
 SG_ S2P_Lmt19_Over_DeltUModule3_49 : 32|16@1+ (1,0) [0|65535] "V"  PC
 SG_ S2P_Lmt19_Over_DeltUModule4_49 : 48|16@1+ (1,0) [0|65535] "mV"  PC

BO_ 2418339442 S2P_Lmt19__50: 8 SBMU
 SG_ S2P_Lmt19_Over_DeltUModule1_50 : 0|16@1+ (1,0) [0|65535] "V"  PC
 SG_ S2P_Lmt19_Over_DeltUModule2_50 : 16|16@1+ (1,0) [0|65535] "V"  PC
 SG_ S2P_Lmt19_Over_DeltUModule3_50 : 32|16@1+ (1,0) [0|65535] "V"  PC
 SG_ S2P_Lmt19_Over_DeltUModule4_50 : 48|16@1+ (1,0) [0|65535] "mV"  PC

BO_ 2418339443 S2P_Lmt19__51: 8 SBMU
 SG_ S2P_Lmt19_Over_DeltUModule1_51 : 0|16@1+ (1,0) [0|65535] "V"  PC
 SG_ S2P_Lmt19_Over_DeltUModule2_51 : 16|16@1+ (1,0) [0|65535] "V"  PC
 SG_ S2P_Lmt19_Over_DeltUModule3_51 : 32|16@1+ (1,0) [0|65535] "V"  PC
 SG_ S2P_Lmt19_Over_DeltUModule4_51 : 48|16@1+ (1,0) [0|65535] "mV"  PC

BO_ 2418339444 S2P_Lmt19__52: 8 SBMU
 SG_ S2P_Lmt19_Over_DeltUModule1_52 : 0|16@1+ (1,0) [0|65535] "V"  PC
 SG_ S2P_Lmt19_Over_DeltUModule2_52 : 16|16@1+ (1,0) [0|65535] "V"  PC
 SG_ S2P_Lmt19_Over_DeltUModule3_52 : 32|16@1+ (1,0) [0|65535] "V"  PC
 SG_ S2P_Lmt19_Over_DeltUModule4_52 : 48|16@1+ (1,0) [0|65535] "mV"  PC

BO_ 2418339445 S2P_Lmt19__53: 8 SBMU
 SG_ S2P_Lmt19_Over_DeltUModule1_53 : 0|16@1+ (1,0) [0|65535] "V"  PC
 SG_ S2P_Lmt19_Over_DeltUModule2_53 : 16|16@1+ (1,0) [0|65535] "V"  PC
 SG_ S2P_Lmt19_Over_DeltUModule3_53 : 32|16@1+ (1,0) [0|65535] "V"  PC
 SG_ S2P_Lmt19_Over_DeltUModule4_53 : 48|16@1+ (1,0) [0|65535] "mV"  PC

BO_ 2418339446 S2P_Lmt19__54: 8 SBMU
 SG_ S2P_Lmt19_Over_DeltUModule1_54 : 0|16@1+ (1,0) [0|65535] "V"  PC
 SG_ S2P_Lmt19_Over_DeltUModule2_54 : 16|16@1+ (1,0) [0|65535] "V"  PC
 SG_ S2P_Lmt19_Over_DeltUModule3_54 : 32|16@1+ (1,0) [0|65535] "V"  PC
 SG_ S2P_Lmt19_Over_DeltUModule4_54 : 48|16@1+ (1,0) [0|65535] "mV"  PC

BO_ 2418339447 S2P_Lmt19__55: 8 SBMU
 SG_ S2P_Lmt19_Over_DeltUModule1_55 : 0|16@1+ (1,0) [0|65535] "V"  PC
 SG_ S2P_Lmt19_Over_DeltUModule2_55 : 16|16@1+ (1,0) [0|65535] "V"  PC
 SG_ S2P_Lmt19_Over_DeltUModule3_55 : 32|16@1+ (1,0) [0|65535] "V"  PC
 SG_ S2P_Lmt19_Over_DeltUModule4_55 : 48|16@1+ (1,0) [0|65535] "mV"  PC

BO_ 2418339448 S2P_Lmt19__56: 8 SBMU
 SG_ S2P_Lmt19_Over_DeltUModule1_56 : 0|16@1+ (1,0) [0|65535] "V"  PC
 SG_ S2P_Lmt19_Over_DeltUModule2_56 : 16|16@1+ (1,0) [0|65535] "V"  PC
 SG_ S2P_Lmt19_Over_DeltUModule3_56 : 32|16@1+ (1,0) [0|65535] "V"  PC
 SG_ S2P_Lmt19_Over_DeltUModule4_56 : 48|16@1+ (1,0) [0|65535] "mV"  PC

BO_ 2418339449 S2P_Lmt19__57: 8 SBMU
 SG_ S2P_Lmt19_Over_DeltUModule1_57 : 0|16@1+ (1,0) [0|65535] "V"  PC
 SG_ S2P_Lmt19_Over_DeltUModule2_57 : 16|16@1+ (1,0) [0|65535] "V"  PC
 SG_ S2P_Lmt19_Over_DeltUModule3_57 : 32|16@1+ (1,0) [0|65535] "V"  PC
 SG_ S2P_Lmt19_Over_DeltUModule4_57 : 48|16@1+ (1,0) [0|65535] "mV"  PC

BO_ 2418339450 S2P_Lmt19__58: 8 SBMU
 SG_ S2P_Lmt19_Over_DeltUModule1_58 : 0|16@1+ (1,0) [0|65535] "V"  PC
 SG_ S2P_Lmt19_Over_DeltUModule2_58 : 16|16@1+ (1,0) [0|65535] "V"  PC
 SG_ S2P_Lmt19_Over_DeltUModule3_58 : 32|16@1+ (1,0) [0|65535] "V"  PC
 SG_ S2P_Lmt19_Over_DeltUModule4_58 : 48|16@1+ (1,0) [0|65535] "mV"  PC

BO_ 2418339451 S2P_Lmt19__59: 8 SBMU
 SG_ S2P_Lmt19_Over_DeltUModule1_59 : 0|16@1+ (1,0) [0|65535] "V"  PC
 SG_ S2P_Lmt19_Over_DeltUModule2_59 : 16|16@1+ (1,0) [0|65535] "V"  PC
 SG_ S2P_Lmt19_Over_DeltUModule3_59 : 32|16@1+ (1,0) [0|65535] "V"  PC
 SG_ S2P_Lmt19_Over_DeltUModule4_59 : 48|16@1+ (1,0) [0|65535] "mV"  PC

BO_ 2418339452 S2P_Lmt19__60: 8 SBMU
 SG_ S2P_Lmt19_Over_DeltUModule1_60 : 0|16@1+ (1,0) [0|65535] "V"  PC
 SG_ S2P_Lmt19_Over_DeltUModule2_60 : 16|16@1+ (1,0) [0|65535] "V"  PC
 SG_ S2P_Lmt19_Over_DeltUModule3_60 : 32|16@1+ (1,0) [0|65535] "V"  PC
 SG_ S2P_Lmt19_Over_DeltUModule4_60 : 48|16@1+ (1,0) [0|65535] "mV"  PC

BO_ 2418339453 S2P_Lmt19__61: 8 SBMU
 SG_ S2P_Lmt19_Over_DeltUModule1_61 : 0|16@1+ (1,0) [0|65535] "V"  PC
 SG_ S2P_Lmt19_Over_DeltUModule2_61 : 16|16@1+ (1,0) [0|65535] "V"  PC
 SG_ S2P_Lmt19_Over_DeltUModule3_61 : 32|16@1+ (1,0) [0|65535] "V"  PC
 SG_ S2P_Lmt19_Over_DeltUModule4_61 : 48|16@1+ (1,0) [0|65535] "mV"  PC

BO_ 2418339454 S2P_Lmt19__62: 8 SBMU
 SG_ S2P_Lmt19_Over_DeltUModule1_62 : 0|16@1+ (1,0) [0|65535] "V"  PC
 SG_ S2P_Lmt19_Over_DeltUModule2_62 : 16|16@1+ (1,0) [0|65535] "V"  PC
 SG_ S2P_Lmt19_Over_DeltUModule3_62 : 32|16@1+ (1,0) [0|65535] "V"  PC
 SG_ S2P_Lmt19_Over_DeltUModule4_62 : 48|16@1+ (1,0) [0|65535] "mV"  PC

BO_ 2418339455 S2P_Lmt19__63: 8 SBMU
 SG_ S2P_Lmt19_Over_DeltUModule1_63 : 0|16@1+ (1,0) [0|65535] "V"  PC
 SG_ S2P_Lmt19_Over_DeltUModule2_63 : 16|16@1+ (1,0) [0|65535] "V"  PC
 SG_ S2P_Lmt19_Over_DeltUModule3_63 : 32|16@1+ (1,0) [0|65535] "V"  PC
 SG_ S2P_Lmt19_Over_DeltUModule4_63 : 48|16@1+ (1,0) [0|65535] "mV"  PC

BO_ 2418404929 S2P_Lmt20__01: 8 SBMU
 SG_ S2P_Lmt20_Over_DeltUcell4_01 : 0|16@1+ (1,0) [0|65535] "mV"  PC
 SG_ S2P_Lmt20_Over_DeltTcell4_01 : 16|8@1+ (1,-50) [-50|205] "℃"  PC
 SG_ S2P_Lmt20_Over_Ucell4_01 : 24|16@1+ (1,0) [0|65535] "mV"  PC
 SG_ S2P_Lmt20_Under_Ucell4_01 : 40|16@1+ (1,0) [0|65535] "mV"  PC
 SG_ S2P_Lmt20_Over_Tcell4_01 : 56|8@1+ (1,-50) [-50|205] "℃"  PC

BO_ 2418404930 S2P_Lmt20__02: 8 SBMU
 SG_ S2P_Lmt20_Over_DeltUcell4_02 : 0|16@1+ (1,0) [0|65535] "mV"  PC
 SG_ S2P_Lmt20_Over_DeltTcell4_02 : 16|8@1+ (1,-50) [-50|205] "℃"  PC
 SG_ S2P_Lmt20_Over_Ucell4_02 : 24|16@1+ (1,0) [0|65535] "mV"  PC
 SG_ S2P_Lmt20_Under_Ucell4_02 : 40|16@1+ (1,0) [0|65535] "mV"  PC
 SG_ S2P_Lmt20_Over_Tcell4_02 : 56|8@1+ (1,-50) [-50|205] "℃"  PC

BO_ 2418404931 S2P_Lmt20__03: 8 SBMU
 SG_ S2P_Lmt20_Over_DeltUcell4_03 : 0|16@1+ (1,0) [0|65535] "mV"  PC
 SG_ S2P_Lmt20_Over_DeltTcell4_03 : 16|8@1+ (1,-50) [-50|205] "℃"  PC
 SG_ S2P_Lmt20_Over_Ucell4_03 : 24|16@1+ (1,0) [0|65535] "mV"  PC
 SG_ S2P_Lmt20_Under_Ucell4_03 : 40|16@1+ (1,0) [0|65535] "mV"  PC
 SG_ S2P_Lmt20_Over_Tcell4_03 : 56|8@1+ (1,-50) [-50|205] "℃"  PC

BO_ 2418404932 S2P_Lmt20__04: 8 SBMU
 SG_ S2P_Lmt20_Over_DeltUcell4_04 : 0|16@1+ (1,0) [0|65535] "mV"  PC
 SG_ S2P_Lmt20_Over_DeltTcell4_04 : 16|8@1+ (1,-50) [-50|205] "℃"  PC
 SG_ S2P_Lmt20_Over_Ucell4_04 : 24|16@1+ (1,0) [0|65535] "mV"  PC
 SG_ S2P_Lmt20_Under_Ucell4_04 : 40|16@1+ (1,0) [0|65535] "mV"  PC
 SG_ S2P_Lmt20_Over_Tcell4_04 : 56|8@1+ (1,-50) [-50|205] "℃"  PC

BO_ 2418404933 S2P_Lmt20__05: 8 SBMU
 SG_ S2P_Lmt20_Over_DeltUcell4_05 : 0|16@1+ (1,0) [0|65535] "mV"  PC
 SG_ S2P_Lmt20_Over_DeltTcell4_05 : 16|8@1+ (1,-50) [-50|205] "℃"  PC
 SG_ S2P_Lmt20_Over_Ucell4_05 : 24|16@1+ (1,0) [0|65535] "mV"  PC
 SG_ S2P_Lmt20_Under_Ucell4_05 : 40|16@1+ (1,0) [0|65535] "mV"  PC
 SG_ S2P_Lmt20_Over_Tcell4_05 : 56|8@1+ (1,-50) [-50|205] "℃"  PC

BO_ 2418404934 S2P_Lmt20__06: 8 SBMU
 SG_ S2P_Lmt20_Over_DeltUcell4_06 : 0|16@1+ (1,0) [0|65535] "mV"  PC
 SG_ S2P_Lmt20_Over_DeltTcell4_06 : 16|8@1+ (1,-50) [-50|205] "℃"  PC
 SG_ S2P_Lmt20_Over_Ucell4_06 : 24|16@1+ (1,0) [0|65535] "mV"  PC
 SG_ S2P_Lmt20_Under_Ucell4_06 : 40|16@1+ (1,0) [0|65535] "mV"  PC
 SG_ S2P_Lmt20_Over_Tcell4_06 : 56|8@1+ (1,-50) [-50|205] "℃"  PC

BO_ 2418404935 S2P_Lmt20__07: 8 SBMU
 SG_ S2P_Lmt20_Over_DeltUcell4_07 : 0|16@1+ (1,0) [0|65535] "mV"  PC
 SG_ S2P_Lmt20_Over_DeltTcell4_07 : 16|8@1+ (1,-50) [-50|205] "℃"  PC
 SG_ S2P_Lmt20_Over_Ucell4_07 : 24|16@1+ (1,0) [0|65535] "mV"  PC
 SG_ S2P_Lmt20_Under_Ucell4_07 : 40|16@1+ (1,0) [0|65535] "mV"  PC
 SG_ S2P_Lmt20_Over_Tcell4_07 : 56|8@1+ (1,-50) [-50|205] "℃"  PC

BO_ 2418404936 S2P_Lmt20__08: 8 SBMU
 SG_ S2P_Lmt20_Over_DeltUcell4_08 : 0|16@1+ (1,0) [0|65535] "mV"  PC
 SG_ S2P_Lmt20_Over_DeltTcell4_08 : 16|8@1+ (1,-50) [-50|205] "℃"  PC
 SG_ S2P_Lmt20_Over_Ucell4_08 : 24|16@1+ (1,0) [0|65535] "mV"  PC
 SG_ S2P_Lmt20_Under_Ucell4_08 : 40|16@1+ (1,0) [0|65535] "mV"  PC
 SG_ S2P_Lmt20_Over_Tcell4_08 : 56|8@1+ (1,-50) [-50|205] "℃"  PC

BO_ 2418404937 S2P_Lmt20__09: 8 SBMU
 SG_ S2P_Lmt20_Over_DeltUcell4_09 : 0|16@1+ (1,0) [0|65535] "mV"  PC
 SG_ S2P_Lmt20_Over_DeltTcell4_09 : 16|8@1+ (1,-50) [-50|205] "℃"  PC
 SG_ S2P_Lmt20_Over_Ucell4_09 : 24|16@1+ (1,0) [0|65535] "mV"  PC
 SG_ S2P_Lmt20_Under_Ucell4_09 : 40|16@1+ (1,0) [0|65535] "mV"  PC
 SG_ S2P_Lmt20_Over_Tcell4_09 : 56|8@1+ (1,-50) [-50|205] "℃"  PC

BO_ 2418404938 S2P_Lmt20__10: 8 SBMU
 SG_ S2P_Lmt20_Over_DeltUcell4_10 : 0|16@1+ (1,0) [0|65535] "mV"  PC
 SG_ S2P_Lmt20_Over_DeltTcell4_10 : 16|8@1+ (1,-50) [-50|205] "℃"  PC
 SG_ S2P_Lmt20_Over_Ucell4_10 : 24|16@1+ (1,0) [0|65535] "mV"  PC
 SG_ S2P_Lmt20_Under_Ucell4_10 : 40|16@1+ (1,0) [0|65535] "mV"  PC
 SG_ S2P_Lmt20_Over_Tcell4_10 : 56|8@1+ (1,-50) [-50|205] "℃"  PC

BO_ 2418404939 S2P_Lmt20__11: 8 SBMU
 SG_ S2P_Lmt20_Over_DeltUcell4_11 : 0|16@1+ (1,0) [0|65535] "mV"  PC
 SG_ S2P_Lmt20_Over_DeltTcell4_11 : 16|8@1+ (1,-50) [-50|205] "℃"  PC
 SG_ S2P_Lmt20_Over_Ucell4_11 : 24|16@1+ (1,0) [0|65535] "mV"  PC
 SG_ S2P_Lmt20_Under_Ucell4_11 : 40|16@1+ (1,0) [0|65535] "mV"  PC
 SG_ S2P_Lmt20_Over_Tcell4_11 : 56|8@1+ (1,-50) [-50|205] "℃"  PC

BO_ 2418404940 S2P_Lmt20__12: 8 SBMU
 SG_ S2P_Lmt20_Over_DeltUcell4_12 : 0|16@1+ (1,0) [0|65535] "mV"  PC
 SG_ S2P_Lmt20_Over_DeltTcell4_12 : 16|8@1+ (1,-50) [-50|205] "℃"  PC
 SG_ S2P_Lmt20_Over_Ucell4_12 : 24|16@1+ (1,0) [0|65535] "mV"  PC
 SG_ S2P_Lmt20_Under_Ucell4_12 : 40|16@1+ (1,0) [0|65535] "mV"  PC
 SG_ S2P_Lmt20_Over_Tcell4_12 : 56|8@1+ (1,-50) [-50|205] "℃"  PC

BO_ 2418404941 S2P_Lmt20__13: 8 SBMU
 SG_ S2P_Lmt20_Over_DeltUcell4_13 : 0|16@1+ (1,0) [0|65535] "mV"  PC
 SG_ S2P_Lmt20_Over_DeltTcell4_13 : 16|8@1+ (1,-50) [-50|205] "℃"  PC
 SG_ S2P_Lmt20_Over_Ucell4_13 : 24|16@1+ (1,0) [0|65535] "mV"  PC
 SG_ S2P_Lmt20_Under_Ucell4_13 : 40|16@1+ (1,0) [0|65535] "mV"  PC
 SG_ S2P_Lmt20_Over_Tcell4_13 : 56|8@1+ (1,-50) [-50|205] "℃"  PC

BO_ 2418404942 S2P_Lmt20__14: 8 SBMU
 SG_ S2P_Lmt20_Over_DeltUcell4_14 : 0|16@1+ (1,0) [0|65535] "mV"  PC
 SG_ S2P_Lmt20_Over_DeltTcell4_14 : 16|8@1+ (1,-50) [-50|205] "℃"  PC
 SG_ S2P_Lmt20_Over_Ucell4_14 : 24|16@1+ (1,0) [0|65535] "mV"  PC
 SG_ S2P_Lmt20_Under_Ucell4_14 : 40|16@1+ (1,0) [0|65535] "mV"  PC
 SG_ S2P_Lmt20_Over_Tcell4_14 : 56|8@1+ (1,-50) [-50|205] "℃"  PC

BO_ 2418404943 S2P_Lmt20__15: 8 SBMU
 SG_ S2P_Lmt20_Over_DeltUcell4_15 : 0|16@1+ (1,0) [0|65535] "mV"  PC
 SG_ S2P_Lmt20_Over_DeltTcell4_15 : 16|8@1+ (1,-50) [-50|205] "℃"  PC
 SG_ S2P_Lmt20_Over_Ucell4_15 : 24|16@1+ (1,0) [0|65535] "mV"  PC
 SG_ S2P_Lmt20_Under_Ucell4_15 : 40|16@1+ (1,0) [0|65535] "mV"  PC
 SG_ S2P_Lmt20_Over_Tcell4_15 : 56|8@1+ (1,-50) [-50|205] "℃"  PC

CM_ SG_ 2400841343 CSC_U_No_63 "CSC号";
CM_ SG_ 2400841343 CSC_Ucell_Frame_Index_63 "当前CSC中单体电压数据帧序号";
CM_ SG_ 2400841343 CSC_Ucell_58_63 "58 电池单体电压";
CM_ SG_ 2400841343 CSC_Ucell_59_63 "59 电池单体电压";
CM_ SG_ 2400841343 CSC_Ucell_60_63 "60 电池单体电压";
CM_ SG_ 2400841343 CSC_Ucell_61_63 "61 电池单体电压";
CM_ SG_ 2400841343 CSC_Ucell_62_63 "62 电池单体电压";
CM_ SG_ 2400841343 CSC_Ucell_63_63 "63 电池单体电压";
CM_ SG_ 2400841343 CSC_Ucell_64_63 "64 电池单体电压";
CM_ SG_ 2400841343 CSC_Ucell_65_63 "65 电池单体电压";
CM_ SG_ 2400841343 CSC_Ucell_66_63 "66 电池单体电压";
CM_ SG_ 2400841343 CSC_Ucell_67_63 "67 电池单体电压";
CM_ SG_ 2400841343 CSC_Ucell_68_63 "68 电池单体电压";
CM_ SG_ 2400841343 CSC_Ucell_69_63 "69 电池单体电压";
CM_ SG_ 2400841343 CSC_Ucell_70_63 "70 电池单体电压";
CM_ SG_ 2400841343 CSC_Ucell_71_63 "71 电池单体电压";
CM_ SG_ 2400841343 CSC_Ucell_72_63 "72 电池单体电压";
CM_ SG_ 2400841343 CSC_Ucell_73_63 "73 电池单体电压";
CM_ SG_ 2400841343 CSC_Ucell_74_63 "74 电池单体电压";
CM_ SG_ 2400841343 CSC_Ucell_75_63 "75 电池单体电压";
CM_ SG_ 2400841343 CSC_Ucell_76_63 "76 电池单体电压";
CM_ SG_ 2400841343 CSC_Ucell_77_63 "77 电池单体电压";
CM_ SG_ 2400841343 CSC_Ucell_78_63 "78 电池单体电压";
CM_ SG_ 2400841343 CSC_Ucell_79_63 "79 电池单体电压";
CM_ SG_ 2400841343 CSC_Ucell_80_63 "80 电池单体电压";
CM_ SG_ 2400841343 CSC_Ucell_81_63 "81 电池单体电压";
CM_ SG_ 2400841343 CSC_Ucell_82_63 "82 电池单体电压";
CM_ SG_ 2400841343 CSC_Ucell_83_63 "83 电池单体电压";
CM_ SG_ 2400841343 CSC_Ucell_84_63 "84 电池单体电压";
CM_ SG_ 2400841343 CSC_Ucell_85_63 "85 电池单体电压";
CM_ SG_ 2400841343 CSC_Ucell_86_63 "86 电池单体电压";
CM_ SG_ 2400841343 CSC_Ucell_87_63 "87 电池单体电压";
CM_ SG_ 2400841343 CSC_Ucell_88_63 "88 电池单体电压";
CM_ SG_ 2400841343 CSC_Ucell_89_63 "89 电池单体电压";
CM_ SG_ 2400841343 CSC_Ucell_90_63 "90 电池单体电压";
CM_ SG_ 2400841343 CSC_Ucell_91_63 "91 电池单体电压";
CM_ SG_ 2400841343 CSC_Ucell_92_63 "92 电池单体电压";
CM_ SG_ 2400841343 CSC_Ucell_93_63 "93 电池单体电压";
CM_ SG_ 2400841343 CSC_Ucell_94_63 "94 电池单体电压";
CM_ SG_ 2400841343 CSC_Ucell_95_63 "95 电池单体电压";
CM_ SG_ 2400841343 CSC_Ucell_96_63 "96 电池单体电压";
CM_ SG_ 2400841343 CSC_Ucell_97_63 "97 电池单体电压";
CM_ SG_ 2400841343 CSC_Ucell_98_63 "98 电池单体电压";
CM_ SG_ 2400841343 CSC_Ucell_99_63 "99 电池单体电压";
CM_ SG_ 2400841343 CSC_Ucell_100_63 "100 电池单体电压";
CM_ SG_ 2400841343 CSC_Ucell_101_63 "101 电池单体电压";
CM_ SG_ 2400841343 CSC_Ucell_102_63 "102 电池单体电压";
CM_ SG_ 2400841343 CSC_Ucell_103_63 "103 电池单体电压";
CM_ SG_ 2400841343 CSC_Ucell_104_63 "104 电池单体电压";
CM_ SG_ 2400841343 CSC_Ucell_105_63 "105 电池单体电压";
CM_ SG_ 2400841343 CSC_Ucell_106_63 "106 电池单体电压";
CM_ SG_ 2400841343 CSC_Ucell_107_63 "107 电池单体电压";
CM_ SG_ 2400841343 CSC_Ucell_108_63 "108 电池单体电压";
CM_ SG_ 2401300033 CSC_B_No_104s_1_01 "CSC号";
CM_ SG_ 2401300033 BalDchg_PosCell_1_01 "放电均衡电芯位置(填充前54个去空CELL)";
CM_ SG_ 2401300033 State_Balance_Status_1_01 "均衡状态";
CM_ SG_ 2401300033 State_Balance_Fault_1_01 "均衡关闭故障";
CM_ SG_ 2401300034 CSC_B_No_104s_1_02 "CSC号";
CM_ SG_ 2401300034 BalDchg_PosCell_1_02 "放电均衡电芯位置(填充前54个去空CELL)";
CM_ SG_ 2401300034 State_Balance_Status_1_02 "均衡状态";
CM_ SG_ 2401300034 State_Balance_Fault_1_02 "均衡关闭故障";
CM_ SG_ 2401300035 CSC_B_No_104s_1_03 "CSC号";
CM_ SG_ 2401300035 BalDchg_PosCell_1_03 "放电均衡电芯位置(填充前54个去空CELL)";
CM_ SG_ 2401300035 State_Balance_Status_1_03 "均衡状态";
CM_ SG_ 2401300035 State_Balance_Fault_1_03 "均衡关闭故障";
CM_ SG_ 2401300036 CSC_B_No_104s_1_04 "CSC号";
CM_ SG_ 2401300036 BalDchg_PosCell_1_04 "放电均衡电芯位置(填充前54个去空CELL)";
CM_ SG_ 2401300036 State_Balance_Status_1_04 "均衡状态";
CM_ SG_ 2401300036 State_Balance_Fault_1_04 "均衡关闭故障";
CM_ SG_ 2401300037 CSC_B_No_104s_1_05 "CSC号";
CM_ SG_ 2401300037 BalDchg_PosCell_1_05 "放电均衡电芯位置(填充前54个去空CELL)";
CM_ SG_ 2401300037 State_Balance_Status_1_05 "均衡状态";
CM_ SG_ 2401300037 State_Balance_Fault_1_05 "均衡关闭故障";
CM_ SG_ 2401300038 CSC_B_No_104s_1_06 "CSC号";
CM_ SG_ 2401300038 BalDchg_PosCell_1_06 "放电均衡电芯位置(填充前54个去空CELL)";
CM_ SG_ 2401300038 State_Balance_Status_1_06 "均衡状态";
CM_ SG_ 2401300038 State_Balance_Fault_1_06 "均衡关闭故障";
CM_ SG_ 2401300039 CSC_B_No_104s_1_07 "CSC号";
CM_ SG_ 2401300039 BalDchg_PosCell_1_07 "放电均衡电芯位置(填充前54个去空CELL)";
CM_ SG_ 2401300039 State_Balance_Status_1_07 "均衡状态";
CM_ SG_ 2401300039 State_Balance_Fault_1_07 "均衡关闭故障";
CM_ SG_ 2401300040 CSC_B_No_104s_1_08 "CSC号";
CM_ SG_ 2401300040 BalDchg_PosCell_1_08 "放电均衡电芯位置(填充前54个去空CELL)";
CM_ SG_ 2401300040 State_Balance_Status_1_08 "均衡状态";
CM_ SG_ 2401300040 State_Balance_Fault_1_08 "均衡关闭故障";
CM_ SG_ 2401300041 CSC_B_No_104s_1_09 "CSC号";
CM_ SG_ 2401300041 BalDchg_PosCell_1_09 "放电均衡电芯位置(填充前54个去空CELL)";
CM_ SG_ 2401300041 State_Balance_Status_1_09 "均衡状态";
CM_ SG_ 2401300041 State_Balance_Fault_1_09 "均衡关闭故障";
CM_ SG_ 2401300042 CSC_B_No_104s_1_10 "CSC号";
CM_ SG_ 2401300042 BalDchg_PosCell_1_10 "放电均衡电芯位置(填充前54个去空CELL)";
CM_ SG_ 2401300042 State_Balance_Status_1_10 "均衡状态";
CM_ SG_ 2401300042 State_Balance_Fault_1_10 "均衡关闭故障";
CM_ SG_ 2401300043 CSC_B_No_104s_1_11 "CSC号";
CM_ SG_ 2401300043 BalDchg_PosCell_1_11 "放电均衡电芯位置(填充前54个去空CELL)";
CM_ SG_ 2401300043 State_Balance_Status_1_11 "均衡状态";
CM_ SG_ 2401300043 State_Balance_Fault_1_11 "均衡关闭故障";
CM_ SG_ 2401300044 CSC_B_No_104s_1_12 "CSC号";
CM_ SG_ 2401300044 BalDchg_PosCell_1_12 "放电均衡电芯位置(填充前54个去空CELL)";
CM_ SG_ 2401300044 State_Balance_Status_1_12 "均衡状态";
CM_ SG_ 2401300044 State_Balance_Fault_1_12 "均衡关闭故障";
CM_ SG_ 2401300045 CSC_B_No_104s_1_13 "CSC号";
CM_ SG_ 2401300045 BalDchg_PosCell_1_13 "放电均衡电芯位置(填充前54个去空CELL)";
CM_ SG_ 2401300045 State_Balance_Status_1_13 "均衡状态";
CM_ SG_ 2401300045 State_Balance_Fault_1_13 "均衡关闭故障";
CM_ SG_ 2401300046 CSC_B_No_104s_1_14 "CSC号";
CM_ SG_ 2401300046 BalDchg_PosCell_1_14 "放电均衡电芯位置(填充前54个去空CELL)";
CM_ SG_ 2401300046 State_Balance_Status_1_14 "均衡状态";
CM_ SG_ 2401300046 State_Balance_Fault_1_14 "均衡关闭故障";
CM_ SG_ 2401300047 CSC_B_No_104s_1_15 "CSC号";
CM_ SG_ 2401300047 BalDchg_PosCell_1_15 "放电均衡电芯位置(填充前54个去空CELL)";
CM_ SG_ 2401300047 State_Balance_Status_1_15 "均衡状态";
CM_ SG_ 2401300047 State_Balance_Fault_1_15 "均衡关闭故障";
CM_ SG_ 2401300048 CSC_B_No_104s_1_16 "CSC号";
CM_ SG_ 2401300048 BalDchg_PosCell_1_16 "放电均衡电芯位置(填充前54个去空CELL)";
CM_ SG_ 2401300048 State_Balance_Status_1_16 "均衡状态";
CM_ SG_ 2401300048 State_Balance_Fault_1_16 "均衡关闭故障";
CM_ SG_ 2401300049 CSC_B_No_104s_1_17 "CSC号";
CM_ SG_ 2401300049 BalDchg_PosCell_1_17 "放电均衡电芯位置(填充前54个去空CELL)";
CM_ SG_ 2401300049 State_Balance_Status_1_17 "均衡状态";
CM_ SG_ 2401300049 State_Balance_Fault_1_17 "均衡关闭故障";
CM_ SG_ 2401300050 CSC_B_No_104s_1_18 "CSC号";
CM_ SG_ 2401300050 BalDchg_PosCell_1_18 "放电均衡电芯位置(填充前54个去空CELL)";
CM_ SG_ 2401300050 State_Balance_Status_1_18 "均衡状态";
CM_ SG_ 2401300050 State_Balance_Fault_1_18 "均衡关闭故障";
CM_ SG_ 2401300051 CSC_B_No_104s_1_19 "CSC号";
CM_ SG_ 2401300051 BalDchg_PosCell_1_19 "放电均衡电芯位置(填充前54个去空CELL)";
CM_ SG_ 2401300051 State_Balance_Status_1_19 "均衡状态";
CM_ SG_ 2401300051 State_Balance_Fault_1_19 "均衡关闭故障";
CM_ SG_ 2401300052 CSC_B_No_104s_1_20 "CSC号";
CM_ SG_ 2401300052 BalDchg_PosCell_1_20 "放电均衡电芯位置(填充前54个去空CELL)";
CM_ SG_ 2401300052 State_Balance_Status_1_20 "均衡状态";
CM_ SG_ 2401300052 State_Balance_Fault_1_20 "均衡关闭故障";
CM_ SG_ 2401300053 CSC_B_No_104s_1_21 "CSC号";
CM_ SG_ 2401300053 BalDchg_PosCell_1_21 "放电均衡电芯位置(填充前54个去空CELL)";
CM_ SG_ 2401300053 State_Balance_Status_1_21 "均衡状态";
CM_ SG_ 2401300053 State_Balance_Fault_1_21 "均衡关闭故障";
CM_ SG_ 2401300054 CSC_B_No_104s_1_22 "CSC号";
CM_ SG_ 2401300054 BalDchg_PosCell_1_22 "放电均衡电芯位置(填充前54个去空CELL)";
CM_ SG_ 2401300054 State_Balance_Status_1_22 "均衡状态";
CM_ SG_ 2401300054 State_Balance_Fault_1_22 "均衡关闭故障";
CM_ SG_ 2401300055 CSC_B_No_104s_1_23 "CSC号";
CM_ SG_ 2401300055 BalDchg_PosCell_1_23 "放电均衡电芯位置(填充前54个去空CELL)";
CM_ SG_ 2401300055 State_Balance_Status_1_23 "均衡状态";
CM_ SG_ 2401300055 State_Balance_Fault_1_23 "均衡关闭故障";
CM_ SG_ 2401300056 CSC_B_No_104s_1_24 "CSC号";
CM_ SG_ 2401300056 BalDchg_PosCell_1_24 "放电均衡电芯位置(填充前54个去空CELL)";
CM_ SG_ 2401300056 State_Balance_Status_1_24 "均衡状态";
CM_ SG_ 2401300056 State_Balance_Fault_1_24 "均衡关闭故障";
CM_ SG_ 2401300057 CSC_B_No_104s_1_25 "CSC号";
CM_ SG_ 2401300057 BalDchg_PosCell_1_25 "放电均衡电芯位置(填充前54个去空CELL)";
CM_ SG_ 2401300057 State_Balance_Status_1_25 "均衡状态";
CM_ SG_ 2401300057 State_Balance_Fault_1_25 "均衡关闭故障";
CM_ SG_ 2401300058 CSC_B_No_104s_1_26 "CSC号";
CM_ SG_ 2401300058 BalDchg_PosCell_1_26 "放电均衡电芯位置(填充前54个去空CELL)";
CM_ SG_ 2401300058 State_Balance_Status_1_26 "均衡状态";
CM_ SG_ 2401300058 State_Balance_Fault_1_26 "均衡关闭故障";
CM_ SG_ 2401300059 CSC_B_No_104s_1_27 "CSC号";
CM_ SG_ 2401300059 BalDchg_PosCell_1_27 "放电均衡电芯位置(填充前54个去空CELL)";
CM_ SG_ 2401300059 State_Balance_Status_1_27 "均衡状态";
CM_ SG_ 2401300059 State_Balance_Fault_1_27 "均衡关闭故障";
CM_ SG_ 2401300060 CSC_B_No_104s_1_28 "CSC号";
CM_ SG_ 2401300060 BalDchg_PosCell_1_28 "放电均衡电芯位置(填充前54个去空CELL)";
CM_ SG_ 2401300060 State_Balance_Status_1_28 "均衡状态";
CM_ SG_ 2401300060 State_Balance_Fault_1_28 "均衡关闭故障";
CM_ SG_ 2401300061 CSC_B_No_104s_1_29 "CSC号";
CM_ SG_ 2401300061 BalDchg_PosCell_1_29 "放电均衡电芯位置(填充前54个去空CELL)";
CM_ SG_ 2401300061 State_Balance_Status_1_29 "均衡状态";
CM_ SG_ 2401300061 State_Balance_Fault_1_29 "均衡关闭故障";
CM_ SG_ 2401300062 CSC_B_No_104s_1_30 "CSC号";
CM_ SG_ 2401300062 BalDchg_PosCell_1_30 "放电均衡电芯位置(填充前54个去空CELL)";
CM_ SG_ 2401300062 State_Balance_Status_1_30 "均衡状态";
CM_ SG_ 2401300062 State_Balance_Fault_1_30 "均衡关闭故障";
CM_ SG_ 2401300063 CSC_B_No_104s_1_31 "CSC号";
CM_ SG_ 2401300063 BalDchg_PosCell_1_31 "放电均衡电芯位置(填充前54个去空CELL)";
CM_ SG_ 2401300063 State_Balance_Status_1_31 "均衡状态";
CM_ SG_ 2401300063 State_Balance_Fault_1_31 "均衡关闭故障";
CM_ SG_ 2401300064 CSC_B_No_104s_1_32 "CSC号";
CM_ SG_ 2401300064 BalDchg_PosCell_1_32 "放电均衡电芯位置(填充前54个去空CELL)";
CM_ SG_ 2401300064 State_Balance_Status_1_32 "均衡状态";
CM_ SG_ 2401300064 State_Balance_Fault_1_32 "均衡关闭故障";
CM_ SG_ 2401300065 CSC_B_No_104s_1_33 "CSC号";
CM_ SG_ 2401300065 BalDchg_PosCell_1_33 "放电均衡电芯位置(填充前54个去空CELL)";
CM_ SG_ 2401300065 State_Balance_Status_1_33 "均衡状态";
CM_ SG_ 2401300065 State_Balance_Fault_1_33 "均衡关闭故障";
CM_ SG_ 2401300066 CSC_B_No_104s_1_34 "CSC号";
CM_ SG_ 2401300066 BalDchg_PosCell_1_34 "放电均衡电芯位置(填充前54个去空CELL)";
CM_ SG_ 2401300066 State_Balance_Status_1_34 "均衡状态";
CM_ SG_ 2401300066 State_Balance_Fault_1_34 "均衡关闭故障";
CM_ SG_ 2401300067 CSC_B_No_104s_1_35 "CSC号";
CM_ SG_ 2401300067 BalDchg_PosCell_1_35 "放电均衡电芯位置(填充前54个去空CELL)";
CM_ SG_ 2401300067 State_Balance_Status_1_35 "均衡状态";
CM_ SG_ 2401300067 State_Balance_Fault_1_35 "均衡关闭故障";
CM_ SG_ 2401300068 CSC_B_No_104s_1_36 "CSC号";
CM_ SG_ 2401300068 BalDchg_PosCell_1_36 "放电均衡电芯位置(填充前54个去空CELL)";
CM_ SG_ 2401300068 State_Balance_Status_1_36 "均衡状态";
CM_ SG_ 2401300068 State_Balance_Fault_1_36 "均衡关闭故障";
CM_ SG_ 2401300069 CSC_B_No_104s_1_37 "CSC号";
CM_ SG_ 2401300069 BalDchg_PosCell_1_37 "放电均衡电芯位置(填充前54个去空CELL)";
CM_ SG_ 2401300069 State_Balance_Status_1_37 "均衡状态";
CM_ SG_ 2401300069 State_Balance_Fault_1_37 "均衡关闭故障";
CM_ SG_ 2401300070 CSC_B_No_104s_1_38 "CSC号";
CM_ SG_ 2401300070 BalDchg_PosCell_1_38 "放电均衡电芯位置(填充前54个去空CELL)";
CM_ SG_ 2401300070 State_Balance_Status_1_38 "均衡状态";
CM_ SG_ 2401300070 State_Balance_Fault_1_38 "均衡关闭故障";
CM_ SG_ 2401300071 CSC_B_No_104s_1_39 "CSC号";
CM_ SG_ 2401300071 BalDchg_PosCell_1_39 "放电均衡电芯位置(填充前54个去空CELL)";
CM_ SG_ 2401300071 State_Balance_Status_1_39 "均衡状态";
CM_ SG_ 2401300071 State_Balance_Fault_1_39 "均衡关闭故障";
CM_ SG_ 2401300072 CSC_B_No_104s_1_40 "CSC号";
CM_ SG_ 2401300072 BalDchg_PosCell_1_40 "放电均衡电芯位置(填充前54个去空CELL)";
CM_ SG_ 2401300072 State_Balance_Status_1_40 "均衡状态";
CM_ SG_ 2401300072 State_Balance_Fault_1_40 "均衡关闭故障";
CM_ SG_ 2401300073 CSC_B_No_104s_1_41 "CSC号";
CM_ SG_ 2401300073 BalDchg_PosCell_1_41 "放电均衡电芯位置(填充前54个去空CELL)";
CM_ SG_ 2401300073 State_Balance_Status_1_41 "均衡状态";
CM_ SG_ 2401300073 State_Balance_Fault_1_41 "均衡关闭故障";
CM_ SG_ 2401300074 CSC_B_No_104s_1_42 "CSC号";
CM_ SG_ 2401300074 BalDchg_PosCell_1_42 "放电均衡电芯位置(填充前54个去空CELL)";
CM_ SG_ 2401300074 State_Balance_Status_1_42 "均衡状态";
CM_ SG_ 2401300074 State_Balance_Fault_1_42 "均衡关闭故障";
CM_ SG_ 2401300075 CSC_B_No_104s_1_43 "CSC号";
CM_ SG_ 2401300075 BalDchg_PosCell_1_43 "放电均衡电芯位置(填充前54个去空CELL)";
CM_ SG_ 2401300075 State_Balance_Status_1_43 "均衡状态";
CM_ SG_ 2401300075 State_Balance_Fault_1_43 "均衡关闭故障";
CM_ SG_ 2401300076 CSC_B_No_104s_1_44 "CSC号";
CM_ SG_ 2401300076 BalDchg_PosCell_1_44 "放电均衡电芯位置(填充前54个去空CELL)";
CM_ SG_ 2401300076 State_Balance_Status_1_44 "均衡状态";
CM_ SG_ 2401300076 State_Balance_Fault_1_44 "均衡关闭故障";
CM_ SG_ 2401300077 CSC_B_No_104s_1_45 "CSC号";
CM_ SG_ 2401300077 BalDchg_PosCell_1_45 "放电均衡电芯位置(填充前54个去空CELL)";
CM_ SG_ 2401300077 State_Balance_Status_1_45 "均衡状态";
CM_ SG_ 2401300077 State_Balance_Fault_1_45 "均衡关闭故障";
CM_ SG_ 2401300078 CSC_B_No_104s_1_46 "CSC号";
CM_ SG_ 2401300078 BalDchg_PosCell_1_46 "放电均衡电芯位置(填充前54个去空CELL)";
CM_ SG_ 2401300078 State_Balance_Status_1_46 "均衡状态";
CM_ SG_ 2401300078 State_Balance_Fault_1_46 "均衡关闭故障";
CM_ SG_ 2401300079 CSC_B_No_104s_1_47 "CSC号";
CM_ SG_ 2401300079 BalDchg_PosCell_1_47 "放电均衡电芯位置(填充前54个去空CELL)";
CM_ SG_ 2401300079 State_Balance_Status_1_47 "均衡状态";
CM_ SG_ 2401300079 State_Balance_Fault_1_47 "均衡关闭故障";
CM_ SG_ 2401300080 CSC_B_No_104s_1_48 "CSC号";
CM_ SG_ 2401300080 BalDchg_PosCell_1_48 "放电均衡电芯位置(填充前54个去空CELL)";
CM_ SG_ 2401300080 State_Balance_Status_1_48 "均衡状态";
CM_ SG_ 2401300080 State_Balance_Fault_1_48 "均衡关闭故障";
CM_ SG_ 2401300081 CSC_B_No_104s_1_49 "CSC号";
CM_ SG_ 2401300081 BalDchg_PosCell_1_49 "放电均衡电芯位置(填充前54个去空CELL)";
CM_ SG_ 2401300081 State_Balance_Status_1_49 "均衡状态";
CM_ SG_ 2401300081 State_Balance_Fault_1_49 "均衡关闭故障";
CM_ SG_ 2401300082 CSC_B_No_104s_1_50 "CSC号";
CM_ SG_ 2401300082 BalDchg_PosCell_1_50 "放电均衡电芯位置(填充前54个去空CELL)";
CM_ SG_ 2401300082 State_Balance_Status_1_50 "均衡状态";
CM_ SG_ 2401300082 State_Balance_Fault_1_50 "均衡关闭故障";
CM_ SG_ 2401300083 CSC_B_No_104s_1_51 "CSC号";
CM_ SG_ 2401300083 BalDchg_PosCell_1_51 "放电均衡电芯位置(填充前54个去空CELL)";
CM_ SG_ 2401300083 State_Balance_Status_1_51 "均衡状态";
CM_ SG_ 2401300083 State_Balance_Fault_1_51 "均衡关闭故障";
CM_ SG_ 2401300084 CSC_B_No_104s_1_52 "CSC号";
CM_ SG_ 2401300084 BalDchg_PosCell_1_52 "放电均衡电芯位置(填充前54个去空CELL)";
CM_ SG_ 2401300084 State_Balance_Status_1_52 "均衡状态";
CM_ SG_ 2401300084 State_Balance_Fault_1_52 "均衡关闭故障";
CM_ SG_ 2401300085 CSC_B_No_104s_1_53 "CSC号";
CM_ SG_ 2401300085 BalDchg_PosCell_1_53 "放电均衡电芯位置(填充前54个去空CELL)";
CM_ SG_ 2401300085 State_Balance_Status_1_53 "均衡状态";
CM_ SG_ 2401300085 State_Balance_Fault_1_53 "均衡关闭故障";
CM_ SG_ 2401300086 CSC_B_No_104s_1_54 "CSC号";
CM_ SG_ 2401300086 BalDchg_PosCell_1_54 "放电均衡电芯位置(填充前54个去空CELL)";
CM_ SG_ 2401300086 State_Balance_Status_1_54 "均衡状态";
CM_ SG_ 2401300086 State_Balance_Fault_1_54 "均衡关闭故障";
CM_ SG_ 2401300087 CSC_B_No_104s_1_55 "CSC号";
CM_ SG_ 2401300087 BalDchg_PosCell_1_55 "放电均衡电芯位置(填充前54个去空CELL)";
CM_ SG_ 2401300087 State_Balance_Status_1_55 "均衡状态";
CM_ SG_ 2401300087 State_Balance_Fault_1_55 "均衡关闭故障";
CM_ SG_ 2401300088 CSC_B_No_104s_1_56 "CSC号";
CM_ SG_ 2401300088 BalDchg_PosCell_1_56 "放电均衡电芯位置(填充前54个去空CELL)";
CM_ SG_ 2401300088 State_Balance_Status_1_56 "均衡状态";
CM_ SG_ 2401300088 State_Balance_Fault_1_56 "均衡关闭故障";
CM_ SG_ 2401300089 CSC_B_No_104s_1_57 "CSC号";
CM_ SG_ 2401300089 BalDchg_PosCell_1_57 "放电均衡电芯位置(填充前54个去空CELL)";
CM_ SG_ 2401300089 State_Balance_Status_1_57 "均衡状态";
CM_ SG_ 2401300089 State_Balance_Fault_1_57 "均衡关闭故障";
CM_ SG_ 2401300090 CSC_B_No_104s_1_58 "CSC号";
CM_ SG_ 2401300090 BalDchg_PosCell_1_58 "放电均衡电芯位置(填充前54个去空CELL)";
CM_ SG_ 2401300090 State_Balance_Status_1_58 "均衡状态";
CM_ SG_ 2401300090 State_Balance_Fault_1_58 "均衡关闭故障";
CM_ SG_ 2401300091 CSC_B_No_104s_1_59 "CSC号";
CM_ SG_ 2401300091 BalDchg_PosCell_1_59 "放电均衡电芯位置(填充前54个去空CELL)";
CM_ SG_ 2401300091 State_Balance_Status_1_59 "均衡状态";
CM_ SG_ 2401300091 State_Balance_Fault_1_59 "均衡关闭故障";
CM_ SG_ 2401300092 CSC_B_No_104s_1_60 "CSC号";
CM_ SG_ 2401300092 BalDchg_PosCell_1_60 "放电均衡电芯位置(填充前54个去空CELL)";
CM_ SG_ 2401300092 State_Balance_Status_1_60 "均衡状态";
CM_ SG_ 2401300092 State_Balance_Fault_1_60 "均衡关闭故障";
CM_ SG_ 2401300093 CSC_B_No_104s_1_61 "CSC号";
CM_ SG_ 2401300093 BalDchg_PosCell_1_61 "放电均衡电芯位置(填充前54个去空CELL)";
CM_ SG_ 2401300093 State_Balance_Status_1_61 "均衡状态";
CM_ SG_ 2401300093 State_Balance_Fault_1_61 "均衡关闭故障";
CM_ SG_ 2401300094 CSC_B_No_104s_1_62 "CSC号";
CM_ SG_ 2401300094 BalDchg_PosCell_1_62 "放电均衡电芯位置(填充前54个去空CELL)";
CM_ SG_ 2401300094 State_Balance_Status_1_62 "均衡状态";
CM_ SG_ 2401300094 State_Balance_Fault_1_62 "均衡关闭故障";
CM_ SG_ 2401300095 CSC_B_No_104s_1_63 "CSC号";
CM_ SG_ 2401300095 BalDchg_PosCell_1_63 "放电均衡电芯位置(填充前54个去空CELL)";
CM_ SG_ 2401300095 State_Balance_Status_1_63 "均衡状态";
CM_ SG_ 2401300095 State_Balance_Fault_1_63 "均衡关闭故障";
CM_ SG_ 2401365569 CSC_B_No_104s_2_01 "CSC号";
CM_ SG_ 2401365569 BalDchg_PosCell_2_01 "放电均衡电芯位置(填充前54个去空CELL)";
CM_ SG_ 2401365569 State_Balance_Status_2_01 "均衡状态";
CM_ SG_ 2401365569 State_Balance_Fault_2_01 "均衡关闭故障";
CM_ SG_ 2401365570 CSC_B_No_104s_2_02 "CSC号";
CM_ SG_ 2401365570 BalDchg_PosCell_2_02 "放电均衡电芯位置(填充前54个去空CELL)";
CM_ SG_ 2401365570 State_Balance_Status_2_02 "均衡状态";
CM_ SG_ 2401365570 State_Balance_Fault_2_02 "均衡关闭故障";
CM_ SG_ 2401365571 CSC_B_No_104s_2_03 "CSC号";
CM_ SG_ 2401365571 BalDchg_PosCell_2_03 "放电均衡电芯位置(填充前54个去空CELL)";
CM_ SG_ 2401365571 State_Balance_Status_2_03 "均衡状态";
CM_ SG_ 2401365571 State_Balance_Fault_2_03 "均衡关闭故障";
CM_ SG_ 2401365572 CSC_B_No_104s_2_04 "CSC号";
CM_ SG_ 2401365572 BalDchg_PosCell_2_04 "放电均衡电芯位置(填充前54个去空CELL)";
CM_ SG_ 2401365572 State_Balance_Status_2_04 "均衡状态";
CM_ SG_ 2401365572 State_Balance_Fault_2_04 "均衡关闭故障";
CM_ SG_ 2401365573 CSC_B_No_104s_2_05 "CSC号";
CM_ SG_ 2401365573 BalDchg_PosCell_2_05 "放电均衡电芯位置(填充前54个去空CELL)";
CM_ SG_ 2401365573 State_Balance_Status_2_05 "均衡状态";
CM_ SG_ 2401365573 State_Balance_Fault_2_05 "均衡关闭故障";
CM_ SG_ 2401365574 CSC_B_No_104s_2_06 "CSC号";
CM_ SG_ 2401365574 BalDchg_PosCell_2_06 "放电均衡电芯位置(填充前54个去空CELL)";
CM_ SG_ 2401365574 State_Balance_Status_2_06 "均衡状态";
CM_ SG_ 2401365574 State_Balance_Fault_2_06 "均衡关闭故障";
CM_ SG_ 2401365575 CSC_B_No_104s_2_07 "CSC号";
CM_ SG_ 2401365575 BalDchg_PosCell_2_07 "放电均衡电芯位置(填充前54个去空CELL)";
CM_ SG_ 2401365575 State_Balance_Status_2_07 "均衡状态";
CM_ SG_ 2401365575 State_Balance_Fault_2_07 "均衡关闭故障";
CM_ SG_ 2401365576 CSC_B_No_104s_2_08 "CSC号";
CM_ SG_ 2401365576 BalDchg_PosCell_2_08 "放电均衡电芯位置(填充前54个去空CELL)";
CM_ SG_ 2401365576 State_Balance_Status_2_08 "均衡状态";
CM_ SG_ 2401365576 State_Balance_Fault_2_08 "均衡关闭故障";
CM_ SG_ 2401365577 CSC_B_No_104s_2_09 "CSC号";
CM_ SG_ 2401365577 BalDchg_PosCell_2_09 "放电均衡电芯位置(填充前54个去空CELL)";
CM_ SG_ 2401365577 State_Balance_Status_2_09 "均衡状态";
CM_ SG_ 2401365577 State_Balance_Fault_2_09 "均衡关闭故障";
CM_ SG_ 2401365578 CSC_B_No_104s_2_10 "CSC号";
CM_ SG_ 2401365578 BalDchg_PosCell_2_10 "放电均衡电芯位置(填充前54个去空CELL)";
CM_ SG_ 2401365578 State_Balance_Status_2_10 "均衡状态";
CM_ SG_ 2401365578 State_Balance_Fault_2_10 "均衡关闭故障";
CM_ SG_ 2401365579 CSC_B_No_104s_2_11 "CSC号";
CM_ SG_ 2401365579 BalDchg_PosCell_2_11 "放电均衡电芯位置(填充前54个去空CELL)";
CM_ SG_ 2401365579 State_Balance_Status_2_11 "均衡状态";
CM_ SG_ 2401365579 State_Balance_Fault_2_11 "均衡关闭故障";
CM_ SG_ 2401365580 CSC_B_No_104s_2_12 "CSC号";
CM_ SG_ 2401365580 BalDchg_PosCell_2_12 "放电均衡电芯位置(填充前54个去空CELL)";
CM_ SG_ 2401365580 State_Balance_Status_2_12 "均衡状态";
CM_ SG_ 2401365580 State_Balance_Fault_2_12 "均衡关闭故障";
CM_ SG_ 2401365581 CSC_B_No_104s_2_13 "CSC号";
CM_ SG_ 2401365581 BalDchg_PosCell_2_13 "放电均衡电芯位置(填充前54个去空CELL)";
CM_ SG_ 2401365581 State_Balance_Status_2_13 "均衡状态";
CM_ SG_ 2401365581 State_Balance_Fault_2_13 "均衡关闭故障";
CM_ SG_ 2401365582 CSC_B_No_104s_2_14 "CSC号";
CM_ SG_ 2401365582 BalDchg_PosCell_2_14 "放电均衡电芯位置(填充前54个去空CELL)";
CM_ SG_ 2401365582 State_Balance_Status_2_14 "均衡状态";
CM_ SG_ 2401365582 State_Balance_Fault_2_14 "均衡关闭故障";
CM_ SG_ 2401365583 CSC_B_No_104s_2_15 "CSC号";
CM_ SG_ 2401365583 BalDchg_PosCell_2_15 "放电均衡电芯位置(填充前54个去空CELL)";
CM_ SG_ 2401365583 State_Balance_Status_2_15 "均衡状态";
CM_ SG_ 2401365583 State_Balance_Fault_2_15 "均衡关闭故障";
CM_ SG_ 2401365584 CSC_B_No_104s_2_16 "CSC号";
CM_ SG_ 2401365584 BalDchg_PosCell_2_16 "放电均衡电芯位置(填充前54个去空CELL)";
CM_ SG_ 2401365584 State_Balance_Status_2_16 "均衡状态";
CM_ SG_ 2401365584 State_Balance_Fault_2_16 "均衡关闭故障";
CM_ SG_ 2401365585 CSC_B_No_104s_2_17 "CSC号";
CM_ SG_ 2401365585 BalDchg_PosCell_2_17 "放电均衡电芯位置(填充前54个去空CELL)";
CM_ SG_ 2401365585 State_Balance_Status_2_17 "均衡状态";
CM_ SG_ 2401365585 State_Balance_Fault_2_17 "均衡关闭故障";
CM_ SG_ 2401365586 CSC_B_No_104s_2_18 "CSC号";
CM_ SG_ 2401365586 BalDchg_PosCell_2_18 "放电均衡电芯位置(填充前54个去空CELL)";
CM_ SG_ 2401365586 State_Balance_Status_2_18 "均衡状态";
CM_ SG_ 2401365586 State_Balance_Fault_2_18 "均衡关闭故障";
CM_ SG_ 2401365587 CSC_B_No_104s_2_19 "CSC号";
CM_ SG_ 2401365587 BalDchg_PosCell_2_19 "放电均衡电芯位置(填充前54个去空CELL)";
CM_ SG_ 2401365587 State_Balance_Status_2_19 "均衡状态";
CM_ SG_ 2401365587 State_Balance_Fault_2_19 "均衡关闭故障";
CM_ SG_ 2401365588 CSC_B_No_104s_2_20 "CSC号";
CM_ SG_ 2401365588 BalDchg_PosCell_2_20 "放电均衡电芯位置(填充前54个去空CELL)";
CM_ SG_ 2401365588 State_Balance_Status_2_20 "均衡状态";
CM_ SG_ 2401365588 State_Balance_Fault_2_20 "均衡关闭故障";
CM_ SG_ 2401365589 CSC_B_No_104s_2_21 "CSC号";
CM_ SG_ 2401365589 BalDchg_PosCell_2_21 "放电均衡电芯位置(填充前54个去空CELL)";
CM_ SG_ 2401365589 State_Balance_Status_2_21 "均衡状态";
CM_ SG_ 2401365589 State_Balance_Fault_2_21 "均衡关闭故障";
CM_ SG_ 2401365590 CSC_B_No_104s_2_22 "CSC号";
CM_ SG_ 2401365590 BalDchg_PosCell_2_22 "放电均衡电芯位置(填充前54个去空CELL)";
CM_ SG_ 2401365590 State_Balance_Status_2_22 "均衡状态";
CM_ SG_ 2401365590 State_Balance_Fault_2_22 "均衡关闭故障";
CM_ SG_ 2401365591 CSC_B_No_104s_2_23 "CSC号";
CM_ SG_ 2401365591 BalDchg_PosCell_2_23 "放电均衡电芯位置(填充前54个去空CELL)";
CM_ SG_ 2401365591 State_Balance_Status_2_23 "均衡状态";
CM_ SG_ 2401365591 State_Balance_Fault_2_23 "均衡关闭故障";
CM_ SG_ 2401365592 CSC_B_No_104s_2_24 "CSC号";
CM_ SG_ 2401365592 BalDchg_PosCell_2_24 "放电均衡电芯位置(填充前54个去空CELL)";
CM_ SG_ 2401365592 State_Balance_Status_2_24 "均衡状态";
CM_ SG_ 2401365592 State_Balance_Fault_2_24 "均衡关闭故障";
CM_ SG_ 2401365593 CSC_B_No_104s_2_25 "CSC号";
CM_ SG_ 2401365593 BalDchg_PosCell_2_25 "放电均衡电芯位置(填充前54个去空CELL)";
CM_ SG_ 2401365593 State_Balance_Status_2_25 "均衡状态";
CM_ SG_ 2401365593 State_Balance_Fault_2_25 "均衡关闭故障";
CM_ SG_ 2401365594 CSC_B_No_104s_2_26 "CSC号";
CM_ SG_ 2401365594 BalDchg_PosCell_2_26 "放电均衡电芯位置(填充前54个去空CELL)";
CM_ SG_ 2401365594 State_Balance_Status_2_26 "均衡状态";
CM_ SG_ 2401365594 State_Balance_Fault_2_26 "均衡关闭故障";
CM_ SG_ 2401365595 CSC_B_No_104s_2_27 "CSC号";
CM_ SG_ 2401365595 BalDchg_PosCell_2_27 "放电均衡电芯位置(填充前54个去空CELL)";
CM_ SG_ 2401365595 State_Balance_Status_2_27 "均衡状态";
CM_ SG_ 2401365595 State_Balance_Fault_2_27 "均衡关闭故障";
CM_ SG_ 2401365596 CSC_B_No_104s_2_28 "CSC号";
CM_ SG_ 2401365596 BalDchg_PosCell_2_28 "放电均衡电芯位置(填充前54个去空CELL)";
CM_ SG_ 2401365596 State_Balance_Status_2_28 "均衡状态";
CM_ SG_ 2401365596 State_Balance_Fault_2_28 "均衡关闭故障";
CM_ SG_ 2401365597 CSC_B_No_104s_2_29 "CSC号";
CM_ SG_ 2401365597 BalDchg_PosCell_2_29 "放电均衡电芯位置(填充前54个去空CELL)";
CM_ SG_ 2401365597 State_Balance_Status_2_29 "均衡状态";
CM_ SG_ 2401365597 State_Balance_Fault_2_29 "均衡关闭故障";
CM_ SG_ 2401365598 CSC_B_No_104s_2_30 "CSC号";
CM_ SG_ 2401365598 BalDchg_PosCell_2_30 "放电均衡电芯位置(填充前54个去空CELL)";
CM_ SG_ 2401365598 State_Balance_Status_2_30 "均衡状态";
CM_ SG_ 2401365598 State_Balance_Fault_2_30 "均衡关闭故障";
CM_ SG_ 2401365599 CSC_B_No_104s_2_31 "CSC号";
CM_ SG_ 2401365599 BalDchg_PosCell_2_31 "放电均衡电芯位置(填充前54个去空CELL)";
CM_ SG_ 2401365599 State_Balance_Status_2_31 "均衡状态";
CM_ SG_ 2401365599 State_Balance_Fault_2_31 "均衡关闭故障";
CM_ SG_ 2401365600 CSC_B_No_104s_2_32 "CSC号";
CM_ SG_ 2401365600 BalDchg_PosCell_2_32 "放电均衡电芯位置(填充前54个去空CELL)";
CM_ SG_ 2401365600 State_Balance_Status_2_32 "均衡状态";
CM_ SG_ 2401365600 State_Balance_Fault_2_32 "均衡关闭故障";
CM_ SG_ 2401365601 CSC_B_No_104s_2_33 "CSC号";
CM_ SG_ 2401365601 BalDchg_PosCell_2_33 "放电均衡电芯位置(填充前54个去空CELL)";
CM_ SG_ 2401365601 State_Balance_Status_2_33 "均衡状态";
CM_ SG_ 2401365601 State_Balance_Fault_2_33 "均衡关闭故障";
CM_ SG_ 2401365602 CSC_B_No_104s_2_34 "CSC号";
CM_ SG_ 2401365602 BalDchg_PosCell_2_34 "放电均衡电芯位置(填充前54个去空CELL)";
CM_ SG_ 2401365602 State_Balance_Status_2_34 "均衡状态";
CM_ SG_ 2401365602 State_Balance_Fault_2_34 "均衡关闭故障";
CM_ SG_ 2401365603 CSC_B_No_104s_2_35 "CSC号";
CM_ SG_ 2401365603 BalDchg_PosCell_2_35 "放电均衡电芯位置(填充前54个去空CELL)";
CM_ SG_ 2401365603 State_Balance_Status_2_35 "均衡状态";
CM_ SG_ 2401365603 State_Balance_Fault_2_35 "均衡关闭故障";
CM_ SG_ 2401365604 CSC_B_No_104s_2_36 "CSC号";
CM_ SG_ 2401365604 BalDchg_PosCell_2_36 "放电均衡电芯位置(填充前54个去空CELL)";
CM_ SG_ 2401365604 State_Balance_Status_2_36 "均衡状态";
CM_ SG_ 2401365604 State_Balance_Fault_2_36 "均衡关闭故障";
CM_ SG_ 2401365605 CSC_B_No_104s_2_37 "CSC号";
CM_ SG_ 2401365605 BalDchg_PosCell_2_37 "放电均衡电芯位置(填充前54个去空CELL)";
CM_ SG_ 2401365605 State_Balance_Status_2_37 "均衡状态";
CM_ SG_ 2401365605 State_Balance_Fault_2_37 "均衡关闭故障";
CM_ SG_ 2401365606 CSC_B_No_104s_2_38 "CSC号";
CM_ SG_ 2401365606 BalDchg_PosCell_2_38 "放电均衡电芯位置(填充前54个去空CELL)";
CM_ SG_ 2401365606 State_Balance_Status_2_38 "均衡状态";
CM_ SG_ 2401365606 State_Balance_Fault_2_38 "均衡关闭故障";
CM_ SG_ 2401365607 CSC_B_No_104s_2_39 "CSC号";
CM_ SG_ 2401365607 BalDchg_PosCell_2_39 "放电均衡电芯位置(填充前54个去空CELL)";
CM_ SG_ 2401365607 State_Balance_Status_2_39 "均衡状态";
CM_ SG_ 2401365607 State_Balance_Fault_2_39 "均衡关闭故障";
CM_ SG_ 2401365608 CSC_B_No_104s_2_40 "CSC号";
CM_ SG_ 2401365608 BalDchg_PosCell_2_40 "放电均衡电芯位置(填充前54个去空CELL)";
CM_ SG_ 2401365608 State_Balance_Status_2_40 "均衡状态";
CM_ SG_ 2401365608 State_Balance_Fault_2_40 "均衡关闭故障";
CM_ SG_ 2401365609 CSC_B_No_104s_2_41 "CSC号";
CM_ SG_ 2401365609 BalDchg_PosCell_2_41 "放电均衡电芯位置(填充前54个去空CELL)";
CM_ SG_ 2401365609 State_Balance_Status_2_41 "均衡状态";
CM_ SG_ 2401365609 State_Balance_Fault_2_41 "均衡关闭故障";
CM_ SG_ 2401365610 CSC_B_No_104s_2_42 "CSC号";
CM_ SG_ 2401365610 BalDchg_PosCell_2_42 "放电均衡电芯位置(填充前54个去空CELL)";
CM_ SG_ 2401365610 State_Balance_Status_2_42 "均衡状态";
CM_ SG_ 2401365610 State_Balance_Fault_2_42 "均衡关闭故障";
CM_ SG_ 2401365611 CSC_B_No_104s_2_43 "CSC号";
CM_ SG_ 2401365611 BalDchg_PosCell_2_43 "放电均衡电芯位置(填充前54个去空CELL)";
CM_ SG_ 2401365611 State_Balance_Status_2_43 "均衡状态";
CM_ SG_ 2401365611 State_Balance_Fault_2_43 "均衡关闭故障";
CM_ SG_ 2401365612 CSC_B_No_104s_2_44 "CSC号";
CM_ SG_ 2401365612 BalDchg_PosCell_2_44 "放电均衡电芯位置(填充前54个去空CELL)";
CM_ SG_ 2401365612 State_Balance_Status_2_44 "均衡状态";
CM_ SG_ 2401365612 State_Balance_Fault_2_44 "均衡关闭故障";
CM_ SG_ 2401365613 CSC_B_No_104s_2_45 "CSC号";
CM_ SG_ 2401365613 BalDchg_PosCell_2_45 "放电均衡电芯位置(填充前54个去空CELL)";
CM_ SG_ 2401365613 State_Balance_Status_2_45 "均衡状态";
CM_ SG_ 2401365613 State_Balance_Fault_2_45 "均衡关闭故障";
CM_ SG_ 2401365614 CSC_B_No_104s_2_46 "CSC号";
CM_ SG_ 2401365614 BalDchg_PosCell_2_46 "放电均衡电芯位置(填充前54个去空CELL)";
CM_ SG_ 2401365614 State_Balance_Status_2_46 "均衡状态";
CM_ SG_ 2401365614 State_Balance_Fault_2_46 "均衡关闭故障";
CM_ SG_ 2401365615 CSC_B_No_104s_2_47 "CSC号";
CM_ SG_ 2401365615 BalDchg_PosCell_2_47 "放电均衡电芯位置(填充前54个去空CELL)";
CM_ SG_ 2401365615 State_Balance_Status_2_47 "均衡状态";
CM_ SG_ 2401365615 State_Balance_Fault_2_47 "均衡关闭故障";
CM_ SG_ 2401365616 CSC_B_No_104s_2_48 "CSC号";
CM_ SG_ 2401365616 BalDchg_PosCell_2_48 "放电均衡电芯位置(填充前54个去空CELL)";
CM_ SG_ 2401365616 State_Balance_Status_2_48 "均衡状态";
CM_ SG_ 2401365616 State_Balance_Fault_2_48 "均衡关闭故障";
CM_ SG_ 2401365617 CSC_B_No_104s_2_49 "CSC号";
CM_ SG_ 2401365617 BalDchg_PosCell_2_49 "放电均衡电芯位置(填充前54个去空CELL)";
CM_ SG_ 2401365617 State_Balance_Status_2_49 "均衡状态";
CM_ SG_ 2401365617 State_Balance_Fault_2_49 "均衡关闭故障";
CM_ SG_ 2401365618 CSC_B_No_104s_2_50 "CSC号";
CM_ SG_ 2401365618 BalDchg_PosCell_2_50 "放电均衡电芯位置(填充前54个去空CELL)";
CM_ SG_ 2401365618 State_Balance_Status_2_50 "均衡状态";
CM_ SG_ 2401365618 State_Balance_Fault_2_50 "均衡关闭故障";
CM_ SG_ 2401365619 CSC_B_No_104s_2_51 "CSC号";
CM_ SG_ 2401365619 BalDchg_PosCell_2_51 "放电均衡电芯位置(填充前54个去空CELL)";
CM_ SG_ 2401365619 State_Balance_Status_2_51 "均衡状态";
CM_ SG_ 2401365619 State_Balance_Fault_2_51 "均衡关闭故障";
CM_ SG_ 2401365620 CSC_B_No_104s_2_52 "CSC号";
CM_ SG_ 2401365620 BalDchg_PosCell_2_52 "放电均衡电芯位置(填充前54个去空CELL)";
CM_ SG_ 2401365620 State_Balance_Status_2_52 "均衡状态";
CM_ SG_ 2401365620 State_Balance_Fault_2_52 "均衡关闭故障";
CM_ SG_ 2401365621 CSC_B_No_104s_2_53 "CSC号";
CM_ SG_ 2401365621 BalDchg_PosCell_2_53 "放电均衡电芯位置(填充前54个去空CELL)";
CM_ SG_ 2401365621 State_Balance_Status_2_53 "均衡状态";
CM_ SG_ 2401365621 State_Balance_Fault_2_53 "均衡关闭故障";
CM_ SG_ 2401365622 CSC_B_No_104s_2_54 "CSC号";
CM_ SG_ 2401365622 BalDchg_PosCell_2_54 "放电均衡电芯位置(填充前54个去空CELL)";
CM_ SG_ 2401365622 State_Balance_Status_2_54 "均衡状态";
CM_ SG_ 2401365622 State_Balance_Fault_2_54 "均衡关闭故障";
CM_ SG_ 2401365623 CSC_B_No_104s_2_55 "CSC号";
CM_ SG_ 2401365623 BalDchg_PosCell_2_55 "放电均衡电芯位置(填充前54个去空CELL)";
CM_ SG_ 2401365623 State_Balance_Status_2_55 "均衡状态";
CM_ SG_ 2401365623 State_Balance_Fault_2_55 "均衡关闭故障";
CM_ SG_ 2401365624 CSC_B_No_104s_2_56 "CSC号";
CM_ SG_ 2401365624 BalDchg_PosCell_2_56 "放电均衡电芯位置(填充前54个去空CELL)";
CM_ SG_ 2401365624 State_Balance_Status_2_56 "均衡状态";
CM_ SG_ 2401365624 State_Balance_Fault_2_56 "均衡关闭故障";
CM_ SG_ 2401365625 CSC_B_No_104s_2_57 "CSC号";
CM_ SG_ 2401365625 BalDchg_PosCell_2_57 "放电均衡电芯位置(填充前54个去空CELL)";
CM_ SG_ 2401365625 State_Balance_Status_2_57 "均衡状态";
CM_ SG_ 2401365625 State_Balance_Fault_2_57 "均衡关闭故障";
CM_ SG_ 2401365626 CSC_B_No_104s_2_58 "CSC号";
CM_ SG_ 2401365626 BalDchg_PosCell_2_58 "放电均衡电芯位置(填充前54个去空CELL)";
CM_ SG_ 2401365626 State_Balance_Status_2_58 "均衡状态";
CM_ SG_ 2401365626 State_Balance_Fault_2_58 "均衡关闭故障";
CM_ SG_ 2401365627 CSC_B_No_104s_2_59 "CSC号";
CM_ SG_ 2401365627 BalDchg_PosCell_2_59 "放电均衡电芯位置(填充前54个去空CELL)";
CM_ SG_ 2401365627 State_Balance_Status_2_59 "均衡状态";
CM_ SG_ 2401365627 State_Balance_Fault_2_59 "均衡关闭故障";
CM_ SG_ 2401365628 CSC_B_No_104s_2_60 "CSC号";
CM_ SG_ 2401365628 BalDchg_PosCell_2_60 "放电均衡电芯位置(填充前54个去空CELL)";
CM_ SG_ 2401365628 State_Balance_Status_2_60 "均衡状态";
CM_ SG_ 2401365628 State_Balance_Fault_2_60 "均衡关闭故障";
CM_ SG_ 2401365629 CSC_B_No_104s_2_61 "CSC号";
CM_ SG_ 2401365629 BalDchg_PosCell_2_61 "放电均衡电芯位置(填充前54个去空CELL)";
CM_ SG_ 2401365629 State_Balance_Status_2_61 "均衡状态";
CM_ SG_ 2401365629 State_Balance_Fault_2_61 "均衡关闭故障";
CM_ SG_ 2401365630 CSC_B_No_104s_2_62 "CSC号";
CM_ SG_ 2401365630 BalDchg_PosCell_2_62 "放电均衡电芯位置(填充前54个去空CELL)";
CM_ SG_ 2401365630 State_Balance_Status_2_62 "均衡状态";
CM_ SG_ 2401365630 State_Balance_Fault_2_62 "均衡关闭故障";
CM_ SG_ 2401365631 CSC_B_No_104s_2_63 "CSC号";
CM_ SG_ 2401365631 BalDchg_PosCell_2_63 "放电均衡电芯位置(填充前54个去空CELL)";
CM_ SG_ 2401365631 State_Balance_Status_2_63 "均衡状态";
CM_ SG_ 2401365631 State_Balance_Fault_2_63 "均衡关闭故障";
CM_ SG_ 2432802798 P2I_DIAG_BYTE1 "PC给IMM的诊断报文字节1（详见调试协议）";
CM_ SG_ 2432802798 P2I_DIAG_BYTE2 "PC给IMM的诊断报文字节2（详见调试协议）";
CM_ SG_ 2432802798 P2I_DIAG_BYTE3 "PC给IMM的诊断报文字节3（详见调试协议）";
CM_ SG_ 2432802798 P2I_DIAG_BYTE4 "PC给IMM的诊断报文字节4（详见调试协议）";
CM_ SG_ 2432802798 P2I_DIAG_BYTE5 "PC给IMM的诊断报文字节5（详见调试协议）";
CM_ SG_ 2432802798 P2I_DIAG_BYTE6 "PC给IMM的诊断报文字节6（详见调试协议）";
CM_ SG_ 2432802798 P2I_DIAG_BYTE7 "PC给IMM的诊断报文字节7（详见调试协议）";
CM_ SG_ 2432802798 P2I_DIAG_BYTE8 "PC给IMM的诊断报文字节8（详见调试协议）";
CM_ SG_ 2418273857 S2P_Lmt18_Over_Idischarge1_01 "电池簇放电电流一级报警值";
CM_ SG_ 2418273857 S2P_Lmt18_Over_Idischarge2_01 "电池簇放电电流二级报警值";
CM_ SG_ 2418273857 S2P_Lmt18_Over_Idischarge3_01 "电池簇放电电流三级报警值";
CM_ SG_ 2418273857 S2P_Lmt18_Over_Idischarge4_01 "电池簇放电电流截止值";
CM_ SG_ 2418273858 S2P_Lmt18_Over_Idischarge1_02 "电池簇放电电流一级报警值";
CM_ SG_ 2418273858 S2P_Lmt18_Over_Idischarge2_02 "电池簇放电电流二级报警值";
CM_ SG_ 2418273858 S2P_Lmt18_Over_Idischarge3_02 "电池簇放电电流三级报警值";
CM_ SG_ 2418273858 S2P_Lmt18_Over_Idischarge4_02 "电池簇放电电流截止值";
CM_ SG_ 2418273859 S2P_Lmt18_Over_Idischarge1_03 "电池簇放电电流一级报警值";
CM_ SG_ 2418273859 S2P_Lmt18_Over_Idischarge2_03 "电池簇放电电流二级报警值";
CM_ SG_ 2418273859 S2P_Lmt18_Over_Idischarge3_03 "电池簇放电电流三级报警值";
CM_ SG_ 2418273859 S2P_Lmt18_Over_Idischarge4_03 "电池簇放电电流截止值";
CM_ SG_ 2418273860 S2P_Lmt18_Over_Idischarge1_04 "电池簇放电电流一级报警值";
CM_ SG_ 2418273860 S2P_Lmt18_Over_Idischarge2_04 "电池簇放电电流二级报警值";
CM_ SG_ 2418273860 S2P_Lmt18_Over_Idischarge3_04 "电池簇放电电流三级报警值";
CM_ SG_ 2418273860 S2P_Lmt18_Over_Idischarge4_04 "电池簇放电电流截止值";
CM_ SG_ 2418273861 S2P_Lmt18_Over_Idischarge1_05 "电池簇放电电流一级报警值";
CM_ SG_ 2418273861 S2P_Lmt18_Over_Idischarge2_05 "电池簇放电电流二级报警值";
CM_ SG_ 2418273861 S2P_Lmt18_Over_Idischarge3_05 "电池簇放电电流三级报警值";
CM_ SG_ 2418273861 S2P_Lmt18_Over_Idischarge4_05 "电池簇放电电流截止值";
CM_ SG_ 2418273862 S2P_Lmt18_Over_Idischarge1_06 "电池簇放电电流一级报警值";
CM_ SG_ 2418273862 S2P_Lmt18_Over_Idischarge2_06 "电池簇放电电流二级报警值";
CM_ SG_ 2418273862 S2P_Lmt18_Over_Idischarge3_06 "电池簇放电电流三级报警值";
CM_ SG_ 2418273862 S2P_Lmt18_Over_Idischarge4_06 "电池簇放电电流截止值";
CM_ SG_ 2418273863 S2P_Lmt18_Over_Idischarge1_07 "电池簇放电电流一级报警值";
CM_ SG_ 2418273863 S2P_Lmt18_Over_Idischarge2_07 "电池簇放电电流二级报警值";
CM_ SG_ 2418273863 S2P_Lmt18_Over_Idischarge3_07 "电池簇放电电流三级报警值";
CM_ SG_ 2418273863 S2P_Lmt18_Over_Idischarge4_07 "电池簇放电电流截止值";
CM_ SG_ 2418273864 S2P_Lmt18_Over_Idischarge1_08 "电池簇放电电流一级报警值";
CM_ SG_ 2418273864 S2P_Lmt18_Over_Idischarge2_08 "电池簇放电电流二级报警值";
CM_ SG_ 2418273864 S2P_Lmt18_Over_Idischarge3_08 "电池簇放电电流三级报警值";
CM_ SG_ 2418273864 S2P_Lmt18_Over_Idischarge4_08 "电池簇放电电流截止值";
CM_ SG_ 2418273865 S2P_Lmt18_Over_Idischarge1_09 "电池簇放电电流一级报警值";
CM_ SG_ 2418273865 S2P_Lmt18_Over_Idischarge2_09 "电池簇放电电流二级报警值";
CM_ SG_ 2418273865 S2P_Lmt18_Over_Idischarge3_09 "电池簇放电电流三级报警值";
CM_ SG_ 2418273865 S2P_Lmt18_Over_Idischarge4_09 "电池簇放电电流截止值";
CM_ SG_ 2418273866 S2P_Lmt18_Over_Idischarge1_10 "电池簇放电电流一级报警值";
CM_ SG_ 2418273866 S2P_Lmt18_Over_Idischarge2_10 "电池簇放电电流二级报警值";
CM_ SG_ 2418273866 S2P_Lmt18_Over_Idischarge3_10 "电池簇放电电流三级报警值";
CM_ SG_ 2418273866 S2P_Lmt18_Over_Idischarge4_10 "电池簇放电电流截止值";
CM_ SG_ 2418273867 S2P_Lmt18_Over_Idischarge1_11 "电池簇放电电流一级报警值";
CM_ SG_ 2418273867 S2P_Lmt18_Over_Idischarge2_11 "电池簇放电电流二级报警值";
CM_ SG_ 2418273867 S2P_Lmt18_Over_Idischarge3_11 "电池簇放电电流三级报警值";
CM_ SG_ 2418273867 S2P_Lmt18_Over_Idischarge4_11 "电池簇放电电流截止值";
CM_ SG_ 2418273868 S2P_Lmt18_Over_Idischarge1_12 "电池簇放电电流一级报警值";
CM_ SG_ 2418273868 S2P_Lmt18_Over_Idischarge2_12 "电池簇放电电流二级报警值";
CM_ SG_ 2418273868 S2P_Lmt18_Over_Idischarge3_12 "电池簇放电电流三级报警值";
CM_ SG_ 2418273868 S2P_Lmt18_Over_Idischarge4_12 "电池簇放电电流截止值";
CM_ SG_ 2418273869 S2P_Lmt18_Over_Idischarge1_13 "电池簇放电电流一级报警值";
CM_ SG_ 2418273869 S2P_Lmt18_Over_Idischarge2_13 "电池簇放电电流二级报警值";
CM_ SG_ 2418273869 S2P_Lmt18_Over_Idischarge3_13 "电池簇放电电流三级报警值";
CM_ SG_ 2418273869 S2P_Lmt18_Over_Idischarge4_13 "电池簇放电电流截止值";
CM_ SG_ 2418273870 S2P_Lmt18_Over_Idischarge1_14 "电池簇放电电流一级报警值";
CM_ SG_ 2418273870 S2P_Lmt18_Over_Idischarge2_14 "电池簇放电电流二级报警值";
CM_ SG_ 2418273870 S2P_Lmt18_Over_Idischarge3_14 "电池簇放电电流三级报警值";
CM_ SG_ 2418273870 S2P_Lmt18_Over_Idischarge4_14 "电池簇放电电流截止值";
CM_ SG_ 2418273871 S2P_Lmt18_Over_Idischarge1_15 "电池簇放电电流一级报警值";
CM_ SG_ 2418273871 S2P_Lmt18_Over_Idischarge2_15 "电池簇放电电流二级报警值";
CM_ SG_ 2418273871 S2P_Lmt18_Over_Idischarge3_15 "电池簇放电电流三级报警值";
CM_ SG_ 2418273871 S2P_Lmt18_Over_Idischarge4_15 "电池簇放电电流截止值";
CM_ SG_ 2418273872 S2P_Lmt18_Over_Idischarge1_16 "电池簇放电电流一级报警值";
CM_ SG_ 2418273872 S2P_Lmt18_Over_Idischarge2_16 "电池簇放电电流二级报警值";
CM_ SG_ 2418273872 S2P_Lmt18_Over_Idischarge3_16 "电池簇放电电流三级报警值";
CM_ SG_ 2418273872 S2P_Lmt18_Over_Idischarge4_16 "电池簇放电电流截止值";
CM_ SG_ 2418273873 S2P_Lmt18_Over_Idischarge1_17 "电池簇放电电流一级报警值";
CM_ SG_ 2418273873 S2P_Lmt18_Over_Idischarge2_17 "电池簇放电电流二级报警值";
CM_ SG_ 2418273873 S2P_Lmt18_Over_Idischarge3_17 "电池簇放电电流三级报警值";
CM_ SG_ 2418273873 S2P_Lmt18_Over_Idischarge4_17 "电池簇放电电流截止值";
CM_ SG_ 2418273874 S2P_Lmt18_Over_Idischarge1_18 "电池簇放电电流一级报警值";
CM_ SG_ 2418273874 S2P_Lmt18_Over_Idischarge2_18 "电池簇放电电流二级报警值";
CM_ SG_ 2418273874 S2P_Lmt18_Over_Idischarge3_18 "电池簇放电电流三级报警值";
CM_ SG_ 2418273874 S2P_Lmt18_Over_Idischarge4_18 "电池簇放电电流截止值";
CM_ SG_ 2418273875 S2P_Lmt18_Over_Idischarge1_19 "电池簇放电电流一级报警值";
CM_ SG_ 2418273875 S2P_Lmt18_Over_Idischarge2_19 "电池簇放电电流二级报警值";
CM_ SG_ 2418273875 S2P_Lmt18_Over_Idischarge3_19 "电池簇放电电流三级报警值";
CM_ SG_ 2418273875 S2P_Lmt18_Over_Idischarge4_19 "电池簇放电电流截止值";
CM_ SG_ 2418273876 S2P_Lmt18_Over_Idischarge1_20 "电池簇放电电流一级报警值";
CM_ SG_ 2418273876 S2P_Lmt18_Over_Idischarge2_20 "电池簇放电电流二级报警值";
CM_ SG_ 2418273876 S2P_Lmt18_Over_Idischarge3_20 "电池簇放电电流三级报警值";
CM_ SG_ 2418273876 S2P_Lmt18_Over_Idischarge4_20 "电池簇放电电流截止值";
CM_ SG_ 2418273877 S2P_Lmt18_Over_Idischarge1_21 "电池簇放电电流一级报警值";
CM_ SG_ 2418273877 S2P_Lmt18_Over_Idischarge2_21 "电池簇放电电流二级报警值";
CM_ SG_ 2418273877 S2P_Lmt18_Over_Idischarge3_21 "电池簇放电电流三级报警值";
CM_ SG_ 2418273877 S2P_Lmt18_Over_Idischarge4_21 "电池簇放电电流截止值";
CM_ SG_ 2418273878 S2P_Lmt18_Over_Idischarge1_22 "电池簇放电电流一级报警值";
CM_ SG_ 2418273878 S2P_Lmt18_Over_Idischarge2_22 "电池簇放电电流二级报警值";
CM_ SG_ 2418273878 S2P_Lmt18_Over_Idischarge3_22 "电池簇放电电流三级报警值";
CM_ SG_ 2418273878 S2P_Lmt18_Over_Idischarge4_22 "电池簇放电电流截止值";
CM_ SG_ 2418273879 S2P_Lmt18_Over_Idischarge1_23 "电池簇放电电流一级报警值";
CM_ SG_ 2418273879 S2P_Lmt18_Over_Idischarge2_23 "电池簇放电电流二级报警值";
CM_ SG_ 2418273879 S2P_Lmt18_Over_Idischarge3_23 "电池簇放电电流三级报警值";
CM_ SG_ 2418273879 S2P_Lmt18_Over_Idischarge4_23 "电池簇放电电流截止值";
CM_ SG_ 2418273880 S2P_Lmt18_Over_Idischarge1_24 "电池簇放电电流一级报警值";
CM_ SG_ 2418273880 S2P_Lmt18_Over_Idischarge2_24 "电池簇放电电流二级报警值";
CM_ SG_ 2418273880 S2P_Lmt18_Over_Idischarge3_24 "电池簇放电电流三级报警值";
CM_ SG_ 2418273880 S2P_Lmt18_Over_Idischarge4_24 "电池簇放电电流截止值";
CM_ SG_ 2418273881 S2P_Lmt18_Over_Idischarge1_25 "电池簇放电电流一级报警值";
CM_ SG_ 2418273881 S2P_Lmt18_Over_Idischarge2_25 "电池簇放电电流二级报警值";
CM_ SG_ 2418273881 S2P_Lmt18_Over_Idischarge3_25 "电池簇放电电流三级报警值";
CM_ SG_ 2418273881 S2P_Lmt18_Over_Idischarge4_25 "电池簇放电电流截止值";
CM_ SG_ 2418273882 S2P_Lmt18_Over_Idischarge1_26 "电池簇放电电流一级报警值";
CM_ SG_ 2418273882 S2P_Lmt18_Over_Idischarge2_26 "电池簇放电电流二级报警值";
CM_ SG_ 2418273882 S2P_Lmt18_Over_Idischarge3_26 "电池簇放电电流三级报警值";
CM_ SG_ 2418273882 S2P_Lmt18_Over_Idischarge4_26 "电池簇放电电流截止值";
CM_ SG_ 2418273883 S2P_Lmt18_Over_Idischarge1_27 "电池簇放电电流一级报警值";
CM_ SG_ 2418273883 S2P_Lmt18_Over_Idischarge2_27 "电池簇放电电流二级报警值";
CM_ SG_ 2418273883 S2P_Lmt18_Over_Idischarge3_27 "电池簇放电电流三级报警值";
CM_ SG_ 2418273883 S2P_Lmt18_Over_Idischarge4_27 "电池簇放电电流截止值";
CM_ SG_ 2418273884 S2P_Lmt18_Over_Idischarge1_28 "电池簇放电电流一级报警值";
CM_ SG_ 2418273884 S2P_Lmt18_Over_Idischarge2_28 "电池簇放电电流二级报警值";
CM_ SG_ 2418273884 S2P_Lmt18_Over_Idischarge3_28 "电池簇放电电流三级报警值";
CM_ SG_ 2418273884 S2P_Lmt18_Over_Idischarge4_28 "电池簇放电电流截止值";
CM_ SG_ 2418273885 S2P_Lmt18_Over_Idischarge1_29 "电池簇放电电流一级报警值";
CM_ SG_ 2418273885 S2P_Lmt18_Over_Idischarge2_29 "电池簇放电电流二级报警值";
CM_ SG_ 2418273885 S2P_Lmt18_Over_Idischarge3_29 "电池簇放电电流三级报警值";
CM_ SG_ 2418273885 S2P_Lmt18_Over_Idischarge4_29 "电池簇放电电流截止值";
CM_ SG_ 2418273886 S2P_Lmt18_Over_Idischarge1_30 "电池簇放电电流一级报警值";
CM_ SG_ 2418273886 S2P_Lmt18_Over_Idischarge2_30 "电池簇放电电流二级报警值";
CM_ SG_ 2418273886 S2P_Lmt18_Over_Idischarge3_30 "电池簇放电电流三级报警值";
CM_ SG_ 2418273886 S2P_Lmt18_Over_Idischarge4_30 "电池簇放电电流截止值";
CM_ SG_ 2418273887 S2P_Lmt18_Over_Idischarge1_31 "电池簇放电电流一级报警值";
CM_ SG_ 2418273887 S2P_Lmt18_Over_Idischarge2_31 "电池簇放电电流二级报警值";
CM_ SG_ 2418273887 S2P_Lmt18_Over_Idischarge3_31 "电池簇放电电流三级报警值";
CM_ SG_ 2418273887 S2P_Lmt18_Over_Idischarge4_31 "电池簇放电电流截止值";
CM_ SG_ 2418273888 S2P_Lmt18_Over_Idischarge1_32 "电池簇放电电流一级报警值";
CM_ SG_ 2418273888 S2P_Lmt18_Over_Idischarge2_32 "电池簇放电电流二级报警值";
CM_ SG_ 2418273888 S2P_Lmt18_Over_Idischarge3_32 "电池簇放电电流三级报警值";
CM_ SG_ 2418273888 S2P_Lmt18_Over_Idischarge4_32 "电池簇放电电流截止值";
CM_ SG_ 2418273889 S2P_Lmt18_Over_Idischarge1_33 "电池簇放电电流一级报警值";
CM_ SG_ 2418273889 S2P_Lmt18_Over_Idischarge2_33 "电池簇放电电流二级报警值";
CM_ SG_ 2418273889 S2P_Lmt18_Over_Idischarge3_33 "电池簇放电电流三级报警值";
CM_ SG_ 2418273889 S2P_Lmt18_Over_Idischarge4_33 "电池簇放电电流截止值";
CM_ SG_ 2418273890 S2P_Lmt18_Over_Idischarge1_34 "电池簇放电电流一级报警值";
CM_ SG_ 2418273890 S2P_Lmt18_Over_Idischarge2_34 "电池簇放电电流二级报警值";
CM_ SG_ 2418273890 S2P_Lmt18_Over_Idischarge3_34 "电池簇放电电流三级报警值";
CM_ SG_ 2418273890 S2P_Lmt18_Over_Idischarge4_34 "电池簇放电电流截止值";
CM_ SG_ 2418273891 S2P_Lmt18_Over_Idischarge1_35 "电池簇放电电流一级报警值";
CM_ SG_ 2418273891 S2P_Lmt18_Over_Idischarge2_35 "电池簇放电电流二级报警值";
CM_ SG_ 2418273891 S2P_Lmt18_Over_Idischarge3_35 "电池簇放电电流三级报警值";
CM_ SG_ 2418273891 S2P_Lmt18_Over_Idischarge4_35 "电池簇放电电流截止值";
CM_ SG_ 2418273892 S2P_Lmt18_Over_Idischarge1_36 "电池簇放电电流一级报警值";
CM_ SG_ 2418273892 S2P_Lmt18_Over_Idischarge2_36 "电池簇放电电流二级报警值";
CM_ SG_ 2418273892 S2P_Lmt18_Over_Idischarge3_36 "电池簇放电电流三级报警值";
CM_ SG_ 2418273892 S2P_Lmt18_Over_Idischarge4_36 "电池簇放电电流截止值";
CM_ SG_ 2418273893 S2P_Lmt18_Over_Idischarge1_37 "电池簇放电电流一级报警值";
CM_ SG_ 2418273893 S2P_Lmt18_Over_Idischarge2_37 "电池簇放电电流二级报警值";
CM_ SG_ 2418273893 S2P_Lmt18_Over_Idischarge3_37 "电池簇放电电流三级报警值";
CM_ SG_ 2418273893 S2P_Lmt18_Over_Idischarge4_37 "电池簇放电电流截止值";
CM_ SG_ 2418273894 S2P_Lmt18_Over_Idischarge1_38 "电池簇放电电流一级报警值";
CM_ SG_ 2418273894 S2P_Lmt18_Over_Idischarge2_38 "电池簇放电电流二级报警值";
CM_ SG_ 2418273894 S2P_Lmt18_Over_Idischarge3_38 "电池簇放电电流三级报警值";
CM_ SG_ 2418273894 S2P_Lmt18_Over_Idischarge4_38 "电池簇放电电流截止值";
CM_ SG_ 2418273895 S2P_Lmt18_Over_Idischarge1_39 "电池簇放电电流一级报警值";
CM_ SG_ 2418273895 S2P_Lmt18_Over_Idischarge2_39 "电池簇放电电流二级报警值";
CM_ SG_ 2418273895 S2P_Lmt18_Over_Idischarge3_39 "电池簇放电电流三级报警值";
CM_ SG_ 2418273895 S2P_Lmt18_Over_Idischarge4_39 "电池簇放电电流截止值";
CM_ SG_ 2418273896 S2P_Lmt18_Over_Idischarge1_40 "电池簇放电电流一级报警值";
CM_ SG_ 2418273896 S2P_Lmt18_Over_Idischarge2_40 "电池簇放电电流二级报警值";
CM_ SG_ 2418273896 S2P_Lmt18_Over_Idischarge3_40 "电池簇放电电流三级报警值";
CM_ SG_ 2418273896 S2P_Lmt18_Over_Idischarge4_40 "电池簇放电电流截止值";
CM_ SG_ 2418273897 S2P_Lmt18_Over_Idischarge1_41 "电池簇放电电流一级报警值";
CM_ SG_ 2418273897 S2P_Lmt18_Over_Idischarge2_41 "电池簇放电电流二级报警值";
CM_ SG_ 2418273897 S2P_Lmt18_Over_Idischarge3_41 "电池簇放电电流三级报警值";
CM_ SG_ 2418273897 S2P_Lmt18_Over_Idischarge4_41 "电池簇放电电流截止值";
CM_ SG_ 2418273898 S2P_Lmt18_Over_Idischarge1_42 "电池簇放电电流一级报警值";
CM_ SG_ 2418273898 S2P_Lmt18_Over_Idischarge2_42 "电池簇放电电流二级报警值";
CM_ SG_ 2418273898 S2P_Lmt18_Over_Idischarge3_42 "电池簇放电电流三级报警值";
CM_ SG_ 2418273898 S2P_Lmt18_Over_Idischarge4_42 "电池簇放电电流截止值";
CM_ SG_ 2418273899 S2P_Lmt18_Over_Idischarge1_43 "电池簇放电电流一级报警值";
CM_ SG_ 2418273899 S2P_Lmt18_Over_Idischarge2_43 "电池簇放电电流二级报警值";
CM_ SG_ 2418273899 S2P_Lmt18_Over_Idischarge3_43 "电池簇放电电流三级报警值";
CM_ SG_ 2418273899 S2P_Lmt18_Over_Idischarge4_43 "电池簇放电电流截止值";
CM_ SG_ 2418273900 S2P_Lmt18_Over_Idischarge1_44 "电池簇放电电流一级报警值";
CM_ SG_ 2418273900 S2P_Lmt18_Over_Idischarge2_44 "电池簇放电电流二级报警值";
CM_ SG_ 2418273900 S2P_Lmt18_Over_Idischarge3_44 "电池簇放电电流三级报警值";
CM_ SG_ 2418273900 S2P_Lmt18_Over_Idischarge4_44 "电池簇放电电流截止值";
CM_ SG_ 2418273901 S2P_Lmt18_Over_Idischarge1_45 "电池簇放电电流一级报警值";
CM_ SG_ 2418273901 S2P_Lmt18_Over_Idischarge2_45 "电池簇放电电流二级报警值";
CM_ SG_ 2418273901 S2P_Lmt18_Over_Idischarge3_45 "电池簇放电电流三级报警值";
CM_ SG_ 2418273901 S2P_Lmt18_Over_Idischarge4_45 "电池簇放电电流截止值";
CM_ SG_ 2418273902 S2P_Lmt18_Over_Idischarge1_46 "电池簇放电电流一级报警值";
CM_ SG_ 2418273902 S2P_Lmt18_Over_Idischarge2_46 "电池簇放电电流二级报警值";
CM_ SG_ 2418273902 S2P_Lmt18_Over_Idischarge3_46 "电池簇放电电流三级报警值";
CM_ SG_ 2418273902 S2P_Lmt18_Over_Idischarge4_46 "电池簇放电电流截止值";
CM_ SG_ 2418273903 S2P_Lmt18_Over_Idischarge1_47 "电池簇放电电流一级报警值";
CM_ SG_ 2418273903 S2P_Lmt18_Over_Idischarge2_47 "电池簇放电电流二级报警值";
CM_ SG_ 2418273903 S2P_Lmt18_Over_Idischarge3_47 "电池簇放电电流三级报警值";
CM_ SG_ 2418273903 S2P_Lmt18_Over_Idischarge4_47 "电池簇放电电流截止值";
CM_ SG_ 2418273904 S2P_Lmt18_Over_Idischarge1_48 "电池簇放电电流一级报警值";
CM_ SG_ 2418273904 S2P_Lmt18_Over_Idischarge2_48 "电池簇放电电流二级报警值";
CM_ SG_ 2418273904 S2P_Lmt18_Over_Idischarge3_48 "电池簇放电电流三级报警值";
CM_ SG_ 2418273904 S2P_Lmt18_Over_Idischarge4_48 "电池簇放电电流截止值";
CM_ SG_ 2418273905 S2P_Lmt18_Over_Idischarge1_49 "电池簇放电电流一级报警值";
CM_ SG_ 2418273905 S2P_Lmt18_Over_Idischarge2_49 "电池簇放电电流二级报警值";
CM_ SG_ 2418273905 S2P_Lmt18_Over_Idischarge3_49 "电池簇放电电流三级报警值";
CM_ SG_ 2418273905 S2P_Lmt18_Over_Idischarge4_49 "电池簇放电电流截止值";
CM_ SG_ 2418273906 S2P_Lmt18_Over_Idischarge1_50 "电池簇放电电流一级报警值";
CM_ SG_ 2418273906 S2P_Lmt18_Over_Idischarge2_50 "电池簇放电电流二级报警值";
CM_ SG_ 2418273906 S2P_Lmt18_Over_Idischarge3_50 "电池簇放电电流三级报警值";
CM_ SG_ 2418273906 S2P_Lmt18_Over_Idischarge4_50 "电池簇放电电流截止值";
CM_ SG_ 2418273907 S2P_Lmt18_Over_Idischarge1_51 "电池簇放电电流一级报警值";
CM_ SG_ 2418273907 S2P_Lmt18_Over_Idischarge2_51 "电池簇放电电流二级报警值";
CM_ SG_ 2418273907 S2P_Lmt18_Over_Idischarge3_51 "电池簇放电电流三级报警值";
CM_ SG_ 2418273907 S2P_Lmt18_Over_Idischarge4_51 "电池簇放电电流截止值";
CM_ SG_ 2418273908 S2P_Lmt18_Over_Idischarge1_52 "电池簇放电电流一级报警值";
CM_ SG_ 2418273908 S2P_Lmt18_Over_Idischarge2_52 "电池簇放电电流二级报警值";
CM_ SG_ 2418273908 S2P_Lmt18_Over_Idischarge3_52 "电池簇放电电流三级报警值";
CM_ SG_ 2418273908 S2P_Lmt18_Over_Idischarge4_52 "电池簇放电电流截止值";
CM_ SG_ 2418273909 S2P_Lmt18_Over_Idischarge1_53 "电池簇放电电流一级报警值";
CM_ SG_ 2418273909 S2P_Lmt18_Over_Idischarge2_53 "电池簇放电电流二级报警值";
CM_ SG_ 2418273909 S2P_Lmt18_Over_Idischarge3_53 "电池簇放电电流三级报警值";
CM_ SG_ 2418273909 S2P_Lmt18_Over_Idischarge4_53 "电池簇放电电流截止值";
CM_ SG_ 2418273910 S2P_Lmt18_Over_Idischarge1_54 "电池簇放电电流一级报警值";
CM_ SG_ 2418273910 S2P_Lmt18_Over_Idischarge2_54 "电池簇放电电流二级报警值";
CM_ SG_ 2418273910 S2P_Lmt18_Over_Idischarge3_54 "电池簇放电电流三级报警值";
CM_ SG_ 2418273910 S2P_Lmt18_Over_Idischarge4_54 "电池簇放电电流截止值";
CM_ SG_ 2418273911 S2P_Lmt18_Over_Idischarge1_55 "电池簇放电电流一级报警值";
CM_ SG_ 2418273911 S2P_Lmt18_Over_Idischarge2_55 "电池簇放电电流二级报警值";
CM_ SG_ 2418273911 S2P_Lmt18_Over_Idischarge3_55 "电池簇放电电流三级报警值";
CM_ SG_ 2418273911 S2P_Lmt18_Over_Idischarge4_55 "电池簇放电电流截止值";
CM_ SG_ 2418273912 S2P_Lmt18_Over_Idischarge1_56 "电池簇放电电流一级报警值";
CM_ SG_ 2418273912 S2P_Lmt18_Over_Idischarge2_56 "电池簇放电电流二级报警值";
CM_ SG_ 2418273912 S2P_Lmt18_Over_Idischarge3_56 "电池簇放电电流三级报警值";
CM_ SG_ 2418273912 S2P_Lmt18_Over_Idischarge4_56 "电池簇放电电流截止值";
CM_ SG_ 2418273913 S2P_Lmt18_Over_Idischarge1_57 "电池簇放电电流一级报警值";
CM_ SG_ 2418273913 S2P_Lmt18_Over_Idischarge2_57 "电池簇放电电流二级报警值";
CM_ SG_ 2418273913 S2P_Lmt18_Over_Idischarge3_57 "电池簇放电电流三级报警值";
CM_ SG_ 2418273913 S2P_Lmt18_Over_Idischarge4_57 "电池簇放电电流截止值";
CM_ SG_ 2418273914 S2P_Lmt18_Over_Idischarge1_58 "电池簇放电电流一级报警值";
CM_ SG_ 2418273914 S2P_Lmt18_Over_Idischarge2_58 "电池簇放电电流二级报警值";
CM_ SG_ 2418273914 S2P_Lmt18_Over_Idischarge3_58 "电池簇放电电流三级报警值";
CM_ SG_ 2418273914 S2P_Lmt18_Over_Idischarge4_58 "电池簇放电电流截止值";
CM_ SG_ 2418273915 S2P_Lmt18_Over_Idischarge1_59 "电池簇放电电流一级报警值";
CM_ SG_ 2418273915 S2P_Lmt18_Over_Idischarge2_59 "电池簇放电电流二级报警值";
CM_ SG_ 2418273915 S2P_Lmt18_Over_Idischarge3_59 "电池簇放电电流三级报警值";
CM_ SG_ 2418273915 S2P_Lmt18_Over_Idischarge4_59 "电池簇放电电流截止值";
CM_ SG_ 2418273916 S2P_Lmt18_Over_Idischarge1_60 "电池簇放电电流一级报警值";
CM_ SG_ 2418273916 S2P_Lmt18_Over_Idischarge2_60 "电池簇放电电流二级报警值";
CM_ SG_ 2418273916 S2P_Lmt18_Over_Idischarge3_60 "电池簇放电电流三级报警值";
CM_ SG_ 2418273916 S2P_Lmt18_Over_Idischarge4_60 "电池簇放电电流截止值";
CM_ SG_ 2418273917 S2P_Lmt18_Over_Idischarge1_61 "电池簇放电电流一级报警值";
CM_ SG_ 2418273917 S2P_Lmt18_Over_Idischarge2_61 "电池簇放电电流二级报警值";
CM_ SG_ 2418273917 S2P_Lmt18_Over_Idischarge3_61 "电池簇放电电流三级报警值";
CM_ SG_ 2418273917 S2P_Lmt18_Over_Idischarge4_61 "电池簇放电电流截止值";
CM_ SG_ 2418273918 S2P_Lmt18_Over_Idischarge1_62 "电池簇放电电流一级报警值";
CM_ SG_ 2418273918 S2P_Lmt18_Over_Idischarge2_62 "电池簇放电电流二级报警值";
CM_ SG_ 2418273918 S2P_Lmt18_Over_Idischarge3_62 "电池簇放电电流三级报警值";
CM_ SG_ 2418273918 S2P_Lmt18_Over_Idischarge4_62 "电池簇放电电流截止值";
CM_ SG_ 2418273919 S2P_Lmt18_Over_Idischarge1_63 "电池簇放电电流一级报警值";
CM_ SG_ 2418273919 S2P_Lmt18_Over_Idischarge2_63 "电池簇放电电流二级报警值";
CM_ SG_ 2418273919 S2P_Lmt18_Over_Idischarge3_63 "电池簇放电电流三级报警值";
CM_ SG_ 2418273919 S2P_Lmt18_Over_Idischarge4_63 "电池簇放电电流截止值";
CM_ SG_ 2418339393 S2P_Lmt19_Over_DeltUModule1_01 "电池模块电压极差一级报警值";
CM_ SG_ 2418339393 S2P_Lmt19_Over_DeltUModule2_01 "电池模块电压极差二级报警值";
CM_ SG_ 2418339393 S2P_Lmt19_Over_DeltUModule3_01 "电池模块电压极差三级报警值";
CM_ SG_ 2418339393 S2P_Lmt19_Over_DeltUModule4_01 "电池模块电压极差截止值";
CM_ SG_ 2418339394 S2P_Lmt19_Over_DeltUModule1_02 "电池模块电压极差一级报警值";
CM_ SG_ 2418339394 S2P_Lmt19_Over_DeltUModule2_02 "电池模块电压极差二级报警值";
CM_ SG_ 2418339394 S2P_Lmt19_Over_DeltUModule3_02 "电池模块电压极差三级报警值";
CM_ SG_ 2418339394 S2P_Lmt19_Over_DeltUModule4_02 "电池模块电压极差截止值";
CM_ SG_ 2418339395 S2P_Lmt19_Over_DeltUModule1_03 "电池模块电压极差一级报警值";
CM_ SG_ 2418339395 S2P_Lmt19_Over_DeltUModule2_03 "电池模块电压极差二级报警值";
CM_ SG_ 2418339395 S2P_Lmt19_Over_DeltUModule3_03 "电池模块电压极差三级报警值";
CM_ SG_ 2418339395 S2P_Lmt19_Over_DeltUModule4_03 "电池模块电压极差截止值";
CM_ SG_ 2418339396 S2P_Lmt19_Over_DeltUModule1_04 "电池模块电压极差一级报警值";
CM_ SG_ 2418339396 S2P_Lmt19_Over_DeltUModule2_04 "电池模块电压极差二级报警值";
CM_ SG_ 2418339396 S2P_Lmt19_Over_DeltUModule3_04 "电池模块电压极差三级报警值";
CM_ SG_ 2418339396 S2P_Lmt19_Over_DeltUModule4_04 "电池模块电压极差截止值";
CM_ SG_ 2418339397 S2P_Lmt19_Over_DeltUModule1_05 "电池模块电压极差一级报警值";
CM_ SG_ 2418339397 S2P_Lmt19_Over_DeltUModule2_05 "电池模块电压极差二级报警值";
CM_ SG_ 2418339397 S2P_Lmt19_Over_DeltUModule3_05 "电池模块电压极差三级报警值";
CM_ SG_ 2418339397 S2P_Lmt19_Over_DeltUModule4_05 "电池模块电压极差截止值";
CM_ SG_ 2418339398 S2P_Lmt19_Over_DeltUModule1_06 "电池模块电压极差一级报警值";
CM_ SG_ 2418339398 S2P_Lmt19_Over_DeltUModule2_06 "电池模块电压极差二级报警值";
CM_ SG_ 2418339398 S2P_Lmt19_Over_DeltUModule3_06 "电池模块电压极差三级报警值";
CM_ SG_ 2418339398 S2P_Lmt19_Over_DeltUModule4_06 "电池模块电压极差截止值";
CM_ SG_ 2418339399 S2P_Lmt19_Over_DeltUModule1_07 "电池模块电压极差一级报警值";
CM_ SG_ 2418339399 S2P_Lmt19_Over_DeltUModule2_07 "电池模块电压极差二级报警值";
CM_ SG_ 2418339399 S2P_Lmt19_Over_DeltUModule3_07 "电池模块电压极差三级报警值";
CM_ SG_ 2418339399 S2P_Lmt19_Over_DeltUModule4_07 "电池模块电压极差截止值";
CM_ SG_ 2418339400 S2P_Lmt19_Over_DeltUModule1_08 "电池模块电压极差一级报警值";
CM_ SG_ 2418339400 S2P_Lmt19_Over_DeltUModule2_08 "电池模块电压极差二级报警值";
CM_ SG_ 2418339400 S2P_Lmt19_Over_DeltUModule3_08 "电池模块电压极差三级报警值";
CM_ SG_ 2418339400 S2P_Lmt19_Over_DeltUModule4_08 "电池模块电压极差截止值";
CM_ SG_ 2418339401 S2P_Lmt19_Over_DeltUModule1_09 "电池模块电压极差一级报警值";
CM_ SG_ 2418339401 S2P_Lmt19_Over_DeltUModule2_09 "电池模块电压极差二级报警值";
CM_ SG_ 2418339401 S2P_Lmt19_Over_DeltUModule3_09 "电池模块电压极差三级报警值";
CM_ SG_ 2418339401 S2P_Lmt19_Over_DeltUModule4_09 "电池模块电压极差截止值";
CM_ SG_ 2418339402 S2P_Lmt19_Over_DeltUModule1_10 "电池模块电压极差一级报警值";
CM_ SG_ 2418339402 S2P_Lmt19_Over_DeltUModule2_10 "电池模块电压极差二级报警值";
CM_ SG_ 2418339402 S2P_Lmt19_Over_DeltUModule3_10 "电池模块电压极差三级报警值";
CM_ SG_ 2418339402 S2P_Lmt19_Over_DeltUModule4_10 "电池模块电压极差截止值";
CM_ SG_ 2418339403 S2P_Lmt19_Over_DeltUModule1_11 "电池模块电压极差一级报警值";
CM_ SG_ 2418339403 S2P_Lmt19_Over_DeltUModule2_11 "电池模块电压极差二级报警值";
CM_ SG_ 2418339403 S2P_Lmt19_Over_DeltUModule3_11 "电池模块电压极差三级报警值";
CM_ SG_ 2418339403 S2P_Lmt19_Over_DeltUModule4_11 "电池模块电压极差截止值";
CM_ SG_ 2418339404 S2P_Lmt19_Over_DeltUModule1_12 "电池模块电压极差一级报警值";
CM_ SG_ 2418339404 S2P_Lmt19_Over_DeltUModule2_12 "电池模块电压极差二级报警值";
CM_ SG_ 2418339404 S2P_Lmt19_Over_DeltUModule3_12 "电池模块电压极差三级报警值";
CM_ SG_ 2418339404 S2P_Lmt19_Over_DeltUModule4_12 "电池模块电压极差截止值";
CM_ SG_ 2418339405 S2P_Lmt19_Over_DeltUModule1_13 "电池模块电压极差一级报警值";
CM_ SG_ 2418339405 S2P_Lmt19_Over_DeltUModule2_13 "电池模块电压极差二级报警值";
CM_ SG_ 2418339405 S2P_Lmt19_Over_DeltUModule3_13 "电池模块电压极差三级报警值";
CM_ SG_ 2418339405 S2P_Lmt19_Over_DeltUModule4_13 "电池模块电压极差截止值";
CM_ SG_ 2418339406 S2P_Lmt19_Over_DeltUModule1_14 "电池模块电压极差一级报警值";
CM_ SG_ 2418339406 S2P_Lmt19_Over_DeltUModule2_14 "电池模块电压极差二级报警值";
CM_ SG_ 2418339406 S2P_Lmt19_Over_DeltUModule3_14 "电池模块电压极差三级报警值";
CM_ SG_ 2418339406 S2P_Lmt19_Over_DeltUModule4_14 "电池模块电压极差截止值";
CM_ SG_ 2418339407 S2P_Lmt19_Over_DeltUModule1_15 "电池模块电压极差一级报警值";
CM_ SG_ 2418339407 S2P_Lmt19_Over_DeltUModule2_15 "电池模块电压极差二级报警值";
CM_ SG_ 2418339407 S2P_Lmt19_Over_DeltUModule3_15 "电池模块电压极差三级报警值";
CM_ SG_ 2418339407 S2P_Lmt19_Over_DeltUModule4_15 "电池模块电压极差截止值";
CM_ SG_ 2418339408 S2P_Lmt19_Over_DeltUModule1_16 "电池模块电压极差一级报警值";
CM_ SG_ 2418339408 S2P_Lmt19_Over_DeltUModule2_16 "电池模块电压极差二级报警值";
CM_ SG_ 2418339408 S2P_Lmt19_Over_DeltUModule3_16 "电池模块电压极差三级报警值";
CM_ SG_ 2418339408 S2P_Lmt19_Over_DeltUModule4_16 "电池模块电压极差截止值";
CM_ SG_ 2418339409 S2P_Lmt19_Over_DeltUModule1_17 "电池模块电压极差一级报警值";
CM_ SG_ 2418339409 S2P_Lmt19_Over_DeltUModule2_17 "电池模块电压极差二级报警值";
CM_ SG_ 2418339409 S2P_Lmt19_Over_DeltUModule3_17 "电池模块电压极差三级报警值";
CM_ SG_ 2418339409 S2P_Lmt19_Over_DeltUModule4_17 "电池模块电压极差截止值";
CM_ SG_ 2418339410 S2P_Lmt19_Over_DeltUModule1_18 "电池模块电压极差一级报警值";
CM_ SG_ 2418339410 S2P_Lmt19_Over_DeltUModule2_18 "电池模块电压极差二级报警值";
CM_ SG_ 2418339410 S2P_Lmt19_Over_DeltUModule3_18 "电池模块电压极差三级报警值";
CM_ SG_ 2418339410 S2P_Lmt19_Over_DeltUModule4_18 "电池模块电压极差截止值";
CM_ SG_ 2418339411 S2P_Lmt19_Over_DeltUModule1_19 "电池模块电压极差一级报警值";
CM_ SG_ 2418339411 S2P_Lmt19_Over_DeltUModule2_19 "电池模块电压极差二级报警值";
CM_ SG_ 2418339411 S2P_Lmt19_Over_DeltUModule3_19 "电池模块电压极差三级报警值";
CM_ SG_ 2418339411 S2P_Lmt19_Over_DeltUModule4_19 "电池模块电压极差截止值";
CM_ SG_ 2418339412 S2P_Lmt19_Over_DeltUModule1_20 "电池模块电压极差一级报警值";
CM_ SG_ 2418339412 S2P_Lmt19_Over_DeltUModule2_20 "电池模块电压极差二级报警值";
CM_ SG_ 2418339412 S2P_Lmt19_Over_DeltUModule3_20 "电池模块电压极差三级报警值";
CM_ SG_ 2418339412 S2P_Lmt19_Over_DeltUModule4_20 "电池模块电压极差截止值";
CM_ SG_ 2418339413 S2P_Lmt19_Over_DeltUModule1_21 "电池模块电压极差一级报警值";
CM_ SG_ 2418339413 S2P_Lmt19_Over_DeltUModule2_21 "电池模块电压极差二级报警值";
CM_ SG_ 2418339413 S2P_Lmt19_Over_DeltUModule3_21 "电池模块电压极差三级报警值";
CM_ SG_ 2418339413 S2P_Lmt19_Over_DeltUModule4_21 "电池模块电压极差截止值";
CM_ SG_ 2418339414 S2P_Lmt19_Over_DeltUModule1_22 "电池模块电压极差一级报警值";
CM_ SG_ 2418339414 S2P_Lmt19_Over_DeltUModule2_22 "电池模块电压极差二级报警值";
CM_ SG_ 2418339414 S2P_Lmt19_Over_DeltUModule3_22 "电池模块电压极差三级报警值";
CM_ SG_ 2418339414 S2P_Lmt19_Over_DeltUModule4_22 "电池模块电压极差截止值";
CM_ SG_ 2418339415 S2P_Lmt19_Over_DeltUModule1_23 "电池模块电压极差一级报警值";
CM_ SG_ 2418339415 S2P_Lmt19_Over_DeltUModule2_23 "电池模块电压极差二级报警值";
CM_ SG_ 2418339415 S2P_Lmt19_Over_DeltUModule3_23 "电池模块电压极差三级报警值";
CM_ SG_ 2418339415 S2P_Lmt19_Over_DeltUModule4_23 "电池模块电压极差截止值";
CM_ SG_ 2418339416 S2P_Lmt19_Over_DeltUModule1_24 "电池模块电压极差一级报警值";
CM_ SG_ 2418339416 S2P_Lmt19_Over_DeltUModule2_24 "电池模块电压极差二级报警值";
CM_ SG_ 2418339416 S2P_Lmt19_Over_DeltUModule3_24 "电池模块电压极差三级报警值";
CM_ SG_ 2418339416 S2P_Lmt19_Over_DeltUModule4_24 "电池模块电压极差截止值";
CM_ SG_ 2418339417 S2P_Lmt19_Over_DeltUModule1_25 "电池模块电压极差一级报警值";
CM_ SG_ 2418339417 S2P_Lmt19_Over_DeltUModule2_25 "电池模块电压极差二级报警值";
CM_ SG_ 2418339417 S2P_Lmt19_Over_DeltUModule3_25 "电池模块电压极差三级报警值";
CM_ SG_ 2418339417 S2P_Lmt19_Over_DeltUModule4_25 "电池模块电压极差截止值";
CM_ SG_ 2418339418 S2P_Lmt19_Over_DeltUModule1_26 "电池模块电压极差一级报警值";
CM_ SG_ 2418339418 S2P_Lmt19_Over_DeltUModule2_26 "电池模块电压极差二级报警值";
CM_ SG_ 2418339418 S2P_Lmt19_Over_DeltUModule3_26 "电池模块电压极差三级报警值";
CM_ SG_ 2418339418 S2P_Lmt19_Over_DeltUModule4_26 "电池模块电压极差截止值";
CM_ SG_ 2418339419 S2P_Lmt19_Over_DeltUModule1_27 "电池模块电压极差一级报警值";
CM_ SG_ 2418339419 S2P_Lmt19_Over_DeltUModule2_27 "电池模块电压极差二级报警值";
CM_ SG_ 2418339419 S2P_Lmt19_Over_DeltUModule3_27 "电池模块电压极差三级报警值";
CM_ SG_ 2418339419 S2P_Lmt19_Over_DeltUModule4_27 "电池模块电压极差截止值";
CM_ SG_ 2418339420 S2P_Lmt19_Over_DeltUModule1_28 "电池模块电压极差一级报警值";
CM_ SG_ 2418339420 S2P_Lmt19_Over_DeltUModule2_28 "电池模块电压极差二级报警值";
CM_ SG_ 2418339420 S2P_Lmt19_Over_DeltUModule3_28 "电池模块电压极差三级报警值";
CM_ SG_ 2418339420 S2P_Lmt19_Over_DeltUModule4_28 "电池模块电压极差截止值";
CM_ SG_ 2418339421 S2P_Lmt19_Over_DeltUModule1_29 "电池模块电压极差一级报警值";
CM_ SG_ 2418339421 S2P_Lmt19_Over_DeltUModule2_29 "电池模块电压极差二级报警值";
CM_ SG_ 2418339421 S2P_Lmt19_Over_DeltUModule3_29 "电池模块电压极差三级报警值";
CM_ SG_ 2418339421 S2P_Lmt19_Over_DeltUModule4_29 "电池模块电压极差截止值";
CM_ SG_ 2418339422 S2P_Lmt19_Over_DeltUModule1_30 "电池模块电压极差一级报警值";
CM_ SG_ 2418339422 S2P_Lmt19_Over_DeltUModule2_30 "电池模块电压极差二级报警值";
CM_ SG_ 2418339422 S2P_Lmt19_Over_DeltUModule3_30 "电池模块电压极差三级报警值";
CM_ SG_ 2418339422 S2P_Lmt19_Over_DeltUModule4_30 "电池模块电压极差截止值";
CM_ SG_ 2418339423 S2P_Lmt19_Over_DeltUModule1_31 "电池模块电压极差一级报警值";
CM_ SG_ 2418339423 S2P_Lmt19_Over_DeltUModule2_31 "电池模块电压极差二级报警值";
CM_ SG_ 2418339423 S2P_Lmt19_Over_DeltUModule3_31 "电池模块电压极差三级报警值";
CM_ SG_ 2418339423 S2P_Lmt19_Over_DeltUModule4_31 "电池模块电压极差截止值";
CM_ SG_ 2418339424 S2P_Lmt19_Over_DeltUModule1_32 "电池模块电压极差一级报警值";
CM_ SG_ 2418339424 S2P_Lmt19_Over_DeltUModule2_32 "电池模块电压极差二级报警值";
CM_ SG_ 2418339424 S2P_Lmt19_Over_DeltUModule3_32 "电池模块电压极差三级报警值";
CM_ SG_ 2418339424 S2P_Lmt19_Over_DeltUModule4_32 "电池模块电压极差截止值";
CM_ SG_ 2418339425 S2P_Lmt19_Over_DeltUModule1_33 "电池模块电压极差一级报警值";
CM_ SG_ 2418339425 S2P_Lmt19_Over_DeltUModule2_33 "电池模块电压极差二级报警值";
CM_ SG_ 2418339425 S2P_Lmt19_Over_DeltUModule3_33 "电池模块电压极差三级报警值";
CM_ SG_ 2418339425 S2P_Lmt19_Over_DeltUModule4_33 "电池模块电压极差截止值";
CM_ SG_ 2418339426 S2P_Lmt19_Over_DeltUModule1_34 "电池模块电压极差一级报警值";
CM_ SG_ 2418339426 S2P_Lmt19_Over_DeltUModule2_34 "电池模块电压极差二级报警值";
CM_ SG_ 2418339426 S2P_Lmt19_Over_DeltUModule3_34 "电池模块电压极差三级报警值";
CM_ SG_ 2418339426 S2P_Lmt19_Over_DeltUModule4_34 "电池模块电压极差截止值";
CM_ SG_ 2418339427 S2P_Lmt19_Over_DeltUModule1_35 "电池模块电压极差一级报警值";
CM_ SG_ 2418339427 S2P_Lmt19_Over_DeltUModule2_35 "电池模块电压极差二级报警值";
CM_ SG_ 2418339427 S2P_Lmt19_Over_DeltUModule3_35 "电池模块电压极差三级报警值";
CM_ SG_ 2418339427 S2P_Lmt19_Over_DeltUModule4_35 "电池模块电压极差截止值";
CM_ SG_ 2418339428 S2P_Lmt19_Over_DeltUModule1_36 "电池模块电压极差一级报警值";
CM_ SG_ 2418339428 S2P_Lmt19_Over_DeltUModule2_36 "电池模块电压极差二级报警值";
CM_ SG_ 2418339428 S2P_Lmt19_Over_DeltUModule3_36 "电池模块电压极差三级报警值";
CM_ SG_ 2418339428 S2P_Lmt19_Over_DeltUModule4_36 "电池模块电压极差截止值";
CM_ SG_ 2418339429 S2P_Lmt19_Over_DeltUModule1_37 "电池模块电压极差一级报警值";
CM_ SG_ 2418339429 S2P_Lmt19_Over_DeltUModule2_37 "电池模块电压极差二级报警值";
CM_ SG_ 2418339429 S2P_Lmt19_Over_DeltUModule3_37 "电池模块电压极差三级报警值";
CM_ SG_ 2418339429 S2P_Lmt19_Over_DeltUModule4_37 "电池模块电压极差截止值";
CM_ SG_ 2418339430 S2P_Lmt19_Over_DeltUModule1_38 "电池模块电压极差一级报警值";
CM_ SG_ 2418339430 S2P_Lmt19_Over_DeltUModule2_38 "电池模块电压极差二级报警值";
CM_ SG_ 2418339430 S2P_Lmt19_Over_DeltUModule3_38 "电池模块电压极差三级报警值";
CM_ SG_ 2418339430 S2P_Lmt19_Over_DeltUModule4_38 "电池模块电压极差截止值";
CM_ SG_ 2418339431 S2P_Lmt19_Over_DeltUModule1_39 "电池模块电压极差一级报警值";
CM_ SG_ 2418339431 S2P_Lmt19_Over_DeltUModule2_39 "电池模块电压极差二级报警值";
CM_ SG_ 2418339431 S2P_Lmt19_Over_DeltUModule3_39 "电池模块电压极差三级报警值";
CM_ SG_ 2418339431 S2P_Lmt19_Over_DeltUModule4_39 "电池模块电压极差截止值";
CM_ SG_ 2418339432 S2P_Lmt19_Over_DeltUModule1_40 "电池模块电压极差一级报警值";
CM_ SG_ 2418339432 S2P_Lmt19_Over_DeltUModule2_40 "电池模块电压极差二级报警值";
CM_ SG_ 2418339432 S2P_Lmt19_Over_DeltUModule3_40 "电池模块电压极差三级报警值";
CM_ SG_ 2418339432 S2P_Lmt19_Over_DeltUModule4_40 "电池模块电压极差截止值";
CM_ SG_ 2418339433 S2P_Lmt19_Over_DeltUModule1_41 "电池模块电压极差一级报警值";
CM_ SG_ 2418339433 S2P_Lmt19_Over_DeltUModule2_41 "电池模块电压极差二级报警值";
CM_ SG_ 2418339433 S2P_Lmt19_Over_DeltUModule3_41 "电池模块电压极差三级报警值";
CM_ SG_ 2418339433 S2P_Lmt19_Over_DeltUModule4_41 "电池模块电压极差截止值";
CM_ SG_ 2418339434 S2P_Lmt19_Over_DeltUModule1_42 "电池模块电压极差一级报警值";
CM_ SG_ 2418339434 S2P_Lmt19_Over_DeltUModule2_42 "电池模块电压极差二级报警值";
CM_ SG_ 2418339434 S2P_Lmt19_Over_DeltUModule3_42 "电池模块电压极差三级报警值";
CM_ SG_ 2418339434 S2P_Lmt19_Over_DeltUModule4_42 "电池模块电压极差截止值";
CM_ SG_ 2418339435 S2P_Lmt19_Over_DeltUModule1_43 "电池模块电压极差一级报警值";
CM_ SG_ 2418339435 S2P_Lmt19_Over_DeltUModule2_43 "电池模块电压极差二级报警值";
CM_ SG_ 2418339435 S2P_Lmt19_Over_DeltUModule3_43 "电池模块电压极差三级报警值";
CM_ SG_ 2418339435 S2P_Lmt19_Over_DeltUModule4_43 "电池模块电压极差截止值";
CM_ SG_ 2418339436 S2P_Lmt19_Over_DeltUModule1_44 "电池模块电压极差一级报警值";
CM_ SG_ 2418339436 S2P_Lmt19_Over_DeltUModule2_44 "电池模块电压极差二级报警值";
CM_ SG_ 2418339436 S2P_Lmt19_Over_DeltUModule3_44 "电池模块电压极差三级报警值";
CM_ SG_ 2418339436 S2P_Lmt19_Over_DeltUModule4_44 "电池模块电压极差截止值";
CM_ SG_ 2418339437 S2P_Lmt19_Over_DeltUModule1_45 "电池模块电压极差一级报警值";
CM_ SG_ 2418339437 S2P_Lmt19_Over_DeltUModule2_45 "电池模块电压极差二级报警值";
CM_ SG_ 2418339437 S2P_Lmt19_Over_DeltUModule3_45 "电池模块电压极差三级报警值";
CM_ SG_ 2418339437 S2P_Lmt19_Over_DeltUModule4_45 "电池模块电压极差截止值";
CM_ SG_ 2418339438 S2P_Lmt19_Over_DeltUModule1_46 "电池模块电压极差一级报警值";
CM_ SG_ 2418339438 S2P_Lmt19_Over_DeltUModule2_46 "电池模块电压极差二级报警值";
CM_ SG_ 2418339438 S2P_Lmt19_Over_DeltUModule3_46 "电池模块电压极差三级报警值";
CM_ SG_ 2418339438 S2P_Lmt19_Over_DeltUModule4_46 "电池模块电压极差截止值";
CM_ SG_ 2418339439 S2P_Lmt19_Over_DeltUModule1_47 "电池模块电压极差一级报警值";
CM_ SG_ 2418339439 S2P_Lmt19_Over_DeltUModule2_47 "电池模块电压极差二级报警值";
CM_ SG_ 2418339439 S2P_Lmt19_Over_DeltUModule3_47 "电池模块电压极差三级报警值";
CM_ SG_ 2418339439 S2P_Lmt19_Over_DeltUModule4_47 "电池模块电压极差截止值";
CM_ SG_ 2418339440 S2P_Lmt19_Over_DeltUModule1_48 "电池模块电压极差一级报警值";
CM_ SG_ 2418339440 S2P_Lmt19_Over_DeltUModule2_48 "电池模块电压极差二级报警值";
CM_ SG_ 2418339440 S2P_Lmt19_Over_DeltUModule3_48 "电池模块电压极差三级报警值";
CM_ SG_ 2418339440 S2P_Lmt19_Over_DeltUModule4_48 "电池模块电压极差截止值";
CM_ SG_ 2418339441 S2P_Lmt19_Over_DeltUModule1_49 "电池模块电压极差一级报警值";
CM_ SG_ 2418339441 S2P_Lmt19_Over_DeltUModule2_49 "电池模块电压极差二级报警值";
CM_ SG_ 2418339441 S2P_Lmt19_Over_DeltUModule3_49 "电池模块电压极差三级报警值";
CM_ SG_ 2418339441 S2P_Lmt19_Over_DeltUModule4_49 "电池模块电压极差截止值";
CM_ SG_ 2418339442 S2P_Lmt19_Over_DeltUModule1_50 "电池模块电压极差一级报警值";
CM_ SG_ 2418339442 S2P_Lmt19_Over_DeltUModule2_50 "电池模块电压极差二级报警值";
CM_ SG_ 2418339442 S2P_Lmt19_Over_DeltUModule3_50 "电池模块电压极差三级报警值";
CM_ SG_ 2418339442 S2P_Lmt19_Over_DeltUModule4_50 "电池模块电压极差截止值";
CM_ SG_ 2418339443 S2P_Lmt19_Over_DeltUModule1_51 "电池模块电压极差一级报警值";
CM_ SG_ 2418339443 S2P_Lmt19_Over_DeltUModule2_51 "电池模块电压极差二级报警值";
CM_ SG_ 2418339443 S2P_Lmt19_Over_DeltUModule3_51 "电池模块电压极差三级报警值";
CM_ SG_ 2418339443 S2P_Lmt19_Over_DeltUModule4_51 "电池模块电压极差截止值";
CM_ SG_ 2418339444 S2P_Lmt19_Over_DeltUModule1_52 "电池模块电压极差一级报警值";
CM_ SG_ 2418339444 S2P_Lmt19_Over_DeltUModule2_52 "电池模块电压极差二级报警值";
CM_ SG_ 2418339444 S2P_Lmt19_Over_DeltUModule3_52 "电池模块电压极差三级报警值";
CM_ SG_ 2418339444 S2P_Lmt19_Over_DeltUModule4_52 "电池模块电压极差截止值";
CM_ SG_ 2418339445 S2P_Lmt19_Over_DeltUModule1_53 "电池模块电压极差一级报警值";
CM_ SG_ 2418339445 S2P_Lmt19_Over_DeltUModule2_53 "电池模块电压极差二级报警值";
CM_ SG_ 2418339445 S2P_Lmt19_Over_DeltUModule3_53 "电池模块电压极差三级报警值";
CM_ SG_ 2418339445 S2P_Lmt19_Over_DeltUModule4_53 "电池模块电压极差截止值";
CM_ SG_ 2418339446 S2P_Lmt19_Over_DeltUModule1_54 "电池模块电压极差一级报警值";
CM_ SG_ 2418339446 S2P_Lmt19_Over_DeltUModule2_54 "电池模块电压极差二级报警值";
CM_ SG_ 2418339446 S2P_Lmt19_Over_DeltUModule3_54 "电池模块电压极差三级报警值";
CM_ SG_ 2418339446 S2P_Lmt19_Over_DeltUModule4_54 "电池模块电压极差截止值";
CM_ SG_ 2418339447 S2P_Lmt19_Over_DeltUModule1_55 "电池模块电压极差一级报警值";
CM_ SG_ 2418339447 S2P_Lmt19_Over_DeltUModule2_55 "电池模块电压极差二级报警值";
CM_ SG_ 2418339447 S2P_Lmt19_Over_DeltUModule3_55 "电池模块电压极差三级报警值";
CM_ SG_ 2418339447 S2P_Lmt19_Over_DeltUModule4_55 "电池模块电压极差截止值";
CM_ SG_ 2418339448 S2P_Lmt19_Over_DeltUModule1_56 "电池模块电压极差一级报警值";
CM_ SG_ 2418339448 S2P_Lmt19_Over_DeltUModule2_56 "电池模块电压极差二级报警值";
CM_ SG_ 2418339448 S2P_Lmt19_Over_DeltUModule3_56 "电池模块电压极差三级报警值";
CM_ SG_ 2418339448 S2P_Lmt19_Over_DeltUModule4_56 "电池模块电压极差截止值";
CM_ SG_ 2418339449 S2P_Lmt19_Over_DeltUModule1_57 "电池模块电压极差一级报警值";
CM_ SG_ 2418339449 S2P_Lmt19_Over_DeltUModule2_57 "电池模块电压极差二级报警值";
CM_ SG_ 2418339449 S2P_Lmt19_Over_DeltUModule3_57 "电池模块电压极差三级报警值";
CM_ SG_ 2418339449 S2P_Lmt19_Over_DeltUModule4_57 "电池模块电压极差截止值";
CM_ SG_ 2418339450 S2P_Lmt19_Over_DeltUModule1_58 "电池模块电压极差一级报警值";
CM_ SG_ 2418339450 S2P_Lmt19_Over_DeltUModule2_58 "电池模块电压极差二级报警值";
CM_ SG_ 2418339450 S2P_Lmt19_Over_DeltUModule3_58 "电池模块电压极差三级报警值";
CM_ SG_ 2418339450 S2P_Lmt19_Over_DeltUModule4_58 "电池模块电压极差截止值";
CM_ SG_ 2418339451 S2P_Lmt19_Over_DeltUModule1_59 "电池模块电压极差一级报警值";
CM_ SG_ 2418339451 S2P_Lmt19_Over_DeltUModule2_59 "电池模块电压极差二级报警值";
CM_ SG_ 2418339451 S2P_Lmt19_Over_DeltUModule3_59 "电池模块电压极差三级报警值";
CM_ SG_ 2418339451 S2P_Lmt19_Over_DeltUModule4_59 "电池模块电压极差截止值";
CM_ SG_ 2418339452 S2P_Lmt19_Over_DeltUModule1_60 "电池模块电压极差一级报警值";
CM_ SG_ 2418339452 S2P_Lmt19_Over_DeltUModule2_60 "电池模块电压极差二级报警值";
CM_ SG_ 2418339452 S2P_Lmt19_Over_DeltUModule3_60 "电池模块电压极差三级报警值";
CM_ SG_ 2418339452 S2P_Lmt19_Over_DeltUModule4_60 "电池模块电压极差截止值";
CM_ SG_ 2418339453 S2P_Lmt19_Over_DeltUModule1_61 "电池模块电压极差一级报警值";
CM_ SG_ 2418339453 S2P_Lmt19_Over_DeltUModule2_61 "电池模块电压极差二级报警值";
CM_ SG_ 2418339453 S2P_Lmt19_Over_DeltUModule3_61 "电池模块电压极差三级报警值";
CM_ SG_ 2418339453 S2P_Lmt19_Over_DeltUModule4_61 "电池模块电压极差截止值";
CM_ SG_ 2418339454 S2P_Lmt19_Over_DeltUModule1_62 "电池模块电压极差一级报警值";
CM_ SG_ 2418339454 S2P_Lmt19_Over_DeltUModule2_62 "电池模块电压极差二级报警值";
CM_ SG_ 2418339454 S2P_Lmt19_Over_DeltUModule3_62 "电池模块电压极差三级报警值";
CM_ SG_ 2418339454 S2P_Lmt19_Over_DeltUModule4_62 "电池模块电压极差截止值";
CM_ SG_ 2418339455 S2P_Lmt19_Over_DeltUModule1_63 "电池模块电压极差一级报警值";
CM_ SG_ 2418339455 S2P_Lmt19_Over_DeltUModule2_63 "电池模块电压极差二级报警值";
CM_ SG_ 2418339455 S2P_Lmt19_Over_DeltUModule3_63 "电池模块电压极差三级报警值";
CM_ SG_ 2418339455 S2P_Lmt19_Over_DeltUModule4_63 "电池模块电压极差截止值";
CM_ SG_ 2418404929 S2P_Lmt20_Over_DeltUcell4_01 "电池单体电压极差截止值";
CM_ SG_ 2418404929 S2P_Lmt20_Over_DeltTcell4_01 "电池单体温度极差截止值";
CM_ SG_ 2418404929 S2P_Lmt20_Over_Ucell4_01 "电池单体充电截止电压";
CM_ SG_ 2418404929 S2P_Lmt20_Under_Ucell4_01 "电池单体放电截止电压";
CM_ SG_ 2418404929 S2P_Lmt20_Over_Tcell4_01 "电池单体高温截止温度";
CM_ SG_ 2418404930 S2P_Lmt20_Over_DeltUcell4_02 "电池单体电压极差截止值";
CM_ SG_ 2418404930 S2P_Lmt20_Over_DeltTcell4_02 "电池单体温度极差截止值";
CM_ SG_ 2418404930 S2P_Lmt20_Over_Ucell4_02 "电池单体充电截止电压";
CM_ SG_ 2418404930 S2P_Lmt20_Under_Ucell4_02 "电池单体放电截止电压";
CM_ SG_ 2418404930 S2P_Lmt20_Over_Tcell4_02 "电池单体高温截止温度";
CM_ SG_ 2418404931 S2P_Lmt20_Over_DeltUcell4_03 "电池单体电压极差截止值";
CM_ SG_ 2418404931 S2P_Lmt20_Over_DeltTcell4_03 "电池单体温度极差截止值";
CM_ SG_ 2418404931 S2P_Lmt20_Over_Ucell4_03 "电池单体充电截止电压";
CM_ SG_ 2418404931 S2P_Lmt20_Under_Ucell4_03 "电池单体放电截止电压";
CM_ SG_ 2418404931 S2P_Lmt20_Over_Tcell4_03 "电池单体高温截止温度";
CM_ SG_ 2418404932 S2P_Lmt20_Over_DeltUcell4_04 "电池单体电压极差截止值";
CM_ SG_ 2418404932 S2P_Lmt20_Over_DeltTcell4_04 "电池单体温度极差截止值";
CM_ SG_ 2418404932 S2P_Lmt20_Over_Ucell4_04 "电池单体充电截止电压";
CM_ SG_ 2418404932 S2P_Lmt20_Under_Ucell4_04 "电池单体放电截止电压";
CM_ SG_ 2418404932 S2P_Lmt20_Over_Tcell4_04 "电池单体高温截止温度";
CM_ SG_ 2418404933 S2P_Lmt20_Over_DeltUcell4_05 "电池单体电压极差截止值";
CM_ SG_ 2418404933 S2P_Lmt20_Over_DeltTcell4_05 "电池单体温度极差截止值";
CM_ SG_ 2418404933 S2P_Lmt20_Over_Ucell4_05 "电池单体充电截止电压";
CM_ SG_ 2418404933 S2P_Lmt20_Under_Ucell4_05 "电池单体放电截止电压";
CM_ SG_ 2418404933 S2P_Lmt20_Over_Tcell4_05 "电池单体高温截止温度";
CM_ SG_ 2418404934 S2P_Lmt20_Over_DeltUcell4_06 "电池单体电压极差截止值";
CM_ SG_ 2418404934 S2P_Lmt20_Over_DeltTcell4_06 "电池单体温度极差截止值";
CM_ SG_ 2418404934 S2P_Lmt20_Over_Ucell4_06 "电池单体充电截止电压";
CM_ SG_ 2418404934 S2P_Lmt20_Under_Ucell4_06 "电池单体放电截止电压";
CM_ SG_ 2418404934 S2P_Lmt20_Over_Tcell4_06 "电池单体高温截止温度";
CM_ SG_ 2418404935 S2P_Lmt20_Over_DeltUcell4_07 "电池单体电压极差截止值";
CM_ SG_ 2418404935 S2P_Lmt20_Over_DeltTcell4_07 "电池单体温度极差截止值";
CM_ SG_ 2418404935 S2P_Lmt20_Over_Ucell4_07 "电池单体充电截止电压";
CM_ SG_ 2418404935 S2P_Lmt20_Under_Ucell4_07 "电池单体放电截止电压";
CM_ SG_ 2418404935 S2P_Lmt20_Over_Tcell4_07 "电池单体高温截止温度";
CM_ SG_ 2418404936 S2P_Lmt20_Over_DeltUcell4_08 "电池单体电压极差截止值";
CM_ SG_ 2418404936 S2P_Lmt20_Over_DeltTcell4_08 "电池单体温度极差截止值";
CM_ SG_ 2418404936 S2P_Lmt20_Over_Ucell4_08 "电池单体充电截止电压";
CM_ SG_ 2418404936 S2P_Lmt20_Under_Ucell4_08 "电池单体放电截止电压";
CM_ SG_ 2418404936 S2P_Lmt20_Over_Tcell4_08 "电池单体高温截止温度";
CM_ SG_ 2418404937 S2P_Lmt20_Over_DeltUcell4_09 "电池单体电压极差截止值";
CM_ SG_ 2418404937 S2P_Lmt20_Over_DeltTcell4_09 "电池单体温度极差截止值";
CM_ SG_ 2418404937 S2P_Lmt20_Over_Ucell4_09 "电池单体充电截止电压";
CM_ SG_ 2418404937 S2P_Lmt20_Under_Ucell4_09 "电池单体放电截止电压";
CM_ SG_ 2418404937 S2P_Lmt20_Over_Tcell4_09 "电池单体高温截止温度";
CM_ SG_ 2418404938 S2P_Lmt20_Over_DeltUcell4_10 "电池单体电压极差截止值";
CM_ SG_ 2418404938 S2P_Lmt20_Over_DeltTcell4_10 "电池单体温度极差截止值";
CM_ SG_ 2418404938 S2P_Lmt20_Over_Ucell4_10 "电池单体充电截止电压";
CM_ SG_ 2418404938 S2P_Lmt20_Under_Ucell4_10 "电池单体放电截止电压";
CM_ SG_ 2418404938 S2P_Lmt20_Over_Tcell4_10 "电池单体高温截止温度";
CM_ SG_ 2418404939 S2P_Lmt20_Over_DeltUcell4_11 "电池单体电压极差截止值";
CM_ SG_ 2418404939 S2P_Lmt20_Over_DeltTcell4_11 "电池单体温度极差截止值";
CM_ SG_ 2418404939 S2P_Lmt20_Over_Ucell4_11 "电池单体充电截止电压";
CM_ SG_ 2418404939 S2P_Lmt20_Under_Ucell4_11 "电池单体放电截止电压";
CM_ SG_ 2418404939 S2P_Lmt20_Over_Tcell4_11 "电池单体高温截止温度";
CM_ SG_ 2418404940 S2P_Lmt20_Over_DeltUcell4_12 "电池单体电压极差截止值";
CM_ SG_ 2418404940 S2P_Lmt20_Over_DeltTcell4_12 "电池单体温度极差截止值";
CM_ SG_ 2418404940 S2P_Lmt20_Over_Ucell4_12 "电池单体充电截止电压";
CM_ SG_ 2418404940 S2P_Lmt20_Under_Ucell4_12 "电池单体放电截止电压";
CM_ SG_ 2418404940 S2P_Lmt20_Over_Tcell4_12 "电池单体高温截止温度";
CM_ SG_ 2418404941 S2P_Lmt20_Over_DeltUcell4_13 "电池单体电压极差截止值";
CM_ SG_ 2418404941 S2P_Lmt20_Over_DeltTcell4_13 "电池单体温度极差截止值";
CM_ SG_ 2418404941 S2P_Lmt20_Over_Ucell4_13 "电池单体充电截止电压";
CM_ SG_ 2418404941 S2P_Lmt20_Under_Ucell4_13 "电池单体放电截止电压";
CM_ SG_ 2418404941 S2P_Lmt20_Over_Tcell4_13 "电池单体高温截止温度";
CM_ SG_ 2418404942 S2P_Lmt20_Over_DeltUcell4_14 "电池单体电压极差截止值";
CM_ SG_ 2418404942 S2P_Lmt20_Over_DeltTcell4_14 "电池单体温度极差截止值";
CM_ SG_ 2418404942 S2P_Lmt20_Over_Ucell4_14 "电池单体充电截止电压";
CM_ SG_ 2418404942 S2P_Lmt20_Under_Ucell4_14 "电池单体放电截止电压";
CM_ SG_ 2418404942 S2P_Lmt20_Over_Tcell4_14 "电池单体高温截止温度";
CM_ SG_ 2418404943 S2P_Lmt20_Over_DeltUcell4_15 "电池单体电压极差截止值";
CM_ SG_ 2418404943 S2P_Lmt20_Over_DeltTcell4_15 "电池单体温度极差截止值";
CM_ SG_ 2418404943 S2P_Lmt20_Over_Ucell4_15 "电池单体充电截止电压";
CM_ SG_ 2418404943 S2P_Lmt20_Under_Ucell4_15 "电池单体放电截止电压";
CM_ SG_ 2418404943 S2P_Lmt20_Over_Tcell4_15 "电池单体高温截止温度";
VAL_ 2400841343 CSC_U_No_63 1 "CSC 1" 2 "CSC 2" 3 "CSC 3" 4 "CSC 4" 5 "CSC 5" 6 "CSC 6" ;
VAL_ 2400841343 CSC_Ucell_58_63 65535 "Invalid" ;
VAL_ 2400841343 CSC_Ucell_59_63 65535 "Invalid" ;
VAL_ 2400841343 CSC_Ucell_60_63 65535 "Invalid" ;
VAL_ 2400841343 CSC_Ucell_61_63 65535 "Invalid" ;
VAL_ 2400841343 CSC_Ucell_62_63 65535 "Invalid" ;
VAL_ 2400841343 CSC_Ucell_63_63 65535 "Invalid" ;
VAL_ 2400841343 CSC_Ucell_64_63 65535 "Invalid" ;
VAL_ 2400841343 CSC_Ucell_65_63 65535 "Invalid" ;
VAL_ 2400841343 CSC_Ucell_66_63 65535 "Invalid" ;
VAL_ 2400841343 CSC_Ucell_67_63 65535 "Invalid" ;
VAL_ 2400841343 CSC_Ucell_68_63 65535 "Invalid" ;
VAL_ 2400841343 CSC_Ucell_69_63 65535 "Invalid" ;
VAL_ 2400841343 CSC_Ucell_70_63 65535 "Invalid" ;
VAL_ 2400841343 CSC_Ucell_71_63 65535 "Invalid" ;
VAL_ 2400841343 CSC_Ucell_72_63 65535 "Invalid" ;
VAL_ 2400841343 CSC_Ucell_73_63 65535 "Invalid" ;
VAL_ 2400841343 CSC_Ucell_74_63 65535 "Invalid" ;
VAL_ 2400841343 CSC_Ucell_75_63 65535 "Invalid" ;
VAL_ 2400841343 CSC_Ucell_76_63 65535 "Invalid" ;
VAL_ 2400841343 CSC_Ucell_77_63 65535 "Invalid" ;
VAL_ 2400841343 CSC_Ucell_78_63 65535 "Invalid" ;
VAL_ 2400841343 CSC_Ucell_79_63 65535 "Invalid" ;
VAL_ 2400841343 CSC_Ucell_80_63 65535 "Invalid" ;
VAL_ 2400841343 CSC_Ucell_81_63 65535 "Invalid" ;
VAL_ 2400841343 CSC_Ucell_82_63 65535 "Invalid" ;
VAL_ 2400841343 CSC_Ucell_83_63 65535 "Invalid" ;
VAL_ 2400841343 CSC_Ucell_84_63 65535 "Invalid" ;
VAL_ 2400841343 CSC_Ucell_85_63 65535 "Invalid" ;
VAL_ 2400841343 CSC_Ucell_86_63 65535 "Invalid" ;
VAL_ 2400841343 CSC_Ucell_87_63 65535 "Invalid" ;
VAL_ 2400841343 CSC_Ucell_88_63 65535 "Invalid" ;
VAL_ 2400841343 CSC_Ucell_89_63 65535 "Invalid" ;
VAL_ 2400841343 CSC_Ucell_90_63 65535 "Invalid" ;
VAL_ 2400841343 CSC_Ucell_91_63 65535 "Invalid" ;
VAL_ 2400841343 CSC_Ucell_92_63 65535 "Invalid" ;
VAL_ 2400841343 CSC_Ucell_93_63 65535 "Invalid" ;
VAL_ 2400841343 CSC_Ucell_94_63 65535 "Invalid" ;
VAL_ 2400841343 CSC_Ucell_95_63 65535 "Invalid" ;
VAL_ 2400841343 CSC_Ucell_96_63 65535 "Invalid" ;
VAL_ 2400841343 CSC_Ucell_97_63 65535 "Invalid" ;
VAL_ 2400841343 CSC_Ucell_98_63 65535 "Invalid" ;
VAL_ 2400841343 CSC_Ucell_99_63 65535 "Invalid" ;
VAL_ 2400841343 CSC_Ucell_100_63 65535 "Invalid" ;
VAL_ 2400841343 CSC_Ucell_101_63 65535 "Invalid" ;
VAL_ 2400841343 CSC_Ucell_102_63 65535 "Invalid" ;
VAL_ 2400841343 CSC_Ucell_103_63 65535 "Invalid" ;
VAL_ 2400841343 CSC_Ucell_104_63 65535 "Invalid" ;
VAL_ 2400841343 CSC_Ucell_105_63 65535 "Invalid" ;
VAL_ 2400841343 CSC_Ucell_106_63 65535 "Invalid" ;
VAL_ 2400841343 CSC_Ucell_107_63 65535 "Invalid" ;
VAL_ 2400841343 CSC_Ucell_108_63 65535 "Invalid" ;
VAL_ 2401300033 State_Balance_Status_1_01 0 "forbid balance" 1 "on balance" 2 "permit balance" 3 "balancing stopped" 4 "waitting for balance" ;
VAL_ 2401300033 State_Balance_Fault_1_01 0 "Normal" 1 "Failure" ;
VAL_ 2401300034 State_Balance_Status_1_02 0 "forbid balance" 1 "on balance" 2 "permit balance" 3 "balancing stopped" 4 "waitting for balance" ;
VAL_ 2401300034 State_Balance_Fault_1_02 0 "Normal" 1 "Failure" ;
VAL_ 2401300035 State_Balance_Status_1_03 0 "forbid balance" 1 "on balance" 2 "permit balance" 3 "balancing stopped" 4 "waitting for balance" ;
VAL_ 2401300035 State_Balance_Fault_1_03 0 "Normal" 1 "Failure" ;
VAL_ 2401300036 State_Balance_Status_1_04 0 "forbid balance" 1 "on balance" 2 "permit balance" 3 "balancing stopped" 4 "waitting for balance" ;
VAL_ 2401300036 State_Balance_Fault_1_04 0 "Normal" 1 "Failure" ;
VAL_ 2401300037 State_Balance_Status_1_05 0 "forbid balance" 1 "on balance" 2 "permit balance" 3 "balancing stopped" 4 "waitting for balance" ;
VAL_ 2401300037 State_Balance_Fault_1_05 0 "Normal" 1 "Failure" ;
VAL_ 2401300038 State_Balance_Status_1_06 0 "forbid balance" 1 "on balance" 2 "permit balance" 3 "balancing stopped" 4 "waitting for balance" ;
VAL_ 2401300038 State_Balance_Fault_1_06 0 "Normal" 1 "Failure" ;
VAL_ 2401300039 State_Balance_Status_1_07 0 "forbid balance" 1 "on balance" 2 "permit balance" 3 "balancing stopped" 4 "waitting for balance" ;
VAL_ 2401300039 State_Balance_Fault_1_07 0 "Normal" 1 "Failure" ;
VAL_ 2401300040 State_Balance_Status_1_08 0 "forbid balance" 1 "on balance" 2 "permit balance" 3 "balancing stopped" 4 "waitting for balance" ;
VAL_ 2401300040 State_Balance_Fault_1_08 0 "Normal" 1 "Failure" ;
VAL_ 2401300041 State_Balance_Status_1_09 0 "forbid balance" 1 "on balance" 2 "permit balance" 3 "balancing stopped" 4 "waitting for balance" ;
VAL_ 2401300041 State_Balance_Fault_1_09 0 "Normal" 1 "Failure" ;
VAL_ 2401300042 State_Balance_Status_1_10 0 "forbid balance" 1 "on balance" 2 "permit balance" 3 "balancing stopped" 4 "waitting for balance" ;
VAL_ 2401300042 State_Balance_Fault_1_10 0 "Normal" 1 "Failure" ;
VAL_ 2401300043 State_Balance_Status_1_11 0 "forbid balance" 1 "on balance" 2 "permit balance" 3 "balancing stopped" 4 "waitting for balance" ;
VAL_ 2401300043 State_Balance_Fault_1_11 0 "Normal" 1 "Failure" ;
VAL_ 2401300044 State_Balance_Status_1_12 0 "forbid balance" 1 "on balance" 2 "permit balance" 3 "balancing stopped" 4 "waitting for balance" ;
VAL_ 2401300044 State_Balance_Fault_1_12 0 "Normal" 1 "Failure" ;
VAL_ 2401300045 State_Balance_Status_1_13 0 "forbid balance" 1 "on balance" 2 "permit balance" 3 "balancing stopped" 4 "waitting for balance" ;
VAL_ 2401300045 State_Balance_Fault_1_13 0 "Normal" 1 "Failure" ;
VAL_ 2401300046 State_Balance_Status_1_14 0 "forbid balance" 1 "on balance" 2 "permit balance" 3 "balancing stopped" 4 "waitting for balance" ;
VAL_ 2401300046 State_Balance_Fault_1_14 0 "Normal" 1 "Failure" ;
VAL_ 2401300047 State_Balance_Status_1_15 0 "forbid balance" 1 "on balance" 2 "permit balance" 3 "balancing stopped" 4 "waitting for balance" ;
VAL_ 2401300047 State_Balance_Fault_1_15 0 "Normal" 1 "Failure" ;
VAL_ 2401300048 State_Balance_Status_1_16 0 "forbid balance" 1 "on balance" 2 "permit balance" 3 "balancing stopped" 4 "waitting for balance" ;
VAL_ 2401300048 State_Balance_Fault_1_16 0 "Normal" 1 "Failure" ;
VAL_ 2401300049 State_Balance_Status_1_17 0 "forbid balance" 1 "on balance" 2 "permit balance" 3 "balancing stopped" 4 "waitting for balance" ;
VAL_ 2401300049 State_Balance_Fault_1_17 0 "Normal" 1 "Failure" ;
VAL_ 2401300050 State_Balance_Status_1_18 0 "forbid balance" 1 "on balance" 2 "permit balance" 3 "balancing stopped" 4 "waitting for balance" ;
VAL_ 2401300050 State_Balance_Fault_1_18 0 "Normal" 1 "Failure" ;
VAL_ 2401300051 State_Balance_Status_1_19 0 "forbid balance" 1 "on balance" 2 "permit balance" 3 "balancing stopped" 4 "waitting for balance" ;
VAL_ 2401300051 State_Balance_Fault_1_19 0 "Normal" 1 "Failure" ;
VAL_ 2401300052 State_Balance_Status_1_20 0 "forbid balance" 1 "on balance" 2 "permit balance" 3 "balancing stopped" 4 "waitting for balance" ;
VAL_ 2401300052 State_Balance_Fault_1_20 0 "Normal" 1 "Failure" ;
VAL_ 2401300053 State_Balance_Status_1_21 0 "forbid balance" 1 "on balance" 2 "permit balance" 3 "balancing stopped" 4 "waitting for balance" ;
VAL_ 2401300053 State_Balance_Fault_1_21 0 "Normal" 1 "Failure" ;
VAL_ 2401300054 State_Balance_Status_1_22 0 "forbid balance" 1 "on balance" 2 "permit balance" 3 "balancing stopped" 4 "waitting for balance" ;
VAL_ 2401300054 State_Balance_Fault_1_22 0 "Normal" 1 "Failure" ;
VAL_ 2401300055 State_Balance_Status_1_23 0 "forbid balance" 1 "on balance" 2 "permit balance" 3 "balancing stopped" 4 "waitting for balance" ;
VAL_ 2401300055 State_Balance_Fault_1_23 0 "Normal" 1 "Failure" ;
VAL_ 2401300056 State_Balance_Status_1_24 0 "forbid balance" 1 "on balance" 2 "permit balance" 3 "balancing stopped" 4 "waitting for balance" ;
VAL_ 2401300056 State_Balance_Fault_1_24 0 "Normal" 1 "Failure" ;
VAL_ 2401300057 State_Balance_Status_1_25 0 "forbid balance" 1 "on balance" 2 "permit balance" 3 "balancing stopped" 4 "waitting for balance" ;
VAL_ 2401300057 State_Balance_Fault_1_25 0 "Normal" 1 "Failure" ;
VAL_ 2401300058 State_Balance_Status_1_26 0 "forbid balance" 1 "on balance" 2 "permit balance" 3 "balancing stopped" 4 "waitting for balance" ;
VAL_ 2401300058 State_Balance_Fault_1_26 0 "Normal" 1 "Failure" ;
VAL_ 2401300059 State_Balance_Status_1_27 0 "forbid balance" 1 "on balance" 2 "permit balance" 3 "balancing stopped" 4 "waitting for balance" ;
VAL_ 2401300059 State_Balance_Fault_1_27 0 "Normal" 1 "Failure" ;
VAL_ 2401300060 State_Balance_Status_1_28 0 "forbid balance" 1 "on balance" 2 "permit balance" 3 "balancing stopped" 4 "waitting for balance" ;
VAL_ 2401300060 State_Balance_Fault_1_28 0 "Normal" 1 "Failure" ;
VAL_ 2401300061 State_Balance_Status_1_29 0 "forbid balance" 1 "on balance" 2 "permit balance" 3 "balancing stopped" 4 "waitting for balance" ;
VAL_ 2401300061 State_Balance_Fault_1_29 0 "Normal" 1 "Failure" ;
VAL_ 2401300062 State_Balance_Status_1_30 0 "forbid balance" 1 "on balance" 2 "permit balance" 3 "balancing stopped" 4 "waitting for balance" ;
VAL_ 2401300062 State_Balance_Fault_1_30 0 "Normal" 1 "Failure" ;
VAL_ 2401300063 State_Balance_Status_1_31 0 "forbid balance" 1 "on balance" 2 "permit balance" 3 "balancing stopped" 4 "waitting for balance" ;
VAL_ 2401300063 State_Balance_Fault_1_31 0 "Normal" 1 "Failure" ;
VAL_ 2401300064 State_Balance_Status_1_32 0 "forbid balance" 1 "on balance" 2 "permit balance" 3 "balancing stopped" 4 "waitting for balance" ;
VAL_ 2401300064 State_Balance_Fault_1_32 0 "Normal" 1 "Failure" ;
VAL_ 2401300065 State_Balance_Status_1_33 0 "forbid balance" 1 "on balance" 2 "permit balance" 3 "balancing stopped" 4 "waitting for balance" ;
VAL_ 2401300065 State_Balance_Fault_1_33 0 "Normal" 1 "Failure" ;
VAL_ 2401300066 State_Balance_Status_1_34 0 "forbid balance" 1 "on balance" 2 "permit balance" 3 "balancing stopped" 4 "waitting for balance" ;
VAL_ 2401300066 State_Balance_Fault_1_34 0 "Normal" 1 "Failure" ;
VAL_ 2401300067 State_Balance_Status_1_35 0 "forbid balance" 1 "on balance" 2 "permit balance" 3 "balancing stopped" 4 "waitting for balance" ;
VAL_ 2401300067 State_Balance_Fault_1_35 0 "Normal" 1 "Failure" ;
VAL_ 2401300068 State_Balance_Status_1_36 0 "forbid balance" 1 "on balance" 2 "permit balance" 3 "balancing stopped" 4 "waitting for balance" ;
VAL_ 2401300068 State_Balance_Fault_1_36 0 "Normal" 1 "Failure" ;
VAL_ 2401300069 State_Balance_Status_1_37 0 "forbid balance" 1 "on balance" 2 "permit balance" 3 "balancing stopped" 4 "waitting for balance" ;
VAL_ 2401300069 State_Balance_Fault_1_37 0 "Normal" 1 "Failure" ;
VAL_ 2401300070 State_Balance_Status_1_38 0 "forbid balance" 1 "on balance" 2 "permit balance" 3 "balancing stopped" 4 "waitting for balance" ;
VAL_ 2401300070 State_Balance_Fault_1_38 0 "Normal" 1 "Failure" ;
VAL_ 2401300071 State_Balance_Status_1_39 0 "forbid balance" 1 "on balance" 2 "permit balance" 3 "balancing stopped" 4 "waitting for balance" ;
VAL_ 2401300071 State_Balance_Fault_1_39 0 "Normal" 1 "Failure" ;
VAL_ 2401300072 State_Balance_Status_1_40 0 "forbid balance" 1 "on balance" 2 "permit balance" 3 "balancing stopped" 4 "waitting for balance" ;
VAL_ 2401300072 State_Balance_Fault_1_40 0 "Normal" 1 "Failure" ;
VAL_ 2401300073 State_Balance_Status_1_41 0 "forbid balance" 1 "on balance" 2 "permit balance" 3 "balancing stopped" 4 "waitting for balance" ;
VAL_ 2401300073 State_Balance_Fault_1_41 0 "Normal" 1 "Failure" ;
VAL_ 2401300074 State_Balance_Status_1_42 0 "forbid balance" 1 "on balance" 2 "permit balance" 3 "balancing stopped" 4 "waitting for balance" ;
VAL_ 2401300074 State_Balance_Fault_1_42 0 "Normal" 1 "Failure" ;
VAL_ 2401300075 State_Balance_Status_1_43 0 "forbid balance" 1 "on balance" 2 "permit balance" 3 "balancing stopped" 4 "waitting for balance" ;
VAL_ 2401300075 State_Balance_Fault_1_43 0 "Normal" 1 "Failure" ;
VAL_ 2401300076 State_Balance_Status_1_44 0 "forbid balance" 1 "on balance" 2 "permit balance" 3 "balancing stopped" 4 "waitting for balance" ;
VAL_ 2401300076 State_Balance_Fault_1_44 0 "Normal" 1 "Failure" ;
VAL_ 2401300077 State_Balance_Status_1_45 0 "forbid balance" 1 "on balance" 2 "permit balance" 3 "balancing stopped" 4 "waitting for balance" ;
VAL_ 2401300077 State_Balance_Fault_1_45 0 "Normal" 1 "Failure" ;
VAL_ 2401300078 State_Balance_Status_1_46 0 "forbid balance" 1 "on balance" 2 "permit balance" 3 "balancing stopped" 4 "waitting for balance" ;
VAL_ 2401300078 State_Balance_Fault_1_46 0 "Normal" 1 "Failure" ;
VAL_ 2401300079 State_Balance_Status_1_47 0 "forbid balance" 1 "on balance" 2 "permit balance" 3 "balancing stopped" 4 "waitting for balance" ;
VAL_ 2401300079 State_Balance_Fault_1_47 0 "Normal" 1 "Failure" ;
VAL_ 2401300080 State_Balance_Status_1_48 0 "forbid balance" 1 "on balance" 2 "permit balance" 3 "balancing stopped" 4 "waitting for balance" ;
VAL_ 2401300080 State_Balance_Fault_1_48 0 "Normal" 1 "Failure" ;
VAL_ 2401300081 State_Balance_Status_1_49 0 "forbid balance" 1 "on balance" 2 "permit balance" 3 "balancing stopped" 4 "waitting for balance" ;
VAL_ 2401300081 State_Balance_Fault_1_49 0 "Normal" 1 "Failure" ;
VAL_ 2401300082 State_Balance_Status_1_50 0 "forbid balance" 1 "on balance" 2 "permit balance" 3 "balancing stopped" 4 "waitting for balance" ;
VAL_ 2401300082 State_Balance_Fault_1_50 0 "Normal" 1 "Failure" ;
VAL_ 2401300083 State_Balance_Status_1_51 0 "forbid balance" 1 "on balance" 2 "permit balance" 3 "balancing stopped" 4 "waitting for balance" ;
VAL_ 2401300083 State_Balance_Fault_1_51 0 "Normal" 1 "Failure" ;
VAL_ 2401300084 State_Balance_Status_1_52 0 "forbid balance" 1 "on balance" 2 "permit balance" 3 "balancing stopped" 4 "waitting for balance" ;
VAL_ 2401300084 State_Balance_Fault_1_52 0 "Normal" 1 "Failure" ;
VAL_ 2401300085 State_Balance_Status_1_53 0 "forbid balance" 1 "on balance" 2 "permit balance" 3 "balancing stopped" 4 "waitting for balance" ;
VAL_ 2401300085 State_Balance_Fault_1_53 0 "Normal" 1 "Failure" ;
VAL_ 2401300086 State_Balance_Status_1_54 0 "forbid balance" 1 "on balance" 2 "permit balance" 3 "balancing stopped" 4 "waitting for balance" ;
VAL_ 2401300086 State_Balance_Fault_1_54 0 "Normal" 1 "Failure" ;
VAL_ 2401300087 State_Balance_Status_1_55 0 "forbid balance" 1 "on balance" 2 "permit balance" 3 "balancing stopped" 4 "waitting for balance" ;
VAL_ 2401300087 State_Balance_Fault_1_55 0 "Normal" 1 "Failure" ;
VAL_ 2401300088 State_Balance_Status_1_56 0 "forbid balance" 1 "on balance" 2 "permit balance" 3 "balancing stopped" 4 "waitting for balance" ;
VAL_ 2401300088 State_Balance_Fault_1_56 0 "Normal" 1 "Failure" ;
VAL_ 2401300089 State_Balance_Status_1_57 0 "forbid balance" 1 "on balance" 2 "permit balance" 3 "balancing stopped" 4 "waitting for balance" ;
VAL_ 2401300089 State_Balance_Fault_1_57 0 "Normal" 1 "Failure" ;
VAL_ 2401300090 State_Balance_Status_1_58 0 "forbid balance" 1 "on balance" 2 "permit balance" 3 "balancing stopped" 4 "waitting for balance" ;
VAL_ 2401300090 State_Balance_Fault_1_58 0 "Normal" 1 "Failure" ;
VAL_ 2401300091 State_Balance_Status_1_59 0 "forbid balance" 1 "on balance" 2 "permit balance" 3 "balancing stopped" 4 "waitting for balance" ;
VAL_ 2401300091 State_Balance_Fault_1_59 0 "Normal" 1 "Failure" ;
VAL_ 2401300092 State_Balance_Status_1_60 0 "forbid balance" 1 "on balance" 2 "permit balance" 3 "balancing stopped" 4 "waitting for balance" ;
VAL_ 2401300092 State_Balance_Fault_1_60 0 "Normal" 1 "Failure" ;
VAL_ 2401300093 State_Balance_Status_1_61 0 "forbid balance" 1 "on balance" 2 "permit balance" 3 "balancing stopped" 4 "waitting for balance" ;
VAL_ 2401300093 State_Balance_Fault_1_61 0 "Normal" 1 "Failure" ;
VAL_ 2401300094 State_Balance_Status_1_62 0 "forbid balance" 1 "on balance" 2 "permit balance" 3 "balancing stopped" 4 "waitting for balance" ;
VAL_ 2401300094 State_Balance_Fault_1_62 0 "Normal" 1 "Failure" ;
VAL_ 2401300095 State_Balance_Status_1_63 0 "forbid balance" 1 "on balance" 2 "permit balance" 3 "balancing stopped" 4 "waitting for balance" ;
VAL_ 2401300095 State_Balance_Fault_1_63 0 "Normal" 1 "Failure" ;
VAL_ 2401365569 State_Balance_Status_2_01 0 "forbid balance" 1 "on balance" 2 "permit balance" 3 "balancing stopped" 4 "waitting for balance" ;
VAL_ 2401365569 State_Balance_Fault_2_01 0 "Normal" 1 "Failure" ;
VAL_ 2401365570 State_Balance_Status_2_02 0 "forbid balance" 1 "on balance" 2 "permit balance" 3 "balancing stopped" 4 "waitting for balance" ;
VAL_ 2401365570 State_Balance_Fault_2_02 0 "Normal" 1 "Failure" ;
VAL_ 2401365571 State_Balance_Status_2_03 0 "forbid balance" 1 "on balance" 2 "permit balance" 3 "balancing stopped" 4 "waitting for balance" ;
VAL_ 2401365571 State_Balance_Fault_2_03 0 "Normal" 1 "Failure" ;
VAL_ 2401365572 State_Balance_Status_2_04 0 "forbid balance" 1 "on balance" 2 "permit balance" 3 "balancing stopped" 4 "waitting for balance" ;
VAL_ 2401365572 State_Balance_Fault_2_04 0 "Normal" 1 "Failure" ;
VAL_ 2401365573 State_Balance_Status_2_05 0 "forbid balance" 1 "on balance" 2 "permit balance" 3 "balancing stopped" 4 "waitting for balance" ;
VAL_ 2401365573 State_Balance_Fault_2_05 0 "Normal" 1 "Failure" ;
VAL_ 2401365574 State_Balance_Status_2_06 0 "forbid balance" 1 "on balance" 2 "permit balance" 3 "balancing stopped" 4 "waitting for balance" ;
VAL_ 2401365574 State_Balance_Fault_2_06 0 "Normal" 1 "Failure" ;
VAL_ 2401365575 State_Balance_Status_2_07 0 "forbid balance" 1 "on balance" 2 "permit balance" 3 "balancing stopped" 4 "waitting for balance" ;
VAL_ 2401365575 State_Balance_Fault_2_07 0 "Normal" 1 "Failure" ;
VAL_ 2401365576 State_Balance_Status_2_08 0 "forbid balance" 1 "on balance" 2 "permit balance" 3 "balancing stopped" 4 "waitting for balance" ;
VAL_ 2401365576 State_Balance_Fault_2_08 0 "Normal" 1 "Failure" ;
VAL_ 2401365577 State_Balance_Status_2_09 0 "forbid balance" 1 "on balance" 2 "permit balance" 3 "balancing stopped" 4 "waitting for balance" ;
VAL_ 2401365577 State_Balance_Fault_2_09 0 "Normal" 1 "Failure" ;
VAL_ 2401365578 State_Balance_Status_2_10 0 "forbid balance" 1 "on balance" 2 "permit balance" 3 "balancing stopped" 4 "waitting for balance" ;
VAL_ 2401365578 State_Balance_Fault_2_10 0 "Normal" 1 "Failure" ;
VAL_ 2401365579 State_Balance_Status_2_11 0 "forbid balance" 1 "on balance" 2 "permit balance" 3 "balancing stopped" 4 "waitting for balance" ;
VAL_ 2401365579 State_Balance_Fault_2_11 0 "Normal" 1 "Failure" ;
VAL_ 2401365580 State_Balance_Status_2_12 0 "forbid balance" 1 "on balance" 2 "permit balance" 3 "balancing stopped" 4 "waitting for balance" ;
VAL_ 2401365580 State_Balance_Fault_2_12 0 "Normal" 1 "Failure" ;
VAL_ 2401365581 State_Balance_Status_2_13 0 "forbid balance" 1 "on balance" 2 "permit balance" 3 "balancing stopped" 4 "waitting for balance" ;
VAL_ 2401365581 State_Balance_Fault_2_13 0 "Normal" 1 "Failure" ;
VAL_ 2401365582 State_Balance_Status_2_14 0 "forbid balance" 1 "on balance" 2 "permit balance" 3 "balancing stopped" 4 "waitting for balance" ;
VAL_ 2401365582 State_Balance_Fault_2_14 0 "Normal" 1 "Failure" ;
VAL_ 2401365583 State_Balance_Status_2_15 0 "forbid balance" 1 "on balance" 2 "permit balance" 3 "balancing stopped" 4 "waitting for balance" ;
VAL_ 2401365583 State_Balance_Fault_2_15 0 "Normal" 1 "Failure" ;
VAL_ 2401365584 State_Balance_Status_2_16 0 "forbid balance" 1 "on balance" 2 "permit balance" 3 "balancing stopped" 4 "waitting for balance" ;
VAL_ 2401365584 State_Balance_Fault_2_16 0 "Normal" 1 "Failure" ;
VAL_ 2401365585 State_Balance_Status_2_17 0 "forbid balance" 1 "on balance" 2 "permit balance" 3 "balancing stopped" 4 "waitting for balance" ;
VAL_ 2401365585 State_Balance_Fault_2_17 0 "Normal" 1 "Failure" ;
VAL_ 2401365586 State_Balance_Status_2_18 0 "forbid balance" 1 "on balance" 2 "permit balance" 3 "balancing stopped" 4 "waitting for balance" ;
VAL_ 2401365586 State_Balance_Fault_2_18 0 "Normal" 1 "Failure" ;
VAL_ 2401365587 State_Balance_Status_2_19 0 "forbid balance" 1 "on balance" 2 "permit balance" 3 "balancing stopped" 4 "waitting for balance" ;
VAL_ 2401365587 State_Balance_Fault_2_19 0 "Normal" 1 "Failure" ;
VAL_ 2401365588 State_Balance_Status_2_20 0 "forbid balance" 1 "on balance" 2 "permit balance" 3 "balancing stopped" 4 "waitting for balance" ;
VAL_ 2401365588 State_Balance_Fault_2_20 0 "Normal" 1 "Failure" ;
VAL_ 2401365589 State_Balance_Status_2_21 0 "forbid balance" 1 "on balance" 2 "permit balance" 3 "balancing stopped" 4 "waitting for balance" ;
VAL_ 2401365589 State_Balance_Fault_2_21 0 "Normal" 1 "Failure" ;
VAL_ 2401365590 State_Balance_Status_2_22 0 "forbid balance" 1 "on balance" 2 "permit balance" 3 "balancing stopped" 4 "waitting for balance" ;
VAL_ 2401365590 State_Balance_Fault_2_22 0 "Normal" 1 "Failure" ;
VAL_ 2401365591 State_Balance_Status_2_23 0 "forbid balance" 1 "on balance" 2 "permit balance" 3 "balancing stopped" 4 "waitting for balance" ;
VAL_ 2401365591 State_Balance_Fault_2_23 0 "Normal" 1 "Failure" ;
VAL_ 2401365592 State_Balance_Status_2_24 0 "forbid balance" 1 "on balance" 2 "permit balance" 3 "balancing stopped" 4 "waitting for balance" ;
VAL_ 2401365592 State_Balance_Fault_2_24 0 "Normal" 1 "Failure" ;
VAL_ 2401365593 State_Balance_Status_2_25 0 "forbid balance" 1 "on balance" 2 "permit balance" 3 "balancing stopped" 4 "waitting for balance" ;
VAL_ 2401365593 State_Balance_Fault_2_25 0 "Normal" 1 "Failure" ;
VAL_ 2401365594 State_Balance_Status_2_26 0 "forbid balance" 1 "on balance" 2 "permit balance" 3 "balancing stopped" 4 "waitting for balance" ;
VAL_ 2401365594 State_Balance_Fault_2_26 0 "Normal" 1 "Failure" ;
VAL_ 2401365595 State_Balance_Status_2_27 0 "forbid balance" 1 "on balance" 2 "permit balance" 3 "balancing stopped" 4 "waitting for balance" ;
VAL_ 2401365595 State_Balance_Fault_2_27 0 "Normal" 1 "Failure" ;
VAL_ 2401365596 State_Balance_Status_2_28 0 "forbid balance" 1 "on balance" 2 "permit balance" 3 "balancing stopped" 4 "waitting for balance" ;
VAL_ 2401365596 State_Balance_Fault_2_28 0 "Normal" 1 "Failure" ;
VAL_ 2401365597 State_Balance_Status_2_29 0 "forbid balance" 1 "on balance" 2 "permit balance" 3 "balancing stopped" 4 "waitting for balance" ;
VAL_ 2401365597 State_Balance_Fault_2_29 0 "Normal" 1 "Failure" ;
VAL_ 2401365598 State_Balance_Status_2_30 0 "forbid balance" 1 "on balance" 2 "permit balance" 3 "balancing stopped" 4 "waitting for balance" ;
VAL_ 2401365598 State_Balance_Fault_2_30 0 "Normal" 1 "Failure" ;
VAL_ 2401365599 State_Balance_Status_2_31 0 "forbid balance" 1 "on balance" 2 "permit balance" 3 "balancing stopped" 4 "waitting for balance" ;
VAL_ 2401365599 State_Balance_Fault_2_31 0 "Normal" 1 "Failure" ;
VAL_ 2401365600 State_Balance_Status_2_32 0 "forbid balance" 1 "on balance" 2 "permit balance" 3 "balancing stopped" 4 "waitting for balance" ;
VAL_ 2401365600 State_Balance_Fault_2_32 0 "Normal" 1 "Failure" ;
VAL_ 2401365601 State_Balance_Status_2_33 0 "forbid balance" 1 "on balance" 2 "permit balance" 3 "balancing stopped" 4 "waitting for balance" ;
VAL_ 2401365601 State_Balance_Fault_2_33 0 "Normal" 1 "Failure" ;
VAL_ 2401365602 State_Balance_Status_2_34 0 "forbid balance" 1 "on balance" 2 "permit balance" 3 "balancing stopped" 4 "waitting for balance" ;
VAL_ 2401365602 State_Balance_Fault_2_34 0 "Normal" 1 "Failure" ;
VAL_ 2401365603 State_Balance_Status_2_35 0 "forbid balance" 1 "on balance" 2 "permit balance" 3 "balancing stopped" 4 "waitting for balance" ;
VAL_ 2401365603 State_Balance_Fault_2_35 0 "Normal" 1 "Failure" ;
VAL_ 2401365604 State_Balance_Status_2_36 0 "forbid balance" 1 "on balance" 2 "permit balance" 3 "balancing stopped" 4 "waitting for balance" ;
VAL_ 2401365604 State_Balance_Fault_2_36 0 "Normal" 1 "Failure" ;
VAL_ 2401365605 State_Balance_Status_2_37 0 "forbid balance" 1 "on balance" 2 "permit balance" 3 "balancing stopped" 4 "waitting for balance" ;
VAL_ 2401365605 State_Balance_Fault_2_37 0 "Normal" 1 "Failure" ;
VAL_ 2401365606 State_Balance_Status_2_38 0 "forbid balance" 1 "on balance" 2 "permit balance" 3 "balancing stopped" 4 "waitting for balance" ;
VAL_ 2401365606 State_Balance_Fault_2_38 0 "Normal" 1 "Failure" ;
VAL_ 2401365607 State_Balance_Status_2_39 0 "forbid balance" 1 "on balance" 2 "permit balance" 3 "balancing stopped" 4 "waitting for balance" ;
VAL_ 2401365607 State_Balance_Fault_2_39 0 "Normal" 1 "Failure" ;
VAL_ 2401365608 State_Balance_Status_2_40 0 "forbid balance" 1 "on balance" 2 "permit balance" 3 "balancing stopped" 4 "waitting for balance" ;
VAL_ 2401365608 State_Balance_Fault_2_40 0 "Normal" 1 "Failure" ;
VAL_ 2401365609 State_Balance_Status_2_41 0 "forbid balance" 1 "on balance" 2 "permit balance" 3 "balancing stopped" 4 "waitting for balance" ;
VAL_ 2401365609 State_Balance_Fault_2_41 0 "Normal" 1 "Failure" ;
VAL_ 2401365610 State_Balance_Status_2_42 0 "forbid balance" 1 "on balance" 2 "permit balance" 3 "balancing stopped" 4 "waitting for balance" ;
VAL_ 2401365610 State_Balance_Fault_2_42 0 "Normal" 1 "Failure" ;
VAL_ 2401365611 State_Balance_Status_2_43 0 "forbid balance" 1 "on balance" 2 "permit balance" 3 "balancing stopped" 4 "waitting for balance" ;
VAL_ 2401365611 State_Balance_Fault_2_43 0 "Normal" 1 "Failure" ;
VAL_ 2401365612 State_Balance_Status_2_44 0 "forbid balance" 1 "on balance" 2 "permit balance" 3 "balancing stopped" 4 "waitting for balance" ;
VAL_ 2401365612 State_Balance_Fault_2_44 0 "Normal" 1 "Failure" ;
VAL_ 2401365613 State_Balance_Status_2_45 0 "forbid balance" 1 "on balance" 2 "permit balance" 3 "balancing stopped" 4 "waitting for balance" ;
VAL_ 2401365613 State_Balance_Fault_2_45 0 "Normal" 1 "Failure" ;
VAL_ 2401365614 State_Balance_Status_2_46 0 "forbid balance" 1 "on balance" 2 "permit balance" 3 "balancing stopped" 4 "waitting for balance" ;
VAL_ 2401365614 State_Balance_Fault_2_46 0 "Normal" 1 "Failure" ;
VAL_ 2401365615 State_Balance_Status_2_47 0 "forbid balance" 1 "on balance" 2 "permit balance" 3 "balancing stopped" 4 "waitting for balance" ;
VAL_ 2401365615 State_Balance_Fault_2_47 0 "Normal" 1 "Failure" ;
VAL_ 2401365616 State_Balance_Status_2_48 0 "forbid balance" 1 "on balance" 2 "permit balance" 3 "balancing stopped" 4 "waitting for balance" ;
VAL_ 2401365616 State_Balance_Fault_2_48 0 "Normal" 1 "Failure" ;
VAL_ 2401365617 State_Balance_Status_2_49 0 "forbid balance" 1 "on balance" 2 "permit balance" 3 "balancing stopped" 4 "waitting for balance" ;
VAL_ 2401365617 State_Balance_Fault_2_49 0 "Normal" 1 "Failure" ;
VAL_ 2401365618 State_Balance_Status_2_50 0 "forbid balance" 1 "on balance" 2 "permit balance" 3 "balancing stopped" 4 "waitting for balance" ;
VAL_ 2401365618 State_Balance_Fault_2_50 0 "Normal" 1 "Failure" ;
VAL_ 2401365619 State_Balance_Status_2_51 0 "forbid balance" 1 "on balance" 2 "permit balance" 3 "balancing stopped" 4 "waitting for balance" ;
VAL_ 2401365619 State_Balance_Fault_2_51 0 "Normal" 1 "Failure" ;
VAL_ 2401365620 State_Balance_Status_2_52 0 "forbid balance" 1 "on balance" 2 "permit balance" 3 "balancing stopped" 4 "waitting for balance" ;
VAL_ 2401365620 State_Balance_Fault_2_52 0 "Normal" 1 "Failure" ;
VAL_ 2401365621 State_Balance_Status_2_53 0 "forbid balance" 1 "on balance" 2 "permit balance" 3 "balancing stopped" 4 "waitting for balance" ;
VAL_ 2401365621 State_Balance_Fault_2_53 0 "Normal" 1 "Failure" ;
VAL_ 2401365622 State_Balance_Status_2_54 0 "forbid balance" 1 "on balance" 2 "permit balance" 3 "balancing stopped" 4 "waitting for balance" ;
VAL_ 2401365622 State_Balance_Fault_2_54 0 "Normal" 1 "Failure" ;
VAL_ 2401365623 State_Balance_Status_2_55 0 "forbid balance" 1 "on balance" 2 "permit balance" 3 "balancing stopped" 4 "waitting for balance" ;
VAL_ 2401365623 State_Balance_Fault_2_55 0 "Normal" 1 "Failure" ;
VAL_ 2401365624 State_Balance_Status_2_56 0 "forbid balance" 1 "on balance" 2 "permit balance" 3 "balancing stopped" 4 "waitting for balance" ;
VAL_ 2401365624 State_Balance_Fault_2_56 0 "Normal" 1 "Failure" ;
VAL_ 2401365625 State_Balance_Status_2_57 0 "forbid balance" 1 "on balance" 2 "permit balance" 3 "balancing stopped" 4 "waitting for balance" ;
VAL_ 2401365625 State_Balance_Fault_2_57 0 "Normal" 1 "Failure" ;
VAL_ 2401365626 State_Balance_Status_2_58 0 "forbid balance" 1 "on balance" 2 "permit balance" 3 "balancing stopped" 4 "waitting for balance" ;
VAL_ 2401365626 State_Balance_Fault_2_58 0 "Normal" 1 "Failure" ;
VAL_ 2401365627 State_Balance_Status_2_59 0 "forbid balance" 1 "on balance" 2 "permit balance" 3 "balancing stopped" 4 "waitting for balance" ;
VAL_ 2401365627 State_Balance_Fault_2_59 0 "Normal" 1 "Failure" ;
VAL_ 2401365628 State_Balance_Status_2_60 0 "forbid balance" 1 "on balance" 2 "permit balance" 3 "balancing stopped" 4 "waitting for balance" ;
VAL_ 2401365628 State_Balance_Fault_2_60 0 "Normal" 1 "Failure" ;
VAL_ 2401365629 State_Balance_Status_2_61 0 "forbid balance" 1 "on balance" 2 "permit balance" 3 "balancing stopped" 4 "waitting for balance" ;
VAL_ 2401365629 State_Balance_Fault_2_61 0 "Normal" 1 "Failure" ;
VAL_ 2401365630 State_Balance_Status_2_62 0 "forbid balance" 1 "on balance" 2 "permit balance" 3 "balancing stopped" 4 "waitting for balance" ;
VAL_ 2401365630 State_Balance_Fault_2_62 0 "Normal" 1 "Failure" ;
VAL_ 2401365631 State_Balance_Status_2_63 0 "forbid balance" 1 "on balance" 2 "permit balance" 3 "balancing stopped" 4 "waitting for balance" ;
VAL_ 2401365631 State_Balance_Fault_2_63 0 "Normal" 1 "Failure" ;
VERSION ""

NS_ :

BS_:

BU_: MBMU PC SBMU IMM ETH DCDC LEMS

BO_ 2418404944 S2P_Lmt20__16: 8 SBMU
 SG_ S2P_Lmt20_Over_DeltUcell4_16 : 0|16@1+ (1,0) [0|65535] "mV"  PC
 SG_ S2P_Lmt20_Over_DeltTcell4_16 : 16|8@1+ (1,-50) [-50|205] "℃"  PC
 SG_ S2P_Lmt20_Over_Ucell4_16 : 24|16@1+ (1,0) [0|65535] "mV"  PC
 SG_ S2P_Lmt20_Under_Ucell4_16 : 40|16@1+ (1,0) [0|65535] "mV"  PC
 SG_ S2P_Lmt20_Over_Tcell4_16 : 56|8@1+ (1,-50) [-50|205] "℃"  PC

BO_ 2418404945 S2P_Lmt20__17: 8 SBMU
 SG_ S2P_Lmt20_Over_DeltUcell4_17 : 0|16@1+ (1,0) [0|65535] "mV"  PC
 SG_ S2P_Lmt20_Over_DeltTcell4_17 : 16|8@1+ (1,-50) [-50|205] "℃"  PC
 SG_ S2P_Lmt20_Over_Ucell4_17 : 24|16@1+ (1,0) [0|65535] "mV"  PC
 SG_ S2P_Lmt20_Under_Ucell4_17 : 40|16@1+ (1,0) [0|65535] "mV"  PC
 SG_ S2P_Lmt20_Over_Tcell4_17 : 56|8@1+ (1,-50) [-50|205] "℃"  PC

BO_ 2418404946 S2P_Lmt20__18: 8 SBMU
 SG_ S2P_Lmt20_Over_DeltUcell4_18 : 0|16@1+ (1,0) [0|65535] "mV"  PC
 SG_ S2P_Lmt20_Over_DeltTcell4_18 : 16|8@1+ (1,-50) [-50|205] "℃"  PC
 SG_ S2P_Lmt20_Over_Ucell4_18 : 24|16@1+ (1,0) [0|65535] "mV"  PC
 SG_ S2P_Lmt20_Under_Ucell4_18 : 40|16@1+ (1,0) [0|65535] "mV"  PC
 SG_ S2P_Lmt20_Over_Tcell4_18 : 56|8@1+ (1,-50) [-50|205] "℃"  PC

BO_ 2418404947 S2P_Lmt20__19: 8 SBMU
 SG_ S2P_Lmt20_Over_DeltUcell4_19 : 0|16@1+ (1,0) [0|65535] "mV"  PC
 SG_ S2P_Lmt20_Over_DeltTcell4_19 : 16|8@1+ (1,-50) [-50|205] "℃"  PC
 SG_ S2P_Lmt20_Over_Ucell4_19 : 24|16@1+ (1,0) [0|65535] "mV"  PC
 SG_ S2P_Lmt20_Under_Ucell4_19 : 40|16@1+ (1,0) [0|65535] "mV"  PC
 SG_ S2P_Lmt20_Over_Tcell4_19 : 56|8@1+ (1,-50) [-50|205] "℃"  PC

BO_ 2418404948 S2P_Lmt20__20: 8 SBMU
 SG_ S2P_Lmt20_Over_DeltUcell4_20 : 0|16@1+ (1,0) [0|65535] "mV"  PC
 SG_ S2P_Lmt20_Over_DeltTcell4_20 : 16|8@1+ (1,-50) [-50|205] "℃"  PC
 SG_ S2P_Lmt20_Over_Ucell4_20 : 24|16@1+ (1,0) [0|65535] "mV"  PC
 SG_ S2P_Lmt20_Under_Ucell4_20 : 40|16@1+ (1,0) [0|65535] "mV"  PC
 SG_ S2P_Lmt20_Over_Tcell4_20 : 56|8@1+ (1,-50) [-50|205] "℃"  PC

BO_ 2418404949 S2P_Lmt20__21: 8 SBMU
 SG_ S2P_Lmt20_Over_DeltUcell4_21 : 0|16@1+ (1,0) [0|65535] "mV"  PC
 SG_ S2P_Lmt20_Over_DeltTcell4_21 : 16|8@1+ (1,-50) [-50|205] "℃"  PC
 SG_ S2P_Lmt20_Over_Ucell4_21 : 24|16@1+ (1,0) [0|65535] "mV"  PC
 SG_ S2P_Lmt20_Under_Ucell4_21 : 40|16@1+ (1,0) [0|65535] "mV"  PC
 SG_ S2P_Lmt20_Over_Tcell4_21 : 56|8@1+ (1,-50) [-50|205] "℃"  PC

BO_ 2418404950 S2P_Lmt20__22: 8 SBMU
 SG_ S2P_Lmt20_Over_DeltUcell4_22 : 0|16@1+ (1,0) [0|65535] "mV"  PC
 SG_ S2P_Lmt20_Over_DeltTcell4_22 : 16|8@1+ (1,-50) [-50|205] "℃"  PC
 SG_ S2P_Lmt20_Over_Ucell4_22 : 24|16@1+ (1,0) [0|65535] "mV"  PC
 SG_ S2P_Lmt20_Under_Ucell4_22 : 40|16@1+ (1,0) [0|65535] "mV"  PC
 SG_ S2P_Lmt20_Over_Tcell4_22 : 56|8@1+ (1,-50) [-50|205] "℃"  PC

BO_ 2418404951 S2P_Lmt20__23: 8 SBMU
 SG_ S2P_Lmt20_Over_DeltUcell4_23 : 0|16@1+ (1,0) [0|65535] "mV"  PC
 SG_ S2P_Lmt20_Over_DeltTcell4_23 : 16|8@1+ (1,-50) [-50|205] "℃"  PC
 SG_ S2P_Lmt20_Over_Ucell4_23 : 24|16@1+ (1,0) [0|65535] "mV"  PC
 SG_ S2P_Lmt20_Under_Ucell4_23 : 40|16@1+ (1,0) [0|65535] "mV"  PC
 SG_ S2P_Lmt20_Over_Tcell4_23 : 56|8@1+ (1,-50) [-50|205] "℃"  PC

BO_ 2418404952 S2P_Lmt20__24: 8 SBMU
 SG_ S2P_Lmt20_Over_DeltUcell4_24 : 0|16@1+ (1,0) [0|65535] "mV"  PC
 SG_ S2P_Lmt20_Over_DeltTcell4_24 : 16|8@1+ (1,-50) [-50|205] "℃"  PC
 SG_ S2P_Lmt20_Over_Ucell4_24 : 24|16@1+ (1,0) [0|65535] "mV"  PC
 SG_ S2P_Lmt20_Under_Ucell4_24 : 40|16@1+ (1,0) [0|65535] "mV"  PC
 SG_ S2P_Lmt20_Over_Tcell4_24 : 56|8@1+ (1,-50) [-50|205] "℃"  PC

BO_ 2418404953 S2P_Lmt20__25: 8 SBMU
 SG_ S2P_Lmt20_Over_DeltUcell4_25 : 0|16@1+ (1,0) [0|65535] "mV"  PC
 SG_ S2P_Lmt20_Over_DeltTcell4_25 : 16|8@1+ (1,-50) [-50|205] "℃"  PC
 SG_ S2P_Lmt20_Over_Ucell4_25 : 24|16@1+ (1,0) [0|65535] "mV"  PC
 SG_ S2P_Lmt20_Under_Ucell4_25 : 40|16@1+ (1,0) [0|65535] "mV"  PC
 SG_ S2P_Lmt20_Over_Tcell4_25 : 56|8@1+ (1,-50) [-50|205] "℃"  PC

BO_ 2418404954 S2P_Lmt20__26: 8 SBMU
 SG_ S2P_Lmt20_Over_DeltUcell4_26 : 0|16@1+ (1,0) [0|65535] "mV"  PC
 SG_ S2P_Lmt20_Over_DeltTcell4_26 : 16|8@1+ (1,-50) [-50|205] "℃"  PC
 SG_ S2P_Lmt20_Over_Ucell4_26 : 24|16@1+ (1,0) [0|65535] "mV"  PC
 SG_ S2P_Lmt20_Under_Ucell4_26 : 40|16@1+ (1,0) [0|65535] "mV"  PC
 SG_ S2P_Lmt20_Over_Tcell4_26 : 56|8@1+ (1,-50) [-50|205] "℃"  PC

BO_ 2418404955 S2P_Lmt20__27: 8 SBMU
 SG_ S2P_Lmt20_Over_DeltUcell4_27 : 0|16@1+ (1,0) [0|65535] "mV"  PC
 SG_ S2P_Lmt20_Over_DeltTcell4_27 : 16|8@1+ (1,-50) [-50|205] "℃"  PC
 SG_ S2P_Lmt20_Over_Ucell4_27 : 24|16@1+ (1,0) [0|65535] "mV"  PC
 SG_ S2P_Lmt20_Under_Ucell4_27 : 40|16@1+ (1,0) [0|65535] "mV"  PC
 SG_ S2P_Lmt20_Over_Tcell4_27 : 56|8@1+ (1,-50) [-50|205] "℃"  PC

BO_ 2418404956 S2P_Lmt20__28: 8 SBMU
 SG_ S2P_Lmt20_Over_DeltUcell4_28 : 0|16@1+ (1,0) [0|65535] "mV"  PC
 SG_ S2P_Lmt20_Over_DeltTcell4_28 : 16|8@1+ (1,-50) [-50|205] "℃"  PC
 SG_ S2P_Lmt20_Over_Ucell4_28 : 24|16@1+ (1,0) [0|65535] "mV"  PC
 SG_ S2P_Lmt20_Under_Ucell4_28 : 40|16@1+ (1,0) [0|65535] "mV"  PC
 SG_ S2P_Lmt20_Over_Tcell4_28 : 56|8@1+ (1,-50) [-50|205] "℃"  PC

BO_ 2418404957 S2P_Lmt20__29: 8 SBMU
 SG_ S2P_Lmt20_Over_DeltUcell4_29 : 0|16@1+ (1,0) [0|65535] "mV"  PC
 SG_ S2P_Lmt20_Over_DeltTcell4_29 : 16|8@1+ (1,-50) [-50|205] "℃"  PC
 SG_ S2P_Lmt20_Over_Ucell4_29 : 24|16@1+ (1,0) [0|65535] "mV"  PC
 SG_ S2P_Lmt20_Under_Ucell4_29 : 40|16@1+ (1,0) [0|65535] "mV"  PC
 SG_ S2P_Lmt20_Over_Tcell4_29 : 56|8@1+ (1,-50) [-50|205] "℃"  PC

BO_ 2418404958 S2P_Lmt20__30: 8 SBMU
 SG_ S2P_Lmt20_Over_DeltUcell4_30 : 0|16@1+ (1,0) [0|65535] "mV"  PC
 SG_ S2P_Lmt20_Over_DeltTcell4_30 : 16|8@1+ (1,-50) [-50|205] "℃"  PC
 SG_ S2P_Lmt20_Over_Ucell4_30 : 24|16@1+ (1,0) [0|65535] "mV"  PC
 SG_ S2P_Lmt20_Under_Ucell4_30 : 40|16@1+ (1,0) [0|65535] "mV"  PC
 SG_ S2P_Lmt20_Over_Tcell4_30 : 56|8@1+ (1,-50) [-50|205] "℃"  PC

BO_ 2418404959 S2P_Lmt20__31: 8 SBMU
 SG_ S2P_Lmt20_Over_DeltUcell4_31 : 0|16@1+ (1,0) [0|65535] "mV"  PC
 SG_ S2P_Lmt20_Over_DeltTcell4_31 : 16|8@1+ (1,-50) [-50|205] "℃"  PC
 SG_ S2P_Lmt20_Over_Ucell4_31 : 24|16@1+ (1,0) [0|65535] "mV"  PC
 SG_ S2P_Lmt20_Under_Ucell4_31 : 40|16@1+ (1,0) [0|65535] "mV"  PC
 SG_ S2P_Lmt20_Over_Tcell4_31 : 56|8@1+ (1,-50) [-50|205] "℃"  PC

BO_ 2418404960 S2P_Lmt20__32: 8 SBMU
 SG_ S2P_Lmt20_Over_DeltUcell4_32 : 0|16@1+ (1,0) [0|65535] "mV"  PC
 SG_ S2P_Lmt20_Over_DeltTcell4_32 : 16|8@1+ (1,-50) [-50|205] "℃"  PC
 SG_ S2P_Lmt20_Over_Ucell4_32 : 24|16@1+ (1,0) [0|65535] "mV"  PC
 SG_ S2P_Lmt20_Under_Ucell4_32 : 40|16@1+ (1,0) [0|65535] "mV"  PC
 SG_ S2P_Lmt20_Over_Tcell4_32 : 56|8@1+ (1,-50) [-50|205] "℃"  PC

BO_ 2418404961 S2P_Lmt20__33: 8 SBMU
 SG_ S2P_Lmt20_Over_DeltUcell4_33 : 0|16@1+ (1,0) [0|65535] "mV"  PC
 SG_ S2P_Lmt20_Over_DeltTcell4_33 : 16|8@1+ (1,-50) [-50|205] "℃"  PC
 SG_ S2P_Lmt20_Over_Ucell4_33 : 24|16@1+ (1,0) [0|65535] "mV"  PC
 SG_ S2P_Lmt20_Under_Ucell4_33 : 40|16@1+ (1,0) [0|65535] "mV"  PC
 SG_ S2P_Lmt20_Over_Tcell4_33 : 56|8@1+ (1,-50) [-50|205] "℃"  PC

BO_ 2418404962 S2P_Lmt20__34: 8 SBMU
 SG_ S2P_Lmt20_Over_DeltUcell4_34 : 0|16@1+ (1,0) [0|65535] "mV"  PC
 SG_ S2P_Lmt20_Over_DeltTcell4_34 : 16|8@1+ (1,-50) [-50|205] "℃"  PC
 SG_ S2P_Lmt20_Over_Ucell4_34 : 24|16@1+ (1,0) [0|65535] "mV"  PC
 SG_ S2P_Lmt20_Under_Ucell4_34 : 40|16@1+ (1,0) [0|65535] "mV"  PC
 SG_ S2P_Lmt20_Over_Tcell4_34 : 56|8@1+ (1,-50) [-50|205] "℃"  PC

BO_ 2418404963 S2P_Lmt20__35: 8 SBMU
 SG_ S2P_Lmt20_Over_DeltUcell4_35 : 0|16@1+ (1,0) [0|65535] "mV"  PC
 SG_ S2P_Lmt20_Over_DeltTcell4_35 : 16|8@1+ (1,-50) [-50|205] "℃"  PC
 SG_ S2P_Lmt20_Over_Ucell4_35 : 24|16@1+ (1,0) [0|65535] "mV"  PC
 SG_ S2P_Lmt20_Under_Ucell4_35 : 40|16@1+ (1,0) [0|65535] "mV"  PC
 SG_ S2P_Lmt20_Over_Tcell4_35 : 56|8@1+ (1,-50) [-50|205] "℃"  PC

BO_ 2418404964 S2P_Lmt20__36: 8 SBMU
 SG_ S2P_Lmt20_Over_DeltUcell4_36 : 0|16@1+ (1,0) [0|65535] "mV"  PC
 SG_ S2P_Lmt20_Over_DeltTcell4_36 : 16|8@1+ (1,-50) [-50|205] "℃"  PC
 SG_ S2P_Lmt20_Over_Ucell4_36 : 24|16@1+ (1,0) [0|65535] "mV"  PC
 SG_ S2P_Lmt20_Under_Ucell4_36 : 40|16@1+ (1,0) [0|65535] "mV"  PC
 SG_ S2P_Lmt20_Over_Tcell4_36 : 56|8@1+ (1,-50) [-50|205] "℃"  PC

BO_ 2418404965 S2P_Lmt20__37: 8 SBMU
 SG_ S2P_Lmt20_Over_DeltUcell4_37 : 0|16@1+ (1,0) [0|65535] "mV"  PC
 SG_ S2P_Lmt20_Over_DeltTcell4_37 : 16|8@1+ (1,-50) [-50|205] "℃"  PC
 SG_ S2P_Lmt20_Over_Ucell4_37 : 24|16@1+ (1,0) [0|65535] "mV"  PC
 SG_ S2P_Lmt20_Under_Ucell4_37 : 40|16@1+ (1,0) [0|65535] "mV"  PC
 SG_ S2P_Lmt20_Over_Tcell4_37 : 56|8@1+ (1,-50) [-50|205] "℃"  PC

BO_ 2418404966 S2P_Lmt20__38: 8 SBMU
 SG_ S2P_Lmt20_Over_DeltUcell4_38 : 0|16@1+ (1,0) [0|65535] "mV"  PC
 SG_ S2P_Lmt20_Over_DeltTcell4_38 : 16|8@1+ (1,-50) [-50|205] "℃"  PC
 SG_ S2P_Lmt20_Over_Ucell4_38 : 24|16@1+ (1,0) [0|65535] "mV"  PC
 SG_ S2P_Lmt20_Under_Ucell4_38 : 40|16@1+ (1,0) [0|65535] "mV"  PC
 SG_ S2P_Lmt20_Over_Tcell4_38 : 56|8@1+ (1,-50) [-50|205] "℃"  PC

BO_ 2418404967 S2P_Lmt20__39: 8 SBMU
 SG_ S2P_Lmt20_Over_DeltUcell4_39 : 0|16@1+ (1,0) [0|65535] "mV"  PC
 SG_ S2P_Lmt20_Over_DeltTcell4_39 : 16|8@1+ (1,-50) [-50|205] "℃"  PC
 SG_ S2P_Lmt20_Over_Ucell4_39 : 24|16@1+ (1,0) [0|65535] "mV"  PC
 SG_ S2P_Lmt20_Under_Ucell4_39 : 40|16@1+ (1,0) [0|65535] "mV"  PC
 SG_ S2P_Lmt20_Over_Tcell4_39 : 56|8@1+ (1,-50) [-50|205] "℃"  PC

BO_ 2418404968 S2P_Lmt20__40: 8 SBMU
 SG_ S2P_Lmt20_Over_DeltUcell4_40 : 0|16@1+ (1,0) [0|65535] "mV"  PC
 SG_ S2P_Lmt20_Over_DeltTcell4_40 : 16|8@1+ (1,-50) [-50|205] "℃"  PC
 SG_ S2P_Lmt20_Over_Ucell4_40 : 24|16@1+ (1,0) [0|65535] "mV"  PC
 SG_ S2P_Lmt20_Under_Ucell4_40 : 40|16@1+ (1,0) [0|65535] "mV"  PC
 SG_ S2P_Lmt20_Over_Tcell4_40 : 56|8@1+ (1,-50) [-50|205] "℃"  PC

BO_ 2418404969 S2P_Lmt20__41: 8 SBMU
 SG_ S2P_Lmt20_Over_DeltUcell4_41 : 0|16@1+ (1,0) [0|65535] "mV"  PC
 SG_ S2P_Lmt20_Over_DeltTcell4_41 : 16|8@1+ (1,-50) [-50|205] "℃"  PC
 SG_ S2P_Lmt20_Over_Ucell4_41 : 24|16@1+ (1,0) [0|65535] "mV"  PC
 SG_ S2P_Lmt20_Under_Ucell4_41 : 40|16@1+ (1,0) [0|65535] "mV"  PC
 SG_ S2P_Lmt20_Over_Tcell4_41 : 56|8@1+ (1,-50) [-50|205] "℃"  PC

BO_ 2418404970 S2P_Lmt20__42: 8 SBMU
 SG_ S2P_Lmt20_Over_DeltUcell4_42 : 0|16@1+ (1,0) [0|65535] "mV"  PC
 SG_ S2P_Lmt20_Over_DeltTcell4_42 : 16|8@1+ (1,-50) [-50|205] "℃"  PC
 SG_ S2P_Lmt20_Over_Ucell4_42 : 24|16@1+ (1,0) [0|65535] "mV"  PC
 SG_ S2P_Lmt20_Under_Ucell4_42 : 40|16@1+ (1,0) [0|65535] "mV"  PC
 SG_ S2P_Lmt20_Over_Tcell4_42 : 56|8@1+ (1,-50) [-50|205] "℃"  PC

BO_ 2418404971 S2P_Lmt20__43: 8 SBMU
 SG_ S2P_Lmt20_Over_DeltUcell4_43 : 0|16@1+ (1,0) [0|65535] "mV"  PC
 SG_ S2P_Lmt20_Over_DeltTcell4_43 : 16|8@1+ (1,-50) [-50|205] "℃"  PC
 SG_ S2P_Lmt20_Over_Ucell4_43 : 24|16@1+ (1,0) [0|65535] "mV"  PC
 SG_ S2P_Lmt20_Under_Ucell4_43 : 40|16@1+ (1,0) [0|65535] "mV"  PC
 SG_ S2P_Lmt20_Over_Tcell4_43 : 56|8@1+ (1,-50) [-50|205] "℃"  PC

BO_ 2418404972 S2P_Lmt20__44: 8 SBMU
 SG_ S2P_Lmt20_Over_DeltUcell4_44 : 0|16@1+ (1,0) [0|65535] "mV"  PC
 SG_ S2P_Lmt20_Over_DeltTcell4_44 : 16|8@1+ (1,-50) [-50|205] "℃"  PC
 SG_ S2P_Lmt20_Over_Ucell4_44 : 24|16@1+ (1,0) [0|65535] "mV"  PC
 SG_ S2P_Lmt20_Under_Ucell4_44 : 40|16@1+ (1,0) [0|65535] "mV"  PC
 SG_ S2P_Lmt20_Over_Tcell4_44 : 56|8@1+ (1,-50) [-50|205] "℃"  PC

BO_ 2418404973 S2P_Lmt20__45: 8 SBMU
 SG_ S2P_Lmt20_Over_DeltUcell4_45 : 0|16@1+ (1,0) [0|65535] "mV"  PC
 SG_ S2P_Lmt20_Over_DeltTcell4_45 : 16|8@1+ (1,-50) [-50|205] "℃"  PC
 SG_ S2P_Lmt20_Over_Ucell4_45 : 24|16@1+ (1,0) [0|65535] "mV"  PC
 SG_ S2P_Lmt20_Under_Ucell4_45 : 40|16@1+ (1,0) [0|65535] "mV"  PC
 SG_ S2P_Lmt20_Over_Tcell4_45 : 56|8@1+ (1,-50) [-50|205] "℃"  PC

BO_ 2418404974 S2P_Lmt20__46: 8 SBMU
 SG_ S2P_Lmt20_Over_DeltUcell4_46 : 0|16@1+ (1,0) [0|65535] "mV"  PC
 SG_ S2P_Lmt20_Over_DeltTcell4_46 : 16|8@1+ (1,-50) [-50|205] "℃"  PC
 SG_ S2P_Lmt20_Over_Ucell4_46 : 24|16@1+ (1,0) [0|65535] "mV"  PC
 SG_ S2P_Lmt20_Under_Ucell4_46 : 40|16@1+ (1,0) [0|65535] "mV"  PC
 SG_ S2P_Lmt20_Over_Tcell4_46 : 56|8@1+ (1,-50) [-50|205] "℃"  PC

BO_ 2418404975 S2P_Lmt20__47: 8 SBMU
 SG_ S2P_Lmt20_Over_DeltUcell4_47 : 0|16@1+ (1,0) [0|65535] "mV"  PC
 SG_ S2P_Lmt20_Over_DeltTcell4_47 : 16|8@1+ (1,-50) [-50|205] "℃"  PC
 SG_ S2P_Lmt20_Over_Ucell4_47 : 24|16@1+ (1,0) [0|65535] "mV"  PC
 SG_ S2P_Lmt20_Under_Ucell4_47 : 40|16@1+ (1,0) [0|65535] "mV"  PC
 SG_ S2P_Lmt20_Over_Tcell4_47 : 56|8@1+ (1,-50) [-50|205] "℃"  PC

BO_ 2418404976 S2P_Lmt20__48: 8 SBMU
 SG_ S2P_Lmt20_Over_DeltUcell4_48 : 0|16@1+ (1,0) [0|65535] "mV"  PC
 SG_ S2P_Lmt20_Over_DeltTcell4_48 : 16|8@1+ (1,-50) [-50|205] "℃"  PC
 SG_ S2P_Lmt20_Over_Ucell4_48 : 24|16@1+ (1,0) [0|65535] "mV"  PC
 SG_ S2P_Lmt20_Under_Ucell4_48 : 40|16@1+ (1,0) [0|65535] "mV"  PC
 SG_ S2P_Lmt20_Over_Tcell4_48 : 56|8@1+ (1,-50) [-50|205] "℃"  PC

BO_ 2418404977 S2P_Lmt20__49: 8 SBMU
 SG_ S2P_Lmt20_Over_DeltUcell4_49 : 0|16@1+ (1,0) [0|65535] "mV"  PC
 SG_ S2P_Lmt20_Over_DeltTcell4_49 : 16|8@1+ (1,-50) [-50|205] "℃"  PC
 SG_ S2P_Lmt20_Over_Ucell4_49 : 24|16@1+ (1,0) [0|65535] "mV"  PC
 SG_ S2P_Lmt20_Under_Ucell4_49 : 40|16@1+ (1,0) [0|65535] "mV"  PC
 SG_ S2P_Lmt20_Over_Tcell4_49 : 56|8@1+ (1,-50) [-50|205] "℃"  PC

BO_ 2418404978 S2P_Lmt20__50: 8 SBMU
 SG_ S2P_Lmt20_Over_DeltUcell4_50 : 0|16@1+ (1,0) [0|65535] "mV"  PC
 SG_ S2P_Lmt20_Over_DeltTcell4_50 : 16|8@1+ (1,-50) [-50|205] "℃"  PC
 SG_ S2P_Lmt20_Over_Ucell4_50 : 24|16@1+ (1,0) [0|65535] "mV"  PC
 SG_ S2P_Lmt20_Under_Ucell4_50 : 40|16@1+ (1,0) [0|65535] "mV"  PC
 SG_ S2P_Lmt20_Over_Tcell4_50 : 56|8@1+ (1,-50) [-50|205] "℃"  PC

BO_ 2418404979 S2P_Lmt20__51: 8 SBMU
 SG_ S2P_Lmt20_Over_DeltUcell4_51 : 0|16@1+ (1,0) [0|65535] "mV"  PC
 SG_ S2P_Lmt20_Over_DeltTcell4_51 : 16|8@1+ (1,-50) [-50|205] "℃"  PC
 SG_ S2P_Lmt20_Over_Ucell4_51 : 24|16@1+ (1,0) [0|65535] "mV"  PC
 SG_ S2P_Lmt20_Under_Ucell4_51 : 40|16@1+ (1,0) [0|65535] "mV"  PC
 SG_ S2P_Lmt20_Over_Tcell4_51 : 56|8@1+ (1,-50) [-50|205] "℃"  PC

BO_ 2418404980 S2P_Lmt20__52: 8 SBMU
 SG_ S2P_Lmt20_Over_DeltUcell4_52 : 0|16@1+ (1,0) [0|65535] "mV"  PC
 SG_ S2P_Lmt20_Over_DeltTcell4_52 : 16|8@1+ (1,-50) [-50|205] "℃"  PC
 SG_ S2P_Lmt20_Over_Ucell4_52 : 24|16@1+ (1,0) [0|65535] "mV"  PC
 SG_ S2P_Lmt20_Under_Ucell4_52 : 40|16@1+ (1,0) [0|65535] "mV"  PC
 SG_ S2P_Lmt20_Over_Tcell4_52 : 56|8@1+ (1,-50) [-50|205] "℃"  PC

BO_ 2418404981 S2P_Lmt20__53: 8 SBMU
 SG_ S2P_Lmt20_Over_DeltUcell4_53 : 0|16@1+ (1,0) [0|65535] "mV"  PC
 SG_ S2P_Lmt20_Over_DeltTcell4_53 : 16|8@1+ (1,-50) [-50|205] "℃"  PC
 SG_ S2P_Lmt20_Over_Ucell4_53 : 24|16@1+ (1,0) [0|65535] "mV"  PC
 SG_ S2P_Lmt20_Under_Ucell4_53 : 40|16@1+ (1,0) [0|65535] "mV"  PC
 SG_ S2P_Lmt20_Over_Tcell4_53 : 56|8@1+ (1,-50) [-50|205] "℃"  PC

BO_ 2418404982 S2P_Lmt20__54: 8 SBMU
 SG_ S2P_Lmt20_Over_DeltUcell4_54 : 0|16@1+ (1,0) [0|65535] "mV"  PC
 SG_ S2P_Lmt20_Over_DeltTcell4_54 : 16|8@1+ (1,-50) [-50|205] "℃"  PC
 SG_ S2P_Lmt20_Over_Ucell4_54 : 24|16@1+ (1,0) [0|65535] "mV"  PC
 SG_ S2P_Lmt20_Under_Ucell4_54 : 40|16@1+ (1,0) [0|65535] "mV"  PC
 SG_ S2P_Lmt20_Over_Tcell4_54 : 56|8@1+ (1,-50) [-50|205] "℃"  PC

BO_ 2418404983 S2P_Lmt20__55: 8 SBMU
 SG_ S2P_Lmt20_Over_DeltUcell4_55 : 0|16@1+ (1,0) [0|65535] "mV"  PC
 SG_ S2P_Lmt20_Over_DeltTcell4_55 : 16|8@1+ (1,-50) [-50|205] "℃"  PC
 SG_ S2P_Lmt20_Over_Ucell4_55 : 24|16@1+ (1,0) [0|65535] "mV"  PC
 SG_ S2P_Lmt20_Under_Ucell4_55 : 40|16@1+ (1,0) [0|65535] "mV"  PC
 SG_ S2P_Lmt20_Over_Tcell4_55 : 56|8@1+ (1,-50) [-50|205] "℃"  PC

BO_ 2418404984 S2P_Lmt20__56: 8 SBMU
 SG_ S2P_Lmt20_Over_DeltUcell4_56 : 0|16@1+ (1,0) [0|65535] "mV"  PC
 SG_ S2P_Lmt20_Over_DeltTcell4_56 : 16|8@1+ (1,-50) [-50|205] "℃"  PC
 SG_ S2P_Lmt20_Over_Ucell4_56 : 24|16@1+ (1,0) [0|65535] "mV"  PC
 SG_ S2P_Lmt20_Under_Ucell4_56 : 40|16@1+ (1,0) [0|65535] "mV"  PC
 SG_ S2P_Lmt20_Over_Tcell4_56 : 56|8@1+ (1,-50) [-50|205] "℃"  PC

BO_ 2418404985 S2P_Lmt20__57: 8 SBMU
 SG_ S2P_Lmt20_Over_DeltUcell4_57 : 0|16@1+ (1,0) [0|65535] "mV"  PC
 SG_ S2P_Lmt20_Over_DeltTcell4_57 : 16|8@1+ (1,-50) [-50|205] "℃"  PC
 SG_ S2P_Lmt20_Over_Ucell4_57 : 24|16@1+ (1,0) [0|65535] "mV"  PC
 SG_ S2P_Lmt20_Under_Ucell4_57 : 40|16@1+ (1,0) [0|65535] "mV"  PC
 SG_ S2P_Lmt20_Over_Tcell4_57 : 56|8@1+ (1,-50) [-50|205] "℃"  PC

BO_ 2418404986 S2P_Lmt20__58: 8 SBMU
 SG_ S2P_Lmt20_Over_DeltUcell4_58 : 0|16@1+ (1,0) [0|65535] "mV"  PC
 SG_ S2P_Lmt20_Over_DeltTcell4_58 : 16|8@1+ (1,-50) [-50|205] "℃"  PC
 SG_ S2P_Lmt20_Over_Ucell4_58 : 24|16@1+ (1,0) [0|65535] "mV"  PC
 SG_ S2P_Lmt20_Under_Ucell4_58 : 40|16@1+ (1,0) [0|65535] "mV"  PC
 SG_ S2P_Lmt20_Over_Tcell4_58 : 56|8@1+ (1,-50) [-50|205] "℃"  PC

BO_ 2418404987 S2P_Lmt20__59: 8 SBMU
 SG_ S2P_Lmt20_Over_DeltUcell4_59 : 0|16@1+ (1,0) [0|65535] "mV"  PC
 SG_ S2P_Lmt20_Over_DeltTcell4_59 : 16|8@1+ (1,-50) [-50|205] "℃"  PC
 SG_ S2P_Lmt20_Over_Ucell4_59 : 24|16@1+ (1,0) [0|65535] "mV"  PC
 SG_ S2P_Lmt20_Under_Ucell4_59 : 40|16@1+ (1,0) [0|65535] "mV"  PC
 SG_ S2P_Lmt20_Over_Tcell4_59 : 56|8@1+ (1,-50) [-50|205] "℃"  PC

BO_ 2418404988 S2P_Lmt20__60: 8 SBMU
 SG_ S2P_Lmt20_Over_DeltUcell4_60 : 0|16@1+ (1,0) [0|65535] "mV"  PC
 SG_ S2P_Lmt20_Over_DeltTcell4_60 : 16|8@1+ (1,-50) [-50|205] "℃"  PC
 SG_ S2P_Lmt20_Over_Ucell4_60 : 24|16@1+ (1,0) [0|65535] "mV"  PC
 SG_ S2P_Lmt20_Under_Ucell4_60 : 40|16@1+ (1,0) [0|65535] "mV"  PC
 SG_ S2P_Lmt20_Over_Tcell4_60 : 56|8@1+ (1,-50) [-50|205] "℃"  PC

BO_ 2418404989 S2P_Lmt20__61: 8 SBMU
 SG_ S2P_Lmt20_Over_DeltUcell4_61 : 0|16@1+ (1,0) [0|65535] "mV"  PC
 SG_ S2P_Lmt20_Over_DeltTcell4_61 : 16|8@1+ (1,-50) [-50|205] "℃"  PC
 SG_ S2P_Lmt20_Over_Ucell4_61 : 24|16@1+ (1,0) [0|65535] "mV"  PC
 SG_ S2P_Lmt20_Under_Ucell4_61 : 40|16@1+ (1,0) [0|65535] "mV"  PC
 SG_ S2P_Lmt20_Over_Tcell4_61 : 56|8@1+ (1,-50) [-50|205] "℃"  PC

BO_ 2418404990 S2P_Lmt20__62: 8 SBMU
 SG_ S2P_Lmt20_Over_DeltUcell4_62 : 0|16@1+ (1,0) [0|65535] "mV"  PC
 SG_ S2P_Lmt20_Over_DeltTcell4_62 : 16|8@1+ (1,-50) [-50|205] "℃"  PC
 SG_ S2P_Lmt20_Over_Ucell4_62 : 24|16@1+ (1,0) [0|65535] "mV"  PC
 SG_ S2P_Lmt20_Under_Ucell4_62 : 40|16@1+ (1,0) [0|65535] "mV"  PC
 SG_ S2P_Lmt20_Over_Tcell4_62 : 56|8@1+ (1,-50) [-50|205] "℃"  PC

BO_ 2418404991 S2P_Lmt20__63: 8 SBMU
 SG_ S2P_Lmt20_Over_DeltUcell4_63 : 0|16@1+ (1,0) [0|65535] "mV"  PC
 SG_ S2P_Lmt20_Over_DeltTcell4_63 : 16|8@1+ (1,-50) [-50|205] "℃"  PC
 SG_ S2P_Lmt20_Over_Ucell4_63 : 24|16@1+ (1,0) [0|65535] "mV"  PC
 SG_ S2P_Lmt20_Under_Ucell4_63 : 40|16@1+ (1,0) [0|65535] "mV"  PC
 SG_ S2P_Lmt20_Over_Tcell4_63 : 56|8@1+ (1,-50) [-50|205] "℃"  PC

BO_ 2418470465 S2P_Lmt21__01: 8 SBMU
 SG_ S2P_Lmt21_Under_Tcell4_01 : 0|8@1+ (1,-50) [-50|205] "℃"  PC

BO_ 2418470466 S2P_Lmt21__02: 8 SBMU
 SG_ S2P_Lmt21_Under_Tcell4_02 : 0|8@1+ (1,-50) [-50|205] "℃"  PC

BO_ 2418470467 S2P_Lmt21__03: 8 SBMU
 SG_ S2P_Lmt21_Under_Tcell4_03 : 0|8@1+ (1,-50) [-50|205] "℃"  PC

BO_ 2418470468 S2P_Lmt21__04: 8 SBMU
 SG_ S2P_Lmt21_Under_Tcell4_04 : 0|8@1+ (1,-50) [-50|205] "℃"  PC

BO_ 2418470469 S2P_Lmt21__05: 8 SBMU
 SG_ S2P_Lmt21_Under_Tcell4_05 : 0|8@1+ (1,-50) [-50|205] "℃"  PC

BO_ 2418470470 S2P_Lmt21__06: 8 SBMU
 SG_ S2P_Lmt21_Under_Tcell4_06 : 0|8@1+ (1,-50) [-50|205] "℃"  PC

BO_ 2418470471 S2P_Lmt21__07: 8 SBMU
 SG_ S2P_Lmt21_Under_Tcell4_07 : 0|8@1+ (1,-50) [-50|205] "℃"  PC

BO_ 2418470472 S2P_Lmt21__08: 8 SBMU
 SG_ S2P_Lmt21_Under_Tcell4_08 : 0|8@1+ (1,-50) [-50|205] "℃"  PC

BO_ 2418470473 S2P_Lmt21__09: 8 SBMU
 SG_ S2P_Lmt21_Under_Tcell4_09 : 0|8@1+ (1,-50) [-50|205] "℃"  PC

BO_ 2418470474 S2P_Lmt21__10: 8 SBMU
 SG_ S2P_Lmt21_Under_Tcell4_10 : 0|8@1+ (1,-50) [-50|205] "℃"  PC

BO_ 2418470475 S2P_Lmt21__11: 8 SBMU
 SG_ S2P_Lmt21_Under_Tcell4_11 : 0|8@1+ (1,-50) [-50|205] "℃"  PC

BO_ 2418470476 S2P_Lmt21__12: 8 SBMU
 SG_ S2P_Lmt21_Under_Tcell4_12 : 0|8@1+ (1,-50) [-50|205] "℃"  PC

BO_ 2418470477 S2P_Lmt21__13: 8 SBMU
 SG_ S2P_Lmt21_Under_Tcell4_13 : 0|8@1+ (1,-50) [-50|205] "℃"  PC

BO_ 2418470478 S2P_Lmt21__14: 8 SBMU
 SG_ S2P_Lmt21_Under_Tcell4_14 : 0|8@1+ (1,-50) [-50|205] "℃"  PC

BO_ 2418470479 S2P_Lmt21__15: 8 SBMU
 SG_ S2P_Lmt21_Under_Tcell4_15 : 0|8@1+ (1,-50) [-50|205] "℃"  PC

BO_ 2418470480 S2P_Lmt21__16: 8 SBMU
 SG_ S2P_Lmt21_Under_Tcell4_16 : 0|8@1+ (1,-50) [-50|205] "℃"  PC

BO_ 2418470481 S2P_Lmt21__17: 8 SBMU
 SG_ S2P_Lmt21_Under_Tcell4_17 : 0|8@1+ (1,-50) [-50|205] "℃"  PC

BO_ 2418470482 S2P_Lmt21__18: 8 SBMU
 SG_ S2P_Lmt21_Under_Tcell4_18 : 0|8@1+ (1,-50) [-50|205] "℃"  PC

BO_ 2418470483 S2P_Lmt21__19: 8 SBMU
 SG_ S2P_Lmt21_Under_Tcell4_19 : 0|8@1+ (1,-50) [-50|205] "℃"  PC

BO_ 2418470484 S2P_Lmt21__20: 8 SBMU
 SG_ S2P_Lmt21_Under_Tcell4_20 : 0|8@1+ (1,-50) [-50|205] "℃"  PC

BO_ 2418470485 S2P_Lmt21__21: 8 SBMU
 SG_ S2P_Lmt21_Under_Tcell4_21 : 0|8@1+ (1,-50) [-50|205] "℃"  PC

BO_ 2418470486 S2P_Lmt21__22: 8 SBMU
 SG_ S2P_Lmt21_Under_Tcell4_22 : 0|8@1+ (1,-50) [-50|205] "℃"  PC

BO_ 2418470487 S2P_Lmt21__23: 8 SBMU
 SG_ S2P_Lmt21_Under_Tcell4_23 : 0|8@1+ (1,-50) [-50|205] "℃"  PC

BO_ 2418470488 S2P_Lmt21__24: 8 SBMU
 SG_ S2P_Lmt21_Under_Tcell4_24 : 0|8@1+ (1,-50) [-50|205] "℃"  PC

BO_ 2418470489 S2P_Lmt21__25: 8 SBMU
 SG_ S2P_Lmt21_Under_Tcell4_25 : 0|8@1+ (1,-50) [-50|205] "℃"  PC

BO_ 2418470490 S2P_Lmt21__26: 8 SBMU
 SG_ S2P_Lmt21_Under_Tcell4_26 : 0|8@1+ (1,-50) [-50|205] "℃"  PC

BO_ 2418470491 S2P_Lmt21__27: 8 SBMU
 SG_ S2P_Lmt21_Under_Tcell4_27 : 0|8@1+ (1,-50) [-50|205] "℃"  PC

BO_ 2418470492 S2P_Lmt21__28: 8 SBMU
 SG_ S2P_Lmt21_Under_Tcell4_28 : 0|8@1+ (1,-50) [-50|205] "℃"  PC

BO_ 2418470493 S2P_Lmt21__29: 8 SBMU
 SG_ S2P_Lmt21_Under_Tcell4_29 : 0|8@1+ (1,-50) [-50|205] "℃"  PC

BO_ 2418470494 S2P_Lmt21__30: 8 SBMU
 SG_ S2P_Lmt21_Under_Tcell4_30 : 0|8@1+ (1,-50) [-50|205] "℃"  PC

BO_ 2418470495 S2P_Lmt21__31: 8 SBMU
 SG_ S2P_Lmt21_Under_Tcell4_31 : 0|8@1+ (1,-50) [-50|205] "℃"  PC

BO_ 2418470496 S2P_Lmt21__32: 8 SBMU
 SG_ S2P_Lmt21_Under_Tcell4_32 : 0|8@1+ (1,-50) [-50|205] "℃"  PC

BO_ 2418470497 S2P_Lmt21__33: 8 SBMU
 SG_ S2P_Lmt21_Under_Tcell4_33 : 0|8@1+ (1,-50) [-50|205] "℃"  PC

BO_ 2418470498 S2P_Lmt21__34: 8 SBMU
 SG_ S2P_Lmt21_Under_Tcell4_34 : 0|8@1+ (1,-50) [-50|205] "℃"  PC

BO_ 2418470499 S2P_Lmt21__35: 8 SBMU
 SG_ S2P_Lmt21_Under_Tcell4_35 : 0|8@1+ (1,-50) [-50|205] "℃"  PC

BO_ 2418470500 S2P_Lmt21__36: 8 SBMU
 SG_ S2P_Lmt21_Under_Tcell4_36 : 0|8@1+ (1,-50) [-50|205] "℃"  PC

BO_ 2418470501 S2P_Lmt21__37: 8 SBMU
 SG_ S2P_Lmt21_Under_Tcell4_37 : 0|8@1+ (1,-50) [-50|205] "℃"  PC

BO_ 2418470502 S2P_Lmt21__38: 8 SBMU
 SG_ S2P_Lmt21_Under_Tcell4_38 : 0|8@1+ (1,-50) [-50|205] "℃"  PC

BO_ 2418470503 S2P_Lmt21__39: 8 SBMU
 SG_ S2P_Lmt21_Under_Tcell4_39 : 0|8@1+ (1,-50) [-50|205] "℃"  PC

BO_ 2418470504 S2P_Lmt21__40: 8 SBMU
 SG_ S2P_Lmt21_Under_Tcell4_40 : 0|8@1+ (1,-50) [-50|205] "℃"  PC

BO_ 2418470505 S2P_Lmt21__41: 8 SBMU
 SG_ S2P_Lmt21_Under_Tcell4_41 : 0|8@1+ (1,-50) [-50|205] "℃"  PC

BO_ 2418470506 S2P_Lmt21__42: 8 SBMU
 SG_ S2P_Lmt21_Under_Tcell4_42 : 0|8@1+ (1,-50) [-50|205] "℃"  PC

BO_ 2418470507 S2P_Lmt21__43: 8 SBMU
 SG_ S2P_Lmt21_Under_Tcell4_43 : 0|8@1+ (1,-50) [-50|205] "℃"  PC

BO_ 2418470508 S2P_Lmt21__44: 8 SBMU
 SG_ S2P_Lmt21_Under_Tcell4_44 : 0|8@1+ (1,-50) [-50|205] "℃"  PC

BO_ 2418470509 S2P_Lmt21__45: 8 SBMU
 SG_ S2P_Lmt21_Under_Tcell4_45 : 0|8@1+ (1,-50) [-50|205] "℃"  PC

BO_ 2418470510 S2P_Lmt21__46: 8 SBMU
 SG_ S2P_Lmt21_Under_Tcell4_46 : 0|8@1+ (1,-50) [-50|205] "℃"  PC

BO_ 2418470511 S2P_Lmt21__47: 8 SBMU
 SG_ S2P_Lmt21_Under_Tcell4_47 : 0|8@1+ (1,-50) [-50|205] "℃"  PC

BO_ 2418470512 S2P_Lmt21__48: 8 SBMU
 SG_ S2P_Lmt21_Under_Tcell4_48 : 0|8@1+ (1,-50) [-50|205] "℃"  PC

BO_ 2418470513 S2P_Lmt21__49: 8 SBMU
 SG_ S2P_Lmt21_Under_Tcell4_49 : 0|8@1+ (1,-50) [-50|205] "℃"  PC

BO_ 2418470514 S2P_Lmt21__50: 8 SBMU
 SG_ S2P_Lmt21_Under_Tcell4_50 : 0|8@1+ (1,-50) [-50|205] "℃"  PC

BO_ 2418470515 S2P_Lmt21__51: 8 SBMU
 SG_ S2P_Lmt21_Under_Tcell4_51 : 0|8@1+ (1,-50) [-50|205] "℃"  PC

BO_ 2418470516 S2P_Lmt21__52: 8 SBMU
 SG_ S2P_Lmt21_Under_Tcell4_52 : 0|8@1+ (1,-50) [-50|205] "℃"  PC

BO_ 2418470517 S2P_Lmt21__53: 8 SBMU
 SG_ S2P_Lmt21_Under_Tcell4_53 : 0|8@1+ (1,-50) [-50|205] "℃"  PC

BO_ 2418470518 S2P_Lmt21__54: 8 SBMU
 SG_ S2P_Lmt21_Under_Tcell4_54 : 0|8@1+ (1,-50) [-50|205] "℃"  PC

BO_ 2418470519 S2P_Lmt21__55: 8 SBMU
 SG_ S2P_Lmt21_Under_Tcell4_55 : 0|8@1+ (1,-50) [-50|205] "℃"  PC

BO_ 2418470520 S2P_Lmt21__56: 8 SBMU
 SG_ S2P_Lmt21_Under_Tcell4_56 : 0|8@1+ (1,-50) [-50|205] "℃"  PC

BO_ 2418470521 S2P_Lmt21__57: 8 SBMU
 SG_ S2P_Lmt21_Under_Tcell4_57 : 0|8@1+ (1,-50) [-50|205] "℃"  PC

BO_ 2418470522 S2P_Lmt21__58: 8 SBMU
 SG_ S2P_Lmt21_Under_Tcell4_58 : 0|8@1+ (1,-50) [-50|205] "℃"  PC

BO_ 2418470523 S2P_Lmt21__59: 8 SBMU
 SG_ S2P_Lmt21_Under_Tcell4_59 : 0|8@1+ (1,-50) [-50|205] "℃"  PC

BO_ 2418470524 S2P_Lmt21__60: 8 SBMU
 SG_ S2P_Lmt21_Under_Tcell4_60 : 0|8@1+ (1,-50) [-50|205] "℃"  PC

BO_ 2418470525 S2P_Lmt21__61: 8 SBMU
 SG_ S2P_Lmt21_Under_Tcell4_61 : 0|8@1+ (1,-50) [-50|205] "℃"  PC

BO_ 2418470526 S2P_Lmt21__62: 8 SBMU
 SG_ S2P_Lmt21_Under_Tcell4_62 : 0|8@1+ (1,-50) [-50|205] "℃"  PC

BO_ 2418470527 S2P_Lmt21__63: 8 SBMU
 SG_ S2P_Lmt21_Under_Tcell4_63 : 0|8@1+ (1,-50) [-50|205] "℃"  PC

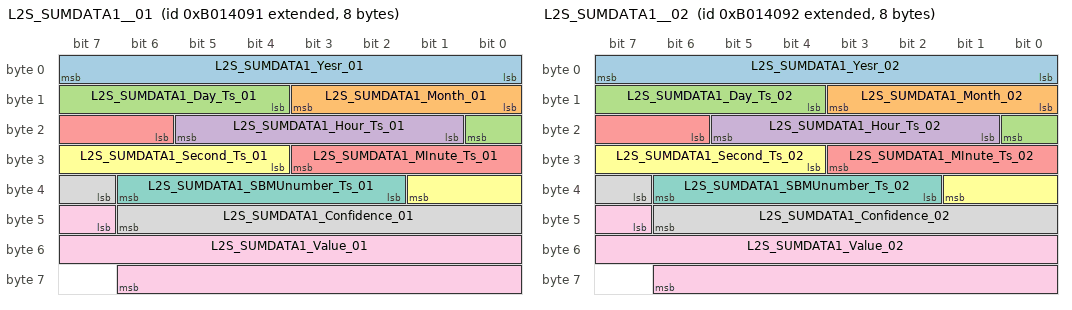
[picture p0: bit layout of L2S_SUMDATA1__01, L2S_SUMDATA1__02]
BO_ 2332115089 L2S_SUMDATA1__01: 8 LEMS
 SG_ L2S_SUMDATA1_Yesr_01 : 0|8@1+ (1,2000) [2000|2255] ""  SBMU
 SG_ L2S_SUMDATA1_Month_01 : 8|4@1+ (1,0) [0|15] ""  SBMU
 SG_ L2S_SUMDATA1_Day_Ts_01 : 12|5@1+ (1,0) [0|31] ""  SBMU
 SG_ L2S_SUMDATA1_Hour_Ts_01 : 17|5@1+ (1,0) [0|31] ""  SBMU
 SG_ L2S_SUMDATA1_MInute_Ts_01 : 22|6@1+ (1,0) [0|63] ""  SBMU
 SG_ L2S_SUMDATA1_Second_Ts_01 : 28|6@1+ (1,0) [0|63] ""  SBMU
 SG_ L2S_SUMDATA1_SBMUnumber_Ts_01 : 34|5@1+ (1,0) [0|31] ""  SBMU
 SG_ L2S_SUMDATA1_Confidence_01 : 39|8@1+ (1,0) [0|255] ""  SBMU
 SG_ L2S_SUMDATA1_Value_01 : 47|16@1+ (0.01,-100) [-100|555.35] "%"  SBMU

BO_ 2332115090 L2S_SUMDATA1__02: 8 LEMS
 SG_ L2S_SUMDATA1_Yesr_02 : 0|8@1+ (1,2000) [2000|2255] ""  SBMU
 SG_ L2S_SUMDATA1_Month_02 : 8|4@1+ (1,0) [0|15] ""  SBMU
 SG_ L2S_SUMDATA1_Day_Ts_02 : 12|5@1+ (1,0) [0|31] ""  SBMU
 SG_ L2S_SUMDATA1_Hour_Ts_02 : 17|5@1+ (1,0) [0|31] ""  SBMU
 SG_ L2S_SUMDATA1_MInute_Ts_02 : 22|6@1+ (1,0) [0|63] ""  SBMU
 SG_ L2S_SUMDATA1_Second_Ts_02 : 28|6@1+ (1,0) [0|63] ""  SBMU
 SG_ L2S_SUMDATA1_SBMUnumber_Ts_02 : 34|5@1+ (1,0) [0|31] ""  SBMU
 SG_ L2S_SUMDATA1_Confidence_02 : 39|8@1+ (1,0) [0|255] ""  SBMU
 SG_ L2S_SUMDATA1_Value_02 : 47|16@1+ (0.01,-100) [-100|555.35] "%"  SBMU

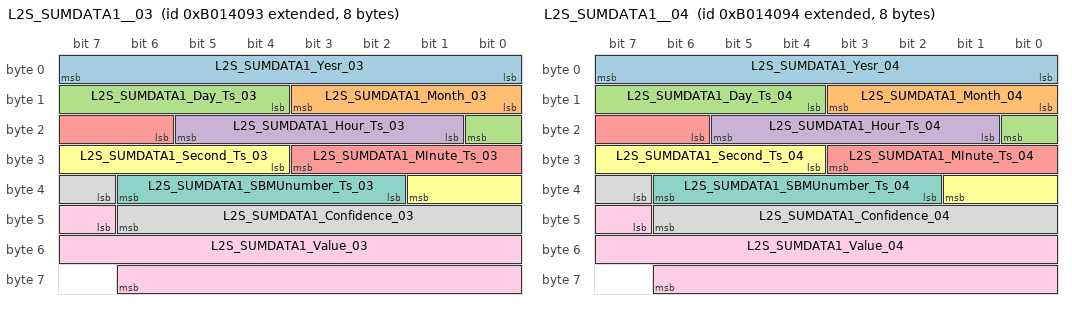
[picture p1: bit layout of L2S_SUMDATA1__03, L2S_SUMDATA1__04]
BO_ 2332115091 L2S_SUMDATA1__03: 8 LEMS
 SG_ L2S_SUMDATA1_Yesr_03 : 0|8@1+ (1,2000) [2000|2255] ""  SBMU
 SG_ L2S_SUMDATA1_Month_03 : 8|4@1+ (1,0) [0|15] ""  SBMU
 SG_ L2S_SUMDATA1_Day_Ts_03 : 12|5@1+ (1,0) [0|31] ""  SBMU
 SG_ L2S_SUMDATA1_Hour_Ts_03 : 17|5@1+ (1,0) [0|31] ""  SBMU
 SG_ L2S_SUMDATA1_MInute_Ts_03 : 22|6@1+ (1,0) [0|63] ""  SBMU
 SG_ L2S_SUMDATA1_Second_Ts_03 : 28|6@1+ (1,0) [0|63] ""  SBMU
 SG_ L2S_SUMDATA1_SBMUnumber_Ts_03 : 34|5@1+ (1,0) [0|31] ""  SBMU
 SG_ L2S_SUMDATA1_Confidence_03 : 39|8@1+ (1,0) [0|255] ""  SBMU
 SG_ L2S_SUMDATA1_Value_03 : 47|16@1+ (0.01,-100) [-100|555.35] "%"  SBMU

BO_ 2332115092 L2S_SUMDATA1__04: 8 LEMS
 SG_ L2S_SUMDATA1_Yesr_04 : 0|8@1+ (1,2000) [2000|2255] ""  SBMU
 SG_ L2S_SUMDATA1_Month_04 : 8|4@1+ (1,0) [0|15] ""  SBMU
 SG_ L2S_SUMDATA1_Day_Ts_04 : 12|5@1+ (1,0) [0|31] ""  SBMU
 SG_ L2S_SUMDATA1_Hour_Ts_04 : 17|5@1+ (1,0) [0|31] ""  SBMU
 SG_ L2S_SUMDATA1_MInute_Ts_04 : 22|6@1+ (1,0) [0|63] ""  SBMU
 SG_ L2S_SUMDATA1_Second_Ts_04 : 28|6@1+ (1,0) [0|63] ""  SBMU
 SG_ L2S_SUMDATA1_SBMUnumber_Ts_04 : 34|5@1+ (1,0) [0|31] ""  SBMU
 SG_ L2S_SUMDATA1_Confidence_04 : 39|8@1+ (1,0) [0|255] ""  SBMU
 SG_ L2S_SUMDATA1_Value_04 : 47|16@1+ (0.01,-100) [-100|555.35] "%"  SBMU

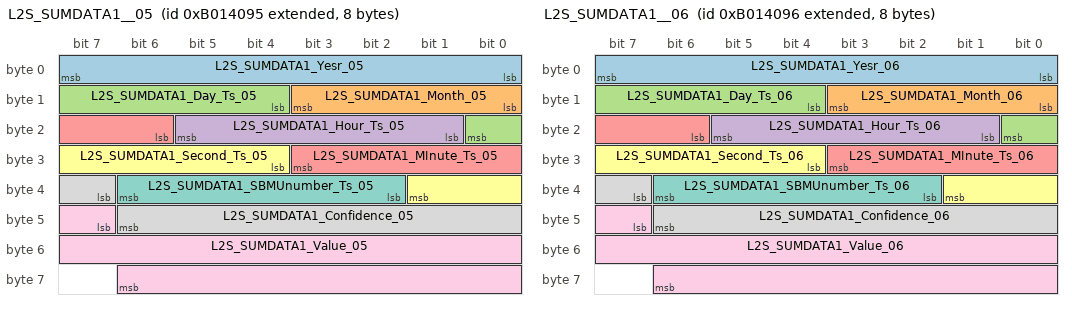
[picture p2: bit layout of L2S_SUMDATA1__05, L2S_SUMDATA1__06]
BO_ 2332115093 L2S_SUMDATA1__05: 8 LEMS
 SG_ L2S_SUMDATA1_Yesr_05 : 0|8@1+ (1,2000) [2000|2255] ""  SBMU
 SG_ L2S_SUMDATA1_Month_05 : 8|4@1+ (1,0) [0|15] ""  SBMU
 SG_ L2S_SUMDATA1_Day_Ts_05 : 12|5@1+ (1,0) [0|31] ""  SBMU
 SG_ L2S_SUMDATA1_Hour_Ts_05 : 17|5@1+ (1,0) [0|31] ""  SBMU
 SG_ L2S_SUMDATA1_MInute_Ts_05 : 22|6@1+ (1,0) [0|63] ""  SBMU
 SG_ L2S_SUMDATA1_Second_Ts_05 : 28|6@1+ (1,0) [0|63] ""  SBMU
 SG_ L2S_SUMDATA1_SBMUnumber_Ts_05 : 34|5@1+ (1,0) [0|31] ""  SBMU
 SG_ L2S_SUMDATA1_Confidence_05 : 39|8@1+ (1,0) [0|255] ""  SBMU
 SG_ L2S_SUMDATA1_Value_05 : 47|16@1+ (0.01,-100) [-100|555.35] "%"  SBMU

BO_ 2332115094 L2S_SUMDATA1__06: 8 LEMS
 SG_ L2S_SUMDATA1_Yesr_06 : 0|8@1+ (1,2000) [2000|2255] ""  SBMU
 SG_ L2S_SUMDATA1_Month_06 : 8|4@1+ (1,0) [0|15] ""  SBMU
 SG_ L2S_SUMDATA1_Day_Ts_06 : 12|5@1+ (1,0) [0|31] ""  SBMU
 SG_ L2S_SUMDATA1_Hour_Ts_06 : 17|5@1+ (1,0) [0|31] ""  SBMU
 SG_ L2S_SUMDATA1_MInute_Ts_06 : 22|6@1+ (1,0) [0|63] ""  SBMU
 SG_ L2S_SUMDATA1_Second_Ts_06 : 28|6@1+ (1,0) [0|63] ""  SBMU
 SG_ L2S_SUMDATA1_SBMUnumber_Ts_06 : 34|5@1+ (1,0) [0|31] ""  SBMU
 SG_ L2S_SUMDATA1_Confidence_06 : 39|8@1+ (1,0) [0|255] ""  SBMU
 SG_ L2S_SUMDATA1_Value_06 : 47|16@1+ (0.01,-100) [-100|555.35] "%"  SBMU

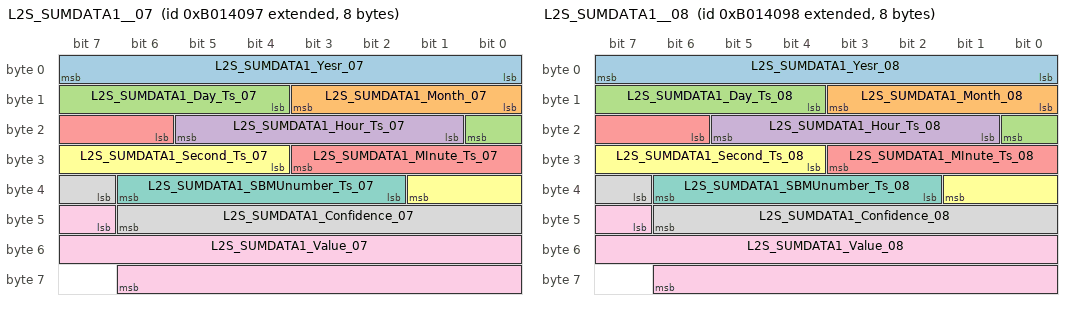
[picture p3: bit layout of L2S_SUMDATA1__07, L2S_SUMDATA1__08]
BO_ 2332115095 L2S_SUMDATA1__07: 8 LEMS
 SG_ L2S_SUMDATA1_Yesr_07 : 0|8@1+ (1,2000) [2000|2255] ""  SBMU
 SG_ L2S_SUMDATA1_Month_07 : 8|4@1+ (1,0) [0|15] ""  SBMU
 SG_ L2S_SUMDATA1_Day_Ts_07 : 12|5@1+ (1,0) [0|31] ""  SBMU
 SG_ L2S_SUMDATA1_Hour_Ts_07 : 17|5@1+ (1,0) [0|31] ""  SBMU
 SG_ L2S_SUMDATA1_MInute_Ts_07 : 22|6@1+ (1,0) [0|63] ""  SBMU
 SG_ L2S_SUMDATA1_Second_Ts_07 : 28|6@1+ (1,0) [0|63] ""  SBMU
 SG_ L2S_SUMDATA1_SBMUnumber_Ts_07 : 34|5@1+ (1,0) [0|31] ""  SBMU
 SG_ L2S_SUMDATA1_Confidence_07 : 39|8@1+ (1,0) [0|255] ""  SBMU
 SG_ L2S_SUMDATA1_Value_07 : 47|16@1+ (0.01,-100) [-100|555.35] "%"  SBMU

BO_ 2332115096 L2S_SUMDATA1__08: 8 LEMS
 SG_ L2S_SUMDATA1_Yesr_08 : 0|8@1+ (1,2000) [2000|2255] ""  SBMU
 SG_ L2S_SUMDATA1_Month_08 : 8|4@1+ (1,0) [0|15] ""  SBMU
 SG_ L2S_SUMDATA1_Day_Ts_08 : 12|5@1+ (1,0) [0|31] ""  SBMU
 SG_ L2S_SUMDATA1_Hour_Ts_08 : 17|5@1+ (1,0) [0|31] ""  SBMU
 SG_ L2S_SUMDATA1_MInute_Ts_08 : 22|6@1+ (1,0) [0|63] ""  SBMU
 SG_ L2S_SUMDATA1_Second_Ts_08 : 28|6@1+ (1,0) [0|63] ""  SBMU
 SG_ L2S_SUMDATA1_SBMUnumber_Ts_08 : 34|5@1+ (1,0) [0|31] ""  SBMU
 SG_ L2S_SUMDATA1_Confidence_08 : 39|8@1+ (1,0) [0|255] ""  SBMU
 SG_ L2S_SUMDATA1_Value_08 : 47|16@1+ (0.01,-100) [-100|555.35] "%"  SBMU

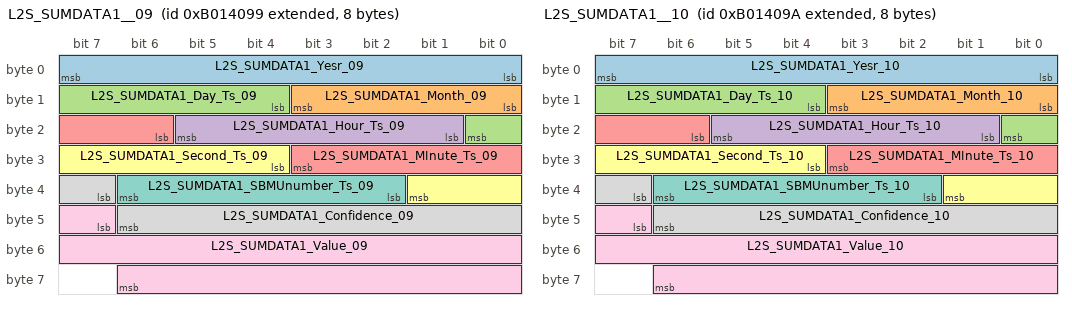
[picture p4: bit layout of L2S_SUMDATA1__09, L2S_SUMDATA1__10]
BO_ 2332115097 L2S_SUMDATA1__09: 8 LEMS
 SG_ L2S_SUMDATA1_Yesr_09 : 0|8@1+ (1,2000) [2000|2255] ""  SBMU
 SG_ L2S_SUMDATA1_Month_09 : 8|4@1+ (1,0) [0|15] ""  SBMU
 SG_ L2S_SUMDATA1_Day_Ts_09 : 12|5@1+ (1,0) [0|31] ""  SBMU
 SG_ L2S_SUMDATA1_Hour_Ts_09 : 17|5@1+ (1,0) [0|31] ""  SBMU
 SG_ L2S_SUMDATA1_MInute_Ts_09 : 22|6@1+ (1,0) [0|63] ""  SBMU
 SG_ L2S_SUMDATA1_Second_Ts_09 : 28|6@1+ (1,0) [0|63] ""  SBMU
 SG_ L2S_SUMDATA1_SBMUnumber_Ts_09 : 34|5@1+ (1,0) [0|31] ""  SBMU
 SG_ L2S_SUMDATA1_Confidence_09 : 39|8@1+ (1,0) [0|255] ""  SBMU
 SG_ L2S_SUMDATA1_Value_09 : 47|16@1+ (0.01,-100) [-100|555.35] "%"  SBMU

BO_ 2332115098 L2S_SUMDATA1__10: 8 LEMS
 SG_ L2S_SUMDATA1_Yesr_10 : 0|8@1+ (1,2000) [2000|2255] ""  SBMU
 SG_ L2S_SUMDATA1_Month_10 : 8|4@1+ (1,0) [0|15] ""  SBMU
 SG_ L2S_SUMDATA1_Day_Ts_10 : 12|5@1+ (1,0) [0|31] ""  SBMU
 SG_ L2S_SUMDATA1_Hour_Ts_10 : 17|5@1+ (1,0) [0|31] ""  SBMU
 SG_ L2S_SUMDATA1_MInute_Ts_10 : 22|6@1+ (1,0) [0|63] ""  SBMU
 SG_ L2S_SUMDATA1_Second_Ts_10 : 28|6@1+ (1,0) [0|63] ""  SBMU
 SG_ L2S_SUMDATA1_SBMUnumber_Ts_10 : 34|5@1+ (1,0) [0|31] ""  SBMU
 SG_ L2S_SUMDATA1_Confidence_10 : 39|8@1+ (1,0) [0|255] ""  SBMU
 SG_ L2S_SUMDATA1_Value_10 : 47|16@1+ (0.01,-100) [-100|555.35] "%"  SBMU

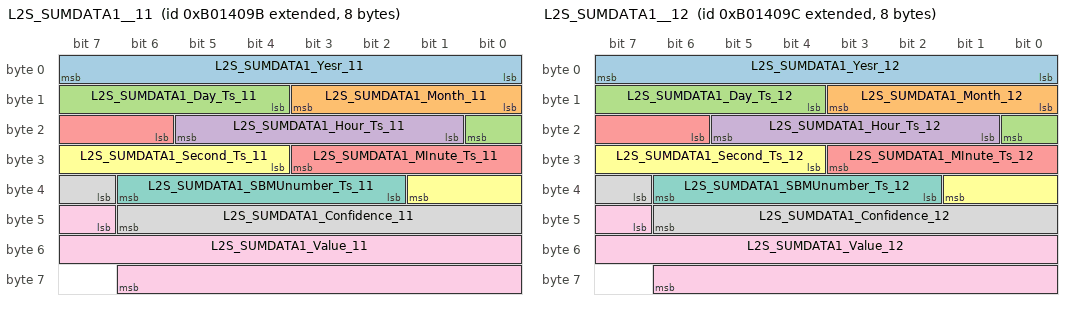
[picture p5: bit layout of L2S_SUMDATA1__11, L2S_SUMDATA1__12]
BO_ 2332115099 L2S_SUMDATA1__11: 8 LEMS
 SG_ L2S_SUMDATA1_Yesr_11 : 0|8@1+ (1,2000) [2000|2255] ""  SBMU
 SG_ L2S_SUMDATA1_Month_11 : 8|4@1+ (1,0) [0|15] ""  SBMU
 SG_ L2S_SUMDATA1_Day_Ts_11 : 12|5@1+ (1,0) [0|31] ""  SBMU
 SG_ L2S_SUMDATA1_Hour_Ts_11 : 17|5@1+ (1,0) [0|31] ""  SBMU
 SG_ L2S_SUMDATA1_MInute_Ts_11 : 22|6@1+ (1,0) [0|63] ""  SBMU
 SG_ L2S_SUMDATA1_Second_Ts_11 : 28|6@1+ (1,0) [0|63] ""  SBMU
 SG_ L2S_SUMDATA1_SBMUnumber_Ts_11 : 34|5@1+ (1,0) [0|31] ""  SBMU
 SG_ L2S_SUMDATA1_Confidence_11 : 39|8@1+ (1,0) [0|255] ""  SBMU
 SG_ L2S_SUMDATA1_Value_11 : 47|16@1+ (0.01,-100) [-100|555.35] "%"  SBMU

BO_ 2332115100 L2S_SUMDATA1__12: 8 LEMS
 SG_ L2S_SUMDATA1_Yesr_12 : 0|8@1+ (1,2000) [2000|2255] ""  SBMU
 SG_ L2S_SUMDATA1_Month_12 : 8|4@1+ (1,0) [0|15] ""  SBMU
 SG_ L2S_SUMDATA1_Day_Ts_12 : 12|5@1+ (1,0) [0|31] ""  SBMU
 SG_ L2S_SUMDATA1_Hour_Ts_12 : 17|5@1+ (1,0) [0|31] ""  SBMU
 SG_ L2S_SUMDATA1_MInute_Ts_12 : 22|6@1+ (1,0) [0|63] ""  SBMU
 SG_ L2S_SUMDATA1_Second_Ts_12 : 28|6@1+ (1,0) [0|63] ""  SBMU
 SG_ L2S_SUMDATA1_SBMUnumber_Ts_12 : 34|5@1+ (1,0) [0|31] ""  SBMU
 SG_ L2S_SUMDATA1_Confidence_12 : 39|8@1+ (1,0) [0|255] ""  SBMU
 SG_ L2S_SUMDATA1_Value_12 : 47|16@1+ (0.01,-100) [-100|555.35] "%"  SBMU

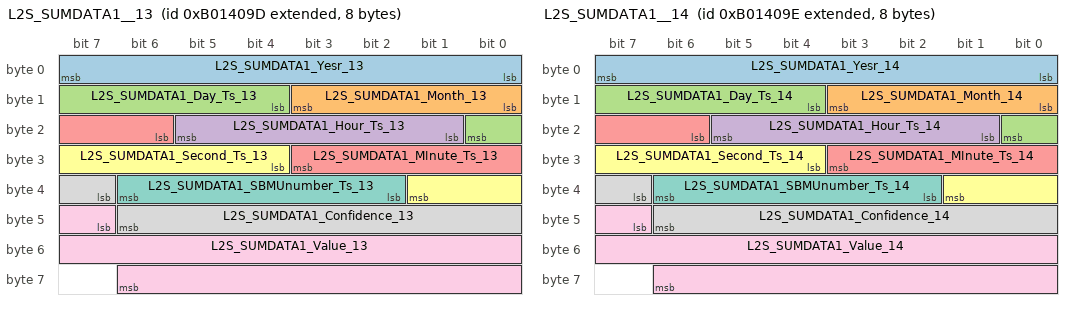
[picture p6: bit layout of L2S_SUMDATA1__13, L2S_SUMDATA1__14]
BO_ 2332115101 L2S_SUMDATA1__13: 8 LEMS
 SG_ L2S_SUMDATA1_Yesr_13 : 0|8@1+ (1,2000) [2000|2255] ""  SBMU
 SG_ L2S_SUMDATA1_Month_13 : 8|4@1+ (1,0) [0|15] ""  SBMU
 SG_ L2S_SUMDATA1_Day_Ts_13 : 12|5@1+ (1,0) [0|31] ""  SBMU
 SG_ L2S_SUMDATA1_Hour_Ts_13 : 17|5@1+ (1,0) [0|31] ""  SBMU
 SG_ L2S_SUMDATA1_MInute_Ts_13 : 22|6@1+ (1,0) [0|63] ""  SBMU
 SG_ L2S_SUMDATA1_Second_Ts_13 : 28|6@1+ (1,0) [0|63] ""  SBMU
 SG_ L2S_SUMDATA1_SBMUnumber_Ts_13 : 34|5@1+ (1,0) [0|31] ""  SBMU
 SG_ L2S_SUMDATA1_Confidence_13 : 39|8@1+ (1,0) [0|255] ""  SBMU
 SG_ L2S_SUMDATA1_Value_13 : 47|16@1+ (0.01,-100) [-100|555.35] "%"  SBMU

BO_ 2332115102 L2S_SUMDATA1__14: 8 LEMS
 SG_ L2S_SUMDATA1_Yesr_14 : 0|8@1+ (1,2000) [2000|2255] ""  SBMU
 SG_ L2S_SUMDATA1_Month_14 : 8|4@1+ (1,0) [0|15] ""  SBMU
 SG_ L2S_SUMDATA1_Day_Ts_14 : 12|5@1+ (1,0) [0|31] ""  SBMU
 SG_ L2S_SUMDATA1_Hour_Ts_14 : 17|5@1+ (1,0) [0|31] ""  SBMU
 SG_ L2S_SUMDATA1_MInute_Ts_14 : 22|6@1+ (1,0) [0|63] ""  SBMU
 SG_ L2S_SUMDATA1_Second_Ts_14 : 28|6@1+ (1,0) [0|63] ""  SBMU
 SG_ L2S_SUMDATA1_SBMUnumber_Ts_14 : 34|5@1+ (1,0) [0|31] ""  SBMU
 SG_ L2S_SUMDATA1_Confidence_14 : 39|8@1+ (1,0) [0|255] ""  SBMU
 SG_ L2S_SUMDATA1_Value_14 : 47|16@1+ (0.01,-100) [-100|555.35] "%"  SBMU

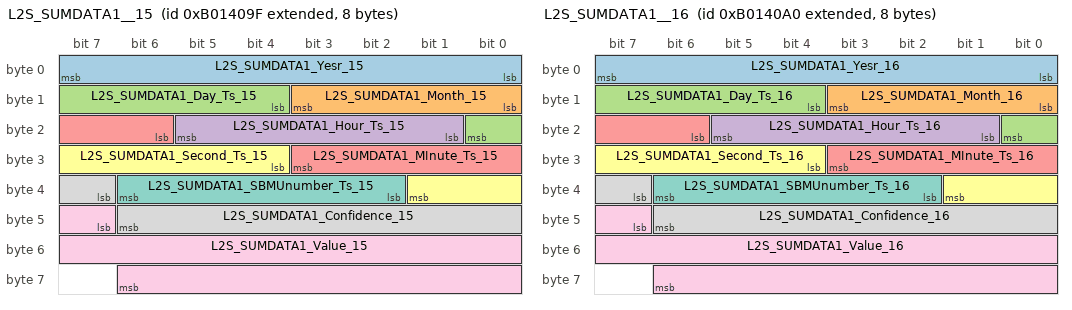
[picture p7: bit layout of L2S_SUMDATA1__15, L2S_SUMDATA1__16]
BO_ 2332115103 L2S_SUMDATA1__15: 8 LEMS
 SG_ L2S_SUMDATA1_Yesr_15 : 0|8@1+ (1,2000) [2000|2255] ""  SBMU
 SG_ L2S_SUMDATA1_Month_15 : 8|4@1+ (1,0) [0|15] ""  SBMU
 SG_ L2S_SUMDATA1_Day_Ts_15 : 12|5@1+ (1,0) [0|31] ""  SBMU
 SG_ L2S_SUMDATA1_Hour_Ts_15 : 17|5@1+ (1,0) [0|31] ""  SBMU
 SG_ L2S_SUMDATA1_MInute_Ts_15 : 22|6@1+ (1,0) [0|63] ""  SBMU
 SG_ L2S_SUMDATA1_Second_Ts_15 : 28|6@1+ (1,0) [0|63] ""  SBMU
 SG_ L2S_SUMDATA1_SBMUnumber_Ts_15 : 34|5@1+ (1,0) [0|31] ""  SBMU
 SG_ L2S_SUMDATA1_Confidence_15 : 39|8@1+ (1,0) [0|255] ""  SBMU
 SG_ L2S_SUMDATA1_Value_15 : 47|16@1+ (0.01,-100) [-100|555.35] "%"  SBMU

BO_ 2332115104 L2S_SUMDATA1__16: 8 LEMS
 SG_ L2S_SUMDATA1_Yesr_16 : 0|8@1+ (1,2000) [2000|2255] ""  SBMU
 SG_ L2S_SUMDATA1_Month_16 : 8|4@1+ (1,0) [0|15] ""  SBMU
 SG_ L2S_SUMDATA1_Day_Ts_16 : 12|5@1+ (1,0) [0|31] ""  SBMU
 SG_ L2S_SUMDATA1_Hour_Ts_16 : 17|5@1+ (1,0) [0|31] ""  SBMU
 SG_ L2S_SUMDATA1_MInute_Ts_16 : 22|6@1+ (1,0) [0|63] ""  SBMU
 SG_ L2S_SUMDATA1_Second_Ts_16 : 28|6@1+ (1,0) [0|63] ""  SBMU
 SG_ L2S_SUMDATA1_SBMUnumber_Ts_16 : 34|5@1+ (1,0) [0|31] ""  SBMU
 SG_ L2S_SUMDATA1_Confidence_16 : 39|8@1+ (1,0) [0|255] ""  SBMU
 SG_ L2S_SUMDATA1_Value_16 : 47|16@1+ (0.01,-100) [-100|555.35] "%"  SBMU

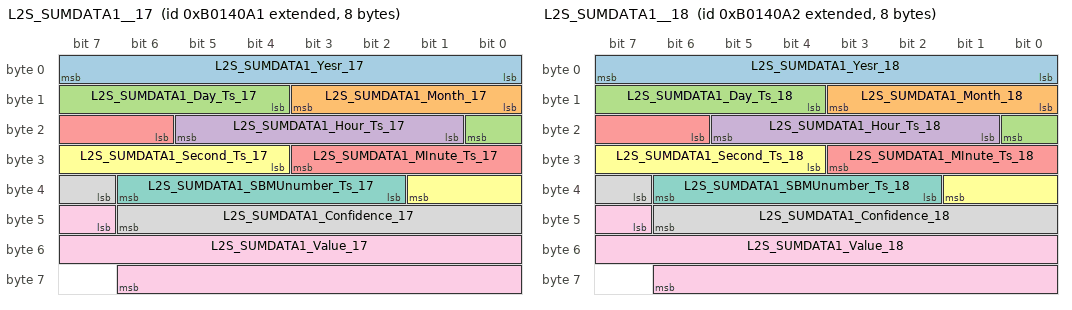
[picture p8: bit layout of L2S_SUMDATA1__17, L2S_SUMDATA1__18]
BO_ 2332115105 L2S_SUMDATA1__17: 8 LEMS
 SG_ L2S_SUMDATA1_Yesr_17 : 0|8@1+ (1,2000) [2000|2255] ""  SBMU
 SG_ L2S_SUMDATA1_Month_17 : 8|4@1+ (1,0) [0|15] ""  SBMU
 SG_ L2S_SUMDATA1_Day_Ts_17 : 12|5@1+ (1,0) [0|31] ""  SBMU
 SG_ L2S_SUMDATA1_Hour_Ts_17 : 17|5@1+ (1,0) [0|31] ""  SBMU
 SG_ L2S_SUMDATA1_MInute_Ts_17 : 22|6@1+ (1,0) [0|63] ""  SBMU
 SG_ L2S_SUMDATA1_Second_Ts_17 : 28|6@1+ (1,0) [0|63] ""  SBMU
 SG_ L2S_SUMDATA1_SBMUnumber_Ts_17 : 34|5@1+ (1,0) [0|31] ""  SBMU
 SG_ L2S_SUMDATA1_Confidence_17 : 39|8@1+ (1,0) [0|255] ""  SBMU
 SG_ L2S_SUMDATA1_Value_17 : 47|16@1+ (0.01,-100) [-100|555.35] "%"  SBMU

BO_ 2332115106 L2S_SUMDATA1__18: 8 LEMS
 SG_ L2S_SUMDATA1_Yesr_18 : 0|8@1+ (1,2000) [2000|2255] ""  SBMU
 SG_ L2S_SUMDATA1_Month_18 : 8|4@1+ (1,0) [0|15] ""  SBMU
 SG_ L2S_SUMDATA1_Day_Ts_18 : 12|5@1+ (1,0) [0|31] ""  SBMU
 SG_ L2S_SUMDATA1_Hour_Ts_18 : 17|5@1+ (1,0) [0|31] ""  SBMU
 SG_ L2S_SUMDATA1_MInute_Ts_18 : 22|6@1+ (1,0) [0|63] ""  SBMU
 SG_ L2S_SUMDATA1_Second_Ts_18 : 28|6@1+ (1,0) [0|63] ""  SBMU
 SG_ L2S_SUMDATA1_SBMUnumber_Ts_18 : 34|5@1+ (1,0) [0|31] ""  SBMU
 SG_ L2S_SUMDATA1_Confidence_18 : 39|8@1+ (1,0) [0|255] ""  SBMU
 SG_ L2S_SUMDATA1_Value_18 : 47|16@1+ (0.01,-100) [-100|555.35] "%"  SBMU

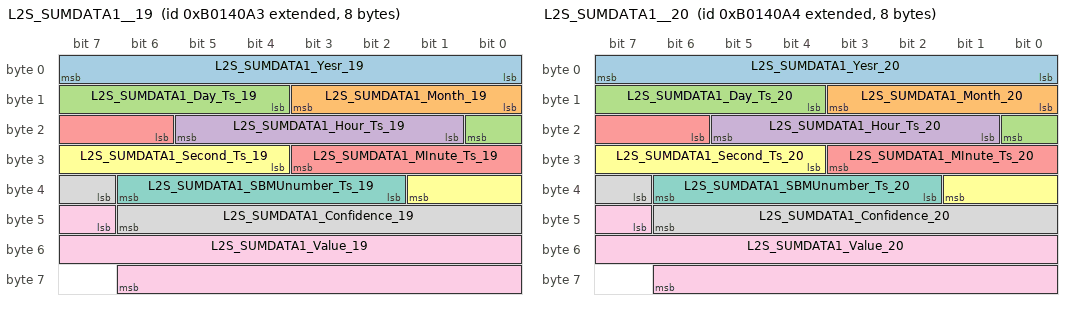
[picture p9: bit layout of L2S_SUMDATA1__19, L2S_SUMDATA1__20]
BO_ 2332115107 L2S_SUMDATA1__19: 8 LEMS
 SG_ L2S_SUMDATA1_Yesr_19 : 0|8@1+ (1,2000) [2000|2255] ""  SBMU
 SG_ L2S_SUMDATA1_Month_19 : 8|4@1+ (1,0) [0|15] ""  SBMU
 SG_ L2S_SUMDATA1_Day_Ts_19 : 12|5@1+ (1,0) [0|31] ""  SBMU
 SG_ L2S_SUMDATA1_Hour_Ts_19 : 17|5@1+ (1,0) [0|31] ""  SBMU
 SG_ L2S_SUMDATA1_MInute_Ts_19 : 22|6@1+ (1,0) [0|63] ""  SBMU
 SG_ L2S_SUMDATA1_Second_Ts_19 : 28|6@1+ (1,0) [0|63] ""  SBMU
 SG_ L2S_SUMDATA1_SBMUnumber_Ts_19 : 34|5@1+ (1,0) [0|31] ""  SBMU
 SG_ L2S_SUMDATA1_Confidence_19 : 39|8@1+ (1,0) [0|255] ""  SBMU
 SG_ L2S_SUMDATA1_Value_19 : 47|16@1+ (0.01,-100) [-100|555.35] "%"  SBMU

BO_ 2332115108 L2S_SUMDATA1__20: 8 LEMS
 SG_ L2S_SUMDATA1_Yesr_20 : 0|8@1+ (1,2000) [2000|2255] ""  SBMU
 SG_ L2S_SUMDATA1_Month_20 : 8|4@1+ (1,0) [0|15] ""  SBMU
 SG_ L2S_SUMDATA1_Day_Ts_20 : 12|5@1+ (1,0) [0|31] ""  SBMU
 SG_ L2S_SUMDATA1_Hour_Ts_20 : 17|5@1+ (1,0) [0|31] ""  SBMU
 SG_ L2S_SUMDATA1_MInute_Ts_20 : 22|6@1+ (1,0) [0|63] ""  SBMU
 SG_ L2S_SUMDATA1_Second_Ts_20 : 28|6@1+ (1,0) [0|63] ""  SBMU
 SG_ L2S_SUMDATA1_SBMUnumber_Ts_20 : 34|5@1+ (1,0) [0|31] ""  SBMU
 SG_ L2S_SUMDATA1_Confidence_20 : 39|8@1+ (1,0) [0|255] ""  SBMU
 SG_ L2S_SUMDATA1_Value_20 : 47|16@1+ (0.01,-100) [-100|555.35] "%"  SBMU

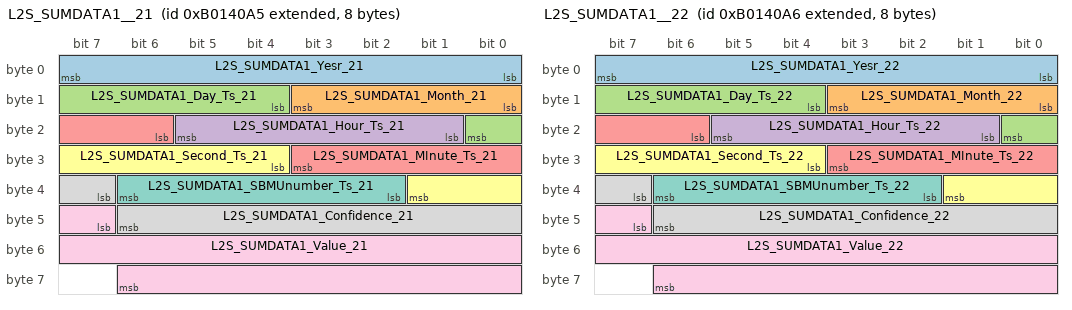
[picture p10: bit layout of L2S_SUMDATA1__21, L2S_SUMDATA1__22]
BO_ 2332115109 L2S_SUMDATA1__21: 8 LEMS
 SG_ L2S_SUMDATA1_Yesr_21 : 0|8@1+ (1,2000) [2000|2255] ""  SBMU
 SG_ L2S_SUMDATA1_Month_21 : 8|4@1+ (1,0) [0|15] ""  SBMU
 SG_ L2S_SUMDATA1_Day_Ts_21 : 12|5@1+ (1,0) [0|31] ""  SBMU
 SG_ L2S_SUMDATA1_Hour_Ts_21 : 17|5@1+ (1,0) [0|31] ""  SBMU
 SG_ L2S_SUMDATA1_MInute_Ts_21 : 22|6@1+ (1,0) [0|63] ""  SBMU
 SG_ L2S_SUMDATA1_Second_Ts_21 : 28|6@1+ (1,0) [0|63] ""  SBMU
 SG_ L2S_SUMDATA1_SBMUnumber_Ts_21 : 34|5@1+ (1,0) [0|31] ""  SBMU
 SG_ L2S_SUMDATA1_Confidence_21 : 39|8@1+ (1,0) [0|255] ""  SBMU
 SG_ L2S_SUMDATA1_Value_21 : 47|16@1+ (0.01,-100) [-100|555.35] "%"  SBMU

BO_ 2332115110 L2S_SUMDATA1__22: 8 LEMS
 SG_ L2S_SUMDATA1_Yesr_22 : 0|8@1+ (1,2000) [2000|2255] ""  SBMU
 SG_ L2S_SUMDATA1_Month_22 : 8|4@1+ (1,0) [0|15] ""  SBMU
 SG_ L2S_SUMDATA1_Day_Ts_22 : 12|5@1+ (1,0) [0|31] ""  SBMU
 SG_ L2S_SUMDATA1_Hour_Ts_22 : 17|5@1+ (1,0) [0|31] ""  SBMU
 SG_ L2S_SUMDATA1_MInute_Ts_22 : 22|6@1+ (1,0) [0|63] ""  SBMU
 SG_ L2S_SUMDATA1_Second_Ts_22 : 28|6@1+ (1,0) [0|63] ""  SBMU
 SG_ L2S_SUMDATA1_SBMUnumber_Ts_22 : 34|5@1+ (1,0) [0|31] ""  SBMU
 SG_ L2S_SUMDATA1_Confidence_22 : 39|8@1+ (1,0) [0|255] ""  SBMU
 SG_ L2S_SUMDATA1_Value_22 : 47|16@1+ (0.01,-100) [-100|555.35] "%"  SBMU

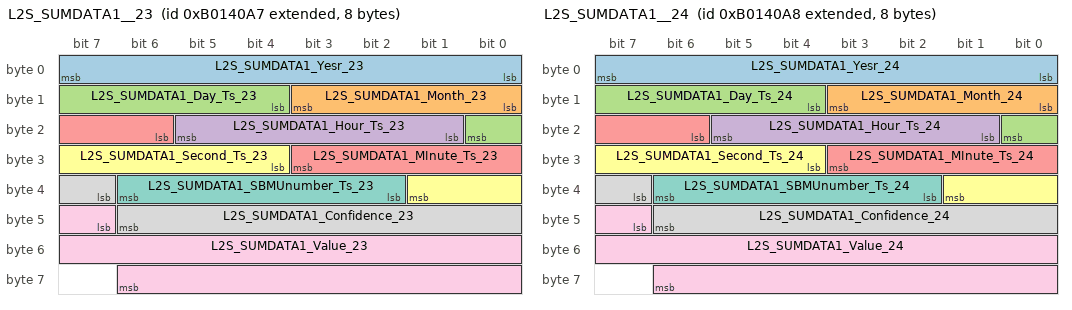
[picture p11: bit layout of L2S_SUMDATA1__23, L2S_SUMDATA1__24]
BO_ 2332115111 L2S_SUMDATA1__23: 8 LEMS
 SG_ L2S_SUMDATA1_Yesr_23 : 0|8@1+ (1,2000) [2000|2255] ""  SBMU
 SG_ L2S_SUMDATA1_Month_23 : 8|4@1+ (1,0) [0|15] ""  SBMU
 SG_ L2S_SUMDATA1_Day_Ts_23 : 12|5@1+ (1,0) [0|31] ""  SBMU
 SG_ L2S_SUMDATA1_Hour_Ts_23 : 17|5@1+ (1,0) [0|31] ""  SBMU
 SG_ L2S_SUMDATA1_MInute_Ts_23 : 22|6@1+ (1,0) [0|63] ""  SBMU
 SG_ L2S_SUMDATA1_Second_Ts_23 : 28|6@1+ (1,0) [0|63] ""  SBMU
 SG_ L2S_SUMDATA1_SBMUnumber_Ts_23 : 34|5@1+ (1,0) [0|31] ""  SBMU
 SG_ L2S_SUMDATA1_Confidence_23 : 39|8@1+ (1,0) [0|255] ""  SBMU
 SG_ L2S_SUMDATA1_Value_23 : 47|16@1+ (0.01,-100) [-100|555.35] "%"  SBMU

BO_ 2332115112 L2S_SUMDATA1__24: 8 LEMS
 SG_ L2S_SUMDATA1_Yesr_24 : 0|8@1+ (1,2000) [2000|2255] ""  SBMU
 SG_ L2S_SUMDATA1_Month_24 : 8|4@1+ (1,0) [0|15] ""  SBMU
 SG_ L2S_SUMDATA1_Day_Ts_24 : 12|5@1+ (1,0) [0|31] ""  SBMU
 SG_ L2S_SUMDATA1_Hour_Ts_24 : 17|5@1+ (1,0) [0|31] ""  SBMU
 SG_ L2S_SUMDATA1_MInute_Ts_24 : 22|6@1+ (1,0) [0|63] ""  SBMU
 SG_ L2S_SUMDATA1_Second_Ts_24 : 28|6@1+ (1,0) [0|63] ""  SBMU
 SG_ L2S_SUMDATA1_SBMUnumber_Ts_24 : 34|5@1+ (1,0) [0|31] ""  SBMU
 SG_ L2S_SUMDATA1_Confidence_24 : 39|8@1+ (1,0) [0|255] ""  SBMU
 SG_ L2S_SUMDATA1_Value_24 : 47|16@1+ (0.01,-100) [-100|555.35] "%"  SBMU

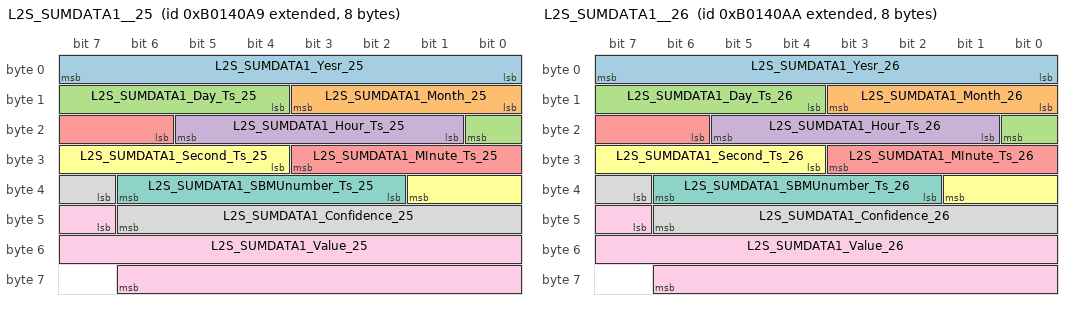
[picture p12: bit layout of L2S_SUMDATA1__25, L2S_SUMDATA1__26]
BO_ 2332115113 L2S_SUMDATA1__25: 8 LEMS
 SG_ L2S_SUMDATA1_Yesr_25 : 0|8@1+ (1,2000) [2000|2255] ""  SBMU
 SG_ L2S_SUMDATA1_Month_25 : 8|4@1+ (1,0) [0|15] ""  SBMU
 SG_ L2S_SUMDATA1_Day_Ts_25 : 12|5@1+ (1,0) [0|31] ""  SBMU
 SG_ L2S_SUMDATA1_Hour_Ts_25 : 17|5@1+ (1,0) [0|31] ""  SBMU
 SG_ L2S_SUMDATA1_MInute_Ts_25 : 22|6@1+ (1,0) [0|63] ""  SBMU
 SG_ L2S_SUMDATA1_Second_Ts_25 : 28|6@1+ (1,0) [0|63] ""  SBMU
 SG_ L2S_SUMDATA1_SBMUnumber_Ts_25 : 34|5@1+ (1,0) [0|31] ""  SBMU
 SG_ L2S_SUMDATA1_Confidence_25 : 39|8@1+ (1,0) [0|255] ""  SBMU
 SG_ L2S_SUMDATA1_Value_25 : 47|16@1+ (0.01,-100) [-100|555.35] "%"  SBMU

BO_ 2332115114 L2S_SUMDATA1__26: 8 LEMS
 SG_ L2S_SUMDATA1_Yesr_26 : 0|8@1+ (1,2000) [2000|2255] ""  SBMU
 SG_ L2S_SUMDATA1_Month_26 : 8|4@1+ (1,0) [0|15] ""  SBMU
 SG_ L2S_SUMDATA1_Day_Ts_26 : 12|5@1+ (1,0) [0|31] ""  SBMU
 SG_ L2S_SUMDATA1_Hour_Ts_26 : 17|5@1+ (1,0) [0|31] ""  SBMU
 SG_ L2S_SUMDATA1_MInute_Ts_26 : 22|6@1+ (1,0) [0|63] ""  SBMU
 SG_ L2S_SUMDATA1_Second_Ts_26 : 28|6@1+ (1,0) [0|63] ""  SBMU
 SG_ L2S_SUMDATA1_SBMUnumber_Ts_26 : 34|5@1+ (1,0) [0|31] ""  SBMU
 SG_ L2S_SUMDATA1_Confidence_26 : 39|8@1+ (1,0) [0|255] ""  SBMU
 SG_ L2S_SUMDATA1_Value_26 : 47|16@1+ (0.01,-100) [-100|555.35] "%"  SBMU

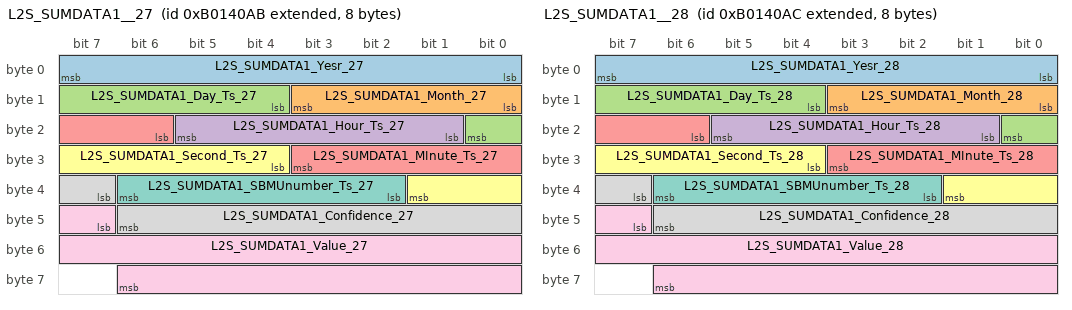
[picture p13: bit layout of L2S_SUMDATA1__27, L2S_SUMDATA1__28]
BO_ 2332115115 L2S_SUMDATA1__27: 8 LEMS
 SG_ L2S_SUMDATA1_Yesr_27 : 0|8@1+ (1,2000) [2000|2255] ""  SBMU
 SG_ L2S_SUMDATA1_Month_27 : 8|4@1+ (1,0) [0|15] ""  SBMU
 SG_ L2S_SUMDATA1_Day_Ts_27 : 12|5@1+ (1,0) [0|31] ""  SBMU
 SG_ L2S_SUMDATA1_Hour_Ts_27 : 17|5@1+ (1,0) [0|31] ""  SBMU
 SG_ L2S_SUMDATA1_MInute_Ts_27 : 22|6@1+ (1,0) [0|63] ""  SBMU
 SG_ L2S_SUMDATA1_Second_Ts_27 : 28|6@1+ (1,0) [0|63] ""  SBMU
 SG_ L2S_SUMDATA1_SBMUnumber_Ts_27 : 34|5@1+ (1,0) [0|31] ""  SBMU
 SG_ L2S_SUMDATA1_Confidence_27 : 39|8@1+ (1,0) [0|255] ""  SBMU
 SG_ L2S_SUMDATA1_Value_27 : 47|16@1+ (0.01,-100) [-100|555.35] "%"  SBMU

BO_ 2332115116 L2S_SUMDATA1__28: 8 LEMS
 SG_ L2S_SUMDATA1_Yesr_28 : 0|8@1+ (1,2000) [2000|2255] ""  SBMU
 SG_ L2S_SUMDATA1_Month_28 : 8|4@1+ (1,0) [0|15] ""  SBMU
 SG_ L2S_SUMDATA1_Day_Ts_28 : 12|5@1+ (1,0) [0|31] ""  SBMU
 SG_ L2S_SUMDATA1_Hour_Ts_28 : 17|5@1+ (1,0) [0|31] ""  SBMU
 SG_ L2S_SUMDATA1_MInute_Ts_28 : 22|6@1+ (1,0) [0|63] ""  SBMU
 SG_ L2S_SUMDATA1_Second_Ts_28 : 28|6@1+ (1,0) [0|63] ""  SBMU
 SG_ L2S_SUMDATA1_SBMUnumber_Ts_28 : 34|5@1+ (1,0) [0|31] ""  SBMU
 SG_ L2S_SUMDATA1_Confidence_28 : 39|8@1+ (1,0) [0|255] ""  SBMU
 SG_ L2S_SUMDATA1_Value_28 : 47|16@1+ (0.01,-100) [-100|555.35] "%"  SBMU

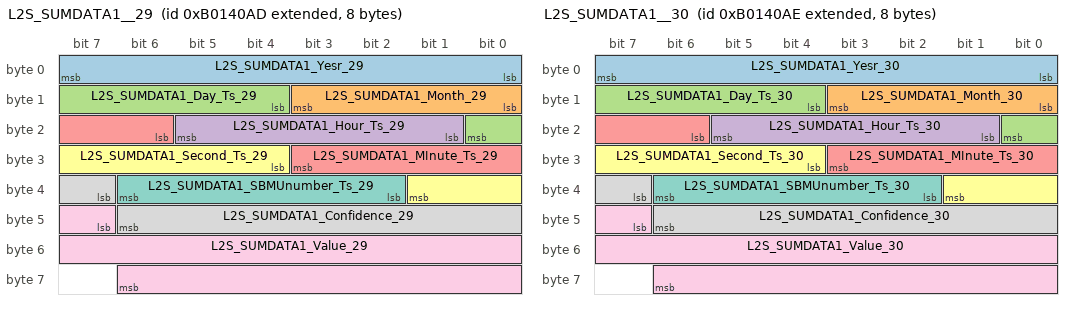
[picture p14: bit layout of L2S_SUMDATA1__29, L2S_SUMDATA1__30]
BO_ 2332115117 L2S_SUMDATA1__29: 8 LEMS
 SG_ L2S_SUMDATA1_Yesr_29 : 0|8@1+ (1,2000) [2000|2255] ""  SBMU
 SG_ L2S_SUMDATA1_Month_29 : 8|4@1+ (1,0) [0|15] ""  SBMU
 SG_ L2S_SUMDATA1_Day_Ts_29 : 12|5@1+ (1,0) [0|31] ""  SBMU
 SG_ L2S_SUMDATA1_Hour_Ts_29 : 17|5@1+ (1,0) [0|31] ""  SBMU
 SG_ L2S_SUMDATA1_MInute_Ts_29 : 22|6@1+ (1,0) [0|63] ""  SBMU
 SG_ L2S_SUMDATA1_Second_Ts_29 : 28|6@1+ (1,0) [0|63] ""  SBMU
 SG_ L2S_SUMDATA1_SBMUnumber_Ts_29 : 34|5@1+ (1,0) [0|31] ""  SBMU
 SG_ L2S_SUMDATA1_Confidence_29 : 39|8@1+ (1,0) [0|255] ""  SBMU
 SG_ L2S_SUMDATA1_Value_29 : 47|16@1+ (0.01,-100) [-100|555.35] "%"  SBMU

BO_ 2332115118 L2S_SUMDATA1__30: 8 LEMS
 SG_ L2S_SUMDATA1_Yesr_30 : 0|8@1+ (1,2000) [2000|2255] ""  SBMU
 SG_ L2S_SUMDATA1_Month_30 : 8|4@1+ (1,0) [0|15] ""  SBMU
 SG_ L2S_SUMDATA1_Day_Ts_30 : 12|5@1+ (1,0) [0|31] ""  SBMU
 SG_ L2S_SUMDATA1_Hour_Ts_30 : 17|5@1+ (1,0) [0|31] ""  SBMU
 SG_ L2S_SUMDATA1_MInute_Ts_30 : 22|6@1+ (1,0) [0|63] ""  SBMU
 SG_ L2S_SUMDATA1_Second_Ts_30 : 28|6@1+ (1,0) [0|63] ""  SBMU
 SG_ L2S_SUMDATA1_SBMUnumber_Ts_30 : 34|5@1+ (1,0) [0|31] ""  SBMU
 SG_ L2S_SUMDATA1_Confidence_30 : 39|8@1+ (1,0) [0|255] ""  SBMU
 SG_ L2S_SUMDATA1_Value_30 : 47|16@1+ (0.01,-100) [-100|555.35] "%"  SBMU

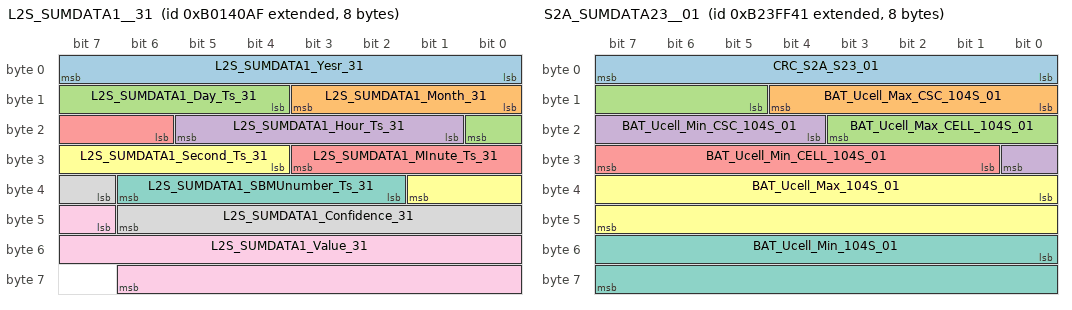
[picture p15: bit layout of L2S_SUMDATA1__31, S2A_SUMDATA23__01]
BO_ 2332115119 L2S_SUMDATA1__31: 8 LEMS
 SG_ L2S_SUMDATA1_Yesr_31 : 0|8@1+ (1,2000) [2000|2255] ""  SBMU
 SG_ L2S_SUMDATA1_Month_31 : 8|4@1+ (1,0) [0|15] ""  SBMU
 SG_ L2S_SUMDATA1_Day_Ts_31 : 12|5@1+ (1,0) [0|31] ""  SBMU
 SG_ L2S_SUMDATA1_Hour_Ts_31 : 17|5@1+ (1,0) [0|31] ""  SBMU
 SG_ L2S_SUMDATA1_MInute_Ts_31 : 22|6@1+ (1,0) [0|63] ""  SBMU
 SG_ L2S_SUMDATA1_Second_Ts_31 : 28|6@1+ (1,0) [0|63] ""  SBMU
 SG_ L2S_SUMDATA1_SBMUnumber_Ts_31 : 34|5@1+ (1,0) [0|31] ""  SBMU
 SG_ L2S_SUMDATA1_Confidence_31 : 39|8@1+ (1,0) [0|255] ""  SBMU
 SG_ L2S_SUMDATA1_Value_31 : 47|16@1+ (0.01,-100) [-100|555.35] "%"  SBMU

BO_ 2334392129 S2A_SUMDATA23__01: 8 SBMU
 SG_ CRC_S2A_S23_01 : 0|8@1+ (1,0) [0|255] ""  MBMU,PC
 SG_ BAT_Ucell_Max_CSC_104S_01 : 8|5@1+ (1,0) [0|31] ""  MBMU,PC
 SG_ BAT_Ucell_Max_CELL_104S_01 : 13|7@1+ (1,0) [0|127] ""  MBMU,PC
 SG_ BAT_Ucell_Min_CSC_104S_01 : 20|5@1+ (1,0) [0|31] ""  MBMU,PC
 SG_ BAT_Ucell_Min_CELL_104S_01 : 25|7@1+ (1,0) [0|127] ""  MBMU,PC
 SG_ BAT_Ucell_Max_104S_01 : 32|16@1+ (1,0) [0|65535] "mV"  MBMU,PC
 SG_ BAT_Ucell_Min_104S_01 : 48|16@1+ (1,0) [0|65535] "mV"  MBMU,PC

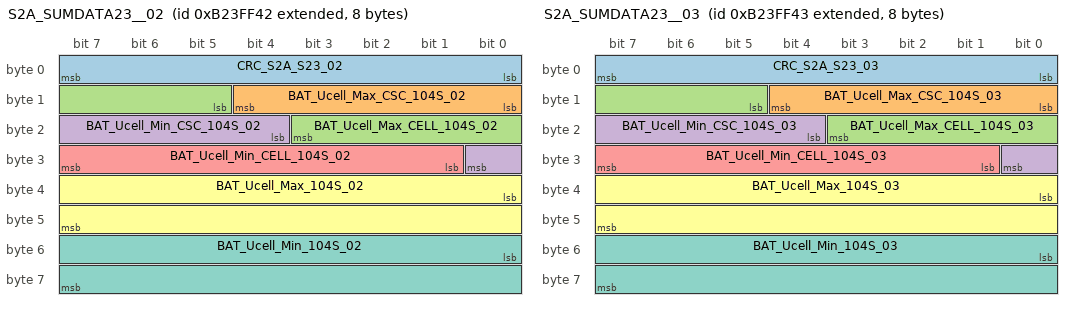
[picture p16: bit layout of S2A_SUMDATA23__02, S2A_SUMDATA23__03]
BO_ 2334392130 S2A_SUMDATA23__02: 8 SBMU
 SG_ CRC_S2A_S23_02 : 0|8@1+ (1,0) [0|255] ""  MBMU,PC
 SG_ BAT_Ucell_Max_CSC_104S_02 : 8|5@1+ (1,0) [0|31] ""  MBMU,PC
 SG_ BAT_Ucell_Max_CELL_104S_02 : 13|7@1+ (1,0) [0|127] ""  MBMU,PC
 SG_ BAT_Ucell_Min_CSC_104S_02 : 20|5@1+ (1,0) [0|31] ""  MBMU,PC
 SG_ BAT_Ucell_Min_CELL_104S_02 : 25|7@1+ (1,0) [0|127] ""  MBMU,PC
 SG_ BAT_Ucell_Max_104S_02 : 32|16@1+ (1,0) [0|65535] "mV"  MBMU,PC
 SG_ BAT_Ucell_Min_104S_02 : 48|16@1+ (1,0) [0|65535] "mV"  MBMU,PC

BO_ 2334392131 S2A_SUMDATA23__03: 8 SBMU
 SG_ CRC_S2A_S23_03 : 0|8@1+ (1,0) [0|255] ""  MBMU,PC
 SG_ BAT_Ucell_Max_CSC_104S_03 : 8|5@1+ (1,0) [0|31] ""  MBMU,PC
 SG_ BAT_Ucell_Max_CELL_104S_03 : 13|7@1+ (1,0) [0|127] ""  MBMU,PC
 SG_ BAT_Ucell_Min_CSC_104S_03 : 20|5@1+ (1,0) [0|31] ""  MBMU,PC
 SG_ BAT_Ucell_Min_CELL_104S_03 : 25|7@1+ (1,0) [0|127] ""  MBMU,PC
 SG_ BAT_Ucell_Max_104S_03 : 32|16@1+ (1,0) [0|65535] "mV"  MBMU,PC
 SG_ BAT_Ucell_Min_104S_03 : 48|16@1+ (1,0) [0|65535] "mV"  MBMU,PC

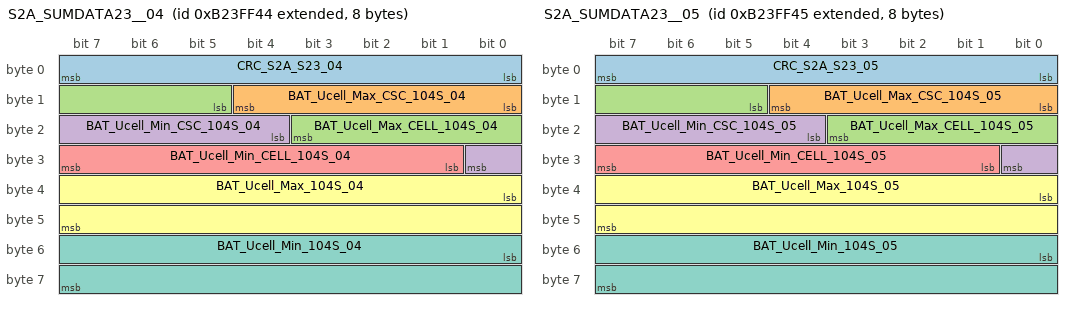
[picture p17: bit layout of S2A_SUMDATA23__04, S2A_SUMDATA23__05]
BO_ 2334392132 S2A_SUMDATA23__04: 8 SBMU
 SG_ CRC_S2A_S23_04 : 0|8@1+ (1,0) [0|255] ""  MBMU,PC
 SG_ BAT_Ucell_Max_CSC_104S_04 : 8|5@1+ (1,0) [0|31] ""  MBMU,PC
 SG_ BAT_Ucell_Max_CELL_104S_04 : 13|7@1+ (1,0) [0|127] ""  MBMU,PC
 SG_ BAT_Ucell_Min_CSC_104S_04 : 20|5@1+ (1,0) [0|31] ""  MBMU,PC
 SG_ BAT_Ucell_Min_CELL_104S_04 : 25|7@1+ (1,0) [0|127] ""  MBMU,PC
 SG_ BAT_Ucell_Max_104S_04 : 32|16@1+ (1,0) [0|65535] "mV"  MBMU,PC
 SG_ BAT_Ucell_Min_104S_04 : 48|16@1+ (1,0) [0|65535] "mV"  MBMU,PC

BO_ 2334392133 S2A_SUMDATA23__05: 8 SBMU
 SG_ CRC_S2A_S23_05 : 0|8@1+ (1,0) [0|255] ""  MBMU,PC
 SG_ BAT_Ucell_Max_CSC_104S_05 : 8|5@1+ (1,0) [0|31] ""  MBMU,PC
 SG_ BAT_Ucell_Max_CELL_104S_05 : 13|7@1+ (1,0) [0|127] ""  MBMU,PC
 SG_ BAT_Ucell_Min_CSC_104S_05 : 20|5@1+ (1,0) [0|31] ""  MBMU,PC
 SG_ BAT_Ucell_Min_CELL_104S_05 : 25|7@1+ (1,0) [0|127] ""  MBMU,PC
 SG_ BAT_Ucell_Max_104S_05 : 32|16@1+ (1,0) [0|65535] "mV"  MBMU,PC
 SG_ BAT_Ucell_Min_104S_05 : 48|16@1+ (1,0) [0|65535] "mV"  MBMU,PC

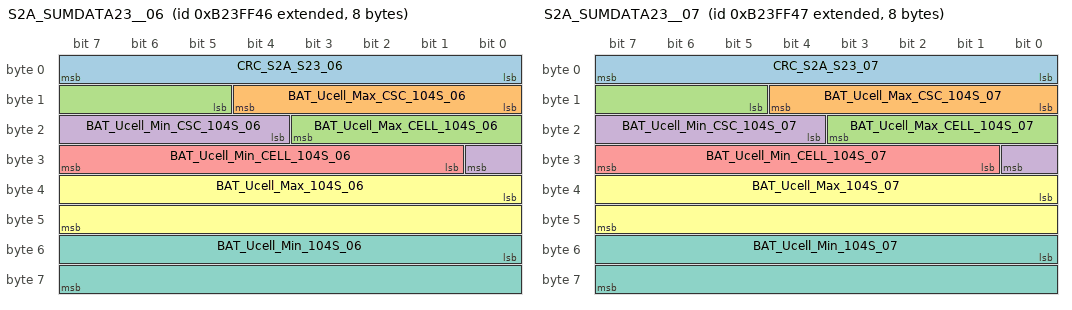
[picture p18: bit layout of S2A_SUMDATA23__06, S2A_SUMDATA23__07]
BO_ 2334392134 S2A_SUMDATA23__06: 8 SBMU
 SG_ CRC_S2A_S23_06 : 0|8@1+ (1,0) [0|255] ""  MBMU,PC
 SG_ BAT_Ucell_Max_CSC_104S_06 : 8|5@1+ (1,0) [0|31] ""  MBMU,PC
 SG_ BAT_Ucell_Max_CELL_104S_06 : 13|7@1+ (1,0) [0|127] ""  MBMU,PC
 SG_ BAT_Ucell_Min_CSC_104S_06 : 20|5@1+ (1,0) [0|31] ""  MBMU,PC
 SG_ BAT_Ucell_Min_CELL_104S_06 : 25|7@1+ (1,0) [0|127] ""  MBMU,PC
 SG_ BAT_Ucell_Max_104S_06 : 32|16@1+ (1,0) [0|65535] "mV"  MBMU,PC
 SG_ BAT_Ucell_Min_104S_06 : 48|16@1+ (1,0) [0|65535] "mV"  MBMU,PC

BO_ 2334392135 S2A_SUMDATA23__07: 8 SBMU
 SG_ CRC_S2A_S23_07 : 0|8@1+ (1,0) [0|255] ""  MBMU,PC
 SG_ BAT_Ucell_Max_CSC_104S_07 : 8|5@1+ (1,0) [0|31] ""  MBMU,PC
 SG_ BAT_Ucell_Max_CELL_104S_07 : 13|7@1+ (1,0) [0|127] ""  MBMU,PC
 SG_ BAT_Ucell_Min_CSC_104S_07 : 20|5@1+ (1,0) [0|31] ""  MBMU,PC
 SG_ BAT_Ucell_Min_CELL_104S_07 : 25|7@1+ (1,0) [0|127] ""  MBMU,PC
 SG_ BAT_Ucell_Max_104S_07 : 32|16@1+ (1,0) [0|65535] "mV"  MBMU,PC
 SG_ BAT_Ucell_Min_104S_07 : 48|16@1+ (1,0) [0|65535] "mV"  MBMU,PC

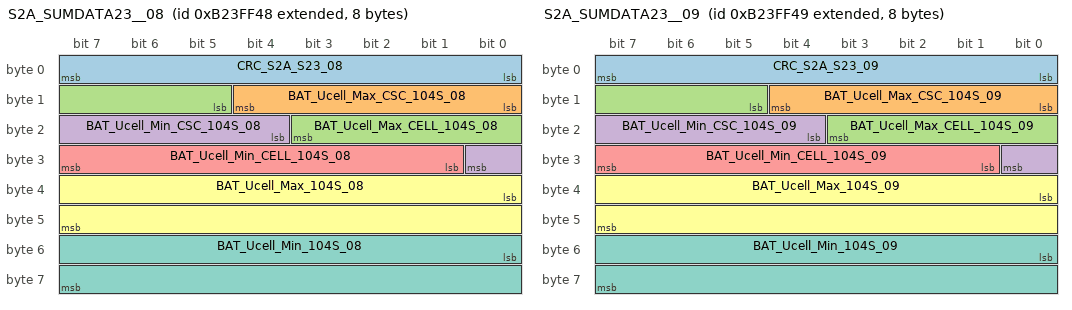
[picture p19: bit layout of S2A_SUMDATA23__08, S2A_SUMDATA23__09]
BO_ 2334392136 S2A_SUMDATA23__08: 8 SBMU
 SG_ CRC_S2A_S23_08 : 0|8@1+ (1,0) [0|255] ""  MBMU,PC
 SG_ BAT_Ucell_Max_CSC_104S_08 : 8|5@1+ (1,0) [0|31] ""  MBMU,PC
 SG_ BAT_Ucell_Max_CELL_104S_08 : 13|7@1+ (1,0) [0|127] ""  MBMU,PC
 SG_ BAT_Ucell_Min_CSC_104S_08 : 20|5@1+ (1,0) [0|31] ""  MBMU,PC
 SG_ BAT_Ucell_Min_CELL_104S_08 : 25|7@1+ (1,0) [0|127] ""  MBMU,PC
 SG_ BAT_Ucell_Max_104S_08 : 32|16@1+ (1,0) [0|65535] "mV"  MBMU,PC
 SG_ BAT_Ucell_Min_104S_08 : 48|16@1+ (1,0) [0|65535] "mV"  MBMU,PC

BO_ 2334392137 S2A_SUMDATA23__09: 8 SBMU
 SG_ CRC_S2A_S23_09 : 0|8@1+ (1,0) [0|255] ""  MBMU,PC
 SG_ BAT_Ucell_Max_CSC_104S_09 : 8|5@1+ (1,0) [0|31] ""  MBMU,PC
 SG_ BAT_Ucell_Max_CELL_104S_09 : 13|7@1+ (1,0) [0|127] ""  MBMU,PC
 SG_ BAT_Ucell_Min_CSC_104S_09 : 20|5@1+ (1,0) [0|31] ""  MBMU,PC
 SG_ BAT_Ucell_Min_CELL_104S_09 : 25|7@1+ (1,0) [0|127] ""  MBMU,PC
 SG_ BAT_Ucell_Max_104S_09 : 32|16@1+ (1,0) [0|65535] "mV"  MBMU,PC
 SG_ BAT_Ucell_Min_104S_09 : 48|16@1+ (1,0) [0|65535] "mV"  MBMU,PC

BO_ 2334392138 S2A_SUMDATA23__10: 8 SBMU
 SG_ CRC_S2A_S23_10 : 0|8@1+ (1,0) [0|255] ""  MBMU,PC
 SG_ BAT_Ucell_Max_CSC_104S_10 : 8|5@1+ (1,0) [0|31] ""  MBMU,PC
 SG_ BAT_Ucell_Max_CELL_104S_10 : 13|7@1+ (1,0) [0|127] ""  MBMU,PC
 SG_ BAT_Ucell_Min_CSC_104S_10 : 20|5@1+ (1,0) [0|31] ""  MBMU,PC
 SG_ BAT_Ucell_Min_CELL_104S_10 : 25|7@1+ (1,0) [0|127] ""  MBMU,PC
 SG_ BAT_Ucell_Max_104S_10 : 32|16@1+ (1,0) [0|65535] "mV"  MBMU,PC
 SG_ BAT_Ucell_Min_104S_10 : 48|16@1+ (1,0) [0|65535] "mV"  MBMU,PC

BO_ 2334392139 S2A_SUMDATA23__11: 8 SBMU
 SG_ CRC_S2A_S23_11 : 0|8@1+ (1,0) [0|255] ""  MBMU,PC
 SG_ BAT_Ucell_Max_CSC_104S_11 : 8|5@1+ (1,0) [0|31] ""  MBMU,PC
 SG_ BAT_Ucell_Max_CELL_104S_11 : 13|7@1+ (1,0) [0|127] ""  MBMU,PC
 SG_ BAT_Ucell_Min_CSC_104S_11 : 20|5@1+ (1,0) [0|31] ""  MBMU,PC
 SG_ BAT_Ucell_Min_CELL_104S_11 : 25|7@1+ (1,0) [0|127] ""  MBMU,PC
 SG_ BAT_Ucell_Max_104S_11 : 32|16@1+ (1,0) [0|65535] "mV"  MBMU,PC
 SG_ BAT_Ucell_Min_104S_11 : 48|16@1+ (1,0) [0|65535] "mV"  MBMU,PC

BO_ 2334392140 S2A_SUMDATA23__12: 8 SBMU
 SG_ CRC_S2A_S23_12 : 0|8@1+ (1,0) [0|255] ""  MBMU,PC
 SG_ BAT_Ucell_Max_CSC_104S_12 : 8|5@1+ (1,0) [0|31] ""  MBMU,PC
 SG_ BAT_Ucell_Max_CELL_104S_12 : 13|7@1+ (1,0) [0|127] ""  MBMU,PC
 SG_ BAT_Ucell_Min_CSC_104S_12 : 20|5@1+ (1,0) [0|31] ""  MBMU,PC
 SG_ BAT_Ucell_Min_CELL_104S_12 : 25|7@1+ (1,0) [0|127] ""  MBMU,PC
 SG_ BAT_Ucell_Max_104S_12 : 32|16@1+ (1,0) [0|65535] "mV"  MBMU,PC
 SG_ BAT_Ucell_Min_104S_12 : 48|16@1+ (1,0) [0|65535] "mV"  MBMU,PC

BO_ 2334392141 S2A_SUMDATA23__13: 8 SBMU
 SG_ CRC_S2A_S23_13 : 0|8@1+ (1,0) [0|255] ""  MBMU,PC
 SG_ BAT_Ucell_Max_CSC_104S_13 : 8|5@1+ (1,0) [0|31] ""  MBMU,PC
 SG_ BAT_Ucell_Max_CELL_104S_13 : 13|7@1+ (1,0) [0|127] ""  MBMU,PC
 SG_ BAT_Ucell_Min_CSC_104S_13 : 20|5@1+ (1,0) [0|31] ""  MBMU,PC
 SG_ BAT_Ucell_Min_CELL_104S_13 : 25|7@1+ (1,0) [0|127] ""  MBMU,PC
 SG_ BAT_Ucell_Max_104S_13 : 32|16@1+ (1,0) [0|65535] "mV"  MBMU,PC
 SG_ BAT_Ucell_Min_104S_13 : 48|16@1+ (1,0) [0|65535] "mV"  MBMU,PC

BO_ 2334392142 S2A_SUMDATA23__14: 8 SBMU
 SG_ CRC_S2A_S23_14 : 0|8@1+ (1,0) [0|255] ""  MBMU,PC
 SG_ BAT_Ucell_Max_CSC_104S_14 : 8|5@1+ (1,0) [0|31] ""  MBMU,PC
 SG_ BAT_Ucell_Max_CELL_104S_14 : 13|7@1+ (1,0) [0|127] ""  MBMU,PC
 SG_ BAT_Ucell_Min_CSC_104S_14 : 20|5@1+ (1,0) [0|31] ""  MBMU,PC
 SG_ BAT_Ucell_Min_CELL_104S_14 : 25|7@1+ (1,0) [0|127] ""  MBMU,PC
 SG_ BAT_Ucell_Max_104S_14 : 32|16@1+ (1,0) [0|65535] "mV"  MBMU,PC
 SG_ BAT_Ucell_Min_104S_14 : 48|16@1+ (1,0) [0|65535] "mV"  MBMU,PC

BO_ 2334392143 S2A_SUMDATA23__15: 8 SBMU
 SG_ CRC_S2A_S23_15 : 0|8@1+ (1,0) [0|255] ""  MBMU,PC
 SG_ BAT_Ucell_Max_CSC_104S_15 : 8|5@1+ (1,0) [0|31] ""  MBMU,PC
 SG_ BAT_Ucell_Max_CELL_104S_15 : 13|7@1+ (1,0) [0|127] ""  MBMU,PC
 SG_ BAT_Ucell_Min_CSC_104S_15 : 20|5@1+ (1,0) [0|31] ""  MBMU,PC
 SG_ BAT_Ucell_Min_CELL_104S_15 : 25|7@1+ (1,0) [0|127] ""  MBMU,PC
 SG_ BAT_Ucell_Max_104S_15 : 32|16@1+ (1,0) [0|65535] "mV"  MBMU,PC
 SG_ BAT_Ucell_Min_104S_15 : 48|16@1+ (1,0) [0|65535] "mV"  MBMU,PC

BO_ 2334392144 S2A_SUMDATA23__16: 8 SBMU
 SG_ CRC_S2A_S23_16 : 0|8@1+ (1,0) [0|255] ""  MBMU,PC
 SG_ BAT_Ucell_Max_CSC_104S_16 : 8|5@1+ (1,0) [0|31] ""  MBMU,PC
 SG_ BAT_Ucell_Max_CELL_104S_16 : 13|7@1+ (1,0) [0|127] ""  MBMU,PC
 SG_ BAT_Ucell_Min_CSC_104S_16 : 20|5@1+ (1,0) [0|31] ""  MBMU,PC
 SG_ BAT_Ucell_Min_CELL_104S_16 : 25|7@1+ (1,0) [0|127] ""  MBMU,PC
 SG_ BAT_Ucell_Max_104S_16 : 32|16@1+ (1,0) [0|65535] "mV"  MBMU,PC
 SG_ BAT_Ucell_Min_104S_16 : 48|16@1+ (1,0) [0|65535] "mV"  MBMU,PC

BO_ 2334392145 S2A_SUMDATA23__17: 8 SBMU
 SG_ CRC_S2A_S23_17 : 0|8@1+ (1,0) [0|255] ""  MBMU,PC
 SG_ BAT_Ucell_Max_CSC_104S_17 : 8|5@1+ (1,0) [0|31] ""  MBMU,PC
 SG_ BAT_Ucell_Max_CELL_104S_17 : 13|7@1+ (1,0) [0|127] ""  MBMU,PC
 SG_ BAT_Ucell_Min_CSC_104S_17 : 20|5@1+ (1,0) [0|31] ""  MBMU,PC
 SG_ BAT_Ucell_Min_CELL_104S_17 : 25|7@1+ (1,0) [0|127] ""  MBMU,PC
 SG_ BAT_Ucell_Max_104S_17 : 32|16@1+ (1,0) [0|65535] "mV"  MBMU,PC
 SG_ BAT_Ucell_Min_104S_17 : 48|16@1+ (1,0) [0|65535] "mV"  MBMU,PC

BO_ 2334392146 S2A_SUMDATA23__18: 8 SBMU
 SG_ CRC_S2A_S23_18 : 0|8@1+ (1,0) [0|255] ""  MBMU,PC
 SG_ BAT_Ucell_Max_CSC_104S_18 : 8|5@1+ (1,0) [0|31] ""  MBMU,PC
 SG_ BAT_Ucell_Max_CELL_104S_18 : 13|7@1+ (1,0) [0|127] ""  MBMU,PC
 SG_ BAT_Ucell_Min_CSC_104S_18 : 20|5@1+ (1,0) [0|31] ""  MBMU,PC
 SG_ BAT_Ucell_Min_CELL_104S_18 : 25|7@1+ (1,0) [0|127] ""  MBMU,PC
 SG_ BAT_Ucell_Max_104S_18 : 32|16@1+ (1,0) [0|65535] "mV"  MBMU,PC
 SG_ BAT_Ucell_Min_104S_18 : 48|16@1+ (1,0) [0|65535] "mV"  MBMU,PC

BO_ 2334392147 S2A_SUMDATA23__19: 8 SBMU
 SG_ CRC_S2A_S23_19 : 0|8@1+ (1,0) [0|255] ""  MBMU,PC
 SG_ BAT_Ucell_Max_CSC_104S_19 : 8|5@1+ (1,0) [0|31] ""  MBMU,PC
 SG_ BAT_Ucell_Max_CELL_104S_19 : 13|7@1+ (1,0) [0|127] ""  MBMU,PC
 SG_ BAT_Ucell_Min_CSC_104S_19 : 20|5@1+ (1,0) [0|31] ""  MBMU,PC
 SG_ BAT_Ucell_Min_CELL_104S_19 : 25|7@1+ (1,0) [0|127] ""  MBMU,PC
 SG_ BAT_Ucell_Max_104S_19 : 32|16@1+ (1,0) [0|65535] "mV"  MBMU,PC
 SG_ BAT_Ucell_Min_104S_19 : 48|16@1+ (1,0) [0|65535] "mV"  MBMU,PC

BO_ 2334392148 S2A_SUMDATA23__20: 8 SBMU
 SG_ CRC_S2A_S23_20 : 0|8@1+ (1,0) [0|255] ""  MBMU,PC
 SG_ BAT_Ucell_Max_CSC_104S_20 : 8|5@1+ (1,0) [0|31] ""  MBMU,PC
 SG_ BAT_Ucell_Max_CELL_104S_20 : 13|7@1+ (1,0) [0|127] ""  MBMU,PC
 SG_ BAT_Ucell_Min_CSC_104S_20 : 20|5@1+ (1,0) [0|31] ""  MBMU,PC
 SG_ BAT_Ucell_Min_CELL_104S_20 : 25|7@1+ (1,0) [0|127] ""  MBMU,PC
 SG_ BAT_Ucell_Max_104S_20 : 32|16@1+ (1,0) [0|65535] "mV"  MBMU,PC
 SG_ BAT_Ucell_Min_104S_20 : 48|16@1+ (1,0) [0|65535] "mV"  MBMU,PC

BO_ 2334392149 S2A_SUMDATA23__21: 8 SBMU
 SG_ CRC_S2A_S23_21 : 0|8@1+ (1,0) [0|255] ""  MBMU,PC
 SG_ BAT_Ucell_Max_CSC_104S_21 : 8|5@1+ (1,0) [0|31] ""  MBMU,PC
 SG_ BAT_Ucell_Max_CELL_104S_21 : 13|7@1+ (1,0) [0|127] ""  MBMU,PC
 SG_ BAT_Ucell_Min_CSC_104S_21 : 20|5@1+ (1,0) [0|31] ""  MBMU,PC
 SG_ BAT_Ucell_Min_CELL_104S_21 : 25|7@1+ (1,0) [0|127] ""  MBMU,PC
 SG_ BAT_Ucell_Max_104S_21 : 32|16@1+ (1,0) [0|65535] "mV"  MBMU,PC
 SG_ BAT_Ucell_Min_104S_21 : 48|16@1+ (1,0) [0|65535] "mV"  MBMU,PC

BO_ 2334392150 S2A_SUMDATA23__22: 8 SBMU
 SG_ CRC_S2A_S23_22 : 0|8@1+ (1,0) [0|255] ""  MBMU,PC
 SG_ BAT_Ucell_Max_CSC_104S_22 : 8|5@1+ (1,0) [0|31] ""  MBMU,PC
 SG_ BAT_Ucell_Max_CELL_104S_22 : 13|7@1+ (1,0) [0|127] ""  MBMU,PC
 SG_ BAT_Ucell_Min_CSC_104S_22 : 20|5@1+ (1,0) [0|31] ""  MBMU,PC
 SG_ BAT_Ucell_Min_CELL_104S_22 : 25|7@1+ (1,0) [0|127] ""  MBMU,PC
 SG_ BAT_Ucell_Max_104S_22 : 32|16@1+ (1,0) [0|65535] "mV"  MBMU,PC
 SG_ BAT_Ucell_Min_104S_22 : 48|16@1+ (1,0) [0|65535] "mV"  MBMU,PC

BO_ 2334392151 S2A_SUMDATA23__23: 8 SBMU
 SG_ CRC_S2A_S23_23 : 0|8@1+ (1,0) [0|255] ""  MBMU,PC
 SG_ BAT_Ucell_Max_CSC_104S_23 : 8|5@1+ (1,0) [0|31] ""  MBMU,PC
 SG_ BAT_Ucell_Max_CELL_104S_23 : 13|7@1+ (1,0) [0|127] ""  MBMU,PC
 SG_ BAT_Ucell_Min_CSC_104S_23 : 20|5@1+ (1,0) [0|31] ""  MBMU,PC
 SG_ BAT_Ucell_Min_CELL_104S_23 : 25|7@1+ (1,0) [0|127] ""  MBMU,PC
 SG_ BAT_Ucell_Max_104S_23 : 32|16@1+ (1,0) [0|65535] "mV"  MBMU,PC
 SG_ BAT_Ucell_Min_104S_23 : 48|16@1+ (1,0) [0|65535] "mV"  MBMU,PC

BO_ 2334392152 S2A_SUMDATA23__24: 8 SBMU
 SG_ CRC_S2A_S23_24 : 0|8@1+ (1,0) [0|255] ""  MBMU,PC
 SG_ BAT_Ucell_Max_CSC_104S_24 : 8|5@1+ (1,0) [0|31] ""  MBMU,PC
 SG_ BAT_Ucell_Max_CELL_104S_24 : 13|7@1+ (1,0) [0|127] ""  MBMU,PC
 SG_ BAT_Ucell_Min_CSC_104S_24 : 20|5@1+ (1,0) [0|31] ""  MBMU,PC
 SG_ BAT_Ucell_Min_CELL_104S_24 : 25|7@1+ (1,0) [0|127] ""  MBMU,PC
 SG_ BAT_Ucell_Max_104S_24 : 32|16@1+ (1,0) [0|65535] "mV"  MBMU,PC
 SG_ BAT_Ucell_Min_104S_24 : 48|16@1+ (1,0) [0|65535] "mV"  MBMU,PC

BO_ 2334392153 S2A_SUMDATA23__25: 8 SBMU
 SG_ CRC_S2A_S23_25 : 0|8@1+ (1,0) [0|255] ""  MBMU,PC
 SG_ BAT_Ucell_Max_CSC_104S_25 : 8|5@1+ (1,0) [0|31] ""  MBMU,PC
 SG_ BAT_Ucell_Max_CELL_104S_25 : 13|7@1+ (1,0) [0|127] ""  MBMU,PC
 SG_ BAT_Ucell_Min_CSC_104S_25 : 20|5@1+ (1,0) [0|31] ""  MBMU,PC
 SG_ BAT_Ucell_Min_CELL_104S_25 : 25|7@1+ (1,0) [0|127] ""  MBMU,PC
 SG_ BAT_Ucell_Max_104S_25 : 32|16@1+ (1,0) [0|65535] "mV"  MBMU,PC
 SG_ BAT_Ucell_Min_104S_25 : 48|16@1+ (1,0) [0|65535] "mV"  MBMU,PC

BO_ 2334392154 S2A_SUMDATA23__26: 8 SBMU
 SG_ CRC_S2A_S23_26 : 0|8@1+ (1,0) [0|255] ""  MBMU,PC
 SG_ BAT_Ucell_Max_CSC_104S_26 : 8|5@1+ (1,0) [0|31] ""  MBMU,PC
 SG_ BAT_Ucell_Max_CELL_104S_26 : 13|7@1+ (1,0) [0|127] ""  MBMU,PC
 SG_ BAT_Ucell_Min_CSC_104S_26 : 20|5@1+ (1,0) [0|31] ""  MBMU,PC
 SG_ BAT_Ucell_Min_CELL_104S_26 : 25|7@1+ (1,0) [0|127] ""  MBMU,PC
 SG_ BAT_Ucell_Max_104S_26 : 32|16@1+ (1,0) [0|65535] "mV"  MBMU,PC
 SG_ BAT_Ucell_Min_104S_26 : 48|16@1+ (1,0) [0|65535] "mV"  MBMU,PC

BO_ 2334392155 S2A_SUMDATA23__27: 8 SBMU
 SG_ CRC_S2A_S23_27 : 0|8@1+ (1,0) [0|255] ""  MBMU,PC
 SG_ BAT_Ucell_Max_CSC_104S_27 : 8|5@1+ (1,0) [0|31] ""  MBMU,PC
 SG_ BAT_Ucell_Max_CELL_104S_27 : 13|7@1+ (1,0) [0|127] ""  MBMU,PC
 SG_ BAT_Ucell_Min_CSC_104S_27 : 20|5@1+ (1,0) [0|31] ""  MBMU,PC
 SG_ BAT_Ucell_Min_CELL_104S_27 : 25|7@1+ (1,0) [0|127] ""  MBMU,PC
 SG_ BAT_Ucell_Max_104S_27 : 32|16@1+ (1,0) [0|65535] "mV"  MBMU,PC
 SG_ BAT_Ucell_Min_104S_27 : 48|16@1+ (1,0) [0|65535] "mV"  MBMU,PC

BO_ 2334392156 S2A_SUMDATA23__28: 8 SBMU
 SG_ CRC_S2A_S23_28 : 0|8@1+ (1,0) [0|255] ""  MBMU,PC
 SG_ BAT_Ucell_Max_CSC_104S_28 : 8|5@1+ (1,0) [0|31] ""  MBMU,PC
 SG_ BAT_Ucell_Max_CELL_104S_28 : 13|7@1+ (1,0) [0|127] ""  MBMU,PC
 SG_ BAT_Ucell_Min_CSC_104S_28 : 20|5@1+ (1,0) [0|31] ""  MBMU,PC
 SG_ BAT_Ucell_Min_CELL_104S_28 : 25|7@1+ (1,0) [0|127] ""  MBMU,PC
 SG_ BAT_Ucell_Max_104S_28 : 32|16@1+ (1,0) [0|65535] "mV"  MBMU,PC
 SG_ BAT_Ucell_Min_104S_28 : 48|16@1+ (1,0) [0|65535] "mV"  MBMU,PC

BO_ 2334392157 S2A_SUMDATA23__29: 8 SBMU
 SG_ CRC_S2A_S23_29 : 0|8@1+ (1,0) [0|255] ""  MBMU,PC
 SG_ BAT_Ucell_Max_CSC_104S_29 : 8|5@1+ (1,0) [0|31] ""  MBMU,PC
 SG_ BAT_Ucell_Max_CELL_104S_29 : 13|7@1+ (1,0) [0|127] ""  MBMU,PC
 SG_ BAT_Ucell_Min_CSC_104S_29 : 20|5@1+ (1,0) [0|31] ""  MBMU,PC
 SG_ BAT_Ucell_Min_CELL_104S_29 : 25|7@1+ (1,0) [0|127] ""  MBMU,PC
 SG_ BAT_Ucell_Max_104S_29 : 32|16@1+ (1,0) [0|65535] "mV"  MBMU,PC
 SG_ BAT_Ucell_Min_104S_29 : 48|16@1+ (1,0) [0|65535] "mV"  MBMU,PC

BO_ 2334392158 S2A_SUMDATA23__30: 8 SBMU
 SG_ CRC_S2A_S23_30 : 0|8@1+ (1,0) [0|255] ""  MBMU,PC
 SG_ BAT_Ucell_Max_CSC_104S_30 : 8|5@1+ (1,0) [0|31] ""  MBMU,PC
 SG_ BAT_Ucell_Max_CELL_104S_30 : 13|7@1+ (1,0) [0|127] ""  MBMU,PC
 SG_ BAT_Ucell_Min_CSC_104S_30 : 20|5@1+ (1,0) [0|31] ""  MBMU,PC
 SG_ BAT_Ucell_Min_CELL_104S_30 : 25|7@1+ (1,0) [0|127] ""  MBMU,PC
 SG_ BAT_Ucell_Max_104S_30 : 32|16@1+ (1,0) [0|65535] "mV"  MBMU,PC
 SG_ BAT_Ucell_Min_104S_30 : 48|16@1+ (1,0) [0|65535] "mV"  MBMU,PC

BO_ 2334392159 S2A_SUMDATA23__31: 8 SBMU
 SG_ CRC_S2A_S23_31 : 0|8@1+ (1,0) [0|255] ""  MBMU,PC
 SG_ BAT_Ucell_Max_CSC_104S_31 : 8|5@1+ (1,0) [0|31] ""  MBMU,PC
 SG_ BAT_Ucell_Max_CELL_104S_31 : 13|7@1+ (1,0) [0|127] ""  MBMU,PC
 SG_ BAT_Ucell_Min_CSC_104S_31 : 20|5@1+ (1,0) [0|31] ""  MBMU,PC
 SG_ BAT_Ucell_Min_CELL_104S_31 : 25|7@1+ (1,0) [0|127] ""  MBMU,PC
 SG_ BAT_Ucell_Max_104S_31 : 32|16@1+ (1,0) [0|65535] "mV"  MBMU,PC
 SG_ BAT_Ucell_Min_104S_31 : 48|16@1+ (1,0) [0|65535] "mV"  MBMU,PC

BO_ 2334392160 S2A_SUMDATA23__32: 8 SBMU
 SG_ CRC_S2A_S23_32 : 0|8@1+ (1,0) [0|255] ""  MBMU,PC
 SG_ BAT_Ucell_Max_CSC_104S_32 : 8|5@1+ (1,0) [0|31] ""  MBMU,PC
 SG_ BAT_Ucell_Max_CELL_104S_32 : 13|7@1+ (1,0) [0|127] ""  MBMU,PC
 SG_ BAT_Ucell_Min_CSC_104S_32 : 20|5@1+ (1,0) [0|31] ""  MBMU,PC
 SG_ BAT_Ucell_Min_CELL_104S_32 : 25|7@1+ (1,0) [0|127] ""  MBMU,PC
 SG_ BAT_Ucell_Max_104S_32 : 32|16@1+ (1,0) [0|65535] "mV"  MBMU,PC
 SG_ BAT_Ucell_Min_104S_32 : 48|16@1+ (1,0) [0|65535] "mV"  MBMU,PC

BO_ 2334392161 S2A_SUMDATA23__33: 8 SBMU
 SG_ CRC_S2A_S23_33 : 0|8@1+ (1,0) [0|255] ""  MBMU,PC
 SG_ BAT_Ucell_Max_CSC_104S_33 : 8|5@1+ (1,0) [0|31] ""  MBMU,PC
 SG_ BAT_Ucell_Max_CELL_104S_33 : 13|7@1+ (1,0) [0|127] ""  MBMU,PC
 SG_ BAT_Ucell_Min_CSC_104S_33 : 20|5@1+ (1,0) [0|31] ""  MBMU,PC
 SG_ BAT_Ucell_Min_CELL_104S_33 : 25|7@1+ (1,0) [0|127] ""  MBMU,PC
 SG_ BAT_Ucell_Max_104S_33 : 32|16@1+ (1,0) [0|65535] "mV"  MBMU,PC
 SG_ BAT_Ucell_Min_104S_33 : 48|16@1+ (1,0) [0|65535] "mV"  MBMU,PC

BO_ 2334392162 S2A_SUMDATA23__34: 8 SBMU
 SG_ CRC_S2A_S23_34 : 0|8@1+ (1,0) [0|255] ""  MBMU,PC
 SG_ BAT_Ucell_Max_CSC_104S_34 : 8|5@1+ (1,0) [0|31] ""  MBMU,PC
 SG_ BAT_Ucell_Max_CELL_104S_34 : 13|7@1+ (1,0) [0|127] ""  MBMU,PC
 SG_ BAT_Ucell_Min_CSC_104S_34 : 20|5@1+ (1,0) [0|31] ""  MBMU,PC
 SG_ BAT_Ucell_Min_CELL_104S_34 : 25|7@1+ (1,0) [0|127] ""  MBMU,PC
 SG_ BAT_Ucell_Max_104S_34 : 32|16@1+ (1,0) [0|65535] "mV"  MBMU,PC
 SG_ BAT_Ucell_Min_104S_34 : 48|16@1+ (1,0) [0|65535] "mV"  MBMU,PC

BO_ 2334392163 S2A_SUMDATA23__35: 8 SBMU
 SG_ CRC_S2A_S23_35 : 0|8@1+ (1,0) [0|255] ""  MBMU,PC
 SG_ BAT_Ucell_Max_CSC_104S_35 : 8|5@1+ (1,0) [0|31] ""  MBMU,PC
 SG_ BAT_Ucell_Max_CELL_104S_35 : 13|7@1+ (1,0) [0|127] ""  MBMU,PC
 SG_ BAT_Ucell_Min_CSC_104S_35 : 20|5@1+ (1,0) [0|31] ""  MBMU,PC
 SG_ BAT_Ucell_Min_CELL_104S_35 : 25|7@1+ (1,0) [0|127] ""  MBMU,PC
 SG_ BAT_Ucell_Max_104S_35 : 32|16@1+ (1,0) [0|65535] "mV"  MBMU,PC
 SG_ BAT_Ucell_Min_104S_35 : 48|16@1+ (1,0) [0|65535] "mV"  MBMU,PC

BO_ 2334392164 S2A_SUMDATA23__36: 8 SBMU
 SG_ CRC_S2A_S23_36 : 0|8@1+ (1,0) [0|255] ""  MBMU,PC
 SG_ BAT_Ucell_Max_CSC_104S_36 : 8|5@1+ (1,0) [0|31] ""  MBMU,PC
 SG_ BAT_Ucell_Max_CELL_104S_36 : 13|7@1+ (1,0) [0|127] ""  MBMU,PC
 SG_ BAT_Ucell_Min_CSC_104S_36 : 20|5@1+ (1,0) [0|31] ""  MBMU,PC
 SG_ BAT_Ucell_Min_CELL_104S_36 : 25|7@1+ (1,0) [0|127] ""  MBMU,PC
 SG_ BAT_Ucell_Max_104S_36 : 32|16@1+ (1,0) [0|65535] "mV"  MBMU,PC
 SG_ BAT_Ucell_Min_104S_36 : 48|16@1+ (1,0) [0|65535] "mV"  MBMU,PC

BO_ 2334392165 S2A_SUMDATA23__37: 8 SBMU
 SG_ CRC_S2A_S23_37 : 0|8@1+ (1,0) [0|255] ""  MBMU,PC
 SG_ BAT_Ucell_Max_CSC_104S_37 : 8|5@1+ (1,0) [0|31] ""  MBMU,PC
 SG_ BAT_Ucell_Max_CELL_104S_37 : 13|7@1+ (1,0) [0|127] ""  MBMU,PC
 SG_ BAT_Ucell_Min_CSC_104S_37 : 20|5@1+ (1,0) [0|31] ""  MBMU,PC
 SG_ BAT_Ucell_Min_CELL_104S_37 : 25|7@1+ (1,0) [0|127] ""  MBMU,PC
 SG_ BAT_Ucell_Max_104S_37 : 32|16@1+ (1,0) [0|65535] "mV"  MBMU,PC
 SG_ BAT_Ucell_Min_104S_37 : 48|16@1+ (1,0) [0|65535] "mV"  MBMU,PC

BO_ 2334392166 S2A_SUMDATA23__38: 8 SBMU
 SG_ CRC_S2A_S23_38 : 0|8@1+ (1,0) [0|255] ""  MBMU,PC
 SG_ BAT_Ucell_Max_CSC_104S_38 : 8|5@1+ (1,0) [0|31] ""  MBMU,PC
 SG_ BAT_Ucell_Max_CELL_104S_38 : 13|7@1+ (1,0) [0|127] ""  MBMU,PC
 SG_ BAT_Ucell_Min_CSC_104S_38 : 20|5@1+ (1,0) [0|31] ""  MBMU,PC
 SG_ BAT_Ucell_Min_CELL_104S_38 : 25|7@1+ (1,0) [0|127] ""  MBMU,PC
 SG_ BAT_Ucell_Max_104S_38 : 32|16@1+ (1,0) [0|65535] "mV"  MBMU,PC
 SG_ BAT_Ucell_Min_104S_38 : 48|16@1+ (1,0) [0|65535] "mV"  MBMU,PC

BO_ 2334392167 S2A_SUMDATA23__39: 8 SBMU
 SG_ CRC_S2A_S23_39 : 0|8@1+ (1,0) [0|255] ""  MBMU,PC
 SG_ BAT_Ucell_Max_CSC_104S_39 : 8|5@1+ (1,0) [0|31] ""  MBMU,PC
 SG_ BAT_Ucell_Max_CELL_104S_39 : 13|7@1+ (1,0) [0|127] ""  MBMU,PC
 SG_ BAT_Ucell_Min_CSC_104S_39 : 20|5@1+ (1,0) [0|31] ""  MBMU,PC
 SG_ BAT_Ucell_Min_CELL_104S_39 : 25|7@1+ (1,0) [0|127] ""  MBMU,PC
 SG_ BAT_Ucell_Max_104S_39 : 32|16@1+ (1,0) [0|65535] "mV"  MBMU,PC
 SG_ BAT_Ucell_Min_104S_39 : 48|16@1+ (1,0) [0|65535] "mV"  MBMU,PC

BO_ 2334392168 S2A_SUMDATA23__40: 8 SBMU
 SG_ CRC_S2A_S23_40 : 0|8@1+ (1,0) [0|255] ""  MBMU,PC
 SG_ BAT_Ucell_Max_CSC_104S_40 : 8|5@1+ (1,0) [0|31] ""  MBMU,PC
 SG_ BAT_Ucell_Max_CELL_104S_40 : 13|7@1+ (1,0) [0|127] ""  MBMU,PC
 SG_ BAT_Ucell_Min_CSC_104S_40 : 20|5@1+ (1,0) [0|31] ""  MBMU,PC
 SG_ BAT_Ucell_Min_CELL_104S_40 : 25|7@1+ (1,0) [0|127] ""  MBMU,PC
 SG_ BAT_Ucell_Max_104S_40 : 32|16@1+ (1,0) [0|65535] "mV"  MBMU,PC
 SG_ BAT_Ucell_Min_104S_40 : 48|16@1+ (1,0) [0|65535] "mV"  MBMU,PC

BO_ 2334392169 S2A_SUMDATA23__41: 8 SBMU
 SG_ CRC_S2A_S23_41 : 0|8@1+ (1,0) [0|255] ""  MBMU,PC
 SG_ BAT_Ucell_Max_CSC_104S_41 : 8|5@1+ (1,0) [0|31] ""  MBMU,PC
 SG_ BAT_Ucell_Max_CELL_104S_41 : 13|7@1+ (1,0) [0|127] ""  MBMU,PC
 SG_ BAT_Ucell_Min_CSC_104S_41 : 20|5@1+ (1,0) [0|31] ""  MBMU,PC
 SG_ BAT_Ucell_Min_CELL_104S_41 : 25|7@1+ (1,0) [0|127] ""  MBMU,PC
 SG_ BAT_Ucell_Max_104S_41 : 32|16@1+ (1,0) [0|65535] "mV"  MBMU,PC
 SG_ BAT_Ucell_Min_104S_41 : 48|16@1+ (1,0) [0|65535] "mV"  MBMU,PC

BO_ 2334392170 S2A_SUMDATA23__42: 8 SBMU
 SG_ CRC_S2A_S23_42 : 0|8@1+ (1,0) [0|255] ""  MBMU,PC
 SG_ BAT_Ucell_Max_CSC_104S_42 : 8|5@1+ (1,0) [0|31] ""  MBMU,PC
 SG_ BAT_Ucell_Max_CELL_104S_42 : 13|7@1+ (1,0) [0|127] ""  MBMU,PC
 SG_ BAT_Ucell_Min_CSC_104S_42 : 20|5@1+ (1,0) [0|31] ""  MBMU,PC
 SG_ BAT_Ucell_Min_CELL_104S_42 : 25|7@1+ (1,0) [0|127] ""  MBMU,PC
 SG_ BAT_Ucell_Max_104S_42 : 32|16@1+ (1,0) [0|65535] "mV"  MBMU,PC
 SG_ BAT_Ucell_Min_104S_42 : 48|16@1+ (1,0) [0|65535] "mV"  MBMU,PC

BO_ 2334392171 S2A_SUMDATA23__43: 8 SBMU
 SG_ CRC_S2A_S23_43 : 0|8@1+ (1,0) [0|255] ""  MBMU,PC
 SG_ BAT_Ucell_Max_CSC_104S_43 : 8|5@1+ (1,0) [0|31] ""  MBMU,PC
 SG_ BAT_Ucell_Max_CELL_104S_43 : 13|7@1+ (1,0) [0|127] ""  MBMU,PC
 SG_ BAT_Ucell_Min_CSC_104S_43 : 20|5@1+ (1,0) [0|31] ""  MBMU,PC
 SG_ BAT_Ucell_Min_CELL_104S_43 : 25|7@1+ (1,0) [0|127] ""  MBMU,PC
 SG_ BAT_Ucell_Max_104S_43 : 32|16@1+ (1,0) [0|65535] "mV"  MBMU,PC
 SG_ BAT_Ucell_Min_104S_43 : 48|16@1+ (1,0) [0|65535] "mV"  MBMU,PC

BO_ 2334392172 S2A_SUMDATA23__44: 8 SBMU
 SG_ CRC_S2A_S23_44 : 0|8@1+ (1,0) [0|255] ""  MBMU,PC
 SG_ BAT_Ucell_Max_CSC_104S_44 : 8|5@1+ (1,0) [0|31] ""  MBMU,PC
 SG_ BAT_Ucell_Max_CELL_104S_44 : 13|7@1+ (1,0) [0|127] ""  MBMU,PC
 SG_ BAT_Ucell_Min_CSC_104S_44 : 20|5@1+ (1,0) [0|31] ""  MBMU,PC
 SG_ BAT_Ucell_Min_CELL_104S_44 : 25|7@1+ (1,0) [0|127] ""  MBMU,PC
 SG_ BAT_Ucell_Max_104S_44 : 32|16@1+ (1,0) [0|65535] "mV"  MBMU,PC
 SG_ BAT_Ucell_Min_104S_44 : 48|16@1+ (1,0) [0|65535] "mV"  MBMU,PC

BO_ 2334392173 S2A_SUMDATA23__45: 8 SBMU
 SG_ CRC_S2A_S23_45 : 0|8@1+ (1,0) [0|255] ""  MBMU,PC
 SG_ BAT_Ucell_Max_CSC_104S_45 : 8|5@1+ (1,0) [0|31] ""  MBMU,PC
 SG_ BAT_Ucell_Max_CELL_104S_45 : 13|7@1+ (1,0) [0|127] ""  MBMU,PC
 SG_ BAT_Ucell_Min_CSC_104S_45 : 20|5@1+ (1,0) [0|31] ""  MBMU,PC
 SG_ BAT_Ucell_Min_CELL_104S_45 : 25|7@1+ (1,0) [0|127] ""  MBMU,PC
 SG_ BAT_Ucell_Max_104S_45 : 32|16@1+ (1,0) [0|65535] "mV"  MBMU,PC
 SG_ BAT_Ucell_Min_104S_45 : 48|16@1+ (1,0) [0|65535] "mV"  MBMU,PC

BO_ 2334392174 S2A_SUMDATA23__46: 8 SBMU
 SG_ CRC_S2A_S23_46 : 0|8@1+ (1,0) [0|255] ""  MBMU,PC
 SG_ BAT_Ucell_Max_CSC_104S_46 : 8|5@1+ (1,0) [0|31] ""  MBMU,PC
 SG_ BAT_Ucell_Max_CELL_104S_46 : 13|7@1+ (1,0) [0|127] ""  MBMU,PC
 SG_ BAT_Ucell_Min_CSC_104S_46 : 20|5@1+ (1,0) [0|31] ""  MBMU,PC
 SG_ BAT_Ucell_Min_CELL_104S_46 : 25|7@1+ (1,0) [0|127] ""  MBMU,PC
 SG_ BAT_Ucell_Max_104S_46 : 32|16@1+ (1,0) [0|65535] "mV"  MBMU,PC
 SG_ BAT_Ucell_Min_104S_46 : 48|16@1+ (1,0) [0|65535] "mV"  MBMU,PC

BO_ 2334392175 S2A_SUMDATA23__47: 8 SBMU
 SG_ CRC_S2A_S23_47 : 0|8@1+ (1,0) [0|255] ""  MBMU,PC
 SG_ BAT_Ucell_Max_CSC_104S_47 : 8|5@1+ (1,0) [0|31] ""  MBMU,PC
 SG_ BAT_Ucell_Max_CELL_104S_47 : 13|7@1+ (1,0) [0|127] ""  MBMU,PC
 SG_ BAT_Ucell_Min_CSC_104S_47 : 20|5@1+ (1,0) [0|31] ""  MBMU,PC
 SG_ BAT_Ucell_Min_CELL_104S_47 : 25|7@1+ (1,0) [0|127] ""  MBMU,PC
 SG_ BAT_Ucell_Max_104S_47 : 32|16@1+ (1,0) [0|65535] "mV"  MBMU,PC
 SG_ BAT_Ucell_Min_104S_47 : 48|16@1+ (1,0) [0|65535] "mV"  MBMU,PC

BO_ 2334392176 S2A_SUMDATA23__48: 8 SBMU
 SG_ CRC_S2A_S23_48 : 0|8@1+ (1,0) [0|255] ""  MBMU,PC
 SG_ BAT_Ucell_Max_CSC_104S_48 : 8|5@1+ (1,0) [0|31] ""  MBMU,PC
 SG_ BAT_Ucell_Max_CELL_104S_48 : 13|7@1+ (1,0) [0|127] ""  MBMU,PC
 SG_ BAT_Ucell_Min_CSC_104S_48 : 20|5@1+ (1,0) [0|31] ""  MBMU,PC
 SG_ BAT_Ucell_Min_CELL_104S_48 : 25|7@1+ (1,0) [0|127] ""  MBMU,PC
 SG_ BAT_Ucell_Max_104S_48 : 32|16@1+ (1,0) [0|65535] "mV"  MBMU,PC
 SG_ BAT_Ucell_Min_104S_48 : 48|16@1+ (1,0) [0|65535] "mV"  MBMU,PC

BO_ 2334392177 S2A_SUMDATA23__49: 8 SBMU
 SG_ CRC_S2A_S23_49 : 0|8@1+ (1,0) [0|255] ""  MBMU,PC
 SG_ BAT_Ucell_Max_CSC_104S_49 : 8|5@1+ (1,0) [0|31] ""  MBMU,PC
 SG_ BAT_Ucell_Max_CELL_104S_49 : 13|7@1+ (1,0) [0|127] ""  MBMU,PC
 SG_ BAT_Ucell_Min_CSC_104S_49 : 20|5@1+ (1,0) [0|31] ""  MBMU,PC
 SG_ BAT_Ucell_Min_CELL_104S_49 : 25|7@1+ (1,0) [0|127] ""  MBMU,PC
 SG_ BAT_Ucell_Max_104S_49 : 32|16@1+ (1,0) [0|65535] "mV"  MBMU,PC
 SG_ BAT_Ucell_Min_104S_49 : 48|16@1+ (1,0) [0|65535] "mV"  MBMU,PC

BO_ 2334392178 S2A_SUMDATA23__50: 8 SBMU
 SG_ CRC_S2A_S23_50 : 0|8@1+ (1,0) [0|255] ""  MBMU,PC
 SG_ BAT_Ucell_Max_CSC_104S_50 : 8|5@1+ (1,0) [0|31] ""  MBMU,PC
 SG_ BAT_Ucell_Max_CELL_104S_50 : 13|7@1+ (1,0) [0|127] ""  MBMU,PC
 SG_ BAT_Ucell_Min_CSC_104S_50 : 20|5@1+ (1,0) [0|31] ""  MBMU,PC
 SG_ BAT_Ucell_Min_CELL_104S_50 : 25|7@1+ (1,0) [0|127] ""  MBMU,PC
 SG_ BAT_Ucell_Max_104S_50 : 32|16@1+ (1,0) [0|65535] "mV"  MBMU,PC
 SG_ BAT_Ucell_Min_104S_50 : 48|16@1+ (1,0) [0|65535] "mV"  MBMU,PC

BO_ 2334392179 S2A_SUMDATA23__51: 8 SBMU
 SG_ CRC_S2A_S23_51 : 0|8@1+ (1,0) [0|255] ""  MBMU,PC
 SG_ BAT_Ucell_Max_CSC_104S_51 : 8|5@1+ (1,0) [0|31] ""  MBMU,PC
 SG_ BAT_Ucell_Max_CELL_104S_51 : 13|7@1+ (1,0) [0|127] ""  MBMU,PC
 SG_ BAT_Ucell_Min_CSC_104S_51 : 20|5@1+ (1,0) [0|31] ""  MBMU,PC
 SG_ BAT_Ucell_Min_CELL_104S_51 : 25|7@1+ (1,0) [0|127] ""  MBMU,PC
 SG_ BAT_Ucell_Max_104S_51 : 32|16@1+ (1,0) [0|65535] "mV"  MBMU,PC
 SG_ BAT_Ucell_Min_104S_51 : 48|16@1+ (1,0) [0|65535] "mV"  MBMU,PC

BO_ 2334392180 S2A_SUMDATA23__52: 8 SBMU
 SG_ CRC_S2A_S23_52 : 0|8@1+ (1,0) [0|255] ""  MBMU,PC
 SG_ BAT_Ucell_Max_CSC_104S_52 : 8|5@1+ (1,0) [0|31] ""  MBMU,PC
 SG_ BAT_Ucell_Max_CELL_104S_52 : 13|7@1+ (1,0) [0|127] ""  MBMU,PC
 SG_ BAT_Ucell_Min_CSC_104S_52 : 20|5@1+ (1,0) [0|31] ""  MBMU,PC
 SG_ BAT_Ucell_Min_CELL_104S_52 : 25|7@1+ (1,0) [0|127] ""  MBMU,PC
 SG_ BAT_Ucell_Max_104S_52 : 32|16@1+ (1,0) [0|65535] "mV"  MBMU,PC
 SG_ BAT_Ucell_Min_104S_52 : 48|16@1+ (1,0) [0|65535] "mV"  MBMU,PC

BO_ 2334392181 S2A_SUMDATA23__53: 8 SBMU
 SG_ CRC_S2A_S23_53 : 0|8@1+ (1,0) [0|255] ""  MBMU,PC
 SG_ BAT_Ucell_Max_CSC_104S_53 : 8|5@1+ (1,0) [0|31] ""  MBMU,PC
 SG_ BAT_Ucell_Max_CELL_104S_53 : 13|7@1+ (1,0) [0|127] ""  MBMU,PC
 SG_ BAT_Ucell_Min_CSC_104S_53 : 20|5@1+ (1,0) [0|31] ""  MBMU,PC
 SG_ BAT_Ucell_Min_CELL_104S_53 : 25|7@1+ (1,0) [0|127] ""  MBMU,PC
 SG_ BAT_Ucell_Max_104S_53 : 32|16@1+ (1,0) [0|65535] "mV"  MBMU,PC
 SG_ BAT_Ucell_Min_104S_53 : 48|16@1+ (1,0) [0|65535] "mV"  MBMU,PC

BO_ 2334392182 S2A_SUMDATA23__54: 8 SBMU
 SG_ CRC_S2A_S23_54 : 0|8@1+ (1,0) [0|255] ""  MBMU,PC
 SG_ BAT_Ucell_Max_CSC_104S_54 : 8|5@1+ (1,0) [0|31] ""  MBMU,PC
 SG_ BAT_Ucell_Max_CELL_104S_54 : 13|7@1+ (1,0) [0|127] ""  MBMU,PC
 SG_ BAT_Ucell_Min_CSC_104S_54 : 20|5@1+ (1,0) [0|31] ""  MBMU,PC
 SG_ BAT_Ucell_Min_CELL_104S_54 : 25|7@1+ (1,0) [0|127] ""  MBMU,PC
 SG_ BAT_Ucell_Max_104S_54 : 32|16@1+ (1,0) [0|65535] "mV"  MBMU,PC
 SG_ BAT_Ucell_Min_104S_54 : 48|16@1+ (1,0) [0|65535] "mV"  MBMU,PC

BO_ 2334392183 S2A_SUMDATA23__55: 8 SBMU
 SG_ CRC_S2A_S23_55 : 0|8@1+ (1,0) [0|255] ""  MBMU,PC
 SG_ BAT_Ucell_Max_CSC_104S_55 : 8|5@1+ (1,0) [0|31] ""  MBMU,PC
 SG_ BAT_Ucell_Max_CELL_104S_55 : 13|7@1+ (1,0) [0|127] ""  MBMU,PC
 SG_ BAT_Ucell_Min_CSC_104S_55 : 20|5@1+ (1,0) [0|31] ""  MBMU,PC
 SG_ BAT_Ucell_Min_CELL_104S_55 : 25|7@1+ (1,0) [0|127] ""  MBMU,PC
 SG_ BAT_Ucell_Max_104S_55 : 32|16@1+ (1,0) [0|65535] "mV"  MBMU,PC
 SG_ BAT_Ucell_Min_104S_55 : 48|16@1+ (1,0) [0|65535] "mV"  MBMU,PC

BO_ 2334392184 S2A_SUMDATA23__56: 8 SBMU
 SG_ CRC_S2A_S23_56 : 0|8@1+ (1,0) [0|255] ""  MBMU,PC
 SG_ BAT_Ucell_Max_CSC_104S_56 : 8|5@1+ (1,0) [0|31] ""  MBMU,PC
 SG_ BAT_Ucell_Max_CELL_104S_56 : 13|7@1+ (1,0) [0|127] ""  MBMU,PC
 SG_ BAT_Ucell_Min_CSC_104S_56 : 20|5@1+ (1,0) [0|31] ""  MBMU,PC
 SG_ BAT_Ucell_Min_CELL_104S_56 : 25|7@1+ (1,0) [0|127] ""  MBMU,PC
 SG_ BAT_Ucell_Max_104S_56 : 32|16@1+ (1,0) [0|65535] "mV"  MBMU,PC
 SG_ BAT_Ucell_Min_104S_56 : 48|16@1+ (1,0) [0|65535] "mV"  MBMU,PC

BO_ 2334392185 S2A_SUMDATA23__57: 8 SBMU
 SG_ CRC_S2A_S23_57 : 0|8@1+ (1,0) [0|255] ""  MBMU,PC
 SG_ BAT_Ucell_Max_CSC_104S_57 : 8|5@1+ (1,0) [0|31] ""  MBMU,PC
 SG_ BAT_Ucell_Max_CELL_104S_57 : 13|7@1+ (1,0) [0|127] ""  MBMU,PC
 SG_ BAT_Ucell_Min_CSC_104S_57 : 20|5@1+ (1,0) [0|31] ""  MBMU,PC
 SG_ BAT_Ucell_Min_CELL_104S_57 : 25|7@1+ (1,0) [0|127] ""  MBMU,PC
 SG_ BAT_Ucell_Max_104S_57 : 32|16@1+ (1,0) [0|65535] "mV"  MBMU,PC
 SG_ BAT_Ucell_Min_104S_57 : 48|16@1+ (1,0) [0|65535] "mV"  MBMU,PC

BO_ 2334392186 S2A_SUMDATA23__58: 8 SBMU
 SG_ CRC_S2A_S23_58 : 0|8@1+ (1,0) [0|255] ""  MBMU,PC
 SG_ BAT_Ucell_Max_CSC_104S_58 : 8|5@1+ (1,0) [0|31] ""  MBMU,PC
 SG_ BAT_Ucell_Max_CELL_104S_58 : 13|7@1+ (1,0) [0|127] ""  MBMU,PC
 SG_ BAT_Ucell_Min_CSC_104S_58 : 20|5@1+ (1,0) [0|31] ""  MBMU,PC
 SG_ BAT_Ucell_Min_CELL_104S_58 : 25|7@1+ (1,0) [0|127] ""  MBMU,PC
 SG_ BAT_Ucell_Max_104S_58 : 32|16@1+ (1,0) [0|65535] "mV"  MBMU,PC
 SG_ BAT_Ucell_Min_104S_58 : 48|16@1+ (1,0) [0|65535] "mV"  MBMU,PC

BO_ 2334392187 S2A_SUMDATA23__59: 8 SBMU
 SG_ CRC_S2A_S23_59 : 0|8@1+ (1,0) [0|255] ""  MBMU,PC
 SG_ BAT_Ucell_Max_CSC_104S_59 : 8|5@1+ (1,0) [0|31] ""  MBMU,PC
 SG_ BAT_Ucell_Max_CELL_104S_59 : 13|7@1+ (1,0) [0|127] ""  MBMU,PC
 SG_ BAT_Ucell_Min_CSC_104S_59 : 20|5@1+ (1,0) [0|31] ""  MBMU,PC
 SG_ BAT_Ucell_Min_CELL_104S_59 : 25|7@1+ (1,0) [0|127] ""  MBMU,PC
 SG_ BAT_Ucell_Max_104S_59 : 32|16@1+ (1,0) [0|65535] "mV"  MBMU,PC
 SG_ BAT_Ucell_Min_104S_59 : 48|16@1+ (1,0) [0|65535] "mV"  MBMU,PC

BO_ 2334392188 S2A_SUMDATA23__60: 8 SBMU
 SG_ CRC_S2A_S23_60 : 0|8@1+ (1,0) [0|255] ""  MBMU,PC
 SG_ BAT_Ucell_Max_CSC_104S_60 : 8|5@1+ (1,0) [0|31] ""  MBMU,PC
 SG_ BAT_Ucell_Max_CELL_104S_60 : 13|7@1+ (1,0) [0|127] ""  MBMU,PC
 SG_ BAT_Ucell_Min_CSC_104S_60 : 20|5@1+ (1,0) [0|31] ""  MBMU,PC
 SG_ BAT_Ucell_Min_CELL_104S_60 : 25|7@1+ (1,0) [0|127] ""  MBMU,PC
 SG_ BAT_Ucell_Max_104S_60 : 32|16@1+ (1,0) [0|65535] "mV"  MBMU,PC
 SG_ BAT_Ucell_Min_104S_60 : 48|16@1+ (1,0) [0|65535] "mV"  MBMU,PC

BO_ 2334392189 S2A_SUMDATA23__61: 8 SBMU
 SG_ CRC_S2A_S23_61 : 0|8@1+ (1,0) [0|255] ""  MBMU,PC
 SG_ BAT_Ucell_Max_CSC_104S_61 : 8|5@1+ (1,0) [0|31] ""  MBMU,PC
 SG_ BAT_Ucell_Max_CELL_104S_61 : 13|7@1+ (1,0) [0|127] ""  MBMU,PC
 SG_ BAT_Ucell_Min_CSC_104S_61 : 20|5@1+ (1,0) [0|31] ""  MBMU,PC
 SG_ BAT_Ucell_Min_CELL_104S_61 : 25|7@1+ (1,0) [0|127] ""  MBMU,PC
 SG_ BAT_Ucell_Max_104S_61 : 32|16@1+ (1,0) [0|65535] "mV"  MBMU,PC
 SG_ BAT_Ucell_Min_104S_61 : 48|16@1+ (1,0) [0|65535] "mV"  MBMU,PC

BO_ 2334392190 S2A_SUMDATA23__62: 8 SBMU
 SG_ CRC_S2A_S23_62 : 0|8@1+ (1,0) [0|255] ""  MBMU,PC
 SG_ BAT_Ucell_Max_CSC_104S_62 : 8|5@1+ (1,0) [0|31] ""  MBMU,PC
 SG_ BAT_Ucell_Max_CELL_104S_62 : 13|7@1+ (1,0) [0|127] ""  MBMU,PC
 SG_ BAT_Ucell_Min_CSC_104S_62 : 20|5@1+ (1,0) [0|31] ""  MBMU,PC
 SG_ BAT_Ucell_Min_CELL_104S_62 : 25|7@1+ (1,0) [0|127] ""  MBMU,PC
 SG_ BAT_Ucell_Max_104S_62 : 32|16@1+ (1,0) [0|65535] "mV"  MBMU,PC
 SG_ BAT_Ucell_Min_104S_62 : 48|16@1+ (1,0) [0|65535] "mV"  MBMU,PC

BO_ 2334392191 S2A_SUMDATA23__63: 8 SBMU
 SG_ CRC_S2A_S23_63 : 0|8@1+ (1,0) [0|255] ""  MBMU,PC
 SG_ BAT_Ucell_Max_CSC_104S_63 : 8|5@1+ (1,0) [0|31] ""  MBMU,PC
 SG_ BAT_Ucell_Max_CELL_104S_63 : 13|7@1+ (1,0) [0|127] ""  MBMU,PC
 SG_ BAT_Ucell_Min_CSC_104S_63 : 20|5@1+ (1,0) [0|31] ""  MBMU,PC
 SG_ BAT_Ucell_Min_CELL_104S_63 : 25|7@1+ (1,0) [0|127] ""  MBMU,PC
 SG_ BAT_Ucell_Max_104S_63 : 32|16@1+ (1,0) [0|65535] "mV"  MBMU,PC
 SG_ BAT_Ucell_Min_104S_63 : 48|16@1+ (1,0) [0|65535] "mV"  MBMU,PC

BO_ 2417946177 S2P_BL_Meg_104s__01: 8 SBMU
 SG_ S2P_Bal_CSCNum_104s_01 : 0|5@1+ (1,0) [0|31] ""  PC
 SG_ S2P_Bal_CellNum_104s_01 : 5|7@1+ (1,0) [0|127] ""  PC
 SG_ S2P_Bal_Type_104s_01 : 12|2@1+ (1,0) [0|3] ""  PC
 SG_ S2P_Bal_TimeRemain_104s_01 : 14|9@1+ (1,0) [0|511] ""  PC
 SG_ S2P_Bal_DeltaVolt_104s_01 : 23|10@1+ (1,0) [0|1023] ""  PC
 SG_ S2P_Bal_TypeLevel_104s_01 : 44|3@1+ (1,0) [0|7] ""  PC
 SG_ S2P_Bal_Strategy_104s_01 : 49|1@1+ (1,0) [0|1] ""  PC
 SG_ S2P_Bal_ForceBalMode_104s_01 : 50|2@1+ (1,0) [0|3] ""  PC
 SG_ S2P_Bal_CellTempFault_104s_01 : 52|1@1+ (1,0) [0|1] ""  PC
 SG_ S2P_Bal_CellVoltFail_104s_01 : 53|1@1+ (1,0) [0|1] ""  PC
 SG_ S2P_Bal_CloseBalIstr_104s_01 : 54|1@1+ (1,0) [0|1] ""  PC
 SG_ S2P_Bal_CCanTimeOut_104s_01 : 55|1@1+ (1,0) [0|1] ""  PC
 SG_ S2P_Bal_CellOffLine_104s_01 : 56|1@1+ (1,0) [0|1] ""  PC
 SG_ S2P_Bal_BalanCirFlt_104s_01 : 57|1@1+ (1,0) [0|1] ""  PC
 SG_ S2P_Bal_CellVoOverFlt104s_01 : 59|1@1+ (1,0) [0|1] ""  PC
 SG_ S2P_Bal_CellVoLowFlt104s_01 : 60|1@1+ (1,0) [0|1] ""  PC
 SG_ S2P_Bal_CSCPCBTeFlt104s_01 : 61|1@1+ (1,0) [0|1] ""  PC

BO_ 2417946178 S2P_BL_Meg_104s__02: 8 SBMU
 SG_ S2P_Bal_CSCNum_104s_02 : 0|5@1+ (1,0) [0|31] ""  PC
 SG_ S2P_Bal_CellNum_104s_02 : 5|7@1+ (1,0) [0|127] ""  PC
 SG_ S2P_Bal_Type_104s_02 : 12|2@1+ (1,0) [0|3] ""  PC
 SG_ S2P_Bal_TimeRemain_104s_02 : 14|9@1+ (1,0) [0|511] ""  PC
 SG_ S2P_Bal_DeltaVolt_104s_02 : 23|10@1+ (1,0) [0|1023] ""  PC
 SG_ S2P_Bal_TypeLevel_104s_02 : 44|3@1+ (1,0) [0|7] ""  PC
 SG_ S2P_Bal_Strategy_104s_02 : 49|1@1+ (1,0) [0|1] ""  PC
 SG_ S2P_Bal_ForceBalMode_104s_02 : 50|2@1+ (1,0) [0|3] ""  PC
 SG_ S2P_Bal_CellTempFault_104s_02 : 52|1@1+ (1,0) [0|1] ""  PC
 SG_ S2P_Bal_CellVoltFail_104s_02 : 53|1@1+ (1,0) [0|1] ""  PC
 SG_ S2P_Bal_CloseBalIstr_104s_02 : 54|1@1+ (1,0) [0|1] ""  PC
 SG_ S2P_Bal_CCanTimeOut_104s_02 : 55|1@1+ (1,0) [0|1] ""  PC
 SG_ S2P_Bal_CellOffLine_104s_02 : 56|1@1+ (1,0) [0|1] ""  PC
 SG_ S2P_Bal_BalanCirFlt_104s_02 : 57|1@1+ (1,0) [0|1] ""  PC
 SG_ S2P_Bal_CellVoOverFlt104s_02 : 59|1@1+ (1,0) [0|1] ""  PC
 SG_ S2P_Bal_CellVoLowFlt104s_02 : 60|1@1+ (1,0) [0|1] ""  PC
 SG_ S2P_Bal_CSCPCBTeFlt104s_02 : 61|1@1+ (1,0) [0|1] ""  PC

BO_ 2417946179 S2P_BL_Meg_104s__03: 8 SBMU
 SG_ S2P_Bal_CSCNum_104s_03 : 0|5@1+ (1,0) [0|31] ""  PC
 SG_ S2P_Bal_CellNum_104s_03 : 5|7@1+ (1,0) [0|127] ""  PC
 SG_ S2P_Bal_Type_104s_03 : 12|2@1+ (1,0) [0|3] ""  PC
 SG_ S2P_Bal_TimeRemain_104s_03 : 14|9@1+ (1,0) [0|511] ""  PC
 SG_ S2P_Bal_DeltaVolt_104s_03 : 23|10@1+ (1,0) [0|1023] ""  PC
 SG_ S2P_Bal_TypeLevel_104s_03 : 44|3@1+ (1,0) [0|7] ""  PC
 SG_ S2P_Bal_Strategy_104s_03 : 49|1@1+ (1,0) [0|1] ""  PC
 SG_ S2P_Bal_ForceBalMode_104s_03 : 50|2@1+ (1,0) [0|3] ""  PC
 SG_ S2P_Bal_CellTempFault_104s_03 : 52|1@1+ (1,0) [0|1] ""  PC
 SG_ S2P_Bal_CellVoltFail_104s_03 : 53|1@1+ (1,0) [0|1] ""  PC
 SG_ S2P_Bal_CloseBalIstr_104s_03 : 54|1@1+ (1,0) [0|1] ""  PC
 SG_ S2P_Bal_CCanTimeOut_104s_03 : 55|1@1+ (1,0) [0|1] ""  PC
 SG_ S2P_Bal_CellOffLine_104s_03 : 56|1@1+ (1,0) [0|1] ""  PC
 SG_ S2P_Bal_BalanCirFlt_104s_03 : 57|1@1+ (1,0) [0|1] ""  PC
 SG_ S2P_Bal_CellVoOverFlt104s_03 : 59|1@1+ (1,0) [0|1] ""  PC
 SG_ S2P_Bal_CellVoLowFlt104s_03 : 60|1@1+ (1,0) [0|1] ""  PC
 SG_ S2P_Bal_CSCPCBTeFlt104s_03 : 61|1@1+ (1,0) [0|1] ""  PC

BO_ 2417946180 S2P_BL_Meg_104s__04: 8 SBMU
 SG_ S2P_Bal_CSCNum_104s_04 : 0|5@1+ (1,0) [0|31] ""  PC
 SG_ S2P_Bal_CellNum_104s_04 : 5|7@1+ (1,0) [0|127] ""  PC
 SG_ S2P_Bal_Type_104s_04 : 12|2@1+ (1,0) [0|3] ""  PC
 SG_ S2P_Bal_TimeRemain_104s_04 : 14|9@1+ (1,0) [0|511] ""  PC
 SG_ S2P_Bal_DeltaVolt_104s_04 : 23|10@1+ (1,0) [0|1023] ""  PC
 SG_ S2P_Bal_TypeLevel_104s_04 : 44|3@1+ (1,0) [0|7] ""  PC
 SG_ S2P_Bal_Strategy_104s_04 : 49|1@1+ (1,0) [0|1] ""  PC
 SG_ S2P_Bal_ForceBalMode_104s_04 : 50|2@1+ (1,0) [0|3] ""  PC
 SG_ S2P_Bal_CellTempFault_104s_04 : 52|1@1+ (1,0) [0|1] ""  PC
 SG_ S2P_Bal_CellVoltFail_104s_04 : 53|1@1+ (1,0) [0|1] ""  PC
 SG_ S2P_Bal_CloseBalIstr_104s_04 : 54|1@1+ (1,0) [0|1] ""  PC
 SG_ S2P_Bal_CCanTimeOut_104s_04 : 55|1@1+ (1,0) [0|1] ""  PC
 SG_ S2P_Bal_CellOffLine_104s_04 : 56|1@1+ (1,0) [0|1] ""  PC
 SG_ S2P_Bal_BalanCirFlt_104s_04 : 57|1@1+ (1,0) [0|1] ""  PC
 SG_ S2P_Bal_CellVoOverFlt104s_04 : 59|1@1+ (1,0) [0|1] ""  PC
 SG_ S2P_Bal_CellVoLowFlt104s_04 : 60|1@1+ (1,0) [0|1] ""  PC
 SG_ S2P_Bal_CSCPCBTeFlt104s_04 : 61|1@1+ (1,0) [0|1] ""  PC

BO_ 2417946181 S2P_BL_Meg_104s__05: 8 SBMU
 SG_ S2P_Bal_CSCNum_104s_05 : 0|5@1+ (1,0) [0|31] ""  PC
 SG_ S2P_Bal_CellNum_104s_05 : 5|7@1+ (1,0) [0|127] ""  PC
 SG_ S2P_Bal_Type_104s_05 : 12|2@1+ (1,0) [0|3] ""  PC
 SG_ S2P_Bal_TimeRemain_104s_05 : 14|9@1+ (1,0) [0|511] ""  PC
 SG_ S2P_Bal_DeltaVolt_104s_05 : 23|10@1+ (1,0) [0|1023] ""  PC
 SG_ S2P_Bal_TypeLevel_104s_05 : 44|3@1+ (1,0) [0|7] ""  PC
 SG_ S2P_Bal_Strategy_104s_05 : 49|1@1+ (1,0) [0|1] ""  PC
 SG_ S2P_Bal_ForceBalMode_104s_05 : 50|2@1+ (1,0) [0|3] ""  PC
 SG_ S2P_Bal_CellTempFault_104s_05 : 52|1@1+ (1,0) [0|1] ""  PC
 SG_ S2P_Bal_CellVoltFail_104s_05 : 53|1@1+ (1,0) [0|1] ""  PC
 SG_ S2P_Bal_CloseBalIstr_104s_05 : 54|1@1+ (1,0) [0|1] ""  PC
 SG_ S2P_Bal_CCanTimeOut_104s_05 : 55|1@1+ (1,0) [0|1] ""  PC
 SG_ S2P_Bal_CellOffLine_104s_05 : 56|1@1+ (1,0) [0|1] ""  PC
 SG_ S2P_Bal_BalanCirFlt_104s_05 : 57|1@1+ (1,0) [0|1] ""  PC
 SG_ S2P_Bal_CellVoOverFlt104s_05 : 59|1@1+ (1,0) [0|1] ""  PC
 SG_ S2P_Bal_CellVoLowFlt104s_05 : 60|1@1+ (1,0) [0|1] ""  PC
 SG_ S2P_Bal_CSCPCBTeFlt104s_05 : 61|1@1+ (1,0) [0|1] ""  PC

BO_ 2417946182 S2P_BL_Meg_104s__06: 8 SBMU
 SG_ S2P_Bal_CSCNum_104s_06 : 0|5@1+ (1,0) [0|31] ""  PC
 SG_ S2P_Bal_CellNum_104s_06 : 5|7@1+ (1,0) [0|127] ""  PC
 SG_ S2P_Bal_Type_104s_06 : 12|2@1+ (1,0) [0|3] ""  PC
 SG_ S2P_Bal_TimeRemain_104s_06 : 14|9@1+ (1,0) [0|511] ""  PC
 SG_ S2P_Bal_DeltaVolt_104s_06 : 23|10@1+ (1,0) [0|1023] ""  PC
 SG_ S2P_Bal_TypeLevel_104s_06 : 44|3@1+ (1,0) [0|7] ""  PC
 SG_ S2P_Bal_Strategy_104s_06 : 49|1@1+ (1,0) [0|1] ""  PC
 SG_ S2P_Bal_ForceBalMode_104s_06 : 50|2@1+ (1,0) [0|3] ""  PC
 SG_ S2P_Bal_CellTempFault_104s_06 : 52|1@1+ (1,0) [0|1] ""  PC
 SG_ S2P_Bal_CellVoltFail_104s_06 : 53|1@1+ (1,0) [0|1] ""  PC
 SG_ S2P_Bal_CloseBalIstr_104s_06 : 54|1@1+ (1,0) [0|1] ""  PC
 SG_ S2P_Bal_CCanTimeOut_104s_06 : 55|1@1+ (1,0) [0|1] ""  PC
 SG_ S2P_Bal_CellOffLine_104s_06 : 56|1@1+ (1,0) [0|1] ""  PC
 SG_ S2P_Bal_BalanCirFlt_104s_06 : 57|1@1+ (1,0) [0|1] ""  PC
 SG_ S2P_Bal_CellVoOverFlt104s_06 : 59|1@1+ (1,0) [0|1] ""  PC
 SG_ S2P_Bal_CellVoLowFlt104s_06 : 60|1@1+ (1,0) [0|1] ""  PC
 SG_ S2P_Bal_CSCPCBTeFlt104s_06 : 61|1@1+ (1,0) [0|1] ""  PC

BO_ 2417946183 S2P_BL_Meg_104s__07: 8 SBMU
 SG_ S2P_Bal_CSCNum_104s_07 : 0|5@1+ (1,0) [0|31] ""  PC
 SG_ S2P_Bal_CellNum_104s_07 : 5|7@1+ (1,0) [0|127] ""  PC
 SG_ S2P_Bal_Type_104s_07 : 12|2@1+ (1,0) [0|3] ""  PC
 SG_ S2P_Bal_TimeRemain_104s_07 : 14|9@1+ (1,0) [0|511] ""  PC
 SG_ S2P_Bal_DeltaVolt_104s_07 : 23|10@1+ (1,0) [0|1023] ""  PC
 SG_ S2P_Bal_TypeLevel_104s_07 : 44|3@1+ (1,0) [0|7] ""  PC
 SG_ S2P_Bal_Strategy_104s_07 : 49|1@1+ (1,0) [0|1] ""  PC
 SG_ S2P_Bal_ForceBalMode_104s_07 : 50|2@1+ (1,0) [0|3] ""  PC
 SG_ S2P_Bal_CellTempFault_104s_07 : 52|1@1+ (1,0) [0|1] ""  PC
 SG_ S2P_Bal_CellVoltFail_104s_07 : 53|1@1+ (1,0) [0|1] ""  PC
 SG_ S2P_Bal_CloseBalIstr_104s_07 : 54|1@1+ (1,0) [0|1] ""  PC
 SG_ S2P_Bal_CCanTimeOut_104s_07 : 55|1@1+ (1,0) [0|1] ""  PC
 SG_ S2P_Bal_CellOffLine_104s_07 : 56|1@1+ (1,0) [0|1] ""  PC
 SG_ S2P_Bal_BalanCirFlt_104s_07 : 57|1@1+ (1,0) [0|1] ""  PC
 SG_ S2P_Bal_CellVoOverFlt104s_07 : 59|1@1+ (1,0) [0|1] ""  PC
 SG_ S2P_Bal_CellVoLowFlt104s_07 : 60|1@1+ (1,0) [0|1] ""  PC
 SG_ S2P_Bal_CSCPCBTeFlt104s_07 : 61|1@1+ (1,0) [0|1] ""  PC

BO_ 2417946184 S2P_BL_Meg_104s__08: 8 SBMU
 SG_ S2P_Bal_CSCNum_104s_08 : 0|5@1+ (1,0) [0|31] ""  PC
 SG_ S2P_Bal_CellNum_104s_08 : 5|7@1+ (1,0) [0|127] ""  PC
 SG_ S2P_Bal_Type_104s_08 : 12|2@1+ (1,0) [0|3] ""  PC
 SG_ S2P_Bal_TimeRemain_104s_08 : 14|9@1+ (1,0) [0|511] ""  PC
 SG_ S2P_Bal_DeltaVolt_104s_08 : 23|10@1+ (1,0) [0|1023] ""  PC
 SG_ S2P_Bal_TypeLevel_104s_08 : 44|3@1+ (1,0) [0|7] ""  PC
 SG_ S2P_Bal_Strategy_104s_08 : 49|1@1+ (1,0) [0|1] ""  PC
 SG_ S2P_Bal_ForceBalMode_104s_08 : 50|2@1+ (1,0) [0|3] ""  PC
 SG_ S2P_Bal_CellTempFault_104s_08 : 52|1@1+ (1,0) [0|1] ""  PC
 SG_ S2P_Bal_CellVoltFail_104s_08 : 53|1@1+ (1,0) [0|1] ""  PC
 SG_ S2P_Bal_CloseBalIstr_104s_08 : 54|1@1+ (1,0) [0|1] ""  PC
 SG_ S2P_Bal_CCanTimeOut_104s_08 : 55|1@1+ (1,0) [0|1] ""  PC
 SG_ S2P_Bal_CellOffLine_104s_08 : 56|1@1+ (1,0) [0|1] ""  PC
 SG_ S2P_Bal_BalanCirFlt_104s_08 : 57|1@1+ (1,0) [0|1] ""  PC
 SG_ S2P_Bal_CellVoOverFlt104s_08 : 59|1@1+ (1,0) [0|1] ""  PC
 SG_ S2P_Bal_CellVoLowFlt104s_08 : 60|1@1+ (1,0) [0|1] ""  PC
 SG_ S2P_Bal_CSCPCBTeFlt104s_08 : 61|1@1+ (1,0) [0|1] ""  PC

BO_ 2417946185 S2P_BL_Meg_104s__09: 8 SBMU
 SG_ S2P_Bal_CSCNum_104s_09 : 0|5@1+ (1,0) [0|31] ""  PC
 SG_ S2P_Bal_CellNum_104s_09 : 5|7@1+ (1,0) [0|127] ""  PC
 SG_ S2P_Bal_Type_104s_09 : 12|2@1+ (1,0) [0|3] ""  PC
 SG_ S2P_Bal_TimeRemain_104s_09 : 14|9@1+ (1,0) [0|511] ""  PC
 SG_ S2P_Bal_DeltaVolt_104s_09 : 23|10@1+ (1,0) [0|1023] ""  PC
 SG_ S2P_Bal_TypeLevel_104s_09 : 44|3@1+ (1,0) [0|7] ""  PC
 SG_ S2P_Bal_Strategy_104s_09 : 49|1@1+ (1,0) [0|1] ""  PC
 SG_ S2P_Bal_ForceBalMode_104s_09 : 50|2@1+ (1,0) [0|3] ""  PC
 SG_ S2P_Bal_CellTempFault_104s_09 : 52|1@1+ (1,0) [0|1] ""  PC
 SG_ S2P_Bal_CellVoltFail_104s_09 : 53|1@1+ (1,0) [0|1] ""  PC
 SG_ S2P_Bal_CloseBalIstr_104s_09 : 54|1@1+ (1,0) [0|1] ""  PC
 SG_ S2P_Bal_CCanTimeOut_104s_09 : 55|1@1+ (1,0) [0|1] ""  PC
 SG_ S2P_Bal_CellOffLine_104s_09 : 56|1@1+ (1,0) [0|1] ""  PC
 SG_ S2P_Bal_BalanCirFlt_104s_09 : 57|1@1+ (1,0) [0|1] ""  PC
 SG_ S2P_Bal_CellVoOverFlt104s_09 : 59|1@1+ (1,0) [0|1] ""  PC
 SG_ S2P_Bal_CellVoLowFlt104s_09 : 60|1@1+ (1,0) [0|1] ""  PC
 SG_ S2P_Bal_CSCPCBTeFlt104s_09 : 61|1@1+ (1,0) [0|1] ""  PC

BO_ 2417946186 S2P_BL_Meg_104s__10: 8 SBMU
 SG_ S2P_Bal_CSCNum_104s_10 : 0|5@1+ (1,0) [0|31] ""  PC
 SG_ S2P_Bal_CellNum_104s_10 : 5|7@1+ (1,0) [0|127] ""  PC
 SG_ S2P_Bal_Type_104s_10 : 12|2@1+ (1,0) [0|3] ""  PC
 SG_ S2P_Bal_TimeRemain_104s_10 : 14|9@1+ (1,0) [0|511] ""  PC
 SG_ S2P_Bal_DeltaVolt_104s_10 : 23|10@1+ (1,0) [0|1023] ""  PC
 SG_ S2P_Bal_TypeLevel_104s_10 : 44|3@1+ (1,0) [0|7] ""  PC
 SG_ S2P_Bal_Strategy_104s_10 : 49|1@1+ (1,0) [0|1] ""  PC
 SG_ S2P_Bal_ForceBalMode_104s_10 : 50|2@1+ (1,0) [0|3] ""  PC
 SG_ S2P_Bal_CellTempFault_104s_10 : 52|1@1+ (1,0) [0|1] ""  PC
 SG_ S2P_Bal_CellVoltFail_104s_10 : 53|1@1+ (1,0) [0|1] ""  PC
 SG_ S2P_Bal_CloseBalIstr_104s_10 : 54|1@1+ (1,0) [0|1] ""  PC
 SG_ S2P_Bal_CCanTimeOut_104s_10 : 55|1@1+ (1,0) [0|1] ""  PC
 SG_ S2P_Bal_CellOffLine_104s_10 : 56|1@1+ (1,0) [0|1] ""  PC
 SG_ S2P_Bal_BalanCirFlt_104s_10 : 57|1@1+ (1,0) [0|1] ""  PC
 SG_ S2P_Bal_CellVoOverFlt104s_10 : 59|1@1+ (1,0) [0|1] ""  PC
 SG_ S2P_Bal_CellVoLowFlt104s_10 : 60|1@1+ (1,0) [0|1] ""  PC
 SG_ S2P_Bal_CSCPCBTeFlt104s_10 : 61|1@1+ (1,0) [0|1] ""  PC

BO_ 2417946187 S2P_BL_Meg_104s__11: 8 SBMU
 SG_ S2P_Bal_CSCNum_104s_11 : 0|5@1+ (1,0) [0|31] ""  PC
 SG_ S2P_Bal_CellNum_104s_11 : 5|7@1+ (1,0) [0|127] ""  PC
 SG_ S2P_Bal_Type_104s_11 : 12|2@1+ (1,0) [0|3] ""  PC
 SG_ S2P_Bal_TimeRemain_104s_11 : 14|9@1+ (1,0) [0|511] ""  PC
 SG_ S2P_Bal_DeltaVolt_104s_11 : 23|10@1+ (1,0) [0|1023] ""  PC
 SG_ S2P_Bal_TypeLevel_104s_11 : 44|3@1+ (1,0) [0|7] ""  PC
 SG_ S2P_Bal_Strategy_104s_11 : 49|1@1+ (1,0) [0|1] ""  PC
 SG_ S2P_Bal_ForceBalMode_104s_11 : 50|2@1+ (1,0) [0|3] ""  PC
 SG_ S2P_Bal_CellTempFault_104s_11 : 52|1@1+ (1,0) [0|1] ""  PC
 SG_ S2P_Bal_CellVoltFail_104s_11 : 53|1@1+ (1,0) [0|1] ""  PC
 SG_ S2P_Bal_CloseBalIstr_104s_11 : 54|1@1+ (1,0) [0|1] ""  PC
 SG_ S2P_Bal_CCanTimeOut_104s_11 : 55|1@1+ (1,0) [0|1] ""  PC
 SG_ S2P_Bal_CellOffLine_104s_11 : 56|1@1+ (1,0) [0|1] ""  PC
 SG_ S2P_Bal_BalanCirFlt_104s_11 : 57|1@1+ (1,0) [0|1] ""  PC
 SG_ S2P_Bal_CellVoOverFlt104s_11 : 59|1@1+ (1,0) [0|1] ""  PC
 SG_ S2P_Bal_CellVoLowFlt104s_11 : 60|1@1+ (1,0) [0|1] ""  PC
 SG_ S2P_Bal_CSCPCBTeFlt104s_11 : 61|1@1+ (1,0) [0|1] ""  PC

BO_ 2417946188 S2P_BL_Meg_104s__12: 8 SBMU
 SG_ S2P_Bal_CSCNum_104s_12 : 0|5@1+ (1,0) [0|31] ""  PC
 SG_ S2P_Bal_CellNum_104s_12 : 5|7@1+ (1,0) [0|127] ""  PC
 SG_ S2P_Bal_Type_104s_12 : 12|2@1+ (1,0) [0|3] ""  PC
 SG_ S2P_Bal_TimeRemain_104s_12 : 14|9@1+ (1,0) [0|511] ""  PC
 SG_ S2P_Bal_DeltaVolt_104s_12 : 23|10@1+ (1,0) [0|1023] ""  PC
 SG_ S2P_Bal_TypeLevel_104s_12 : 44|3@1+ (1,0) [0|7] ""  PC
 SG_ S2P_Bal_Strategy_104s_12 : 49|1@1+ (1,0) [0|1] ""  PC
 SG_ S2P_Bal_ForceBalMode_104s_12 : 50|2@1+ (1,0) [0|3] ""  PC
 SG_ S2P_Bal_CellTempFault_104s_12 : 52|1@1+ (1,0) [0|1] ""  PC
 SG_ S2P_Bal_CellVoltFail_104s_12 : 53|1@1+ (1,0) [0|1] ""  PC
 SG_ S2P_Bal_CloseBalIstr_104s_12 : 54|1@1+ (1,0) [0|1] ""  PC
 SG_ S2P_Bal_CCanTimeOut_104s_12 : 55|1@1+ (1,0) [0|1] ""  PC
 SG_ S2P_Bal_CellOffLine_104s_12 : 56|1@1+ (1,0) [0|1] ""  PC
 SG_ S2P_Bal_BalanCirFlt_104s_12 : 57|1@1+ (1,0) [0|1] ""  PC
 SG_ S2P_Bal_CellVoOverFlt104s_12 : 59|1@1+ (1,0) [0|1] ""  PC
 SG_ S2P_Bal_CellVoLowFlt104s_12 : 60|1@1+ (1,0) [0|1] ""  PC
 SG_ S2P_Bal_CSCPCBTeFlt104s_12 : 61|1@1+ (1,0) [0|1] ""  PC

CM_ SG_ 2418404944 S2P_Lmt20_Over_DeltUcell4_16 "电池单体电压极差截止值";
CM_ SG_ 2418404944 S2P_Lmt20_Over_DeltTcell4_16 "电池单体温度极差截止值";
CM_ SG_ 2418404944 S2P_Lmt20_Over_Ucell4_16 "电池单体充电截止电压";
CM_ SG_ 2418404944 S2P_Lmt20_Under_Ucell4_16 "电池单体放电截止电压";
CM_ SG_ 2418404944 S2P_Lmt20_Over_Tcell4_16 "电池单体高温截止温度";
CM_ SG_ 2418404945 S2P_Lmt20_Over_DeltUcell4_17 "电池单体电压极差截止值";
CM_ SG_ 2418404945 S2P_Lmt20_Over_DeltTcell4_17 "电池单体温度极差截止值";
CM_ SG_ 2418404945 S2P_Lmt20_Over_Ucell4_17 "电池单体充电截止电压";
CM_ SG_ 2418404945 S2P_Lmt20_Under_Ucell4_17 "电池单体放电截止电压";
CM_ SG_ 2418404945 S2P_Lmt20_Over_Tcell4_17 "电池单体高温截止温度";
CM_ SG_ 2418404946 S2P_Lmt20_Over_DeltUcell4_18 "电池单体电压极差截止值";
CM_ SG_ 2418404946 S2P_Lmt20_Over_DeltTcell4_18 "电池单体温度极差截止值";
CM_ SG_ 2418404946 S2P_Lmt20_Over_Ucell4_18 "电池单体充电截止电压";
CM_ SG_ 2418404946 S2P_Lmt20_Under_Ucell4_18 "电池单体放电截止电压";
CM_ SG_ 2418404946 S2P_Lmt20_Over_Tcell4_18 "电池单体高温截止温度";
CM_ SG_ 2418404947 S2P_Lmt20_Over_DeltUcell4_19 "电池单体电压极差截止值";
CM_ SG_ 2418404947 S2P_Lmt20_Over_DeltTcell4_19 "电池单体温度极差截止值";
CM_ SG_ 2418404947 S2P_Lmt20_Over_Ucell4_19 "电池单体充电截止电压";
CM_ SG_ 2418404947 S2P_Lmt20_Under_Ucell4_19 "电池单体放电截止电压";
CM_ SG_ 2418404947 S2P_Lmt20_Over_Tcell4_19 "电池单体高温截止温度";
CM_ SG_ 2418404948 S2P_Lmt20_Over_DeltUcell4_20 "电池单体电压极差截止值";
CM_ SG_ 2418404948 S2P_Lmt20_Over_DeltTcell4_20 "电池单体温度极差截止值";
CM_ SG_ 2418404948 S2P_Lmt20_Over_Ucell4_20 "电池单体充电截止电压";
CM_ SG_ 2418404948 S2P_Lmt20_Under_Ucell4_20 "电池单体放电截止电压";
CM_ SG_ 2418404948 S2P_Lmt20_Over_Tcell4_20 "电池单体高温截止温度";
CM_ SG_ 2418404949 S2P_Lmt20_Over_DeltUcell4_21 "电池单体电压极差截止值";
CM_ SG_ 2418404949 S2P_Lmt20_Over_DeltTcell4_21 "电池单体温度极差截止值";
CM_ SG_ 2418404949 S2P_Lmt20_Over_Ucell4_21 "电池单体充电截止电压";
CM_ SG_ 2418404949 S2P_Lmt20_Under_Ucell4_21 "电池单体放电截止电压";
CM_ SG_ 2418404949 S2P_Lmt20_Over_Tcell4_21 "电池单体高温截止温度";
CM_ SG_ 2418404950 S2P_Lmt20_Over_DeltUcell4_22 "电池单体电压极差截止值";
CM_ SG_ 2418404950 S2P_Lmt20_Over_DeltTcell4_22 "电池单体温度极差截止值";
CM_ SG_ 2418404950 S2P_Lmt20_Over_Ucell4_22 "电池单体充电截止电压";
CM_ SG_ 2418404950 S2P_Lmt20_Under_Ucell4_22 "电池单体放电截止电压";
CM_ SG_ 2418404950 S2P_Lmt20_Over_Tcell4_22 "电池单体高温截止温度";
CM_ SG_ 2418404951 S2P_Lmt20_Over_DeltUcell4_23 "电池单体电压极差截止值";
CM_ SG_ 2418404951 S2P_Lmt20_Over_DeltTcell4_23 "电池单体温度极差截止值";
CM_ SG_ 2418404951 S2P_Lmt20_Over_Ucell4_23 "电池单体充电截止电压";
CM_ SG_ 2418404951 S2P_Lmt20_Under_Ucell4_23 "电池单体放电截止电压";
CM_ SG_ 2418404951 S2P_Lmt20_Over_Tcell4_23 "电池单体高温截止温度";
CM_ SG_ 2418404952 S2P_Lmt20_Over_DeltUcell4_24 "电池单体电压极差截止值";
CM_ SG_ 2418404952 S2P_Lmt20_Over_DeltTcell4_24 "电池单体温度极差截止值";
CM_ SG_ 2418404952 S2P_Lmt20_Over_Ucell4_24 "电池单体充电截止电压";
CM_ SG_ 2418404952 S2P_Lmt20_Under_Ucell4_24 "电池单体放电截止电压";
CM_ SG_ 2418404952 S2P_Lmt20_Over_Tcell4_24 "电池单体高温截止温度";
CM_ SG_ 2418404953 S2P_Lmt20_Over_DeltUcell4_25 "电池单体电压极差截止值";
CM_ SG_ 2418404953 S2P_Lmt20_Over_DeltTcell4_25 "电池单体温度极差截止值";
CM_ SG_ 2418404953 S2P_Lmt20_Over_Ucell4_25 "电池单体充电截止电压";
CM_ SG_ 2418404953 S2P_Lmt20_Under_Ucell4_25 "电池单体放电截止电压";
CM_ SG_ 2418404953 S2P_Lmt20_Over_Tcell4_25 "电池单体高温截止温度";
CM_ SG_ 2418404954 S2P_Lmt20_Over_DeltUcell4_26 "电池单体电压极差截止值";
CM_ SG_ 2418404954 S2P_Lmt20_Over_DeltTcell4_26 "电池单体温度极差截止值";
CM_ SG_ 2418404954 S2P_Lmt20_Over_Ucell4_26 "电池单体充电截止电压";
CM_ SG_ 2418404954 S2P_Lmt20_Under_Ucell4_26 "电池单体放电截止电压";
CM_ SG_ 2418404954 S2P_Lmt20_Over_Tcell4_26 "电池单体高温截止温度";
CM_ SG_ 2418404955 S2P_Lmt20_Over_DeltUcell4_27 "电池单体电压极差截止值";
CM_ SG_ 2418404955 S2P_Lmt20_Over_DeltTcell4_27 "电池单体温度极差截止值";
CM_ SG_ 2418404955 S2P_Lmt20_Over_Ucell4_27 "电池单体充电截止电压";
CM_ SG_ 2418404955 S2P_Lmt20_Under_Ucell4_27 "电池单体放电截止电压";
CM_ SG_ 2418404955 S2P_Lmt20_Over_Tcell4_27 "电池单体高温截止温度";
CM_ SG_ 2418404956 S2P_Lmt20_Over_DeltUcell4_28 "电池单体电压极差截止值";
CM_ SG_ 2418404956 S2P_Lmt20_Over_DeltTcell4_28 "电池单体温度极差截止值";
CM_ SG_ 2418404956 S2P_Lmt20_Over_Ucell4_28 "电池单体充电截止电压";
CM_ SG_ 2418404956 S2P_Lmt20_Under_Ucell4_28 "电池单体放电截止电压";
CM_ SG_ 2418404956 S2P_Lmt20_Over_Tcell4_28 "电池单体高温截止温度";
CM_ SG_ 2418404957 S2P_Lmt20_Over_DeltUcell4_29 "电池单体电压极差截止值";
CM_ SG_ 2418404957 S2P_Lmt20_Over_DeltTcell4_29 "电池单体温度极差截止值";
CM_ SG_ 2418404957 S2P_Lmt20_Over_Ucell4_29 "电池单体充电截止电压";
CM_ SG_ 2418404957 S2P_Lmt20_Under_Ucell4_29 "电池单体放电截止电压";
CM_ SG_ 2418404957 S2P_Lmt20_Over_Tcell4_29 "电池单体高温截止温度";
CM_ SG_ 2418404958 S2P_Lmt20_Over_DeltUcell4_30 "电池单体电压极差截止值";
CM_ SG_ 2418404958 S2P_Lmt20_Over_DeltTcell4_30 "电池单体温度极差截止值";
CM_ SG_ 2418404958 S2P_Lmt20_Over_Ucell4_30 "电池单体充电截止电压";
CM_ SG_ 2418404958 S2P_Lmt20_Under_Ucell4_30 "电池单体放电截止电压";
CM_ SG_ 2418404958 S2P_Lmt20_Over_Tcell4_30 "电池单体高温截止温度";
CM_ SG_ 2418404959 S2P_Lmt20_Over_DeltUcell4_31 "电池单体电压极差截止值";
CM_ SG_ 2418404959 S2P_Lmt20_Over_DeltTcell4_31 "电池单体温度极差截止值";
CM_ SG_ 2418404959 S2P_Lmt20_Over_Ucell4_31 "电池单体充电截止电压";
CM_ SG_ 2418404959 S2P_Lmt20_Under_Ucell4_31 "电池单体放电截止电压";
CM_ SG_ 2418404959 S2P_Lmt20_Over_Tcell4_31 "电池单体高温截止温度";
CM_ SG_ 2418404960 S2P_Lmt20_Over_DeltUcell4_32 "电池单体电压极差截止值";
CM_ SG_ 2418404960 S2P_Lmt20_Over_DeltTcell4_32 "电池单体温度极差截止值";
CM_ SG_ 2418404960 S2P_Lmt20_Over_Ucell4_32 "电池单体充电截止电压";
CM_ SG_ 2418404960 S2P_Lmt20_Under_Ucell4_32 "电池单体放电截止电压";
CM_ SG_ 2418404960 S2P_Lmt20_Over_Tcell4_32 "电池单体高温截止温度";
CM_ SG_ 2418404961 S2P_Lmt20_Over_DeltUcell4_33 "电池单体电压极差截止值";
CM_ SG_ 2418404961 S2P_Lmt20_Over_DeltTcell4_33 "电池单体温度极差截止值";
CM_ SG_ 2418404961 S2P_Lmt20_Over_Ucell4_33 "电池单体充电截止电压";
CM_ SG_ 2418404961 S2P_Lmt20_Under_Ucell4_33 "电池单体放电截止电压";
CM_ SG_ 2418404961 S2P_Lmt20_Over_Tcell4_33 "电池单体高温截止温度";
CM_ SG_ 2418404962 S2P_Lmt20_Over_DeltUcell4_34 "电池单体电压极差截止值";
CM_ SG_ 2418404962 S2P_Lmt20_Over_DeltTcell4_34 "电池单体温度极差截止值";
CM_ SG_ 2418404962 S2P_Lmt20_Over_Ucell4_34 "电池单体充电截止电压";
CM_ SG_ 2418404962 S2P_Lmt20_Under_Ucell4_34 "电池单体放电截止电压";
CM_ SG_ 2418404962 S2P_Lmt20_Over_Tcell4_34 "电池单体高温截止温度";
CM_ SG_ 2418404963 S2P_Lmt20_Over_DeltUcell4_35 "电池单体电压极差截止值";
CM_ SG_ 2418404963 S2P_Lmt20_Over_DeltTcell4_35 "电池单体温度极差截止值";
CM_ SG_ 2418404963 S2P_Lmt20_Over_Ucell4_35 "电池单体充电截止电压";
CM_ SG_ 2418404963 S2P_Lmt20_Under_Ucell4_35 "电池单体放电截止电压";
CM_ SG_ 2418404963 S2P_Lmt20_Over_Tcell4_35 "电池单体高温截止温度";
CM_ SG_ 2418404964 S2P_Lmt20_Over_DeltUcell4_36 "电池单体电压极差截止值";
CM_ SG_ 2418404964 S2P_Lmt20_Over_DeltTcell4_36 "电池单体温度极差截止值";
CM_ SG_ 2418404964 S2P_Lmt20_Over_Ucell4_36 "电池单体充电截止电压";
CM_ SG_ 2418404964 S2P_Lmt20_Under_Ucell4_36 "电池单体放电截止电压";
CM_ SG_ 2418404964 S2P_Lmt20_Over_Tcell4_36 "电池单体高温截止温度";
CM_ SG_ 2418404965 S2P_Lmt20_Over_DeltUcell4_37 "电池单体电压极差截止值";
CM_ SG_ 2418404965 S2P_Lmt20_Over_DeltTcell4_37 "电池单体温度极差截止值";
CM_ SG_ 2418404965 S2P_Lmt20_Over_Ucell4_37 "电池单体充电截止电压";
CM_ SG_ 2418404965 S2P_Lmt20_Under_Ucell4_37 "电池单体放电截止电压";
CM_ SG_ 2418404965 S2P_Lmt20_Over_Tcell4_37 "电池单体高温截止温度";
CM_ SG_ 2418404966 S2P_Lmt20_Over_DeltUcell4_38 "电池单体电压极差截止值";
CM_ SG_ 2418404966 S2P_Lmt20_Over_DeltTcell4_38 "电池单体温度极差截止值";
CM_ SG_ 2418404966 S2P_Lmt20_Over_Ucell4_38 "电池单体充电截止电压";
CM_ SG_ 2418404966 S2P_Lmt20_Under_Ucell4_38 "电池单体放电截止电压";
CM_ SG_ 2418404966 S2P_Lmt20_Over_Tcell4_38 "电池单体高温截止温度";
CM_ SG_ 2418404967 S2P_Lmt20_Over_DeltUcell4_39 "电池单体电压极差截止值";
CM_ SG_ 2418404967 S2P_Lmt20_Over_DeltTcell4_39 "电池单体温度极差截止值";
CM_ SG_ 2418404967 S2P_Lmt20_Over_Ucell4_39 "电池单体充电截止电压";
CM_ SG_ 2418404967 S2P_Lmt20_Under_Ucell4_39 "电池单体放电截止电压";
CM_ SG_ 2418404967 S2P_Lmt20_Over_Tcell4_39 "电池单体高温截止温度";
CM_ SG_ 2418404968 S2P_Lmt20_Over_DeltUcell4_40 "电池单体电压极差截止值";
CM_ SG_ 2418404968 S2P_Lmt20_Over_DeltTcell4_40 "电池单体温度极差截止值";
CM_ SG_ 2418404968 S2P_Lmt20_Over_Ucell4_40 "电池单体充电截止电压";
CM_ SG_ 2418404968 S2P_Lmt20_Under_Ucell4_40 "电池单体放电截止电压";
CM_ SG_ 2418404968 S2P_Lmt20_Over_Tcell4_40 "电池单体高温截止温度";
CM_ SG_ 2418404969 S2P_Lmt20_Over_DeltUcell4_41 "电池单体电压极差截止值";
CM_ SG_ 2418404969 S2P_Lmt20_Over_DeltTcell4_41 "电池单体温度极差截止值";
CM_ SG_ 2418404969 S2P_Lmt20_Over_Ucell4_41 "电池单体充电截止电压";
CM_ SG_ 2418404969 S2P_Lmt20_Under_Ucell4_41 "电池单体放电截止电压";
CM_ SG_ 2418404969 S2P_Lmt20_Over_Tcell4_41 "电池单体高温截止温度";
CM_ SG_ 2418404970 S2P_Lmt20_Over_DeltUcell4_42 "电池单体电压极差截止值";
CM_ SG_ 2418404970 S2P_Lmt20_Over_DeltTcell4_42 "电池单体温度极差截止值";
CM_ SG_ 2418404970 S2P_Lmt20_Over_Ucell4_42 "电池单体充电截止电压";
CM_ SG_ 2418404970 S2P_Lmt20_Under_Ucell4_42 "电池单体放电截止电压";
CM_ SG_ 2418404970 S2P_Lmt20_Over_Tcell4_42 "电池单体高温截止温度";
CM_ SG_ 2418404971 S2P_Lmt20_Over_DeltUcell4_43 "电池单体电压极差截止值";
CM_ SG_ 2418404971 S2P_Lmt20_Over_DeltTcell4_43 "电池单体温度极差截止值";
CM_ SG_ 2418404971 S2P_Lmt20_Over_Ucell4_43 "电池单体充电截止电压";
CM_ SG_ 2418404971 S2P_Lmt20_Under_Ucell4_43 "电池单体放电截止电压";
CM_ SG_ 2418404971 S2P_Lmt20_Over_Tcell4_43 "电池单体高温截止温度";
CM_ SG_ 2418404972 S2P_Lmt20_Over_DeltUcell4_44 "电池单体电压极差截止值";
CM_ SG_ 2418404972 S2P_Lmt20_Over_DeltTcell4_44 "电池单体温度极差截止值";
CM_ SG_ 2418404972 S2P_Lmt20_Over_Ucell4_44 "电池单体充电截止电压";
CM_ SG_ 2418404972 S2P_Lmt20_Under_Ucell4_44 "电池单体放电截止电压";
CM_ SG_ 2418404972 S2P_Lmt20_Over_Tcell4_44 "电池单体高温截止温度";
CM_ SG_ 2418404973 S2P_Lmt20_Over_DeltUcell4_45 "电池单体电压极差截止值";
CM_ SG_ 2418404973 S2P_Lmt20_Over_DeltTcell4_45 "电池单体温度极差截止值";
CM_ SG_ 2418404973 S2P_Lmt20_Over_Ucell4_45 "电池单体充电截止电压";
CM_ SG_ 2418404973 S2P_Lmt20_Under_Ucell4_45 "电池单体放电截止电压";
CM_ SG_ 2418404973 S2P_Lmt20_Over_Tcell4_45 "电池单体高温截止温度";
CM_ SG_ 2418404974 S2P_Lmt20_Over_DeltUcell4_46 "电池单体电压极差截止值";
CM_ SG_ 2418404974 S2P_Lmt20_Over_DeltTcell4_46 "电池单体温度极差截止值";
CM_ SG_ 2418404974 S2P_Lmt20_Over_Ucell4_46 "电池单体充电截止电压";
CM_ SG_ 2418404974 S2P_Lmt20_Under_Ucell4_46 "电池单体放电截止电压";
CM_ SG_ 2418404974 S2P_Lmt20_Over_Tcell4_46 "电池单体高温截止温度";
CM_ SG_ 2418404975 S2P_Lmt20_Over_DeltUcell4_47 "电池单体电压极差截止值";
CM_ SG_ 2418404975 S2P_Lmt20_Over_DeltTcell4_47 "电池单体温度极差截止值";
CM_ SG_ 2418404975 S2P_Lmt20_Over_Ucell4_47 "电池单体充电截止电压";
CM_ SG_ 2418404975 S2P_Lmt20_Under_Ucell4_47 "电池单体放电截止电压";
CM_ SG_ 2418404975 S2P_Lmt20_Over_Tcell4_47 "电池单体高温截止温度";
CM_ SG_ 2418404976 S2P_Lmt20_Over_DeltUcell4_48 "电池单体电压极差截止值";
CM_ SG_ 2418404976 S2P_Lmt20_Over_DeltTcell4_48 "电池单体温度极差截止值";
CM_ SG_ 2418404976 S2P_Lmt20_Over_Ucell4_48 "电池单体充电截止电压";
CM_ SG_ 2418404976 S2P_Lmt20_Under_Ucell4_48 "电池单体放电截止电压";
CM_ SG_ 2418404976 S2P_Lmt20_Over_Tcell4_48 "电池单体高温截止温度";
CM_ SG_ 2418404977 S2P_Lmt20_Over_DeltUcell4_49 "电池单体电压极差截止值";
CM_ SG_ 2418404977 S2P_Lmt20_Over_DeltTcell4_49 "电池单体温度极差截止值";
CM_ SG_ 2418404977 S2P_Lmt20_Over_Ucell4_49 "电池单体充电截止电压";
CM_ SG_ 2418404977 S2P_Lmt20_Under_Ucell4_49 "电池单体放电截止电压";
CM_ SG_ 2418404977 S2P_Lmt20_Over_Tcell4_49 "电池单体高温截止温度";
CM_ SG_ 2418404978 S2P_Lmt20_Over_DeltUcell4_50 "电池单体电压极差截止值";
CM_ SG_ 2418404978 S2P_Lmt20_Over_DeltTcell4_50 "电池单体温度极差截止值";
CM_ SG_ 2418404978 S2P_Lmt20_Over_Ucell4_50 "电池单体充电截止电压";
CM_ SG_ 2418404978 S2P_Lmt20_Under_Ucell4_50 "电池单体放电截止电压";
CM_ SG_ 2418404978 S2P_Lmt20_Over_Tcell4_50 "电池单体高温截止温度";
CM_ SG_ 2418404979 S2P_Lmt20_Over_DeltUcell4_51 "电池单体电压极差截止值";
CM_ SG_ 2418404979 S2P_Lmt20_Over_DeltTcell4_51 "电池单体温度极差截止值";
CM_ SG_ 2418404979 S2P_Lmt20_Over_Ucell4_51 "电池单体充电截止电压";
CM_ SG_ 2418404979 S2P_Lmt20_Under_Ucell4_51 "电池单体放电截止电压";
CM_ SG_ 2418404979 S2P_Lmt20_Over_Tcell4_51 "电池单体高温截止温度";
CM_ SG_ 2418404980 S2P_Lmt20_Over_DeltUcell4_52 "电池单体电压极差截止值";
CM_ SG_ 2418404980 S2P_Lmt20_Over_DeltTcell4_52 "电池单体温度极差截止值";
CM_ SG_ 2418404980 S2P_Lmt20_Over_Ucell4_52 "电池单体充电截止电压";
CM_ SG_ 2418404980 S2P_Lmt20_Under_Ucell4_52 "电池单体放电截止电压";
CM_ SG_ 2418404980 S2P_Lmt20_Over_Tcell4_52 "电池单体高温截止温度";
CM_ SG_ 2418404981 S2P_Lmt20_Over_DeltUcell4_53 "电池单体电压极差截止值";
CM_ SG_ 2418404981 S2P_Lmt20_Over_DeltTcell4_53 "电池单体温度极差截止值";
CM_ SG_ 2418404981 S2P_Lmt20_Over_Ucell4_53 "电池单体充电截止电压";
CM_ SG_ 2418404981 S2P_Lmt20_Under_Ucell4_53 "电池单体放电截止电压";
CM_ SG_ 2418404981 S2P_Lmt20_Over_Tcell4_53 "电池单体高温截止温度";
CM_ SG_ 2418404982 S2P_Lmt20_Over_DeltUcell4_54 "电池单体电压极差截止值";
CM_ SG_ 2418404982 S2P_Lmt20_Over_DeltTcell4_54 "电池单体温度极差截止值";
CM_ SG_ 2418404982 S2P_Lmt20_Over_Ucell4_54 "电池单体充电截止电压";
CM_ SG_ 2418404982 S2P_Lmt20_Under_Ucell4_54 "电池单体放电截止电压";
CM_ SG_ 2418404982 S2P_Lmt20_Over_Tcell4_54 "电池单体高温截止温度";
CM_ SG_ 2418404983 S2P_Lmt20_Over_DeltUcell4_55 "电池单体电压极差截止值";
CM_ SG_ 2418404983 S2P_Lmt20_Over_DeltTcell4_55 "电池单体温度极差截止值";
CM_ SG_ 2418404983 S2P_Lmt20_Over_Ucell4_55 "电池单体充电截止电压";
CM_ SG_ 2418404983 S2P_Lmt20_Under_Ucell4_55 "电池单体放电截止电压";
CM_ SG_ 2418404983 S2P_Lmt20_Over_Tcell4_55 "电池单体高温截止温度";
CM_ SG_ 2418404984 S2P_Lmt20_Over_DeltUcell4_56 "电池单体电压极差截止值";
CM_ SG_ 2418404984 S2P_Lmt20_Over_DeltTcell4_56 "电池单体温度极差截止值";
CM_ SG_ 2418404984 S2P_Lmt20_Over_Ucell4_56 "电池单体充电截止电压";
CM_ SG_ 2418404984 S2P_Lmt20_Under_Ucell4_56 "电池单体放电截止电压";
CM_ SG_ 2418404984 S2P_Lmt20_Over_Tcell4_56 "电池单体高温截止温度";
CM_ SG_ 2418404985 S2P_Lmt20_Over_DeltUcell4_57 "电池单体电压极差截止值";
CM_ SG_ 2418404985 S2P_Lmt20_Over_DeltTcell4_57 "电池单体温度极差截止值";
CM_ SG_ 2418404985 S2P_Lmt20_Over_Ucell4_57 "电池单体充电截止电压";
CM_ SG_ 2418404985 S2P_Lmt20_Under_Ucell4_57 "电池单体放电截止电压";
CM_ SG_ 2418404985 S2P_Lmt20_Over_Tcell4_57 "电池单体高温截止温度";
CM_ SG_ 2418404986 S2P_Lmt20_Over_DeltUcell4_58 "电池单体电压极差截止值";
CM_ SG_ 2418404986 S2P_Lmt20_Over_DeltTcell4_58 "电池单体温度极差截止值";
CM_ SG_ 2418404986 S2P_Lmt20_Over_Ucell4_58 "电池单体充电截止电压";
CM_ SG_ 2418404986 S2P_Lmt20_Under_Ucell4_58 "电池单体放电截止电压";
CM_ SG_ 2418404986 S2P_Lmt20_Over_Tcell4_58 "电池单体高温截止温度";
CM_ SG_ 2418404987 S2P_Lmt20_Over_DeltUcell4_59 "电池单体电压极差截止值";
CM_ SG_ 2418404987 S2P_Lmt20_Over_DeltTcell4_59 "电池单体温度极差截止值";
CM_ SG_ 2418404987 S2P_Lmt20_Over_Ucell4_59 "电池单体充电截止电压";
CM_ SG_ 2418404987 S2P_Lmt20_Under_Ucell4_59 "电池单体放电截止电压";
CM_ SG_ 2418404987 S2P_Lmt20_Over_Tcell4_59 "电池单体高温截止温度";
CM_ SG_ 2418404988 S2P_Lmt20_Over_DeltUcell4_60 "电池单体电压极差截止值";
CM_ SG_ 2418404988 S2P_Lmt20_Over_DeltTcell4_60 "电池单体温度极差截止值";
CM_ SG_ 2418404988 S2P_Lmt20_Over_Ucell4_60 "电池单体充电截止电压";
CM_ SG_ 2418404988 S2P_Lmt20_Under_Ucell4_60 "电池单体放电截止电压";
CM_ SG_ 2418404988 S2P_Lmt20_Over_Tcell4_60 "电池单体高温截止温度";
CM_ SG_ 2418404989 S2P_Lmt20_Over_DeltUcell4_61 "电池单体电压极差截止值";
CM_ SG_ 2418404989 S2P_Lmt20_Over_DeltTcell4_61 "电池单体温度极差截止值";
CM_ SG_ 2418404989 S2P_Lmt20_Over_Ucell4_61 "电池单体充电截止电压";
CM_ SG_ 2418404989 S2P_Lmt20_Under_Ucell4_61 "电池单体放电截止电压";
CM_ SG_ 2418404989 S2P_Lmt20_Over_Tcell4_61 "电池单体高温截止温度";
CM_ SG_ 2418404990 S2P_Lmt20_Over_DeltUcell4_62 "电池单体电压极差截止值";
CM_ SG_ 2418404990 S2P_Lmt20_Over_DeltTcell4_62 "电池单体温度极差截止值";
CM_ SG_ 2418404990 S2P_Lmt20_Over_Ucell4_62 "电池单体充电截止电压";
CM_ SG_ 2418404990 S2P_Lmt20_Under_Ucell4_62 "电池单体放电截止电压";
CM_ SG_ 2418404990 S2P_Lmt20_Over_Tcell4_62 "电池单体高温截止温度";
CM_ SG_ 2418404991 S2P_Lmt20_Over_DeltUcell4_63 "电池单体电压极差截止值";
CM_ SG_ 2418404991 S2P_Lmt20_Over_DeltTcell4_63 "电池单体温度极差截止值";
CM_ SG_ 2418404991 S2P_Lmt20_Over_Ucell4_63 "电池单体充电截止电压";
CM_ SG_ 2418404991 S2P_Lmt20_Under_Ucell4_63 "电池单体放电截止电压";
CM_ SG_ 2418404991 S2P_Lmt20_Over_Tcell4_63 "电池单体高温截止温度";
CM_ SG_ 2418470465 S2P_Lmt21_Under_Tcell4_01 "电池单体低温截止温度";
CM_ SG_ 2418470466 S2P_Lmt21_Under_Tcell4_02 "电池单体低温截止温度";
CM_ SG_ 2418470467 S2P_Lmt21_Under_Tcell4_03 "电池单体低温截止温度";
CM_ SG_ 2418470468 S2P_Lmt21_Under_Tcell4_04 "电池单体低温截止温度";
CM_ SG_ 2418470469 S2P_Lmt21_Under_Tcell4_05 "电池单体低温截止温度";
CM_ SG_ 2418470470 S2P_Lmt21_Under_Tcell4_06 "电池单体低温截止温度";
CM_ SG_ 2418470471 S2P_Lmt21_Under_Tcell4_07 "电池单体低温截止温度";
CM_ SG_ 2418470472 S2P_Lmt21_Under_Tcell4_08 "电池单体低温截止温度";
CM_ SG_ 2418470473 S2P_Lmt21_Under_Tcell4_09 "电池单体低温截止温度";
CM_ SG_ 2418470474 S2P_Lmt21_Under_Tcell4_10 "电池单体低温截止温度";
CM_ SG_ 2418470475 S2P_Lmt21_Under_Tcell4_11 "电池单体低温截止温度";
CM_ SG_ 2418470476 S2P_Lmt21_Under_Tcell4_12 "电池单体低温截止温度";
CM_ SG_ 2418470477 S2P_Lmt21_Under_Tcell4_13 "电池单体低温截止温度";
CM_ SG_ 2418470478 S2P_Lmt21_Under_Tcell4_14 "电池单体低温截止温度";
CM_ SG_ 2418470479 S2P_Lmt21_Under_Tcell4_15 "电池单体低温截止温度";
CM_ SG_ 2418470480 S2P_Lmt21_Under_Tcell4_16 "电池单体低温截止温度";
CM_ SG_ 2418470481 S2P_Lmt21_Under_Tcell4_17 "电池单体低温截止温度";
CM_ SG_ 2418470482 S2P_Lmt21_Under_Tcell4_18 "电池单体低温截止温度";
CM_ SG_ 2418470483 S2P_Lmt21_Under_Tcell4_19 "电池单体低温截止温度";
CM_ SG_ 2418470484 S2P_Lmt21_Under_Tcell4_20 "电池单体低温截止温度";
CM_ SG_ 2418470485 S2P_Lmt21_Under_Tcell4_21 "电池单体低温截止温度";
CM_ SG_ 2418470486 S2P_Lmt21_Under_Tcell4_22 "电池单体低温截止温度";
CM_ SG_ 2418470487 S2P_Lmt21_Under_Tcell4_23 "电池单体低温截止温度";
CM_ SG_ 2418470488 S2P_Lmt21_Under_Tcell4_24 "电池单体低温截止温度";
CM_ SG_ 2418470489 S2P_Lmt21_Under_Tcell4_25 "电池单体低温截止温度";
CM_ SG_ 2418470490 S2P_Lmt21_Under_Tcell4_26 "电池单体低温截止温度";
CM_ SG_ 2418470491 S2P_Lmt21_Under_Tcell4_27 "电池单体低温截止温度";
CM_ SG_ 2418470492 S2P_Lmt21_Under_Tcell4_28 "电池单体低温截止温度";
CM_ SG_ 2418470493 S2P_Lmt21_Under_Tcell4_29 "电池单体低温截止温度";
CM_ SG_ 2418470494 S2P_Lmt21_Under_Tcell4_30 "电池单体低温截止温度";
CM_ SG_ 2418470495 S2P_Lmt21_Under_Tcell4_31 "电池单体低温截止温度";
CM_ SG_ 2418470496 S2P_Lmt21_Under_Tcell4_32 "电池单体低温截止温度";
CM_ SG_ 2418470497 S2P_Lmt21_Under_Tcell4_33 "电池单体低温截止温度";
CM_ SG_ 2418470498 S2P_Lmt21_Under_Tcell4_34 "电池单体低温截止温度";
CM_ SG_ 2418470499 S2P_Lmt21_Under_Tcell4_35 "电池单体低温截止温度";
CM_ SG_ 2418470500 S2P_Lmt21_Under_Tcell4_36 "电池单体低温截止温度";
CM_ SG_ 2418470501 S2P_Lmt21_Under_Tcell4_37 "电池单体低温截止温度";
CM_ SG_ 2418470502 S2P_Lmt21_Under_Tcell4_38 "电池单体低温截止温度";
CM_ SG_ 2418470503 S2P_Lmt21_Under_Tcell4_39 "电池单体低温截止温度";
CM_ SG_ 2418470504 S2P_Lmt21_Under_Tcell4_40 "电池单体低温截止温度";
CM_ SG_ 2418470505 S2P_Lmt21_Under_Tcell4_41 "电池单体低温截止温度";
CM_ SG_ 2418470506 S2P_Lmt21_Under_Tcell4_42 "电池单体低温截止温度";
CM_ SG_ 2418470507 S2P_Lmt21_Under_Tcell4_43 "电池单体低温截止温度";
CM_ SG_ 2418470508 S2P_Lmt21_Under_Tcell4_44 "电池单体低温截止温度";
CM_ SG_ 2418470509 S2P_Lmt21_Under_Tcell4_45 "电池单体低温截止温度";
CM_ SG_ 2418470510 S2P_Lmt21_Under_Tcell4_46 "电池单体低温截止温度";
CM_ SG_ 2418470511 S2P_Lmt21_Under_Tcell4_47 "电池单体低温截止温度";
CM_ SG_ 2418470512 S2P_Lmt21_Under_Tcell4_48 "电池单体低温截止温度";
CM_ SG_ 2418470513 S2P_Lmt21_Under_Tcell4_49 "电池单体低温截止温度";
CM_ SG_ 2418470514 S2P_Lmt21_Under_Tcell4_50 "电池单体低温截止温度";
CM_ SG_ 2418470515 S2P_Lmt21_Under_Tcell4_51 "电池单体低温截止温度";
CM_ SG_ 2418470516 S2P_Lmt21_Under_Tcell4_52 "电池单体低温截止温度";
CM_ SG_ 2418470517 S2P_Lmt21_Under_Tcell4_53 "电池单体低温截止温度";
CM_ SG_ 2418470518 S2P_Lmt21_Under_Tcell4_54 "电池单体低温截止温度";
CM_ SG_ 2418470519 S2P_Lmt21_Under_Tcell4_55 "电池单体低温截止温度";
CM_ SG_ 2418470520 S2P_Lmt21_Under_Tcell4_56 "电池单体低温截止温度";
CM_ SG_ 2418470521 S2P_Lmt21_Under_Tcell4_57 "电池单体低温截止温度";
CM_ SG_ 2418470522 S2P_Lmt21_Under_Tcell4_58 "电池单体低温截止温度";
CM_ SG_ 2418470523 S2P_Lmt21_Under_Tcell4_59 "电池单体低温截止温度";
CM_ SG_ 2418470524 S2P_Lmt21_Under_Tcell4_60 "电池单体低温截止温度";
CM_ SG_ 2418470525 S2P_Lmt21_Under_Tcell4_61 "电池单体低温截止温度";
CM_ SG_ 2418470526 S2P_Lmt21_Under_Tcell4_62 "电池单体低温截止温度";
CM_ SG_ 2418470527 S2P_Lmt21_Under_Tcell4_63 "电池单体低温截止温度";
CM_ SG_ 2332115089 L2S_SUMDATA1_Yesr_01 "LEMS发送的算法计算时间-年";
CM_ SG_ 2332115089 L2S_SUMDATA1_Month_01 "LEMS发送的算法计算时间-月";
CM_ SG_ 2332115089 L2S_SUMDATA1_Day_Ts_01 "LEMS发送的算法计算时间-日";
CM_ SG_ 2332115089 L2S_SUMDATA1_Hour_Ts_01 "LEMS发送的算法计算时间-时";
CM_ SG_ 2332115089 L2S_SUMDATA1_MInute_Ts_01 "LEMS发送的算法计算时间-分";
CM_ SG_ 2332115089 L2S_SUMDATA1_Second_Ts_01 "LEMS发送的算法计算时间-秒";
CM_ SG_ 2332115089 L2S_SUMDATA1_SBMUnumber_Ts_01 "LEMS发送的SBMU号";
CM_ SG_ 2332115089 L2S_SUMDATA1_Confidence_01 "LEMS向SBMU发送的置信度";
CM_ SG_ 2332115089 L2S_SUMDATA1_Value_01 "LEMS向SBMU发送的计算结果";
CM_ SG_ 2332115090 L2S_SUMDATA1_Yesr_02 "LEMS发送的算法计算时间-年";
CM_ SG_ 2332115090 L2S_SUMDATA1_Month_02 "LEMS发送的算法计算时间-月";
CM_ SG_ 2332115090 L2S_SUMDATA1_Day_Ts_02 "LEMS发送的算法计算时间-日";
CM_ SG_ 2332115090 L2S_SUMDATA1_Hour_Ts_02 "LEMS发送的算法计算时间-时";
CM_ SG_ 2332115090 L2S_SUMDATA1_MInute_Ts_02 "LEMS发送的算法计算时间-分";
CM_ SG_ 2332115090 L2S_SUMDATA1_Second_Ts_02 "LEMS发送的算法计算时间-秒";
CM_ SG_ 2332115090 L2S_SUMDATA1_SBMUnumber_Ts_02 "LEMS发送的SBMU号";
CM_ SG_ 2332115090 L2S_SUMDATA1_Confidence_02 "LEMS向SBMU发送的置信度";
CM_ SG_ 2332115090 L2S_SUMDATA1_Value_02 "LEMS向SBMU发送的计算结果";
CM_ SG_ 2332115091 L2S_SUMDATA1_Yesr_03 "LEMS发送的算法计算时间-年";
CM_ SG_ 2332115091 L2S_SUMDATA1_Month_03 "LEMS发送的算法计算时间-月";
CM_ SG_ 2332115091 L2S_SUMDATA1_Day_Ts_03 "LEMS发送的算法计算时间-日";
CM_ SG_ 2332115091 L2S_SUMDATA1_Hour_Ts_03 "LEMS发送的算法计算时间-时";
CM_ SG_ 2332115091 L2S_SUMDATA1_MInute_Ts_03 "LEMS发送的算法计算时间-分";
CM_ SG_ 2332115091 L2S_SUMDATA1_Second_Ts_03 "LEMS发送的算法计算时间-秒";
CM_ SG_ 2332115091 L2S_SUMDATA1_SBMUnumber_Ts_03 "LEMS发送的SBMU号";
CM_ SG_ 2332115091 L2S_SUMDATA1_Confidence_03 "LEMS向SBMU发送的置信度";
CM_ SG_ 2332115091 L2S_SUMDATA1_Value_03 "LEMS向SBMU发送的计算结果";
CM_ SG_ 2332115092 L2S_SUMDATA1_Yesr_04 "LEMS发送的算法计算时间-年";
CM_ SG_ 2332115092 L2S_SUMDATA1_Month_04 "LEMS发送的算法计算时间-月";
CM_ SG_ 2332115092 L2S_SUMDATA1_Day_Ts_04 "LEMS发送的算法计算时间-日";
CM_ SG_ 2332115092 L2S_SUMDATA1_Hour_Ts_04 "LEMS发送的算法计算时间-时";
CM_ SG_ 2332115092 L2S_SUMDATA1_MInute_Ts_04 "LEMS发送的算法计算时间-分";
CM_ SG_ 2332115092 L2S_SUMDATA1_Second_Ts_04 "LEMS发送的算法计算时间-秒";
CM_ SG_ 2332115092 L2S_SUMDATA1_SBMUnumber_Ts_04 "LEMS发送的SBMU号";
CM_ SG_ 2332115092 L2S_SUMDATA1_Confidence_04 "LEMS向SBMU发送的置信度";
CM_ SG_ 2332115092 L2S_SUMDATA1_Value_04 "LEMS向SBMU发送的计算结果";
CM_ SG_ 2332115093 L2S_SUMDATA1_Yesr_05 "LEMS发送的算法计算时间-年";
CM_ SG_ 2332115093 L2S_SUMDATA1_Month_05 "LEMS发送的算法计算时间-月";
CM_ SG_ 2332115093 L2S_SUMDATA1_Day_Ts_05 "LEMS发送的算法计算时间-日";
CM_ SG_ 2332115093 L2S_SUMDATA1_Hour_Ts_05 "LEMS发送的算法计算时间-时";
CM_ SG_ 2332115093 L2S_SUMDATA1_MInute_Ts_05 "LEMS发送的算法计算时间-分";
CM_ SG_ 2332115093 L2S_SUMDATA1_Second_Ts_05 "LEMS发送的算法计算时间-秒";
CM_ SG_ 2332115093 L2S_SUMDATA1_SBMUnumber_Ts_05 "LEMS发送的SBMU号";
CM_ SG_ 2332115093 L2S_SUMDATA1_Confidence_05 "LEMS向SBMU发送的置信度";
CM_ SG_ 2332115093 L2S_SUMDATA1_Value_05 "LEMS向SBMU发送的计算结果";
CM_ SG_ 2332115094 L2S_SUMDATA1_Yesr_06 "LEMS发送的算法计算时间-年";
CM_ SG_ 2332115094 L2S_SUMDATA1_Month_06 "LEMS发送的算法计算时间-月";
CM_ SG_ 2332115094 L2S_SUMDATA1_Day_Ts_06 "LEMS发送的算法计算时间-日";
CM_ SG_ 2332115094 L2S_SUMDATA1_Hour_Ts_06 "LEMS发送的算法计算时间-时";
CM_ SG_ 2332115094 L2S_SUMDATA1_MInute_Ts_06 "LEMS发送的算法计算时间-分";
CM_ SG_ 2332115094 L2S_SUMDATA1_Second_Ts_06 "LEMS发送的算法计算时间-秒";
CM_ SG_ 2332115094 L2S_SUMDATA1_SBMUnumber_Ts_06 "LEMS发送的SBMU号";
CM_ SG_ 2332115094 L2S_SUMDATA1_Confidence_06 "LEMS向SBMU发送的置信度";
CM_ SG_ 2332115094 L2S_SUMDATA1_Value_06 "LEMS向SBMU发送的计算结果";
CM_ SG_ 2332115095 L2S_SUMDATA1_Yesr_07 "LEMS发送的算法计算时间-年";
CM_ SG_ 2332115095 L2S_SUMDATA1_Month_07 "LEMS发送的算法计算时间-月";
CM_ SG_ 2332115095 L2S_SUMDATA1_Day_Ts_07 "LEMS发送的算法计算时间-日";
CM_ SG_ 2332115095 L2S_SUMDATA1_Hour_Ts_07 "LEMS发送的算法计算时间-时";
CM_ SG_ 2332115095 L2S_SUMDATA1_MInute_Ts_07 "LEMS发送的算法计算时间-分";
CM_ SG_ 2332115095 L2S_SUMDATA1_Second_Ts_07 "LEMS发送的算法计算时间-秒";
CM_ SG_ 2332115095 L2S_SUMDATA1_SBMUnumber_Ts_07 "LEMS发送的SBMU号";
CM_ SG_ 2332115095 L2S_SUMDATA1_Confidence_07 "LEMS向SBMU发送的置信度";
CM_ SG_ 2332115095 L2S_SUMDATA1_Value_07 "LEMS向SBMU发送的计算结果";
CM_ SG_ 2332115096 L2S_SUMDATA1_Yesr_08 "LEMS发送的算法计算时间-年";
CM_ SG_ 2332115096 L2S_SUMDATA1_Month_08 "LEMS发送的算法计算时间-月";
CM_ SG_ 2332115096 L2S_SUMDATA1_Day_Ts_08 "LEMS发送的算法计算时间-日";
CM_ SG_ 2332115096 L2S_SUMDATA1_Hour_Ts_08 "LEMS发送的算法计算时间-时";
CM_ SG_ 2332115096 L2S_SUMDATA1_MInute_Ts_08 "LEMS发送的算法计算时间-分";
CM_ SG_ 2332115096 L2S_SUMDATA1_Second_Ts_08 "LEMS发送的算法计算时间-秒";
CM_ SG_ 2332115096 L2S_SUMDATA1_SBMUnumber_Ts_08 "LEMS发送的SBMU号";
CM_ SG_ 2332115096 L2S_SUMDATA1_Confidence_08 "LEMS向SBMU发送的置信度";
CM_ SG_ 2332115096 L2S_SUMDATA1_Value_08 "LEMS向SBMU发送的计算结果";
CM_ SG_ 2332115097 L2S_SUMDATA1_Yesr_09 "LEMS发送的算法计算时间-年";
CM_ SG_ 2332115097 L2S_SUMDATA1_Month_09 "LEMS发送的算法计算时间-月";
CM_ SG_ 2332115097 L2S_SUMDATA1_Day_Ts_09 "LEMS发送的算法计算时间-日";
CM_ SG_ 2332115097 L2S_SUMDATA1_Hour_Ts_09 "LEMS发送的算法计算时间-时";
CM_ SG_ 2332115097 L2S_SUMDATA1_MInute_Ts_09 "LEMS发送的算法计算时间-分";
CM_ SG_ 2332115097 L2S_SUMDATA1_Second_Ts_09 "LEMS发送的算法计算时间-秒";
CM_ SG_ 2332115097 L2S_SUMDATA1_SBMUnumber_Ts_09 "LEMS发送的SBMU号";
CM_ SG_ 2332115097 L2S_SUMDATA1_Confidence_09 "LEMS向SBMU发送的置信度";
CM_ SG_ 2332115097 L2S_SUMDATA1_Value_09 "LEMS向SBMU发送的计算结果";
CM_ SG_ 2332115098 L2S_SUMDATA1_Yesr_10 "LEMS发送的算法计算时间-年";
CM_ SG_ 2332115098 L2S_SUMDATA1_Month_10 "LEMS发送的算法计算时间-月";
CM_ SG_ 2332115098 L2S_SUMDATA1_Day_Ts_10 "LEMS发送的算法计算时间-日";
CM_ SG_ 2332115098 L2S_SUMDATA1_Hour_Ts_10 "LEMS发送的算法计算时间-时";
CM_ SG_ 2332115098 L2S_SUMDATA1_MInute_Ts_10 "LEMS发送的算法计算时间-分";
CM_ SG_ 2332115098 L2S_SUMDATA1_Second_Ts_10 "LEMS发送的算法计算时间-秒";
CM_ SG_ 2332115098 L2S_SUMDATA1_SBMUnumber_Ts_10 "LEMS发送的SBMU号";
CM_ SG_ 2332115098 L2S_SUMDATA1_Confidence_10 "LEMS向SBMU发送的置信度";
CM_ SG_ 2332115098 L2S_SUMDATA1_Value_10 "LEMS向SBMU发送的计算结果";
CM_ SG_ 2332115099 L2S_SUMDATA1_Yesr_11 "LEMS发送的算法计算时间-年";
CM_ SG_ 2332115099 L2S_SUMDATA1_Month_11 "LEMS发送的算法计算时间-月";
CM_ SG_ 2332115099 L2S_SUMDATA1_Day_Ts_11 "LEMS发送的算法计算时间-日";
CM_ SG_ 2332115099 L2S_SUMDATA1_Hour_Ts_11 "LEMS发送的算法计算时间-时";
CM_ SG_ 2332115099 L2S_SUMDATA1_MInute_Ts_11 "LEMS发送的算法计算时间-分";
CM_ SG_ 2332115099 L2S_SUMDATA1_Second_Ts_11 "LEMS发送的算法计算时间-秒";
CM_ SG_ 2332115099 L2S_SUMDATA1_SBMUnumber_Ts_11 "LEMS发送的SBMU号";
CM_ SG_ 2332115099 L2S_SUMDATA1_Confidence_11 "LEMS向SBMU发送的置信度";
CM_ SG_ 2332115099 L2S_SUMDATA1_Value_11 "LEMS向SBMU发送的计算结果";
CM_ SG_ 2332115100 L2S_SUMDATA1_Yesr_12 "LEMS发送的算法计算时间-年";
CM_ SG_ 2332115100 L2S_SUMDATA1_Month_12 "LEMS发送的算法计算时间-月";
CM_ SG_ 2332115100 L2S_SUMDATA1_Day_Ts_12 "LEMS发送的算法计算时间-日";
CM_ SG_ 2332115100 L2S_SUMDATA1_Hour_Ts_12 "LEMS发送的算法计算时间-时";
CM_ SG_ 2332115100 L2S_SUMDATA1_MInute_Ts_12 "LEMS发送的算法计算时间-分";
CM_ SG_ 2332115100 L2S_SUMDATA1_Second_Ts_12 "LEMS发送的算法计算时间-秒";
CM_ SG_ 2332115100 L2S_SUMDATA1_SBMUnumber_Ts_12 "LEMS发送的SBMU号";
CM_ SG_ 2332115100 L2S_SUMDATA1_Confidence_12 "LEMS向SBMU发送的置信度";
CM_ SG_ 2332115100 L2S_SUMDATA1_Value_12 "LEMS向SBMU发送的计算结果";
CM_ SG_ 2332115101 L2S_SUMDATA1_Yesr_13 "LEMS发送的算法计算时间-年";
CM_ SG_ 2332115101 L2S_SUMDATA1_Month_13 "LEMS发送的算法计算时间-月";
CM_ SG_ 2332115101 L2S_SUMDATA1_Day_Ts_13 "LEMS发送的算法计算时间-日";
CM_ SG_ 2332115101 L2S_SUMDATA1_Hour_Ts_13 "LEMS发送的算法计算时间-时";
CM_ SG_ 2332115101 L2S_SUMDATA1_MInute_Ts_13 "LEMS发送的算法计算时间-分";
CM_ SG_ 2332115101 L2S_SUMDATA1_Second_Ts_13 "LEMS发送的算法计算时间-秒";
CM_ SG_ 2332115101 L2S_SUMDATA1_SBMUnumber_Ts_13 "LEMS发送的SBMU号";
CM_ SG_ 2332115101 L2S_SUMDATA1_Confidence_13 "LEMS向SBMU发送的置信度";
CM_ SG_ 2332115101 L2S_SUMDATA1_Value_13 "LEMS向SBMU发送的计算结果";
CM_ SG_ 2332115102 L2S_SUMDATA1_Yesr_14 "LEMS发送的算法计算时间-年";
CM_ SG_ 2332115102 L2S_SUMDATA1_Month_14 "LEMS发送的算法计算时间-月";
CM_ SG_ 2332115102 L2S_SUMDATA1_Day_Ts_14 "LEMS发送的算法计算时间-日";
CM_ SG_ 2332115102 L2S_SUMDATA1_Hour_Ts_14 "LEMS发送的算法计算时间-时";
CM_ SG_ 2332115102 L2S_SUMDATA1_MInute_Ts_14 "LEMS发送的算法计算时间-分";
CM_ SG_ 2332115102 L2S_SUMDATA1_Second_Ts_14 "LEMS发送的算法计算时间-秒";
CM_ SG_ 2332115102 L2S_SUMDATA1_SBMUnumber_Ts_14 "LEMS发送的SBMU号";
CM_ SG_ 2332115102 L2S_SUMDATA1_Confidence_14 "LEMS向SBMU发送的置信度";
CM_ SG_ 2332115102 L2S_SUMDATA1_Value_14 "LEMS向SBMU发送的计算结果";
CM_ SG_ 2332115103 L2S_SUMDATA1_Yesr_15 "LEMS发送的算法计算时间-年";
CM_ SG_ 2332115103 L2S_SUMDATA1_Month_15 "LEMS发送的算法计算时间-月";
CM_ SG_ 2332115103 L2S_SUMDATA1_Day_Ts_15 "LEMS发送的算法计算时间-日";
CM_ SG_ 2332115103 L2S_SUMDATA1_Hour_Ts_15 "LEMS发送的算法计算时间-时";
CM_ SG_ 2332115103 L2S_SUMDATA1_MInute_Ts_15 "LEMS发送的算法计算时间-分";
CM_ SG_ 2332115103 L2S_SUMDATA1_Second_Ts_15 "LEMS发送的算法计算时间-秒";
CM_ SG_ 2332115103 L2S_SUMDATA1_SBMUnumber_Ts_15 "LEMS发送的SBMU号";
CM_ SG_ 2332115103 L2S_SUMDATA1_Confidence_15 "LEMS向SBMU发送的置信度";
CM_ SG_ 2332115103 L2S_SUMDATA1_Value_15 "LEMS向SBMU发送的计算结果";
CM_ SG_ 2332115104 L2S_SUMDATA1_Yesr_16 "LEMS发送的算法计算时间-年";
CM_ SG_ 2332115104 L2S_SUMDATA1_Month_16 "LEMS发送的算法计算时间-月";
CM_ SG_ 2332115104 L2S_SUMDATA1_Day_Ts_16 "LEMS发送的算法计算时间-日";
CM_ SG_ 2332115104 L2S_SUMDATA1_Hour_Ts_16 "LEMS发送的算法计算时间-时";
CM_ SG_ 2332115104 L2S_SUMDATA1_MInute_Ts_16 "LEMS发送的算法计算时间-分";
CM_ SG_ 2332115104 L2S_SUMDATA1_Second_Ts_16 "LEMS发送的算法计算时间-秒";
CM_ SG_ 2332115104 L2S_SUMDATA1_SBMUnumber_Ts_16 "LEMS发送的SBMU号";
CM_ SG_ 2332115104 L2S_SUMDATA1_Confidence_16 "LEMS向SBMU发送的置信度";
CM_ SG_ 2332115104 L2S_SUMDATA1_Value_16 "LEMS向SBMU发送的计算结果";
CM_ SG_ 2332115105 L2S_SUMDATA1_Yesr_17 "LEMS发送的算法计算时间-年";
CM_ SG_ 2332115105 L2S_SUMDATA1_Month_17 "LEMS发送的算法计算时间-月";
CM_ SG_ 2332115105 L2S_SUMDATA1_Day_Ts_17 "LEMS发送的算法计算时间-日";
CM_ SG_ 2332115105 L2S_SUMDATA1_Hour_Ts_17 "LEMS发送的算法计算时间-时";
CM_ SG_ 2332115105 L2S_SUMDATA1_MInute_Ts_17 "LEMS发送的算法计算时间-分";
CM_ SG_ 2332115105 L2S_SUMDATA1_Second_Ts_17 "LEMS发送的算法计算时间-秒";
CM_ SG_ 2332115105 L2S_SUMDATA1_SBMUnumber_Ts_17 "LEMS发送的SBMU号";
CM_ SG_ 2332115105 L2S_SUMDATA1_Confidence_17 "LEMS向SBMU发送的置信度";
CM_ SG_ 2332115105 L2S_SUMDATA1_Value_17 "LEMS向SBMU发送的计算结果";
CM_ SG_ 2332115106 L2S_SUMDATA1_Yesr_18 "LEMS发送的算法计算时间-年";
CM_ SG_ 2332115106 L2S_SUMDATA1_Month_18 "LEMS发送的算法计算时间-月";
CM_ SG_ 2332115106 L2S_SUMDATA1_Day_Ts_18 "LEMS发送的算法计算时间-日";
CM_ SG_ 2332115106 L2S_SUMDATA1_Hour_Ts_18 "LEMS发送的算法计算时间-时";
CM_ SG_ 2332115106 L2S_SUMDATA1_MInute_Ts_18 "LEMS发送的算法计算时间-分";
CM_ SG_ 2332115106 L2S_SUMDATA1_Second_Ts_18 "LEMS发送的算法计算时间-秒";
CM_ SG_ 2332115106 L2S_SUMDATA1_SBMUnumber_Ts_18 "LEMS发送的SBMU号";
CM_ SG_ 2332115106 L2S_SUMDATA1_Confidence_18 "LEMS向SBMU发送的置信度";
CM_ SG_ 2332115106 L2S_SUMDATA1_Value_18 "LEMS向SBMU发送的计算结果";
CM_ SG_ 2332115107 L2S_SUMDATA1_Yesr_19 "LEMS发送的算法计算时间-年";
CM_ SG_ 2332115107 L2S_SUMDATA1_Month_19 "LEMS发送的算法计算时间-月";
CM_ SG_ 2332115107 L2S_SUMDATA1_Day_Ts_19 "LEMS发送的算法计算时间-日";
CM_ SG_ 2332115107 L2S_SUMDATA1_Hour_Ts_19 "LEMS发送的算法计算时间-时";
CM_ SG_ 2332115107 L2S_SUMDATA1_MInute_Ts_19 "LEMS发送的算法计算时间-分";
CM_ SG_ 2332115107 L2S_SUMDATA1_Second_Ts_19 "LEMS发送的算法计算时间-秒";
CM_ SG_ 2332115107 L2S_SUMDATA1_SBMUnumber_Ts_19 "LEMS发送的SBMU号";
CM_ SG_ 2332115107 L2S_SUMDATA1_Confidence_19 "LEMS向SBMU发送的置信度";
CM_ SG_ 2332115107 L2S_SUMDATA1_Value_19 "LEMS向SBMU发送的计算结果";
CM_ SG_ 2332115108 L2S_SUMDATA1_Yesr_20 "LEMS发送的算法计算时间-年";
CM_ SG_ 2332115108 L2S_SUMDATA1_Month_20 "LEMS发送的算法计算时间-月";
CM_ SG_ 2332115108 L2S_SUMDATA1_Day_Ts_20 "LEMS发送的算法计算时间-日";
CM_ SG_ 2332115108 L2S_SUMDATA1_Hour_Ts_20 "LEMS发送的算法计算时间-时";
CM_ SG_ 2332115108 L2S_SUMDATA1_MInute_Ts_20 "LEMS发送的算法计算时间-分";
CM_ SG_ 2332115108 L2S_SUMDATA1_Second_Ts_20 "LEMS发送的算法计算时间-秒";
CM_ SG_ 2332115108 L2S_SUMDATA1_SBMUnumber_Ts_20 "LEMS发送的SBMU号";
CM_ SG_ 2332115108 L2S_SUMDATA1_Confidence_20 "LEMS向SBMU发送的置信度";
CM_ SG_ 2332115108 L2S_SUMDATA1_Value_20 "LEMS向SBMU发送的计算结果";
CM_ SG_ 2332115109 L2S_SUMDATA1_Yesr_21 "LEMS发送的算法计算时间-年";
CM_ SG_ 2332115109 L2S_SUMDATA1_Month_21 "LEMS发送的算法计算时间-月";
CM_ SG_ 2332115109 L2S_SUMDATA1_Day_Ts_21 "LEMS发送的算法计算时间-日";
CM_ SG_ 2332115109 L2S_SUMDATA1_Hour_Ts_21 "LEMS发送的算法计算时间-时";
CM_ SG_ 2332115109 L2S_SUMDATA1_MInute_Ts_21 "LEMS发送的算法计算时间-分";
CM_ SG_ 2332115109 L2S_SUMDATA1_Second_Ts_21 "LEMS发送的算法计算时间-秒";
CM_ SG_ 2332115109 L2S_SUMDATA1_SBMUnumber_Ts_21 "LEMS发送的SBMU号";
CM_ SG_ 2332115109 L2S_SUMDATA1_Confidence_21 "LEMS向SBMU发送的置信度";
CM_ SG_ 2332115109 L2S_SUMDATA1_Value_21 "LEMS向SBMU发送的计算结果";
CM_ SG_ 2332115110 L2S_SUMDATA1_Yesr_22 "LEMS发送的算法计算时间-年";
CM_ SG_ 2332115110 L2S_SUMDATA1_Month_22 "LEMS发送的算法计算时间-月";
CM_ SG_ 2332115110 L2S_SUMDATA1_Day_Ts_22 "LEMS发送的算法计算时间-日";
CM_ SG_ 2332115110 L2S_SUMDATA1_Hour_Ts_22 "LEMS发送的算法计算时间-时";
CM_ SG_ 2332115110 L2S_SUMDATA1_MInute_Ts_22 "LEMS发送的算法计算时间-分";
CM_ SG_ 2332115110 L2S_SUMDATA1_Second_Ts_22 "LEMS发送的算法计算时间-秒";
CM_ SG_ 2332115110 L2S_SUMDATA1_SBMUnumber_Ts_22 "LEMS发送的SBMU号";
CM_ SG_ 2332115110 L2S_SUMDATA1_Confidence_22 "LEMS向SBMU发送的置信度";
CM_ SG_ 2332115110 L2S_SUMDATA1_Value_22 "LEMS向SBMU发送的计算结果";
CM_ SG_ 2332115111 L2S_SUMDATA1_Yesr_23 "LEMS发送的算法计算时间-年";
CM_ SG_ 2332115111 L2S_SUMDATA1_Month_23 "LEMS发送的算法计算时间-月";
CM_ SG_ 2332115111 L2S_SUMDATA1_Day_Ts_23 "LEMS发送的算法计算时间-日";
CM_ SG_ 2332115111 L2S_SUMDATA1_Hour_Ts_23 "LEMS发送的算法计算时间-时";
CM_ SG_ 2332115111 L2S_SUMDATA1_MInute_Ts_23 "LEMS发送的算法计算时间-分";
CM_ SG_ 2332115111 L2S_SUMDATA1_Second_Ts_23 "LEMS发送的算法计算时间-秒";
CM_ SG_ 2332115111 L2S_SUMDATA1_SBMUnumber_Ts_23 "LEMS发送的SBMU号";
CM_ SG_ 2332115111 L2S_SUMDATA1_Confidence_23 "LEMS向SBMU发送的置信度";
CM_ SG_ 2332115111 L2S_SUMDATA1_Value_23 "LEMS向SBMU发送的计算结果";
CM_ SG_ 2332115112 L2S_SUMDATA1_Yesr_24 "LEMS发送的算法计算时间-年";
CM_ SG_ 2332115112 L2S_SUMDATA1_Month_24 "LEMS发送的算法计算时间-月";
CM_ SG_ 2332115112 L2S_SUMDATA1_Day_Ts_24 "LEMS发送的算法计算时间-日";
CM_ SG_ 2332115112 L2S_SUMDATA1_Hour_Ts_24 "LEMS发送的算法计算时间-时";
CM_ SG_ 2332115112 L2S_SUMDATA1_MInute_Ts_24 "LEMS发送的算法计算时间-分";
CM_ SG_ 2332115112 L2S_SUMDATA1_Second_Ts_24 "LEMS发送的算法计算时间-秒";
CM_ SG_ 2332115112 L2S_SUMDATA1_SBMUnumber_Ts_24 "LEMS发送的SBMU号";
CM_ SG_ 2332115112 L2S_SUMDATA1_Confidence_24 "LEMS向SBMU发送的置信度";
CM_ SG_ 2332115112 L2S_SUMDATA1_Value_24 "LEMS向SBMU发送的计算结果";
CM_ SG_ 2332115113 L2S_SUMDATA1_Yesr_25 "LEMS发送的算法计算时间-年";
CM_ SG_ 2332115113 L2S_SUMDATA1_Month_25 "LEMS发送的算法计算时间-月";
CM_ SG_ 2332115113 L2S_SUMDATA1_Day_Ts_25 "LEMS发送的算法计算时间-日";
CM_ SG_ 2332115113 L2S_SUMDATA1_Hour_Ts_25 "LEMS发送的算法计算时间-时";
CM_ SG_ 2332115113 L2S_SUMDATA1_MInute_Ts_25 "LEMS发送的算法计算时间-分";
CM_ SG_ 2332115113 L2S_SUMDATA1_Second_Ts_25 "LEMS发送的算法计算时间-秒";
CM_ SG_ 2332115113 L2S_SUMDATA1_SBMUnumber_Ts_25 "LEMS发送的SBMU号";
CM_ SG_ 2332115113 L2S_SUMDATA1_Confidence_25 "LEMS向SBMU发送的置信度";
CM_ SG_ 2332115113 L2S_SUMDATA1_Value_25 "LEMS向SBMU发送的计算结果";
CM_ SG_ 2332115114 L2S_SUMDATA1_Yesr_26 "LEMS发送的算法计算时间-年";
CM_ SG_ 2332115114 L2S_SUMDATA1_Month_26 "LEMS发送的算法计算时间-月";
CM_ SG_ 2332115114 L2S_SUMDATA1_Day_Ts_26 "LEMS发送的算法计算时间-日";
CM_ SG_ 2332115114 L2S_SUMDATA1_Hour_Ts_26 "LEMS发送的算法计算时间-时";
CM_ SG_ 2332115114 L2S_SUMDATA1_MInute_Ts_26 "LEMS发送的算法计算时间-分";
CM_ SG_ 2332115114 L2S_SUMDATA1_Second_Ts_26 "LEMS发送的算法计算时间-秒";
CM_ SG_ 2332115114 L2S_SUMDATA1_SBMUnumber_Ts_26 "LEMS发送的SBMU号";
CM_ SG_ 2332115114 L2S_SUMDATA1_Confidence_26 "LEMS向SBMU发送的置信度";
CM_ SG_ 2332115114 L2S_SUMDATA1_Value_26 "LEMS向SBMU发送的计算结果";
CM_ SG_ 2332115115 L2S_SUMDATA1_Yesr_27 "LEMS发送的算法计算时间-年";
CM_ SG_ 2332115115 L2S_SUMDATA1_Month_27 "LEMS发送的算法计算时间-月";
CM_ SG_ 2332115115 L2S_SUMDATA1_Day_Ts_27 "LEMS发送的算法计算时间-日";
CM_ SG_ 2332115115 L2S_SUMDATA1_Hour_Ts_27 "LEMS发送的算法计算时间-时";
CM_ SG_ 2332115115 L2S_SUMDATA1_MInute_Ts_27 "LEMS发送的算法计算时间-分";
CM_ SG_ 2332115115 L2S_SUMDATA1_Second_Ts_27 "LEMS发送的算法计算时间-秒";
CM_ SG_ 2332115115 L2S_SUMDATA1_SBMUnumber_Ts_27 "LEMS发送的SBMU号";
CM_ SG_ 2332115115 L2S_SUMDATA1_Confidence_27 "LEMS向SBMU发送的置信度";
CM_ SG_ 2332115115 L2S_SUMDATA1_Value_27 "LEMS向SBMU发送的计算结果";
CM_ SG_ 2332115116 L2S_SUMDATA1_Yesr_28 "LEMS发送的算法计算时间-年";
CM_ SG_ 2332115116 L2S_SUMDATA1_Month_28 "LEMS发送的算法计算时间-月";
CM_ SG_ 2332115116 L2S_SUMDATA1_Day_Ts_28 "LEMS发送的算法计算时间-日";
CM_ SG_ 2332115116 L2S_SUMDATA1_Hour_Ts_28 "LEMS发送的算法计算时间-时";
CM_ SG_ 2332115116 L2S_SUMDATA1_MInute_Ts_28 "LEMS发送的算法计算时间-分";
CM_ SG_ 2332115116 L2S_SUMDATA1_Second_Ts_28 "LEMS发送的算法计算时间-秒";
CM_ SG_ 2332115116 L2S_SUMDATA1_SBMUnumber_Ts_28 "LEMS发送的SBMU号";
CM_ SG_ 2332115116 L2S_SUMDATA1_Confidence_28 "LEMS向SBMU发送的置信度";
CM_ SG_ 2332115116 L2S_SUMDATA1_Value_28 "LEMS向SBMU发送的计算结果";
CM_ SG_ 2332115117 L2S_SUMDATA1_Yesr_29 "LEMS发送的算法计算时间-年";
CM_ SG_ 2332115117 L2S_SUMDATA1_Month_29 "LEMS发送的算法计算时间-月";
CM_ SG_ 2332115117 L2S_SUMDATA1_Day_Ts_29 "LEMS发送的算法计算时间-日";
CM_ SG_ 2332115117 L2S_SUMDATA1_Hour_Ts_29 "LEMS发送的算法计算时间-时";
CM_ SG_ 2332115117 L2S_SUMDATA1_MInute_Ts_29 "LEMS发送的算法计算时间-分";
CM_ SG_ 2332115117 L2S_SUMDATA1_Second_Ts_29 "LEMS发送的算法计算时间-秒";
CM_ SG_ 2332115117 L2S_SUMDATA1_SBMUnumber_Ts_29 "LEMS发送的SBMU号";
CM_ SG_ 2332115117 L2S_SUMDATA1_Confidence_29 "LEMS向SBMU发送的置信度";
CM_ SG_ 2332115117 L2S_SUMDATA1_Value_29 "LEMS向SBMU发送的计算结果";
CM_ SG_ 2332115118 L2S_SUMDATA1_Yesr_30 "LEMS发送的算法计算时间-年";
CM_ SG_ 2332115118 L2S_SUMDATA1_Month_30 "LEMS发送的算法计算时间-月";
CM_ SG_ 2332115118 L2S_SUMDATA1_Day_Ts_30 "LEMS发送的算法计算时间-日";
CM_ SG_ 2332115118 L2S_SUMDATA1_Hour_Ts_30 "LEMS发送的算法计算时间-时";
CM_ SG_ 2332115118 L2S_SUMDATA1_MInute_Ts_30 "LEMS发送的算法计算时间-分";
CM_ SG_ 2332115118 L2S_SUMDATA1_Second_Ts_30 "LEMS发送的算法计算时间-秒";
CM_ SG_ 2332115118 L2S_SUMDATA1_SBMUnumber_Ts_30 "LEMS发送的SBMU号";
CM_ SG_ 2332115118 L2S_SUMDATA1_Confidence_30 "LEMS向SBMU发送的置信度";
CM_ SG_ 2332115118 L2S_SUMDATA1_Value_30 "LEMS向SBMU发送的计算结果";
CM_ SG_ 2332115119 L2S_SUMDATA1_Yesr_31 "LEMS发送的算法计算时间-年";
CM_ SG_ 2332115119 L2S_SUMDATA1_Month_31 "LEMS发送的算法计算时间-月";
CM_ SG_ 2332115119 L2S_SUMDATA1_Day_Ts_31 "LEMS发送的算法计算时间-日";
CM_ SG_ 2332115119 L2S_SUMDATA1_Hour_Ts_31 "LEMS发送的算法计算时间-时";
CM_ SG_ 2332115119 L2S_SUMDATA1_MInute_Ts_31 "LEMS发送的算法计算时间-分";
CM_ SG_ 2332115119 L2S_SUMDATA1_Second_Ts_31 "LEMS发送的算法计算时间-秒";
CM_ SG_ 2332115119 L2S_SUMDATA1_SBMUnumber_Ts_31 "LEMS发送的SBMU号";
CM_ SG_ 2332115119 L2S_SUMDATA1_Confidence_31 "LEMS向SBMU发送的置信度";
CM_ SG_ 2332115119 L2S_SUMDATA1_Value_31 "LEMS向SBMU发送的计算结果";
CM_ SG_ 2334392129 CRC_S2A_S23_01 "S2A概要数据3 的CRC";
CM_ SG_ 2334392129 BAT_Ucell_Max_CSC_104S_01 "最高单体电压所在CSC号(当前最大支持31个)从1开始";
CM_ SG_ 2334392129 BAT_Ucell_Max_CELL_104S_01 "最高单体电压所在电芯位置（当前最大位号108）从1开始";
CM_ SG_ 2334392129 BAT_Ucell_Min_CSC_104S_01 "最低单体电压所在CSC号(当前最大支持个数31个)从1开始";
CM_ SG_ 2334392129 BAT_Ucell_Min_CELL_104S_01 "最低单体电压所在电芯位置（当前最大位号108）从1开始";
CM_ SG_ 2334392129 BAT_Ucell_Max_104S_01 "最高单体电压";
CM_ SG_ 2334392129 BAT_Ucell_Min_104S_01 "最低单体电压";
CM_ SG_ 2334392130 CRC_S2A_S23_02 "S2A概要数据3 的CRC";
CM_ SG_ 2334392130 BAT_Ucell_Max_CSC_104S_02 "最高单体电压所在CSC号(当前最大支持31个)从1开始";
CM_ SG_ 2334392130 BAT_Ucell_Max_CELL_104S_02 "最高单体电压所在电芯位置（当前最大位号108）从1开始";
CM_ SG_ 2334392130 BAT_Ucell_Min_CSC_104S_02 "最低单体电压所在CSC号(当前最大支持个数31个)从1开始";
CM_ SG_ 2334392130 BAT_Ucell_Min_CELL_104S_02 "最低单体电压所在电芯位置（当前最大位号108）从1开始";
CM_ SG_ 2334392130 BAT_Ucell_Max_104S_02 "最高单体电压";
CM_ SG_ 2334392130 BAT_Ucell_Min_104S_02 "最低单体电压";
CM_ SG_ 2334392131 CRC_S2A_S23_03 "S2A概要数据3 的CRC";
CM_ SG_ 2334392131 BAT_Ucell_Max_CSC_104S_03 "最高单体电压所在CSC号(当前最大支持31个)从1开始";
CM_ SG_ 2334392131 BAT_Ucell_Max_CELL_104S_03 "最高单体电压所在电芯位置（当前最大位号108）从1开始";
CM_ SG_ 2334392131 BAT_Ucell_Min_CSC_104S_03 "最低单体电压所在CSC号(当前最大支持个数31个)从1开始";
CM_ SG_ 2334392131 BAT_Ucell_Min_CELL_104S_03 "最低单体电压所在电芯位置（当前最大位号108）从1开始";
CM_ SG_ 2334392131 BAT_Ucell_Max_104S_03 "最高单体电压";
CM_ SG_ 2334392131 BAT_Ucell_Min_104S_03 "最低单体电压";
CM_ SG_ 2334392132 CRC_S2A_S23_04 "S2A概要数据3 的CRC";
CM_ SG_ 2334392132 BAT_Ucell_Max_CSC_104S_04 "最高单体电压所在CSC号(当前最大支持31个)从1开始";
CM_ SG_ 2334392132 BAT_Ucell_Max_CELL_104S_04 "最高单体电压所在电芯位置（当前最大位号108）从1开始";
CM_ SG_ 2334392132 BAT_Ucell_Min_CSC_104S_04 "最低单体电压所在CSC号(当前最大支持个数31个)从1开始";
CM_ SG_ 2334392132 BAT_Ucell_Min_CELL_104S_04 "最低单体电压所在电芯位置（当前最大位号108）从1开始";
CM_ SG_ 2334392132 BAT_Ucell_Max_104S_04 "最高单体电压";
CM_ SG_ 2334392132 BAT_Ucell_Min_104S_04 "最低单体电压";
CM_ SG_ 2334392133 CRC_S2A_S23_05 "S2A概要数据3 的CRC";
CM_ SG_ 2334392133 BAT_Ucell_Max_CSC_104S_05 "最高单体电压所在CSC号(当前最大支持31个)从1开始";
CM_ SG_ 2334392133 BAT_Ucell_Max_CELL_104S_05 "最高单体电压所在电芯位置（当前最大位号108）从1开始";
CM_ SG_ 2334392133 BAT_Ucell_Min_CSC_104S_05 "最低单体电压所在CSC号(当前最大支持个数31个)从1开始";
CM_ SG_ 2334392133 BAT_Ucell_Min_CELL_104S_05 "最低单体电压所在电芯位置（当前最大位号108）从1开始";
CM_ SG_ 2334392133 BAT_Ucell_Max_104S_05 "最高单体电压";
CM_ SG_ 2334392133 BAT_Ucell_Min_104S_05 "最低单体电压";
CM_ SG_ 2334392134 CRC_S2A_S23_06 "S2A概要数据3 的CRC";
CM_ SG_ 2334392134 BAT_Ucell_Max_CSC_104S_06 "最高单体电压所在CSC号(当前最大支持31个)从1开始";
CM_ SG_ 2334392134 BAT_Ucell_Max_CELL_104S_06 "最高单体电压所在电芯位置（当前最大位号108）从1开始";
CM_ SG_ 2334392134 BAT_Ucell_Min_CSC_104S_06 "最低单体电压所在CSC号(当前最大支持个数31个)从1开始";
CM_ SG_ 2334392134 BAT_Ucell_Min_CELL_104S_06 "最低单体电压所在电芯位置（当前最大位号108）从1开始";
CM_ SG_ 2334392134 BAT_Ucell_Max_104S_06 "最高单体电压";
CM_ SG_ 2334392134 BAT_Ucell_Min_104S_06 "最低单体电压";
CM_ SG_ 2334392135 CRC_S2A_S23_07 "S2A概要数据3 的CRC";
CM_ SG_ 2334392135 BAT_Ucell_Max_CSC_104S_07 "最高单体电压所在CSC号(当前最大支持31个)从1开始";
CM_ SG_ 2334392135 BAT_Ucell_Max_CELL_104S_07 "最高单体电压所在电芯位置（当前最大位号108）从1开始";
CM_ SG_ 2334392135 BAT_Ucell_Min_CSC_104S_07 "最低单体电压所在CSC号(当前最大支持个数31个)从1开始";
CM_ SG_ 2334392135 BAT_Ucell_Min_CELL_104S_07 "最低单体电压所在电芯位置（当前最大位号108）从1开始";
CM_ SG_ 2334392135 BAT_Ucell_Max_104S_07 "最高单体电压";
CM_ SG_ 2334392135 BAT_Ucell_Min_104S_07 "最低单体电压";
CM_ SG_ 2334392136 CRC_S2A_S23_08 "S2A概要数据3 的CRC";
CM_ SG_ 2334392136 BAT_Ucell_Max_CSC_104S_08 "最高单体电压所在CSC号(当前最大支持31个)从1开始";
CM_ SG_ 2334392136 BAT_Ucell_Max_CELL_104S_08 "最高单体电压所在电芯位置（当前最大位号108）从1开始";
CM_ SG_ 2334392136 BAT_Ucell_Min_CSC_104S_08 "最低单体电压所在CSC号(当前最大支持个数31个)从1开始";
CM_ SG_ 2334392136 BAT_Ucell_Min_CELL_104S_08 "最低单体电压所在电芯位置（当前最大位号108）从1开始";
CM_ SG_ 2334392136 BAT_Ucell_Max_104S_08 "最高单体电压";
CM_ SG_ 2334392136 BAT_Ucell_Min_104S_08 "最低单体电压";
CM_ SG_ 2334392137 CRC_S2A_S23_09 "S2A概要数据3 的CRC";
CM_ SG_ 2334392137 BAT_Ucell_Max_CSC_104S_09 "最高单体电压所在CSC号(当前最大支持31个)从1开始";
CM_ SG_ 2334392137 BAT_Ucell_Max_CELL_104S_09 "最高单体电压所在电芯位置（当前最大位号108）从1开始";
CM_ SG_ 2334392137 BAT_Ucell_Min_CSC_104S_09 "最低单体电压所在CSC号(当前最大支持个数31个)从1开始";
CM_ SG_ 2334392137 BAT_Ucell_Min_CELL_104S_09 "最低单体电压所在电芯位置（当前最大位号108）从1开始";
CM_ SG_ 2334392137 BAT_Ucell_Max_104S_09 "最高单体电压";
CM_ SG_ 2334392137 BAT_Ucell_Min_104S_09 "最低单体电压";
CM_ SG_ 2334392138 CRC_S2A_S23_10 "S2A概要数据3 的CRC";
CM_ SG_ 2334392138 BAT_Ucell_Max_CSC_104S_10 "最高单体电压所在CSC号(当前最大支持31个)从1开始";
CM_ SG_ 2334392138 BAT_Ucell_Max_CELL_104S_10 "最高单体电压所在电芯位置（当前最大位号108）从1开始";
CM_ SG_ 2334392138 BAT_Ucell_Min_CSC_104S_10 "最低单体电压所在CSC号(当前最大支持个数31个)从1开始";
CM_ SG_ 2334392138 BAT_Ucell_Min_CELL_104S_10 "最低单体电压所在电芯位置（当前最大位号108）从1开始";
CM_ SG_ 2334392138 BAT_Ucell_Max_104S_10 "最高单体电压";
CM_ SG_ 2334392138 BAT_Ucell_Min_104S_10 "最低单体电压";
CM_ SG_ 2334392139 CRC_S2A_S23_11 "S2A概要数据3 的CRC";
CM_ SG_ 2334392139 BAT_Ucell_Max_CSC_104S_11 "最高单体电压所在CSC号(当前最大支持31个)从1开始";
CM_ SG_ 2334392139 BAT_Ucell_Max_CELL_104S_11 "最高单体电压所在电芯位置（当前最大位号108）从1开始";
CM_ SG_ 2334392139 BAT_Ucell_Min_CSC_104S_11 "最低单体电压所在CSC号(当前最大支持个数31个)从1开始";
CM_ SG_ 2334392139 BAT_Ucell_Min_CELL_104S_11 "最低单体电压所在电芯位置（当前最大位号108）从1开始";
CM_ SG_ 2334392139 BAT_Ucell_Max_104S_11 "最高单体电压";
CM_ SG_ 2334392139 BAT_Ucell_Min_104S_11 "最低单体电压";
CM_ SG_ 2334392140 CRC_S2A_S23_12 "S2A概要数据3 的CRC";
CM_ SG_ 2334392140 BAT_Ucell_Max_CSC_104S_12 "最高单体电压所在CSC号(当前最大支持31个)从1开始";
CM_ SG_ 2334392140 BAT_Ucell_Max_CELL_104S_12 "最高单体电压所在电芯位置（当前最大位号108）从1开始";
CM_ SG_ 2334392140 BAT_Ucell_Min_CSC_104S_12 "最低单体电压所在CSC号(当前最大支持个数31个)从1开始";
CM_ SG_ 2334392140 BAT_Ucell_Min_CELL_104S_12 "最低单体电压所在电芯位置（当前最大位号108）从1开始";
CM_ SG_ 2334392140 BAT_Ucell_Max_104S_12 "最高单体电压";
CM_ SG_ 2334392140 BAT_Ucell_Min_104S_12 "最低单体电压";
CM_ SG_ 2334392141 CRC_S2A_S23_13 "S2A概要数据3 的CRC";
CM_ SG_ 2334392141 BAT_Ucell_Max_CSC_104S_13 "最高单体电压所在CSC号(当前最大支持31个)从1开始";
CM_ SG_ 2334392141 BAT_Ucell_Max_CELL_104S_13 "最高单体电压所在电芯位置（当前最大位号108）从1开始";
CM_ SG_ 2334392141 BAT_Ucell_Min_CSC_104S_13 "最低单体电压所在CSC号(当前最大支持个数31个)从1开始";
CM_ SG_ 2334392141 BAT_Ucell_Min_CELL_104S_13 "最低单体电压所在电芯位置（当前最大位号108）从1开始";
CM_ SG_ 2334392141 BAT_Ucell_Max_104S_13 "最高单体电压";
CM_ SG_ 2334392141 BAT_Ucell_Min_104S_13 "最低单体电压";
CM_ SG_ 2334392142 CRC_S2A_S23_14 "S2A概要数据3 的CRC";
CM_ SG_ 2334392142 BAT_Ucell_Max_CSC_104S_14 "最高单体电压所在CSC号(当前最大支持31个)从1开始";
CM_ SG_ 2334392142 BAT_Ucell_Max_CELL_104S_14 "最高单体电压所在电芯位置（当前最大位号108）从1开始";
CM_ SG_ 2334392142 BAT_Ucell_Min_CSC_104S_14 "最低单体电压所在CSC号(当前最大支持个数31个)从1开始";
CM_ SG_ 2334392142 BAT_Ucell_Min_CELL_104S_14 "最低单体电压所在电芯位置（当前最大位号108）从1开始";
CM_ SG_ 2334392142 BAT_Ucell_Max_104S_14 "最高单体电压";
CM_ SG_ 2334392142 BAT_Ucell_Min_104S_14 "最低单体电压";
CM_ SG_ 2334392143 CRC_S2A_S23_15 "S2A概要数据3 的CRC";
CM_ SG_ 2334392143 BAT_Ucell_Max_CSC_104S_15 "最高单体电压所在CSC号(当前最大支持31个)从1开始";
CM_ SG_ 2334392143 BAT_Ucell_Max_CELL_104S_15 "最高单体电压所在电芯位置（当前最大位号108）从1开始";
CM_ SG_ 2334392143 BAT_Ucell_Min_CSC_104S_15 "最低单体电压所在CSC号(当前最大支持个数31个)从1开始";
CM_ SG_ 2334392143 BAT_Ucell_Min_CELL_104S_15 "最低单体电压所在电芯位置（当前最大位号108）从1开始";
CM_ SG_ 2334392143 BAT_Ucell_Max_104S_15 "最高单体电压";
CM_ SG_ 2334392143 BAT_Ucell_Min_104S_15 "最低单体电压";
CM_ SG_ 2334392144 CRC_S2A_S23_16 "S2A概要数据3 的CRC";
CM_ SG_ 2334392144 BAT_Ucell_Max_CSC_104S_16 "最高单体电压所在CSC号(当前最大支持31个)从1开始";
CM_ SG_ 2334392144 BAT_Ucell_Max_CELL_104S_16 "最高单体电压所在电芯位置（当前最大位号108）从1开始";
CM_ SG_ 2334392144 BAT_Ucell_Min_CSC_104S_16 "最低单体电压所在CSC号(当前最大支持个数31个)从1开始";
CM_ SG_ 2334392144 BAT_Ucell_Min_CELL_104S_16 "最低单体电压所在电芯位置（当前最大位号108）从1开始";
CM_ SG_ 2334392144 BAT_Ucell_Max_104S_16 "最高单体电压";
CM_ SG_ 2334392144 BAT_Ucell_Min_104S_16 "最低单体电压";
CM_ SG_ 2334392145 CRC_S2A_S23_17 "S2A概要数据3 的CRC";
CM_ SG_ 2334392145 BAT_Ucell_Max_CSC_104S_17 "最高单体电压所在CSC号(当前最大支持31个)从1开始";
CM_ SG_ 2334392145 BAT_Ucell_Max_CELL_104S_17 "最高单体电压所在电芯位置（当前最大位号108）从1开始";
CM_ SG_ 2334392145 BAT_Ucell_Min_CSC_104S_17 "最低单体电压所在CSC号(当前最大支持个数31个)从1开始";
CM_ SG_ 2334392145 BAT_Ucell_Min_CELL_104S_17 "最低单体电压所在电芯位置（当前最大位号108）从1开始";
CM_ SG_ 2334392145 BAT_Ucell_Max_104S_17 "最高单体电压";
CM_ SG_ 2334392145 BAT_Ucell_Min_104S_17 "最低单体电压";
CM_ SG_ 2334392146 CRC_S2A_S23_18 "S2A概要数据3 的CRC";
CM_ SG_ 2334392146 BAT_Ucell_Max_CSC_104S_18 "最高单体电压所在CSC号(当前最大支持31个)从1开始";
CM_ SG_ 2334392146 BAT_Ucell_Max_CELL_104S_18 "最高单体电压所在电芯位置（当前最大位号108）从1开始";
CM_ SG_ 2334392146 BAT_Ucell_Min_CSC_104S_18 "最低单体电压所在CSC号(当前最大支持个数31个)从1开始";
CM_ SG_ 2334392146 BAT_Ucell_Min_CELL_104S_18 "最低单体电压所在电芯位置（当前最大位号108）从1开始";
CM_ SG_ 2334392146 BAT_Ucell_Max_104S_18 "最高单体电压";
CM_ SG_ 2334392146 BAT_Ucell_Min_104S_18 "最低单体电压";
CM_ SG_ 2334392147 CRC_S2A_S23_19 "S2A概要数据3 的CRC";
CM_ SG_ 2334392147 BAT_Ucell_Max_CSC_104S_19 "最高单体电压所在CSC号(当前最大支持31个)从1开始";
CM_ SG_ 2334392147 BAT_Ucell_Max_CELL_104S_19 "最高单体电压所在电芯位置（当前最大位号108）从1开始";
CM_ SG_ 2334392147 BAT_Ucell_Min_CSC_104S_19 "最低单体电压所在CSC号(当前最大支持个数31个)从1开始";
CM_ SG_ 2334392147 BAT_Ucell_Min_CELL_104S_19 "最低单体电压所在电芯位置（当前最大位号108）从1开始";
CM_ SG_ 2334392147 BAT_Ucell_Max_104S_19 "最高单体电压";
CM_ SG_ 2334392147 BAT_Ucell_Min_104S_19 "最低单体电压";
CM_ SG_ 2334392148 CRC_S2A_S23_20 "S2A概要数据3 的CRC";
CM_ SG_ 2334392148 BAT_Ucell_Max_CSC_104S_20 "最高单体电压所在CSC号(当前最大支持31个)从1开始";
CM_ SG_ 2334392148 BAT_Ucell_Max_CELL_104S_20 "最高单体电压所在电芯位置（当前最大位号108）从1开始";
CM_ SG_ 2334392148 BAT_Ucell_Min_CSC_104S_20 "最低单体电压所在CSC号(当前最大支持个数31个)从1开始";
CM_ SG_ 2334392148 BAT_Ucell_Min_CELL_104S_20 "最低单体电压所在电芯位置（当前最大位号108）从1开始";
CM_ SG_ 2334392148 BAT_Ucell_Max_104S_20 "最高单体电压";
CM_ SG_ 2334392148 BAT_Ucell_Min_104S_20 "最低单体电压";
CM_ SG_ 2334392149 CRC_S2A_S23_21 "S2A概要数据3 的CRC";
CM_ SG_ 2334392149 BAT_Ucell_Max_CSC_104S_21 "最高单体电压所在CSC号(当前最大支持31个)从1开始";
CM_ SG_ 2334392149 BAT_Ucell_Max_CELL_104S_21 "最高单体电压所在电芯位置（当前最大位号108）从1开始";
CM_ SG_ 2334392149 BAT_Ucell_Min_CSC_104S_21 "最低单体电压所在CSC号(当前最大支持个数31个)从1开始";
CM_ SG_ 2334392149 BAT_Ucell_Min_CELL_104S_21 "最低单体电压所在电芯位置（当前最大位号108）从1开始";
CM_ SG_ 2334392149 BAT_Ucell_Max_104S_21 "最高单体电压";
CM_ SG_ 2334392149 BAT_Ucell_Min_104S_21 "最低单体电压";
CM_ SG_ 2334392150 CRC_S2A_S23_22 "S2A概要数据3 的CRC";
CM_ SG_ 2334392150 BAT_Ucell_Max_CSC_104S_22 "最高单体电压所在CSC号(当前最大支持31个)从1开始";
CM_ SG_ 2334392150 BAT_Ucell_Max_CELL_104S_22 "最高单体电压所在电芯位置（当前最大位号108）从1开始";
CM_ SG_ 2334392150 BAT_Ucell_Min_CSC_104S_22 "最低单体电压所在CSC号(当前最大支持个数31个)从1开始";
CM_ SG_ 2334392150 BAT_Ucell_Min_CELL_104S_22 "最低单体电压所在电芯位置（当前最大位号108）从1开始";
CM_ SG_ 2334392150 BAT_Ucell_Max_104S_22 "最高单体电压";
CM_ SG_ 2334392150 BAT_Ucell_Min_104S_22 "最低单体电压";
CM_ SG_ 2334392151 CRC_S2A_S23_23 "S2A概要数据3 的CRC";
CM_ SG_ 2334392151 BAT_Ucell_Max_CSC_104S_23 "最高单体电压所在CSC号(当前最大支持31个)从1开始";
CM_ SG_ 2334392151 BAT_Ucell_Max_CELL_104S_23 "最高单体电压所在电芯位置（当前最大位号108）从1开始";
CM_ SG_ 2334392151 BAT_Ucell_Min_CSC_104S_23 "最低单体电压所在CSC号(当前最大支持个数31个)从1开始";
CM_ SG_ 2334392151 BAT_Ucell_Min_CELL_104S_23 "最低单体电压所在电芯位置（当前最大位号108）从1开始";
CM_ SG_ 2334392151 BAT_Ucell_Max_104S_23 "最高单体电压";
CM_ SG_ 2334392151 BAT_Ucell_Min_104S_23 "最低单体电压";
CM_ SG_ 2334392152 CRC_S2A_S23_24 "S2A概要数据3 的CRC";
CM_ SG_ 2334392152 BAT_Ucell_Max_CSC_104S_24 "最高单体电压所在CSC号(当前最大支持31个)从1开始";
CM_ SG_ 2334392152 BAT_Ucell_Max_CELL_104S_24 "最高单体电压所在电芯位置（当前最大位号108）从1开始";
CM_ SG_ 2334392152 BAT_Ucell_Min_CSC_104S_24 "最低单体电压所在CSC号(当前最大支持个数31个)从1开始";
CM_ SG_ 2334392152 BAT_Ucell_Min_CELL_104S_24 "最低单体电压所在电芯位置（当前最大位号108）从1开始";
CM_ SG_ 2334392152 BAT_Ucell_Max_104S_24 "最高单体电压";
CM_ SG_ 2334392152 BAT_Ucell_Min_104S_24 "最低单体电压";
CM_ SG_ 2334392153 CRC_S2A_S23_25 "S2A概要数据3 的CRC";
CM_ SG_ 2334392153 BAT_Ucell_Max_CSC_104S_25 "最高单体电压所在CSC号(当前最大支持31个)从1开始";
CM_ SG_ 2334392153 BAT_Ucell_Max_CELL_104S_25 "最高单体电压所在电芯位置（当前最大位号108）从1开始";
CM_ SG_ 2334392153 BAT_Ucell_Min_CSC_104S_25 "最低单体电压所在CSC号(当前最大支持个数31个)从1开始";
CM_ SG_ 2334392153 BAT_Ucell_Min_CELL_104S_25 "最低单体电压所在电芯位置（当前最大位号108）从1开始";
CM_ SG_ 2334392153 BAT_Ucell_Max_104S_25 "最高单体电压";
CM_ SG_ 2334392153 BAT_Ucell_Min_104S_25 "最低单体电压";
CM_ SG_ 2334392154 CRC_S2A_S23_26 "S2A概要数据3 的CRC";
CM_ SG_ 2334392154 BAT_Ucell_Max_CSC_104S_26 "最高单体电压所在CSC号(当前最大支持31个)从1开始";
CM_ SG_ 2334392154 BAT_Ucell_Max_CELL_104S_26 "最高单体电压所在电芯位置（当前最大位号108）从1开始";
CM_ SG_ 2334392154 BAT_Ucell_Min_CSC_104S_26 "最低单体电压所在CSC号(当前最大支持个数31个)从1开始";
CM_ SG_ 2334392154 BAT_Ucell_Min_CELL_104S_26 "最低单体电压所在电芯位置（当前最大位号108）从1开始";
CM_ SG_ 2334392154 BAT_Ucell_Max_104S_26 "最高单体电压";
CM_ SG_ 2334392154 BAT_Ucell_Min_104S_26 "最低单体电压";
CM_ SG_ 2334392155 CRC_S2A_S23_27 "S2A概要数据3 的CRC";
CM_ SG_ 2334392155 BAT_Ucell_Max_CSC_104S_27 "最高单体电压所在CSC号(当前最大支持31个)从1开始";
CM_ SG_ 2334392155 BAT_Ucell_Max_CELL_104S_27 "最高单体电压所在电芯位置（当前最大位号108）从1开始";
CM_ SG_ 2334392155 BAT_Ucell_Min_CSC_104S_27 "最低单体电压所在CSC号(当前最大支持个数31个)从1开始";
CM_ SG_ 2334392155 BAT_Ucell_Min_CELL_104S_27 "最低单体电压所在电芯位置（当前最大位号108）从1开始";
CM_ SG_ 2334392155 BAT_Ucell_Max_104S_27 "最高单体电压";
CM_ SG_ 2334392155 BAT_Ucell_Min_104S_27 "最低单体电压";
CM_ SG_ 2334392156 CRC_S2A_S23_28 "S2A概要数据3 的CRC";
CM_ SG_ 2334392156 BAT_Ucell_Max_CSC_104S_28 "最高单体电压所在CSC号(当前最大支持31个)从1开始";
CM_ SG_ 2334392156 BAT_Ucell_Max_CELL_104S_28 "最高单体电压所在电芯位置（当前最大位号108）从1开始";
CM_ SG_ 2334392156 BAT_Ucell_Min_CSC_104S_28 "最低单体电压所在CSC号(当前最大支持个数31个)从1开始";
CM_ SG_ 2334392156 BAT_Ucell_Min_CELL_104S_28 "最低单体电压所在电芯位置（当前最大位号108）从1开始";
CM_ SG_ 2334392156 BAT_Ucell_Max_104S_28 "最高单体电压";
CM_ SG_ 2334392156 BAT_Ucell_Min_104S_28 "最低单体电压";
CM_ SG_ 2334392157 CRC_S2A_S23_29 "S2A概要数据3 的CRC";
CM_ SG_ 2334392157 BAT_Ucell_Max_CSC_104S_29 "最高单体电压所在CSC号(当前最大支持31个)从1开始";
CM_ SG_ 2334392157 BAT_Ucell_Max_CELL_104S_29 "最高单体电压所在电芯位置（当前最大位号108）从1开始";
CM_ SG_ 2334392157 BAT_Ucell_Min_CSC_104S_29 "最低单体电压所在CSC号(当前最大支持个数31个)从1开始";
CM_ SG_ 2334392157 BAT_Ucell_Min_CELL_104S_29 "最低单体电压所在电芯位置（当前最大位号108）从1开始";
CM_ SG_ 2334392157 BAT_Ucell_Max_104S_29 "最高单体电压";
CM_ SG_ 2334392157 BAT_Ucell_Min_104S_29 "最低单体电压";
CM_ SG_ 2334392158 CRC_S2A_S23_30 "S2A概要数据3 的CRC";
CM_ SG_ 2334392158 BAT_Ucell_Max_CSC_104S_30 "最高单体电压所在CSC号(当前最大支持31个)从1开始";
CM_ SG_ 2334392158 BAT_Ucell_Max_CELL_104S_30 "最高单体电压所在电芯位置（当前最大位号108）从1开始";
CM_ SG_ 2334392158 BAT_Ucell_Min_CSC_104S_30 "最低单体电压所在CSC号(当前最大支持个数31个)从1开始";
CM_ SG_ 2334392158 BAT_Ucell_Min_CELL_104S_30 "最低单体电压所在电芯位置（当前最大位号108）从1开始";
CM_ SG_ 2334392158 BAT_Ucell_Max_104S_30 "最高单体电压";
CM_ SG_ 2334392158 BAT_Ucell_Min_104S_30 "最低单体电压";
CM_ SG_ 2334392159 CRC_S2A_S23_31 "S2A概要数据3 的CRC";
CM_ SG_ 2334392159 BAT_Ucell_Max_CSC_104S_31 "最高单体电压所在CSC号(当前最大支持31个)从1开始";
CM_ SG_ 2334392159 BAT_Ucell_Max_CELL_104S_31 "最高单体电压所在电芯位置（当前最大位号108）从1开始";
CM_ SG_ 2334392159 BAT_Ucell_Min_CSC_104S_31 "最低单体电压所在CSC号(当前最大支持个数31个)从1开始";
CM_ SG_ 2334392159 BAT_Ucell_Min_CELL_104S_31 "最低单体电压所在电芯位置（当前最大位号108）从1开始";
CM_ SG_ 2334392159 BAT_Ucell_Max_104S_31 "最高单体电压";
CM_ SG_ 2334392159 BAT_Ucell_Min_104S_31 "最低单体电压";
CM_ SG_ 2334392160 CRC_S2A_S23_32 "S2A概要数据3 的CRC";
CM_ SG_ 2334392160 BAT_Ucell_Max_CSC_104S_32 "最高单体电压所在CSC号(当前最大支持31个)从1开始";
CM_ SG_ 2334392160 BAT_Ucell_Max_CELL_104S_32 "最高单体电压所在电芯位置（当前最大位号108）从1开始";
CM_ SG_ 2334392160 BAT_Ucell_Min_CSC_104S_32 "最低单体电压所在CSC号(当前最大支持个数31个)从1开始";
CM_ SG_ 2334392160 BAT_Ucell_Min_CELL_104S_32 "最低单体电压所在电芯位置（当前最大位号108）从1开始";
CM_ SG_ 2334392160 BAT_Ucell_Max_104S_32 "最高单体电压";
CM_ SG_ 2334392160 BAT_Ucell_Min_104S_32 "最低单体电压";
CM_ SG_ 2334392161 CRC_S2A_S23_33 "S2A概要数据3 的CRC";
CM_ SG_ 2334392161 BAT_Ucell_Max_CSC_104S_33 "最高单体电压所在CSC号(当前最大支持31个)从1开始";
CM_ SG_ 2334392161 BAT_Ucell_Max_CELL_104S_33 "最高单体电压所在电芯位置（当前最大位号108）从1开始";
CM_ SG_ 2334392161 BAT_Ucell_Min_CSC_104S_33 "最低单体电压所在CSC号(当前最大支持个数31个)从1开始";
CM_ SG_ 2334392161 BAT_Ucell_Min_CELL_104S_33 "最低单体电压所在电芯位置（当前最大位号108）从1开始";
CM_ SG_ 2334392161 BAT_Ucell_Max_104S_33 "最高单体电压";
CM_ SG_ 2334392161 BAT_Ucell_Min_104S_33 "最低单体电压";
CM_ SG_ 2334392162 CRC_S2A_S23_34 "S2A概要数据3 的CRC";
CM_ SG_ 2334392162 BAT_Ucell_Max_CSC_104S_34 "最高单体电压所在CSC号(当前最大支持31个)从1开始";
CM_ SG_ 2334392162 BAT_Ucell_Max_CELL_104S_34 "最高单体电压所在电芯位置（当前最大位号108）从1开始";
CM_ SG_ 2334392162 BAT_Ucell_Min_CSC_104S_34 "最低单体电压所在CSC号(当前最大支持个数31个)从1开始";
CM_ SG_ 2334392162 BAT_Ucell_Min_CELL_104S_34 "最低单体电压所在电芯位置（当前最大位号108）从1开始";
CM_ SG_ 2334392162 BAT_Ucell_Max_104S_34 "最高单体电压";
CM_ SG_ 2334392162 BAT_Ucell_Min_104S_34 "最低单体电压";
CM_ SG_ 2334392163 CRC_S2A_S23_35 "S2A概要数据3 的CRC";
CM_ SG_ 2334392163 BAT_Ucell_Max_CSC_104S_35 "最高单体电压所在CSC号(当前最大支持31个)从1开始";
CM_ SG_ 2334392163 BAT_Ucell_Max_CELL_104S_35 "最高单体电压所在电芯位置（当前最大位号108）从1开始";
CM_ SG_ 2334392163 BAT_Ucell_Min_CSC_104S_35 "最低单体电压所在CSC号(当前最大支持个数31个)从1开始";
CM_ SG_ 2334392163 BAT_Ucell_Min_CELL_104S_35 "最低单体电压所在电芯位置（当前最大位号108）从1开始";
CM_ SG_ 2334392163 BAT_Ucell_Max_104S_35 "最高单体电压";
CM_ SG_ 2334392163 BAT_Ucell_Min_104S_35 "最低单体电压";
CM_ SG_ 2334392164 CRC_S2A_S23_36 "S2A概要数据3 的CRC";
CM_ SG_ 2334392164 BAT_Ucell_Max_CSC_104S_36 "最高单体电压所在CSC号(当前最大支持31个)从1开始";
CM_ SG_ 2334392164 BAT_Ucell_Max_CELL_104S_36 "最高单体电压所在电芯位置（当前最大位号108）从1开始";
CM_ SG_ 2334392164 BAT_Ucell_Min_CSC_104S_36 "最低单体电压所在CSC号(当前最大支持个数31个)从1开始";
CM_ SG_ 2334392164 BAT_Ucell_Min_CELL_104S_36 "最低单体电压所在电芯位置（当前最大位号108）从1开始";
CM_ SG_ 2334392164 BAT_Ucell_Max_104S_36 "最高单体电压";
CM_ SG_ 2334392164 BAT_Ucell_Min_104S_36 "最低单体电压";
CM_ SG_ 2334392165 CRC_S2A_S23_37 "S2A概要数据3 的CRC";
CM_ SG_ 2334392165 BAT_Ucell_Max_CSC_104S_37 "最高单体电压所在CSC号(当前最大支持31个)从1开始";
CM_ SG_ 2334392165 BAT_Ucell_Max_CELL_104S_37 "最高单体电压所在电芯位置（当前最大位号108）从1开始";
CM_ SG_ 2334392165 BAT_Ucell_Min_CSC_104S_37 "最低单体电压所在CSC号(当前最大支持个数31个)从1开始";
CM_ SG_ 2334392165 BAT_Ucell_Min_CELL_104S_37 "最低单体电压所在电芯位置（当前最大位号108）从1开始";
CM_ SG_ 2334392165 BAT_Ucell_Max_104S_37 "最高单体电压";
CM_ SG_ 2334392165 BAT_Ucell_Min_104S_37 "最低单体电压";
CM_ SG_ 2334392166 CRC_S2A_S23_38 "S2A概要数据3 的CRC";
CM_ SG_ 2334392166 BAT_Ucell_Max_CSC_104S_38 "最高单体电压所在CSC号(当前最大支持31个)从1开始";
CM_ SG_ 2334392166 BAT_Ucell_Max_CELL_104S_38 "最高单体电压所在电芯位置（当前最大位号108）从1开始";
CM_ SG_ 2334392166 BAT_Ucell_Min_CSC_104S_38 "最低单体电压所在CSC号(当前最大支持个数31个)从1开始";
CM_ SG_ 2334392166 BAT_Ucell_Min_CELL_104S_38 "最低单体电压所在电芯位置（当前最大位号108）从1开始";
CM_ SG_ 2334392166 BAT_Ucell_Max_104S_38 "最高单体电压";
CM_ SG_ 2334392166 BAT_Ucell_Min_104S_38 "最低单体电压";
CM_ SG_ 2334392167 CRC_S2A_S23_39 "S2A概要数据3 的CRC";
CM_ SG_ 2334392167 BAT_Ucell_Max_CSC_104S_39 "最高单体电压所在CSC号(当前最大支持31个)从1开始";
CM_ SG_ 2334392167 BAT_Ucell_Max_CELL_104S_39 "最高单体电压所在电芯位置（当前最大位号108）从1开始";
CM_ SG_ 2334392167 BAT_Ucell_Min_CSC_104S_39 "最低单体电压所在CSC号(当前最大支持个数31个)从1开始";
CM_ SG_ 2334392167 BAT_Ucell_Min_CELL_104S_39 "最低单体电压所在电芯位置（当前最大位号108）从1开始";
CM_ SG_ 2334392167 BAT_Ucell_Max_104S_39 "最高单体电压";
CM_ SG_ 2334392167 BAT_Ucell_Min_104S_39 "最低单体电压";
CM_ SG_ 2334392168 CRC_S2A_S23_40 "S2A概要数据3 的CRC";
CM_ SG_ 2334392168 BAT_Ucell_Max_CSC_104S_40 "最高单体电压所在CSC号(当前最大支持31个)从1开始";
CM_ SG_ 2334392168 BAT_Ucell_Max_CELL_104S_40 "最高单体电压所在电芯位置（当前最大位号108）从1开始";
CM_ SG_ 2334392168 BAT_Ucell_Min_CSC_104S_40 "最低单体电压所在CSC号(当前最大支持个数31个)从1开始";
CM_ SG_ 2334392168 BAT_Ucell_Min_CELL_104S_40 "最低单体电压所在电芯位置（当前最大位号108）从1开始";
CM_ SG_ 2334392168 BAT_Ucell_Max_104S_40 "最高单体电压";
CM_ SG_ 2334392168 BAT_Ucell_Min_104S_40 "最低单体电压";
CM_ SG_ 2334392169 CRC_S2A_S23_41 "S2A概要数据3 的CRC";
CM_ SG_ 2334392169 BAT_Ucell_Max_CSC_104S_41 "最高单体电压所在CSC号(当前最大支持31个)从1开始";
CM_ SG_ 2334392169 BAT_Ucell_Max_CELL_104S_41 "最高单体电压所在电芯位置（当前最大位号108）从1开始";
CM_ SG_ 2334392169 BAT_Ucell_Min_CSC_104S_41 "最低单体电压所在CSC号(当前最大支持个数31个)从1开始";
CM_ SG_ 2334392169 BAT_Ucell_Min_CELL_104S_41 "最低单体电压所在电芯位置（当前最大位号108）从1开始";
CM_ SG_ 2334392169 BAT_Ucell_Max_104S_41 "最高单体电压";
CM_ SG_ 2334392169 BAT_Ucell_Min_104S_41 "最低单体电压";
CM_ SG_ 2334392170 CRC_S2A_S23_42 "S2A概要数据3 的CRC";
CM_ SG_ 2334392170 BAT_Ucell_Max_CSC_104S_42 "最高单体电压所在CSC号(当前最大支持31个)从1开始";
CM_ SG_ 2334392170 BAT_Ucell_Max_CELL_104S_42 "最高单体电压所在电芯位置（当前最大位号108）从1开始";
CM_ SG_ 2334392170 BAT_Ucell_Min_CSC_104S_42 "最低单体电压所在CSC号(当前最大支持个数31个)从1开始";
CM_ SG_ 2334392170 BAT_Ucell_Min_CELL_104S_42 "最低单体电压所在电芯位置（当前最大位号108）从1开始";
CM_ SG_ 2334392170 BAT_Ucell_Max_104S_42 "最高单体电压";
CM_ SG_ 2334392170 BAT_Ucell_Min_104S_42 "最低单体电压";
CM_ SG_ 2334392171 CRC_S2A_S23_43 "S2A概要数据3 的CRC";
CM_ SG_ 2334392171 BAT_Ucell_Max_CSC_104S_43 "最高单体电压所在CSC号(当前最大支持31个)从1开始";
CM_ SG_ 2334392171 BAT_Ucell_Max_CELL_104S_43 "最高单体电压所在电芯位置（当前最大位号108）从1开始";
CM_ SG_ 2334392171 BAT_Ucell_Min_CSC_104S_43 "最低单体电压所在CSC号(当前最大支持个数31个)从1开始";
CM_ SG_ 2334392171 BAT_Ucell_Min_CELL_104S_43 "最低单体电压所在电芯位置（当前最大位号108）从1开始";
CM_ SG_ 2334392171 BAT_Ucell_Max_104S_43 "最高单体电压";
CM_ SG_ 2334392171 BAT_Ucell_Min_104S_43 "最低单体电压";
CM_ SG_ 2334392172 CRC_S2A_S23_44 "S2A概要数据3 的CRC";
CM_ SG_ 2334392172 BAT_Ucell_Max_CSC_104S_44 "最高单体电压所在CSC号(当前最大支持31个)从1开始";
CM_ SG_ 2334392172 BAT_Ucell_Max_CELL_104S_44 "最高单体电压所在电芯位置（当前最大位号108）从1开始";
CM_ SG_ 2334392172 BAT_Ucell_Min_CSC_104S_44 "最低单体电压所在CSC号(当前最大支持个数31个)从1开始";
CM_ SG_ 2334392172 BAT_Ucell_Min_CELL_104S_44 "最低单体电压所在电芯位置（当前最大位号108）从1开始";
CM_ SG_ 2334392172 BAT_Ucell_Max_104S_44 "最高单体电压";
CM_ SG_ 2334392172 BAT_Ucell_Min_104S_44 "最低单体电压";
CM_ SG_ 2334392173 CRC_S2A_S23_45 "S2A概要数据3 的CRC";
CM_ SG_ 2334392173 BAT_Ucell_Max_CSC_104S_45 "最高单体电压所在CSC号(当前最大支持31个)从1开始";
CM_ SG_ 2334392173 BAT_Ucell_Max_CELL_104S_45 "最高单体电压所在电芯位置（当前最大位号108）从1开始";
CM_ SG_ 2334392173 BAT_Ucell_Min_CSC_104S_45 "最低单体电压所在CSC号(当前最大支持个数31个)从1开始";
CM_ SG_ 2334392173 BAT_Ucell_Min_CELL_104S_45 "最低单体电压所在电芯位置（当前最大位号108）从1开始";
CM_ SG_ 2334392173 BAT_Ucell_Max_104S_45 "最高单体电压";
CM_ SG_ 2334392173 BAT_Ucell_Min_104S_45 "最低单体电压";
CM_ SG_ 2334392174 CRC_S2A_S23_46 "S2A概要数据3 的CRC";
CM_ SG_ 2334392174 BAT_Ucell_Max_CSC_104S_46 "最高单体电压所在CSC号(当前最大支持31个)从1开始";
CM_ SG_ 2334392174 BAT_Ucell_Max_CELL_104S_46 "最高单体电压所在电芯位置（当前最大位号108）从1开始";
CM_ SG_ 2334392174 BAT_Ucell_Min_CSC_104S_46 "最低单体电压所在CSC号(当前最大支持个数31个)从1开始";
CM_ SG_ 2334392174 BAT_Ucell_Min_CELL_104S_46 "最低单体电压所在电芯位置（当前最大位号108）从1开始";
CM_ SG_ 2334392174 BAT_Ucell_Max_104S_46 "最高单体电压";
CM_ SG_ 2334392174 BAT_Ucell_Min_104S_46 "最低单体电压";
CM_ SG_ 2334392175 CRC_S2A_S23_47 "S2A概要数据3 的CRC";
CM_ SG_ 2334392175 BAT_Ucell_Max_CSC_104S_47 "最高单体电压所在CSC号(当前最大支持31个)从1开始";
CM_ SG_ 2334392175 BAT_Ucell_Max_CELL_104S_47 "最高单体电压所在电芯位置（当前最大位号108）从1开始";
CM_ SG_ 2334392175 BAT_Ucell_Min_CSC_104S_47 "最低单体电压所在CSC号(当前最大支持个数31个)从1开始";
CM_ SG_ 2334392175 BAT_Ucell_Min_CELL_104S_47 "最低单体电压所在电芯位置（当前最大位号108）从1开始";
CM_ SG_ 2334392175 BAT_Ucell_Max_104S_47 "最高单体电压";
CM_ SG_ 2334392175 BAT_Ucell_Min_104S_47 "最低单体电压";
CM_ SG_ 2334392176 CRC_S2A_S23_48 "S2A概要数据3 的CRC";
CM_ SG_ 2334392176 BAT_Ucell_Max_CSC_104S_48 "最高单体电压所在CSC号(当前最大支持31个)从1开始";
CM_ SG_ 2334392176 BAT_Ucell_Max_CELL_104S_48 "最高单体电压所在电芯位置（当前最大位号108）从1开始";
CM_ SG_ 2334392176 BAT_Ucell_Min_CSC_104S_48 "最低单体电压所在CSC号(当前最大支持个数31个)从1开始";
CM_ SG_ 2334392176 BAT_Ucell_Min_CELL_104S_48 "最低单体电压所在电芯位置（当前最大位号108）从1开始";
CM_ SG_ 2334392176 BAT_Ucell_Max_104S_48 "最高单体电压";
CM_ SG_ 2334392176 BAT_Ucell_Min_104S_48 "最低单体电压";
CM_ SG_ 2334392177 CRC_S2A_S23_49 "S2A概要数据3 的CRC";
CM_ SG_ 2334392177 BAT_Ucell_Max_CSC_104S_49 "最高单体电压所在CSC号(当前最大支持31个)从1开始";
CM_ SG_ 2334392177 BAT_Ucell_Max_CELL_104S_49 "最高单体电压所在电芯位置（当前最大位号108）从1开始";
CM_ SG_ 2334392177 BAT_Ucell_Min_CSC_104S_49 "最低单体电压所在CSC号(当前最大支持个数31个)从1开始";
CM_ SG_ 2334392177 BAT_Ucell_Min_CELL_104S_49 "最低单体电压所在电芯位置（当前最大位号108）从1开始";
CM_ SG_ 2334392177 BAT_Ucell_Max_104S_49 "最高单体电压";
CM_ SG_ 2334392177 BAT_Ucell_Min_104S_49 "最低单体电压";
CM_ SG_ 2334392178 CRC_S2A_S23_50 "S2A概要数据3 的CRC";
CM_ SG_ 2334392178 BAT_Ucell_Max_CSC_104S_50 "最高单体电压所在CSC号(当前最大支持31个)从1开始";
CM_ SG_ 2334392178 BAT_Ucell_Max_CELL_104S_50 "最高单体电压所在电芯位置（当前最大位号108）从1开始";
CM_ SG_ 2334392178 BAT_Ucell_Min_CSC_104S_50 "最低单体电压所在CSC号(当前最大支持个数31个)从1开始";
CM_ SG_ 2334392178 BAT_Ucell_Min_CELL_104S_50 "最低单体电压所在电芯位置（当前最大位号108）从1开始";
CM_ SG_ 2334392178 BAT_Ucell_Max_104S_50 "最高单体电压";
CM_ SG_ 2334392178 BAT_Ucell_Min_104S_50 "最低单体电压";
CM_ SG_ 2334392179 CRC_S2A_S23_51 "S2A概要数据3 的CRC";
CM_ SG_ 2334392179 BAT_Ucell_Max_CSC_104S_51 "最高单体电压所在CSC号(当前最大支持31个)从1开始";
CM_ SG_ 2334392179 BAT_Ucell_Max_CELL_104S_51 "最高单体电压所在电芯位置（当前最大位号108）从1开始";
CM_ SG_ 2334392179 BAT_Ucell_Min_CSC_104S_51 "最低单体电压所在CSC号(当前最大支持个数31个)从1开始";
CM_ SG_ 2334392179 BAT_Ucell_Min_CELL_104S_51 "最低单体电压所在电芯位置（当前最大位号108）从1开始";
CM_ SG_ 2334392179 BAT_Ucell_Max_104S_51 "最高单体电压";
CM_ SG_ 2334392179 BAT_Ucell_Min_104S_51 "最低单体电压";
CM_ SG_ 2334392180 CRC_S2A_S23_52 "S2A概要数据3 的CRC";
CM_ SG_ 2334392180 BAT_Ucell_Max_CSC_104S_52 "最高单体电压所在CSC号(当前最大支持31个)从1开始";
CM_ SG_ 2334392180 BAT_Ucell_Max_CELL_104S_52 "最高单体电压所在电芯位置（当前最大位号108）从1开始";
CM_ SG_ 2334392180 BAT_Ucell_Min_CSC_104S_52 "最低单体电压所在CSC号(当前最大支持个数31个)从1开始";
CM_ SG_ 2334392180 BAT_Ucell_Min_CELL_104S_52 "最低单体电压所在电芯位置（当前最大位号108）从1开始";
CM_ SG_ 2334392180 BAT_Ucell_Max_104S_52 "最高单体电压";
CM_ SG_ 2334392180 BAT_Ucell_Min_104S_52 "最低单体电压";
CM_ SG_ 2334392181 CRC_S2A_S23_53 "S2A概要数据3 的CRC";
CM_ SG_ 2334392181 BAT_Ucell_Max_CSC_104S_53 "最高单体电压所在CSC号(当前最大支持31个)从1开始";
CM_ SG_ 2334392181 BAT_Ucell_Max_CELL_104S_53 "最高单体电压所在电芯位置（当前最大位号108）从1开始";
CM_ SG_ 2334392181 BAT_Ucell_Min_CSC_104S_53 "最低单体电压所在CSC号(当前最大支持个数31个)从1开始";
CM_ SG_ 2334392181 BAT_Ucell_Min_CELL_104S_53 "最低单体电压所在电芯位置（当前最大位号108）从1开始";
CM_ SG_ 2334392181 BAT_Ucell_Max_104S_53 "最高单体电压";
CM_ SG_ 2334392181 BAT_Ucell_Min_104S_53 "最低单体电压";
CM_ SG_ 2334392182 CRC_S2A_S23_54 "S2A概要数据3 的CRC";
CM_ SG_ 2334392182 BAT_Ucell_Max_CSC_104S_54 "最高单体电压所在CSC号(当前最大支持31个)从1开始";
CM_ SG_ 2334392182 BAT_Ucell_Max_CELL_104S_54 "最高单体电压所在电芯位置（当前最大位号108）从1开始";
CM_ SG_ 2334392182 BAT_Ucell_Min_CSC_104S_54 "最低单体电压所在CSC号(当前最大支持个数31个)从1开始";
CM_ SG_ 2334392182 BAT_Ucell_Min_CELL_104S_54 "最低单体电压所在电芯位置（当前最大位号108）从1开始";
CM_ SG_ 2334392182 BAT_Ucell_Max_104S_54 "最高单体电压";
CM_ SG_ 2334392182 BAT_Ucell_Min_104S_54 "最低单体电压";
CM_ SG_ 2334392183 CRC_S2A_S23_55 "S2A概要数据3 的CRC";
CM_ SG_ 2334392183 BAT_Ucell_Max_CSC_104S_55 "最高单体电压所在CSC号(当前最大支持31个)从1开始";
CM_ SG_ 2334392183 BAT_Ucell_Max_CELL_104S_55 "最高单体电压所在电芯位置（当前最大位号108）从1开始";
CM_ SG_ 2334392183 BAT_Ucell_Min_CSC_104S_55 "最低单体电压所在CSC号(当前最大支持个数31个)从1开始";
CM_ SG_ 2334392183 BAT_Ucell_Min_CELL_104S_55 "最低单体电压所在电芯位置（当前最大位号108）从1开始";
CM_ SG_ 2334392183 BAT_Ucell_Max_104S_55 "最高单体电压";
CM_ SG_ 2334392183 BAT_Ucell_Min_104S_55 "最低单体电压";
CM_ SG_ 2334392184 CRC_S2A_S23_56 "S2A概要数据3 的CRC";
CM_ SG_ 2334392184 BAT_Ucell_Max_CSC_104S_56 "最高单体电压所在CSC号(当前最大支持31个)从1开始";
CM_ SG_ 2334392184 BAT_Ucell_Max_CELL_104S_56 "最高单体电压所在电芯位置（当前最大位号108）从1开始";
CM_ SG_ 2334392184 BAT_Ucell_Min_CSC_104S_56 "最低单体电压所在CSC号(当前最大支持个数31个)从1开始";
CM_ SG_ 2334392184 BAT_Ucell_Min_CELL_104S_56 "最低单体电压所在电芯位置（当前最大位号108）从1开始";
CM_ SG_ 2334392184 BAT_Ucell_Max_104S_56 "最高单体电压";
CM_ SG_ 2334392184 BAT_Ucell_Min_104S_56 "最低单体电压";
CM_ SG_ 2334392185 CRC_S2A_S23_57 "S2A概要数据3 的CRC";
CM_ SG_ 2334392185 BAT_Ucell_Max_CSC_104S_57 "最高单体电压所在CSC号(当前最大支持31个)从1开始";
CM_ SG_ 2334392185 BAT_Ucell_Max_CELL_104S_57 "最高单体电压所在电芯位置（当前最大位号108）从1开始";
CM_ SG_ 2334392185 BAT_Ucell_Min_CSC_104S_57 "最低单体电压所在CSC号(当前最大支持个数31个)从1开始";
CM_ SG_ 2334392185 BAT_Ucell_Min_CELL_104S_57 "最低单体电压所在电芯位置（当前最大位号108）从1开始";
CM_ SG_ 2334392185 BAT_Ucell_Max_104S_57 "最高单体电压";
CM_ SG_ 2334392185 BAT_Ucell_Min_104S_57 "最低单体电压";
CM_ SG_ 2334392186 CRC_S2A_S23_58 "S2A概要数据3 的CRC";
CM_ SG_ 2334392186 BAT_Ucell_Max_CSC_104S_58 "最高单体电压所在CSC号(当前最大支持31个)从1开始";
CM_ SG_ 2334392186 BAT_Ucell_Max_CELL_104S_58 "最高单体电压所在电芯位置（当前最大位号108）从1开始";
CM_ SG_ 2334392186 BAT_Ucell_Min_CSC_104S_58 "最低单体电压所在CSC号(当前最大支持个数31个)从1开始";
CM_ SG_ 2334392186 BAT_Ucell_Min_CELL_104S_58 "最低单体电压所在电芯位置（当前最大位号108）从1开始";
CM_ SG_ 2334392186 BAT_Ucell_Max_104S_58 "最高单体电压";
CM_ SG_ 2334392186 BAT_Ucell_Min_104S_58 "最低单体电压";
CM_ SG_ 2334392187 CRC_S2A_S23_59 "S2A概要数据3 的CRC";
CM_ SG_ 2334392187 BAT_Ucell_Max_CSC_104S_59 "最高单体电压所在CSC号(当前最大支持31个)从1开始";
CM_ SG_ 2334392187 BAT_Ucell_Max_CELL_104S_59 "最高单体电压所在电芯位置（当前最大位号108）从1开始";
CM_ SG_ 2334392187 BAT_Ucell_Min_CSC_104S_59 "最低单体电压所在CSC号(当前最大支持个数31个)从1开始";
CM_ SG_ 2334392187 BAT_Ucell_Min_CELL_104S_59 "最低单体电压所在电芯位置（当前最大位号108）从1开始";
CM_ SG_ 2334392187 BAT_Ucell_Max_104S_59 "最高单体电压";
CM_ SG_ 2334392187 BAT_Ucell_Min_104S_59 "最低单体电压";
CM_ SG_ 2334392188 CRC_S2A_S23_60 "S2A概要数据3 的CRC";
CM_ SG_ 2334392188 BAT_Ucell_Max_CSC_104S_60 "最高单体电压所在CSC号(当前最大支持31个)从1开始";
CM_ SG_ 2334392188 BAT_Ucell_Max_CELL_104S_60 "最高单体电压所在电芯位置（当前最大位号108）从1开始";
CM_ SG_ 2334392188 BAT_Ucell_Min_CSC_104S_60 "最低单体电压所在CSC号(当前最大支持个数31个)从1开始";
CM_ SG_ 2334392188 BAT_Ucell_Min_CELL_104S_60 "最低单体电压所在电芯位置（当前最大位号108）从1开始";
CM_ SG_ 2334392188 BAT_Ucell_Max_104S_60 "最高单体电压";
CM_ SG_ 2334392188 BAT_Ucell_Min_104S_60 "最低单体电压";
CM_ SG_ 2334392189 CRC_S2A_S23_61 "S2A概要数据3 的CRC";
CM_ SG_ 2334392189 BAT_Ucell_Max_CSC_104S_61 "最高单体电压所在CSC号(当前最大支持31个)从1开始";
CM_ SG_ 2334392189 BAT_Ucell_Max_CELL_104S_61 "最高单体电压所在电芯位置（当前最大位号108）从1开始";
CM_ SG_ 2334392189 BAT_Ucell_Min_CSC_104S_61 "最低单体电压所在CSC号(当前最大支持个数31个)从1开始";
CM_ SG_ 2334392189 BAT_Ucell_Min_CELL_104S_61 "最低单体电压所在电芯位置（当前最大位号108）从1开始";
CM_ SG_ 2334392189 BAT_Ucell_Max_104S_61 "最高单体电压";
CM_ SG_ 2334392189 BAT_Ucell_Min_104S_61 "最低单体电压";
CM_ SG_ 2334392190 CRC_S2A_S23_62 "S2A概要数据3 的CRC";
CM_ SG_ 2334392190 BAT_Ucell_Max_CSC_104S_62 "最高单体电压所在CSC号(当前最大支持31个)从1开始";
CM_ SG_ 2334392190 BAT_Ucell_Max_CELL_104S_62 "最高单体电压所在电芯位置（当前最大位号108）从1开始";
CM_ SG_ 2334392190 BAT_Ucell_Min_CSC_104S_62 "最低单体电压所在CSC号(当前最大支持个数31个)从1开始";
CM_ SG_ 2334392190 BAT_Ucell_Min_CELL_104S_62 "最低单体电压所在电芯位置（当前最大位号108）从1开始";
CM_ SG_ 2334392190 BAT_Ucell_Max_104S_62 "最高单体电压";
CM_ SG_ 2334392190 BAT_Ucell_Min_104S_62 "最低单体电压";
CM_ SG_ 2334392191 CRC_S2A_S23_63 "S2A概要数据3 的CRC";
CM_ SG_ 2334392191 BAT_Ucell_Max_CSC_104S_63 "最高单体电压所在CSC号(当前最大支持31个)从1开始";
CM_ SG_ 2334392191 BAT_Ucell_Max_CELL_104S_63 "最高单体电压所在电芯位置（当前最大位号108）从1开始";
CM_ SG_ 2334392191 BAT_Ucell_Min_CSC_104S_63 "最低单体电压所在CSC号(当前最大支持个数31个)从1开始";
CM_ SG_ 2334392191 BAT_Ucell_Min_CELL_104S_63 "最低单体电压所在电芯位置（当前最大位号108）从1开始";
CM_ SG_ 2334392191 BAT_Ucell_Max_104S_63 "最高单体电压";
CM_ SG_ 2334392191 BAT_Ucell_Min_104S_63 "最低单体电压";
CM_ SG_ 2417946177 S2P_Bal_CSCNum_104s_01 "CSC号";
CM_ SG_ 2417946177 S2P_Bal_CellNum_104s_01 "CELL号";
CM_ SG_ 2417946177 S2P_Bal_Type_104s_01 "均衡类型";
CM_ SG_ 2417946177 S2P_Bal_TimeRemain_104s_01 "故障清除指令";
CM_ SG_ 2417946177 S2P_Bal_DeltaVolt_104s_01 "均衡电芯压差";
CM_ SG_ 2417946177 S2P_Bal_TypeLevel_104s_01 "均衡等级";
CM_ SG_ 2417946177 S2P_Bal_Strategy_104s_01 "均衡策略";
CM_ SG_ 2417946177 S2P_Bal_ForceBalMode_104s_01 "强制均衡模式";
CM_ SG_ 2417946177 S2P_Bal_CellTempFault_104s_01 "温度单点无效";
CM_ SG_ 2417946177 S2P_Bal_CellVoltFail_104s_01 "电芯电压采样失效";
CM_ SG_ 2417946177 S2P_Bal_CloseBalIstr_104s_01 "其他模块关闭均衡指令";
CM_ SG_ 2417946177 S2P_Bal_CCanTimeOut_104s_01 "CCAN通讯超时故障";
CM_ SG_ 2417946177 S2P_Bal_CellOffLine_104s_01 "预留";
CM_ SG_ 2417946177 S2P_Bal_BalanCirFlt_104s_01 "均衡回路故障";
CM_ SG_ 2417946177 S2P_Bal_CellVoOverFlt104s_01 "预留";
CM_ SG_ 2417946177 S2P_Bal_CellVoLowFlt104s_01 "预留";
CM_ SG_ 2417946177 S2P_Bal_CSCPCBTeFlt104s_01 "预留";
CM_ SG_ 2417946178 S2P_Bal_CSCNum_104s_02 "CSC号";
CM_ SG_ 2417946178 S2P_Bal_CellNum_104s_02 "CELL号";
CM_ SG_ 2417946178 S2P_Bal_Type_104s_02 "均衡类型";
CM_ SG_ 2417946178 S2P_Bal_TimeRemain_104s_02 "故障清除指令";
CM_ SG_ 2417946178 S2P_Bal_DeltaVolt_104s_02 "均衡电芯压差";
CM_ SG_ 2417946178 S2P_Bal_TypeLevel_104s_02 "均衡等级";
CM_ SG_ 2417946178 S2P_Bal_Strategy_104s_02 "均衡策略";
CM_ SG_ 2417946178 S2P_Bal_ForceBalMode_104s_02 "强制均衡模式";
CM_ SG_ 2417946178 S2P_Bal_CellTempFault_104s_02 "温度单点无效";
CM_ SG_ 2417946178 S2P_Bal_CellVoltFail_104s_02 "电芯电压采样失效";
CM_ SG_ 2417946178 S2P_Bal_CloseBalIstr_104s_02 "其他模块关闭均衡指令";
CM_ SG_ 2417946178 S2P_Bal_CCanTimeOut_104s_02 "CCAN通讯超时故障";
CM_ SG_ 2417946178 S2P_Bal_CellOffLine_104s_02 "预留";
CM_ SG_ 2417946178 S2P_Bal_BalanCirFlt_104s_02 "均衡回路故障";
CM_ SG_ 2417946178 S2P_Bal_CellVoOverFlt104s_02 "预留";
CM_ SG_ 2417946178 S2P_Bal_CellVoLowFlt104s_02 "预留";
CM_ SG_ 2417946178 S2P_Bal_CSCPCBTeFlt104s_02 "预留";
CM_ SG_ 2417946179 S2P_Bal_CSCNum_104s_03 "CSC号";
CM_ SG_ 2417946179 S2P_Bal_CellNum_104s_03 "CELL号";
CM_ SG_ 2417946179 S2P_Bal_Type_104s_03 "均衡类型";
CM_ SG_ 2417946179 S2P_Bal_TimeRemain_104s_03 "故障清除指令";
CM_ SG_ 2417946179 S2P_Bal_DeltaVolt_104s_03 "均衡电芯压差";
CM_ SG_ 2417946179 S2P_Bal_TypeLevel_104s_03 "均衡等级";
CM_ SG_ 2417946179 S2P_Bal_Strategy_104s_03 "均衡策略";
CM_ SG_ 2417946179 S2P_Bal_ForceBalMode_104s_03 "强制均衡模式";
CM_ SG_ 2417946179 S2P_Bal_CellTempFault_104s_03 "温度单点无效";
CM_ SG_ 2417946179 S2P_Bal_CellVoltFail_104s_03 "电芯电压采样失效";
CM_ SG_ 2417946179 S2P_Bal_CloseBalIstr_104s_03 "其他模块关闭均衡指令";
CM_ SG_ 2417946179 S2P_Bal_CCanTimeOut_104s_03 "CCAN通讯超时故障";
CM_ SG_ 2417946179 S2P_Bal_CellOffLine_104s_03 "预留";
CM_ SG_ 2417946179 S2P_Bal_BalanCirFlt_104s_03 "均衡回路故障";
CM_ SG_ 2417946179 S2P_Bal_CellVoOverFlt104s_03 "预留";
CM_ SG_ 2417946179 S2P_Bal_CellVoLowFlt104s_03 "预留";
CM_ SG_ 2417946179 S2P_Bal_CSCPCBTeFlt104s_03 "预留";
CM_ SG_ 2417946180 S2P_Bal_CSCNum_104s_04 "CSC号";
CM_ SG_ 2417946180 S2P_Bal_CellNum_104s_04 "CELL号";
CM_ SG_ 2417946180 S2P_Bal_Type_104s_04 "均衡类型";
CM_ SG_ 2417946180 S2P_Bal_TimeRemain_104s_04 "故障清除指令";
CM_ SG_ 2417946180 S2P_Bal_DeltaVolt_104s_04 "均衡电芯压差";
CM_ SG_ 2417946180 S2P_Bal_TypeLevel_104s_04 "均衡等级";
CM_ SG_ 2417946180 S2P_Bal_Strategy_104s_04 "均衡策略";
CM_ SG_ 2417946180 S2P_Bal_ForceBalMode_104s_04 "强制均衡模式";
CM_ SG_ 2417946180 S2P_Bal_CellTempFault_104s_04 "温度单点无效";
CM_ SG_ 2417946180 S2P_Bal_CellVoltFail_104s_04 "电芯电压采样失效";
CM_ SG_ 2417946180 S2P_Bal_CloseBalIstr_104s_04 "其他模块关闭均衡指令";
CM_ SG_ 2417946180 S2P_Bal_CCanTimeOut_104s_04 "CCAN通讯超时故障";
CM_ SG_ 2417946180 S2P_Bal_CellOffLine_104s_04 "预留";
CM_ SG_ 2417946180 S2P_Bal_BalanCirFlt_104s_04 "均衡回路故障";
CM_ SG_ 2417946180 S2P_Bal_CellVoOverFlt104s_04 "预留";
CM_ SG_ 2417946180 S2P_Bal_CellVoLowFlt104s_04 "预留";
CM_ SG_ 2417946180 S2P_Bal_CSCPCBTeFlt104s_04 "预留";
CM_ SG_ 2417946181 S2P_Bal_CSCNum_104s_05 "CSC号";
CM_ SG_ 2417946181 S2P_Bal_CellNum_104s_05 "CELL号";
CM_ SG_ 2417946181 S2P_Bal_Type_104s_05 "均衡类型";
CM_ SG_ 2417946181 S2P_Bal_TimeRemain_104s_05 "故障清除指令";
CM_ SG_ 2417946181 S2P_Bal_DeltaVolt_104s_05 "均衡电芯压差";
CM_ SG_ 2417946181 S2P_Bal_TypeLevel_104s_05 "均衡等级";
CM_ SG_ 2417946181 S2P_Bal_Strategy_104s_05 "均衡策略";
CM_ SG_ 2417946181 S2P_Bal_ForceBalMode_104s_05 "强制均衡模式";
CM_ SG_ 2417946181 S2P_Bal_CellTempFault_104s_05 "温度单点无效";
CM_ SG_ 2417946181 S2P_Bal_CellVoltFail_104s_05 "电芯电压采样失效";
CM_ SG_ 2417946181 S2P_Bal_CloseBalIstr_104s_05 "其他模块关闭均衡指令";
CM_ SG_ 2417946181 S2P_Bal_CCanTimeOut_104s_05 "CCAN通讯超时故障";
CM_ SG_ 2417946181 S2P_Bal_CellOffLine_104s_05 "预留";
CM_ SG_ 2417946181 S2P_Bal_BalanCirFlt_104s_05 "均衡回路故障";
CM_ SG_ 2417946181 S2P_Bal_CellVoOverFlt104s_05 "预留";
CM_ SG_ 2417946181 S2P_Bal_CellVoLowFlt104s_05 "预留";
CM_ SG_ 2417946181 S2P_Bal_CSCPCBTeFlt104s_05 "预留";
CM_ SG_ 2417946182 S2P_Bal_CSCNum_104s_06 "CSC号";
CM_ SG_ 2417946182 S2P_Bal_CellNum_104s_06 "CELL号";
CM_ SG_ 2417946182 S2P_Bal_Type_104s_06 "均衡类型";
CM_ SG_ 2417946182 S2P_Bal_TimeRemain_104s_06 "故障清除指令";
CM_ SG_ 2417946182 S2P_Bal_DeltaVolt_104s_06 "均衡电芯压差";
CM_ SG_ 2417946182 S2P_Bal_TypeLevel_104s_06 "均衡等级";
CM_ SG_ 2417946182 S2P_Bal_Strategy_104s_06 "均衡策略";
CM_ SG_ 2417946182 S2P_Bal_ForceBalMode_104s_06 "强制均衡模式";
CM_ SG_ 2417946182 S2P_Bal_CellTempFault_104s_06 "温度单点无效";
CM_ SG_ 2417946182 S2P_Bal_CellVoltFail_104s_06 "电芯电压采样失效";
CM_ SG_ 2417946182 S2P_Bal_CloseBalIstr_104s_06 "其他模块关闭均衡指令";
CM_ SG_ 2417946182 S2P_Bal_CCanTimeOut_104s_06 "CCAN通讯超时故障";
CM_ SG_ 2417946182 S2P_Bal_CellOffLine_104s_06 "预留";
CM_ SG_ 2417946182 S2P_Bal_BalanCirFlt_104s_06 "均衡回路故障";
CM_ SG_ 2417946182 S2P_Bal_CellVoOverFlt104s_06 "预留";
CM_ SG_ 2417946182 S2P_Bal_CellVoLowFlt104s_06 "预留";
CM_ SG_ 2417946182 S2P_Bal_CSCPCBTeFlt104s_06 "预留";
CM_ SG_ 2417946183 S2P_Bal_CSCNum_104s_07 "CSC号";
CM_ SG_ 2417946183 S2P_Bal_CellNum_104s_07 "CELL号";
CM_ SG_ 2417946183 S2P_Bal_Type_104s_07 "均衡类型";
CM_ SG_ 2417946183 S2P_Bal_TimeRemain_104s_07 "故障清除指令";
CM_ SG_ 2417946183 S2P_Bal_DeltaVolt_104s_07 "均衡电芯压差";
CM_ SG_ 2417946183 S2P_Bal_TypeLevel_104s_07 "均衡等级";
CM_ SG_ 2417946183 S2P_Bal_Strategy_104s_07 "均衡策略";
CM_ SG_ 2417946183 S2P_Bal_ForceBalMode_104s_07 "强制均衡模式";
CM_ SG_ 2417946183 S2P_Bal_CellTempFault_104s_07 "温度单点无效";
CM_ SG_ 2417946183 S2P_Bal_CellVoltFail_104s_07 "电芯电压采样失效";
CM_ SG_ 2417946183 S2P_Bal_CloseBalIstr_104s_07 "其他模块关闭均衡指令";
CM_ SG_ 2417946183 S2P_Bal_CCanTimeOut_104s_07 "CCAN通讯超时故障";
CM_ SG_ 2417946183 S2P_Bal_CellOffLine_104s_07 "预留";
CM_ SG_ 2417946183 S2P_Bal_BalanCirFlt_104s_07 "均衡回路故障";
CM_ SG_ 2417946183 S2P_Bal_CellVoOverFlt104s_07 "预留";
CM_ SG_ 2417946183 S2P_Bal_CellVoLowFlt104s_07 "预留";
CM_ SG_ 2417946183 S2P_Bal_CSCPCBTeFlt104s_07 "预留";
CM_ SG_ 2417946184 S2P_Bal_CSCNum_104s_08 "CSC号";
CM_ SG_ 2417946184 S2P_Bal_CellNum_104s_08 "CELL号";
CM_ SG_ 2417946184 S2P_Bal_Type_104s_08 "均衡类型";
CM_ SG_ 2417946184 S2P_Bal_TimeRemain_104s_08 "故障清除指令";
CM_ SG_ 2417946184 S2P_Bal_DeltaVolt_104s_08 "均衡电芯压差";
CM_ SG_ 2417946184 S2P_Bal_TypeLevel_104s_08 "均衡等级";
CM_ SG_ 2417946184 S2P_Bal_Strategy_104s_08 "均衡策略";
CM_ SG_ 2417946184 S2P_Bal_ForceBalMode_104s_08 "强制均衡模式";
CM_ SG_ 2417946184 S2P_Bal_CellTempFault_104s_08 "温度单点无效";
CM_ SG_ 2417946184 S2P_Bal_CellVoltFail_104s_08 "电芯电压采样失效";
CM_ SG_ 2417946184 S2P_Bal_CloseBalIstr_104s_08 "其他模块关闭均衡指令";
CM_ SG_ 2417946184 S2P_Bal_CCanTimeOut_104s_08 "CCAN通讯超时故障";
CM_ SG_ 2417946184 S2P_Bal_CellOffLine_104s_08 "预留";
CM_ SG_ 2417946184 S2P_Bal_BalanCirFlt_104s_08 "均衡回路故障";
CM_ SG_ 2417946184 S2P_Bal_CellVoOverFlt104s_08 "预留";
CM_ SG_ 2417946184 S2P_Bal_CellVoLowFlt104s_08 "预留";
CM_ SG_ 2417946184 S2P_Bal_CSCPCBTeFlt104s_08 "预留";
CM_ SG_ 2417946185 S2P_Bal_CSCNum_104s_09 "CSC号";
CM_ SG_ 2417946185 S2P_Bal_CellNum_104s_09 "CELL号";
CM_ SG_ 2417946185 S2P_Bal_Type_104s_09 "均衡类型";
CM_ SG_ 2417946185 S2P_Bal_TimeRemain_104s_09 "故障清除指令";
CM_ SG_ 2417946185 S2P_Bal_DeltaVolt_104s_09 "均衡电芯压差";
CM_ SG_ 2417946185 S2P_Bal_TypeLevel_104s_09 "均衡等级";
CM_ SG_ 2417946185 S2P_Bal_Strategy_104s_09 "均衡策略";
CM_ SG_ 2417946185 S2P_Bal_ForceBalMode_104s_09 "强制均衡模式";
CM_ SG_ 2417946185 S2P_Bal_CellTempFault_104s_09 "温度单点无效";
CM_ SG_ 2417946185 S2P_Bal_CellVoltFail_104s_09 "电芯电压采样失效";
CM_ SG_ 2417946185 S2P_Bal_CloseBalIstr_104s_09 "其他模块关闭均衡指令";
CM_ SG_ 2417946185 S2P_Bal_CCanTimeOut_104s_09 "CCAN通讯超时故障";
CM_ SG_ 2417946185 S2P_Bal_CellOffLine_104s_09 "预留";
CM_ SG_ 2417946185 S2P_Bal_BalanCirFlt_104s_09 "均衡回路故障";
CM_ SG_ 2417946185 S2P_Bal_CellVoOverFlt104s_09 "预留";
CM_ SG_ 2417946185 S2P_Bal_CellVoLowFlt104s_09 "预留";
CM_ SG_ 2417946185 S2P_Bal_CSCPCBTeFlt104s_09 "预留";
CM_ SG_ 2417946186 S2P_Bal_CSCNum_104s_10 "CSC号";
CM_ SG_ 2417946186 S2P_Bal_CellNum_104s_10 "CELL号";
CM_ SG_ 2417946186 S2P_Bal_Type_104s_10 "均衡类型";
CM_ SG_ 2417946186 S2P_Bal_TimeRemain_104s_10 "故障清除指令";
CM_ SG_ 2417946186 S2P_Bal_DeltaVolt_104s_10 "均衡电芯压差";
CM_ SG_ 2417946186 S2P_Bal_TypeLevel_104s_10 "均衡等级";
CM_ SG_ 2417946186 S2P_Bal_Strategy_104s_10 "均衡策略";
CM_ SG_ 2417946186 S2P_Bal_ForceBalMode_104s_10 "强制均衡模式";
CM_ SG_ 2417946186 S2P_Bal_CellTempFault_104s_10 "温度单点无效";
CM_ SG_ 2417946186 S2P_Bal_CellVoltFail_104s_10 "电芯电压采样失效";
CM_ SG_ 2417946186 S2P_Bal_CloseBalIstr_104s_10 "其他模块关闭均衡指令";
CM_ SG_ 2417946186 S2P_Bal_CCanTimeOut_104s_10 "CCAN通讯超时故障";
CM_ SG_ 2417946186 S2P_Bal_CellOffLine_104s_10 "预留";
CM_ SG_ 2417946186 S2P_Bal_BalanCirFlt_104s_10 "均衡回路故障";
CM_ SG_ 2417946186 S2P_Bal_CellVoOverFlt104s_10 "预留";
CM_ SG_ 2417946186 S2P_Bal_CellVoLowFlt104s_10 "预留";
CM_ SG_ 2417946186 S2P_Bal_CSCPCBTeFlt104s_10 "预留";
CM_ SG_ 2417946187 S2P_Bal_CSCNum_104s_11 "CSC号";
CM_ SG_ 2417946187 S2P_Bal_CellNum_104s_11 "CELL号";
CM_ SG_ 2417946187 S2P_Bal_Type_104s_11 "均衡类型";
CM_ SG_ 2417946187 S2P_Bal_TimeRemain_104s_11 "故障清除指令";
CM_ SG_ 2417946187 S2P_Bal_DeltaVolt_104s_11 "均衡电芯压差";
CM_ SG_ 2417946187 S2P_Bal_TypeLevel_104s_11 "均衡等级";
CM_ SG_ 2417946187 S2P_Bal_Strategy_104s_11 "均衡策略";
CM_ SG_ 2417946187 S2P_Bal_ForceBalMode_104s_11 "强制均衡模式";
CM_ SG_ 2417946187 S2P_Bal_CellTempFault_104s_11 "温度单点无效";
CM_ SG_ 2417946187 S2P_Bal_CellVoltFail_104s_11 "电芯电压采样失效";
CM_ SG_ 2417946187 S2P_Bal_CloseBalIstr_104s_11 "其他模块关闭均衡指令";
CM_ SG_ 2417946187 S2P_Bal_CCanTimeOut_104s_11 "CCAN通讯超时故障";
CM_ SG_ 2417946187 S2P_Bal_CellOffLine_104s_11 "预留";
CM_ SG_ 2417946187 S2P_Bal_BalanCirFlt_104s_11 "均衡回路故障";
CM_ SG_ 2417946187 S2P_Bal_CellVoOverFlt104s_11 "预留";
CM_ SG_ 2417946187 S2P_Bal_CellVoLowFlt104s_11 "预留";
CM_ SG_ 2417946187 S2P_Bal_CSCPCBTeFlt104s_11 "预留";
CM_ SG_ 2417946188 S2P_Bal_CSCNum_104s_12 "CSC号";
CM_ SG_ 2417946188 S2P_Bal_CellNum_104s_12 "CELL号";
CM_ SG_ 2417946188 S2P_Bal_Type_104s_12 "均衡类型";
CM_ SG_ 2417946188 S2P_Bal_TimeRemain_104s_12 "故障清除指令";
CM_ SG_ 2417946188 S2P_Bal_DeltaVolt_104s_12 "均衡电芯压差";
CM_ SG_ 2417946188 S2P_Bal_TypeLevel_104s_12 "均衡等级";
CM_ SG_ 2417946188 S2P_Bal_Strategy_104s_12 "均衡策略";
CM_ SG_ 2417946188 S2P_Bal_ForceBalMode_104s_12 "强制均衡模式";
CM_ SG_ 2417946188 S2P_Bal_CellTempFault_104s_12 "温度单点无效";
CM_ SG_ 2417946188 S2P_Bal_CellVoltFail_104s_12 "电芯电压采样失效";
CM_ SG_ 2417946188 S2P_Bal_CloseBalIstr_104s_12 "其他模块关闭均衡指令";
CM_ SG_ 2417946188 S2P_Bal_CCanTimeOut_104s_12 "CCAN通讯超时故障";
CM_ SG_ 2417946188 S2P_Bal_CellOffLine_104s_12 "预留";
CM_ SG_ 2417946188 S2P_Bal_BalanCirFlt_104s_12 "均衡回路故障";
CM_ SG_ 2417946188 S2P_Bal_CellVoOverFlt104s_12 "预留";
CM_ SG_ 2417946188 S2P_Bal_CellVoLowFlt104s_12 "预留";
CM_ SG_ 2417946188 S2P_Bal_CSCPCBTeFlt104s_12 "预留";
VAL_ 2417946177 S2P_Bal_CSCNum_104s_01 0 "No CSC" 1 "CSC 1" 2 "CSC 2" 3 "CSC 3" 4 "CSC 4" 5 "CSC 5" 6 "CSC 6" 7 "CSC 7" 8 "CSC 8" 9 "CSC 9" 10 "CSC 10" 11 "CSC 11" 12 "CSC 12" 13 "CSC 13" 14 "CSC 14" 15 "CSC 15" 16 "CSC 16" 17 "CSC 17" 18 "CSC 18" 19 "CSC 19" 20 "CSC 20" 21 "CSC 21" 22 "CSC 22" 23 "CSC 23" 24 "CSC 24" 25 "CSC 25" 26 "CSC 26" 27 "CSC 27" 28 "CSC 28" 29 "CSC 29" 30 "CSC 30" 31 "CSC 31" ;
VAL_ 2417946177 S2P_Bal_CellNum_104s_01 1 "Cell 1" 2 "Cell 2" 3 "Cell 3" 4 "Cell 4" 5 "Cell 5" 6 "Cell 6" 7 "Cell 7" 8 "Cell 8" 9 "Cell 9" 10 "Cell 10" 11 "Cell 11" 12 "Cell 12" 13 "Cell 13" 14 "Cell 14" 15 "Cell 15" 16 "Cell 16" 127 "Null" ;
VAL_ 2417946177 S2P_Bal_Type_104s_01 0 "Balance stop" 1 "charge Balance" 2 "discharge Balance" ;
VAL_ 2417946177 S2P_Bal_TypeLevel_104s_01 0 "Not Balance" 1 "Low end Balance" 2 "High end Balance" 3 "Force Balance" ;
VAL_ 2417946177 S2P_Bal_Strategy_104s_01 0 "Active Balance" 1 "Passive Static" ;
VAL_ 2417946177 S2P_Bal_ForceBalMode_104s_01 1 "Base on time " 2 "Base on Target Vol" 3 "Base on Ave Vol" ;
VAL_ 2417946177 S2P_Bal_CellTempFault_104s_01 0 "Nomal" 1 "Fault" ;
VAL_ 2417946177 S2P_Bal_CellVoltFail_104s_01 0 "Nomal" 1 "Fault" ;
VAL_ 2417946177 S2P_Bal_CloseBalIstr_104s_01 0 "Nomal" 1 "Fault" ;
VAL_ 2417946177 S2P_Bal_CCanTimeOut_104s_01 0 "Nomal" 1 "Fault" ;
VAL_ 2417946177 S2P_Bal_BalanCirFlt_104s_01 0 "Nomal" 1 "Fault" ;
VAL_ 2417946178 S2P_Bal_CSCNum_104s_02 0 "No CSC" 1 "CSC 1" 2 "CSC 2" 3 "CSC 3" 4 "CSC 4" 5 "CSC 5" 6 "CSC 6" 7 "CSC 7" 8 "CSC 8" 9 "CSC 9" 10 "CSC 10" 11 "CSC 11" 12 "CSC 12" 13 "CSC 13" 14 "CSC 14" 15 "CSC 15" 16 "CSC 16" 17 "CSC 17" 18 "CSC 18" 19 "CSC 19" 20 "CSC 20" 21 "CSC 21" 22 "CSC 22" 23 "CSC 23" 24 "CSC 24" 25 "CSC 25" 26 "CSC 26" 27 "CSC 27" 28 "CSC 28" 29 "CSC 29" 30 "CSC 30" 31 "CSC 31" ;
VAL_ 2417946178 S2P_Bal_CellNum_104s_02 1 "Cell 1" 2 "Cell 2" 3 "Cell 3" 4 "Cell 4" 5 "Cell 5" 6 "Cell 6" 7 "Cell 7" 8 "Cell 8" 9 "Cell 9" 10 "Cell 10" 11 "Cell 11" 12 "Cell 12" 13 "Cell 13" 14 "Cell 14" 15 "Cell 15" 16 "Cell 16" 127 "Null" ;
VAL_ 2417946178 S2P_Bal_Type_104s_02 0 "Balance stop" 1 "charge Balance" 2 "discharge Balance" ;
VAL_ 2417946178 S2P_Bal_TypeLevel_104s_02 0 "Not Balance" 1 "Low end Balance" 2 "High end Balance" 3 "Force Balance" ;
VAL_ 2417946178 S2P_Bal_Strategy_104s_02 0 "Active Balance" 1 "Passive Static" ;
VAL_ 2417946178 S2P_Bal_ForceBalMode_104s_02 1 "Base on time " 2 "Base on Target Vol" 3 "Base on Ave Vol" ;
VAL_ 2417946178 S2P_Bal_CellTempFault_104s_02 0 "Nomal" 1 "Fault" ;
VAL_ 2417946178 S2P_Bal_CellVoltFail_104s_02 0 "Nomal" 1 "Fault" ;
VAL_ 2417946178 S2P_Bal_CloseBalIstr_104s_02 0 "Nomal" 1 "Fault" ;
VAL_ 2417946178 S2P_Bal_CCanTimeOut_104s_02 0 "Nomal" 1 "Fault" ;
VAL_ 2417946178 S2P_Bal_BalanCirFlt_104s_02 0 "Nomal" 1 "Fault" ;
VAL_ 2417946179 S2P_Bal_CSCNum_104s_03 0 "No CSC" 1 "CSC 1" 2 "CSC 2" 3 "CSC 3" 4 "CSC 4" 5 "CSC 5" 6 "CSC 6" 7 "CSC 7" 8 "CSC 8" 9 "CSC 9" 10 "CSC 10" 11 "CSC 11" 12 "CSC 12" 13 "CSC 13" 14 "CSC 14" 15 "CSC 15" 16 "CSC 16" 17 "CSC 17" 18 "CSC 18" 19 "CSC 19" 20 "CSC 20" 21 "CSC 21" 22 "CSC 22" 23 "CSC 23" 24 "CSC 24" 25 "CSC 25" 26 "CSC 26" 27 "CSC 27" 28 "CSC 28" 29 "CSC 29" 30 "CSC 30" 31 "CSC 31" ;
VAL_ 2417946179 S2P_Bal_CellNum_104s_03 1 "Cell 1" 2 "Cell 2" 3 "Cell 3" 4 "Cell 4" 5 "Cell 5" 6 "Cell 6" 7 "Cell 7" 8 "Cell 8" 9 "Cell 9" 10 "Cell 10" 11 "Cell 11" 12 "Cell 12" 13 "Cell 13" 14 "Cell 14" 15 "Cell 15" 16 "Cell 16" 127 "Null" ;
VAL_ 2417946179 S2P_Bal_Type_104s_03 0 "Balance stop" 1 "charge Balance" 2 "discharge Balance" ;
VAL_ 2417946179 S2P_Bal_TypeLevel_104s_03 0 "Not Balance" 1 "Low end Balance" 2 "High end Balance" 3 "Force Balance" ;
VAL_ 2417946179 S2P_Bal_Strategy_104s_03 0 "Active Balance" 1 "Passive Static" ;
VAL_ 2417946179 S2P_Bal_ForceBalMode_104s_03 1 "Base on time " 2 "Base on Target Vol" 3 "Base on Ave Vol" ;
VAL_ 2417946179 S2P_Bal_CellTempFault_104s_03 0 "Nomal" 1 "Fault" ;
VAL_ 2417946179 S2P_Bal_CellVoltFail_104s_03 0 "Nomal" 1 "Fault" ;
VAL_ 2417946179 S2P_Bal_CloseBalIstr_104s_03 0 "Nomal" 1 "Fault" ;
VAL_ 2417946179 S2P_Bal_CCanTimeOut_104s_03 0 "Nomal" 1 "Fault" ;
VAL_ 2417946179 S2P_Bal_BalanCirFlt_104s_03 0 "Nomal" 1 "Fault" ;
VAL_ 2417946180 S2P_Bal_CSCNum_104s_04 0 "No CSC" 1 "CSC 1" 2 "CSC 2" 3 "CSC 3" 4 "CSC 4" 5 "CSC 5" 6 "CSC 6" 7 "CSC 7" 8 "CSC 8" 9 "CSC 9" 10 "CSC 10" 11 "CSC 11" 12 "CSC 12" 13 "CSC 13" 14 "CSC 14" 15 "CSC 15" 16 "CSC 16" 17 "CSC 17" 18 "CSC 18" 19 "CSC 19" 20 "CSC 20" 21 "CSC 21" 22 "CSC 22" 23 "CSC 23" 24 "CSC 24" 25 "CSC 25" 26 "CSC 26" 27 "CSC 27" 28 "CSC 28" 29 "CSC 29" 30 "CSC 30" 31 "CSC 31" ;
VAL_ 2417946180 S2P_Bal_CellNum_104s_04 1 "Cell 1" 2 "Cell 2" 3 "Cell 3" 4 "Cell 4" 5 "Cell 5" 6 "Cell 6" 7 "Cell 7" 8 "Cell 8" 9 "Cell 9" 10 "Cell 10" 11 "Cell 11" 12 "Cell 12" 13 "Cell 13" 14 "Cell 14" 15 "Cell 15" 16 "Cell 16" 127 "Null" ;
VAL_ 2417946180 S2P_Bal_Type_104s_04 0 "Balance stop" 1 "charge Balance" 2 "discharge Balance" ;
VAL_ 2417946180 S2P_Bal_TypeLevel_104s_04 0 "Not Balance" 1 "Low end Balance" 2 "High end Balance" 3 "Force Balance" ;
VAL_ 2417946180 S2P_Bal_Strategy_104s_04 0 "Active Balance" 1 "Passive Static" ;
VAL_ 2417946180 S2P_Bal_ForceBalMode_104s_04 1 "Base on time " 2 "Base on Target Vol" 3 "Base on Ave Vol" ;
VAL_ 2417946180 S2P_Bal_CellTempFault_104s_04 0 "Nomal" 1 "Fault" ;
VAL_ 2417946180 S2P_Bal_CellVoltFail_104s_04 0 "Nomal" 1 "Fault" ;
VAL_ 2417946180 S2P_Bal_CloseBalIstr_104s_04 0 "Nomal" 1 "Fault" ;
VAL_ 2417946180 S2P_Bal_CCanTimeOut_104s_04 0 "Nomal" 1 "Fault" ;
VAL_ 2417946180 S2P_Bal_BalanCirFlt_104s_04 0 "Nomal" 1 "Fault" ;
VAL_ 2417946181 S2P_Bal_CSCNum_104s_05 0 "No CSC" 1 "CSC 1" 2 "CSC 2" 3 "CSC 3" 4 "CSC 4" 5 "CSC 5" 6 "CSC 6" 7 "CSC 7" 8 "CSC 8" 9 "CSC 9" 10 "CSC 10" 11 "CSC 11" 12 "CSC 12" 13 "CSC 13" 14 "CSC 14" 15 "CSC 15" 16 "CSC 16" 17 "CSC 17" 18 "CSC 18" 19 "CSC 19" 20 "CSC 20" 21 "CSC 21" 22 "CSC 22" 23 "CSC 23" 24 "CSC 24" 25 "CSC 25" 26 "CSC 26" 27 "CSC 27" 28 "CSC 28" 29 "CSC 29" 30 "CSC 30" 31 "CSC 31" ;
VAL_ 2417946181 S2P_Bal_CellNum_104s_05 1 "Cell 1" 2 "Cell 2" 3 "Cell 3" 4 "Cell 4" 5 "Cell 5" 6 "Cell 6" 7 "Cell 7" 8 "Cell 8" 9 "Cell 9" 10 "Cell 10" 11 "Cell 11" 12 "Cell 12" 13 "Cell 13" 14 "Cell 14" 15 "Cell 15" 16 "Cell 16" 127 "Null" ;
VAL_ 2417946181 S2P_Bal_Type_104s_05 0 "Balance stop" 1 "charge Balance" 2 "discharge Balance" ;
VAL_ 2417946181 S2P_Bal_TypeLevel_104s_05 0 "Not Balance" 1 "Low end Balance" 2 "High end Balance" 3 "Force Balance" ;
VAL_ 2417946181 S2P_Bal_Strategy_104s_05 0 "Active Balance" 1 "Passive Static" ;
VAL_ 2417946181 S2P_Bal_ForceBalMode_104s_05 1 "Base on time " 2 "Base on Target Vol" 3 "Base on Ave Vol" ;
VAL_ 2417946181 S2P_Bal_CellTempFault_104s_05 0 "Nomal" 1 "Fault" ;
VAL_ 2417946181 S2P_Bal_CellVoltFail_104s_05 0 "Nomal" 1 "Fault" ;
VAL_ 2417946181 S2P_Bal_CloseBalIstr_104s_05 0 "Nomal" 1 "Fault" ;
VAL_ 2417946181 S2P_Bal_CCanTimeOut_104s_05 0 "Nomal" 1 "Fault" ;
VAL_ 2417946181 S2P_Bal_BalanCirFlt_104s_05 0 "Nomal" 1 "Fault" ;
VAL_ 2417946182 S2P_Bal_CSCNum_104s_06 0 "No CSC" 1 "CSC 1" 2 "CSC 2" 3 "CSC 3" 4 "CSC 4" 5 "CSC 5" 6 "CSC 6" 7 "CSC 7" 8 "CSC 8" 9 "CSC 9" 10 "CSC 10" 11 "CSC 11" 12 "CSC 12" 13 "CSC 13" 14 "CSC 14" 15 "CSC 15" 16 "CSC 16" 17 "CSC 17" 18 "CSC 18" 19 "CSC 19" 20 "CSC 20" 21 "CSC 21" 22 "CSC 22" 23 "CSC 23" 24 "CSC 24" 25 "CSC 25" 26 "CSC 26" 27 "CSC 27" 28 "CSC 28" 29 "CSC 29" 30 "CSC 30" 31 "CSC 31" ;
VAL_ 2417946182 S2P_Bal_CellNum_104s_06 1 "Cell 1" 2 "Cell 2" 3 "Cell 3" 4 "Cell 4" 5 "Cell 5" 6 "Cell 6" 7 "Cell 7" 8 "Cell 8" 9 "Cell 9" 10 "Cell 10" 11 "Cell 11" 12 "Cell 12" 13 "Cell 13" 14 "Cell 14" 15 "Cell 15" 16 "Cell 16" 127 "Null" ;
VAL_ 2417946182 S2P_Bal_Type_104s_06 0 "Balance stop" 1 "charge Balance" 2 "discharge Balance" ;
VAL_ 2417946182 S2P_Bal_TypeLevel_104s_06 0 "Not Balance" 1 "Low end Balance" 2 "High end Balance" 3 "Force Balance" ;
VAL_ 2417946182 S2P_Bal_Strategy_104s_06 0 "Active Balance" 1 "Passive Static" ;
VAL_ 2417946182 S2P_Bal_ForceBalMode_104s_06 1 "Base on time " 2 "Base on Target Vol" 3 "Base on Ave Vol" ;
VAL_ 2417946182 S2P_Bal_CellTempFault_104s_06 0 "Nomal" 1 "Fault" ;
VAL_ 2417946182 S2P_Bal_CellVoltFail_104s_06 0 "Nomal" 1 "Fault" ;
VAL_ 2417946182 S2P_Bal_CloseBalIstr_104s_06 0 "Nomal" 1 "Fault" ;
VAL_ 2417946182 S2P_Bal_CCanTimeOut_104s_06 0 "Nomal" 1 "Fault" ;
VAL_ 2417946182 S2P_Bal_BalanCirFlt_104s_06 0 "Nomal" 1 "Fault" ;
VAL_ 2417946183 S2P_Bal_CSCNum_104s_07 0 "No CSC" 1 "CSC 1" 2 "CSC 2" 3 "CSC 3" 4 "CSC 4" 5 "CSC 5" 6 "CSC 6" 7 "CSC 7" 8 "CSC 8" 9 "CSC 9" 10 "CSC 10" 11 "CSC 11" 12 "CSC 12" 13 "CSC 13" 14 "CSC 14" 15 "CSC 15" 16 "CSC 16" 17 "CSC 17" 18 "CSC 18" 19 "CSC 19" 20 "CSC 20" 21 "CSC 21" 22 "CSC 22" 23 "CSC 23" 24 "CSC 24" 25 "CSC 25" 26 "CSC 26" 27 "CSC 27" 28 "CSC 28" 29 "CSC 29" 30 "CSC 30" 31 "CSC 31" ;
VAL_ 2417946183 S2P_Bal_CellNum_104s_07 1 "Cell 1" 2 "Cell 2" 3 "Cell 3" 4 "Cell 4" 5 "Cell 5" 6 "Cell 6" 7 "Cell 7" 8 "Cell 8" 9 "Cell 9" 10 "Cell 10" 11 "Cell 11" 12 "Cell 12" 13 "Cell 13" 14 "Cell 14" 15 "Cell 15" 16 "Cell 16" 127 "Null" ;
VAL_ 2417946183 S2P_Bal_Type_104s_07 0 "Balance stop" 1 "charge Balance" 2 "discharge Balance" ;
VAL_ 2417946183 S2P_Bal_TypeLevel_104s_07 0 "Not Balance" 1 "Low end Balance" 2 "High end Balance" 3 "Force Balance" ;
VAL_ 2417946183 S2P_Bal_Strategy_104s_07 0 "Active Balance" 1 "Passive Static" ;
VAL_ 2417946183 S2P_Bal_ForceBalMode_104s_07 1 "Base on time " 2 "Base on Target Vol" 3 "Base on Ave Vol" ;
VAL_ 2417946183 S2P_Bal_CellTempFault_104s_07 0 "Nomal" 1 "Fault" ;
VAL_ 2417946183 S2P_Bal_CellVoltFail_104s_07 0 "Nomal" 1 "Fault" ;
VAL_ 2417946183 S2P_Bal_CloseBalIstr_104s_07 0 "Nomal" 1 "Fault" ;
VAL_ 2417946183 S2P_Bal_CCanTimeOut_104s_07 0 "Nomal" 1 "Fault" ;
VAL_ 2417946183 S2P_Bal_BalanCirFlt_104s_07 0 "Nomal" 1 "Fault" ;
VAL_ 2417946184 S2P_Bal_CSCNum_104s_08 0 "No CSC" 1 "CSC 1" 2 "CSC 2" 3 "CSC 3" 4 "CSC 4" 5 "CSC 5" 6 "CSC 6" 7 "CSC 7" 8 "CSC 8" 9 "CSC 9" 10 "CSC 10" 11 "CSC 11" 12 "CSC 12" 13 "CSC 13" 14 "CSC 14" 15 "CSC 15" 16 "CSC 16" 17 "CSC 17" 18 "CSC 18" 19 "CSC 19" 20 "CSC 20" 21 "CSC 21" 22 "CSC 22" 23 "CSC 23" 24 "CSC 24" 25 "CSC 25" 26 "CSC 26" 27 "CSC 27" 28 "CSC 28" 29 "CSC 29" 30 "CSC 30" 31 "CSC 31" ;
VAL_ 2417946184 S2P_Bal_CellNum_104s_08 1 "Cell 1" 2 "Cell 2" 3 "Cell 3" 4 "Cell 4" 5 "Cell 5" 6 "Cell 6" 7 "Cell 7" 8 "Cell 8" 9 "Cell 9" 10 "Cell 10" 11 "Cell 11" 12 "Cell 12" 13 "Cell 13" 14 "Cell 14" 15 "Cell 15" 16 "Cell 16" 127 "Null" ;
VAL_ 2417946184 S2P_Bal_Type_104s_08 0 "Balance stop" 1 "charge Balance" 2 "discharge Balance" ;
VAL_ 2417946184 S2P_Bal_TypeLevel_104s_08 0 "Not Balance" 1 "Low end Balance" 2 "High end Balance" 3 "Force Balance" ;
VAL_ 2417946184 S2P_Bal_Strategy_104s_08 0 "Active Balance" 1 "Passive Static" ;
VAL_ 2417946184 S2P_Bal_ForceBalMode_104s_08 1 "Base on time " 2 "Base on Target Vol" 3 "Base on Ave Vol" ;
VAL_ 2417946184 S2P_Bal_CellTempFault_104s_08 0 "Nomal" 1 "Fault" ;
VAL_ 2417946184 S2P_Bal_CellVoltFail_104s_08 0 "Nomal" 1 "Fault" ;
VAL_ 2417946184 S2P_Bal_CloseBalIstr_104s_08 0 "Nomal" 1 "Fault" ;
VAL_ 2417946184 S2P_Bal_CCanTimeOut_104s_08 0 "Nomal" 1 "Fault" ;
VAL_ 2417946184 S2P_Bal_BalanCirFlt_104s_08 0 "Nomal" 1 "Fault" ;
VAL_ 2417946185 S2P_Bal_CSCNum_104s_09 0 "No CSC" 1 "CSC 1" 2 "CSC 2" 3 "CSC 3" 4 "CSC 4" 5 "CSC 5" 6 "CSC 6" 7 "CSC 7" 8 "CSC 8" 9 "CSC 9" 10 "CSC 10" 11 "CSC 11" 12 "CSC 12" 13 "CSC 13" 14 "CSC 14" 15 "CSC 15" 16 "CSC 16" 17 "CSC 17" 18 "CSC 18" 19 "CSC 19" 20 "CSC 20" 21 "CSC 21" 22 "CSC 22" 23 "CSC 23" 24 "CSC 24" 25 "CSC 25" 26 "CSC 26" 27 "CSC 27" 28 "CSC 28" 29 "CSC 29" 30 "CSC 30" 31 "CSC 31" ;
VAL_ 2417946185 S2P_Bal_CellNum_104s_09 1 "Cell 1" 2 "Cell 2" 3 "Cell 3" 4 "Cell 4" 5 "Cell 5" 6 "Cell 6" 7 "Cell 7" 8 "Cell 8" 9 "Cell 9" 10 "Cell 10" 11 "Cell 11" 12 "Cell 12" 13 "Cell 13" 14 "Cell 14" 15 "Cell 15" 16 "Cell 16" 127 "Null" ;
VAL_ 2417946185 S2P_Bal_Type_104s_09 0 "Balance stop" 1 "charge Balance" 2 "discharge Balance" ;
VAL_ 2417946185 S2P_Bal_TypeLevel_104s_09 0 "Not Balance" 1 "Low end Balance" 2 "High end Balance" 3 "Force Balance" ;
VAL_ 2417946185 S2P_Bal_Strategy_104s_09 0 "Active Balance" 1 "Passive Static" ;
VAL_ 2417946185 S2P_Bal_ForceBalMode_104s_09 1 "Base on time " 2 "Base on Target Vol" 3 "Base on Ave Vol" ;
VAL_ 2417946185 S2P_Bal_CellTempFault_104s_09 0 "Nomal" 1 "Fault" ;
VAL_ 2417946185 S2P_Bal_CellVoltFail_104s_09 0 "Nomal" 1 "Fault" ;
VAL_ 2417946185 S2P_Bal_CloseBalIstr_104s_09 0 "Nomal" 1 "Fault" ;
VAL_ 2417946185 S2P_Bal_CCanTimeOut_104s_09 0 "Nomal" 1 "Fault" ;
VAL_ 2417946185 S2P_Bal_BalanCirFlt_104s_09 0 "Nomal" 1 "Fault" ;
VAL_ 2417946186 S2P_Bal_CSCNum_104s_10 0 "No CSC" 1 "CSC 1" 2 "CSC 2" 3 "CSC 3" 4 "CSC 4" 5 "CSC 5" 6 "CSC 6" 7 "CSC 7" 8 "CSC 8" 9 "CSC 9" 10 "CSC 10" 11 "CSC 11" 12 "CSC 12" 13 "CSC 13" 14 "CSC 14" 15 "CSC 15" 16 "CSC 16" 17 "CSC 17" 18 "CSC 18" 19 "CSC 19" 20 "CSC 20" 21 "CSC 21" 22 "CSC 22" 23 "CSC 23" 24 "CSC 24" 25 "CSC 25" 26 "CSC 26" 27 "CSC 27" 28 "CSC 28" 29 "CSC 29" 30 "CSC 30" 31 "CSC 31" ;
VAL_ 2417946186 S2P_Bal_CellNum_104s_10 1 "Cell 1" 2 "Cell 2" 3 "Cell 3" 4 "Cell 4" 5 "Cell 5" 6 "Cell 6" 7 "Cell 7" 8 "Cell 8" 9 "Cell 9" 10 "Cell 10" 11 "Cell 11" 12 "Cell 12" 13 "Cell 13" 14 "Cell 14" 15 "Cell 15" 16 "Cell 16" 127 "Null" ;
VAL_ 2417946186 S2P_Bal_Type_104s_10 0 "Balance stop" 1 "charge Balance" 2 "discharge Balance" ;
VAL_ 2417946186 S2P_Bal_TypeLevel_104s_10 0 "Not Balance" 1 "Low end Balance" 2 "High end Balance" 3 "Force Balance" ;
VAL_ 2417946186 S2P_Bal_Strategy_104s_10 0 "Active Balance" 1 "Passive Static" ;
VAL_ 2417946186 S2P_Bal_ForceBalMode_104s_10 1 "Base on time " 2 "Base on Target Vol" 3 "Base on Ave Vol" ;
VAL_ 2417946186 S2P_Bal_CellTempFault_104s_10 0 "Nomal" 1 "Fault" ;
VAL_ 2417946186 S2P_Bal_CellVoltFail_104s_10 0 "Nomal" 1 "Fault" ;
VAL_ 2417946186 S2P_Bal_CloseBalIstr_104s_10 0 "Nomal" 1 "Fault" ;
VAL_ 2417946186 S2P_Bal_CCanTimeOut_104s_10 0 "Nomal" 1 "Fault" ;
VAL_ 2417946186 S2P_Bal_BalanCirFlt_104s_10 0 "Nomal" 1 "Fault" ;
VAL_ 2417946187 S2P_Bal_CSCNum_104s_11 0 "No CSC" 1 "CSC 1" 2 "CSC 2" 3 "CSC 3" 4 "CSC 4" 5 "CSC 5" 6 "CSC 6" 7 "CSC 7" 8 "CSC 8" 9 "CSC 9" 10 "CSC 10" 11 "CSC 11" 12 "CSC 12" 13 "CSC 13" 14 "CSC 14" 15 "CSC 15" 16 "CSC 16" 17 "CSC 17" 18 "CSC 18" 19 "CSC 19" 20 "CSC 20" 21 "CSC 21" 22 "CSC 22" 23 "CSC 23" 24 "CSC 24" 25 "CSC 25" 26 "CSC 26" 27 "CSC 27" 28 "CSC 28" 29 "CSC 29" 30 "CSC 30" 31 "CSC 31" ;
VAL_ 2417946187 S2P_Bal_CellNum_104s_11 1 "Cell 1" 2 "Cell 2" 3 "Cell 3" 4 "Cell 4" 5 "Cell 5" 6 "Cell 6" 7 "Cell 7" 8 "Cell 8" 9 "Cell 9" 10 "Cell 10" 11 "Cell 11" 12 "Cell 12" 13 "Cell 13" 14 "Cell 14" 15 "Cell 15" 16 "Cell 16" 127 "Null" ;
VAL_ 2417946187 S2P_Bal_Type_104s_11 0 "Balance stop" 1 "charge Balance" 2 "discharge Balance" ;
VAL_ 2417946187 S2P_Bal_TypeLevel_104s_11 0 "Not Balance" 1 "Low end Balance" 2 "High end Balance" 3 "Force Balance" ;
VAL_ 2417946187 S2P_Bal_Strategy_104s_11 0 "Active Balance" 1 "Passive Static" ;
VAL_ 2417946187 S2P_Bal_ForceBalMode_104s_11 1 "Base on time " 2 "Base on Target Vol" 3 "Base on Ave Vol" ;
VAL_ 2417946187 S2P_Bal_CellTempFault_104s_11 0 "Nomal" 1 "Fault" ;
VAL_ 2417946187 S2P_Bal_CellVoltFail_104s_11 0 "Nomal" 1 "Fault" ;
VAL_ 2417946187 S2P_Bal_CloseBalIstr_104s_11 0 "Nomal" 1 "Fault" ;
VAL_ 2417946187 S2P_Bal_CCanTimeOut_104s_11 0 "Nomal" 1 "Fault" ;
VAL_ 2417946187 S2P_Bal_BalanCirFlt_104s_11 0 "Nomal" 1 "Fault" ;
VAL_ 2417946188 S2P_Bal_CSCNum_104s_12 0 "No CSC" 1 "CSC 1" 2 "CSC 2" 3 "CSC 3" 4 "CSC 4" 5 "CSC 5" 6 "CSC 6" 7 "CSC 7" 8 "CSC 8" 9 "CSC 9" 10 "CSC 10" 11 "CSC 11" 12 "CSC 12" 13 "CSC 13" 14 "CSC 14" 15 "CSC 15" 16 "CSC 16" 17 "CSC 17" 18 "CSC 18" 19 "CSC 19" 20 "CSC 20" 21 "CSC 21" 22 "CSC 22" 23 "CSC 23" 24 "CSC 24" 25 "CSC 25" 26 "CSC 26" 27 "CSC 27" 28 "CSC 28" 29 "CSC 29" 30 "CSC 30" 31 "CSC 31" ;
VAL_ 2417946188 S2P_Bal_CellNum_104s_12 1 "Cell 1" 2 "Cell 2" 3 "Cell 3" 4 "Cell 4" 5 "Cell 5" 6 "Cell 6" 7 "Cell 7" 8 "Cell 8" 9 "Cell 9" 10 "Cell 10" 11 "Cell 11" 12 "Cell 12" 13 "Cell 13" 14 "Cell 14" 15 "Cell 15" 16 "Cell 16" 127 "Null" ;
VAL_ 2417946188 S2P_Bal_Type_104s_12 0 "Balance stop" 1 "charge Balance" 2 "discharge Balance" ;
VAL_ 2417946188 S2P_Bal_TypeLevel_104s_12 0 "Not Balance" 1 "Low end Balance" 2 "High end Balance" 3 "Force Balance" ;
VAL_ 2417946188 S2P_Bal_Strategy_104s_12 0 "Active Balance" 1 "Passive Static" ;
VAL_ 2417946188 S2P_Bal_ForceBalMode_104s_12 1 "Base on time " 2 "Base on Target Vol" 3 "Base on Ave Vol" ;
VAL_ 2417946188 S2P_Bal_CellTempFault_104s_12 0 "Nomal" 1 "Fault" ;
VAL_ 2417946188 S2P_Bal_CellVoltFail_104s_12 0 "Nomal" 1 "Fault" ;
VAL_ 2417946188 S2P_Bal_CloseBalIstr_104s_12 0 "Nomal" 1 "Fault" ;
VAL_ 2417946188 S2P_Bal_CCanTimeOut_104s_12 0 "Nomal" 1 "Fault" ;
VAL_ 2417946188 S2P_Bal_BalanCirFlt_104s_12 0 "Nomal" 1 "Fault" ;
VERSION ""

NS_ :

BS_:

BU_: MBMU PC SBMU IMM ETH DCDC LEMS

BO_ 2417946189 S2P_BL_Meg_104s__13: 8 SBMU
 SG_ S2P_Bal_CSCNum_104s_13 : 0|5@1+ (1,0) [0|31] ""  PC
 SG_ S2P_Bal_CellNum_104s_13 : 5|7@1+ (1,0) [0|127] ""  PC
 SG_ S2P_Bal_Type_104s_13 : 12|2@1+ (1,0) [0|3] ""  PC
 SG_ S2P_Bal_TimeRemain_104s_13 : 14|9@1+ (1,0) [0|511] ""  PC
 SG_ S2P_Bal_DeltaVolt_104s_13 : 23|10@1+ (1,0) [0|1023] ""  PC
 SG_ S2P_Bal_TypeLevel_104s_13 : 44|3@1+ (1,0) [0|7] ""  PC
 SG_ S2P_Bal_Strategy_104s_13 : 49|1@1+ (1,0) [0|1] ""  PC
 SG_ S2P_Bal_ForceBalMode_104s_13 : 50|2@1+ (1,0) [0|3] ""  PC
 SG_ S2P_Bal_CellTempFault_104s_13 : 52|1@1+ (1,0) [0|1] ""  PC
 SG_ S2P_Bal_CellVoltFail_104s_13 : 53|1@1+ (1,0) [0|1] ""  PC
 SG_ S2P_Bal_CloseBalIstr_104s_13 : 54|1@1+ (1,0) [0|1] ""  PC
 SG_ S2P_Bal_CCanTimeOut_104s_13 : 55|1@1+ (1,0) [0|1] ""  PC
 SG_ S2P_Bal_CellOffLine_104s_13 : 56|1@1+ (1,0) [0|1] ""  PC
 SG_ S2P_Bal_BalanCirFlt_104s_13 : 57|1@1+ (1,0) [0|1] ""  PC
 SG_ S2P_Bal_CellVoOverFlt104s_13 : 59|1@1+ (1,0) [0|1] ""  PC
 SG_ S2P_Bal_CellVoLowFlt104s_13 : 60|1@1+ (1,0) [0|1] ""  PC
 SG_ S2P_Bal_CSCPCBTeFlt104s_13 : 61|1@1+ (1,0) [0|1] ""  PC

BO_ 2417946190 S2P_BL_Meg_104s__14: 8 SBMU
 SG_ S2P_Bal_CSCNum_104s_14 : 0|5@1+ (1,0) [0|31] ""  PC
 SG_ S2P_Bal_CellNum_104s_14 : 5|7@1+ (1,0) [0|127] ""  PC
 SG_ S2P_Bal_Type_104s_14 : 12|2@1+ (1,0) [0|3] ""  PC
 SG_ S2P_Bal_TimeRemain_104s_14 : 14|9@1+ (1,0) [0|511] ""  PC
 SG_ S2P_Bal_DeltaVolt_104s_14 : 23|10@1+ (1,0) [0|1023] ""  PC
 SG_ S2P_Bal_TypeLevel_104s_14 : 44|3@1+ (1,0) [0|7] ""  PC
 SG_ S2P_Bal_Strategy_104s_14 : 49|1@1+ (1,0) [0|1] ""  PC
 SG_ S2P_Bal_ForceBalMode_104s_14 : 50|2@1+ (1,0) [0|3] ""  PC
 SG_ S2P_Bal_CellTempFault_104s_14 : 52|1@1+ (1,0) [0|1] ""  PC
 SG_ S2P_Bal_CellVoltFail_104s_14 : 53|1@1+ (1,0) [0|1] ""  PC
 SG_ S2P_Bal_CloseBalIstr_104s_14 : 54|1@1+ (1,0) [0|1] ""  PC
 SG_ S2P_Bal_CCanTimeOut_104s_14 : 55|1@1+ (1,0) [0|1] ""  PC
 SG_ S2P_Bal_CellOffLine_104s_14 : 56|1@1+ (1,0) [0|1] ""  PC
 SG_ S2P_Bal_BalanCirFlt_104s_14 : 57|1@1+ (1,0) [0|1] ""  PC
 SG_ S2P_Bal_CellVoOverFlt104s_14 : 59|1@1+ (1,0) [0|1] ""  PC
 SG_ S2P_Bal_CellVoLowFlt104s_14 : 60|1@1+ (1,0) [0|1] ""  PC
 SG_ S2P_Bal_CSCPCBTeFlt104s_14 : 61|1@1+ (1,0) [0|1] ""  PC

BO_ 2417946191 S2P_BL_Meg_104s__15: 8 SBMU
 SG_ S2P_Bal_CSCNum_104s_15 : 0|5@1+ (1,0) [0|31] ""  PC
 SG_ S2P_Bal_CellNum_104s_15 : 5|7@1+ (1,0) [0|127] ""  PC
 SG_ S2P_Bal_Type_104s_15 : 12|2@1+ (1,0) [0|3] ""  PC
 SG_ S2P_Bal_TimeRemain_104s_15 : 14|9@1+ (1,0) [0|511] ""  PC
 SG_ S2P_Bal_DeltaVolt_104s_15 : 23|10@1+ (1,0) [0|1023] ""  PC
 SG_ S2P_Bal_TypeLevel_104s_15 : 44|3@1+ (1,0) [0|7] ""  PC
 SG_ S2P_Bal_Strategy_104s_15 : 49|1@1+ (1,0) [0|1] ""  PC
 SG_ S2P_Bal_ForceBalMode_104s_15 : 50|2@1+ (1,0) [0|3] ""  PC
 SG_ S2P_Bal_CellTempFault_104s_15 : 52|1@1+ (1,0) [0|1] ""  PC
 SG_ S2P_Bal_CellVoltFail_104s_15 : 53|1@1+ (1,0) [0|1] ""  PC
 SG_ S2P_Bal_CloseBalIstr_104s_15 : 54|1@1+ (1,0) [0|1] ""  PC
 SG_ S2P_Bal_CCanTimeOut_104s_15 : 55|1@1+ (1,0) [0|1] ""  PC
 SG_ S2P_Bal_CellOffLine_104s_15 : 56|1@1+ (1,0) [0|1] ""  PC
 SG_ S2P_Bal_BalanCirFlt_104s_15 : 57|1@1+ (1,0) [0|1] ""  PC
 SG_ S2P_Bal_CellVoOverFlt104s_15 : 59|1@1+ (1,0) [0|1] ""  PC
 SG_ S2P_Bal_CellVoLowFlt104s_15 : 60|1@1+ (1,0) [0|1] ""  PC
 SG_ S2P_Bal_CSCPCBTeFlt104s_15 : 61|1@1+ (1,0) [0|1] ""  PC

BO_ 2417946192 S2P_BL_Meg_104s__16: 8 SBMU
 SG_ S2P_Bal_CSCNum_104s_16 : 0|5@1+ (1,0) [0|31] ""  PC
 SG_ S2P_Bal_CellNum_104s_16 : 5|7@1+ (1,0) [0|127] ""  PC
 SG_ S2P_Bal_Type_104s_16 : 12|2@1+ (1,0) [0|3] ""  PC
 SG_ S2P_Bal_TimeRemain_104s_16 : 14|9@1+ (1,0) [0|511] ""  PC
 SG_ S2P_Bal_DeltaVolt_104s_16 : 23|10@1+ (1,0) [0|1023] ""  PC
 SG_ S2P_Bal_TypeLevel_104s_16 : 44|3@1+ (1,0) [0|7] ""  PC
 SG_ S2P_Bal_Strategy_104s_16 : 49|1@1+ (1,0) [0|1] ""  PC
 SG_ S2P_Bal_ForceBalMode_104s_16 : 50|2@1+ (1,0) [0|3] ""  PC
 SG_ S2P_Bal_CellTempFault_104s_16 : 52|1@1+ (1,0) [0|1] ""  PC
 SG_ S2P_Bal_CellVoltFail_104s_16 : 53|1@1+ (1,0) [0|1] ""  PC
 SG_ S2P_Bal_CloseBalIstr_104s_16 : 54|1@1+ (1,0) [0|1] ""  PC
 SG_ S2P_Bal_CCanTimeOut_104s_16 : 55|1@1+ (1,0) [0|1] ""  PC
 SG_ S2P_Bal_CellOffLine_104s_16 : 56|1@1+ (1,0) [0|1] ""  PC
 SG_ S2P_Bal_BalanCirFlt_104s_16 : 57|1@1+ (1,0) [0|1] ""  PC
 SG_ S2P_Bal_CellVoOverFlt104s_16 : 59|1@1+ (1,0) [0|1] ""  PC
 SG_ S2P_Bal_CellVoLowFlt104s_16 : 60|1@1+ (1,0) [0|1] ""  PC
 SG_ S2P_Bal_CSCPCBTeFlt104s_16 : 61|1@1+ (1,0) [0|1] ""  PC

BO_ 2417946193 S2P_BL_Meg_104s__17: 8 SBMU
 SG_ S2P_Bal_CSCNum_104s_17 : 0|5@1+ (1,0) [0|31] ""  PC
 SG_ S2P_Bal_CellNum_104s_17 : 5|7@1+ (1,0) [0|127] ""  PC
 SG_ S2P_Bal_Type_104s_17 : 12|2@1+ (1,0) [0|3] ""  PC
 SG_ S2P_Bal_TimeRemain_104s_17 : 14|9@1+ (1,0) [0|511] ""  PC
 SG_ S2P_Bal_DeltaVolt_104s_17 : 23|10@1+ (1,0) [0|1023] ""  PC
 SG_ S2P_Bal_TypeLevel_104s_17 : 44|3@1+ (1,0) [0|7] ""  PC
 SG_ S2P_Bal_Strategy_104s_17 : 49|1@1+ (1,0) [0|1] ""  PC
 SG_ S2P_Bal_ForceBalMode_104s_17 : 50|2@1+ (1,0) [0|3] ""  PC
 SG_ S2P_Bal_CellTempFault_104s_17 : 52|1@1+ (1,0) [0|1] ""  PC
 SG_ S2P_Bal_CellVoltFail_104s_17 : 53|1@1+ (1,0) [0|1] ""  PC
 SG_ S2P_Bal_CloseBalIstr_104s_17 : 54|1@1+ (1,0) [0|1] ""  PC
 SG_ S2P_Bal_CCanTimeOut_104s_17 : 55|1@1+ (1,0) [0|1] ""  PC
 SG_ S2P_Bal_CellOffLine_104s_17 : 56|1@1+ (1,0) [0|1] ""  PC
 SG_ S2P_Bal_BalanCirFlt_104s_17 : 57|1@1+ (1,0) [0|1] ""  PC
 SG_ S2P_Bal_CellVoOverFlt104s_17 : 59|1@1+ (1,0) [0|1] ""  PC
 SG_ S2P_Bal_CellVoLowFlt104s_17 : 60|1@1+ (1,0) [0|1] ""  PC
 SG_ S2P_Bal_CSCPCBTeFlt104s_17 : 61|1@1+ (1,0) [0|1] ""  PC

BO_ 2417946194 S2P_BL_Meg_104s__18: 8 SBMU
 SG_ S2P_Bal_CSCNum_104s_18 : 0|5@1+ (1,0) [0|31] ""  PC
 SG_ S2P_Bal_CellNum_104s_18 : 5|7@1+ (1,0) [0|127] ""  PC
 SG_ S2P_Bal_Type_104s_18 : 12|2@1+ (1,0) [0|3] ""  PC
 SG_ S2P_Bal_TimeRemain_104s_18 : 14|9@1+ (1,0) [0|511] ""  PC
 SG_ S2P_Bal_DeltaVolt_104s_18 : 23|10@1+ (1,0) [0|1023] ""  PC
 SG_ S2P_Bal_TypeLevel_104s_18 : 44|3@1+ (1,0) [0|7] ""  PC
 SG_ S2P_Bal_Strategy_104s_18 : 49|1@1+ (1,0) [0|1] ""  PC
 SG_ S2P_Bal_ForceBalMode_104s_18 : 50|2@1+ (1,0) [0|3] ""  PC
 SG_ S2P_Bal_CellTempFault_104s_18 : 52|1@1+ (1,0) [0|1] ""  PC
 SG_ S2P_Bal_CellVoltFail_104s_18 : 53|1@1+ (1,0) [0|1] ""  PC
 SG_ S2P_Bal_CloseBalIstr_104s_18 : 54|1@1+ (1,0) [0|1] ""  PC
 SG_ S2P_Bal_CCanTimeOut_104s_18 : 55|1@1+ (1,0) [0|1] ""  PC
 SG_ S2P_Bal_CellOffLine_104s_18 : 56|1@1+ (1,0) [0|1] ""  PC
 SG_ S2P_Bal_BalanCirFlt_104s_18 : 57|1@1+ (1,0) [0|1] ""  PC
 SG_ S2P_Bal_CellVoOverFlt104s_18 : 59|1@1+ (1,0) [0|1] ""  PC
 SG_ S2P_Bal_CellVoLowFlt104s_18 : 60|1@1+ (1,0) [0|1] ""  PC
 SG_ S2P_Bal_CSCPCBTeFlt104s_18 : 61|1@1+ (1,0) [0|1] ""  PC

BO_ 2417946195 S2P_BL_Meg_104s__19: 8 SBMU
 SG_ S2P_Bal_CSCNum_104s_19 : 0|5@1+ (1,0) [0|31] ""  PC
 SG_ S2P_Bal_CellNum_104s_19 : 5|7@1+ (1,0) [0|127] ""  PC
 SG_ S2P_Bal_Type_104s_19 : 12|2@1+ (1,0) [0|3] ""  PC
 SG_ S2P_Bal_TimeRemain_104s_19 : 14|9@1+ (1,0) [0|511] ""  PC
 SG_ S2P_Bal_DeltaVolt_104s_19 : 23|10@1+ (1,0) [0|1023] ""  PC
 SG_ S2P_Bal_TypeLevel_104s_19 : 44|3@1+ (1,0) [0|7] ""  PC
 SG_ S2P_Bal_Strategy_104s_19 : 49|1@1+ (1,0) [0|1] ""  PC
 SG_ S2P_Bal_ForceBalMode_104s_19 : 50|2@1+ (1,0) [0|3] ""  PC
 SG_ S2P_Bal_CellTempFault_104s_19 : 52|1@1+ (1,0) [0|1] ""  PC
 SG_ S2P_Bal_CellVoltFail_104s_19 : 53|1@1+ (1,0) [0|1] ""  PC
 SG_ S2P_Bal_CloseBalIstr_104s_19 : 54|1@1+ (1,0) [0|1] ""  PC
 SG_ S2P_Bal_CCanTimeOut_104s_19 : 55|1@1+ (1,0) [0|1] ""  PC
 SG_ S2P_Bal_CellOffLine_104s_19 : 56|1@1+ (1,0) [0|1] ""  PC
 SG_ S2P_Bal_BalanCirFlt_104s_19 : 57|1@1+ (1,0) [0|1] ""  PC
 SG_ S2P_Bal_CellVoOverFlt104s_19 : 59|1@1+ (1,0) [0|1] ""  PC
 SG_ S2P_Bal_CellVoLowFlt104s_19 : 60|1@1+ (1,0) [0|1] ""  PC
 SG_ S2P_Bal_CSCPCBTeFlt104s_19 : 61|1@1+ (1,0) [0|1] ""  PC

BO_ 2417946196 S2P_BL_Meg_104s__20: 8 SBMU
 SG_ S2P_Bal_CSCNum_104s_20 : 0|5@1+ (1,0) [0|31] ""  PC
 SG_ S2P_Bal_CellNum_104s_20 : 5|7@1+ (1,0) [0|127] ""  PC
 SG_ S2P_Bal_Type_104s_20 : 12|2@1+ (1,0) [0|3] ""  PC
 SG_ S2P_Bal_TimeRemain_104s_20 : 14|9@1+ (1,0) [0|511] ""  PC
 SG_ S2P_Bal_DeltaVolt_104s_20 : 23|10@1+ (1,0) [0|1023] ""  PC
 SG_ S2P_Bal_TypeLevel_104s_20 : 44|3@1+ (1,0) [0|7] ""  PC
 SG_ S2P_Bal_Strategy_104s_20 : 49|1@1+ (1,0) [0|1] ""  PC
 SG_ S2P_Bal_ForceBalMode_104s_20 : 50|2@1+ (1,0) [0|3] ""  PC
 SG_ S2P_Bal_CellTempFault_104s_20 : 52|1@1+ (1,0) [0|1] ""  PC
 SG_ S2P_Bal_CellVoltFail_104s_20 : 53|1@1+ (1,0) [0|1] ""  PC
 SG_ S2P_Bal_CloseBalIstr_104s_20 : 54|1@1+ (1,0) [0|1] ""  PC
 SG_ S2P_Bal_CCanTimeOut_104s_20 : 55|1@1+ (1,0) [0|1] ""  PC
 SG_ S2P_Bal_CellOffLine_104s_20 : 56|1@1+ (1,0) [0|1] ""  PC
 SG_ S2P_Bal_BalanCirFlt_104s_20 : 57|1@1+ (1,0) [0|1] ""  PC
 SG_ S2P_Bal_CellVoOverFlt104s_20 : 59|1@1+ (1,0) [0|1] ""  PC
 SG_ S2P_Bal_CellVoLowFlt104s_20 : 60|1@1+ (1,0) [0|1] ""  PC
 SG_ S2P_Bal_CSCPCBTeFlt104s_20 : 61|1@1+ (1,0) [0|1] ""  PC

BO_ 2417946197 S2P_BL_Meg_104s__21: 8 SBMU
 SG_ S2P_Bal_CSCNum_104s_21 : 0|5@1+ (1,0) [0|31] ""  PC
 SG_ S2P_Bal_CellNum_104s_21 : 5|7@1+ (1,0) [0|127] ""  PC
 SG_ S2P_Bal_Type_104s_21 : 12|2@1+ (1,0) [0|3] ""  PC
 SG_ S2P_Bal_TimeRemain_104s_21 : 14|9@1+ (1,0) [0|511] ""  PC
 SG_ S2P_Bal_DeltaVolt_104s_21 : 23|10@1+ (1,0) [0|1023] ""  PC
 SG_ S2P_Bal_TypeLevel_104s_21 : 44|3@1+ (1,0) [0|7] ""  PC
 SG_ S2P_Bal_Strategy_104s_21 : 49|1@1+ (1,0) [0|1] ""  PC
 SG_ S2P_Bal_ForceBalMode_104s_21 : 50|2@1+ (1,0) [0|3] ""  PC
 SG_ S2P_Bal_CellTempFault_104s_21 : 52|1@1+ (1,0) [0|1] ""  PC
 SG_ S2P_Bal_CellVoltFail_104s_21 : 53|1@1+ (1,0) [0|1] ""  PC
 SG_ S2P_Bal_CloseBalIstr_104s_21 : 54|1@1+ (1,0) [0|1] ""  PC
 SG_ S2P_Bal_CCanTimeOut_104s_21 : 55|1@1+ (1,0) [0|1] ""  PC
 SG_ S2P_Bal_CellOffLine_104s_21 : 56|1@1+ (1,0) [0|1] ""  PC
 SG_ S2P_Bal_BalanCirFlt_104s_21 : 57|1@1+ (1,0) [0|1] ""  PC
 SG_ S2P_Bal_CellVoOverFlt104s_21 : 59|1@1+ (1,0) [0|1] ""  PC
 SG_ S2P_Bal_CellVoLowFlt104s_21 : 60|1@1+ (1,0) [0|1] ""  PC
 SG_ S2P_Bal_CSCPCBTeFlt104s_21 : 61|1@1+ (1,0) [0|1] ""  PC

BO_ 2417946198 S2P_BL_Meg_104s__22: 8 SBMU
 SG_ S2P_Bal_CSCNum_104s_22 : 0|5@1+ (1,0) [0|31] ""  PC
 SG_ S2P_Bal_CellNum_104s_22 : 5|7@1+ (1,0) [0|127] ""  PC
 SG_ S2P_Bal_Type_104s_22 : 12|2@1+ (1,0) [0|3] ""  PC
 SG_ S2P_Bal_TimeRemain_104s_22 : 14|9@1+ (1,0) [0|511] ""  PC
 SG_ S2P_Bal_DeltaVolt_104s_22 : 23|10@1+ (1,0) [0|1023] ""  PC
 SG_ S2P_Bal_TypeLevel_104s_22 : 44|3@1+ (1,0) [0|7] ""  PC
 SG_ S2P_Bal_Strategy_104s_22 : 49|1@1+ (1,0) [0|1] ""  PC
 SG_ S2P_Bal_ForceBalMode_104s_22 : 50|2@1+ (1,0) [0|3] ""  PC
 SG_ S2P_Bal_CellTempFault_104s_22 : 52|1@1+ (1,0) [0|1] ""  PC
 SG_ S2P_Bal_CellVoltFail_104s_22 : 53|1@1+ (1,0) [0|1] ""  PC
 SG_ S2P_Bal_CloseBalIstr_104s_22 : 54|1@1+ (1,0) [0|1] ""  PC
 SG_ S2P_Bal_CCanTimeOut_104s_22 : 55|1@1+ (1,0) [0|1] ""  PC
 SG_ S2P_Bal_CellOffLine_104s_22 : 56|1@1+ (1,0) [0|1] ""  PC
 SG_ S2P_Bal_BalanCirFlt_104s_22 : 57|1@1+ (1,0) [0|1] ""  PC
 SG_ S2P_Bal_CellVoOverFlt104s_22 : 59|1@1+ (1,0) [0|1] ""  PC
 SG_ S2P_Bal_CellVoLowFlt104s_22 : 60|1@1+ (1,0) [0|1] ""  PC
 SG_ S2P_Bal_CSCPCBTeFlt104s_22 : 61|1@1+ (1,0) [0|1] ""  PC

BO_ 2417946199 S2P_BL_Meg_104s__23: 8 SBMU
 SG_ S2P_Bal_CSCNum_104s_23 : 0|5@1+ (1,0) [0|31] ""  PC
 SG_ S2P_Bal_CellNum_104s_23 : 5|7@1+ (1,0) [0|127] ""  PC
 SG_ S2P_Bal_Type_104s_23 : 12|2@1+ (1,0) [0|3] ""  PC
 SG_ S2P_Bal_TimeRemain_104s_23 : 14|9@1+ (1,0) [0|511] ""  PC
 SG_ S2P_Bal_DeltaVolt_104s_23 : 23|10@1+ (1,0) [0|1023] ""  PC
 SG_ S2P_Bal_TypeLevel_104s_23 : 44|3@1+ (1,0) [0|7] ""  PC
 SG_ S2P_Bal_Strategy_104s_23 : 49|1@1+ (1,0) [0|1] ""  PC
 SG_ S2P_Bal_ForceBalMode_104s_23 : 50|2@1+ (1,0) [0|3] ""  PC
 SG_ S2P_Bal_CellTempFault_104s_23 : 52|1@1+ (1,0) [0|1] ""  PC
 SG_ S2P_Bal_CellVoltFail_104s_23 : 53|1@1+ (1,0) [0|1] ""  PC
 SG_ S2P_Bal_CloseBalIstr_104s_23 : 54|1@1+ (1,0) [0|1] ""  PC
 SG_ S2P_Bal_CCanTimeOut_104s_23 : 55|1@1+ (1,0) [0|1] ""  PC
 SG_ S2P_Bal_CellOffLine_104s_23 : 56|1@1+ (1,0) [0|1] ""  PC
 SG_ S2P_Bal_BalanCirFlt_104s_23 : 57|1@1+ (1,0) [0|1] ""  PC
 SG_ S2P_Bal_CellVoOverFlt104s_23 : 59|1@1+ (1,0) [0|1] ""  PC
 SG_ S2P_Bal_CellVoLowFlt104s_23 : 60|1@1+ (1,0) [0|1] ""  PC
 SG_ S2P_Bal_CSCPCBTeFlt104s_23 : 61|1@1+ (1,0) [0|1] ""  PC

BO_ 2417946200 S2P_BL_Meg_104s__24: 8 SBMU
 SG_ S2P_Bal_CSCNum_104s_24 : 0|5@1+ (1,0) [0|31] ""  PC
 SG_ S2P_Bal_CellNum_104s_24 : 5|7@1+ (1,0) [0|127] ""  PC
 SG_ S2P_Bal_Type_104s_24 : 12|2@1+ (1,0) [0|3] ""  PC
 SG_ S2P_Bal_TimeRemain_104s_24 : 14|9@1+ (1,0) [0|511] ""  PC
 SG_ S2P_Bal_DeltaVolt_104s_24 : 23|10@1+ (1,0) [0|1023] ""  PC
 SG_ S2P_Bal_TypeLevel_104s_24 : 44|3@1+ (1,0) [0|7] ""  PC
 SG_ S2P_Bal_Strategy_104s_24 : 49|1@1+ (1,0) [0|1] ""  PC
 SG_ S2P_Bal_ForceBalMode_104s_24 : 50|2@1+ (1,0) [0|3] ""  PC
 SG_ S2P_Bal_CellTempFault_104s_24 : 52|1@1+ (1,0) [0|1] ""  PC
 SG_ S2P_Bal_CellVoltFail_104s_24 : 53|1@1+ (1,0) [0|1] ""  PC
 SG_ S2P_Bal_CloseBalIstr_104s_24 : 54|1@1+ (1,0) [0|1] ""  PC
 SG_ S2P_Bal_CCanTimeOut_104s_24 : 55|1@1+ (1,0) [0|1] ""  PC
 SG_ S2P_Bal_CellOffLine_104s_24 : 56|1@1+ (1,0) [0|1] ""  PC
 SG_ S2P_Bal_BalanCirFlt_104s_24 : 57|1@1+ (1,0) [0|1] ""  PC
 SG_ S2P_Bal_CellVoOverFlt104s_24 : 59|1@1+ (1,0) [0|1] ""  PC
 SG_ S2P_Bal_CellVoLowFlt104s_24 : 60|1@1+ (1,0) [0|1] ""  PC
 SG_ S2P_Bal_CSCPCBTeFlt104s_24 : 61|1@1+ (1,0) [0|1] ""  PC

BO_ 2417946201 S2P_BL_Meg_104s__25: 8 SBMU
 SG_ S2P_Bal_CSCNum_104s_25 : 0|5@1+ (1,0) [0|31] ""  PC
 SG_ S2P_Bal_CellNum_104s_25 : 5|7@1+ (1,0) [0|127] ""  PC
 SG_ S2P_Bal_Type_104s_25 : 12|2@1+ (1,0) [0|3] ""  PC
 SG_ S2P_Bal_TimeRemain_104s_25 : 14|9@1+ (1,0) [0|511] ""  PC
 SG_ S2P_Bal_DeltaVolt_104s_25 : 23|10@1+ (1,0) [0|1023] ""  PC
 SG_ S2P_Bal_TypeLevel_104s_25 : 44|3@1+ (1,0) [0|7] ""  PC
 SG_ S2P_Bal_Strategy_104s_25 : 49|1@1+ (1,0) [0|1] ""  PC
 SG_ S2P_Bal_ForceBalMode_104s_25 : 50|2@1+ (1,0) [0|3] ""  PC
 SG_ S2P_Bal_CellTempFault_104s_25 : 52|1@1+ (1,0) [0|1] ""  PC
 SG_ S2P_Bal_CellVoltFail_104s_25 : 53|1@1+ (1,0) [0|1] ""  PC
 SG_ S2P_Bal_CloseBalIstr_104s_25 : 54|1@1+ (1,0) [0|1] ""  PC
 SG_ S2P_Bal_CCanTimeOut_104s_25 : 55|1@1+ (1,0) [0|1] ""  PC
 SG_ S2P_Bal_CellOffLine_104s_25 : 56|1@1+ (1,0) [0|1] ""  PC
 SG_ S2P_Bal_BalanCirFlt_104s_25 : 57|1@1+ (1,0) [0|1] ""  PC
 SG_ S2P_Bal_CellVoOverFlt104s_25 : 59|1@1+ (1,0) [0|1] ""  PC
 SG_ S2P_Bal_CellVoLowFlt104s_25 : 60|1@1+ (1,0) [0|1] ""  PC
 SG_ S2P_Bal_CSCPCBTeFlt104s_25 : 61|1@1+ (1,0) [0|1] ""  PC

BO_ 2417946202 S2P_BL_Meg_104s__26: 8 SBMU
 SG_ S2P_Bal_CSCNum_104s_26 : 0|5@1+ (1,0) [0|31] ""  PC
 SG_ S2P_Bal_CellNum_104s_26 : 5|7@1+ (1,0) [0|127] ""  PC
 SG_ S2P_Bal_Type_104s_26 : 12|2@1+ (1,0) [0|3] ""  PC
 SG_ S2P_Bal_TimeRemain_104s_26 : 14|9@1+ (1,0) [0|511] ""  PC
 SG_ S2P_Bal_DeltaVolt_104s_26 : 23|10@1+ (1,0) [0|1023] ""  PC
 SG_ S2P_Bal_TypeLevel_104s_26 : 44|3@1+ (1,0) [0|7] ""  PC
 SG_ S2P_Bal_Strategy_104s_26 : 49|1@1+ (1,0) [0|1] ""  PC
 SG_ S2P_Bal_ForceBalMode_104s_26 : 50|2@1+ (1,0) [0|3] ""  PC
 SG_ S2P_Bal_CellTempFault_104s_26 : 52|1@1+ (1,0) [0|1] ""  PC
 SG_ S2P_Bal_CellVoltFail_104s_26 : 53|1@1+ (1,0) [0|1] ""  PC
 SG_ S2P_Bal_CloseBalIstr_104s_26 : 54|1@1+ (1,0) [0|1] ""  PC
 SG_ S2P_Bal_CCanTimeOut_104s_26 : 55|1@1+ (1,0) [0|1] ""  PC
 SG_ S2P_Bal_CellOffLine_104s_26 : 56|1@1+ (1,0) [0|1] ""  PC
 SG_ S2P_Bal_BalanCirFlt_104s_26 : 57|1@1+ (1,0) [0|1] ""  PC
 SG_ S2P_Bal_CellVoOverFlt104s_26 : 59|1@1+ (1,0) [0|1] ""  PC
 SG_ S2P_Bal_CellVoLowFlt104s_26 : 60|1@1+ (1,0) [0|1] ""  PC
 SG_ S2P_Bal_CSCPCBTeFlt104s_26 : 61|1@1+ (1,0) [0|1] ""  PC

BO_ 2417946203 S2P_BL_Meg_104s__27: 8 SBMU
 SG_ S2P_Bal_CSCNum_104s_27 : 0|5@1+ (1,0) [0|31] ""  PC
 SG_ S2P_Bal_CellNum_104s_27 : 5|7@1+ (1,0) [0|127] ""  PC
 SG_ S2P_Bal_Type_104s_27 : 12|2@1+ (1,0) [0|3] ""  PC
 SG_ S2P_Bal_TimeRemain_104s_27 : 14|9@1+ (1,0) [0|511] ""  PC
 SG_ S2P_Bal_DeltaVolt_104s_27 : 23|10@1+ (1,0) [0|1023] ""  PC
 SG_ S2P_Bal_TypeLevel_104s_27 : 44|3@1+ (1,0) [0|7] ""  PC
 SG_ S2P_Bal_Strategy_104s_27 : 49|1@1+ (1,0) [0|1] ""  PC
 SG_ S2P_Bal_ForceBalMode_104s_27 : 50|2@1+ (1,0) [0|3] ""  PC
 SG_ S2P_Bal_CellTempFault_104s_27 : 52|1@1+ (1,0) [0|1] ""  PC
 SG_ S2P_Bal_CellVoltFail_104s_27 : 53|1@1+ (1,0) [0|1] ""  PC
 SG_ S2P_Bal_CloseBalIstr_104s_27 : 54|1@1+ (1,0) [0|1] ""  PC
 SG_ S2P_Bal_CCanTimeOut_104s_27 : 55|1@1+ (1,0) [0|1] ""  PC
 SG_ S2P_Bal_CellOffLine_104s_27 : 56|1@1+ (1,0) [0|1] ""  PC
 SG_ S2P_Bal_BalanCirFlt_104s_27 : 57|1@1+ (1,0) [0|1] ""  PC
 SG_ S2P_Bal_CellVoOverFlt104s_27 : 59|1@1+ (1,0) [0|1] ""  PC
 SG_ S2P_Bal_CellVoLowFlt104s_27 : 60|1@1+ (1,0) [0|1] ""  PC
 SG_ S2P_Bal_CSCPCBTeFlt104s_27 : 61|1@1+ (1,0) [0|1] ""  PC

BO_ 2417946204 S2P_BL_Meg_104s__28: 8 SBMU
 SG_ S2P_Bal_CSCNum_104s_28 : 0|5@1+ (1,0) [0|31] ""  PC
 SG_ S2P_Bal_CellNum_104s_28 : 5|7@1+ (1,0) [0|127] ""  PC
 SG_ S2P_Bal_Type_104s_28 : 12|2@1+ (1,0) [0|3] ""  PC
 SG_ S2P_Bal_TimeRemain_104s_28 : 14|9@1+ (1,0) [0|511] ""  PC
 SG_ S2P_Bal_DeltaVolt_104s_28 : 23|10@1+ (1,0) [0|1023] ""  PC
 SG_ S2P_Bal_TypeLevel_104s_28 : 44|3@1+ (1,0) [0|7] ""  PC
 SG_ S2P_Bal_Strategy_104s_28 : 49|1@1+ (1,0) [0|1] ""  PC
 SG_ S2P_Bal_ForceBalMode_104s_28 : 50|2@1+ (1,0) [0|3] ""  PC
 SG_ S2P_Bal_CellTempFault_104s_28 : 52|1@1+ (1,0) [0|1] ""  PC
 SG_ S2P_Bal_CellVoltFail_104s_28 : 53|1@1+ (1,0) [0|1] ""  PC
 SG_ S2P_Bal_CloseBalIstr_104s_28 : 54|1@1+ (1,0) [0|1] ""  PC
 SG_ S2P_Bal_CCanTimeOut_104s_28 : 55|1@1+ (1,0) [0|1] ""  PC
 SG_ S2P_Bal_CellOffLine_104s_28 : 56|1@1+ (1,0) [0|1] ""  PC
 SG_ S2P_Bal_BalanCirFlt_104s_28 : 57|1@1+ (1,0) [0|1] ""  PC
 SG_ S2P_Bal_CellVoOverFlt104s_28 : 59|1@1+ (1,0) [0|1] ""  PC
 SG_ S2P_Bal_CellVoLowFlt104s_28 : 60|1@1+ (1,0) [0|1] ""  PC
 SG_ S2P_Bal_CSCPCBTeFlt104s_28 : 61|1@1+ (1,0) [0|1] ""  PC

BO_ 2417946205 S2P_BL_Meg_104s__29: 8 SBMU
 SG_ S2P_Bal_CSCNum_104s_29 : 0|5@1+ (1,0) [0|31] ""  PC
 SG_ S2P_Bal_CellNum_104s_29 : 5|7@1+ (1,0) [0|127] ""  PC
 SG_ S2P_Bal_Type_104s_29 : 12|2@1+ (1,0) [0|3] ""  PC
 SG_ S2P_Bal_TimeRemain_104s_29 : 14|9@1+ (1,0) [0|511] ""  PC
 SG_ S2P_Bal_DeltaVolt_104s_29 : 23|10@1+ (1,0) [0|1023] ""  PC
 SG_ S2P_Bal_TypeLevel_104s_29 : 44|3@1+ (1,0) [0|7] ""  PC
 SG_ S2P_Bal_Strategy_104s_29 : 49|1@1+ (1,0) [0|1] ""  PC
 SG_ S2P_Bal_ForceBalMode_104s_29 : 50|2@1+ (1,0) [0|3] ""  PC
 SG_ S2P_Bal_CellTempFault_104s_29 : 52|1@1+ (1,0) [0|1] ""  PC
 SG_ S2P_Bal_CellVoltFail_104s_29 : 53|1@1+ (1,0) [0|1] ""  PC
 SG_ S2P_Bal_CloseBalIstr_104s_29 : 54|1@1+ (1,0) [0|1] ""  PC
 SG_ S2P_Bal_CCanTimeOut_104s_29 : 55|1@1+ (1,0) [0|1] ""  PC
 SG_ S2P_Bal_CellOffLine_104s_29 : 56|1@1+ (1,0) [0|1] ""  PC
 SG_ S2P_Bal_BalanCirFlt_104s_29 : 57|1@1+ (1,0) [0|1] ""  PC
 SG_ S2P_Bal_CellVoOverFlt104s_29 : 59|1@1+ (1,0) [0|1] ""  PC
 SG_ S2P_Bal_CellVoLowFlt104s_29 : 60|1@1+ (1,0) [0|1] ""  PC
 SG_ S2P_Bal_CSCPCBTeFlt104s_29 : 61|1@1+ (1,0) [0|1] ""  PC

BO_ 2417946206 S2P_BL_Meg_104s__30: 8 SBMU
 SG_ S2P_Bal_CSCNum_104s_30 : 0|5@1+ (1,0) [0|31] ""  PC
 SG_ S2P_Bal_CellNum_104s_30 : 5|7@1+ (1,0) [0|127] ""  PC
 SG_ S2P_Bal_Type_104s_30 : 12|2@1+ (1,0) [0|3] ""  PC
 SG_ S2P_Bal_TimeRemain_104s_30 : 14|9@1+ (1,0) [0|511] ""  PC
 SG_ S2P_Bal_DeltaVolt_104s_30 : 23|10@1+ (1,0) [0|1023] ""  PC
 SG_ S2P_Bal_TypeLevel_104s_30 : 44|3@1+ (1,0) [0|7] ""  PC
 SG_ S2P_Bal_Strategy_104s_30 : 49|1@1+ (1,0) [0|1] ""  PC
 SG_ S2P_Bal_ForceBalMode_104s_30 : 50|2@1+ (1,0) [0|3] ""  PC
 SG_ S2P_Bal_CellTempFault_104s_30 : 52|1@1+ (1,0) [0|1] ""  PC
 SG_ S2P_Bal_CellVoltFail_104s_30 : 53|1@1+ (1,0) [0|1] ""  PC
 SG_ S2P_Bal_CloseBalIstr_104s_30 : 54|1@1+ (1,0) [0|1] ""  PC
 SG_ S2P_Bal_CCanTimeOut_104s_30 : 55|1@1+ (1,0) [0|1] ""  PC
 SG_ S2P_Bal_CellOffLine_104s_30 : 56|1@1+ (1,0) [0|1] ""  PC
 SG_ S2P_Bal_BalanCirFlt_104s_30 : 57|1@1+ (1,0) [0|1] ""  PC
 SG_ S2P_Bal_CellVoOverFlt104s_30 : 59|1@1+ (1,0) [0|1] ""  PC
 SG_ S2P_Bal_CellVoLowFlt104s_30 : 60|1@1+ (1,0) [0|1] ""  PC
 SG_ S2P_Bal_CSCPCBTeFlt104s_30 : 61|1@1+ (1,0) [0|1] ""  PC

BO_ 2417946207 S2P_BL_Meg_104s__31: 8 SBMU
 SG_ S2P_Bal_CSCNum_104s_31 : 0|5@1+ (1,0) [0|31] ""  PC
 SG_ S2P_Bal_CellNum_104s_31 : 5|7@1+ (1,0) [0|127] ""  PC
 SG_ S2P_Bal_Type_104s_31 : 12|2@1+ (1,0) [0|3] ""  PC
 SG_ S2P_Bal_TimeRemain_104s_31 : 14|9@1+ (1,0) [0|511] ""  PC
 SG_ S2P_Bal_DeltaVolt_104s_31 : 23|10@1+ (1,0) [0|1023] ""  PC
 SG_ S2P_Bal_TypeLevel_104s_31 : 44|3@1+ (1,0) [0|7] ""  PC
 SG_ S2P_Bal_Strategy_104s_31 : 49|1@1+ (1,0) [0|1] ""  PC
 SG_ S2P_Bal_ForceBalMode_104s_31 : 50|2@1+ (1,0) [0|3] ""  PC
 SG_ S2P_Bal_CellTempFault_104s_31 : 52|1@1+ (1,0) [0|1] ""  PC
 SG_ S2P_Bal_CellVoltFail_104s_31 : 53|1@1+ (1,0) [0|1] ""  PC
 SG_ S2P_Bal_CloseBalIstr_104s_31 : 54|1@1+ (1,0) [0|1] ""  PC
 SG_ S2P_Bal_CCanTimeOut_104s_31 : 55|1@1+ (1,0) [0|1] ""  PC
 SG_ S2P_Bal_CellOffLine_104s_31 : 56|1@1+ (1,0) [0|1] ""  PC
 SG_ S2P_Bal_BalanCirFlt_104s_31 : 57|1@1+ (1,0) [0|1] ""  PC
 SG_ S2P_Bal_CellVoOverFlt104s_31 : 59|1@1+ (1,0) [0|1] ""  PC
 SG_ S2P_Bal_CellVoLowFlt104s_31 : 60|1@1+ (1,0) [0|1] ""  PC
 SG_ S2P_Bal_CSCPCBTeFlt104s_31 : 61|1@1+ (1,0) [0|1] ""  PC

BO_ 2417946208 S2P_BL_Meg_104s__32: 8 SBMU
 SG_ S2P_Bal_CSCNum_104s_32 : 0|5@1+ (1,0) [0|31] ""  PC
 SG_ S2P_Bal_CellNum_104s_32 : 5|7@1+ (1,0) [0|127] ""  PC
 SG_ S2P_Bal_Type_104s_32 : 12|2@1+ (1,0) [0|3] ""  PC
 SG_ S2P_Bal_TimeRemain_104s_32 : 14|9@1+ (1,0) [0|511] ""  PC
 SG_ S2P_Bal_DeltaVolt_104s_32 : 23|10@1+ (1,0) [0|1023] ""  PC
 SG_ S2P_Bal_TypeLevel_104s_32 : 44|3@1+ (1,0) [0|7] ""  PC
 SG_ S2P_Bal_Strategy_104s_32 : 49|1@1+ (1,0) [0|1] ""  PC
 SG_ S2P_Bal_ForceBalMode_104s_32 : 50|2@1+ (1,0) [0|3] ""  PC
 SG_ S2P_Bal_CellTempFault_104s_32 : 52|1@1+ (1,0) [0|1] ""  PC
 SG_ S2P_Bal_CellVoltFail_104s_32 : 53|1@1+ (1,0) [0|1] ""  PC
 SG_ S2P_Bal_CloseBalIstr_104s_32 : 54|1@1+ (1,0) [0|1] ""  PC
 SG_ S2P_Bal_CCanTimeOut_104s_32 : 55|1@1+ (1,0) [0|1] ""  PC
 SG_ S2P_Bal_CellOffLine_104s_32 : 56|1@1+ (1,0) [0|1] ""  PC
 SG_ S2P_Bal_BalanCirFlt_104s_32 : 57|1@1+ (1,0) [0|1] ""  PC
 SG_ S2P_Bal_CellVoOverFlt104s_32 : 59|1@1+ (1,0) [0|1] ""  PC
 SG_ S2P_Bal_CellVoLowFlt104s_32 : 60|1@1+ (1,0) [0|1] ""  PC
 SG_ S2P_Bal_CSCPCBTeFlt104s_32 : 61|1@1+ (1,0) [0|1] ""  PC

BO_ 2417946209 S2P_BL_Meg_104s__33: 8 SBMU
 SG_ S2P_Bal_CSCNum_104s_33 : 0|5@1+ (1,0) [0|31] ""  PC
 SG_ S2P_Bal_CellNum_104s_33 : 5|7@1+ (1,0) [0|127] ""  PC
 SG_ S2P_Bal_Type_104s_33 : 12|2@1+ (1,0) [0|3] ""  PC
 SG_ S2P_Bal_TimeRemain_104s_33 : 14|9@1+ (1,0) [0|511] ""  PC
 SG_ S2P_Bal_DeltaVolt_104s_33 : 23|10@1+ (1,0) [0|1023] ""  PC
 SG_ S2P_Bal_TypeLevel_104s_33 : 44|3@1+ (1,0) [0|7] ""  PC
 SG_ S2P_Bal_Strategy_104s_33 : 49|1@1+ (1,0) [0|1] ""  PC
 SG_ S2P_Bal_ForceBalMode_104s_33 : 50|2@1+ (1,0) [0|3] ""  PC
 SG_ S2P_Bal_CellTempFault_104s_33 : 52|1@1+ (1,0) [0|1] ""  PC
 SG_ S2P_Bal_CellVoltFail_104s_33 : 53|1@1+ (1,0) [0|1] ""  PC
 SG_ S2P_Bal_CloseBalIstr_104s_33 : 54|1@1+ (1,0) [0|1] ""  PC
 SG_ S2P_Bal_CCanTimeOut_104s_33 : 55|1@1+ (1,0) [0|1] ""  PC
 SG_ S2P_Bal_CellOffLine_104s_33 : 56|1@1+ (1,0) [0|1] ""  PC
 SG_ S2P_Bal_BalanCirFlt_104s_33 : 57|1@1+ (1,0) [0|1] ""  PC
 SG_ S2P_Bal_CellVoOverFlt104s_33 : 59|1@1+ (1,0) [0|1] ""  PC
 SG_ S2P_Bal_CellVoLowFlt104s_33 : 60|1@1+ (1,0) [0|1] ""  PC
 SG_ S2P_Bal_CSCPCBTeFlt104s_33 : 61|1@1+ (1,0) [0|1] ""  PC

BO_ 2417946210 S2P_BL_Meg_104s__34: 8 SBMU
 SG_ S2P_Bal_CSCNum_104s_34 : 0|5@1+ (1,0) [0|31] ""  PC
 SG_ S2P_Bal_CellNum_104s_34 : 5|7@1+ (1,0) [0|127] ""  PC
 SG_ S2P_Bal_Type_104s_34 : 12|2@1+ (1,0) [0|3] ""  PC
 SG_ S2P_Bal_TimeRemain_104s_34 : 14|9@1+ (1,0) [0|511] ""  PC
 SG_ S2P_Bal_DeltaVolt_104s_34 : 23|10@1+ (1,0) [0|1023] ""  PC
 SG_ S2P_Bal_TypeLevel_104s_34 : 44|3@1+ (1,0) [0|7] ""  PC
 SG_ S2P_Bal_Strategy_104s_34 : 49|1@1+ (1,0) [0|1] ""  PC
 SG_ S2P_Bal_ForceBalMode_104s_34 : 50|2@1+ (1,0) [0|3] ""  PC
 SG_ S2P_Bal_CellTempFault_104s_34 : 52|1@1+ (1,0) [0|1] ""  PC
 SG_ S2P_Bal_CellVoltFail_104s_34 : 53|1@1+ (1,0) [0|1] ""  PC
 SG_ S2P_Bal_CloseBalIstr_104s_34 : 54|1@1+ (1,0) [0|1] ""  PC
 SG_ S2P_Bal_CCanTimeOut_104s_34 : 55|1@1+ (1,0) [0|1] ""  PC
 SG_ S2P_Bal_CellOffLine_104s_34 : 56|1@1+ (1,0) [0|1] ""  PC
 SG_ S2P_Bal_BalanCirFlt_104s_34 : 57|1@1+ (1,0) [0|1] ""  PC
 SG_ S2P_Bal_CellVoOverFlt104s_34 : 59|1@1+ (1,0) [0|1] ""  PC
 SG_ S2P_Bal_CellVoLowFlt104s_34 : 60|1@1+ (1,0) [0|1] ""  PC
 SG_ S2P_Bal_CSCPCBTeFlt104s_34 : 61|1@1+ (1,0) [0|1] ""  PC

BO_ 2417946211 S2P_BL_Meg_104s__35: 8 SBMU
 SG_ S2P_Bal_CSCNum_104s_35 : 0|5@1+ (1,0) [0|31] ""  PC
 SG_ S2P_Bal_CellNum_104s_35 : 5|7@1+ (1,0) [0|127] ""  PC
 SG_ S2P_Bal_Type_104s_35 : 12|2@1+ (1,0) [0|3] ""  PC
 SG_ S2P_Bal_TimeRemain_104s_35 : 14|9@1+ (1,0) [0|511] ""  PC
 SG_ S2P_Bal_DeltaVolt_104s_35 : 23|10@1+ (1,0) [0|1023] ""  PC
 SG_ S2P_Bal_TypeLevel_104s_35 : 44|3@1+ (1,0) [0|7] ""  PC
 SG_ S2P_Bal_Strategy_104s_35 : 49|1@1+ (1,0) [0|1] ""  PC
 SG_ S2P_Bal_ForceBalMode_104s_35 : 50|2@1+ (1,0) [0|3] ""  PC
 SG_ S2P_Bal_CellTempFault_104s_35 : 52|1@1+ (1,0) [0|1] ""  PC
 SG_ S2P_Bal_CellVoltFail_104s_35 : 53|1@1+ (1,0) [0|1] ""  PC
 SG_ S2P_Bal_CloseBalIstr_104s_35 : 54|1@1+ (1,0) [0|1] ""  PC
 SG_ S2P_Bal_CCanTimeOut_104s_35 : 55|1@1+ (1,0) [0|1] ""  PC
 SG_ S2P_Bal_CellOffLine_104s_35 : 56|1@1+ (1,0) [0|1] ""  PC
 SG_ S2P_Bal_BalanCirFlt_104s_35 : 57|1@1+ (1,0) [0|1] ""  PC
 SG_ S2P_Bal_CellVoOverFlt104s_35 : 59|1@1+ (1,0) [0|1] ""  PC
 SG_ S2P_Bal_CellVoLowFlt104s_35 : 60|1@1+ (1,0) [0|1] ""  PC
 SG_ S2P_Bal_CSCPCBTeFlt104s_35 : 61|1@1+ (1,0) [0|1] ""  PC

BO_ 2417946212 S2P_BL_Meg_104s__36: 8 SBMU
 SG_ S2P_Bal_CSCNum_104s_36 : 0|5@1+ (1,0) [0|31] ""  PC
 SG_ S2P_Bal_CellNum_104s_36 : 5|7@1+ (1,0) [0|127] ""  PC
 SG_ S2P_Bal_Type_104s_36 : 12|2@1+ (1,0) [0|3] ""  PC
 SG_ S2P_Bal_TimeRemain_104s_36 : 14|9@1+ (1,0) [0|511] ""  PC
 SG_ S2P_Bal_DeltaVolt_104s_36 : 23|10@1+ (1,0) [0|1023] ""  PC
 SG_ S2P_Bal_TypeLevel_104s_36 : 44|3@1+ (1,0) [0|7] ""  PC
 SG_ S2P_Bal_Strategy_104s_36 : 49|1@1+ (1,0) [0|1] ""  PC
 SG_ S2P_Bal_ForceBalMode_104s_36 : 50|2@1+ (1,0) [0|3] ""  PC
 SG_ S2P_Bal_CellTempFault_104s_36 : 52|1@1+ (1,0) [0|1] ""  PC
 SG_ S2P_Bal_CellVoltFail_104s_36 : 53|1@1+ (1,0) [0|1] ""  PC
 SG_ S2P_Bal_CloseBalIstr_104s_36 : 54|1@1+ (1,0) [0|1] ""  PC
 SG_ S2P_Bal_CCanTimeOut_104s_36 : 55|1@1+ (1,0) [0|1] ""  PC
 SG_ S2P_Bal_CellOffLine_104s_36 : 56|1@1+ (1,0) [0|1] ""  PC
 SG_ S2P_Bal_BalanCirFlt_104s_36 : 57|1@1+ (1,0) [0|1] ""  PC
 SG_ S2P_Bal_CellVoOverFlt104s_36 : 59|1@1+ (1,0) [0|1] ""  PC
 SG_ S2P_Bal_CellVoLowFlt104s_36 : 60|1@1+ (1,0) [0|1] ""  PC
 SG_ S2P_Bal_CSCPCBTeFlt104s_36 : 61|1@1+ (1,0) [0|1] ""  PC

BO_ 2417946213 S2P_BL_Meg_104s__37: 8 SBMU
 SG_ S2P_Bal_CSCNum_104s_37 : 0|5@1+ (1,0) [0|31] ""  PC
 SG_ S2P_Bal_CellNum_104s_37 : 5|7@1+ (1,0) [0|127] ""  PC
 SG_ S2P_Bal_Type_104s_37 : 12|2@1+ (1,0) [0|3] ""  PC
 SG_ S2P_Bal_TimeRemain_104s_37 : 14|9@1+ (1,0) [0|511] ""  PC
 SG_ S2P_Bal_DeltaVolt_104s_37 : 23|10@1+ (1,0) [0|1023] ""  PC
 SG_ S2P_Bal_TypeLevel_104s_37 : 44|3@1+ (1,0) [0|7] ""  PC
 SG_ S2P_Bal_Strategy_104s_37 : 49|1@1+ (1,0) [0|1] ""  PC
 SG_ S2P_Bal_ForceBalMode_104s_37 : 50|2@1+ (1,0) [0|3] ""  PC
 SG_ S2P_Bal_CellTempFault_104s_37 : 52|1@1+ (1,0) [0|1] ""  PC
 SG_ S2P_Bal_CellVoltFail_104s_37 : 53|1@1+ (1,0) [0|1] ""  PC
 SG_ S2P_Bal_CloseBalIstr_104s_37 : 54|1@1+ (1,0) [0|1] ""  PC
 SG_ S2P_Bal_CCanTimeOut_104s_37 : 55|1@1+ (1,0) [0|1] ""  PC
 SG_ S2P_Bal_CellOffLine_104s_37 : 56|1@1+ (1,0) [0|1] ""  PC
 SG_ S2P_Bal_BalanCirFlt_104s_37 : 57|1@1+ (1,0) [0|1] ""  PC
 SG_ S2P_Bal_CellVoOverFlt104s_37 : 59|1@1+ (1,0) [0|1] ""  PC
 SG_ S2P_Bal_CellVoLowFlt104s_37 : 60|1@1+ (1,0) [0|1] ""  PC
 SG_ S2P_Bal_CSCPCBTeFlt104s_37 : 61|1@1+ (1,0) [0|1] ""  PC

BO_ 2417946214 S2P_BL_Meg_104s__38: 8 SBMU
 SG_ S2P_Bal_CSCNum_104s_38 : 0|5@1+ (1,0) [0|31] ""  PC
 SG_ S2P_Bal_CellNum_104s_38 : 5|7@1+ (1,0) [0|127] ""  PC
 SG_ S2P_Bal_Type_104s_38 : 12|2@1+ (1,0) [0|3] ""  PC
 SG_ S2P_Bal_TimeRemain_104s_38 : 14|9@1+ (1,0) [0|511] ""  PC
 SG_ S2P_Bal_DeltaVolt_104s_38 : 23|10@1+ (1,0) [0|1023] ""  PC
 SG_ S2P_Bal_TypeLevel_104s_38 : 44|3@1+ (1,0) [0|7] ""  PC
 SG_ S2P_Bal_Strategy_104s_38 : 49|1@1+ (1,0) [0|1] ""  PC
 SG_ S2P_Bal_ForceBalMode_104s_38 : 50|2@1+ (1,0) [0|3] ""  PC
 SG_ S2P_Bal_CellTempFault_104s_38 : 52|1@1+ (1,0) [0|1] ""  PC
 SG_ S2P_Bal_CellVoltFail_104s_38 : 53|1@1+ (1,0) [0|1] ""  PC
 SG_ S2P_Bal_CloseBalIstr_104s_38 : 54|1@1+ (1,0) [0|1] ""  PC
 SG_ S2P_Bal_CCanTimeOut_104s_38 : 55|1@1+ (1,0) [0|1] ""  PC
 SG_ S2P_Bal_CellOffLine_104s_38 : 56|1@1+ (1,0) [0|1] ""  PC
 SG_ S2P_Bal_BalanCirFlt_104s_38 : 57|1@1+ (1,0) [0|1] ""  PC
 SG_ S2P_Bal_CellVoOverFlt104s_38 : 59|1@1+ (1,0) [0|1] ""  PC
 SG_ S2P_Bal_CellVoLowFlt104s_38 : 60|1@1+ (1,0) [0|1] ""  PC
 SG_ S2P_Bal_CSCPCBTeFlt104s_38 : 61|1@1+ (1,0) [0|1] ""  PC

BO_ 2417946215 S2P_BL_Meg_104s__39: 8 SBMU
 SG_ S2P_Bal_CSCNum_104s_39 : 0|5@1+ (1,0) [0|31] ""  PC
 SG_ S2P_Bal_CellNum_104s_39 : 5|7@1+ (1,0) [0|127] ""  PC
 SG_ S2P_Bal_Type_104s_39 : 12|2@1+ (1,0) [0|3] ""  PC
 SG_ S2P_Bal_TimeRemain_104s_39 : 14|9@1+ (1,0) [0|511] ""  PC
 SG_ S2P_Bal_DeltaVolt_104s_39 : 23|10@1+ (1,0) [0|1023] ""  PC
 SG_ S2P_Bal_TypeLevel_104s_39 : 44|3@1+ (1,0) [0|7] ""  PC
 SG_ S2P_Bal_Strategy_104s_39 : 49|1@1+ (1,0) [0|1] ""  PC
 SG_ S2P_Bal_ForceBalMode_104s_39 : 50|2@1+ (1,0) [0|3] ""  PC
 SG_ S2P_Bal_CellTempFault_104s_39 : 52|1@1+ (1,0) [0|1] ""  PC
 SG_ S2P_Bal_CellVoltFail_104s_39 : 53|1@1+ (1,0) [0|1] ""  PC
 SG_ S2P_Bal_CloseBalIstr_104s_39 : 54|1@1+ (1,0) [0|1] ""  PC
 SG_ S2P_Bal_CCanTimeOut_104s_39 : 55|1@1+ (1,0) [0|1] ""  PC
 SG_ S2P_Bal_CellOffLine_104s_39 : 56|1@1+ (1,0) [0|1] ""  PC
 SG_ S2P_Bal_BalanCirFlt_104s_39 : 57|1@1+ (1,0) [0|1] ""  PC
 SG_ S2P_Bal_CellVoOverFlt104s_39 : 59|1@1+ (1,0) [0|1] ""  PC
 SG_ S2P_Bal_CellVoLowFlt104s_39 : 60|1@1+ (1,0) [0|1] ""  PC
 SG_ S2P_Bal_CSCPCBTeFlt104s_39 : 61|1@1+ (1,0) [0|1] ""  PC

BO_ 2417946216 S2P_BL_Meg_104s__40: 8 SBMU
 SG_ S2P_Bal_CSCNum_104s_40 : 0|5@1+ (1,0) [0|31] ""  PC
 SG_ S2P_Bal_CellNum_104s_40 : 5|7@1+ (1,0) [0|127] ""  PC
 SG_ S2P_Bal_Type_104s_40 : 12|2@1+ (1,0) [0|3] ""  PC
 SG_ S2P_Bal_TimeRemain_104s_40 : 14|9@1+ (1,0) [0|511] ""  PC
 SG_ S2P_Bal_DeltaVolt_104s_40 : 23|10@1+ (1,0) [0|1023] ""  PC
 SG_ S2P_Bal_TypeLevel_104s_40 : 44|3@1+ (1,0) [0|7] ""  PC
 SG_ S2P_Bal_Strategy_104s_40 : 49|1@1+ (1,0) [0|1] ""  PC
 SG_ S2P_Bal_ForceBalMode_104s_40 : 50|2@1+ (1,0) [0|3] ""  PC
 SG_ S2P_Bal_CellTempFault_104s_40 : 52|1@1+ (1,0) [0|1] ""  PC
 SG_ S2P_Bal_CellVoltFail_104s_40 : 53|1@1+ (1,0) [0|1] ""  PC
 SG_ S2P_Bal_CloseBalIstr_104s_40 : 54|1@1+ (1,0) [0|1] ""  PC
 SG_ S2P_Bal_CCanTimeOut_104s_40 : 55|1@1+ (1,0) [0|1] ""  PC
 SG_ S2P_Bal_CellOffLine_104s_40 : 56|1@1+ (1,0) [0|1] ""  PC
 SG_ S2P_Bal_BalanCirFlt_104s_40 : 57|1@1+ (1,0) [0|1] ""  PC
 SG_ S2P_Bal_CellVoOverFlt104s_40 : 59|1@1+ (1,0) [0|1] ""  PC
 SG_ S2P_Bal_CellVoLowFlt104s_40 : 60|1@1+ (1,0) [0|1] ""  PC
 SG_ S2P_Bal_CSCPCBTeFlt104s_40 : 61|1@1+ (1,0) [0|1] ""  PC

BO_ 2417946217 S2P_BL_Meg_104s__41: 8 SBMU
 SG_ S2P_Bal_CSCNum_104s_41 : 0|5@1+ (1,0) [0|31] ""  PC
 SG_ S2P_Bal_CellNum_104s_41 : 5|7@1+ (1,0) [0|127] ""  PC
 SG_ S2P_Bal_Type_104s_41 : 12|2@1+ (1,0) [0|3] ""  PC
 SG_ S2P_Bal_TimeRemain_104s_41 : 14|9@1+ (1,0) [0|511] ""  PC
 SG_ S2P_Bal_DeltaVolt_104s_41 : 23|10@1+ (1,0) [0|1023] ""  PC
 SG_ S2P_Bal_TypeLevel_104s_41 : 44|3@1+ (1,0) [0|7] ""  PC
 SG_ S2P_Bal_Strategy_104s_41 : 49|1@1+ (1,0) [0|1] ""  PC
 SG_ S2P_Bal_ForceBalMode_104s_41 : 50|2@1+ (1,0) [0|3] ""  PC
 SG_ S2P_Bal_CellTempFault_104s_41 : 52|1@1+ (1,0) [0|1] ""  PC
 SG_ S2P_Bal_CellVoltFail_104s_41 : 53|1@1+ (1,0) [0|1] ""  PC
 SG_ S2P_Bal_CloseBalIstr_104s_41 : 54|1@1+ (1,0) [0|1] ""  PC
 SG_ S2P_Bal_CCanTimeOut_104s_41 : 55|1@1+ (1,0) [0|1] ""  PC
 SG_ S2P_Bal_CellOffLine_104s_41 : 56|1@1+ (1,0) [0|1] ""  PC
 SG_ S2P_Bal_BalanCirFlt_104s_41 : 57|1@1+ (1,0) [0|1] ""  PC
 SG_ S2P_Bal_CellVoOverFlt104s_41 : 59|1@1+ (1,0) [0|1] ""  PC
 SG_ S2P_Bal_CellVoLowFlt104s_41 : 60|1@1+ (1,0) [0|1] ""  PC
 SG_ S2P_Bal_CSCPCBTeFlt104s_41 : 61|1@1+ (1,0) [0|1] ""  PC

BO_ 2417946218 S2P_BL_Meg_104s__42: 8 SBMU
 SG_ S2P_Bal_CSCNum_104s_42 : 0|5@1+ (1,0) [0|31] ""  PC
 SG_ S2P_Bal_CellNum_104s_42 : 5|7@1+ (1,0) [0|127] ""  PC
 SG_ S2P_Bal_Type_104s_42 : 12|2@1+ (1,0) [0|3] ""  PC
 SG_ S2P_Bal_TimeRemain_104s_42 : 14|9@1+ (1,0) [0|511] ""  PC
 SG_ S2P_Bal_DeltaVolt_104s_42 : 23|10@1+ (1,0) [0|1023] ""  PC
 SG_ S2P_Bal_TypeLevel_104s_42 : 44|3@1+ (1,0) [0|7] ""  PC
 SG_ S2P_Bal_Strategy_104s_42 : 49|1@1+ (1,0) [0|1] ""  PC
 SG_ S2P_Bal_ForceBalMode_104s_42 : 50|2@1+ (1,0) [0|3] ""  PC
 SG_ S2P_Bal_CellTempFault_104s_42 : 52|1@1+ (1,0) [0|1] ""  PC
 SG_ S2P_Bal_CellVoltFail_104s_42 : 53|1@1+ (1,0) [0|1] ""  PC
 SG_ S2P_Bal_CloseBalIstr_104s_42 : 54|1@1+ (1,0) [0|1] ""  PC
 SG_ S2P_Bal_CCanTimeOut_104s_42 : 55|1@1+ (1,0) [0|1] ""  PC
 SG_ S2P_Bal_CellOffLine_104s_42 : 56|1@1+ (1,0) [0|1] ""  PC
 SG_ S2P_Bal_BalanCirFlt_104s_42 : 57|1@1+ (1,0) [0|1] ""  PC
 SG_ S2P_Bal_CellVoOverFlt104s_42 : 59|1@1+ (1,0) [0|1] ""  PC
 SG_ S2P_Bal_CellVoLowFlt104s_42 : 60|1@1+ (1,0) [0|1] ""  PC
 SG_ S2P_Bal_CSCPCBTeFlt104s_42 : 61|1@1+ (1,0) [0|1] ""  PC

BO_ 2417946219 S2P_BL_Meg_104s__43: 8 SBMU
 SG_ S2P_Bal_CSCNum_104s_43 : 0|5@1+ (1,0) [0|31] ""  PC
 SG_ S2P_Bal_CellNum_104s_43 : 5|7@1+ (1,0) [0|127] ""  PC
 SG_ S2P_Bal_Type_104s_43 : 12|2@1+ (1,0) [0|3] ""  PC
 SG_ S2P_Bal_TimeRemain_104s_43 : 14|9@1+ (1,0) [0|511] ""  PC
 SG_ S2P_Bal_DeltaVolt_104s_43 : 23|10@1+ (1,0) [0|1023] ""  PC
 SG_ S2P_Bal_TypeLevel_104s_43 : 44|3@1+ (1,0) [0|7] ""  PC
 SG_ S2P_Bal_Strategy_104s_43 : 49|1@1+ (1,0) [0|1] ""  PC
 SG_ S2P_Bal_ForceBalMode_104s_43 : 50|2@1+ (1,0) [0|3] ""  PC
 SG_ S2P_Bal_CellTempFault_104s_43 : 52|1@1+ (1,0) [0|1] ""  PC
 SG_ S2P_Bal_CellVoltFail_104s_43 : 53|1@1+ (1,0) [0|1] ""  PC
 SG_ S2P_Bal_CloseBalIstr_104s_43 : 54|1@1+ (1,0) [0|1] ""  PC
 SG_ S2P_Bal_CCanTimeOut_104s_43 : 55|1@1+ (1,0) [0|1] ""  PC
 SG_ S2P_Bal_CellOffLine_104s_43 : 56|1@1+ (1,0) [0|1] ""  PC
 SG_ S2P_Bal_BalanCirFlt_104s_43 : 57|1@1+ (1,0) [0|1] ""  PC
 SG_ S2P_Bal_CellVoOverFlt104s_43 : 59|1@1+ (1,0) [0|1] ""  PC
 SG_ S2P_Bal_CellVoLowFlt104s_43 : 60|1@1+ (1,0) [0|1] ""  PC
 SG_ S2P_Bal_CSCPCBTeFlt104s_43 : 61|1@1+ (1,0) [0|1] ""  PC

BO_ 2417946220 S2P_BL_Meg_104s__44: 8 SBMU
 SG_ S2P_Bal_CSCNum_104s_44 : 0|5@1+ (1,0) [0|31] ""  PC
 SG_ S2P_Bal_CellNum_104s_44 : 5|7@1+ (1,0) [0|127] ""  PC
 SG_ S2P_Bal_Type_104s_44 : 12|2@1+ (1,0) [0|3] ""  PC
 SG_ S2P_Bal_TimeRemain_104s_44 : 14|9@1+ (1,0) [0|511] ""  PC
 SG_ S2P_Bal_DeltaVolt_104s_44 : 23|10@1+ (1,0) [0|1023] ""  PC
 SG_ S2P_Bal_TypeLevel_104s_44 : 44|3@1+ (1,0) [0|7] ""  PC
 SG_ S2P_Bal_Strategy_104s_44 : 49|1@1+ (1,0) [0|1] ""  PC
 SG_ S2P_Bal_ForceBalMode_104s_44 : 50|2@1+ (1,0) [0|3] ""  PC
 SG_ S2P_Bal_CellTempFault_104s_44 : 52|1@1+ (1,0) [0|1] ""  PC
 SG_ S2P_Bal_CellVoltFail_104s_44 : 53|1@1+ (1,0) [0|1] ""  PC
 SG_ S2P_Bal_CloseBalIstr_104s_44 : 54|1@1+ (1,0) [0|1] ""  PC
 SG_ S2P_Bal_CCanTimeOut_104s_44 : 55|1@1+ (1,0) [0|1] ""  PC
 SG_ S2P_Bal_CellOffLine_104s_44 : 56|1@1+ (1,0) [0|1] ""  PC
 SG_ S2P_Bal_BalanCirFlt_104s_44 : 57|1@1+ (1,0) [0|1] ""  PC
 SG_ S2P_Bal_CellVoOverFlt104s_44 : 59|1@1+ (1,0) [0|1] ""  PC
 SG_ S2P_Bal_CellVoLowFlt104s_44 : 60|1@1+ (1,0) [0|1] ""  PC
 SG_ S2P_Bal_CSCPCBTeFlt104s_44 : 61|1@1+ (1,0) [0|1] ""  PC

BO_ 2417946221 S2P_BL_Meg_104s__45: 8 SBMU
 SG_ S2P_Bal_CSCNum_104s_45 : 0|5@1+ (1,0) [0|31] ""  PC
 SG_ S2P_Bal_CellNum_104s_45 : 5|7@1+ (1,0) [0|127] ""  PC
 SG_ S2P_Bal_Type_104s_45 : 12|2@1+ (1,0) [0|3] ""  PC
 SG_ S2P_Bal_TimeRemain_104s_45 : 14|9@1+ (1,0) [0|511] ""  PC
 SG_ S2P_Bal_DeltaVolt_104s_45 : 23|10@1+ (1,0) [0|1023] ""  PC
 SG_ S2P_Bal_TypeLevel_104s_45 : 44|3@1+ (1,0) [0|7] ""  PC
 SG_ S2P_Bal_Strategy_104s_45 : 49|1@1+ (1,0) [0|1] ""  PC
 SG_ S2P_Bal_ForceBalMode_104s_45 : 50|2@1+ (1,0) [0|3] ""  PC
 SG_ S2P_Bal_CellTempFault_104s_45 : 52|1@1+ (1,0) [0|1] ""  PC
 SG_ S2P_Bal_CellVoltFail_104s_45 : 53|1@1+ (1,0) [0|1] ""  PC
 SG_ S2P_Bal_CloseBalIstr_104s_45 : 54|1@1+ (1,0) [0|1] ""  PC
 SG_ S2P_Bal_CCanTimeOut_104s_45 : 55|1@1+ (1,0) [0|1] ""  PC
 SG_ S2P_Bal_CellOffLine_104s_45 : 56|1@1+ (1,0) [0|1] ""  PC
 SG_ S2P_Bal_BalanCirFlt_104s_45 : 57|1@1+ (1,0) [0|1] ""  PC
 SG_ S2P_Bal_CellVoOverFlt104s_45 : 59|1@1+ (1,0) [0|1] ""  PC
 SG_ S2P_Bal_CellVoLowFlt104s_45 : 60|1@1+ (1,0) [0|1] ""  PC
 SG_ S2P_Bal_CSCPCBTeFlt104s_45 : 61|1@1+ (1,0) [0|1] ""  PC

BO_ 2417946222 S2P_BL_Meg_104s__46: 8 SBMU
 SG_ S2P_Bal_CSCNum_104s_46 : 0|5@1+ (1,0) [0|31] ""  PC
 SG_ S2P_Bal_CellNum_104s_46 : 5|7@1+ (1,0) [0|127] ""  PC
 SG_ S2P_Bal_Type_104s_46 : 12|2@1+ (1,0) [0|3] ""  PC
 SG_ S2P_Bal_TimeRemain_104s_46 : 14|9@1+ (1,0) [0|511] ""  PC
 SG_ S2P_Bal_DeltaVolt_104s_46 : 23|10@1+ (1,0) [0|1023] ""  PC
 SG_ S2P_Bal_TypeLevel_104s_46 : 44|3@1+ (1,0) [0|7] ""  PC
 SG_ S2P_Bal_Strategy_104s_46 : 49|1@1+ (1,0) [0|1] ""  PC
 SG_ S2P_Bal_ForceBalMode_104s_46 : 50|2@1+ (1,0) [0|3] ""  PC
 SG_ S2P_Bal_CellTempFault_104s_46 : 52|1@1+ (1,0) [0|1] ""  PC
 SG_ S2P_Bal_CellVoltFail_104s_46 : 53|1@1+ (1,0) [0|1] ""  PC
 SG_ S2P_Bal_CloseBalIstr_104s_46 : 54|1@1+ (1,0) [0|1] ""  PC
 SG_ S2P_Bal_CCanTimeOut_104s_46 : 55|1@1+ (1,0) [0|1] ""  PC
 SG_ S2P_Bal_CellOffLine_104s_46 : 56|1@1+ (1,0) [0|1] ""  PC
 SG_ S2P_Bal_BalanCirFlt_104s_46 : 57|1@1+ (1,0) [0|1] ""  PC
 SG_ S2P_Bal_CellVoOverFlt104s_46 : 59|1@1+ (1,0) [0|1] ""  PC
 SG_ S2P_Bal_CellVoLowFlt104s_46 : 60|1@1+ (1,0) [0|1] ""  PC
 SG_ S2P_Bal_CSCPCBTeFlt104s_46 : 61|1@1+ (1,0) [0|1] ""  PC

BO_ 2417946223 S2P_BL_Meg_104s__47: 8 SBMU
 SG_ S2P_Bal_CSCNum_104s_47 : 0|5@1+ (1,0) [0|31] ""  PC
 SG_ S2P_Bal_CellNum_104s_47 : 5|7@1+ (1,0) [0|127] ""  PC
 SG_ S2P_Bal_Type_104s_47 : 12|2@1+ (1,0) [0|3] ""  PC
 SG_ S2P_Bal_TimeRemain_104s_47 : 14|9@1+ (1,0) [0|511] ""  PC
 SG_ S2P_Bal_DeltaVolt_104s_47 : 23|10@1+ (1,0) [0|1023] ""  PC
 SG_ S2P_Bal_TypeLevel_104s_47 : 44|3@1+ (1,0) [0|7] ""  PC
 SG_ S2P_Bal_Strategy_104s_47 : 49|1@1+ (1,0) [0|1] ""  PC
 SG_ S2P_Bal_ForceBalMode_104s_47 : 50|2@1+ (1,0) [0|3] ""  PC
 SG_ S2P_Bal_CellTempFault_104s_47 : 52|1@1+ (1,0) [0|1] ""  PC
 SG_ S2P_Bal_CellVoltFail_104s_47 : 53|1@1+ (1,0) [0|1] ""  PC
 SG_ S2P_Bal_CloseBalIstr_104s_47 : 54|1@1+ (1,0) [0|1] ""  PC
 SG_ S2P_Bal_CCanTimeOut_104s_47 : 55|1@1+ (1,0) [0|1] ""  PC
 SG_ S2P_Bal_CellOffLine_104s_47 : 56|1@1+ (1,0) [0|1] ""  PC
 SG_ S2P_Bal_BalanCirFlt_104s_47 : 57|1@1+ (1,0) [0|1] ""  PC
 SG_ S2P_Bal_CellVoOverFlt104s_47 : 59|1@1+ (1,0) [0|1] ""  PC
 SG_ S2P_Bal_CellVoLowFlt104s_47 : 60|1@1+ (1,0) [0|1] ""  PC
 SG_ S2P_Bal_CSCPCBTeFlt104s_47 : 61|1@1+ (1,0) [0|1] ""  PC

BO_ 2417946224 S2P_BL_Meg_104s__48: 8 SBMU
 SG_ S2P_Bal_CSCNum_104s_48 : 0|5@1+ (1,0) [0|31] ""  PC
 SG_ S2P_Bal_CellNum_104s_48 : 5|7@1+ (1,0) [0|127] ""  PC
 SG_ S2P_Bal_Type_104s_48 : 12|2@1+ (1,0) [0|3] ""  PC
 SG_ S2P_Bal_TimeRemain_104s_48 : 14|9@1+ (1,0) [0|511] ""  PC
 SG_ S2P_Bal_DeltaVolt_104s_48 : 23|10@1+ (1,0) [0|1023] ""  PC
 SG_ S2P_Bal_TypeLevel_104s_48 : 44|3@1+ (1,0) [0|7] ""  PC
 SG_ S2P_Bal_Strategy_104s_48 : 49|1@1+ (1,0) [0|1] ""  PC
 SG_ S2P_Bal_ForceBalMode_104s_48 : 50|2@1+ (1,0) [0|3] ""  PC
 SG_ S2P_Bal_CellTempFault_104s_48 : 52|1@1+ (1,0) [0|1] ""  PC
 SG_ S2P_Bal_CellVoltFail_104s_48 : 53|1@1+ (1,0) [0|1] ""  PC
 SG_ S2P_Bal_CloseBalIstr_104s_48 : 54|1@1+ (1,0) [0|1] ""  PC
 SG_ S2P_Bal_CCanTimeOut_104s_48 : 55|1@1+ (1,0) [0|1] ""  PC
 SG_ S2P_Bal_CellOffLine_104s_48 : 56|1@1+ (1,0) [0|1] ""  PC
 SG_ S2P_Bal_BalanCirFlt_104s_48 : 57|1@1+ (1,0) [0|1] ""  PC
 SG_ S2P_Bal_CellVoOverFlt104s_48 : 59|1@1+ (1,0) [0|1] ""  PC
 SG_ S2P_Bal_CellVoLowFlt104s_48 : 60|1@1+ (1,0) [0|1] ""  PC
 SG_ S2P_Bal_CSCPCBTeFlt104s_48 : 61|1@1+ (1,0) [0|1] ""  PC

BO_ 2417946225 S2P_BL_Meg_104s__49: 8 SBMU
 SG_ S2P_Bal_CSCNum_104s_49 : 0|5@1+ (1,0) [0|31] ""  PC
 SG_ S2P_Bal_CellNum_104s_49 : 5|7@1+ (1,0) [0|127] ""  PC
 SG_ S2P_Bal_Type_104s_49 : 12|2@1+ (1,0) [0|3] ""  PC
 SG_ S2P_Bal_TimeRemain_104s_49 : 14|9@1+ (1,0) [0|511] ""  PC
 SG_ S2P_Bal_DeltaVolt_104s_49 : 23|10@1+ (1,0) [0|1023] ""  PC
 SG_ S2P_Bal_TypeLevel_104s_49 : 44|3@1+ (1,0) [0|7] ""  PC
 SG_ S2P_Bal_Strategy_104s_49 : 49|1@1+ (1,0) [0|1] ""  PC
 SG_ S2P_Bal_ForceBalMode_104s_49 : 50|2@1+ (1,0) [0|3] ""  PC
 SG_ S2P_Bal_CellTempFault_104s_49 : 52|1@1+ (1,0) [0|1] ""  PC
 SG_ S2P_Bal_CellVoltFail_104s_49 : 53|1@1+ (1,0) [0|1] ""  PC
 SG_ S2P_Bal_CloseBalIstr_104s_49 : 54|1@1+ (1,0) [0|1] ""  PC
 SG_ S2P_Bal_CCanTimeOut_104s_49 : 55|1@1+ (1,0) [0|1] ""  PC
 SG_ S2P_Bal_CellOffLine_104s_49 : 56|1@1+ (1,0) [0|1] ""  PC
 SG_ S2P_Bal_BalanCirFlt_104s_49 : 57|1@1+ (1,0) [0|1] ""  PC
 SG_ S2P_Bal_CellVoOverFlt104s_49 : 59|1@1+ (1,0) [0|1] ""  PC
 SG_ S2P_Bal_CellVoLowFlt104s_49 : 60|1@1+ (1,0) [0|1] ""  PC
 SG_ S2P_Bal_CSCPCBTeFlt104s_49 : 61|1@1+ (1,0) [0|1] ""  PC

BO_ 2417946226 S2P_BL_Meg_104s__50: 8 SBMU
 SG_ S2P_Bal_CSCNum_104s_50 : 0|5@1+ (1,0) [0|31] ""  PC
 SG_ S2P_Bal_CellNum_104s_50 : 5|7@1+ (1,0) [0|127] ""  PC
 SG_ S2P_Bal_Type_104s_50 : 12|2@1+ (1,0) [0|3] ""  PC
 SG_ S2P_Bal_TimeRemain_104s_50 : 14|9@1+ (1,0) [0|511] ""  PC
 SG_ S2P_Bal_DeltaVolt_104s_50 : 23|10@1+ (1,0) [0|1023] ""  PC
 SG_ S2P_Bal_TypeLevel_104s_50 : 44|3@1+ (1,0) [0|7] ""  PC
 SG_ S2P_Bal_Strategy_104s_50 : 49|1@1+ (1,0) [0|1] ""  PC
 SG_ S2P_Bal_ForceBalMode_104s_50 : 50|2@1+ (1,0) [0|3] ""  PC
 SG_ S2P_Bal_CellTempFault_104s_50 : 52|1@1+ (1,0) [0|1] ""  PC
 SG_ S2P_Bal_CellVoltFail_104s_50 : 53|1@1+ (1,0) [0|1] ""  PC
 SG_ S2P_Bal_CloseBalIstr_104s_50 : 54|1@1+ (1,0) [0|1] ""  PC
 SG_ S2P_Bal_CCanTimeOut_104s_50 : 55|1@1+ (1,0) [0|1] ""  PC
 SG_ S2P_Bal_CellOffLine_104s_50 : 56|1@1+ (1,0) [0|1] ""  PC
 SG_ S2P_Bal_BalanCirFlt_104s_50 : 57|1@1+ (1,0) [0|1] ""  PC
 SG_ S2P_Bal_CellVoOverFlt104s_50 : 59|1@1+ (1,0) [0|1] ""  PC
 SG_ S2P_Bal_CellVoLowFlt104s_50 : 60|1@1+ (1,0) [0|1] ""  PC
 SG_ S2P_Bal_CSCPCBTeFlt104s_50 : 61|1@1+ (1,0) [0|1] ""  PC

BO_ 2417946227 S2P_BL_Meg_104s__51: 8 SBMU
 SG_ S2P_Bal_CSCNum_104s_51 : 0|5@1+ (1,0) [0|31] ""  PC
 SG_ S2P_Bal_CellNum_104s_51 : 5|7@1+ (1,0) [0|127] ""  PC
 SG_ S2P_Bal_Type_104s_51 : 12|2@1+ (1,0) [0|3] ""  PC
 SG_ S2P_Bal_TimeRemain_104s_51 : 14|9@1+ (1,0) [0|511] ""  PC
 SG_ S2P_Bal_DeltaVolt_104s_51 : 23|10@1+ (1,0) [0|1023] ""  PC
 SG_ S2P_Bal_TypeLevel_104s_51 : 44|3@1+ (1,0) [0|7] ""  PC
 SG_ S2P_Bal_Strategy_104s_51 : 49|1@1+ (1,0) [0|1] ""  PC
 SG_ S2P_Bal_ForceBalMode_104s_51 : 50|2@1+ (1,0) [0|3] ""  PC
 SG_ S2P_Bal_CellTempFault_104s_51 : 52|1@1+ (1,0) [0|1] ""  PC
 SG_ S2P_Bal_CellVoltFail_104s_51 : 53|1@1+ (1,0) [0|1] ""  PC
 SG_ S2P_Bal_CloseBalIstr_104s_51 : 54|1@1+ (1,0) [0|1] ""  PC
 SG_ S2P_Bal_CCanTimeOut_104s_51 : 55|1@1+ (1,0) [0|1] ""  PC
 SG_ S2P_Bal_CellOffLine_104s_51 : 56|1@1+ (1,0) [0|1] ""  PC
 SG_ S2P_Bal_BalanCirFlt_104s_51 : 57|1@1+ (1,0) [0|1] ""  PC
 SG_ S2P_Bal_CellVoOverFlt104s_51 : 59|1@1+ (1,0) [0|1] ""  PC
 SG_ S2P_Bal_CellVoLowFlt104s_51 : 60|1@1+ (1,0) [0|1] ""  PC
 SG_ S2P_Bal_CSCPCBTeFlt104s_51 : 61|1@1+ (1,0) [0|1] ""  PC

BO_ 2417946228 S2P_BL_Meg_104s__52: 8 SBMU
 SG_ S2P_Bal_CSCNum_104s_52 : 0|5@1+ (1,0) [0|31] ""  PC
 SG_ S2P_Bal_CellNum_104s_52 : 5|7@1+ (1,0) [0|127] ""  PC
 SG_ S2P_Bal_Type_104s_52 : 12|2@1+ (1,0) [0|3] ""  PC
 SG_ S2P_Bal_TimeRemain_104s_52 : 14|9@1+ (1,0) [0|511] ""  PC
 SG_ S2P_Bal_DeltaVolt_104s_52 : 23|10@1+ (1,0) [0|1023] ""  PC
 SG_ S2P_Bal_TypeLevel_104s_52 : 44|3@1+ (1,0) [0|7] ""  PC
 SG_ S2P_Bal_Strategy_104s_52 : 49|1@1+ (1,0) [0|1] ""  PC
 SG_ S2P_Bal_ForceBalMode_104s_52 : 50|2@1+ (1,0) [0|3] ""  PC
 SG_ S2P_Bal_CellTempFault_104s_52 : 52|1@1+ (1,0) [0|1] ""  PC
 SG_ S2P_Bal_CellVoltFail_104s_52 : 53|1@1+ (1,0) [0|1] ""  PC
 SG_ S2P_Bal_CloseBalIstr_104s_52 : 54|1@1+ (1,0) [0|1] ""  PC
 SG_ S2P_Bal_CCanTimeOut_104s_52 : 55|1@1+ (1,0) [0|1] ""  PC
 SG_ S2P_Bal_CellOffLine_104s_52 : 56|1@1+ (1,0) [0|1] ""  PC
 SG_ S2P_Bal_BalanCirFlt_104s_52 : 57|1@1+ (1,0) [0|1] ""  PC
 SG_ S2P_Bal_CellVoOverFlt104s_52 : 59|1@1+ (1,0) [0|1] ""  PC
 SG_ S2P_Bal_CellVoLowFlt104s_52 : 60|1@1+ (1,0) [0|1] ""  PC
 SG_ S2P_Bal_CSCPCBTeFlt104s_52 : 61|1@1+ (1,0) [0|1] ""  PC

BO_ 2417946229 S2P_BL_Meg_104s__53: 8 SBMU
 SG_ S2P_Bal_CSCNum_104s_53 : 0|5@1+ (1,0) [0|31] ""  PC
 SG_ S2P_Bal_CellNum_104s_53 : 5|7@1+ (1,0) [0|127] ""  PC
 SG_ S2P_Bal_Type_104s_53 : 12|2@1+ (1,0) [0|3] ""  PC
 SG_ S2P_Bal_TimeRemain_104s_53 : 14|9@1+ (1,0) [0|511] ""  PC
 SG_ S2P_Bal_DeltaVolt_104s_53 : 23|10@1+ (1,0) [0|1023] ""  PC
 SG_ S2P_Bal_TypeLevel_104s_53 : 44|3@1+ (1,0) [0|7] ""  PC
 SG_ S2P_Bal_Strategy_104s_53 : 49|1@1+ (1,0) [0|1] ""  PC
 SG_ S2P_Bal_ForceBalMode_104s_53 : 50|2@1+ (1,0) [0|3] ""  PC
 SG_ S2P_Bal_CellTempFault_104s_53 : 52|1@1+ (1,0) [0|1] ""  PC
 SG_ S2P_Bal_CellVoltFail_104s_53 : 53|1@1+ (1,0) [0|1] ""  PC
 SG_ S2P_Bal_CloseBalIstr_104s_53 : 54|1@1+ (1,0) [0|1] ""  PC
 SG_ S2P_Bal_CCanTimeOut_104s_53 : 55|1@1+ (1,0) [0|1] ""  PC
 SG_ S2P_Bal_CellOffLine_104s_53 : 56|1@1+ (1,0) [0|1] ""  PC
 SG_ S2P_Bal_BalanCirFlt_104s_53 : 57|1@1+ (1,0) [0|1] ""  PC
 SG_ S2P_Bal_CellVoOverFlt104s_53 : 59|1@1+ (1,0) [0|1] ""  PC
 SG_ S2P_Bal_CellVoLowFlt104s_53 : 60|1@1+ (1,0) [0|1] ""  PC
 SG_ S2P_Bal_CSCPCBTeFlt104s_53 : 61|1@1+ (1,0) [0|1] ""  PC

BO_ 2417946230 S2P_BL_Meg_104s__54: 8 SBMU
 SG_ S2P_Bal_CSCNum_104s_54 : 0|5@1+ (1,0) [0|31] ""  PC
 SG_ S2P_Bal_CellNum_104s_54 : 5|7@1+ (1,0) [0|127] ""  PC
 SG_ S2P_Bal_Type_104s_54 : 12|2@1+ (1,0) [0|3] ""  PC
 SG_ S2P_Bal_TimeRemain_104s_54 : 14|9@1+ (1,0) [0|511] ""  PC
 SG_ S2P_Bal_DeltaVolt_104s_54 : 23|10@1+ (1,0) [0|1023] ""  PC
 SG_ S2P_Bal_TypeLevel_104s_54 : 44|3@1+ (1,0) [0|7] ""  PC
 SG_ S2P_Bal_Strategy_104s_54 : 49|1@1+ (1,0) [0|1] ""  PC
 SG_ S2P_Bal_ForceBalMode_104s_54 : 50|2@1+ (1,0) [0|3] ""  PC
 SG_ S2P_Bal_CellTempFault_104s_54 : 52|1@1+ (1,0) [0|1] ""  PC
 SG_ S2P_Bal_CellVoltFail_104s_54 : 53|1@1+ (1,0) [0|1] ""  PC
 SG_ S2P_Bal_CloseBalIstr_104s_54 : 54|1@1+ (1,0) [0|1] ""  PC
 SG_ S2P_Bal_CCanTimeOut_104s_54 : 55|1@1+ (1,0) [0|1] ""  PC
 SG_ S2P_Bal_CellOffLine_104s_54 : 56|1@1+ (1,0) [0|1] ""  PC
 SG_ S2P_Bal_BalanCirFlt_104s_54 : 57|1@1+ (1,0) [0|1] ""  PC
 SG_ S2P_Bal_CellVoOverFlt104s_54 : 59|1@1+ (1,0) [0|1] ""  PC
 SG_ S2P_Bal_CellVoLowFlt104s_54 : 60|1@1+ (1,0) [0|1] ""  PC
 SG_ S2P_Bal_CSCPCBTeFlt104s_54 : 61|1@1+ (1,0) [0|1] ""  PC

BO_ 2417946231 S2P_BL_Meg_104s__55: 8 SBMU
 SG_ S2P_Bal_CSCNum_104s_55 : 0|5@1+ (1,0) [0|31] ""  PC
 SG_ S2P_Bal_CellNum_104s_55 : 5|7@1+ (1,0) [0|127] ""  PC
 SG_ S2P_Bal_Type_104s_55 : 12|2@1+ (1,0) [0|3] ""  PC
 SG_ S2P_Bal_TimeRemain_104s_55 : 14|9@1+ (1,0) [0|511] ""  PC
 SG_ S2P_Bal_DeltaVolt_104s_55 : 23|10@1+ (1,0) [0|1023] ""  PC
 SG_ S2P_Bal_TypeLevel_104s_55 : 44|3@1+ (1,0) [0|7] ""  PC
 SG_ S2P_Bal_Strategy_104s_55 : 49|1@1+ (1,0) [0|1] ""  PC
 SG_ S2P_Bal_ForceBalMode_104s_55 : 50|2@1+ (1,0) [0|3] ""  PC
 SG_ S2P_Bal_CellTempFault_104s_55 : 52|1@1+ (1,0) [0|1] ""  PC
 SG_ S2P_Bal_CellVoltFail_104s_55 : 53|1@1+ (1,0) [0|1] ""  PC
 SG_ S2P_Bal_CloseBalIstr_104s_55 : 54|1@1+ (1,0) [0|1] ""  PC
 SG_ S2P_Bal_CCanTimeOut_104s_55 : 55|1@1+ (1,0) [0|1] ""  PC
 SG_ S2P_Bal_CellOffLine_104s_55 : 56|1@1+ (1,0) [0|1] ""  PC
 SG_ S2P_Bal_BalanCirFlt_104s_55 : 57|1@1+ (1,0) [0|1] ""  PC
 SG_ S2P_Bal_CellVoOverFlt104s_55 : 59|1@1+ (1,0) [0|1] ""  PC
 SG_ S2P_Bal_CellVoLowFlt104s_55 : 60|1@1+ (1,0) [0|1] ""  PC
 SG_ S2P_Bal_CSCPCBTeFlt104s_55 : 61|1@1+ (1,0) [0|1] ""  PC

BO_ 2417946232 S2P_BL_Meg_104s__56: 8 SBMU
 SG_ S2P_Bal_CSCNum_104s_56 : 0|5@1+ (1,0) [0|31] ""  PC
 SG_ S2P_Bal_CellNum_104s_56 : 5|7@1+ (1,0) [0|127] ""  PC
 SG_ S2P_Bal_Type_104s_56 : 12|2@1+ (1,0) [0|3] ""  PC
 SG_ S2P_Bal_TimeRemain_104s_56 : 14|9@1+ (1,0) [0|511] ""  PC
 SG_ S2P_Bal_DeltaVolt_104s_56 : 23|10@1+ (1,0) [0|1023] ""  PC
 SG_ S2P_Bal_TypeLevel_104s_56 : 44|3@1+ (1,0) [0|7] ""  PC
 SG_ S2P_Bal_Strategy_104s_56 : 49|1@1+ (1,0) [0|1] ""  PC
 SG_ S2P_Bal_ForceBalMode_104s_56 : 50|2@1+ (1,0) [0|3] ""  PC
 SG_ S2P_Bal_CellTempFault_104s_56 : 52|1@1+ (1,0) [0|1] ""  PC
 SG_ S2P_Bal_CellVoltFail_104s_56 : 53|1@1+ (1,0) [0|1] ""  PC
 SG_ S2P_Bal_CloseBalIstr_104s_56 : 54|1@1+ (1,0) [0|1] ""  PC
 SG_ S2P_Bal_CCanTimeOut_104s_56 : 55|1@1+ (1,0) [0|1] ""  PC
 SG_ S2P_Bal_CellOffLine_104s_56 : 56|1@1+ (1,0) [0|1] ""  PC
 SG_ S2P_Bal_BalanCirFlt_104s_56 : 57|1@1+ (1,0) [0|1] ""  PC
 SG_ S2P_Bal_CellVoOverFlt104s_56 : 59|1@1+ (1,0) [0|1] ""  PC
 SG_ S2P_Bal_CellVoLowFlt104s_56 : 60|1@1+ (1,0) [0|1] ""  PC
 SG_ S2P_Bal_CSCPCBTeFlt104s_56 : 61|1@1+ (1,0) [0|1] ""  PC

BO_ 2417946233 S2P_BL_Meg_104s__57: 8 SBMU
 SG_ S2P_Bal_CSCNum_104s_57 : 0|5@1+ (1,0) [0|31] ""  PC
 SG_ S2P_Bal_CellNum_104s_57 : 5|7@1+ (1,0) [0|127] ""  PC
 SG_ S2P_Bal_Type_104s_57 : 12|2@1+ (1,0) [0|3] ""  PC
 SG_ S2P_Bal_TimeRemain_104s_57 : 14|9@1+ (1,0) [0|511] ""  PC
 SG_ S2P_Bal_DeltaVolt_104s_57 : 23|10@1+ (1,0) [0|1023] ""  PC
 SG_ S2P_Bal_TypeLevel_104s_57 : 44|3@1+ (1,0) [0|7] ""  PC
 SG_ S2P_Bal_Strategy_104s_57 : 49|1@1+ (1,0) [0|1] ""  PC
 SG_ S2P_Bal_ForceBalMode_104s_57 : 50|2@1+ (1,0) [0|3] ""  PC
 SG_ S2P_Bal_CellTempFault_104s_57 : 52|1@1+ (1,0) [0|1] ""  PC
 SG_ S2P_Bal_CellVoltFail_104s_57 : 53|1@1+ (1,0) [0|1] ""  PC
 SG_ S2P_Bal_CloseBalIstr_104s_57 : 54|1@1+ (1,0) [0|1] ""  PC
 SG_ S2P_Bal_CCanTimeOut_104s_57 : 55|1@1+ (1,0) [0|1] ""  PC
 SG_ S2P_Bal_CellOffLine_104s_57 : 56|1@1+ (1,0) [0|1] ""  PC
 SG_ S2P_Bal_BalanCirFlt_104s_57 : 57|1@1+ (1,0) [0|1] ""  PC
 SG_ S2P_Bal_CellVoOverFlt104s_57 : 59|1@1+ (1,0) [0|1] ""  PC
 SG_ S2P_Bal_CellVoLowFlt104s_57 : 60|1@1+ (1,0) [0|1] ""  PC
 SG_ S2P_Bal_CSCPCBTeFlt104s_57 : 61|1@1+ (1,0) [0|1] ""  PC

BO_ 2417946234 S2P_BL_Meg_104s__58: 8 SBMU
 SG_ S2P_Bal_CSCNum_104s_58 : 0|5@1+ (1,0) [0|31] ""  PC
 SG_ S2P_Bal_CellNum_104s_58 : 5|7@1+ (1,0) [0|127] ""  PC
 SG_ S2P_Bal_Type_104s_58 : 12|2@1+ (1,0) [0|3] ""  PC
 SG_ S2P_Bal_TimeRemain_104s_58 : 14|9@1+ (1,0) [0|511] ""  PC
 SG_ S2P_Bal_DeltaVolt_104s_58 : 23|10@1+ (1,0) [0|1023] ""  PC
 SG_ S2P_Bal_TypeLevel_104s_58 : 44|3@1+ (1,0) [0|7] ""  PC
 SG_ S2P_Bal_Strategy_104s_58 : 49|1@1+ (1,0) [0|1] ""  PC
 SG_ S2P_Bal_ForceBalMode_104s_58 : 50|2@1+ (1,0) [0|3] ""  PC
 SG_ S2P_Bal_CellTempFault_104s_58 : 52|1@1+ (1,0) [0|1] ""  PC
 SG_ S2P_Bal_CellVoltFail_104s_58 : 53|1@1+ (1,0) [0|1] ""  PC
 SG_ S2P_Bal_CloseBalIstr_104s_58 : 54|1@1+ (1,0) [0|1] ""  PC
 SG_ S2P_Bal_CCanTimeOut_104s_58 : 55|1@1+ (1,0) [0|1] ""  PC
 SG_ S2P_Bal_CellOffLine_104s_58 : 56|1@1+ (1,0) [0|1] ""  PC
 SG_ S2P_Bal_BalanCirFlt_104s_58 : 57|1@1+ (1,0) [0|1] ""  PC
 SG_ S2P_Bal_CellVoOverFlt104s_58 : 59|1@1+ (1,0) [0|1] ""  PC
 SG_ S2P_Bal_CellVoLowFlt104s_58 : 60|1@1+ (1,0) [0|1] ""  PC
 SG_ S2P_Bal_CSCPCBTeFlt104s_58 : 61|1@1+ (1,0) [0|1] ""  PC

BO_ 2417946235 S2P_BL_Meg_104s__59: 8 SBMU
 SG_ S2P_Bal_CSCNum_104s_59 : 0|5@1+ (1,0) [0|31] ""  PC
 SG_ S2P_Bal_CellNum_104s_59 : 5|7@1+ (1,0) [0|127] ""  PC
 SG_ S2P_Bal_Type_104s_59 : 12|2@1+ (1,0) [0|3] ""  PC
 SG_ S2P_Bal_TimeRemain_104s_59 : 14|9@1+ (1,0) [0|511] ""  PC
 SG_ S2P_Bal_DeltaVolt_104s_59 : 23|10@1+ (1,0) [0|1023] ""  PC
 SG_ S2P_Bal_TypeLevel_104s_59 : 44|3@1+ (1,0) [0|7] ""  PC
 SG_ S2P_Bal_Strategy_104s_59 : 49|1@1+ (1,0) [0|1] ""  PC
 SG_ S2P_Bal_ForceBalMode_104s_59 : 50|2@1+ (1,0) [0|3] ""  PC
 SG_ S2P_Bal_CellTempFault_104s_59 : 52|1@1+ (1,0) [0|1] ""  PC
 SG_ S2P_Bal_CellVoltFail_104s_59 : 53|1@1+ (1,0) [0|1] ""  PC
 SG_ S2P_Bal_CloseBalIstr_104s_59 : 54|1@1+ (1,0) [0|1] ""  PC
 SG_ S2P_Bal_CCanTimeOut_104s_59 : 55|1@1+ (1,0) [0|1] ""  PC
 SG_ S2P_Bal_CellOffLine_104s_59 : 56|1@1+ (1,0) [0|1] ""  PC
 SG_ S2P_Bal_BalanCirFlt_104s_59 : 57|1@1+ (1,0) [0|1] ""  PC
 SG_ S2P_Bal_CellVoOverFlt104s_59 : 59|1@1+ (1,0) [0|1] ""  PC
 SG_ S2P_Bal_CellVoLowFlt104s_59 : 60|1@1+ (1,0) [0|1] ""  PC
 SG_ S2P_Bal_CSCPCBTeFlt104s_59 : 61|1@1+ (1,0) [0|1] ""  PC

BO_ 2417946236 S2P_BL_Meg_104s__60: 8 SBMU
 SG_ S2P_Bal_CSCNum_104s_60 : 0|5@1+ (1,0) [0|31] ""  PC
 SG_ S2P_Bal_CellNum_104s_60 : 5|7@1+ (1,0) [0|127] ""  PC
 SG_ S2P_Bal_Type_104s_60 : 12|2@1+ (1,0) [0|3] ""  PC
 SG_ S2P_Bal_TimeRemain_104s_60 : 14|9@1+ (1,0) [0|511] ""  PC
 SG_ S2P_Bal_DeltaVolt_104s_60 : 23|10@1+ (1,0) [0|1023] ""  PC
 SG_ S2P_Bal_TypeLevel_104s_60 : 44|3@1+ (1,0) [0|7] ""  PC
 SG_ S2P_Bal_Strategy_104s_60 : 49|1@1+ (1,0) [0|1] ""  PC
 SG_ S2P_Bal_ForceBalMode_104s_60 : 50|2@1+ (1,0) [0|3] ""  PC
 SG_ S2P_Bal_CellTempFault_104s_60 : 52|1@1+ (1,0) [0|1] ""  PC
 SG_ S2P_Bal_CellVoltFail_104s_60 : 53|1@1+ (1,0) [0|1] ""  PC
 SG_ S2P_Bal_CloseBalIstr_104s_60 : 54|1@1+ (1,0) [0|1] ""  PC
 SG_ S2P_Bal_CCanTimeOut_104s_60 : 55|1@1+ (1,0) [0|1] ""  PC
 SG_ S2P_Bal_CellOffLine_104s_60 : 56|1@1+ (1,0) [0|1] ""  PC
 SG_ S2P_Bal_BalanCirFlt_104s_60 : 57|1@1+ (1,0) [0|1] ""  PC
 SG_ S2P_Bal_CellVoOverFlt104s_60 : 59|1@1+ (1,0) [0|1] ""  PC
 SG_ S2P_Bal_CellVoLowFlt104s_60 : 60|1@1+ (1,0) [0|1] ""  PC
 SG_ S2P_Bal_CSCPCBTeFlt104s_60 : 61|1@1+ (1,0) [0|1] ""  PC

BO_ 2417946237 S2P_BL_Meg_104s__61: 8 SBMU
 SG_ S2P_Bal_CSCNum_104s_61 : 0|5@1+ (1,0) [0|31] ""  PC
 SG_ S2P_Bal_CellNum_104s_61 : 5|7@1+ (1,0) [0|127] ""  PC
 SG_ S2P_Bal_Type_104s_61 : 12|2@1+ (1,0) [0|3] ""  PC
 SG_ S2P_Bal_TimeRemain_104s_61 : 14|9@1+ (1,0) [0|511] ""  PC
 SG_ S2P_Bal_DeltaVolt_104s_61 : 23|10@1+ (1,0) [0|1023] ""  PC
 SG_ S2P_Bal_TypeLevel_104s_61 : 44|3@1+ (1,0) [0|7] ""  PC
 SG_ S2P_Bal_Strategy_104s_61 : 49|1@1+ (1,0) [0|1] ""  PC
 SG_ S2P_Bal_ForceBalMode_104s_61 : 50|2@1+ (1,0) [0|3] ""  PC
 SG_ S2P_Bal_CellTempFault_104s_61 : 52|1@1+ (1,0) [0|1] ""  PC
 SG_ S2P_Bal_CellVoltFail_104s_61 : 53|1@1+ (1,0) [0|1] ""  PC
 SG_ S2P_Bal_CloseBalIstr_104s_61 : 54|1@1+ (1,0) [0|1] ""  PC
 SG_ S2P_Bal_CCanTimeOut_104s_61 : 55|1@1+ (1,0) [0|1] ""  PC
 SG_ S2P_Bal_CellOffLine_104s_61 : 56|1@1+ (1,0) [0|1] ""  PC
 SG_ S2P_Bal_BalanCirFlt_104s_61 : 57|1@1+ (1,0) [0|1] ""  PC
 SG_ S2P_Bal_CellVoOverFlt104s_61 : 59|1@1+ (1,0) [0|1] ""  PC
 SG_ S2P_Bal_CellVoLowFlt104s_61 : 60|1@1+ (1,0) [0|1] ""  PC
 SG_ S2P_Bal_CSCPCBTeFlt104s_61 : 61|1@1+ (1,0) [0|1] ""  PC

BO_ 2417946238 S2P_BL_Meg_104s__62: 8 SBMU
 SG_ S2P_Bal_CSCNum_104s_62 : 0|5@1+ (1,0) [0|31] ""  PC
 SG_ S2P_Bal_CellNum_104s_62 : 5|7@1+ (1,0) [0|127] ""  PC
 SG_ S2P_Bal_Type_104s_62 : 12|2@1+ (1,0) [0|3] ""  PC
 SG_ S2P_Bal_TimeRemain_104s_62 : 14|9@1+ (1,0) [0|511] ""  PC
 SG_ S2P_Bal_DeltaVolt_104s_62 : 23|10@1+ (1,0) [0|1023] ""  PC
 SG_ S2P_Bal_TypeLevel_104s_62 : 44|3@1+ (1,0) [0|7] ""  PC
 SG_ S2P_Bal_Strategy_104s_62 : 49|1@1+ (1,0) [0|1] ""  PC
 SG_ S2P_Bal_ForceBalMode_104s_62 : 50|2@1+ (1,0) [0|3] ""  PC
 SG_ S2P_Bal_CellTempFault_104s_62 : 52|1@1+ (1,0) [0|1] ""  PC
 SG_ S2P_Bal_CellVoltFail_104s_62 : 53|1@1+ (1,0) [0|1] ""  PC
 SG_ S2P_Bal_CloseBalIstr_104s_62 : 54|1@1+ (1,0) [0|1] ""  PC
 SG_ S2P_Bal_CCanTimeOut_104s_62 : 55|1@1+ (1,0) [0|1] ""  PC
 SG_ S2P_Bal_CellOffLine_104s_62 : 56|1@1+ (1,0) [0|1] ""  PC
 SG_ S2P_Bal_BalanCirFlt_104s_62 : 57|1@1+ (1,0) [0|1] ""  PC
 SG_ S2P_Bal_CellVoOverFlt104s_62 : 59|1@1+ (1,0) [0|1] ""  PC
 SG_ S2P_Bal_CellVoLowFlt104s_62 : 60|1@1+ (1,0) [0|1] ""  PC
 SG_ S2P_Bal_CSCPCBTeFlt104s_62 : 61|1@1+ (1,0) [0|1] ""  PC

BO_ 2417946239 S2P_BL_Meg_104s__63: 8 SBMU
 SG_ S2P_Bal_CSCNum_104s_63 : 0|5@1+ (1,0) [0|31] ""  PC
 SG_ S2P_Bal_CellNum_104s_63 : 5|7@1+ (1,0) [0|127] ""  PC
 SG_ S2P_Bal_Type_104s_63 : 12|2@1+ (1,0) [0|3] ""  PC
 SG_ S2P_Bal_TimeRemain_104s_63 : 14|9@1+ (1,0) [0|511] ""  PC
 SG_ S2P_Bal_DeltaVolt_104s_63 : 23|10@1+ (1,0) [0|1023] ""  PC
 SG_ S2P_Bal_TypeLevel_104s_63 : 44|3@1+ (1,0) [0|7] ""  PC
 SG_ S2P_Bal_Strategy_104s_63 : 49|1@1+ (1,0) [0|1] ""  PC
 SG_ S2P_Bal_ForceBalMode_104s_63 : 50|2@1+ (1,0) [0|3] ""  PC
 SG_ S2P_Bal_CellTempFault_104s_63 : 52|1@1+ (1,0) [0|1] ""  PC
 SG_ S2P_Bal_CellVoltFail_104s_63 : 53|1@1+ (1,0) [0|1] ""  PC
 SG_ S2P_Bal_CloseBalIstr_104s_63 : 54|1@1+ (1,0) [0|1] ""  PC
 SG_ S2P_Bal_CCanTimeOut_104s_63 : 55|1@1+ (1,0) [0|1] ""  PC
 SG_ S2P_Bal_CellOffLine_104s_63 : 56|1@1+ (1,0) [0|1] ""  PC
 SG_ S2P_Bal_BalanCirFlt_104s_63 : 57|1@1+ (1,0) [0|1] ""  PC
 SG_ S2P_Bal_CellVoOverFlt104s_63 : 59|1@1+ (1,0) [0|1] ""  PC
 SG_ S2P_Bal_CellVoLowFlt104s_63 : 60|1@1+ (1,0) [0|1] ""  PC
 SG_ S2P_Bal_CSCPCBTeFlt104s_63 : 61|1@1+ (1,0) [0|1] ""  PC

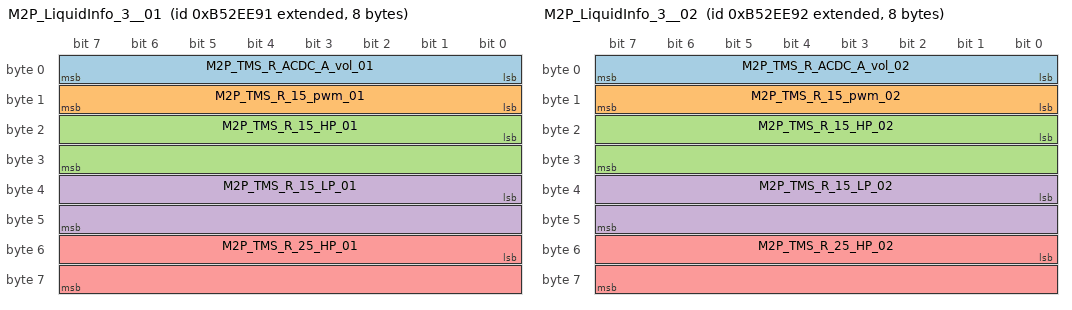
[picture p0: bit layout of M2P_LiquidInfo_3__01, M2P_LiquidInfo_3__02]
BO_ 2337468049 M2P_LiquidInfo_3__01: 8 MBMU
 SG_ M2P_TMS_R_ACDC_A_vol_01 : 0|8@1+ (1,0) [0|255] "V"  PC
 SG_ M2P_TMS_R_15_pwm_01 : 8|8@1+ (1,0) [0|255] ""  PC
 SG_ M2P_TMS_R_15_HP_01 : 16|16@1+ (1,0) [0|65535] "kpa"  PC
 SG_ M2P_TMS_R_15_LP_01 : 32|16@1+ (1,0) [0|65535] "kpa"  PC
 SG_ M2P_TMS_R_25_HP_01 : 48|16@1+ (1,0) [0|65535] "kpa"  PC

BO_ 2337468050 M2P_LiquidInfo_3__02: 8 MBMU
 SG_ M2P_TMS_R_ACDC_A_vol_02 : 0|8@1+ (1,0) [0|255] "V"  PC
 SG_ M2P_TMS_R_15_pwm_02 : 8|8@1+ (1,0) [0|255] ""  PC
 SG_ M2P_TMS_R_15_HP_02 : 16|16@1+ (1,0) [0|65535] "kpa"  PC
 SG_ M2P_TMS_R_15_LP_02 : 32|16@1+ (1,0) [0|65535] "kpa"  PC
 SG_ M2P_TMS_R_25_HP_02 : 48|16@1+ (1,0) [0|65535] "kpa"  PC

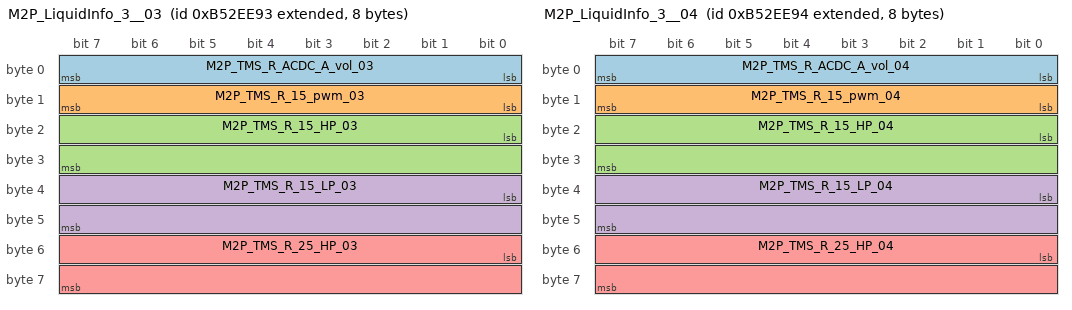
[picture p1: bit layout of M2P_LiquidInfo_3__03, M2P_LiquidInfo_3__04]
BO_ 2337468051 M2P_LiquidInfo_3__03: 8 MBMU
 SG_ M2P_TMS_R_ACDC_A_vol_03 : 0|8@1+ (1,0) [0|255] "V"  PC
 SG_ M2P_TMS_R_15_pwm_03 : 8|8@1+ (1,0) [0|255] ""  PC
 SG_ M2P_TMS_R_15_HP_03 : 16|16@1+ (1,0) [0|65535] "kpa"  PC
 SG_ M2P_TMS_R_15_LP_03 : 32|16@1+ (1,0) [0|65535] "kpa"  PC
 SG_ M2P_TMS_R_25_HP_03 : 48|16@1+ (1,0) [0|65535] "kpa"  PC

BO_ 2337468052 M2P_LiquidInfo_3__04: 8 MBMU
 SG_ M2P_TMS_R_ACDC_A_vol_04 : 0|8@1+ (1,0) [0|255] "V"  PC
 SG_ M2P_TMS_R_15_pwm_04 : 8|8@1+ (1,0) [0|255] ""  PC
 SG_ M2P_TMS_R_15_HP_04 : 16|16@1+ (1,0) [0|65535] "kpa"  PC
 SG_ M2P_TMS_R_15_LP_04 : 32|16@1+ (1,0) [0|65535] "kpa"  PC
 SG_ M2P_TMS_R_25_HP_04 : 48|16@1+ (1,0) [0|65535] "kpa"  PC

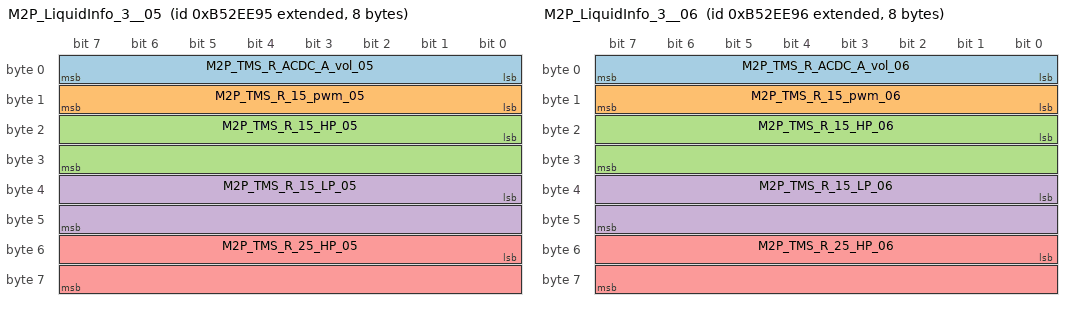
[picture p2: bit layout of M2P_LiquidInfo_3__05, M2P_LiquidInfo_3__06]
BO_ 2337468053 M2P_LiquidInfo_3__05: 8 MBMU
 SG_ M2P_TMS_R_ACDC_A_vol_05 : 0|8@1+ (1,0) [0|255] "V"  PC
 SG_ M2P_TMS_R_15_pwm_05 : 8|8@1+ (1,0) [0|255] ""  PC
 SG_ M2P_TMS_R_15_HP_05 : 16|16@1+ (1,0) [0|65535] "kpa"  PC
 SG_ M2P_TMS_R_15_LP_05 : 32|16@1+ (1,0) [0|65535] "kpa"  PC
 SG_ M2P_TMS_R_25_HP_05 : 48|16@1+ (1,0) [0|65535] "kpa"  PC

BO_ 2337468054 M2P_LiquidInfo_3__06: 8 MBMU
 SG_ M2P_TMS_R_ACDC_A_vol_06 : 0|8@1+ (1,0) [0|255] "V"  PC
 SG_ M2P_TMS_R_15_pwm_06 : 8|8@1+ (1,0) [0|255] ""  PC
 SG_ M2P_TMS_R_15_HP_06 : 16|16@1+ (1,0) [0|65535] "kpa"  PC
 SG_ M2P_TMS_R_15_LP_06 : 32|16@1+ (1,0) [0|65535] "kpa"  PC
 SG_ M2P_TMS_R_25_HP_06 : 48|16@1+ (1,0) [0|65535] "kpa"  PC

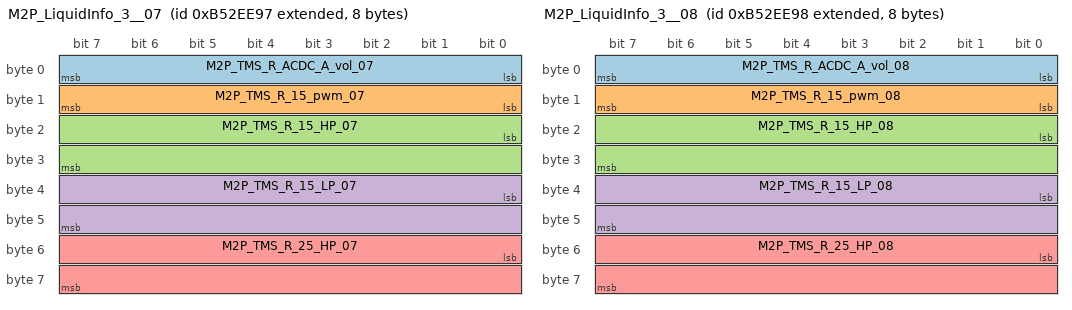
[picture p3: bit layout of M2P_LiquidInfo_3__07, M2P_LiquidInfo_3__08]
BO_ 2337468055 M2P_LiquidInfo_3__07: 8 MBMU
 SG_ M2P_TMS_R_ACDC_A_vol_07 : 0|8@1+ (1,0) [0|255] "V"  PC
 SG_ M2P_TMS_R_15_pwm_07 : 8|8@1+ (1,0) [0|255] ""  PC
 SG_ M2P_TMS_R_15_HP_07 : 16|16@1+ (1,0) [0|65535] "kpa"  PC
 SG_ M2P_TMS_R_15_LP_07 : 32|16@1+ (1,0) [0|65535] "kpa"  PC
 SG_ M2P_TMS_R_25_HP_07 : 48|16@1+ (1,0) [0|65535] "kpa"  PC

BO_ 2337468056 M2P_LiquidInfo_3__08: 8 MBMU
 SG_ M2P_TMS_R_ACDC_A_vol_08 : 0|8@1+ (1,0) [0|255] "V"  PC
 SG_ M2P_TMS_R_15_pwm_08 : 8|8@1+ (1,0) [0|255] ""  PC
 SG_ M2P_TMS_R_15_HP_08 : 16|16@1+ (1,0) [0|65535] "kpa"  PC
 SG_ M2P_TMS_R_15_LP_08 : 32|16@1+ (1,0) [0|65535] "kpa"  PC
 SG_ M2P_TMS_R_25_HP_08 : 48|16@1+ (1,0) [0|65535] "kpa"  PC

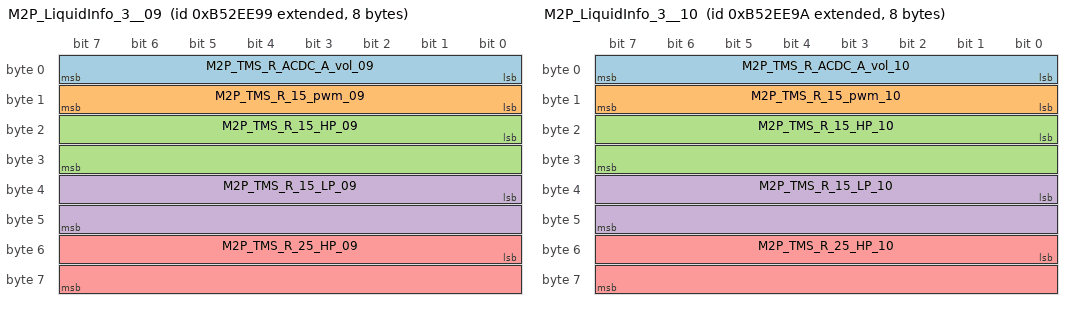
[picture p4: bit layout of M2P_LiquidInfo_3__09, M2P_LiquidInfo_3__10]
BO_ 2337468057 M2P_LiquidInfo_3__09: 8 MBMU
 SG_ M2P_TMS_R_ACDC_A_vol_09 : 0|8@1+ (1,0) [0|255] "V"  PC
 SG_ M2P_TMS_R_15_pwm_09 : 8|8@1+ (1,0) [0|255] ""  PC
 SG_ M2P_TMS_R_15_HP_09 : 16|16@1+ (1,0) [0|65535] "kpa"  PC
 SG_ M2P_TMS_R_15_LP_09 : 32|16@1+ (1,0) [0|65535] "kpa"  PC
 SG_ M2P_TMS_R_25_HP_09 : 48|16@1+ (1,0) [0|65535] "kpa"  PC

BO_ 2337468058 M2P_LiquidInfo_3__10: 8 MBMU
 SG_ M2P_TMS_R_ACDC_A_vol_10 : 0|8@1+ (1,0) [0|255] "V"  PC
 SG_ M2P_TMS_R_15_pwm_10 : 8|8@1+ (1,0) [0|255] ""  PC
 SG_ M2P_TMS_R_15_HP_10 : 16|16@1+ (1,0) [0|65535] "kpa"  PC
 SG_ M2P_TMS_R_15_LP_10 : 32|16@1+ (1,0) [0|65535] "kpa"  PC
 SG_ M2P_TMS_R_25_HP_10 : 48|16@1+ (1,0) [0|65535] "kpa"  PC

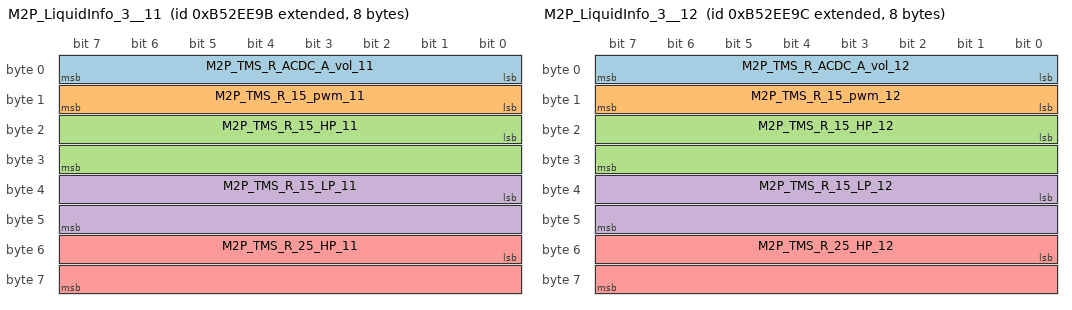
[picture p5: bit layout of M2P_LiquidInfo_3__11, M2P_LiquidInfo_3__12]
BO_ 2337468059 M2P_LiquidInfo_3__11: 8 MBMU
 SG_ M2P_TMS_R_ACDC_A_vol_11 : 0|8@1+ (1,0) [0|255] "V"  PC
 SG_ M2P_TMS_R_15_pwm_11 : 8|8@1+ (1,0) [0|255] ""  PC
 SG_ M2P_TMS_R_15_HP_11 : 16|16@1+ (1,0) [0|65535] "kpa"  PC
 SG_ M2P_TMS_R_15_LP_11 : 32|16@1+ (1,0) [0|65535] "kpa"  PC
 SG_ M2P_TMS_R_25_HP_11 : 48|16@1+ (1,0) [0|65535] "kpa"  PC

BO_ 2337468060 M2P_LiquidInfo_3__12: 8 MBMU
 SG_ M2P_TMS_R_ACDC_A_vol_12 : 0|8@1+ (1,0) [0|255] "V"  PC
 SG_ M2P_TMS_R_15_pwm_12 : 8|8@1+ (1,0) [0|255] ""  PC
 SG_ M2P_TMS_R_15_HP_12 : 16|16@1+ (1,0) [0|65535] "kpa"  PC
 SG_ M2P_TMS_R_15_LP_12 : 32|16@1+ (1,0) [0|65535] "kpa"  PC
 SG_ M2P_TMS_R_25_HP_12 : 48|16@1+ (1,0) [0|65535] "kpa"  PC

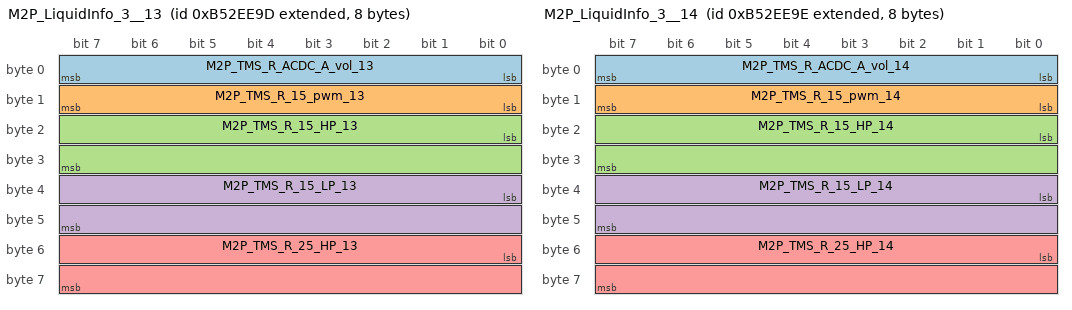
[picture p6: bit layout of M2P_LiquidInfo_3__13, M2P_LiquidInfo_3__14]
BO_ 2337468061 M2P_LiquidInfo_3__13: 8 MBMU
 SG_ M2P_TMS_R_ACDC_A_vol_13 : 0|8@1+ (1,0) [0|255] "V"  PC
 SG_ M2P_TMS_R_15_pwm_13 : 8|8@1+ (1,0) [0|255] ""  PC
 SG_ M2P_TMS_R_15_HP_13 : 16|16@1+ (1,0) [0|65535] "kpa"  PC
 SG_ M2P_TMS_R_15_LP_13 : 32|16@1+ (1,0) [0|65535] "kpa"  PC
 SG_ M2P_TMS_R_25_HP_13 : 48|16@1+ (1,0) [0|65535] "kpa"  PC

BO_ 2337468062 M2P_LiquidInfo_3__14: 8 MBMU
 SG_ M2P_TMS_R_ACDC_A_vol_14 : 0|8@1+ (1,0) [0|255] "V"  PC
 SG_ M2P_TMS_R_15_pwm_14 : 8|8@1+ (1,0) [0|255] ""  PC
 SG_ M2P_TMS_R_15_HP_14 : 16|16@1+ (1,0) [0|65535] "kpa"  PC
 SG_ M2P_TMS_R_15_LP_14 : 32|16@1+ (1,0) [0|65535] "kpa"  PC
 SG_ M2P_TMS_R_25_HP_14 : 48|16@1+ (1,0) [0|65535] "kpa"  PC

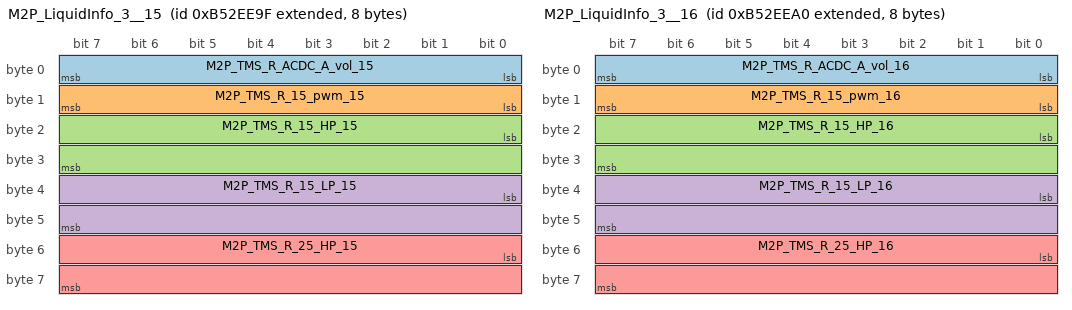
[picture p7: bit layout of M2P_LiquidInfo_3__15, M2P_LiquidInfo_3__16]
BO_ 2337468063 M2P_LiquidInfo_3__15: 8 MBMU
 SG_ M2P_TMS_R_ACDC_A_vol_15 : 0|8@1+ (1,0) [0|255] "V"  PC
 SG_ M2P_TMS_R_15_pwm_15 : 8|8@1+ (1,0) [0|255] ""  PC
 SG_ M2P_TMS_R_15_HP_15 : 16|16@1+ (1,0) [0|65535] "kpa"  PC
 SG_ M2P_TMS_R_15_LP_15 : 32|16@1+ (1,0) [0|65535] "kpa"  PC
 SG_ M2P_TMS_R_25_HP_15 : 48|16@1+ (1,0) [0|65535] "kpa"  PC

BO_ 2337468064 M2P_LiquidInfo_3__16: 8 MBMU
 SG_ M2P_TMS_R_ACDC_A_vol_16 : 0|8@1+ (1,0) [0|255] "V"  PC
 SG_ M2P_TMS_R_15_pwm_16 : 8|8@1+ (1,0) [0|255] ""  PC
 SG_ M2P_TMS_R_15_HP_16 : 16|16@1+ (1,0) [0|65535] "kpa"  PC
 SG_ M2P_TMS_R_15_LP_16 : 32|16@1+ (1,0) [0|65535] "kpa"  PC
 SG_ M2P_TMS_R_25_HP_16 : 48|16@1+ (1,0) [0|65535] "kpa"  PC

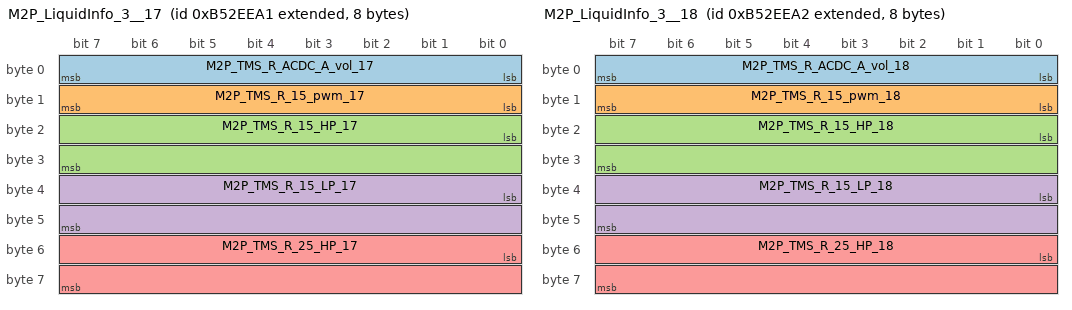
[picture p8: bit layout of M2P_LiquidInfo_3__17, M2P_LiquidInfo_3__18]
BO_ 2337468065 M2P_LiquidInfo_3__17: 8 MBMU
 SG_ M2P_TMS_R_ACDC_A_vol_17 : 0|8@1+ (1,0) [0|255] "V"  PC
 SG_ M2P_TMS_R_15_pwm_17 : 8|8@1+ (1,0) [0|255] ""  PC
 SG_ M2P_TMS_R_15_HP_17 : 16|16@1+ (1,0) [0|65535] "kpa"  PC
 SG_ M2P_TMS_R_15_LP_17 : 32|16@1+ (1,0) [0|65535] "kpa"  PC
 SG_ M2P_TMS_R_25_HP_17 : 48|16@1+ (1,0) [0|65535] "kpa"  PC

BO_ 2337468066 M2P_LiquidInfo_3__18: 8 MBMU
 SG_ M2P_TMS_R_ACDC_A_vol_18 : 0|8@1+ (1,0) [0|255] "V"  PC
 SG_ M2P_TMS_R_15_pwm_18 : 8|8@1+ (1,0) [0|255] ""  PC
 SG_ M2P_TMS_R_15_HP_18 : 16|16@1+ (1,0) [0|65535] "kpa"  PC
 SG_ M2P_TMS_R_15_LP_18 : 32|16@1+ (1,0) [0|65535] "kpa"  PC
 SG_ M2P_TMS_R_25_HP_18 : 48|16@1+ (1,0) [0|65535] "kpa"  PC

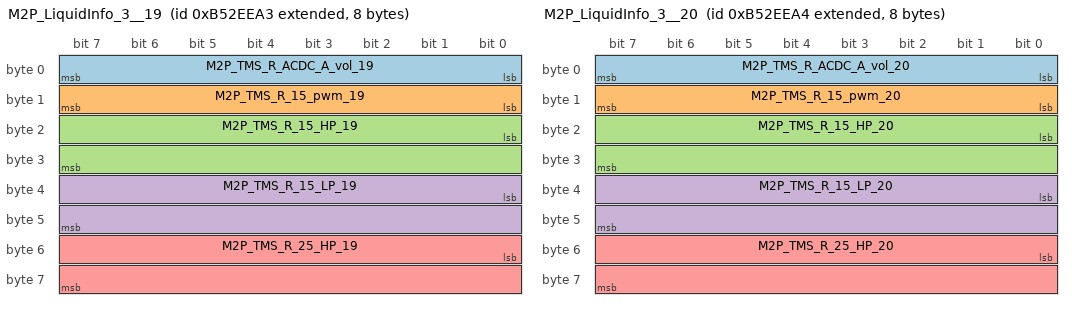
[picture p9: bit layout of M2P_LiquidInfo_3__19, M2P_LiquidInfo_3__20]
BO_ 2337468067 M2P_LiquidInfo_3__19: 8 MBMU
 SG_ M2P_TMS_R_ACDC_A_vol_19 : 0|8@1+ (1,0) [0|255] "V"  PC
 SG_ M2P_TMS_R_15_pwm_19 : 8|8@1+ (1,0) [0|255] ""  PC
 SG_ M2P_TMS_R_15_HP_19 : 16|16@1+ (1,0) [0|65535] "kpa"  PC
 SG_ M2P_TMS_R_15_LP_19 : 32|16@1+ (1,0) [0|65535] "kpa"  PC
 SG_ M2P_TMS_R_25_HP_19 : 48|16@1+ (1,0) [0|65535] "kpa"  PC

BO_ 2337468068 M2P_LiquidInfo_3__20: 8 MBMU
 SG_ M2P_TMS_R_ACDC_A_vol_20 : 0|8@1+ (1,0) [0|255] "V"  PC
 SG_ M2P_TMS_R_15_pwm_20 : 8|8@1+ (1,0) [0|255] ""  PC
 SG_ M2P_TMS_R_15_HP_20 : 16|16@1+ (1,0) [0|65535] "kpa"  PC
 SG_ M2P_TMS_R_15_LP_20 : 32|16@1+ (1,0) [0|65535] "kpa"  PC
 SG_ M2P_TMS_R_25_HP_20 : 48|16@1+ (1,0) [0|65535] "kpa"  PC

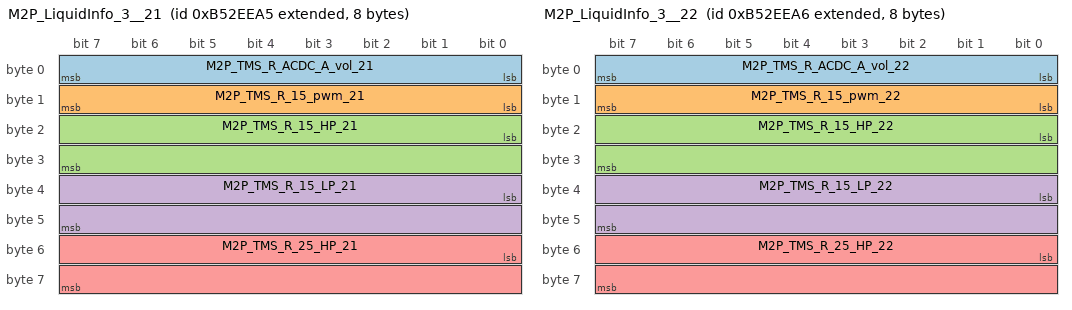
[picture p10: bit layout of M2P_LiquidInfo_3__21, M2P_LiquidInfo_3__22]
BO_ 2337468069 M2P_LiquidInfo_3__21: 8 MBMU
 SG_ M2P_TMS_R_ACDC_A_vol_21 : 0|8@1+ (1,0) [0|255] "V"  PC
 SG_ M2P_TMS_R_15_pwm_21 : 8|8@1+ (1,0) [0|255] ""  PC
 SG_ M2P_TMS_R_15_HP_21 : 16|16@1+ (1,0) [0|65535] "kpa"  PC
 SG_ M2P_TMS_R_15_LP_21 : 32|16@1+ (1,0) [0|65535] "kpa"  PC
 SG_ M2P_TMS_R_25_HP_21 : 48|16@1+ (1,0) [0|65535] "kpa"  PC

BO_ 2337468070 M2P_LiquidInfo_3__22: 8 MBMU
 SG_ M2P_TMS_R_ACDC_A_vol_22 : 0|8@1+ (1,0) [0|255] "V"  PC
 SG_ M2P_TMS_R_15_pwm_22 : 8|8@1+ (1,0) [0|255] ""  PC
 SG_ M2P_TMS_R_15_HP_22 : 16|16@1+ (1,0) [0|65535] "kpa"  PC
 SG_ M2P_TMS_R_15_LP_22 : 32|16@1+ (1,0) [0|65535] "kpa"  PC
 SG_ M2P_TMS_R_25_HP_22 : 48|16@1+ (1,0) [0|65535] "kpa"  PC

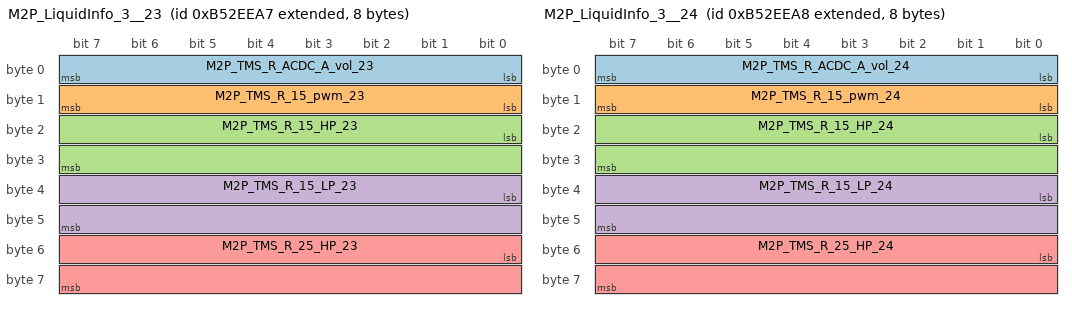
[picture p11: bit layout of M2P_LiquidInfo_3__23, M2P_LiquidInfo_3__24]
BO_ 2337468071 M2P_LiquidInfo_3__23: 8 MBMU
 SG_ M2P_TMS_R_ACDC_A_vol_23 : 0|8@1+ (1,0) [0|255] "V"  PC
 SG_ M2P_TMS_R_15_pwm_23 : 8|8@1+ (1,0) [0|255] ""  PC
 SG_ M2P_TMS_R_15_HP_23 : 16|16@1+ (1,0) [0|65535] "kpa"  PC
 SG_ M2P_TMS_R_15_LP_23 : 32|16@1+ (1,0) [0|65535] "kpa"  PC
 SG_ M2P_TMS_R_25_HP_23 : 48|16@1+ (1,0) [0|65535] "kpa"  PC

BO_ 2337468072 M2P_LiquidInfo_3__24: 8 MBMU
 SG_ M2P_TMS_R_ACDC_A_vol_24 : 0|8@1+ (1,0) [0|255] "V"  PC
 SG_ M2P_TMS_R_15_pwm_24 : 8|8@1+ (1,0) [0|255] ""  PC
 SG_ M2P_TMS_R_15_HP_24 : 16|16@1+ (1,0) [0|65535] "kpa"  PC
 SG_ M2P_TMS_R_15_LP_24 : 32|16@1+ (1,0) [0|65535] "kpa"  PC
 SG_ M2P_TMS_R_25_HP_24 : 48|16@1+ (1,0) [0|65535] "kpa"  PC

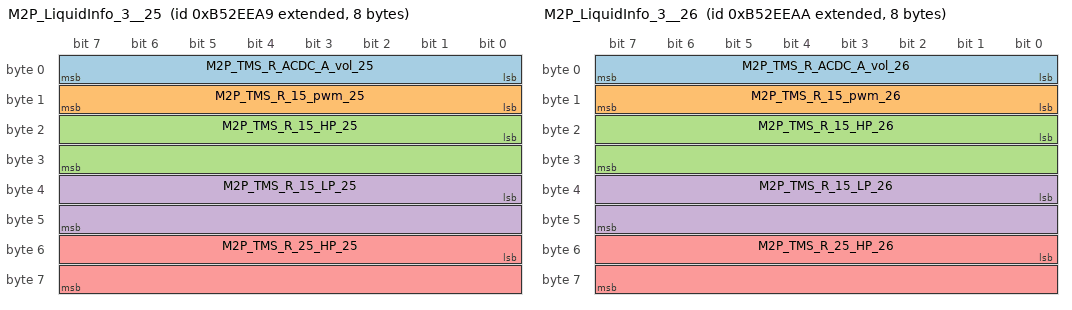
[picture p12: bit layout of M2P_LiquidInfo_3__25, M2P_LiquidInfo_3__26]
BO_ 2337468073 M2P_LiquidInfo_3__25: 8 MBMU
 SG_ M2P_TMS_R_ACDC_A_vol_25 : 0|8@1+ (1,0) [0|255] "V"  PC
 SG_ M2P_TMS_R_15_pwm_25 : 8|8@1+ (1,0) [0|255] ""  PC
 SG_ M2P_TMS_R_15_HP_25 : 16|16@1+ (1,0) [0|65535] "kpa"  PC
 SG_ M2P_TMS_R_15_LP_25 : 32|16@1+ (1,0) [0|65535] "kpa"  PC
 SG_ M2P_TMS_R_25_HP_25 : 48|16@1+ (1,0) [0|65535] "kpa"  PC

BO_ 2337468074 M2P_LiquidInfo_3__26: 8 MBMU
 SG_ M2P_TMS_R_ACDC_A_vol_26 : 0|8@1+ (1,0) [0|255] "V"  PC
 SG_ M2P_TMS_R_15_pwm_26 : 8|8@1+ (1,0) [0|255] ""  PC
 SG_ M2P_TMS_R_15_HP_26 : 16|16@1+ (1,0) [0|65535] "kpa"  PC
 SG_ M2P_TMS_R_15_LP_26 : 32|16@1+ (1,0) [0|65535] "kpa"  PC
 SG_ M2P_TMS_R_25_HP_26 : 48|16@1+ (1,0) [0|65535] "kpa"  PC

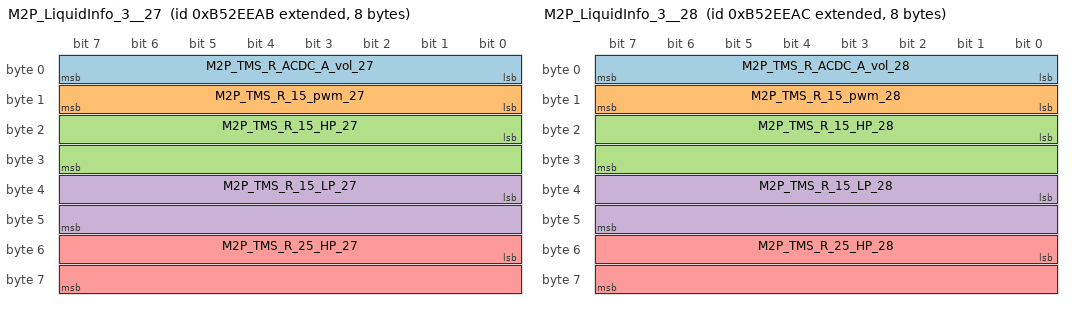
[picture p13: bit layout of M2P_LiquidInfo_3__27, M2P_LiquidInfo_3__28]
BO_ 2337468075 M2P_LiquidInfo_3__27: 8 MBMU
 SG_ M2P_TMS_R_ACDC_A_vol_27 : 0|8@1+ (1,0) [0|255] "V"  PC
 SG_ M2P_TMS_R_15_pwm_27 : 8|8@1+ (1,0) [0|255] ""  PC
 SG_ M2P_TMS_R_15_HP_27 : 16|16@1+ (1,0) [0|65535] "kpa"  PC
 SG_ M2P_TMS_R_15_LP_27 : 32|16@1+ (1,0) [0|65535] "kpa"  PC
 SG_ M2P_TMS_R_25_HP_27 : 48|16@1+ (1,0) [0|65535] "kpa"  PC

BO_ 2337468076 M2P_LiquidInfo_3__28: 8 MBMU
 SG_ M2P_TMS_R_ACDC_A_vol_28 : 0|8@1+ (1,0) [0|255] "V"  PC
 SG_ M2P_TMS_R_15_pwm_28 : 8|8@1+ (1,0) [0|255] ""  PC
 SG_ M2P_TMS_R_15_HP_28 : 16|16@1+ (1,0) [0|65535] "kpa"  PC
 SG_ M2P_TMS_R_15_LP_28 : 32|16@1+ (1,0) [0|65535] "kpa"  PC
 SG_ M2P_TMS_R_25_HP_28 : 48|16@1+ (1,0) [0|65535] "kpa"  PC

CM_ SG_ 2417946189 S2P_Bal_CSCNum_104s_13 "CSC号";
CM_ SG_ 2417946189 S2P_Bal_CellNum_104s_13 "CELL号";
CM_ SG_ 2417946189 S2P_Bal_Type_104s_13 "均衡类型";
CM_ SG_ 2417946189 S2P_Bal_TimeRemain_104s_13 "故障清除指令";
CM_ SG_ 2417946189 S2P_Bal_DeltaVolt_104s_13 "均衡电芯压差";
CM_ SG_ 2417946189 S2P_Bal_TypeLevel_104s_13 "均衡等级";
CM_ SG_ 2417946189 S2P_Bal_Strategy_104s_13 "均衡策略";
CM_ SG_ 2417946189 S2P_Bal_ForceBalMode_104s_13 "强制均衡模式";
CM_ SG_ 2417946189 S2P_Bal_CellTempFault_104s_13 "温度单点无效";
CM_ SG_ 2417946189 S2P_Bal_CellVoltFail_104s_13 "电芯电压采样失效";
CM_ SG_ 2417946189 S2P_Bal_CloseBalIstr_104s_13 "其他模块关闭均衡指令";
CM_ SG_ 2417946189 S2P_Bal_CCanTimeOut_104s_13 "CCAN通讯超时故障";
CM_ SG_ 2417946189 S2P_Bal_CellOffLine_104s_13 "预留";
CM_ SG_ 2417946189 S2P_Bal_BalanCirFlt_104s_13 "均衡回路故障";
CM_ SG_ 2417946189 S2P_Bal_CellVoOverFlt104s_13 "预留";
CM_ SG_ 2417946189 S2P_Bal_CellVoLowFlt104s_13 "预留";
CM_ SG_ 2417946189 S2P_Bal_CSCPCBTeFlt104s_13 "预留";
CM_ SG_ 2417946190 S2P_Bal_CSCNum_104s_14 "CSC号";
CM_ SG_ 2417946190 S2P_Bal_CellNum_104s_14 "CELL号";
CM_ SG_ 2417946190 S2P_Bal_Type_104s_14 "均衡类型";
CM_ SG_ 2417946190 S2P_Bal_TimeRemain_104s_14 "故障清除指令";
CM_ SG_ 2417946190 S2P_Bal_DeltaVolt_104s_14 "均衡电芯压差";
CM_ SG_ 2417946190 S2P_Bal_TypeLevel_104s_14 "均衡等级";
CM_ SG_ 2417946190 S2P_Bal_Strategy_104s_14 "均衡策略";
CM_ SG_ 2417946190 S2P_Bal_ForceBalMode_104s_14 "强制均衡模式";
CM_ SG_ 2417946190 S2P_Bal_CellTempFault_104s_14 "温度单点无效";
CM_ SG_ 2417946190 S2P_Bal_CellVoltFail_104s_14 "电芯电压采样失效";
CM_ SG_ 2417946190 S2P_Bal_CloseBalIstr_104s_14 "其他模块关闭均衡指令";
CM_ SG_ 2417946190 S2P_Bal_CCanTimeOut_104s_14 "CCAN通讯超时故障";
CM_ SG_ 2417946190 S2P_Bal_CellOffLine_104s_14 "预留";
CM_ SG_ 2417946190 S2P_Bal_BalanCirFlt_104s_14 "均衡回路故障";
CM_ SG_ 2417946190 S2P_Bal_CellVoOverFlt104s_14 "预留";
CM_ SG_ 2417946190 S2P_Bal_CellVoLowFlt104s_14 "预留";
CM_ SG_ 2417946190 S2P_Bal_CSCPCBTeFlt104s_14 "预留";
CM_ SG_ 2417946191 S2P_Bal_CSCNum_104s_15 "CSC号";
CM_ SG_ 2417946191 S2P_Bal_CellNum_104s_15 "CELL号";
CM_ SG_ 2417946191 S2P_Bal_Type_104s_15 "均衡类型";
CM_ SG_ 2417946191 S2P_Bal_TimeRemain_104s_15 "故障清除指令";
CM_ SG_ 2417946191 S2P_Bal_DeltaVolt_104s_15 "均衡电芯压差";
CM_ SG_ 2417946191 S2P_Bal_TypeLevel_104s_15 "均衡等级";
CM_ SG_ 2417946191 S2P_Bal_Strategy_104s_15 "均衡策略";
CM_ SG_ 2417946191 S2P_Bal_ForceBalMode_104s_15 "强制均衡模式";
CM_ SG_ 2417946191 S2P_Bal_CellTempFault_104s_15 "温度单点无效";
CM_ SG_ 2417946191 S2P_Bal_CellVoltFail_104s_15 "电芯电压采样失效";
CM_ SG_ 2417946191 S2P_Bal_CloseBalIstr_104s_15 "其他模块关闭均衡指令";
CM_ SG_ 2417946191 S2P_Bal_CCanTimeOut_104s_15 "CCAN通讯超时故障";
CM_ SG_ 2417946191 S2P_Bal_CellOffLine_104s_15 "预留";
CM_ SG_ 2417946191 S2P_Bal_BalanCirFlt_104s_15 "均衡回路故障";
CM_ SG_ 2417946191 S2P_Bal_CellVoOverFlt104s_15 "预留";
CM_ SG_ 2417946191 S2P_Bal_CellVoLowFlt104s_15 "预留";
CM_ SG_ 2417946191 S2P_Bal_CSCPCBTeFlt104s_15 "预留";
CM_ SG_ 2417946192 S2P_Bal_CSCNum_104s_16 "CSC号";
CM_ SG_ 2417946192 S2P_Bal_CellNum_104s_16 "CELL号";
CM_ SG_ 2417946192 S2P_Bal_Type_104s_16 "均衡类型";
CM_ SG_ 2417946192 S2P_Bal_TimeRemain_104s_16 "故障清除指令";
CM_ SG_ 2417946192 S2P_Bal_DeltaVolt_104s_16 "均衡电芯压差";
CM_ SG_ 2417946192 S2P_Bal_TypeLevel_104s_16 "均衡等级";
CM_ SG_ 2417946192 S2P_Bal_Strategy_104s_16 "均衡策略";
CM_ SG_ 2417946192 S2P_Bal_ForceBalMode_104s_16 "强制均衡模式";
CM_ SG_ 2417946192 S2P_Bal_CellTempFault_104s_16 "温度单点无效";
CM_ SG_ 2417946192 S2P_Bal_CellVoltFail_104s_16 "电芯电压采样失效";
CM_ SG_ 2417946192 S2P_Bal_CloseBalIstr_104s_16 "其他模块关闭均衡指令";
CM_ SG_ 2417946192 S2P_Bal_CCanTimeOut_104s_16 "CCAN通讯超时故障";
CM_ SG_ 2417946192 S2P_Bal_CellOffLine_104s_16 "预留";
CM_ SG_ 2417946192 S2P_Bal_BalanCirFlt_104s_16 "均衡回路故障";
CM_ SG_ 2417946192 S2P_Bal_CellVoOverFlt104s_16 "预留";
CM_ SG_ 2417946192 S2P_Bal_CellVoLowFlt104s_16 "预留";
CM_ SG_ 2417946192 S2P_Bal_CSCPCBTeFlt104s_16 "预留";
CM_ SG_ 2417946193 S2P_Bal_CSCNum_104s_17 "CSC号";
CM_ SG_ 2417946193 S2P_Bal_CellNum_104s_17 "CELL号";
CM_ SG_ 2417946193 S2P_Bal_Type_104s_17 "均衡类型";
CM_ SG_ 2417946193 S2P_Bal_TimeRemain_104s_17 "故障清除指令";
CM_ SG_ 2417946193 S2P_Bal_DeltaVolt_104s_17 "均衡电芯压差";
CM_ SG_ 2417946193 S2P_Bal_TypeLevel_104s_17 "均衡等级";
CM_ SG_ 2417946193 S2P_Bal_Strategy_104s_17 "均衡策略";
CM_ SG_ 2417946193 S2P_Bal_ForceBalMode_104s_17 "强制均衡模式";
CM_ SG_ 2417946193 S2P_Bal_CellTempFault_104s_17 "温度单点无效";
CM_ SG_ 2417946193 S2P_Bal_CellVoltFail_104s_17 "电芯电压采样失效";
CM_ SG_ 2417946193 S2P_Bal_CloseBalIstr_104s_17 "其他模块关闭均衡指令";
CM_ SG_ 2417946193 S2P_Bal_CCanTimeOut_104s_17 "CCAN通讯超时故障";
CM_ SG_ 2417946193 S2P_Bal_CellOffLine_104s_17 "预留";
CM_ SG_ 2417946193 S2P_Bal_BalanCirFlt_104s_17 "均衡回路故障";
CM_ SG_ 2417946193 S2P_Bal_CellVoOverFlt104s_17 "预留";
CM_ SG_ 2417946193 S2P_Bal_CellVoLowFlt104s_17 "预留";
CM_ SG_ 2417946193 S2P_Bal_CSCPCBTeFlt104s_17 "预留";
CM_ SG_ 2417946194 S2P_Bal_CSCNum_104s_18 "CSC号";
CM_ SG_ 2417946194 S2P_Bal_CellNum_104s_18 "CELL号";
CM_ SG_ 2417946194 S2P_Bal_Type_104s_18 "均衡类型";
CM_ SG_ 2417946194 S2P_Bal_TimeRemain_104s_18 "故障清除指令";
CM_ SG_ 2417946194 S2P_Bal_DeltaVolt_104s_18 "均衡电芯压差";
CM_ SG_ 2417946194 S2P_Bal_TypeLevel_104s_18 "均衡等级";
CM_ SG_ 2417946194 S2P_Bal_Strategy_104s_18 "均衡策略";
CM_ SG_ 2417946194 S2P_Bal_ForceBalMode_104s_18 "强制均衡模式";
CM_ SG_ 2417946194 S2P_Bal_CellTempFault_104s_18 "温度单点无效";
CM_ SG_ 2417946194 S2P_Bal_CellVoltFail_104s_18 "电芯电压采样失效";
CM_ SG_ 2417946194 S2P_Bal_CloseBalIstr_104s_18 "其他模块关闭均衡指令";
CM_ SG_ 2417946194 S2P_Bal_CCanTimeOut_104s_18 "CCAN通讯超时故障";
CM_ SG_ 2417946194 S2P_Bal_CellOffLine_104s_18 "预留";
CM_ SG_ 2417946194 S2P_Bal_BalanCirFlt_104s_18 "均衡回路故障";
CM_ SG_ 2417946194 S2P_Bal_CellVoOverFlt104s_18 "预留";
CM_ SG_ 2417946194 S2P_Bal_CellVoLowFlt104s_18 "预留";
CM_ SG_ 2417946194 S2P_Bal_CSCPCBTeFlt104s_18 "预留";
CM_ SG_ 2417946195 S2P_Bal_CSCNum_104s_19 "CSC号";
CM_ SG_ 2417946195 S2P_Bal_CellNum_104s_19 "CELL号";
CM_ SG_ 2417946195 S2P_Bal_Type_104s_19 "均衡类型";
CM_ SG_ 2417946195 S2P_Bal_TimeRemain_104s_19 "故障清除指令";
CM_ SG_ 2417946195 S2P_Bal_DeltaVolt_104s_19 "均衡电芯压差";
CM_ SG_ 2417946195 S2P_Bal_TypeLevel_104s_19 "均衡等级";
CM_ SG_ 2417946195 S2P_Bal_Strategy_104s_19 "均衡策略";
CM_ SG_ 2417946195 S2P_Bal_ForceBalMode_104s_19 "强制均衡模式";
CM_ SG_ 2417946195 S2P_Bal_CellTempFault_104s_19 "温度单点无效";
CM_ SG_ 2417946195 S2P_Bal_CellVoltFail_104s_19 "电芯电压采样失效";
CM_ SG_ 2417946195 S2P_Bal_CloseBalIstr_104s_19 "其他模块关闭均衡指令";
CM_ SG_ 2417946195 S2P_Bal_CCanTimeOut_104s_19 "CCAN通讯超时故障";
CM_ SG_ 2417946195 S2P_Bal_CellOffLine_104s_19 "预留";
CM_ SG_ 2417946195 S2P_Bal_BalanCirFlt_104s_19 "均衡回路故障";
CM_ SG_ 2417946195 S2P_Bal_CellVoOverFlt104s_19 "预留";
CM_ SG_ 2417946195 S2P_Bal_CellVoLowFlt104s_19 "预留";
CM_ SG_ 2417946195 S2P_Bal_CSCPCBTeFlt104s_19 "预留";
CM_ SG_ 2417946196 S2P_Bal_CSCNum_104s_20 "CSC号";
CM_ SG_ 2417946196 S2P_Bal_CellNum_104s_20 "CELL号";
CM_ SG_ 2417946196 S2P_Bal_Type_104s_20 "均衡类型";
CM_ SG_ 2417946196 S2P_Bal_TimeRemain_104s_20 "故障清除指令";
CM_ SG_ 2417946196 S2P_Bal_DeltaVolt_104s_20 "均衡电芯压差";
CM_ SG_ 2417946196 S2P_Bal_TypeLevel_104s_20 "均衡等级";
CM_ SG_ 2417946196 S2P_Bal_Strategy_104s_20 "均衡策略";
CM_ SG_ 2417946196 S2P_Bal_ForceBalMode_104s_20 "强制均衡模式";
CM_ SG_ 2417946196 S2P_Bal_CellTempFault_104s_20 "温度单点无效";
CM_ SG_ 2417946196 S2P_Bal_CellVoltFail_104s_20 "电芯电压采样失效";
CM_ SG_ 2417946196 S2P_Bal_CloseBalIstr_104s_20 "其他模块关闭均衡指令";
CM_ SG_ 2417946196 S2P_Bal_CCanTimeOut_104s_20 "CCAN通讯超时故障";
CM_ SG_ 2417946196 S2P_Bal_CellOffLine_104s_20 "预留";
CM_ SG_ 2417946196 S2P_Bal_BalanCirFlt_104s_20 "均衡回路故障";
CM_ SG_ 2417946196 S2P_Bal_CellVoOverFlt104s_20 "预留";
CM_ SG_ 2417946196 S2P_Bal_CellVoLowFlt104s_20 "预留";
CM_ SG_ 2417946196 S2P_Bal_CSCPCBTeFlt104s_20 "预留";
CM_ SG_ 2417946197 S2P_Bal_CSCNum_104s_21 "CSC号";
CM_ SG_ 2417946197 S2P_Bal_CellNum_104s_21 "CELL号";
CM_ SG_ 2417946197 S2P_Bal_Type_104s_21 "均衡类型";
CM_ SG_ 2417946197 S2P_Bal_TimeRemain_104s_21 "故障清除指令";
CM_ SG_ 2417946197 S2P_Bal_DeltaVolt_104s_21 "均衡电芯压差";
CM_ SG_ 2417946197 S2P_Bal_TypeLevel_104s_21 "均衡等级";
CM_ SG_ 2417946197 S2P_Bal_Strategy_104s_21 "均衡策略";
CM_ SG_ 2417946197 S2P_Bal_ForceBalMode_104s_21 "强制均衡模式";
CM_ SG_ 2417946197 S2P_Bal_CellTempFault_104s_21 "温度单点无效";
CM_ SG_ 2417946197 S2P_Bal_CellVoltFail_104s_21 "电芯电压采样失效";
CM_ SG_ 2417946197 S2P_Bal_CloseBalIstr_104s_21 "其他模块关闭均衡指令";
CM_ SG_ 2417946197 S2P_Bal_CCanTimeOut_104s_21 "CCAN通讯超时故障";
CM_ SG_ 2417946197 S2P_Bal_CellOffLine_104s_21 "预留";
CM_ SG_ 2417946197 S2P_Bal_BalanCirFlt_104s_21 "均衡回路故障";
CM_ SG_ 2417946197 S2P_Bal_CellVoOverFlt104s_21 "预留";
CM_ SG_ 2417946197 S2P_Bal_CellVoLowFlt104s_21 "预留";
CM_ SG_ 2417946197 S2P_Bal_CSCPCBTeFlt104s_21 "预留";
CM_ SG_ 2417946198 S2P_Bal_CSCNum_104s_22 "CSC号";
CM_ SG_ 2417946198 S2P_Bal_CellNum_104s_22 "CELL号";
CM_ SG_ 2417946198 S2P_Bal_Type_104s_22 "均衡类型";
CM_ SG_ 2417946198 S2P_Bal_TimeRemain_104s_22 "故障清除指令";
CM_ SG_ 2417946198 S2P_Bal_DeltaVolt_104s_22 "均衡电芯压差";
CM_ SG_ 2417946198 S2P_Bal_TypeLevel_104s_22 "均衡等级";
CM_ SG_ 2417946198 S2P_Bal_Strategy_104s_22 "均衡策略";
CM_ SG_ 2417946198 S2P_Bal_ForceBalMode_104s_22 "强制均衡模式";
CM_ SG_ 2417946198 S2P_Bal_CellTempFault_104s_22 "温度单点无效";
CM_ SG_ 2417946198 S2P_Bal_CellVoltFail_104s_22 "电芯电压采样失效";
CM_ SG_ 2417946198 S2P_Bal_CloseBalIstr_104s_22 "其他模块关闭均衡指令";
CM_ SG_ 2417946198 S2P_Bal_CCanTimeOut_104s_22 "CCAN通讯超时故障";
CM_ SG_ 2417946198 S2P_Bal_CellOffLine_104s_22 "预留";
CM_ SG_ 2417946198 S2P_Bal_BalanCirFlt_104s_22 "均衡回路故障";
CM_ SG_ 2417946198 S2P_Bal_CellVoOverFlt104s_22 "预留";
CM_ SG_ 2417946198 S2P_Bal_CellVoLowFlt104s_22 "预留";
CM_ SG_ 2417946198 S2P_Bal_CSCPCBTeFlt104s_22 "预留";
CM_ SG_ 2417946199 S2P_Bal_CSCNum_104s_23 "CSC号";
CM_ SG_ 2417946199 S2P_Bal_CellNum_104s_23 "CELL号";
CM_ SG_ 2417946199 S2P_Bal_Type_104s_23 "均衡类型";
CM_ SG_ 2417946199 S2P_Bal_TimeRemain_104s_23 "故障清除指令";
CM_ SG_ 2417946199 S2P_Bal_DeltaVolt_104s_23 "均衡电芯压差";
CM_ SG_ 2417946199 S2P_Bal_TypeLevel_104s_23 "均衡等级";
CM_ SG_ 2417946199 S2P_Bal_Strategy_104s_23 "均衡策略";
CM_ SG_ 2417946199 S2P_Bal_ForceBalMode_104s_23 "强制均衡模式";
CM_ SG_ 2417946199 S2P_Bal_CellTempFault_104s_23 "温度单点无效";
CM_ SG_ 2417946199 S2P_Bal_CellVoltFail_104s_23 "电芯电压采样失效";
CM_ SG_ 2417946199 S2P_Bal_CloseBalIstr_104s_23 "其他模块关闭均衡指令";
CM_ SG_ 2417946199 S2P_Bal_CCanTimeOut_104s_23 "CCAN通讯超时故障";
CM_ SG_ 2417946199 S2P_Bal_CellOffLine_104s_23 "预留";
CM_ SG_ 2417946199 S2P_Bal_BalanCirFlt_104s_23 "均衡回路故障";
CM_ SG_ 2417946199 S2P_Bal_CellVoOverFlt104s_23 "预留";
CM_ SG_ 2417946199 S2P_Bal_CellVoLowFlt104s_23 "预留";
CM_ SG_ 2417946199 S2P_Bal_CSCPCBTeFlt104s_23 "预留";
CM_ SG_ 2417946200 S2P_Bal_CSCNum_104s_24 "CSC号";
CM_ SG_ 2417946200 S2P_Bal_CellNum_104s_24 "CELL号";
CM_ SG_ 2417946200 S2P_Bal_Type_104s_24 "均衡类型";
CM_ SG_ 2417946200 S2P_Bal_TimeRemain_104s_24 "故障清除指令";
CM_ SG_ 2417946200 S2P_Bal_DeltaVolt_104s_24 "均衡电芯压差";
CM_ SG_ 2417946200 S2P_Bal_TypeLevel_104s_24 "均衡等级";
CM_ SG_ 2417946200 S2P_Bal_Strategy_104s_24 "均衡策略";
CM_ SG_ 2417946200 S2P_Bal_ForceBalMode_104s_24 "强制均衡模式";
CM_ SG_ 2417946200 S2P_Bal_CellTempFault_104s_24 "温度单点无效";
CM_ SG_ 2417946200 S2P_Bal_CellVoltFail_104s_24 "电芯电压采样失效";
CM_ SG_ 2417946200 S2P_Bal_CloseBalIstr_104s_24 "其他模块关闭均衡指令";
CM_ SG_ 2417946200 S2P_Bal_CCanTimeOut_104s_24 "CCAN通讯超时故障";
CM_ SG_ 2417946200 S2P_Bal_CellOffLine_104s_24 "预留";
CM_ SG_ 2417946200 S2P_Bal_BalanCirFlt_104s_24 "均衡回路故障";
CM_ SG_ 2417946200 S2P_Bal_CellVoOverFlt104s_24 "预留";
CM_ SG_ 2417946200 S2P_Bal_CellVoLowFlt104s_24 "预留";
CM_ SG_ 2417946200 S2P_Bal_CSCPCBTeFlt104s_24 "预留";
CM_ SG_ 2417946201 S2P_Bal_CSCNum_104s_25 "CSC号";
CM_ SG_ 2417946201 S2P_Bal_CellNum_104s_25 "CELL号";
CM_ SG_ 2417946201 S2P_Bal_Type_104s_25 "均衡类型";
CM_ SG_ 2417946201 S2P_Bal_TimeRemain_104s_25 "故障清除指令";
CM_ SG_ 2417946201 S2P_Bal_DeltaVolt_104s_25 "均衡电芯压差";
CM_ SG_ 2417946201 S2P_Bal_TypeLevel_104s_25 "均衡等级";
CM_ SG_ 2417946201 S2P_Bal_Strategy_104s_25 "均衡策略";
CM_ SG_ 2417946201 S2P_Bal_ForceBalMode_104s_25 "强制均衡模式";
CM_ SG_ 2417946201 S2P_Bal_CellTempFault_104s_25 "温度单点无效";
CM_ SG_ 2417946201 S2P_Bal_CellVoltFail_104s_25 "电芯电压采样失效";
CM_ SG_ 2417946201 S2P_Bal_CloseBalIstr_104s_25 "其他模块关闭均衡指令";
CM_ SG_ 2417946201 S2P_Bal_CCanTimeOut_104s_25 "CCAN通讯超时故障";
CM_ SG_ 2417946201 S2P_Bal_CellOffLine_104s_25 "预留";
CM_ SG_ 2417946201 S2P_Bal_BalanCirFlt_104s_25 "均衡回路故障";
CM_ SG_ 2417946201 S2P_Bal_CellVoOverFlt104s_25 "预留";
CM_ SG_ 2417946201 S2P_Bal_CellVoLowFlt104s_25 "预留";
CM_ SG_ 2417946201 S2P_Bal_CSCPCBTeFlt104s_25 "预留";
CM_ SG_ 2417946202 S2P_Bal_CSCNum_104s_26 "CSC号";
CM_ SG_ 2417946202 S2P_Bal_CellNum_104s_26 "CELL号";
CM_ SG_ 2417946202 S2P_Bal_Type_104s_26 "均衡类型";
CM_ SG_ 2417946202 S2P_Bal_TimeRemain_104s_26 "故障清除指令";
CM_ SG_ 2417946202 S2P_Bal_DeltaVolt_104s_26 "均衡电芯压差";
CM_ SG_ 2417946202 S2P_Bal_TypeLevel_104s_26 "均衡等级";
CM_ SG_ 2417946202 S2P_Bal_Strategy_104s_26 "均衡策略";
CM_ SG_ 2417946202 S2P_Bal_ForceBalMode_104s_26 "强制均衡模式";
CM_ SG_ 2417946202 S2P_Bal_CellTempFault_104s_26 "温度单点无效";
CM_ SG_ 2417946202 S2P_Bal_CellVoltFail_104s_26 "电芯电压采样失效";
CM_ SG_ 2417946202 S2P_Bal_CloseBalIstr_104s_26 "其他模块关闭均衡指令";
CM_ SG_ 2417946202 S2P_Bal_CCanTimeOut_104s_26 "CCAN通讯超时故障";
CM_ SG_ 2417946202 S2P_Bal_CellOffLine_104s_26 "预留";
CM_ SG_ 2417946202 S2P_Bal_BalanCirFlt_104s_26 "均衡回路故障";
CM_ SG_ 2417946202 S2P_Bal_CellVoOverFlt104s_26 "预留";
CM_ SG_ 2417946202 S2P_Bal_CellVoLowFlt104s_26 "预留";
CM_ SG_ 2417946202 S2P_Bal_CSCPCBTeFlt104s_26 "预留";
CM_ SG_ 2417946203 S2P_Bal_CSCNum_104s_27 "CSC号";
CM_ SG_ 2417946203 S2P_Bal_CellNum_104s_27 "CELL号";
CM_ SG_ 2417946203 S2P_Bal_Type_104s_27 "均衡类型";
CM_ SG_ 2417946203 S2P_Bal_TimeRemain_104s_27 "故障清除指令";
CM_ SG_ 2417946203 S2P_Bal_DeltaVolt_104s_27 "均衡电芯压差";
CM_ SG_ 2417946203 S2P_Bal_TypeLevel_104s_27 "均衡等级";
CM_ SG_ 2417946203 S2P_Bal_Strategy_104s_27 "均衡策略";
CM_ SG_ 2417946203 S2P_Bal_ForceBalMode_104s_27 "强制均衡模式";
CM_ SG_ 2417946203 S2P_Bal_CellTempFault_104s_27 "温度单点无效";
CM_ SG_ 2417946203 S2P_Bal_CellVoltFail_104s_27 "电芯电压采样失效";
CM_ SG_ 2417946203 S2P_Bal_CloseBalIstr_104s_27 "其他模块关闭均衡指令";
CM_ SG_ 2417946203 S2P_Bal_CCanTimeOut_104s_27 "CCAN通讯超时故障";
CM_ SG_ 2417946203 S2P_Bal_CellOffLine_104s_27 "预留";
CM_ SG_ 2417946203 S2P_Bal_BalanCirFlt_104s_27 "均衡回路故障";
CM_ SG_ 2417946203 S2P_Bal_CellVoOverFlt104s_27 "预留";
CM_ SG_ 2417946203 S2P_Bal_CellVoLowFlt104s_27 "预留";
CM_ SG_ 2417946203 S2P_Bal_CSCPCBTeFlt104s_27 "预留";
CM_ SG_ 2417946204 S2P_Bal_CSCNum_104s_28 "CSC号";
CM_ SG_ 2417946204 S2P_Bal_CellNum_104s_28 "CELL号";
CM_ SG_ 2417946204 S2P_Bal_Type_104s_28 "均衡类型";
CM_ SG_ 2417946204 S2P_Bal_TimeRemain_104s_28 "故障清除指令";
CM_ SG_ 2417946204 S2P_Bal_DeltaVolt_104s_28 "均衡电芯压差";
CM_ SG_ 2417946204 S2P_Bal_TypeLevel_104s_28 "均衡等级";
CM_ SG_ 2417946204 S2P_Bal_Strategy_104s_28 "均衡策略";
CM_ SG_ 2417946204 S2P_Bal_ForceBalMode_104s_28 "强制均衡模式";
CM_ SG_ 2417946204 S2P_Bal_CellTempFault_104s_28 "温度单点无效";
CM_ SG_ 2417946204 S2P_Bal_CellVoltFail_104s_28 "电芯电压采样失效";
CM_ SG_ 2417946204 S2P_Bal_CloseBalIstr_104s_28 "其他模块关闭均衡指令";
CM_ SG_ 2417946204 S2P_Bal_CCanTimeOut_104s_28 "CCAN通讯超时故障";
CM_ SG_ 2417946204 S2P_Bal_CellOffLine_104s_28 "预留";
CM_ SG_ 2417946204 S2P_Bal_BalanCirFlt_104s_28 "均衡回路故障";
CM_ SG_ 2417946204 S2P_Bal_CellVoOverFlt104s_28 "预留";
CM_ SG_ 2417946204 S2P_Bal_CellVoLowFlt104s_28 "预留";
CM_ SG_ 2417946204 S2P_Bal_CSCPCBTeFlt104s_28 "预留";
CM_ SG_ 2417946205 S2P_Bal_CSCNum_104s_29 "CSC号";
CM_ SG_ 2417946205 S2P_Bal_CellNum_104s_29 "CELL号";
CM_ SG_ 2417946205 S2P_Bal_Type_104s_29 "均衡类型";
CM_ SG_ 2417946205 S2P_Bal_TimeRemain_104s_29 "故障清除指令";
CM_ SG_ 2417946205 S2P_Bal_DeltaVolt_104s_29 "均衡电芯压差";
CM_ SG_ 2417946205 S2P_Bal_TypeLevel_104s_29 "均衡等级";
CM_ SG_ 2417946205 S2P_Bal_Strategy_104s_29 "均衡策略";
CM_ SG_ 2417946205 S2P_Bal_ForceBalMode_104s_29 "强制均衡模式";
CM_ SG_ 2417946205 S2P_Bal_CellTempFault_104s_29 "温度单点无效";
CM_ SG_ 2417946205 S2P_Bal_CellVoltFail_104s_29 "电芯电压采样失效";
CM_ SG_ 2417946205 S2P_Bal_CloseBalIstr_104s_29 "其他模块关闭均衡指令";
CM_ SG_ 2417946205 S2P_Bal_CCanTimeOut_104s_29 "CCAN通讯超时故障";
CM_ SG_ 2417946205 S2P_Bal_CellOffLine_104s_29 "预留";
CM_ SG_ 2417946205 S2P_Bal_BalanCirFlt_104s_29 "均衡回路故障";
CM_ SG_ 2417946205 S2P_Bal_CellVoOverFlt104s_29 "预留";
CM_ SG_ 2417946205 S2P_Bal_CellVoLowFlt104s_29 "预留";
CM_ SG_ 2417946205 S2P_Bal_CSCPCBTeFlt104s_29 "预留";
CM_ SG_ 2417946206 S2P_Bal_CSCNum_104s_30 "CSC号";
CM_ SG_ 2417946206 S2P_Bal_CellNum_104s_30 "CELL号";
CM_ SG_ 2417946206 S2P_Bal_Type_104s_30 "均衡类型";
CM_ SG_ 2417946206 S2P_Bal_TimeRemain_104s_30 "故障清除指令";
CM_ SG_ 2417946206 S2P_Bal_DeltaVolt_104s_30 "均衡电芯压差";
CM_ SG_ 2417946206 S2P_Bal_TypeLevel_104s_30 "均衡等级";
CM_ SG_ 2417946206 S2P_Bal_Strategy_104s_30 "均衡策略";
CM_ SG_ 2417946206 S2P_Bal_ForceBalMode_104s_30 "强制均衡模式";
CM_ SG_ 2417946206 S2P_Bal_CellTempFault_104s_30 "温度单点无效";
CM_ SG_ 2417946206 S2P_Bal_CellVoltFail_104s_30 "电芯电压采样失效";
CM_ SG_ 2417946206 S2P_Bal_CloseBalIstr_104s_30 "其他模块关闭均衡指令";
CM_ SG_ 2417946206 S2P_Bal_CCanTimeOut_104s_30 "CCAN通讯超时故障";
CM_ SG_ 2417946206 S2P_Bal_CellOffLine_104s_30 "预留";
CM_ SG_ 2417946206 S2P_Bal_BalanCirFlt_104s_30 "均衡回路故障";
CM_ SG_ 2417946206 S2P_Bal_CellVoOverFlt104s_30 "预留";
CM_ SG_ 2417946206 S2P_Bal_CellVoLowFlt104s_30 "预留";
CM_ SG_ 2417946206 S2P_Bal_CSCPCBTeFlt104s_30 "预留";
CM_ SG_ 2417946207 S2P_Bal_CSCNum_104s_31 "CSC号";
CM_ SG_ 2417946207 S2P_Bal_CellNum_104s_31 "CELL号";
CM_ SG_ 2417946207 S2P_Bal_Type_104s_31 "均衡类型";
CM_ SG_ 2417946207 S2P_Bal_TimeRemain_104s_31 "故障清除指令";
CM_ SG_ 2417946207 S2P_Bal_DeltaVolt_104s_31 "均衡电芯压差";
CM_ SG_ 2417946207 S2P_Bal_TypeLevel_104s_31 "均衡等级";
CM_ SG_ 2417946207 S2P_Bal_Strategy_104s_31 "均衡策略";
CM_ SG_ 2417946207 S2P_Bal_ForceBalMode_104s_31 "强制均衡模式";
CM_ SG_ 2417946207 S2P_Bal_CellTempFault_104s_31 "温度单点无效";
CM_ SG_ 2417946207 S2P_Bal_CellVoltFail_104s_31 "电芯电压采样失效";
CM_ SG_ 2417946207 S2P_Bal_CloseBalIstr_104s_31 "其他模块关闭均衡指令";
CM_ SG_ 2417946207 S2P_Bal_CCanTimeOut_104s_31 "CCAN通讯超时故障";
CM_ SG_ 2417946207 S2P_Bal_CellOffLine_104s_31 "预留";
CM_ SG_ 2417946207 S2P_Bal_BalanCirFlt_104s_31 "均衡回路故障";
CM_ SG_ 2417946207 S2P_Bal_CellVoOverFlt104s_31 "预留";
CM_ SG_ 2417946207 S2P_Bal_CellVoLowFlt104s_31 "预留";
CM_ SG_ 2417946207 S2P_Bal_CSCPCBTeFlt104s_31 "预留";
CM_ SG_ 2417946208 S2P_Bal_CSCNum_104s_32 "CSC号";
CM_ SG_ 2417946208 S2P_Bal_CellNum_104s_32 "CELL号";
CM_ SG_ 2417946208 S2P_Bal_Type_104s_32 "均衡类型";
CM_ SG_ 2417946208 S2P_Bal_TimeRemain_104s_32 "故障清除指令";
CM_ SG_ 2417946208 S2P_Bal_DeltaVolt_104s_32 "均衡电芯压差";
CM_ SG_ 2417946208 S2P_Bal_TypeLevel_104s_32 "均衡等级";
CM_ SG_ 2417946208 S2P_Bal_Strategy_104s_32 "均衡策略";
CM_ SG_ 2417946208 S2P_Bal_ForceBalMode_104s_32 "强制均衡模式";
CM_ SG_ 2417946208 S2P_Bal_CellTempFault_104s_32 "温度单点无效";
CM_ SG_ 2417946208 S2P_Bal_CellVoltFail_104s_32 "电芯电压采样失效";
CM_ SG_ 2417946208 S2P_Bal_CloseBalIstr_104s_32 "其他模块关闭均衡指令";
CM_ SG_ 2417946208 S2P_Bal_CCanTimeOut_104s_32 "CCAN通讯超时故障";
CM_ SG_ 2417946208 S2P_Bal_CellOffLine_104s_32 "预留";
CM_ SG_ 2417946208 S2P_Bal_BalanCirFlt_104s_32 "均衡回路故障";
CM_ SG_ 2417946208 S2P_Bal_CellVoOverFlt104s_32 "预留";
CM_ SG_ 2417946208 S2P_Bal_CellVoLowFlt104s_32 "预留";
CM_ SG_ 2417946208 S2P_Bal_CSCPCBTeFlt104s_32 "预留";
CM_ SG_ 2417946209 S2P_Bal_CSCNum_104s_33 "CSC号";
CM_ SG_ 2417946209 S2P_Bal_CellNum_104s_33 "CELL号";
CM_ SG_ 2417946209 S2P_Bal_Type_104s_33 "均衡类型";
CM_ SG_ 2417946209 S2P_Bal_TimeRemain_104s_33 "故障清除指令";
CM_ SG_ 2417946209 S2P_Bal_DeltaVolt_104s_33 "均衡电芯压差";
CM_ SG_ 2417946209 S2P_Bal_TypeLevel_104s_33 "均衡等级";
CM_ SG_ 2417946209 S2P_Bal_Strategy_104s_33 "均衡策略";
CM_ SG_ 2417946209 S2P_Bal_ForceBalMode_104s_33 "强制均衡模式";
CM_ SG_ 2417946209 S2P_Bal_CellTempFault_104s_33 "温度单点无效";
CM_ SG_ 2417946209 S2P_Bal_CellVoltFail_104s_33 "电芯电压采样失效";
CM_ SG_ 2417946209 S2P_Bal_CloseBalIstr_104s_33 "其他模块关闭均衡指令";
CM_ SG_ 2417946209 S2P_Bal_CCanTimeOut_104s_33 "CCAN通讯超时故障";
CM_ SG_ 2417946209 S2P_Bal_CellOffLine_104s_33 "预留";
CM_ SG_ 2417946209 S2P_Bal_BalanCirFlt_104s_33 "均衡回路故障";
CM_ SG_ 2417946209 S2P_Bal_CellVoOverFlt104s_33 "预留";
CM_ SG_ 2417946209 S2P_Bal_CellVoLowFlt104s_33 "预留";
CM_ SG_ 2417946209 S2P_Bal_CSCPCBTeFlt104s_33 "预留";
CM_ SG_ 2417946210 S2P_Bal_CSCNum_104s_34 "CSC号";
CM_ SG_ 2417946210 S2P_Bal_CellNum_104s_34 "CELL号";
CM_ SG_ 2417946210 S2P_Bal_Type_104s_34 "均衡类型";
CM_ SG_ 2417946210 S2P_Bal_TimeRemain_104s_34 "故障清除指令";
CM_ SG_ 2417946210 S2P_Bal_DeltaVolt_104s_34 "均衡电芯压差";
CM_ SG_ 2417946210 S2P_Bal_TypeLevel_104s_34 "均衡等级";
CM_ SG_ 2417946210 S2P_Bal_Strategy_104s_34 "均衡策略";
CM_ SG_ 2417946210 S2P_Bal_ForceBalMode_104s_34 "强制均衡模式";
CM_ SG_ 2417946210 S2P_Bal_CellTempFault_104s_34 "温度单点无效";
CM_ SG_ 2417946210 S2P_Bal_CellVoltFail_104s_34 "电芯电压采样失效";
CM_ SG_ 2417946210 S2P_Bal_CloseBalIstr_104s_34 "其他模块关闭均衡指令";
CM_ SG_ 2417946210 S2P_Bal_CCanTimeOut_104s_34 "CCAN通讯超时故障";
CM_ SG_ 2417946210 S2P_Bal_CellOffLine_104s_34 "预留";
CM_ SG_ 2417946210 S2P_Bal_BalanCirFlt_104s_34 "均衡回路故障";
CM_ SG_ 2417946210 S2P_Bal_CellVoOverFlt104s_34 "预留";
CM_ SG_ 2417946210 S2P_Bal_CellVoLowFlt104s_34 "预留";
CM_ SG_ 2417946210 S2P_Bal_CSCPCBTeFlt104s_34 "预留";
CM_ SG_ 2417946211 S2P_Bal_CSCNum_104s_35 "CSC号";
CM_ SG_ 2417946211 S2P_Bal_CellNum_104s_35 "CELL号";
CM_ SG_ 2417946211 S2P_Bal_Type_104s_35 "均衡类型";
CM_ SG_ 2417946211 S2P_Bal_TimeRemain_104s_35 "故障清除指令";
CM_ SG_ 2417946211 S2P_Bal_DeltaVolt_104s_35 "均衡电芯压差";
CM_ SG_ 2417946211 S2P_Bal_TypeLevel_104s_35 "均衡等级";
CM_ SG_ 2417946211 S2P_Bal_Strategy_104s_35 "均衡策略";
CM_ SG_ 2417946211 S2P_Bal_ForceBalMode_104s_35 "强制均衡模式";
CM_ SG_ 2417946211 S2P_Bal_CellTempFault_104s_35 "温度单点无效";
CM_ SG_ 2417946211 S2P_Bal_CellVoltFail_104s_35 "电芯电压采样失效";
CM_ SG_ 2417946211 S2P_Bal_CloseBalIstr_104s_35 "其他模块关闭均衡指令";
CM_ SG_ 2417946211 S2P_Bal_CCanTimeOut_104s_35 "CCAN通讯超时故障";
CM_ SG_ 2417946211 S2P_Bal_CellOffLine_104s_35 "预留";
CM_ SG_ 2417946211 S2P_Bal_BalanCirFlt_104s_35 "均衡回路故障";
CM_ SG_ 2417946211 S2P_Bal_CellVoOverFlt104s_35 "预留";
CM_ SG_ 2417946211 S2P_Bal_CellVoLowFlt104s_35 "预留";
CM_ SG_ 2417946211 S2P_Bal_CSCPCBTeFlt104s_35 "预留";
CM_ SG_ 2417946212 S2P_Bal_CSCNum_104s_36 "CSC号";
CM_ SG_ 2417946212 S2P_Bal_CellNum_104s_36 "CELL号";
CM_ SG_ 2417946212 S2P_Bal_Type_104s_36 "均衡类型";
CM_ SG_ 2417946212 S2P_Bal_TimeRemain_104s_36 "故障清除指令";
CM_ SG_ 2417946212 S2P_Bal_DeltaVolt_104s_36 "均衡电芯压差";
CM_ SG_ 2417946212 S2P_Bal_TypeLevel_104s_36 "均衡等级";
CM_ SG_ 2417946212 S2P_Bal_Strategy_104s_36 "均衡策略";
CM_ SG_ 2417946212 S2P_Bal_ForceBalMode_104s_36 "强制均衡模式";
CM_ SG_ 2417946212 S2P_Bal_CellTempFault_104s_36 "温度单点无效";
CM_ SG_ 2417946212 S2P_Bal_CellVoltFail_104s_36 "电芯电压采样失效";
CM_ SG_ 2417946212 S2P_Bal_CloseBalIstr_104s_36 "其他模块关闭均衡指令";
CM_ SG_ 2417946212 S2P_Bal_CCanTimeOut_104s_36 "CCAN通讯超时故障";
CM_ SG_ 2417946212 S2P_Bal_CellOffLine_104s_36 "预留";
CM_ SG_ 2417946212 S2P_Bal_BalanCirFlt_104s_36 "均衡回路故障";
CM_ SG_ 2417946212 S2P_Bal_CellVoOverFlt104s_36 "预留";
CM_ SG_ 2417946212 S2P_Bal_CellVoLowFlt104s_36 "预留";
CM_ SG_ 2417946212 S2P_Bal_CSCPCBTeFlt104s_36 "预留";
CM_ SG_ 2417946213 S2P_Bal_CSCNum_104s_37 "CSC号";
CM_ SG_ 2417946213 S2P_Bal_CellNum_104s_37 "CELL号";
CM_ SG_ 2417946213 S2P_Bal_Type_104s_37 "均衡类型";
CM_ SG_ 2417946213 S2P_Bal_TimeRemain_104s_37 "故障清除指令";
CM_ SG_ 2417946213 S2P_Bal_DeltaVolt_104s_37 "均衡电芯压差";
CM_ SG_ 2417946213 S2P_Bal_TypeLevel_104s_37 "均衡等级";
CM_ SG_ 2417946213 S2P_Bal_Strategy_104s_37 "均衡策略";
CM_ SG_ 2417946213 S2P_Bal_ForceBalMode_104s_37 "强制均衡模式";
CM_ SG_ 2417946213 S2P_Bal_CellTempFault_104s_37 "温度单点无效";
CM_ SG_ 2417946213 S2P_Bal_CellVoltFail_104s_37 "电芯电压采样失效";
CM_ SG_ 2417946213 S2P_Bal_CloseBalIstr_104s_37 "其他模块关闭均衡指令";
CM_ SG_ 2417946213 S2P_Bal_CCanTimeOut_104s_37 "CCAN通讯超时故障";
CM_ SG_ 2417946213 S2P_Bal_CellOffLine_104s_37 "预留";
CM_ SG_ 2417946213 S2P_Bal_BalanCirFlt_104s_37 "均衡回路故障";
CM_ SG_ 2417946213 S2P_Bal_CellVoOverFlt104s_37 "预留";
CM_ SG_ 2417946213 S2P_Bal_CellVoLowFlt104s_37 "预留";
CM_ SG_ 2417946213 S2P_Bal_CSCPCBTeFlt104s_37 "预留";
CM_ SG_ 2417946214 S2P_Bal_CSCNum_104s_38 "CSC号";
CM_ SG_ 2417946214 S2P_Bal_CellNum_104s_38 "CELL号";
CM_ SG_ 2417946214 S2P_Bal_Type_104s_38 "均衡类型";
CM_ SG_ 2417946214 S2P_Bal_TimeRemain_104s_38 "故障清除指令";
CM_ SG_ 2417946214 S2P_Bal_DeltaVolt_104s_38 "均衡电芯压差";
CM_ SG_ 2417946214 S2P_Bal_TypeLevel_104s_38 "均衡等级";
CM_ SG_ 2417946214 S2P_Bal_Strategy_104s_38 "均衡策略";
CM_ SG_ 2417946214 S2P_Bal_ForceBalMode_104s_38 "强制均衡模式";
CM_ SG_ 2417946214 S2P_Bal_CellTempFault_104s_38 "温度单点无效";
CM_ SG_ 2417946214 S2P_Bal_CellVoltFail_104s_38 "电芯电压采样失效";
CM_ SG_ 2417946214 S2P_Bal_CloseBalIstr_104s_38 "其他模块关闭均衡指令";
CM_ SG_ 2417946214 S2P_Bal_CCanTimeOut_104s_38 "CCAN通讯超时故障";
CM_ SG_ 2417946214 S2P_Bal_CellOffLine_104s_38 "预留";
CM_ SG_ 2417946214 S2P_Bal_BalanCirFlt_104s_38 "均衡回路故障";
CM_ SG_ 2417946214 S2P_Bal_CellVoOverFlt104s_38 "预留";
CM_ SG_ 2417946214 S2P_Bal_CellVoLowFlt104s_38 "预留";
CM_ SG_ 2417946214 S2P_Bal_CSCPCBTeFlt104s_38 "预留";
CM_ SG_ 2417946215 S2P_Bal_CSCNum_104s_39 "CSC号";
CM_ SG_ 2417946215 S2P_Bal_CellNum_104s_39 "CELL号";
CM_ SG_ 2417946215 S2P_Bal_Type_104s_39 "均衡类型";
CM_ SG_ 2417946215 S2P_Bal_TimeRemain_104s_39 "故障清除指令";
CM_ SG_ 2417946215 S2P_Bal_DeltaVolt_104s_39 "均衡电芯压差";
CM_ SG_ 2417946215 S2P_Bal_TypeLevel_104s_39 "均衡等级";
CM_ SG_ 2417946215 S2P_Bal_Strategy_104s_39 "均衡策略";
CM_ SG_ 2417946215 S2P_Bal_ForceBalMode_104s_39 "强制均衡模式";
CM_ SG_ 2417946215 S2P_Bal_CellTempFault_104s_39 "温度单点无效";
CM_ SG_ 2417946215 S2P_Bal_CellVoltFail_104s_39 "电芯电压采样失效";
CM_ SG_ 2417946215 S2P_Bal_CloseBalIstr_104s_39 "其他模块关闭均衡指令";
CM_ SG_ 2417946215 S2P_Bal_CCanTimeOut_104s_39 "CCAN通讯超时故障";
CM_ SG_ 2417946215 S2P_Bal_CellOffLine_104s_39 "预留";
CM_ SG_ 2417946215 S2P_Bal_BalanCirFlt_104s_39 "均衡回路故障";
CM_ SG_ 2417946215 S2P_Bal_CellVoOverFlt104s_39 "预留";
CM_ SG_ 2417946215 S2P_Bal_CellVoLowFlt104s_39 "预留";
CM_ SG_ 2417946215 S2P_Bal_CSCPCBTeFlt104s_39 "预留";
CM_ SG_ 2417946216 S2P_Bal_CSCNum_104s_40 "CSC号";
CM_ SG_ 2417946216 S2P_Bal_CellNum_104s_40 "CELL号";
CM_ SG_ 2417946216 S2P_Bal_Type_104s_40 "均衡类型";
CM_ SG_ 2417946216 S2P_Bal_TimeRemain_104s_40 "故障清除指令";
CM_ SG_ 2417946216 S2P_Bal_DeltaVolt_104s_40 "均衡电芯压差";
CM_ SG_ 2417946216 S2P_Bal_TypeLevel_104s_40 "均衡等级";
CM_ SG_ 2417946216 S2P_Bal_Strategy_104s_40 "均衡策略";
CM_ SG_ 2417946216 S2P_Bal_ForceBalMode_104s_40 "强制均衡模式";
CM_ SG_ 2417946216 S2P_Bal_CellTempFault_104s_40 "温度单点无效";
CM_ SG_ 2417946216 S2P_Bal_CellVoltFail_104s_40 "电芯电压采样失效";
CM_ SG_ 2417946216 S2P_Bal_CloseBalIstr_104s_40 "其他模块关闭均衡指令";
CM_ SG_ 2417946216 S2P_Bal_CCanTimeOut_104s_40 "CCAN通讯超时故障";
CM_ SG_ 2417946216 S2P_Bal_CellOffLine_104s_40 "预留";
CM_ SG_ 2417946216 S2P_Bal_BalanCirFlt_104s_40 "均衡回路故障";
CM_ SG_ 2417946216 S2P_Bal_CellVoOverFlt104s_40 "预留";
CM_ SG_ 2417946216 S2P_Bal_CellVoLowFlt104s_40 "预留";
CM_ SG_ 2417946216 S2P_Bal_CSCPCBTeFlt104s_40 "预留";
CM_ SG_ 2417946217 S2P_Bal_CSCNum_104s_41 "CSC号";
CM_ SG_ 2417946217 S2P_Bal_CellNum_104s_41 "CELL号";
CM_ SG_ 2417946217 S2P_Bal_Type_104s_41 "均衡类型";
CM_ SG_ 2417946217 S2P_Bal_TimeRemain_104s_41 "故障清除指令";
CM_ SG_ 2417946217 S2P_Bal_DeltaVolt_104s_41 "均衡电芯压差";
CM_ SG_ 2417946217 S2P_Bal_TypeLevel_104s_41 "均衡等级";
CM_ SG_ 2417946217 S2P_Bal_Strategy_104s_41 "均衡策略";
CM_ SG_ 2417946217 S2P_Bal_ForceBalMode_104s_41 "强制均衡模式";
CM_ SG_ 2417946217 S2P_Bal_CellTempFault_104s_41 "温度单点无效";
CM_ SG_ 2417946217 S2P_Bal_CellVoltFail_104s_41 "电芯电压采样失效";
CM_ SG_ 2417946217 S2P_Bal_CloseBalIstr_104s_41 "其他模块关闭均衡指令";
CM_ SG_ 2417946217 S2P_Bal_CCanTimeOut_104s_41 "CCAN通讯超时故障";
CM_ SG_ 2417946217 S2P_Bal_CellOffLine_104s_41 "预留";
CM_ SG_ 2417946217 S2P_Bal_BalanCirFlt_104s_41 "均衡回路故障";
CM_ SG_ 2417946217 S2P_Bal_CellVoOverFlt104s_41 "预留";
CM_ SG_ 2417946217 S2P_Bal_CellVoLowFlt104s_41 "预留";
CM_ SG_ 2417946217 S2P_Bal_CSCPCBTeFlt104s_41 "预留";
CM_ SG_ 2417946218 S2P_Bal_CSCNum_104s_42 "CSC号";
CM_ SG_ 2417946218 S2P_Bal_CellNum_104s_42 "CELL号";
CM_ SG_ 2417946218 S2P_Bal_Type_104s_42 "均衡类型";
CM_ SG_ 2417946218 S2P_Bal_TimeRemain_104s_42 "故障清除指令";
CM_ SG_ 2417946218 S2P_Bal_DeltaVolt_104s_42 "均衡电芯压差";
CM_ SG_ 2417946218 S2P_Bal_TypeLevel_104s_42 "均衡等级";
CM_ SG_ 2417946218 S2P_Bal_Strategy_104s_42 "均衡策略";
CM_ SG_ 2417946218 S2P_Bal_ForceBalMode_104s_42 "强制均衡模式";
CM_ SG_ 2417946218 S2P_Bal_CellTempFault_104s_42 "温度单点无效";
CM_ SG_ 2417946218 S2P_Bal_CellVoltFail_104s_42 "电芯电压采样失效";
CM_ SG_ 2417946218 S2P_Bal_CloseBalIstr_104s_42 "其他模块关闭均衡指令";
CM_ SG_ 2417946218 S2P_Bal_CCanTimeOut_104s_42 "CCAN通讯超时故障";
CM_ SG_ 2417946218 S2P_Bal_CellOffLine_104s_42 "预留";
CM_ SG_ 2417946218 S2P_Bal_BalanCirFlt_104s_42 "均衡回路故障";
CM_ SG_ 2417946218 S2P_Bal_CellVoOverFlt104s_42 "预留";
CM_ SG_ 2417946218 S2P_Bal_CellVoLowFlt104s_42 "预留";
CM_ SG_ 2417946218 S2P_Bal_CSCPCBTeFlt104s_42 "预留";
CM_ SG_ 2417946219 S2P_Bal_CSCNum_104s_43 "CSC号";
CM_ SG_ 2417946219 S2P_Bal_CellNum_104s_43 "CELL号";
CM_ SG_ 2417946219 S2P_Bal_Type_104s_43 "均衡类型";
CM_ SG_ 2417946219 S2P_Bal_TimeRemain_104s_43 "故障清除指令";
CM_ SG_ 2417946219 S2P_Bal_DeltaVolt_104s_43 "均衡电芯压差";
CM_ SG_ 2417946219 S2P_Bal_TypeLevel_104s_43 "均衡等级";
CM_ SG_ 2417946219 S2P_Bal_Strategy_104s_43 "均衡策略";
CM_ SG_ 2417946219 S2P_Bal_ForceBalMode_104s_43 "强制均衡模式";
CM_ SG_ 2417946219 S2P_Bal_CellTempFault_104s_43 "温度单点无效";
CM_ SG_ 2417946219 S2P_Bal_CellVoltFail_104s_43 "电芯电压采样失效";
CM_ SG_ 2417946219 S2P_Bal_CloseBalIstr_104s_43 "其他模块关闭均衡指令";
CM_ SG_ 2417946219 S2P_Bal_CCanTimeOut_104s_43 "CCAN通讯超时故障";
CM_ SG_ 2417946219 S2P_Bal_CellOffLine_104s_43 "预留";
CM_ SG_ 2417946219 S2P_Bal_BalanCirFlt_104s_43 "均衡回路故障";
CM_ SG_ 2417946219 S2P_Bal_CellVoOverFlt104s_43 "预留";
CM_ SG_ 2417946219 S2P_Bal_CellVoLowFlt104s_43 "预留";
CM_ SG_ 2417946219 S2P_Bal_CSCPCBTeFlt104s_43 "预留";
CM_ SG_ 2417946220 S2P_Bal_CSCNum_104s_44 "CSC号";
CM_ SG_ 2417946220 S2P_Bal_CellNum_104s_44 "CELL号";
CM_ SG_ 2417946220 S2P_Bal_Type_104s_44 "均衡类型";
CM_ SG_ 2417946220 S2P_Bal_TimeRemain_104s_44 "故障清除指令";
CM_ SG_ 2417946220 S2P_Bal_DeltaVolt_104s_44 "均衡电芯压差";
CM_ SG_ 2417946220 S2P_Bal_TypeLevel_104s_44 "均衡等级";
CM_ SG_ 2417946220 S2P_Bal_Strategy_104s_44 "均衡策略";
CM_ SG_ 2417946220 S2P_Bal_ForceBalMode_104s_44 "强制均衡模式";
CM_ SG_ 2417946220 S2P_Bal_CellTempFault_104s_44 "温度单点无效";
CM_ SG_ 2417946220 S2P_Bal_CellVoltFail_104s_44 "电芯电压采样失效";
CM_ SG_ 2417946220 S2P_Bal_CloseBalIstr_104s_44 "其他模块关闭均衡指令";
CM_ SG_ 2417946220 S2P_Bal_CCanTimeOut_104s_44 "CCAN通讯超时故障";
CM_ SG_ 2417946220 S2P_Bal_CellOffLine_104s_44 "预留";
CM_ SG_ 2417946220 S2P_Bal_BalanCirFlt_104s_44 "均衡回路故障";
CM_ SG_ 2417946220 S2P_Bal_CellVoOverFlt104s_44 "预留";
CM_ SG_ 2417946220 S2P_Bal_CellVoLowFlt104s_44 "预留";
CM_ SG_ 2417946220 S2P_Bal_CSCPCBTeFlt104s_44 "预留";
CM_ SG_ 2417946221 S2P_Bal_CSCNum_104s_45 "CSC号";
CM_ SG_ 2417946221 S2P_Bal_CellNum_104s_45 "CELL号";
CM_ SG_ 2417946221 S2P_Bal_Type_104s_45 "均衡类型";
CM_ SG_ 2417946221 S2P_Bal_TimeRemain_104s_45 "故障清除指令";
CM_ SG_ 2417946221 S2P_Bal_DeltaVolt_104s_45 "均衡电芯压差";
CM_ SG_ 2417946221 S2P_Bal_TypeLevel_104s_45 "均衡等级";
CM_ SG_ 2417946221 S2P_Bal_Strategy_104s_45 "均衡策略";
CM_ SG_ 2417946221 S2P_Bal_ForceBalMode_104s_45 "强制均衡模式";
CM_ SG_ 2417946221 S2P_Bal_CellTempFault_104s_45 "温度单点无效";
CM_ SG_ 2417946221 S2P_Bal_CellVoltFail_104s_45 "电芯电压采样失效";
CM_ SG_ 2417946221 S2P_Bal_CloseBalIstr_104s_45 "其他模块关闭均衡指令";
CM_ SG_ 2417946221 S2P_Bal_CCanTimeOut_104s_45 "CCAN通讯超时故障";
CM_ SG_ 2417946221 S2P_Bal_CellOffLine_104s_45 "预留";
CM_ SG_ 2417946221 S2P_Bal_BalanCirFlt_104s_45 "均衡回路故障";
CM_ SG_ 2417946221 S2P_Bal_CellVoOverFlt104s_45 "预留";
CM_ SG_ 2417946221 S2P_Bal_CellVoLowFlt104s_45 "预留";
CM_ SG_ 2417946221 S2P_Bal_CSCPCBTeFlt104s_45 "预留";
CM_ SG_ 2417946222 S2P_Bal_CSCNum_104s_46 "CSC号";
CM_ SG_ 2417946222 S2P_Bal_CellNum_104s_46 "CELL号";
CM_ SG_ 2417946222 S2P_Bal_Type_104s_46 "均衡类型";
CM_ SG_ 2417946222 S2P_Bal_TimeRemain_104s_46 "故障清除指令";
CM_ SG_ 2417946222 S2P_Bal_DeltaVolt_104s_46 "均衡电芯压差";
CM_ SG_ 2417946222 S2P_Bal_TypeLevel_104s_46 "均衡等级";
CM_ SG_ 2417946222 S2P_Bal_Strategy_104s_46 "均衡策略";
CM_ SG_ 2417946222 S2P_Bal_ForceBalMode_104s_46 "强制均衡模式";
CM_ SG_ 2417946222 S2P_Bal_CellTempFault_104s_46 "温度单点无效";
CM_ SG_ 2417946222 S2P_Bal_CellVoltFail_104s_46 "电芯电压采样失效";
CM_ SG_ 2417946222 S2P_Bal_CloseBalIstr_104s_46 "其他模块关闭均衡指令";
CM_ SG_ 2417946222 S2P_Bal_CCanTimeOut_104s_46 "CCAN通讯超时故障";
CM_ SG_ 2417946222 S2P_Bal_CellOffLine_104s_46 "预留";
CM_ SG_ 2417946222 S2P_Bal_BalanCirFlt_104s_46 "均衡回路故障";
CM_ SG_ 2417946222 S2P_Bal_CellVoOverFlt104s_46 "预留";
CM_ SG_ 2417946222 S2P_Bal_CellVoLowFlt104s_46 "预留";
CM_ SG_ 2417946222 S2P_Bal_CSCPCBTeFlt104s_46 "预留";
CM_ SG_ 2417946223 S2P_Bal_CSCNum_104s_47 "CSC号";
CM_ SG_ 2417946223 S2P_Bal_CellNum_104s_47 "CELL号";
CM_ SG_ 2417946223 S2P_Bal_Type_104s_47 "均衡类型";
CM_ SG_ 2417946223 S2P_Bal_TimeRemain_104s_47 "故障清除指令";
CM_ SG_ 2417946223 S2P_Bal_DeltaVolt_104s_47 "均衡电芯压差";
CM_ SG_ 2417946223 S2P_Bal_TypeLevel_104s_47 "均衡等级";
CM_ SG_ 2417946223 S2P_Bal_Strategy_104s_47 "均衡策略";
CM_ SG_ 2417946223 S2P_Bal_ForceBalMode_104s_47 "强制均衡模式";
CM_ SG_ 2417946223 S2P_Bal_CellTempFault_104s_47 "温度单点无效";
CM_ SG_ 2417946223 S2P_Bal_CellVoltFail_104s_47 "电芯电压采样失效";
CM_ SG_ 2417946223 S2P_Bal_CloseBalIstr_104s_47 "其他模块关闭均衡指令";
CM_ SG_ 2417946223 S2P_Bal_CCanTimeOut_104s_47 "CCAN通讯超时故障";
CM_ SG_ 2417946223 S2P_Bal_CellOffLine_104s_47 "预留";
CM_ SG_ 2417946223 S2P_Bal_BalanCirFlt_104s_47 "均衡回路故障";
CM_ SG_ 2417946223 S2P_Bal_CellVoOverFlt104s_47 "预留";
CM_ SG_ 2417946223 S2P_Bal_CellVoLowFlt104s_47 "预留";
CM_ SG_ 2417946223 S2P_Bal_CSCPCBTeFlt104s_47 "预留";
CM_ SG_ 2417946224 S2P_Bal_CSCNum_104s_48 "CSC号";
CM_ SG_ 2417946224 S2P_Bal_CellNum_104s_48 "CELL号";
CM_ SG_ 2417946224 S2P_Bal_Type_104s_48 "均衡类型";
CM_ SG_ 2417946224 S2P_Bal_TimeRemain_104s_48 "故障清除指令";
CM_ SG_ 2417946224 S2P_Bal_DeltaVolt_104s_48 "均衡电芯压差";
CM_ SG_ 2417946224 S2P_Bal_TypeLevel_104s_48 "均衡等级";
CM_ SG_ 2417946224 S2P_Bal_Strategy_104s_48 "均衡策略";
CM_ SG_ 2417946224 S2P_Bal_ForceBalMode_104s_48 "强制均衡模式";
CM_ SG_ 2417946224 S2P_Bal_CellTempFault_104s_48 "温度单点无效";
CM_ SG_ 2417946224 S2P_Bal_CellVoltFail_104s_48 "电芯电压采样失效";
CM_ SG_ 2417946224 S2P_Bal_CloseBalIstr_104s_48 "其他模块关闭均衡指令";
CM_ SG_ 2417946224 S2P_Bal_CCanTimeOut_104s_48 "CCAN通讯超时故障";
CM_ SG_ 2417946224 S2P_Bal_CellOffLine_104s_48 "预留";
CM_ SG_ 2417946224 S2P_Bal_BalanCirFlt_104s_48 "均衡回路故障";
CM_ SG_ 2417946224 S2P_Bal_CellVoOverFlt104s_48 "预留";
CM_ SG_ 2417946224 S2P_Bal_CellVoLowFlt104s_48 "预留";
CM_ SG_ 2417946224 S2P_Bal_CSCPCBTeFlt104s_48 "预留";
CM_ SG_ 2417946225 S2P_Bal_CSCNum_104s_49 "CSC号";
CM_ SG_ 2417946225 S2P_Bal_CellNum_104s_49 "CELL号";
CM_ SG_ 2417946225 S2P_Bal_Type_104s_49 "均衡类型";
CM_ SG_ 2417946225 S2P_Bal_TimeRemain_104s_49 "故障清除指令";
CM_ SG_ 2417946225 S2P_Bal_DeltaVolt_104s_49 "均衡电芯压差";
CM_ SG_ 2417946225 S2P_Bal_TypeLevel_104s_49 "均衡等级";
CM_ SG_ 2417946225 S2P_Bal_Strategy_104s_49 "均衡策略";
CM_ SG_ 2417946225 S2P_Bal_ForceBalMode_104s_49 "强制均衡模式";
CM_ SG_ 2417946225 S2P_Bal_CellTempFault_104s_49 "温度单点无效";
CM_ SG_ 2417946225 S2P_Bal_CellVoltFail_104s_49 "电芯电压采样失效";
CM_ SG_ 2417946225 S2P_Bal_CloseBalIstr_104s_49 "其他模块关闭均衡指令";
CM_ SG_ 2417946225 S2P_Bal_CCanTimeOut_104s_49 "CCAN通讯超时故障";
CM_ SG_ 2417946225 S2P_Bal_CellOffLine_104s_49 "预留";
CM_ SG_ 2417946225 S2P_Bal_BalanCirFlt_104s_49 "均衡回路故障";
CM_ SG_ 2417946225 S2P_Bal_CellVoOverFlt104s_49 "预留";
CM_ SG_ 2417946225 S2P_Bal_CellVoLowFlt104s_49 "预留";
CM_ SG_ 2417946225 S2P_Bal_CSCPCBTeFlt104s_49 "预留";
CM_ SG_ 2417946226 S2P_Bal_CSCNum_104s_50 "CSC号";
CM_ SG_ 2417946226 S2P_Bal_CellNum_104s_50 "CELL号";
CM_ SG_ 2417946226 S2P_Bal_Type_104s_50 "均衡类型";
CM_ SG_ 2417946226 S2P_Bal_TimeRemain_104s_50 "故障清除指令";
CM_ SG_ 2417946226 S2P_Bal_DeltaVolt_104s_50 "均衡电芯压差";
CM_ SG_ 2417946226 S2P_Bal_TypeLevel_104s_50 "均衡等级";
CM_ SG_ 2417946226 S2P_Bal_Strategy_104s_50 "均衡策略";
CM_ SG_ 2417946226 S2P_Bal_ForceBalMode_104s_50 "强制均衡模式";
CM_ SG_ 2417946226 S2P_Bal_CellTempFault_104s_50 "温度单点无效";
CM_ SG_ 2417946226 S2P_Bal_CellVoltFail_104s_50 "电芯电压采样失效";
CM_ SG_ 2417946226 S2P_Bal_CloseBalIstr_104s_50 "其他模块关闭均衡指令";
CM_ SG_ 2417946226 S2P_Bal_CCanTimeOut_104s_50 "CCAN通讯超时故障";
CM_ SG_ 2417946226 S2P_Bal_CellOffLine_104s_50 "预留";
CM_ SG_ 2417946226 S2P_Bal_BalanCirFlt_104s_50 "均衡回路故障";
CM_ SG_ 2417946226 S2P_Bal_CellVoOverFlt104s_50 "预留";
CM_ SG_ 2417946226 S2P_Bal_CellVoLowFlt104s_50 "预留";
CM_ SG_ 2417946226 S2P_Bal_CSCPCBTeFlt104s_50 "预留";
CM_ SG_ 2417946227 S2P_Bal_CSCNum_104s_51 "CSC号";
CM_ SG_ 2417946227 S2P_Bal_CellNum_104s_51 "CELL号";
CM_ SG_ 2417946227 S2P_Bal_Type_104s_51 "均衡类型";
CM_ SG_ 2417946227 S2P_Bal_TimeRemain_104s_51 "故障清除指令";
CM_ SG_ 2417946227 S2P_Bal_DeltaVolt_104s_51 "均衡电芯压差";
CM_ SG_ 2417946227 S2P_Bal_TypeLevel_104s_51 "均衡等级";
CM_ SG_ 2417946227 S2P_Bal_Strategy_104s_51 "均衡策略";
CM_ SG_ 2417946227 S2P_Bal_ForceBalMode_104s_51 "强制均衡模式";
CM_ SG_ 2417946227 S2P_Bal_CellTempFault_104s_51 "温度单点无效";
CM_ SG_ 2417946227 S2P_Bal_CellVoltFail_104s_51 "电芯电压采样失效";
CM_ SG_ 2417946227 S2P_Bal_CloseBalIstr_104s_51 "其他模块关闭均衡指令";
CM_ SG_ 2417946227 S2P_Bal_CCanTimeOut_104s_51 "CCAN通讯超时故障";
CM_ SG_ 2417946227 S2P_Bal_CellOffLine_104s_51 "预留";
CM_ SG_ 2417946227 S2P_Bal_BalanCirFlt_104s_51 "均衡回路故障";
CM_ SG_ 2417946227 S2P_Bal_CellVoOverFlt104s_51 "预留";
CM_ SG_ 2417946227 S2P_Bal_CellVoLowFlt104s_51 "预留";
CM_ SG_ 2417946227 S2P_Bal_CSCPCBTeFlt104s_51 "预留";
CM_ SG_ 2417946228 S2P_Bal_CSCNum_104s_52 "CSC号";
CM_ SG_ 2417946228 S2P_Bal_CellNum_104s_52 "CELL号";
CM_ SG_ 2417946228 S2P_Bal_Type_104s_52 "均衡类型";
CM_ SG_ 2417946228 S2P_Bal_TimeRemain_104s_52 "故障清除指令";
CM_ SG_ 2417946228 S2P_Bal_DeltaVolt_104s_52 "均衡电芯压差";
CM_ SG_ 2417946228 S2P_Bal_TypeLevel_104s_52 "均衡等级";
CM_ SG_ 2417946228 S2P_Bal_Strategy_104s_52 "均衡策略";
CM_ SG_ 2417946228 S2P_Bal_ForceBalMode_104s_52 "强制均衡模式";
CM_ SG_ 2417946228 S2P_Bal_CellTempFault_104s_52 "温度单点无效";
CM_ SG_ 2417946228 S2P_Bal_CellVoltFail_104s_52 "电芯电压采样失效";
CM_ SG_ 2417946228 S2P_Bal_CloseBalIstr_104s_52 "其他模块关闭均衡指令";
CM_ SG_ 2417946228 S2P_Bal_CCanTimeOut_104s_52 "CCAN通讯超时故障";
CM_ SG_ 2417946228 S2P_Bal_CellOffLine_104s_52 "预留";
CM_ SG_ 2417946228 S2P_Bal_BalanCirFlt_104s_52 "均衡回路故障";
CM_ SG_ 2417946228 S2P_Bal_CellVoOverFlt104s_52 "预留";
CM_ SG_ 2417946228 S2P_Bal_CellVoLowFlt104s_52 "预留";
CM_ SG_ 2417946228 S2P_Bal_CSCPCBTeFlt104s_52 "预留";
CM_ SG_ 2417946229 S2P_Bal_CSCNum_104s_53 "CSC号";
CM_ SG_ 2417946229 S2P_Bal_CellNum_104s_53 "CELL号";
CM_ SG_ 2417946229 S2P_Bal_Type_104s_53 "均衡类型";
CM_ SG_ 2417946229 S2P_Bal_TimeRemain_104s_53 "故障清除指令";
CM_ SG_ 2417946229 S2P_Bal_DeltaVolt_104s_53 "均衡电芯压差";
CM_ SG_ 2417946229 S2P_Bal_TypeLevel_104s_53 "均衡等级";
CM_ SG_ 2417946229 S2P_Bal_Strategy_104s_53 "均衡策略";
CM_ SG_ 2417946229 S2P_Bal_ForceBalMode_104s_53 "强制均衡模式";
CM_ SG_ 2417946229 S2P_Bal_CellTempFault_104s_53 "温度单点无效";
CM_ SG_ 2417946229 S2P_Bal_CellVoltFail_104s_53 "电芯电压采样失效";
CM_ SG_ 2417946229 S2P_Bal_CloseBalIstr_104s_53 "其他模块关闭均衡指令";
CM_ SG_ 2417946229 S2P_Bal_CCanTimeOut_104s_53 "CCAN通讯超时故障";
CM_ SG_ 2417946229 S2P_Bal_CellOffLine_104s_53 "预留";
CM_ SG_ 2417946229 S2P_Bal_BalanCirFlt_104s_53 "均衡回路故障";
CM_ SG_ 2417946229 S2P_Bal_CellVoOverFlt104s_53 "预留";
CM_ SG_ 2417946229 S2P_Bal_CellVoLowFlt104s_53 "预留";
CM_ SG_ 2417946229 S2P_Bal_CSCPCBTeFlt104s_53 "预留";
CM_ SG_ 2417946230 S2P_Bal_CSCNum_104s_54 "CSC号";
CM_ SG_ 2417946230 S2P_Bal_CellNum_104s_54 "CELL号";
CM_ SG_ 2417946230 S2P_Bal_Type_104s_54 "均衡类型";
CM_ SG_ 2417946230 S2P_Bal_TimeRemain_104s_54 "故障清除指令";
CM_ SG_ 2417946230 S2P_Bal_DeltaVolt_104s_54 "均衡电芯压差";
CM_ SG_ 2417946230 S2P_Bal_TypeLevel_104s_54 "均衡等级";
CM_ SG_ 2417946230 S2P_Bal_Strategy_104s_54 "均衡策略";
CM_ SG_ 2417946230 S2P_Bal_ForceBalMode_104s_54 "强制均衡模式";
CM_ SG_ 2417946230 S2P_Bal_CellTempFault_104s_54 "温度单点无效";
CM_ SG_ 2417946230 S2P_Bal_CellVoltFail_104s_54 "电芯电压采样失效";
CM_ SG_ 2417946230 S2P_Bal_CloseBalIstr_104s_54 "其他模块关闭均衡指令";
CM_ SG_ 2417946230 S2P_Bal_CCanTimeOut_104s_54 "CCAN通讯超时故障";
CM_ SG_ 2417946230 S2P_Bal_CellOffLine_104s_54 "预留";
CM_ SG_ 2417946230 S2P_Bal_BalanCirFlt_104s_54 "均衡回路故障";
CM_ SG_ 2417946230 S2P_Bal_CellVoOverFlt104s_54 "预留";
CM_ SG_ 2417946230 S2P_Bal_CellVoLowFlt104s_54 "预留";
CM_ SG_ 2417946230 S2P_Bal_CSCPCBTeFlt104s_54 "预留";
CM_ SG_ 2417946231 S2P_Bal_CSCNum_104s_55 "CSC号";
CM_ SG_ 2417946231 S2P_Bal_CellNum_104s_55 "CELL号";
CM_ SG_ 2417946231 S2P_Bal_Type_104s_55 "均衡类型";
CM_ SG_ 2417946231 S2P_Bal_TimeRemain_104s_55 "故障清除指令";
CM_ SG_ 2417946231 S2P_Bal_DeltaVolt_104s_55 "均衡电芯压差";
CM_ SG_ 2417946231 S2P_Bal_TypeLevel_104s_55 "均衡等级";
CM_ SG_ 2417946231 S2P_Bal_Strategy_104s_55 "均衡策略";
CM_ SG_ 2417946231 S2P_Bal_ForceBalMode_104s_55 "强制均衡模式";
CM_ SG_ 2417946231 S2P_Bal_CellTempFault_104s_55 "温度单点无效";
CM_ SG_ 2417946231 S2P_Bal_CellVoltFail_104s_55 "电芯电压采样失效";
CM_ SG_ 2417946231 S2P_Bal_CloseBalIstr_104s_55 "其他模块关闭均衡指令";
CM_ SG_ 2417946231 S2P_Bal_CCanTimeOut_104s_55 "CCAN通讯超时故障";
CM_ SG_ 2417946231 S2P_Bal_CellOffLine_104s_55 "预留";
CM_ SG_ 2417946231 S2P_Bal_BalanCirFlt_104s_55 "均衡回路故障";
CM_ SG_ 2417946231 S2P_Bal_CellVoOverFlt104s_55 "预留";
CM_ SG_ 2417946231 S2P_Bal_CellVoLowFlt104s_55 "预留";
CM_ SG_ 2417946231 S2P_Bal_CSCPCBTeFlt104s_55 "预留";
CM_ SG_ 2417946232 S2P_Bal_CSCNum_104s_56 "CSC号";
CM_ SG_ 2417946232 S2P_Bal_CellNum_104s_56 "CELL号";
CM_ SG_ 2417946232 S2P_Bal_Type_104s_56 "均衡类型";
CM_ SG_ 2417946232 S2P_Bal_TimeRemain_104s_56 "故障清除指令";
CM_ SG_ 2417946232 S2P_Bal_DeltaVolt_104s_56 "均衡电芯压差";
CM_ SG_ 2417946232 S2P_Bal_TypeLevel_104s_56 "均衡等级";
CM_ SG_ 2417946232 S2P_Bal_Strategy_104s_56 "均衡策略";
CM_ SG_ 2417946232 S2P_Bal_ForceBalMode_104s_56 "强制均衡模式";
CM_ SG_ 2417946232 S2P_Bal_CellTempFault_104s_56 "温度单点无效";
CM_ SG_ 2417946232 S2P_Bal_CellVoltFail_104s_56 "电芯电压采样失效";
CM_ SG_ 2417946232 S2P_Bal_CloseBalIstr_104s_56 "其他模块关闭均衡指令";
CM_ SG_ 2417946232 S2P_Bal_CCanTimeOut_104s_56 "CCAN通讯超时故障";
CM_ SG_ 2417946232 S2P_Bal_CellOffLine_104s_56 "预留";
CM_ SG_ 2417946232 S2P_Bal_BalanCirFlt_104s_56 "均衡回路故障";
CM_ SG_ 2417946232 S2P_Bal_CellVoOverFlt104s_56 "预留";
CM_ SG_ 2417946232 S2P_Bal_CellVoLowFlt104s_56 "预留";
CM_ SG_ 2417946232 S2P_Bal_CSCPCBTeFlt104s_56 "预留";
CM_ SG_ 2417946233 S2P_Bal_CSCNum_104s_57 "CSC号";
CM_ SG_ 2417946233 S2P_Bal_CellNum_104s_57 "CELL号";
CM_ SG_ 2417946233 S2P_Bal_Type_104s_57 "均衡类型";
CM_ SG_ 2417946233 S2P_Bal_TimeRemain_104s_57 "故障清除指令";
CM_ SG_ 2417946233 S2P_Bal_DeltaVolt_104s_57 "均衡电芯压差";
CM_ SG_ 2417946233 S2P_Bal_TypeLevel_104s_57 "均衡等级";
CM_ SG_ 2417946233 S2P_Bal_Strategy_104s_57 "均衡策略";
CM_ SG_ 2417946233 S2P_Bal_ForceBalMode_104s_57 "强制均衡模式";
CM_ SG_ 2417946233 S2P_Bal_CellTempFault_104s_57 "温度单点无效";
CM_ SG_ 2417946233 S2P_Bal_CellVoltFail_104s_57 "电芯电压采样失效";
CM_ SG_ 2417946233 S2P_Bal_CloseBalIstr_104s_57 "其他模块关闭均衡指令";
CM_ SG_ 2417946233 S2P_Bal_CCanTimeOut_104s_57 "CCAN通讯超时故障";
CM_ SG_ 2417946233 S2P_Bal_CellOffLine_104s_57 "预留";
CM_ SG_ 2417946233 S2P_Bal_BalanCirFlt_104s_57 "均衡回路故障";
CM_ SG_ 2417946233 S2P_Bal_CellVoOverFlt104s_57 "预留";
CM_ SG_ 2417946233 S2P_Bal_CellVoLowFlt104s_57 "预留";
CM_ SG_ 2417946233 S2P_Bal_CSCPCBTeFlt104s_57 "预留";
CM_ SG_ 2417946234 S2P_Bal_CSCNum_104s_58 "CSC号";
CM_ SG_ 2417946234 S2P_Bal_CellNum_104s_58 "CELL号";
CM_ SG_ 2417946234 S2P_Bal_Type_104s_58 "均衡类型";
CM_ SG_ 2417946234 S2P_Bal_TimeRemain_104s_58 "故障清除指令";
CM_ SG_ 2417946234 S2P_Bal_DeltaVolt_104s_58 "均衡电芯压差";
CM_ SG_ 2417946234 S2P_Bal_TypeLevel_104s_58 "均衡等级";
CM_ SG_ 2417946234 S2P_Bal_Strategy_104s_58 "均衡策略";
CM_ SG_ 2417946234 S2P_Bal_ForceBalMode_104s_58 "强制均衡模式";
CM_ SG_ 2417946234 S2P_Bal_CellTempFault_104s_58 "温度单点无效";
CM_ SG_ 2417946234 S2P_Bal_CellVoltFail_104s_58 "电芯电压采样失效";
CM_ SG_ 2417946234 S2P_Bal_CloseBalIstr_104s_58 "其他模块关闭均衡指令";
CM_ SG_ 2417946234 S2P_Bal_CCanTimeOut_104s_58 "CCAN通讯超时故障";
CM_ SG_ 2417946234 S2P_Bal_CellOffLine_104s_58 "预留";
CM_ SG_ 2417946234 S2P_Bal_BalanCirFlt_104s_58 "均衡回路故障";
CM_ SG_ 2417946234 S2P_Bal_CellVoOverFlt104s_58 "预留";
CM_ SG_ 2417946234 S2P_Bal_CellVoLowFlt104s_58 "预留";
CM_ SG_ 2417946234 S2P_Bal_CSCPCBTeFlt104s_58 "预留";
CM_ SG_ 2417946235 S2P_Bal_CSCNum_104s_59 "CSC号";
CM_ SG_ 2417946235 S2P_Bal_CellNum_104s_59 "CELL号";
CM_ SG_ 2417946235 S2P_Bal_Type_104s_59 "均衡类型";
CM_ SG_ 2417946235 S2P_Bal_TimeRemain_104s_59 "故障清除指令";
CM_ SG_ 2417946235 S2P_Bal_DeltaVolt_104s_59 "均衡电芯压差";
CM_ SG_ 2417946235 S2P_Bal_TypeLevel_104s_59 "均衡等级";
CM_ SG_ 2417946235 S2P_Bal_Strategy_104s_59 "均衡策略";
CM_ SG_ 2417946235 S2P_Bal_ForceBalMode_104s_59 "强制均衡模式";
CM_ SG_ 2417946235 S2P_Bal_CellTempFault_104s_59 "温度单点无效";
CM_ SG_ 2417946235 S2P_Bal_CellVoltFail_104s_59 "电芯电压采样失效";
CM_ SG_ 2417946235 S2P_Bal_CloseBalIstr_104s_59 "其他模块关闭均衡指令";
CM_ SG_ 2417946235 S2P_Bal_CCanTimeOut_104s_59 "CCAN通讯超时故障";
CM_ SG_ 2417946235 S2P_Bal_CellOffLine_104s_59 "预留";
CM_ SG_ 2417946235 S2P_Bal_BalanCirFlt_104s_59 "均衡回路故障";
CM_ SG_ 2417946235 S2P_Bal_CellVoOverFlt104s_59 "预留";
CM_ SG_ 2417946235 S2P_Bal_CellVoLowFlt104s_59 "预留";
CM_ SG_ 2417946235 S2P_Bal_CSCPCBTeFlt104s_59 "预留";
CM_ SG_ 2417946236 S2P_Bal_CSCNum_104s_60 "CSC号";
CM_ SG_ 2417946236 S2P_Bal_CellNum_104s_60 "CELL号";
CM_ SG_ 2417946236 S2P_Bal_Type_104s_60 "均衡类型";
CM_ SG_ 2417946236 S2P_Bal_TimeRemain_104s_60 "故障清除指令";
CM_ SG_ 2417946236 S2P_Bal_DeltaVolt_104s_60 "均衡电芯压差";
CM_ SG_ 2417946236 S2P_Bal_TypeLevel_104s_60 "均衡等级";
CM_ SG_ 2417946236 S2P_Bal_Strategy_104s_60 "均衡策略";
CM_ SG_ 2417946236 S2P_Bal_ForceBalMode_104s_60 "强制均衡模式";
CM_ SG_ 2417946236 S2P_Bal_CellTempFault_104s_60 "温度单点无效";
CM_ SG_ 2417946236 S2P_Bal_CellVoltFail_104s_60 "电芯电压采样失效";
CM_ SG_ 2417946236 S2P_Bal_CloseBalIstr_104s_60 "其他模块关闭均衡指令";
CM_ SG_ 2417946236 S2P_Bal_CCanTimeOut_104s_60 "CCAN通讯超时故障";
CM_ SG_ 2417946236 S2P_Bal_CellOffLine_104s_60 "预留";
CM_ SG_ 2417946236 S2P_Bal_BalanCirFlt_104s_60 "均衡回路故障";
CM_ SG_ 2417946236 S2P_Bal_CellVoOverFlt104s_60 "预留";
CM_ SG_ 2417946236 S2P_Bal_CellVoLowFlt104s_60 "预留";
CM_ SG_ 2417946236 S2P_Bal_CSCPCBTeFlt104s_60 "预留";
CM_ SG_ 2417946237 S2P_Bal_CSCNum_104s_61 "CSC号";
CM_ SG_ 2417946237 S2P_Bal_CellNum_104s_61 "CELL号";
CM_ SG_ 2417946237 S2P_Bal_Type_104s_61 "均衡类型";
CM_ SG_ 2417946237 S2P_Bal_TimeRemain_104s_61 "故障清除指令";
CM_ SG_ 2417946237 S2P_Bal_DeltaVolt_104s_61 "均衡电芯压差";
CM_ SG_ 2417946237 S2P_Bal_TypeLevel_104s_61 "均衡等级";
CM_ SG_ 2417946237 S2P_Bal_Strategy_104s_61 "均衡策略";
CM_ SG_ 2417946237 S2P_Bal_ForceBalMode_104s_61 "强制均衡模式";
CM_ SG_ 2417946237 S2P_Bal_CellTempFault_104s_61 "温度单点无效";
CM_ SG_ 2417946237 S2P_Bal_CellVoltFail_104s_61 "电芯电压采样失效";
CM_ SG_ 2417946237 S2P_Bal_CloseBalIstr_104s_61 "其他模块关闭均衡指令";
CM_ SG_ 2417946237 S2P_Bal_CCanTimeOut_104s_61 "CCAN通讯超时故障";
CM_ SG_ 2417946237 S2P_Bal_CellOffLine_104s_61 "预留";
CM_ SG_ 2417946237 S2P_Bal_BalanCirFlt_104s_61 "均衡回路故障";
CM_ SG_ 2417946237 S2P_Bal_CellVoOverFlt104s_61 "预留";
CM_ SG_ 2417946237 S2P_Bal_CellVoLowFlt104s_61 "预留";
CM_ SG_ 2417946237 S2P_Bal_CSCPCBTeFlt104s_61 "预留";
CM_ SG_ 2417946238 S2P_Bal_CSCNum_104s_62 "CSC号";
CM_ SG_ 2417946238 S2P_Bal_CellNum_104s_62 "CELL号";
CM_ SG_ 2417946238 S2P_Bal_Type_104s_62 "均衡类型";
CM_ SG_ 2417946238 S2P_Bal_TimeRemain_104s_62 "故障清除指令";
CM_ SG_ 2417946238 S2P_Bal_DeltaVolt_104s_62 "均衡电芯压差";
CM_ SG_ 2417946238 S2P_Bal_TypeLevel_104s_62 "均衡等级";
CM_ SG_ 2417946238 S2P_Bal_Strategy_104s_62 "均衡策略";
CM_ SG_ 2417946238 S2P_Bal_ForceBalMode_104s_62 "强制均衡模式";
CM_ SG_ 2417946238 S2P_Bal_CellTempFault_104s_62 "温度单点无效";
CM_ SG_ 2417946238 S2P_Bal_CellVoltFail_104s_62 "电芯电压采样失效";
CM_ SG_ 2417946238 S2P_Bal_CloseBalIstr_104s_62 "其他模块关闭均衡指令";
CM_ SG_ 2417946238 S2P_Bal_CCanTimeOut_104s_62 "CCAN通讯超时故障";
CM_ SG_ 2417946238 S2P_Bal_CellOffLine_104s_62 "预留";
CM_ SG_ 2417946238 S2P_Bal_BalanCirFlt_104s_62 "均衡回路故障";
CM_ SG_ 2417946238 S2P_Bal_CellVoOverFlt104s_62 "预留";
CM_ SG_ 2417946238 S2P_Bal_CellVoLowFlt104s_62 "预留";
CM_ SG_ 2417946238 S2P_Bal_CSCPCBTeFlt104s_62 "预留";
CM_ SG_ 2417946239 S2P_Bal_CSCNum_104s_63 "CSC号";
CM_ SG_ 2417946239 S2P_Bal_CellNum_104s_63 "CELL号";
CM_ SG_ 2417946239 S2P_Bal_Type_104s_63 "均衡类型";
CM_ SG_ 2417946239 S2P_Bal_TimeRemain_104s_63 "故障清除指令";
CM_ SG_ 2417946239 S2P_Bal_DeltaVolt_104s_63 "均衡电芯压差";
CM_ SG_ 2417946239 S2P_Bal_TypeLevel_104s_63 "均衡等级";
CM_ SG_ 2417946239 S2P_Bal_Strategy_104s_63 "均衡策略";
CM_ SG_ 2417946239 S2P_Bal_ForceBalMode_104s_63 "强制均衡模式";
CM_ SG_ 2417946239 S2P_Bal_CellTempFault_104s_63 "温度单点无效";
CM_ SG_ 2417946239 S2P_Bal_CellVoltFail_104s_63 "电芯电压采样失效";
CM_ SG_ 2417946239 S2P_Bal_CloseBalIstr_104s_63 "其他模块关闭均衡指令";
CM_ SG_ 2417946239 S2P_Bal_CCanTimeOut_104s_63 "CCAN通讯超时故障";
CM_ SG_ 2417946239 S2P_Bal_CellOffLine_104s_63 "预留";
CM_ SG_ 2417946239 S2P_Bal_BalanCirFlt_104s_63 "均衡回路故障";
CM_ SG_ 2417946239 S2P_Bal_CellVoOverFlt104s_63 "预留";
CM_ SG_ 2417946239 S2P_Bal_CellVoLowFlt104s_63 "预留";
CM_ SG_ 2417946239 S2P_Bal_CSCPCBTeFlt104s_63 "预留";
CM_ SG_ 2337468049 M2P_TMS_R_ACDC_A_vol_01 "2号TMS ACDC_A 电压";
CM_ SG_ 2337468049 M2P_TMS_R_15_pwm_01 "2号TMS 15kw风机PWM";
CM_ SG_ 2337468049 M2P_TMS_R_15_HP_01 "2号TMS AC1高压压力值(15kw)";
CM_ SG_ 2337468049 M2P_TMS_R_15_LP_01 "2号TMS AC1低压压力值(15kw)";
CM_ SG_ 2337468049 M2P_TMS_R_25_HP_01 "2号TMS AC2高压压力值(25kw)";
CM_ SG_ 2337468050 M2P_TMS_R_ACDC_A_vol_02 "2号TMS ACDC_A 电压";
CM_ SG_ 2337468050 M2P_TMS_R_15_pwm_02 "2号TMS 15kw风机PWM";
CM_ SG_ 2337468050 M2P_TMS_R_15_HP_02 "2号TMS AC1高压压力值(15kw)";
CM_ SG_ 2337468050 M2P_TMS_R_15_LP_02 "2号TMS AC1低压压力值(15kw)";
CM_ SG_ 2337468050 M2P_TMS_R_25_HP_02 "2号TMS AC2高压压力值(25kw)";
CM_ SG_ 2337468051 M2P_TMS_R_ACDC_A_vol_03 "2号TMS ACDC_A 电压";
CM_ SG_ 2337468051 M2P_TMS_R_15_pwm_03 "2号TMS 15kw风机PWM";
CM_ SG_ 2337468051 M2P_TMS_R_15_HP_03 "2号TMS AC1高压压力值(15kw)";
CM_ SG_ 2337468051 M2P_TMS_R_15_LP_03 "2号TMS AC1低压压力值(15kw)";
CM_ SG_ 2337468051 M2P_TMS_R_25_HP_03 "2号TMS AC2高压压力值(25kw)";
CM_ SG_ 2337468052 M2P_TMS_R_ACDC_A_vol_04 "2号TMS ACDC_A 电压";
CM_ SG_ 2337468052 M2P_TMS_R_15_pwm_04 "2号TMS 15kw风机PWM";
CM_ SG_ 2337468052 M2P_TMS_R_15_HP_04 "2号TMS AC1高压压力值(15kw)";
CM_ SG_ 2337468052 M2P_TMS_R_15_LP_04 "2号TMS AC1低压压力值(15kw)";
CM_ SG_ 2337468052 M2P_TMS_R_25_HP_04 "2号TMS AC2高压压力值(25kw)";
CM_ SG_ 2337468053 M2P_TMS_R_ACDC_A_vol_05 "2号TMS ACDC_A 电压";
CM_ SG_ 2337468053 M2P_TMS_R_15_pwm_05 "2号TMS 15kw风机PWM";
CM_ SG_ 2337468053 M2P_TMS_R_15_HP_05 "2号TMS AC1高压压力值(15kw)";
CM_ SG_ 2337468053 M2P_TMS_R_15_LP_05 "2号TMS AC1低压压力值(15kw)";
CM_ SG_ 2337468053 M2P_TMS_R_25_HP_05 "2号TMS AC2高压压力值(25kw)";
CM_ SG_ 2337468054 M2P_TMS_R_ACDC_A_vol_06 "2号TMS ACDC_A 电压";
CM_ SG_ 2337468054 M2P_TMS_R_15_pwm_06 "2号TMS 15kw风机PWM";
CM_ SG_ 2337468054 M2P_TMS_R_15_HP_06 "2号TMS AC1高压压力值(15kw)";
CM_ SG_ 2337468054 M2P_TMS_R_15_LP_06 "2号TMS AC1低压压力值(15kw)";
CM_ SG_ 2337468054 M2P_TMS_R_25_HP_06 "2号TMS AC2高压压力值(25kw)";
CM_ SG_ 2337468055 M2P_TMS_R_ACDC_A_vol_07 "2号TMS ACDC_A 电压";
CM_ SG_ 2337468055 M2P_TMS_R_15_pwm_07 "2号TMS 15kw风机PWM";
CM_ SG_ 2337468055 M2P_TMS_R_15_HP_07 "2号TMS AC1高压压力值(15kw)";
CM_ SG_ 2337468055 M2P_TMS_R_15_LP_07 "2号TMS AC1低压压力值(15kw)";
CM_ SG_ 2337468055 M2P_TMS_R_25_HP_07 "2号TMS AC2高压压力值(25kw)";
CM_ SG_ 2337468056 M2P_TMS_R_ACDC_A_vol_08 "2号TMS ACDC_A 电压";
CM_ SG_ 2337468056 M2P_TMS_R_15_pwm_08 "2号TMS 15kw风机PWM";
CM_ SG_ 2337468056 M2P_TMS_R_15_HP_08 "2号TMS AC1高压压力值(15kw)";
CM_ SG_ 2337468056 M2P_TMS_R_15_LP_08 "2号TMS AC1低压压力值(15kw)";
CM_ SG_ 2337468056 M2P_TMS_R_25_HP_08 "2号TMS AC2高压压力值(25kw)";
CM_ SG_ 2337468057 M2P_TMS_R_ACDC_A_vol_09 "2号TMS ACDC_A 电压";
CM_ SG_ 2337468057 M2P_TMS_R_15_pwm_09 "2号TMS 15kw风机PWM";
CM_ SG_ 2337468057 M2P_TMS_R_15_HP_09 "2号TMS AC1高压压力值(15kw)";
CM_ SG_ 2337468057 M2P_TMS_R_15_LP_09 "2号TMS AC1低压压力值(15kw)";
CM_ SG_ 2337468057 M2P_TMS_R_25_HP_09 "2号TMS AC2高压压力值(25kw)";
CM_ SG_ 2337468058 M2P_TMS_R_ACDC_A_vol_10 "2号TMS ACDC_A 电压";
CM_ SG_ 2337468058 M2P_TMS_R_15_pwm_10 "2号TMS 15kw风机PWM";
CM_ SG_ 2337468058 M2P_TMS_R_15_HP_10 "2号TMS AC1高压压力值(15kw)";
CM_ SG_ 2337468058 M2P_TMS_R_15_LP_10 "2号TMS AC1低压压力值(15kw)";
CM_ SG_ 2337468058 M2P_TMS_R_25_HP_10 "2号TMS AC2高压压力值(25kw)";
CM_ SG_ 2337468059 M2P_TMS_R_ACDC_A_vol_11 "2号TMS ACDC_A 电压";
CM_ SG_ 2337468059 M2P_TMS_R_15_pwm_11 "2号TMS 15kw风机PWM";
CM_ SG_ 2337468059 M2P_TMS_R_15_HP_11 "2号TMS AC1高压压力值(15kw)";
CM_ SG_ 2337468059 M2P_TMS_R_15_LP_11 "2号TMS AC1低压压力值(15kw)";
CM_ SG_ 2337468059 M2P_TMS_R_25_HP_11 "2号TMS AC2高压压力值(25kw)";
CM_ SG_ 2337468060 M2P_TMS_R_ACDC_A_vol_12 "2号TMS ACDC_A 电压";
CM_ SG_ 2337468060 M2P_TMS_R_15_pwm_12 "2号TMS 15kw风机PWM";
CM_ SG_ 2337468060 M2P_TMS_R_15_HP_12 "2号TMS AC1高压压力值(15kw)";
CM_ SG_ 2337468060 M2P_TMS_R_15_LP_12 "2号TMS AC1低压压力值(15kw)";
CM_ SG_ 2337468060 M2P_TMS_R_25_HP_12 "2号TMS AC2高压压力值(25kw)";
CM_ SG_ 2337468061 M2P_TMS_R_ACDC_A_vol_13 "2号TMS ACDC_A 电压";
CM_ SG_ 2337468061 M2P_TMS_R_15_pwm_13 "2号TMS 15kw风机PWM";
CM_ SG_ 2337468061 M2P_TMS_R_15_HP_13 "2号TMS AC1高压压力值(15kw)";
CM_ SG_ 2337468061 M2P_TMS_R_15_LP_13 "2号TMS AC1低压压力值(15kw)";
CM_ SG_ 2337468061 M2P_TMS_R_25_HP_13 "2号TMS AC2高压压力值(25kw)";
CM_ SG_ 2337468062 M2P_TMS_R_ACDC_A_vol_14 "2号TMS ACDC_A 电压";
CM_ SG_ 2337468062 M2P_TMS_R_15_pwm_14 "2号TMS 15kw风机PWM";
CM_ SG_ 2337468062 M2P_TMS_R_15_HP_14 "2号TMS AC1高压压力值(15kw)";
CM_ SG_ 2337468062 M2P_TMS_R_15_LP_14 "2号TMS AC1低压压力值(15kw)";
CM_ SG_ 2337468062 M2P_TMS_R_25_HP_14 "2号TMS AC2高压压力值(25kw)";
CM_ SG_ 2337468063 M2P_TMS_R_ACDC_A_vol_15 "2号TMS ACDC_A 电压";
CM_ SG_ 2337468063 M2P_TMS_R_15_pwm_15 "2号TMS 15kw风机PWM";
CM_ SG_ 2337468063 M2P_TMS_R_15_HP_15 "2号TMS AC1高压压力值(15kw)";
CM_ SG_ 2337468063 M2P_TMS_R_15_LP_15 "2号TMS AC1低压压力值(15kw)";
CM_ SG_ 2337468063 M2P_TMS_R_25_HP_15 "2号TMS AC2高压压力值(25kw)";
CM_ SG_ 2337468064 M2P_TMS_R_ACDC_A_vol_16 "2号TMS ACDC_A 电压";
CM_ SG_ 2337468064 M2P_TMS_R_15_pwm_16 "2号TMS 15kw风机PWM";
CM_ SG_ 2337468064 M2P_TMS_R_15_HP_16 "2号TMS AC1高压压力值(15kw)";
CM_ SG_ 2337468064 M2P_TMS_R_15_LP_16 "2号TMS AC1低压压力值(15kw)";
CM_ SG_ 2337468064 M2P_TMS_R_25_HP_16 "2号TMS AC2高压压力值(25kw)";
CM_ SG_ 2337468065 M2P_TMS_R_ACDC_A_vol_17 "2号TMS ACDC_A 电压";
CM_ SG_ 2337468065 M2P_TMS_R_15_pwm_17 "2号TMS 15kw风机PWM";
CM_ SG_ 2337468065 M2P_TMS_R_15_HP_17 "2号TMS AC1高压压力值(15kw)";
CM_ SG_ 2337468065 M2P_TMS_R_15_LP_17 "2号TMS AC1低压压力值(15kw)";
CM_ SG_ 2337468065 M2P_TMS_R_25_HP_17 "2号TMS AC2高压压力值(25kw)";
CM_ SG_ 2337468066 M2P_TMS_R_ACDC_A_vol_18 "2号TMS ACDC_A 电压";
CM_ SG_ 2337468066 M2P_TMS_R_15_pwm_18 "2号TMS 15kw风机PWM";
CM_ SG_ 2337468066 M2P_TMS_R_15_HP_18 "2号TMS AC1高压压力值(15kw)";
CM_ SG_ 2337468066 M2P_TMS_R_15_LP_18 "2号TMS AC1低压压力值(15kw)";
CM_ SG_ 2337468066 M2P_TMS_R_25_HP_18 "2号TMS AC2高压压力值(25kw)";
CM_ SG_ 2337468067 M2P_TMS_R_ACDC_A_vol_19 "2号TMS ACDC_A 电压";
CM_ SG_ 2337468067 M2P_TMS_R_15_pwm_19 "2号TMS 15kw风机PWM";
CM_ SG_ 2337468067 M2P_TMS_R_15_HP_19 "2号TMS AC1高压压力值(15kw)";
CM_ SG_ 2337468067 M2P_TMS_R_15_LP_19 "2号TMS AC1低压压力值(15kw)";
CM_ SG_ 2337468067 M2P_TMS_R_25_HP_19 "2号TMS AC2高压压力值(25kw)";
CM_ SG_ 2337468068 M2P_TMS_R_ACDC_A_vol_20 "2号TMS ACDC_A 电压";
CM_ SG_ 2337468068 M2P_TMS_R_15_pwm_20 "2号TMS 15kw风机PWM";
CM_ SG_ 2337468068 M2P_TMS_R_15_HP_20 "2号TMS AC1高压压力值(15kw)";
CM_ SG_ 2337468068 M2P_TMS_R_15_LP_20 "2号TMS AC1低压压力值(15kw)";
CM_ SG_ 2337468068 M2P_TMS_R_25_HP_20 "2号TMS AC2高压压力值(25kw)";
CM_ SG_ 2337468069 M2P_TMS_R_ACDC_A_vol_21 "2号TMS ACDC_A 电压";
CM_ SG_ 2337468069 M2P_TMS_R_15_pwm_21 "2号TMS 15kw风机PWM";
CM_ SG_ 2337468069 M2P_TMS_R_15_HP_21 "2号TMS AC1高压压力值(15kw)";
CM_ SG_ 2337468069 M2P_TMS_R_15_LP_21 "2号TMS AC1低压压力值(15kw)";
CM_ SG_ 2337468069 M2P_TMS_R_25_HP_21 "2号TMS AC2高压压力值(25kw)";
CM_ SG_ 2337468070 M2P_TMS_R_ACDC_A_vol_22 "2号TMS ACDC_A 电压";
CM_ SG_ 2337468070 M2P_TMS_R_15_pwm_22 "2号TMS 15kw风机PWM";
CM_ SG_ 2337468070 M2P_TMS_R_15_HP_22 "2号TMS AC1高压压力值(15kw)";
CM_ SG_ 2337468070 M2P_TMS_R_15_LP_22 "2号TMS AC1低压压力值(15kw)";
CM_ SG_ 2337468070 M2P_TMS_R_25_HP_22 "2号TMS AC2高压压力值(25kw)";
CM_ SG_ 2337468071 M2P_TMS_R_ACDC_A_vol_23 "2号TMS ACDC_A 电压";
CM_ SG_ 2337468071 M2P_TMS_R_15_pwm_23 "2号TMS 15kw风机PWM";
CM_ SG_ 2337468071 M2P_TMS_R_15_HP_23 "2号TMS AC1高压压力值(15kw)";
CM_ SG_ 2337468071 M2P_TMS_R_15_LP_23 "2号TMS AC1低压压力值(15kw)";
CM_ SG_ 2337468071 M2P_TMS_R_25_HP_23 "2号TMS AC2高压压力值(25kw)";
CM_ SG_ 2337468072 M2P_TMS_R_ACDC_A_vol_24 "2号TMS ACDC_A 电压";
CM_ SG_ 2337468072 M2P_TMS_R_15_pwm_24 "2号TMS 15kw风机PWM";
CM_ SG_ 2337468072 M2P_TMS_R_15_HP_24 "2号TMS AC1高压压力值(15kw)";
CM_ SG_ 2337468072 M2P_TMS_R_15_LP_24 "2号TMS AC1低压压力值(15kw)";
CM_ SG_ 2337468072 M2P_TMS_R_25_HP_24 "2号TMS AC2高压压力值(25kw)";
CM_ SG_ 2337468073 M2P_TMS_R_ACDC_A_vol_25 "2号TMS ACDC_A 电压";
CM_ SG_ 2337468073 M2P_TMS_R_15_pwm_25 "2号TMS 15kw风机PWM";
CM_ SG_ 2337468073 M2P_TMS_R_15_HP_25 "2号TMS AC1高压压力值(15kw)";
CM_ SG_ 2337468073 M2P_TMS_R_15_LP_25 "2号TMS AC1低压压力值(15kw)";
CM_ SG_ 2337468073 M2P_TMS_R_25_HP_25 "2号TMS AC2高压压力值(25kw)";
CM_ SG_ 2337468074 M2P_TMS_R_ACDC_A_vol_26 "2号TMS ACDC_A 电压";
CM_ SG_ 2337468074 M2P_TMS_R_15_pwm_26 "2号TMS 15kw风机PWM";
CM_ SG_ 2337468074 M2P_TMS_R_15_HP_26 "2号TMS AC1高压压力值(15kw)";
CM_ SG_ 2337468074 M2P_TMS_R_15_LP_26 "2号TMS AC1低压压力值(15kw)";
CM_ SG_ 2337468074 M2P_TMS_R_25_HP_26 "2号TMS AC2高压压力值(25kw)";
CM_ SG_ 2337468075 M2P_TMS_R_ACDC_A_vol_27 "2号TMS ACDC_A 电压";
CM_ SG_ 2337468075 M2P_TMS_R_15_pwm_27 "2号TMS 15kw风机PWM";
CM_ SG_ 2337468075 M2P_TMS_R_15_HP_27 "2号TMS AC1高压压力值(15kw)";
CM_ SG_ 2337468075 M2P_TMS_R_15_LP_27 "2号TMS AC1低压压力值(15kw)";
CM_ SG_ 2337468075 M2P_TMS_R_25_HP_27 "2号TMS AC2高压压力值(25kw)";
CM_ SG_ 2337468076 M2P_TMS_R_ACDC_A_vol_28 "2号TMS ACDC_A 电压";
CM_ SG_ 2337468076 M2P_TMS_R_15_pwm_28 "2号TMS 15kw风机PWM";
CM_ SG_ 2337468076 M2P_TMS_R_15_HP_28 "2号TMS AC1高压压力值(15kw)";
CM_ SG_ 2337468076 M2P_TMS_R_15_LP_28 "2号TMS AC1低压压力值(15kw)";
CM_ SG_ 2337468076 M2P_TMS_R_25_HP_28 "2号TMS AC2高压压力值(25kw)";
VAL_ 2417946189 S2P_Bal_CSCNum_104s_13 0 "No CSC" 1 "CSC 1" 2 "CSC 2" 3 "CSC 3" 4 "CSC 4" 5 "CSC 5" 6 "CSC 6" 7 "CSC 7" 8 "CSC 8" 9 "CSC 9" 10 "CSC 10" 11 "CSC 11" 12 "CSC 12" 13 "CSC 13" 14 "CSC 14" 15 "CSC 15" 16 "CSC 16" 17 "CSC 17" 18 "CSC 18" 19 "CSC 19" 20 "CSC 20" 21 "CSC 21" 22 "CSC 22" 23 "CSC 23" 24 "CSC 24" 25 "CSC 25" 26 "CSC 26" 27 "CSC 27" 28 "CSC 28" 29 "CSC 29" 30 "CSC 30" 31 "CSC 31" ;
VAL_ 2417946189 S2P_Bal_CellNum_104s_13 1 "Cell 1" 2 "Cell 2" 3 "Cell 3" 4 "Cell 4" 5 "Cell 5" 6 "Cell 6" 7 "Cell 7" 8 "Cell 8" 9 "Cell 9" 10 "Cell 10" 11 "Cell 11" 12 "Cell 12" 13 "Cell 13" 14 "Cell 14" 15 "Cell 15" 16 "Cell 16" 127 "Null" ;
VAL_ 2417946189 S2P_Bal_Type_104s_13 0 "Balance stop" 1 "charge Balance" 2 "discharge Balance" ;
VAL_ 2417946189 S2P_Bal_TypeLevel_104s_13 0 "Not Balance" 1 "Low end Balance" 2 "High end Balance" 3 "Force Balance" ;
VAL_ 2417946189 S2P_Bal_Strategy_104s_13 0 "Active Balance" 1 "Passive Static" ;
VAL_ 2417946189 S2P_Bal_ForceBalMode_104s_13 1 "Base on time " 2 "Base on Target Vol" 3 "Base on Ave Vol" ;
VAL_ 2417946189 S2P_Bal_CellTempFault_104s_13 0 "Nomal" 1 "Fault" ;
VAL_ 2417946189 S2P_Bal_CellVoltFail_104s_13 0 "Nomal" 1 "Fault" ;
VAL_ 2417946189 S2P_Bal_CloseBalIstr_104s_13 0 "Nomal" 1 "Fault" ;
VAL_ 2417946189 S2P_Bal_CCanTimeOut_104s_13 0 "Nomal" 1 "Fault" ;
VAL_ 2417946189 S2P_Bal_BalanCirFlt_104s_13 0 "Nomal" 1 "Fault" ;
VAL_ 2417946190 S2P_Bal_CSCNum_104s_14 0 "No CSC" 1 "CSC 1" 2 "CSC 2" 3 "CSC 3" 4 "CSC 4" 5 "CSC 5" 6 "CSC 6" 7 "CSC 7" 8 "CSC 8" 9 "CSC 9" 10 "CSC 10" 11 "CSC 11" 12 "CSC 12" 13 "CSC 13" 14 "CSC 14" 15 "CSC 15" 16 "CSC 16" 17 "CSC 17" 18 "CSC 18" 19 "CSC 19" 20 "CSC 20" 21 "CSC 21" 22 "CSC 22" 23 "CSC 23" 24 "CSC 24" 25 "CSC 25" 26 "CSC 26" 27 "CSC 27" 28 "CSC 28" 29 "CSC 29" 30 "CSC 30" 31 "CSC 31" ;
VAL_ 2417946190 S2P_Bal_CellNum_104s_14 1 "Cell 1" 2 "Cell 2" 3 "Cell 3" 4 "Cell 4" 5 "Cell 5" 6 "Cell 6" 7 "Cell 7" 8 "Cell 8" 9 "Cell 9" 10 "Cell 10" 11 "Cell 11" 12 "Cell 12" 13 "Cell 13" 14 "Cell 14" 15 "Cell 15" 16 "Cell 16" 127 "Null" ;
VAL_ 2417946190 S2P_Bal_Type_104s_14 0 "Balance stop" 1 "charge Balance" 2 "discharge Balance" ;
VAL_ 2417946190 S2P_Bal_TypeLevel_104s_14 0 "Not Balance" 1 "Low end Balance" 2 "High end Balance" 3 "Force Balance" ;
VAL_ 2417946190 S2P_Bal_Strategy_104s_14 0 "Active Balance" 1 "Passive Static" ;
VAL_ 2417946190 S2P_Bal_ForceBalMode_104s_14 1 "Base on time " 2 "Base on Target Vol" 3 "Base on Ave Vol" ;
VAL_ 2417946190 S2P_Bal_CellTempFault_104s_14 0 "Nomal" 1 "Fault" ;
VAL_ 2417946190 S2P_Bal_CellVoltFail_104s_14 0 "Nomal" 1 "Fault" ;
VAL_ 2417946190 S2P_Bal_CloseBalIstr_104s_14 0 "Nomal" 1 "Fault" ;
VAL_ 2417946190 S2P_Bal_CCanTimeOut_104s_14 0 "Nomal" 1 "Fault" ;
VAL_ 2417946190 S2P_Bal_BalanCirFlt_104s_14 0 "Nomal" 1 "Fault" ;
VAL_ 2417946191 S2P_Bal_CSCNum_104s_15 0 "No CSC" 1 "CSC 1" 2 "CSC 2" 3 "CSC 3" 4 "CSC 4" 5 "CSC 5" 6 "CSC 6" 7 "CSC 7" 8 "CSC 8" 9 "CSC 9" 10 "CSC 10" 11 "CSC 11" 12 "CSC 12" 13 "CSC 13" 14 "CSC 14" 15 "CSC 15" 16 "CSC 16" 17 "CSC 17" 18 "CSC 18" 19 "CSC 19" 20 "CSC 20" 21 "CSC 21" 22 "CSC 22" 23 "CSC 23" 24 "CSC 24" 25 "CSC 25" 26 "CSC 26" 27 "CSC 27" 28 "CSC 28" 29 "CSC 29" 30 "CSC 30" 31 "CSC 31" ;
VAL_ 2417946191 S2P_Bal_CellNum_104s_15 1 "Cell 1" 2 "Cell 2" 3 "Cell 3" 4 "Cell 4" 5 "Cell 5" 6 "Cell 6" 7 "Cell 7" 8 "Cell 8" 9 "Cell 9" 10 "Cell 10" 11 "Cell 11" 12 "Cell 12" 13 "Cell 13" 14 "Cell 14" 15 "Cell 15" 16 "Cell 16" 127 "Null" ;
VAL_ 2417946191 S2P_Bal_Type_104s_15 0 "Balance stop" 1 "charge Balance" 2 "discharge Balance" ;
VAL_ 2417946191 S2P_Bal_TypeLevel_104s_15 0 "Not Balance" 1 "Low end Balance" 2 "High end Balance" 3 "Force Balance" ;
VAL_ 2417946191 S2P_Bal_Strategy_104s_15 0 "Active Balance" 1 "Passive Static" ;
VAL_ 2417946191 S2P_Bal_ForceBalMode_104s_15 1 "Base on time " 2 "Base on Target Vol" 3 "Base on Ave Vol" ;
VAL_ 2417946191 S2P_Bal_CellTempFault_104s_15 0 "Nomal" 1 "Fault" ;
VAL_ 2417946191 S2P_Bal_CellVoltFail_104s_15 0 "Nomal" 1 "Fault" ;
VAL_ 2417946191 S2P_Bal_CloseBalIstr_104s_15 0 "Nomal" 1 "Fault" ;
VAL_ 2417946191 S2P_Bal_CCanTimeOut_104s_15 0 "Nomal" 1 "Fault" ;
VAL_ 2417946191 S2P_Bal_BalanCirFlt_104s_15 0 "Nomal" 1 "Fault" ;
VAL_ 2417946192 S2P_Bal_CSCNum_104s_16 0 "No CSC" 1 "CSC 1" 2 "CSC 2" 3 "CSC 3" 4 "CSC 4" 5 "CSC 5" 6 "CSC 6" 7 "CSC 7" 8 "CSC 8" 9 "CSC 9" 10 "CSC 10" 11 "CSC 11" 12 "CSC 12" 13 "CSC 13" 14 "CSC 14" 15 "CSC 15" 16 "CSC 16" 17 "CSC 17" 18 "CSC 18" 19 "CSC 19" 20 "CSC 20" 21 "CSC 21" 22 "CSC 22" 23 "CSC 23" 24 "CSC 24" 25 "CSC 25" 26 "CSC 26" 27 "CSC 27" 28 "CSC 28" 29 "CSC 29" 30 "CSC 30" 31 "CSC 31" ;
VAL_ 2417946192 S2P_Bal_CellNum_104s_16 1 "Cell 1" 2 "Cell 2" 3 "Cell 3" 4 "Cell 4" 5 "Cell 5" 6 "Cell 6" 7 "Cell 7" 8 "Cell 8" 9 "Cell 9" 10 "Cell 10" 11 "Cell 11" 12 "Cell 12" 13 "Cell 13" 14 "Cell 14" 15 "Cell 15" 16 "Cell 16" 127 "Null" ;
VAL_ 2417946192 S2P_Bal_Type_104s_16 0 "Balance stop" 1 "charge Balance" 2 "discharge Balance" ;
VAL_ 2417946192 S2P_Bal_TypeLevel_104s_16 0 "Not Balance" 1 "Low end Balance" 2 "High end Balance" 3 "Force Balance" ;
VAL_ 2417946192 S2P_Bal_Strategy_104s_16 0 "Active Balance" 1 "Passive Static" ;
VAL_ 2417946192 S2P_Bal_ForceBalMode_104s_16 1 "Base on time " 2 "Base on Target Vol" 3 "Base on Ave Vol" ;
VAL_ 2417946192 S2P_Bal_CellTempFault_104s_16 0 "Nomal" 1 "Fault" ;
VAL_ 2417946192 S2P_Bal_CellVoltFail_104s_16 0 "Nomal" 1 "Fault" ;
VAL_ 2417946192 S2P_Bal_CloseBalIstr_104s_16 0 "Nomal" 1 "Fault" ;
VAL_ 2417946192 S2P_Bal_CCanTimeOut_104s_16 0 "Nomal" 1 "Fault" ;
VAL_ 2417946192 S2P_Bal_BalanCirFlt_104s_16 0 "Nomal" 1 "Fault" ;
VAL_ 2417946193 S2P_Bal_CSCNum_104s_17 0 "No CSC" 1 "CSC 1" 2 "CSC 2" 3 "CSC 3" 4 "CSC 4" 5 "CSC 5" 6 "CSC 6" 7 "CSC 7" 8 "CSC 8" 9 "CSC 9" 10 "CSC 10" 11 "CSC 11" 12 "CSC 12" 13 "CSC 13" 14 "CSC 14" 15 "CSC 15" 16 "CSC 16" 17 "CSC 17" 18 "CSC 18" 19 "CSC 19" 20 "CSC 20" 21 "CSC 21" 22 "CSC 22" 23 "CSC 23" 24 "CSC 24" 25 "CSC 25" 26 "CSC 26" 27 "CSC 27" 28 "CSC 28" 29 "CSC 29" 30 "CSC 30" 31 "CSC 31" ;
VAL_ 2417946193 S2P_Bal_CellNum_104s_17 1 "Cell 1" 2 "Cell 2" 3 "Cell 3" 4 "Cell 4" 5 "Cell 5" 6 "Cell 6" 7 "Cell 7" 8 "Cell 8" 9 "Cell 9" 10 "Cell 10" 11 "Cell 11" 12 "Cell 12" 13 "Cell 13" 14 "Cell 14" 15 "Cell 15" 16 "Cell 16" 127 "Null" ;
VAL_ 2417946193 S2P_Bal_Type_104s_17 0 "Balance stop" 1 "charge Balance" 2 "discharge Balance" ;
VAL_ 2417946193 S2P_Bal_TypeLevel_104s_17 0 "Not Balance" 1 "Low end Balance" 2 "High end Balance" 3 "Force Balance" ;
VAL_ 2417946193 S2P_Bal_Strategy_104s_17 0 "Active Balance" 1 "Passive Static" ;
VAL_ 2417946193 S2P_Bal_ForceBalMode_104s_17 1 "Base on time " 2 "Base on Target Vol" 3 "Base on Ave Vol" ;
VAL_ 2417946193 S2P_Bal_CellTempFault_104s_17 0 "Nomal" 1 "Fault" ;
VAL_ 2417946193 S2P_Bal_CellVoltFail_104s_17 0 "Nomal" 1 "Fault" ;
VAL_ 2417946193 S2P_Bal_CloseBalIstr_104s_17 0 "Nomal" 1 "Fault" ;
VAL_ 2417946193 S2P_Bal_CCanTimeOut_104s_17 0 "Nomal" 1 "Fault" ;
VAL_ 2417946193 S2P_Bal_BalanCirFlt_104s_17 0 "Nomal" 1 "Fault" ;
VAL_ 2417946194 S2P_Bal_CSCNum_104s_18 0 "No CSC" 1 "CSC 1" 2 "CSC 2" 3 "CSC 3" 4 "CSC 4" 5 "CSC 5" 6 "CSC 6" 7 "CSC 7" 8 "CSC 8" 9 "CSC 9" 10 "CSC 10" 11 "CSC 11" 12 "CSC 12" 13 "CSC 13" 14 "CSC 14" 15 "CSC 15" 16 "CSC 16" 17 "CSC 17" 18 "CSC 18" 19 "CSC 19" 20 "CSC 20" 21 "CSC 21" 22 "CSC 22" 23 "CSC 23" 24 "CSC 24" 25 "CSC 25" 26 "CSC 26" 27 "CSC 27" 28 "CSC 28" 29 "CSC 29" 30 "CSC 30" 31 "CSC 31" ;
VAL_ 2417946194 S2P_Bal_CellNum_104s_18 1 "Cell 1" 2 "Cell 2" 3 "Cell 3" 4 "Cell 4" 5 "Cell 5" 6 "Cell 6" 7 "Cell 7" 8 "Cell 8" 9 "Cell 9" 10 "Cell 10" 11 "Cell 11" 12 "Cell 12" 13 "Cell 13" 14 "Cell 14" 15 "Cell 15" 16 "Cell 16" 127 "Null" ;
VAL_ 2417946194 S2P_Bal_Type_104s_18 0 "Balance stop" 1 "charge Balance" 2 "discharge Balance" ;
VAL_ 2417946194 S2P_Bal_TypeLevel_104s_18 0 "Not Balance" 1 "Low end Balance" 2 "High end Balance" 3 "Force Balance" ;
VAL_ 2417946194 S2P_Bal_Strategy_104s_18 0 "Active Balance" 1 "Passive Static" ;
VAL_ 2417946194 S2P_Bal_ForceBalMode_104s_18 1 "Base on time " 2 "Base on Target Vol" 3 "Base on Ave Vol" ;
VAL_ 2417946194 S2P_Bal_CellTempFault_104s_18 0 "Nomal" 1 "Fault" ;
VAL_ 2417946194 S2P_Bal_CellVoltFail_104s_18 0 "Nomal" 1 "Fault" ;
VAL_ 2417946194 S2P_Bal_CloseBalIstr_104s_18 0 "Nomal" 1 "Fault" ;
VAL_ 2417946194 S2P_Bal_CCanTimeOut_104s_18 0 "Nomal" 1 "Fault" ;
VAL_ 2417946194 S2P_Bal_BalanCirFlt_104s_18 0 "Nomal" 1 "Fault" ;
VAL_ 2417946195 S2P_Bal_CSCNum_104s_19 0 "No CSC" 1 "CSC 1" 2 "CSC 2" 3 "CSC 3" 4 "CSC 4" 5 "CSC 5" 6 "CSC 6" 7 "CSC 7" 8 "CSC 8" 9 "CSC 9" 10 "CSC 10" 11 "CSC 11" 12 "CSC 12" 13 "CSC 13" 14 "CSC 14" 15 "CSC 15" 16 "CSC 16" 17 "CSC 17" 18 "CSC 18" 19 "CSC 19" 20 "CSC 20" 21 "CSC 21" 22 "CSC 22" 23 "CSC 23" 24 "CSC 24" 25 "CSC 25" 26 "CSC 26" 27 "CSC 27" 28 "CSC 28" 29 "CSC 29" 30 "CSC 30" 31 "CSC 31" ;
VAL_ 2417946195 S2P_Bal_CellNum_104s_19 1 "Cell 1" 2 "Cell 2" 3 "Cell 3" 4 "Cell 4" 5 "Cell 5" 6 "Cell 6" 7 "Cell 7" 8 "Cell 8" 9 "Cell 9" 10 "Cell 10" 11 "Cell 11" 12 "Cell 12" 13 "Cell 13" 14 "Cell 14" 15 "Cell 15" 16 "Cell 16" 127 "Null" ;
VAL_ 2417946195 S2P_Bal_Type_104s_19 0 "Balance stop" 1 "charge Balance" 2 "discharge Balance" ;
VAL_ 2417946195 S2P_Bal_TypeLevel_104s_19 0 "Not Balance" 1 "Low end Balance" 2 "High end Balance" 3 "Force Balance" ;
VAL_ 2417946195 S2P_Bal_Strategy_104s_19 0 "Active Balance" 1 "Passive Static" ;
VAL_ 2417946195 S2P_Bal_ForceBalMode_104s_19 1 "Base on time " 2 "Base on Target Vol" 3 "Base on Ave Vol" ;
VAL_ 2417946195 S2P_Bal_CellTempFault_104s_19 0 "Nomal" 1 "Fault" ;
VAL_ 2417946195 S2P_Bal_CellVoltFail_104s_19 0 "Nomal" 1 "Fault" ;
VAL_ 2417946195 S2P_Bal_CloseBalIstr_104s_19 0 "Nomal" 1 "Fault" ;
VAL_ 2417946195 S2P_Bal_CCanTimeOut_104s_19 0 "Nomal" 1 "Fault" ;
VAL_ 2417946195 S2P_Bal_BalanCirFlt_104s_19 0 "Nomal" 1 "Fault" ;
VAL_ 2417946196 S2P_Bal_CSCNum_104s_20 0 "No CSC" 1 "CSC 1" 2 "CSC 2" 3 "CSC 3" 4 "CSC 4" 5 "CSC 5" 6 "CSC 6" 7 "CSC 7" 8 "CSC 8" 9 "CSC 9" 10 "CSC 10" 11 "CSC 11" 12 "CSC 12" 13 "CSC 13" 14 "CSC 14" 15 "CSC 15" 16 "CSC 16" 17 "CSC 17" 18 "CSC 18" 19 "CSC 19" 20 "CSC 20" 21 "CSC 21" 22 "CSC 22" 23 "CSC 23" 24 "CSC 24" 25 "CSC 25" 26 "CSC 26" 27 "CSC 27" 28 "CSC 28" 29 "CSC 29" 30 "CSC 30" 31 "CSC 31" ;
VAL_ 2417946196 S2P_Bal_CellNum_104s_20 1 "Cell 1" 2 "Cell 2" 3 "Cell 3" 4 "Cell 4" 5 "Cell 5" 6 "Cell 6" 7 "Cell 7" 8 "Cell 8" 9 "Cell 9" 10 "Cell 10" 11 "Cell 11" 12 "Cell 12" 13 "Cell 13" 14 "Cell 14" 15 "Cell 15" 16 "Cell 16" 127 "Null" ;
VAL_ 2417946196 S2P_Bal_Type_104s_20 0 "Balance stop" 1 "charge Balance" 2 "discharge Balance" ;
VAL_ 2417946196 S2P_Bal_TypeLevel_104s_20 0 "Not Balance" 1 "Low end Balance" 2 "High end Balance" 3 "Force Balance" ;
VAL_ 2417946196 S2P_Bal_Strategy_104s_20 0 "Active Balance" 1 "Passive Static" ;
VAL_ 2417946196 S2P_Bal_ForceBalMode_104s_20 1 "Base on time " 2 "Base on Target Vol" 3 "Base on Ave Vol" ;
VAL_ 2417946196 S2P_Bal_CellTempFault_104s_20 0 "Nomal" 1 "Fault" ;
VAL_ 2417946196 S2P_Bal_CellVoltFail_104s_20 0 "Nomal" 1 "Fault" ;
VAL_ 2417946196 S2P_Bal_CloseBalIstr_104s_20 0 "Nomal" 1 "Fault" ;
VAL_ 2417946196 S2P_Bal_CCanTimeOut_104s_20 0 "Nomal" 1 "Fault" ;
VAL_ 2417946196 S2P_Bal_BalanCirFlt_104s_20 0 "Nomal" 1 "Fault" ;
VAL_ 2417946197 S2P_Bal_CSCNum_104s_21 0 "No CSC" 1 "CSC 1" 2 "CSC 2" 3 "CSC 3" 4 "CSC 4" 5 "CSC 5" 6 "CSC 6" 7 "CSC 7" 8 "CSC 8" 9 "CSC 9" 10 "CSC 10" 11 "CSC 11" 12 "CSC 12" 13 "CSC 13" 14 "CSC 14" 15 "CSC 15" 16 "CSC 16" 17 "CSC 17" 18 "CSC 18" 19 "CSC 19" 20 "CSC 20" 21 "CSC 21" 22 "CSC 22" 23 "CSC 23" 24 "CSC 24" 25 "CSC 25" 26 "CSC 26" 27 "CSC 27" 28 "CSC 28" 29 "CSC 29" 30 "CSC 30" 31 "CSC 31" ;
VAL_ 2417946197 S2P_Bal_CellNum_104s_21 1 "Cell 1" 2 "Cell 2" 3 "Cell 3" 4 "Cell 4" 5 "Cell 5" 6 "Cell 6" 7 "Cell 7" 8 "Cell 8" 9 "Cell 9" 10 "Cell 10" 11 "Cell 11" 12 "Cell 12" 13 "Cell 13" 14 "Cell 14" 15 "Cell 15" 16 "Cell 16" 127 "Null" ;
VAL_ 2417946197 S2P_Bal_Type_104s_21 0 "Balance stop" 1 "charge Balance" 2 "discharge Balance" ;
VAL_ 2417946197 S2P_Bal_TypeLevel_104s_21 0 "Not Balance" 1 "Low end Balance" 2 "High end Balance" 3 "Force Balance" ;
VAL_ 2417946197 S2P_Bal_Strategy_104s_21 0 "Active Balance" 1 "Passive Static" ;
VAL_ 2417946197 S2P_Bal_ForceBalMode_104s_21 1 "Base on time " 2 "Base on Target Vol" 3 "Base on Ave Vol" ;
VAL_ 2417946197 S2P_Bal_CellTempFault_104s_21 0 "Nomal" 1 "Fault" ;
VAL_ 2417946197 S2P_Bal_CellVoltFail_104s_21 0 "Nomal" 1 "Fault" ;
VAL_ 2417946197 S2P_Bal_CloseBalIstr_104s_21 0 "Nomal" 1 "Fault" ;
VAL_ 2417946197 S2P_Bal_CCanTimeOut_104s_21 0 "Nomal" 1 "Fault" ;
VAL_ 2417946197 S2P_Bal_BalanCirFlt_104s_21 0 "Nomal" 1 "Fault" ;
VAL_ 2417946198 S2P_Bal_CSCNum_104s_22 0 "No CSC" 1 "CSC 1" 2 "CSC 2" 3 "CSC 3" 4 "CSC 4" 5 "CSC 5" 6 "CSC 6" 7 "CSC 7" 8 "CSC 8" 9 "CSC 9" 10 "CSC 10" 11 "CSC 11" 12 "CSC 12" 13 "CSC 13" 14 "CSC 14" 15 "CSC 15" 16 "CSC 16" 17 "CSC 17" 18 "CSC 18" 19 "CSC 19" 20 "CSC 20" 21 "CSC 21" 22 "CSC 22" 23 "CSC 23" 24 "CSC 24" 25 "CSC 25" 26 "CSC 26" 27 "CSC 27" 28 "CSC 28" 29 "CSC 29" 30 "CSC 30" 31 "CSC 31" ;
VAL_ 2417946198 S2P_Bal_CellNum_104s_22 1 "Cell 1" 2 "Cell 2" 3 "Cell 3" 4 "Cell 4" 5 "Cell 5" 6 "Cell 6" 7 "Cell 7" 8 "Cell 8" 9 "Cell 9" 10 "Cell 10" 11 "Cell 11" 12 "Cell 12" 13 "Cell 13" 14 "Cell 14" 15 "Cell 15" 16 "Cell 16" 127 "Null" ;
VAL_ 2417946198 S2P_Bal_Type_104s_22 0 "Balance stop" 1 "charge Balance" 2 "discharge Balance" ;
VAL_ 2417946198 S2P_Bal_TypeLevel_104s_22 0 "Not Balance" 1 "Low end Balance" 2 "High end Balance" 3 "Force Balance" ;
VAL_ 2417946198 S2P_Bal_Strategy_104s_22 0 "Active Balance" 1 "Passive Static" ;
VAL_ 2417946198 S2P_Bal_ForceBalMode_104s_22 1 "Base on time " 2 "Base on Target Vol" 3 "Base on Ave Vol" ;
VAL_ 2417946198 S2P_Bal_CellTempFault_104s_22 0 "Nomal" 1 "Fault" ;
VAL_ 2417946198 S2P_Bal_CellVoltFail_104s_22 0 "Nomal" 1 "Fault" ;
VAL_ 2417946198 S2P_Bal_CloseBalIstr_104s_22 0 "Nomal" 1 "Fault" ;
VAL_ 2417946198 S2P_Bal_CCanTimeOut_104s_22 0 "Nomal" 1 "Fault" ;
VAL_ 2417946198 S2P_Bal_BalanCirFlt_104s_22 0 "Nomal" 1 "Fault" ;
VAL_ 2417946199 S2P_Bal_CSCNum_104s_23 0 "No CSC" 1 "CSC 1" 2 "CSC 2" 3 "CSC 3" 4 "CSC 4" 5 "CSC 5" 6 "CSC 6" 7 "CSC 7" 8 "CSC 8" 9 "CSC 9" 10 "CSC 10" 11 "CSC 11" 12 "CSC 12" 13 "CSC 13" 14 "CSC 14" 15 "CSC 15" 16 "CSC 16" 17 "CSC 17" 18 "CSC 18" 19 "CSC 19" 20 "CSC 20" 21 "CSC 21" 22 "CSC 22" 23 "CSC 23" 24 "CSC 24" 25 "CSC 25" 26 "CSC 26" 27 "CSC 27" 28 "CSC 28" 29 "CSC 29" 30 "CSC 30" 31 "CSC 31" ;
VAL_ 2417946199 S2P_Bal_CellNum_104s_23 1 "Cell 1" 2 "Cell 2" 3 "Cell 3" 4 "Cell 4" 5 "Cell 5" 6 "Cell 6" 7 "Cell 7" 8 "Cell 8" 9 "Cell 9" 10 "Cell 10" 11 "Cell 11" 12 "Cell 12" 13 "Cell 13" 14 "Cell 14" 15 "Cell 15" 16 "Cell 16" 127 "Null" ;
VAL_ 2417946199 S2P_Bal_Type_104s_23 0 "Balance stop" 1 "charge Balance" 2 "discharge Balance" ;
VAL_ 2417946199 S2P_Bal_TypeLevel_104s_23 0 "Not Balance" 1 "Low end Balance" 2 "High end Balance" 3 "Force Balance" ;
VAL_ 2417946199 S2P_Bal_Strategy_104s_23 0 "Active Balance" 1 "Passive Static" ;
VAL_ 2417946199 S2P_Bal_ForceBalMode_104s_23 1 "Base on time " 2 "Base on Target Vol" 3 "Base on Ave Vol" ;
VAL_ 2417946199 S2P_Bal_CellTempFault_104s_23 0 "Nomal" 1 "Fault" ;
VAL_ 2417946199 S2P_Bal_CellVoltFail_104s_23 0 "Nomal" 1 "Fault" ;
VAL_ 2417946199 S2P_Bal_CloseBalIstr_104s_23 0 "Nomal" 1 "Fault" ;
VAL_ 2417946199 S2P_Bal_CCanTimeOut_104s_23 0 "Nomal" 1 "Fault" ;
VAL_ 2417946199 S2P_Bal_BalanCirFlt_104s_23 0 "Nomal" 1 "Fault" ;
VAL_ 2417946200 S2P_Bal_CSCNum_104s_24 0 "No CSC" 1 "CSC 1" 2 "CSC 2" 3 "CSC 3" 4 "CSC 4" 5 "CSC 5" 6 "CSC 6" 7 "CSC 7" 8 "CSC 8" 9 "CSC 9" 10 "CSC 10" 11 "CSC 11" 12 "CSC 12" 13 "CSC 13" 14 "CSC 14" 15 "CSC 15" 16 "CSC 16" 17 "CSC 17" 18 "CSC 18" 19 "CSC 19" 20 "CSC 20" 21 "CSC 21" 22 "CSC 22" 23 "CSC 23" 24 "CSC 24" 25 "CSC 25" 26 "CSC 26" 27 "CSC 27" 28 "CSC 28" 29 "CSC 29" 30 "CSC 30" 31 "CSC 31" ;
VAL_ 2417946200 S2P_Bal_CellNum_104s_24 1 "Cell 1" 2 "Cell 2" 3 "Cell 3" 4 "Cell 4" 5 "Cell 5" 6 "Cell 6" 7 "Cell 7" 8 "Cell 8" 9 "Cell 9" 10 "Cell 10" 11 "Cell 11" 12 "Cell 12" 13 "Cell 13" 14 "Cell 14" 15 "Cell 15" 16 "Cell 16" 127 "Null" ;
VAL_ 2417946200 S2P_Bal_Type_104s_24 0 "Balance stop" 1 "charge Balance" 2 "discharge Balance" ;
VAL_ 2417946200 S2P_Bal_TypeLevel_104s_24 0 "Not Balance" 1 "Low end Balance" 2 "High end Balance" 3 "Force Balance" ;
VAL_ 2417946200 S2P_Bal_Strategy_104s_24 0 "Active Balance" 1 "Passive Static" ;
VAL_ 2417946200 S2P_Bal_ForceBalMode_104s_24 1 "Base on time " 2 "Base on Target Vol" 3 "Base on Ave Vol" ;
VAL_ 2417946200 S2P_Bal_CellTempFault_104s_24 0 "Nomal" 1 "Fault" ;
VAL_ 2417946200 S2P_Bal_CellVoltFail_104s_24 0 "Nomal" 1 "Fault" ;
VAL_ 2417946200 S2P_Bal_CloseBalIstr_104s_24 0 "Nomal" 1 "Fault" ;
VAL_ 2417946200 S2P_Bal_CCanTimeOut_104s_24 0 "Nomal" 1 "Fault" ;
VAL_ 2417946200 S2P_Bal_BalanCirFlt_104s_24 0 "Nomal" 1 "Fault" ;
VAL_ 2417946201 S2P_Bal_CSCNum_104s_25 0 "No CSC" 1 "CSC 1" 2 "CSC 2" 3 "CSC 3" 4 "CSC 4" 5 "CSC 5" 6 "CSC 6" 7 "CSC 7" 8 "CSC 8" 9 "CSC 9" 10 "CSC 10" 11 "CSC 11" 12 "CSC 12" 13 "CSC 13" 14 "CSC 14" 15 "CSC 15" 16 "CSC 16" 17 "CSC 17" 18 "CSC 18" 19 "CSC 19" 20 "CSC 20" 21 "CSC 21" 22 "CSC 22" 23 "CSC 23" 24 "CSC 24" 25 "CSC 25" 26 "CSC 26" 27 "CSC 27" 28 "CSC 28" 29 "CSC 29" 30 "CSC 30" 31 "CSC 31" ;
VAL_ 2417946201 S2P_Bal_CellNum_104s_25 1 "Cell 1" 2 "Cell 2" 3 "Cell 3" 4 "Cell 4" 5 "Cell 5" 6 "Cell 6" 7 "Cell 7" 8 "Cell 8" 9 "Cell 9" 10 "Cell 10" 11 "Cell 11" 12 "Cell 12" 13 "Cell 13" 14 "Cell 14" 15 "Cell 15" 16 "Cell 16" 127 "Null" ;
VAL_ 2417946201 S2P_Bal_Type_104s_25 0 "Balance stop" 1 "charge Balance" 2 "discharge Balance" ;
VAL_ 2417946201 S2P_Bal_TypeLevel_104s_25 0 "Not Balance" 1 "Low end Balance" 2 "High end Balance" 3 "Force Balance" ;
VAL_ 2417946201 S2P_Bal_Strategy_104s_25 0 "Active Balance" 1 "Passive Static" ;
VAL_ 2417946201 S2P_Bal_ForceBalMode_104s_25 1 "Base on time " 2 "Base on Target Vol" 3 "Base on Ave Vol" ;
VAL_ 2417946201 S2P_Bal_CellTempFault_104s_25 0 "Nomal" 1 "Fault" ;
VAL_ 2417946201 S2P_Bal_CellVoltFail_104s_25 0 "Nomal" 1 "Fault" ;
VAL_ 2417946201 S2P_Bal_CloseBalIstr_104s_25 0 "Nomal" 1 "Fault" ;
VAL_ 2417946201 S2P_Bal_CCanTimeOut_104s_25 0 "Nomal" 1 "Fault" ;
VAL_ 2417946201 S2P_Bal_BalanCirFlt_104s_25 0 "Nomal" 1 "Fault" ;
VAL_ 2417946202 S2P_Bal_CSCNum_104s_26 0 "No CSC" 1 "CSC 1" 2 "CSC 2" 3 "CSC 3" 4 "CSC 4" 5 "CSC 5" 6 "CSC 6" 7 "CSC 7" 8 "CSC 8" 9 "CSC 9" 10 "CSC 10" 11 "CSC 11" 12 "CSC 12" 13 "CSC 13" 14 "CSC 14" 15 "CSC 15" 16 "CSC 16" 17 "CSC 17" 18 "CSC 18" 19 "CSC 19" 20 "CSC 20" 21 "CSC 21" 22 "CSC 22" 23 "CSC 23" 24 "CSC 24" 25 "CSC 25" 26 "CSC 26" 27 "CSC 27" 28 "CSC 28" 29 "CSC 29" 30 "CSC 30" 31 "CSC 31" ;
VAL_ 2417946202 S2P_Bal_CellNum_104s_26 1 "Cell 1" 2 "Cell 2" 3 "Cell 3" 4 "Cell 4" 5 "Cell 5" 6 "Cell 6" 7 "Cell 7" 8 "Cell 8" 9 "Cell 9" 10 "Cell 10" 11 "Cell 11" 12 "Cell 12" 13 "Cell 13" 14 "Cell 14" 15 "Cell 15" 16 "Cell 16" 127 "Null" ;
VAL_ 2417946202 S2P_Bal_Type_104s_26 0 "Balance stop" 1 "charge Balance" 2 "discharge Balance" ;
VAL_ 2417946202 S2P_Bal_TypeLevel_104s_26 0 "Not Balance" 1 "Low end Balance" 2 "High end Balance" 3 "Force Balance" ;
VAL_ 2417946202 S2P_Bal_Strategy_104s_26 0 "Active Balance" 1 "Passive Static" ;
VAL_ 2417946202 S2P_Bal_ForceBalMode_104s_26 1 "Base on time " 2 "Base on Target Vol" 3 "Base on Ave Vol" ;
VAL_ 2417946202 S2P_Bal_CellTempFault_104s_26 0 "Nomal" 1 "Fault" ;
VAL_ 2417946202 S2P_Bal_CellVoltFail_104s_26 0 "Nomal" 1 "Fault" ;
VAL_ 2417946202 S2P_Bal_CloseBalIstr_104s_26 0 "Nomal" 1 "Fault" ;
VAL_ 2417946202 S2P_Bal_CCanTimeOut_104s_26 0 "Nomal" 1 "Fault" ;
VAL_ 2417946202 S2P_Bal_BalanCirFlt_104s_26 0 "Nomal" 1 "Fault" ;
VAL_ 2417946203 S2P_Bal_CSCNum_104s_27 0 "No CSC" 1 "CSC 1" 2 "CSC 2" 3 "CSC 3" 4 "CSC 4" 5 "CSC 5" 6 "CSC 6" 7 "CSC 7" 8 "CSC 8" 9 "CSC 9" 10 "CSC 10" 11 "CSC 11" 12 "CSC 12" 13 "CSC 13" 14 "CSC 14" 15 "CSC 15" 16 "CSC 16" 17 "CSC 17" 18 "CSC 18" 19 "CSC 19" 20 "CSC 20" 21 "CSC 21" 22 "CSC 22" 23 "CSC 23" 24 "CSC 24" 25 "CSC 25" 26 "CSC 26" 27 "CSC 27" 28 "CSC 28" 29 "CSC 29" 30 "CSC 30" 31 "CSC 31" ;
VAL_ 2417946203 S2P_Bal_CellNum_104s_27 1 "Cell 1" 2 "Cell 2" 3 "Cell 3" 4 "Cell 4" 5 "Cell 5" 6 "Cell 6" 7 "Cell 7" 8 "Cell 8" 9 "Cell 9" 10 "Cell 10" 11 "Cell 11" 12 "Cell 12" 13 "Cell 13" 14 "Cell 14" 15 "Cell 15" 16 "Cell 16" 127 "Null" ;
VAL_ 2417946203 S2P_Bal_Type_104s_27 0 "Balance stop" 1 "charge Balance" 2 "discharge Balance" ;
VAL_ 2417946203 S2P_Bal_TypeLevel_104s_27 0 "Not Balance" 1 "Low end Balance" 2 "High end Balance" 3 "Force Balance" ;
VAL_ 2417946203 S2P_Bal_Strategy_104s_27 0 "Active Balance" 1 "Passive Static" ;
VAL_ 2417946203 S2P_Bal_ForceBalMode_104s_27 1 "Base on time " 2 "Base on Target Vol" 3 "Base on Ave Vol" ;
VAL_ 2417946203 S2P_Bal_CellTempFault_104s_27 0 "Nomal" 1 "Fault" ;
VAL_ 2417946203 S2P_Bal_CellVoltFail_104s_27 0 "Nomal" 1 "Fault" ;
VAL_ 2417946203 S2P_Bal_CloseBalIstr_104s_27 0 "Nomal" 1 "Fault" ;
VAL_ 2417946203 S2P_Bal_CCanTimeOut_104s_27 0 "Nomal" 1 "Fault" ;
VAL_ 2417946203 S2P_Bal_BalanCirFlt_104s_27 0 "Nomal" 1 "Fault" ;
VAL_ 2417946204 S2P_Bal_CSCNum_104s_28 0 "No CSC" 1 "CSC 1" 2 "CSC 2" 3 "CSC 3" 4 "CSC 4" 5 "CSC 5" 6 "CSC 6" 7 "CSC 7" 8 "CSC 8" 9 "CSC 9" 10 "CSC 10" 11 "CSC 11" 12 "CSC 12" 13 "CSC 13" 14 "CSC 14" 15 "CSC 15" 16 "CSC 16" 17 "CSC 17" 18 "CSC 18" 19 "CSC 19" 20 "CSC 20" 21 "CSC 21" 22 "CSC 22" 23 "CSC 23" 24 "CSC 24" 25 "CSC 25" 26 "CSC 26" 27 "CSC 27" 28 "CSC 28" 29 "CSC 29" 30 "CSC 30" 31 "CSC 31" ;
VAL_ 2417946204 S2P_Bal_CellNum_104s_28 1 "Cell 1" 2 "Cell 2" 3 "Cell 3" 4 "Cell 4" 5 "Cell 5" 6 "Cell 6" 7 "Cell 7" 8 "Cell 8" 9 "Cell 9" 10 "Cell 10" 11 "Cell 11" 12 "Cell 12" 13 "Cell 13" 14 "Cell 14" 15 "Cell 15" 16 "Cell 16" 127 "Null" ;
VAL_ 2417946204 S2P_Bal_Type_104s_28 0 "Balance stop" 1 "charge Balance" 2 "discharge Balance" ;
VAL_ 2417946204 S2P_Bal_TypeLevel_104s_28 0 "Not Balance" 1 "Low end Balance" 2 "High end Balance" 3 "Force Balance" ;
VAL_ 2417946204 S2P_Bal_Strategy_104s_28 0 "Active Balance" 1 "Passive Static" ;
VAL_ 2417946204 S2P_Bal_ForceBalMode_104s_28 1 "Base on time " 2 "Base on Target Vol" 3 "Base on Ave Vol" ;
VAL_ 2417946204 S2P_Bal_CellTempFault_104s_28 0 "Nomal" 1 "Fault" ;
VAL_ 2417946204 S2P_Bal_CellVoltFail_104s_28 0 "Nomal" 1 "Fault" ;
VAL_ 2417946204 S2P_Bal_CloseBalIstr_104s_28 0 "Nomal" 1 "Fault" ;
VAL_ 2417946204 S2P_Bal_CCanTimeOut_104s_28 0 "Nomal" 1 "Fault" ;
VAL_ 2417946204 S2P_Bal_BalanCirFlt_104s_28 0 "Nomal" 1 "Fault" ;
VAL_ 2417946205 S2P_Bal_CSCNum_104s_29 0 "No CSC" 1 "CSC 1" 2 "CSC 2" 3 "CSC 3" 4 "CSC 4" 5 "CSC 5" 6 "CSC 6" 7 "CSC 7" 8 "CSC 8" 9 "CSC 9" 10 "CSC 10" 11 "CSC 11" 12 "CSC 12" 13 "CSC 13" 14 "CSC 14" 15 "CSC 15" 16 "CSC 16" 17 "CSC 17" 18 "CSC 18" 19 "CSC 19" 20 "CSC 20" 21 "CSC 21" 22 "CSC 22" 23 "CSC 23" 24 "CSC 24" 25 "CSC 25" 26 "CSC 26" 27 "CSC 27" 28 "CSC 28" 29 "CSC 29" 30 "CSC 30" 31 "CSC 31" ;
VAL_ 2417946205 S2P_Bal_CellNum_104s_29 1 "Cell 1" 2 "Cell 2" 3 "Cell 3" 4 "Cell 4" 5 "Cell 5" 6 "Cell 6" 7 "Cell 7" 8 "Cell 8" 9 "Cell 9" 10 "Cell 10" 11 "Cell 11" 12 "Cell 12" 13 "Cell 13" 14 "Cell 14" 15 "Cell 15" 16 "Cell 16" 127 "Null" ;
VAL_ 2417946205 S2P_Bal_Type_104s_29 0 "Balance stop" 1 "charge Balance" 2 "discharge Balance" ;
VAL_ 2417946205 S2P_Bal_TypeLevel_104s_29 0 "Not Balance" 1 "Low end Balance" 2 "High end Balance" 3 "Force Balance" ;
VAL_ 2417946205 S2P_Bal_Strategy_104s_29 0 "Active Balance" 1 "Passive Static" ;
VAL_ 2417946205 S2P_Bal_ForceBalMode_104s_29 1 "Base on time " 2 "Base on Target Vol" 3 "Base on Ave Vol" ;
VAL_ 2417946205 S2P_Bal_CellTempFault_104s_29 0 "Nomal" 1 "Fault" ;
VAL_ 2417946205 S2P_Bal_CellVoltFail_104s_29 0 "Nomal" 1 "Fault" ;
VAL_ 2417946205 S2P_Bal_CloseBalIstr_104s_29 0 "Nomal" 1 "Fault" ;
VAL_ 2417946205 S2P_Bal_CCanTimeOut_104s_29 0 "Nomal" 1 "Fault" ;
VAL_ 2417946205 S2P_Bal_BalanCirFlt_104s_29 0 "Nomal" 1 "Fault" ;
VAL_ 2417946206 S2P_Bal_CSCNum_104s_30 0 "No CSC" 1 "CSC 1" 2 "CSC 2" 3 "CSC 3" 4 "CSC 4" 5 "CSC 5" 6 "CSC 6" 7 "CSC 7" 8 "CSC 8" 9 "CSC 9" 10 "CSC 10" 11 "CSC 11" 12 "CSC 12" 13 "CSC 13" 14 "CSC 14" 15 "CSC 15" 16 "CSC 16" 17 "CSC 17" 18 "CSC 18" 19 "CSC 19" 20 "CSC 20" 21 "CSC 21" 22 "CSC 22" 23 "CSC 23" 24 "CSC 24" 25 "CSC 25" 26 "CSC 26" 27 "CSC 27" 28 "CSC 28" 29 "CSC 29" 30 "CSC 30" 31 "CSC 31" ;
VAL_ 2417946206 S2P_Bal_CellNum_104s_30 1 "Cell 1" 2 "Cell 2" 3 "Cell 3" 4 "Cell 4" 5 "Cell 5" 6 "Cell 6" 7 "Cell 7" 8 "Cell 8" 9 "Cell 9" 10 "Cell 10" 11 "Cell 11" 12 "Cell 12" 13 "Cell 13" 14 "Cell 14" 15 "Cell 15" 16 "Cell 16" 127 "Null" ;
VAL_ 2417946206 S2P_Bal_Type_104s_30 0 "Balance stop" 1 "charge Balance" 2 "discharge Balance" ;
VAL_ 2417946206 S2P_Bal_TypeLevel_104s_30 0 "Not Balance" 1 "Low end Balance" 2 "High end Balance" 3 "Force Balance" ;
VAL_ 2417946206 S2P_Bal_Strategy_104s_30 0 "Active Balance" 1 "Passive Static" ;
VAL_ 2417946206 S2P_Bal_ForceBalMode_104s_30 1 "Base on time " 2 "Base on Target Vol" 3 "Base on Ave Vol" ;
VAL_ 2417946206 S2P_Bal_CellTempFault_104s_30 0 "Nomal" 1 "Fault" ;
VAL_ 2417946206 S2P_Bal_CellVoltFail_104s_30 0 "Nomal" 1 "Fault" ;
VAL_ 2417946206 S2P_Bal_CloseBalIstr_104s_30 0 "Nomal" 1 "Fault" ;
VAL_ 2417946206 S2P_Bal_CCanTimeOut_104s_30 0 "Nomal" 1 "Fault" ;
VAL_ 2417946206 S2P_Bal_BalanCirFlt_104s_30 0 "Nomal" 1 "Fault" ;
VAL_ 2417946207 S2P_Bal_CSCNum_104s_31 0 "No CSC" 1 "CSC 1" 2 "CSC 2" 3 "CSC 3" 4 "CSC 4" 5 "CSC 5" 6 "CSC 6" 7 "CSC 7" 8 "CSC 8" 9 "CSC 9" 10 "CSC 10" 11 "CSC 11" 12 "CSC 12" 13 "CSC 13" 14 "CSC 14" 15 "CSC 15" 16 "CSC 16" 17 "CSC 17" 18 "CSC 18" 19 "CSC 19" 20 "CSC 20" 21 "CSC 21" 22 "CSC 22" 23 "CSC 23" 24 "CSC 24" 25 "CSC 25" 26 "CSC 26" 27 "CSC 27" 28 "CSC 28" 29 "CSC 29" 30 "CSC 30" 31 "CSC 31" ;
VAL_ 2417946207 S2P_Bal_CellNum_104s_31 1 "Cell 1" 2 "Cell 2" 3 "Cell 3" 4 "Cell 4" 5 "Cell 5" 6 "Cell 6" 7 "Cell 7" 8 "Cell 8" 9 "Cell 9" 10 "Cell 10" 11 "Cell 11" 12 "Cell 12" 13 "Cell 13" 14 "Cell 14" 15 "Cell 15" 16 "Cell 16" 127 "Null" ;
VAL_ 2417946207 S2P_Bal_Type_104s_31 0 "Balance stop" 1 "charge Balance" 2 "discharge Balance" ;
VAL_ 2417946207 S2P_Bal_TypeLevel_104s_31 0 "Not Balance" 1 "Low end Balance" 2 "High end Balance" 3 "Force Balance" ;
VAL_ 2417946207 S2P_Bal_Strategy_104s_31 0 "Active Balance" 1 "Passive Static" ;
VAL_ 2417946207 S2P_Bal_ForceBalMode_104s_31 1 "Base on time " 2 "Base on Target Vol" 3 "Base on Ave Vol" ;
VAL_ 2417946207 S2P_Bal_CellTempFault_104s_31 0 "Nomal" 1 "Fault" ;
VAL_ 2417946207 S2P_Bal_CellVoltFail_104s_31 0 "Nomal" 1 "Fault" ;
VAL_ 2417946207 S2P_Bal_CloseBalIstr_104s_31 0 "Nomal" 1 "Fault" ;
VAL_ 2417946207 S2P_Bal_CCanTimeOut_104s_31 0 "Nomal" 1 "Fault" ;
VAL_ 2417946207 S2P_Bal_BalanCirFlt_104s_31 0 "Nomal" 1 "Fault" ;
VAL_ 2417946208 S2P_Bal_CSCNum_104s_32 0 "No CSC" 1 "CSC 1" 2 "CSC 2" 3 "CSC 3" 4 "CSC 4" 5 "CSC 5" 6 "CSC 6" 7 "CSC 7" 8 "CSC 8" 9 "CSC 9" 10 "CSC 10" 11 "CSC 11" 12 "CSC 12" 13 "CSC 13" 14 "CSC 14" 15 "CSC 15" 16 "CSC 16" 17 "CSC 17" 18 "CSC 18" 19 "CSC 19" 20 "CSC 20" 21 "CSC 21" 22 "CSC 22" 23 "CSC 23" 24 "CSC 24" 25 "CSC 25" 26 "CSC 26" 27 "CSC 27" 28 "CSC 28" 29 "CSC 29" 30 "CSC 30" 31 "CSC 31" ;
VAL_ 2417946208 S2P_Bal_CellNum_104s_32 1 "Cell 1" 2 "Cell 2" 3 "Cell 3" 4 "Cell 4" 5 "Cell 5" 6 "Cell 6" 7 "Cell 7" 8 "Cell 8" 9 "Cell 9" 10 "Cell 10" 11 "Cell 11" 12 "Cell 12" 13 "Cell 13" 14 "Cell 14" 15 "Cell 15" 16 "Cell 16" 127 "Null" ;
VAL_ 2417946208 S2P_Bal_Type_104s_32 0 "Balance stop" 1 "charge Balance" 2 "discharge Balance" ;
VAL_ 2417946208 S2P_Bal_TypeLevel_104s_32 0 "Not Balance" 1 "Low end Balance" 2 "High end Balance" 3 "Force Balance" ;
VAL_ 2417946208 S2P_Bal_Strategy_104s_32 0 "Active Balance" 1 "Passive Static" ;
VAL_ 2417946208 S2P_Bal_ForceBalMode_104s_32 1 "Base on time " 2 "Base on Target Vol" 3 "Base on Ave Vol" ;
VAL_ 2417946208 S2P_Bal_CellTempFault_104s_32 0 "Nomal" 1 "Fault" ;
VAL_ 2417946208 S2P_Bal_CellVoltFail_104s_32 0 "Nomal" 1 "Fault" ;
VAL_ 2417946208 S2P_Bal_CloseBalIstr_104s_32 0 "Nomal" 1 "Fault" ;
VAL_ 2417946208 S2P_Bal_CCanTimeOut_104s_32 0 "Nomal" 1 "Fault" ;
VAL_ 2417946208 S2P_Bal_BalanCirFlt_104s_32 0 "Nomal" 1 "Fault" ;
VAL_ 2417946209 S2P_Bal_CSCNum_104s_33 0 "No CSC" 1 "CSC 1" 2 "CSC 2" 3 "CSC 3" 4 "CSC 4" 5 "CSC 5" 6 "CSC 6" 7 "CSC 7" 8 "CSC 8" 9 "CSC 9" 10 "CSC 10" 11 "CSC 11" 12 "CSC 12" 13 "CSC 13" 14 "CSC 14" 15 "CSC 15" 16 "CSC 16" 17 "CSC 17" 18 "CSC 18" 19 "CSC 19" 20 "CSC 20" 21 "CSC 21" 22 "CSC 22" 23 "CSC 23" 24 "CSC 24" 25 "CSC 25" 26 "CSC 26" 27 "CSC 27" 28 "CSC 28" 29 "CSC 29" 30 "CSC 30" 31 "CSC 31" ;
VAL_ 2417946209 S2P_Bal_CellNum_104s_33 1 "Cell 1" 2 "Cell 2" 3 "Cell 3" 4 "Cell 4" 5 "Cell 5" 6 "Cell 6" 7 "Cell 7" 8 "Cell 8" 9 "Cell 9" 10 "Cell 10" 11 "Cell 11" 12 "Cell 12" 13 "Cell 13" 14 "Cell 14" 15 "Cell 15" 16 "Cell 16" 127 "Null" ;
VAL_ 2417946209 S2P_Bal_Type_104s_33 0 "Balance stop" 1 "charge Balance" 2 "discharge Balance" ;
VAL_ 2417946209 S2P_Bal_TypeLevel_104s_33 0 "Not Balance" 1 "Low end Balance" 2 "High end Balance" 3 "Force Balance" ;
VAL_ 2417946209 S2P_Bal_Strategy_104s_33 0 "Active Balance" 1 "Passive Static" ;
VAL_ 2417946209 S2P_Bal_ForceBalMode_104s_33 1 "Base on time " 2 "Base on Target Vol" 3 "Base on Ave Vol" ;
VAL_ 2417946209 S2P_Bal_CellTempFault_104s_33 0 "Nomal" 1 "Fault" ;
VAL_ 2417946209 S2P_Bal_CellVoltFail_104s_33 0 "Nomal" 1 "Fault" ;
VAL_ 2417946209 S2P_Bal_CloseBalIstr_104s_33 0 "Nomal" 1 "Fault" ;
VAL_ 2417946209 S2P_Bal_CCanTimeOut_104s_33 0 "Nomal" 1 "Fault" ;
VAL_ 2417946209 S2P_Bal_BalanCirFlt_104s_33 0 "Nomal" 1 "Fault" ;
VAL_ 2417946210 S2P_Bal_CSCNum_104s_34 0 "No CSC" 1 "CSC 1" 2 "CSC 2" 3 "CSC 3" 4 "CSC 4" 5 "CSC 5" 6 "CSC 6" 7 "CSC 7" 8 "CSC 8" 9 "CSC 9" 10 "CSC 10" 11 "CSC 11" 12 "CSC 12" 13 "CSC 13" 14 "CSC 14" 15 "CSC 15" 16 "CSC 16" 17 "CSC 17" 18 "CSC 18" 19 "CSC 19" 20 "CSC 20" 21 "CSC 21" 22 "CSC 22" 23 "CSC 23" 24 "CSC 24" 25 "CSC 25" 26 "CSC 26" 27 "CSC 27" 28 "CSC 28" 29 "CSC 29" 30 "CSC 30" 31 "CSC 31" ;
VAL_ 2417946210 S2P_Bal_CellNum_104s_34 1 "Cell 1" 2 "Cell 2" 3 "Cell 3" 4 "Cell 4" 5 "Cell 5" 6 "Cell 6" 7 "Cell 7" 8 "Cell 8" 9 "Cell 9" 10 "Cell 10" 11 "Cell 11" 12 "Cell 12" 13 "Cell 13" 14 "Cell 14" 15 "Cell 15" 16 "Cell 16" 127 "Null" ;
VAL_ 2417946210 S2P_Bal_Type_104s_34 0 "Balance stop" 1 "charge Balance" 2 "discharge Balance" ;
VAL_ 2417946210 S2P_Bal_TypeLevel_104s_34 0 "Not Balance" 1 "Low end Balance" 2 "High end Balance" 3 "Force Balance" ;
VAL_ 2417946210 S2P_Bal_Strategy_104s_34 0 "Active Balance" 1 "Passive Static" ;
VAL_ 2417946210 S2P_Bal_ForceBalMode_104s_34 1 "Base on time " 2 "Base on Target Vol" 3 "Base on Ave Vol" ;
VAL_ 2417946210 S2P_Bal_CellTempFault_104s_34 0 "Nomal" 1 "Fault" ;
VAL_ 2417946210 S2P_Bal_CellVoltFail_104s_34 0 "Nomal" 1 "Fault" ;
VAL_ 2417946210 S2P_Bal_CloseBalIstr_104s_34 0 "Nomal" 1 "Fault" ;
VAL_ 2417946210 S2P_Bal_CCanTimeOut_104s_34 0 "Nomal" 1 "Fault" ;
VAL_ 2417946210 S2P_Bal_BalanCirFlt_104s_34 0 "Nomal" 1 "Fault" ;
VAL_ 2417946211 S2P_Bal_CSCNum_104s_35 0 "No CSC" 1 "CSC 1" 2 "CSC 2" 3 "CSC 3" 4 "CSC 4" 5 "CSC 5" 6 "CSC 6" 7 "CSC 7" 8 "CSC 8" 9 "CSC 9" 10 "CSC 10" 11 "CSC 11" 12 "CSC 12" 13 "CSC 13" 14 "CSC 14" 15 "CSC 15" 16 "CSC 16" 17 "CSC 17" 18 "CSC 18" 19 "CSC 19" 20 "CSC 20" 21 "CSC 21" 22 "CSC 22" 23 "CSC 23" 24 "CSC 24" 25 "CSC 25" 26 "CSC 26" 27 "CSC 27" 28 "CSC 28" 29 "CSC 29" 30 "CSC 30" 31 "CSC 31" ;
VAL_ 2417946211 S2P_Bal_CellNum_104s_35 1 "Cell 1" 2 "Cell 2" 3 "Cell 3" 4 "Cell 4" 5 "Cell 5" 6 "Cell 6" 7 "Cell 7" 8 "Cell 8" 9 "Cell 9" 10 "Cell 10" 11 "Cell 11" 12 "Cell 12" 13 "Cell 13" 14 "Cell 14" 15 "Cell 15" 16 "Cell 16" 127 "Null" ;
VAL_ 2417946211 S2P_Bal_Type_104s_35 0 "Balance stop" 1 "charge Balance" 2 "discharge Balance" ;
VAL_ 2417946211 S2P_Bal_TypeLevel_104s_35 0 "Not Balance" 1 "Low end Balance" 2 "High end Balance" 3 "Force Balance" ;
VAL_ 2417946211 S2P_Bal_Strategy_104s_35 0 "Active Balance" 1 "Passive Static" ;
VAL_ 2417946211 S2P_Bal_ForceBalMode_104s_35 1 "Base on time " 2 "Base on Target Vol" 3 "Base on Ave Vol" ;
VAL_ 2417946211 S2P_Bal_CellTempFault_104s_35 0 "Nomal" 1 "Fault" ;
VAL_ 2417946211 S2P_Bal_CellVoltFail_104s_35 0 "Nomal" 1 "Fault" ;
VAL_ 2417946211 S2P_Bal_CloseBalIstr_104s_35 0 "Nomal" 1 "Fault" ;
VAL_ 2417946211 S2P_Bal_CCanTimeOut_104s_35 0 "Nomal" 1 "Fault" ;
VAL_ 2417946211 S2P_Bal_BalanCirFlt_104s_35 0 "Nomal" 1 "Fault" ;
VAL_ 2417946212 S2P_Bal_CSCNum_104s_36 0 "No CSC" 1 "CSC 1" 2 "CSC 2" 3 "CSC 3" 4 "CSC 4" 5 "CSC 5" 6 "CSC 6" 7 "CSC 7" 8 "CSC 8" 9 "CSC 9" 10 "CSC 10" 11 "CSC 11" 12 "CSC 12" 13 "CSC 13" 14 "CSC 14" 15 "CSC 15" 16 "CSC 16" 17 "CSC 17" 18 "CSC 18" 19 "CSC 19" 20 "CSC 20" 21 "CSC 21" 22 "CSC 22" 23 "CSC 23" 24 "CSC 24" 25 "CSC 25" 26 "CSC 26" 27 "CSC 27" 28 "CSC 28" 29 "CSC 29" 30 "CSC 30" 31 "CSC 31" ;
VAL_ 2417946212 S2P_Bal_CellNum_104s_36 1 "Cell 1" 2 "Cell 2" 3 "Cell 3" 4 "Cell 4" 5 "Cell 5" 6 "Cell 6" 7 "Cell 7" 8 "Cell 8" 9 "Cell 9" 10 "Cell 10" 11 "Cell 11" 12 "Cell 12" 13 "Cell 13" 14 "Cell 14" 15 "Cell 15" 16 "Cell 16" 127 "Null" ;
VAL_ 2417946212 S2P_Bal_Type_104s_36 0 "Balance stop" 1 "charge Balance" 2 "discharge Balance" ;
VAL_ 2417946212 S2P_Bal_TypeLevel_104s_36 0 "Not Balance" 1 "Low end Balance" 2 "High end Balance" 3 "Force Balance" ;
VAL_ 2417946212 S2P_Bal_Strategy_104s_36 0 "Active Balance" 1 "Passive Static" ;
VAL_ 2417946212 S2P_Bal_ForceBalMode_104s_36 1 "Base on time " 2 "Base on Target Vol" 3 "Base on Ave Vol" ;
VAL_ 2417946212 S2P_Bal_CellTempFault_104s_36 0 "Nomal" 1 "Fault" ;
VAL_ 2417946212 S2P_Bal_CellVoltFail_104s_36 0 "Nomal" 1 "Fault" ;
VAL_ 2417946212 S2P_Bal_CloseBalIstr_104s_36 0 "Nomal" 1 "Fault" ;
VAL_ 2417946212 S2P_Bal_CCanTimeOut_104s_36 0 "Nomal" 1 "Fault" ;
VAL_ 2417946212 S2P_Bal_BalanCirFlt_104s_36 0 "Nomal" 1 "Fault" ;
VAL_ 2417946213 S2P_Bal_CSCNum_104s_37 0 "No CSC" 1 "CSC 1" 2 "CSC 2" 3 "CSC 3" 4 "CSC 4" 5 "CSC 5" 6 "CSC 6" 7 "CSC 7" 8 "CSC 8" 9 "CSC 9" 10 "CSC 10" 11 "CSC 11" 12 "CSC 12" 13 "CSC 13" 14 "CSC 14" 15 "CSC 15" 16 "CSC 16" 17 "CSC 17" 18 "CSC 18" 19 "CSC 19" 20 "CSC 20" 21 "CSC 21" 22 "CSC 22" 23 "CSC 23" 24 "CSC 24" 25 "CSC 25" 26 "CSC 26" 27 "CSC 27" 28 "CSC 28" 29 "CSC 29" 30 "CSC 30" 31 "CSC 31" ;
VAL_ 2417946213 S2P_Bal_CellNum_104s_37 1 "Cell 1" 2 "Cell 2" 3 "Cell 3" 4 "Cell 4" 5 "Cell 5" 6 "Cell 6" 7 "Cell 7" 8 "Cell 8" 9 "Cell 9" 10 "Cell 10" 11 "Cell 11" 12 "Cell 12" 13 "Cell 13" 14 "Cell 14" 15 "Cell 15" 16 "Cell 16" 127 "Null" ;
VAL_ 2417946213 S2P_Bal_Type_104s_37 0 "Balance stop" 1 "charge Balance" 2 "discharge Balance" ;
VAL_ 2417946213 S2P_Bal_TypeLevel_104s_37 0 "Not Balance" 1 "Low end Balance" 2 "High end Balance" 3 "Force Balance" ;
VAL_ 2417946213 S2P_Bal_Strategy_104s_37 0 "Active Balance" 1 "Passive Static" ;
VAL_ 2417946213 S2P_Bal_ForceBalMode_104s_37 1 "Base on time " 2 "Base on Target Vol" 3 "Base on Ave Vol" ;
VAL_ 2417946213 S2P_Bal_CellTempFault_104s_37 0 "Nomal" 1 "Fault" ;
VAL_ 2417946213 S2P_Bal_CellVoltFail_104s_37 0 "Nomal" 1 "Fault" ;
VAL_ 2417946213 S2P_Bal_CloseBalIstr_104s_37 0 "Nomal" 1 "Fault" ;
VAL_ 2417946213 S2P_Bal_CCanTimeOut_104s_37 0 "Nomal" 1 "Fault" ;
VAL_ 2417946213 S2P_Bal_BalanCirFlt_104s_37 0 "Nomal" 1 "Fault" ;
VAL_ 2417946214 S2P_Bal_CSCNum_104s_38 0 "No CSC" 1 "CSC 1" 2 "CSC 2" 3 "CSC 3" 4 "CSC 4" 5 "CSC 5" 6 "CSC 6" 7 "CSC 7" 8 "CSC 8" 9 "CSC 9" 10 "CSC 10" 11 "CSC 11" 12 "CSC 12" 13 "CSC 13" 14 "CSC 14" 15 "CSC 15" 16 "CSC 16" 17 "CSC 17" 18 "CSC 18" 19 "CSC 19" 20 "CSC 20" 21 "CSC 21" 22 "CSC 22" 23 "CSC 23" 24 "CSC 24" 25 "CSC 25" 26 "CSC 26" 27 "CSC 27" 28 "CSC 28" 29 "CSC 29" 30 "CSC 30" 31 "CSC 31" ;
VAL_ 2417946214 S2P_Bal_CellNum_104s_38 1 "Cell 1" 2 "Cell 2" 3 "Cell 3" 4 "Cell 4" 5 "Cell 5" 6 "Cell 6" 7 "Cell 7" 8 "Cell 8" 9 "Cell 9" 10 "Cell 10" 11 "Cell 11" 12 "Cell 12" 13 "Cell 13" 14 "Cell 14" 15 "Cell 15" 16 "Cell 16" 127 "Null" ;
VAL_ 2417946214 S2P_Bal_Type_104s_38 0 "Balance stop" 1 "charge Balance" 2 "discharge Balance" ;
VAL_ 2417946214 S2P_Bal_TypeLevel_104s_38 0 "Not Balance" 1 "Low end Balance" 2 "High end Balance" 3 "Force Balance" ;
VAL_ 2417946214 S2P_Bal_Strategy_104s_38 0 "Active Balance" 1 "Passive Static" ;
VAL_ 2417946214 S2P_Bal_ForceBalMode_104s_38 1 "Base on time " 2 "Base on Target Vol" 3 "Base on Ave Vol" ;
VAL_ 2417946214 S2P_Bal_CellTempFault_104s_38 0 "Nomal" 1 "Fault" ;
VAL_ 2417946214 S2P_Bal_CellVoltFail_104s_38 0 "Nomal" 1 "Fault" ;
VAL_ 2417946214 S2P_Bal_CloseBalIstr_104s_38 0 "Nomal" 1 "Fault" ;
VAL_ 2417946214 S2P_Bal_CCanTimeOut_104s_38 0 "Nomal" 1 "Fault" ;
VAL_ 2417946214 S2P_Bal_BalanCirFlt_104s_38 0 "Nomal" 1 "Fault" ;
VAL_ 2417946215 S2P_Bal_CSCNum_104s_39 0 "No CSC" 1 "CSC 1" 2 "CSC 2" 3 "CSC 3" 4 "CSC 4" 5 "CSC 5" 6 "CSC 6" 7 "CSC 7" 8 "CSC 8" 9 "CSC 9" 10 "CSC 10" 11 "CSC 11" 12 "CSC 12" 13 "CSC 13" 14 "CSC 14" 15 "CSC 15" 16 "CSC 16" 17 "CSC 17" 18 "CSC 18" 19 "CSC 19" 20 "CSC 20" 21 "CSC 21" 22 "CSC 22" 23 "CSC 23" 24 "CSC 24" 25 "CSC 25" 26 "CSC 26" 27 "CSC 27" 28 "CSC 28" 29 "CSC 29" 30 "CSC 30" 31 "CSC 31" ;
VAL_ 2417946215 S2P_Bal_CellNum_104s_39 1 "Cell 1" 2 "Cell 2" 3 "Cell 3" 4 "Cell 4" 5 "Cell 5" 6 "Cell 6" 7 "Cell 7" 8 "Cell 8" 9 "Cell 9" 10 "Cell 10" 11 "Cell 11" 12 "Cell 12" 13 "Cell 13" 14 "Cell 14" 15 "Cell 15" 16 "Cell 16" 127 "Null" ;
VAL_ 2417946215 S2P_Bal_Type_104s_39 0 "Balance stop" 1 "charge Balance" 2 "discharge Balance" ;
VAL_ 2417946215 S2P_Bal_TypeLevel_104s_39 0 "Not Balance" 1 "Low end Balance" 2 "High end Balance" 3 "Force Balance" ;
VAL_ 2417946215 S2P_Bal_Strategy_104s_39 0 "Active Balance" 1 "Passive Static" ;
VAL_ 2417946215 S2P_Bal_ForceBalMode_104s_39 1 "Base on time " 2 "Base on Target Vol" 3 "Base on Ave Vol" ;
VAL_ 2417946215 S2P_Bal_CellTempFault_104s_39 0 "Nomal" 1 "Fault" ;
VAL_ 2417946215 S2P_Bal_CellVoltFail_104s_39 0 "Nomal" 1 "Fault" ;
VAL_ 2417946215 S2P_Bal_CloseBalIstr_104s_39 0 "Nomal" 1 "Fault" ;
VAL_ 2417946215 S2P_Bal_CCanTimeOut_104s_39 0 "Nomal" 1 "Fault" ;
VAL_ 2417946215 S2P_Bal_BalanCirFlt_104s_39 0 "Nomal" 1 "Fault" ;
VAL_ 2417946216 S2P_Bal_CSCNum_104s_40 0 "No CSC" 1 "CSC 1" 2 "CSC 2" 3 "CSC 3" 4 "CSC 4" 5 "CSC 5" 6 "CSC 6" 7 "CSC 7" 8 "CSC 8" 9 "CSC 9" 10 "CSC 10" 11 "CSC 11" 12 "CSC 12" 13 "CSC 13" 14 "CSC 14" 15 "CSC 15" 16 "CSC 16" 17 "CSC 17" 18 "CSC 18" 19 "CSC 19" 20 "CSC 20" 21 "CSC 21" 22 "CSC 22" 23 "CSC 23" 24 "CSC 24" 25 "CSC 25" 26 "CSC 26" 27 "CSC 27" 28 "CSC 28" 29 "CSC 29" 30 "CSC 30" 31 "CSC 31" ;
VAL_ 2417946216 S2P_Bal_CellNum_104s_40 1 "Cell 1" 2 "Cell 2" 3 "Cell 3" 4 "Cell 4" 5 "Cell 5" 6 "Cell 6" 7 "Cell 7" 8 "Cell 8" 9 "Cell 9" 10 "Cell 10" 11 "Cell 11" 12 "Cell 12" 13 "Cell 13" 14 "Cell 14" 15 "Cell 15" 16 "Cell 16" 127 "Null" ;
VAL_ 2417946216 S2P_Bal_Type_104s_40 0 "Balance stop" 1 "charge Balance" 2 "discharge Balance" ;
VAL_ 2417946216 S2P_Bal_TypeLevel_104s_40 0 "Not Balance" 1 "Low end Balance" 2 "High end Balance" 3 "Force Balance" ;
VAL_ 2417946216 S2P_Bal_Strategy_104s_40 0 "Active Balance" 1 "Passive Static" ;
VAL_ 2417946216 S2P_Bal_ForceBalMode_104s_40 1 "Base on time " 2 "Base on Target Vol" 3 "Base on Ave Vol" ;
VAL_ 2417946216 S2P_Bal_CellTempFault_104s_40 0 "Nomal" 1 "Fault" ;
VAL_ 2417946216 S2P_Bal_CellVoltFail_104s_40 0 "Nomal" 1 "Fault" ;
VAL_ 2417946216 S2P_Bal_CloseBalIstr_104s_40 0 "Nomal" 1 "Fault" ;
VAL_ 2417946216 S2P_Bal_CCanTimeOut_104s_40 0 "Nomal" 1 "Fault" ;
VAL_ 2417946216 S2P_Bal_BalanCirFlt_104s_40 0 "Nomal" 1 "Fault" ;
VAL_ 2417946217 S2P_Bal_CSCNum_104s_41 0 "No CSC" 1 "CSC 1" 2 "CSC 2" 3 "CSC 3" 4 "CSC 4" 5 "CSC 5" 6 "CSC 6" 7 "CSC 7" 8 "CSC 8" 9 "CSC 9" 10 "CSC 10" 11 "CSC 11" 12 "CSC 12" 13 "CSC 13" 14 "CSC 14" 15 "CSC 15" 16 "CSC 16" 17 "CSC 17" 18 "CSC 18" 19 "CSC 19" 20 "CSC 20" 21 "CSC 21" 22 "CSC 22" 23 "CSC 23" 24 "CSC 24" 25 "CSC 25" 26 "CSC 26" 27 "CSC 27" 28 "CSC 28" 29 "CSC 29" 30 "CSC 30" 31 "CSC 31" ;
VAL_ 2417946217 S2P_Bal_CellNum_104s_41 1 "Cell 1" 2 "Cell 2" 3 "Cell 3" 4 "Cell 4" 5 "Cell 5" 6 "Cell 6" 7 "Cell 7" 8 "Cell 8" 9 "Cell 9" 10 "Cell 10" 11 "Cell 11" 12 "Cell 12" 13 "Cell 13" 14 "Cell 14" 15 "Cell 15" 16 "Cell 16" 127 "Null" ;
VAL_ 2417946217 S2P_Bal_Type_104s_41 0 "Balance stop" 1 "charge Balance" 2 "discharge Balance" ;
VAL_ 2417946217 S2P_Bal_TypeLevel_104s_41 0 "Not Balance" 1 "Low end Balance" 2 "High end Balance" 3 "Force Balance" ;
VAL_ 2417946217 S2P_Bal_Strategy_104s_41 0 "Active Balance" 1 "Passive Static" ;
VAL_ 2417946217 S2P_Bal_ForceBalMode_104s_41 1 "Base on time " 2 "Base on Target Vol" 3 "Base on Ave Vol" ;
VAL_ 2417946217 S2P_Bal_CellTempFault_104s_41 0 "Nomal" 1 "Fault" ;
VAL_ 2417946217 S2P_Bal_CellVoltFail_104s_41 0 "Nomal" 1 "Fault" ;
VAL_ 2417946217 S2P_Bal_CloseBalIstr_104s_41 0 "Nomal" 1 "Fault" ;
VAL_ 2417946217 S2P_Bal_CCanTimeOut_104s_41 0 "Nomal" 1 "Fault" ;
VAL_ 2417946217 S2P_Bal_BalanCirFlt_104s_41 0 "Nomal" 1 "Fault" ;
VAL_ 2417946218 S2P_Bal_CSCNum_104s_42 0 "No CSC" 1 "CSC 1" 2 "CSC 2" 3 "CSC 3" 4 "CSC 4" 5 "CSC 5" 6 "CSC 6" 7 "CSC 7" 8 "CSC 8" 9 "CSC 9" 10 "CSC 10" 11 "CSC 11" 12 "CSC 12" 13 "CSC 13" 14 "CSC 14" 15 "CSC 15" 16 "CSC 16" 17 "CSC 17" 18 "CSC 18" 19 "CSC 19" 20 "CSC 20" 21 "CSC 21" 22 "CSC 22" 23 "CSC 23" 24 "CSC 24" 25 "CSC 25" 26 "CSC 26" 27 "CSC 27" 28 "CSC 28" 29 "CSC 29" 30 "CSC 30" 31 "CSC 31" ;
VAL_ 2417946218 S2P_Bal_CellNum_104s_42 1 "Cell 1" 2 "Cell 2" 3 "Cell 3" 4 "Cell 4" 5 "Cell 5" 6 "Cell 6" 7 "Cell 7" 8 "Cell 8" 9 "Cell 9" 10 "Cell 10" 11 "Cell 11" 12 "Cell 12" 13 "Cell 13" 14 "Cell 14" 15 "Cell 15" 16 "Cell 16" 127 "Null" ;
VAL_ 2417946218 S2P_Bal_Type_104s_42 0 "Balance stop" 1 "charge Balance" 2 "discharge Balance" ;
VAL_ 2417946218 S2P_Bal_TypeLevel_104s_42 0 "Not Balance" 1 "Low end Balance" 2 "High end Balance" 3 "Force Balance" ;
VAL_ 2417946218 S2P_Bal_Strategy_104s_42 0 "Active Balance" 1 "Passive Static" ;
VAL_ 2417946218 S2P_Bal_ForceBalMode_104s_42 1 "Base on time " 2 "Base on Target Vol" 3 "Base on Ave Vol" ;
VAL_ 2417946218 S2P_Bal_CellTempFault_104s_42 0 "Nomal" 1 "Fault" ;
VAL_ 2417946218 S2P_Bal_CellVoltFail_104s_42 0 "Nomal" 1 "Fault" ;
VAL_ 2417946218 S2P_Bal_CloseBalIstr_104s_42 0 "Nomal" 1 "Fault" ;
VAL_ 2417946218 S2P_Bal_CCanTimeOut_104s_42 0 "Nomal" 1 "Fault" ;
VAL_ 2417946218 S2P_Bal_BalanCirFlt_104s_42 0 "Nomal" 1 "Fault" ;
VAL_ 2417946219 S2P_Bal_CSCNum_104s_43 0 "No CSC" 1 "CSC 1" 2 "CSC 2" 3 "CSC 3" 4 "CSC 4" 5 "CSC 5" 6 "CSC 6" 7 "CSC 7" 8 "CSC 8" 9 "CSC 9" 10 "CSC 10" 11 "CSC 11" 12 "CSC 12" 13 "CSC 13" 14 "CSC 14" 15 "CSC 15" 16 "CSC 16" 17 "CSC 17" 18 "CSC 18" 19 "CSC 19" 20 "CSC 20" 21 "CSC 21" 22 "CSC 22" 23 "CSC 23" 24 "CSC 24" 25 "CSC 25" 26 "CSC 26" 27 "CSC 27" 28 "CSC 28" 29 "CSC 29" 30 "CSC 30" 31 "CSC 31" ;
VAL_ 2417946219 S2P_Bal_CellNum_104s_43 1 "Cell 1" 2 "Cell 2" 3 "Cell 3" 4 "Cell 4" 5 "Cell 5" 6 "Cell 6" 7 "Cell 7" 8 "Cell 8" 9 "Cell 9" 10 "Cell 10" 11 "Cell 11" 12 "Cell 12" 13 "Cell 13" 14 "Cell 14" 15 "Cell 15" 16 "Cell 16" 127 "Null" ;
VAL_ 2417946219 S2P_Bal_Type_104s_43 0 "Balance stop" 1 "charge Balance" 2 "discharge Balance" ;
VAL_ 2417946219 S2P_Bal_TypeLevel_104s_43 0 "Not Balance" 1 "Low end Balance" 2 "High end Balance" 3 "Force Balance" ;
VAL_ 2417946219 S2P_Bal_Strategy_104s_43 0 "Active Balance" 1 "Passive Static" ;
VAL_ 2417946219 S2P_Bal_ForceBalMode_104s_43 1 "Base on time " 2 "Base on Target Vol" 3 "Base on Ave Vol" ;
VAL_ 2417946219 S2P_Bal_CellTempFault_104s_43 0 "Nomal" 1 "Fault" ;
VAL_ 2417946219 S2P_Bal_CellVoltFail_104s_43 0 "Nomal" 1 "Fault" ;
VAL_ 2417946219 S2P_Bal_CloseBalIstr_104s_43 0 "Nomal" 1 "Fault" ;
VAL_ 2417946219 S2P_Bal_CCanTimeOut_104s_43 0 "Nomal" 1 "Fault" ;
VAL_ 2417946219 S2P_Bal_BalanCirFlt_104s_43 0 "Nomal" 1 "Fault" ;
VAL_ 2417946220 S2P_Bal_CSCNum_104s_44 0 "No CSC" 1 "CSC 1" 2 "CSC 2" 3 "CSC 3" 4 "CSC 4" 5 "CSC 5" 6 "CSC 6" 7 "CSC 7" 8 "CSC 8" 9 "CSC 9" 10 "CSC 10" 11 "CSC 11" 12 "CSC 12" 13 "CSC 13" 14 "CSC 14" 15 "CSC 15" 16 "CSC 16" 17 "CSC 17" 18 "CSC 18" 19 "CSC 19" 20 "CSC 20" 21 "CSC 21" 22 "CSC 22" 23 "CSC 23" 24 "CSC 24" 25 "CSC 25" 26 "CSC 26" 27 "CSC 27" 28 "CSC 28" 29 "CSC 29" 30 "CSC 30" 31 "CSC 31" ;
VAL_ 2417946220 S2P_Bal_CellNum_104s_44 1 "Cell 1" 2 "Cell 2" 3 "Cell 3" 4 "Cell 4" 5 "Cell 5" 6 "Cell 6" 7 "Cell 7" 8 "Cell 8" 9 "Cell 9" 10 "Cell 10" 11 "Cell 11" 12 "Cell 12" 13 "Cell 13" 14 "Cell 14" 15 "Cell 15" 16 "Cell 16" 127 "Null" ;
VAL_ 2417946220 S2P_Bal_Type_104s_44 0 "Balance stop" 1 "charge Balance" 2 "discharge Balance" ;
VAL_ 2417946220 S2P_Bal_TypeLevel_104s_44 0 "Not Balance" 1 "Low end Balance" 2 "High end Balance" 3 "Force Balance" ;
VAL_ 2417946220 S2P_Bal_Strategy_104s_44 0 "Active Balance" 1 "Passive Static" ;
VAL_ 2417946220 S2P_Bal_ForceBalMode_104s_44 1 "Base on time " 2 "Base on Target Vol" 3 "Base on Ave Vol" ;
VAL_ 2417946220 S2P_Bal_CellTempFault_104s_44 0 "Nomal" 1 "Fault" ;
VAL_ 2417946220 S2P_Bal_CellVoltFail_104s_44 0 "Nomal" 1 "Fault" ;
VAL_ 2417946220 S2P_Bal_CloseBalIstr_104s_44 0 "Nomal" 1 "Fault" ;
VAL_ 2417946220 S2P_Bal_CCanTimeOut_104s_44 0 "Nomal" 1 "Fault" ;
VAL_ 2417946220 S2P_Bal_BalanCirFlt_104s_44 0 "Nomal" 1 "Fault" ;
VAL_ 2417946221 S2P_Bal_CSCNum_104s_45 0 "No CSC" 1 "CSC 1" 2 "CSC 2" 3 "CSC 3" 4 "CSC 4" 5 "CSC 5" 6 "CSC 6" 7 "CSC 7" 8 "CSC 8" 9 "CSC 9" 10 "CSC 10" 11 "CSC 11" 12 "CSC 12" 13 "CSC 13" 14 "CSC 14" 15 "CSC 15" 16 "CSC 16" 17 "CSC 17" 18 "CSC 18" 19 "CSC 19" 20 "CSC 20" 21 "CSC 21" 22 "CSC 22" 23 "CSC 23" 24 "CSC 24" 25 "CSC 25" 26 "CSC 26" 27 "CSC 27" 28 "CSC 28" 29 "CSC 29" 30 "CSC 30" 31 "CSC 31" ;
VAL_ 2417946221 S2P_Bal_CellNum_104s_45 1 "Cell 1" 2 "Cell 2" 3 "Cell 3" 4 "Cell 4" 5 "Cell 5" 6 "Cell 6" 7 "Cell 7" 8 "Cell 8" 9 "Cell 9" 10 "Cell 10" 11 "Cell 11" 12 "Cell 12" 13 "Cell 13" 14 "Cell 14" 15 "Cell 15" 16 "Cell 16" 127 "Null" ;
VAL_ 2417946221 S2P_Bal_Type_104s_45 0 "Balance stop" 1 "charge Balance" 2 "discharge Balance" ;
VAL_ 2417946221 S2P_Bal_TypeLevel_104s_45 0 "Not Balance" 1 "Low end Balance" 2 "High end Balance" 3 "Force Balance" ;
VAL_ 2417946221 S2P_Bal_Strategy_104s_45 0 "Active Balance" 1 "Passive Static" ;
VAL_ 2417946221 S2P_Bal_ForceBalMode_104s_45 1 "Base on time " 2 "Base on Target Vol" 3 "Base on Ave Vol" ;
VAL_ 2417946221 S2P_Bal_CellTempFault_104s_45 0 "Nomal" 1 "Fault" ;
VAL_ 2417946221 S2P_Bal_CellVoltFail_104s_45 0 "Nomal" 1 "Fault" ;
VAL_ 2417946221 S2P_Bal_CloseBalIstr_104s_45 0 "Nomal" 1 "Fault" ;
VAL_ 2417946221 S2P_Bal_CCanTimeOut_104s_45 0 "Nomal" 1 "Fault" ;
VAL_ 2417946221 S2P_Bal_BalanCirFlt_104s_45 0 "Nomal" 1 "Fault" ;
VAL_ 2417946222 S2P_Bal_CSCNum_104s_46 0 "No CSC" 1 "CSC 1" 2 "CSC 2" 3 "CSC 3" 4 "CSC 4" 5 "CSC 5" 6 "CSC 6" 7 "CSC 7" 8 "CSC 8" 9 "CSC 9" 10 "CSC 10" 11 "CSC 11" 12 "CSC 12" 13 "CSC 13" 14 "CSC 14" 15 "CSC 15" 16 "CSC 16" 17 "CSC 17" 18 "CSC 18" 19 "CSC 19" 20 "CSC 20" 21 "CSC 21" 22 "CSC 22" 23 "CSC 23" 24 "CSC 24" 25 "CSC 25" 26 "CSC 26" 27 "CSC 27" 28 "CSC 28" 29 "CSC 29" 30 "CSC 30" 31 "CSC 31" ;
VAL_ 2417946222 S2P_Bal_CellNum_104s_46 1 "Cell 1" 2 "Cell 2" 3 "Cell 3" 4 "Cell 4" 5 "Cell 5" 6 "Cell 6" 7 "Cell 7" 8 "Cell 8" 9 "Cell 9" 10 "Cell 10" 11 "Cell 11" 12 "Cell 12" 13 "Cell 13" 14 "Cell 14" 15 "Cell 15" 16 "Cell 16" 127 "Null" ;
VAL_ 2417946222 S2P_Bal_Type_104s_46 0 "Balance stop" 1 "charge Balance" 2 "discharge Balance" ;
VAL_ 2417946222 S2P_Bal_TypeLevel_104s_46 0 "Not Balance" 1 "Low end Balance" 2 "High end Balance" 3 "Force Balance" ;
VAL_ 2417946222 S2P_Bal_Strategy_104s_46 0 "Active Balance" 1 "Passive Static" ;
VAL_ 2417946222 S2P_Bal_ForceBalMode_104s_46 1 "Base on time " 2 "Base on Target Vol" 3 "Base on Ave Vol" ;
VAL_ 2417946222 S2P_Bal_CellTempFault_104s_46 0 "Nomal" 1 "Fault" ;
VAL_ 2417946222 S2P_Bal_CellVoltFail_104s_46 0 "Nomal" 1 "Fault" ;
VAL_ 2417946222 S2P_Bal_CloseBalIstr_104s_46 0 "Nomal" 1 "Fault" ;
VAL_ 2417946222 S2P_Bal_CCanTimeOut_104s_46 0 "Nomal" 1 "Fault" ;
VAL_ 2417946222 S2P_Bal_BalanCirFlt_104s_46 0 "Nomal" 1 "Fault" ;
VAL_ 2417946223 S2P_Bal_CSCNum_104s_47 0 "No CSC" 1 "CSC 1" 2 "CSC 2" 3 "CSC 3" 4 "CSC 4" 5 "CSC 5" 6 "CSC 6" 7 "CSC 7" 8 "CSC 8" 9 "CSC 9" 10 "CSC 10" 11 "CSC 11" 12 "CSC 12" 13 "CSC 13" 14 "CSC 14" 15 "CSC 15" 16 "CSC 16" 17 "CSC 17" 18 "CSC 18" 19 "CSC 19" 20 "CSC 20" 21 "CSC 21" 22 "CSC 22" 23 "CSC 23" 24 "CSC 24" 25 "CSC 25" 26 "CSC 26" 27 "CSC 27" 28 "CSC 28" 29 "CSC 29" 30 "CSC 30" 31 "CSC 31" ;
VAL_ 2417946223 S2P_Bal_CellNum_104s_47 1 "Cell 1" 2 "Cell 2" 3 "Cell 3" 4 "Cell 4" 5 "Cell 5" 6 "Cell 6" 7 "Cell 7" 8 "Cell 8" 9 "Cell 9" 10 "Cell 10" 11 "Cell 11" 12 "Cell 12" 13 "Cell 13" 14 "Cell 14" 15 "Cell 15" 16 "Cell 16" 127 "Null" ;
VAL_ 2417946223 S2P_Bal_Type_104s_47 0 "Balance stop" 1 "charge Balance" 2 "discharge Balance" ;
VAL_ 2417946223 S2P_Bal_TypeLevel_104s_47 0 "Not Balance" 1 "Low end Balance" 2 "High end Balance" 3 "Force Balance" ;
VAL_ 2417946223 S2P_Bal_Strategy_104s_47 0 "Active Balance" 1 "Passive Static" ;
VAL_ 2417946223 S2P_Bal_ForceBalMode_104s_47 1 "Base on time " 2 "Base on Target Vol" 3 "Base on Ave Vol" ;
VAL_ 2417946223 S2P_Bal_CellTempFault_104s_47 0 "Nomal" 1 "Fault" ;
VAL_ 2417946223 S2P_Bal_CellVoltFail_104s_47 0 "Nomal" 1 "Fault" ;
VAL_ 2417946223 S2P_Bal_CloseBalIstr_104s_47 0 "Nomal" 1 "Fault" ;
VAL_ 2417946223 S2P_Bal_CCanTimeOut_104s_47 0 "Nomal" 1 "Fault" ;
VAL_ 2417946223 S2P_Bal_BalanCirFlt_104s_47 0 "Nomal" 1 "Fault" ;
VAL_ 2417946224 S2P_Bal_CSCNum_104s_48 0 "No CSC" 1 "CSC 1" 2 "CSC 2" 3 "CSC 3" 4 "CSC 4" 5 "CSC 5" 6 "CSC 6" 7 "CSC 7" 8 "CSC 8" 9 "CSC 9" 10 "CSC 10" 11 "CSC 11" 12 "CSC 12" 13 "CSC 13" 14 "CSC 14" 15 "CSC 15" 16 "CSC 16" 17 "CSC 17" 18 "CSC 18" 19 "CSC 19" 20 "CSC 20" 21 "CSC 21" 22 "CSC 22" 23 "CSC 23" 24 "CSC 24" 25 "CSC 25" 26 "CSC 26" 27 "CSC 27" 28 "CSC 28" 29 "CSC 29" 30 "CSC 30" 31 "CSC 31" ;
VAL_ 2417946224 S2P_Bal_CellNum_104s_48 1 "Cell 1" 2 "Cell 2" 3 "Cell 3" 4 "Cell 4" 5 "Cell 5" 6 "Cell 6" 7 "Cell 7" 8 "Cell 8" 9 "Cell 9" 10 "Cell 10" 11 "Cell 11" 12 "Cell 12" 13 "Cell 13" 14 "Cell 14" 15 "Cell 15" 16 "Cell 16" 127 "Null" ;
VAL_ 2417946224 S2P_Bal_Type_104s_48 0 "Balance stop" 1 "charge Balance" 2 "discharge Balance" ;
VAL_ 2417946224 S2P_Bal_TypeLevel_104s_48 0 "Not Balance" 1 "Low end Balance" 2 "High end Balance" 3 "Force Balance" ;
VAL_ 2417946224 S2P_Bal_Strategy_104s_48 0 "Active Balance" 1 "Passive Static" ;
VAL_ 2417946224 S2P_Bal_ForceBalMode_104s_48 1 "Base on time " 2 "Base on Target Vol" 3 "Base on Ave Vol" ;
VAL_ 2417946224 S2P_Bal_CellTempFault_104s_48 0 "Nomal" 1 "Fault" ;
VAL_ 2417946224 S2P_Bal_CellVoltFail_104s_48 0 "Nomal" 1 "Fault" ;
VAL_ 2417946224 S2P_Bal_CloseBalIstr_104s_48 0 "Nomal" 1 "Fault" ;
VAL_ 2417946224 S2P_Bal_CCanTimeOut_104s_48 0 "Nomal" 1 "Fault" ;
VAL_ 2417946224 S2P_Bal_BalanCirFlt_104s_48 0 "Nomal" 1 "Fault" ;
VAL_ 2417946225 S2P_Bal_CSCNum_104s_49 0 "No CSC" 1 "CSC 1" 2 "CSC 2" 3 "CSC 3" 4 "CSC 4" 5 "CSC 5" 6 "CSC 6" 7 "CSC 7" 8 "CSC 8" 9 "CSC 9" 10 "CSC 10" 11 "CSC 11" 12 "CSC 12" 13 "CSC 13" 14 "CSC 14" 15 "CSC 15" 16 "CSC 16" 17 "CSC 17" 18 "CSC 18" 19 "CSC 19" 20 "CSC 20" 21 "CSC 21" 22 "CSC 22" 23 "CSC 23" 24 "CSC 24" 25 "CSC 25" 26 "CSC 26" 27 "CSC 27" 28 "CSC 28" 29 "CSC 29" 30 "CSC 30" 31 "CSC 31" ;
VAL_ 2417946225 S2P_Bal_CellNum_104s_49 1 "Cell 1" 2 "Cell 2" 3 "Cell 3" 4 "Cell 4" 5 "Cell 5" 6 "Cell 6" 7 "Cell 7" 8 "Cell 8" 9 "Cell 9" 10 "Cell 10" 11 "Cell 11" 12 "Cell 12" 13 "Cell 13" 14 "Cell 14" 15 "Cell 15" 16 "Cell 16" 127 "Null" ;
VAL_ 2417946225 S2P_Bal_Type_104s_49 0 "Balance stop" 1 "charge Balance" 2 "discharge Balance" ;
VAL_ 2417946225 S2P_Bal_TypeLevel_104s_49 0 "Not Balance" 1 "Low end Balance" 2 "High end Balance" 3 "Force Balance" ;
VAL_ 2417946225 S2P_Bal_Strategy_104s_49 0 "Active Balance" 1 "Passive Static" ;
VAL_ 2417946225 S2P_Bal_ForceBalMode_104s_49 1 "Base on time " 2 "Base on Target Vol" 3 "Base on Ave Vol" ;
VAL_ 2417946225 S2P_Bal_CellTempFault_104s_49 0 "Nomal" 1 "Fault" ;
VAL_ 2417946225 S2P_Bal_CellVoltFail_104s_49 0 "Nomal" 1 "Fault" ;
VAL_ 2417946225 S2P_Bal_CloseBalIstr_104s_49 0 "Nomal" 1 "Fault" ;
VAL_ 2417946225 S2P_Bal_CCanTimeOut_104s_49 0 "Nomal" 1 "Fault" ;
VAL_ 2417946225 S2P_Bal_BalanCirFlt_104s_49 0 "Nomal" 1 "Fault" ;
VAL_ 2417946226 S2P_Bal_CSCNum_104s_50 0 "No CSC" 1 "CSC 1" 2 "CSC 2" 3 "CSC 3" 4 "CSC 4" 5 "CSC 5" 6 "CSC 6" 7 "CSC 7" 8 "CSC 8" 9 "CSC 9" 10 "CSC 10" 11 "CSC 11" 12 "CSC 12" 13 "CSC 13" 14 "CSC 14" 15 "CSC 15" 16 "CSC 16" 17 "CSC 17" 18 "CSC 18" 19 "CSC 19" 20 "CSC 20" 21 "CSC 21" 22 "CSC 22" 23 "CSC 23" 24 "CSC 24" 25 "CSC 25" 26 "CSC 26" 27 "CSC 27" 28 "CSC 28" 29 "CSC 29" 30 "CSC 30" 31 "CSC 31" ;
VAL_ 2417946226 S2P_Bal_CellNum_104s_50 1 "Cell 1" 2 "Cell 2" 3 "Cell 3" 4 "Cell 4" 5 "Cell 5" 6 "Cell 6" 7 "Cell 7" 8 "Cell 8" 9 "Cell 9" 10 "Cell 10" 11 "Cell 11" 12 "Cell 12" 13 "Cell 13" 14 "Cell 14" 15 "Cell 15" 16 "Cell 16" 127 "Null" ;
VAL_ 2417946226 S2P_Bal_Type_104s_50 0 "Balance stop" 1 "charge Balance" 2 "discharge Balance" ;
VAL_ 2417946226 S2P_Bal_TypeLevel_104s_50 0 "Not Balance" 1 "Low end Balance" 2 "High end Balance" 3 "Force Balance" ;
VAL_ 2417946226 S2P_Bal_Strategy_104s_50 0 "Active Balance" 1 "Passive Static" ;
VAL_ 2417946226 S2P_Bal_ForceBalMode_104s_50 1 "Base on time " 2 "Base on Target Vol" 3 "Base on Ave Vol" ;
VAL_ 2417946226 S2P_Bal_CellTempFault_104s_50 0 "Nomal" 1 "Fault" ;
VAL_ 2417946226 S2P_Bal_CellVoltFail_104s_50 0 "Nomal" 1 "Fault" ;
VAL_ 2417946226 S2P_Bal_CloseBalIstr_104s_50 0 "Nomal" 1 "Fault" ;
VAL_ 2417946226 S2P_Bal_CCanTimeOut_104s_50 0 "Nomal" 1 "Fault" ;
VAL_ 2417946226 S2P_Bal_BalanCirFlt_104s_50 0 "Nomal" 1 "Fault" ;
VAL_ 2417946227 S2P_Bal_CSCNum_104s_51 0 "No CSC" 1 "CSC 1" 2 "CSC 2" 3 "CSC 3" 4 "CSC 4" 5 "CSC 5" 6 "CSC 6" 7 "CSC 7" 8 "CSC 8" 9 "CSC 9" 10 "CSC 10" 11 "CSC 11" 12 "CSC 12" 13 "CSC 13" 14 "CSC 14" 15 "CSC 15" 16 "CSC 16" 17 "CSC 17" 18 "CSC 18" 19 "CSC 19" 20 "CSC 20" 21 "CSC 21" 22 "CSC 22" 23 "CSC 23" 24 "CSC 24" 25 "CSC 25" 26 "CSC 26" 27 "CSC 27" 28 "CSC 28" 29 "CSC 29" 30 "CSC 30" 31 "CSC 31" ;
VAL_ 2417946227 S2P_Bal_CellNum_104s_51 1 "Cell 1" 2 "Cell 2" 3 "Cell 3" 4 "Cell 4" 5 "Cell 5" 6 "Cell 6" 7 "Cell 7" 8 "Cell 8" 9 "Cell 9" 10 "Cell 10" 11 "Cell 11" 12 "Cell 12" 13 "Cell 13" 14 "Cell 14" 15 "Cell 15" 16 "Cell 16" 127 "Null" ;
VAL_ 2417946227 S2P_Bal_Type_104s_51 0 "Balance stop" 1 "charge Balance" 2 "discharge Balance" ;
VAL_ 2417946227 S2P_Bal_TypeLevel_104s_51 0 "Not Balance" 1 "Low end Balance" 2 "High end Balance" 3 "Force Balance" ;
VAL_ 2417946227 S2P_Bal_Strategy_104s_51 0 "Active Balance" 1 "Passive Static" ;
VAL_ 2417946227 S2P_Bal_ForceBalMode_104s_51 1 "Base on time " 2 "Base on Target Vol" 3 "Base on Ave Vol" ;
VAL_ 2417946227 S2P_Bal_CellTempFault_104s_51 0 "Nomal" 1 "Fault" ;
VAL_ 2417946227 S2P_Bal_CellVoltFail_104s_51 0 "Nomal" 1 "Fault" ;
VAL_ 2417946227 S2P_Bal_CloseBalIstr_104s_51 0 "Nomal" 1 "Fault" ;
VAL_ 2417946227 S2P_Bal_CCanTimeOut_104s_51 0 "Nomal" 1 "Fault" ;
VAL_ 2417946227 S2P_Bal_BalanCirFlt_104s_51 0 "Nomal" 1 "Fault" ;
VAL_ 2417946228 S2P_Bal_CSCNum_104s_52 0 "No CSC" 1 "CSC 1" 2 "CSC 2" 3 "CSC 3" 4 "CSC 4" 5 "CSC 5" 6 "CSC 6" 7 "CSC 7" 8 "CSC 8" 9 "CSC 9" 10 "CSC 10" 11 "CSC 11" 12 "CSC 12" 13 "CSC 13" 14 "CSC 14" 15 "CSC 15" 16 "CSC 16" 17 "CSC 17" 18 "CSC 18" 19 "CSC 19" 20 "CSC 20" 21 "CSC 21" 22 "CSC 22" 23 "CSC 23" 24 "CSC 24" 25 "CSC 25" 26 "CSC 26" 27 "CSC 27" 28 "CSC 28" 29 "CSC 29" 30 "CSC 30" 31 "CSC 31" ;
VAL_ 2417946228 S2P_Bal_CellNum_104s_52 1 "Cell 1" 2 "Cell 2" 3 "Cell 3" 4 "Cell 4" 5 "Cell 5" 6 "Cell 6" 7 "Cell 7" 8 "Cell 8" 9 "Cell 9" 10 "Cell 10" 11 "Cell 11" 12 "Cell 12" 13 "Cell 13" 14 "Cell 14" 15 "Cell 15" 16 "Cell 16" 127 "Null" ;
VAL_ 2417946228 S2P_Bal_Type_104s_52 0 "Balance stop" 1 "charge Balance" 2 "discharge Balance" ;
VAL_ 2417946228 S2P_Bal_TypeLevel_104s_52 0 "Not Balance" 1 "Low end Balance" 2 "High end Balance" 3 "Force Balance" ;
VAL_ 2417946228 S2P_Bal_Strategy_104s_52 0 "Active Balance" 1 "Passive Static" ;
VAL_ 2417946228 S2P_Bal_ForceBalMode_104s_52 1 "Base on time " 2 "Base on Target Vol" 3 "Base on Ave Vol" ;
VAL_ 2417946228 S2P_Bal_CellTempFault_104s_52 0 "Nomal" 1 "Fault" ;
VAL_ 2417946228 S2P_Bal_CellVoltFail_104s_52 0 "Nomal" 1 "Fault" ;
VAL_ 2417946228 S2P_Bal_CloseBalIstr_104s_52 0 "Nomal" 1 "Fault" ;
VAL_ 2417946228 S2P_Bal_CCanTimeOut_104s_52 0 "Nomal" 1 "Fault" ;
VAL_ 2417946228 S2P_Bal_BalanCirFlt_104s_52 0 "Nomal" 1 "Fault" ;
VAL_ 2417946229 S2P_Bal_CSCNum_104s_53 0 "No CSC" 1 "CSC 1" 2 "CSC 2" 3 "CSC 3" 4 "CSC 4" 5 "CSC 5" 6 "CSC 6" 7 "CSC 7" 8 "CSC 8" 9 "CSC 9" 10 "CSC 10" 11 "CSC 11" 12 "CSC 12" 13 "CSC 13" 14 "CSC 14" 15 "CSC 15" 16 "CSC 16" 17 "CSC 17" 18 "CSC 18" 19 "CSC 19" 20 "CSC 20" 21 "CSC 21" 22 "CSC 22" 23 "CSC 23" 24 "CSC 24" 25 "CSC 25" 26 "CSC 26" 27 "CSC 27" 28 "CSC 28" 29 "CSC 29" 30 "CSC 30" 31 "CSC 31" ;
VAL_ 2417946229 S2P_Bal_CellNum_104s_53 1 "Cell 1" 2 "Cell 2" 3 "Cell 3" 4 "Cell 4" 5 "Cell 5" 6 "Cell 6" 7 "Cell 7" 8 "Cell 8" 9 "Cell 9" 10 "Cell 10" 11 "Cell 11" 12 "Cell 12" 13 "Cell 13" 14 "Cell 14" 15 "Cell 15" 16 "Cell 16" 127 "Null" ;
VAL_ 2417946229 S2P_Bal_Type_104s_53 0 "Balance stop" 1 "charge Balance" 2 "discharge Balance" ;
VAL_ 2417946229 S2P_Bal_TypeLevel_104s_53 0 "Not Balance" 1 "Low end Balance" 2 "High end Balance" 3 "Force Balance" ;
VAL_ 2417946229 S2P_Bal_Strategy_104s_53 0 "Active Balance" 1 "Passive Static" ;
VAL_ 2417946229 S2P_Bal_ForceBalMode_104s_53 1 "Base on time " 2 "Base on Target Vol" 3 "Base on Ave Vol" ;
VAL_ 2417946229 S2P_Bal_CellTempFault_104s_53 0 "Nomal" 1 "Fault" ;
VAL_ 2417946229 S2P_Bal_CellVoltFail_104s_53 0 "Nomal" 1 "Fault" ;
VAL_ 2417946229 S2P_Bal_CloseBalIstr_104s_53 0 "Nomal" 1 "Fault" ;
VAL_ 2417946229 S2P_Bal_CCanTimeOut_104s_53 0 "Nomal" 1 "Fault" ;
VAL_ 2417946229 S2P_Bal_BalanCirFlt_104s_53 0 "Nomal" 1 "Fault" ;
VAL_ 2417946230 S2P_Bal_CSCNum_104s_54 0 "No CSC" 1 "CSC 1" 2 "CSC 2" 3 "CSC 3" 4 "CSC 4" 5 "CSC 5" 6 "CSC 6" 7 "CSC 7" 8 "CSC 8" 9 "CSC 9" 10 "CSC 10" 11 "CSC 11" 12 "CSC 12" 13 "CSC 13" 14 "CSC 14" 15 "CSC 15" 16 "CSC 16" 17 "CSC 17" 18 "CSC 18" 19 "CSC 19" 20 "CSC 20" 21 "CSC 21" 22 "CSC 22" 23 "CSC 23" 24 "CSC 24" 25 "CSC 25" 26 "CSC 26" 27 "CSC 27" 28 "CSC 28" 29 "CSC 29" 30 "CSC 30" 31 "CSC 31" ;
VAL_ 2417946230 S2P_Bal_CellNum_104s_54 1 "Cell 1" 2 "Cell 2" 3 "Cell 3" 4 "Cell 4" 5 "Cell 5" 6 "Cell 6" 7 "Cell 7" 8 "Cell 8" 9 "Cell 9" 10 "Cell 10" 11 "Cell 11" 12 "Cell 12" 13 "Cell 13" 14 "Cell 14" 15 "Cell 15" 16 "Cell 16" 127 "Null" ;
VAL_ 2417946230 S2P_Bal_Type_104s_54 0 "Balance stop" 1 "charge Balance" 2 "discharge Balance" ;
VAL_ 2417946230 S2P_Bal_TypeLevel_104s_54 0 "Not Balance" 1 "Low end Balance" 2 "High end Balance" 3 "Force Balance" ;
VAL_ 2417946230 S2P_Bal_Strategy_104s_54 0 "Active Balance" 1 "Passive Static" ;
VAL_ 2417946230 S2P_Bal_ForceBalMode_104s_54 1 "Base on time " 2 "Base on Target Vol" 3 "Base on Ave Vol" ;
VAL_ 2417946230 S2P_Bal_CellTempFault_104s_54 0 "Nomal" 1 "Fault" ;
VAL_ 2417946230 S2P_Bal_CellVoltFail_104s_54 0 "Nomal" 1 "Fault" ;
VAL_ 2417946230 S2P_Bal_CloseBalIstr_104s_54 0 "Nomal" 1 "Fault" ;
VAL_ 2417946230 S2P_Bal_CCanTimeOut_104s_54 0 "Nomal" 1 "Fault" ;
VAL_ 2417946230 S2P_Bal_BalanCirFlt_104s_54 0 "Nomal" 1 "Fault" ;
VAL_ 2417946231 S2P_Bal_CSCNum_104s_55 0 "No CSC" 1 "CSC 1" 2 "CSC 2" 3 "CSC 3" 4 "CSC 4" 5 "CSC 5" 6 "CSC 6" 7 "CSC 7" 8 "CSC 8" 9 "CSC 9" 10 "CSC 10" 11 "CSC 11" 12 "CSC 12" 13 "CSC 13" 14 "CSC 14" 15 "CSC 15" 16 "CSC 16" 17 "CSC 17" 18 "CSC 18" 19 "CSC 19" 20 "CSC 20" 21 "CSC 21" 22 "CSC 22" 23 "CSC 23" 24 "CSC 24" 25 "CSC 25" 26 "CSC 26" 27 "CSC 27" 28 "CSC 28" 29 "CSC 29" 30 "CSC 30" 31 "CSC 31" ;
VAL_ 2417946231 S2P_Bal_CellNum_104s_55 1 "Cell 1" 2 "Cell 2" 3 "Cell 3" 4 "Cell 4" 5 "Cell 5" 6 "Cell 6" 7 "Cell 7" 8 "Cell 8" 9 "Cell 9" 10 "Cell 10" 11 "Cell 11" 12 "Cell 12" 13 "Cell 13" 14 "Cell 14" 15 "Cell 15" 16 "Cell 16" 127 "Null" ;
VAL_ 2417946231 S2P_Bal_Type_104s_55 0 "Balance stop" 1 "charge Balance" 2 "discharge Balance" ;
VAL_ 2417946231 S2P_Bal_TypeLevel_104s_55 0 "Not Balance" 1 "Low end Balance" 2 "High end Balance" 3 "Force Balance" ;
VAL_ 2417946231 S2P_Bal_Strategy_104s_55 0 "Active Balance" 1 "Passive Static" ;
VAL_ 2417946231 S2P_Bal_ForceBalMode_104s_55 1 "Base on time " 2 "Base on Target Vol" 3 "Base on Ave Vol" ;
VAL_ 2417946231 S2P_Bal_CellTempFault_104s_55 0 "Nomal" 1 "Fault" ;
VAL_ 2417946231 S2P_Bal_CellVoltFail_104s_55 0 "Nomal" 1 "Fault" ;
VAL_ 2417946231 S2P_Bal_CloseBalIstr_104s_55 0 "Nomal" 1 "Fault" ;
VAL_ 2417946231 S2P_Bal_CCanTimeOut_104s_55 0 "Nomal" 1 "Fault" ;
VAL_ 2417946231 S2P_Bal_BalanCirFlt_104s_55 0 "Nomal" 1 "Fault" ;
VAL_ 2417946232 S2P_Bal_CSCNum_104s_56 0 "No CSC" 1 "CSC 1" 2 "CSC 2" 3 "CSC 3" 4 "CSC 4" 5 "CSC 5" 6 "CSC 6" 7 "CSC 7" 8 "CSC 8" 9 "CSC 9" 10 "CSC 10" 11 "CSC 11" 12 "CSC 12" 13 "CSC 13" 14 "CSC 14" 15 "CSC 15" 16 "CSC 16" 17 "CSC 17" 18 "CSC 18" 19 "CSC 19" 20 "CSC 20" 21 "CSC 21" 22 "CSC 22" 23 "CSC 23" 24 "CSC 24" 25 "CSC 25" 26 "CSC 26" 27 "CSC 27" 28 "CSC 28" 29 "CSC 29" 30 "CSC 30" 31 "CSC 31" ;
VAL_ 2417946232 S2P_Bal_CellNum_104s_56 1 "Cell 1" 2 "Cell 2" 3 "Cell 3" 4 "Cell 4" 5 "Cell 5" 6 "Cell 6" 7 "Cell 7" 8 "Cell 8" 9 "Cell 9" 10 "Cell 10" 11 "Cell 11" 12 "Cell 12" 13 "Cell 13" 14 "Cell 14" 15 "Cell 15" 16 "Cell 16" 127 "Null" ;
VAL_ 2417946232 S2P_Bal_Type_104s_56 0 "Balance stop" 1 "charge Balance" 2 "discharge Balance" ;
VAL_ 2417946232 S2P_Bal_TypeLevel_104s_56 0 "Not Balance" 1 "Low end Balance" 2 "High end Balance" 3 "Force Balance" ;
VAL_ 2417946232 S2P_Bal_Strategy_104s_56 0 "Active Balance" 1 "Passive Static" ;
VAL_ 2417946232 S2P_Bal_ForceBalMode_104s_56 1 "Base on time " 2 "Base on Target Vol" 3 "Base on Ave Vol" ;
VAL_ 2417946232 S2P_Bal_CellTempFault_104s_56 0 "Nomal" 1 "Fault" ;
VAL_ 2417946232 S2P_Bal_CellVoltFail_104s_56 0 "Nomal" 1 "Fault" ;
VAL_ 2417946232 S2P_Bal_CloseBalIstr_104s_56 0 "Nomal" 1 "Fault" ;
VAL_ 2417946232 S2P_Bal_CCanTimeOut_104s_56 0 "Nomal" 1 "Fault" ;
VAL_ 2417946232 S2P_Bal_BalanCirFlt_104s_56 0 "Nomal" 1 "Fault" ;
VAL_ 2417946233 S2P_Bal_CSCNum_104s_57 0 "No CSC" 1 "CSC 1" 2 "CSC 2" 3 "CSC 3" 4 "CSC 4" 5 "CSC 5" 6 "CSC 6" 7 "CSC 7" 8 "CSC 8" 9 "CSC 9" 10 "CSC 10" 11 "CSC 11" 12 "CSC 12" 13 "CSC 13" 14 "CSC 14" 15 "CSC 15" 16 "CSC 16" 17 "CSC 17" 18 "CSC 18" 19 "CSC 19" 20 "CSC 20" 21 "CSC 21" 22 "CSC 22" 23 "CSC 23" 24 "CSC 24" 25 "CSC 25" 26 "CSC 26" 27 "CSC 27" 28 "CSC 28" 29 "CSC 29" 30 "CSC 30" 31 "CSC 31" ;
VAL_ 2417946233 S2P_Bal_CellNum_104s_57 1 "Cell 1" 2 "Cell 2" 3 "Cell 3" 4 "Cell 4" 5 "Cell 5" 6 "Cell 6" 7 "Cell 7" 8 "Cell 8" 9 "Cell 9" 10 "Cell 10" 11 "Cell 11" 12 "Cell 12" 13 "Cell 13" 14 "Cell 14" 15 "Cell 15" 16 "Cell 16" 127 "Null" ;
VAL_ 2417946233 S2P_Bal_Type_104s_57 0 "Balance stop" 1 "charge Balance" 2 "discharge Balance" ;
VAL_ 2417946233 S2P_Bal_TypeLevel_104s_57 0 "Not Balance" 1 "Low end Balance" 2 "High end Balance" 3 "Force Balance" ;
VAL_ 2417946233 S2P_Bal_Strategy_104s_57 0 "Active Balance" 1 "Passive Static" ;
VAL_ 2417946233 S2P_Bal_ForceBalMode_104s_57 1 "Base on time " 2 "Base on Target Vol" 3 "Base on Ave Vol" ;
VAL_ 2417946233 S2P_Bal_CellTempFault_104s_57 0 "Nomal" 1 "Fault" ;
VAL_ 2417946233 S2P_Bal_CellVoltFail_104s_57 0 "Nomal" 1 "Fault" ;
VAL_ 2417946233 S2P_Bal_CloseBalIstr_104s_57 0 "Nomal" 1 "Fault" ;
VAL_ 2417946233 S2P_Bal_CCanTimeOut_104s_57 0 "Nomal" 1 "Fault" ;
VAL_ 2417946233 S2P_Bal_BalanCirFlt_104s_57 0 "Nomal" 1 "Fault" ;
VAL_ 2417946234 S2P_Bal_CSCNum_104s_58 0 "No CSC" 1 "CSC 1" 2 "CSC 2" 3 "CSC 3" 4 "CSC 4" 5 "CSC 5" 6 "CSC 6" 7 "CSC 7" 8 "CSC 8" 9 "CSC 9" 10 "CSC 10" 11 "CSC 11" 12 "CSC 12" 13 "CSC 13" 14 "CSC 14" 15 "CSC 15" 16 "CSC 16" 17 "CSC 17" 18 "CSC 18" 19 "CSC 19" 20 "CSC 20" 21 "CSC 21" 22 "CSC 22" 23 "CSC 23" 24 "CSC 24" 25 "CSC 25" 26 "CSC 26" 27 "CSC 27" 28 "CSC 28" 29 "CSC 29" 30 "CSC 30" 31 "CSC 31" ;
VAL_ 2417946234 S2P_Bal_CellNum_104s_58 1 "Cell 1" 2 "Cell 2" 3 "Cell 3" 4 "Cell 4" 5 "Cell 5" 6 "Cell 6" 7 "Cell 7" 8 "Cell 8" 9 "Cell 9" 10 "Cell 10" 11 "Cell 11" 12 "Cell 12" 13 "Cell 13" 14 "Cell 14" 15 "Cell 15" 16 "Cell 16" 127 "Null" ;
VAL_ 2417946234 S2P_Bal_Type_104s_58 0 "Balance stop" 1 "charge Balance" 2 "discharge Balance" ;
VAL_ 2417946234 S2P_Bal_TypeLevel_104s_58 0 "Not Balance" 1 "Low end Balance" 2 "High end Balance" 3 "Force Balance" ;
VAL_ 2417946234 S2P_Bal_Strategy_104s_58 0 "Active Balance" 1 "Passive Static" ;
VAL_ 2417946234 S2P_Bal_ForceBalMode_104s_58 1 "Base on time " 2 "Base on Target Vol" 3 "Base on Ave Vol" ;
VAL_ 2417946234 S2P_Bal_CellTempFault_104s_58 0 "Nomal" 1 "Fault" ;
VAL_ 2417946234 S2P_Bal_CellVoltFail_104s_58 0 "Nomal" 1 "Fault" ;
VAL_ 2417946234 S2P_Bal_CloseBalIstr_104s_58 0 "Nomal" 1 "Fault" ;
VAL_ 2417946234 S2P_Bal_CCanTimeOut_104s_58 0 "Nomal" 1 "Fault" ;
VAL_ 2417946234 S2P_Bal_BalanCirFlt_104s_58 0 "Nomal" 1 "Fault" ;
VAL_ 2417946235 S2P_Bal_CSCNum_104s_59 0 "No CSC" 1 "CSC 1" 2 "CSC 2" 3 "CSC 3" 4 "CSC 4" 5 "CSC 5" 6 "CSC 6" 7 "CSC 7" 8 "CSC 8" 9 "CSC 9" 10 "CSC 10" 11 "CSC 11" 12 "CSC 12" 13 "CSC 13" 14 "CSC 14" 15 "CSC 15" 16 "CSC 16" 17 "CSC 17" 18 "CSC 18" 19 "CSC 19" 20 "CSC 20" 21 "CSC 21" 22 "CSC 22" 23 "CSC 23" 24 "CSC 24" 25 "CSC 25" 26 "CSC 26" 27 "CSC 27" 28 "CSC 28" 29 "CSC 29" 30 "CSC 30" 31 "CSC 31" ;
VAL_ 2417946235 S2P_Bal_CellNum_104s_59 1 "Cell 1" 2 "Cell 2" 3 "Cell 3" 4 "Cell 4" 5 "Cell 5" 6 "Cell 6" 7 "Cell 7" 8 "Cell 8" 9 "Cell 9" 10 "Cell 10" 11 "Cell 11" 12 "Cell 12" 13 "Cell 13" 14 "Cell 14" 15 "Cell 15" 16 "Cell 16" 127 "Null" ;
VAL_ 2417946235 S2P_Bal_Type_104s_59 0 "Balance stop" 1 "charge Balance" 2 "discharge Balance" ;
VAL_ 2417946235 S2P_Bal_TypeLevel_104s_59 0 "Not Balance" 1 "Low end Balance" 2 "High end Balance" 3 "Force Balance" ;
VAL_ 2417946235 S2P_Bal_Strategy_104s_59 0 "Active Balance" 1 "Passive Static" ;
VAL_ 2417946235 S2P_Bal_ForceBalMode_104s_59 1 "Base on time " 2 "Base on Target Vol" 3 "Base on Ave Vol" ;
VAL_ 2417946235 S2P_Bal_CellTempFault_104s_59 0 "Nomal" 1 "Fault" ;
VAL_ 2417946235 S2P_Bal_CellVoltFail_104s_59 0 "Nomal" 1 "Fault" ;
VAL_ 2417946235 S2P_Bal_CloseBalIstr_104s_59 0 "Nomal" 1 "Fault" ;
VAL_ 2417946235 S2P_Bal_CCanTimeOut_104s_59 0 "Nomal" 1 "Fault" ;
VAL_ 2417946235 S2P_Bal_BalanCirFlt_104s_59 0 "Nomal" 1 "Fault" ;
VAL_ 2417946236 S2P_Bal_CSCNum_104s_60 0 "No CSC" 1 "CSC 1" 2 "CSC 2" 3 "CSC 3" 4 "CSC 4" 5 "CSC 5" 6 "CSC 6" 7 "CSC 7" 8 "CSC 8" 9 "CSC 9" 10 "CSC 10" 11 "CSC 11" 12 "CSC 12" 13 "CSC 13" 14 "CSC 14" 15 "CSC 15" 16 "CSC 16" 17 "CSC 17" 18 "CSC 18" 19 "CSC 19" 20 "CSC 20" 21 "CSC 21" 22 "CSC 22" 23 "CSC 23" 24 "CSC 24" 25 "CSC 25" 26 "CSC 26" 27 "CSC 27" 28 "CSC 28" 29 "CSC 29" 30 "CSC 30" 31 "CSC 31" ;
VAL_ 2417946236 S2P_Bal_CellNum_104s_60 1 "Cell 1" 2 "Cell 2" 3 "Cell 3" 4 "Cell 4" 5 "Cell 5" 6 "Cell 6" 7 "Cell 7" 8 "Cell 8" 9 "Cell 9" 10 "Cell 10" 11 "Cell 11" 12 "Cell 12" 13 "Cell 13" 14 "Cell 14" 15 "Cell 15" 16 "Cell 16" 127 "Null" ;
VAL_ 2417946236 S2P_Bal_Type_104s_60 0 "Balance stop" 1 "charge Balance" 2 "discharge Balance" ;
VAL_ 2417946236 S2P_Bal_TypeLevel_104s_60 0 "Not Balance" 1 "Low end Balance" 2 "High end Balance" 3 "Force Balance" ;
VAL_ 2417946236 S2P_Bal_Strategy_104s_60 0 "Active Balance" 1 "Passive Static" ;
VAL_ 2417946236 S2P_Bal_ForceBalMode_104s_60 1 "Base on time " 2 "Base on Target Vol" 3 "Base on Ave Vol" ;
VAL_ 2417946236 S2P_Bal_CellTempFault_104s_60 0 "Nomal" 1 "Fault" ;
VAL_ 2417946236 S2P_Bal_CellVoltFail_104s_60 0 "Nomal" 1 "Fault" ;
VAL_ 2417946236 S2P_Bal_CloseBalIstr_104s_60 0 "Nomal" 1 "Fault" ;
VAL_ 2417946236 S2P_Bal_CCanTimeOut_104s_60 0 "Nomal" 1 "Fault" ;
VAL_ 2417946236 S2P_Bal_BalanCirFlt_104s_60 0 "Nomal" 1 "Fault" ;
VAL_ 2417946237 S2P_Bal_CSCNum_104s_61 0 "No CSC" 1 "CSC 1" 2 "CSC 2" 3 "CSC 3" 4 "CSC 4" 5 "CSC 5" 6 "CSC 6" 7 "CSC 7" 8 "CSC 8" 9 "CSC 9" 10 "CSC 10" 11 "CSC 11" 12 "CSC 12" 13 "CSC 13" 14 "CSC 14" 15 "CSC 15" 16 "CSC 16" 17 "CSC 17" 18 "CSC 18" 19 "CSC 19" 20 "CSC 20" 21 "CSC 21" 22 "CSC 22" 23 "CSC 23" 24 "CSC 24" 25 "CSC 25" 26 "CSC 26" 27 "CSC 27" 28 "CSC 28" 29 "CSC 29" 30 "CSC 30" 31 "CSC 31" ;
VAL_ 2417946237 S2P_Bal_CellNum_104s_61 1 "Cell 1" 2 "Cell 2" 3 "Cell 3" 4 "Cell 4" 5 "Cell 5" 6 "Cell 6" 7 "Cell 7" 8 "Cell 8" 9 "Cell 9" 10 "Cell 10" 11 "Cell 11" 12 "Cell 12" 13 "Cell 13" 14 "Cell 14" 15 "Cell 15" 16 "Cell 16" 127 "Null" ;
VAL_ 2417946237 S2P_Bal_Type_104s_61 0 "Balance stop" 1 "charge Balance" 2 "discharge Balance" ;
VAL_ 2417946237 S2P_Bal_TypeLevel_104s_61 0 "Not Balance" 1 "Low end Balance" 2 "High end Balance" 3 "Force Balance" ;
VAL_ 2417946237 S2P_Bal_Strategy_104s_61 0 "Active Balance" 1 "Passive Static" ;
VAL_ 2417946237 S2P_Bal_ForceBalMode_104s_61 1 "Base on time " 2 "Base on Target Vol" 3 "Base on Ave Vol" ;
VAL_ 2417946237 S2P_Bal_CellTempFault_104s_61 0 "Nomal" 1 "Fault" ;
VAL_ 2417946237 S2P_Bal_CellVoltFail_104s_61 0 "Nomal" 1 "Fault" ;
VAL_ 2417946237 S2P_Bal_CloseBalIstr_104s_61 0 "Nomal" 1 "Fault" ;
VAL_ 2417946237 S2P_Bal_CCanTimeOut_104s_61 0 "Nomal" 1 "Fault" ;
VAL_ 2417946237 S2P_Bal_BalanCirFlt_104s_61 0 "Nomal" 1 "Fault" ;
VAL_ 2417946238 S2P_Bal_CSCNum_104s_62 0 "No CSC" 1 "CSC 1" 2 "CSC 2" 3 "CSC 3" 4 "CSC 4" 5 "CSC 5" 6 "CSC 6" 7 "CSC 7" 8 "CSC 8" 9 "CSC 9" 10 "CSC 10" 11 "CSC 11" 12 "CSC 12" 13 "CSC 13" 14 "CSC 14" 15 "CSC 15" 16 "CSC 16" 17 "CSC 17" 18 "CSC 18" 19 "CSC 19" 20 "CSC 20" 21 "CSC 21" 22 "CSC 22" 23 "CSC 23" 24 "CSC 24" 25 "CSC 25" 26 "CSC 26" 27 "CSC 27" 28 "CSC 28" 29 "CSC 29" 30 "CSC 30" 31 "CSC 31" ;
VAL_ 2417946238 S2P_Bal_CellNum_104s_62 1 "Cell 1" 2 "Cell 2" 3 "Cell 3" 4 "Cell 4" 5 "Cell 5" 6 "Cell 6" 7 "Cell 7" 8 "Cell 8" 9 "Cell 9" 10 "Cell 10" 11 "Cell 11" 12 "Cell 12" 13 "Cell 13" 14 "Cell 14" 15 "Cell 15" 16 "Cell 16" 127 "Null" ;
VAL_ 2417946238 S2P_Bal_Type_104s_62 0 "Balance stop" 1 "charge Balance" 2 "discharge Balance" ;
VAL_ 2417946238 S2P_Bal_TypeLevel_104s_62 0 "Not Balance" 1 "Low end Balance" 2 "High end Balance" 3 "Force Balance" ;
VAL_ 2417946238 S2P_Bal_Strategy_104s_62 0 "Active Balance" 1 "Passive Static" ;
VAL_ 2417946238 S2P_Bal_ForceBalMode_104s_62 1 "Base on time " 2 "Base on Target Vol" 3 "Base on Ave Vol" ;
VAL_ 2417946238 S2P_Bal_CellTempFault_104s_62 0 "Nomal" 1 "Fault" ;
VAL_ 2417946238 S2P_Bal_CellVoltFail_104s_62 0 "Nomal" 1 "Fault" ;
VAL_ 2417946238 S2P_Bal_CloseBalIstr_104s_62 0 "Nomal" 1 "Fault" ;
VAL_ 2417946238 S2P_Bal_CCanTimeOut_104s_62 0 "Nomal" 1 "Fault" ;
VAL_ 2417946238 S2P_Bal_BalanCirFlt_104s_62 0 "Nomal" 1 "Fault" ;
VAL_ 2417946239 S2P_Bal_CSCNum_104s_63 0 "No CSC" 1 "CSC 1" 2 "CSC 2" 3 "CSC 3" 4 "CSC 4" 5 "CSC 5" 6 "CSC 6" 7 "CSC 7" 8 "CSC 8" 9 "CSC 9" 10 "CSC 10" 11 "CSC 11" 12 "CSC 12" 13 "CSC 13" 14 "CSC 14" 15 "CSC 15" 16 "CSC 16" 17 "CSC 17" 18 "CSC 18" 19 "CSC 19" 20 "CSC 20" 21 "CSC 21" 22 "CSC 22" 23 "CSC 23" 24 "CSC 24" 25 "CSC 25" 26 "CSC 26" 27 "CSC 27" 28 "CSC 28" 29 "CSC 29" 30 "CSC 30" 31 "CSC 31" ;
VAL_ 2417946239 S2P_Bal_CellNum_104s_63 1 "Cell 1" 2 "Cell 2" 3 "Cell 3" 4 "Cell 4" 5 "Cell 5" 6 "Cell 6" 7 "Cell 7" 8 "Cell 8" 9 "Cell 9" 10 "Cell 10" 11 "Cell 11" 12 "Cell 12" 13 "Cell 13" 14 "Cell 14" 15 "Cell 15" 16 "Cell 16" 127 "Null" ;
VAL_ 2417946239 S2P_Bal_Type_104s_63 0 "Balance stop" 1 "charge Balance" 2 "discharge Balance" ;
VAL_ 2417946239 S2P_Bal_TypeLevel_104s_63 0 "Not Balance" 1 "Low end Balance" 2 "High end Balance" 3 "Force Balance" ;
VAL_ 2417946239 S2P_Bal_Strategy_104s_63 0 "Active Balance" 1 "Passive Static" ;
VAL_ 2417946239 S2P_Bal_ForceBalMode_104s_63 1 "Base on time " 2 "Base on Target Vol" 3 "Base on Ave Vol" ;
VAL_ 2417946239 S2P_Bal_CellTempFault_104s_63 0 "Nomal" 1 "Fault" ;
VAL_ 2417946239 S2P_Bal_CellVoltFail_104s_63 0 "Nomal" 1 "Fault" ;
VAL_ 2417946239 S2P_Bal_CloseBalIstr_104s_63 0 "Nomal" 1 "Fault" ;
VAL_ 2417946239 S2P_Bal_CCanTimeOut_104s_63 0 "Nomal" 1 "Fault" ;
VAL_ 2417946239 S2P_Bal_BalanCirFlt_104s_63 0 "Nomal" 1 "Fault" ;
VERSION ""

NS_ :

BS_:

BU_: MBMU PC SBMU IMM ETH DCDC LEMS

BO_ 2337468077 M2P_LiquidInfo_3__29: 8 MBMU
 SG_ M2P_TMS_R_ACDC_A_vol_29 : 0|8@1+ (1,0) [0|255] "V"  PC
 SG_ M2P_TMS_R_15_pwm_29 : 8|8@1+ (1,0) [0|255] ""  PC
 SG_ M2P_TMS_R_15_HP_29 : 16|16@1+ (1,0) [0|65535] "kpa"  PC
 SG_ M2P_TMS_R_15_LP_29 : 32|16@1+ (1,0) [0|65535] "kpa"  PC
 SG_ M2P_TMS_R_25_HP_29 : 48|16@1+ (1,0) [0|65535] "kpa"  PC

BO_ 2337468078 M2P_LiquidInfo_3__30: 8 MBMU
 SG_ M2P_TMS_R_ACDC_A_vol_30 : 0|8@1+ (1,0) [0|255] "V"  PC
 SG_ M2P_TMS_R_15_pwm_30 : 8|8@1+ (1,0) [0|255] ""  PC
 SG_ M2P_TMS_R_15_HP_30 : 16|16@1+ (1,0) [0|65535] "kpa"  PC
 SG_ M2P_TMS_R_15_LP_30 : 32|16@1+ (1,0) [0|65535] "kpa"  PC
 SG_ M2P_TMS_R_25_HP_30 : 48|16@1+ (1,0) [0|65535] "kpa"  PC

BO_ 2337468079 M2P_LiquidInfo_3__31: 8 MBMU
 SG_ M2P_TMS_R_ACDC_A_vol_31 : 0|8@1+ (1,0) [0|255] "V"  PC
 SG_ M2P_TMS_R_15_pwm_31 : 8|8@1+ (1,0) [0|255] ""  PC
 SG_ M2P_TMS_R_15_HP_31 : 16|16@1+ (1,0) [0|65535] "kpa"  PC
 SG_ M2P_TMS_R_15_LP_31 : 32|16@1+ (1,0) [0|65535] "kpa"  PC
 SG_ M2P_TMS_R_25_HP_31 : 48|16@1+ (1,0) [0|65535] "kpa"  PC

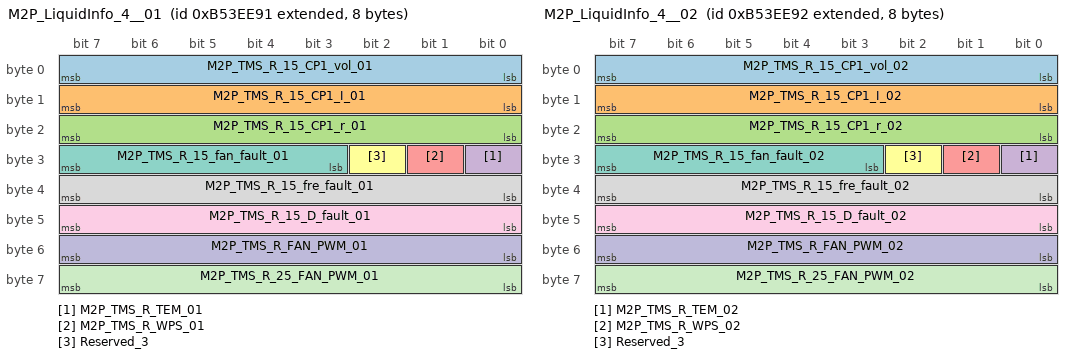
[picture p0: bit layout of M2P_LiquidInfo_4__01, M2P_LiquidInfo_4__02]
BO_ 2337533585 M2P_LiquidInfo_4__01: 8 MBMU
 SG_ M2P_TMS_R_15_CP1_vol_01 : 0|8@1+ (2,0) [0|510] "V"  PC
 SG_ M2P_TMS_R_15_CP1_I_01 : 8|8@1+ (1,0) [0|255] "A"  PC
 SG_ M2P_TMS_R_15_CP1_r_01 : 16|8@1+ (100,0) [0|25500] "rpm"  PC
 SG_ M2P_TMS_R_TEM_01 : 24|1@1+ (1,0) [0|1] ""  PC
 SG_ M2P_TMS_R_WPS_01 : 25|1@1+ (1,0) [0|1] ""  PC
 SG_ Reserved_3 : 26|1@1+ (1,0) [0|1] ""  PC
 SG_ M2P_TMS_R_15_fan_fault_01 : 27|5@1+ (1,0) [0|31] ""  PC
 SG_ M2P_TMS_R_15_fre_fault_01 : 32|8@1+ (1,0) [0|255] ""  PC
 SG_ M2P_TMS_R_15_D_fault_01 : 40|8@1+ (1,0) [0|255] ""  PC
 SG_ M2P_TMS_R_FAN_PWM_01 : 48|8@1+ (1,0) [0|255] ""  PC
 SG_ M2P_TMS_R_25_FAN_PWM_01 : 56|8@1+ (1,0) [0|255] ""  PC

BO_ 2337533586 M2P_LiquidInfo_4__02: 8 MBMU
 SG_ M2P_TMS_R_15_CP1_vol_02 : 0|8@1+ (2,0) [0|510] "V"  PC
 SG_ M2P_TMS_R_15_CP1_I_02 : 8|8@1+ (1,0) [0|255] "A"  PC
 SG_ M2P_TMS_R_15_CP1_r_02 : 16|8@1+ (100,0) [0|25500] "rpm"  PC
 SG_ M2P_TMS_R_TEM_02 : 24|1@1+ (1,0) [0|1] ""  PC
 SG_ M2P_TMS_R_WPS_02 : 25|1@1+ (1,0) [0|1] ""  PC
 SG_ Reserved_3 : 26|1@1+ (1,0) [0|1] ""  PC
 SG_ M2P_TMS_R_15_fan_fault_02 : 27|5@1+ (1,0) [0|31] ""  PC
 SG_ M2P_TMS_R_15_fre_fault_02 : 32|8@1+ (1,0) [0|255] ""  PC
 SG_ M2P_TMS_R_15_D_fault_02 : 40|8@1+ (1,0) [0|255] ""  PC
 SG_ M2P_TMS_R_FAN_PWM_02 : 48|8@1+ (1,0) [0|255] ""  PC
 SG_ M2P_TMS_R_25_FAN_PWM_02 : 56|8@1+ (1,0) [0|255] ""  PC

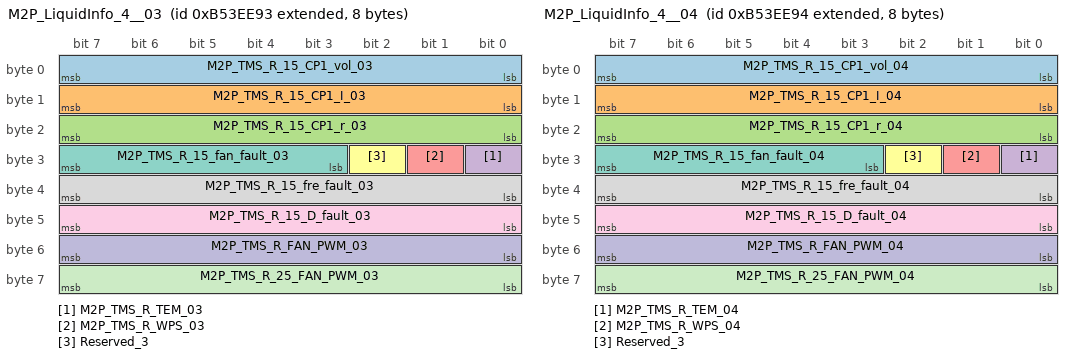
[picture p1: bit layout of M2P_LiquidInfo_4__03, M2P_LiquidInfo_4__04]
BO_ 2337533587 M2P_LiquidInfo_4__03: 8 MBMU
 SG_ M2P_TMS_R_15_CP1_vol_03 : 0|8@1+ (2,0) [0|510] "V"  PC
 SG_ M2P_TMS_R_15_CP1_I_03 : 8|8@1+ (1,0) [0|255] "A"  PC
 SG_ M2P_TMS_R_15_CP1_r_03 : 16|8@1+ (100,0) [0|25500] "rpm"  PC
 SG_ M2P_TMS_R_TEM_03 : 24|1@1+ (1,0) [0|1] ""  PC
 SG_ M2P_TMS_R_WPS_03 : 25|1@1+ (1,0) [0|1] ""  PC
 SG_ Reserved_3 : 26|1@1+ (1,0) [0|1] ""  PC
 SG_ M2P_TMS_R_15_fan_fault_03 : 27|5@1+ (1,0) [0|31] ""  PC
 SG_ M2P_TMS_R_15_fre_fault_03 : 32|8@1+ (1,0) [0|255] ""  PC
 SG_ M2P_TMS_R_15_D_fault_03 : 40|8@1+ (1,0) [0|255] ""  PC
 SG_ M2P_TMS_R_FAN_PWM_03 : 48|8@1+ (1,0) [0|255] ""  PC
 SG_ M2P_TMS_R_25_FAN_PWM_03 : 56|8@1+ (1,0) [0|255] ""  PC

BO_ 2337533588 M2P_LiquidInfo_4__04: 8 MBMU
 SG_ M2P_TMS_R_15_CP1_vol_04 : 0|8@1+ (2,0) [0|510] "V"  PC
 SG_ M2P_TMS_R_15_CP1_I_04 : 8|8@1+ (1,0) [0|255] "A"  PC
 SG_ M2P_TMS_R_15_CP1_r_04 : 16|8@1+ (100,0) [0|25500] "rpm"  PC
 SG_ M2P_TMS_R_TEM_04 : 24|1@1+ (1,0) [0|1] ""  PC
 SG_ M2P_TMS_R_WPS_04 : 25|1@1+ (1,0) [0|1] ""  PC
 SG_ Reserved_3 : 26|1@1+ (1,0) [0|1] ""  PC
 SG_ M2P_TMS_R_15_fan_fault_04 : 27|5@1+ (1,0) [0|31] ""  PC
 SG_ M2P_TMS_R_15_fre_fault_04 : 32|8@1+ (1,0) [0|255] ""  PC
 SG_ M2P_TMS_R_15_D_fault_04 : 40|8@1+ (1,0) [0|255] ""  PC
 SG_ M2P_TMS_R_FAN_PWM_04 : 48|8@1+ (1,0) [0|255] ""  PC
 SG_ M2P_TMS_R_25_FAN_PWM_04 : 56|8@1+ (1,0) [0|255] ""  PC

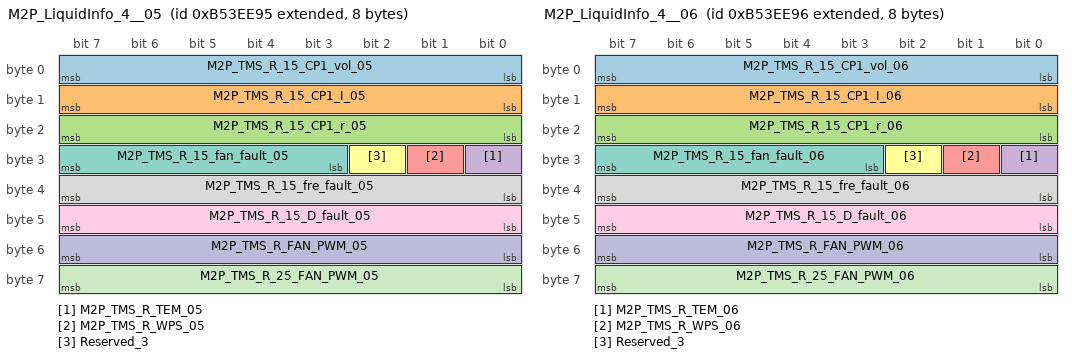
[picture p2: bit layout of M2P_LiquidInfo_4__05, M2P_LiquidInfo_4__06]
BO_ 2337533589 M2P_LiquidInfo_4__05: 8 MBMU
 SG_ M2P_TMS_R_15_CP1_vol_05 : 0|8@1+ (2,0) [0|510] "V"  PC
 SG_ M2P_TMS_R_15_CP1_I_05 : 8|8@1+ (1,0) [0|255] "A"  PC
 SG_ M2P_TMS_R_15_CP1_r_05 : 16|8@1+ (100,0) [0|25500] "rpm"  PC
 SG_ M2P_TMS_R_TEM_05 : 24|1@1+ (1,0) [0|1] ""  PC
 SG_ M2P_TMS_R_WPS_05 : 25|1@1+ (1,0) [0|1] ""  PC
 SG_ Reserved_3 : 26|1@1+ (1,0) [0|1] ""  PC
 SG_ M2P_TMS_R_15_fan_fault_05 : 27|5@1+ (1,0) [0|31] ""  PC
 SG_ M2P_TMS_R_15_fre_fault_05 : 32|8@1+ (1,0) [0|255] ""  PC
 SG_ M2P_TMS_R_15_D_fault_05 : 40|8@1+ (1,0) [0|255] ""  PC
 SG_ M2P_TMS_R_FAN_PWM_05 : 48|8@1+ (1,0) [0|255] ""  PC
 SG_ M2P_TMS_R_25_FAN_PWM_05 : 56|8@1+ (1,0) [0|255] ""  PC

BO_ 2337533590 M2P_LiquidInfo_4__06: 8 MBMU
 SG_ M2P_TMS_R_15_CP1_vol_06 : 0|8@1+ (2,0) [0|510] "V"  PC
 SG_ M2P_TMS_R_15_CP1_I_06 : 8|8@1+ (1,0) [0|255] "A"  PC
 SG_ M2P_TMS_R_15_CP1_r_06 : 16|8@1+ (100,0) [0|25500] "rpm"  PC
 SG_ M2P_TMS_R_TEM_06 : 24|1@1+ (1,0) [0|1] ""  PC
 SG_ M2P_TMS_R_WPS_06 : 25|1@1+ (1,0) [0|1] ""  PC
 SG_ Reserved_3 : 26|1@1+ (1,0) [0|1] ""  PC
 SG_ M2P_TMS_R_15_fan_fault_06 : 27|5@1+ (1,0) [0|31] ""  PC
 SG_ M2P_TMS_R_15_fre_fault_06 : 32|8@1+ (1,0) [0|255] ""  PC
 SG_ M2P_TMS_R_15_D_fault_06 : 40|8@1+ (1,0) [0|255] ""  PC
 SG_ M2P_TMS_R_FAN_PWM_06 : 48|8@1+ (1,0) [0|255] ""  PC
 SG_ M2P_TMS_R_25_FAN_PWM_06 : 56|8@1+ (1,0) [0|255] ""  PC

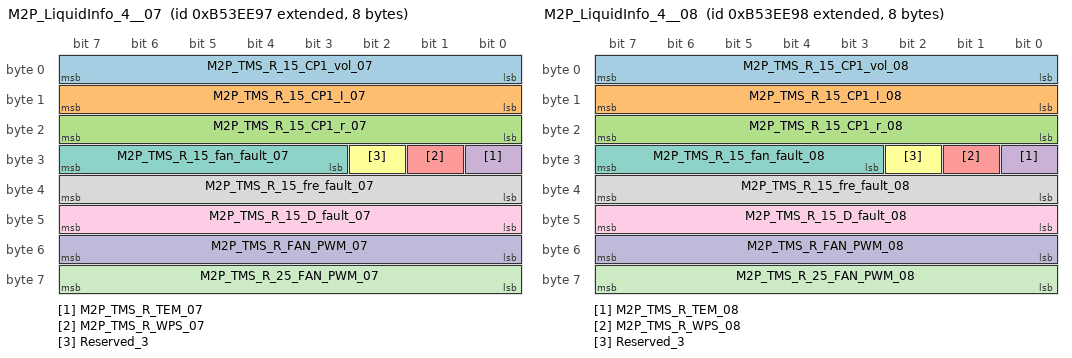
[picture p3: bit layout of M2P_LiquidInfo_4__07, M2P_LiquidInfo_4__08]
BO_ 2337533591 M2P_LiquidInfo_4__07: 8 MBMU
 SG_ M2P_TMS_R_15_CP1_vol_07 : 0|8@1+ (2,0) [0|510] "V"  PC
 SG_ M2P_TMS_R_15_CP1_I_07 : 8|8@1+ (1,0) [0|255] "A"  PC
 SG_ M2P_TMS_R_15_CP1_r_07 : 16|8@1+ (100,0) [0|25500] "rpm"  PC
 SG_ M2P_TMS_R_TEM_07 : 24|1@1+ (1,0) [0|1] ""  PC
 SG_ M2P_TMS_R_WPS_07 : 25|1@1+ (1,0) [0|1] ""  PC
 SG_ Reserved_3 : 26|1@1+ (1,0) [0|1] ""  PC
 SG_ M2P_TMS_R_15_fan_fault_07 : 27|5@1+ (1,0) [0|31] ""  PC
 SG_ M2P_TMS_R_15_fre_fault_07 : 32|8@1+ (1,0) [0|255] ""  PC
 SG_ M2P_TMS_R_15_D_fault_07 : 40|8@1+ (1,0) [0|255] ""  PC
 SG_ M2P_TMS_R_FAN_PWM_07 : 48|8@1+ (1,0) [0|255] ""  PC
 SG_ M2P_TMS_R_25_FAN_PWM_07 : 56|8@1+ (1,0) [0|255] ""  PC

BO_ 2337533592 M2P_LiquidInfo_4__08: 8 MBMU
 SG_ M2P_TMS_R_15_CP1_vol_08 : 0|8@1+ (2,0) [0|510] "V"  PC
 SG_ M2P_TMS_R_15_CP1_I_08 : 8|8@1+ (1,0) [0|255] "A"  PC
 SG_ M2P_TMS_R_15_CP1_r_08 : 16|8@1+ (100,0) [0|25500] "rpm"  PC
 SG_ M2P_TMS_R_TEM_08 : 24|1@1+ (1,0) [0|1] ""  PC
 SG_ M2P_TMS_R_WPS_08 : 25|1@1+ (1,0) [0|1] ""  PC
 SG_ Reserved_3 : 26|1@1+ (1,0) [0|1] ""  PC
 SG_ M2P_TMS_R_15_fan_fault_08 : 27|5@1+ (1,0) [0|31] ""  PC
 SG_ M2P_TMS_R_15_fre_fault_08 : 32|8@1+ (1,0) [0|255] ""  PC
 SG_ M2P_TMS_R_15_D_fault_08 : 40|8@1+ (1,0) [0|255] ""  PC
 SG_ M2P_TMS_R_FAN_PWM_08 : 48|8@1+ (1,0) [0|255] ""  PC
 SG_ M2P_TMS_R_25_FAN_PWM_08 : 56|8@1+ (1,0) [0|255] ""  PC

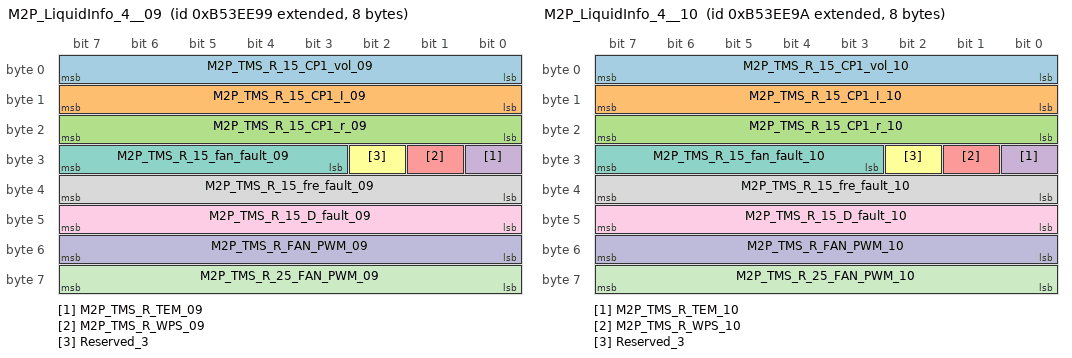
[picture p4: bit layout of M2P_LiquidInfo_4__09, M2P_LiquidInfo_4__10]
BO_ 2337533593 M2P_LiquidInfo_4__09: 8 MBMU
 SG_ M2P_TMS_R_15_CP1_vol_09 : 0|8@1+ (2,0) [0|510] "V"  PC
 SG_ M2P_TMS_R_15_CP1_I_09 : 8|8@1+ (1,0) [0|255] "A"  PC
 SG_ M2P_TMS_R_15_CP1_r_09 : 16|8@1+ (100,0) [0|25500] "rpm"  PC
 SG_ M2P_TMS_R_TEM_09 : 24|1@1+ (1,0) [0|1] ""  PC
 SG_ M2P_TMS_R_WPS_09 : 25|1@1+ (1,0) [0|1] ""  PC
 SG_ Reserved_3 : 26|1@1+ (1,0) [0|1] ""  PC
 SG_ M2P_TMS_R_15_fan_fault_09 : 27|5@1+ (1,0) [0|31] ""  PC
 SG_ M2P_TMS_R_15_fre_fault_09 : 32|8@1+ (1,0) [0|255] ""  PC
 SG_ M2P_TMS_R_15_D_fault_09 : 40|8@1+ (1,0) [0|255] ""  PC
 SG_ M2P_TMS_R_FAN_PWM_09 : 48|8@1+ (1,0) [0|255] ""  PC
 SG_ M2P_TMS_R_25_FAN_PWM_09 : 56|8@1+ (1,0) [0|255] ""  PC

BO_ 2337533594 M2P_LiquidInfo_4__10: 8 MBMU
 SG_ M2P_TMS_R_15_CP1_vol_10 : 0|8@1+ (2,0) [0|510] "V"  PC
 SG_ M2P_TMS_R_15_CP1_I_10 : 8|8@1+ (1,0) [0|255] "A"  PC
 SG_ M2P_TMS_R_15_CP1_r_10 : 16|8@1+ (100,0) [0|25500] "rpm"  PC
 SG_ M2P_TMS_R_TEM_10 : 24|1@1+ (1,0) [0|1] ""  PC
 SG_ M2P_TMS_R_WPS_10 : 25|1@1+ (1,0) [0|1] ""  PC
 SG_ Reserved_3 : 26|1@1+ (1,0) [0|1] ""  PC
 SG_ M2P_TMS_R_15_fan_fault_10 : 27|5@1+ (1,0) [0|31] ""  PC
 SG_ M2P_TMS_R_15_fre_fault_10 : 32|8@1+ (1,0) [0|255] ""  PC
 SG_ M2P_TMS_R_15_D_fault_10 : 40|8@1+ (1,0) [0|255] ""  PC
 SG_ M2P_TMS_R_FAN_PWM_10 : 48|8@1+ (1,0) [0|255] ""  PC
 SG_ M2P_TMS_R_25_FAN_PWM_10 : 56|8@1+ (1,0) [0|255] ""  PC

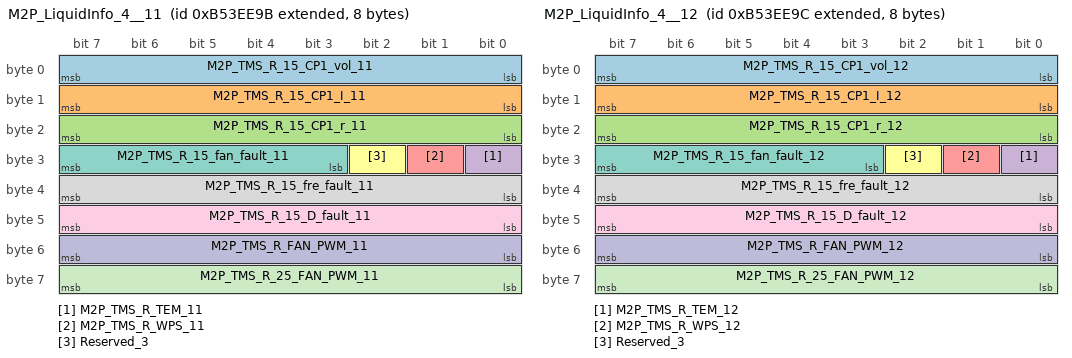
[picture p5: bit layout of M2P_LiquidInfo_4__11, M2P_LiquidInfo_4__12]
BO_ 2337533595 M2P_LiquidInfo_4__11: 8 MBMU
 SG_ M2P_TMS_R_15_CP1_vol_11 : 0|8@1+ (2,0) [0|510] "V"  PC
 SG_ M2P_TMS_R_15_CP1_I_11 : 8|8@1+ (1,0) [0|255] "A"  PC
 SG_ M2P_TMS_R_15_CP1_r_11 : 16|8@1+ (100,0) [0|25500] "rpm"  PC
 SG_ M2P_TMS_R_TEM_11 : 24|1@1+ (1,0) [0|1] ""  PC
 SG_ M2P_TMS_R_WPS_11 : 25|1@1+ (1,0) [0|1] ""  PC
 SG_ Reserved_3 : 26|1@1+ (1,0) [0|1] ""  PC
 SG_ M2P_TMS_R_15_fan_fault_11 : 27|5@1+ (1,0) [0|31] ""  PC
 SG_ M2P_TMS_R_15_fre_fault_11 : 32|8@1+ (1,0) [0|255] ""  PC
 SG_ M2P_TMS_R_15_D_fault_11 : 40|8@1+ (1,0) [0|255] ""  PC
 SG_ M2P_TMS_R_FAN_PWM_11 : 48|8@1+ (1,0) [0|255] ""  PC
 SG_ M2P_TMS_R_25_FAN_PWM_11 : 56|8@1+ (1,0) [0|255] ""  PC

BO_ 2337533596 M2P_LiquidInfo_4__12: 8 MBMU
 SG_ M2P_TMS_R_15_CP1_vol_12 : 0|8@1+ (2,0) [0|510] "V"  PC
 SG_ M2P_TMS_R_15_CP1_I_12 : 8|8@1+ (1,0) [0|255] "A"  PC
 SG_ M2P_TMS_R_15_CP1_r_12 : 16|8@1+ (100,0) [0|25500] "rpm"  PC
 SG_ M2P_TMS_R_TEM_12 : 24|1@1+ (1,0) [0|1] ""  PC
 SG_ M2P_TMS_R_WPS_12 : 25|1@1+ (1,0) [0|1] ""  PC
 SG_ Reserved_3 : 26|1@1+ (1,0) [0|1] ""  PC
 SG_ M2P_TMS_R_15_fan_fault_12 : 27|5@1+ (1,0) [0|31] ""  PC
 SG_ M2P_TMS_R_15_fre_fault_12 : 32|8@1+ (1,0) [0|255] ""  PC
 SG_ M2P_TMS_R_15_D_fault_12 : 40|8@1+ (1,0) [0|255] ""  PC
 SG_ M2P_TMS_R_FAN_PWM_12 : 48|8@1+ (1,0) [0|255] ""  PC
 SG_ M2P_TMS_R_25_FAN_PWM_12 : 56|8@1+ (1,0) [0|255] ""  PC

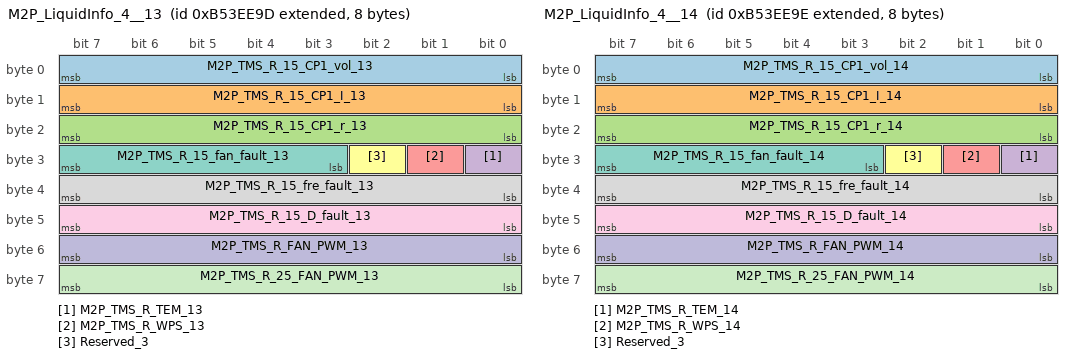
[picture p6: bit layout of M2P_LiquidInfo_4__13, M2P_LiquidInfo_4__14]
BO_ 2337533597 M2P_LiquidInfo_4__13: 8 MBMU
 SG_ M2P_TMS_R_15_CP1_vol_13 : 0|8@1+ (2,0) [0|510] "V"  PC
 SG_ M2P_TMS_R_15_CP1_I_13 : 8|8@1+ (1,0) [0|255] "A"  PC
 SG_ M2P_TMS_R_15_CP1_r_13 : 16|8@1+ (100,0) [0|25500] "rpm"  PC
 SG_ M2P_TMS_R_TEM_13 : 24|1@1+ (1,0) [0|1] ""  PC
 SG_ M2P_TMS_R_WPS_13 : 25|1@1+ (1,0) [0|1] ""  PC
 SG_ Reserved_3 : 26|1@1+ (1,0) [0|1] ""  PC
 SG_ M2P_TMS_R_15_fan_fault_13 : 27|5@1+ (1,0) [0|31] ""  PC
 SG_ M2P_TMS_R_15_fre_fault_13 : 32|8@1+ (1,0) [0|255] ""  PC
 SG_ M2P_TMS_R_15_D_fault_13 : 40|8@1+ (1,0) [0|255] ""  PC
 SG_ M2P_TMS_R_FAN_PWM_13 : 48|8@1+ (1,0) [0|255] ""  PC
 SG_ M2P_TMS_R_25_FAN_PWM_13 : 56|8@1+ (1,0) [0|255] ""  PC

BO_ 2337533598 M2P_LiquidInfo_4__14: 8 MBMU
 SG_ M2P_TMS_R_15_CP1_vol_14 : 0|8@1+ (2,0) [0|510] "V"  PC
 SG_ M2P_TMS_R_15_CP1_I_14 : 8|8@1+ (1,0) [0|255] "A"  PC
 SG_ M2P_TMS_R_15_CP1_r_14 : 16|8@1+ (100,0) [0|25500] "rpm"  PC
 SG_ M2P_TMS_R_TEM_14 : 24|1@1+ (1,0) [0|1] ""  PC
 SG_ M2P_TMS_R_WPS_14 : 25|1@1+ (1,0) [0|1] ""  PC
 SG_ Reserved_3 : 26|1@1+ (1,0) [0|1] ""  PC
 SG_ M2P_TMS_R_15_fan_fault_14 : 27|5@1+ (1,0) [0|31] ""  PC
 SG_ M2P_TMS_R_15_fre_fault_14 : 32|8@1+ (1,0) [0|255] ""  PC
 SG_ M2P_TMS_R_15_D_fault_14 : 40|8@1+ (1,0) [0|255] ""  PC
 SG_ M2P_TMS_R_FAN_PWM_14 : 48|8@1+ (1,0) [0|255] ""  PC
 SG_ M2P_TMS_R_25_FAN_PWM_14 : 56|8@1+ (1,0) [0|255] ""  PC

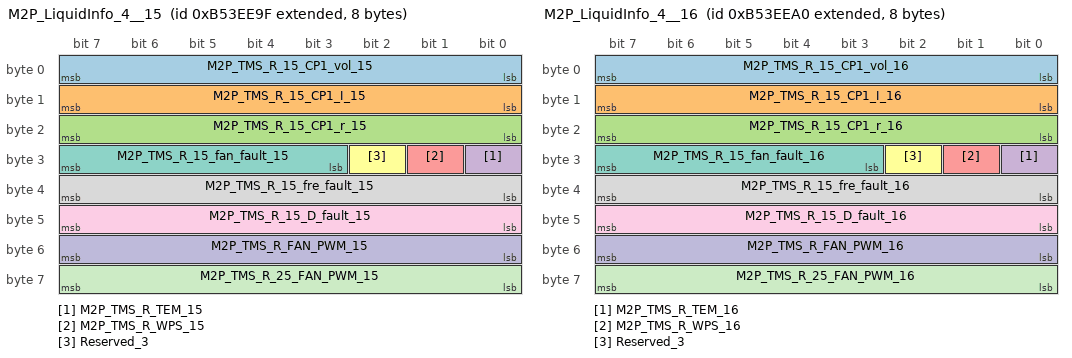
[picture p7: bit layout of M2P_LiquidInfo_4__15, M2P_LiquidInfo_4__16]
BO_ 2337533599 M2P_LiquidInfo_4__15: 8 MBMU
 SG_ M2P_TMS_R_15_CP1_vol_15 : 0|8@1+ (2,0) [0|510] "V"  PC
 SG_ M2P_TMS_R_15_CP1_I_15 : 8|8@1+ (1,0) [0|255] "A"  PC
 SG_ M2P_TMS_R_15_CP1_r_15 : 16|8@1+ (100,0) [0|25500] "rpm"  PC
 SG_ M2P_TMS_R_TEM_15 : 24|1@1+ (1,0) [0|1] ""  PC
 SG_ M2P_TMS_R_WPS_15 : 25|1@1+ (1,0) [0|1] ""  PC
 SG_ Reserved_3 : 26|1@1+ (1,0) [0|1] ""  PC
 SG_ M2P_TMS_R_15_fan_fault_15 : 27|5@1+ (1,0) [0|31] ""  PC
 SG_ M2P_TMS_R_15_fre_fault_15 : 32|8@1+ (1,0) [0|255] ""  PC
 SG_ M2P_TMS_R_15_D_fault_15 : 40|8@1+ (1,0) [0|255] ""  PC
 SG_ M2P_TMS_R_FAN_PWM_15 : 48|8@1+ (1,0) [0|255] ""  PC
 SG_ M2P_TMS_R_25_FAN_PWM_15 : 56|8@1+ (1,0) [0|255] ""  PC

BO_ 2337533600 M2P_LiquidInfo_4__16: 8 MBMU
 SG_ M2P_TMS_R_15_CP1_vol_16 : 0|8@1+ (2,0) [0|510] "V"  PC
 SG_ M2P_TMS_R_15_CP1_I_16 : 8|8@1+ (1,0) [0|255] "A"  PC
 SG_ M2P_TMS_R_15_CP1_r_16 : 16|8@1+ (100,0) [0|25500] "rpm"  PC
 SG_ M2P_TMS_R_TEM_16 : 24|1@1+ (1,0) [0|1] ""  PC
 SG_ M2P_TMS_R_WPS_16 : 25|1@1+ (1,0) [0|1] ""  PC
 SG_ Reserved_3 : 26|1@1+ (1,0) [0|1] ""  PC
 SG_ M2P_TMS_R_15_fan_fault_16 : 27|5@1+ (1,0) [0|31] ""  PC
 SG_ M2P_TMS_R_15_fre_fault_16 : 32|8@1+ (1,0) [0|255] ""  PC
 SG_ M2P_TMS_R_15_D_fault_16 : 40|8@1+ (1,0) [0|255] ""  PC
 SG_ M2P_TMS_R_FAN_PWM_16 : 48|8@1+ (1,0) [0|255] ""  PC
 SG_ M2P_TMS_R_25_FAN_PWM_16 : 56|8@1+ (1,0) [0|255] ""  PC

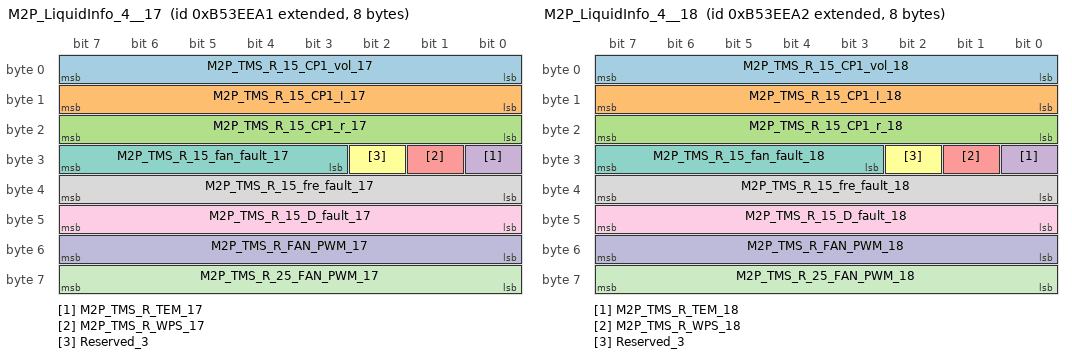
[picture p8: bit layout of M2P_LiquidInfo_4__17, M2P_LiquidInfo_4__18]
BO_ 2337533601 M2P_LiquidInfo_4__17: 8 MBMU
 SG_ M2P_TMS_R_15_CP1_vol_17 : 0|8@1+ (2,0) [0|510] "V"  PC
 SG_ M2P_TMS_R_15_CP1_I_17 : 8|8@1+ (1,0) [0|255] "A"  PC
 SG_ M2P_TMS_R_15_CP1_r_17 : 16|8@1+ (100,0) [0|25500] "rpm"  PC
 SG_ M2P_TMS_R_TEM_17 : 24|1@1+ (1,0) [0|1] ""  PC
 SG_ M2P_TMS_R_WPS_17 : 25|1@1+ (1,0) [0|1] ""  PC
 SG_ Reserved_3 : 26|1@1+ (1,0) [0|1] ""  PC
 SG_ M2P_TMS_R_15_fan_fault_17 : 27|5@1+ (1,0) [0|31] ""  PC
 SG_ M2P_TMS_R_15_fre_fault_17 : 32|8@1+ (1,0) [0|255] ""  PC
 SG_ M2P_TMS_R_15_D_fault_17 : 40|8@1+ (1,0) [0|255] ""  PC
 SG_ M2P_TMS_R_FAN_PWM_17 : 48|8@1+ (1,0) [0|255] ""  PC
 SG_ M2P_TMS_R_25_FAN_PWM_17 : 56|8@1+ (1,0) [0|255] ""  PC

BO_ 2337533602 M2P_LiquidInfo_4__18: 8 MBMU
 SG_ M2P_TMS_R_15_CP1_vol_18 : 0|8@1+ (2,0) [0|510] "V"  PC
 SG_ M2P_TMS_R_15_CP1_I_18 : 8|8@1+ (1,0) [0|255] "A"  PC
 SG_ M2P_TMS_R_15_CP1_r_18 : 16|8@1+ (100,0) [0|25500] "rpm"  PC
 SG_ M2P_TMS_R_TEM_18 : 24|1@1+ (1,0) [0|1] ""  PC
 SG_ M2P_TMS_R_WPS_18 : 25|1@1+ (1,0) [0|1] ""  PC
 SG_ Reserved_3 : 26|1@1+ (1,0) [0|1] ""  PC
 SG_ M2P_TMS_R_15_fan_fault_18 : 27|5@1+ (1,0) [0|31] ""  PC
 SG_ M2P_TMS_R_15_fre_fault_18 : 32|8@1+ (1,0) [0|255] ""  PC
 SG_ M2P_TMS_R_15_D_fault_18 : 40|8@1+ (1,0) [0|255] ""  PC
 SG_ M2P_TMS_R_FAN_PWM_18 : 48|8@1+ (1,0) [0|255] ""  PC
 SG_ M2P_TMS_R_25_FAN_PWM_18 : 56|8@1+ (1,0) [0|255] ""  PC

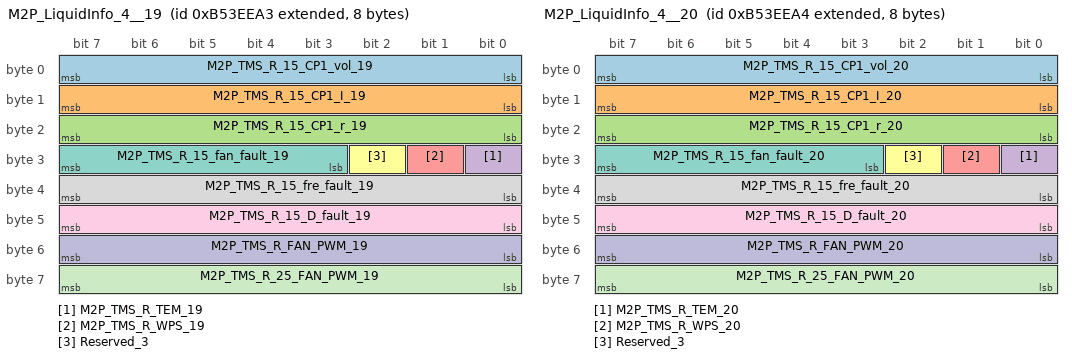
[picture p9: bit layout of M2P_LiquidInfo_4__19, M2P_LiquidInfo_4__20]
BO_ 2337533603 M2P_LiquidInfo_4__19: 8 MBMU
 SG_ M2P_TMS_R_15_CP1_vol_19 : 0|8@1+ (2,0) [0|510] "V"  PC
 SG_ M2P_TMS_R_15_CP1_I_19 : 8|8@1+ (1,0) [0|255] "A"  PC
 SG_ M2P_TMS_R_15_CP1_r_19 : 16|8@1+ (100,0) [0|25500] "rpm"  PC
 SG_ M2P_TMS_R_TEM_19 : 24|1@1+ (1,0) [0|1] ""  PC
 SG_ M2P_TMS_R_WPS_19 : 25|1@1+ (1,0) [0|1] ""  PC
 SG_ Reserved_3 : 26|1@1+ (1,0) [0|1] ""  PC
 SG_ M2P_TMS_R_15_fan_fault_19 : 27|5@1+ (1,0) [0|31] ""  PC
 SG_ M2P_TMS_R_15_fre_fault_19 : 32|8@1+ (1,0) [0|255] ""  PC
 SG_ M2P_TMS_R_15_D_fault_19 : 40|8@1+ (1,0) [0|255] ""  PC
 SG_ M2P_TMS_R_FAN_PWM_19 : 48|8@1+ (1,0) [0|255] ""  PC
 SG_ M2P_TMS_R_25_FAN_PWM_19 : 56|8@1+ (1,0) [0|255] ""  PC

BO_ 2337533604 M2P_LiquidInfo_4__20: 8 MBMU
 SG_ M2P_TMS_R_15_CP1_vol_20 : 0|8@1+ (2,0) [0|510] "V"  PC
 SG_ M2P_TMS_R_15_CP1_I_20 : 8|8@1+ (1,0) [0|255] "A"  PC
 SG_ M2P_TMS_R_15_CP1_r_20 : 16|8@1+ (100,0) [0|25500] "rpm"  PC
 SG_ M2P_TMS_R_TEM_20 : 24|1@1+ (1,0) [0|1] ""  PC
 SG_ M2P_TMS_R_WPS_20 : 25|1@1+ (1,0) [0|1] ""  PC
 SG_ Reserved_3 : 26|1@1+ (1,0) [0|1] ""  PC
 SG_ M2P_TMS_R_15_fan_fault_20 : 27|5@1+ (1,0) [0|31] ""  PC
 SG_ M2P_TMS_R_15_fre_fault_20 : 32|8@1+ (1,0) [0|255] ""  PC
 SG_ M2P_TMS_R_15_D_fault_20 : 40|8@1+ (1,0) [0|255] ""  PC
 SG_ M2P_TMS_R_FAN_PWM_20 : 48|8@1+ (1,0) [0|255] ""  PC
 SG_ M2P_TMS_R_25_FAN_PWM_20 : 56|8@1+ (1,0) [0|255] ""  PC

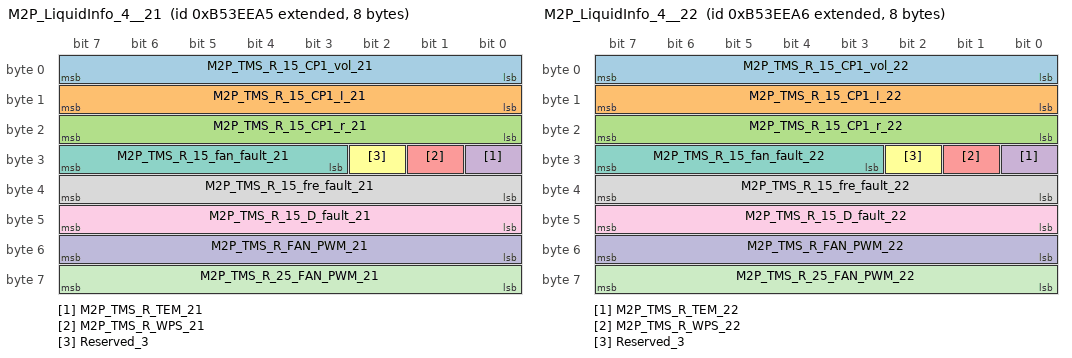
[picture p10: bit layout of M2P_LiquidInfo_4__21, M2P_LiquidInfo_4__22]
BO_ 2337533605 M2P_LiquidInfo_4__21: 8 MBMU
 SG_ M2P_TMS_R_15_CP1_vol_21 : 0|8@1+ (2,0) [0|510] "V"  PC
 SG_ M2P_TMS_R_15_CP1_I_21 : 8|8@1+ (1,0) [0|255] "A"  PC
 SG_ M2P_TMS_R_15_CP1_r_21 : 16|8@1+ (100,0) [0|25500] "rpm"  PC
 SG_ M2P_TMS_R_TEM_21 : 24|1@1+ (1,0) [0|1] ""  PC
 SG_ M2P_TMS_R_WPS_21 : 25|1@1+ (1,0) [0|1] ""  PC
 SG_ Reserved_3 : 26|1@1+ (1,0) [0|1] ""  PC
 SG_ M2P_TMS_R_15_fan_fault_21 : 27|5@1+ (1,0) [0|31] ""  PC
 SG_ M2P_TMS_R_15_fre_fault_21 : 32|8@1+ (1,0) [0|255] ""  PC
 SG_ M2P_TMS_R_15_D_fault_21 : 40|8@1+ (1,0) [0|255] ""  PC
 SG_ M2P_TMS_R_FAN_PWM_21 : 48|8@1+ (1,0) [0|255] ""  PC
 SG_ M2P_TMS_R_25_FAN_PWM_21 : 56|8@1+ (1,0) [0|255] ""  PC

BO_ 2337533606 M2P_LiquidInfo_4__22: 8 MBMU
 SG_ M2P_TMS_R_15_CP1_vol_22 : 0|8@1+ (2,0) [0|510] "V"  PC
 SG_ M2P_TMS_R_15_CP1_I_22 : 8|8@1+ (1,0) [0|255] "A"  PC
 SG_ M2P_TMS_R_15_CP1_r_22 : 16|8@1+ (100,0) [0|25500] "rpm"  PC
 SG_ M2P_TMS_R_TEM_22 : 24|1@1+ (1,0) [0|1] ""  PC
 SG_ M2P_TMS_R_WPS_22 : 25|1@1+ (1,0) [0|1] ""  PC
 SG_ Reserved_3 : 26|1@1+ (1,0) [0|1] ""  PC
 SG_ M2P_TMS_R_15_fan_fault_22 : 27|5@1+ (1,0) [0|31] ""  PC
 SG_ M2P_TMS_R_15_fre_fault_22 : 32|8@1+ (1,0) [0|255] ""  PC
 SG_ M2P_TMS_R_15_D_fault_22 : 40|8@1+ (1,0) [0|255] ""  PC
 SG_ M2P_TMS_R_FAN_PWM_22 : 48|8@1+ (1,0) [0|255] ""  PC
 SG_ M2P_TMS_R_25_FAN_PWM_22 : 56|8@1+ (1,0) [0|255] ""  PC

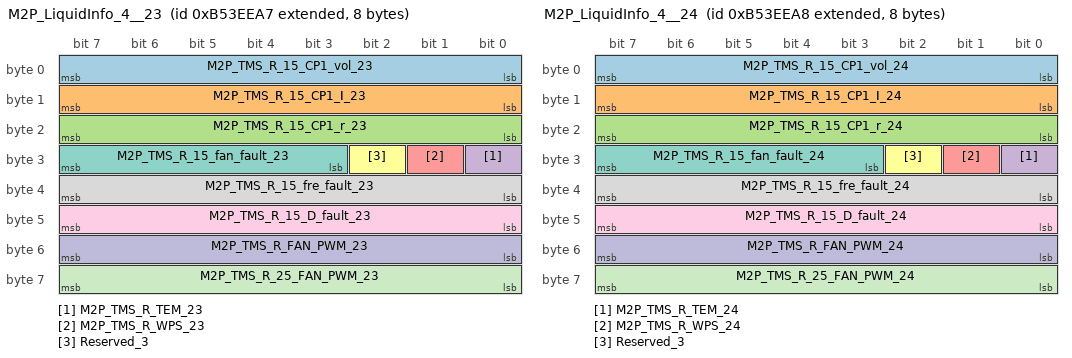
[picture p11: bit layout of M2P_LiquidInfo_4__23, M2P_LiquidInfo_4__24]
BO_ 2337533607 M2P_LiquidInfo_4__23: 8 MBMU
 SG_ M2P_TMS_R_15_CP1_vol_23 : 0|8@1+ (2,0) [0|510] "V"  PC
 SG_ M2P_TMS_R_15_CP1_I_23 : 8|8@1+ (1,0) [0|255] "A"  PC
 SG_ M2P_TMS_R_15_CP1_r_23 : 16|8@1+ (100,0) [0|25500] "rpm"  PC
 SG_ M2P_TMS_R_TEM_23 : 24|1@1+ (1,0) [0|1] ""  PC
 SG_ M2P_TMS_R_WPS_23 : 25|1@1+ (1,0) [0|1] ""  PC
 SG_ Reserved_3 : 26|1@1+ (1,0) [0|1] ""  PC
 SG_ M2P_TMS_R_15_fan_fault_23 : 27|5@1+ (1,0) [0|31] ""  PC
 SG_ M2P_TMS_R_15_fre_fault_23 : 32|8@1+ (1,0) [0|255] ""  PC
 SG_ M2P_TMS_R_15_D_fault_23 : 40|8@1+ (1,0) [0|255] ""  PC
 SG_ M2P_TMS_R_FAN_PWM_23 : 48|8@1+ (1,0) [0|255] ""  PC
 SG_ M2P_TMS_R_25_FAN_PWM_23 : 56|8@1+ (1,0) [0|255] ""  PC

BO_ 2337533608 M2P_LiquidInfo_4__24: 8 MBMU
 SG_ M2P_TMS_R_15_CP1_vol_24 : 0|8@1+ (2,0) [0|510] "V"  PC
 SG_ M2P_TMS_R_15_CP1_I_24 : 8|8@1+ (1,0) [0|255] "A"  PC
 SG_ M2P_TMS_R_15_CP1_r_24 : 16|8@1+ (100,0) [0|25500] "rpm"  PC
 SG_ M2P_TMS_R_TEM_24 : 24|1@1+ (1,0) [0|1] ""  PC
 SG_ M2P_TMS_R_WPS_24 : 25|1@1+ (1,0) [0|1] ""  PC
 SG_ Reserved_3 : 26|1@1+ (1,0) [0|1] ""  PC
 SG_ M2P_TMS_R_15_fan_fault_24 : 27|5@1+ (1,0) [0|31] ""  PC
 SG_ M2P_TMS_R_15_fre_fault_24 : 32|8@1+ (1,0) [0|255] ""  PC
 SG_ M2P_TMS_R_15_D_fault_24 : 40|8@1+ (1,0) [0|255] ""  PC
 SG_ M2P_TMS_R_FAN_PWM_24 : 48|8@1+ (1,0) [0|255] ""  PC
 SG_ M2P_TMS_R_25_FAN_PWM_24 : 56|8@1+ (1,0) [0|255] ""  PC

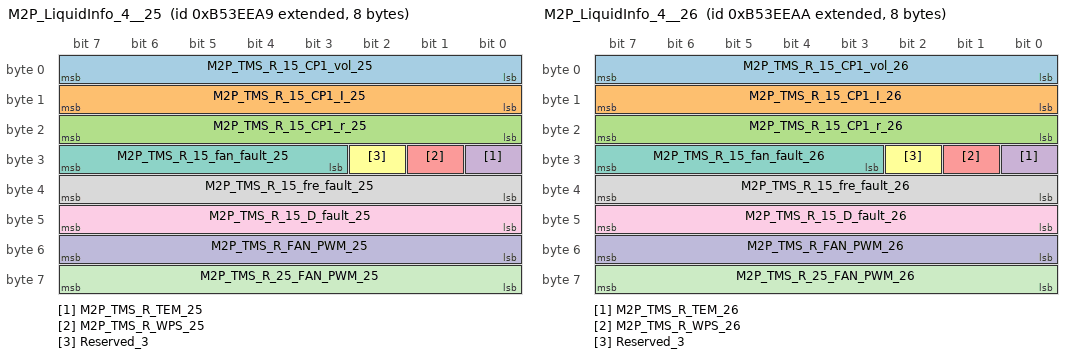
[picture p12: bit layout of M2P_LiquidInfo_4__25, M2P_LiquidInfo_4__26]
BO_ 2337533609 M2P_LiquidInfo_4__25: 8 MBMU
 SG_ M2P_TMS_R_15_CP1_vol_25 : 0|8@1+ (2,0) [0|510] "V"  PC
 SG_ M2P_TMS_R_15_CP1_I_25 : 8|8@1+ (1,0) [0|255] "A"  PC
 SG_ M2P_TMS_R_15_CP1_r_25 : 16|8@1+ (100,0) [0|25500] "rpm"  PC
 SG_ M2P_TMS_R_TEM_25 : 24|1@1+ (1,0) [0|1] ""  PC
 SG_ M2P_TMS_R_WPS_25 : 25|1@1+ (1,0) [0|1] ""  PC
 SG_ Reserved_3 : 26|1@1+ (1,0) [0|1] ""  PC
 SG_ M2P_TMS_R_15_fan_fault_25 : 27|5@1+ (1,0) [0|31] ""  PC
 SG_ M2P_TMS_R_15_fre_fault_25 : 32|8@1+ (1,0) [0|255] ""  PC
 SG_ M2P_TMS_R_15_D_fault_25 : 40|8@1+ (1,0) [0|255] ""  PC
 SG_ M2P_TMS_R_FAN_PWM_25 : 48|8@1+ (1,0) [0|255] ""  PC
 SG_ M2P_TMS_R_25_FAN_PWM_25 : 56|8@1+ (1,0) [0|255] ""  PC

BO_ 2337533610 M2P_LiquidInfo_4__26: 8 MBMU
 SG_ M2P_TMS_R_15_CP1_vol_26 : 0|8@1+ (2,0) [0|510] "V"  PC
 SG_ M2P_TMS_R_15_CP1_I_26 : 8|8@1+ (1,0) [0|255] "A"  PC
 SG_ M2P_TMS_R_15_CP1_r_26 : 16|8@1+ (100,0) [0|25500] "rpm"  PC
 SG_ M2P_TMS_R_TEM_26 : 24|1@1+ (1,0) [0|1] ""  PC
 SG_ M2P_TMS_R_WPS_26 : 25|1@1+ (1,0) [0|1] ""  PC
 SG_ Reserved_3 : 26|1@1+ (1,0) [0|1] ""  PC
 SG_ M2P_TMS_R_15_fan_fault_26 : 27|5@1+ (1,0) [0|31] ""  PC
 SG_ M2P_TMS_R_15_fre_fault_26 : 32|8@1+ (1,0) [0|255] ""  PC
 SG_ M2P_TMS_R_15_D_fault_26 : 40|8@1+ (1,0) [0|255] ""  PC
 SG_ M2P_TMS_R_FAN_PWM_26 : 48|8@1+ (1,0) [0|255] ""  PC
 SG_ M2P_TMS_R_25_FAN_PWM_26 : 56|8@1+ (1,0) [0|255] ""  PC

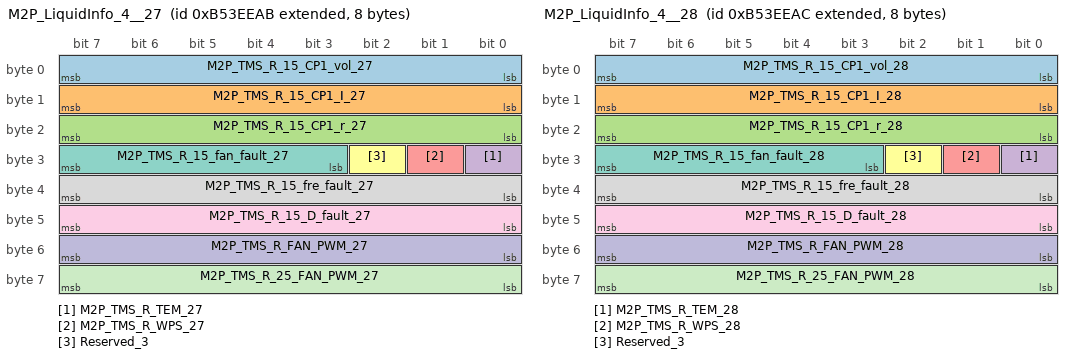
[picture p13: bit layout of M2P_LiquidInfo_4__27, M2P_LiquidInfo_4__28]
BO_ 2337533611 M2P_LiquidInfo_4__27: 8 MBMU
 SG_ M2P_TMS_R_15_CP1_vol_27 : 0|8@1+ (2,0) [0|510] "V"  PC
 SG_ M2P_TMS_R_15_CP1_I_27 : 8|8@1+ (1,0) [0|255] "A"  PC
 SG_ M2P_TMS_R_15_CP1_r_27 : 16|8@1+ (100,0) [0|25500] "rpm"  PC
 SG_ M2P_TMS_R_TEM_27 : 24|1@1+ (1,0) [0|1] ""  PC
 SG_ M2P_TMS_R_WPS_27 : 25|1@1+ (1,0) [0|1] ""  PC
 SG_ Reserved_3 : 26|1@1+ (1,0) [0|1] ""  PC
 SG_ M2P_TMS_R_15_fan_fault_27 : 27|5@1+ (1,0) [0|31] ""  PC
 SG_ M2P_TMS_R_15_fre_fault_27 : 32|8@1+ (1,0) [0|255] ""  PC
 SG_ M2P_TMS_R_15_D_fault_27 : 40|8@1+ (1,0) [0|255] ""  PC
 SG_ M2P_TMS_R_FAN_PWM_27 : 48|8@1+ (1,0) [0|255] ""  PC
 SG_ M2P_TMS_R_25_FAN_PWM_27 : 56|8@1+ (1,0) [0|255] ""  PC

BO_ 2337533612 M2P_LiquidInfo_4__28: 8 MBMU
 SG_ M2P_TMS_R_15_CP1_vol_28 : 0|8@1+ (2,0) [0|510] "V"  PC
 SG_ M2P_TMS_R_15_CP1_I_28 : 8|8@1+ (1,0) [0|255] "A"  PC
 SG_ M2P_TMS_R_15_CP1_r_28 : 16|8@1+ (100,0) [0|25500] "rpm"  PC
 SG_ M2P_TMS_R_TEM_28 : 24|1@1+ (1,0) [0|1] ""  PC
 SG_ M2P_TMS_R_WPS_28 : 25|1@1+ (1,0) [0|1] ""  PC
 SG_ Reserved_3 : 26|1@1+ (1,0) [0|1] ""  PC
 SG_ M2P_TMS_R_15_fan_fault_28 : 27|5@1+ (1,0) [0|31] ""  PC
 SG_ M2P_TMS_R_15_fre_fault_28 : 32|8@1+ (1,0) [0|255] ""  PC
 SG_ M2P_TMS_R_15_D_fault_28 : 40|8@1+ (1,0) [0|255] ""  PC
 SG_ M2P_TMS_R_FAN_PWM_28 : 48|8@1+ (1,0) [0|255] ""  PC
 SG_ M2P_TMS_R_25_FAN_PWM_28 : 56|8@1+ (1,0) [0|255] ""  PC

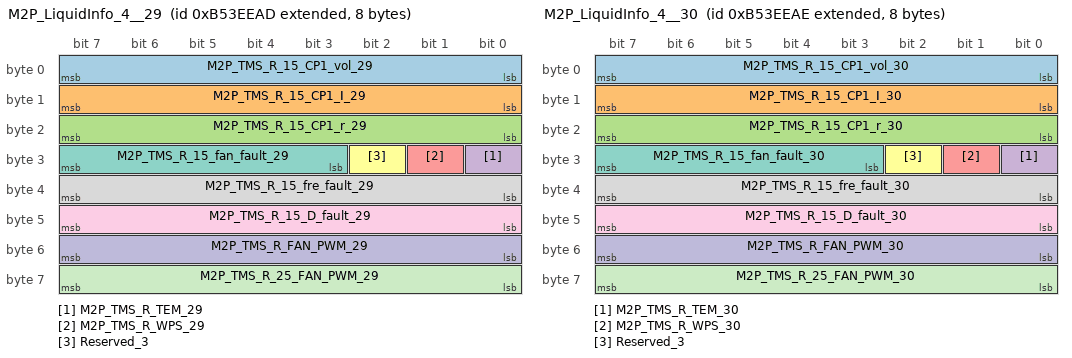
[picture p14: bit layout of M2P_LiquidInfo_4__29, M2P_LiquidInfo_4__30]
BO_ 2337533613 M2P_LiquidInfo_4__29: 8 MBMU
 SG_ M2P_TMS_R_15_CP1_vol_29 : 0|8@1+ (2,0) [0|510] "V"  PC
 SG_ M2P_TMS_R_15_CP1_I_29 : 8|8@1+ (1,0) [0|255] "A"  PC
 SG_ M2P_TMS_R_15_CP1_r_29 : 16|8@1+ (100,0) [0|25500] "rpm"  PC
 SG_ M2P_TMS_R_TEM_29 : 24|1@1+ (1,0) [0|1] ""  PC
 SG_ M2P_TMS_R_WPS_29 : 25|1@1+ (1,0) [0|1] ""  PC
 SG_ Reserved_3 : 26|1@1+ (1,0) [0|1] ""  PC
 SG_ M2P_TMS_R_15_fan_fault_29 : 27|5@1+ (1,0) [0|31] ""  PC
 SG_ M2P_TMS_R_15_fre_fault_29 : 32|8@1+ (1,0) [0|255] ""  PC
 SG_ M2P_TMS_R_15_D_fault_29 : 40|8@1+ (1,0) [0|255] ""  PC
 SG_ M2P_TMS_R_FAN_PWM_29 : 48|8@1+ (1,0) [0|255] ""  PC
 SG_ M2P_TMS_R_25_FAN_PWM_29 : 56|8@1+ (1,0) [0|255] ""  PC

BO_ 2337533614 M2P_LiquidInfo_4__30: 8 MBMU
 SG_ M2P_TMS_R_15_CP1_vol_30 : 0|8@1+ (2,0) [0|510] "V"  PC
 SG_ M2P_TMS_R_15_CP1_I_30 : 8|8@1+ (1,0) [0|255] "A"  PC
 SG_ M2P_TMS_R_15_CP1_r_30 : 16|8@1+ (100,0) [0|25500] "rpm"  PC
 SG_ M2P_TMS_R_TEM_30 : 24|1@1+ (1,0) [0|1] ""  PC
 SG_ M2P_TMS_R_WPS_30 : 25|1@1+ (1,0) [0|1] ""  PC
 SG_ Reserved_3 : 26|1@1+ (1,0) [0|1] ""  PC
 SG_ M2P_TMS_R_15_fan_fault_30 : 27|5@1+ (1,0) [0|31] ""  PC
 SG_ M2P_TMS_R_15_fre_fault_30 : 32|8@1+ (1,0) [0|255] ""  PC
 SG_ M2P_TMS_R_15_D_fault_30 : 40|8@1+ (1,0) [0|255] ""  PC
 SG_ M2P_TMS_R_FAN_PWM_30 : 48|8@1+ (1,0) [0|255] ""  PC
 SG_ M2P_TMS_R_25_FAN_PWM_30 : 56|8@1+ (1,0) [0|255] ""  PC

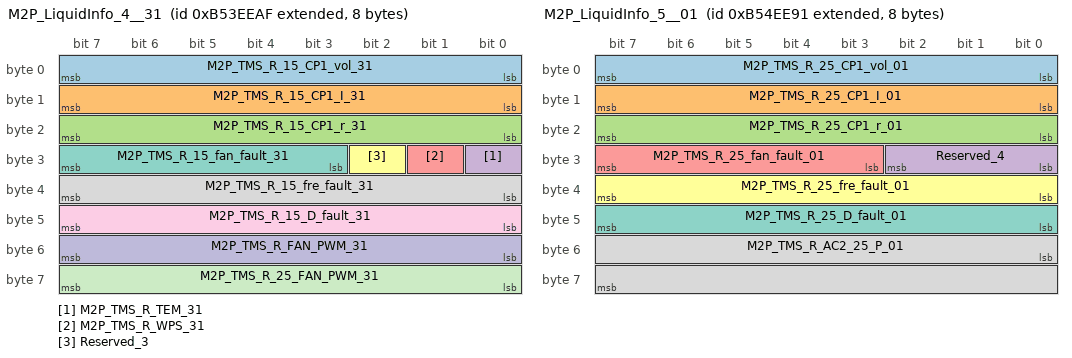
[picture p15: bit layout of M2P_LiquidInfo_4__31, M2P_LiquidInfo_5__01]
BO_ 2337533615 M2P_LiquidInfo_4__31: 8 MBMU
 SG_ M2P_TMS_R_15_CP1_vol_31 : 0|8@1+ (2,0) [0|510] "V"  PC
 SG_ M2P_TMS_R_15_CP1_I_31 : 8|8@1+ (1,0) [0|255] "A"  PC
 SG_ M2P_TMS_R_15_CP1_r_31 : 16|8@1+ (100,0) [0|25500] "rpm"  PC
 SG_ M2P_TMS_R_TEM_31 : 24|1@1+ (1,0) [0|1] ""  PC
 SG_ M2P_TMS_R_WPS_31 : 25|1@1+ (1,0) [0|1] ""  PC
 SG_ Reserved_3 : 26|1@1+ (1,0) [0|1] ""  PC
 SG_ M2P_TMS_R_15_fan_fault_31 : 27|5@1+ (1,0) [0|31] ""  PC
 SG_ M2P_TMS_R_15_fre_fault_31 : 32|8@1+ (1,0) [0|255] ""  PC
 SG_ M2P_TMS_R_15_D_fault_31 : 40|8@1+ (1,0) [0|255] ""  PC
 SG_ M2P_TMS_R_FAN_PWM_31 : 48|8@1+ (1,0) [0|255] ""  PC
 SG_ M2P_TMS_R_25_FAN_PWM_31 : 56|8@1+ (1,0) [0|255] ""  PC

BO_ 2337599121 M2P_LiquidInfo_5__01: 8 MBMU
 SG_ M2P_TMS_R_25_CP1_vol_01 : 0|8@1+ (2,0) [0|510] "V"  PC
 SG_ M2P_TMS_R_25_CP1_I_01 : 8|8@1+ (1,0) [0|255] "A"  PC
 SG_ M2P_TMS_R_25_CP1_r_01 : 16|8@1+ (100,0) [0|25500] "rpm"  PC
 SG_ Reserved_4 : 24|3@1+ (1,0) [0|7] ""  PC
 SG_ M2P_TMS_R_25_fan_fault_01 : 27|5@1+ (1,0) [0|31] ""  PC
 SG_ M2P_TMS_R_25_fre_fault_01 : 32|8@1+ (1,0) [0|255] ""  PC
 SG_ M2P_TMS_R_25_D_fault_01 : 40|8@1+ (1,0) [0|255] ""  PC
 SG_ M2P_TMS_R_AC2_25_P_01 : 48|16@1+ (1,0) [0|65535] ""  PC

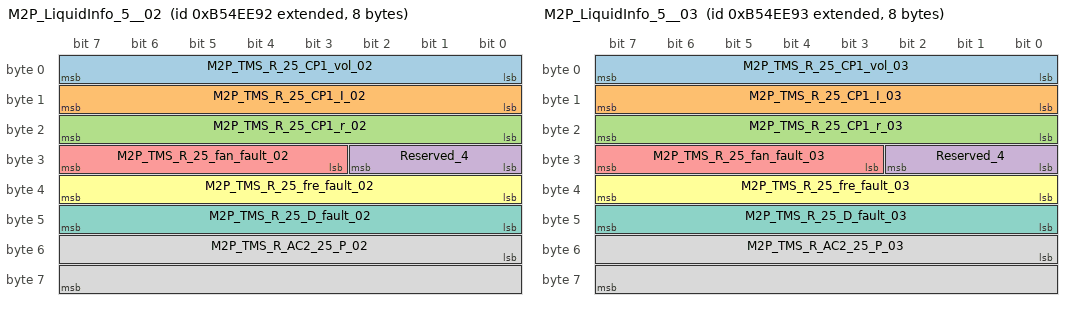
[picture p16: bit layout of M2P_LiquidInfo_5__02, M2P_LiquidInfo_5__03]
BO_ 2337599122 M2P_LiquidInfo_5__02: 8 MBMU
 SG_ M2P_TMS_R_25_CP1_vol_02 : 0|8@1+ (2,0) [0|510] "V"  PC
 SG_ M2P_TMS_R_25_CP1_I_02 : 8|8@1+ (1,0) [0|255] "A"  PC
 SG_ M2P_TMS_R_25_CP1_r_02 : 16|8@1+ (100,0) [0|25500] "rpm"  PC
 SG_ Reserved_4 : 24|3@1+ (1,0) [0|7] ""  PC
 SG_ M2P_TMS_R_25_fan_fault_02 : 27|5@1+ (1,0) [0|31] ""  PC
 SG_ M2P_TMS_R_25_fre_fault_02 : 32|8@1+ (1,0) [0|255] ""  PC
 SG_ M2P_TMS_R_25_D_fault_02 : 40|8@1+ (1,0) [0|255] ""  PC
 SG_ M2P_TMS_R_AC2_25_P_02 : 48|16@1+ (1,0) [0|65535] ""  PC

BO_ 2337599123 M2P_LiquidInfo_5__03: 8 MBMU
 SG_ M2P_TMS_R_25_CP1_vol_03 : 0|8@1+ (2,0) [0|510] "V"  PC
 SG_ M2P_TMS_R_25_CP1_I_03 : 8|8@1+ (1,0) [0|255] "A"  PC
 SG_ M2P_TMS_R_25_CP1_r_03 : 16|8@1+ (100,0) [0|25500] "rpm"  PC
 SG_ Reserved_4 : 24|3@1+ (1,0) [0|7] ""  PC
 SG_ M2P_TMS_R_25_fan_fault_03 : 27|5@1+ (1,0) [0|31] ""  PC
 SG_ M2P_TMS_R_25_fre_fault_03 : 32|8@1+ (1,0) [0|255] ""  PC
 SG_ M2P_TMS_R_25_D_fault_03 : 40|8@1+ (1,0) [0|255] ""  PC
 SG_ M2P_TMS_R_AC2_25_P_03 : 48|16@1+ (1,0) [0|65535] ""  PC

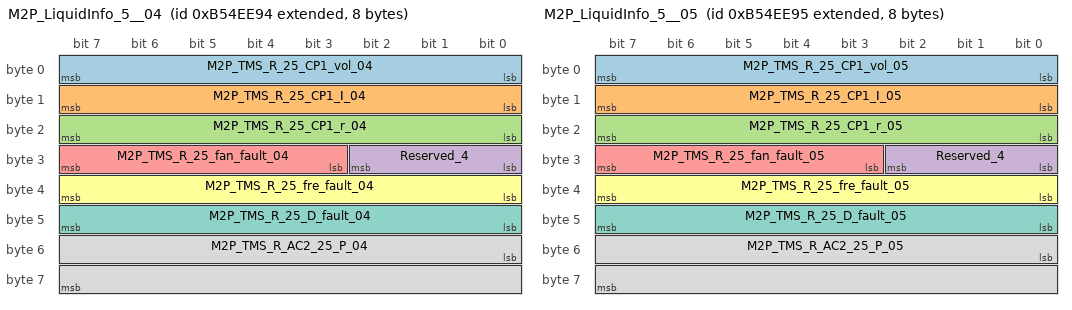
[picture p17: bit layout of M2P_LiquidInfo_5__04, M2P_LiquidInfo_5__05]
BO_ 2337599124 M2P_LiquidInfo_5__04: 8 MBMU
 SG_ M2P_TMS_R_25_CP1_vol_04 : 0|8@1+ (2,0) [0|510] "V"  PC
 SG_ M2P_TMS_R_25_CP1_I_04 : 8|8@1+ (1,0) [0|255] "A"  PC
 SG_ M2P_TMS_R_25_CP1_r_04 : 16|8@1+ (100,0) [0|25500] "rpm"  PC
 SG_ Reserved_4 : 24|3@1+ (1,0) [0|7] ""  PC
 SG_ M2P_TMS_R_25_fan_fault_04 : 27|5@1+ (1,0) [0|31] ""  PC
 SG_ M2P_TMS_R_25_fre_fault_04 : 32|8@1+ (1,0) [0|255] ""  PC
 SG_ M2P_TMS_R_25_D_fault_04 : 40|8@1+ (1,0) [0|255] ""  PC
 SG_ M2P_TMS_R_AC2_25_P_04 : 48|16@1+ (1,0) [0|65535] ""  PC

BO_ 2337599125 M2P_LiquidInfo_5__05: 8 MBMU
 SG_ M2P_TMS_R_25_CP1_vol_05 : 0|8@1+ (2,0) [0|510] "V"  PC
 SG_ M2P_TMS_R_25_CP1_I_05 : 8|8@1+ (1,0) [0|255] "A"  PC
 SG_ M2P_TMS_R_25_CP1_r_05 : 16|8@1+ (100,0) [0|25500] "rpm"  PC
 SG_ Reserved_4 : 24|3@1+ (1,0) [0|7] ""  PC
 SG_ M2P_TMS_R_25_fan_fault_05 : 27|5@1+ (1,0) [0|31] ""  PC
 SG_ M2P_TMS_R_25_fre_fault_05 : 32|8@1+ (1,0) [0|255] ""  PC
 SG_ M2P_TMS_R_25_D_fault_05 : 40|8@1+ (1,0) [0|255] ""  PC
 SG_ M2P_TMS_R_AC2_25_P_05 : 48|16@1+ (1,0) [0|65535] ""  PC

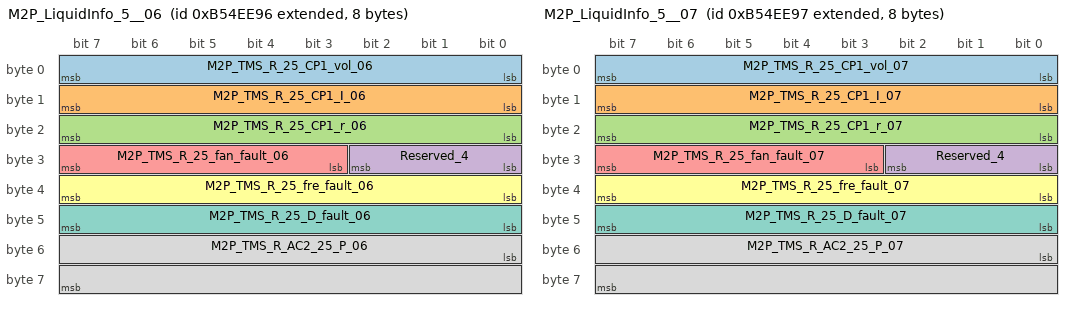
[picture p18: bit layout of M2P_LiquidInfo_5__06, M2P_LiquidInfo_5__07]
BO_ 2337599126 M2P_LiquidInfo_5__06: 8 MBMU
 SG_ M2P_TMS_R_25_CP1_vol_06 : 0|8@1+ (2,0) [0|510] "V"  PC
 SG_ M2P_TMS_R_25_CP1_I_06 : 8|8@1+ (1,0) [0|255] "A"  PC
 SG_ M2P_TMS_R_25_CP1_r_06 : 16|8@1+ (100,0) [0|25500] "rpm"  PC
 SG_ Reserved_4 : 24|3@1+ (1,0) [0|7] ""  PC
 SG_ M2P_TMS_R_25_fan_fault_06 : 27|5@1+ (1,0) [0|31] ""  PC
 SG_ M2P_TMS_R_25_fre_fault_06 : 32|8@1+ (1,0) [0|255] ""  PC
 SG_ M2P_TMS_R_25_D_fault_06 : 40|8@1+ (1,0) [0|255] ""  PC
 SG_ M2P_TMS_R_AC2_25_P_06 : 48|16@1+ (1,0) [0|65535] ""  PC

BO_ 2337599127 M2P_LiquidInfo_5__07: 8 MBMU
 SG_ M2P_TMS_R_25_CP1_vol_07 : 0|8@1+ (2,0) [0|510] "V"  PC
 SG_ M2P_TMS_R_25_CP1_I_07 : 8|8@1+ (1,0) [0|255] "A"  PC
 SG_ M2P_TMS_R_25_CP1_r_07 : 16|8@1+ (100,0) [0|25500] "rpm"  PC
 SG_ Reserved_4 : 24|3@1+ (1,0) [0|7] ""  PC
 SG_ M2P_TMS_R_25_fan_fault_07 : 27|5@1+ (1,0) [0|31] ""  PC
 SG_ M2P_TMS_R_25_fre_fault_07 : 32|8@1+ (1,0) [0|255] ""  PC
 SG_ M2P_TMS_R_25_D_fault_07 : 40|8@1+ (1,0) [0|255] ""  PC
 SG_ M2P_TMS_R_AC2_25_P_07 : 48|16@1+ (1,0) [0|65535] ""  PC

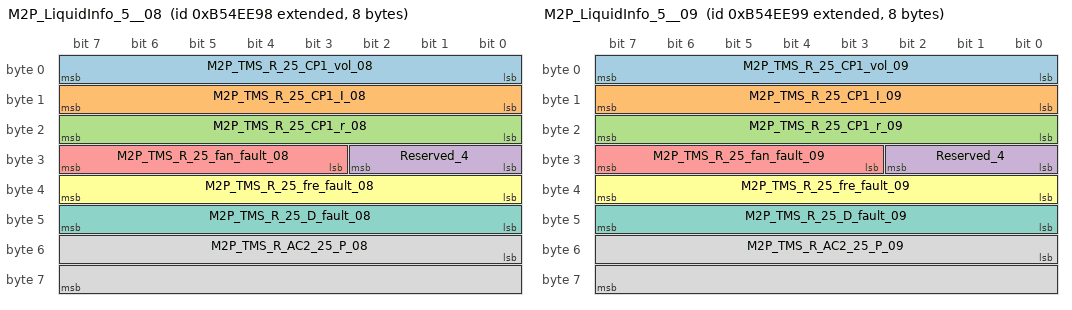
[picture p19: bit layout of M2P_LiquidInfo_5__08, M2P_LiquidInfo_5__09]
BO_ 2337599128 M2P_LiquidInfo_5__08: 8 MBMU
 SG_ M2P_TMS_R_25_CP1_vol_08 : 0|8@1+ (2,0) [0|510] "V"  PC
 SG_ M2P_TMS_R_25_CP1_I_08 : 8|8@1+ (1,0) [0|255] "A"  PC
 SG_ M2P_TMS_R_25_CP1_r_08 : 16|8@1+ (100,0) [0|25500] "rpm"  PC
 SG_ Reserved_4 : 24|3@1+ (1,0) [0|7] ""  PC
 SG_ M2P_TMS_R_25_fan_fault_08 : 27|5@1+ (1,0) [0|31] ""  PC
 SG_ M2P_TMS_R_25_fre_fault_08 : 32|8@1+ (1,0) [0|255] ""  PC
 SG_ M2P_TMS_R_25_D_fault_08 : 40|8@1+ (1,0) [0|255] ""  PC
 SG_ M2P_TMS_R_AC2_25_P_08 : 48|16@1+ (1,0) [0|65535] ""  PC

BO_ 2337599129 M2P_LiquidInfo_5__09: 8 MBMU
 SG_ M2P_TMS_R_25_CP1_vol_09 : 0|8@1+ (2,0) [0|510] "V"  PC
 SG_ M2P_TMS_R_25_CP1_I_09 : 8|8@1+ (1,0) [0|255] "A"  PC
 SG_ M2P_TMS_R_25_CP1_r_09 : 16|8@1+ (100,0) [0|25500] "rpm"  PC
 SG_ Reserved_4 : 24|3@1+ (1,0) [0|7] ""  PC
 SG_ M2P_TMS_R_25_fan_fault_09 : 27|5@1+ (1,0) [0|31] ""  PC
 SG_ M2P_TMS_R_25_fre_fault_09 : 32|8@1+ (1,0) [0|255] ""  PC
 SG_ M2P_TMS_R_25_D_fault_09 : 40|8@1+ (1,0) [0|255] ""  PC
 SG_ M2P_TMS_R_AC2_25_P_09 : 48|16@1+ (1,0) [0|65535] ""  PC

BO_ 2337599130 M2P_LiquidInfo_5__10: 8 MBMU
 SG_ M2P_TMS_R_25_CP1_vol_10 : 0|8@1+ (2,0) [0|510] "V"  PC
 SG_ M2P_TMS_R_25_CP1_I_10 : 8|8@1+ (1,0) [0|255] "A"  PC
 SG_ M2P_TMS_R_25_CP1_r_10 : 16|8@1+ (100,0) [0|25500] "rpm"  PC
 SG_ Reserved_4 : 24|3@1+ (1,0) [0|7] ""  PC
 SG_ M2P_TMS_R_25_fan_fault_10 : 27|5@1+ (1,0) [0|31] ""  PC
 SG_ M2P_TMS_R_25_fre_fault_10 : 32|8@1+ (1,0) [0|255] ""  PC
 SG_ M2P_TMS_R_25_D_fault_10 : 40|8@1+ (1,0) [0|255] ""  PC
 SG_ M2P_TMS_R_AC2_25_P_10 : 48|16@1+ (1,0) [0|65535] ""  PC

BO_ 2337599131 M2P_LiquidInfo_5__11: 8 MBMU
 SG_ M2P_TMS_R_25_CP1_vol_11 : 0|8@1+ (2,0) [0|510] "V"  PC
 SG_ M2P_TMS_R_25_CP1_I_11 : 8|8@1+ (1,0) [0|255] "A"  PC
 SG_ M2P_TMS_R_25_CP1_r_11 : 16|8@1+ (100,0) [0|25500] "rpm"  PC
 SG_ Reserved_4 : 24|3@1+ (1,0) [0|7] ""  PC
 SG_ M2P_TMS_R_25_fan_fault_11 : 27|5@1+ (1,0) [0|31] ""  PC
 SG_ M2P_TMS_R_25_fre_fault_11 : 32|8@1+ (1,0) [0|255] ""  PC
 SG_ M2P_TMS_R_25_D_fault_11 : 40|8@1+ (1,0) [0|255] ""  PC
 SG_ M2P_TMS_R_AC2_25_P_11 : 48|16@1+ (1,0) [0|65535] ""  PC

BO_ 2337599132 M2P_LiquidInfo_5__12: 8 MBMU
 SG_ M2P_TMS_R_25_CP1_vol_12 : 0|8@1+ (2,0) [0|510] "V"  PC
 SG_ M2P_TMS_R_25_CP1_I_12 : 8|8@1+ (1,0) [0|255] "A"  PC
 SG_ M2P_TMS_R_25_CP1_r_12 : 16|8@1+ (100,0) [0|25500] "rpm"  PC
 SG_ Reserved_4 : 24|3@1+ (1,0) [0|7] ""  PC
 SG_ M2P_TMS_R_25_fan_fault_12 : 27|5@1+ (1,0) [0|31] ""  PC
 SG_ M2P_TMS_R_25_fre_fault_12 : 32|8@1+ (1,0) [0|255] ""  PC
 SG_ M2P_TMS_R_25_D_fault_12 : 40|8@1+ (1,0) [0|255] ""  PC
 SG_ M2P_TMS_R_AC2_25_P_12 : 48|16@1+ (1,0) [0|65535] ""  PC

BO_ 2337599133 M2P_LiquidInfo_5__13: 8 MBMU
 SG_ M2P_TMS_R_25_CP1_vol_13 : 0|8@1+ (2,0) [0|510] "V"  PC
 SG_ M2P_TMS_R_25_CP1_I_13 : 8|8@1+ (1,0) [0|255] "A"  PC
 SG_ M2P_TMS_R_25_CP1_r_13 : 16|8@1+ (100,0) [0|25500] "rpm"  PC
 SG_ Reserved_4 : 24|3@1+ (1,0) [0|7] ""  PC
 SG_ M2P_TMS_R_25_fan_fault_13 : 27|5@1+ (1,0) [0|31] ""  PC
 SG_ M2P_TMS_R_25_fre_fault_13 : 32|8@1+ (1,0) [0|255] ""  PC
 SG_ M2P_TMS_R_25_D_fault_13 : 40|8@1+ (1,0) [0|255] ""  PC
 SG_ M2P_TMS_R_AC2_25_P_13 : 48|16@1+ (1,0) [0|65535] ""  PC

BO_ 2337599134 M2P_LiquidInfo_5__14: 8 MBMU
 SG_ M2P_TMS_R_25_CP1_vol_14 : 0|8@1+ (2,0) [0|510] "V"  PC
 SG_ M2P_TMS_R_25_CP1_I_14 : 8|8@1+ (1,0) [0|255] "A"  PC
 SG_ M2P_TMS_R_25_CP1_r_14 : 16|8@1+ (100,0) [0|25500] "rpm"  PC
 SG_ Reserved_4 : 24|3@1+ (1,0) [0|7] ""  PC
 SG_ M2P_TMS_R_25_fan_fault_14 : 27|5@1+ (1,0) [0|31] ""  PC
 SG_ M2P_TMS_R_25_fre_fault_14 : 32|8@1+ (1,0) [0|255] ""  PC
 SG_ M2P_TMS_R_25_D_fault_14 : 40|8@1+ (1,0) [0|255] ""  PC
 SG_ M2P_TMS_R_AC2_25_P_14 : 48|16@1+ (1,0) [0|65535] ""  PC

BO_ 2337599135 M2P_LiquidInfo_5__15: 8 MBMU
 SG_ M2P_TMS_R_25_CP1_vol_15 : 0|8@1+ (2,0) [0|510] "V"  PC
 SG_ M2P_TMS_R_25_CP1_I_15 : 8|8@1+ (1,0) [0|255] "A"  PC
 SG_ M2P_TMS_R_25_CP1_r_15 : 16|8@1+ (100,0) [0|25500] "rpm"  PC
 SG_ Reserved_4 : 24|3@1+ (1,0) [0|7] ""  PC
 SG_ M2P_TMS_R_25_fan_fault_15 : 27|5@1+ (1,0) [0|31] ""  PC
 SG_ M2P_TMS_R_25_fre_fault_15 : 32|8@1+ (1,0) [0|255] ""  PC
 SG_ M2P_TMS_R_25_D_fault_15 : 40|8@1+ (1,0) [0|255] ""  PC
 SG_ M2P_TMS_R_AC2_25_P_15 : 48|16@1+ (1,0) [0|65535] ""  PC

BO_ 2337599136 M2P_LiquidInfo_5__16: 8 MBMU
 SG_ M2P_TMS_R_25_CP1_vol_16 : 0|8@1+ (2,0) [0|510] "V"  PC
 SG_ M2P_TMS_R_25_CP1_I_16 : 8|8@1+ (1,0) [0|255] "A"  PC
 SG_ M2P_TMS_R_25_CP1_r_16 : 16|8@1+ (100,0) [0|25500] "rpm"  PC
 SG_ Reserved_4 : 24|3@1+ (1,0) [0|7] ""  PC
 SG_ M2P_TMS_R_25_fan_fault_16 : 27|5@1+ (1,0) [0|31] ""  PC
 SG_ M2P_TMS_R_25_fre_fault_16 : 32|8@1+ (1,0) [0|255] ""  PC
 SG_ M2P_TMS_R_25_D_fault_16 : 40|8@1+ (1,0) [0|255] ""  PC
 SG_ M2P_TMS_R_AC2_25_P_16 : 48|16@1+ (1,0) [0|65535] ""  PC

BO_ 2337599137 M2P_LiquidInfo_5__17: 8 MBMU
 SG_ M2P_TMS_R_25_CP1_vol_17 : 0|8@1+ (2,0) [0|510] "V"  PC
 SG_ M2P_TMS_R_25_CP1_I_17 : 8|8@1+ (1,0) [0|255] "A"  PC
 SG_ M2P_TMS_R_25_CP1_r_17 : 16|8@1+ (100,0) [0|25500] "rpm"  PC
 SG_ Reserved_4 : 24|3@1+ (1,0) [0|7] ""  PC
 SG_ M2P_TMS_R_25_fan_fault_17 : 27|5@1+ (1,0) [0|31] ""  PC
 SG_ M2P_TMS_R_25_fre_fault_17 : 32|8@1+ (1,0) [0|255] ""  PC
 SG_ M2P_TMS_R_25_D_fault_17 : 40|8@1+ (1,0) [0|255] ""  PC
 SG_ M2P_TMS_R_AC2_25_P_17 : 48|16@1+ (1,0) [0|65535] ""  PC

BO_ 2337599138 M2P_LiquidInfo_5__18: 8 MBMU
 SG_ M2P_TMS_R_25_CP1_vol_18 : 0|8@1+ (2,0) [0|510] "V"  PC
 SG_ M2P_TMS_R_25_CP1_I_18 : 8|8@1+ (1,0) [0|255] "A"  PC
 SG_ M2P_TMS_R_25_CP1_r_18 : 16|8@1+ (100,0) [0|25500] "rpm"  PC
 SG_ Reserved_4 : 24|3@1+ (1,0) [0|7] ""  PC
 SG_ M2P_TMS_R_25_fan_fault_18 : 27|5@1+ (1,0) [0|31] ""  PC
 SG_ M2P_TMS_R_25_fre_fault_18 : 32|8@1+ (1,0) [0|255] ""  PC
 SG_ M2P_TMS_R_25_D_fault_18 : 40|8@1+ (1,0) [0|255] ""  PC
 SG_ M2P_TMS_R_AC2_25_P_18 : 48|16@1+ (1,0) [0|65535] ""  PC

BO_ 2337599139 M2P_LiquidInfo_5__19: 8 MBMU
 SG_ M2P_TMS_R_25_CP1_vol_19 : 0|8@1+ (2,0) [0|510] "V"  PC
 SG_ M2P_TMS_R_25_CP1_I_19 : 8|8@1+ (1,0) [0|255] "A"  PC
 SG_ M2P_TMS_R_25_CP1_r_19 : 16|8@1+ (100,0) [0|25500] "rpm"  PC
 SG_ Reserved_4 : 24|3@1+ (1,0) [0|7] ""  PC
 SG_ M2P_TMS_R_25_fan_fault_19 : 27|5@1+ (1,0) [0|31] ""  PC
 SG_ M2P_TMS_R_25_fre_fault_19 : 32|8@1+ (1,0) [0|255] ""  PC
 SG_ M2P_TMS_R_25_D_fault_19 : 40|8@1+ (1,0) [0|255] ""  PC
 SG_ M2P_TMS_R_AC2_25_P_19 : 48|16@1+ (1,0) [0|65535] ""  PC

BO_ 2337599140 M2P_LiquidInfo_5__20: 8 MBMU
 SG_ M2P_TMS_R_25_CP1_vol_20 : 0|8@1+ (2,0) [0|510] "V"  PC
 SG_ M2P_TMS_R_25_CP1_I_20 : 8|8@1+ (1,0) [0|255] "A"  PC
 SG_ M2P_TMS_R_25_CP1_r_20 : 16|8@1+ (100,0) [0|25500] "rpm"  PC
 SG_ Reserved_4 : 24|3@1+ (1,0) [0|7] ""  PC
 SG_ M2P_TMS_R_25_fan_fault_20 : 27|5@1+ (1,0) [0|31] ""  PC
 SG_ M2P_TMS_R_25_fre_fault_20 : 32|8@1+ (1,0) [0|255] ""  PC
 SG_ M2P_TMS_R_25_D_fault_20 : 40|8@1+ (1,0) [0|255] ""  PC
 SG_ M2P_TMS_R_AC2_25_P_20 : 48|16@1+ (1,0) [0|65535] ""  PC

BO_ 2337599141 M2P_LiquidInfo_5__21: 8 MBMU
 SG_ M2P_TMS_R_25_CP1_vol_21 : 0|8@1+ (2,0) [0|510] "V"  PC
 SG_ M2P_TMS_R_25_CP1_I_21 : 8|8@1+ (1,0) [0|255] "A"  PC
 SG_ M2P_TMS_R_25_CP1_r_21 : 16|8@1+ (100,0) [0|25500] "rpm"  PC
 SG_ Reserved_4 : 24|3@1+ (1,0) [0|7] ""  PC
 SG_ M2P_TMS_R_25_fan_fault_21 : 27|5@1+ (1,0) [0|31] ""  PC
 SG_ M2P_TMS_R_25_fre_fault_21 : 32|8@1+ (1,0) [0|255] ""  PC
 SG_ M2P_TMS_R_25_D_fault_21 : 40|8@1+ (1,0) [0|255] ""  PC
 SG_ M2P_TMS_R_AC2_25_P_21 : 48|16@1+ (1,0) [0|65535] ""  PC

BO_ 2337599142 M2P_LiquidInfo_5__22: 8 MBMU
 SG_ M2P_TMS_R_25_CP1_vol_22 : 0|8@1+ (2,0) [0|510] "V"  PC
 SG_ M2P_TMS_R_25_CP1_I_22 : 8|8@1+ (1,0) [0|255] "A"  PC
 SG_ M2P_TMS_R_25_CP1_r_22 : 16|8@1+ (100,0) [0|25500] "rpm"  PC
 SG_ Reserved_4 : 24|3@1+ (1,0) [0|7] ""  PC
 SG_ M2P_TMS_R_25_fan_fault_22 : 27|5@1+ (1,0) [0|31] ""  PC
 SG_ M2P_TMS_R_25_fre_fault_22 : 32|8@1+ (1,0) [0|255] ""  PC
 SG_ M2P_TMS_R_25_D_fault_22 : 40|8@1+ (1,0) [0|255] ""  PC
 SG_ M2P_TMS_R_AC2_25_P_22 : 48|16@1+ (1,0) [0|65535] ""  PC

BO_ 2337599143 M2P_LiquidInfo_5__23: 8 MBMU
 SG_ M2P_TMS_R_25_CP1_vol_23 : 0|8@1+ (2,0) [0|510] "V"  PC
 SG_ M2P_TMS_R_25_CP1_I_23 : 8|8@1+ (1,0) [0|255] "A"  PC
 SG_ M2P_TMS_R_25_CP1_r_23 : 16|8@1+ (100,0) [0|25500] "rpm"  PC
 SG_ Reserved_4 : 24|3@1+ (1,0) [0|7] ""  PC
 SG_ M2P_TMS_R_25_fan_fault_23 : 27|5@1+ (1,0) [0|31] ""  PC
 SG_ M2P_TMS_R_25_fre_fault_23 : 32|8@1+ (1,0) [0|255] ""  PC
 SG_ M2P_TMS_R_25_D_fault_23 : 40|8@1+ (1,0) [0|255] ""  PC
 SG_ M2P_TMS_R_AC2_25_P_23 : 48|16@1+ (1,0) [0|65535] ""  PC

BO_ 2337599144 M2P_LiquidInfo_5__24: 8 MBMU
 SG_ M2P_TMS_R_25_CP1_vol_24 : 0|8@1+ (2,0) [0|510] "V"  PC
 SG_ M2P_TMS_R_25_CP1_I_24 : 8|8@1+ (1,0) [0|255] "A"  PC
 SG_ M2P_TMS_R_25_CP1_r_24 : 16|8@1+ (100,0) [0|25500] "rpm"  PC
 SG_ Reserved_4 : 24|3@1+ (1,0) [0|7] ""  PC
 SG_ M2P_TMS_R_25_fan_fault_24 : 27|5@1+ (1,0) [0|31] ""  PC
 SG_ M2P_TMS_R_25_fre_fault_24 : 32|8@1+ (1,0) [0|255] ""  PC
 SG_ M2P_TMS_R_25_D_fault_24 : 40|8@1+ (1,0) [0|255] ""  PC
 SG_ M2P_TMS_R_AC2_25_P_24 : 48|16@1+ (1,0) [0|65535] ""  PC

BO_ 2337599145 M2P_LiquidInfo_5__25: 8 MBMU
 SG_ M2P_TMS_R_25_CP1_vol_25 : 0|8@1+ (2,0) [0|510] "V"  PC
 SG_ M2P_TMS_R_25_CP1_I_25 : 8|8@1+ (1,0) [0|255] "A"  PC
 SG_ M2P_TMS_R_25_CP1_r_25 : 16|8@1+ (100,0) [0|25500] "rpm"  PC
 SG_ Reserved_4 : 24|3@1+ (1,0) [0|7] ""  PC
 SG_ M2P_TMS_R_25_fan_fault_25 : 27|5@1+ (1,0) [0|31] ""  PC
 SG_ M2P_TMS_R_25_fre_fault_25 : 32|8@1+ (1,0) [0|255] ""  PC
 SG_ M2P_TMS_R_25_D_fault_25 : 40|8@1+ (1,0) [0|255] ""  PC
 SG_ M2P_TMS_R_AC2_25_P_25 : 48|16@1+ (1,0) [0|65535] ""  PC

BO_ 2337599146 M2P_LiquidInfo_5__26: 8 MBMU
 SG_ M2P_TMS_R_25_CP1_vol_26 : 0|8@1+ (2,0) [0|510] "V"  PC
 SG_ M2P_TMS_R_25_CP1_I_26 : 8|8@1+ (1,0) [0|255] "A"  PC
 SG_ M2P_TMS_R_25_CP1_r_26 : 16|8@1+ (100,0) [0|25500] "rpm"  PC
 SG_ Reserved_4 : 24|3@1+ (1,0) [0|7] ""  PC
 SG_ M2P_TMS_R_25_fan_fault_26 : 27|5@1+ (1,0) [0|31] ""  PC
 SG_ M2P_TMS_R_25_fre_fault_26 : 32|8@1+ (1,0) [0|255] ""  PC
 SG_ M2P_TMS_R_25_D_fault_26 : 40|8@1+ (1,0) [0|255] ""  PC
 SG_ M2P_TMS_R_AC2_25_P_26 : 48|16@1+ (1,0) [0|65535] ""  PC

BO_ 2337599147 M2P_LiquidInfo_5__27: 8 MBMU
 SG_ M2P_TMS_R_25_CP1_vol_27 : 0|8@1+ (2,0) [0|510] "V"  PC
 SG_ M2P_TMS_R_25_CP1_I_27 : 8|8@1+ (1,0) [0|255] "A"  PC
 SG_ M2P_TMS_R_25_CP1_r_27 : 16|8@1+ (100,0) [0|25500] "rpm"  PC
 SG_ Reserved_4 : 24|3@1+ (1,0) [0|7] ""  PC
 SG_ M2P_TMS_R_25_fan_fault_27 : 27|5@1+ (1,0) [0|31] ""  PC
 SG_ M2P_TMS_R_25_fre_fault_27 : 32|8@1+ (1,0) [0|255] ""  PC
 SG_ M2P_TMS_R_25_D_fault_27 : 40|8@1+ (1,0) [0|255] ""  PC
 SG_ M2P_TMS_R_AC2_25_P_27 : 48|16@1+ (1,0) [0|65535] ""  PC

BO_ 2337599148 M2P_LiquidInfo_5__28: 8 MBMU
 SG_ M2P_TMS_R_25_CP1_vol_28 : 0|8@1+ (2,0) [0|510] "V"  PC
 SG_ M2P_TMS_R_25_CP1_I_28 : 8|8@1+ (1,0) [0|255] "A"  PC
 SG_ M2P_TMS_R_25_CP1_r_28 : 16|8@1+ (100,0) [0|25500] "rpm"  PC
 SG_ Reserved_4 : 24|3@1+ (1,0) [0|7] ""  PC
 SG_ M2P_TMS_R_25_fan_fault_28 : 27|5@1+ (1,0) [0|31] ""  PC
 SG_ M2P_TMS_R_25_fre_fault_28 : 32|8@1+ (1,0) [0|255] ""  PC
 SG_ M2P_TMS_R_25_D_fault_28 : 40|8@1+ (1,0) [0|255] ""  PC
 SG_ M2P_TMS_R_AC2_25_P_28 : 48|16@1+ (1,0) [0|65535] ""  PC

BO_ 2337599149 M2P_LiquidInfo_5__29: 8 MBMU
 SG_ M2P_TMS_R_25_CP1_vol_29 : 0|8@1+ (2,0) [0|510] "V"  PC
 SG_ M2P_TMS_R_25_CP1_I_29 : 8|8@1+ (1,0) [0|255] "A"  PC
 SG_ M2P_TMS_R_25_CP1_r_29 : 16|8@1+ (100,0) [0|25500] "rpm"  PC
 SG_ Reserved_4 : 24|3@1+ (1,0) [0|7] ""  PC
 SG_ M2P_TMS_R_25_fan_fault_29 : 27|5@1+ (1,0) [0|31] ""  PC
 SG_ M2P_TMS_R_25_fre_fault_29 : 32|8@1+ (1,0) [0|255] ""  PC
 SG_ M2P_TMS_R_25_D_fault_29 : 40|8@1+ (1,0) [0|255] ""  PC
 SG_ M2P_TMS_R_AC2_25_P_29 : 48|16@1+ (1,0) [0|65535] ""  PC

BO_ 2337599150 M2P_LiquidInfo_5__30: 8 MBMU
 SG_ M2P_TMS_R_25_CP1_vol_30 : 0|8@1+ (2,0) [0|510] "V"  PC
 SG_ M2P_TMS_R_25_CP1_I_30 : 8|8@1+ (1,0) [0|255] "A"  PC
 SG_ M2P_TMS_R_25_CP1_r_30 : 16|8@1+ (100,0) [0|25500] "rpm"  PC
 SG_ Reserved_4 : 24|3@1+ (1,0) [0|7] ""  PC
 SG_ M2P_TMS_R_25_fan_fault_30 : 27|5@1+ (1,0) [0|31] ""  PC
 SG_ M2P_TMS_R_25_fre_fault_30 : 32|8@1+ (1,0) [0|255] ""  PC
 SG_ M2P_TMS_R_25_D_fault_30 : 40|8@1+ (1,0) [0|255] ""  PC
 SG_ M2P_TMS_R_AC2_25_P_30 : 48|16@1+ (1,0) [0|65535] ""  PC

BO_ 2337599151 M2P_LiquidInfo_5__31: 8 MBMU
 SG_ M2P_TMS_R_25_CP1_vol_31 : 0|8@1+ (2,0) [0|510] "V"  PC
 SG_ M2P_TMS_R_25_CP1_I_31 : 8|8@1+ (1,0) [0|255] "A"  PC
 SG_ M2P_TMS_R_25_CP1_r_31 : 16|8@1+ (100,0) [0|25500] "rpm"  PC
 SG_ Reserved_4 : 24|3@1+ (1,0) [0|7] ""  PC
 SG_ M2P_TMS_R_25_fan_fault_31 : 27|5@1+ (1,0) [0|31] ""  PC
 SG_ M2P_TMS_R_25_fre_fault_31 : 32|8@1+ (1,0) [0|255] ""  PC
 SG_ M2P_TMS_R_25_D_fault_31 : 40|8@1+ (1,0) [0|255] ""  PC
 SG_ M2P_TMS_R_AC2_25_P_31 : 48|16@1+ (1,0) [0|65535] ""  PC

BO_ 2337664657 M2P_LiquidInfo_6__01: 8 MBMU
 SG_ M2P_TMS_R_S_version_01 : 0|40@1+ (1,0) [0|1099511627775] ""  PC
 SG_ M2P_TMS_R_N_S_version_01 : 40|24@1+ (1,0) [0|16777215] ""  PC

BO_ 2337664658 M2P_LiquidInfo_6__02: 8 MBMU
 SG_ M2P_TMS_R_S_version_02 : 0|40@1+ (1,0) [0|1099511627775] ""  PC
 SG_ M2P_TMS_R_N_S_version_02 : 40|24@1+ (1,0) [0|16777215] ""  PC

BO_ 2337664659 M2P_LiquidInfo_6__03: 8 MBMU
 SG_ M2P_TMS_R_S_version_03 : 0|40@1+ (1,0) [0|1099511627775] ""  PC
 SG_ M2P_TMS_R_N_S_version_03 : 40|24@1+ (1,0) [0|16777215] ""  PC

BO_ 2337664660 M2P_LiquidInfo_6__04: 8 MBMU
 SG_ M2P_TMS_R_S_version_04 : 0|40@1+ (1,0) [0|1099511627775] ""  PC
 SG_ M2P_TMS_R_N_S_version_04 : 40|24@1+ (1,0) [0|16777215] ""  PC

BO_ 2337664661 M2P_LiquidInfo_6__05: 8 MBMU
 SG_ M2P_TMS_R_S_version_05 : 0|40@1+ (1,0) [0|1099511627775] ""  PC
 SG_ M2P_TMS_R_N_S_version_05 : 40|24@1+ (1,0) [0|16777215] ""  PC

BO_ 2337664662 M2P_LiquidInfo_6__06: 8 MBMU
 SG_ M2P_TMS_R_S_version_06 : 0|40@1+ (1,0) [0|1099511627775] ""  PC
 SG_ M2P_TMS_R_N_S_version_06 : 40|24@1+ (1,0) [0|16777215] ""  PC

BO_ 2337664663 M2P_LiquidInfo_6__07: 8 MBMU
 SG_ M2P_TMS_R_S_version_07 : 0|40@1+ (1,0) [0|1099511627775] ""  PC
 SG_ M2P_TMS_R_N_S_version_07 : 40|24@1+ (1,0) [0|16777215] ""  PC

BO_ 2337664664 M2P_LiquidInfo_6__08: 8 MBMU
 SG_ M2P_TMS_R_S_version_08 : 0|40@1+ (1,0) [0|1099511627775] ""  PC
 SG_ M2P_TMS_R_N_S_version_08 : 40|24@1+ (1,0) [0|16777215] ""  PC

BO_ 2337664665 M2P_LiquidInfo_6__09: 8 MBMU
 SG_ M2P_TMS_R_S_version_09 : 0|40@1+ (1,0) [0|1099511627775] ""  PC
 SG_ M2P_TMS_R_N_S_version_09 : 40|24@1+ (1,0) [0|16777215] ""  PC

BO_ 2337664666 M2P_LiquidInfo_6__10: 8 MBMU
 SG_ M2P_TMS_R_S_version_10 : 0|40@1+ (1,0) [0|1099511627775] ""  PC
 SG_ M2P_TMS_R_N_S_version_10 : 40|24@1+ (1,0) [0|16777215] ""  PC

BO_ 2337664667 M2P_LiquidInfo_6__11: 8 MBMU
 SG_ M2P_TMS_R_S_version_11 : 0|40@1+ (1,0) [0|1099511627775] ""  PC
 SG_ M2P_TMS_R_N_S_version_11 : 40|24@1+ (1,0) [0|16777215] ""  PC

BO_ 2337664668 M2P_LiquidInfo_6__12: 8 MBMU
 SG_ M2P_TMS_R_S_version_12 : 0|40@1+ (1,0) [0|1099511627775] ""  PC
 SG_ M2P_TMS_R_N_S_version_12 : 40|24@1+ (1,0) [0|16777215] ""  PC

BO_ 2337664669 M2P_LiquidInfo_6__13: 8 MBMU
 SG_ M2P_TMS_R_S_version_13 : 0|40@1+ (1,0) [0|1099511627775] ""  PC
 SG_ M2P_TMS_R_N_S_version_13 : 40|24@1+ (1,0) [0|16777215] ""  PC

BO_ 2337664670 M2P_LiquidInfo_6__14: 8 MBMU
 SG_ M2P_TMS_R_S_version_14 : 0|40@1+ (1,0) [0|1099511627775] ""  PC
 SG_ M2P_TMS_R_N_S_version_14 : 40|24@1+ (1,0) [0|16777215] ""  PC

BO_ 2337664671 M2P_LiquidInfo_6__15: 8 MBMU
 SG_ M2P_TMS_R_S_version_15 : 0|40@1+ (1,0) [0|1099511627775] ""  PC
 SG_ M2P_TMS_R_N_S_version_15 : 40|24@1+ (1,0) [0|16777215] ""  PC

BO_ 2337664672 M2P_LiquidInfo_6__16: 8 MBMU
 SG_ M2P_TMS_R_S_version_16 : 0|40@1+ (1,0) [0|1099511627775] ""  PC
 SG_ M2P_TMS_R_N_S_version_16 : 40|24@1+ (1,0) [0|16777215] ""  PC

BO_ 2337664673 M2P_LiquidInfo_6__17: 8 MBMU
 SG_ M2P_TMS_R_S_version_17 : 0|40@1+ (1,0) [0|1099511627775] ""  PC
 SG_ M2P_TMS_R_N_S_version_17 : 40|24@1+ (1,0) [0|16777215] ""  PC

BO_ 2337664674 M2P_LiquidInfo_6__18: 8 MBMU
 SG_ M2P_TMS_R_S_version_18 : 0|40@1+ (1,0) [0|1099511627775] ""  PC
 SG_ M2P_TMS_R_N_S_version_18 : 40|24@1+ (1,0) [0|16777215] ""  PC

CM_ SG_ 2337468077 M2P_TMS_R_ACDC_A_vol_29 "2号TMS ACDC_A 电压";
CM_ SG_ 2337468077 M2P_TMS_R_15_pwm_29 "2号TMS 15kw风机PWM";
CM_ SG_ 2337468077 M2P_TMS_R_15_HP_29 "2号TMS AC1高压压力值(15kw)";
CM_ SG_ 2337468077 M2P_TMS_R_15_LP_29 "2号TMS AC1低压压力值(15kw)";
CM_ SG_ 2337468077 M2P_TMS_R_25_HP_29 "2号TMS AC2高压压力值(25kw)";
CM_ SG_ 2337468078 M2P_TMS_R_ACDC_A_vol_30 "2号TMS ACDC_A 电压";
CM_ SG_ 2337468078 M2P_TMS_R_15_pwm_30 "2号TMS 15kw风机PWM";
CM_ SG_ 2337468078 M2P_TMS_R_15_HP_30 "2号TMS AC1高压压力值(15kw)";
CM_ SG_ 2337468078 M2P_TMS_R_15_LP_30 "2号TMS AC1低压压力值(15kw)";
CM_ SG_ 2337468078 M2P_TMS_R_25_HP_30 "2号TMS AC2高压压力值(25kw)";
CM_ SG_ 2337468079 M2P_TMS_R_ACDC_A_vol_31 "2号TMS ACDC_A 电压";
CM_ SG_ 2337468079 M2P_TMS_R_15_pwm_31 "2号TMS 15kw风机PWM";
CM_ SG_ 2337468079 M2P_TMS_R_15_HP_31 "2号TMS AC1高压压力值(15kw)";
CM_ SG_ 2337468079 M2P_TMS_R_15_LP_31 "2号TMS AC1低压压力值(15kw)";
CM_ SG_ 2337468079 M2P_TMS_R_25_HP_31 "2号TMS AC2高压压力值(25kw)";
CM_ SG_ 2337533585 M2P_TMS_R_15_CP1_vol_01 "2号TMS压缩机1电压(15kw)";
CM_ SG_ 2337533585 M2P_TMS_R_15_CP1_I_01 "2号TMS压缩机1电流(15kw)";
CM_ SG_ 2337533585 M2P_TMS_R_15_CP1_r_01 "2号TMS压缩机1转速(15kw)";
CM_ SG_ 2337533585 M2P_TMS_R_TEM_01 "2号TMSPTC温度开关状态";
CM_ SG_ 2337533585 M2P_TMS_R_WPS_01 "2号TMS水泵开关";
CM_ SG_ 2337533585 Reserved_3 "预留";
CM_ SG_ 2337533585 M2P_TMS_R_15_fan_fault_01 "2号TMS风机故障(15kw)";
CM_ SG_ 2337533585 M2P_TMS_R_15_fre_fault_01 "2号TMS AC1故障(15kw变频器)";
CM_ SG_ 2337533585 M2P_TMS_R_15_D_fault_01 "2号TMSAC1故障(15kwDC/DC)";
CM_ SG_ 2337533585 M2P_TMS_R_FAN_PWM_01 "2号TMS冷却风机PWM占空比";
CM_ SG_ 2337533585 M2P_TMS_R_25_FAN_PWM_01 "2号TMS25kw风机PWM";
CM_ SG_ 2337533586 M2P_TMS_R_15_CP1_vol_02 "2号TMS压缩机1电压(15kw)";
CM_ SG_ 2337533586 M2P_TMS_R_15_CP1_I_02 "2号TMS压缩机1电流(15kw)";
CM_ SG_ 2337533586 M2P_TMS_R_15_CP1_r_02 "2号TMS压缩机1转速(15kw)";
CM_ SG_ 2337533586 M2P_TMS_R_TEM_02 "2号TMSPTC温度开关状态";
CM_ SG_ 2337533586 M2P_TMS_R_WPS_02 "2号TMS水泵开关";
CM_ SG_ 2337533586 Reserved_3 "预留";
CM_ SG_ 2337533586 M2P_TMS_R_15_fan_fault_02 "2号TMS风机故障(15kw)";
CM_ SG_ 2337533586 M2P_TMS_R_15_fre_fault_02 "2号TMS AC1故障(15kw变频器)";
CM_ SG_ 2337533586 M2P_TMS_R_15_D_fault_02 "2号TMSAC1故障(15kwDC/DC)";
CM_ SG_ 2337533586 M2P_TMS_R_FAN_PWM_02 "2号TMS冷却风机PWM占空比";
CM_ SG_ 2337533586 M2P_TMS_R_25_FAN_PWM_02 "2号TMS25kw风机PWM";
CM_ SG_ 2337533587 M2P_TMS_R_15_CP1_vol_03 "2号TMS压缩机1电压(15kw)";
CM_ SG_ 2337533587 M2P_TMS_R_15_CP1_I_03 "2号TMS压缩机1电流(15kw)";
CM_ SG_ 2337533587 M2P_TMS_R_15_CP1_r_03 "2号TMS压缩机1转速(15kw)";
CM_ SG_ 2337533587 M2P_TMS_R_TEM_03 "2号TMSPTC温度开关状态";
CM_ SG_ 2337533587 M2P_TMS_R_WPS_03 "2号TMS水泵开关";
CM_ SG_ 2337533587 Reserved_3 "预留";
CM_ SG_ 2337533587 M2P_TMS_R_15_fan_fault_03 "2号TMS风机故障(15kw)";
CM_ SG_ 2337533587 M2P_TMS_R_15_fre_fault_03 "2号TMS AC1故障(15kw变频器)";
CM_ SG_ 2337533587 M2P_TMS_R_15_D_fault_03 "2号TMSAC1故障(15kwDC/DC)";
CM_ SG_ 2337533587 M2P_TMS_R_FAN_PWM_03 "2号TMS冷却风机PWM占空比";
CM_ SG_ 2337533587 M2P_TMS_R_25_FAN_PWM_03 "2号TMS25kw风机PWM";
CM_ SG_ 2337533588 M2P_TMS_R_15_CP1_vol_04 "2号TMS压缩机1电压(15kw)";
CM_ SG_ 2337533588 M2P_TMS_R_15_CP1_I_04 "2号TMS压缩机1电流(15kw)";
CM_ SG_ 2337533588 M2P_TMS_R_15_CP1_r_04 "2号TMS压缩机1转速(15kw)";
CM_ SG_ 2337533588 M2P_TMS_R_TEM_04 "2号TMSPTC温度开关状态";
CM_ SG_ 2337533588 M2P_TMS_R_WPS_04 "2号TMS水泵开关";
CM_ SG_ 2337533588 Reserved_3 "预留";
CM_ SG_ 2337533588 M2P_TMS_R_15_fan_fault_04 "2号TMS风机故障(15kw)";
CM_ SG_ 2337533588 M2P_TMS_R_15_fre_fault_04 "2号TMS AC1故障(15kw变频器)";
CM_ SG_ 2337533588 M2P_TMS_R_15_D_fault_04 "2号TMSAC1故障(15kwDC/DC)";
CM_ SG_ 2337533588 M2P_TMS_R_FAN_PWM_04 "2号TMS冷却风机PWM占空比";
CM_ SG_ 2337533588 M2P_TMS_R_25_FAN_PWM_04 "2号TMS25kw风机PWM";
CM_ SG_ 2337533589 M2P_TMS_R_15_CP1_vol_05 "2号TMS压缩机1电压(15kw)";
CM_ SG_ 2337533589 M2P_TMS_R_15_CP1_I_05 "2号TMS压缩机1电流(15kw)";
CM_ SG_ 2337533589 M2P_TMS_R_15_CP1_r_05 "2号TMS压缩机1转速(15kw)";
CM_ SG_ 2337533589 M2P_TMS_R_TEM_05 "2号TMSPTC温度开关状态";
CM_ SG_ 2337533589 M2P_TMS_R_WPS_05 "2号TMS水泵开关";
CM_ SG_ 2337533589 Reserved_3 "预留";
CM_ SG_ 2337533589 M2P_TMS_R_15_fan_fault_05 "2号TMS风机故障(15kw)";
CM_ SG_ 2337533589 M2P_TMS_R_15_fre_fault_05 "2号TMS AC1故障(15kw变频器)";
CM_ SG_ 2337533589 M2P_TMS_R_15_D_fault_05 "2号TMSAC1故障(15kwDC/DC)";
CM_ SG_ 2337533589 M2P_TMS_R_FAN_PWM_05 "2号TMS冷却风机PWM占空比";
CM_ SG_ 2337533589 M2P_TMS_R_25_FAN_PWM_05 "2号TMS25kw风机PWM";
CM_ SG_ 2337533590 M2P_TMS_R_15_CP1_vol_06 "2号TMS压缩机1电压(15kw)";
CM_ SG_ 2337533590 M2P_TMS_R_15_CP1_I_06 "2号TMS压缩机1电流(15kw)";
CM_ SG_ 2337533590 M2P_TMS_R_15_CP1_r_06 "2号TMS压缩机1转速(15kw)";
CM_ SG_ 2337533590 M2P_TMS_R_TEM_06 "2号TMSPTC温度开关状态";
CM_ SG_ 2337533590 M2P_TMS_R_WPS_06 "2号TMS水泵开关";
CM_ SG_ 2337533590 Reserved_3 "预留";
CM_ SG_ 2337533590 M2P_TMS_R_15_fan_fault_06 "2号TMS风机故障(15kw)";
CM_ SG_ 2337533590 M2P_TMS_R_15_fre_fault_06 "2号TMS AC1故障(15kw变频器)";
CM_ SG_ 2337533590 M2P_TMS_R_15_D_fault_06 "2号TMSAC1故障(15kwDC/DC)";
CM_ SG_ 2337533590 M2P_TMS_R_FAN_PWM_06 "2号TMS冷却风机PWM占空比";
CM_ SG_ 2337533590 M2P_TMS_R_25_FAN_PWM_06 "2号TMS25kw风机PWM";
CM_ SG_ 2337533591 M2P_TMS_R_15_CP1_vol_07 "2号TMS压缩机1电压(15kw)";
CM_ SG_ 2337533591 M2P_TMS_R_15_CP1_I_07 "2号TMS压缩机1电流(15kw)";
CM_ SG_ 2337533591 M2P_TMS_R_15_CP1_r_07 "2号TMS压缩机1转速(15kw)";
CM_ SG_ 2337533591 M2P_TMS_R_TEM_07 "2号TMSPTC温度开关状态";
CM_ SG_ 2337533591 M2P_TMS_R_WPS_07 "2号TMS水泵开关";
CM_ SG_ 2337533591 Reserved_3 "预留";
CM_ SG_ 2337533591 M2P_TMS_R_15_fan_fault_07 "2号TMS风机故障(15kw)";
CM_ SG_ 2337533591 M2P_TMS_R_15_fre_fault_07 "2号TMS AC1故障(15kw变频器)";
CM_ SG_ 2337533591 M2P_TMS_R_15_D_fault_07 "2号TMSAC1故障(15kwDC/DC)";
CM_ SG_ 2337533591 M2P_TMS_R_FAN_PWM_07 "2号TMS冷却风机PWM占空比";
CM_ SG_ 2337533591 M2P_TMS_R_25_FAN_PWM_07 "2号TMS25kw风机PWM";
CM_ SG_ 2337533592 M2P_TMS_R_15_CP1_vol_08 "2号TMS压缩机1电压(15kw)";
CM_ SG_ 2337533592 M2P_TMS_R_15_CP1_I_08 "2号TMS压缩机1电流(15kw)";
CM_ SG_ 2337533592 M2P_TMS_R_15_CP1_r_08 "2号TMS压缩机1转速(15kw)";
CM_ SG_ 2337533592 M2P_TMS_R_TEM_08 "2号TMSPTC温度开关状态";
CM_ SG_ 2337533592 M2P_TMS_R_WPS_08 "2号TMS水泵开关";
CM_ SG_ 2337533592 Reserved_3 "预留";
CM_ SG_ 2337533592 M2P_TMS_R_15_fan_fault_08 "2号TMS风机故障(15kw)";
CM_ SG_ 2337533592 M2P_TMS_R_15_fre_fault_08 "2号TMS AC1故障(15kw变频器)";
CM_ SG_ 2337533592 M2P_TMS_R_15_D_fault_08 "2号TMSAC1故障(15kwDC/DC)";
CM_ SG_ 2337533592 M2P_TMS_R_FAN_PWM_08 "2号TMS冷却风机PWM占空比";
CM_ SG_ 2337533592 M2P_TMS_R_25_FAN_PWM_08 "2号TMS25kw风机PWM";
CM_ SG_ 2337533593 M2P_TMS_R_15_CP1_vol_09 "2号TMS压缩机1电压(15kw)";
CM_ SG_ 2337533593 M2P_TMS_R_15_CP1_I_09 "2号TMS压缩机1电流(15kw)";
CM_ SG_ 2337533593 M2P_TMS_R_15_CP1_r_09 "2号TMS压缩机1转速(15kw)";
CM_ SG_ 2337533593 M2P_TMS_R_TEM_09 "2号TMSPTC温度开关状态";
CM_ SG_ 2337533593 M2P_TMS_R_WPS_09 "2号TMS水泵开关";
CM_ SG_ 2337533593 Reserved_3 "预留";
CM_ SG_ 2337533593 M2P_TMS_R_15_fan_fault_09 "2号TMS风机故障(15kw)";
CM_ SG_ 2337533593 M2P_TMS_R_15_fre_fault_09 "2号TMS AC1故障(15kw变频器)";
CM_ SG_ 2337533593 M2P_TMS_R_15_D_fault_09 "2号TMSAC1故障(15kwDC/DC)";
CM_ SG_ 2337533593 M2P_TMS_R_FAN_PWM_09 "2号TMS冷却风机PWM占空比";
CM_ SG_ 2337533593 M2P_TMS_R_25_FAN_PWM_09 "2号TMS25kw风机PWM";
CM_ SG_ 2337533594 M2P_TMS_R_15_CP1_vol_10 "2号TMS压缩机1电压(15kw)";
CM_ SG_ 2337533594 M2P_TMS_R_15_CP1_I_10 "2号TMS压缩机1电流(15kw)";
CM_ SG_ 2337533594 M2P_TMS_R_15_CP1_r_10 "2号TMS压缩机1转速(15kw)";
CM_ SG_ 2337533594 M2P_TMS_R_TEM_10 "2号TMSPTC温度开关状态";
CM_ SG_ 2337533594 M2P_TMS_R_WPS_10 "2号TMS水泵开关";
CM_ SG_ 2337533594 Reserved_3 "预留";
CM_ SG_ 2337533594 M2P_TMS_R_15_fan_fault_10 "2号TMS风机故障(15kw)";
CM_ SG_ 2337533594 M2P_TMS_R_15_fre_fault_10 "2号TMS AC1故障(15kw变频器)";
CM_ SG_ 2337533594 M2P_TMS_R_15_D_fault_10 "2号TMSAC1故障(15kwDC/DC)";
CM_ SG_ 2337533594 M2P_TMS_R_FAN_PWM_10 "2号TMS冷却风机PWM占空比";
CM_ SG_ 2337533594 M2P_TMS_R_25_FAN_PWM_10 "2号TMS25kw风机PWM";
CM_ SG_ 2337533595 M2P_TMS_R_15_CP1_vol_11 "2号TMS压缩机1电压(15kw)";
CM_ SG_ 2337533595 M2P_TMS_R_15_CP1_I_11 "2号TMS压缩机1电流(15kw)";
CM_ SG_ 2337533595 M2P_TMS_R_15_CP1_r_11 "2号TMS压缩机1转速(15kw)";
CM_ SG_ 2337533595 M2P_TMS_R_TEM_11 "2号TMSPTC温度开关状态";
CM_ SG_ 2337533595 M2P_TMS_R_WPS_11 "2号TMS水泵开关";
CM_ SG_ 2337533595 Reserved_3 "预留";
CM_ SG_ 2337533595 M2P_TMS_R_15_fan_fault_11 "2号TMS风机故障(15kw)";
CM_ SG_ 2337533595 M2P_TMS_R_15_fre_fault_11 "2号TMS AC1故障(15kw变频器)";
CM_ SG_ 2337533595 M2P_TMS_R_15_D_fault_11 "2号TMSAC1故障(15kwDC/DC)";
CM_ SG_ 2337533595 M2P_TMS_R_FAN_PWM_11 "2号TMS冷却风机PWM占空比";
CM_ SG_ 2337533595 M2P_TMS_R_25_FAN_PWM_11 "2号TMS25kw风机PWM";
CM_ SG_ 2337533596 M2P_TMS_R_15_CP1_vol_12 "2号TMS压缩机1电压(15kw)";
CM_ SG_ 2337533596 M2P_TMS_R_15_CP1_I_12 "2号TMS压缩机1电流(15kw)";
CM_ SG_ 2337533596 M2P_TMS_R_15_CP1_r_12 "2号TMS压缩机1转速(15kw)";
CM_ SG_ 2337533596 M2P_TMS_R_TEM_12 "2号TMSPTC温度开关状态";
CM_ SG_ 2337533596 M2P_TMS_R_WPS_12 "2号TMS水泵开关";
CM_ SG_ 2337533596 Reserved_3 "预留";
CM_ SG_ 2337533596 M2P_TMS_R_15_fan_fault_12 "2号TMS风机故障(15kw)";
CM_ SG_ 2337533596 M2P_TMS_R_15_fre_fault_12 "2号TMS AC1故障(15kw变频器)";
CM_ SG_ 2337533596 M2P_TMS_R_15_D_fault_12 "2号TMSAC1故障(15kwDC/DC)";
CM_ SG_ 2337533596 M2P_TMS_R_FAN_PWM_12 "2号TMS冷却风机PWM占空比";
CM_ SG_ 2337533596 M2P_TMS_R_25_FAN_PWM_12 "2号TMS25kw风机PWM";
CM_ SG_ 2337533597 M2P_TMS_R_15_CP1_vol_13 "2号TMS压缩机1电压(15kw)";
CM_ SG_ 2337533597 M2P_TMS_R_15_CP1_I_13 "2号TMS压缩机1电流(15kw)";
CM_ SG_ 2337533597 M2P_TMS_R_15_CP1_r_13 "2号TMS压缩机1转速(15kw)";
CM_ SG_ 2337533597 M2P_TMS_R_TEM_13 "2号TMSPTC温度开关状态";
CM_ SG_ 2337533597 M2P_TMS_R_WPS_13 "2号TMS水泵开关";
CM_ SG_ 2337533597 Reserved_3 "预留";
CM_ SG_ 2337533597 M2P_TMS_R_15_fan_fault_13 "2号TMS风机故障(15kw)";
CM_ SG_ 2337533597 M2P_TMS_R_15_fre_fault_13 "2号TMS AC1故障(15kw变频器)";
CM_ SG_ 2337533597 M2P_TMS_R_15_D_fault_13 "2号TMSAC1故障(15kwDC/DC)";
CM_ SG_ 2337533597 M2P_TMS_R_FAN_PWM_13 "2号TMS冷却风机PWM占空比";
CM_ SG_ 2337533597 M2P_TMS_R_25_FAN_PWM_13 "2号TMS25kw风机PWM";
CM_ SG_ 2337533598 M2P_TMS_R_15_CP1_vol_14 "2号TMS压缩机1电压(15kw)";
CM_ SG_ 2337533598 M2P_TMS_R_15_CP1_I_14 "2号TMS压缩机1电流(15kw)";
CM_ SG_ 2337533598 M2P_TMS_R_15_CP1_r_14 "2号TMS压缩机1转速(15kw)";
CM_ SG_ 2337533598 M2P_TMS_R_TEM_14 "2号TMSPTC温度开关状态";
CM_ SG_ 2337533598 M2P_TMS_R_WPS_14 "2号TMS水泵开关";
CM_ SG_ 2337533598 Reserved_3 "预留";
CM_ SG_ 2337533598 M2P_TMS_R_15_fan_fault_14 "2号TMS风机故障(15kw)";
CM_ SG_ 2337533598 M2P_TMS_R_15_fre_fault_14 "2号TMS AC1故障(15kw变频器)";
CM_ SG_ 2337533598 M2P_TMS_R_15_D_fault_14 "2号TMSAC1故障(15kwDC/DC)";
CM_ SG_ 2337533598 M2P_TMS_R_FAN_PWM_14 "2号TMS冷却风机PWM占空比";
CM_ SG_ 2337533598 M2P_TMS_R_25_FAN_PWM_14 "2号TMS25kw风机PWM";
CM_ SG_ 2337533599 M2P_TMS_R_15_CP1_vol_15 "2号TMS压缩机1电压(15kw)";
CM_ SG_ 2337533599 M2P_TMS_R_15_CP1_I_15 "2号TMS压缩机1电流(15kw)";
CM_ SG_ 2337533599 M2P_TMS_R_15_CP1_r_15 "2号TMS压缩机1转速(15kw)";
CM_ SG_ 2337533599 M2P_TMS_R_TEM_15 "2号TMSPTC温度开关状态";
CM_ SG_ 2337533599 M2P_TMS_R_WPS_15 "2号TMS水泵开关";
CM_ SG_ 2337533599 Reserved_3 "预留";
CM_ SG_ 2337533599 M2P_TMS_R_15_fan_fault_15 "2号TMS风机故障(15kw)";
CM_ SG_ 2337533599 M2P_TMS_R_15_fre_fault_15 "2号TMS AC1故障(15kw变频器)";
CM_ SG_ 2337533599 M2P_TMS_R_15_D_fault_15 "2号TMSAC1故障(15kwDC/DC)";
CM_ SG_ 2337533599 M2P_TMS_R_FAN_PWM_15 "2号TMS冷却风机PWM占空比";
CM_ SG_ 2337533599 M2P_TMS_R_25_FAN_PWM_15 "2号TMS25kw风机PWM";
CM_ SG_ 2337533600 M2P_TMS_R_15_CP1_vol_16 "2号TMS压缩机1电压(15kw)";
CM_ SG_ 2337533600 M2P_TMS_R_15_CP1_I_16 "2号TMS压缩机1电流(15kw)";
CM_ SG_ 2337533600 M2P_TMS_R_15_CP1_r_16 "2号TMS压缩机1转速(15kw)";
CM_ SG_ 2337533600 M2P_TMS_R_TEM_16 "2号TMSPTC温度开关状态";
CM_ SG_ 2337533600 M2P_TMS_R_WPS_16 "2号TMS水泵开关";
CM_ SG_ 2337533600 Reserved_3 "预留";
CM_ SG_ 2337533600 M2P_TMS_R_15_fan_fault_16 "2号TMS风机故障(15kw)";
CM_ SG_ 2337533600 M2P_TMS_R_15_fre_fault_16 "2号TMS AC1故障(15kw变频器)";
CM_ SG_ 2337533600 M2P_TMS_R_15_D_fault_16 "2号TMSAC1故障(15kwDC/DC)";
CM_ SG_ 2337533600 M2P_TMS_R_FAN_PWM_16 "2号TMS冷却风机PWM占空比";
CM_ SG_ 2337533600 M2P_TMS_R_25_FAN_PWM_16 "2号TMS25kw风机PWM";
CM_ SG_ 2337533601 M2P_TMS_R_15_CP1_vol_17 "2号TMS压缩机1电压(15kw)";
CM_ SG_ 2337533601 M2P_TMS_R_15_CP1_I_17 "2号TMS压缩机1电流(15kw)";
CM_ SG_ 2337533601 M2P_TMS_R_15_CP1_r_17 "2号TMS压缩机1转速(15kw)";
CM_ SG_ 2337533601 M2P_TMS_R_TEM_17 "2号TMSPTC温度开关状态";
CM_ SG_ 2337533601 M2P_TMS_R_WPS_17 "2号TMS水泵开关";
CM_ SG_ 2337533601 Reserved_3 "预留";
CM_ SG_ 2337533601 M2P_TMS_R_15_fan_fault_17 "2号TMS风机故障(15kw)";
CM_ SG_ 2337533601 M2P_TMS_R_15_fre_fault_17 "2号TMS AC1故障(15kw变频器)";
CM_ SG_ 2337533601 M2P_TMS_R_15_D_fault_17 "2号TMSAC1故障(15kwDC/DC)";
CM_ SG_ 2337533601 M2P_TMS_R_FAN_PWM_17 "2号TMS冷却风机PWM占空比";
CM_ SG_ 2337533601 M2P_TMS_R_25_FAN_PWM_17 "2号TMS25kw风机PWM";
CM_ SG_ 2337533602 M2P_TMS_R_15_CP1_vol_18 "2号TMS压缩机1电压(15kw)";
CM_ SG_ 2337533602 M2P_TMS_R_15_CP1_I_18 "2号TMS压缩机1电流(15kw)";
CM_ SG_ 2337533602 M2P_TMS_R_15_CP1_r_18 "2号TMS压缩机1转速(15kw)";
CM_ SG_ 2337533602 M2P_TMS_R_TEM_18 "2号TMSPTC温度开关状态";
CM_ SG_ 2337533602 M2P_TMS_R_WPS_18 "2号TMS水泵开关";
CM_ SG_ 2337533602 Reserved_3 "预留";
CM_ SG_ 2337533602 M2P_TMS_R_15_fan_fault_18 "2号TMS风机故障(15kw)";
CM_ SG_ 2337533602 M2P_TMS_R_15_fre_fault_18 "2号TMS AC1故障(15kw变频器)";
CM_ SG_ 2337533602 M2P_TMS_R_15_D_fault_18 "2号TMSAC1故障(15kwDC/DC)";
CM_ SG_ 2337533602 M2P_TMS_R_FAN_PWM_18 "2号TMS冷却风机PWM占空比";
CM_ SG_ 2337533602 M2P_TMS_R_25_FAN_PWM_18 "2号TMS25kw风机PWM";
CM_ SG_ 2337533603 M2P_TMS_R_15_CP1_vol_19 "2号TMS压缩机1电压(15kw)";
CM_ SG_ 2337533603 M2P_TMS_R_15_CP1_I_19 "2号TMS压缩机1电流(15kw)";
CM_ SG_ 2337533603 M2P_TMS_R_15_CP1_r_19 "2号TMS压缩机1转速(15kw)";
CM_ SG_ 2337533603 M2P_TMS_R_TEM_19 "2号TMSPTC温度开关状态";
CM_ SG_ 2337533603 M2P_TMS_R_WPS_19 "2号TMS水泵开关";
CM_ SG_ 2337533603 Reserved_3 "预留";
CM_ SG_ 2337533603 M2P_TMS_R_15_fan_fault_19 "2号TMS风机故障(15kw)";
CM_ SG_ 2337533603 M2P_TMS_R_15_fre_fault_19 "2号TMS AC1故障(15kw变频器)";
CM_ SG_ 2337533603 M2P_TMS_R_15_D_fault_19 "2号TMSAC1故障(15kwDC/DC)";
CM_ SG_ 2337533603 M2P_TMS_R_FAN_PWM_19 "2号TMS冷却风机PWM占空比";
CM_ SG_ 2337533603 M2P_TMS_R_25_FAN_PWM_19 "2号TMS25kw风机PWM";
CM_ SG_ 2337533604 M2P_TMS_R_15_CP1_vol_20 "2号TMS压缩机1电压(15kw)";
CM_ SG_ 2337533604 M2P_TMS_R_15_CP1_I_20 "2号TMS压缩机1电流(15kw)";
CM_ SG_ 2337533604 M2P_TMS_R_15_CP1_r_20 "2号TMS压缩机1转速(15kw)";
CM_ SG_ 2337533604 M2P_TMS_R_TEM_20 "2号TMSPTC温度开关状态";
CM_ SG_ 2337533604 M2P_TMS_R_WPS_20 "2号TMS水泵开关";
CM_ SG_ 2337533604 Reserved_3 "预留";
CM_ SG_ 2337533604 M2P_TMS_R_15_fan_fault_20 "2号TMS风机故障(15kw)";
CM_ SG_ 2337533604 M2P_TMS_R_15_fre_fault_20 "2号TMS AC1故障(15kw变频器)";
CM_ SG_ 2337533604 M2P_TMS_R_15_D_fault_20 "2号TMSAC1故障(15kwDC/DC)";
CM_ SG_ 2337533604 M2P_TMS_R_FAN_PWM_20 "2号TMS冷却风机PWM占空比";
CM_ SG_ 2337533604 M2P_TMS_R_25_FAN_PWM_20 "2号TMS25kw风机PWM";
CM_ SG_ 2337533605 M2P_TMS_R_15_CP1_vol_21 "2号TMS压缩机1电压(15kw)";
CM_ SG_ 2337533605 M2P_TMS_R_15_CP1_I_21 "2号TMS压缩机1电流(15kw)";
CM_ SG_ 2337533605 M2P_TMS_R_15_CP1_r_21 "2号TMS压缩机1转速(15kw)";
CM_ SG_ 2337533605 M2P_TMS_R_TEM_21 "2号TMSPTC温度开关状态";
CM_ SG_ 2337533605 M2P_TMS_R_WPS_21 "2号TMS水泵开关";
CM_ SG_ 2337533605 Reserved_3 "预留";
CM_ SG_ 2337533605 M2P_TMS_R_15_fan_fault_21 "2号TMS风机故障(15kw)";
CM_ SG_ 2337533605 M2P_TMS_R_15_fre_fault_21 "2号TMS AC1故障(15kw变频器)";
CM_ SG_ 2337533605 M2P_TMS_R_15_D_fault_21 "2号TMSAC1故障(15kwDC/DC)";
CM_ SG_ 2337533605 M2P_TMS_R_FAN_PWM_21 "2号TMS冷却风机PWM占空比";
CM_ SG_ 2337533605 M2P_TMS_R_25_FAN_PWM_21 "2号TMS25kw风机PWM";
CM_ SG_ 2337533606 M2P_TMS_R_15_CP1_vol_22 "2号TMS压缩机1电压(15kw)";
CM_ SG_ 2337533606 M2P_TMS_R_15_CP1_I_22 "2号TMS压缩机1电流(15kw)";
CM_ SG_ 2337533606 M2P_TMS_R_15_CP1_r_22 "2号TMS压缩机1转速(15kw)";
CM_ SG_ 2337533606 M2P_TMS_R_TEM_22 "2号TMSPTC温度开关状态";
CM_ SG_ 2337533606 M2P_TMS_R_WPS_22 "2号TMS水泵开关";
CM_ SG_ 2337533606 Reserved_3 "预留";
CM_ SG_ 2337533606 M2P_TMS_R_15_fan_fault_22 "2号TMS风机故障(15kw)";
CM_ SG_ 2337533606 M2P_TMS_R_15_fre_fault_22 "2号TMS AC1故障(15kw变频器)";
CM_ SG_ 2337533606 M2P_TMS_R_15_D_fault_22 "2号TMSAC1故障(15kwDC/DC)";
CM_ SG_ 2337533606 M2P_TMS_R_FAN_PWM_22 "2号TMS冷却风机PWM占空比";
CM_ SG_ 2337533606 M2P_TMS_R_25_FAN_PWM_22 "2号TMS25kw风机PWM";
CM_ SG_ 2337533607 M2P_TMS_R_15_CP1_vol_23 "2号TMS压缩机1电压(15kw)";
CM_ SG_ 2337533607 M2P_TMS_R_15_CP1_I_23 "2号TMS压缩机1电流(15kw)";
CM_ SG_ 2337533607 M2P_TMS_R_15_CP1_r_23 "2号TMS压缩机1转速(15kw)";
CM_ SG_ 2337533607 M2P_TMS_R_TEM_23 "2号TMSPTC温度开关状态";
CM_ SG_ 2337533607 M2P_TMS_R_WPS_23 "2号TMS水泵开关";
CM_ SG_ 2337533607 Reserved_3 "预留";
CM_ SG_ 2337533607 M2P_TMS_R_15_fan_fault_23 "2号TMS风机故障(15kw)";
CM_ SG_ 2337533607 M2P_TMS_R_15_fre_fault_23 "2号TMS AC1故障(15kw变频器)";
CM_ SG_ 2337533607 M2P_TMS_R_15_D_fault_23 "2号TMSAC1故障(15kwDC/DC)";
CM_ SG_ 2337533607 M2P_TMS_R_FAN_PWM_23 "2号TMS冷却风机PWM占空比";
CM_ SG_ 2337533607 M2P_TMS_R_25_FAN_PWM_23 "2号TMS25kw风机PWM";
CM_ SG_ 2337533608 M2P_TMS_R_15_CP1_vol_24 "2号TMS压缩机1电压(15kw)";
CM_ SG_ 2337533608 M2P_TMS_R_15_CP1_I_24 "2号TMS压缩机1电流(15kw)";
CM_ SG_ 2337533608 M2P_TMS_R_15_CP1_r_24 "2号TMS压缩机1转速(15kw)";
CM_ SG_ 2337533608 M2P_TMS_R_TEM_24 "2号TMSPTC温度开关状态";
CM_ SG_ 2337533608 M2P_TMS_R_WPS_24 "2号TMS水泵开关";
CM_ SG_ 2337533608 Reserved_3 "预留";
CM_ SG_ 2337533608 M2P_TMS_R_15_fan_fault_24 "2号TMS风机故障(15kw)";
CM_ SG_ 2337533608 M2P_TMS_R_15_fre_fault_24 "2号TMS AC1故障(15kw变频器)";
CM_ SG_ 2337533608 M2P_TMS_R_15_D_fault_24 "2号TMSAC1故障(15kwDC/DC)";
CM_ SG_ 2337533608 M2P_TMS_R_FAN_PWM_24 "2号TMS冷却风机PWM占空比";
CM_ SG_ 2337533608 M2P_TMS_R_25_FAN_PWM_24 "2号TMS25kw风机PWM";
CM_ SG_ 2337533609 M2P_TMS_R_15_CP1_vol_25 "2号TMS压缩机1电压(15kw)";
CM_ SG_ 2337533609 M2P_TMS_R_15_CP1_I_25 "2号TMS压缩机1电流(15kw)";
CM_ SG_ 2337533609 M2P_TMS_R_15_CP1_r_25 "2号TMS压缩机1转速(15kw)";
CM_ SG_ 2337533609 M2P_TMS_R_TEM_25 "2号TMSPTC温度开关状态";
CM_ SG_ 2337533609 M2P_TMS_R_WPS_25 "2号TMS水泵开关";
CM_ SG_ 2337533609 Reserved_3 "预留";
CM_ SG_ 2337533609 M2P_TMS_R_15_fan_fault_25 "2号TMS风机故障(15kw)";
CM_ SG_ 2337533609 M2P_TMS_R_15_fre_fault_25 "2号TMS AC1故障(15kw变频器)";
CM_ SG_ 2337533609 M2P_TMS_R_15_D_fault_25 "2号TMSAC1故障(15kwDC/DC)";
CM_ SG_ 2337533609 M2P_TMS_R_FAN_PWM_25 "2号TMS冷却风机PWM占空比";
CM_ SG_ 2337533609 M2P_TMS_R_25_FAN_PWM_25 "2号TMS25kw风机PWM";
CM_ SG_ 2337533610 M2P_TMS_R_15_CP1_vol_26 "2号TMS压缩机1电压(15kw)";
CM_ SG_ 2337533610 M2P_TMS_R_15_CP1_I_26 "2号TMS压缩机1电流(15kw)";
CM_ SG_ 2337533610 M2P_TMS_R_15_CP1_r_26 "2号TMS压缩机1转速(15kw)";
CM_ SG_ 2337533610 M2P_TMS_R_TEM_26 "2号TMSPTC温度开关状态";
CM_ SG_ 2337533610 M2P_TMS_R_WPS_26 "2号TMS水泵开关";
CM_ SG_ 2337533610 Reserved_3 "预留";
CM_ SG_ 2337533610 M2P_TMS_R_15_fan_fault_26 "2号TMS风机故障(15kw)";
CM_ SG_ 2337533610 M2P_TMS_R_15_fre_fault_26 "2号TMS AC1故障(15kw变频器)";
CM_ SG_ 2337533610 M2P_TMS_R_15_D_fault_26 "2号TMSAC1故障(15kwDC/DC)";
CM_ SG_ 2337533610 M2P_TMS_R_FAN_PWM_26 "2号TMS冷却风机PWM占空比";
CM_ SG_ 2337533610 M2P_TMS_R_25_FAN_PWM_26 "2号TMS25kw风机PWM";
CM_ SG_ 2337533611 M2P_TMS_R_15_CP1_vol_27 "2号TMS压缩机1电压(15kw)";
CM_ SG_ 2337533611 M2P_TMS_R_15_CP1_I_27 "2号TMS压缩机1电流(15kw)";
CM_ SG_ 2337533611 M2P_TMS_R_15_CP1_r_27 "2号TMS压缩机1转速(15kw)";
CM_ SG_ 2337533611 M2P_TMS_R_TEM_27 "2号TMSPTC温度开关状态";
CM_ SG_ 2337533611 M2P_TMS_R_WPS_27 "2号TMS水泵开关";
CM_ SG_ 2337533611 Reserved_3 "预留";
CM_ SG_ 2337533611 M2P_TMS_R_15_fan_fault_27 "2号TMS风机故障(15kw)";
CM_ SG_ 2337533611 M2P_TMS_R_15_fre_fault_27 "2号TMS AC1故障(15kw变频器)";
CM_ SG_ 2337533611 M2P_TMS_R_15_D_fault_27 "2号TMSAC1故障(15kwDC/DC)";
CM_ SG_ 2337533611 M2P_TMS_R_FAN_PWM_27 "2号TMS冷却风机PWM占空比";
CM_ SG_ 2337533611 M2P_TMS_R_25_FAN_PWM_27 "2号TMS25kw风机PWM";
CM_ SG_ 2337533612 M2P_TMS_R_15_CP1_vol_28 "2号TMS压缩机1电压(15kw)";
CM_ SG_ 2337533612 M2P_TMS_R_15_CP1_I_28 "2号TMS压缩机1电流(15kw)";
CM_ SG_ 2337533612 M2P_TMS_R_15_CP1_r_28 "2号TMS压缩机1转速(15kw)";
CM_ SG_ 2337533612 M2P_TMS_R_TEM_28 "2号TMSPTC温度开关状态";
CM_ SG_ 2337533612 M2P_TMS_R_WPS_28 "2号TMS水泵开关";
CM_ SG_ 2337533612 Reserved_3 "预留";
CM_ SG_ 2337533612 M2P_TMS_R_15_fan_fault_28 "2号TMS风机故障(15kw)";
CM_ SG_ 2337533612 M2P_TMS_R_15_fre_fault_28 "2号TMS AC1故障(15kw变频器)";
CM_ SG_ 2337533612 M2P_TMS_R_15_D_fault_28 "2号TMSAC1故障(15kwDC/DC)";
CM_ SG_ 2337533612 M2P_TMS_R_FAN_PWM_28 "2号TMS冷却风机PWM占空比";
CM_ SG_ 2337533612 M2P_TMS_R_25_FAN_PWM_28 "2号TMS25kw风机PWM";
CM_ SG_ 2337533613 M2P_TMS_R_15_CP1_vol_29 "2号TMS压缩机1电压(15kw)";
CM_ SG_ 2337533613 M2P_TMS_R_15_CP1_I_29 "2号TMS压缩机1电流(15kw)";
CM_ SG_ 2337533613 M2P_TMS_R_15_CP1_r_29 "2号TMS压缩机1转速(15kw)";
CM_ SG_ 2337533613 M2P_TMS_R_TEM_29 "2号TMSPTC温度开关状态";
CM_ SG_ 2337533613 M2P_TMS_R_WPS_29 "2号TMS水泵开关";
CM_ SG_ 2337533613 Reserved_3 "预留";
CM_ SG_ 2337533613 M2P_TMS_R_15_fan_fault_29 "2号TMS风机故障(15kw)";
CM_ SG_ 2337533613 M2P_TMS_R_15_fre_fault_29 "2号TMS AC1故障(15kw变频器)";
CM_ SG_ 2337533613 M2P_TMS_R_15_D_fault_29 "2号TMSAC1故障(15kwDC/DC)";
CM_ SG_ 2337533613 M2P_TMS_R_FAN_PWM_29 "2号TMS冷却风机PWM占空比";
CM_ SG_ 2337533613 M2P_TMS_R_25_FAN_PWM_29 "2号TMS25kw风机PWM";
CM_ SG_ 2337533614 M2P_TMS_R_15_CP1_vol_30 "2号TMS压缩机1电压(15kw)";
CM_ SG_ 2337533614 M2P_TMS_R_15_CP1_I_30 "2号TMS压缩机1电流(15kw)";
CM_ SG_ 2337533614 M2P_TMS_R_15_CP1_r_30 "2号TMS压缩机1转速(15kw)";
CM_ SG_ 2337533614 M2P_TMS_R_TEM_30 "2号TMSPTC温度开关状态";
CM_ SG_ 2337533614 M2P_TMS_R_WPS_30 "2号TMS水泵开关";
CM_ SG_ 2337533614 Reserved_3 "预留";
CM_ SG_ 2337533614 M2P_TMS_R_15_fan_fault_30 "2号TMS风机故障(15kw)";
CM_ SG_ 2337533614 M2P_TMS_R_15_fre_fault_30 "2号TMS AC1故障(15kw变频器)";
CM_ SG_ 2337533614 M2P_TMS_R_15_D_fault_30 "2号TMSAC1故障(15kwDC/DC)";
CM_ SG_ 2337533614 M2P_TMS_R_FAN_PWM_30 "2号TMS冷却风机PWM占空比";
CM_ SG_ 2337533614 M2P_TMS_R_25_FAN_PWM_30 "2号TMS25kw风机PWM";
CM_ SG_ 2337533615 M2P_TMS_R_15_CP1_vol_31 "2号TMS压缩机1电压(15kw)";
CM_ SG_ 2337533615 M2P_TMS_R_15_CP1_I_31 "2号TMS压缩机1电流(15kw)";
CM_ SG_ 2337533615 M2P_TMS_R_15_CP1_r_31 "2号TMS压缩机1转速(15kw)";
CM_ SG_ 2337533615 M2P_TMS_R_TEM_31 "2号TMSPTC温度开关状态";
CM_ SG_ 2337533615 M2P_TMS_R_WPS_31 "2号TMS水泵开关";
CM_ SG_ 2337533615 Reserved_3 "预留";
CM_ SG_ 2337533615 M2P_TMS_R_15_fan_fault_31 "2号TMS风机故障(15kw)";
CM_ SG_ 2337533615 M2P_TMS_R_15_fre_fault_31 "2号TMS AC1故障(15kw变频器)";
CM_ SG_ 2337533615 M2P_TMS_R_15_D_fault_31 "2号TMSAC1故障(15kwDC/DC)";
CM_ SG_ 2337533615 M2P_TMS_R_FAN_PWM_31 "2号TMS冷却风机PWM占空比";
CM_ SG_ 2337533615 M2P_TMS_R_25_FAN_PWM_31 "2号TMS25kw风机PWM";
CM_ SG_ 2337599121 M2P_TMS_R_25_CP1_vol_01 "2号TMS压缩机2电压(25kw)";
CM_ SG_ 2337599121 M2P_TMS_R_25_CP1_I_01 "2号TMS压缩机2电流(25kw)";
CM_ SG_ 2337599121 M2P_TMS_R_25_CP1_r_01 "2号TMS压缩机2转速(25kw)";
CM_ SG_ 2337599121 Reserved_4 "保留";
CM_ SG_ 2337599121 M2P_TMS_R_25_fan_fault_01 "2号TMS风机故障(25kw)";
CM_ SG_ 2337599121 M2P_TMS_R_25_fre_fault_01 "2号TMSAC2故障(25kw变频器)";
CM_ SG_ 2337599121 M2P_TMS_R_25_D_fault_01 "2号TMS AC2故障(25kwDC/DC)";
CM_ SG_ 2337599121 M2P_TMS_R_AC2_25_P_01 "2号TMS AC2低压压力值(25kw)";
CM_ SG_ 2337599122 M2P_TMS_R_25_CP1_vol_02 "2号TMS压缩机2电压(25kw)";
CM_ SG_ 2337599122 M2P_TMS_R_25_CP1_I_02 "2号TMS压缩机2电流(25kw)";
CM_ SG_ 2337599122 M2P_TMS_R_25_CP1_r_02 "2号TMS压缩机2转速(25kw)";
CM_ SG_ 2337599122 Reserved_4 "保留";
CM_ SG_ 2337599122 M2P_TMS_R_25_fan_fault_02 "2号TMS风机故障(25kw)";
CM_ SG_ 2337599122 M2P_TMS_R_25_fre_fault_02 "2号TMSAC2故障(25kw变频器)";
CM_ SG_ 2337599122 M2P_TMS_R_25_D_fault_02 "2号TMS AC2故障(25kwDC/DC)";
CM_ SG_ 2337599122 M2P_TMS_R_AC2_25_P_02 "2号TMS AC2低压压力值(25kw)";
CM_ SG_ 2337599123 M2P_TMS_R_25_CP1_vol_03 "2号TMS压缩机2电压(25kw)";
CM_ SG_ 2337599123 M2P_TMS_R_25_CP1_I_03 "2号TMS压缩机2电流(25kw)";
CM_ SG_ 2337599123 M2P_TMS_R_25_CP1_r_03 "2号TMS压缩机2转速(25kw)";
CM_ SG_ 2337599123 Reserved_4 "保留";
CM_ SG_ 2337599123 M2P_TMS_R_25_fan_fault_03 "2号TMS风机故障(25kw)";
CM_ SG_ 2337599123 M2P_TMS_R_25_fre_fault_03 "2号TMSAC2故障(25kw变频器)";
CM_ SG_ 2337599123 M2P_TMS_R_25_D_fault_03 "2号TMS AC2故障(25kwDC/DC)";
CM_ SG_ 2337599123 M2P_TMS_R_AC2_25_P_03 "2号TMS AC2低压压力值(25kw)";
CM_ SG_ 2337599124 M2P_TMS_R_25_CP1_vol_04 "2号TMS压缩机2电压(25kw)";
CM_ SG_ 2337599124 M2P_TMS_R_25_CP1_I_04 "2号TMS压缩机2电流(25kw)";
CM_ SG_ 2337599124 M2P_TMS_R_25_CP1_r_04 "2号TMS压缩机2转速(25kw)";
CM_ SG_ 2337599124 Reserved_4 "保留";
CM_ SG_ 2337599124 M2P_TMS_R_25_fan_fault_04 "2号TMS风机故障(25kw)";
CM_ SG_ 2337599124 M2P_TMS_R_25_fre_fault_04 "2号TMSAC2故障(25kw变频器)";
CM_ SG_ 2337599124 M2P_TMS_R_25_D_fault_04 "2号TMS AC2故障(25kwDC/DC)";
CM_ SG_ 2337599124 M2P_TMS_R_AC2_25_P_04 "2号TMS AC2低压压力值(25kw)";
CM_ SG_ 2337599125 M2P_TMS_R_25_CP1_vol_05 "2号TMS压缩机2电压(25kw)";
CM_ SG_ 2337599125 M2P_TMS_R_25_CP1_I_05 "2号TMS压缩机2电流(25kw)";
CM_ SG_ 2337599125 M2P_TMS_R_25_CP1_r_05 "2号TMS压缩机2转速(25kw)";
CM_ SG_ 2337599125 Reserved_4 "保留";
CM_ SG_ 2337599125 M2P_TMS_R_25_fan_fault_05 "2号TMS风机故障(25kw)";
CM_ SG_ 2337599125 M2P_TMS_R_25_fre_fault_05 "2号TMSAC2故障(25kw变频器)";
CM_ SG_ 2337599125 M2P_TMS_R_25_D_fault_05 "2号TMS AC2故障(25kwDC/DC)";
CM_ SG_ 2337599125 M2P_TMS_R_AC2_25_P_05 "2号TMS AC2低压压力值(25kw)";
CM_ SG_ 2337599126 M2P_TMS_R_25_CP1_vol_06 "2号TMS压缩机2电压(25kw)";
CM_ SG_ 2337599126 M2P_TMS_R_25_CP1_I_06 "2号TMS压缩机2电流(25kw)";
CM_ SG_ 2337599126 M2P_TMS_R_25_CP1_r_06 "2号TMS压缩机2转速(25kw)";
CM_ SG_ 2337599126 Reserved_4 "保留";
CM_ SG_ 2337599126 M2P_TMS_R_25_fan_fault_06 "2号TMS风机故障(25kw)";
CM_ SG_ 2337599126 M2P_TMS_R_25_fre_fault_06 "2号TMSAC2故障(25kw变频器)";
CM_ SG_ 2337599126 M2P_TMS_R_25_D_fault_06 "2号TMS AC2故障(25kwDC/DC)";
CM_ SG_ 2337599126 M2P_TMS_R_AC2_25_P_06 "2号TMS AC2低压压力值(25kw)";
CM_ SG_ 2337599127 M2P_TMS_R_25_CP1_vol_07 "2号TMS压缩机2电压(25kw)";
CM_ SG_ 2337599127 M2P_TMS_R_25_CP1_I_07 "2号TMS压缩机2电流(25kw)";
CM_ SG_ 2337599127 M2P_TMS_R_25_CP1_r_07 "2号TMS压缩机2转速(25kw)";
CM_ SG_ 2337599127 Reserved_4 "保留";
CM_ SG_ 2337599127 M2P_TMS_R_25_fan_fault_07 "2号TMS风机故障(25kw)";
CM_ SG_ 2337599127 M2P_TMS_R_25_fre_fault_07 "2号TMSAC2故障(25kw变频器)";
CM_ SG_ 2337599127 M2P_TMS_R_25_D_fault_07 "2号TMS AC2故障(25kwDC/DC)";
CM_ SG_ 2337599127 M2P_TMS_R_AC2_25_P_07 "2号TMS AC2低压压力值(25kw)";
CM_ SG_ 2337599128 M2P_TMS_R_25_CP1_vol_08 "2号TMS压缩机2电压(25kw)";
CM_ SG_ 2337599128 M2P_TMS_R_25_CP1_I_08 "2号TMS压缩机2电流(25kw)";
CM_ SG_ 2337599128 M2P_TMS_R_25_CP1_r_08 "2号TMS压缩机2转速(25kw)";
CM_ SG_ 2337599128 Reserved_4 "保留";
CM_ SG_ 2337599128 M2P_TMS_R_25_fan_fault_08 "2号TMS风机故障(25kw)";
CM_ SG_ 2337599128 M2P_TMS_R_25_fre_fault_08 "2号TMSAC2故障(25kw变频器)";
CM_ SG_ 2337599128 M2P_TMS_R_25_D_fault_08 "2号TMS AC2故障(25kwDC/DC)";
CM_ SG_ 2337599128 M2P_TMS_R_AC2_25_P_08 "2号TMS AC2低压压力值(25kw)";
CM_ SG_ 2337599129 M2P_TMS_R_25_CP1_vol_09 "2号TMS压缩机2电压(25kw)";
CM_ SG_ 2337599129 M2P_TMS_R_25_CP1_I_09 "2号TMS压缩机2电流(25kw)";
CM_ SG_ 2337599129 M2P_TMS_R_25_CP1_r_09 "2号TMS压缩机2转速(25kw)";
CM_ SG_ 2337599129 Reserved_4 "保留";
CM_ SG_ 2337599129 M2P_TMS_R_25_fan_fault_09 "2号TMS风机故障(25kw)";
CM_ SG_ 2337599129 M2P_TMS_R_25_fre_fault_09 "2号TMSAC2故障(25kw变频器)";
CM_ SG_ 2337599129 M2P_TMS_R_25_D_fault_09 "2号TMS AC2故障(25kwDC/DC)";
CM_ SG_ 2337599129 M2P_TMS_R_AC2_25_P_09 "2号TMS AC2低压压力值(25kw)";
CM_ SG_ 2337599130 M2P_TMS_R_25_CP1_vol_10 "2号TMS压缩机2电压(25kw)";
CM_ SG_ 2337599130 M2P_TMS_R_25_CP1_I_10 "2号TMS压缩机2电流(25kw)";
CM_ SG_ 2337599130 M2P_TMS_R_25_CP1_r_10 "2号TMS压缩机2转速(25kw)";
CM_ SG_ 2337599130 Reserved_4 "保留";
CM_ SG_ 2337599130 M2P_TMS_R_25_fan_fault_10 "2号TMS风机故障(25kw)";
CM_ SG_ 2337599130 M2P_TMS_R_25_fre_fault_10 "2号TMSAC2故障(25kw变频器)";
CM_ SG_ 2337599130 M2P_TMS_R_25_D_fault_10 "2号TMS AC2故障(25kwDC/DC)";
CM_ SG_ 2337599130 M2P_TMS_R_AC2_25_P_10 "2号TMS AC2低压压力值(25kw)";
CM_ SG_ 2337599131 M2P_TMS_R_25_CP1_vol_11 "2号TMS压缩机2电压(25kw)";
CM_ SG_ 2337599131 M2P_TMS_R_25_CP1_I_11 "2号TMS压缩机2电流(25kw)";
CM_ SG_ 2337599131 M2P_TMS_R_25_CP1_r_11 "2号TMS压缩机2转速(25kw)";
CM_ SG_ 2337599131 Reserved_4 "保留";
CM_ SG_ 2337599131 M2P_TMS_R_25_fan_fault_11 "2号TMS风机故障(25kw)";
CM_ SG_ 2337599131 M2P_TMS_R_25_fre_fault_11 "2号TMSAC2故障(25kw变频器)";
CM_ SG_ 2337599131 M2P_TMS_R_25_D_fault_11 "2号TMS AC2故障(25kwDC/DC)";
CM_ SG_ 2337599131 M2P_TMS_R_AC2_25_P_11 "2号TMS AC2低压压力值(25kw)";
CM_ SG_ 2337599132 M2P_TMS_R_25_CP1_vol_12 "2号TMS压缩机2电压(25kw)";
CM_ SG_ 2337599132 M2P_TMS_R_25_CP1_I_12 "2号TMS压缩机2电流(25kw)";
CM_ SG_ 2337599132 M2P_TMS_R_25_CP1_r_12 "2号TMS压缩机2转速(25kw)";
CM_ SG_ 2337599132 Reserved_4 "保留";
CM_ SG_ 2337599132 M2P_TMS_R_25_fan_fault_12 "2号TMS风机故障(25kw)";
CM_ SG_ 2337599132 M2P_TMS_R_25_fre_fault_12 "2号TMSAC2故障(25kw变频器)";
CM_ SG_ 2337599132 M2P_TMS_R_25_D_fault_12 "2号TMS AC2故障(25kwDC/DC)";
CM_ SG_ 2337599132 M2P_TMS_R_AC2_25_P_12 "2号TMS AC2低压压力值(25kw)";
CM_ SG_ 2337599133 M2P_TMS_R_25_CP1_vol_13 "2号TMS压缩机2电压(25kw)";
CM_ SG_ 2337599133 M2P_TMS_R_25_CP1_I_13 "2号TMS压缩机2电流(25kw)";
CM_ SG_ 2337599133 M2P_TMS_R_25_CP1_r_13 "2号TMS压缩机2转速(25kw)";
CM_ SG_ 2337599133 Reserved_4 "保留";
CM_ SG_ 2337599133 M2P_TMS_R_25_fan_fault_13 "2号TMS风机故障(25kw)";
CM_ SG_ 2337599133 M2P_TMS_R_25_fre_fault_13 "2号TMSAC2故障(25kw变频器)";
CM_ SG_ 2337599133 M2P_TMS_R_25_D_fault_13 "2号TMS AC2故障(25kwDC/DC)";
CM_ SG_ 2337599133 M2P_TMS_R_AC2_25_P_13 "2号TMS AC2低压压力值(25kw)";
CM_ SG_ 2337599134 M2P_TMS_R_25_CP1_vol_14 "2号TMS压缩机2电压(25kw)";
CM_ SG_ 2337599134 M2P_TMS_R_25_CP1_I_14 "2号TMS压缩机2电流(25kw)";
CM_ SG_ 2337599134 M2P_TMS_R_25_CP1_r_14 "2号TMS压缩机2转速(25kw)";
CM_ SG_ 2337599134 Reserved_4 "保留";
CM_ SG_ 2337599134 M2P_TMS_R_25_fan_fault_14 "2号TMS风机故障(25kw)";
CM_ SG_ 2337599134 M2P_TMS_R_25_fre_fault_14 "2号TMSAC2故障(25kw变频器)";
CM_ SG_ 2337599134 M2P_TMS_R_25_D_fault_14 "2号TMS AC2故障(25kwDC/DC)";
CM_ SG_ 2337599134 M2P_TMS_R_AC2_25_P_14 "2号TMS AC2低压压力值(25kw)";
CM_ SG_ 2337599135 M2P_TMS_R_25_CP1_vol_15 "2号TMS压缩机2电压(25kw)";
CM_ SG_ 2337599135 M2P_TMS_R_25_CP1_I_15 "2号TMS压缩机2电流(25kw)";
CM_ SG_ 2337599135 M2P_TMS_R_25_CP1_r_15 "2号TMS压缩机2转速(25kw)";
CM_ SG_ 2337599135 Reserved_4 "保留";
CM_ SG_ 2337599135 M2P_TMS_R_25_fan_fault_15 "2号TMS风机故障(25kw)";
CM_ SG_ 2337599135 M2P_TMS_R_25_fre_fault_15 "2号TMSAC2故障(25kw变频器)";
CM_ SG_ 2337599135 M2P_TMS_R_25_D_fault_15 "2号TMS AC2故障(25kwDC/DC)";
CM_ SG_ 2337599135 M2P_TMS_R_AC2_25_P_15 "2号TMS AC2低压压力值(25kw)";
CM_ SG_ 2337599136 M2P_TMS_R_25_CP1_vol_16 "2号TMS压缩机2电压(25kw)";
CM_ SG_ 2337599136 M2P_TMS_R_25_CP1_I_16 "2号TMS压缩机2电流(25kw)";
CM_ SG_ 2337599136 M2P_TMS_R_25_CP1_r_16 "2号TMS压缩机2转速(25kw)";
CM_ SG_ 2337599136 Reserved_4 "保留";
CM_ SG_ 2337599136 M2P_TMS_R_25_fan_fault_16 "2号TMS风机故障(25kw)";
CM_ SG_ 2337599136 M2P_TMS_R_25_fre_fault_16 "2号TMSAC2故障(25kw变频器)";
CM_ SG_ 2337599136 M2P_TMS_R_25_D_fault_16 "2号TMS AC2故障(25kwDC/DC)";
CM_ SG_ 2337599136 M2P_TMS_R_AC2_25_P_16 "2号TMS AC2低压压力值(25kw)";
CM_ SG_ 2337599137 M2P_TMS_R_25_CP1_vol_17 "2号TMS压缩机2电压(25kw)";
CM_ SG_ 2337599137 M2P_TMS_R_25_CP1_I_17 "2号TMS压缩机2电流(25kw)";
CM_ SG_ 2337599137 M2P_TMS_R_25_CP1_r_17 "2号TMS压缩机2转速(25kw)";
CM_ SG_ 2337599137 Reserved_4 "保留";
CM_ SG_ 2337599137 M2P_TMS_R_25_fan_fault_17 "2号TMS风机故障(25kw)";
CM_ SG_ 2337599137 M2P_TMS_R_25_fre_fault_17 "2号TMSAC2故障(25kw变频器)";
CM_ SG_ 2337599137 M2P_TMS_R_25_D_fault_17 "2号TMS AC2故障(25kwDC/DC)";
CM_ SG_ 2337599137 M2P_TMS_R_AC2_25_P_17 "2号TMS AC2低压压力值(25kw)";
CM_ SG_ 2337599138 M2P_TMS_R_25_CP1_vol_18 "2号TMS压缩机2电压(25kw)";
CM_ SG_ 2337599138 M2P_TMS_R_25_CP1_I_18 "2号TMS压缩机2电流(25kw)";
CM_ SG_ 2337599138 M2P_TMS_R_25_CP1_r_18 "2号TMS压缩机2转速(25kw)";
CM_ SG_ 2337599138 Reserved_4 "保留";
CM_ SG_ 2337599138 M2P_TMS_R_25_fan_fault_18 "2号TMS风机故障(25kw)";
CM_ SG_ 2337599138 M2P_TMS_R_25_fre_fault_18 "2号TMSAC2故障(25kw变频器)";
CM_ SG_ 2337599138 M2P_TMS_R_25_D_fault_18 "2号TMS AC2故障(25kwDC/DC)";
CM_ SG_ 2337599138 M2P_TMS_R_AC2_25_P_18 "2号TMS AC2低压压力值(25kw)";
CM_ SG_ 2337599139 M2P_TMS_R_25_CP1_vol_19 "2号TMS压缩机2电压(25kw)";
CM_ SG_ 2337599139 M2P_TMS_R_25_CP1_I_19 "2号TMS压缩机2电流(25kw)";
CM_ SG_ 2337599139 M2P_TMS_R_25_CP1_r_19 "2号TMS压缩机2转速(25kw)";
CM_ SG_ 2337599139 Reserved_4 "保留";
CM_ SG_ 2337599139 M2P_TMS_R_25_fan_fault_19 "2号TMS风机故障(25kw)";
CM_ SG_ 2337599139 M2P_TMS_R_25_fre_fault_19 "2号TMSAC2故障(25kw变频器)";
CM_ SG_ 2337599139 M2P_TMS_R_25_D_fault_19 "2号TMS AC2故障(25kwDC/DC)";
CM_ SG_ 2337599139 M2P_TMS_R_AC2_25_P_19 "2号TMS AC2低压压力值(25kw)";
CM_ SG_ 2337599140 M2P_TMS_R_25_CP1_vol_20 "2号TMS压缩机2电压(25kw)";
CM_ SG_ 2337599140 M2P_TMS_R_25_CP1_I_20 "2号TMS压缩机2电流(25kw)";
CM_ SG_ 2337599140 M2P_TMS_R_25_CP1_r_20 "2号TMS压缩机2转速(25kw)";
CM_ SG_ 2337599140 Reserved_4 "保留";
CM_ SG_ 2337599140 M2P_TMS_R_25_fan_fault_20 "2号TMS风机故障(25kw)";
CM_ SG_ 2337599140 M2P_TMS_R_25_fre_fault_20 "2号TMSAC2故障(25kw变频器)";
CM_ SG_ 2337599140 M2P_TMS_R_25_D_fault_20 "2号TMS AC2故障(25kwDC/DC)";
CM_ SG_ 2337599140 M2P_TMS_R_AC2_25_P_20 "2号TMS AC2低压压力值(25kw)";
CM_ SG_ 2337599141 M2P_TMS_R_25_CP1_vol_21 "2号TMS压缩机2电压(25kw)";
CM_ SG_ 2337599141 M2P_TMS_R_25_CP1_I_21 "2号TMS压缩机2电流(25kw)";
CM_ SG_ 2337599141 M2P_TMS_R_25_CP1_r_21 "2号TMS压缩机2转速(25kw)";
CM_ SG_ 2337599141 Reserved_4 "保留";
CM_ SG_ 2337599141 M2P_TMS_R_25_fan_fault_21 "2号TMS风机故障(25kw)";
CM_ SG_ 2337599141 M2P_TMS_R_25_fre_fault_21 "2号TMSAC2故障(25kw变频器)";
CM_ SG_ 2337599141 M2P_TMS_R_25_D_fault_21 "2号TMS AC2故障(25kwDC/DC)";
CM_ SG_ 2337599141 M2P_TMS_R_AC2_25_P_21 "2号TMS AC2低压压力值(25kw)";
CM_ SG_ 2337599142 M2P_TMS_R_25_CP1_vol_22 "2号TMS压缩机2电压(25kw)";
CM_ SG_ 2337599142 M2P_TMS_R_25_CP1_I_22 "2号TMS压缩机2电流(25kw)";
CM_ SG_ 2337599142 M2P_TMS_R_25_CP1_r_22 "2号TMS压缩机2转速(25kw)";
CM_ SG_ 2337599142 Reserved_4 "保留";
CM_ SG_ 2337599142 M2P_TMS_R_25_fan_fault_22 "2号TMS风机故障(25kw)";
CM_ SG_ 2337599142 M2P_TMS_R_25_fre_fault_22 "2号TMSAC2故障(25kw变频器)";
CM_ SG_ 2337599142 M2P_TMS_R_25_D_fault_22 "2号TMS AC2故障(25kwDC/DC)";
CM_ SG_ 2337599142 M2P_TMS_R_AC2_25_P_22 "2号TMS AC2低压压力值(25kw)";
CM_ SG_ 2337599143 M2P_TMS_R_25_CP1_vol_23 "2号TMS压缩机2电压(25kw)";
CM_ SG_ 2337599143 M2P_TMS_R_25_CP1_I_23 "2号TMS压缩机2电流(25kw)";
CM_ SG_ 2337599143 M2P_TMS_R_25_CP1_r_23 "2号TMS压缩机2转速(25kw)";
CM_ SG_ 2337599143 Reserved_4 "保留";
CM_ SG_ 2337599143 M2P_TMS_R_25_fan_fault_23 "2号TMS风机故障(25kw)";
CM_ SG_ 2337599143 M2P_TMS_R_25_fre_fault_23 "2号TMSAC2故障(25kw变频器)";
CM_ SG_ 2337599143 M2P_TMS_R_25_D_fault_23 "2号TMS AC2故障(25kwDC/DC)";
CM_ SG_ 2337599143 M2P_TMS_R_AC2_25_P_23 "2号TMS AC2低压压力值(25kw)";
CM_ SG_ 2337599144 M2P_TMS_R_25_CP1_vol_24 "2号TMS压缩机2电压(25kw)";
CM_ SG_ 2337599144 M2P_TMS_R_25_CP1_I_24 "2号TMS压缩机2电流(25kw)";
CM_ SG_ 2337599144 M2P_TMS_R_25_CP1_r_24 "2号TMS压缩机2转速(25kw)";
CM_ SG_ 2337599144 Reserved_4 "保留";
CM_ SG_ 2337599144 M2P_TMS_R_25_fan_fault_24 "2号TMS风机故障(25kw)";
CM_ SG_ 2337599144 M2P_TMS_R_25_fre_fault_24 "2号TMSAC2故障(25kw变频器)";
CM_ SG_ 2337599144 M2P_TMS_R_25_D_fault_24 "2号TMS AC2故障(25kwDC/DC)";
CM_ SG_ 2337599144 M2P_TMS_R_AC2_25_P_24 "2号TMS AC2低压压力值(25kw)";
CM_ SG_ 2337599145 M2P_TMS_R_25_CP1_vol_25 "2号TMS压缩机2电压(25kw)";
CM_ SG_ 2337599145 M2P_TMS_R_25_CP1_I_25 "2号TMS压缩机2电流(25kw)";
CM_ SG_ 2337599145 M2P_TMS_R_25_CP1_r_25 "2号TMS压缩机2转速(25kw)";
CM_ SG_ 2337599145 Reserved_4 "保留";
CM_ SG_ 2337599145 M2P_TMS_R_25_fan_fault_25 "2号TMS风机故障(25kw)";
CM_ SG_ 2337599145 M2P_TMS_R_25_fre_fault_25 "2号TMSAC2故障(25kw变频器)";
CM_ SG_ 2337599145 M2P_TMS_R_25_D_fault_25 "2号TMS AC2故障(25kwDC/DC)";
CM_ SG_ 2337599145 M2P_TMS_R_AC2_25_P_25 "2号TMS AC2低压压力值(25kw)";
CM_ SG_ 2337599146 M2P_TMS_R_25_CP1_vol_26 "2号TMS压缩机2电压(25kw)";
CM_ SG_ 2337599146 M2P_TMS_R_25_CP1_I_26 "2号TMS压缩机2电流(25kw)";
CM_ SG_ 2337599146 M2P_TMS_R_25_CP1_r_26 "2号TMS压缩机2转速(25kw)";
CM_ SG_ 2337599146 Reserved_4 "保留";
CM_ SG_ 2337599146 M2P_TMS_R_25_fan_fault_26 "2号TMS风机故障(25kw)";
CM_ SG_ 2337599146 M2P_TMS_R_25_fre_fault_26 "2号TMSAC2故障(25kw变频器)";
CM_ SG_ 2337599146 M2P_TMS_R_25_D_fault_26 "2号TMS AC2故障(25kwDC/DC)";
CM_ SG_ 2337599146 M2P_TMS_R_AC2_25_P_26 "2号TMS AC2低压压力值(25kw)";
CM_ SG_ 2337599147 M2P_TMS_R_25_CP1_vol_27 "2号TMS压缩机2电压(25kw)";
CM_ SG_ 2337599147 M2P_TMS_R_25_CP1_I_27 "2号TMS压缩机2电流(25kw)";
CM_ SG_ 2337599147 M2P_TMS_R_25_CP1_r_27 "2号TMS压缩机2转速(25kw)";
CM_ SG_ 2337599147 Reserved_4 "保留";
CM_ SG_ 2337599147 M2P_TMS_R_25_fan_fault_27 "2号TMS风机故障(25kw)";
CM_ SG_ 2337599147 M2P_TMS_R_25_fre_fault_27 "2号TMSAC2故障(25kw变频器)";
CM_ SG_ 2337599147 M2P_TMS_R_25_D_fault_27 "2号TMS AC2故障(25kwDC/DC)";
CM_ SG_ 2337599147 M2P_TMS_R_AC2_25_P_27 "2号TMS AC2低压压力值(25kw)";
CM_ SG_ 2337599148 M2P_TMS_R_25_CP1_vol_28 "2号TMS压缩机2电压(25kw)";
CM_ SG_ 2337599148 M2P_TMS_R_25_CP1_I_28 "2号TMS压缩机2电流(25kw)";
CM_ SG_ 2337599148 M2P_TMS_R_25_CP1_r_28 "2号TMS压缩机2转速(25kw)";
CM_ SG_ 2337599148 Reserved_4 "保留";
CM_ SG_ 2337599148 M2P_TMS_R_25_fan_fault_28 "2号TMS风机故障(25kw)";
CM_ SG_ 2337599148 M2P_TMS_R_25_fre_fault_28 "2号TMSAC2故障(25kw变频器)";
CM_ SG_ 2337599148 M2P_TMS_R_25_D_fault_28 "2号TMS AC2故障(25kwDC/DC)";
CM_ SG_ 2337599148 M2P_TMS_R_AC2_25_P_28 "2号TMS AC2低压压力值(25kw)";
CM_ SG_ 2337599149 M2P_TMS_R_25_CP1_vol_29 "2号TMS压缩机2电压(25kw)";
CM_ SG_ 2337599149 M2P_TMS_R_25_CP1_I_29 "2号TMS压缩机2电流(25kw)";
CM_ SG_ 2337599149 M2P_TMS_R_25_CP1_r_29 "2号TMS压缩机2转速(25kw)";
CM_ SG_ 2337599149 Reserved_4 "保留";
CM_ SG_ 2337599149 M2P_TMS_R_25_fan_fault_29 "2号TMS风机故障(25kw)";
CM_ SG_ 2337599149 M2P_TMS_R_25_fre_fault_29 "2号TMSAC2故障(25kw变频器)";
CM_ SG_ 2337599149 M2P_TMS_R_25_D_fault_29 "2号TMS AC2故障(25kwDC/DC)";
CM_ SG_ 2337599149 M2P_TMS_R_AC2_25_P_29 "2号TMS AC2低压压力值(25kw)";
CM_ SG_ 2337599150 M2P_TMS_R_25_CP1_vol_30 "2号TMS压缩机2电压(25kw)";
CM_ SG_ 2337599150 M2P_TMS_R_25_CP1_I_30 "2号TMS压缩机2电流(25kw)";
CM_ SG_ 2337599150 M2P_TMS_R_25_CP1_r_30 "2号TMS压缩机2转速(25kw)";
CM_ SG_ 2337599150 Reserved_4 "保留";
CM_ SG_ 2337599150 M2P_TMS_R_25_fan_fault_30 "2号TMS风机故障(25kw)";
CM_ SG_ 2337599150 M2P_TMS_R_25_fre_fault_30 "2号TMSAC2故障(25kw变频器)";
CM_ SG_ 2337599150 M2P_TMS_R_25_D_fault_30 "2号TMS AC2故障(25kwDC/DC)";
CM_ SG_ 2337599150 M2P_TMS_R_AC2_25_P_30 "2号TMS AC2低压压力值(25kw)";
CM_ SG_ 2337599151 M2P_TMS_R_25_CP1_vol_31 "2号TMS压缩机2电压(25kw)";
CM_ SG_ 2337599151 M2P_TMS_R_25_CP1_I_31 "2号TMS压缩机2电流(25kw)";
CM_ SG_ 2337599151 M2P_TMS_R_25_CP1_r_31 "2号TMS压缩机2转速(25kw)";
CM_ SG_ 2337599151 Reserved_4 "保留";
CM_ SG_ 2337599151 M2P_TMS_R_25_fan_fault_31 "2号TMS风机故障(25kw)";
CM_ SG_ 2337599151 M2P_TMS_R_25_fre_fault_31 "2号TMSAC2故障(25kw变频器)";
CM_ SG_ 2337599151 M2P_TMS_R_25_D_fault_31 "2号TMS AC2故障(25kwDC/DC)";
CM_ SG_ 2337599151 M2P_TMS_R_AC2_25_P_31 "2号TMS AC2低压压力值(25kw)";
CM_ SG_ 2337664657 M2P_TMS_R_S_version_01 "2号TMS 对应机组的软件号";
CM_ SG_ 2337664657 M2P_TMS_R_N_S_version_01 "2号TMS 对应机组更新的软件版本号";
CM_ SG_ 2337664658 M2P_TMS_R_S_version_02 "2号TMS 对应机组的软件号";
CM_ SG_ 2337664658 M2P_TMS_R_N_S_version_02 "2号TMS 对应机组更新的软件版本号";
CM_ SG_ 2337664659 M2P_TMS_R_S_version_03 "2号TMS 对应机组的软件号";
CM_ SG_ 2337664659 M2P_TMS_R_N_S_version_03 "2号TMS 对应机组更新的软件版本号";
CM_ SG_ 2337664660 M2P_TMS_R_S_version_04 "2号TMS 对应机组的软件号";
CM_ SG_ 2337664660 M2P_TMS_R_N_S_version_04 "2号TMS 对应机组更新的软件版本号";
CM_ SG_ 2337664661 M2P_TMS_R_S_version_05 "2号TMS 对应机组的软件号";
CM_ SG_ 2337664661 M2P_TMS_R_N_S_version_05 "2号TMS 对应机组更新的软件版本号";
CM_ SG_ 2337664662 M2P_TMS_R_S_version_06 "2号TMS 对应机组的软件号";
CM_ SG_ 2337664662 M2P_TMS_R_N_S_version_06 "2号TMS 对应机组更新的软件版本号";
CM_ SG_ 2337664663 M2P_TMS_R_S_version_07 "2号TMS 对应机组的软件号";
CM_ SG_ 2337664663 M2P_TMS_R_N_S_version_07 "2号TMS 对应机组更新的软件版本号";
CM_ SG_ 2337664664 M2P_TMS_R_S_version_08 "2号TMS 对应机组的软件号";
CM_ SG_ 2337664664 M2P_TMS_R_N_S_version_08 "2号TMS 对应机组更新的软件版本号";
CM_ SG_ 2337664665 M2P_TMS_R_S_version_09 "2号TMS 对应机组的软件号";
CM_ SG_ 2337664665 M2P_TMS_R_N_S_version_09 "2号TMS 对应机组更新的软件版本号";
CM_ SG_ 2337664666 M2P_TMS_R_S_version_10 "2号TMS 对应机组的软件号";
CM_ SG_ 2337664666 M2P_TMS_R_N_S_version_10 "2号TMS 对应机组更新的软件版本号";
CM_ SG_ 2337664667 M2P_TMS_R_S_version_11 "2号TMS 对应机组的软件号";
CM_ SG_ 2337664667 M2P_TMS_R_N_S_version_11 "2号TMS 对应机组更新的软件版本号";
CM_ SG_ 2337664668 M2P_TMS_R_S_version_12 "2号TMS 对应机组的软件号";
CM_ SG_ 2337664668 M2P_TMS_R_N_S_version_12 "2号TMS 对应机组更新的软件版本号";
CM_ SG_ 2337664669 M2P_TMS_R_S_version_13 "2号TMS 对应机组的软件号";
CM_ SG_ 2337664669 M2P_TMS_R_N_S_version_13 "2号TMS 对应机组更新的软件版本号";
CM_ SG_ 2337664670 M2P_TMS_R_S_version_14 "2号TMS 对应机组的软件号";
CM_ SG_ 2337664670 M2P_TMS_R_N_S_version_14 "2号TMS 对应机组更新的软件版本号";
CM_ SG_ 2337664671 M2P_TMS_R_S_version_15 "2号TMS 对应机组的软件号";
CM_ SG_ 2337664671 M2P_TMS_R_N_S_version_15 "2号TMS 对应机组更新的软件版本号";
CM_ SG_ 2337664672 M2P_TMS_R_S_version_16 "2号TMS 对应机组的软件号";
CM_ SG_ 2337664672 M2P_TMS_R_N_S_version_16 "2号TMS 对应机组更新的软件版本号";
CM_ SG_ 2337664673 M2P_TMS_R_S_version_17 "2号TMS 对应机组的软件号";
CM_ SG_ 2337664673 M2P_TMS_R_N_S_version_17 "2号TMS 对应机组更新的软件版本号";
CM_ SG_ 2337664674 M2P_TMS_R_S_version_18 "2号TMS 对应机组的软件号";
CM_ SG_ 2337664674 M2P_TMS_R_N_S_version_18 "2号TMS 对应机组更新的软件版本号";
VAL_ 2337533585 M2P_TMS_R_TEM_01 0 "open" 1 "close" ;
VAL_ 2337533585 M2P_TMS_R_WPS_01 0 "open" 1 "close" ;
VAL_ 2337533585 M2P_TMS_R_15_fan_fault_01 0 "no fault 00实际为0x00 引号外不能使用字母" 1 "Fan 1 overvoltage 01实际为0x01" 2 "Fan 1 under voltage 02实际为0x02" 3 "Fan 1 is stuck in rotatio 03实际为0x03" 4 "Fan 1 overcurren 04实际为0x04" 5 "Fan 1 motor overheating 05实际为0x05" 6 "Fan 1 drive overheating 06实际为0x06" 7 "Fan 2 overvoltage 07实际为0x07" 8 "Fan 2 under voltage 08实际为0x08" 9 "Fan 2 is stuck in rotation 09实际为0x09" 10 "Fan 2 overcurrent 10实际为0x0A" 11 "Fan 2 motor overheating 11实际为0x0B" 12 "Fan 2drive overheating 12实际为0x0C" ;
VAL_ 2337533585 M2P_TMS_R_15_fre_fault_01 0 "no fault 00实际为0x00 引号外不能使用字母" 1 "Overcurrent 01实际为0x01" 2 "Operating overvoltage 02实际为0x02" 3 "Operating under voltage 03实际为0x03" 4 "AC input overvoltage 04实际为0x04" 5 "AC input under voltage 05实际为0x05" 6 "communication fault 06实际为0x06" 7 "Overcurrent frequency reduction 07实际为0x07" 8 "Over power frequency reduction 08实际为0x08" 9 "Input phase loss 09实际为0x09" 10 "External malfunction 10实际为0x0A" 11 "NTC overheating 11实际为0x0B" 12 "Power on to ground short circuit detection 12实际为0x0C" 13 "motor overload 13实际为0x0D" ;
VAL_ 2337533585 M2P_TMS_R_15_D_fault_01 0 "no fault 00实际为0x00 引号外不能使用字母" 1 "Overcurrent 01实际为0x01" 2 "Operating overvoltage 02实际为0x02" 3 "Operating under voltage 03实际为0x03" 4 "DC output overvoltage 04实际为0x04" 5 "DC output undervoltage 05实际为0x05" 6 "communication fault 06实际为0x06" 7 "Substrate overheating 07实际为0x07" 8 "output overload 08实际为0x08" ;
VAL_ 2337533586 M2P_TMS_R_TEM_02 0 "open" 1 "close" ;
VAL_ 2337533586 M2P_TMS_R_WPS_02 0 "open" 1 "close" ;
VAL_ 2337533586 M2P_TMS_R_15_fan_fault_02 0 "no fault 00实际为0x00 引号外不能使用字母" 1 "Fan 1 overvoltage 01实际为0x01" 2 "Fan 1 under voltage 02实际为0x02" 3 "Fan 1 is stuck in rotatio 03实际为0x03" 4 "Fan 1 overcurren 04实际为0x04" 5 "Fan 1 motor overheating 05实际为0x05" 6 "Fan 1 drive overheating 06实际为0x06" 7 "Fan 2 overvoltage 07实际为0x07" 8 "Fan 2 under voltage 08实际为0x08" 9 "Fan 2 is stuck in rotation 09实际为0x09" 10 "Fan 2 overcurrent 10实际为0x0A" 11 "Fan 2 motor overheating 11实际为0x0B" 12 "Fan 2drive overheating 12实际为0x0C" ;
VAL_ 2337533586 M2P_TMS_R_15_fre_fault_02 0 "no fault 00实际为0x00 引号外不能使用字母" 1 "Overcurrent 01实际为0x01" 2 "Operating overvoltage 02实际为0x02" 3 "Operating under voltage 03实际为0x03" 4 "AC input overvoltage 04实际为0x04" 5 "AC input under voltage 05实际为0x05" 6 "communication fault 06实际为0x06" 7 "Overcurrent frequency reduction 07实际为0x07" 8 "Over power frequency reduction 08实际为0x08" 9 "Input phase loss 09实际为0x09" 10 "External malfunction 10实际为0x0A" 11 "NTC overheating 11实际为0x0B" 12 "Power on to ground short circuit detection 12实际为0x0C" 13 "motor overload 13实际为0x0D" ;
VAL_ 2337533586 M2P_TMS_R_15_D_fault_02 0 "no fault 00实际为0x00 引号外不能使用字母" 1 "Overcurrent 01实际为0x01" 2 "Operating overvoltage 02实际为0x02" 3 "Operating under voltage 03实际为0x03" 4 "DC output overvoltage 04实际为0x04" 5 "DC output undervoltage 05实际为0x05" 6 "communication fault 06实际为0x06" 7 "Substrate overheating 07实际为0x07" 8 "output overload 08实际为0x08" ;
VAL_ 2337533587 M2P_TMS_R_TEM_03 0 "open" 1 "close" ;
VAL_ 2337533587 M2P_TMS_R_WPS_03 0 "open" 1 "close" ;
VAL_ 2337533587 M2P_TMS_R_15_fan_fault_03 0 "no fault 00实际为0x00 引号外不能使用字母" 1 "Fan 1 overvoltage 01实际为0x01" 2 "Fan 1 under voltage 02实际为0x02" 3 "Fan 1 is stuck in rotatio 03实际为0x03" 4 "Fan 1 overcurren 04实际为0x04" 5 "Fan 1 motor overheating 05实际为0x05" 6 "Fan 1 drive overheating 06实际为0x06" 7 "Fan 2 overvoltage 07实际为0x07" 8 "Fan 2 under voltage 08实际为0x08" 9 "Fan 2 is stuck in rotation 09实际为0x09" 10 "Fan 2 overcurrent 10实际为0x0A" 11 "Fan 2 motor overheating 11实际为0x0B" 12 "Fan 2drive overheating 12实际为0x0C" ;
VAL_ 2337533587 M2P_TMS_R_15_fre_fault_03 0 "no fault 00实际为0x00 引号外不能使用字母" 1 "Overcurrent 01实际为0x01" 2 "Operating overvoltage 02实际为0x02" 3 "Operating under voltage 03实际为0x03" 4 "AC input overvoltage 04实际为0x04" 5 "AC input under voltage 05实际为0x05" 6 "communication fault 06实际为0x06" 7 "Overcurrent frequency reduction 07实际为0x07" 8 "Over power frequency reduction 08实际为0x08" 9 "Input phase loss 09实际为0x09" 10 "External malfunction 10实际为0x0A" 11 "NTC overheating 11实际为0x0B" 12 "Power on to ground short circuit detection 12实际为0x0C" 13 "motor overload 13实际为0x0D" ;
VAL_ 2337533587 M2P_TMS_R_15_D_fault_03 0 "no fault 00实际为0x00 引号外不能使用字母" 1 "Overcurrent 01实际为0x01" 2 "Operating overvoltage 02实际为0x02" 3 "Operating under voltage 03实际为0x03" 4 "DC output overvoltage 04实际为0x04" 5 "DC output undervoltage 05实际为0x05" 6 "communication fault 06实际为0x06" 7 "Substrate overheating 07实际为0x07" 8 "output overload 08实际为0x08" ;
VAL_ 2337533588 M2P_TMS_R_TEM_04 0 "open" 1 "close" ;
VAL_ 2337533588 M2P_TMS_R_WPS_04 0 "open" 1 "close" ;
VAL_ 2337533588 M2P_TMS_R_15_fan_fault_04 0 "no fault 00实际为0x00 引号外不能使用字母" 1 "Fan 1 overvoltage 01实际为0x01" 2 "Fan 1 under voltage 02实际为0x02" 3 "Fan 1 is stuck in rotatio 03实际为0x03" 4 "Fan 1 overcurren 04实际为0x04" 5 "Fan 1 motor overheating 05实际为0x05" 6 "Fan 1 drive overheating 06实际为0x06" 7 "Fan 2 overvoltage 07实际为0x07" 8 "Fan 2 under voltage 08实际为0x08" 9 "Fan 2 is stuck in rotation 09实际为0x09" 10 "Fan 2 overcurrent 10实际为0x0A" 11 "Fan 2 motor overheating 11实际为0x0B" 12 "Fan 2drive overheating 12实际为0x0C" ;
VAL_ 2337533588 M2P_TMS_R_15_fre_fault_04 0 "no fault 00实际为0x00 引号外不能使用字母" 1 "Overcurrent 01实际为0x01" 2 "Operating overvoltage 02实际为0x02" 3 "Operating under voltage 03实际为0x03" 4 "AC input overvoltage 04实际为0x04" 5 "AC input under voltage 05实际为0x05" 6 "communication fault 06实际为0x06" 7 "Overcurrent frequency reduction 07实际为0x07" 8 "Over power frequency reduction 08实际为0x08" 9 "Input phase loss 09实际为0x09" 10 "External malfunction 10实际为0x0A" 11 "NTC overheating 11实际为0x0B" 12 "Power on to ground short circuit detection 12实际为0x0C" 13 "motor overload 13实际为0x0D" ;
VAL_ 2337533588 M2P_TMS_R_15_D_fault_04 0 "no fault 00实际为0x00 引号外不能使用字母" 1 "Overcurrent 01实际为0x01" 2 "Operating overvoltage 02实际为0x02" 3 "Operating under voltage 03实际为0x03" 4 "DC output overvoltage 04实际为0x04" 5 "DC output undervoltage 05实际为0x05" 6 "communication fault 06实际为0x06" 7 "Substrate overheating 07实际为0x07" 8 "output overload 08实际为0x08" ;
VAL_ 2337533589 M2P_TMS_R_TEM_05 0 "open" 1 "close" ;
VAL_ 2337533589 M2P_TMS_R_WPS_05 0 "open" 1 "close" ;
VAL_ 2337533589 M2P_TMS_R_15_fan_fault_05 0 "no fault 00实际为0x00 引号外不能使用字母" 1 "Fan 1 overvoltage 01实际为0x01" 2 "Fan 1 under voltage 02实际为0x02" 3 "Fan 1 is stuck in rotatio 03实际为0x03" 4 "Fan 1 overcurren 04实际为0x04" 5 "Fan 1 motor overheating 05实际为0x05" 6 "Fan 1 drive overheating 06实际为0x06" 7 "Fan 2 overvoltage 07实际为0x07" 8 "Fan 2 under voltage 08实际为0x08" 9 "Fan 2 is stuck in rotation 09实际为0x09" 10 "Fan 2 overcurrent 10实际为0x0A" 11 "Fan 2 motor overheating 11实际为0x0B" 12 "Fan 2drive overheating 12实际为0x0C" ;
VAL_ 2337533589 M2P_TMS_R_15_fre_fault_05 0 "no fault 00实际为0x00 引号外不能使用字母" 1 "Overcurrent 01实际为0x01" 2 "Operating overvoltage 02实际为0x02" 3 "Operating under voltage 03实际为0x03" 4 "AC input overvoltage 04实际为0x04" 5 "AC input under voltage 05实际为0x05" 6 "communication fault 06实际为0x06" 7 "Overcurrent frequency reduction 07实际为0x07" 8 "Over power frequency reduction 08实际为0x08" 9 "Input phase loss 09实际为0x09" 10 "External malfunction 10实际为0x0A" 11 "NTC overheating 11实际为0x0B" 12 "Power on to ground short circuit detection 12实际为0x0C" 13 "motor overload 13实际为0x0D" ;
VAL_ 2337533589 M2P_TMS_R_15_D_fault_05 0 "no fault 00实际为0x00 引号外不能使用字母" 1 "Overcurrent 01实际为0x01" 2 "Operating overvoltage 02实际为0x02" 3 "Operating under voltage 03实际为0x03" 4 "DC output overvoltage 04实际为0x04" 5 "DC output undervoltage 05实际为0x05" 6 "communication fault 06实际为0x06" 7 "Substrate overheating 07实际为0x07" 8 "output overload 08实际为0x08" ;
VAL_ 2337533590 M2P_TMS_R_TEM_06 0 "open" 1 "close" ;
VAL_ 2337533590 M2P_TMS_R_WPS_06 0 "open" 1 "close" ;
VAL_ 2337533590 M2P_TMS_R_15_fan_fault_06 0 "no fault 00实际为0x00 引号外不能使用字母" 1 "Fan 1 overvoltage 01实际为0x01" 2 "Fan 1 under voltage 02实际为0x02" 3 "Fan 1 is stuck in rotatio 03实际为0x03" 4 "Fan 1 overcurren 04实际为0x04" 5 "Fan 1 motor overheating 05实际为0x05" 6 "Fan 1 drive overheating 06实际为0x06" 7 "Fan 2 overvoltage 07实际为0x07" 8 "Fan 2 under voltage 08实际为0x08" 9 "Fan 2 is stuck in rotation 09实际为0x09" 10 "Fan 2 overcurrent 10实际为0x0A" 11 "Fan 2 motor overheating 11实际为0x0B" 12 "Fan 2drive overheating 12实际为0x0C" ;
VAL_ 2337533590 M2P_TMS_R_15_fre_fault_06 0 "no fault 00实际为0x00 引号外不能使用字母" 1 "Overcurrent 01实际为0x01" 2 "Operating overvoltage 02实际为0x02" 3 "Operating under voltage 03实际为0x03" 4 "AC input overvoltage 04实际为0x04" 5 "AC input under voltage 05实际为0x05" 6 "communication fault 06实际为0x06" 7 "Overcurrent frequency reduction 07实际为0x07" 8 "Over power frequency reduction 08实际为0x08" 9 "Input phase loss 09实际为0x09" 10 "External malfunction 10实际为0x0A" 11 "NTC overheating 11实际为0x0B" 12 "Power on to ground short circuit detection 12实际为0x0C" 13 "motor overload 13实际为0x0D" ;
VAL_ 2337533590 M2P_TMS_R_15_D_fault_06 0 "no fault 00实际为0x00 引号外不能使用字母" 1 "Overcurrent 01实际为0x01" 2 "Operating overvoltage 02实际为0x02" 3 "Operating under voltage 03实际为0x03" 4 "DC output overvoltage 04实际为0x04" 5 "DC output undervoltage 05实际为0x05" 6 "communication fault 06实际为0x06" 7 "Substrate overheating 07实际为0x07" 8 "output overload 08实际为0x08" ;
VAL_ 2337533591 M2P_TMS_R_TEM_07 0 "open" 1 "close" ;
VAL_ 2337533591 M2P_TMS_R_WPS_07 0 "open" 1 "close" ;
VAL_ 2337533591 M2P_TMS_R_15_fan_fault_07 0 "no fault 00实际为0x00 引号外不能使用字母" 1 "Fan 1 overvoltage 01实际为0x01" 2 "Fan 1 under voltage 02实际为0x02" 3 "Fan 1 is stuck in rotatio 03实际为0x03" 4 "Fan 1 overcurren 04实际为0x04" 5 "Fan 1 motor overheating 05实际为0x05" 6 "Fan 1 drive overheating 06实际为0x06" 7 "Fan 2 overvoltage 07实际为0x07" 8 "Fan 2 under voltage 08实际为0x08" 9 "Fan 2 is stuck in rotation 09实际为0x09" 10 "Fan 2 overcurrent 10实际为0x0A" 11 "Fan 2 motor overheating 11实际为0x0B" 12 "Fan 2drive overheating 12实际为0x0C" ;
VAL_ 2337533591 M2P_TMS_R_15_fre_fault_07 0 "no fault 00实际为0x00 引号外不能使用字母" 1 "Overcurrent 01实际为0x01" 2 "Operating overvoltage 02实际为0x02" 3 "Operating under voltage 03实际为0x03" 4 "AC input overvoltage 04实际为0x04" 5 "AC input under voltage 05实际为0x05" 6 "communication fault 06实际为0x06" 7 "Overcurrent frequency reduction 07实际为0x07" 8 "Over power frequency reduction 08实际为0x08" 9 "Input phase loss 09实际为0x09" 10 "External malfunction 10实际为0x0A" 11 "NTC overheating 11实际为0x0B" 12 "Power on to ground short circuit detection 12实际为0x0C" 13 "motor overload 13实际为0x0D" ;
VAL_ 2337533591 M2P_TMS_R_15_D_fault_07 0 "no fault 00实际为0x00 引号外不能使用字母" 1 "Overcurrent 01实际为0x01" 2 "Operating overvoltage 02实际为0x02" 3 "Operating under voltage 03实际为0x03" 4 "DC output overvoltage 04实际为0x04" 5 "DC output undervoltage 05实际为0x05" 6 "communication fault 06实际为0x06" 7 "Substrate overheating 07实际为0x07" 8 "output overload 08实际为0x08" ;
VAL_ 2337533592 M2P_TMS_R_TEM_08 0 "open" 1 "close" ;
VAL_ 2337533592 M2P_TMS_R_WPS_08 0 "open" 1 "close" ;
VAL_ 2337533592 M2P_TMS_R_15_fan_fault_08 0 "no fault 00实际为0x00 引号外不能使用字母" 1 "Fan 1 overvoltage 01实际为0x01" 2 "Fan 1 under voltage 02实际为0x02" 3 "Fan 1 is stuck in rotatio 03实际为0x03" 4 "Fan 1 overcurren 04实际为0x04" 5 "Fan 1 motor overheating 05实际为0x05" 6 "Fan 1 drive overheating 06实际为0x06" 7 "Fan 2 overvoltage 07实际为0x07" 8 "Fan 2 under voltage 08实际为0x08" 9 "Fan 2 is stuck in rotation 09实际为0x09" 10 "Fan 2 overcurrent 10实际为0x0A" 11 "Fan 2 motor overheating 11实际为0x0B" 12 "Fan 2drive overheating 12实际为0x0C" ;
VAL_ 2337533592 M2P_TMS_R_15_fre_fault_08 0 "no fault 00实际为0x00 引号外不能使用字母" 1 "Overcurrent 01实际为0x01" 2 "Operating overvoltage 02实际为0x02" 3 "Operating under voltage 03实际为0x03" 4 "AC input overvoltage 04实际为0x04" 5 "AC input under voltage 05实际为0x05" 6 "communication fault 06实际为0x06" 7 "Overcurrent frequency reduction 07实际为0x07" 8 "Over power frequency reduction 08实际为0x08" 9 "Input phase loss 09实际为0x09" 10 "External malfunction 10实际为0x0A" 11 "NTC overheating 11实际为0x0B" 12 "Power on to ground short circuit detection 12实际为0x0C" 13 "motor overload 13实际为0x0D" ;
VAL_ 2337533592 M2P_TMS_R_15_D_fault_08 0 "no fault 00实际为0x00 引号外不能使用字母" 1 "Overcurrent 01实际为0x01" 2 "Operating overvoltage 02实际为0x02" 3 "Operating under voltage 03实际为0x03" 4 "DC output overvoltage 04实际为0x04" 5 "DC output undervoltage 05实际为0x05" 6 "communication fault 06实际为0x06" 7 "Substrate overheating 07实际为0x07" 8 "output overload 08实际为0x08" ;
VAL_ 2337533593 M2P_TMS_R_TEM_09 0 "open" 1 "close" ;
VAL_ 2337533593 M2P_TMS_R_WPS_09 0 "open" 1 "close" ;
VAL_ 2337533593 M2P_TMS_R_15_fan_fault_09 0 "no fault 00实际为0x00 引号外不能使用字母" 1 "Fan 1 overvoltage 01实际为0x01" 2 "Fan 1 under voltage 02实际为0x02" 3 "Fan 1 is stuck in rotatio 03实际为0x03" 4 "Fan 1 overcurren 04实际为0x04" 5 "Fan 1 motor overheating 05实际为0x05" 6 "Fan 1 drive overheating 06实际为0x06" 7 "Fan 2 overvoltage 07实际为0x07" 8 "Fan 2 under voltage 08实际为0x08" 9 "Fan 2 is stuck in rotation 09实际为0x09" 10 "Fan 2 overcurrent 10实际为0x0A" 11 "Fan 2 motor overheating 11实际为0x0B" 12 "Fan 2drive overheating 12实际为0x0C" ;
VAL_ 2337533593 M2P_TMS_R_15_fre_fault_09 0 "no fault 00实际为0x00 引号外不能使用字母" 1 "Overcurrent 01实际为0x01" 2 "Operating overvoltage 02实际为0x02" 3 "Operating under voltage 03实际为0x03" 4 "AC input overvoltage 04实际为0x04" 5 "AC input under voltage 05实际为0x05" 6 "communication fault 06实际为0x06" 7 "Overcurrent frequency reduction 07实际为0x07" 8 "Over power frequency reduction 08实际为0x08" 9 "Input phase loss 09实际为0x09" 10 "External malfunction 10实际为0x0A" 11 "NTC overheating 11实际为0x0B" 12 "Power on to ground short circuit detection 12实际为0x0C" 13 "motor overload 13实际为0x0D" ;
VAL_ 2337533593 M2P_TMS_R_15_D_fault_09 0 "no fault 00实际为0x00 引号外不能使用字母" 1 "Overcurrent 01实际为0x01" 2 "Operating overvoltage 02实际为0x02" 3 "Operating under voltage 03实际为0x03" 4 "DC output overvoltage 04实际为0x04" 5 "DC output undervoltage 05实际为0x05" 6 "communication fault 06实际为0x06" 7 "Substrate overheating 07实际为0x07" 8 "output overload 08实际为0x08" ;
VAL_ 2337533594 M2P_TMS_R_TEM_10 0 "open" 1 "close" ;
VAL_ 2337533594 M2P_TMS_R_WPS_10 0 "open" 1 "close" ;
VAL_ 2337533594 M2P_TMS_R_15_fan_fault_10 0 "no fault 00实际为0x00 引号外不能使用字母" 1 "Fan 1 overvoltage 01实际为0x01" 2 "Fan 1 under voltage 02实际为0x02" 3 "Fan 1 is stuck in rotatio 03实际为0x03" 4 "Fan 1 overcurren 04实际为0x04" 5 "Fan 1 motor overheating 05实际为0x05" 6 "Fan 1 drive overheating 06实际为0x06" 7 "Fan 2 overvoltage 07实际为0x07" 8 "Fan 2 under voltage 08实际为0x08" 9 "Fan 2 is stuck in rotation 09实际为0x09" 10 "Fan 2 overcurrent 10实际为0x0A" 11 "Fan 2 motor overheating 11实际为0x0B" 12 "Fan 2drive overheating 12实际为0x0C" ;
VAL_ 2337533594 M2P_TMS_R_15_fre_fault_10 0 "no fault 00实际为0x00 引号外不能使用字母" 1 "Overcurrent 01实际为0x01" 2 "Operating overvoltage 02实际为0x02" 3 "Operating under voltage 03实际为0x03" 4 "AC input overvoltage 04实际为0x04" 5 "AC input under voltage 05实际为0x05" 6 "communication fault 06实际为0x06" 7 "Overcurrent frequency reduction 07实际为0x07" 8 "Over power frequency reduction 08实际为0x08" 9 "Input phase loss 09实际为0x09" 10 "External malfunction 10实际为0x0A" 11 "NTC overheating 11实际为0x0B" 12 "Power on to ground short circuit detection 12实际为0x0C" 13 "motor overload 13实际为0x0D" ;
VAL_ 2337533594 M2P_TMS_R_15_D_fault_10 0 "no fault 00实际为0x00 引号外不能使用字母" 1 "Overcurrent 01实际为0x01" 2 "Operating overvoltage 02实际为0x02" 3 "Operating under voltage 03实际为0x03" 4 "DC output overvoltage 04实际为0x04" 5 "DC output undervoltage 05实际为0x05" 6 "communication fault 06实际为0x06" 7 "Substrate overheating 07实际为0x07" 8 "output overload 08实际为0x08" ;
VAL_ 2337533595 M2P_TMS_R_TEM_11 0 "open" 1 "close" ;
VAL_ 2337533595 M2P_TMS_R_WPS_11 0 "open" 1 "close" ;
VAL_ 2337533595 M2P_TMS_R_15_fan_fault_11 0 "no fault 00实际为0x00 引号外不能使用字母" 1 "Fan 1 overvoltage 01实际为0x01" 2 "Fan 1 under voltage 02实际为0x02" 3 "Fan 1 is stuck in rotatio 03实际为0x03" 4 "Fan 1 overcurren 04实际为0x04" 5 "Fan 1 motor overheating 05实际为0x05" 6 "Fan 1 drive overheating 06实际为0x06" 7 "Fan 2 overvoltage 07实际为0x07" 8 "Fan 2 under voltage 08实际为0x08" 9 "Fan 2 is stuck in rotation 09实际为0x09" 10 "Fan 2 overcurrent 10实际为0x0A" 11 "Fan 2 motor overheating 11实际为0x0B" 12 "Fan 2drive overheating 12实际为0x0C" ;
VAL_ 2337533595 M2P_TMS_R_15_fre_fault_11 0 "no fault 00实际为0x00 引号外不能使用字母" 1 "Overcurrent 01实际为0x01" 2 "Operating overvoltage 02实际为0x02" 3 "Operating under voltage 03实际为0x03" 4 "AC input overvoltage 04实际为0x04" 5 "AC input under voltage 05实际为0x05" 6 "communication fault 06实际为0x06" 7 "Overcurrent frequency reduction 07实际为0x07" 8 "Over power frequency reduction 08实际为0x08" 9 "Input phase loss 09实际为0x09" 10 "External malfunction 10实际为0x0A" 11 "NTC overheating 11实际为0x0B" 12 "Power on to ground short circuit detection 12实际为0x0C" 13 "motor overload 13实际为0x0D" ;
VAL_ 2337533595 M2P_TMS_R_15_D_fault_11 0 "no fault 00实际为0x00 引号外不能使用字母" 1 "Overcurrent 01实际为0x01" 2 "Operating overvoltage 02实际为0x02" 3 "Operating under voltage 03实际为0x03" 4 "DC output overvoltage 04实际为0x04" 5 "DC output undervoltage 05实际为0x05" 6 "communication fault 06实际为0x06" 7 "Substrate overheating 07实际为0x07" 8 "output overload 08实际为0x08" ;
VAL_ 2337533596 M2P_TMS_R_TEM_12 0 "open" 1 "close" ;
VAL_ 2337533596 M2P_TMS_R_WPS_12 0 "open" 1 "close" ;
VAL_ 2337533596 M2P_TMS_R_15_fan_fault_12 0 "no fault 00实际为0x00 引号外不能使用字母" 1 "Fan 1 overvoltage 01实际为0x01" 2 "Fan 1 under voltage 02实际为0x02" 3 "Fan 1 is stuck in rotatio 03实际为0x03" 4 "Fan 1 overcurren 04实际为0x04" 5 "Fan 1 motor overheating 05实际为0x05" 6 "Fan 1 drive overheating 06实际为0x06" 7 "Fan 2 overvoltage 07实际为0x07" 8 "Fan 2 under voltage 08实际为0x08" 9 "Fan 2 is stuck in rotation 09实际为0x09" 10 "Fan 2 overcurrent 10实际为0x0A" 11 "Fan 2 motor overheating 11实际为0x0B" 12 "Fan 2drive overheating 12实际为0x0C" ;
VAL_ 2337533596 M2P_TMS_R_15_fre_fault_12 0 "no fault 00实际为0x00 引号外不能使用字母" 1 "Overcurrent 01实际为0x01" 2 "Operating overvoltage 02实际为0x02" 3 "Operating under voltage 03实际为0x03" 4 "AC input overvoltage 04实际为0x04" 5 "AC input under voltage 05实际为0x05" 6 "communication fault 06实际为0x06" 7 "Overcurrent frequency reduction 07实际为0x07" 8 "Over power frequency reduction 08实际为0x08" 9 "Input phase loss 09实际为0x09" 10 "External malfunction 10实际为0x0A" 11 "NTC overheating 11实际为0x0B" 12 "Power on to ground short circuit detection 12实际为0x0C" 13 "motor overload 13实际为0x0D" ;
VAL_ 2337533596 M2P_TMS_R_15_D_fault_12 0 "no fault 00实际为0x00 引号外不能使用字母" 1 "Overcurrent 01实际为0x01" 2 "Operating overvoltage 02实际为0x02" 3 "Operating under voltage 03实际为0x03" 4 "DC output overvoltage 04实际为0x04" 5 "DC output undervoltage 05实际为0x05" 6 "communication fault 06实际为0x06" 7 "Substrate overheating 07实际为0x07" 8 "output overload 08实际为0x08" ;
VAL_ 2337533597 M2P_TMS_R_TEM_13 0 "open" 1 "close" ;
VAL_ 2337533597 M2P_TMS_R_WPS_13 0 "open" 1 "close" ;
VAL_ 2337533597 M2P_TMS_R_15_fan_fault_13 0 "no fault 00实际为0x00 引号外不能使用字母" 1 "Fan 1 overvoltage 01实际为0x01" 2 "Fan 1 under voltage 02实际为0x02" 3 "Fan 1 is stuck in rotatio 03实际为0x03" 4 "Fan 1 overcurren 04实际为0x04" 5 "Fan 1 motor overheating 05实际为0x05" 6 "Fan 1 drive overheating 06实际为0x06" 7 "Fan 2 overvoltage 07实际为0x07" 8 "Fan 2 under voltage 08实际为0x08" 9 "Fan 2 is stuck in rotation 09实际为0x09" 10 "Fan 2 overcurrent 10实际为0x0A" 11 "Fan 2 motor overheating 11实际为0x0B" 12 "Fan 2drive overheating 12实际为0x0C" ;
VAL_ 2337533597 M2P_TMS_R_15_fre_fault_13 0 "no fault 00实际为0x00 引号外不能使用字母" 1 "Overcurrent 01实际为0x01" 2 "Operating overvoltage 02实际为0x02" 3 "Operating under voltage 03实际为0x03" 4 "AC input overvoltage 04实际为0x04" 5 "AC input under voltage 05实际为0x05" 6 "communication fault 06实际为0x06" 7 "Overcurrent frequency reduction 07实际为0x07" 8 "Over power frequency reduction 08实际为0x08" 9 "Input phase loss 09实际为0x09" 10 "External malfunction 10实际为0x0A" 11 "NTC overheating 11实际为0x0B" 12 "Power on to ground short circuit detection 12实际为0x0C" 13 "motor overload 13实际为0x0D" ;
VAL_ 2337533597 M2P_TMS_R_15_D_fault_13 0 "no fault 00实际为0x00 引号外不能使用字母" 1 "Overcurrent 01实际为0x01" 2 "Operating overvoltage 02实际为0x02" 3 "Operating under voltage 03实际为0x03" 4 "DC output overvoltage 04实际为0x04" 5 "DC output undervoltage 05实际为0x05" 6 "communication fault 06实际为0x06" 7 "Substrate overheating 07实际为0x07" 8 "output overload 08实际为0x08" ;
VAL_ 2337533598 M2P_TMS_R_TEM_14 0 "open" 1 "close" ;
VAL_ 2337533598 M2P_TMS_R_WPS_14 0 "open" 1 "close" ;
VAL_ 2337533598 M2P_TMS_R_15_fan_fault_14 0 "no fault 00实际为0x00 引号外不能使用字母" 1 "Fan 1 overvoltage 01实际为0x01" 2 "Fan 1 under voltage 02实际为0x02" 3 "Fan 1 is stuck in rotatio 03实际为0x03" 4 "Fan 1 overcurren 04实际为0x04" 5 "Fan 1 motor overheating 05实际为0x05" 6 "Fan 1 drive overheating 06实际为0x06" 7 "Fan 2 overvoltage 07实际为0x07" 8 "Fan 2 under voltage 08实际为0x08" 9 "Fan 2 is stuck in rotation 09实际为0x09" 10 "Fan 2 overcurrent 10实际为0x0A" 11 "Fan 2 motor overheating 11实际为0x0B" 12 "Fan 2drive overheating 12实际为0x0C" ;
VAL_ 2337533598 M2P_TMS_R_15_fre_fault_14 0 "no fault 00实际为0x00 引号外不能使用字母" 1 "Overcurrent 01实际为0x01" 2 "Operating overvoltage 02实际为0x02" 3 "Operating under voltage 03实际为0x03" 4 "AC input overvoltage 04实际为0x04" 5 "AC input under voltage 05实际为0x05" 6 "communication fault 06实际为0x06" 7 "Overcurrent frequency reduction 07实际为0x07" 8 "Over power frequency reduction 08实际为0x08" 9 "Input phase loss 09实际为0x09" 10 "External malfunction 10实际为0x0A" 11 "NTC overheating 11实际为0x0B" 12 "Power on to ground short circuit detection 12实际为0x0C" 13 "motor overload 13实际为0x0D" ;
VAL_ 2337533598 M2P_TMS_R_15_D_fault_14 0 "no fault 00实际为0x00 引号外不能使用字母" 1 "Overcurrent 01实际为0x01" 2 "Operating overvoltage 02实际为0x02" 3 "Operating under voltage 03实际为0x03" 4 "DC output overvoltage 04实际为0x04" 5 "DC output undervoltage 05实际为0x05" 6 "communication fault 06实际为0x06" 7 "Substrate overheating 07实际为0x07" 8 "output overload 08实际为0x08" ;
VAL_ 2337533599 M2P_TMS_R_TEM_15 0 "open" 1 "close" ;
VAL_ 2337533599 M2P_TMS_R_WPS_15 0 "open" 1 "close" ;
VAL_ 2337533599 M2P_TMS_R_15_fan_fault_15 0 "no fault 00实际为0x00 引号外不能使用字母" 1 "Fan 1 overvoltage 01实际为0x01" 2 "Fan 1 under voltage 02实际为0x02" 3 "Fan 1 is stuck in rotatio 03实际为0x03" 4 "Fan 1 overcurren 04实际为0x04" 5 "Fan 1 motor overheating 05实际为0x05" 6 "Fan 1 drive overheating 06实际为0x06" 7 "Fan 2 overvoltage 07实际为0x07" 8 "Fan 2 under voltage 08实际为0x08" 9 "Fan 2 is stuck in rotation 09实际为0x09" 10 "Fan 2 overcurrent 10实际为0x0A" 11 "Fan 2 motor overheating 11实际为0x0B" 12 "Fan 2drive overheating 12实际为0x0C" ;
VAL_ 2337533599 M2P_TMS_R_15_fre_fault_15 0 "no fault 00实际为0x00 引号外不能使用字母" 1 "Overcurrent 01实际为0x01" 2 "Operating overvoltage 02实际为0x02" 3 "Operating under voltage 03实际为0x03" 4 "AC input overvoltage 04实际为0x04" 5 "AC input under voltage 05实际为0x05" 6 "communication fault 06实际为0x06" 7 "Overcurrent frequency reduction 07实际为0x07" 8 "Over power frequency reduction 08实际为0x08" 9 "Input phase loss 09实际为0x09" 10 "External malfunction 10实际为0x0A" 11 "NTC overheating 11实际为0x0B" 12 "Power on to ground short circuit detection 12实际为0x0C" 13 "motor overload 13实际为0x0D" ;
VAL_ 2337533599 M2P_TMS_R_15_D_fault_15 0 "no fault 00实际为0x00 引号外不能使用字母" 1 "Overcurrent 01实际为0x01" 2 "Operating overvoltage 02实际为0x02" 3 "Operating under voltage 03实际为0x03" 4 "DC output overvoltage 04实际为0x04" 5 "DC output undervoltage 05实际为0x05" 6 "communication fault 06实际为0x06" 7 "Substrate overheating 07实际为0x07" 8 "output overload 08实际为0x08" ;
VAL_ 2337533600 M2P_TMS_R_TEM_16 0 "open" 1 "close" ;
VAL_ 2337533600 M2P_TMS_R_WPS_16 0 "open" 1 "close" ;
VAL_ 2337533600 M2P_TMS_R_15_fan_fault_16 0 "no fault 00实际为0x00 引号外不能使用字母" 1 "Fan 1 overvoltage 01实际为0x01" 2 "Fan 1 under voltage 02实际为0x02" 3 "Fan 1 is stuck in rotatio 03实际为0x03" 4 "Fan 1 overcurren 04实际为0x04" 5 "Fan 1 motor overheating 05实际为0x05" 6 "Fan 1 drive overheating 06实际为0x06" 7 "Fan 2 overvoltage 07实际为0x07" 8 "Fan 2 under voltage 08实际为0x08" 9 "Fan 2 is stuck in rotation 09实际为0x09" 10 "Fan 2 overcurrent 10实际为0x0A" 11 "Fan 2 motor overheating 11实际为0x0B" 12 "Fan 2drive overheating 12实际为0x0C" ;
VAL_ 2337533600 M2P_TMS_R_15_fre_fault_16 0 "no fault 00实际为0x00 引号外不能使用字母" 1 "Overcurrent 01实际为0x01" 2 "Operating overvoltage 02实际为0x02" 3 "Operating under voltage 03实际为0x03" 4 "AC input overvoltage 04实际为0x04" 5 "AC input under voltage 05实际为0x05" 6 "communication fault 06实际为0x06" 7 "Overcurrent frequency reduction 07实际为0x07" 8 "Over power frequency reduction 08实际为0x08" 9 "Input phase loss 09实际为0x09" 10 "External malfunction 10实际为0x0A" 11 "NTC overheating 11实际为0x0B" 12 "Power on to ground short circuit detection 12实际为0x0C" 13 "motor overload 13实际为0x0D" ;
VAL_ 2337533600 M2P_TMS_R_15_D_fault_16 0 "no fault 00实际为0x00 引号外不能使用字母" 1 "Overcurrent 01实际为0x01" 2 "Operating overvoltage 02实际为0x02" 3 "Operating under voltage 03实际为0x03" 4 "DC output overvoltage 04实际为0x04" 5 "DC output undervoltage 05实际为0x05" 6 "communication fault 06实际为0x06" 7 "Substrate overheating 07实际为0x07" 8 "output overload 08实际为0x08" ;
VAL_ 2337533601 M2P_TMS_R_TEM_17 0 "open" 1 "close" ;
VAL_ 2337533601 M2P_TMS_R_WPS_17 0 "open" 1 "close" ;
VAL_ 2337533601 M2P_TMS_R_15_fan_fault_17 0 "no fault 00实际为0x00 引号外不能使用字母" 1 "Fan 1 overvoltage 01实际为0x01" 2 "Fan 1 under voltage 02实际为0x02" 3 "Fan 1 is stuck in rotatio 03实际为0x03" 4 "Fan 1 overcurren 04实际为0x04" 5 "Fan 1 motor overheating 05实际为0x05" 6 "Fan 1 drive overheating 06实际为0x06" 7 "Fan 2 overvoltage 07实际为0x07" 8 "Fan 2 under voltage 08实际为0x08" 9 "Fan 2 is stuck in rotation 09实际为0x09" 10 "Fan 2 overcurrent 10实际为0x0A" 11 "Fan 2 motor overheating 11实际为0x0B" 12 "Fan 2drive overheating 12实际为0x0C" ;
VAL_ 2337533601 M2P_TMS_R_15_fre_fault_17 0 "no fault 00实际为0x00 引号外不能使用字母" 1 "Overcurrent 01实际为0x01" 2 "Operating overvoltage 02实际为0x02" 3 "Operating under voltage 03实际为0x03" 4 "AC input overvoltage 04实际为0x04" 5 "AC input under voltage 05实际为0x05" 6 "communication fault 06实际为0x06" 7 "Overcurrent frequency reduction 07实际为0x07" 8 "Over power frequency reduction 08实际为0x08" 9 "Input phase loss 09实际为0x09" 10 "External malfunction 10实际为0x0A" 11 "NTC overheating 11实际为0x0B" 12 "Power on to ground short circuit detection 12实际为0x0C" 13 "motor overload 13实际为0x0D" ;
VAL_ 2337533601 M2P_TMS_R_15_D_fault_17 0 "no fault 00实际为0x00 引号外不能使用字母" 1 "Overcurrent 01实际为0x01" 2 "Operating overvoltage 02实际为0x02" 3 "Operating under voltage 03实际为0x03" 4 "DC output overvoltage 04实际为0x04" 5 "DC output undervoltage 05实际为0x05" 6 "communication fault 06实际为0x06" 7 "Substrate overheating 07实际为0x07" 8 "output overload 08实际为0x08" ;
VAL_ 2337533602 M2P_TMS_R_TEM_18 0 "open" 1 "close" ;
VAL_ 2337533602 M2P_TMS_R_WPS_18 0 "open" 1 "close" ;
VAL_ 2337533602 M2P_TMS_R_15_fan_fault_18 0 "no fault 00实际为0x00 引号外不能使用字母" 1 "Fan 1 overvoltage 01实际为0x01" 2 "Fan 1 under voltage 02实际为0x02" 3 "Fan 1 is stuck in rotatio 03实际为0x03" 4 "Fan 1 overcurren 04实际为0x04" 5 "Fan 1 motor overheating 05实际为0x05" 6 "Fan 1 drive overheating 06实际为0x06" 7 "Fan 2 overvoltage 07实际为0x07" 8 "Fan 2 under voltage 08实际为0x08" 9 "Fan 2 is stuck in rotation 09实际为0x09" 10 "Fan 2 overcurrent 10实际为0x0A" 11 "Fan 2 motor overheating 11实际为0x0B" 12 "Fan 2drive overheating 12实际为0x0C" ;
VAL_ 2337533602 M2P_TMS_R_15_fre_fault_18 0 "no fault 00实际为0x00 引号外不能使用字母" 1 "Overcurrent 01实际为0x01" 2 "Operating overvoltage 02实际为0x02" 3 "Operating under voltage 03实际为0x03" 4 "AC input overvoltage 04实际为0x04" 5 "AC input under voltage 05实际为0x05" 6 "communication fault 06实际为0x06" 7 "Overcurrent frequency reduction 07实际为0x07" 8 "Over power frequency reduction 08实际为0x08" 9 "Input phase loss 09实际为0x09" 10 "External malfunction 10实际为0x0A" 11 "NTC overheating 11实际为0x0B" 12 "Power on to ground short circuit detection 12实际为0x0C" 13 "motor overload 13实际为0x0D" ;
VAL_ 2337533602 M2P_TMS_R_15_D_fault_18 0 "no fault 00实际为0x00 引号外不能使用字母" 1 "Overcurrent 01实际为0x01" 2 "Operating overvoltage 02实际为0x02" 3 "Operating under voltage 03实际为0x03" 4 "DC output overvoltage 04实际为0x04" 5 "DC output undervoltage 05实际为0x05" 6 "communication fault 06实际为0x06" 7 "Substrate overheating 07实际为0x07" 8 "output overload 08实际为0x08" ;
VAL_ 2337533603 M2P_TMS_R_TEM_19 0 "open" 1 "close" ;
VAL_ 2337533603 M2P_TMS_R_WPS_19 0 "open" 1 "close" ;
VAL_ 2337533603 M2P_TMS_R_15_fan_fault_19 0 "no fault 00实际为0x00 引号外不能使用字母" 1 "Fan 1 overvoltage 01实际为0x01" 2 "Fan 1 under voltage 02实际为0x02" 3 "Fan 1 is stuck in rotatio 03实际为0x03" 4 "Fan 1 overcurren 04实际为0x04" 5 "Fan 1 motor overheating 05实际为0x05" 6 "Fan 1 drive overheating 06实际为0x06" 7 "Fan 2 overvoltage 07实际为0x07" 8 "Fan 2 under voltage 08实际为0x08" 9 "Fan 2 is stuck in rotation 09实际为0x09" 10 "Fan 2 overcurrent 10实际为0x0A" 11 "Fan 2 motor overheating 11实际为0x0B" 12 "Fan 2drive overheating 12实际为0x0C" ;
VAL_ 2337533603 M2P_TMS_R_15_fre_fault_19 0 "no fault 00实际为0x00 引号外不能使用字母" 1 "Overcurrent 01实际为0x01" 2 "Operating overvoltage 02实际为0x02" 3 "Operating under voltage 03实际为0x03" 4 "AC input overvoltage 04实际为0x04" 5 "AC input under voltage 05实际为0x05" 6 "communication fault 06实际为0x06" 7 "Overcurrent frequency reduction 07实际为0x07" 8 "Over power frequency reduction 08实际为0x08" 9 "Input phase loss 09实际为0x09" 10 "External malfunction 10实际为0x0A" 11 "NTC overheating 11实际为0x0B" 12 "Power on to ground short circuit detection 12实际为0x0C" 13 "motor overload 13实际为0x0D" ;
VAL_ 2337533603 M2P_TMS_R_15_D_fault_19 0 "no fault 00实际为0x00 引号外不能使用字母" 1 "Overcurrent 01实际为0x01" 2 "Operating overvoltage 02实际为0x02" 3 "Operating under voltage 03实际为0x03" 4 "DC output overvoltage 04实际为0x04" 5 "DC output undervoltage 05实际为0x05" 6 "communication fault 06实际为0x06" 7 "Substrate overheating 07实际为0x07" 8 "output overload 08实际为0x08" ;
VAL_ 2337533604 M2P_TMS_R_TEM_20 0 "open" 1 "close" ;
VAL_ 2337533604 M2P_TMS_R_WPS_20 0 "open" 1 "close" ;
VAL_ 2337533604 M2P_TMS_R_15_fan_fault_20 0 "no fault 00实际为0x00 引号外不能使用字母" 1 "Fan 1 overvoltage 01实际为0x01" 2 "Fan 1 under voltage 02实际为0x02" 3 "Fan 1 is stuck in rotatio 03实际为0x03" 4 "Fan 1 overcurren 04实际为0x04" 5 "Fan 1 motor overheating 05实际为0x05" 6 "Fan 1 drive overheating 06实际为0x06" 7 "Fan 2 overvoltage 07实际为0x07" 8 "Fan 2 under voltage 08实际为0x08" 9 "Fan 2 is stuck in rotation 09实际为0x09" 10 "Fan 2 overcurrent 10实际为0x0A" 11 "Fan 2 motor overheating 11实际为0x0B" 12 "Fan 2drive overheating 12实际为0x0C" ;
VAL_ 2337533604 M2P_TMS_R_15_fre_fault_20 0 "no fault 00实际为0x00 引号外不能使用字母" 1 "Overcurrent 01实际为0x01" 2 "Operating overvoltage 02实际为0x02" 3 "Operating under voltage 03实际为0x03" 4 "AC input overvoltage 04实际为0x04" 5 "AC input under voltage 05实际为0x05" 6 "communication fault 06实际为0x06" 7 "Overcurrent frequency reduction 07实际为0x07" 8 "Over power frequency reduction 08实际为0x08" 9 "Input phase loss 09实际为0x09" 10 "External malfunction 10实际为0x0A" 11 "NTC overheating 11实际为0x0B" 12 "Power on to ground short circuit detection 12实际为0x0C" 13 "motor overload 13实际为0x0D" ;
VAL_ 2337533604 M2P_TMS_R_15_D_fault_20 0 "no fault 00实际为0x00 引号外不能使用字母" 1 "Overcurrent 01实际为0x01" 2 "Operating overvoltage 02实际为0x02" 3 "Operating under voltage 03实际为0x03" 4 "DC output overvoltage 04实际为0x04" 5 "DC output undervoltage 05实际为0x05" 6 "communication fault 06实际为0x06" 7 "Substrate overheating 07实际为0x07" 8 "output overload 08实际为0x08" ;
VAL_ 2337533605 M2P_TMS_R_TEM_21 0 "open" 1 "close" ;
VAL_ 2337533605 M2P_TMS_R_WPS_21 0 "open" 1 "close" ;
VAL_ 2337533605 M2P_TMS_R_15_fan_fault_21 0 "no fault 00实际为0x00 引号外不能使用字母" 1 "Fan 1 overvoltage 01实际为0x01" 2 "Fan 1 under voltage 02实际为0x02" 3 "Fan 1 is stuck in rotatio 03实际为0x03" 4 "Fan 1 overcurren 04实际为0x04" 5 "Fan 1 motor overheating 05实际为0x05" 6 "Fan 1 drive overheating 06实际为0x06" 7 "Fan 2 overvoltage 07实际为0x07" 8 "Fan 2 under voltage 08实际为0x08" 9 "Fan 2 is stuck in rotation 09实际为0x09" 10 "Fan 2 overcurrent 10实际为0x0A" 11 "Fan 2 motor overheating 11实际为0x0B" 12 "Fan 2drive overheating 12实际为0x0C" ;
VAL_ 2337533605 M2P_TMS_R_15_fre_fault_21 0 "no fault 00实际为0x00 引号外不能使用字母" 1 "Overcurrent 01实际为0x01" 2 "Operating overvoltage 02实际为0x02" 3 "Operating under voltage 03实际为0x03" 4 "AC input overvoltage 04实际为0x04" 5 "AC input under voltage 05实际为0x05" 6 "communication fault 06实际为0x06" 7 "Overcurrent frequency reduction 07实际为0x07" 8 "Over power frequency reduction 08实际为0x08" 9 "Input phase loss 09实际为0x09" 10 "External malfunction 10实际为0x0A" 11 "NTC overheating 11实际为0x0B" 12 "Power on to ground short circuit detection 12实际为0x0C" 13 "motor overload 13实际为0x0D" ;
VAL_ 2337533605 M2P_TMS_R_15_D_fault_21 0 "no fault 00实际为0x00 引号外不能使用字母" 1 "Overcurrent 01实际为0x01" 2 "Operating overvoltage 02实际为0x02" 3 "Operating under voltage 03实际为0x03" 4 "DC output overvoltage 04实际为0x04" 5 "DC output undervoltage 05实际为0x05" 6 "communication fault 06实际为0x06" 7 "Substrate overheating 07实际为0x07" 8 "output overload 08实际为0x08" ;
VAL_ 2337533606 M2P_TMS_R_TEM_22 0 "open" 1 "close" ;
VAL_ 2337533606 M2P_TMS_R_WPS_22 0 "open" 1 "close" ;
VAL_ 2337533606 M2P_TMS_R_15_fan_fault_22 0 "no fault 00实际为0x00 引号外不能使用字母" 1 "Fan 1 overvoltage 01实际为0x01" 2 "Fan 1 under voltage 02实际为0x02" 3 "Fan 1 is stuck in rotatio 03实际为0x03" 4 "Fan 1 overcurren 04实际为0x04" 5 "Fan 1 motor overheating 05实际为0x05" 6 "Fan 1 drive overheating 06实际为0x06" 7 "Fan 2 overvoltage 07实际为0x07" 8 "Fan 2 under voltage 08实际为0x08" 9 "Fan 2 is stuck in rotation 09实际为0x09" 10 "Fan 2 overcurrent 10实际为0x0A" 11 "Fan 2 motor overheating 11实际为0x0B" 12 "Fan 2drive overheating 12实际为0x0C" ;
VAL_ 2337533606 M2P_TMS_R_15_fre_fault_22 0 "no fault 00实际为0x00 引号外不能使用字母" 1 "Overcurrent 01实际为0x01" 2 "Operating overvoltage 02实际为0x02" 3 "Operating under voltage 03实际为0x03" 4 "AC input overvoltage 04实际为0x04" 5 "AC input under voltage 05实际为0x05" 6 "communication fault 06实际为0x06" 7 "Overcurrent frequency reduction 07实际为0x07" 8 "Over power frequency reduction 08实际为0x08" 9 "Input phase loss 09实际为0x09" 10 "External malfunction 10实际为0x0A" 11 "NTC overheating 11实际为0x0B" 12 "Power on to ground short circuit detection 12实际为0x0C" 13 "motor overload 13实际为0x0D" ;
VAL_ 2337533606 M2P_TMS_R_15_D_fault_22 0 "no fault 00实际为0x00 引号外不能使用字母" 1 "Overcurrent 01实际为0x01" 2 "Operating overvoltage 02实际为0x02" 3 "Operating under voltage 03实际为0x03" 4 "DC output overvoltage 04实际为0x04" 5 "DC output undervoltage 05实际为0x05" 6 "communication fault 06实际为0x06" 7 "Substrate overheating 07实际为0x07" 8 "output overload 08实际为0x08" ;
VAL_ 2337533607 M2P_TMS_R_TEM_23 0 "open" 1 "close" ;
VAL_ 2337533607 M2P_TMS_R_WPS_23 0 "open" 1 "close" ;
VAL_ 2337533607 M2P_TMS_R_15_fan_fault_23 0 "no fault 00实际为0x00 引号外不能使用字母" 1 "Fan 1 overvoltage 01实际为0x01" 2 "Fan 1 under voltage 02实际为0x02" 3 "Fan 1 is stuck in rotatio 03实际为0x03" 4 "Fan 1 overcurren 04实际为0x04" 5 "Fan 1 motor overheating 05实际为0x05" 6 "Fan 1 drive overheating 06实际为0x06" 7 "Fan 2 overvoltage 07实际为0x07" 8 "Fan 2 under voltage 08实际为0x08" 9 "Fan 2 is stuck in rotation 09实际为0x09" 10 "Fan 2 overcurrent 10实际为0x0A" 11 "Fan 2 motor overheating 11实际为0x0B" 12 "Fan 2drive overheating 12实际为0x0C" ;
VAL_ 2337533607 M2P_TMS_R_15_fre_fault_23 0 "no fault 00实际为0x00 引号外不能使用字母" 1 "Overcurrent 01实际为0x01" 2 "Operating overvoltage 02实际为0x02" 3 "Operating under voltage 03实际为0x03" 4 "AC input overvoltage 04实际为0x04" 5 "AC input under voltage 05实际为0x05" 6 "communication fault 06实际为0x06" 7 "Overcurrent frequency reduction 07实际为0x07" 8 "Over power frequency reduction 08实际为0x08" 9 "Input phase loss 09实际为0x09" 10 "External malfunction 10实际为0x0A" 11 "NTC overheating 11实际为0x0B" 12 "Power on to ground short circuit detection 12实际为0x0C" 13 "motor overload 13实际为0x0D" ;
VAL_ 2337533607 M2P_TMS_R_15_D_fault_23 0 "no fault 00实际为0x00 引号外不能使用字母" 1 "Overcurrent 01实际为0x01" 2 "Operating overvoltage 02实际为0x02" 3 "Operating under voltage 03实际为0x03" 4 "DC output overvoltage 04实际为0x04" 5 "DC output undervoltage 05实际为0x05" 6 "communication fault 06实际为0x06" 7 "Substrate overheating 07实际为0x07" 8 "output overload 08实际为0x08" ;
VAL_ 2337533608 M2P_TMS_R_TEM_24 0 "open" 1 "close" ;
VAL_ 2337533608 M2P_TMS_R_WPS_24 0 "open" 1 "close" ;
VAL_ 2337533608 M2P_TMS_R_15_fan_fault_24 0 "no fault 00实际为0x00 引号外不能使用字母" 1 "Fan 1 overvoltage 01实际为0x01" 2 "Fan 1 under voltage 02实际为0x02" 3 "Fan 1 is stuck in rotatio 03实际为0x03" 4 "Fan 1 overcurren 04实际为0x04" 5 "Fan 1 motor overheating 05实际为0x05" 6 "Fan 1 drive overheating 06实际为0x06" 7 "Fan 2 overvoltage 07实际为0x07" 8 "Fan 2 under voltage 08实际为0x08" 9 "Fan 2 is stuck in rotation 09实际为0x09" 10 "Fan 2 overcurrent 10实际为0x0A" 11 "Fan 2 motor overheating 11实际为0x0B" 12 "Fan 2drive overheating 12实际为0x0C" ;
VAL_ 2337533608 M2P_TMS_R_15_fre_fault_24 0 "no fault 00实际为0x00 引号外不能使用字母" 1 "Overcurrent 01实际为0x01" 2 "Operating overvoltage 02实际为0x02" 3 "Operating under voltage 03实际为0x03" 4 "AC input overvoltage 04实际为0x04" 5 "AC input under voltage 05实际为0x05" 6 "communication fault 06实际为0x06" 7 "Overcurrent frequency reduction 07实际为0x07" 8 "Over power frequency reduction 08实际为0x08" 9 "Input phase loss 09实际为0x09" 10 "External malfunction 10实际为0x0A" 11 "NTC overheating 11实际为0x0B" 12 "Power on to ground short circuit detection 12实际为0x0C" 13 "motor overload 13实际为0x0D" ;
VAL_ 2337533608 M2P_TMS_R_15_D_fault_24 0 "no fault 00实际为0x00 引号外不能使用字母" 1 "Overcurrent 01实际为0x01" 2 "Operating overvoltage 02实际为0x02" 3 "Operating under voltage 03实际为0x03" 4 "DC output overvoltage 04实际为0x04" 5 "DC output undervoltage 05实际为0x05" 6 "communication fault 06实际为0x06" 7 "Substrate overheating 07实际为0x07" 8 "output overload 08实际为0x08" ;
VAL_ 2337533609 M2P_TMS_R_TEM_25 0 "open" 1 "close" ;
VAL_ 2337533609 M2P_TMS_R_WPS_25 0 "open" 1 "close" ;
VAL_ 2337533609 M2P_TMS_R_15_fan_fault_25 0 "no fault 00实际为0x00 引号外不能使用字母" 1 "Fan 1 overvoltage 01实际为0x01" 2 "Fan 1 under voltage 02实际为0x02" 3 "Fan 1 is stuck in rotatio 03实际为0x03" 4 "Fan 1 overcurren 04实际为0x04" 5 "Fan 1 motor overheating 05实际为0x05" 6 "Fan 1 drive overheating 06实际为0x06" 7 "Fan 2 overvoltage 07实际为0x07" 8 "Fan 2 under voltage 08实际为0x08" 9 "Fan 2 is stuck in rotation 09实际为0x09" 10 "Fan 2 overcurrent 10实际为0x0A" 11 "Fan 2 motor overheating 11实际为0x0B" 12 "Fan 2drive overheating 12实际为0x0C" ;
VAL_ 2337533609 M2P_TMS_R_15_fre_fault_25 0 "no fault 00实际为0x00 引号外不能使用字母" 1 "Overcurrent 01实际为0x01" 2 "Operating overvoltage 02实际为0x02" 3 "Operating under voltage 03实际为0x03" 4 "AC input overvoltage 04实际为0x04" 5 "AC input under voltage 05实际为0x05" 6 "communication fault 06实际为0x06" 7 "Overcurrent frequency reduction 07实际为0x07" 8 "Over power frequency reduction 08实际为0x08" 9 "Input phase loss 09实际为0x09" 10 "External malfunction 10实际为0x0A" 11 "NTC overheating 11实际为0x0B" 12 "Power on to ground short circuit detection 12实际为0x0C" 13 "motor overload 13实际为0x0D" ;
VAL_ 2337533609 M2P_TMS_R_15_D_fault_25 0 "no fault 00实际为0x00 引号外不能使用字母" 1 "Overcurrent 01实际为0x01" 2 "Operating overvoltage 02实际为0x02" 3 "Operating under voltage 03实际为0x03" 4 "DC output overvoltage 04实际为0x04" 5 "DC output undervoltage 05实际为0x05" 6 "communication fault 06实际为0x06" 7 "Substrate overheating 07实际为0x07" 8 "output overload 08实际为0x08" ;
VAL_ 2337533610 M2P_TMS_R_TEM_26 0 "open" 1 "close" ;
VAL_ 2337533610 M2P_TMS_R_WPS_26 0 "open" 1 "close" ;
VAL_ 2337533610 M2P_TMS_R_15_fan_fault_26 0 "no fault 00实际为0x00 引号外不能使用字母" 1 "Fan 1 overvoltage 01实际为0x01" 2 "Fan 1 under voltage 02实际为0x02" 3 "Fan 1 is stuck in rotatio 03实际为0x03" 4 "Fan 1 overcurren 04实际为0x04" 5 "Fan 1 motor overheating 05实际为0x05" 6 "Fan 1 drive overheating 06实际为0x06" 7 "Fan 2 overvoltage 07实际为0x07" 8 "Fan 2 under voltage 08实际为0x08" 9 "Fan 2 is stuck in rotation 09实际为0x09" 10 "Fan 2 overcurrent 10实际为0x0A" 11 "Fan 2 motor overheating 11实际为0x0B" 12 "Fan 2drive overheating 12实际为0x0C" ;
VAL_ 2337533610 M2P_TMS_R_15_fre_fault_26 0 "no fault 00实际为0x00 引号外不能使用字母" 1 "Overcurrent 01实际为0x01" 2 "Operating overvoltage 02实际为0x02" 3 "Operating under voltage 03实际为0x03" 4 "AC input overvoltage 04实际为0x04" 5 "AC input under voltage 05实际为0x05" 6 "communication fault 06实际为0x06" 7 "Overcurrent frequency reduction 07实际为0x07" 8 "Over power frequency reduction 08实际为0x08" 9 "Input phase loss 09实际为0x09" 10 "External malfunction 10实际为0x0A" 11 "NTC overheating 11实际为0x0B" 12 "Power on to ground short circuit detection 12实际为0x0C" 13 "motor overload 13实际为0x0D" ;
VAL_ 2337533610 M2P_TMS_R_15_D_fault_26 0 "no fault 00实际为0x00 引号外不能使用字母" 1 "Overcurrent 01实际为0x01" 2 "Operating overvoltage 02实际为0x02" 3 "Operating under voltage 03实际为0x03" 4 "DC output overvoltage 04实际为0x04" 5 "DC output undervoltage 05实际为0x05" 6 "communication fault 06实际为0x06" 7 "Substrate overheating 07实际为0x07" 8 "output overload 08实际为0x08" ;
VAL_ 2337533611 M2P_TMS_R_TEM_27 0 "open" 1 "close" ;
VAL_ 2337533611 M2P_TMS_R_WPS_27 0 "open" 1 "close" ;
VAL_ 2337533611 M2P_TMS_R_15_fan_fault_27 0 "no fault 00实际为0x00 引号外不能使用字母" 1 "Fan 1 overvoltage 01实际为0x01" 2 "Fan 1 under voltage 02实际为0x02" 3 "Fan 1 is stuck in rotatio 03实际为0x03" 4 "Fan 1 overcurren 04实际为0x04" 5 "Fan 1 motor overheating 05实际为0x05" 6 "Fan 1 drive overheating 06实际为0x06" 7 "Fan 2 overvoltage 07实际为0x07" 8 "Fan 2 under voltage 08实际为0x08" 9 "Fan 2 is stuck in rotation 09实际为0x09" 10 "Fan 2 overcurrent 10实际为0x0A" 11 "Fan 2 motor overheating 11实际为0x0B" 12 "Fan 2drive overheating 12实际为0x0C" ;
VAL_ 2337533611 M2P_TMS_R_15_fre_fault_27 0 "no fault 00实际为0x00 引号外不能使用字母" 1 "Overcurrent 01实际为0x01" 2 "Operating overvoltage 02实际为0x02" 3 "Operating under voltage 03实际为0x03" 4 "AC input overvoltage 04实际为0x04" 5 "AC input under voltage 05实际为0x05" 6 "communication fault 06实际为0x06" 7 "Overcurrent frequency reduction 07实际为0x07" 8 "Over power frequency reduction 08实际为0x08" 9 "Input phase loss 09实际为0x09" 10 "External malfunction 10实际为0x0A" 11 "NTC overheating 11实际为0x0B" 12 "Power on to ground short circuit detection 12实际为0x0C" 13 "motor overload 13实际为0x0D" ;
VAL_ 2337533611 M2P_TMS_R_15_D_fault_27 0 "no fault 00实际为0x00 引号外不能使用字母" 1 "Overcurrent 01实际为0x01" 2 "Operating overvoltage 02实际为0x02" 3 "Operating under voltage 03实际为0x03" 4 "DC output overvoltage 04实际为0x04" 5 "DC output undervoltage 05实际为0x05" 6 "communication fault 06实际为0x06" 7 "Substrate overheating 07实际为0x07" 8 "output overload 08实际为0x08" ;
VAL_ 2337533612 M2P_TMS_R_TEM_28 0 "open" 1 "close" ;
VAL_ 2337533612 M2P_TMS_R_WPS_28 0 "open" 1 "close" ;
VAL_ 2337533612 M2P_TMS_R_15_fan_fault_28 0 "no fault 00实际为0x00 引号外不能使用字母" 1 "Fan 1 overvoltage 01实际为0x01" 2 "Fan 1 under voltage 02实际为0x02" 3 "Fan 1 is stuck in rotatio 03实际为0x03" 4 "Fan 1 overcurren 04实际为0x04" 5 "Fan 1 motor overheating 05实际为0x05" 6 "Fan 1 drive overheating 06实际为0x06" 7 "Fan 2 overvoltage 07实际为0x07" 8 "Fan 2 under voltage 08实际为0x08" 9 "Fan 2 is stuck in rotation 09实际为0x09" 10 "Fan 2 overcurrent 10实际为0x0A" 11 "Fan 2 motor overheating 11实际为0x0B" 12 "Fan 2drive overheating 12实际为0x0C" ;
VAL_ 2337533612 M2P_TMS_R_15_fre_fault_28 0 "no fault 00实际为0x00 引号外不能使用字母" 1 "Overcurrent 01实际为0x01" 2 "Operating overvoltage 02实际为0x02" 3 "Operating under voltage 03实际为0x03" 4 "AC input overvoltage 04实际为0x04" 5 "AC input under voltage 05实际为0x05" 6 "communication fault 06实际为0x06" 7 "Overcurrent frequency reduction 07实际为0x07" 8 "Over power frequency reduction 08实际为0x08" 9 "Input phase loss 09实际为0x09" 10 "External malfunction 10实际为0x0A" 11 "NTC overheating 11实际为0x0B" 12 "Power on to ground short circuit detection 12实际为0x0C" 13 "motor overload 13实际为0x0D" ;
VAL_ 2337533612 M2P_TMS_R_15_D_fault_28 0 "no fault 00实际为0x00 引号外不能使用字母" 1 "Overcurrent 01实际为0x01" 2 "Operating overvoltage 02实际为0x02" 3 "Operating under voltage 03实际为0x03" 4 "DC output overvoltage 04实际为0x04" 5 "DC output undervoltage 05实际为0x05" 6 "communication fault 06实际为0x06" 7 "Substrate overheating 07实际为0x07" 8 "output overload 08实际为0x08" ;
VAL_ 2337533613 M2P_TMS_R_TEM_29 0 "open" 1 "close" ;
VAL_ 2337533613 M2P_TMS_R_WPS_29 0 "open" 1 "close" ;
VAL_ 2337533613 M2P_TMS_R_15_fan_fault_29 0 "no fault 00实际为0x00 引号外不能使用字母" 1 "Fan 1 overvoltage 01实际为0x01" 2 "Fan 1 under voltage 02实际为0x02" 3 "Fan 1 is stuck in rotatio 03实际为0x03" 4 "Fan 1 overcurren 04实际为0x04" 5 "Fan 1 motor overheating 05实际为0x05" 6 "Fan 1 drive overheating 06实际为0x06" 7 "Fan 2 overvoltage 07实际为0x07" 8 "Fan 2 under voltage 08实际为0x08" 9 "Fan 2 is stuck in rotation 09实际为0x09" 10 "Fan 2 overcurrent 10实际为0x0A" 11 "Fan 2 motor overheating 11实际为0x0B" 12 "Fan 2drive overheating 12实际为0x0C" ;
VAL_ 2337533613 M2P_TMS_R_15_fre_fault_29 0 "no fault 00实际为0x00 引号外不能使用字母" 1 "Overcurrent 01实际为0x01" 2 "Operating overvoltage 02实际为0x02" 3 "Operating under voltage 03实际为0x03" 4 "AC input overvoltage 04实际为0x04" 5 "AC input under voltage 05实际为0x05" 6 "communication fault 06实际为0x06" 7 "Overcurrent frequency reduction 07实际为0x07" 8 "Over power frequency reduction 08实际为0x08" 9 "Input phase loss 09实际为0x09" 10 "External malfunction 10实际为0x0A" 11 "NTC overheating 11实际为0x0B" 12 "Power on to ground short circuit detection 12实际为0x0C" 13 "motor overload 13实际为0x0D" ;
VAL_ 2337533613 M2P_TMS_R_15_D_fault_29 0 "no fault 00实际为0x00 引号外不能使用字母" 1 "Overcurrent 01实际为0x01" 2 "Operating overvoltage 02实际为0x02" 3 "Operating under voltage 03实际为0x03" 4 "DC output overvoltage 04实际为0x04" 5 "DC output undervoltage 05实际为0x05" 6 "communication fault 06实际为0x06" 7 "Substrate overheating 07实际为0x07" 8 "output overload 08实际为0x08" ;
VAL_ 2337533614 M2P_TMS_R_TEM_30 0 "open" 1 "close" ;
VAL_ 2337533614 M2P_TMS_R_WPS_30 0 "open" 1 "close" ;
VAL_ 2337533614 M2P_TMS_R_15_fan_fault_30 0 "no fault 00实际为0x00 引号外不能使用字母" 1 "Fan 1 overvoltage 01实际为0x01" 2 "Fan 1 under voltage 02实际为0x02" 3 "Fan 1 is stuck in rotatio 03实际为0x03" 4 "Fan 1 overcurren 04实际为0x04" 5 "Fan 1 motor overheating 05实际为0x05" 6 "Fan 1 drive overheating 06实际为0x06" 7 "Fan 2 overvoltage 07实际为0x07" 8 "Fan 2 under voltage 08实际为0x08" 9 "Fan 2 is stuck in rotation 09实际为0x09" 10 "Fan 2 overcurrent 10实际为0x0A" 11 "Fan 2 motor overheating 11实际为0x0B" 12 "Fan 2drive overheating 12实际为0x0C" ;
VAL_ 2337533614 M2P_TMS_R_15_fre_fault_30 0 "no fault 00实际为0x00 引号外不能使用字母" 1 "Overcurrent 01实际为0x01" 2 "Operating overvoltage 02实际为0x02" 3 "Operating under voltage 03实际为0x03" 4 "AC input overvoltage 04实际为0x04" 5 "AC input under voltage 05实际为0x05" 6 "communication fault 06实际为0x06" 7 "Overcurrent frequency reduction 07实际为0x07" 8 "Over power frequency reduction 08实际为0x08" 9 "Input phase loss 09实际为0x09" 10 "External malfunction 10实际为0x0A" 11 "NTC overheating 11实际为0x0B" 12 "Power on to ground short circuit detection 12实际为0x0C" 13 "motor overload 13实际为0x0D" ;
VAL_ 2337533614 M2P_TMS_R_15_D_fault_30 0 "no fault 00实际为0x00 引号外不能使用字母" 1 "Overcurrent 01实际为0x01" 2 "Operating overvoltage 02实际为0x02" 3 "Operating under voltage 03实际为0x03" 4 "DC output overvoltage 04实际为0x04" 5 "DC output undervoltage 05实际为0x05" 6 "communication fault 06实际为0x06" 7 "Substrate overheating 07实际为0x07" 8 "output overload 08实际为0x08" ;
VAL_ 2337533615 M2P_TMS_R_TEM_31 0 "open" 1 "close" ;
VAL_ 2337533615 M2P_TMS_R_WPS_31 0 "open" 1 "close" ;
VAL_ 2337533615 M2P_TMS_R_15_fan_fault_31 0 "no fault 00实际为0x00 引号外不能使用字母" 1 "Fan 1 overvoltage 01实际为0x01" 2 "Fan 1 under voltage 02实际为0x02" 3 "Fan 1 is stuck in rotatio 03实际为0x03" 4 "Fan 1 overcurren 04实际为0x04" 5 "Fan 1 motor overheating 05实际为0x05" 6 "Fan 1 drive overheating 06实际为0x06" 7 "Fan 2 overvoltage 07实际为0x07" 8 "Fan 2 under voltage 08实际为0x08" 9 "Fan 2 is stuck in rotation 09实际为0x09" 10 "Fan 2 overcurrent 10实际为0x0A" 11 "Fan 2 motor overheating 11实际为0x0B" 12 "Fan 2drive overheating 12实际为0x0C" ;
VAL_ 2337533615 M2P_TMS_R_15_fre_fault_31 0 "no fault 00实际为0x00 引号外不能使用字母" 1 "Overcurrent 01实际为0x01" 2 "Operating overvoltage 02实际为0x02" 3 "Operating under voltage 03实际为0x03" 4 "AC input overvoltage 04实际为0x04" 5 "AC input under voltage 05实际为0x05" 6 "communication fault 06实际为0x06" 7 "Overcurrent frequency reduction 07实际为0x07" 8 "Over power frequency reduction 08实际为0x08" 9 "Input phase loss 09实际为0x09" 10 "External malfunction 10实际为0x0A" 11 "NTC overheating 11实际为0x0B" 12 "Power on to ground short circuit detection 12实际为0x0C" 13 "motor overload 13实际为0x0D" ;
VAL_ 2337533615 M2P_TMS_R_15_D_fault_31 0 "no fault 00实际为0x00 引号外不能使用字母" 1 "Overcurrent 01实际为0x01" 2 "Operating overvoltage 02实际为0x02" 3 "Operating under voltage 03实际为0x03" 4 "DC output overvoltage 04实际为0x04" 5 "DC output undervoltage 05实际为0x05" 6 "communication fault 06实际为0x06" 7 "Substrate overheating 07实际为0x07" 8 "output overload 08实际为0x08" ;
VAL_ 2337599121 M2P_TMS_R_25_fan_fault_01 0 "no fault 00实际为0x00 引号外不能使用字母" 1 "Fan 3 overvoltage 01实际为0x01" 2 "Fan 3 under voltage 02实际为0x02" 3 "Fan 3 is stuck in rotation 03实际为0x03" 4 "Fan 3 overcurrent 04实际为0x04" 5 "Fan 3 motor overheating 05实际为0x05" 6 "Fan 3 drive overheating 06实际为0x06" 7 "Fan 4 overvoltage 07实际为0x07" 8 "Fan 4 under voltage 08实际为0x08" 9 "Fan 4 is stuck in rotation 09实际为0x09" 10 "Fan 4 overcurrent 10实际为0x0A" 11 "Fan 4 motor overheating 11实际为0x0B" 12 "Fan 4 drive overheating 12实际为0x0C" 13 "Fan 5 overvoltage 13实际为0x0D" 14 "Fan 5 under voltage 14实际为0x0E" 15 "Fan 5 is stuck in rotation 15实际为0x0F" 16 "Fan 5 overcurrent 10实际为0x10" 17 "Fan 5 motor overheating 17实际为0x11" 18 "Fan 5 drive overheating 18实际为0x12" 19 "Fan 6 overvoltage 19实际为0x13" 20 "Fan 6 under voltage 20实际为0x14" 21 "Fan 6 is stuck in rotation 21实际为0x15" 22 "Fan 6 overcurrent 22实际为0x16" 23 "Fan 6 motor overheating 23实际为0x17" 24 "Fan 6 drive overheating 24实际为0x18" ;
VAL_ 2337599121 M2P_TMS_R_25_fre_fault_01 0 "no fault 00实际为0x00 引号外不能使用字母" 1 "Overcurrent 01实际为0x01" 2 "Operating overvoltage 02实际为0x02" 3 "Operating under voltage 03实际为0x03" 4 "AC input overvoltage 04实际为0x04" 5 "AC input under voltage05实际为0x05" 6 "communication fault 06实际为0x06" 7 "Overcurrent frequency reduction 07实际为0x07" 8 "Over power frequency reduction 08实际为0x08" 9 "Input phase loss 09实际为0x09" 10 "External malfunction 10实际为0x0A" 11 "NTC overheating 11实际为0x0B" 12 "Power on to ground short circuit detection 12实际为0x0C" 13 "motor overload 13实际为0x0D" ;
VAL_ 2337599121 M2P_TMS_R_25_D_fault_01 0 "no fault 00实际为0x00 引号外不能使用字母" 1 "Overcurrent 01实际为0x01" 2 "Operating overvoltage 02实际为0x02" 3 "Operating under voltage 03实际为0x03" 4 "DC output overvoltage 04实际为0x04" 5 "DC output undervoltage 05实际为0x05" 6 "communication fault 06实际为0x06" 7 "Substrate overheating 07实际为0x07" 8 "output overload 08实际为0x08" ;
VAL_ 2337599122 M2P_TMS_R_25_fan_fault_02 0 "no fault 00实际为0x00 引号外不能使用字母" 1 "Fan 3 overvoltage 01实际为0x01" 2 "Fan 3 under voltage 02实际为0x02" 3 "Fan 3 is stuck in rotation 03实际为0x03" 4 "Fan 3 overcurrent 04实际为0x04" 5 "Fan 3 motor overheating 05实际为0x05" 6 "Fan 3 drive overheating 06实际为0x06" 7 "Fan 4 overvoltage 07实际为0x07" 8 "Fan 4 under voltage 08实际为0x08" 9 "Fan 4 is stuck in rotation 09实际为0x09" 10 "Fan 4 overcurrent 10实际为0x0A" 11 "Fan 4 motor overheating 11实际为0x0B" 12 "Fan 4 drive overheating 12实际为0x0C" 13 "Fan 5 overvoltage 13实际为0x0D" 14 "Fan 5 under voltage 14实际为0x0E" 15 "Fan 5 is stuck in rotation 15实际为0x0F" 16 "Fan 5 overcurrent 10实际为0x10" 17 "Fan 5 motor overheating 17实际为0x11" 18 "Fan 5 drive overheating 18实际为0x12" 19 "Fan 6 overvoltage 19实际为0x13" 20 "Fan 6 under voltage 20实际为0x14" 21 "Fan 6 is stuck in rotation 21实际为0x15" 22 "Fan 6 overcurrent 22实际为0x16" 23 "Fan 6 motor overheating 23实际为0x17" 24 "Fan 6 drive overheating 24实际为0x18" ;
VAL_ 2337599122 M2P_TMS_R_25_fre_fault_02 0 "no fault 00实际为0x00 引号外不能使用字母" 1 "Overcurrent 01实际为0x01" 2 "Operating overvoltage 02实际为0x02" 3 "Operating under voltage 03实际为0x03" 4 "AC input overvoltage 04实际为0x04" 5 "AC input under voltage05实际为0x05" 6 "communication fault 06实际为0x06" 7 "Overcurrent frequency reduction 07实际为0x07" 8 "Over power frequency reduction 08实际为0x08" 9 "Input phase loss 09实际为0x09" 10 "External malfunction 10实际为0x0A" 11 "NTC overheating 11实际为0x0B" 12 "Power on to ground short circuit detection 12实际为0x0C" 13 "motor overload 13实际为0x0D" ;
VAL_ 2337599122 M2P_TMS_R_25_D_fault_02 0 "no fault 00实际为0x00 引号外不能使用字母" 1 "Overcurrent 01实际为0x01" 2 "Operating overvoltage 02实际为0x02" 3 "Operating under voltage 03实际为0x03" 4 "DC output overvoltage 04实际为0x04" 5 "DC output undervoltage 05实际为0x05" 6 "communication fault 06实际为0x06" 7 "Substrate overheating 07实际为0x07" 8 "output overload 08实际为0x08" ;
VAL_ 2337599123 M2P_TMS_R_25_fan_fault_03 0 "no fault 00实际为0x00 引号外不能使用字母" 1 "Fan 3 overvoltage 01实际为0x01" 2 "Fan 3 under voltage 02实际为0x02" 3 "Fan 3 is stuck in rotation 03实际为0x03" 4 "Fan 3 overcurrent 04实际为0x04" 5 "Fan 3 motor overheating 05实际为0x05" 6 "Fan 3 drive overheating 06实际为0x06" 7 "Fan 4 overvoltage 07实际为0x07" 8 "Fan 4 under voltage 08实际为0x08" 9 "Fan 4 is stuck in rotation 09实际为0x09" 10 "Fan 4 overcurrent 10实际为0x0A" 11 "Fan 4 motor overheating 11实际为0x0B" 12 "Fan 4 drive overheating 12实际为0x0C" 13 "Fan 5 overvoltage 13实际为0x0D" 14 "Fan 5 under voltage 14实际为0x0E" 15 "Fan 5 is stuck in rotation 15实际为0x0F" 16 "Fan 5 overcurrent 10实际为0x10" 17 "Fan 5 motor overheating 17实际为0x11" 18 "Fan 5 drive overheating 18实际为0x12" 19 "Fan 6 overvoltage 19实际为0x13" 20 "Fan 6 under voltage 20实际为0x14" 21 "Fan 6 is stuck in rotation 21实际为0x15" 22 "Fan 6 overcurrent 22实际为0x16" 23 "Fan 6 motor overheating 23实际为0x17" 24 "Fan 6 drive overheating 24实际为0x18" ;
VAL_ 2337599123 M2P_TMS_R_25_fre_fault_03 0 "no fault 00实际为0x00 引号外不能使用字母" 1 "Overcurrent 01实际为0x01" 2 "Operating overvoltage 02实际为0x02" 3 "Operating under voltage 03实际为0x03" 4 "AC input overvoltage 04实际为0x04" 5 "AC input under voltage05实际为0x05" 6 "communication fault 06实际为0x06" 7 "Overcurrent frequency reduction 07实际为0x07" 8 "Over power frequency reduction 08实际为0x08" 9 "Input phase loss 09实际为0x09" 10 "External malfunction 10实际为0x0A" 11 "NTC overheating 11实际为0x0B" 12 "Power on to ground short circuit detection 12实际为0x0C" 13 "motor overload 13实际为0x0D" ;
VAL_ 2337599123 M2P_TMS_R_25_D_fault_03 0 "no fault 00实际为0x00 引号外不能使用字母" 1 "Overcurrent 01实际为0x01" 2 "Operating overvoltage 02实际为0x02" 3 "Operating under voltage 03实际为0x03" 4 "DC output overvoltage 04实际为0x04" 5 "DC output undervoltage 05实际为0x05" 6 "communication fault 06实际为0x06" 7 "Substrate overheating 07实际为0x07" 8 "output overload 08实际为0x08" ;
VAL_ 2337599124 M2P_TMS_R_25_fan_fault_04 0 "no fault 00实际为0x00 引号外不能使用字母" 1 "Fan 3 overvoltage 01实际为0x01" 2 "Fan 3 under voltage 02实际为0x02" 3 "Fan 3 is stuck in rotation 03实际为0x03" 4 "Fan 3 overcurrent 04实际为0x04" 5 "Fan 3 motor overheating 05实际为0x05" 6 "Fan 3 drive overheating 06实际为0x06" 7 "Fan 4 overvoltage 07实际为0x07" 8 "Fan 4 under voltage 08实际为0x08" 9 "Fan 4 is stuck in rotation 09实际为0x09" 10 "Fan 4 overcurrent 10实际为0x0A" 11 "Fan 4 motor overheating 11实际为0x0B" 12 "Fan 4 drive overheating 12实际为0x0C" 13 "Fan 5 overvoltage 13实际为0x0D" 14 "Fan 5 under voltage 14实际为0x0E" 15 "Fan 5 is stuck in rotation 15实际为0x0F" 16 "Fan 5 overcurrent 10实际为0x10" 17 "Fan 5 motor overheating 17实际为0x11" 18 "Fan 5 drive overheating 18实际为0x12" 19 "Fan 6 overvoltage 19实际为0x13" 20 "Fan 6 under voltage 20实际为0x14" 21 "Fan 6 is stuck in rotation 21实际为0x15" 22 "Fan 6 overcurrent 22实际为0x16" 23 "Fan 6 motor overheating 23实际为0x17" 24 "Fan 6 drive overheating 24实际为0x18" ;
VAL_ 2337599124 M2P_TMS_R_25_fre_fault_04 0 "no fault 00实际为0x00 引号外不能使用字母" 1 "Overcurrent 01实际为0x01" 2 "Operating overvoltage 02实际为0x02" 3 "Operating under voltage 03实际为0x03" 4 "AC input overvoltage 04实际为0x04" 5 "AC input under voltage05实际为0x05" 6 "communication fault 06实际为0x06" 7 "Overcurrent frequency reduction 07实际为0x07" 8 "Over power frequency reduction 08实际为0x08" 9 "Input phase loss 09实际为0x09" 10 "External malfunction 10实际为0x0A" 11 "NTC overheating 11实际为0x0B" 12 "Power on to ground short circuit detection 12实际为0x0C" 13 "motor overload 13实际为0x0D" ;
VAL_ 2337599124 M2P_TMS_R_25_D_fault_04 0 "no fault 00实际为0x00 引号外不能使用字母" 1 "Overcurrent 01实际为0x01" 2 "Operating overvoltage 02实际为0x02" 3 "Operating under voltage 03实际为0x03" 4 "DC output overvoltage 04实际为0x04" 5 "DC output undervoltage 05实际为0x05" 6 "communication fault 06实际为0x06" 7 "Substrate overheating 07实际为0x07" 8 "output overload 08实际为0x08" ;
VAL_ 2337599125 M2P_TMS_R_25_fan_fault_05 0 "no fault 00实际为0x00 引号外不能使用字母" 1 "Fan 3 overvoltage 01实际为0x01" 2 "Fan 3 under voltage 02实际为0x02" 3 "Fan 3 is stuck in rotation 03实际为0x03" 4 "Fan 3 overcurrent 04实际为0x04" 5 "Fan 3 motor overheating 05实际为0x05" 6 "Fan 3 drive overheating 06实际为0x06" 7 "Fan 4 overvoltage 07实际为0x07" 8 "Fan 4 under voltage 08实际为0x08" 9 "Fan 4 is stuck in rotation 09实际为0x09" 10 "Fan 4 overcurrent 10实际为0x0A" 11 "Fan 4 motor overheating 11实际为0x0B" 12 "Fan 4 drive overheating 12实际为0x0C" 13 "Fan 5 overvoltage 13实际为0x0D" 14 "Fan 5 under voltage 14实际为0x0E" 15 "Fan 5 is stuck in rotation 15实际为0x0F" 16 "Fan 5 overcurrent 10实际为0x10" 17 "Fan 5 motor overheating 17实际为0x11" 18 "Fan 5 drive overheating 18实际为0x12" 19 "Fan 6 overvoltage 19实际为0x13" 20 "Fan 6 under voltage 20实际为0x14" 21 "Fan 6 is stuck in rotation 21实际为0x15" 22 "Fan 6 overcurrent 22实际为0x16" 23 "Fan 6 motor overheating 23实际为0x17" 24 "Fan 6 drive overheating 24实际为0x18" ;
VAL_ 2337599125 M2P_TMS_R_25_fre_fault_05 0 "no fault 00实际为0x00 引号外不能使用字母" 1 "Overcurrent 01实际为0x01" 2 "Operating overvoltage 02实际为0x02" 3 "Operating under voltage 03实际为0x03" 4 "AC input overvoltage 04实际为0x04" 5 "AC input under voltage05实际为0x05" 6 "communication fault 06实际为0x06" 7 "Overcurrent frequency reduction 07实际为0x07" 8 "Over power frequency reduction 08实际为0x08" 9 "Input phase loss 09实际为0x09" 10 "External malfunction 10实际为0x0A" 11 "NTC overheating 11实际为0x0B" 12 "Power on to ground short circuit detection 12实际为0x0C" 13 "motor overload 13实际为0x0D" ;
VAL_ 2337599125 M2P_TMS_R_25_D_fault_05 0 "no fault 00实际为0x00 引号外不能使用字母" 1 "Overcurrent 01实际为0x01" 2 "Operating overvoltage 02实际为0x02" 3 "Operating under voltage 03实际为0x03" 4 "DC output overvoltage 04实际为0x04" 5 "DC output undervoltage 05实际为0x05" 6 "communication fault 06实际为0x06" 7 "Substrate overheating 07实际为0x07" 8 "output overload 08实际为0x08" ;
VAL_ 2337599126 M2P_TMS_R_25_fan_fault_06 0 "no fault 00实际为0x00 引号外不能使用字母" 1 "Fan 3 overvoltage 01实际为0x01" 2 "Fan 3 under voltage 02实际为0x02" 3 "Fan 3 is stuck in rotation 03实际为0x03" 4 "Fan 3 overcurrent 04实际为0x04" 5 "Fan 3 motor overheating 05实际为0x05" 6 "Fan 3 drive overheating 06实际为0x06" 7 "Fan 4 overvoltage 07实际为0x07" 8 "Fan 4 under voltage 08实际为0x08" 9 "Fan 4 is stuck in rotation 09实际为0x09" 10 "Fan 4 overcurrent 10实际为0x0A" 11 "Fan 4 motor overheating 11实际为0x0B" 12 "Fan 4 drive overheating 12实际为0x0C" 13 "Fan 5 overvoltage 13实际为0x0D" 14 "Fan 5 under voltage 14实际为0x0E" 15 "Fan 5 is stuck in rotation 15实际为0x0F" 16 "Fan 5 overcurrent 10实际为0x10" 17 "Fan 5 motor overheating 17实际为0x11" 18 "Fan 5 drive overheating 18实际为0x12" 19 "Fan 6 overvoltage 19实际为0x13" 20 "Fan 6 under voltage 20实际为0x14" 21 "Fan 6 is stuck in rotation 21实际为0x15" 22 "Fan 6 overcurrent 22实际为0x16" 23 "Fan 6 motor overheating 23实际为0x17" 24 "Fan 6 drive overheating 24实际为0x18" ;
VAL_ 2337599126 M2P_TMS_R_25_fre_fault_06 0 "no fault 00实际为0x00 引号外不能使用字母" 1 "Overcurrent 01实际为0x01" 2 "Operating overvoltage 02实际为0x02" 3 "Operating under voltage 03实际为0x03" 4 "AC input overvoltage 04实际为0x04" 5 "AC input under voltage05实际为0x05" 6 "communication fault 06实际为0x06" 7 "Overcurrent frequency reduction 07实际为0x07" 8 "Over power frequency reduction 08实际为0x08" 9 "Input phase loss 09实际为0x09" 10 "External malfunction 10实际为0x0A" 11 "NTC overheating 11实际为0x0B" 12 "Power on to ground short circuit detection 12实际为0x0C" 13 "motor overload 13实际为0x0D" ;
VAL_ 2337599126 M2P_TMS_R_25_D_fault_06 0 "no fault 00实际为0x00 引号外不能使用字母" 1 "Overcurrent 01实际为0x01" 2 "Operating overvoltage 02实际为0x02" 3 "Operating under voltage 03实际为0x03" 4 "DC output overvoltage 04实际为0x04" 5 "DC output undervoltage 05实际为0x05" 6 "communication fault 06实际为0x06" 7 "Substrate overheating 07实际为0x07" 8 "output overload 08实际为0x08" ;
VAL_ 2337599127 M2P_TMS_R_25_fan_fault_07 0 "no fault 00实际为0x00 引号外不能使用字母" 1 "Fan 3 overvoltage 01实际为0x01" 2 "Fan 3 under voltage 02实际为0x02" 3 "Fan 3 is stuck in rotation 03实际为0x03" 4 "Fan 3 overcurrent 04实际为0x04" 5 "Fan 3 motor overheating 05实际为0x05" 6 "Fan 3 drive overheating 06实际为0x06" 7 "Fan 4 overvoltage 07实际为0x07" 8 "Fan 4 under voltage 08实际为0x08" 9 "Fan 4 is stuck in rotation 09实际为0x09" 10 "Fan 4 overcurrent 10实际为0x0A" 11 "Fan 4 motor overheating 11实际为0x0B" 12 "Fan 4 drive overheating 12实际为0x0C" 13 "Fan 5 overvoltage 13实际为0x0D" 14 "Fan 5 under voltage 14实际为0x0E" 15 "Fan 5 is stuck in rotation 15实际为0x0F" 16 "Fan 5 overcurrent 10实际为0x10" 17 "Fan 5 motor overheating 17实际为0x11" 18 "Fan 5 drive overheating 18实际为0x12" 19 "Fan 6 overvoltage 19实际为0x13" 20 "Fan 6 under voltage 20实际为0x14" 21 "Fan 6 is stuck in rotation 21实际为0x15" 22 "Fan 6 overcurrent 22实际为0x16" 23 "Fan 6 motor overheating 23实际为0x17" 24 "Fan 6 drive overheating 24实际为0x18" ;
VAL_ 2337599127 M2P_TMS_R_25_fre_fault_07 0 "no fault 00实际为0x00 引号外不能使用字母" 1 "Overcurrent 01实际为0x01" 2 "Operating overvoltage 02实际为0x02" 3 "Operating under voltage 03实际为0x03" 4 "AC input overvoltage 04实际为0x04" 5 "AC input under voltage05实际为0x05" 6 "communication fault 06实际为0x06" 7 "Overcurrent frequency reduction 07实际为0x07" 8 "Over power frequency reduction 08实际为0x08" 9 "Input phase loss 09实际为0x09" 10 "External malfunction 10实际为0x0A" 11 "NTC overheating 11实际为0x0B" 12 "Power on to ground short circuit detection 12实际为0x0C" 13 "motor overload 13实际为0x0D" ;
VAL_ 2337599127 M2P_TMS_R_25_D_fault_07 0 "no fault 00实际为0x00 引号外不能使用字母" 1 "Overcurrent 01实际为0x01" 2 "Operating overvoltage 02实际为0x02" 3 "Operating under voltage 03实际为0x03" 4 "DC output overvoltage 04实际为0x04" 5 "DC output undervoltage 05实际为0x05" 6 "communication fault 06实际为0x06" 7 "Substrate overheating 07实际为0x07" 8 "output overload 08实际为0x08" ;
VAL_ 2337599128 M2P_TMS_R_25_fan_fault_08 0 "no fault 00实际为0x00 引号外不能使用字母" 1 "Fan 3 overvoltage 01实际为0x01" 2 "Fan 3 under voltage 02实际为0x02" 3 "Fan 3 is stuck in rotation 03实际为0x03" 4 "Fan 3 overcurrent 04实际为0x04" 5 "Fan 3 motor overheating 05实际为0x05" 6 "Fan 3 drive overheating 06实际为0x06" 7 "Fan 4 overvoltage 07实际为0x07" 8 "Fan 4 under voltage 08实际为0x08" 9 "Fan 4 is stuck in rotation 09实际为0x09" 10 "Fan 4 overcurrent 10实际为0x0A" 11 "Fan 4 motor overheating 11实际为0x0B" 12 "Fan 4 drive overheating 12实际为0x0C" 13 "Fan 5 overvoltage 13实际为0x0D" 14 "Fan 5 under voltage 14实际为0x0E" 15 "Fan 5 is stuck in rotation 15实际为0x0F" 16 "Fan 5 overcurrent 10实际为0x10" 17 "Fan 5 motor overheating 17实际为0x11" 18 "Fan 5 drive overheating 18实际为0x12" 19 "Fan 6 overvoltage 19实际为0x13" 20 "Fan 6 under voltage 20实际为0x14" 21 "Fan 6 is stuck in rotation 21实际为0x15" 22 "Fan 6 overcurrent 22实际为0x16" 23 "Fan 6 motor overheating 23实际为0x17" 24 "Fan 6 drive overheating 24实际为0x18" ;
VAL_ 2337599128 M2P_TMS_R_25_fre_fault_08 0 "no fault 00实际为0x00 引号外不能使用字母" 1 "Overcurrent 01实际为0x01" 2 "Operating overvoltage 02实际为0x02" 3 "Operating under voltage 03实际为0x03" 4 "AC input overvoltage 04实际为0x04" 5 "AC input under voltage05实际为0x05" 6 "communication fault 06实际为0x06" 7 "Overcurrent frequency reduction 07实际为0x07" 8 "Over power frequency reduction 08实际为0x08" 9 "Input phase loss 09实际为0x09" 10 "External malfunction 10实际为0x0A" 11 "NTC overheating 11实际为0x0B" 12 "Power on to ground short circuit detection 12实际为0x0C" 13 "motor overload 13实际为0x0D" ;
VAL_ 2337599128 M2P_TMS_R_25_D_fault_08 0 "no fault 00实际为0x00 引号外不能使用字母" 1 "Overcurrent 01实际为0x01" 2 "Operating overvoltage 02实际为0x02" 3 "Operating under voltage 03实际为0x03" 4 "DC output overvoltage 04实际为0x04" 5 "DC output undervoltage 05实际为0x05" 6 "communication fault 06实际为0x06" 7 "Substrate overheating 07实际为0x07" 8 "output overload 08实际为0x08" ;
VAL_ 2337599129 M2P_TMS_R_25_fan_fault_09 0 "no fault 00实际为0x00 引号外不能使用字母" 1 "Fan 3 overvoltage 01实际为0x01" 2 "Fan 3 under voltage 02实际为0x02" 3 "Fan 3 is stuck in rotation 03实际为0x03" 4 "Fan 3 overcurrent 04实际为0x04" 5 "Fan 3 motor overheating 05实际为0x05" 6 "Fan 3 drive overheating 06实际为0x06" 7 "Fan 4 overvoltage 07实际为0x07" 8 "Fan 4 under voltage 08实际为0x08" 9 "Fan 4 is stuck in rotation 09实际为0x09" 10 "Fan 4 overcurrent 10实际为0x0A" 11 "Fan 4 motor overheating 11实际为0x0B" 12 "Fan 4 drive overheating 12实际为0x0C" 13 "Fan 5 overvoltage 13实际为0x0D" 14 "Fan 5 under voltage 14实际为0x0E" 15 "Fan 5 is stuck in rotation 15实际为0x0F" 16 "Fan 5 overcurrent 10实际为0x10" 17 "Fan 5 motor overheating 17实际为0x11" 18 "Fan 5 drive overheating 18实际为0x12" 19 "Fan 6 overvoltage 19实际为0x13" 20 "Fan 6 under voltage 20实际为0x14" 21 "Fan 6 is stuck in rotation 21实际为0x15" 22 "Fan 6 overcurrent 22实际为0x16" 23 "Fan 6 motor overheating 23实际为0x17" 24 "Fan 6 drive overheating 24实际为0x18" ;
VAL_ 2337599129 M2P_TMS_R_25_fre_fault_09 0 "no fault 00实际为0x00 引号外不能使用字母" 1 "Overcurrent 01实际为0x01" 2 "Operating overvoltage 02实际为0x02" 3 "Operating under voltage 03实际为0x03" 4 "AC input overvoltage 04实际为0x04" 5 "AC input under voltage05实际为0x05" 6 "communication fault 06实际为0x06" 7 "Overcurrent frequency reduction 07实际为0x07" 8 "Over power frequency reduction 08实际为0x08" 9 "Input phase loss 09实际为0x09" 10 "External malfunction 10实际为0x0A" 11 "NTC overheating 11实际为0x0B" 12 "Power on to ground short circuit detection 12实际为0x0C" 13 "motor overload 13实际为0x0D" ;
VAL_ 2337599129 M2P_TMS_R_25_D_fault_09 0 "no fault 00实际为0x00 引号外不能使用字母" 1 "Overcurrent 01实际为0x01" 2 "Operating overvoltage 02实际为0x02" 3 "Operating under voltage 03实际为0x03" 4 "DC output overvoltage 04实际为0x04" 5 "DC output undervoltage 05实际为0x05" 6 "communication fault 06实际为0x06" 7 "Substrate overheating 07实际为0x07" 8 "output overload 08实际为0x08" ;
VAL_ 2337599130 M2P_TMS_R_25_fan_fault_10 0 "no fault 00实际为0x00 引号外不能使用字母" 1 "Fan 3 overvoltage 01实际为0x01" 2 "Fan 3 under voltage 02实际为0x02" 3 "Fan 3 is stuck in rotation 03实际为0x03" 4 "Fan 3 overcurrent 04实际为0x04" 5 "Fan 3 motor overheating 05实际为0x05" 6 "Fan 3 drive overheating 06实际为0x06" 7 "Fan 4 overvoltage 07实际为0x07" 8 "Fan 4 under voltage 08实际为0x08" 9 "Fan 4 is stuck in rotation 09实际为0x09" 10 "Fan 4 overcurrent 10实际为0x0A" 11 "Fan 4 motor overheating 11实际为0x0B" 12 "Fan 4 drive overheating 12实际为0x0C" 13 "Fan 5 overvoltage 13实际为0x0D" 14 "Fan 5 under voltage 14实际为0x0E" 15 "Fan 5 is stuck in rotation 15实际为0x0F" 16 "Fan 5 overcurrent 10实际为0x10" 17 "Fan 5 motor overheating 17实际为0x11" 18 "Fan 5 drive overheating 18实际为0x12" 19 "Fan 6 overvoltage 19实际为0x13" 20 "Fan 6 under voltage 20实际为0x14" 21 "Fan 6 is stuck in rotation 21实际为0x15" 22 "Fan 6 overcurrent 22实际为0x16" 23 "Fan 6 motor overheating 23实际为0x17" 24 "Fan 6 drive overheating 24实际为0x18" ;
VAL_ 2337599130 M2P_TMS_R_25_fre_fault_10 0 "no fault 00实际为0x00 引号外不能使用字母" 1 "Overcurrent 01实际为0x01" 2 "Operating overvoltage 02实际为0x02" 3 "Operating under voltage 03实际为0x03" 4 "AC input overvoltage 04实际为0x04" 5 "AC input under voltage05实际为0x05" 6 "communication fault 06实际为0x06" 7 "Overcurrent frequency reduction 07实际为0x07" 8 "Over power frequency reduction 08实际为0x08" 9 "Input phase loss 09实际为0x09" 10 "External malfunction 10实际为0x0A" 11 "NTC overheating 11实际为0x0B" 12 "Power on to ground short circuit detection 12实际为0x0C" 13 "motor overload 13实际为0x0D" ;
VAL_ 2337599130 M2P_TMS_R_25_D_fault_10 0 "no fault 00实际为0x00 引号外不能使用字母" 1 "Overcurrent 01实际为0x01" 2 "Operating overvoltage 02实际为0x02" 3 "Operating under voltage 03实际为0x03" 4 "DC output overvoltage 04实际为0x04" 5 "DC output undervoltage 05实际为0x05" 6 "communication fault 06实际为0x06" 7 "Substrate overheating 07实际为0x07" 8 "output overload 08实际为0x08" ;
VAL_ 2337599131 M2P_TMS_R_25_fan_fault_11 0 "no fault 00实际为0x00 引号外不能使用字母" 1 "Fan 3 overvoltage 01实际为0x01" 2 "Fan 3 under voltage 02实际为0x02" 3 "Fan 3 is stuck in rotation 03实际为0x03" 4 "Fan 3 overcurrent 04实际为0x04" 5 "Fan 3 motor overheating 05实际为0x05" 6 "Fan 3 drive overheating 06实际为0x06" 7 "Fan 4 overvoltage 07实际为0x07" 8 "Fan 4 under voltage 08实际为0x08" 9 "Fan 4 is stuck in rotation 09实际为0x09" 10 "Fan 4 overcurrent 10实际为0x0A" 11 "Fan 4 motor overheating 11实际为0x0B" 12 "Fan 4 drive overheating 12实际为0x0C" 13 "Fan 5 overvoltage 13实际为0x0D" 14 "Fan 5 under voltage 14实际为0x0E" 15 "Fan 5 is stuck in rotation 15实际为0x0F" 16 "Fan 5 overcurrent 10实际为0x10" 17 "Fan 5 motor overheating 17实际为0x11" 18 "Fan 5 drive overheating 18实际为0x12" 19 "Fan 6 overvoltage 19实际为0x13" 20 "Fan 6 under voltage 20实际为0x14" 21 "Fan 6 is stuck in rotation 21实际为0x15" 22 "Fan 6 overcurrent 22实际为0x16" 23 "Fan 6 motor overheating 23实际为0x17" 24 "Fan 6 drive overheating 24实际为0x18" ;
VAL_ 2337599131 M2P_TMS_R_25_fre_fault_11 0 "no fault 00实际为0x00 引号外不能使用字母" 1 "Overcurrent 01实际为0x01" 2 "Operating overvoltage 02实际为0x02" 3 "Operating under voltage 03实际为0x03" 4 "AC input overvoltage 04实际为0x04" 5 "AC input under voltage05实际为0x05" 6 "communication fault 06实际为0x06" 7 "Overcurrent frequency reduction 07实际为0x07" 8 "Over power frequency reduction 08实际为0x08" 9 "Input phase loss 09实际为0x09" 10 "External malfunction 10实际为0x0A" 11 "NTC overheating 11实际为0x0B" 12 "Power on to ground short circuit detection 12实际为0x0C" 13 "motor overload 13实际为0x0D" ;
VAL_ 2337599131 M2P_TMS_R_25_D_fault_11 0 "no fault 00实际为0x00 引号外不能使用字母" 1 "Overcurrent 01实际为0x01" 2 "Operating overvoltage 02实际为0x02" 3 "Operating under voltage 03实际为0x03" 4 "DC output overvoltage 04实际为0x04" 5 "DC output undervoltage 05实际为0x05" 6 "communication fault 06实际为0x06" 7 "Substrate overheating 07实际为0x07" 8 "output overload 08实际为0x08" ;
VAL_ 2337599132 M2P_TMS_R_25_fan_fault_12 0 "no fault 00实际为0x00 引号外不能使用字母" 1 "Fan 3 overvoltage 01实际为0x01" 2 "Fan 3 under voltage 02实际为0x02" 3 "Fan 3 is stuck in rotation 03实际为0x03" 4 "Fan 3 overcurrent 04实际为0x04" 5 "Fan 3 motor overheating 05实际为0x05" 6 "Fan 3 drive overheating 06实际为0x06" 7 "Fan 4 overvoltage 07实际为0x07" 8 "Fan 4 under voltage 08实际为0x08" 9 "Fan 4 is stuck in rotation 09实际为0x09" 10 "Fan 4 overcurrent 10实际为0x0A" 11 "Fan 4 motor overheating 11实际为0x0B" 12 "Fan 4 drive overheating 12实际为0x0C" 13 "Fan 5 overvoltage 13实际为0x0D" 14 "Fan 5 under voltage 14实际为0x0E" 15 "Fan 5 is stuck in rotation 15实际为0x0F" 16 "Fan 5 overcurrent 10实际为0x10" 17 "Fan 5 motor overheating 17实际为0x11" 18 "Fan 5 drive overheating 18实际为0x12" 19 "Fan 6 overvoltage 19实际为0x13" 20 "Fan 6 under voltage 20实际为0x14" 21 "Fan 6 is stuck in rotation 21实际为0x15" 22 "Fan 6 overcurrent 22实际为0x16" 23 "Fan 6 motor overheating 23实际为0x17" 24 "Fan 6 drive overheating 24实际为0x18" ;
VAL_ 2337599132 M2P_TMS_R_25_fre_fault_12 0 "no fault 00实际为0x00 引号外不能使用字母" 1 "Overcurrent 01实际为0x01" 2 "Operating overvoltage 02实际为0x02" 3 "Operating under voltage 03实际为0x03" 4 "AC input overvoltage 04实际为0x04" 5 "AC input under voltage05实际为0x05" 6 "communication fault 06实际为0x06" 7 "Overcurrent frequency reduction 07实际为0x07" 8 "Over power frequency reduction 08实际为0x08" 9 "Input phase loss 09实际为0x09" 10 "External malfunction 10实际为0x0A" 11 "NTC overheating 11实际为0x0B" 12 "Power on to ground short circuit detection 12实际为0x0C" 13 "motor overload 13实际为0x0D" ;
VAL_ 2337599132 M2P_TMS_R_25_D_fault_12 0 "no fault 00实际为0x00 引号外不能使用字母" 1 "Overcurrent 01实际为0x01" 2 "Operating overvoltage 02实际为0x02" 3 "Operating under voltage 03实际为0x03" 4 "DC output overvoltage 04实际为0x04" 5 "DC output undervoltage 05实际为0x05" 6 "communication fault 06实际为0x06" 7 "Substrate overheating 07实际为0x07" 8 "output overload 08实际为0x08" ;
VAL_ 2337599133 M2P_TMS_R_25_fan_fault_13 0 "no fault 00实际为0x00 引号外不能使用字母" 1 "Fan 3 overvoltage 01实际为0x01" 2 "Fan 3 under voltage 02实际为0x02" 3 "Fan 3 is stuck in rotation 03实际为0x03" 4 "Fan 3 overcurrent 04实际为0x04" 5 "Fan 3 motor overheating 05实际为0x05" 6 "Fan 3 drive overheating 06实际为0x06" 7 "Fan 4 overvoltage 07实际为0x07" 8 "Fan 4 under voltage 08实际为0x08" 9 "Fan 4 is stuck in rotation 09实际为0x09" 10 "Fan 4 overcurrent 10实际为0x0A" 11 "Fan 4 motor overheating 11实际为0x0B" 12 "Fan 4 drive overheating 12实际为0x0C" 13 "Fan 5 overvoltage 13实际为0x0D" 14 "Fan 5 under voltage 14实际为0x0E" 15 "Fan 5 is stuck in rotation 15实际为0x0F" 16 "Fan 5 overcurrent 10实际为0x10" 17 "Fan 5 motor overheating 17实际为0x11" 18 "Fan 5 drive overheating 18实际为0x12" 19 "Fan 6 overvoltage 19实际为0x13" 20 "Fan 6 under voltage 20实际为0x14" 21 "Fan 6 is stuck in rotation 21实际为0x15" 22 "Fan 6 overcurrent 22实际为0x16" 23 "Fan 6 motor overheating 23实际为0x17" 24 "Fan 6 drive overheating 24实际为0x18" ;
VAL_ 2337599133 M2P_TMS_R_25_fre_fault_13 0 "no fault 00实际为0x00 引号外不能使用字母" 1 "Overcurrent 01实际为0x01" 2 "Operating overvoltage 02实际为0x02" 3 "Operating under voltage 03实际为0x03" 4 "AC input overvoltage 04实际为0x04" 5 "AC input under voltage05实际为0x05" 6 "communication fault 06实际为0x06" 7 "Overcurrent frequency reduction 07实际为0x07" 8 "Over power frequency reduction 08实际为0x08" 9 "Input phase loss 09实际为0x09" 10 "External malfunction 10实际为0x0A" 11 "NTC overheating 11实际为0x0B" 12 "Power on to ground short circuit detection 12实际为0x0C" 13 "motor overload 13实际为0x0D" ;
VAL_ 2337599133 M2P_TMS_R_25_D_fault_13 0 "no fault 00实际为0x00 引号外不能使用字母" 1 "Overcurrent 01实际为0x01" 2 "Operating overvoltage 02实际为0x02" 3 "Operating under voltage 03实际为0x03" 4 "DC output overvoltage 04实际为0x04" 5 "DC output undervoltage 05实际为0x05" 6 "communication fault 06实际为0x06" 7 "Substrate overheating 07实际为0x07" 8 "output overload 08实际为0x08" ;
VAL_ 2337599134 M2P_TMS_R_25_fan_fault_14 0 "no fault 00实际为0x00 引号外不能使用字母" 1 "Fan 3 overvoltage 01实际为0x01" 2 "Fan 3 under voltage 02实际为0x02" 3 "Fan 3 is stuck in rotation 03实际为0x03" 4 "Fan 3 overcurrent 04实际为0x04" 5 "Fan 3 motor overheating 05实际为0x05" 6 "Fan 3 drive overheating 06实际为0x06" 7 "Fan 4 overvoltage 07实际为0x07" 8 "Fan 4 under voltage 08实际为0x08" 9 "Fan 4 is stuck in rotation 09实际为0x09" 10 "Fan 4 overcurrent 10实际为0x0A" 11 "Fan 4 motor overheating 11实际为0x0B" 12 "Fan 4 drive overheating 12实际为0x0C" 13 "Fan 5 overvoltage 13实际为0x0D" 14 "Fan 5 under voltage 14实际为0x0E" 15 "Fan 5 is stuck in rotation 15实际为0x0F" 16 "Fan 5 overcurrent 10实际为0x10" 17 "Fan 5 motor overheating 17实际为0x11" 18 "Fan 5 drive overheating 18实际为0x12" 19 "Fan 6 overvoltage 19实际为0x13" 20 "Fan 6 under voltage 20实际为0x14" 21 "Fan 6 is stuck in rotation 21实际为0x15" 22 "Fan 6 overcurrent 22实际为0x16" 23 "Fan 6 motor overheating 23实际为0x17" 24 "Fan 6 drive overheating 24实际为0x18" ;
VAL_ 2337599134 M2P_TMS_R_25_fre_fault_14 0 "no fault 00实际为0x00 引号外不能使用字母" 1 "Overcurrent 01实际为0x01" 2 "Operating overvoltage 02实际为0x02" 3 "Operating under voltage 03实际为0x03" 4 "AC input overvoltage 04实际为0x04" 5 "AC input under voltage05实际为0x05" 6 "communication fault 06实际为0x06" 7 "Overcurrent frequency reduction 07实际为0x07" 8 "Over power frequency reduction 08实际为0x08" 9 "Input phase loss 09实际为0x09" 10 "External malfunction 10实际为0x0A" 11 "NTC overheating 11实际为0x0B" 12 "Power on to ground short circuit detection 12实际为0x0C" 13 "motor overload 13实际为0x0D" ;
VAL_ 2337599134 M2P_TMS_R_25_D_fault_14 0 "no fault 00实际为0x00 引号外不能使用字母" 1 "Overcurrent 01实际为0x01" 2 "Operating overvoltage 02实际为0x02" 3 "Operating under voltage 03实际为0x03" 4 "DC output overvoltage 04实际为0x04" 5 "DC output undervoltage 05实际为0x05" 6 "communication fault 06实际为0x06" 7 "Substrate overheating 07实际为0x07" 8 "output overload 08实际为0x08" ;
VAL_ 2337599135 M2P_TMS_R_25_fan_fault_15 0 "no fault 00实际为0x00 引号外不能使用字母" 1 "Fan 3 overvoltage 01实际为0x01" 2 "Fan 3 under voltage 02实际为0x02" 3 "Fan 3 is stuck in rotation 03实际为0x03" 4 "Fan 3 overcurrent 04实际为0x04" 5 "Fan 3 motor overheating 05实际为0x05" 6 "Fan 3 drive overheating 06实际为0x06" 7 "Fan 4 overvoltage 07实际为0x07" 8 "Fan 4 under voltage 08实际为0x08" 9 "Fan 4 is stuck in rotation 09实际为0x09" 10 "Fan 4 overcurrent 10实际为0x0A" 11 "Fan 4 motor overheating 11实际为0x0B" 12 "Fan 4 drive overheating 12实际为0x0C" 13 "Fan 5 overvoltage 13实际为0x0D" 14 "Fan 5 under voltage 14实际为0x0E" 15 "Fan 5 is stuck in rotation 15实际为0x0F" 16 "Fan 5 overcurrent 10实际为0x10" 17 "Fan 5 motor overheating 17实际为0x11" 18 "Fan 5 drive overheating 18实际为0x12" 19 "Fan 6 overvoltage 19实际为0x13" 20 "Fan 6 under voltage 20实际为0x14" 21 "Fan 6 is stuck in rotation 21实际为0x15" 22 "Fan 6 overcurrent 22实际为0x16" 23 "Fan 6 motor overheating 23实际为0x17" 24 "Fan 6 drive overheating 24实际为0x18" ;
VAL_ 2337599135 M2P_TMS_R_25_fre_fault_15 0 "no fault 00实际为0x00 引号外不能使用字母" 1 "Overcurrent 01实际为0x01" 2 "Operating overvoltage 02实际为0x02" 3 "Operating under voltage 03实际为0x03" 4 "AC input overvoltage 04实际为0x04" 5 "AC input under voltage05实际为0x05" 6 "communication fault 06实际为0x06" 7 "Overcurrent frequency reduction 07实际为0x07" 8 "Over power frequency reduction 08实际为0x08" 9 "Input phase loss 09实际为0x09" 10 "External malfunction 10实际为0x0A" 11 "NTC overheating 11实际为0x0B" 12 "Power on to ground short circuit detection 12实际为0x0C" 13 "motor overload 13实际为0x0D" ;
VAL_ 2337599135 M2P_TMS_R_25_D_fault_15 0 "no fault 00实际为0x00 引号外不能使用字母" 1 "Overcurrent 01实际为0x01" 2 "Operating overvoltage 02实际为0x02" 3 "Operating under voltage 03实际为0x03" 4 "DC output overvoltage 04实际为0x04" 5 "DC output undervoltage 05实际为0x05" 6 "communication fault 06实际为0x06" 7 "Substrate overheating 07实际为0x07" 8 "output overload 08实际为0x08" ;
VAL_ 2337599136 M2P_TMS_R_25_fan_fault_16 0 "no fault 00实际为0x00 引号外不能使用字母" 1 "Fan 3 overvoltage 01实际为0x01" 2 "Fan 3 under voltage 02实际为0x02" 3 "Fan 3 is stuck in rotation 03实际为0x03" 4 "Fan 3 overcurrent 04实际为0x04" 5 "Fan 3 motor overheating 05实际为0x05" 6 "Fan 3 drive overheating 06实际为0x06" 7 "Fan 4 overvoltage 07实际为0x07" 8 "Fan 4 under voltage 08实际为0x08" 9 "Fan 4 is stuck in rotation 09实际为0x09" 10 "Fan 4 overcurrent 10实际为0x0A" 11 "Fan 4 motor overheating 11实际为0x0B" 12 "Fan 4 drive overheating 12实际为0x0C" 13 "Fan 5 overvoltage 13实际为0x0D" 14 "Fan 5 under voltage 14实际为0x0E" 15 "Fan 5 is stuck in rotation 15实际为0x0F" 16 "Fan 5 overcurrent 10实际为0x10" 17 "Fan 5 motor overheating 17实际为0x11" 18 "Fan 5 drive overheating 18实际为0x12" 19 "Fan 6 overvoltage 19实际为0x13" 20 "Fan 6 under voltage 20实际为0x14" 21 "Fan 6 is stuck in rotation 21实际为0x15" 22 "Fan 6 overcurrent 22实际为0x16" 23 "Fan 6 motor overheating 23实际为0x17" 24 "Fan 6 drive overheating 24实际为0x18" ;
VAL_ 2337599136 M2P_TMS_R_25_fre_fault_16 0 "no fault 00实际为0x00 引号外不能使用字母" 1 "Overcurrent 01实际为0x01" 2 "Operating overvoltage 02实际为0x02" 3 "Operating under voltage 03实际为0x03" 4 "AC input overvoltage 04实际为0x04" 5 "AC input under voltage05实际为0x05" 6 "communication fault 06实际为0x06" 7 "Overcurrent frequency reduction 07实际为0x07" 8 "Over power frequency reduction 08实际为0x08" 9 "Input phase loss 09实际为0x09" 10 "External malfunction 10实际为0x0A" 11 "NTC overheating 11实际为0x0B" 12 "Power on to ground short circuit detection 12实际为0x0C" 13 "motor overload 13实际为0x0D" ;
VAL_ 2337599136 M2P_TMS_R_25_D_fault_16 0 "no fault 00实际为0x00 引号外不能使用字母" 1 "Overcurrent 01实际为0x01" 2 "Operating overvoltage 02实际为0x02" 3 "Operating under voltage 03实际为0x03" 4 "DC output overvoltage 04实际为0x04" 5 "DC output undervoltage 05实际为0x05" 6 "communication fault 06实际为0x06" 7 "Substrate overheating 07实际为0x07" 8 "output overload 08实际为0x08" ;
VAL_ 2337599137 M2P_TMS_R_25_fan_fault_17 0 "no fault 00实际为0x00 引号外不能使用字母" 1 "Fan 3 overvoltage 01实际为0x01" 2 "Fan 3 under voltage 02实际为0x02" 3 "Fan 3 is stuck in rotation 03实际为0x03" 4 "Fan 3 overcurrent 04实际为0x04" 5 "Fan 3 motor overheating 05实际为0x05" 6 "Fan 3 drive overheating 06实际为0x06" 7 "Fan 4 overvoltage 07实际为0x07" 8 "Fan 4 under voltage 08实际为0x08" 9 "Fan 4 is stuck in rotation 09实际为0x09" 10 "Fan 4 overcurrent 10实际为0x0A" 11 "Fan 4 motor overheating 11实际为0x0B" 12 "Fan 4 drive overheating 12实际为0x0C" 13 "Fan 5 overvoltage 13实际为0x0D" 14 "Fan 5 under voltage 14实际为0x0E" 15 "Fan 5 is stuck in rotation 15实际为0x0F" 16 "Fan 5 overcurrent 10实际为0x10" 17 "Fan 5 motor overheating 17实际为0x11" 18 "Fan 5 drive overheating 18实际为0x12" 19 "Fan 6 overvoltage 19实际为0x13" 20 "Fan 6 under voltage 20实际为0x14" 21 "Fan 6 is stuck in rotation 21实际为0x15" 22 "Fan 6 overcurrent 22实际为0x16" 23 "Fan 6 motor overheating 23实际为0x17" 24 "Fan 6 drive overheating 24实际为0x18" ;
VAL_ 2337599137 M2P_TMS_R_25_fre_fault_17 0 "no fault 00实际为0x00 引号外不能使用字母" 1 "Overcurrent 01实际为0x01" 2 "Operating overvoltage 02实际为0x02" 3 "Operating under voltage 03实际为0x03" 4 "AC input overvoltage 04实际为0x04" 5 "AC input under voltage05实际为0x05" 6 "communication fault 06实际为0x06" 7 "Overcurrent frequency reduction 07实际为0x07" 8 "Over power frequency reduction 08实际为0x08" 9 "Input phase loss 09实际为0x09" 10 "External malfunction 10实际为0x0A" 11 "NTC overheating 11实际为0x0B" 12 "Power on to ground short circuit detection 12实际为0x0C" 13 "motor overload 13实际为0x0D" ;
VAL_ 2337599137 M2P_TMS_R_25_D_fault_17 0 "no fault 00实际为0x00 引号外不能使用字母" 1 "Overcurrent 01实际为0x01" 2 "Operating overvoltage 02实际为0x02" 3 "Operating under voltage 03实际为0x03" 4 "DC output overvoltage 04实际为0x04" 5 "DC output undervoltage 05实际为0x05" 6 "communication fault 06实际为0x06" 7 "Substrate overheating 07实际为0x07" 8 "output overload 08实际为0x08" ;
VAL_ 2337599138 M2P_TMS_R_25_fan_fault_18 0 "no fault 00实际为0x00 引号外不能使用字母" 1 "Fan 3 overvoltage 01实际为0x01" 2 "Fan 3 under voltage 02实际为0x02" 3 "Fan 3 is stuck in rotation 03实际为0x03" 4 "Fan 3 overcurrent 04实际为0x04" 5 "Fan 3 motor overheating 05实际为0x05" 6 "Fan 3 drive overheating 06实际为0x06" 7 "Fan 4 overvoltage 07实际为0x07" 8 "Fan 4 under voltage 08实际为0x08" 9 "Fan 4 is stuck in rotation 09实际为0x09" 10 "Fan 4 overcurrent 10实际为0x0A" 11 "Fan 4 motor overheating 11实际为0x0B" 12 "Fan 4 drive overheating 12实际为0x0C" 13 "Fan 5 overvoltage 13实际为0x0D" 14 "Fan 5 under voltage 14实际为0x0E" 15 "Fan 5 is stuck in rotation 15实际为0x0F" 16 "Fan 5 overcurrent 10实际为0x10" 17 "Fan 5 motor overheating 17实际为0x11" 18 "Fan 5 drive overheating 18实际为0x12" 19 "Fan 6 overvoltage 19实际为0x13" 20 "Fan 6 under voltage 20实际为0x14" 21 "Fan 6 is stuck in rotation 21实际为0x15" 22 "Fan 6 overcurrent 22实际为0x16" 23 "Fan 6 motor overheating 23实际为0x17" 24 "Fan 6 drive overheating 24实际为0x18" ;
VAL_ 2337599138 M2P_TMS_R_25_fre_fault_18 0 "no fault 00实际为0x00 引号外不能使用字母" 1 "Overcurrent 01实际为0x01" 2 "Operating overvoltage 02实际为0x02" 3 "Operating under voltage 03实际为0x03" 4 "AC input overvoltage 04实际为0x04" 5 "AC input under voltage05实际为0x05" 6 "communication fault 06实际为0x06" 7 "Overcurrent frequency reduction 07实际为0x07" 8 "Over power frequency reduction 08实际为0x08" 9 "Input phase loss 09实际为0x09" 10 "External malfunction 10实际为0x0A" 11 "NTC overheating 11实际为0x0B" 12 "Power on to ground short circuit detection 12实际为0x0C" 13 "motor overload 13实际为0x0D" ;
VAL_ 2337599138 M2P_TMS_R_25_D_fault_18 0 "no fault 00实际为0x00 引号外不能使用字母" 1 "Overcurrent 01实际为0x01" 2 "Operating overvoltage 02实际为0x02" 3 "Operating under voltage 03实际为0x03" 4 "DC output overvoltage 04实际为0x04" 5 "DC output undervoltage 05实际为0x05" 6 "communication fault 06实际为0x06" 7 "Substrate overheating 07实际为0x07" 8 "output overload 08实际为0x08" ;
VAL_ 2337599139 M2P_TMS_R_25_fan_fault_19 0 "no fault 00实际为0x00 引号外不能使用字母" 1 "Fan 3 overvoltage 01实际为0x01" 2 "Fan 3 under voltage 02实际为0x02" 3 "Fan 3 is stuck in rotation 03实际为0x03" 4 "Fan 3 overcurrent 04实际为0x04" 5 "Fan 3 motor overheating 05实际为0x05" 6 "Fan 3 drive overheating 06实际为0x06" 7 "Fan 4 overvoltage 07实际为0x07" 8 "Fan 4 under voltage 08实际为0x08" 9 "Fan 4 is stuck in rotation 09实际为0x09" 10 "Fan 4 overcurrent 10实际为0x0A" 11 "Fan 4 motor overheating 11实际为0x0B" 12 "Fan 4 drive overheating 12实际为0x0C" 13 "Fan 5 overvoltage 13实际为0x0D" 14 "Fan 5 under voltage 14实际为0x0E" 15 "Fan 5 is stuck in rotation 15实际为0x0F" 16 "Fan 5 overcurrent 10实际为0x10" 17 "Fan 5 motor overheating 17实际为0x11" 18 "Fan 5 drive overheating 18实际为0x12" 19 "Fan 6 overvoltage 19实际为0x13" 20 "Fan 6 under voltage 20实际为0x14" 21 "Fan 6 is stuck in rotation 21实际为0x15" 22 "Fan 6 overcurrent 22实际为0x16" 23 "Fan 6 motor overheating 23实际为0x17" 24 "Fan 6 drive overheating 24实际为0x18" ;
VAL_ 2337599139 M2P_TMS_R_25_fre_fault_19 0 "no fault 00实际为0x00 引号外不能使用字母" 1 "Overcurrent 01实际为0x01" 2 "Operating overvoltage 02实际为0x02" 3 "Operating under voltage 03实际为0x03" 4 "AC input overvoltage 04实际为0x04" 5 "AC input under voltage05实际为0x05" 6 "communication fault 06实际为0x06" 7 "Overcurrent frequency reduction 07实际为0x07" 8 "Over power frequency reduction 08实际为0x08" 9 "Input phase loss 09实际为0x09" 10 "External malfunction 10实际为0x0A" 11 "NTC overheating 11实际为0x0B" 12 "Power on to ground short circuit detection 12实际为0x0C" 13 "motor overload 13实际为0x0D" ;
VAL_ 2337599139 M2P_TMS_R_25_D_fault_19 0 "no fault 00实际为0x00 引号外不能使用字母" 1 "Overcurrent 01实际为0x01" 2 "Operating overvoltage 02实际为0x02" 3 "Operating under voltage 03实际为0x03" 4 "DC output overvoltage 04实际为0x04" 5 "DC output undervoltage 05实际为0x05" 6 "communication fault 06实际为0x06" 7 "Substrate overheating 07实际为0x07" 8 "output overload 08实际为0x08" ;
VAL_ 2337599140 M2P_TMS_R_25_fan_fault_20 0 "no fault 00实际为0x00 引号外不能使用字母" 1 "Fan 3 overvoltage 01实际为0x01" 2 "Fan 3 under voltage 02实际为0x02" 3 "Fan 3 is stuck in rotation 03实际为0x03" 4 "Fan 3 overcurrent 04实际为0x04" 5 "Fan 3 motor overheating 05实际为0x05" 6 "Fan 3 drive overheating 06实际为0x06" 7 "Fan 4 overvoltage 07实际为0x07" 8 "Fan 4 under voltage 08实际为0x08" 9 "Fan 4 is stuck in rotation 09实际为0x09" 10 "Fan 4 overcurrent 10实际为0x0A" 11 "Fan 4 motor overheating 11实际为0x0B" 12 "Fan 4 drive overheating 12实际为0x0C" 13 "Fan 5 overvoltage 13实际为0x0D" 14 "Fan 5 under voltage 14实际为0x0E" 15 "Fan 5 is stuck in rotation 15实际为0x0F" 16 "Fan 5 overcurrent 10实际为0x10" 17 "Fan 5 motor overheating 17实际为0x11" 18 "Fan 5 drive overheating 18实际为0x12" 19 "Fan 6 overvoltage 19实际为0x13" 20 "Fan 6 under voltage 20实际为0x14" 21 "Fan 6 is stuck in rotation 21实际为0x15" 22 "Fan 6 overcurrent 22实际为0x16" 23 "Fan 6 motor overheating 23实际为0x17" 24 "Fan 6 drive overheating 24实际为0x18" ;
VAL_ 2337599140 M2P_TMS_R_25_fre_fault_20 0 "no fault 00实际为0x00 引号外不能使用字母" 1 "Overcurrent 01实际为0x01" 2 "Operating overvoltage 02实际为0x02" 3 "Operating under voltage 03实际为0x03" 4 "AC input overvoltage 04实际为0x04" 5 "AC input under voltage05实际为0x05" 6 "communication fault 06实际为0x06" 7 "Overcurrent frequency reduction 07实际为0x07" 8 "Over power frequency reduction 08实际为0x08" 9 "Input phase loss 09实际为0x09" 10 "External malfunction 10实际为0x0A" 11 "NTC overheating 11实际为0x0B" 12 "Power on to ground short circuit detection 12实际为0x0C" 13 "motor overload 13实际为0x0D" ;
VAL_ 2337599140 M2P_TMS_R_25_D_fault_20 0 "no fault 00实际为0x00 引号外不能使用字母" 1 "Overcurrent 01实际为0x01" 2 "Operating overvoltage 02实际为0x02" 3 "Operating under voltage 03实际为0x03" 4 "DC output overvoltage 04实际为0x04" 5 "DC output undervoltage 05实际为0x05" 6 "communication fault 06实际为0x06" 7 "Substrate overheating 07实际为0x07" 8 "output overload 08实际为0x08" ;
VAL_ 2337599141 M2P_TMS_R_25_fan_fault_21 0 "no fault 00实际为0x00 引号外不能使用字母" 1 "Fan 3 overvoltage 01实际为0x01" 2 "Fan 3 under voltage 02实际为0x02" 3 "Fan 3 is stuck in rotation 03实际为0x03" 4 "Fan 3 overcurrent 04实际为0x04" 5 "Fan 3 motor overheating 05实际为0x05" 6 "Fan 3 drive overheating 06实际为0x06" 7 "Fan 4 overvoltage 07实际为0x07" 8 "Fan 4 under voltage 08实际为0x08" 9 "Fan 4 is stuck in rotation 09实际为0x09" 10 "Fan 4 overcurrent 10实际为0x0A" 11 "Fan 4 motor overheating 11实际为0x0B" 12 "Fan 4 drive overheating 12实际为0x0C" 13 "Fan 5 overvoltage 13实际为0x0D" 14 "Fan 5 under voltage 14实际为0x0E" 15 "Fan 5 is stuck in rotation 15实际为0x0F" 16 "Fan 5 overcurrent 10实际为0x10" 17 "Fan 5 motor overheating 17实际为0x11" 18 "Fan 5 drive overheating 18实际为0x12" 19 "Fan 6 overvoltage 19实际为0x13" 20 "Fan 6 under voltage 20实际为0x14" 21 "Fan 6 is stuck in rotation 21实际为0x15" 22 "Fan 6 overcurrent 22实际为0x16" 23 "Fan 6 motor overheating 23实际为0x17" 24 "Fan 6 drive overheating 24实际为0x18" ;
VAL_ 2337599141 M2P_TMS_R_25_fre_fault_21 0 "no fault 00实际为0x00 引号外不能使用字母" 1 "Overcurrent 01实际为0x01" 2 "Operating overvoltage 02实际为0x02" 3 "Operating under voltage 03实际为0x03" 4 "AC input overvoltage 04实际为0x04" 5 "AC input under voltage05实际为0x05" 6 "communication fault 06实际为0x06" 7 "Overcurrent frequency reduction 07实际为0x07" 8 "Over power frequency reduction 08实际为0x08" 9 "Input phase loss 09实际为0x09" 10 "External malfunction 10实际为0x0A" 11 "NTC overheating 11实际为0x0B" 12 "Power on to ground short circuit detection 12实际为0x0C" 13 "motor overload 13实际为0x0D" ;
VAL_ 2337599141 M2P_TMS_R_25_D_fault_21 0 "no fault 00实际为0x00 引号外不能使用字母" 1 "Overcurrent 01实际为0x01" 2 "Operating overvoltage 02实际为0x02" 3 "Operating under voltage 03实际为0x03" 4 "DC output overvoltage 04实际为0x04" 5 "DC output undervoltage 05实际为0x05" 6 "communication fault 06实际为0x06" 7 "Substrate overheating 07实际为0x07" 8 "output overload 08实际为0x08" ;
VAL_ 2337599142 M2P_TMS_R_25_fan_fault_22 0 "no fault 00实际为0x00 引号外不能使用字母" 1 "Fan 3 overvoltage 01实际为0x01" 2 "Fan 3 under voltage 02实际为0x02" 3 "Fan 3 is stuck in rotation 03实际为0x03" 4 "Fan 3 overcurrent 04实际为0x04" 5 "Fan 3 motor overheating 05实际为0x05" 6 "Fan 3 drive overheating 06实际为0x06" 7 "Fan 4 overvoltage 07实际为0x07" 8 "Fan 4 under voltage 08实际为0x08" 9 "Fan 4 is stuck in rotation 09实际为0x09" 10 "Fan 4 overcurrent 10实际为0x0A" 11 "Fan 4 motor overheating 11实际为0x0B" 12 "Fan 4 drive overheating 12实际为0x0C" 13 "Fan 5 overvoltage 13实际为0x0D" 14 "Fan 5 under voltage 14实际为0x0E" 15 "Fan 5 is stuck in rotation 15实际为0x0F" 16 "Fan 5 overcurrent 10实际为0x10" 17 "Fan 5 motor overheating 17实际为0x11" 18 "Fan 5 drive overheating 18实际为0x12" 19 "Fan 6 overvoltage 19实际为0x13" 20 "Fan 6 under voltage 20实际为0x14" 21 "Fan 6 is stuck in rotation 21实际为0x15" 22 "Fan 6 overcurrent 22实际为0x16" 23 "Fan 6 motor overheating 23实际为0x17" 24 "Fan 6 drive overheating 24实际为0x18" ;
VAL_ 2337599142 M2P_TMS_R_25_fre_fault_22 0 "no fault 00实际为0x00 引号外不能使用字母" 1 "Overcurrent 01实际为0x01" 2 "Operating overvoltage 02实际为0x02" 3 "Operating under voltage 03实际为0x03" 4 "AC input overvoltage 04实际为0x04" 5 "AC input under voltage05实际为0x05" 6 "communication fault 06实际为0x06" 7 "Overcurrent frequency reduction 07实际为0x07" 8 "Over power frequency reduction 08实际为0x08" 9 "Input phase loss 09实际为0x09" 10 "External malfunction 10实际为0x0A" 11 "NTC overheating 11实际为0x0B" 12 "Power on to ground short circuit detection 12实际为0x0C" 13 "motor overload 13实际为0x0D" ;
VAL_ 2337599142 M2P_TMS_R_25_D_fault_22 0 "no fault 00实际为0x00 引号外不能使用字母" 1 "Overcurrent 01实际为0x01" 2 "Operating overvoltage 02实际为0x02" 3 "Operating under voltage 03实际为0x03" 4 "DC output overvoltage 04实际为0x04" 5 "DC output undervoltage 05实际为0x05" 6 "communication fault 06实际为0x06" 7 "Substrate overheating 07实际为0x07" 8 "output overload 08实际为0x08" ;
VAL_ 2337599143 M2P_TMS_R_25_fan_fault_23 0 "no fault 00实际为0x00 引号外不能使用字母" 1 "Fan 3 overvoltage 01实际为0x01" 2 "Fan 3 under voltage 02实际为0x02" 3 "Fan 3 is stuck in rotation 03实际为0x03" 4 "Fan 3 overcurrent 04实际为0x04" 5 "Fan 3 motor overheating 05实际为0x05" 6 "Fan 3 drive overheating 06实际为0x06" 7 "Fan 4 overvoltage 07实际为0x07" 8 "Fan 4 under voltage 08实际为0x08" 9 "Fan 4 is stuck in rotation 09实际为0x09" 10 "Fan 4 overcurrent 10实际为0x0A" 11 "Fan 4 motor overheating 11实际为0x0B" 12 "Fan 4 drive overheating 12实际为0x0C" 13 "Fan 5 overvoltage 13实际为0x0D" 14 "Fan 5 under voltage 14实际为0x0E" 15 "Fan 5 is stuck in rotation 15实际为0x0F" 16 "Fan 5 overcurrent 10实际为0x10" 17 "Fan 5 motor overheating 17实际为0x11" 18 "Fan 5 drive overheating 18实际为0x12" 19 "Fan 6 overvoltage 19实际为0x13" 20 "Fan 6 under voltage 20实际为0x14" 21 "Fan 6 is stuck in rotation 21实际为0x15" 22 "Fan 6 overcurrent 22实际为0x16" 23 "Fan 6 motor overheating 23实际为0x17" 24 "Fan 6 drive overheating 24实际为0x18" ;
VAL_ 2337599143 M2P_TMS_R_25_fre_fault_23 0 "no fault 00实际为0x00 引号外不能使用字母" 1 "Overcurrent 01实际为0x01" 2 "Operating overvoltage 02实际为0x02" 3 "Operating under voltage 03实际为0x03" 4 "AC input overvoltage 04实际为0x04" 5 "AC input under voltage05实际为0x05" 6 "communication fault 06实际为0x06" 7 "Overcurrent frequency reduction 07实际为0x07" 8 "Over power frequency reduction 08实际为0x08" 9 "Input phase loss 09实际为0x09" 10 "External malfunction 10实际为0x0A" 11 "NTC overheating 11实际为0x0B" 12 "Power on to ground short circuit detection 12实际为0x0C" 13 "motor overload 13实际为0x0D" ;
VAL_ 2337599143 M2P_TMS_R_25_D_fault_23 0 "no fault 00实际为0x00 引号外不能使用字母" 1 "Overcurrent 01实际为0x01" 2 "Operating overvoltage 02实际为0x02" 3 "Operating under voltage 03实际为0x03" 4 "DC output overvoltage 04实际为0x04" 5 "DC output undervoltage 05实际为0x05" 6 "communication fault 06实际为0x06" 7 "Substrate overheating 07实际为0x07" 8 "output overload 08实际为0x08" ;
VAL_ 2337599144 M2P_TMS_R_25_fan_fault_24 0 "no fault 00实际为0x00 引号外不能使用字母" 1 "Fan 3 overvoltage 01实际为0x01" 2 "Fan 3 under voltage 02实际为0x02" 3 "Fan 3 is stuck in rotation 03实际为0x03" 4 "Fan 3 overcurrent 04实际为0x04" 5 "Fan 3 motor overheating 05实际为0x05" 6 "Fan 3 drive overheating 06实际为0x06" 7 "Fan 4 overvoltage 07实际为0x07" 8 "Fan 4 under voltage 08实际为0x08" 9 "Fan 4 is stuck in rotation 09实际为0x09" 10 "Fan 4 overcurrent 10实际为0x0A" 11 "Fan 4 motor overheating 11实际为0x0B" 12 "Fan 4 drive overheating 12实际为0x0C" 13 "Fan 5 overvoltage 13实际为0x0D" 14 "Fan 5 under voltage 14实际为0x0E" 15 "Fan 5 is stuck in rotation 15实际为0x0F" 16 "Fan 5 overcurrent 10实际为0x10" 17 "Fan 5 motor overheating 17实际为0x11" 18 "Fan 5 drive overheating 18实际为0x12" 19 "Fan 6 overvoltage 19实际为0x13" 20 "Fan 6 under voltage 20实际为0x14" 21 "Fan 6 is stuck in rotation 21实际为0x15" 22 "Fan 6 overcurrent 22实际为0x16" 23 "Fan 6 motor overheating 23实际为0x17" 24 "Fan 6 drive overheating 24实际为0x18" ;
VAL_ 2337599144 M2P_TMS_R_25_fre_fault_24 0 "no fault 00实际为0x00 引号外不能使用字母" 1 "Overcurrent 01实际为0x01" 2 "Operating overvoltage 02实际为0x02" 3 "Operating under voltage 03实际为0x03" 4 "AC input overvoltage 04实际为0x04" 5 "AC input under voltage05实际为0x05" 6 "communication fault 06实际为0x06" 7 "Overcurrent frequency reduction 07实际为0x07" 8 "Over power frequency reduction 08实际为0x08" 9 "Input phase loss 09实际为0x09" 10 "External malfunction 10实际为0x0A" 11 "NTC overheating 11实际为0x0B" 12 "Power on to ground short circuit detection 12实际为0x0C" 13 "motor overload 13实际为0x0D" ;
VAL_ 2337599144 M2P_TMS_R_25_D_fault_24 0 "no fault 00实际为0x00 引号外不能使用字母" 1 "Overcurrent 01实际为0x01" 2 "Operating overvoltage 02实际为0x02" 3 "Operating under voltage 03实际为0x03" 4 "DC output overvoltage 04实际为0x04" 5 "DC output undervoltage 05实际为0x05" 6 "communication fault 06实际为0x06" 7 "Substrate overheating 07实际为0x07" 8 "output overload 08实际为0x08" ;
VAL_ 2337599145 M2P_TMS_R_25_fan_fault_25 0 "no fault 00实际为0x00 引号外不能使用字母" 1 "Fan 3 overvoltage 01实际为0x01" 2 "Fan 3 under voltage 02实际为0x02" 3 "Fan 3 is stuck in rotation 03实际为0x03" 4 "Fan 3 overcurrent 04实际为0x04" 5 "Fan 3 motor overheating 05实际为0x05" 6 "Fan 3 drive overheating 06实际为0x06" 7 "Fan 4 overvoltage 07实际为0x07" 8 "Fan 4 under voltage 08实际为0x08" 9 "Fan 4 is stuck in rotation 09实际为0x09" 10 "Fan 4 overcurrent 10实际为0x0A" 11 "Fan 4 motor overheating 11实际为0x0B" 12 "Fan 4 drive overheating 12实际为0x0C" 13 "Fan 5 overvoltage 13实际为0x0D" 14 "Fan 5 under voltage 14实际为0x0E" 15 "Fan 5 is stuck in rotation 15实际为0x0F" 16 "Fan 5 overcurrent 10实际为0x10" 17 "Fan 5 motor overheating 17实际为0x11" 18 "Fan 5 drive overheating 18实际为0x12" 19 "Fan 6 overvoltage 19实际为0x13" 20 "Fan 6 under voltage 20实际为0x14" 21 "Fan 6 is stuck in rotation 21实际为0x15" 22 "Fan 6 overcurrent 22实际为0x16" 23 "Fan 6 motor overheating 23实际为0x17" 24 "Fan 6 drive overheating 24实际为0x18" ;
VAL_ 2337599145 M2P_TMS_R_25_fre_fault_25 0 "no fault 00实际为0x00 引号外不能使用字母" 1 "Overcurrent 01实际为0x01" 2 "Operating overvoltage 02实际为0x02" 3 "Operating under voltage 03实际为0x03" 4 "AC input overvoltage 04实际为0x04" 5 "AC input under voltage05实际为0x05" 6 "communication fault 06实际为0x06" 7 "Overcurrent frequency reduction 07实际为0x07" 8 "Over power frequency reduction 08实际为0x08" 9 "Input phase loss 09实际为0x09" 10 "External malfunction 10实际为0x0A" 11 "NTC overheating 11实际为0x0B" 12 "Power on to ground short circuit detection 12实际为0x0C" 13 "motor overload 13实际为0x0D" ;
VAL_ 2337599145 M2P_TMS_R_25_D_fault_25 0 "no fault 00实际为0x00 引号外不能使用字母" 1 "Overcurrent 01实际为0x01" 2 "Operating overvoltage 02实际为0x02" 3 "Operating under voltage 03实际为0x03" 4 "DC output overvoltage 04实际为0x04" 5 "DC output undervoltage 05实际为0x05" 6 "communication fault 06实际为0x06" 7 "Substrate overheating 07实际为0x07" 8 "output overload 08实际为0x08" ;
VAL_ 2337599146 M2P_TMS_R_25_fan_fault_26 0 "no fault 00实际为0x00 引号外不能使用字母" 1 "Fan 3 overvoltage 01实际为0x01" 2 "Fan 3 under voltage 02实际为0x02" 3 "Fan 3 is stuck in rotation 03实际为0x03" 4 "Fan 3 overcurrent 04实际为0x04" 5 "Fan 3 motor overheating 05实际为0x05" 6 "Fan 3 drive overheating 06实际为0x06" 7 "Fan 4 overvoltage 07实际为0x07" 8 "Fan 4 under voltage 08实际为0x08" 9 "Fan 4 is stuck in rotation 09实际为0x09" 10 "Fan 4 overcurrent 10实际为0x0A" 11 "Fan 4 motor overheating 11实际为0x0B" 12 "Fan 4 drive overheating 12实际为0x0C" 13 "Fan 5 overvoltage 13实际为0x0D" 14 "Fan 5 under voltage 14实际为0x0E" 15 "Fan 5 is stuck in rotation 15实际为0x0F" 16 "Fan 5 overcurrent 10实际为0x10" 17 "Fan 5 motor overheating 17实际为0x11" 18 "Fan 5 drive overheating 18实际为0x12" 19 "Fan 6 overvoltage 19实际为0x13" 20 "Fan 6 under voltage 20实际为0x14" 21 "Fan 6 is stuck in rotation 21实际为0x15" 22 "Fan 6 overcurrent 22实际为0x16" 23 "Fan 6 motor overheating 23实际为0x17" 24 "Fan 6 drive overheating 24实际为0x18" ;
VAL_ 2337599146 M2P_TMS_R_25_fre_fault_26 0 "no fault 00实际为0x00 引号外不能使用字母" 1 "Overcurrent 01实际为0x01" 2 "Operating overvoltage 02实际为0x02" 3 "Operating under voltage 03实际为0x03" 4 "AC input overvoltage 04实际为0x04" 5 "AC input under voltage05实际为0x05" 6 "communication fault 06实际为0x06" 7 "Overcurrent frequency reduction 07实际为0x07" 8 "Over power frequency reduction 08实际为0x08" 9 "Input phase loss 09实际为0x09" 10 "External malfunction 10实际为0x0A" 11 "NTC overheating 11实际为0x0B" 12 "Power on to ground short circuit detection 12实际为0x0C" 13 "motor overload 13实际为0x0D" ;
VAL_ 2337599146 M2P_TMS_R_25_D_fault_26 0 "no fault 00实际为0x00 引号外不能使用字母" 1 "Overcurrent 01实际为0x01" 2 "Operating overvoltage 02实际为0x02" 3 "Operating under voltage 03实际为0x03" 4 "DC output overvoltage 04实际为0x04" 5 "DC output undervoltage 05实际为0x05" 6 "communication fault 06实际为0x06" 7 "Substrate overheating 07实际为0x07" 8 "output overload 08实际为0x08" ;
VAL_ 2337599147 M2P_TMS_R_25_fan_fault_27 0 "no fault 00实际为0x00 引号外不能使用字母" 1 "Fan 3 overvoltage 01实际为0x01" 2 "Fan 3 under voltage 02实际为0x02" 3 "Fan 3 is stuck in rotation 03实际为0x03" 4 "Fan 3 overcurrent 04实际为0x04" 5 "Fan 3 motor overheating 05实际为0x05" 6 "Fan 3 drive overheating 06实际为0x06" 7 "Fan 4 overvoltage 07实际为0x07" 8 "Fan 4 under voltage 08实际为0x08" 9 "Fan 4 is stuck in rotation 09实际为0x09" 10 "Fan 4 overcurrent 10实际为0x0A" 11 "Fan 4 motor overheating 11实际为0x0B" 12 "Fan 4 drive overheating 12实际为0x0C" 13 "Fan 5 overvoltage 13实际为0x0D" 14 "Fan 5 under voltage 14实际为0x0E" 15 "Fan 5 is stuck in rotation 15实际为0x0F" 16 "Fan 5 overcurrent 10实际为0x10" 17 "Fan 5 motor overheating 17实际为0x11" 18 "Fan 5 drive overheating 18实际为0x12" 19 "Fan 6 overvoltage 19实际为0x13" 20 "Fan 6 under voltage 20实际为0x14" 21 "Fan 6 is stuck in rotation 21实际为0x15" 22 "Fan 6 overcurrent 22实际为0x16" 23 "Fan 6 motor overheating 23实际为0x17" 24 "Fan 6 drive overheating 24实际为0x18" ;
VAL_ 2337599147 M2P_TMS_R_25_fre_fault_27 0 "no fault 00实际为0x00 引号外不能使用字母" 1 "Overcurrent 01实际为0x01" 2 "Operating overvoltage 02实际为0x02" 3 "Operating under voltage 03实际为0x03" 4 "AC input overvoltage 04实际为0x04" 5 "AC input under voltage05实际为0x05" 6 "communication fault 06实际为0x06" 7 "Overcurrent frequency reduction 07实际为0x07" 8 "Over power frequency reduction 08实际为0x08" 9 "Input phase loss 09实际为0x09" 10 "External malfunction 10实际为0x0A" 11 "NTC overheating 11实际为0x0B" 12 "Power on to ground short circuit detection 12实际为0x0C" 13 "motor overload 13实际为0x0D" ;
VAL_ 2337599147 M2P_TMS_R_25_D_fault_27 0 "no fault 00实际为0x00 引号外不能使用字母" 1 "Overcurrent 01实际为0x01" 2 "Operating overvoltage 02实际为0x02" 3 "Operating under voltage 03实际为0x03" 4 "DC output overvoltage 04实际为0x04" 5 "DC output undervoltage 05实际为0x05" 6 "communication fault 06实际为0x06" 7 "Substrate overheating 07实际为0x07" 8 "output overload 08实际为0x08" ;
VAL_ 2337599148 M2P_TMS_R_25_fan_fault_28 0 "no fault 00实际为0x00 引号外不能使用字母" 1 "Fan 3 overvoltage 01实际为0x01" 2 "Fan 3 under voltage 02实际为0x02" 3 "Fan 3 is stuck in rotation 03实际为0x03" 4 "Fan 3 overcurrent 04实际为0x04" 5 "Fan 3 motor overheating 05实际为0x05" 6 "Fan 3 drive overheating 06实际为0x06" 7 "Fan 4 overvoltage 07实际为0x07" 8 "Fan 4 under voltage 08实际为0x08" 9 "Fan 4 is stuck in rotation 09实际为0x09" 10 "Fan 4 overcurrent 10实际为0x0A" 11 "Fan 4 motor overheating 11实际为0x0B" 12 "Fan 4 drive overheating 12实际为0x0C" 13 "Fan 5 overvoltage 13实际为0x0D" 14 "Fan 5 under voltage 14实际为0x0E" 15 "Fan 5 is stuck in rotation 15实际为0x0F" 16 "Fan 5 overcurrent 10实际为0x10" 17 "Fan 5 motor overheating 17实际为0x11" 18 "Fan 5 drive overheating 18实际为0x12" 19 "Fan 6 overvoltage 19实际为0x13" 20 "Fan 6 under voltage 20实际为0x14" 21 "Fan 6 is stuck in rotation 21实际为0x15" 22 "Fan 6 overcurrent 22实际为0x16" 23 "Fan 6 motor overheating 23实际为0x17" 24 "Fan 6 drive overheating 24实际为0x18" ;
VAL_ 2337599148 M2P_TMS_R_25_fre_fault_28 0 "no fault 00实际为0x00 引号外不能使用字母" 1 "Overcurrent 01实际为0x01" 2 "Operating overvoltage 02实际为0x02" 3 "Operating under voltage 03实际为0x03" 4 "AC input overvoltage 04实际为0x04" 5 "AC input under voltage05实际为0x05" 6 "communication fault 06实际为0x06" 7 "Overcurrent frequency reduction 07实际为0x07" 8 "Over power frequency reduction 08实际为0x08" 9 "Input phase loss 09实际为0x09" 10 "External malfunction 10实际为0x0A" 11 "NTC overheating 11实际为0x0B" 12 "Power on to ground short circuit detection 12实际为0x0C" 13 "motor overload 13实际为0x0D" ;
VAL_ 2337599148 M2P_TMS_R_25_D_fault_28 0 "no fault 00实际为0x00 引号外不能使用字母" 1 "Overcurrent 01实际为0x01" 2 "Operating overvoltage 02实际为0x02" 3 "Operating under voltage 03实际为0x03" 4 "DC output overvoltage 04实际为0x04" 5 "DC output undervoltage 05实际为0x05" 6 "communication fault 06实际为0x06" 7 "Substrate overheating 07实际为0x07" 8 "output overload 08实际为0x08" ;
VAL_ 2337599149 M2P_TMS_R_25_fan_fault_29 0 "no fault 00实际为0x00 引号外不能使用字母" 1 "Fan 3 overvoltage 01实际为0x01" 2 "Fan 3 under voltage 02实际为0x02" 3 "Fan 3 is stuck in rotation 03实际为0x03" 4 "Fan 3 overcurrent 04实际为0x04" 5 "Fan 3 motor overheating 05实际为0x05" 6 "Fan 3 drive overheating 06实际为0x06" 7 "Fan 4 overvoltage 07实际为0x07" 8 "Fan 4 under voltage 08实际为0x08" 9 "Fan 4 is stuck in rotation 09实际为0x09" 10 "Fan 4 overcurrent 10实际为0x0A" 11 "Fan 4 motor overheating 11实际为0x0B" 12 "Fan 4 drive overheating 12实际为0x0C" 13 "Fan 5 overvoltage 13实际为0x0D" 14 "Fan 5 under voltage 14实际为0x0E" 15 "Fan 5 is stuck in rotation 15实际为0x0F" 16 "Fan 5 overcurrent 10实际为0x10" 17 "Fan 5 motor overheating 17实际为0x11" 18 "Fan 5 drive overheating 18实际为0x12" 19 "Fan 6 overvoltage 19实际为0x13" 20 "Fan 6 under voltage 20实际为0x14" 21 "Fan 6 is stuck in rotation 21实际为0x15" 22 "Fan 6 overcurrent 22实际为0x16" 23 "Fan 6 motor overheating 23实际为0x17" 24 "Fan 6 drive overheating 24实际为0x18" ;
VAL_ 2337599149 M2P_TMS_R_25_fre_fault_29 0 "no fault 00实际为0x00 引号外不能使用字母" 1 "Overcurrent 01实际为0x01" 2 "Operating overvoltage 02实际为0x02" 3 "Operating under voltage 03实际为0x03" 4 "AC input overvoltage 04实际为0x04" 5 "AC input under voltage05实际为0x05" 6 "communication fault 06实际为0x06" 7 "Overcurrent frequency reduction 07实际为0x07" 8 "Over power frequency reduction 08实际为0x08" 9 "Input phase loss 09实际为0x09" 10 "External malfunction 10实际为0x0A" 11 "NTC overheating 11实际为0x0B" 12 "Power on to ground short circuit detection 12实际为0x0C" 13 "motor overload 13实际为0x0D" ;
VAL_ 2337599149 M2P_TMS_R_25_D_fault_29 0 "no fault 00实际为0x00 引号外不能使用字母" 1 "Overcurrent 01实际为0x01" 2 "Operating overvoltage 02实际为0x02" 3 "Operating under voltage 03实际为0x03" 4 "DC output overvoltage 04实际为0x04" 5 "DC output undervoltage 05实际为0x05" 6 "communication fault 06实际为0x06" 7 "Substrate overheating 07实际为0x07" 8 "output overload 08实际为0x08" ;
VAL_ 2337599150 M2P_TMS_R_25_fan_fault_30 0 "no fault 00实际为0x00 引号外不能使用字母" 1 "Fan 3 overvoltage 01实际为0x01" 2 "Fan 3 under voltage 02实际为0x02" 3 "Fan 3 is stuck in rotation 03实际为0x03" 4 "Fan 3 overcurrent 04实际为0x04" 5 "Fan 3 motor overheating 05实际为0x05" 6 "Fan 3 drive overheating 06实际为0x06" 7 "Fan 4 overvoltage 07实际为0x07" 8 "Fan 4 under voltage 08实际为0x08" 9 "Fan 4 is stuck in rotation 09实际为0x09" 10 "Fan 4 overcurrent 10实际为0x0A" 11 "Fan 4 motor overheating 11实际为0x0B" 12 "Fan 4 drive overheating 12实际为0x0C" 13 "Fan 5 overvoltage 13实际为0x0D" 14 "Fan 5 under voltage 14实际为0x0E" 15 "Fan 5 is stuck in rotation 15实际为0x0F" 16 "Fan 5 overcurrent 10实际为0x10" 17 "Fan 5 motor overheating 17实际为0x11" 18 "Fan 5 drive overheating 18实际为0x12" 19 "Fan 6 overvoltage 19实际为0x13" 20 "Fan 6 under voltage 20实际为0x14" 21 "Fan 6 is stuck in rotation 21实际为0x15" 22 "Fan 6 overcurrent 22实际为0x16" 23 "Fan 6 motor overheating 23实际为0x17" 24 "Fan 6 drive overheating 24实际为0x18" ;
VAL_ 2337599150 M2P_TMS_R_25_fre_fault_30 0 "no fault 00实际为0x00 引号外不能使用字母" 1 "Overcurrent 01实际为0x01" 2 "Operating overvoltage 02实际为0x02" 3 "Operating under voltage 03实际为0x03" 4 "AC input overvoltage 04实际为0x04" 5 "AC input under voltage05实际为0x05" 6 "communication fault 06实际为0x06" 7 "Overcurrent frequency reduction 07实际为0x07" 8 "Over power frequency reduction 08实际为0x08" 9 "Input phase loss 09实际为0x09" 10 "External malfunction 10实际为0x0A" 11 "NTC overheating 11实际为0x0B" 12 "Power on to ground short circuit detection 12实际为0x0C" 13 "motor overload 13实际为0x0D" ;
VAL_ 2337599150 M2P_TMS_R_25_D_fault_30 0 "no fault 00实际为0x00 引号外不能使用字母" 1 "Overcurrent 01实际为0x01" 2 "Operating overvoltage 02实际为0x02" 3 "Operating under voltage 03实际为0x03" 4 "DC output overvoltage 04实际为0x04" 5 "DC output undervoltage 05实际为0x05" 6 "communication fault 06实际为0x06" 7 "Substrate overheating 07实际为0x07" 8 "output overload 08实际为0x08" ;
VAL_ 2337599151 M2P_TMS_R_25_fan_fault_31 0 "no fault 00实际为0x00 引号外不能使用字母" 1 "Fan 3 overvoltage 01实际为0x01" 2 "Fan 3 under voltage 02实际为0x02" 3 "Fan 3 is stuck in rotation 03实际为0x03" 4 "Fan 3 overcurrent 04实际为0x04" 5 "Fan 3 motor overheating 05实际为0x05" 6 "Fan 3 drive overheating 06实际为0x06" 7 "Fan 4 overvoltage 07实际为0x07" 8 "Fan 4 under voltage 08实际为0x08" 9 "Fan 4 is stuck in rotation 09实际为0x09" 10 "Fan 4 overcurrent 10实际为0x0A" 11 "Fan 4 motor overheating 11实际为0x0B" 12 "Fan 4 drive overheating 12实际为0x0C" 13 "Fan 5 overvoltage 13实际为0x0D" 14 "Fan 5 under voltage 14实际为0x0E" 15 "Fan 5 is stuck in rotation 15实际为0x0F" 16 "Fan 5 overcurrent 10实际为0x10" 17 "Fan 5 motor overheating 17实际为0x11" 18 "Fan 5 drive overheating 18实际为0x12" 19 "Fan 6 overvoltage 19实际为0x13" 20 "Fan 6 under voltage 20实际为0x14" 21 "Fan 6 is stuck in rotation 21实际为0x15" 22 "Fan 6 overcurrent 22实际为0x16" 23 "Fan 6 motor overheating 23实际为0x17" 24 "Fan 6 drive overheating 24实际为0x18" ;
VAL_ 2337599151 M2P_TMS_R_25_fre_fault_31 0 "no fault 00实际为0x00 引号外不能使用字母" 1 "Overcurrent 01实际为0x01" 2 "Operating overvoltage 02实际为0x02" 3 "Operating under voltage 03实际为0x03" 4 "AC input overvoltage 04实际为0x04" 5 "AC input under voltage05实际为0x05" 6 "communication fault 06实际为0x06" 7 "Overcurrent frequency reduction 07实际为0x07" 8 "Over power frequency reduction 08实际为0x08" 9 "Input phase loss 09实际为0x09" 10 "External malfunction 10实际为0x0A" 11 "NTC overheating 11实际为0x0B" 12 "Power on to ground short circuit detection 12实际为0x0C" 13 "motor overload 13实际为0x0D" ;
VAL_ 2337599151 M2P_TMS_R_25_D_fault_31 0 "no fault 00实际为0x00 引号外不能使用字母" 1 "Overcurrent 01实际为0x01" 2 "Operating overvoltage 02实际为0x02" 3 "Operating under voltage 03实际为0x03" 4 "DC output overvoltage 04实际为0x04" 5 "DC output undervoltage 05实际为0x05" 6 "communication fault 06实际为0x06" 7 "Substrate overheating 07实际为0x07" 8 "output overload 08实际为0x08" ;
VERSION ""

NS_ :

BS_:

BU_: MBMU PC SBMU IMM ETH DCDC LEMS

BO_ 2337664675 M2P_LiquidInfo_6__19: 8 MBMU
 SG_ M2P_TMS_R_S_version_19 : 0|40@1+ (1,0) [0|1099511627775] ""  PC
 SG_ M2P_TMS_R_N_S_version_19 : 40|24@1+ (1,0) [0|16777215] ""  PC

BO_ 2337664676 M2P_LiquidInfo_6__20: 8 MBMU
 SG_ M2P_TMS_R_S_version_20 : 0|40@1+ (1,0) [0|1099511627775] ""  PC
 SG_ M2P_TMS_R_N_S_version_20 : 40|24@1+ (1,0) [0|16777215] ""  PC

BO_ 2337664677 M2P_LiquidInfo_6__21: 8 MBMU
 SG_ M2P_TMS_R_S_version_21 : 0|40@1+ (1,0) [0|1099511627775] ""  PC
 SG_ M2P_TMS_R_N_S_version_21 : 40|24@1+ (1,0) [0|16777215] ""  PC

BO_ 2337664678 M2P_LiquidInfo_6__22: 8 MBMU
 SG_ M2P_TMS_R_S_version_22 : 0|40@1+ (1,0) [0|1099511627775] ""  PC
 SG_ M2P_TMS_R_N_S_version_22 : 40|24@1+ (1,0) [0|16777215] ""  PC

BO_ 2337664679 M2P_LiquidInfo_6__23: 8 MBMU
 SG_ M2P_TMS_R_S_version_23 : 0|40@1+ (1,0) [0|1099511627775] ""  PC
 SG_ M2P_TMS_R_N_S_version_23 : 40|24@1+ (1,0) [0|16777215] ""  PC

BO_ 2337664680 M2P_LiquidInfo_6__24: 8 MBMU
 SG_ M2P_TMS_R_S_version_24 : 0|40@1+ (1,0) [0|1099511627775] ""  PC
 SG_ M2P_TMS_R_N_S_version_24 : 40|24@1+ (1,0) [0|16777215] ""  PC

BO_ 2337664681 M2P_LiquidInfo_6__25: 8 MBMU
 SG_ M2P_TMS_R_S_version_25 : 0|40@1+ (1,0) [0|1099511627775] ""  PC
 SG_ M2P_TMS_R_N_S_version_25 : 40|24@1+ (1,0) [0|16777215] ""  PC

BO_ 2337664682 M2P_LiquidInfo_6__26: 8 MBMU
 SG_ M2P_TMS_R_S_version_26 : 0|40@1+ (1,0) [0|1099511627775] ""  PC
 SG_ M2P_TMS_R_N_S_version_26 : 40|24@1+ (1,0) [0|16777215] ""  PC

BO_ 2337664683 M2P_LiquidInfo_6__27: 8 MBMU
 SG_ M2P_TMS_R_S_version_27 : 0|40@1+ (1,0) [0|1099511627775] ""  PC
 SG_ M2P_TMS_R_N_S_version_27 : 40|24@1+ (1,0) [0|16777215] ""  PC

BO_ 2337664684 M2P_LiquidInfo_6__28: 8 MBMU
 SG_ M2P_TMS_R_S_version_28 : 0|40@1+ (1,0) [0|1099511627775] ""  PC
 SG_ M2P_TMS_R_N_S_version_28 : 40|24@1+ (1,0) [0|16777215] ""  PC

BO_ 2337664685 M2P_LiquidInfo_6__29: 8 MBMU
 SG_ M2P_TMS_R_S_version_29 : 0|40@1+ (1,0) [0|1099511627775] ""  PC
 SG_ M2P_TMS_R_N_S_version_29 : 40|24@1+ (1,0) [0|16777215] ""  PC

BO_ 2337664686 M2P_LiquidInfo_6__30: 8 MBMU
 SG_ M2P_TMS_R_S_version_30 : 0|40@1+ (1,0) [0|1099511627775] ""  PC
 SG_ M2P_TMS_R_N_S_version_30 : 40|24@1+ (1,0) [0|16777215] ""  PC

BO_ 2337664687 M2P_LiquidInfo_6__31: 8 MBMU
 SG_ M2P_TMS_R_S_version_31 : 0|40@1+ (1,0) [0|1099511627775] ""  PC
 SG_ M2P_TMS_R_N_S_version_31 : 40|24@1+ (1,0) [0|16777215] ""  PC

BO_ 2337730193 M2P_LiquidInfo_7__01: 8 MBMU
 SG_ M2P_TMS_L_ACDC_A_vol_01 : 0|8@1+ (1,0) [0|255] "V"  PC
 SG_ M2P_TMS_L_15_pwm_01 : 8|8@1+ (1,0) [0|255] ""  PC
 SG_ M2P_TMS_L_15_HP_01 : 16|16@1+ (1,0) [0|65535] "kpa"  PC
 SG_ M2P_TMS_L_15_LP_01 : 32|16@1+ (1,0) [0|65535] "kpa"  PC
 SG_ M2P_TMS_L_25_HP_01 : 48|16@1+ (1,0) [0|65535] "kpa"  PC

BO_ 2337730194 M2P_LiquidInfo_7__02: 8 MBMU
 SG_ M2P_TMS_L_ACDC_A_vol_02 : 0|8@1+ (1,0) [0|255] "V"  PC
 SG_ M2P_TMS_L_15_pwm_02 : 8|8@1+ (1,0) [0|255] ""  PC
 SG_ M2P_TMS_L_15_HP_02 : 16|16@1+ (1,0) [0|65535] "kpa"  PC
 SG_ M2P_TMS_L_15_LP_02 : 32|16@1+ (1,0) [0|65535] "kpa"  PC
 SG_ M2P_TMS_L_25_HP_02 : 48|16@1+ (1,0) [0|65535] "kpa"  PC

BO_ 2337730195 M2P_LiquidInfo_7__03: 8 MBMU
 SG_ M2P_TMS_L_ACDC_A_vol_03 : 0|8@1+ (1,0) [0|255] "V"  PC
 SG_ M2P_TMS_L_15_pwm_03 : 8|8@1+ (1,0) [0|255] ""  PC
 SG_ M2P_TMS_L_15_HP_03 : 16|16@1+ (1,0) [0|65535] "kpa"  PC
 SG_ M2P_TMS_L_15_LP_03 : 32|16@1+ (1,0) [0|65535] "kpa"  PC
 SG_ M2P_TMS_L_25_HP_03 : 48|16@1+ (1,0) [0|65535] "kpa"  PC

BO_ 2337730196 M2P_LiquidInfo_7__04: 8 MBMU
 SG_ M2P_TMS_L_ACDC_A_vol_04 : 0|8@1+ (1,0) [0|255] "V"  PC
 SG_ M2P_TMS_L_15_pwm_04 : 8|8@1+ (1,0) [0|255] ""  PC
 SG_ M2P_TMS_L_15_HP_04 : 16|16@1+ (1,0) [0|65535] "kpa"  PC
 SG_ M2P_TMS_L_15_LP_04 : 32|16@1+ (1,0) [0|65535] "kpa"  PC
 SG_ M2P_TMS_L_25_HP_04 : 48|16@1+ (1,0) [0|65535] "kpa"  PC

BO_ 2337730197 M2P_LiquidInfo_7__05: 8 MBMU
 SG_ M2P_TMS_L_ACDC_A_vol_05 : 0|8@1+ (1,0) [0|255] "V"  PC
 SG_ M2P_TMS_L_15_pwm_05 : 8|8@1+ (1,0) [0|255] ""  PC
 SG_ M2P_TMS_L_15_HP_05 : 16|16@1+ (1,0) [0|65535] "kpa"  PC
 SG_ M2P_TMS_L_15_LP_05 : 32|16@1+ (1,0) [0|65535] "kpa"  PC
 SG_ M2P_TMS_L_25_HP_05 : 48|16@1+ (1,0) [0|65535] "kpa"  PC

BO_ 2337730198 M2P_LiquidInfo_7__06: 8 MBMU
 SG_ M2P_TMS_L_ACDC_A_vol_06 : 0|8@1+ (1,0) [0|255] "V"  PC
 SG_ M2P_TMS_L_15_pwm_06 : 8|8@1+ (1,0) [0|255] ""  PC
 SG_ M2P_TMS_L_15_HP_06 : 16|16@1+ (1,0) [0|65535] "kpa"  PC
 SG_ M2P_TMS_L_15_LP_06 : 32|16@1+ (1,0) [0|65535] "kpa"  PC
 SG_ M2P_TMS_L_25_HP_06 : 48|16@1+ (1,0) [0|65535] "kpa"  PC

BO_ 2337730199 M2P_LiquidInfo_7__07: 8 MBMU
 SG_ M2P_TMS_L_ACDC_A_vol_07 : 0|8@1+ (1,0) [0|255] "V"  PC
 SG_ M2P_TMS_L_15_pwm_07 : 8|8@1+ (1,0) [0|255] ""  PC
 SG_ M2P_TMS_L_15_HP_07 : 16|16@1+ (1,0) [0|65535] "kpa"  PC
 SG_ M2P_TMS_L_15_LP_07 : 32|16@1+ (1,0) [0|65535] "kpa"  PC
 SG_ M2P_TMS_L_25_HP_07 : 48|16@1+ (1,0) [0|65535] "kpa"  PC

BO_ 2337730200 M2P_LiquidInfo_7__08: 8 MBMU
 SG_ M2P_TMS_L_ACDC_A_vol_08 : 0|8@1+ (1,0) [0|255] "V"  PC
 SG_ M2P_TMS_L_15_pwm_08 : 8|8@1+ (1,0) [0|255] ""  PC
 SG_ M2P_TMS_L_15_HP_08 : 16|16@1+ (1,0) [0|65535] "kpa"  PC
 SG_ M2P_TMS_L_15_LP_08 : 32|16@1+ (1,0) [0|65535] "kpa"  PC
 SG_ M2P_TMS_L_25_HP_08 : 48|16@1+ (1,0) [0|65535] "kpa"  PC

BO_ 2337730201 M2P_LiquidInfo_7__09: 8 MBMU
 SG_ M2P_TMS_L_ACDC_A_vol_09 : 0|8@1+ (1,0) [0|255] "V"  PC
 SG_ M2P_TMS_L_15_pwm_09 : 8|8@1+ (1,0) [0|255] ""  PC
 SG_ M2P_TMS_L_15_HP_09 : 16|16@1+ (1,0) [0|65535] "kpa"  PC
 SG_ M2P_TMS_L_15_LP_09 : 32|16@1+ (1,0) [0|65535] "kpa"  PC
 SG_ M2P_TMS_L_25_HP_09 : 48|16@1+ (1,0) [0|65535] "kpa"  PC

BO_ 2337730202 M2P_LiquidInfo_7__10: 8 MBMU
 SG_ M2P_TMS_L_ACDC_A_vol_10 : 0|8@1+ (1,0) [0|255] "V"  PC
 SG_ M2P_TMS_L_15_pwm_10 : 8|8@1+ (1,0) [0|255] ""  PC
 SG_ M2P_TMS_L_15_HP_10 : 16|16@1+ (1,0) [0|65535] "kpa"  PC
 SG_ M2P_TMS_L_15_LP_10 : 32|16@1+ (1,0) [0|65535] "kpa"  PC
 SG_ M2P_TMS_L_25_HP_10 : 48|16@1+ (1,0) [0|65535] "kpa"  PC

BO_ 2337730203 M2P_LiquidInfo_7__11: 8 MBMU
 SG_ M2P_TMS_L_ACDC_A_vol_11 : 0|8@1+ (1,0) [0|255] "V"  PC
 SG_ M2P_TMS_L_15_pwm_11 : 8|8@1+ (1,0) [0|255] ""  PC
 SG_ M2P_TMS_L_15_HP_11 : 16|16@1+ (1,0) [0|65535] "kpa"  PC
 SG_ M2P_TMS_L_15_LP_11 : 32|16@1+ (1,0) [0|65535] "kpa"  PC
 SG_ M2P_TMS_L_25_HP_11 : 48|16@1+ (1,0) [0|65535] "kpa"  PC

BO_ 2337730204 M2P_LiquidInfo_7__12: 8 MBMU
 SG_ M2P_TMS_L_ACDC_A_vol_12 : 0|8@1+ (1,0) [0|255] "V"  PC
 SG_ M2P_TMS_L_15_pwm_12 : 8|8@1+ (1,0) [0|255] ""  PC
 SG_ M2P_TMS_L_15_HP_12 : 16|16@1+ (1,0) [0|65535] "kpa"  PC
 SG_ M2P_TMS_L_15_LP_12 : 32|16@1+ (1,0) [0|65535] "kpa"  PC
 SG_ M2P_TMS_L_25_HP_12 : 48|16@1+ (1,0) [0|65535] "kpa"  PC

BO_ 2337730205 M2P_LiquidInfo_7__13: 8 MBMU
 SG_ M2P_TMS_L_ACDC_A_vol_13 : 0|8@1+ (1,0) [0|255] "V"  PC
 SG_ M2P_TMS_L_15_pwm_13 : 8|8@1+ (1,0) [0|255] ""  PC
 SG_ M2P_TMS_L_15_HP_13 : 16|16@1+ (1,0) [0|65535] "kpa"  PC
 SG_ M2P_TMS_L_15_LP_13 : 32|16@1+ (1,0) [0|65535] "kpa"  PC
 SG_ M2P_TMS_L_25_HP_13 : 48|16@1+ (1,0) [0|65535] "kpa"  PC

BO_ 2337730206 M2P_LiquidInfo_7__14: 8 MBMU
 SG_ M2P_TMS_L_ACDC_A_vol_14 : 0|8@1+ (1,0) [0|255] "V"  PC
 SG_ M2P_TMS_L_15_pwm_14 : 8|8@1+ (1,0) [0|255] ""  PC
 SG_ M2P_TMS_L_15_HP_14 : 16|16@1+ (1,0) [0|65535] "kpa"  PC
 SG_ M2P_TMS_L_15_LP_14 : 32|16@1+ (1,0) [0|65535] "kpa"  PC
 SG_ M2P_TMS_L_25_HP_14 : 48|16@1+ (1,0) [0|65535] "kpa"  PC

BO_ 2337730207 M2P_LiquidInfo_7__15: 8 MBMU
 SG_ M2P_TMS_L_ACDC_A_vol_15 : 0|8@1+ (1,0) [0|255] "V"  PC
 SG_ M2P_TMS_L_15_pwm_15 : 8|8@1+ (1,0) [0|255] ""  PC
 SG_ M2P_TMS_L_15_HP_15 : 16|16@1+ (1,0) [0|65535] "kpa"  PC
 SG_ M2P_TMS_L_15_LP_15 : 32|16@1+ (1,0) [0|65535] "kpa"  PC
 SG_ M2P_TMS_L_25_HP_15 : 48|16@1+ (1,0) [0|65535] "kpa"  PC

BO_ 2337730208 M2P_LiquidInfo_7__16: 8 MBMU
 SG_ M2P_TMS_L_ACDC_A_vol_16 : 0|8@1+ (1,0) [0|255] "V"  PC
 SG_ M2P_TMS_L_15_pwm_16 : 8|8@1+ (1,0) [0|255] ""  PC
 SG_ M2P_TMS_L_15_HP_16 : 16|16@1+ (1,0) [0|65535] "kpa"  PC
 SG_ M2P_TMS_L_15_LP_16 : 32|16@1+ (1,0) [0|65535] "kpa"  PC
 SG_ M2P_TMS_L_25_HP_16 : 48|16@1+ (1,0) [0|65535] "kpa"  PC

BO_ 2337730209 M2P_LiquidInfo_7__17: 8 MBMU
 SG_ M2P_TMS_L_ACDC_A_vol_17 : 0|8@1+ (1,0) [0|255] "V"  PC
 SG_ M2P_TMS_L_15_pwm_17 : 8|8@1+ (1,0) [0|255] ""  PC
 SG_ M2P_TMS_L_15_HP_17 : 16|16@1+ (1,0) [0|65535] "kpa"  PC
 SG_ M2P_TMS_L_15_LP_17 : 32|16@1+ (1,0) [0|65535] "kpa"  PC
 SG_ M2P_TMS_L_25_HP_17 : 48|16@1+ (1,0) [0|65535] "kpa"  PC

BO_ 2337730210 M2P_LiquidInfo_7__18: 8 MBMU
 SG_ M2P_TMS_L_ACDC_A_vol_18 : 0|8@1+ (1,0) [0|255] "V"  PC
 SG_ M2P_TMS_L_15_pwm_18 : 8|8@1+ (1,0) [0|255] ""  PC
 SG_ M2P_TMS_L_15_HP_18 : 16|16@1+ (1,0) [0|65535] "kpa"  PC
 SG_ M2P_TMS_L_15_LP_18 : 32|16@1+ (1,0) [0|65535] "kpa"  PC
 SG_ M2P_TMS_L_25_HP_18 : 48|16@1+ (1,0) [0|65535] "kpa"  PC

BO_ 2337730211 M2P_LiquidInfo_7__19: 8 MBMU
 SG_ M2P_TMS_L_ACDC_A_vol_19 : 0|8@1+ (1,0) [0|255] "V"  PC
 SG_ M2P_TMS_L_15_pwm_19 : 8|8@1+ (1,0) [0|255] ""  PC
 SG_ M2P_TMS_L_15_HP_19 : 16|16@1+ (1,0) [0|65535] "kpa"  PC
 SG_ M2P_TMS_L_15_LP_19 : 32|16@1+ (1,0) [0|65535] "kpa"  PC
 SG_ M2P_TMS_L_25_HP_19 : 48|16@1+ (1,0) [0|65535] "kpa"  PC

BO_ 2337730212 M2P_LiquidInfo_7__20: 8 MBMU
 SG_ M2P_TMS_L_ACDC_A_vol_20 : 0|8@1+ (1,0) [0|255] "V"  PC
 SG_ M2P_TMS_L_15_pwm_20 : 8|8@1+ (1,0) [0|255] ""  PC
 SG_ M2P_TMS_L_15_HP_20 : 16|16@1+ (1,0) [0|65535] "kpa"  PC
 SG_ M2P_TMS_L_15_LP_20 : 32|16@1+ (1,0) [0|65535] "kpa"  PC
 SG_ M2P_TMS_L_25_HP_20 : 48|16@1+ (1,0) [0|65535] "kpa"  PC

BO_ 2337730213 M2P_LiquidInfo_7__21: 8 MBMU
 SG_ M2P_TMS_L_ACDC_A_vol_21 : 0|8@1+ (1,0) [0|255] "V"  PC
 SG_ M2P_TMS_L_15_pwm_21 : 8|8@1+ (1,0) [0|255] ""  PC
 SG_ M2P_TMS_L_15_HP_21 : 16|16@1+ (1,0) [0|65535] "kpa"  PC
 SG_ M2P_TMS_L_15_LP_21 : 32|16@1+ (1,0) [0|65535] "kpa"  PC
 SG_ M2P_TMS_L_25_HP_21 : 48|16@1+ (1,0) [0|65535] "kpa"  PC

BO_ 2337730214 M2P_LiquidInfo_7__22: 8 MBMU
 SG_ M2P_TMS_L_ACDC_A_vol_22 : 0|8@1+ (1,0) [0|255] "V"  PC
 SG_ M2P_TMS_L_15_pwm_22 : 8|8@1+ (1,0) [0|255] ""  PC
 SG_ M2P_TMS_L_15_HP_22 : 16|16@1+ (1,0) [0|65535] "kpa"  PC
 SG_ M2P_TMS_L_15_LP_22 : 32|16@1+ (1,0) [0|65535] "kpa"  PC
 SG_ M2P_TMS_L_25_HP_22 : 48|16@1+ (1,0) [0|65535] "kpa"  PC

BO_ 2337730215 M2P_LiquidInfo_7__23: 8 MBMU
 SG_ M2P_TMS_L_ACDC_A_vol_23 : 0|8@1+ (1,0) [0|255] "V"  PC
 SG_ M2P_TMS_L_15_pwm_23 : 8|8@1+ (1,0) [0|255] ""  PC
 SG_ M2P_TMS_L_15_HP_23 : 16|16@1+ (1,0) [0|65535] "kpa"  PC
 SG_ M2P_TMS_L_15_LP_23 : 32|16@1+ (1,0) [0|65535] "kpa"  PC
 SG_ M2P_TMS_L_25_HP_23 : 48|16@1+ (1,0) [0|65535] "kpa"  PC

BO_ 2337730216 M2P_LiquidInfo_7__24: 8 MBMU
 SG_ M2P_TMS_L_ACDC_A_vol_24 : 0|8@1+ (1,0) [0|255] "V"  PC
 SG_ M2P_TMS_L_15_pwm_24 : 8|8@1+ (1,0) [0|255] ""  PC
 SG_ M2P_TMS_L_15_HP_24 : 16|16@1+ (1,0) [0|65535] "kpa"  PC
 SG_ M2P_TMS_L_15_LP_24 : 32|16@1+ (1,0) [0|65535] "kpa"  PC
 SG_ M2P_TMS_L_25_HP_24 : 48|16@1+ (1,0) [0|65535] "kpa"  PC

BO_ 2337730217 M2P_LiquidInfo_7__25: 8 MBMU
 SG_ M2P_TMS_L_ACDC_A_vol_25 : 0|8@1+ (1,0) [0|255] "V"  PC
 SG_ M2P_TMS_L_15_pwm_25 : 8|8@1+ (1,0) [0|255] ""  PC
 SG_ M2P_TMS_L_15_HP_25 : 16|16@1+ (1,0) [0|65535] "kpa"  PC
 SG_ M2P_TMS_L_15_LP_25 : 32|16@1+ (1,0) [0|65535] "kpa"  PC
 SG_ M2P_TMS_L_25_HP_25 : 48|16@1+ (1,0) [0|65535] "kpa"  PC

BO_ 2337730218 M2P_LiquidInfo_7__26: 8 MBMU
 SG_ M2P_TMS_L_ACDC_A_vol_26 : 0|8@1+ (1,0) [0|255] "V"  PC
 SG_ M2P_TMS_L_15_pwm_26 : 8|8@1+ (1,0) [0|255] ""  PC
 SG_ M2P_TMS_L_15_HP_26 : 16|16@1+ (1,0) [0|65535] "kpa"  PC
 SG_ M2P_TMS_L_15_LP_26 : 32|16@1+ (1,0) [0|65535] "kpa"  PC
 SG_ M2P_TMS_L_25_HP_26 : 48|16@1+ (1,0) [0|65535] "kpa"  PC

BO_ 2337730219 M2P_LiquidInfo_7__27: 8 MBMU
 SG_ M2P_TMS_L_ACDC_A_vol_27 : 0|8@1+ (1,0) [0|255] "V"  PC
 SG_ M2P_TMS_L_15_pwm_27 : 8|8@1+ (1,0) [0|255] ""  PC
 SG_ M2P_TMS_L_15_HP_27 : 16|16@1+ (1,0) [0|65535] "kpa"  PC
 SG_ M2P_TMS_L_15_LP_27 : 32|16@1+ (1,0) [0|65535] "kpa"  PC
 SG_ M2P_TMS_L_25_HP_27 : 48|16@1+ (1,0) [0|65535] "kpa"  PC

BO_ 2337730220 M2P_LiquidInfo_7__28: 8 MBMU
 SG_ M2P_TMS_L_ACDC_A_vol_28 : 0|8@1+ (1,0) [0|255] "V"  PC
 SG_ M2P_TMS_L_15_pwm_28 : 8|8@1+ (1,0) [0|255] ""  PC
 SG_ M2P_TMS_L_15_HP_28 : 16|16@1+ (1,0) [0|65535] "kpa"  PC
 SG_ M2P_TMS_L_15_LP_28 : 32|16@1+ (1,0) [0|65535] "kpa"  PC
 SG_ M2P_TMS_L_25_HP_28 : 48|16@1+ (1,0) [0|65535] "kpa"  PC

BO_ 2337730221 M2P_LiquidInfo_7__29: 8 MBMU
 SG_ M2P_TMS_L_ACDC_A_vol_29 : 0|8@1+ (1,0) [0|255] "V"  PC
 SG_ M2P_TMS_L_15_pwm_29 : 8|8@1+ (1,0) [0|255] ""  PC
 SG_ M2P_TMS_L_15_HP_29 : 16|16@1+ (1,0) [0|65535] "kpa"  PC
 SG_ M2P_TMS_L_15_LP_29 : 32|16@1+ (1,0) [0|65535] "kpa"  PC
 SG_ M2P_TMS_L_25_HP_29 : 48|16@1+ (1,0) [0|65535] "kpa"  PC

BO_ 2337730222 M2P_LiquidInfo_7__30: 8 MBMU
 SG_ M2P_TMS_L_ACDC_A_vol_30 : 0|8@1+ (1,0) [0|255] "V"  PC
 SG_ M2P_TMS_L_15_pwm_30 : 8|8@1+ (1,0) [0|255] ""  PC
 SG_ M2P_TMS_L_15_HP_30 : 16|16@1+ (1,0) [0|65535] "kpa"  PC
 SG_ M2P_TMS_L_15_LP_30 : 32|16@1+ (1,0) [0|65535] "kpa"  PC
 SG_ M2P_TMS_L_25_HP_30 : 48|16@1+ (1,0) [0|65535] "kpa"  PC

BO_ 2337730223 M2P_LiquidInfo_7__31: 8 MBMU
 SG_ M2P_TMS_L_ACDC_A_vol_31 : 0|8@1+ (1,0) [0|255] "V"  PC
 SG_ M2P_TMS_L_15_pwm_31 : 8|8@1+ (1,0) [0|255] ""  PC
 SG_ M2P_TMS_L_15_HP_31 : 16|16@1+ (1,0) [0|65535] "kpa"  PC
 SG_ M2P_TMS_L_15_LP_31 : 32|16@1+ (1,0) [0|65535] "kpa"  PC
 SG_ M2P_TMS_L_25_HP_31 : 48|16@1+ (1,0) [0|65535] "kpa"  PC

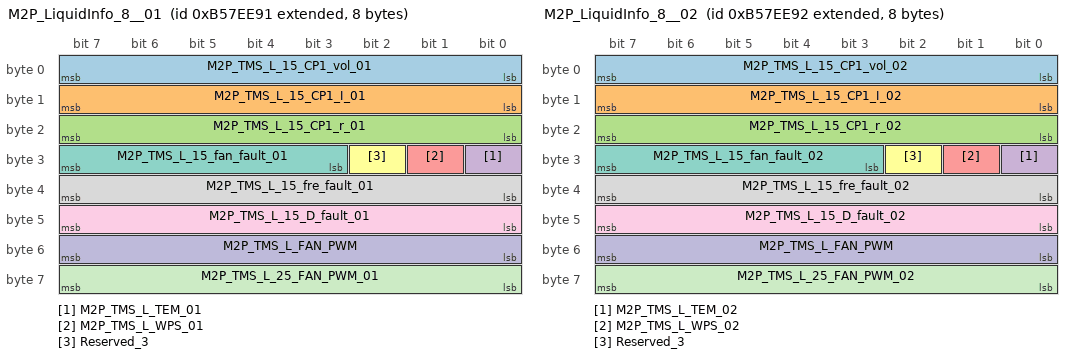
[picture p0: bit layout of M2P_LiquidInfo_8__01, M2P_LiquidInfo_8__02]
BO_ 2337795729 M2P_LiquidInfo_8__01: 8 MBMU
 SG_ M2P_TMS_L_15_CP1_vol_01 : 0|8@1+ (2,0) [0|510] "V"  PC
 SG_ M2P_TMS_L_15_CP1_I_01 : 8|8@1+ (1,0) [0|255] "A"  PC
 SG_ M2P_TMS_L_15_CP1_r_01 : 16|8@1+ (100,0) [0|25500] "rpm"  PC
 SG_ M2P_TMS_L_TEM_01 : 24|1@1+ (1,0) [0|1] ""  PC
 SG_ M2P_TMS_L_WPS_01 : 25|1@1+ (1,0) [0|1] ""  PC
 SG_ Reserved_3 : 26|1@1+ (1,0) [0|1] ""  PC
 SG_ M2P_TMS_L_15_fan_fault_01 : 27|5@1+ (1,0) [0|31] ""  PC
 SG_ M2P_TMS_L_15_fre_fault_01 : 32|8@1+ (1,0) [0|255] ""  PC
 SG_ M2P_TMS_L_15_D_fault_01 : 40|8@1+ (1,0) [0|255] ""  PC
 SG_ M2P_TMS_L_FAN_PWM : 48|8@1+ (1,0) [0|255] ""  PC
 SG_ M2P_TMS_L_25_FAN_PWM_01 : 56|8@1+ (1,0) [0|255] ""  PC

BO_ 2337795730 M2P_LiquidInfo_8__02: 8 MBMU
 SG_ M2P_TMS_L_15_CP1_vol_02 : 0|8@1+ (2,0) [0|510] "V"  PC
 SG_ M2P_TMS_L_15_CP1_I_02 : 8|8@1+ (1,0) [0|255] "A"  PC
 SG_ M2P_TMS_L_15_CP1_r_02 : 16|8@1+ (100,0) [0|25500] "rpm"  PC
 SG_ M2P_TMS_L_TEM_02 : 24|1@1+ (1,0) [0|1] ""  PC
 SG_ M2P_TMS_L_WPS_02 : 25|1@1+ (1,0) [0|1] ""  PC
 SG_ Reserved_3 : 26|1@1+ (1,0) [0|1] ""  PC
 SG_ M2P_TMS_L_15_fan_fault_02 : 27|5@1+ (1,0) [0|31] ""  PC
 SG_ M2P_TMS_L_15_fre_fault_02 : 32|8@1+ (1,0) [0|255] ""  PC
 SG_ M2P_TMS_L_15_D_fault_02 : 40|8@1+ (1,0) [0|255] ""  PC
 SG_ M2P_TMS_L_FAN_PWM : 48|8@1+ (1,0) [0|255] ""  PC
 SG_ M2P_TMS_L_25_FAN_PWM_02 : 56|8@1+ (1,0) [0|255] ""  PC

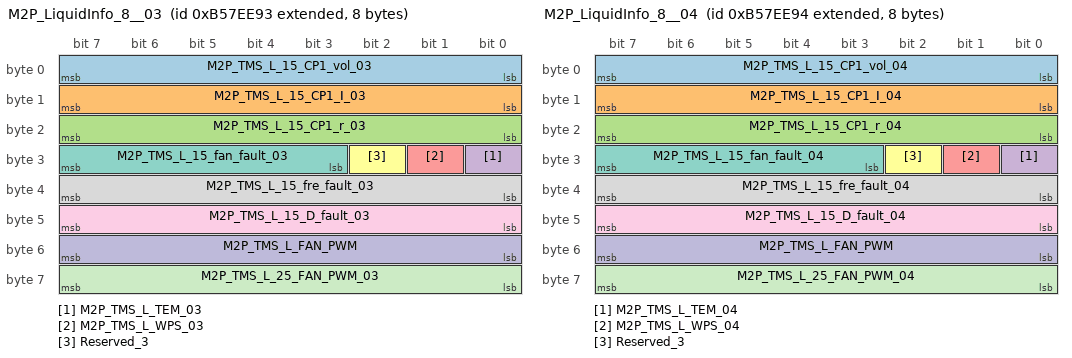
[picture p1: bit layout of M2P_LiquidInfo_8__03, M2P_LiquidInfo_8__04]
BO_ 2337795731 M2P_LiquidInfo_8__03: 8 MBMU
 SG_ M2P_TMS_L_15_CP1_vol_03 : 0|8@1+ (2,0) [0|510] "V"  PC
 SG_ M2P_TMS_L_15_CP1_I_03 : 8|8@1+ (1,0) [0|255] "A"  PC
 SG_ M2P_TMS_L_15_CP1_r_03 : 16|8@1+ (100,0) [0|25500] "rpm"  PC
 SG_ M2P_TMS_L_TEM_03 : 24|1@1+ (1,0) [0|1] ""  PC
 SG_ M2P_TMS_L_WPS_03 : 25|1@1+ (1,0) [0|1] ""  PC
 SG_ Reserved_3 : 26|1@1+ (1,0) [0|1] ""  PC
 SG_ M2P_TMS_L_15_fan_fault_03 : 27|5@1+ (1,0) [0|31] ""  PC
 SG_ M2P_TMS_L_15_fre_fault_03 : 32|8@1+ (1,0) [0|255] ""  PC
 SG_ M2P_TMS_L_15_D_fault_03 : 40|8@1+ (1,0) [0|255] ""  PC
 SG_ M2P_TMS_L_FAN_PWM : 48|8@1+ (1,0) [0|255] ""  PC
 SG_ M2P_TMS_L_25_FAN_PWM_03 : 56|8@1+ (1,0) [0|255] ""  PC

BO_ 2337795732 M2P_LiquidInfo_8__04: 8 MBMU
 SG_ M2P_TMS_L_15_CP1_vol_04 : 0|8@1+ (2,0) [0|510] "V"  PC
 SG_ M2P_TMS_L_15_CP1_I_04 : 8|8@1+ (1,0) [0|255] "A"  PC
 SG_ M2P_TMS_L_15_CP1_r_04 : 16|8@1+ (100,0) [0|25500] "rpm"  PC
 SG_ M2P_TMS_L_TEM_04 : 24|1@1+ (1,0) [0|1] ""  PC
 SG_ M2P_TMS_L_WPS_04 : 25|1@1+ (1,0) [0|1] ""  PC
 SG_ Reserved_3 : 26|1@1+ (1,0) [0|1] ""  PC
 SG_ M2P_TMS_L_15_fan_fault_04 : 27|5@1+ (1,0) [0|31] ""  PC
 SG_ M2P_TMS_L_15_fre_fault_04 : 32|8@1+ (1,0) [0|255] ""  PC
 SG_ M2P_TMS_L_15_D_fault_04 : 40|8@1+ (1,0) [0|255] ""  PC
 SG_ M2P_TMS_L_FAN_PWM : 48|8@1+ (1,0) [0|255] ""  PC
 SG_ M2P_TMS_L_25_FAN_PWM_04 : 56|8@1+ (1,0) [0|255] ""  PC

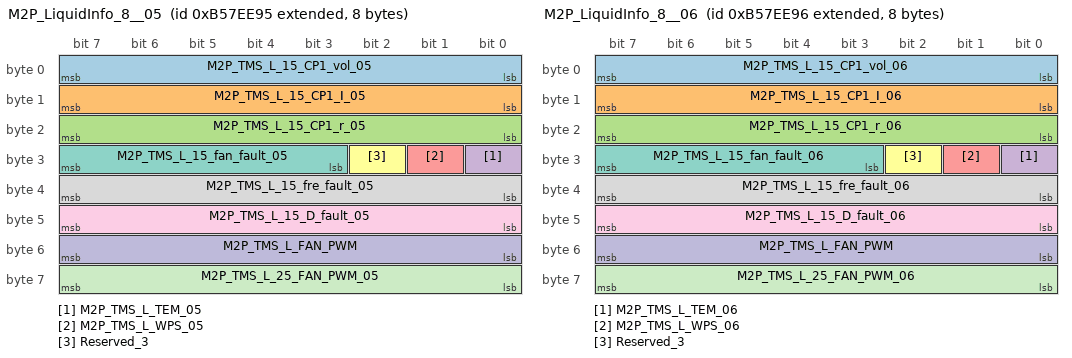
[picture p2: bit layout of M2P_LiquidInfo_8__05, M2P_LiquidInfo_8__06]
BO_ 2337795733 M2P_LiquidInfo_8__05: 8 MBMU
 SG_ M2P_TMS_L_15_CP1_vol_05 : 0|8@1+ (2,0) [0|510] "V"  PC
 SG_ M2P_TMS_L_15_CP1_I_05 : 8|8@1+ (1,0) [0|255] "A"  PC
 SG_ M2P_TMS_L_15_CP1_r_05 : 16|8@1+ (100,0) [0|25500] "rpm"  PC
 SG_ M2P_TMS_L_TEM_05 : 24|1@1+ (1,0) [0|1] ""  PC
 SG_ M2P_TMS_L_WPS_05 : 25|1@1+ (1,0) [0|1] ""  PC
 SG_ Reserved_3 : 26|1@1+ (1,0) [0|1] ""  PC
 SG_ M2P_TMS_L_15_fan_fault_05 : 27|5@1+ (1,0) [0|31] ""  PC
 SG_ M2P_TMS_L_15_fre_fault_05 : 32|8@1+ (1,0) [0|255] ""  PC
 SG_ M2P_TMS_L_15_D_fault_05 : 40|8@1+ (1,0) [0|255] ""  PC
 SG_ M2P_TMS_L_FAN_PWM : 48|8@1+ (1,0) [0|255] ""  PC
 SG_ M2P_TMS_L_25_FAN_PWM_05 : 56|8@1+ (1,0) [0|255] ""  PC

BO_ 2337795734 M2P_LiquidInfo_8__06: 8 MBMU
 SG_ M2P_TMS_L_15_CP1_vol_06 : 0|8@1+ (2,0) [0|510] "V"  PC
 SG_ M2P_TMS_L_15_CP1_I_06 : 8|8@1+ (1,0) [0|255] "A"  PC
 SG_ M2P_TMS_L_15_CP1_r_06 : 16|8@1+ (100,0) [0|25500] "rpm"  PC
 SG_ M2P_TMS_L_TEM_06 : 24|1@1+ (1,0) [0|1] ""  PC
 SG_ M2P_TMS_L_WPS_06 : 25|1@1+ (1,0) [0|1] ""  PC
 SG_ Reserved_3 : 26|1@1+ (1,0) [0|1] ""  PC
 SG_ M2P_TMS_L_15_fan_fault_06 : 27|5@1+ (1,0) [0|31] ""  PC
 SG_ M2P_TMS_L_15_fre_fault_06 : 32|8@1+ (1,0) [0|255] ""  PC
 SG_ M2P_TMS_L_15_D_fault_06 : 40|8@1+ (1,0) [0|255] ""  PC
 SG_ M2P_TMS_L_FAN_PWM : 48|8@1+ (1,0) [0|255] ""  PC
 SG_ M2P_TMS_L_25_FAN_PWM_06 : 56|8@1+ (1,0) [0|255] ""  PC

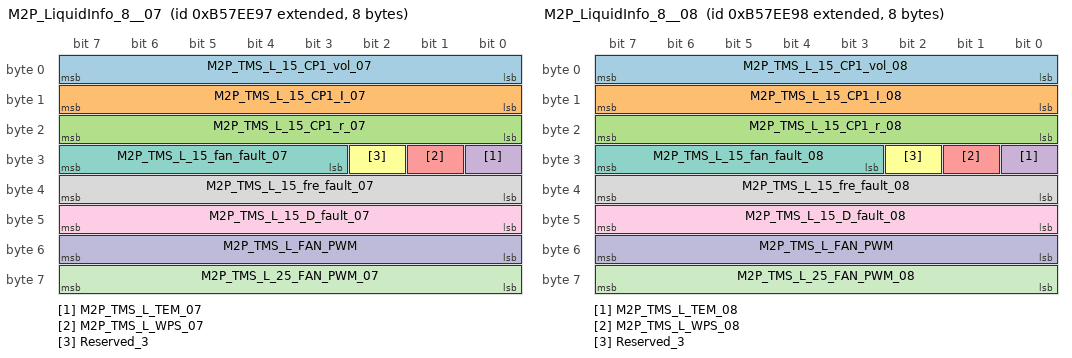
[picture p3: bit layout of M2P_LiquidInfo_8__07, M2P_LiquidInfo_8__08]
BO_ 2337795735 M2P_LiquidInfo_8__07: 8 MBMU
 SG_ M2P_TMS_L_15_CP1_vol_07 : 0|8@1+ (2,0) [0|510] "V"  PC
 SG_ M2P_TMS_L_15_CP1_I_07 : 8|8@1+ (1,0) [0|255] "A"  PC
 SG_ M2P_TMS_L_15_CP1_r_07 : 16|8@1+ (100,0) [0|25500] "rpm"  PC
 SG_ M2P_TMS_L_TEM_07 : 24|1@1+ (1,0) [0|1] ""  PC
 SG_ M2P_TMS_L_WPS_07 : 25|1@1+ (1,0) [0|1] ""  PC
 SG_ Reserved_3 : 26|1@1+ (1,0) [0|1] ""  PC
 SG_ M2P_TMS_L_15_fan_fault_07 : 27|5@1+ (1,0) [0|31] ""  PC
 SG_ M2P_TMS_L_15_fre_fault_07 : 32|8@1+ (1,0) [0|255] ""  PC
 SG_ M2P_TMS_L_15_D_fault_07 : 40|8@1+ (1,0) [0|255] ""  PC
 SG_ M2P_TMS_L_FAN_PWM : 48|8@1+ (1,0) [0|255] ""  PC
 SG_ M2P_TMS_L_25_FAN_PWM_07 : 56|8@1+ (1,0) [0|255] ""  PC

BO_ 2337795736 M2P_LiquidInfo_8__08: 8 MBMU
 SG_ M2P_TMS_L_15_CP1_vol_08 : 0|8@1+ (2,0) [0|510] "V"  PC
 SG_ M2P_TMS_L_15_CP1_I_08 : 8|8@1+ (1,0) [0|255] "A"  PC
 SG_ M2P_TMS_L_15_CP1_r_08 : 16|8@1+ (100,0) [0|25500] "rpm"  PC
 SG_ M2P_TMS_L_TEM_08 : 24|1@1+ (1,0) [0|1] ""  PC
 SG_ M2P_TMS_L_WPS_08 : 25|1@1+ (1,0) [0|1] ""  PC
 SG_ Reserved_3 : 26|1@1+ (1,0) [0|1] ""  PC
 SG_ M2P_TMS_L_15_fan_fault_08 : 27|5@1+ (1,0) [0|31] ""  PC
 SG_ M2P_TMS_L_15_fre_fault_08 : 32|8@1+ (1,0) [0|255] ""  PC
 SG_ M2P_TMS_L_15_D_fault_08 : 40|8@1+ (1,0) [0|255] ""  PC
 SG_ M2P_TMS_L_FAN_PWM : 48|8@1+ (1,0) [0|255] ""  PC
 SG_ M2P_TMS_L_25_FAN_PWM_08 : 56|8@1+ (1,0) [0|255] ""  PC

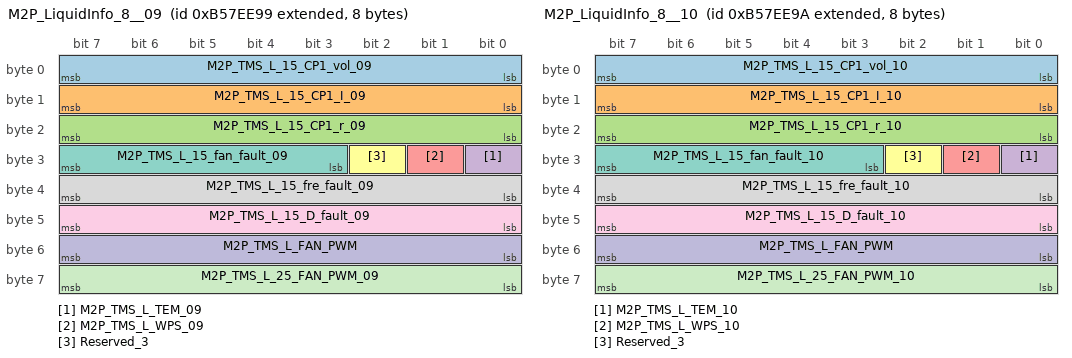
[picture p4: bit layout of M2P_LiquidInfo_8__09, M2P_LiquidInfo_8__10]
BO_ 2337795737 M2P_LiquidInfo_8__09: 8 MBMU
 SG_ M2P_TMS_L_15_CP1_vol_09 : 0|8@1+ (2,0) [0|510] "V"  PC
 SG_ M2P_TMS_L_15_CP1_I_09 : 8|8@1+ (1,0) [0|255] "A"  PC
 SG_ M2P_TMS_L_15_CP1_r_09 : 16|8@1+ (100,0) [0|25500] "rpm"  PC
 SG_ M2P_TMS_L_TEM_09 : 24|1@1+ (1,0) [0|1] ""  PC
 SG_ M2P_TMS_L_WPS_09 : 25|1@1+ (1,0) [0|1] ""  PC
 SG_ Reserved_3 : 26|1@1+ (1,0) [0|1] ""  PC
 SG_ M2P_TMS_L_15_fan_fault_09 : 27|5@1+ (1,0) [0|31] ""  PC
 SG_ M2P_TMS_L_15_fre_fault_09 : 32|8@1+ (1,0) [0|255] ""  PC
 SG_ M2P_TMS_L_15_D_fault_09 : 40|8@1+ (1,0) [0|255] ""  PC
 SG_ M2P_TMS_L_FAN_PWM : 48|8@1+ (1,0) [0|255] ""  PC
 SG_ M2P_TMS_L_25_FAN_PWM_09 : 56|8@1+ (1,0) [0|255] ""  PC

BO_ 2337795738 M2P_LiquidInfo_8__10: 8 MBMU
 SG_ M2P_TMS_L_15_CP1_vol_10 : 0|8@1+ (2,0) [0|510] "V"  PC
 SG_ M2P_TMS_L_15_CP1_I_10 : 8|8@1+ (1,0) [0|255] "A"  PC
 SG_ M2P_TMS_L_15_CP1_r_10 : 16|8@1+ (100,0) [0|25500] "rpm"  PC
 SG_ M2P_TMS_L_TEM_10 : 24|1@1+ (1,0) [0|1] ""  PC
 SG_ M2P_TMS_L_WPS_10 : 25|1@1+ (1,0) [0|1] ""  PC
 SG_ Reserved_3 : 26|1@1+ (1,0) [0|1] ""  PC
 SG_ M2P_TMS_L_15_fan_fault_10 : 27|5@1+ (1,0) [0|31] ""  PC
 SG_ M2P_TMS_L_15_fre_fault_10 : 32|8@1+ (1,0) [0|255] ""  PC
 SG_ M2P_TMS_L_15_D_fault_10 : 40|8@1+ (1,0) [0|255] ""  PC
 SG_ M2P_TMS_L_FAN_PWM : 48|8@1+ (1,0) [0|255] ""  PC
 SG_ M2P_TMS_L_25_FAN_PWM_10 : 56|8@1+ (1,0) [0|255] ""  PC

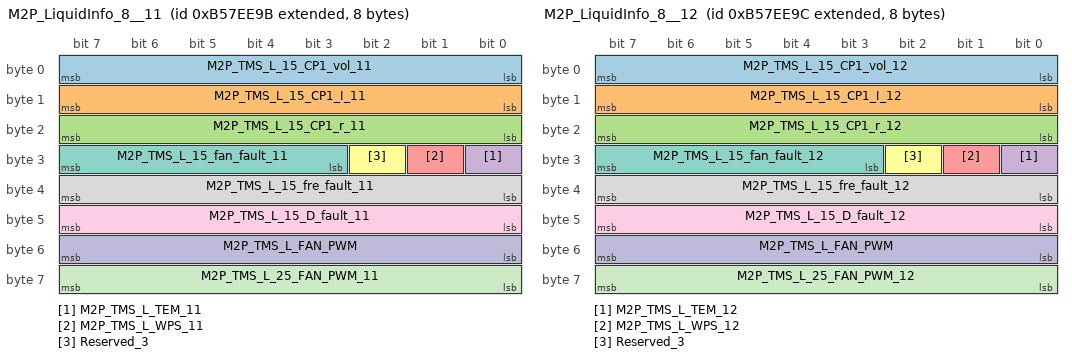
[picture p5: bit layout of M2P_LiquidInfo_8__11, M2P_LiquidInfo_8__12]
BO_ 2337795739 M2P_LiquidInfo_8__11: 8 MBMU
 SG_ M2P_TMS_L_15_CP1_vol_11 : 0|8@1+ (2,0) [0|510] "V"  PC
 SG_ M2P_TMS_L_15_CP1_I_11 : 8|8@1+ (1,0) [0|255] "A"  PC
 SG_ M2P_TMS_L_15_CP1_r_11 : 16|8@1+ (100,0) [0|25500] "rpm"  PC
 SG_ M2P_TMS_L_TEM_11 : 24|1@1+ (1,0) [0|1] ""  PC
 SG_ M2P_TMS_L_WPS_11 : 25|1@1+ (1,0) [0|1] ""  PC
 SG_ Reserved_3 : 26|1@1+ (1,0) [0|1] ""  PC
 SG_ M2P_TMS_L_15_fan_fault_11 : 27|5@1+ (1,0) [0|31] ""  PC
 SG_ M2P_TMS_L_15_fre_fault_11 : 32|8@1+ (1,0) [0|255] ""  PC
 SG_ M2P_TMS_L_15_D_fault_11 : 40|8@1+ (1,0) [0|255] ""  PC
 SG_ M2P_TMS_L_FAN_PWM : 48|8@1+ (1,0) [0|255] ""  PC
 SG_ M2P_TMS_L_25_FAN_PWM_11 : 56|8@1+ (1,0) [0|255] ""  PC

BO_ 2337795740 M2P_LiquidInfo_8__12: 8 MBMU
 SG_ M2P_TMS_L_15_CP1_vol_12 : 0|8@1+ (2,0) [0|510] "V"  PC
 SG_ M2P_TMS_L_15_CP1_I_12 : 8|8@1+ (1,0) [0|255] "A"  PC
 SG_ M2P_TMS_L_15_CP1_r_12 : 16|8@1+ (100,0) [0|25500] "rpm"  PC
 SG_ M2P_TMS_L_TEM_12 : 24|1@1+ (1,0) [0|1] ""  PC
 SG_ M2P_TMS_L_WPS_12 : 25|1@1+ (1,0) [0|1] ""  PC
 SG_ Reserved_3 : 26|1@1+ (1,0) [0|1] ""  PC
 SG_ M2P_TMS_L_15_fan_fault_12 : 27|5@1+ (1,0) [0|31] ""  PC
 SG_ M2P_TMS_L_15_fre_fault_12 : 32|8@1+ (1,0) [0|255] ""  PC
 SG_ M2P_TMS_L_15_D_fault_12 : 40|8@1+ (1,0) [0|255] ""  PC
 SG_ M2P_TMS_L_FAN_PWM : 48|8@1+ (1,0) [0|255] ""  PC
 SG_ M2P_TMS_L_25_FAN_PWM_12 : 56|8@1+ (1,0) [0|255] ""  PC

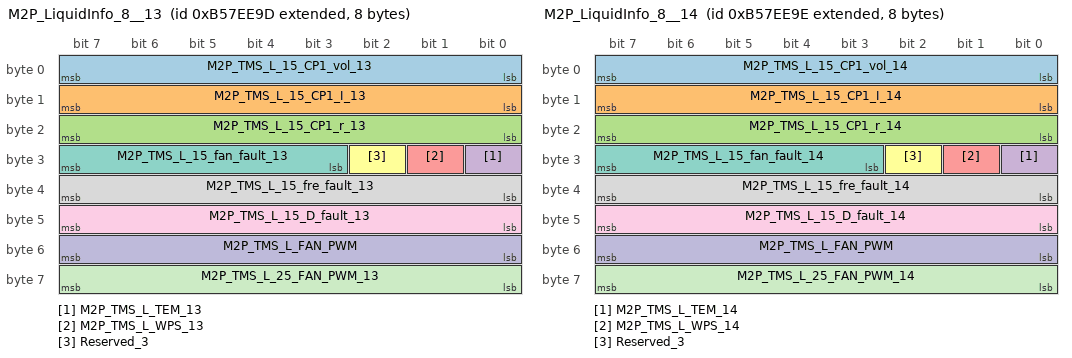
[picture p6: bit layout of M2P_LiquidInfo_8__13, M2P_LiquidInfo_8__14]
BO_ 2337795741 M2P_LiquidInfo_8__13: 8 MBMU
 SG_ M2P_TMS_L_15_CP1_vol_13 : 0|8@1+ (2,0) [0|510] "V"  PC
 SG_ M2P_TMS_L_15_CP1_I_13 : 8|8@1+ (1,0) [0|255] "A"  PC
 SG_ M2P_TMS_L_15_CP1_r_13 : 16|8@1+ (100,0) [0|25500] "rpm"  PC
 SG_ M2P_TMS_L_TEM_13 : 24|1@1+ (1,0) [0|1] ""  PC
 SG_ M2P_TMS_L_WPS_13 : 25|1@1+ (1,0) [0|1] ""  PC
 SG_ Reserved_3 : 26|1@1+ (1,0) [0|1] ""  PC
 SG_ M2P_TMS_L_15_fan_fault_13 : 27|5@1+ (1,0) [0|31] ""  PC
 SG_ M2P_TMS_L_15_fre_fault_13 : 32|8@1+ (1,0) [0|255] ""  PC
 SG_ M2P_TMS_L_15_D_fault_13 : 40|8@1+ (1,0) [0|255] ""  PC
 SG_ M2P_TMS_L_FAN_PWM : 48|8@1+ (1,0) [0|255] ""  PC
 SG_ M2P_TMS_L_25_FAN_PWM_13 : 56|8@1+ (1,0) [0|255] ""  PC

BO_ 2337795742 M2P_LiquidInfo_8__14: 8 MBMU
 SG_ M2P_TMS_L_15_CP1_vol_14 : 0|8@1+ (2,0) [0|510] "V"  PC
 SG_ M2P_TMS_L_15_CP1_I_14 : 8|8@1+ (1,0) [0|255] "A"  PC
 SG_ M2P_TMS_L_15_CP1_r_14 : 16|8@1+ (100,0) [0|25500] "rpm"  PC
 SG_ M2P_TMS_L_TEM_14 : 24|1@1+ (1,0) [0|1] ""  PC
 SG_ M2P_TMS_L_WPS_14 : 25|1@1+ (1,0) [0|1] ""  PC
 SG_ Reserved_3 : 26|1@1+ (1,0) [0|1] ""  PC
 SG_ M2P_TMS_L_15_fan_fault_14 : 27|5@1+ (1,0) [0|31] ""  PC
 SG_ M2P_TMS_L_15_fre_fault_14 : 32|8@1+ (1,0) [0|255] ""  PC
 SG_ M2P_TMS_L_15_D_fault_14 : 40|8@1+ (1,0) [0|255] ""  PC
 SG_ M2P_TMS_L_FAN_PWM : 48|8@1+ (1,0) [0|255] ""  PC
 SG_ M2P_TMS_L_25_FAN_PWM_14 : 56|8@1+ (1,0) [0|255] ""  PC

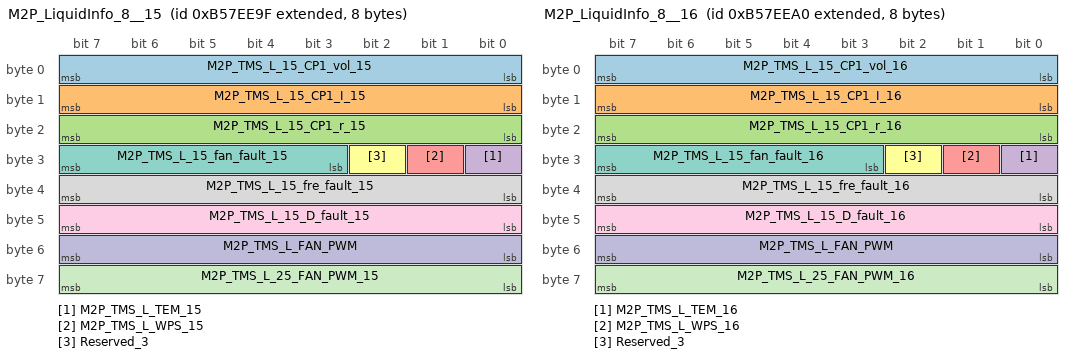
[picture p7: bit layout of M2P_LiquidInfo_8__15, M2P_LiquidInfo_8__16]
BO_ 2337795743 M2P_LiquidInfo_8__15: 8 MBMU
 SG_ M2P_TMS_L_15_CP1_vol_15 : 0|8@1+ (2,0) [0|510] "V"  PC
 SG_ M2P_TMS_L_15_CP1_I_15 : 8|8@1+ (1,0) [0|255] "A"  PC
 SG_ M2P_TMS_L_15_CP1_r_15 : 16|8@1+ (100,0) [0|25500] "rpm"  PC
 SG_ M2P_TMS_L_TEM_15 : 24|1@1+ (1,0) [0|1] ""  PC
 SG_ M2P_TMS_L_WPS_15 : 25|1@1+ (1,0) [0|1] ""  PC
 SG_ Reserved_3 : 26|1@1+ (1,0) [0|1] ""  PC
 SG_ M2P_TMS_L_15_fan_fault_15 : 27|5@1+ (1,0) [0|31] ""  PC
 SG_ M2P_TMS_L_15_fre_fault_15 : 32|8@1+ (1,0) [0|255] ""  PC
 SG_ M2P_TMS_L_15_D_fault_15 : 40|8@1+ (1,0) [0|255] ""  PC
 SG_ M2P_TMS_L_FAN_PWM : 48|8@1+ (1,0) [0|255] ""  PC
 SG_ M2P_TMS_L_25_FAN_PWM_15 : 56|8@1+ (1,0) [0|255] ""  PC

BO_ 2337795744 M2P_LiquidInfo_8__16: 8 MBMU
 SG_ M2P_TMS_L_15_CP1_vol_16 : 0|8@1+ (2,0) [0|510] "V"  PC
 SG_ M2P_TMS_L_15_CP1_I_16 : 8|8@1+ (1,0) [0|255] "A"  PC
 SG_ M2P_TMS_L_15_CP1_r_16 : 16|8@1+ (100,0) [0|25500] "rpm"  PC
 SG_ M2P_TMS_L_TEM_16 : 24|1@1+ (1,0) [0|1] ""  PC
 SG_ M2P_TMS_L_WPS_16 : 25|1@1+ (1,0) [0|1] ""  PC
 SG_ Reserved_3 : 26|1@1+ (1,0) [0|1] ""  PC
 SG_ M2P_TMS_L_15_fan_fault_16 : 27|5@1+ (1,0) [0|31] ""  PC
 SG_ M2P_TMS_L_15_fre_fault_16 : 32|8@1+ (1,0) [0|255] ""  PC
 SG_ M2P_TMS_L_15_D_fault_16 : 40|8@1+ (1,0) [0|255] ""  PC
 SG_ M2P_TMS_L_FAN_PWM : 48|8@1+ (1,0) [0|255] ""  PC
 SG_ M2P_TMS_L_25_FAN_PWM_16 : 56|8@1+ (1,0) [0|255] ""  PC

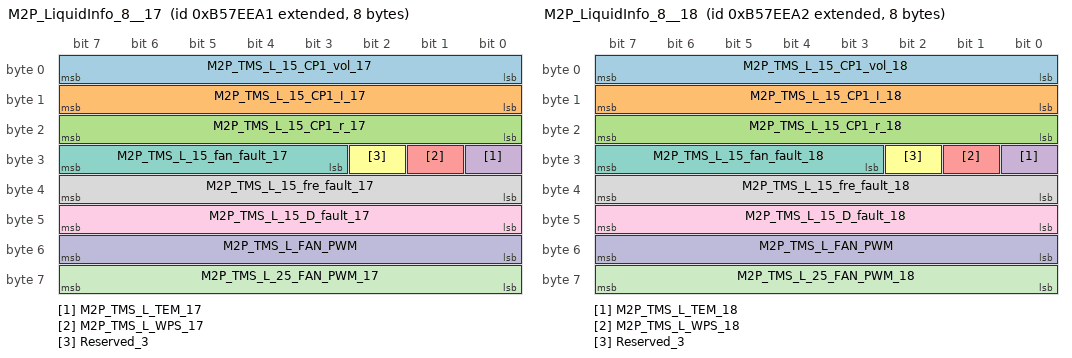
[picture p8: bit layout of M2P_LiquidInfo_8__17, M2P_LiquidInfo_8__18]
BO_ 2337795745 M2P_LiquidInfo_8__17: 8 MBMU
 SG_ M2P_TMS_L_15_CP1_vol_17 : 0|8@1+ (2,0) [0|510] "V"  PC
 SG_ M2P_TMS_L_15_CP1_I_17 : 8|8@1+ (1,0) [0|255] "A"  PC
 SG_ M2P_TMS_L_15_CP1_r_17 : 16|8@1+ (100,0) [0|25500] "rpm"  PC
 SG_ M2P_TMS_L_TEM_17 : 24|1@1+ (1,0) [0|1] ""  PC
 SG_ M2P_TMS_L_WPS_17 : 25|1@1+ (1,0) [0|1] ""  PC
 SG_ Reserved_3 : 26|1@1+ (1,0) [0|1] ""  PC
 SG_ M2P_TMS_L_15_fan_fault_17 : 27|5@1+ (1,0) [0|31] ""  PC
 SG_ M2P_TMS_L_15_fre_fault_17 : 32|8@1+ (1,0) [0|255] ""  PC
 SG_ M2P_TMS_L_15_D_fault_17 : 40|8@1+ (1,0) [0|255] ""  PC
 SG_ M2P_TMS_L_FAN_PWM : 48|8@1+ (1,0) [0|255] ""  PC
 SG_ M2P_TMS_L_25_FAN_PWM_17 : 56|8@1+ (1,0) [0|255] ""  PC

BO_ 2337795746 M2P_LiquidInfo_8__18: 8 MBMU
 SG_ M2P_TMS_L_15_CP1_vol_18 : 0|8@1+ (2,0) [0|510] "V"  PC
 SG_ M2P_TMS_L_15_CP1_I_18 : 8|8@1+ (1,0) [0|255] "A"  PC
 SG_ M2P_TMS_L_15_CP1_r_18 : 16|8@1+ (100,0) [0|25500] "rpm"  PC
 SG_ M2P_TMS_L_TEM_18 : 24|1@1+ (1,0) [0|1] ""  PC
 SG_ M2P_TMS_L_WPS_18 : 25|1@1+ (1,0) [0|1] ""  PC
 SG_ Reserved_3 : 26|1@1+ (1,0) [0|1] ""  PC
 SG_ M2P_TMS_L_15_fan_fault_18 : 27|5@1+ (1,0) [0|31] ""  PC
 SG_ M2P_TMS_L_15_fre_fault_18 : 32|8@1+ (1,0) [0|255] ""  PC
 SG_ M2P_TMS_L_15_D_fault_18 : 40|8@1+ (1,0) [0|255] ""  PC
 SG_ M2P_TMS_L_FAN_PWM : 48|8@1+ (1,0) [0|255] ""  PC
 SG_ M2P_TMS_L_25_FAN_PWM_18 : 56|8@1+ (1,0) [0|255] ""  PC

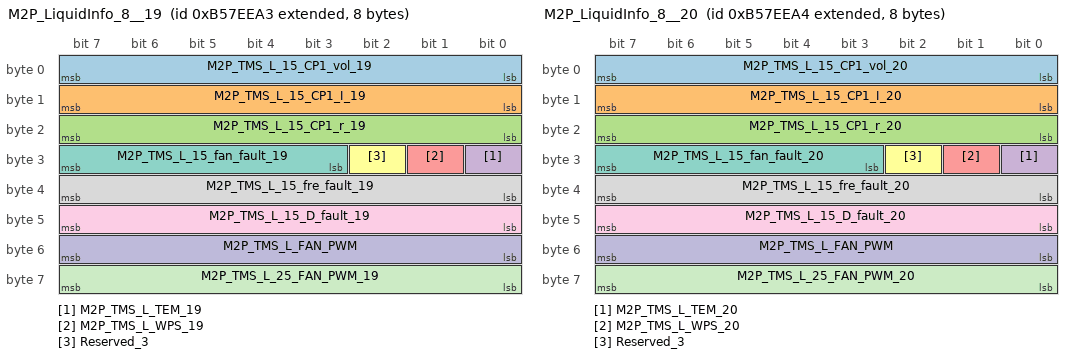
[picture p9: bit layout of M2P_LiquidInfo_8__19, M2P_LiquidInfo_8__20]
BO_ 2337795747 M2P_LiquidInfo_8__19: 8 MBMU
 SG_ M2P_TMS_L_15_CP1_vol_19 : 0|8@1+ (2,0) [0|510] "V"  PC
 SG_ M2P_TMS_L_15_CP1_I_19 : 8|8@1+ (1,0) [0|255] "A"  PC
 SG_ M2P_TMS_L_15_CP1_r_19 : 16|8@1+ (100,0) [0|25500] "rpm"  PC
 SG_ M2P_TMS_L_TEM_19 : 24|1@1+ (1,0) [0|1] ""  PC
 SG_ M2P_TMS_L_WPS_19 : 25|1@1+ (1,0) [0|1] ""  PC
 SG_ Reserved_3 : 26|1@1+ (1,0) [0|1] ""  PC
 SG_ M2P_TMS_L_15_fan_fault_19 : 27|5@1+ (1,0) [0|31] ""  PC
 SG_ M2P_TMS_L_15_fre_fault_19 : 32|8@1+ (1,0) [0|255] ""  PC
 SG_ M2P_TMS_L_15_D_fault_19 : 40|8@1+ (1,0) [0|255] ""  PC
 SG_ M2P_TMS_L_FAN_PWM : 48|8@1+ (1,0) [0|255] ""  PC
 SG_ M2P_TMS_L_25_FAN_PWM_19 : 56|8@1+ (1,0) [0|255] ""  PC

BO_ 2337795748 M2P_LiquidInfo_8__20: 8 MBMU
 SG_ M2P_TMS_L_15_CP1_vol_20 : 0|8@1+ (2,0) [0|510] "V"  PC
 SG_ M2P_TMS_L_15_CP1_I_20 : 8|8@1+ (1,0) [0|255] "A"  PC
 SG_ M2P_TMS_L_15_CP1_r_20 : 16|8@1+ (100,0) [0|25500] "rpm"  PC
 SG_ M2P_TMS_L_TEM_20 : 24|1@1+ (1,0) [0|1] ""  PC
 SG_ M2P_TMS_L_WPS_20 : 25|1@1+ (1,0) [0|1] ""  PC
 SG_ Reserved_3 : 26|1@1+ (1,0) [0|1] ""  PC
 SG_ M2P_TMS_L_15_fan_fault_20 : 27|5@1+ (1,0) [0|31] ""  PC
 SG_ M2P_TMS_L_15_fre_fault_20 : 32|8@1+ (1,0) [0|255] ""  PC
 SG_ M2P_TMS_L_15_D_fault_20 : 40|8@1+ (1,0) [0|255] ""  PC
 SG_ M2P_TMS_L_FAN_PWM : 48|8@1+ (1,0) [0|255] ""  PC
 SG_ M2P_TMS_L_25_FAN_PWM_20 : 56|8@1+ (1,0) [0|255] ""  PC

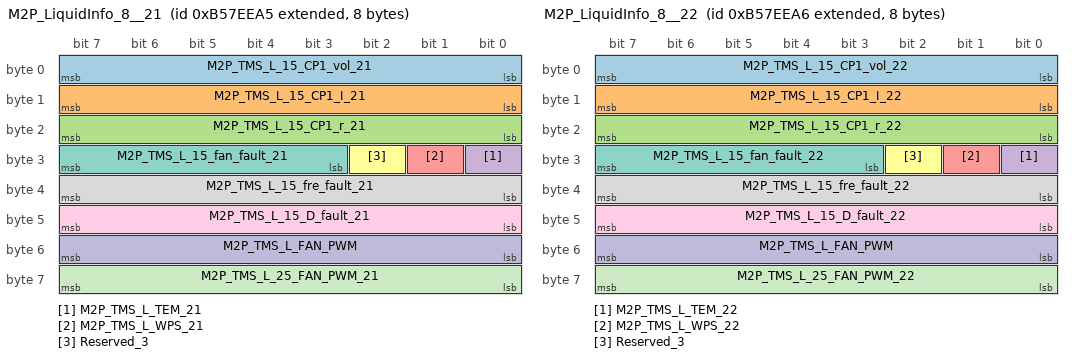
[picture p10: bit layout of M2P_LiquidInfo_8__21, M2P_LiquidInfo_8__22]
BO_ 2337795749 M2P_LiquidInfo_8__21: 8 MBMU
 SG_ M2P_TMS_L_15_CP1_vol_21 : 0|8@1+ (2,0) [0|510] "V"  PC
 SG_ M2P_TMS_L_15_CP1_I_21 : 8|8@1+ (1,0) [0|255] "A"  PC
 SG_ M2P_TMS_L_15_CP1_r_21 : 16|8@1+ (100,0) [0|25500] "rpm"  PC
 SG_ M2P_TMS_L_TEM_21 : 24|1@1+ (1,0) [0|1] ""  PC
 SG_ M2P_TMS_L_WPS_21 : 25|1@1+ (1,0) [0|1] ""  PC
 SG_ Reserved_3 : 26|1@1+ (1,0) [0|1] ""  PC
 SG_ M2P_TMS_L_15_fan_fault_21 : 27|5@1+ (1,0) [0|31] ""  PC
 SG_ M2P_TMS_L_15_fre_fault_21 : 32|8@1+ (1,0) [0|255] ""  PC
 SG_ M2P_TMS_L_15_D_fault_21 : 40|8@1+ (1,0) [0|255] ""  PC
 SG_ M2P_TMS_L_FAN_PWM : 48|8@1+ (1,0) [0|255] ""  PC
 SG_ M2P_TMS_L_25_FAN_PWM_21 : 56|8@1+ (1,0) [0|255] ""  PC

BO_ 2337795750 M2P_LiquidInfo_8__22: 8 MBMU
 SG_ M2P_TMS_L_15_CP1_vol_22 : 0|8@1+ (2,0) [0|510] "V"  PC
 SG_ M2P_TMS_L_15_CP1_I_22 : 8|8@1+ (1,0) [0|255] "A"  PC
 SG_ M2P_TMS_L_15_CP1_r_22 : 16|8@1+ (100,0) [0|25500] "rpm"  PC
 SG_ M2P_TMS_L_TEM_22 : 24|1@1+ (1,0) [0|1] ""  PC
 SG_ M2P_TMS_L_WPS_22 : 25|1@1+ (1,0) [0|1] ""  PC
 SG_ Reserved_3 : 26|1@1+ (1,0) [0|1] ""  PC
 SG_ M2P_TMS_L_15_fan_fault_22 : 27|5@1+ (1,0) [0|31] ""  PC
 SG_ M2P_TMS_L_15_fre_fault_22 : 32|8@1+ (1,0) [0|255] ""  PC
 SG_ M2P_TMS_L_15_D_fault_22 : 40|8@1+ (1,0) [0|255] ""  PC
 SG_ M2P_TMS_L_FAN_PWM : 48|8@1+ (1,0) [0|255] ""  PC
 SG_ M2P_TMS_L_25_FAN_PWM_22 : 56|8@1+ (1,0) [0|255] ""  PC

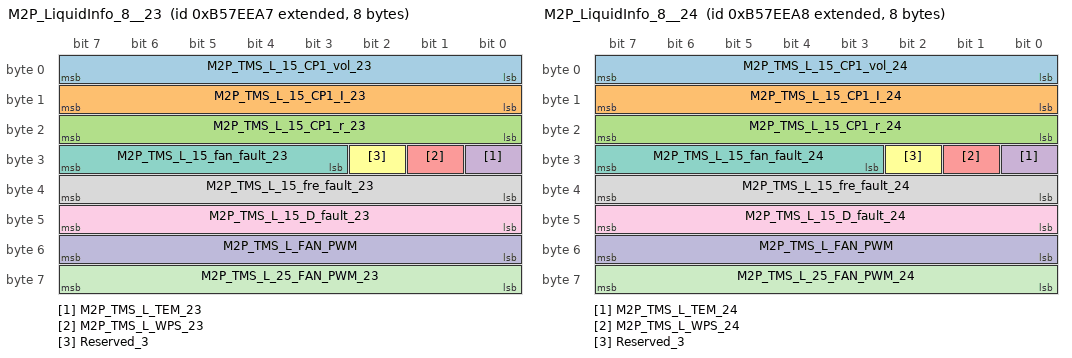
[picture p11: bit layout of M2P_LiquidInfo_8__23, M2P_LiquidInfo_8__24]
BO_ 2337795751 M2P_LiquidInfo_8__23: 8 MBMU
 SG_ M2P_TMS_L_15_CP1_vol_23 : 0|8@1+ (2,0) [0|510] "V"  PC
 SG_ M2P_TMS_L_15_CP1_I_23 : 8|8@1+ (1,0) [0|255] "A"  PC
 SG_ M2P_TMS_L_15_CP1_r_23 : 16|8@1+ (100,0) [0|25500] "rpm"  PC
 SG_ M2P_TMS_L_TEM_23 : 24|1@1+ (1,0) [0|1] ""  PC
 SG_ M2P_TMS_L_WPS_23 : 25|1@1+ (1,0) [0|1] ""  PC
 SG_ Reserved_3 : 26|1@1+ (1,0) [0|1] ""  PC
 SG_ M2P_TMS_L_15_fan_fault_23 : 27|5@1+ (1,0) [0|31] ""  PC
 SG_ M2P_TMS_L_15_fre_fault_23 : 32|8@1+ (1,0) [0|255] ""  PC
 SG_ M2P_TMS_L_15_D_fault_23 : 40|8@1+ (1,0) [0|255] ""  PC
 SG_ M2P_TMS_L_FAN_PWM : 48|8@1+ (1,0) [0|255] ""  PC
 SG_ M2P_TMS_L_25_FAN_PWM_23 : 56|8@1+ (1,0) [0|255] ""  PC

BO_ 2337795752 M2P_LiquidInfo_8__24: 8 MBMU
 SG_ M2P_TMS_L_15_CP1_vol_24 : 0|8@1+ (2,0) [0|510] "V"  PC
 SG_ M2P_TMS_L_15_CP1_I_24 : 8|8@1+ (1,0) [0|255] "A"  PC
 SG_ M2P_TMS_L_15_CP1_r_24 : 16|8@1+ (100,0) [0|25500] "rpm"  PC
 SG_ M2P_TMS_L_TEM_24 : 24|1@1+ (1,0) [0|1] ""  PC
 SG_ M2P_TMS_L_WPS_24 : 25|1@1+ (1,0) [0|1] ""  PC
 SG_ Reserved_3 : 26|1@1+ (1,0) [0|1] ""  PC
 SG_ M2P_TMS_L_15_fan_fault_24 : 27|5@1+ (1,0) [0|31] ""  PC
 SG_ M2P_TMS_L_15_fre_fault_24 : 32|8@1+ (1,0) [0|255] ""  PC
 SG_ M2P_TMS_L_15_D_fault_24 : 40|8@1+ (1,0) [0|255] ""  PC
 SG_ M2P_TMS_L_FAN_PWM : 48|8@1+ (1,0) [0|255] ""  PC
 SG_ M2P_TMS_L_25_FAN_PWM_24 : 56|8@1+ (1,0) [0|255] ""  PC

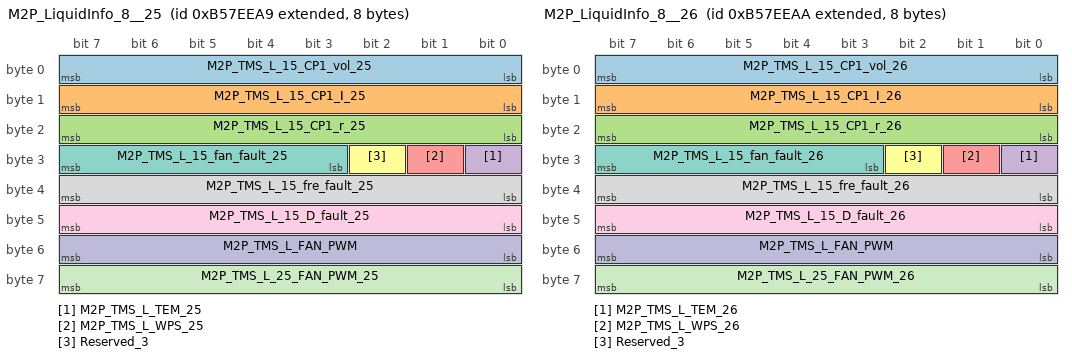
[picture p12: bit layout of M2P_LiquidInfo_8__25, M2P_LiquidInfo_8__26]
BO_ 2337795753 M2P_LiquidInfo_8__25: 8 MBMU
 SG_ M2P_TMS_L_15_CP1_vol_25 : 0|8@1+ (2,0) [0|510] "V"  PC
 SG_ M2P_TMS_L_15_CP1_I_25 : 8|8@1+ (1,0) [0|255] "A"  PC
 SG_ M2P_TMS_L_15_CP1_r_25 : 16|8@1+ (100,0) [0|25500] "rpm"  PC
 SG_ M2P_TMS_L_TEM_25 : 24|1@1+ (1,0) [0|1] ""  PC
 SG_ M2P_TMS_L_WPS_25 : 25|1@1+ (1,0) [0|1] ""  PC
 SG_ Reserved_3 : 26|1@1+ (1,0) [0|1] ""  PC
 SG_ M2P_TMS_L_15_fan_fault_25 : 27|5@1+ (1,0) [0|31] ""  PC
 SG_ M2P_TMS_L_15_fre_fault_25 : 32|8@1+ (1,0) [0|255] ""  PC
 SG_ M2P_TMS_L_15_D_fault_25 : 40|8@1+ (1,0) [0|255] ""  PC
 SG_ M2P_TMS_L_FAN_PWM : 48|8@1+ (1,0) [0|255] ""  PC
 SG_ M2P_TMS_L_25_FAN_PWM_25 : 56|8@1+ (1,0) [0|255] ""  PC

BO_ 2337795754 M2P_LiquidInfo_8__26: 8 MBMU
 SG_ M2P_TMS_L_15_CP1_vol_26 : 0|8@1+ (2,0) [0|510] "V"  PC
 SG_ M2P_TMS_L_15_CP1_I_26 : 8|8@1+ (1,0) [0|255] "A"  PC
 SG_ M2P_TMS_L_15_CP1_r_26 : 16|8@1+ (100,0) [0|25500] "rpm"  PC
 SG_ M2P_TMS_L_TEM_26 : 24|1@1+ (1,0) [0|1] ""  PC
 SG_ M2P_TMS_L_WPS_26 : 25|1@1+ (1,0) [0|1] ""  PC
 SG_ Reserved_3 : 26|1@1+ (1,0) [0|1] ""  PC
 SG_ M2P_TMS_L_15_fan_fault_26 : 27|5@1+ (1,0) [0|31] ""  PC
 SG_ M2P_TMS_L_15_fre_fault_26 : 32|8@1+ (1,0) [0|255] ""  PC
 SG_ M2P_TMS_L_15_D_fault_26 : 40|8@1+ (1,0) [0|255] ""  PC
 SG_ M2P_TMS_L_FAN_PWM : 48|8@1+ (1,0) [0|255] ""  PC
 SG_ M2P_TMS_L_25_FAN_PWM_26 : 56|8@1+ (1,0) [0|255] ""  PC

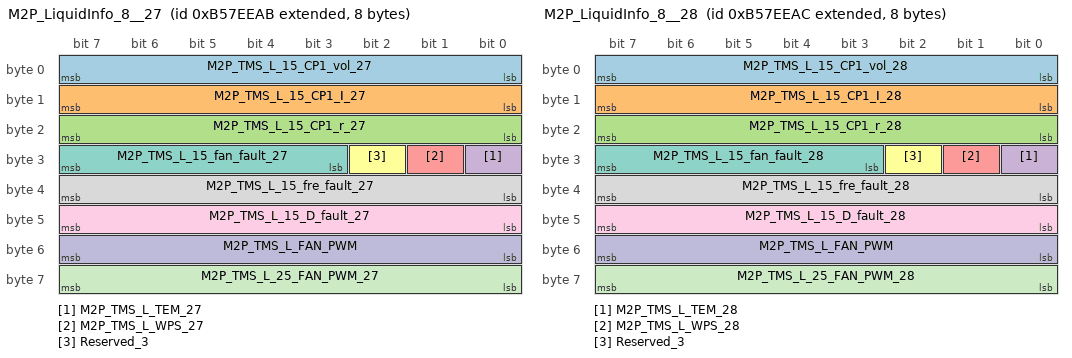
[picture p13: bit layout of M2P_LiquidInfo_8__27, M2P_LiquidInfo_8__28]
BO_ 2337795755 M2P_LiquidInfo_8__27: 8 MBMU
 SG_ M2P_TMS_L_15_CP1_vol_27 : 0|8@1+ (2,0) [0|510] "V"  PC
 SG_ M2P_TMS_L_15_CP1_I_27 : 8|8@1+ (1,0) [0|255] "A"  PC
 SG_ M2P_TMS_L_15_CP1_r_27 : 16|8@1+ (100,0) [0|25500] "rpm"  PC
 SG_ M2P_TMS_L_TEM_27 : 24|1@1+ (1,0) [0|1] ""  PC
 SG_ M2P_TMS_L_WPS_27 : 25|1@1+ (1,0) [0|1] ""  PC
 SG_ Reserved_3 : 26|1@1+ (1,0) [0|1] ""  PC
 SG_ M2P_TMS_L_15_fan_fault_27 : 27|5@1+ (1,0) [0|31] ""  PC
 SG_ M2P_TMS_L_15_fre_fault_27 : 32|8@1+ (1,0) [0|255] ""  PC
 SG_ M2P_TMS_L_15_D_fault_27 : 40|8@1+ (1,0) [0|255] ""  PC
 SG_ M2P_TMS_L_FAN_PWM : 48|8@1+ (1,0) [0|255] ""  PC
 SG_ M2P_TMS_L_25_FAN_PWM_27 : 56|8@1+ (1,0) [0|255] ""  PC

BO_ 2337795756 M2P_LiquidInfo_8__28: 8 MBMU
 SG_ M2P_TMS_L_15_CP1_vol_28 : 0|8@1+ (2,0) [0|510] "V"  PC
 SG_ M2P_TMS_L_15_CP1_I_28 : 8|8@1+ (1,0) [0|255] "A"  PC
 SG_ M2P_TMS_L_15_CP1_r_28 : 16|8@1+ (100,0) [0|25500] "rpm"  PC
 SG_ M2P_TMS_L_TEM_28 : 24|1@1+ (1,0) [0|1] ""  PC
 SG_ M2P_TMS_L_WPS_28 : 25|1@1+ (1,0) [0|1] ""  PC
 SG_ Reserved_3 : 26|1@1+ (1,0) [0|1] ""  PC
 SG_ M2P_TMS_L_15_fan_fault_28 : 27|5@1+ (1,0) [0|31] ""  PC
 SG_ M2P_TMS_L_15_fre_fault_28 : 32|8@1+ (1,0) [0|255] ""  PC
 SG_ M2P_TMS_L_15_D_fault_28 : 40|8@1+ (1,0) [0|255] ""  PC
 SG_ M2P_TMS_L_FAN_PWM : 48|8@1+ (1,0) [0|255] ""  PC
 SG_ M2P_TMS_L_25_FAN_PWM_28 : 56|8@1+ (1,0) [0|255] ""  PC

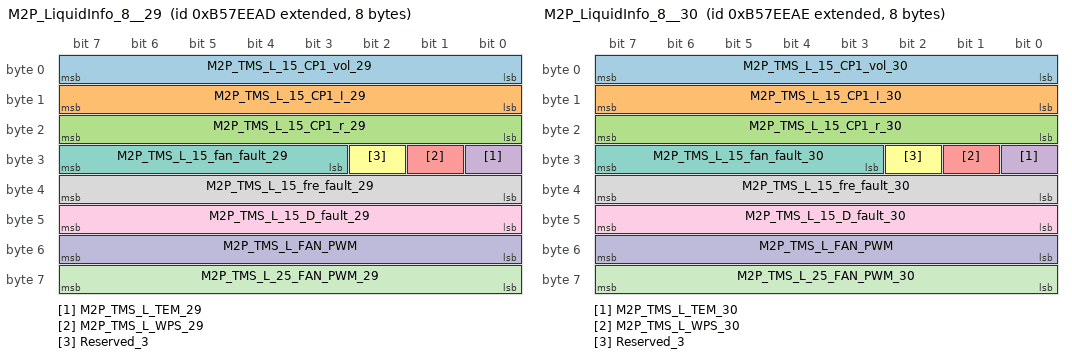
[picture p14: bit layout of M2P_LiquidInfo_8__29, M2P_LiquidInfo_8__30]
BO_ 2337795757 M2P_LiquidInfo_8__29: 8 MBMU
 SG_ M2P_TMS_L_15_CP1_vol_29 : 0|8@1+ (2,0) [0|510] "V"  PC
 SG_ M2P_TMS_L_15_CP1_I_29 : 8|8@1+ (1,0) [0|255] "A"  PC
 SG_ M2P_TMS_L_15_CP1_r_29 : 16|8@1+ (100,0) [0|25500] "rpm"  PC
 SG_ M2P_TMS_L_TEM_29 : 24|1@1+ (1,0) [0|1] ""  PC
 SG_ M2P_TMS_L_WPS_29 : 25|1@1+ (1,0) [0|1] ""  PC
 SG_ Reserved_3 : 26|1@1+ (1,0) [0|1] ""  PC
 SG_ M2P_TMS_L_15_fan_fault_29 : 27|5@1+ (1,0) [0|31] ""  PC
 SG_ M2P_TMS_L_15_fre_fault_29 : 32|8@1+ (1,0) [0|255] ""  PC
 SG_ M2P_TMS_L_15_D_fault_29 : 40|8@1+ (1,0) [0|255] ""  PC
 SG_ M2P_TMS_L_FAN_PWM : 48|8@1+ (1,0) [0|255] ""  PC
 SG_ M2P_TMS_L_25_FAN_PWM_29 : 56|8@1+ (1,0) [0|255] ""  PC

BO_ 2337795758 M2P_LiquidInfo_8__30: 8 MBMU
 SG_ M2P_TMS_L_15_CP1_vol_30 : 0|8@1+ (2,0) [0|510] "V"  PC
 SG_ M2P_TMS_L_15_CP1_I_30 : 8|8@1+ (1,0) [0|255] "A"  PC
 SG_ M2P_TMS_L_15_CP1_r_30 : 16|8@1+ (100,0) [0|25500] "rpm"  PC
 SG_ M2P_TMS_L_TEM_30 : 24|1@1+ (1,0) [0|1] ""  PC
 SG_ M2P_TMS_L_WPS_30 : 25|1@1+ (1,0) [0|1] ""  PC
 SG_ Reserved_3 : 26|1@1+ (1,0) [0|1] ""  PC
 SG_ M2P_TMS_L_15_fan_fault_30 : 27|5@1+ (1,0) [0|31] ""  PC
 SG_ M2P_TMS_L_15_fre_fault_30 : 32|8@1+ (1,0) [0|255] ""  PC
 SG_ M2P_TMS_L_15_D_fault_30 : 40|8@1+ (1,0) [0|255] ""  PC
 SG_ M2P_TMS_L_FAN_PWM : 48|8@1+ (1,0) [0|255] ""  PC
 SG_ M2P_TMS_L_25_FAN_PWM_30 : 56|8@1+ (1,0) [0|255] ""  PC

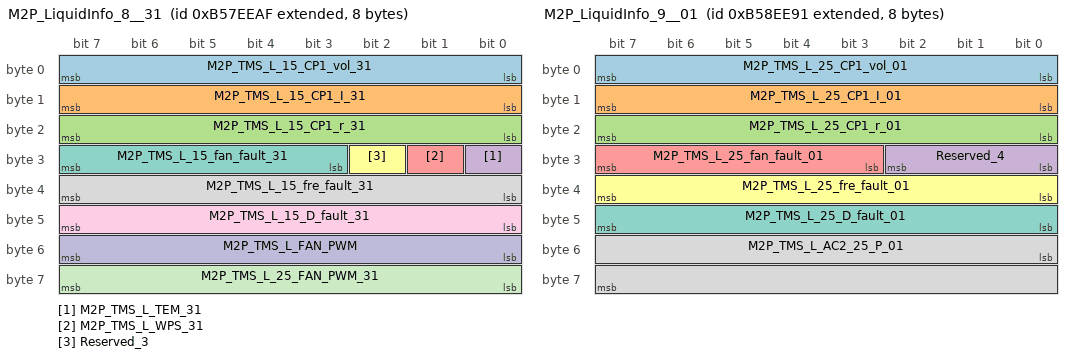
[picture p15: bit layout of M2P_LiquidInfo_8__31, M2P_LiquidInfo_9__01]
BO_ 2337795759 M2P_LiquidInfo_8__31: 8 MBMU
 SG_ M2P_TMS_L_15_CP1_vol_31 : 0|8@1+ (2,0) [0|510] "V"  PC
 SG_ M2P_TMS_L_15_CP1_I_31 : 8|8@1+ (1,0) [0|255] "A"  PC
 SG_ M2P_TMS_L_15_CP1_r_31 : 16|8@1+ (100,0) [0|25500] "rpm"  PC
 SG_ M2P_TMS_L_TEM_31 : 24|1@1+ (1,0) [0|1] ""  PC
 SG_ M2P_TMS_L_WPS_31 : 25|1@1+ (1,0) [0|1] ""  PC
 SG_ Reserved_3 : 26|1@1+ (1,0) [0|1] ""  PC
 SG_ M2P_TMS_L_15_fan_fault_31 : 27|5@1+ (1,0) [0|31] ""  PC
 SG_ M2P_TMS_L_15_fre_fault_31 : 32|8@1+ (1,0) [0|255] ""  PC
 SG_ M2P_TMS_L_15_D_fault_31 : 40|8@1+ (1,0) [0|255] ""  PC
 SG_ M2P_TMS_L_FAN_PWM : 48|8@1+ (1,0) [0|255] ""  PC
 SG_ M2P_TMS_L_25_FAN_PWM_31 : 56|8@1+ (1,0) [0|255] ""  PC

BO_ 2337861265 M2P_LiquidInfo_9__01: 8 MBMU
 SG_ M2P_TMS_L_25_CP1_vol_01 : 0|8@1+ (2,0) [0|510] "V"  PC
 SG_ M2P_TMS_L_25_CP1_I_01 : 8|8@1+ (1,0) [0|255] "A"  PC
 SG_ M2P_TMS_L_25_CP1_r_01 : 16|8@1+ (100,0) [0|25500] "rpm"  PC
 SG_ Reserved_4 : 24|3@1+ (1,0) [0|7] ""  PC
 SG_ M2P_TMS_L_25_fan_fault_01 : 27|5@1+ (1,0) [0|31] ""  PC
 SG_ M2P_TMS_L_25_fre_fault_01 : 32|8@1+ (1,0) [0|255] ""  PC
 SG_ M2P_TMS_L_25_D_fault_01 : 40|8@1+ (1,0) [0|255] ""  PC
 SG_ M2P_TMS_L_AC2_25_P_01 : 48|16@1+ (1,0) [0|65535] ""  PC

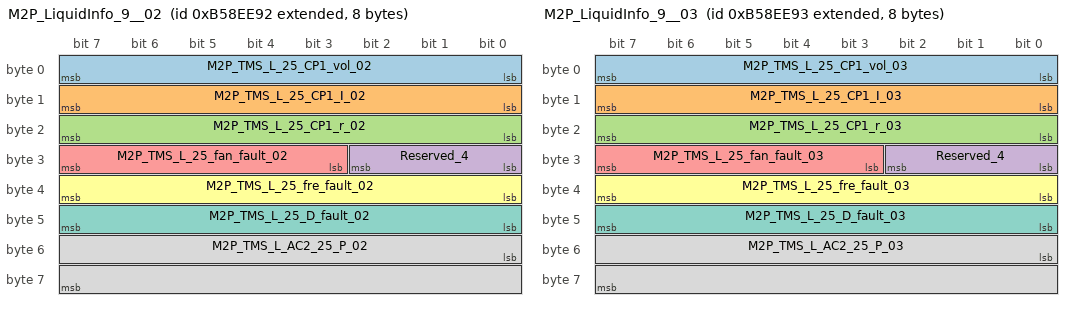
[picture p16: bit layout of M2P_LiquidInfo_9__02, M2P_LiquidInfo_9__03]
BO_ 2337861266 M2P_LiquidInfo_9__02: 8 MBMU
 SG_ M2P_TMS_L_25_CP1_vol_02 : 0|8@1+ (2,0) [0|510] "V"  PC
 SG_ M2P_TMS_L_25_CP1_I_02 : 8|8@1+ (1,0) [0|255] "A"  PC
 SG_ M2P_TMS_L_25_CP1_r_02 : 16|8@1+ (100,0) [0|25500] "rpm"  PC
 SG_ Reserved_4 : 24|3@1+ (1,0) [0|7] ""  PC
 SG_ M2P_TMS_L_25_fan_fault_02 : 27|5@1+ (1,0) [0|31] ""  PC
 SG_ M2P_TMS_L_25_fre_fault_02 : 32|8@1+ (1,0) [0|255] ""  PC
 SG_ M2P_TMS_L_25_D_fault_02 : 40|8@1+ (1,0) [0|255] ""  PC
 SG_ M2P_TMS_L_AC2_25_P_02 : 48|16@1+ (1,0) [0|65535] ""  PC

BO_ 2337861267 M2P_LiquidInfo_9__03: 8 MBMU
 SG_ M2P_TMS_L_25_CP1_vol_03 : 0|8@1+ (2,0) [0|510] "V"  PC
 SG_ M2P_TMS_L_25_CP1_I_03 : 8|8@1+ (1,0) [0|255] "A"  PC
 SG_ M2P_TMS_L_25_CP1_r_03 : 16|8@1+ (100,0) [0|25500] "rpm"  PC
 SG_ Reserved_4 : 24|3@1+ (1,0) [0|7] ""  PC
 SG_ M2P_TMS_L_25_fan_fault_03 : 27|5@1+ (1,0) [0|31] ""  PC
 SG_ M2P_TMS_L_25_fre_fault_03 : 32|8@1+ (1,0) [0|255] ""  PC
 SG_ M2P_TMS_L_25_D_fault_03 : 40|8@1+ (1,0) [0|255] ""  PC
 SG_ M2P_TMS_L_AC2_25_P_03 : 48|16@1+ (1,0) [0|65535] ""  PC

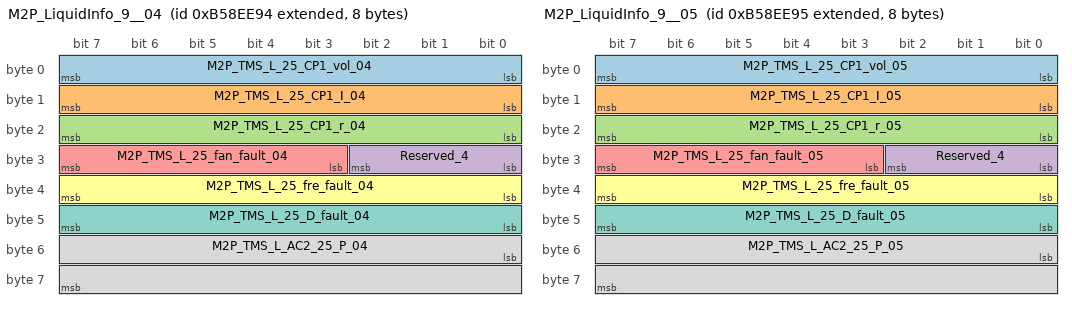
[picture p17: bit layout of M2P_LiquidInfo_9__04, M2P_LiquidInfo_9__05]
BO_ 2337861268 M2P_LiquidInfo_9__04: 8 MBMU
 SG_ M2P_TMS_L_25_CP1_vol_04 : 0|8@1+ (2,0) [0|510] "V"  PC
 SG_ M2P_TMS_L_25_CP1_I_04 : 8|8@1+ (1,0) [0|255] "A"  PC
 SG_ M2P_TMS_L_25_CP1_r_04 : 16|8@1+ (100,0) [0|25500] "rpm"  PC
 SG_ Reserved_4 : 24|3@1+ (1,0) [0|7] ""  PC
 SG_ M2P_TMS_L_25_fan_fault_04 : 27|5@1+ (1,0) [0|31] ""  PC
 SG_ M2P_TMS_L_25_fre_fault_04 : 32|8@1+ (1,0) [0|255] ""  PC
 SG_ M2P_TMS_L_25_D_fault_04 : 40|8@1+ (1,0) [0|255] ""  PC
 SG_ M2P_TMS_L_AC2_25_P_04 : 48|16@1+ (1,0) [0|65535] ""  PC

BO_ 2337861269 M2P_LiquidInfo_9__05: 8 MBMU
 SG_ M2P_TMS_L_25_CP1_vol_05 : 0|8@1+ (2,0) [0|510] "V"  PC
 SG_ M2P_TMS_L_25_CP1_I_05 : 8|8@1+ (1,0) [0|255] "A"  PC
 SG_ M2P_TMS_L_25_CP1_r_05 : 16|8@1+ (100,0) [0|25500] "rpm"  PC
 SG_ Reserved_4 : 24|3@1+ (1,0) [0|7] ""  PC
 SG_ M2P_TMS_L_25_fan_fault_05 : 27|5@1+ (1,0) [0|31] ""  PC
 SG_ M2P_TMS_L_25_fre_fault_05 : 32|8@1+ (1,0) [0|255] ""  PC
 SG_ M2P_TMS_L_25_D_fault_05 : 40|8@1+ (1,0) [0|255] ""  PC
 SG_ M2P_TMS_L_AC2_25_P_05 : 48|16@1+ (1,0) [0|65535] ""  PC

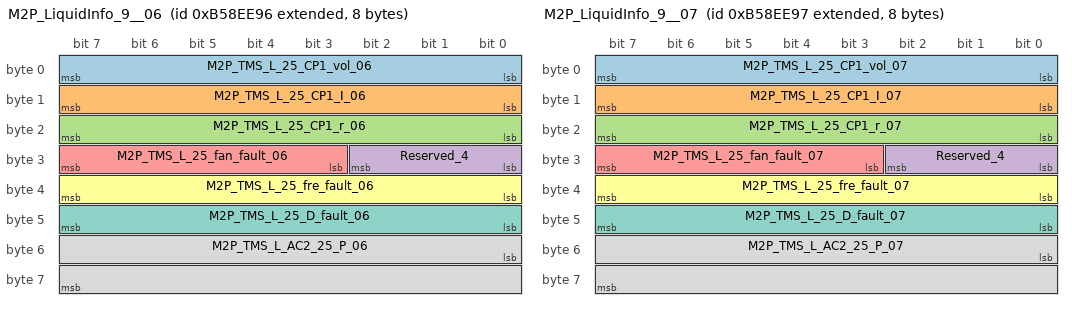
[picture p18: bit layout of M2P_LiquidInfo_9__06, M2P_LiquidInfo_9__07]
BO_ 2337861270 M2P_LiquidInfo_9__06: 8 MBMU
 SG_ M2P_TMS_L_25_CP1_vol_06 : 0|8@1+ (2,0) [0|510] "V"  PC
 SG_ M2P_TMS_L_25_CP1_I_06 : 8|8@1+ (1,0) [0|255] "A"  PC
 SG_ M2P_TMS_L_25_CP1_r_06 : 16|8@1+ (100,0) [0|25500] "rpm"  PC
 SG_ Reserved_4 : 24|3@1+ (1,0) [0|7] ""  PC
 SG_ M2P_TMS_L_25_fan_fault_06 : 27|5@1+ (1,0) [0|31] ""  PC
 SG_ M2P_TMS_L_25_fre_fault_06 : 32|8@1+ (1,0) [0|255] ""  PC
 SG_ M2P_TMS_L_25_D_fault_06 : 40|8@1+ (1,0) [0|255] ""  PC
 SG_ M2P_TMS_L_AC2_25_P_06 : 48|16@1+ (1,0) [0|65535] ""  PC

BO_ 2337861271 M2P_LiquidInfo_9__07: 8 MBMU
 SG_ M2P_TMS_L_25_CP1_vol_07 : 0|8@1+ (2,0) [0|510] "V"  PC
 SG_ M2P_TMS_L_25_CP1_I_07 : 8|8@1+ (1,0) [0|255] "A"  PC
 SG_ M2P_TMS_L_25_CP1_r_07 : 16|8@1+ (100,0) [0|25500] "rpm"  PC
 SG_ Reserved_4 : 24|3@1+ (1,0) [0|7] ""  PC
 SG_ M2P_TMS_L_25_fan_fault_07 : 27|5@1+ (1,0) [0|31] ""  PC
 SG_ M2P_TMS_L_25_fre_fault_07 : 32|8@1+ (1,0) [0|255] ""  PC
 SG_ M2P_TMS_L_25_D_fault_07 : 40|8@1+ (1,0) [0|255] ""  PC
 SG_ M2P_TMS_L_AC2_25_P_07 : 48|16@1+ (1,0) [0|65535] ""  PC

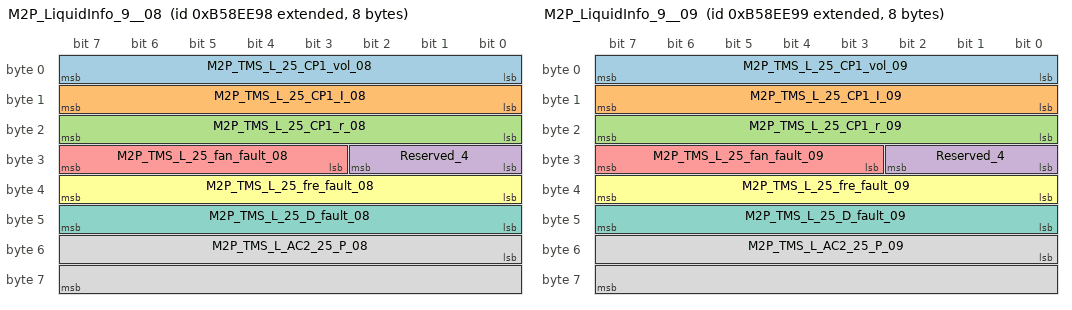
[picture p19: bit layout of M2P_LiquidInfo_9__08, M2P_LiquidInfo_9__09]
BO_ 2337861272 M2P_LiquidInfo_9__08: 8 MBMU
 SG_ M2P_TMS_L_25_CP1_vol_08 : 0|8@1+ (2,0) [0|510] "V"  PC
 SG_ M2P_TMS_L_25_CP1_I_08 : 8|8@1+ (1,0) [0|255] "A"  PC
 SG_ M2P_TMS_L_25_CP1_r_08 : 16|8@1+ (100,0) [0|25500] "rpm"  PC
 SG_ Reserved_4 : 24|3@1+ (1,0) [0|7] ""  PC
 SG_ M2P_TMS_L_25_fan_fault_08 : 27|5@1+ (1,0) [0|31] ""  PC
 SG_ M2P_TMS_L_25_fre_fault_08 : 32|8@1+ (1,0) [0|255] ""  PC
 SG_ M2P_TMS_L_25_D_fault_08 : 40|8@1+ (1,0) [0|255] ""  PC
 SG_ M2P_TMS_L_AC2_25_P_08 : 48|16@1+ (1,0) [0|65535] ""  PC

BO_ 2337861273 M2P_LiquidInfo_9__09: 8 MBMU
 SG_ M2P_TMS_L_25_CP1_vol_09 : 0|8@1+ (2,0) [0|510] "V"  PC
 SG_ M2P_TMS_L_25_CP1_I_09 : 8|8@1+ (1,0) [0|255] "A"  PC
 SG_ M2P_TMS_L_25_CP1_r_09 : 16|8@1+ (100,0) [0|25500] "rpm"  PC
 SG_ Reserved_4 : 24|3@1+ (1,0) [0|7] ""  PC
 SG_ M2P_TMS_L_25_fan_fault_09 : 27|5@1+ (1,0) [0|31] ""  PC
 SG_ M2P_TMS_L_25_fre_fault_09 : 32|8@1+ (1,0) [0|255] ""  PC
 SG_ M2P_TMS_L_25_D_fault_09 : 40|8@1+ (1,0) [0|255] ""  PC
 SG_ M2P_TMS_L_AC2_25_P_09 : 48|16@1+ (1,0) [0|65535] ""  PC

BO_ 2337861274 M2P_LiquidInfo_9__10: 8 MBMU
 SG_ M2P_TMS_L_25_CP1_vol_10 : 0|8@1+ (2,0) [0|510] "V"  PC
 SG_ M2P_TMS_L_25_CP1_I_10 : 8|8@1+ (1,0) [0|255] "A"  PC
 SG_ M2P_TMS_L_25_CP1_r_10 : 16|8@1+ (100,0) [0|25500] "rpm"  PC
 SG_ Reserved_4 : 24|3@1+ (1,0) [0|7] ""  PC
 SG_ M2P_TMS_L_25_fan_fault_10 : 27|5@1+ (1,0) [0|31] ""  PC
 SG_ M2P_TMS_L_25_fre_fault_10 : 32|8@1+ (1,0) [0|255] ""  PC
 SG_ M2P_TMS_L_25_D_fault_10 : 40|8@1+ (1,0) [0|255] ""  PC
 SG_ M2P_TMS_L_AC2_25_P_10 : 48|16@1+ (1,0) [0|65535] ""  PC

BO_ 2337861275 M2P_LiquidInfo_9__11: 8 MBMU
 SG_ M2P_TMS_L_25_CP1_vol_11 : 0|8@1+ (2,0) [0|510] "V"  PC
 SG_ M2P_TMS_L_25_CP1_I_11 : 8|8@1+ (1,0) [0|255] "A"  PC
 SG_ M2P_TMS_L_25_CP1_r_11 : 16|8@1+ (100,0) [0|25500] "rpm"  PC
 SG_ Reserved_4 : 24|3@1+ (1,0) [0|7] ""  PC
 SG_ M2P_TMS_L_25_fan_fault_11 : 27|5@1+ (1,0) [0|31] ""  PC
 SG_ M2P_TMS_L_25_fre_fault_11 : 32|8@1+ (1,0) [0|255] ""  PC
 SG_ M2P_TMS_L_25_D_fault_11 : 40|8@1+ (1,0) [0|255] ""  PC
 SG_ M2P_TMS_L_AC2_25_P_11 : 48|16@1+ (1,0) [0|65535] ""  PC

BO_ 2337861276 M2P_LiquidInfo_9__12: 8 MBMU
 SG_ M2P_TMS_L_25_CP1_vol_12 : 0|8@1+ (2,0) [0|510] "V"  PC
 SG_ M2P_TMS_L_25_CP1_I_12 : 8|8@1+ (1,0) [0|255] "A"  PC
 SG_ M2P_TMS_L_25_CP1_r_12 : 16|8@1+ (100,0) [0|25500] "rpm"  PC
 SG_ Reserved_4 : 24|3@1+ (1,0) [0|7] ""  PC
 SG_ M2P_TMS_L_25_fan_fault_12 : 27|5@1+ (1,0) [0|31] ""  PC
 SG_ M2P_TMS_L_25_fre_fault_12 : 32|8@1+ (1,0) [0|255] ""  PC
 SG_ M2P_TMS_L_25_D_fault_12 : 40|8@1+ (1,0) [0|255] ""  PC
 SG_ M2P_TMS_L_AC2_25_P_12 : 48|16@1+ (1,0) [0|65535] ""  PC

BO_ 2337861277 M2P_LiquidInfo_9__13: 8 MBMU
 SG_ M2P_TMS_L_25_CP1_vol_13 : 0|8@1+ (2,0) [0|510] "V"  PC
 SG_ M2P_TMS_L_25_CP1_I_13 : 8|8@1+ (1,0) [0|255] "A"  PC
 SG_ M2P_TMS_L_25_CP1_r_13 : 16|8@1+ (100,0) [0|25500] "rpm"  PC
 SG_ Reserved_4 : 24|3@1+ (1,0) [0|7] ""  PC
 SG_ M2P_TMS_L_25_fan_fault_13 : 27|5@1+ (1,0) [0|31] ""  PC
 SG_ M2P_TMS_L_25_fre_fault_13 : 32|8@1+ (1,0) [0|255] ""  PC
 SG_ M2P_TMS_L_25_D_fault_13 : 40|8@1+ (1,0) [0|255] ""  PC
 SG_ M2P_TMS_L_AC2_25_P_13 : 48|16@1+ (1,0) [0|65535] ""  PC

BO_ 2337861278 M2P_LiquidInfo_9__14: 8 MBMU
 SG_ M2P_TMS_L_25_CP1_vol_14 : 0|8@1+ (2,0) [0|510] "V"  PC
 SG_ M2P_TMS_L_25_CP1_I_14 : 8|8@1+ (1,0) [0|255] "A"  PC
 SG_ M2P_TMS_L_25_CP1_r_14 : 16|8@1+ (100,0) [0|25500] "rpm"  PC
 SG_ Reserved_4 : 24|3@1+ (1,0) [0|7] ""  PC
 SG_ M2P_TMS_L_25_fan_fault_14 : 27|5@1+ (1,0) [0|31] ""  PC
 SG_ M2P_TMS_L_25_fre_fault_14 : 32|8@1+ (1,0) [0|255] ""  PC
 SG_ M2P_TMS_L_25_D_fault_14 : 40|8@1+ (1,0) [0|255] ""  PC
 SG_ M2P_TMS_L_AC2_25_P_14 : 48|16@1+ (1,0) [0|65535] ""  PC

BO_ 2337861279 M2P_LiquidInfo_9__15: 8 MBMU
 SG_ M2P_TMS_L_25_CP1_vol_15 : 0|8@1+ (2,0) [0|510] "V"  PC
 SG_ M2P_TMS_L_25_CP1_I_15 : 8|8@1+ (1,0) [0|255] "A"  PC
 SG_ M2P_TMS_L_25_CP1_r_15 : 16|8@1+ (100,0) [0|25500] "rpm"  PC
 SG_ Reserved_4 : 24|3@1+ (1,0) [0|7] ""  PC
 SG_ M2P_TMS_L_25_fan_fault_15 : 27|5@1+ (1,0) [0|31] ""  PC
 SG_ M2P_TMS_L_25_fre_fault_15 : 32|8@1+ (1,0) [0|255] ""  PC
 SG_ M2P_TMS_L_25_D_fault_15 : 40|8@1+ (1,0) [0|255] ""  PC
 SG_ M2P_TMS_L_AC2_25_P_15 : 48|16@1+ (1,0) [0|65535] ""  PC

BO_ 2337861280 M2P_LiquidInfo_9__16: 8 MBMU
 SG_ M2P_TMS_L_25_CP1_vol_16 : 0|8@1+ (2,0) [0|510] "V"  PC
 SG_ M2P_TMS_L_25_CP1_I_16 : 8|8@1+ (1,0) [0|255] "A"  PC
 SG_ M2P_TMS_L_25_CP1_r_16 : 16|8@1+ (100,0) [0|25500] "rpm"  PC
 SG_ Reserved_4 : 24|3@1+ (1,0) [0|7] ""  PC
 SG_ M2P_TMS_L_25_fan_fault_16 : 27|5@1+ (1,0) [0|31] ""  PC
 SG_ M2P_TMS_L_25_fre_fault_16 : 32|8@1+ (1,0) [0|255] ""  PC
 SG_ M2P_TMS_L_25_D_fault_16 : 40|8@1+ (1,0) [0|255] ""  PC
 SG_ M2P_TMS_L_AC2_25_P_16 : 48|16@1+ (1,0) [0|65535] ""  PC

BO_ 2337861281 M2P_LiquidInfo_9__17: 8 MBMU
 SG_ M2P_TMS_L_25_CP1_vol_17 : 0|8@1+ (2,0) [0|510] "V"  PC
 SG_ M2P_TMS_L_25_CP1_I_17 : 8|8@1+ (1,0) [0|255] "A"  PC
 SG_ M2P_TMS_L_25_CP1_r_17 : 16|8@1+ (100,0) [0|25500] "rpm"  PC
 SG_ Reserved_4 : 24|3@1+ (1,0) [0|7] ""  PC
 SG_ M2P_TMS_L_25_fan_fault_17 : 27|5@1+ (1,0) [0|31] ""  PC
 SG_ M2P_TMS_L_25_fre_fault_17 : 32|8@1+ (1,0) [0|255] ""  PC
 SG_ M2P_TMS_L_25_D_fault_17 : 40|8@1+ (1,0) [0|255] ""  PC
 SG_ M2P_TMS_L_AC2_25_P_17 : 48|16@1+ (1,0) [0|65535] ""  PC

BO_ 2337861282 M2P_LiquidInfo_9__18: 8 MBMU
 SG_ M2P_TMS_L_25_CP1_vol_18 : 0|8@1+ (2,0) [0|510] "V"  PC
 SG_ M2P_TMS_L_25_CP1_I_18 : 8|8@1+ (1,0) [0|255] "A"  PC
 SG_ M2P_TMS_L_25_CP1_r_18 : 16|8@1+ (100,0) [0|25500] "rpm"  PC
 SG_ Reserved_4 : 24|3@1+ (1,0) [0|7] ""  PC
 SG_ M2P_TMS_L_25_fan_fault_18 : 27|5@1+ (1,0) [0|31] ""  PC
 SG_ M2P_TMS_L_25_fre_fault_18 : 32|8@1+ (1,0) [0|255] ""  PC
 SG_ M2P_TMS_L_25_D_fault_18 : 40|8@1+ (1,0) [0|255] ""  PC
 SG_ M2P_TMS_L_AC2_25_P_18 : 48|16@1+ (1,0) [0|65535] ""  PC

BO_ 2337861283 M2P_LiquidInfo_9__19: 8 MBMU
 SG_ M2P_TMS_L_25_CP1_vol_19 : 0|8@1+ (2,0) [0|510] "V"  PC
 SG_ M2P_TMS_L_25_CP1_I_19 : 8|8@1+ (1,0) [0|255] "A"  PC
 SG_ M2P_TMS_L_25_CP1_r_19 : 16|8@1+ (100,0) [0|25500] "rpm"  PC
 SG_ Reserved_4 : 24|3@1+ (1,0) [0|7] ""  PC
 SG_ M2P_TMS_L_25_fan_fault_19 : 27|5@1+ (1,0) [0|31] ""  PC
 SG_ M2P_TMS_L_25_fre_fault_19 : 32|8@1+ (1,0) [0|255] ""  PC
 SG_ M2P_TMS_L_25_D_fault_19 : 40|8@1+ (1,0) [0|255] ""  PC
 SG_ M2P_TMS_L_AC2_25_P_19 : 48|16@1+ (1,0) [0|65535] ""  PC

BO_ 2337861284 M2P_LiquidInfo_9__20: 8 MBMU
 SG_ M2P_TMS_L_25_CP1_vol_20 : 0|8@1+ (2,0) [0|510] "V"  PC
 SG_ M2P_TMS_L_25_CP1_I_20 : 8|8@1+ (1,0) [0|255] "A"  PC
 SG_ M2P_TMS_L_25_CP1_r_20 : 16|8@1+ (100,0) [0|25500] "rpm"  PC
 SG_ Reserved_4 : 24|3@1+ (1,0) [0|7] ""  PC
 SG_ M2P_TMS_L_25_fan_fault_20 : 27|5@1+ (1,0) [0|31] ""  PC
 SG_ M2P_TMS_L_25_fre_fault_20 : 32|8@1+ (1,0) [0|255] ""  PC
 SG_ M2P_TMS_L_25_D_fault_20 : 40|8@1+ (1,0) [0|255] ""  PC
 SG_ M2P_TMS_L_AC2_25_P_20 : 48|16@1+ (1,0) [0|65535] ""  PC

BO_ 2337861285 M2P_LiquidInfo_9__21: 8 MBMU
 SG_ M2P_TMS_L_25_CP1_vol_21 : 0|8@1+ (2,0) [0|510] "V"  PC
 SG_ M2P_TMS_L_25_CP1_I_21 : 8|8@1+ (1,0) [0|255] "A"  PC
 SG_ M2P_TMS_L_25_CP1_r_21 : 16|8@1+ (100,0) [0|25500] "rpm"  PC
 SG_ Reserved_4 : 24|3@1+ (1,0) [0|7] ""  PC
 SG_ M2P_TMS_L_25_fan_fault_21 : 27|5@1+ (1,0) [0|31] ""  PC
 SG_ M2P_TMS_L_25_fre_fault_21 : 32|8@1+ (1,0) [0|255] ""  PC
 SG_ M2P_TMS_L_25_D_fault_21 : 40|8@1+ (1,0) [0|255] ""  PC
 SG_ M2P_TMS_L_AC2_25_P_21 : 48|16@1+ (1,0) [0|65535] ""  PC

BO_ 2337861286 M2P_LiquidInfo_9__22: 8 MBMU
 SG_ M2P_TMS_L_25_CP1_vol_22 : 0|8@1+ (2,0) [0|510] "V"  PC
 SG_ M2P_TMS_L_25_CP1_I_22 : 8|8@1+ (1,0) [0|255] "A"  PC
 SG_ M2P_TMS_L_25_CP1_r_22 : 16|8@1+ (100,0) [0|25500] "rpm"  PC
 SG_ Reserved_4 : 24|3@1+ (1,0) [0|7] ""  PC
 SG_ M2P_TMS_L_25_fan_fault_22 : 27|5@1+ (1,0) [0|31] ""  PC
 SG_ M2P_TMS_L_25_fre_fault_22 : 32|8@1+ (1,0) [0|255] ""  PC
 SG_ M2P_TMS_L_25_D_fault_22 : 40|8@1+ (1,0) [0|255] ""  PC
 SG_ M2P_TMS_L_AC2_25_P_22 : 48|16@1+ (1,0) [0|65535] ""  PC

BO_ 2337861287 M2P_LiquidInfo_9__23: 8 MBMU
 SG_ M2P_TMS_L_25_CP1_vol_23 : 0|8@1+ (2,0) [0|510] "V"  PC
 SG_ M2P_TMS_L_25_CP1_I_23 : 8|8@1+ (1,0) [0|255] "A"  PC
 SG_ M2P_TMS_L_25_CP1_r_23 : 16|8@1+ (100,0) [0|25500] "rpm"  PC
 SG_ Reserved_4 : 24|3@1+ (1,0) [0|7] ""  PC
 SG_ M2P_TMS_L_25_fan_fault_23 : 27|5@1+ (1,0) [0|31] ""  PC
 SG_ M2P_TMS_L_25_fre_fault_23 : 32|8@1+ (1,0) [0|255] ""  PC
 SG_ M2P_TMS_L_25_D_fault_23 : 40|8@1+ (1,0) [0|255] ""  PC
 SG_ M2P_TMS_L_AC2_25_P_23 : 48|16@1+ (1,0) [0|65535] ""  PC

BO_ 2337861288 M2P_LiquidInfo_9__24: 8 MBMU
 SG_ M2P_TMS_L_25_CP1_vol_24 : 0|8@1+ (2,0) [0|510] "V"  PC
 SG_ M2P_TMS_L_25_CP1_I_24 : 8|8@1+ (1,0) [0|255] "A"  PC
 SG_ M2P_TMS_L_25_CP1_r_24 : 16|8@1+ (100,0) [0|25500] "rpm"  PC
 SG_ Reserved_4 : 24|3@1+ (1,0) [0|7] ""  PC
 SG_ M2P_TMS_L_25_fan_fault_24 : 27|5@1+ (1,0) [0|31] ""  PC
 SG_ M2P_TMS_L_25_fre_fault_24 : 32|8@1+ (1,0) [0|255] ""  PC
 SG_ M2P_TMS_L_25_D_fault_24 : 40|8@1+ (1,0) [0|255] ""  PC
 SG_ M2P_TMS_L_AC2_25_P_24 : 48|16@1+ (1,0) [0|65535] ""  PC

BO_ 2337861289 M2P_LiquidInfo_9__25: 8 MBMU
 SG_ M2P_TMS_L_25_CP1_vol_25 : 0|8@1+ (2,0) [0|510] "V"  PC
 SG_ M2P_TMS_L_25_CP1_I_25 : 8|8@1+ (1,0) [0|255] "A"  PC
 SG_ M2P_TMS_L_25_CP1_r_25 : 16|8@1+ (100,0) [0|25500] "rpm"  PC
 SG_ Reserved_4 : 24|3@1+ (1,0) [0|7] ""  PC
 SG_ M2P_TMS_L_25_fan_fault_25 : 27|5@1+ (1,0) [0|31] ""  PC
 SG_ M2P_TMS_L_25_fre_fault_25 : 32|8@1+ (1,0) [0|255] ""  PC
 SG_ M2P_TMS_L_25_D_fault_25 : 40|8@1+ (1,0) [0|255] ""  PC
 SG_ M2P_TMS_L_AC2_25_P_25 : 48|16@1+ (1,0) [0|65535] ""  PC

CM_ SG_ 2337664675 M2P_TMS_R_S_version_19 "2号TMS 对应机组的软件号";
CM_ SG_ 2337664675 M2P_TMS_R_N_S_version_19 "2号TMS 对应机组更新的软件版本号";
CM_ SG_ 2337664676 M2P_TMS_R_S_version_20 "2号TMS 对应机组的软件号";
CM_ SG_ 2337664676 M2P_TMS_R_N_S_version_20 "2号TMS 对应机组更新的软件版本号";
CM_ SG_ 2337664677 M2P_TMS_R_S_version_21 "2号TMS 对应机组的软件号";
CM_ SG_ 2337664677 M2P_TMS_R_N_S_version_21 "2号TMS 对应机组更新的软件版本号";
CM_ SG_ 2337664678 M2P_TMS_R_S_version_22 "2号TMS 对应机组的软件号";
CM_ SG_ 2337664678 M2P_TMS_R_N_S_version_22 "2号TMS 对应机组更新的软件版本号";
CM_ SG_ 2337664679 M2P_TMS_R_S_version_23 "2号TMS 对应机组的软件号";
CM_ SG_ 2337664679 M2P_TMS_R_N_S_version_23 "2号TMS 对应机组更新的软件版本号";
CM_ SG_ 2337664680 M2P_TMS_R_S_version_24 "2号TMS 对应机组的软件号";
CM_ SG_ 2337664680 M2P_TMS_R_N_S_version_24 "2号TMS 对应机组更新的软件版本号";
CM_ SG_ 2337664681 M2P_TMS_R_S_version_25 "2号TMS 对应机组的软件号";
CM_ SG_ 2337664681 M2P_TMS_R_N_S_version_25 "2号TMS 对应机组更新的软件版本号";
CM_ SG_ 2337664682 M2P_TMS_R_S_version_26 "2号TMS 对应机组的软件号";
CM_ SG_ 2337664682 M2P_TMS_R_N_S_version_26 "2号TMS 对应机组更新的软件版本号";
CM_ SG_ 2337664683 M2P_TMS_R_S_version_27 "2号TMS 对应机组的软件号";
CM_ SG_ 2337664683 M2P_TMS_R_N_S_version_27 "2号TMS 对应机组更新的软件版本号";
CM_ SG_ 2337664684 M2P_TMS_R_S_version_28 "2号TMS 对应机组的软件号";
CM_ SG_ 2337664684 M2P_TMS_R_N_S_version_28 "2号TMS 对应机组更新的软件版本号";
CM_ SG_ 2337664685 M2P_TMS_R_S_version_29 "2号TMS 对应机组的软件号";
CM_ SG_ 2337664685 M2P_TMS_R_N_S_version_29 "2号TMS 对应机组更新的软件版本号";
CM_ SG_ 2337664686 M2P_TMS_R_S_version_30 "2号TMS 对应机组的软件号";
CM_ SG_ 2337664686 M2P_TMS_R_N_S_version_30 "2号TMS 对应机组更新的软件版本号";
CM_ SG_ 2337664687 M2P_TMS_R_S_version_31 "2号TMS 对应机组的软件号";
CM_ SG_ 2337664687 M2P_TMS_R_N_S_version_31 "2号TMS 对应机组更新的软件版本号";
CM_ SG_ 2337730193 M2P_TMS_L_ACDC_A_vol_01 "1号TMS ACDC_A 电压";
CM_ SG_ 2337730193 M2P_TMS_L_15_pwm_01 "1号TMS 15kw风机PWM";
CM_ SG_ 2337730193 M2P_TMS_L_15_HP_01 "1号TMS AC1高压压力值(15kw)";
CM_ SG_ 2337730193 M2P_TMS_L_15_LP_01 "1号TMS AC1低压压力值(15kw)";
CM_ SG_ 2337730193 M2P_TMS_L_25_HP_01 "1号TMS AC2高压压力值(25kw)";
CM_ SG_ 2337730194 M2P_TMS_L_ACDC_A_vol_02 "1号TMS ACDC_A 电压";
CM_ SG_ 2337730194 M2P_TMS_L_15_pwm_02 "1号TMS 15kw风机PWM";
CM_ SG_ 2337730194 M2P_TMS_L_15_HP_02 "1号TMS AC1高压压力值(15kw)";
CM_ SG_ 2337730194 M2P_TMS_L_15_LP_02 "1号TMS AC1低压压力值(15kw)";
CM_ SG_ 2337730194 M2P_TMS_L_25_HP_02 "1号TMS AC2高压压力值(25kw)";
CM_ SG_ 2337730195 M2P_TMS_L_ACDC_A_vol_03 "1号TMS ACDC_A 电压";
CM_ SG_ 2337730195 M2P_TMS_L_15_pwm_03 "1号TMS 15kw风机PWM";
CM_ SG_ 2337730195 M2P_TMS_L_15_HP_03 "1号TMS AC1高压压力值(15kw)";
CM_ SG_ 2337730195 M2P_TMS_L_15_LP_03 "1号TMS AC1低压压力值(15kw)";
CM_ SG_ 2337730195 M2P_TMS_L_25_HP_03 "1号TMS AC2高压压力值(25kw)";
CM_ SG_ 2337730196 M2P_TMS_L_ACDC_A_vol_04 "1号TMS ACDC_A 电压";
CM_ SG_ 2337730196 M2P_TMS_L_15_pwm_04 "1号TMS 15kw风机PWM";
CM_ SG_ 2337730196 M2P_TMS_L_15_HP_04 "1号TMS AC1高压压力值(15kw)";
CM_ SG_ 2337730196 M2P_TMS_L_15_LP_04 "1号TMS AC1低压压力值(15kw)";
CM_ SG_ 2337730196 M2P_TMS_L_25_HP_04 "1号TMS AC2高压压力值(25kw)";
CM_ SG_ 2337730197 M2P_TMS_L_ACDC_A_vol_05 "1号TMS ACDC_A 电压";
CM_ SG_ 2337730197 M2P_TMS_L_15_pwm_05 "1号TMS 15kw风机PWM";
CM_ SG_ 2337730197 M2P_TMS_L_15_HP_05 "1号TMS AC1高压压力值(15kw)";
CM_ SG_ 2337730197 M2P_TMS_L_15_LP_05 "1号TMS AC1低压压力值(15kw)";
CM_ SG_ 2337730197 M2P_TMS_L_25_HP_05 "1号TMS AC2高压压力值(25kw)";
CM_ SG_ 2337730198 M2P_TMS_L_ACDC_A_vol_06 "1号TMS ACDC_A 电压";
CM_ SG_ 2337730198 M2P_TMS_L_15_pwm_06 "1号TMS 15kw风机PWM";
CM_ SG_ 2337730198 M2P_TMS_L_15_HP_06 "1号TMS AC1高压压力值(15kw)";
CM_ SG_ 2337730198 M2P_TMS_L_15_LP_06 "1号TMS AC1低压压力值(15kw)";
CM_ SG_ 2337730198 M2P_TMS_L_25_HP_06 "1号TMS AC2高压压力值(25kw)";
CM_ SG_ 2337730199 M2P_TMS_L_ACDC_A_vol_07 "1号TMS ACDC_A 电压";
CM_ SG_ 2337730199 M2P_TMS_L_15_pwm_07 "1号TMS 15kw风机PWM";
CM_ SG_ 2337730199 M2P_TMS_L_15_HP_07 "1号TMS AC1高压压力值(15kw)";
CM_ SG_ 2337730199 M2P_TMS_L_15_LP_07 "1号TMS AC1低压压力值(15kw)";
CM_ SG_ 2337730199 M2P_TMS_L_25_HP_07 "1号TMS AC2高压压力值(25kw)";
CM_ SG_ 2337730200 M2P_TMS_L_ACDC_A_vol_08 "1号TMS ACDC_A 电压";
CM_ SG_ 2337730200 M2P_TMS_L_15_pwm_08 "1号TMS 15kw风机PWM";
CM_ SG_ 2337730200 M2P_TMS_L_15_HP_08 "1号TMS AC1高压压力值(15kw)";
CM_ SG_ 2337730200 M2P_TMS_L_15_LP_08 "1号TMS AC1低压压力值(15kw)";
CM_ SG_ 2337730200 M2P_TMS_L_25_HP_08 "1号TMS AC2高压压力值(25kw)";
CM_ SG_ 2337730201 M2P_TMS_L_ACDC_A_vol_09 "1号TMS ACDC_A 电压";
CM_ SG_ 2337730201 M2P_TMS_L_15_pwm_09 "1号TMS 15kw风机PWM";
CM_ SG_ 2337730201 M2P_TMS_L_15_HP_09 "1号TMS AC1高压压力值(15kw)";
CM_ SG_ 2337730201 M2P_TMS_L_15_LP_09 "1号TMS AC1低压压力值(15kw)";
CM_ SG_ 2337730201 M2P_TMS_L_25_HP_09 "1号TMS AC2高压压力值(25kw)";
CM_ SG_ 2337730202 M2P_TMS_L_ACDC_A_vol_10 "1号TMS ACDC_A 电压";
CM_ SG_ 2337730202 M2P_TMS_L_15_pwm_10 "1号TMS 15kw风机PWM";
CM_ SG_ 2337730202 M2P_TMS_L_15_HP_10 "1号TMS AC1高压压力值(15kw)";
CM_ SG_ 2337730202 M2P_TMS_L_15_LP_10 "1号TMS AC1低压压力值(15kw)";
CM_ SG_ 2337730202 M2P_TMS_L_25_HP_10 "1号TMS AC2高压压力值(25kw)";
CM_ SG_ 2337730203 M2P_TMS_L_ACDC_A_vol_11 "1号TMS ACDC_A 电压";
CM_ SG_ 2337730203 M2P_TMS_L_15_pwm_11 "1号TMS 15kw风机PWM";
CM_ SG_ 2337730203 M2P_TMS_L_15_HP_11 "1号TMS AC1高压压力值(15kw)";
CM_ SG_ 2337730203 M2P_TMS_L_15_LP_11 "1号TMS AC1低压压力值(15kw)";
CM_ SG_ 2337730203 M2P_TMS_L_25_HP_11 "1号TMS AC2高压压力值(25kw)";
CM_ SG_ 2337730204 M2P_TMS_L_ACDC_A_vol_12 "1号TMS ACDC_A 电压";
CM_ SG_ 2337730204 M2P_TMS_L_15_pwm_12 "1号TMS 15kw风机PWM";
CM_ SG_ 2337730204 M2P_TMS_L_15_HP_12 "1号TMS AC1高压压力值(15kw)";
CM_ SG_ 2337730204 M2P_TMS_L_15_LP_12 "1号TMS AC1低压压力值(15kw)";
CM_ SG_ 2337730204 M2P_TMS_L_25_HP_12 "1号TMS AC2高压压力值(25kw)";
CM_ SG_ 2337730205 M2P_TMS_L_ACDC_A_vol_13 "1号TMS ACDC_A 电压";
CM_ SG_ 2337730205 M2P_TMS_L_15_pwm_13 "1号TMS 15kw风机PWM";
CM_ SG_ 2337730205 M2P_TMS_L_15_HP_13 "1号TMS AC1高压压力值(15kw)";
CM_ SG_ 2337730205 M2P_TMS_L_15_LP_13 "1号TMS AC1低压压力值(15kw)";
CM_ SG_ 2337730205 M2P_TMS_L_25_HP_13 "1号TMS AC2高压压力值(25kw)";
CM_ SG_ 2337730206 M2P_TMS_L_ACDC_A_vol_14 "1号TMS ACDC_A 电压";
CM_ SG_ 2337730206 M2P_TMS_L_15_pwm_14 "1号TMS 15kw风机PWM";
CM_ SG_ 2337730206 M2P_TMS_L_15_HP_14 "1号TMS AC1高压压力值(15kw)";
CM_ SG_ 2337730206 M2P_TMS_L_15_LP_14 "1号TMS AC1低压压力值(15kw)";
CM_ SG_ 2337730206 M2P_TMS_L_25_HP_14 "1号TMS AC2高压压力值(25kw)";
CM_ SG_ 2337730207 M2P_TMS_L_ACDC_A_vol_15 "1号TMS ACDC_A 电压";
CM_ SG_ 2337730207 M2P_TMS_L_15_pwm_15 "1号TMS 15kw风机PWM";
CM_ SG_ 2337730207 M2P_TMS_L_15_HP_15 "1号TMS AC1高压压力值(15kw)";
CM_ SG_ 2337730207 M2P_TMS_L_15_LP_15 "1号TMS AC1低压压力值(15kw)";
CM_ SG_ 2337730207 M2P_TMS_L_25_HP_15 "1号TMS AC2高压压力值(25kw)";
CM_ SG_ 2337730208 M2P_TMS_L_ACDC_A_vol_16 "1号TMS ACDC_A 电压";
CM_ SG_ 2337730208 M2P_TMS_L_15_pwm_16 "1号TMS 15kw风机PWM";
CM_ SG_ 2337730208 M2P_TMS_L_15_HP_16 "1号TMS AC1高压压力值(15kw)";
CM_ SG_ 2337730208 M2P_TMS_L_15_LP_16 "1号TMS AC1低压压力值(15kw)";
CM_ SG_ 2337730208 M2P_TMS_L_25_HP_16 "1号TMS AC2高压压力值(25kw)";
CM_ SG_ 2337730209 M2P_TMS_L_ACDC_A_vol_17 "1号TMS ACDC_A 电压";
CM_ SG_ 2337730209 M2P_TMS_L_15_pwm_17 "1号TMS 15kw风机PWM";
CM_ SG_ 2337730209 M2P_TMS_L_15_HP_17 "1号TMS AC1高压压力值(15kw)";
CM_ SG_ 2337730209 M2P_TMS_L_15_LP_17 "1号TMS AC1低压压力值(15kw)";
CM_ SG_ 2337730209 M2P_TMS_L_25_HP_17 "1号TMS AC2高压压力值(25kw)";
CM_ SG_ 2337730210 M2P_TMS_L_ACDC_A_vol_18 "1号TMS ACDC_A 电压";
CM_ SG_ 2337730210 M2P_TMS_L_15_pwm_18 "1号TMS 15kw风机PWM";
CM_ SG_ 2337730210 M2P_TMS_L_15_HP_18 "1号TMS AC1高压压力值(15kw)";
CM_ SG_ 2337730210 M2P_TMS_L_15_LP_18 "1号TMS AC1低压压力值(15kw)";
CM_ SG_ 2337730210 M2P_TMS_L_25_HP_18 "1号TMS AC2高压压力值(25kw)";
CM_ SG_ 2337730211 M2P_TMS_L_ACDC_A_vol_19 "1号TMS ACDC_A 电压";
CM_ SG_ 2337730211 M2P_TMS_L_15_pwm_19 "1号TMS 15kw风机PWM";
CM_ SG_ 2337730211 M2P_TMS_L_15_HP_19 "1号TMS AC1高压压力值(15kw)";
CM_ SG_ 2337730211 M2P_TMS_L_15_LP_19 "1号TMS AC1低压压力值(15kw)";
CM_ SG_ 2337730211 M2P_TMS_L_25_HP_19 "1号TMS AC2高压压力值(25kw)";
CM_ SG_ 2337730212 M2P_TMS_L_ACDC_A_vol_20 "1号TMS ACDC_A 电压";
CM_ SG_ 2337730212 M2P_TMS_L_15_pwm_20 "1号TMS 15kw风机PWM";
CM_ SG_ 2337730212 M2P_TMS_L_15_HP_20 "1号TMS AC1高压压力值(15kw)";
CM_ SG_ 2337730212 M2P_TMS_L_15_LP_20 "1号TMS AC1低压压力值(15kw)";
CM_ SG_ 2337730212 M2P_TMS_L_25_HP_20 "1号TMS AC2高压压力值(25kw)";
CM_ SG_ 2337730213 M2P_TMS_L_ACDC_A_vol_21 "1号TMS ACDC_A 电压";
CM_ SG_ 2337730213 M2P_TMS_L_15_pwm_21 "1号TMS 15kw风机PWM";
CM_ SG_ 2337730213 M2P_TMS_L_15_HP_21 "1号TMS AC1高压压力值(15kw)";
CM_ SG_ 2337730213 M2P_TMS_L_15_LP_21 "1号TMS AC1低压压力值(15kw)";
CM_ SG_ 2337730213 M2P_TMS_L_25_HP_21 "1号TMS AC2高压压力值(25kw)";
CM_ SG_ 2337730214 M2P_TMS_L_ACDC_A_vol_22 "1号TMS ACDC_A 电压";
CM_ SG_ 2337730214 M2P_TMS_L_15_pwm_22 "1号TMS 15kw风机PWM";
CM_ SG_ 2337730214 M2P_TMS_L_15_HP_22 "1号TMS AC1高压压力值(15kw)";
CM_ SG_ 2337730214 M2P_TMS_L_15_LP_22 "1号TMS AC1低压压力值(15kw)";
CM_ SG_ 2337730214 M2P_TMS_L_25_HP_22 "1号TMS AC2高压压力值(25kw)";
CM_ SG_ 2337730215 M2P_TMS_L_ACDC_A_vol_23 "1号TMS ACDC_A 电压";
CM_ SG_ 2337730215 M2P_TMS_L_15_pwm_23 "1号TMS 15kw风机PWM";
CM_ SG_ 2337730215 M2P_TMS_L_15_HP_23 "1号TMS AC1高压压力值(15kw)";
CM_ SG_ 2337730215 M2P_TMS_L_15_LP_23 "1号TMS AC1低压压力值(15kw)";
CM_ SG_ 2337730215 M2P_TMS_L_25_HP_23 "1号TMS AC2高压压力值(25kw)";
CM_ SG_ 2337730216 M2P_TMS_L_ACDC_A_vol_24 "1号TMS ACDC_A 电压";
CM_ SG_ 2337730216 M2P_TMS_L_15_pwm_24 "1号TMS 15kw风机PWM";
CM_ SG_ 2337730216 M2P_TMS_L_15_HP_24 "1号TMS AC1高压压力值(15kw)";
CM_ SG_ 2337730216 M2P_TMS_L_15_LP_24 "1号TMS AC1低压压力值(15kw)";
CM_ SG_ 2337730216 M2P_TMS_L_25_HP_24 "1号TMS AC2高压压力值(25kw)";
CM_ SG_ 2337730217 M2P_TMS_L_ACDC_A_vol_25 "1号TMS ACDC_A 电压";
CM_ SG_ 2337730217 M2P_TMS_L_15_pwm_25 "1号TMS 15kw风机PWM";
CM_ SG_ 2337730217 M2P_TMS_L_15_HP_25 "1号TMS AC1高压压力值(15kw)";
CM_ SG_ 2337730217 M2P_TMS_L_15_LP_25 "1号TMS AC1低压压力值(15kw)";
CM_ SG_ 2337730217 M2P_TMS_L_25_HP_25 "1号TMS AC2高压压力值(25kw)";
CM_ SG_ 2337730218 M2P_TMS_L_ACDC_A_vol_26 "1号TMS ACDC_A 电压";
CM_ SG_ 2337730218 M2P_TMS_L_15_pwm_26 "1号TMS 15kw风机PWM";
CM_ SG_ 2337730218 M2P_TMS_L_15_HP_26 "1号TMS AC1高压压力值(15kw)";
CM_ SG_ 2337730218 M2P_TMS_L_15_LP_26 "1号TMS AC1低压压力值(15kw)";
CM_ SG_ 2337730218 M2P_TMS_L_25_HP_26 "1号TMS AC2高压压力值(25kw)";
CM_ SG_ 2337730219 M2P_TMS_L_ACDC_A_vol_27 "1号TMS ACDC_A 电压";
CM_ SG_ 2337730219 M2P_TMS_L_15_pwm_27 "1号TMS 15kw风机PWM";
CM_ SG_ 2337730219 M2P_TMS_L_15_HP_27 "1号TMS AC1高压压力值(15kw)";
CM_ SG_ 2337730219 M2P_TMS_L_15_LP_27 "1号TMS AC1低压压力值(15kw)";
CM_ SG_ 2337730219 M2P_TMS_L_25_HP_27 "1号TMS AC2高压压力值(25kw)";
CM_ SG_ 2337730220 M2P_TMS_L_ACDC_A_vol_28 "1号TMS ACDC_A 电压";
CM_ SG_ 2337730220 M2P_TMS_L_15_pwm_28 "1号TMS 15kw风机PWM";
CM_ SG_ 2337730220 M2P_TMS_L_15_HP_28 "1号TMS AC1高压压力值(15kw)";
CM_ SG_ 2337730220 M2P_TMS_L_15_LP_28 "1号TMS AC1低压压力值(15kw)";
CM_ SG_ 2337730220 M2P_TMS_L_25_HP_28 "1号TMS AC2高压压力值(25kw)";
CM_ SG_ 2337730221 M2P_TMS_L_ACDC_A_vol_29 "1号TMS ACDC_A 电压";
CM_ SG_ 2337730221 M2P_TMS_L_15_pwm_29 "1号TMS 15kw风机PWM";
CM_ SG_ 2337730221 M2P_TMS_L_15_HP_29 "1号TMS AC1高压压力值(15kw)";
CM_ SG_ 2337730221 M2P_TMS_L_15_LP_29 "1号TMS AC1低压压力值(15kw)";
CM_ SG_ 2337730221 M2P_TMS_L_25_HP_29 "1号TMS AC2高压压力值(25kw)";
CM_ SG_ 2337730222 M2P_TMS_L_ACDC_A_vol_30 "1号TMS ACDC_A 电压";
CM_ SG_ 2337730222 M2P_TMS_L_15_pwm_30 "1号TMS 15kw风机PWM";
CM_ SG_ 2337730222 M2P_TMS_L_15_HP_30 "1号TMS AC1高压压力值(15kw)";
CM_ SG_ 2337730222 M2P_TMS_L_15_LP_30 "1号TMS AC1低压压力值(15kw)";
CM_ SG_ 2337730222 M2P_TMS_L_25_HP_30 "1号TMS AC2高压压力值(25kw)";
CM_ SG_ 2337730223 M2P_TMS_L_ACDC_A_vol_31 "1号TMS ACDC_A 电压";
CM_ SG_ 2337730223 M2P_TMS_L_15_pwm_31 "1号TMS 15kw风机PWM";
CM_ SG_ 2337730223 M2P_TMS_L_15_HP_31 "1号TMS AC1高压压力值(15kw)";
CM_ SG_ 2337730223 M2P_TMS_L_15_LP_31 "1号TMS AC1低压压力值(15kw)";
CM_ SG_ 2337730223 M2P_TMS_L_25_HP_31 "1号TMS AC2高压压力值(25kw)";
CM_ SG_ 2337795729 M2P_TMS_L_15_CP1_vol_01 "1号TMS压缩机1电压(15kw)";
CM_ SG_ 2337795729 M2P_TMS_L_15_CP1_I_01 "1号TMS压缩机1电流(15kw)";
CM_ SG_ 2337795729 M2P_TMS_L_15_CP1_r_01 "1号TMS压缩机1转速(15kw)";
CM_ SG_ 2337795729 M2P_TMS_L_TEM_01 "1号TMSPTC温度开关状态";
CM_ SG_ 2337795729 M2P_TMS_L_WPS_01 "1号TMS水泵开关";
CM_ SG_ 2337795729 M2P_TMS_L_15_fan_fault_01 "1号TMS风机故障(15kw)";
CM_ SG_ 2337795729 M2P_TMS_L_15_fre_fault_01 "1号TMS AC1故障(15kw变频器)";
CM_ SG_ 2337795729 M2P_TMS_L_15_D_fault_01 "1号TMS AC1故障(15kwDC/DC)";
CM_ SG_ 2337795729 M2P_TMS_L_FAN_PWM "1号TMS冷却风机PWM占空比";
CM_ SG_ 2337795729 M2P_TMS_L_25_FAN_PWM_01 "1号TMS25kw风机PWM";
CM_ SG_ 2337795730 M2P_TMS_L_15_CP1_vol_02 "1号TMS压缩机1电压(15kw)";
CM_ SG_ 2337795730 M2P_TMS_L_15_CP1_I_02 "1号TMS压缩机1电流(15kw)";
CM_ SG_ 2337795730 M2P_TMS_L_15_CP1_r_02 "1号TMS压缩机1转速(15kw)";
CM_ SG_ 2337795730 M2P_TMS_L_TEM_02 "1号TMSPTC温度开关状态";
CM_ SG_ 2337795730 M2P_TMS_L_WPS_02 "1号TMS水泵开关";
CM_ SG_ 2337795730 M2P_TMS_L_15_fan_fault_02 "1号TMS风机故障(15kw)";
CM_ SG_ 2337795730 M2P_TMS_L_15_fre_fault_02 "1号TMS AC1故障(15kw变频器)";
CM_ SG_ 2337795730 M2P_TMS_L_15_D_fault_02 "1号TMS AC1故障(15kwDC/DC)";
CM_ SG_ 2337795730 M2P_TMS_L_FAN_PWM "1号TMS冷却风机PWM占空比";
CM_ SG_ 2337795730 M2P_TMS_L_25_FAN_PWM_02 "1号TMS25kw风机PWM";
CM_ SG_ 2337795731 M2P_TMS_L_15_CP1_vol_03 "1号TMS压缩机1电压(15kw)";
CM_ SG_ 2337795731 M2P_TMS_L_15_CP1_I_03 "1号TMS压缩机1电流(15kw)";
CM_ SG_ 2337795731 M2P_TMS_L_15_CP1_r_03 "1号TMS压缩机1转速(15kw)";
CM_ SG_ 2337795731 M2P_TMS_L_TEM_03 "1号TMSPTC温度开关状态";
CM_ SG_ 2337795731 M2P_TMS_L_WPS_03 "1号TMS水泵开关";
CM_ SG_ 2337795731 M2P_TMS_L_15_fan_fault_03 "1号TMS风机故障(15kw)";
CM_ SG_ 2337795731 M2P_TMS_L_15_fre_fault_03 "1号TMS AC1故障(15kw变频器)";
CM_ SG_ 2337795731 M2P_TMS_L_15_D_fault_03 "1号TMS AC1故障(15kwDC/DC)";
CM_ SG_ 2337795731 M2P_TMS_L_FAN_PWM "1号TMS冷却风机PWM占空比";
CM_ SG_ 2337795731 M2P_TMS_L_25_FAN_PWM_03 "1号TMS25kw风机PWM";
CM_ SG_ 2337795732 M2P_TMS_L_15_CP1_vol_04 "1号TMS压缩机1电压(15kw)";
CM_ SG_ 2337795732 M2P_TMS_L_15_CP1_I_04 "1号TMS压缩机1电流(15kw)";
CM_ SG_ 2337795732 M2P_TMS_L_15_CP1_r_04 "1号TMS压缩机1转速(15kw)";
CM_ SG_ 2337795732 M2P_TMS_L_TEM_04 "1号TMSPTC温度开关状态";
CM_ SG_ 2337795732 M2P_TMS_L_WPS_04 "1号TMS水泵开关";
CM_ SG_ 2337795732 M2P_TMS_L_15_fan_fault_04 "1号TMS风机故障(15kw)";
CM_ SG_ 2337795732 M2P_TMS_L_15_fre_fault_04 "1号TMS AC1故障(15kw变频器)";
CM_ SG_ 2337795732 M2P_TMS_L_15_D_fault_04 "1号TMS AC1故障(15kwDC/DC)";
CM_ SG_ 2337795732 M2P_TMS_L_FAN_PWM "1号TMS冷却风机PWM占空比";
CM_ SG_ 2337795732 M2P_TMS_L_25_FAN_PWM_04 "1号TMS25kw风机PWM";
CM_ SG_ 2337795733 M2P_TMS_L_15_CP1_vol_05 "1号TMS压缩机1电压(15kw)";
CM_ SG_ 2337795733 M2P_TMS_L_15_CP1_I_05 "1号TMS压缩机1电流(15kw)";
CM_ SG_ 2337795733 M2P_TMS_L_15_CP1_r_05 "1号TMS压缩机1转速(15kw)";
CM_ SG_ 2337795733 M2P_TMS_L_TEM_05 "1号TMSPTC温度开关状态";
CM_ SG_ 2337795733 M2P_TMS_L_WPS_05 "1号TMS水泵开关";
CM_ SG_ 2337795733 M2P_TMS_L_15_fan_fault_05 "1号TMS风机故障(15kw)";
CM_ SG_ 2337795733 M2P_TMS_L_15_fre_fault_05 "1号TMS AC1故障(15kw变频器)";
CM_ SG_ 2337795733 M2P_TMS_L_15_D_fault_05 "1号TMS AC1故障(15kwDC/DC)";
CM_ SG_ 2337795733 M2P_TMS_L_FAN_PWM "1号TMS冷却风机PWM占空比";
CM_ SG_ 2337795733 M2P_TMS_L_25_FAN_PWM_05 "1号TMS25kw风机PWM";
CM_ SG_ 2337795734 M2P_TMS_L_15_CP1_vol_06 "1号TMS压缩机1电压(15kw)";
CM_ SG_ 2337795734 M2P_TMS_L_15_CP1_I_06 "1号TMS压缩机1电流(15kw)";
CM_ SG_ 2337795734 M2P_TMS_L_15_CP1_r_06 "1号TMS压缩机1转速(15kw)";
CM_ SG_ 2337795734 M2P_TMS_L_TEM_06 "1号TMSPTC温度开关状态";
CM_ SG_ 2337795734 M2P_TMS_L_WPS_06 "1号TMS水泵开关";
CM_ SG_ 2337795734 M2P_TMS_L_15_fan_fault_06 "1号TMS风机故障(15kw)";
CM_ SG_ 2337795734 M2P_TMS_L_15_fre_fault_06 "1号TMS AC1故障(15kw变频器)";
CM_ SG_ 2337795734 M2P_TMS_L_15_D_fault_06 "1号TMS AC1故障(15kwDC/DC)";
CM_ SG_ 2337795734 M2P_TMS_L_FAN_PWM "1号TMS冷却风机PWM占空比";
CM_ SG_ 2337795734 M2P_TMS_L_25_FAN_PWM_06 "1号TMS25kw风机PWM";
CM_ SG_ 2337795735 M2P_TMS_L_15_CP1_vol_07 "1号TMS压缩机1电压(15kw)";
CM_ SG_ 2337795735 M2P_TMS_L_15_CP1_I_07 "1号TMS压缩机1电流(15kw)";
CM_ SG_ 2337795735 M2P_TMS_L_15_CP1_r_07 "1号TMS压缩机1转速(15kw)";
CM_ SG_ 2337795735 M2P_TMS_L_TEM_07 "1号TMSPTC温度开关状态";
CM_ SG_ 2337795735 M2P_TMS_L_WPS_07 "1号TMS水泵开关";
CM_ SG_ 2337795735 M2P_TMS_L_15_fan_fault_07 "1号TMS风机故障(15kw)";
CM_ SG_ 2337795735 M2P_TMS_L_15_fre_fault_07 "1号TMS AC1故障(15kw变频器)";
CM_ SG_ 2337795735 M2P_TMS_L_15_D_fault_07 "1号TMS AC1故障(15kwDC/DC)";
CM_ SG_ 2337795735 M2P_TMS_L_FAN_PWM "1号TMS冷却风机PWM占空比";
CM_ SG_ 2337795735 M2P_TMS_L_25_FAN_PWM_07 "1号TMS25kw风机PWM";
CM_ SG_ 2337795736 M2P_TMS_L_15_CP1_vol_08 "1号TMS压缩机1电压(15kw)";
CM_ SG_ 2337795736 M2P_TMS_L_15_CP1_I_08 "1号TMS压缩机1电流(15kw)";
CM_ SG_ 2337795736 M2P_TMS_L_15_CP1_r_08 "1号TMS压缩机1转速(15kw)";
CM_ SG_ 2337795736 M2P_TMS_L_TEM_08 "1号TMSPTC温度开关状态";
CM_ SG_ 2337795736 M2P_TMS_L_WPS_08 "1号TMS水泵开关";
CM_ SG_ 2337795736 M2P_TMS_L_15_fan_fault_08 "1号TMS风机故障(15kw)";
CM_ SG_ 2337795736 M2P_TMS_L_15_fre_fault_08 "1号TMS AC1故障(15kw变频器)";
CM_ SG_ 2337795736 M2P_TMS_L_15_D_fault_08 "1号TMS AC1故障(15kwDC/DC)";
CM_ SG_ 2337795736 M2P_TMS_L_FAN_PWM "1号TMS冷却风机PWM占空比";
CM_ SG_ 2337795736 M2P_TMS_L_25_FAN_PWM_08 "1号TMS25kw风机PWM";
CM_ SG_ 2337795737 M2P_TMS_L_15_CP1_vol_09 "1号TMS压缩机1电压(15kw)";
CM_ SG_ 2337795737 M2P_TMS_L_15_CP1_I_09 "1号TMS压缩机1电流(15kw)";
CM_ SG_ 2337795737 M2P_TMS_L_15_CP1_r_09 "1号TMS压缩机1转速(15kw)";
CM_ SG_ 2337795737 M2P_TMS_L_TEM_09 "1号TMSPTC温度开关状态";
CM_ SG_ 2337795737 M2P_TMS_L_WPS_09 "1号TMS水泵开关";
CM_ SG_ 2337795737 M2P_TMS_L_15_fan_fault_09 "1号TMS风机故障(15kw)";
CM_ SG_ 2337795737 M2P_TMS_L_15_fre_fault_09 "1号TMS AC1故障(15kw变频器)";
CM_ SG_ 2337795737 M2P_TMS_L_15_D_fault_09 "1号TMS AC1故障(15kwDC/DC)";
CM_ SG_ 2337795737 M2P_TMS_L_FAN_PWM "1号TMS冷却风机PWM占空比";
CM_ SG_ 2337795737 M2P_TMS_L_25_FAN_PWM_09 "1号TMS25kw风机PWM";
CM_ SG_ 2337795738 M2P_TMS_L_15_CP1_vol_10 "1号TMS压缩机1电压(15kw)";
CM_ SG_ 2337795738 M2P_TMS_L_15_CP1_I_10 "1号TMS压缩机1电流(15kw)";
CM_ SG_ 2337795738 M2P_TMS_L_15_CP1_r_10 "1号TMS压缩机1转速(15kw)";
CM_ SG_ 2337795738 M2P_TMS_L_TEM_10 "1号TMSPTC温度开关状态";
CM_ SG_ 2337795738 M2P_TMS_L_WPS_10 "1号TMS水泵开关";
CM_ SG_ 2337795738 M2P_TMS_L_15_fan_fault_10 "1号TMS风机故障(15kw)";
CM_ SG_ 2337795738 M2P_TMS_L_15_fre_fault_10 "1号TMS AC1故障(15kw变频器)";
CM_ SG_ 2337795738 M2P_TMS_L_15_D_fault_10 "1号TMS AC1故障(15kwDC/DC)";
CM_ SG_ 2337795738 M2P_TMS_L_FAN_PWM "1号TMS冷却风机PWM占空比";
CM_ SG_ 2337795738 M2P_TMS_L_25_FAN_PWM_10 "1号TMS25kw风机PWM";
CM_ SG_ 2337795739 M2P_TMS_L_15_CP1_vol_11 "1号TMS压缩机1电压(15kw)";
CM_ SG_ 2337795739 M2P_TMS_L_15_CP1_I_11 "1号TMS压缩机1电流(15kw)";
CM_ SG_ 2337795739 M2P_TMS_L_15_CP1_r_11 "1号TMS压缩机1转速(15kw)";
CM_ SG_ 2337795739 M2P_TMS_L_TEM_11 "1号TMSPTC温度开关状态";
CM_ SG_ 2337795739 M2P_TMS_L_WPS_11 "1号TMS水泵开关";
CM_ SG_ 2337795739 M2P_TMS_L_15_fan_fault_11 "1号TMS风机故障(15kw)";
CM_ SG_ 2337795739 M2P_TMS_L_15_fre_fault_11 "1号TMS AC1故障(15kw变频器)";
CM_ SG_ 2337795739 M2P_TMS_L_15_D_fault_11 "1号TMS AC1故障(15kwDC/DC)";
CM_ SG_ 2337795739 M2P_TMS_L_FAN_PWM "1号TMS冷却风机PWM占空比";
CM_ SG_ 2337795739 M2P_TMS_L_25_FAN_PWM_11 "1号TMS25kw风机PWM";
CM_ SG_ 2337795740 M2P_TMS_L_15_CP1_vol_12 "1号TMS压缩机1电压(15kw)";
CM_ SG_ 2337795740 M2P_TMS_L_15_CP1_I_12 "1号TMS压缩机1电流(15kw)";
CM_ SG_ 2337795740 M2P_TMS_L_15_CP1_r_12 "1号TMS压缩机1转速(15kw)";
CM_ SG_ 2337795740 M2P_TMS_L_TEM_12 "1号TMSPTC温度开关状态";
CM_ SG_ 2337795740 M2P_TMS_L_WPS_12 "1号TMS水泵开关";
CM_ SG_ 2337795740 M2P_TMS_L_15_fan_fault_12 "1号TMS风机故障(15kw)";
CM_ SG_ 2337795740 M2P_TMS_L_15_fre_fault_12 "1号TMS AC1故障(15kw变频器)";
CM_ SG_ 2337795740 M2P_TMS_L_15_D_fault_12 "1号TMS AC1故障(15kwDC/DC)";
CM_ SG_ 2337795740 M2P_TMS_L_FAN_PWM "1号TMS冷却风机PWM占空比";
CM_ SG_ 2337795740 M2P_TMS_L_25_FAN_PWM_12 "1号TMS25kw风机PWM";
CM_ SG_ 2337795741 M2P_TMS_L_15_CP1_vol_13 "1号TMS压缩机1电压(15kw)";
CM_ SG_ 2337795741 M2P_TMS_L_15_CP1_I_13 "1号TMS压缩机1电流(15kw)";
CM_ SG_ 2337795741 M2P_TMS_L_15_CP1_r_13 "1号TMS压缩机1转速(15kw)";
CM_ SG_ 2337795741 M2P_TMS_L_TEM_13 "1号TMSPTC温度开关状态";
CM_ SG_ 2337795741 M2P_TMS_L_WPS_13 "1号TMS水泵开关";
CM_ SG_ 2337795741 M2P_TMS_L_15_fan_fault_13 "1号TMS风机故障(15kw)";
CM_ SG_ 2337795741 M2P_TMS_L_15_fre_fault_13 "1号TMS AC1故障(15kw变频器)";
CM_ SG_ 2337795741 M2P_TMS_L_15_D_fault_13 "1号TMS AC1故障(15kwDC/DC)";
CM_ SG_ 2337795741 M2P_TMS_L_FAN_PWM "1号TMS冷却风机PWM占空比";
CM_ SG_ 2337795741 M2P_TMS_L_25_FAN_PWM_13 "1号TMS25kw风机PWM";
CM_ SG_ 2337795742 M2P_TMS_L_15_CP1_vol_14 "1号TMS压缩机1电压(15kw)";
CM_ SG_ 2337795742 M2P_TMS_L_15_CP1_I_14 "1号TMS压缩机1电流(15kw)";
CM_ SG_ 2337795742 M2P_TMS_L_15_CP1_r_14 "1号TMS压缩机1转速(15kw)";
CM_ SG_ 2337795742 M2P_TMS_L_TEM_14 "1号TMSPTC温度开关状态";
CM_ SG_ 2337795742 M2P_TMS_L_WPS_14 "1号TMS水泵开关";
CM_ SG_ 2337795742 M2P_TMS_L_15_fan_fault_14 "1号TMS风机故障(15kw)";
CM_ SG_ 2337795742 M2P_TMS_L_15_fre_fault_14 "1号TMS AC1故障(15kw变频器)";
CM_ SG_ 2337795742 M2P_TMS_L_15_D_fault_14 "1号TMS AC1故障(15kwDC/DC)";
CM_ SG_ 2337795742 M2P_TMS_L_FAN_PWM "1号TMS冷却风机PWM占空比";
CM_ SG_ 2337795742 M2P_TMS_L_25_FAN_PWM_14 "1号TMS25kw风机PWM";
CM_ SG_ 2337795743 M2P_TMS_L_15_CP1_vol_15 "1号TMS压缩机1电压(15kw)";
CM_ SG_ 2337795743 M2P_TMS_L_15_CP1_I_15 "1号TMS压缩机1电流(15kw)";
CM_ SG_ 2337795743 M2P_TMS_L_15_CP1_r_15 "1号TMS压缩机1转速(15kw)";
CM_ SG_ 2337795743 M2P_TMS_L_TEM_15 "1号TMSPTC温度开关状态";
CM_ SG_ 2337795743 M2P_TMS_L_WPS_15 "1号TMS水泵开关";
CM_ SG_ 2337795743 M2P_TMS_L_15_fan_fault_15 "1号TMS风机故障(15kw)";
CM_ SG_ 2337795743 M2P_TMS_L_15_fre_fault_15 "1号TMS AC1故障(15kw变频器)";
CM_ SG_ 2337795743 M2P_TMS_L_15_D_fault_15 "1号TMS AC1故障(15kwDC/DC)";
CM_ SG_ 2337795743 M2P_TMS_L_FAN_PWM "1号TMS冷却风机PWM占空比";
CM_ SG_ 2337795743 M2P_TMS_L_25_FAN_PWM_15 "1号TMS25kw风机PWM";
CM_ SG_ 2337795744 M2P_TMS_L_15_CP1_vol_16 "1号TMS压缩机1电压(15kw)";
CM_ SG_ 2337795744 M2P_TMS_L_15_CP1_I_16 "1号TMS压缩机1电流(15kw)";
CM_ SG_ 2337795744 M2P_TMS_L_15_CP1_r_16 "1号TMS压缩机1转速(15kw)";
CM_ SG_ 2337795744 M2P_TMS_L_TEM_16 "1号TMSPTC温度开关状态";
CM_ SG_ 2337795744 M2P_TMS_L_WPS_16 "1号TMS水泵开关";
CM_ SG_ 2337795744 M2P_TMS_L_15_fan_fault_16 "1号TMS风机故障(15kw)";
CM_ SG_ 2337795744 M2P_TMS_L_15_fre_fault_16 "1号TMS AC1故障(15kw变频器)";
CM_ SG_ 2337795744 M2P_TMS_L_15_D_fault_16 "1号TMS AC1故障(15kwDC/DC)";
CM_ SG_ 2337795744 M2P_TMS_L_FAN_PWM "1号TMS冷却风机PWM占空比";
CM_ SG_ 2337795744 M2P_TMS_L_25_FAN_PWM_16 "1号TMS25kw风机PWM";
CM_ SG_ 2337795745 M2P_TMS_L_15_CP1_vol_17 "1号TMS压缩机1电压(15kw)";
CM_ SG_ 2337795745 M2P_TMS_L_15_CP1_I_17 "1号TMS压缩机1电流(15kw)";
CM_ SG_ 2337795745 M2P_TMS_L_15_CP1_r_17 "1号TMS压缩机1转速(15kw)";
CM_ SG_ 2337795745 M2P_TMS_L_TEM_17 "1号TMSPTC温度开关状态";
CM_ SG_ 2337795745 M2P_TMS_L_WPS_17 "1号TMS水泵开关";
CM_ SG_ 2337795745 M2P_TMS_L_15_fan_fault_17 "1号TMS风机故障(15kw)";
CM_ SG_ 2337795745 M2P_TMS_L_15_fre_fault_17 "1号TMS AC1故障(15kw变频器)";
CM_ SG_ 2337795745 M2P_TMS_L_15_D_fault_17 "1号TMS AC1故障(15kwDC/DC)";
CM_ SG_ 2337795745 M2P_TMS_L_FAN_PWM "1号TMS冷却风机PWM占空比";
CM_ SG_ 2337795745 M2P_TMS_L_25_FAN_PWM_17 "1号TMS25kw风机PWM";
CM_ SG_ 2337795746 M2P_TMS_L_15_CP1_vol_18 "1号TMS压缩机1电压(15kw)";
CM_ SG_ 2337795746 M2P_TMS_L_15_CP1_I_18 "1号TMS压缩机1电流(15kw)";
CM_ SG_ 2337795746 M2P_TMS_L_15_CP1_r_18 "1号TMS压缩机1转速(15kw)";
CM_ SG_ 2337795746 M2P_TMS_L_TEM_18 "1号TMSPTC温度开关状态";
CM_ SG_ 2337795746 M2P_TMS_L_WPS_18 "1号TMS水泵开关";
CM_ SG_ 2337795746 M2P_TMS_L_15_fan_fault_18 "1号TMS风机故障(15kw)";
CM_ SG_ 2337795746 M2P_TMS_L_15_fre_fault_18 "1号TMS AC1故障(15kw变频器)";
CM_ SG_ 2337795746 M2P_TMS_L_15_D_fault_18 "1号TMS AC1故障(15kwDC/DC)";
CM_ SG_ 2337795746 M2P_TMS_L_FAN_PWM "1号TMS冷却风机PWM占空比";
CM_ SG_ 2337795746 M2P_TMS_L_25_FAN_PWM_18 "1号TMS25kw风机PWM";
CM_ SG_ 2337795747 M2P_TMS_L_15_CP1_vol_19 "1号TMS压缩机1电压(15kw)";
CM_ SG_ 2337795747 M2P_TMS_L_15_CP1_I_19 "1号TMS压缩机1电流(15kw)";
CM_ SG_ 2337795747 M2P_TMS_L_15_CP1_r_19 "1号TMS压缩机1转速(15kw)";
CM_ SG_ 2337795747 M2P_TMS_L_TEM_19 "1号TMSPTC温度开关状态";
CM_ SG_ 2337795747 M2P_TMS_L_WPS_19 "1号TMS水泵开关";
CM_ SG_ 2337795747 M2P_TMS_L_15_fan_fault_19 "1号TMS风机故障(15kw)";
CM_ SG_ 2337795747 M2P_TMS_L_15_fre_fault_19 "1号TMS AC1故障(15kw变频器)";
CM_ SG_ 2337795747 M2P_TMS_L_15_D_fault_19 "1号TMS AC1故障(15kwDC/DC)";
CM_ SG_ 2337795747 M2P_TMS_L_FAN_PWM "1号TMS冷却风机PWM占空比";
CM_ SG_ 2337795747 M2P_TMS_L_25_FAN_PWM_19 "1号TMS25kw风机PWM";
CM_ SG_ 2337795748 M2P_TMS_L_15_CP1_vol_20 "1号TMS压缩机1电压(15kw)";
CM_ SG_ 2337795748 M2P_TMS_L_15_CP1_I_20 "1号TMS压缩机1电流(15kw)";
CM_ SG_ 2337795748 M2P_TMS_L_15_CP1_r_20 "1号TMS压缩机1转速(15kw)";
CM_ SG_ 2337795748 M2P_TMS_L_TEM_20 "1号TMSPTC温度开关状态";
CM_ SG_ 2337795748 M2P_TMS_L_WPS_20 "1号TMS水泵开关";
CM_ SG_ 2337795748 M2P_TMS_L_15_fan_fault_20 "1号TMS风机故障(15kw)";
CM_ SG_ 2337795748 M2P_TMS_L_15_fre_fault_20 "1号TMS AC1故障(15kw变频器)";
CM_ SG_ 2337795748 M2P_TMS_L_15_D_fault_20 "1号TMS AC1故障(15kwDC/DC)";
CM_ SG_ 2337795748 M2P_TMS_L_FAN_PWM "1号TMS冷却风机PWM占空比";
CM_ SG_ 2337795748 M2P_TMS_L_25_FAN_PWM_20 "1号TMS25kw风机PWM";
CM_ SG_ 2337795749 M2P_TMS_L_15_CP1_vol_21 "1号TMS压缩机1电压(15kw)";
CM_ SG_ 2337795749 M2P_TMS_L_15_CP1_I_21 "1号TMS压缩机1电流(15kw)";
CM_ SG_ 2337795749 M2P_TMS_L_15_CP1_r_21 "1号TMS压缩机1转速(15kw)";
CM_ SG_ 2337795749 M2P_TMS_L_TEM_21 "1号TMSPTC温度开关状态";
CM_ SG_ 2337795749 M2P_TMS_L_WPS_21 "1号TMS水泵开关";
CM_ SG_ 2337795749 M2P_TMS_L_15_fan_fault_21 "1号TMS风机故障(15kw)";
CM_ SG_ 2337795749 M2P_TMS_L_15_fre_fault_21 "1号TMS AC1故障(15kw变频器)";
CM_ SG_ 2337795749 M2P_TMS_L_15_D_fault_21 "1号TMS AC1故障(15kwDC/DC)";
CM_ SG_ 2337795749 M2P_TMS_L_FAN_PWM "1号TMS冷却风机PWM占空比";
CM_ SG_ 2337795749 M2P_TMS_L_25_FAN_PWM_21 "1号TMS25kw风机PWM";
CM_ SG_ 2337795750 M2P_TMS_L_15_CP1_vol_22 "1号TMS压缩机1电压(15kw)";
CM_ SG_ 2337795750 M2P_TMS_L_15_CP1_I_22 "1号TMS压缩机1电流(15kw)";
CM_ SG_ 2337795750 M2P_TMS_L_15_CP1_r_22 "1号TMS压缩机1转速(15kw)";
CM_ SG_ 2337795750 M2P_TMS_L_TEM_22 "1号TMSPTC温度开关状态";
CM_ SG_ 2337795750 M2P_TMS_L_WPS_22 "1号TMS水泵开关";
CM_ SG_ 2337795750 M2P_TMS_L_15_fan_fault_22 "1号TMS风机故障(15kw)";
CM_ SG_ 2337795750 M2P_TMS_L_15_fre_fault_22 "1号TMS AC1故障(15kw变频器)";
CM_ SG_ 2337795750 M2P_TMS_L_15_D_fault_22 "1号TMS AC1故障(15kwDC/DC)";
CM_ SG_ 2337795750 M2P_TMS_L_FAN_PWM "1号TMS冷却风机PWM占空比";
CM_ SG_ 2337795750 M2P_TMS_L_25_FAN_PWM_22 "1号TMS25kw风机PWM";
CM_ SG_ 2337795751 M2P_TMS_L_15_CP1_vol_23 "1号TMS压缩机1电压(15kw)";
CM_ SG_ 2337795751 M2P_TMS_L_15_CP1_I_23 "1号TMS压缩机1电流(15kw)";
CM_ SG_ 2337795751 M2P_TMS_L_15_CP1_r_23 "1号TMS压缩机1转速(15kw)";
CM_ SG_ 2337795751 M2P_TMS_L_TEM_23 "1号TMSPTC温度开关状态";
CM_ SG_ 2337795751 M2P_TMS_L_WPS_23 "1号TMS水泵开关";
CM_ SG_ 2337795751 M2P_TMS_L_15_fan_fault_23 "1号TMS风机故障(15kw)";
CM_ SG_ 2337795751 M2P_TMS_L_15_fre_fault_23 "1号TMS AC1故障(15kw变频器)";
CM_ SG_ 2337795751 M2P_TMS_L_15_D_fault_23 "1号TMS AC1故障(15kwDC/DC)";
CM_ SG_ 2337795751 M2P_TMS_L_FAN_PWM "1号TMS冷却风机PWM占空比";
CM_ SG_ 2337795751 M2P_TMS_L_25_FAN_PWM_23 "1号TMS25kw风机PWM";
CM_ SG_ 2337795752 M2P_TMS_L_15_CP1_vol_24 "1号TMS压缩机1电压(15kw)";
CM_ SG_ 2337795752 M2P_TMS_L_15_CP1_I_24 "1号TMS压缩机1电流(15kw)";
CM_ SG_ 2337795752 M2P_TMS_L_15_CP1_r_24 "1号TMS压缩机1转速(15kw)";
CM_ SG_ 2337795752 M2P_TMS_L_TEM_24 "1号TMSPTC温度开关状态";
CM_ SG_ 2337795752 M2P_TMS_L_WPS_24 "1号TMS水泵开关";
CM_ SG_ 2337795752 M2P_TMS_L_15_fan_fault_24 "1号TMS风机故障(15kw)";
CM_ SG_ 2337795752 M2P_TMS_L_15_fre_fault_24 "1号TMS AC1故障(15kw变频器)";
CM_ SG_ 2337795752 M2P_TMS_L_15_D_fault_24 "1号TMS AC1故障(15kwDC/DC)";
CM_ SG_ 2337795752 M2P_TMS_L_FAN_PWM "1号TMS冷却风机PWM占空比";
CM_ SG_ 2337795752 M2P_TMS_L_25_FAN_PWM_24 "1号TMS25kw风机PWM";
CM_ SG_ 2337795753 M2P_TMS_L_15_CP1_vol_25 "1号TMS压缩机1电压(15kw)";
CM_ SG_ 2337795753 M2P_TMS_L_15_CP1_I_25 "1号TMS压缩机1电流(15kw)";
CM_ SG_ 2337795753 M2P_TMS_L_15_CP1_r_25 "1号TMS压缩机1转速(15kw)";
CM_ SG_ 2337795753 M2P_TMS_L_TEM_25 "1号TMSPTC温度开关状态";
CM_ SG_ 2337795753 M2P_TMS_L_WPS_25 "1号TMS水泵开关";
CM_ SG_ 2337795753 M2P_TMS_L_15_fan_fault_25 "1号TMS风机故障(15kw)";
CM_ SG_ 2337795753 M2P_TMS_L_15_fre_fault_25 "1号TMS AC1故障(15kw变频器)";
CM_ SG_ 2337795753 M2P_TMS_L_15_D_fault_25 "1号TMS AC1故障(15kwDC/DC)";
CM_ SG_ 2337795753 M2P_TMS_L_FAN_PWM "1号TMS冷却风机PWM占空比";
CM_ SG_ 2337795753 M2P_TMS_L_25_FAN_PWM_25 "1号TMS25kw风机PWM";
CM_ SG_ 2337795754 M2P_TMS_L_15_CP1_vol_26 "1号TMS压缩机1电压(15kw)";
CM_ SG_ 2337795754 M2P_TMS_L_15_CP1_I_26 "1号TMS压缩机1电流(15kw)";
CM_ SG_ 2337795754 M2P_TMS_L_15_CP1_r_26 "1号TMS压缩机1转速(15kw)";
CM_ SG_ 2337795754 M2P_TMS_L_TEM_26 "1号TMSPTC温度开关状态";
CM_ SG_ 2337795754 M2P_TMS_L_WPS_26 "1号TMS水泵开关";
CM_ SG_ 2337795754 M2P_TMS_L_15_fan_fault_26 "1号TMS风机故障(15kw)";
CM_ SG_ 2337795754 M2P_TMS_L_15_fre_fault_26 "1号TMS AC1故障(15kw变频器)";
CM_ SG_ 2337795754 M2P_TMS_L_15_D_fault_26 "1号TMS AC1故障(15kwDC/DC)";
CM_ SG_ 2337795754 M2P_TMS_L_FAN_PWM "1号TMS冷却风机PWM占空比";
CM_ SG_ 2337795754 M2P_TMS_L_25_FAN_PWM_26 "1号TMS25kw风机PWM";
CM_ SG_ 2337795755 M2P_TMS_L_15_CP1_vol_27 "1号TMS压缩机1电压(15kw)";
CM_ SG_ 2337795755 M2P_TMS_L_15_CP1_I_27 "1号TMS压缩机1电流(15kw)";
CM_ SG_ 2337795755 M2P_TMS_L_15_CP1_r_27 "1号TMS压缩机1转速(15kw)";
CM_ SG_ 2337795755 M2P_TMS_L_TEM_27 "1号TMSPTC温度开关状态";
CM_ SG_ 2337795755 M2P_TMS_L_WPS_27 "1号TMS水泵开关";
CM_ SG_ 2337795755 M2P_TMS_L_15_fan_fault_27 "1号TMS风机故障(15kw)";
CM_ SG_ 2337795755 M2P_TMS_L_15_fre_fault_27 "1号TMS AC1故障(15kw变频器)";
CM_ SG_ 2337795755 M2P_TMS_L_15_D_fault_27 "1号TMS AC1故障(15kwDC/DC)";
CM_ SG_ 2337795755 M2P_TMS_L_FAN_PWM "1号TMS冷却风机PWM占空比";
CM_ SG_ 2337795755 M2P_TMS_L_25_FAN_PWM_27 "1号TMS25kw风机PWM";
CM_ SG_ 2337795756 M2P_TMS_L_15_CP1_vol_28 "1号TMS压缩机1电压(15kw)";
CM_ SG_ 2337795756 M2P_TMS_L_15_CP1_I_28 "1号TMS压缩机1电流(15kw)";
CM_ SG_ 2337795756 M2P_TMS_L_15_CP1_r_28 "1号TMS压缩机1转速(15kw)";
CM_ SG_ 2337795756 M2P_TMS_L_TEM_28 "1号TMSPTC温度开关状态";
CM_ SG_ 2337795756 M2P_TMS_L_WPS_28 "1号TMS水泵开关";
CM_ SG_ 2337795756 M2P_TMS_L_15_fan_fault_28 "1号TMS风机故障(15kw)";
CM_ SG_ 2337795756 M2P_TMS_L_15_fre_fault_28 "1号TMS AC1故障(15kw变频器)";
CM_ SG_ 2337795756 M2P_TMS_L_15_D_fault_28 "1号TMS AC1故障(15kwDC/DC)";
CM_ SG_ 2337795756 M2P_TMS_L_FAN_PWM "1号TMS冷却风机PWM占空比";
CM_ SG_ 2337795756 M2P_TMS_L_25_FAN_PWM_28 "1号TMS25kw风机PWM";
CM_ SG_ 2337795757 M2P_TMS_L_15_CP1_vol_29 "1号TMS压缩机1电压(15kw)";
CM_ SG_ 2337795757 M2P_TMS_L_15_CP1_I_29 "1号TMS压缩机1电流(15kw)";
CM_ SG_ 2337795757 M2P_TMS_L_15_CP1_r_29 "1号TMS压缩机1转速(15kw)";
CM_ SG_ 2337795757 M2P_TMS_L_TEM_29 "1号TMSPTC温度开关状态";
CM_ SG_ 2337795757 M2P_TMS_L_WPS_29 "1号TMS水泵开关";
CM_ SG_ 2337795757 M2P_TMS_L_15_fan_fault_29 "1号TMS风机故障(15kw)";
CM_ SG_ 2337795757 M2P_TMS_L_15_fre_fault_29 "1号TMS AC1故障(15kw变频器)";
CM_ SG_ 2337795757 M2P_TMS_L_15_D_fault_29 "1号TMS AC1故障(15kwDC/DC)";
CM_ SG_ 2337795757 M2P_TMS_L_FAN_PWM "1号TMS冷却风机PWM占空比";
CM_ SG_ 2337795757 M2P_TMS_L_25_FAN_PWM_29 "1号TMS25kw风机PWM";
CM_ SG_ 2337795758 M2P_TMS_L_15_CP1_vol_30 "1号TMS压缩机1电压(15kw)";
CM_ SG_ 2337795758 M2P_TMS_L_15_CP1_I_30 "1号TMS压缩机1电流(15kw)";
CM_ SG_ 2337795758 M2P_TMS_L_15_CP1_r_30 "1号TMS压缩机1转速(15kw)";
CM_ SG_ 2337795758 M2P_TMS_L_TEM_30 "1号TMSPTC温度开关状态";
CM_ SG_ 2337795758 M2P_TMS_L_WPS_30 "1号TMS水泵开关";
CM_ SG_ 2337795758 M2P_TMS_L_15_fan_fault_30 "1号TMS风机故障(15kw)";
CM_ SG_ 2337795758 M2P_TMS_L_15_fre_fault_30 "1号TMS AC1故障(15kw变频器)";
CM_ SG_ 2337795758 M2P_TMS_L_15_D_fault_30 "1号TMS AC1故障(15kwDC/DC)";
CM_ SG_ 2337795758 M2P_TMS_L_FAN_PWM "1号TMS冷却风机PWM占空比";
CM_ SG_ 2337795758 M2P_TMS_L_25_FAN_PWM_30 "1号TMS25kw风机PWM";
CM_ SG_ 2337795759 M2P_TMS_L_15_CP1_vol_31 "1号TMS压缩机1电压(15kw)";
CM_ SG_ 2337795759 M2P_TMS_L_15_CP1_I_31 "1号TMS压缩机1电流(15kw)";
CM_ SG_ 2337795759 M2P_TMS_L_15_CP1_r_31 "1号TMS压缩机1转速(15kw)";
CM_ SG_ 2337795759 M2P_TMS_L_TEM_31 "1号TMSPTC温度开关状态";
CM_ SG_ 2337795759 M2P_TMS_L_WPS_31 "1号TMS水泵开关";
CM_ SG_ 2337795759 M2P_TMS_L_15_fan_fault_31 "1号TMS风机故障(15kw)";
CM_ SG_ 2337795759 M2P_TMS_L_15_fre_fault_31 "1号TMS AC1故障(15kw变频器)";
CM_ SG_ 2337795759 M2P_TMS_L_15_D_fault_31 "1号TMS AC1故障(15kwDC/DC)";
CM_ SG_ 2337795759 M2P_TMS_L_FAN_PWM "1号TMS冷却风机PWM占空比";
CM_ SG_ 2337795759 M2P_TMS_L_25_FAN_PWM_31 "1号TMS25kw风机PWM";
CM_ SG_ 2337861265 M2P_TMS_L_25_CP1_vol_01 "1号TMS压缩机2电压(25kw)";
CM_ SG_ 2337861265 M2P_TMS_L_25_CP1_I_01 "1号TMS压缩机2电流(25kw)";
CM_ SG_ 2337861265 M2P_TMS_L_25_CP1_r_01 "1号TMS压缩机2转速(25kw)";
CM_ SG_ 2337861265 Reserved_4 "保留";
CM_ SG_ 2337861265 M2P_TMS_L_25_fan_fault_01 "1号TMS风机故障(25kw)";
CM_ SG_ 2337861265 M2P_TMS_L_25_fre_fault_01 "1号TMS AC2故障(25kw变频器)";
CM_ SG_ 2337861265 M2P_TMS_L_25_D_fault_01 "1号TMS AC2故障(25kwDC/DC)";
CM_ SG_ 2337861265 M2P_TMS_L_AC2_25_P_01 "1号TMS AC2低压压力值(25kw)";
CM_ SG_ 2337861266 M2P_TMS_L_25_CP1_vol_02 "1号TMS压缩机2电压(25kw)";
CM_ SG_ 2337861266 M2P_TMS_L_25_CP1_I_02 "1号TMS压缩机2电流(25kw)";
CM_ SG_ 2337861266 M2P_TMS_L_25_CP1_r_02 "1号TMS压缩机2转速(25kw)";
CM_ SG_ 2337861266 Reserved_4 "保留";
CM_ SG_ 2337861266 M2P_TMS_L_25_fan_fault_02 "1号TMS风机故障(25kw)";
CM_ SG_ 2337861266 M2P_TMS_L_25_fre_fault_02 "1号TMS AC2故障(25kw变频器)";
CM_ SG_ 2337861266 M2P_TMS_L_25_D_fault_02 "1号TMS AC2故障(25kwDC/DC)";
CM_ SG_ 2337861266 M2P_TMS_L_AC2_25_P_02 "1号TMS AC2低压压力值(25kw)";
CM_ SG_ 2337861267 M2P_TMS_L_25_CP1_vol_03 "1号TMS压缩机2电压(25kw)";
CM_ SG_ 2337861267 M2P_TMS_L_25_CP1_I_03 "1号TMS压缩机2电流(25kw)";
CM_ SG_ 2337861267 M2P_TMS_L_25_CP1_r_03 "1号TMS压缩机2转速(25kw)";
CM_ SG_ 2337861267 Reserved_4 "保留";
CM_ SG_ 2337861267 M2P_TMS_L_25_fan_fault_03 "1号TMS风机故障(25kw)";
CM_ SG_ 2337861267 M2P_TMS_L_25_fre_fault_03 "1号TMS AC2故障(25kw变频器)";
CM_ SG_ 2337861267 M2P_TMS_L_25_D_fault_03 "1号TMS AC2故障(25kwDC/DC)";
CM_ SG_ 2337861267 M2P_TMS_L_AC2_25_P_03 "1号TMS AC2低压压力值(25kw)";
CM_ SG_ 2337861268 M2P_TMS_L_25_CP1_vol_04 "1号TMS压缩机2电压(25kw)";
CM_ SG_ 2337861268 M2P_TMS_L_25_CP1_I_04 "1号TMS压缩机2电流(25kw)";
CM_ SG_ 2337861268 M2P_TMS_L_25_CP1_r_04 "1号TMS压缩机2转速(25kw)";
CM_ SG_ 2337861268 Reserved_4 "保留";
CM_ SG_ 2337861268 M2P_TMS_L_25_fan_fault_04 "1号TMS风机故障(25kw)";
CM_ SG_ 2337861268 M2P_TMS_L_25_fre_fault_04 "1号TMS AC2故障(25kw变频器)";
CM_ SG_ 2337861268 M2P_TMS_L_25_D_fault_04 "1号TMS AC2故障(25kwDC/DC)";
CM_ SG_ 2337861268 M2P_TMS_L_AC2_25_P_04 "1号TMS AC2低压压力值(25kw)";
CM_ SG_ 2337861269 M2P_TMS_L_25_CP1_vol_05 "1号TMS压缩机2电压(25kw)";
CM_ SG_ 2337861269 M2P_TMS_L_25_CP1_I_05 "1号TMS压缩机2电流(25kw)";
CM_ SG_ 2337861269 M2P_TMS_L_25_CP1_r_05 "1号TMS压缩机2转速(25kw)";
CM_ SG_ 2337861269 Reserved_4 "保留";
CM_ SG_ 2337861269 M2P_TMS_L_25_fan_fault_05 "1号TMS风机故障(25kw)";
CM_ SG_ 2337861269 M2P_TMS_L_25_fre_fault_05 "1号TMS AC2故障(25kw变频器)";
CM_ SG_ 2337861269 M2P_TMS_L_25_D_fault_05 "1号TMS AC2故障(25kwDC/DC)";
CM_ SG_ 2337861269 M2P_TMS_L_AC2_25_P_05 "1号TMS AC2低压压力值(25kw)";
CM_ SG_ 2337861270 M2P_TMS_L_25_CP1_vol_06 "1号TMS压缩机2电压(25kw)";
CM_ SG_ 2337861270 M2P_TMS_L_25_CP1_I_06 "1号TMS压缩机2电流(25kw)";
CM_ SG_ 2337861270 M2P_TMS_L_25_CP1_r_06 "1号TMS压缩机2转速(25kw)";
CM_ SG_ 2337861270 Reserved_4 "保留";
CM_ SG_ 2337861270 M2P_TMS_L_25_fan_fault_06 "1号TMS风机故障(25kw)";
CM_ SG_ 2337861270 M2P_TMS_L_25_fre_fault_06 "1号TMS AC2故障(25kw变频器)";
CM_ SG_ 2337861270 M2P_TMS_L_25_D_fault_06 "1号TMS AC2故障(25kwDC/DC)";
CM_ SG_ 2337861270 M2P_TMS_L_AC2_25_P_06 "1号TMS AC2低压压力值(25kw)";
CM_ SG_ 2337861271 M2P_TMS_L_25_CP1_vol_07 "1号TMS压缩机2电压(25kw)";
CM_ SG_ 2337861271 M2P_TMS_L_25_CP1_I_07 "1号TMS压缩机2电流(25kw)";
CM_ SG_ 2337861271 M2P_TMS_L_25_CP1_r_07 "1号TMS压缩机2转速(25kw)";
CM_ SG_ 2337861271 Reserved_4 "保留";
CM_ SG_ 2337861271 M2P_TMS_L_25_fan_fault_07 "1号TMS风机故障(25kw)";
CM_ SG_ 2337861271 M2P_TMS_L_25_fre_fault_07 "1号TMS AC2故障(25kw变频器)";
CM_ SG_ 2337861271 M2P_TMS_L_25_D_fault_07 "1号TMS AC2故障(25kwDC/DC)";
CM_ SG_ 2337861271 M2P_TMS_L_AC2_25_P_07 "1号TMS AC2低压压力值(25kw)";
CM_ SG_ 2337861272 M2P_TMS_L_25_CP1_vol_08 "1号TMS压缩机2电压(25kw)";
CM_ SG_ 2337861272 M2P_TMS_L_25_CP1_I_08 "1号TMS压缩机2电流(25kw)";
CM_ SG_ 2337861272 M2P_TMS_L_25_CP1_r_08 "1号TMS压缩机2转速(25kw)";
CM_ SG_ 2337861272 Reserved_4 "保留";
CM_ SG_ 2337861272 M2P_TMS_L_25_fan_fault_08 "1号TMS风机故障(25kw)";
CM_ SG_ 2337861272 M2P_TMS_L_25_fre_fault_08 "1号TMS AC2故障(25kw变频器)";
CM_ SG_ 2337861272 M2P_TMS_L_25_D_fault_08 "1号TMS AC2故障(25kwDC/DC)";
CM_ SG_ 2337861272 M2P_TMS_L_AC2_25_P_08 "1号TMS AC2低压压力值(25kw)";
CM_ SG_ 2337861273 M2P_TMS_L_25_CP1_vol_09 "1号TMS压缩机2电压(25kw)";
CM_ SG_ 2337861273 M2P_TMS_L_25_CP1_I_09 "1号TMS压缩机2电流(25kw)";
CM_ SG_ 2337861273 M2P_TMS_L_25_CP1_r_09 "1号TMS压缩机2转速(25kw)";
CM_ SG_ 2337861273 Reserved_4 "保留";
CM_ SG_ 2337861273 M2P_TMS_L_25_fan_fault_09 "1号TMS风机故障(25kw)";
CM_ SG_ 2337861273 M2P_TMS_L_25_fre_fault_09 "1号TMS AC2故障(25kw变频器)";
CM_ SG_ 2337861273 M2P_TMS_L_25_D_fault_09 "1号TMS AC2故障(25kwDC/DC)";
CM_ SG_ 2337861273 M2P_TMS_L_AC2_25_P_09 "1号TMS AC2低压压力值(25kw)";
CM_ SG_ 2337861274 M2P_TMS_L_25_CP1_vol_10 "1号TMS压缩机2电压(25kw)";
CM_ SG_ 2337861274 M2P_TMS_L_25_CP1_I_10 "1号TMS压缩机2电流(25kw)";
CM_ SG_ 2337861274 M2P_TMS_L_25_CP1_r_10 "1号TMS压缩机2转速(25kw)";
CM_ SG_ 2337861274 Reserved_4 "保留";
CM_ SG_ 2337861274 M2P_TMS_L_25_fan_fault_10 "1号TMS风机故障(25kw)";
CM_ SG_ 2337861274 M2P_TMS_L_25_fre_fault_10 "1号TMS AC2故障(25kw变频器)";
CM_ SG_ 2337861274 M2P_TMS_L_25_D_fault_10 "1号TMS AC2故障(25kwDC/DC)";
CM_ SG_ 2337861274 M2P_TMS_L_AC2_25_P_10 "1号TMS AC2低压压力值(25kw)";
CM_ SG_ 2337861275 M2P_TMS_L_25_CP1_vol_11 "1号TMS压缩机2电压(25kw)";
CM_ SG_ 2337861275 M2P_TMS_L_25_CP1_I_11 "1号TMS压缩机2电流(25kw)";
CM_ SG_ 2337861275 M2P_TMS_L_25_CP1_r_11 "1号TMS压缩机2转速(25kw)";
CM_ SG_ 2337861275 Reserved_4 "保留";
CM_ SG_ 2337861275 M2P_TMS_L_25_fan_fault_11 "1号TMS风机故障(25kw)";
CM_ SG_ 2337861275 M2P_TMS_L_25_fre_fault_11 "1号TMS AC2故障(25kw变频器)";
CM_ SG_ 2337861275 M2P_TMS_L_25_D_fault_11 "1号TMS AC2故障(25kwDC/DC)";
CM_ SG_ 2337861275 M2P_TMS_L_AC2_25_P_11 "1号TMS AC2低压压力值(25kw)";
CM_ SG_ 2337861276 M2P_TMS_L_25_CP1_vol_12 "1号TMS压缩机2电压(25kw)";
CM_ SG_ 2337861276 M2P_TMS_L_25_CP1_I_12 "1号TMS压缩机2电流(25kw)";
CM_ SG_ 2337861276 M2P_TMS_L_25_CP1_r_12 "1号TMS压缩机2转速(25kw)";
CM_ SG_ 2337861276 Reserved_4 "保留";
CM_ SG_ 2337861276 M2P_TMS_L_25_fan_fault_12 "1号TMS风机故障(25kw)";
CM_ SG_ 2337861276 M2P_TMS_L_25_fre_fault_12 "1号TMS AC2故障(25kw变频器)";
CM_ SG_ 2337861276 M2P_TMS_L_25_D_fault_12 "1号TMS AC2故障(25kwDC/DC)";
CM_ SG_ 2337861276 M2P_TMS_L_AC2_25_P_12 "1号TMS AC2低压压力值(25kw)";
CM_ SG_ 2337861277 M2P_TMS_L_25_CP1_vol_13 "1号TMS压缩机2电压(25kw)";
CM_ SG_ 2337861277 M2P_TMS_L_25_CP1_I_13 "1号TMS压缩机2电流(25kw)";
CM_ SG_ 2337861277 M2P_TMS_L_25_CP1_r_13 "1号TMS压缩机2转速(25kw)";
CM_ SG_ 2337861277 Reserved_4 "保留";
CM_ SG_ 2337861277 M2P_TMS_L_25_fan_fault_13 "1号TMS风机故障(25kw)";
CM_ SG_ 2337861277 M2P_TMS_L_25_fre_fault_13 "1号TMS AC2故障(25kw变频器)";
CM_ SG_ 2337861277 M2P_TMS_L_25_D_fault_13 "1号TMS AC2故障(25kwDC/DC)";
CM_ SG_ 2337861277 M2P_TMS_L_AC2_25_P_13 "1号TMS AC2低压压力值(25kw)";
CM_ SG_ 2337861278 M2P_TMS_L_25_CP1_vol_14 "1号TMS压缩机2电压(25kw)";
CM_ SG_ 2337861278 M2P_TMS_L_25_CP1_I_14 "1号TMS压缩机2电流(25kw)";
CM_ SG_ 2337861278 M2P_TMS_L_25_CP1_r_14 "1号TMS压缩机2转速(25kw)";
CM_ SG_ 2337861278 Reserved_4 "保留";
CM_ SG_ 2337861278 M2P_TMS_L_25_fan_fault_14 "1号TMS风机故障(25kw)";
CM_ SG_ 2337861278 M2P_TMS_L_25_fre_fault_14 "1号TMS AC2故障(25kw变频器)";
CM_ SG_ 2337861278 M2P_TMS_L_25_D_fault_14 "1号TMS AC2故障(25kwDC/DC)";
CM_ SG_ 2337861278 M2P_TMS_L_AC2_25_P_14 "1号TMS AC2低压压力值(25kw)";
CM_ SG_ 2337861279 M2P_TMS_L_25_CP1_vol_15 "1号TMS压缩机2电压(25kw)";
CM_ SG_ 2337861279 M2P_TMS_L_25_CP1_I_15 "1号TMS压缩机2电流(25kw)";
CM_ SG_ 2337861279 M2P_TMS_L_25_CP1_r_15 "1号TMS压缩机2转速(25kw)";
CM_ SG_ 2337861279 Reserved_4 "保留";
CM_ SG_ 2337861279 M2P_TMS_L_25_fan_fault_15 "1号TMS风机故障(25kw)";
CM_ SG_ 2337861279 M2P_TMS_L_25_fre_fault_15 "1号TMS AC2故障(25kw变频器)";
CM_ SG_ 2337861279 M2P_TMS_L_25_D_fault_15 "1号TMS AC2故障(25kwDC/DC)";
CM_ SG_ 2337861279 M2P_TMS_L_AC2_25_P_15 "1号TMS AC2低压压力值(25kw)";
CM_ SG_ 2337861280 M2P_TMS_L_25_CP1_vol_16 "1号TMS压缩机2电压(25kw)";
CM_ SG_ 2337861280 M2P_TMS_L_25_CP1_I_16 "1号TMS压缩机2电流(25kw)";
CM_ SG_ 2337861280 M2P_TMS_L_25_CP1_r_16 "1号TMS压缩机2转速(25kw)";
CM_ SG_ 2337861280 Reserved_4 "保留";
CM_ SG_ 2337861280 M2P_TMS_L_25_fan_fault_16 "1号TMS风机故障(25kw)";
CM_ SG_ 2337861280 M2P_TMS_L_25_fre_fault_16 "1号TMS AC2故障(25kw变频器)";
CM_ SG_ 2337861280 M2P_TMS_L_25_D_fault_16 "1号TMS AC2故障(25kwDC/DC)";
CM_ SG_ 2337861280 M2P_TMS_L_AC2_25_P_16 "1号TMS AC2低压压力值(25kw)";
CM_ SG_ 2337861281 M2P_TMS_L_25_CP1_vol_17 "1号TMS压缩机2电压(25kw)";
CM_ SG_ 2337861281 M2P_TMS_L_25_CP1_I_17 "1号TMS压缩机2电流(25kw)";
CM_ SG_ 2337861281 M2P_TMS_L_25_CP1_r_17 "1号TMS压缩机2转速(25kw)";
CM_ SG_ 2337861281 Reserved_4 "保留";
CM_ SG_ 2337861281 M2P_TMS_L_25_fan_fault_17 "1号TMS风机故障(25kw)";
CM_ SG_ 2337861281 M2P_TMS_L_25_fre_fault_17 "1号TMS AC2故障(25kw变频器)";
CM_ SG_ 2337861281 M2P_TMS_L_25_D_fault_17 "1号TMS AC2故障(25kwDC/DC)";
CM_ SG_ 2337861281 M2P_TMS_L_AC2_25_P_17 "1号TMS AC2低压压力值(25kw)";
CM_ SG_ 2337861282 M2P_TMS_L_25_CP1_vol_18 "1号TMS压缩机2电压(25kw)";
CM_ SG_ 2337861282 M2P_TMS_L_25_CP1_I_18 "1号TMS压缩机2电流(25kw)";
CM_ SG_ 2337861282 M2P_TMS_L_25_CP1_r_18 "1号TMS压缩机2转速(25kw)";
CM_ SG_ 2337861282 Reserved_4 "保留";
CM_ SG_ 2337861282 M2P_TMS_L_25_fan_fault_18 "1号TMS风机故障(25kw)";
CM_ SG_ 2337861282 M2P_TMS_L_25_fre_fault_18 "1号TMS AC2故障(25kw变频器)";
CM_ SG_ 2337861282 M2P_TMS_L_25_D_fault_18 "1号TMS AC2故障(25kwDC/DC)";
CM_ SG_ 2337861282 M2P_TMS_L_AC2_25_P_18 "1号TMS AC2低压压力值(25kw)";
CM_ SG_ 2337861283 M2P_TMS_L_25_CP1_vol_19 "1号TMS压缩机2电压(25kw)";
CM_ SG_ 2337861283 M2P_TMS_L_25_CP1_I_19 "1号TMS压缩机2电流(25kw)";
CM_ SG_ 2337861283 M2P_TMS_L_25_CP1_r_19 "1号TMS压缩机2转速(25kw)";
CM_ SG_ 2337861283 Reserved_4 "保留";
CM_ SG_ 2337861283 M2P_TMS_L_25_fan_fault_19 "1号TMS风机故障(25kw)";
CM_ SG_ 2337861283 M2P_TMS_L_25_fre_fault_19 "1号TMS AC2故障(25kw变频器)";
CM_ SG_ 2337861283 M2P_TMS_L_25_D_fault_19 "1号TMS AC2故障(25kwDC/DC)";
CM_ SG_ 2337861283 M2P_TMS_L_AC2_25_P_19 "1号TMS AC2低压压力值(25kw)";
CM_ SG_ 2337861284 M2P_TMS_L_25_CP1_vol_20 "1号TMS压缩机2电压(25kw)";
CM_ SG_ 2337861284 M2P_TMS_L_25_CP1_I_20 "1号TMS压缩机2电流(25kw)";
CM_ SG_ 2337861284 M2P_TMS_L_25_CP1_r_20 "1号TMS压缩机2转速(25kw)";
CM_ SG_ 2337861284 Reserved_4 "保留";
CM_ SG_ 2337861284 M2P_TMS_L_25_fan_fault_20 "1号TMS风机故障(25kw)";
CM_ SG_ 2337861284 M2P_TMS_L_25_fre_fault_20 "1号TMS AC2故障(25kw变频器)";
CM_ SG_ 2337861284 M2P_TMS_L_25_D_fault_20 "1号TMS AC2故障(25kwDC/DC)";
CM_ SG_ 2337861284 M2P_TMS_L_AC2_25_P_20 "1号TMS AC2低压压力值(25kw)";
CM_ SG_ 2337861285 M2P_TMS_L_25_CP1_vol_21 "1号TMS压缩机2电压(25kw)";
CM_ SG_ 2337861285 M2P_TMS_L_25_CP1_I_21 "1号TMS压缩机2电流(25kw)";
CM_ SG_ 2337861285 M2P_TMS_L_25_CP1_r_21 "1号TMS压缩机2转速(25kw)";
CM_ SG_ 2337861285 Reserved_4 "保留";
CM_ SG_ 2337861285 M2P_TMS_L_25_fan_fault_21 "1号TMS风机故障(25kw)";
CM_ SG_ 2337861285 M2P_TMS_L_25_fre_fault_21 "1号TMS AC2故障(25kw变频器)";
CM_ SG_ 2337861285 M2P_TMS_L_25_D_fault_21 "1号TMS AC2故障(25kwDC/DC)";
CM_ SG_ 2337861285 M2P_TMS_L_AC2_25_P_21 "1号TMS AC2低压压力值(25kw)";
CM_ SG_ 2337861286 M2P_TMS_L_25_CP1_vol_22 "1号TMS压缩机2电压(25kw)";
CM_ SG_ 2337861286 M2P_TMS_L_25_CP1_I_22 "1号TMS压缩机2电流(25kw)";
CM_ SG_ 2337861286 M2P_TMS_L_25_CP1_r_22 "1号TMS压缩机2转速(25kw)";
CM_ SG_ 2337861286 Reserved_4 "保留";
CM_ SG_ 2337861286 M2P_TMS_L_25_fan_fault_22 "1号TMS风机故障(25kw)";
CM_ SG_ 2337861286 M2P_TMS_L_25_fre_fault_22 "1号TMS AC2故障(25kw变频器)";
CM_ SG_ 2337861286 M2P_TMS_L_25_D_fault_22 "1号TMS AC2故障(25kwDC/DC)";
CM_ SG_ 2337861286 M2P_TMS_L_AC2_25_P_22 "1号TMS AC2低压压力值(25kw)";
CM_ SG_ 2337861287 M2P_TMS_L_25_CP1_vol_23 "1号TMS压缩机2电压(25kw)";
CM_ SG_ 2337861287 M2P_TMS_L_25_CP1_I_23 "1号TMS压缩机2电流(25kw)";
CM_ SG_ 2337861287 M2P_TMS_L_25_CP1_r_23 "1号TMS压缩机2转速(25kw)";
CM_ SG_ 2337861287 Reserved_4 "保留";
CM_ SG_ 2337861287 M2P_TMS_L_25_fan_fault_23 "1号TMS风机故障(25kw)";
CM_ SG_ 2337861287 M2P_TMS_L_25_fre_fault_23 "1号TMS AC2故障(25kw变频器)";
CM_ SG_ 2337861287 M2P_TMS_L_25_D_fault_23 "1号TMS AC2故障(25kwDC/DC)";
CM_ SG_ 2337861287 M2P_TMS_L_AC2_25_P_23 "1号TMS AC2低压压力值(25kw)";
CM_ SG_ 2337861288 M2P_TMS_L_25_CP1_vol_24 "1号TMS压缩机2电压(25kw)";
CM_ SG_ 2337861288 M2P_TMS_L_25_CP1_I_24 "1号TMS压缩机2电流(25kw)";
CM_ SG_ 2337861288 M2P_TMS_L_25_CP1_r_24 "1号TMS压缩机2转速(25kw)";
CM_ SG_ 2337861288 Reserved_4 "保留";
CM_ SG_ 2337861288 M2P_TMS_L_25_fan_fault_24 "1号TMS风机故障(25kw)";
CM_ SG_ 2337861288 M2P_TMS_L_25_fre_fault_24 "1号TMS AC2故障(25kw变频器)";
CM_ SG_ 2337861288 M2P_TMS_L_25_D_fault_24 "1号TMS AC2故障(25kwDC/DC)";
CM_ SG_ 2337861288 M2P_TMS_L_AC2_25_P_24 "1号TMS AC2低压压力值(25kw)";
CM_ SG_ 2337861289 M2P_TMS_L_25_CP1_vol_25 "1号TMS压缩机2电压(25kw)";
CM_ SG_ 2337861289 M2P_TMS_L_25_CP1_I_25 "1号TMS压缩机2电流(25kw)";
CM_ SG_ 2337861289 M2P_TMS_L_25_CP1_r_25 "1号TMS压缩机2转速(25kw)";
CM_ SG_ 2337861289 Reserved_4 "保留";
CM_ SG_ 2337861289 M2P_TMS_L_25_fan_fault_25 "1号TMS风机故障(25kw)";
CM_ SG_ 2337861289 M2P_TMS_L_25_fre_fault_25 "1号TMS AC2故障(25kw变频器)";
CM_ SG_ 2337861289 M2P_TMS_L_25_D_fault_25 "1号TMS AC2故障(25kwDC/DC)";
CM_ SG_ 2337861289 M2P_TMS_L_AC2_25_P_25 "1号TMS AC2低压压力值(25kw)";
VAL_ 2337795729 M2P_TMS_L_TEM_01 0 "open" 1 "close" ;
VAL_ 2337795729 M2P_TMS_L_WPS_01 0 "open" 1 "close" ;
VAL_ 2337795729 M2P_TMS_L_15_fan_fault_01 0 "no fault 00实际为0x00 引号外不能使用字母" 1 "Fan 1 overvoltage 01实际为0x01" 2 "Fan 1 under voltage 02实际为0x02" 3 "Fan 1 is stuck in rotation 03实际为0x03" 4 "Fan 1 overcurrent 04实际为0x04" 5 "Fan 1 motor overheating 05实际为0x05" 6 "Fan 1 drive overheating 06实际为0x06" 7 "Fan 2 overvoltage 07实际为0x07" 8 "Fan 2 under voltage 08实际为0x08" 9 "Fan 2 is stuck in rotation 09实际为0x09" 10 "Fan 2 overcurrent 10实际为0x0A" 11 "Fan 2 motor overheating 11实际为0x0B" 12 "Fan 2 drive overheating 12实际为0x0C" ;
VAL_ 2337795729 M2P_TMS_L_15_fre_fault_01 0 "no fault  00实际为0x00 引号外不能使用字母" 1 "Overcurrent 01实际为0x01" 2 "Operating overvoltage 02实际为0x02" 3 "Operating under voltage 03实际为0x03" 4 "AC input overvoltage 04实际为0x04" 5 "AC input under voltage 05实际为0x05" 6 "communication fault 06实际为0x06" 7 "Overcurrent frequency reduction 07实际为0x07" 8 "Over power frequency reduction 08实际为0x08" 9 "Input phase loss 09实际为0x09" 10 "External malfunction 10实际为0x0A" 11 "NTC overheating 11实际为0x0B" 12 "Power on to ground short circuit detection 12实际为0x0C" 13 "motor overload 13实际为0x0D" ;
VAL_ 2337795729 M2P_TMS_L_15_D_fault_01 0 "no fault 00实际为0x00 引号外不能使用字母" 1 "Overcurrent 01实际为0x01" 2 "Operating overvoltage 02实际为0x02" 3 "Operating under voltage 03实际为0x03" 4 "DC output overvoltage 04实际为0x04" 5 "DC output undervoltage 05实际为0x05" 6 "communication fault 06实际为0x06" 7 "Substrate overheating 07实际为0x07" 8 "output overload 08实际为0x08" ;
VAL_ 2337795730 M2P_TMS_L_TEM_02 0 "open" 1 "close" ;
VAL_ 2337795730 M2P_TMS_L_WPS_02 0 "open" 1 "close" ;
VAL_ 2337795730 M2P_TMS_L_15_fan_fault_02 0 "no fault 00实际为0x00 引号外不能使用字母" 1 "Fan 1 overvoltage 01实际为0x01" 2 "Fan 1 under voltage 02实际为0x02" 3 "Fan 1 is stuck in rotation 03实际为0x03" 4 "Fan 1 overcurrent 04实际为0x04" 5 "Fan 1 motor overheating 05实际为0x05" 6 "Fan 1 drive overheating 06实际为0x06" 7 "Fan 2 overvoltage 07实际为0x07" 8 "Fan 2 under voltage 08实际为0x08" 9 "Fan 2 is stuck in rotation 09实际为0x09" 10 "Fan 2 overcurrent 10实际为0x0A" 11 "Fan 2 motor overheating 11实际为0x0B" 12 "Fan 2 drive overheating 12实际为0x0C" ;
VAL_ 2337795730 M2P_TMS_L_15_fre_fault_02 0 "no fault  00实际为0x00 引号外不能使用字母" 1 "Overcurrent 01实际为0x01" 2 "Operating overvoltage 02实际为0x02" 3 "Operating under voltage 03实际为0x03" 4 "AC input overvoltage 04实际为0x04" 5 "AC input under voltage 05实际为0x05" 6 "communication fault 06实际为0x06" 7 "Overcurrent frequency reduction 07实际为0x07" 8 "Over power frequency reduction 08实际为0x08" 9 "Input phase loss 09实际为0x09" 10 "External malfunction 10实际为0x0A" 11 "NTC overheating 11实际为0x0B" 12 "Power on to ground short circuit detection 12实际为0x0C" 13 "motor overload 13实际为0x0D" ;
VAL_ 2337795730 M2P_TMS_L_15_D_fault_02 0 "no fault 00实际为0x00 引号外不能使用字母" 1 "Overcurrent 01实际为0x01" 2 "Operating overvoltage 02实际为0x02" 3 "Operating under voltage 03实际为0x03" 4 "DC output overvoltage 04实际为0x04" 5 "DC output undervoltage 05实际为0x05" 6 "communication fault 06实际为0x06" 7 "Substrate overheating 07实际为0x07" 8 "output overload 08实际为0x08" ;
VAL_ 2337795731 M2P_TMS_L_TEM_03 0 "open" 1 "close" ;
VAL_ 2337795731 M2P_TMS_L_WPS_03 0 "open" 1 "close" ;
VAL_ 2337795731 M2P_TMS_L_15_fan_fault_03 0 "no fault 00实际为0x00 引号外不能使用字母" 1 "Fan 1 overvoltage 01实际为0x01" 2 "Fan 1 under voltage 02实际为0x02" 3 "Fan 1 is stuck in rotation 03实际为0x03" 4 "Fan 1 overcurrent 04实际为0x04" 5 "Fan 1 motor overheating 05实际为0x05" 6 "Fan 1 drive overheating 06实际为0x06" 7 "Fan 2 overvoltage 07实际为0x07" 8 "Fan 2 under voltage 08实际为0x08" 9 "Fan 2 is stuck in rotation 09实际为0x09" 10 "Fan 2 overcurrent 10实际为0x0A" 11 "Fan 2 motor overheating 11实际为0x0B" 12 "Fan 2 drive overheating 12实际为0x0C" ;
VAL_ 2337795731 M2P_TMS_L_15_fre_fault_03 0 "no fault  00实际为0x00 引号外不能使用字母" 1 "Overcurrent 01实际为0x01" 2 "Operating overvoltage 02实际为0x02" 3 "Operating under voltage 03实际为0x03" 4 "AC input overvoltage 04实际为0x04" 5 "AC input under voltage 05实际为0x05" 6 "communication fault 06实际为0x06" 7 "Overcurrent frequency reduction 07实际为0x07" 8 "Over power frequency reduction 08实际为0x08" 9 "Input phase loss 09实际为0x09" 10 "External malfunction 10实际为0x0A" 11 "NTC overheating 11实际为0x0B" 12 "Power on to ground short circuit detection 12实际为0x0C" 13 "motor overload 13实际为0x0D" ;
VAL_ 2337795731 M2P_TMS_L_15_D_fault_03 0 "no fault 00实际为0x00 引号外不能使用字母" 1 "Overcurrent 01实际为0x01" 2 "Operating overvoltage 02实际为0x02" 3 "Operating under voltage 03实际为0x03" 4 "DC output overvoltage 04实际为0x04" 5 "DC output undervoltage 05实际为0x05" 6 "communication fault 06实际为0x06" 7 "Substrate overheating 07实际为0x07" 8 "output overload 08实际为0x08" ;
VAL_ 2337795732 M2P_TMS_L_TEM_04 0 "open" 1 "close" ;
VAL_ 2337795732 M2P_TMS_L_WPS_04 0 "open" 1 "close" ;
VAL_ 2337795732 M2P_TMS_L_15_fan_fault_04 0 "no fault 00实际为0x00 引号外不能使用字母" 1 "Fan 1 overvoltage 01实际为0x01" 2 "Fan 1 under voltage 02实际为0x02" 3 "Fan 1 is stuck in rotation 03实际为0x03" 4 "Fan 1 overcurrent 04实际为0x04" 5 "Fan 1 motor overheating 05实际为0x05" 6 "Fan 1 drive overheating 06实际为0x06" 7 "Fan 2 overvoltage 07实际为0x07" 8 "Fan 2 under voltage 08实际为0x08" 9 "Fan 2 is stuck in rotation 09实际为0x09" 10 "Fan 2 overcurrent 10实际为0x0A" 11 "Fan 2 motor overheating 11实际为0x0B" 12 "Fan 2 drive overheating 12实际为0x0C" ;
VAL_ 2337795732 M2P_TMS_L_15_fre_fault_04 0 "no fault  00实际为0x00 引号外不能使用字母" 1 "Overcurrent 01实际为0x01" 2 "Operating overvoltage 02实际为0x02" 3 "Operating under voltage 03实际为0x03" 4 "AC input overvoltage 04实际为0x04" 5 "AC input under voltage 05实际为0x05" 6 "communication fault 06实际为0x06" 7 "Overcurrent frequency reduction 07实际为0x07" 8 "Over power frequency reduction 08实际为0x08" 9 "Input phase loss 09实际为0x09" 10 "External malfunction 10实际为0x0A" 11 "NTC overheating 11实际为0x0B" 12 "Power on to ground short circuit detection 12实际为0x0C" 13 "motor overload 13实际为0x0D" ;
VAL_ 2337795732 M2P_TMS_L_15_D_fault_04 0 "no fault 00实际为0x00 引号外不能使用字母" 1 "Overcurrent 01实际为0x01" 2 "Operating overvoltage 02实际为0x02" 3 "Operating under voltage 03实际为0x03" 4 "DC output overvoltage 04实际为0x04" 5 "DC output undervoltage 05实际为0x05" 6 "communication fault 06实际为0x06" 7 "Substrate overheating 07实际为0x07" 8 "output overload 08实际为0x08" ;
VAL_ 2337795733 M2P_TMS_L_TEM_05 0 "open" 1 "close" ;
VAL_ 2337795733 M2P_TMS_L_WPS_05 0 "open" 1 "close" ;
VAL_ 2337795733 M2P_TMS_L_15_fan_fault_05 0 "no fault 00实际为0x00 引号外不能使用字母" 1 "Fan 1 overvoltage 01实际为0x01" 2 "Fan 1 under voltage 02实际为0x02" 3 "Fan 1 is stuck in rotation 03实际为0x03" 4 "Fan 1 overcurrent 04实际为0x04" 5 "Fan 1 motor overheating 05实际为0x05" 6 "Fan 1 drive overheating 06实际为0x06" 7 "Fan 2 overvoltage 07实际为0x07" 8 "Fan 2 under voltage 08实际为0x08" 9 "Fan 2 is stuck in rotation 09实际为0x09" 10 "Fan 2 overcurrent 10实际为0x0A" 11 "Fan 2 motor overheating 11实际为0x0B" 12 "Fan 2 drive overheating 12实际为0x0C" ;
VAL_ 2337795733 M2P_TMS_L_15_fre_fault_05 0 "no fault  00实际为0x00 引号外不能使用字母" 1 "Overcurrent 01实际为0x01" 2 "Operating overvoltage 02实际为0x02" 3 "Operating under voltage 03实际为0x03" 4 "AC input overvoltage 04实际为0x04" 5 "AC input under voltage 05实际为0x05" 6 "communication fault 06实际为0x06" 7 "Overcurrent frequency reduction 07实际为0x07" 8 "Over power frequency reduction 08实际为0x08" 9 "Input phase loss 09实际为0x09" 10 "External malfunction 10实际为0x0A" 11 "NTC overheating 11实际为0x0B" 12 "Power on to ground short circuit detection 12实际为0x0C" 13 "motor overload 13实际为0x0D" ;
VAL_ 2337795733 M2P_TMS_L_15_D_fault_05 0 "no fault 00实际为0x00 引号外不能使用字母" 1 "Overcurrent 01实际为0x01" 2 "Operating overvoltage 02实际为0x02" 3 "Operating under voltage 03实际为0x03" 4 "DC output overvoltage 04实际为0x04" 5 "DC output undervoltage 05实际为0x05" 6 "communication fault 06实际为0x06" 7 "Substrate overheating 07实际为0x07" 8 "output overload 08实际为0x08" ;
VAL_ 2337795734 M2P_TMS_L_TEM_06 0 "open" 1 "close" ;
VAL_ 2337795734 M2P_TMS_L_WPS_06 0 "open" 1 "close" ;
VAL_ 2337795734 M2P_TMS_L_15_fan_fault_06 0 "no fault 00实际为0x00 引号外不能使用字母" 1 "Fan 1 overvoltage 01实际为0x01" 2 "Fan 1 under voltage 02实际为0x02" 3 "Fan 1 is stuck in rotation 03实际为0x03" 4 "Fan 1 overcurrent 04实际为0x04" 5 "Fan 1 motor overheating 05实际为0x05" 6 "Fan 1 drive overheating 06实际为0x06" 7 "Fan 2 overvoltage 07实际为0x07" 8 "Fan 2 under voltage 08实际为0x08" 9 "Fan 2 is stuck in rotation 09实际为0x09" 10 "Fan 2 overcurrent 10实际为0x0A" 11 "Fan 2 motor overheating 11实际为0x0B" 12 "Fan 2 drive overheating 12实际为0x0C" ;
VAL_ 2337795734 M2P_TMS_L_15_fre_fault_06 0 "no fault  00实际为0x00 引号外不能使用字母" 1 "Overcurrent 01实际为0x01" 2 "Operating overvoltage 02实际为0x02" 3 "Operating under voltage 03实际为0x03" 4 "AC input overvoltage 04实际为0x04" 5 "AC input under voltage 05实际为0x05" 6 "communication fault 06实际为0x06" 7 "Overcurrent frequency reduction 07实际为0x07" 8 "Over power frequency reduction 08实际为0x08" 9 "Input phase loss 09实际为0x09" 10 "External malfunction 10实际为0x0A" 11 "NTC overheating 11实际为0x0B" 12 "Power on to ground short circuit detection 12实际为0x0C" 13 "motor overload 13实际为0x0D" ;
VAL_ 2337795734 M2P_TMS_L_15_D_fault_06 0 "no fault 00实际为0x00 引号外不能使用字母" 1 "Overcurrent 01实际为0x01" 2 "Operating overvoltage 02实际为0x02" 3 "Operating under voltage 03实际为0x03" 4 "DC output overvoltage 04实际为0x04" 5 "DC output undervoltage 05实际为0x05" 6 "communication fault 06实际为0x06" 7 "Substrate overheating 07实际为0x07" 8 "output overload 08实际为0x08" ;
VAL_ 2337795735 M2P_TMS_L_TEM_07 0 "open" 1 "close" ;
VAL_ 2337795735 M2P_TMS_L_WPS_07 0 "open" 1 "close" ;
VAL_ 2337795735 M2P_TMS_L_15_fan_fault_07 0 "no fault 00实际为0x00 引号外不能使用字母" 1 "Fan 1 overvoltage 01实际为0x01" 2 "Fan 1 under voltage 02实际为0x02" 3 "Fan 1 is stuck in rotation 03实际为0x03" 4 "Fan 1 overcurrent 04实际为0x04" 5 "Fan 1 motor overheating 05实际为0x05" 6 "Fan 1 drive overheating 06实际为0x06" 7 "Fan 2 overvoltage 07实际为0x07" 8 "Fan 2 under voltage 08实际为0x08" 9 "Fan 2 is stuck in rotation 09实际为0x09" 10 "Fan 2 overcurrent 10实际为0x0A" 11 "Fan 2 motor overheating 11实际为0x0B" 12 "Fan 2 drive overheating 12实际为0x0C" ;
VAL_ 2337795735 M2P_TMS_L_15_fre_fault_07 0 "no fault  00实际为0x00 引号外不能使用字母" 1 "Overcurrent 01实际为0x01" 2 "Operating overvoltage 02实际为0x02" 3 "Operating under voltage 03实际为0x03" 4 "AC input overvoltage 04实际为0x04" 5 "AC input under voltage 05实际为0x05" 6 "communication fault 06实际为0x06" 7 "Overcurrent frequency reduction 07实际为0x07" 8 "Over power frequency reduction 08实际为0x08" 9 "Input phase loss 09实际为0x09" 10 "External malfunction 10实际为0x0A" 11 "NTC overheating 11实际为0x0B" 12 "Power on to ground short circuit detection 12实际为0x0C" 13 "motor overload 13实际为0x0D" ;
VAL_ 2337795735 M2P_TMS_L_15_D_fault_07 0 "no fault 00实际为0x00 引号外不能使用字母" 1 "Overcurrent 01实际为0x01" 2 "Operating overvoltage 02实际为0x02" 3 "Operating under voltage 03实际为0x03" 4 "DC output overvoltage 04实际为0x04" 5 "DC output undervoltage 05实际为0x05" 6 "communication fault 06实际为0x06" 7 "Substrate overheating 07实际为0x07" 8 "output overload 08实际为0x08" ;
VAL_ 2337795736 M2P_TMS_L_TEM_08 0 "open" 1 "close" ;
VAL_ 2337795736 M2P_TMS_L_WPS_08 0 "open" 1 "close" ;
VAL_ 2337795736 M2P_TMS_L_15_fan_fault_08 0 "no fault 00实际为0x00 引号外不能使用字母" 1 "Fan 1 overvoltage 01实际为0x01" 2 "Fan 1 under voltage 02实际为0x02" 3 "Fan 1 is stuck in rotation 03实际为0x03" 4 "Fan 1 overcurrent 04实际为0x04" 5 "Fan 1 motor overheating 05实际为0x05" 6 "Fan 1 drive overheating 06实际为0x06" 7 "Fan 2 overvoltage 07实际为0x07" 8 "Fan 2 under voltage 08实际为0x08" 9 "Fan 2 is stuck in rotation 09实际为0x09" 10 "Fan 2 overcurrent 10实际为0x0A" 11 "Fan 2 motor overheating 11实际为0x0B" 12 "Fan 2 drive overheating 12实际为0x0C" ;
VAL_ 2337795736 M2P_TMS_L_15_fre_fault_08 0 "no fault  00实际为0x00 引号外不能使用字母" 1 "Overcurrent 01实际为0x01" 2 "Operating overvoltage 02实际为0x02" 3 "Operating under voltage 03实际为0x03" 4 "AC input overvoltage 04实际为0x04" 5 "AC input under voltage 05实际为0x05" 6 "communication fault 06实际为0x06" 7 "Overcurrent frequency reduction 07实际为0x07" 8 "Over power frequency reduction 08实际为0x08" 9 "Input phase loss 09实际为0x09" 10 "External malfunction 10实际为0x0A" 11 "NTC overheating 11实际为0x0B" 12 "Power on to ground short circuit detection 12实际为0x0C" 13 "motor overload 13实际为0x0D" ;
VAL_ 2337795736 M2P_TMS_L_15_D_fault_08 0 "no fault 00实际为0x00 引号外不能使用字母" 1 "Overcurrent 01实际为0x01" 2 "Operating overvoltage 02实际为0x02" 3 "Operating under voltage 03实际为0x03" 4 "DC output overvoltage 04实际为0x04" 5 "DC output undervoltage 05实际为0x05" 6 "communication fault 06实际为0x06" 7 "Substrate overheating 07实际为0x07" 8 "output overload 08实际为0x08" ;
VAL_ 2337795737 M2P_TMS_L_TEM_09 0 "open" 1 "close" ;
VAL_ 2337795737 M2P_TMS_L_WPS_09 0 "open" 1 "close" ;
VAL_ 2337795737 M2P_TMS_L_15_fan_fault_09 0 "no fault 00实际为0x00 引号外不能使用字母" 1 "Fan 1 overvoltage 01实际为0x01" 2 "Fan 1 under voltage 02实际为0x02" 3 "Fan 1 is stuck in rotation 03实际为0x03" 4 "Fan 1 overcurrent 04实际为0x04" 5 "Fan 1 motor overheating 05实际为0x05" 6 "Fan 1 drive overheating 06实际为0x06" 7 "Fan 2 overvoltage 07实际为0x07" 8 "Fan 2 under voltage 08实际为0x08" 9 "Fan 2 is stuck in rotation 09实际为0x09" 10 "Fan 2 overcurrent 10实际为0x0A" 11 "Fan 2 motor overheating 11实际为0x0B" 12 "Fan 2 drive overheating 12实际为0x0C" ;
VAL_ 2337795737 M2P_TMS_L_15_fre_fault_09 0 "no fault  00实际为0x00 引号外不能使用字母" 1 "Overcurrent 01实际为0x01" 2 "Operating overvoltage 02实际为0x02" 3 "Operating under voltage 03实际为0x03" 4 "AC input overvoltage 04实际为0x04" 5 "AC input under voltage 05实际为0x05" 6 "communication fault 06实际为0x06" 7 "Overcurrent frequency reduction 07实际为0x07" 8 "Over power frequency reduction 08实际为0x08" 9 "Input phase loss 09实际为0x09" 10 "External malfunction 10实际为0x0A" 11 "NTC overheating 11实际为0x0B" 12 "Power on to ground short circuit detection 12实际为0x0C" 13 "motor overload 13实际为0x0D" ;
VAL_ 2337795737 M2P_TMS_L_15_D_fault_09 0 "no fault 00实际为0x00 引号外不能使用字母" 1 "Overcurrent 01实际为0x01" 2 "Operating overvoltage 02实际为0x02" 3 "Operating under voltage 03实际为0x03" 4 "DC output overvoltage 04实际为0x04" 5 "DC output undervoltage 05实际为0x05" 6 "communication fault 06实际为0x06" 7 "Substrate overheating 07实际为0x07" 8 "output overload 08实际为0x08" ;
VAL_ 2337795738 M2P_TMS_L_TEM_10 0 "open" 1 "close" ;
VAL_ 2337795738 M2P_TMS_L_WPS_10 0 "open" 1 "close" ;
VAL_ 2337795738 M2P_TMS_L_15_fan_fault_10 0 "no fault 00实际为0x00 引号外不能使用字母" 1 "Fan 1 overvoltage 01实际为0x01" 2 "Fan 1 under voltage 02实际为0x02" 3 "Fan 1 is stuck in rotation 03实际为0x03" 4 "Fan 1 overcurrent 04实际为0x04" 5 "Fan 1 motor overheating 05实际为0x05" 6 "Fan 1 drive overheating 06实际为0x06" 7 "Fan 2 overvoltage 07实际为0x07" 8 "Fan 2 under voltage 08实际为0x08" 9 "Fan 2 is stuck in rotation 09实际为0x09" 10 "Fan 2 overcurrent 10实际为0x0A" 11 "Fan 2 motor overheating 11实际为0x0B" 12 "Fan 2 drive overheating 12实际为0x0C" ;
VAL_ 2337795738 M2P_TMS_L_15_fre_fault_10 0 "no fault  00实际为0x00 引号外不能使用字母" 1 "Overcurrent 01实际为0x01" 2 "Operating overvoltage 02实际为0x02" 3 "Operating under voltage 03实际为0x03" 4 "AC input overvoltage 04实际为0x04" 5 "AC input under voltage 05实际为0x05" 6 "communication fault 06实际为0x06" 7 "Overcurrent frequency reduction 07实际为0x07" 8 "Over power frequency reduction 08实际为0x08" 9 "Input phase loss 09实际为0x09" 10 "External malfunction 10实际为0x0A" 11 "NTC overheating 11实际为0x0B" 12 "Power on to ground short circuit detection 12实际为0x0C" 13 "motor overload 13实际为0x0D" ;
VAL_ 2337795738 M2P_TMS_L_15_D_fault_10 0 "no fault 00实际为0x00 引号外不能使用字母" 1 "Overcurrent 01实际为0x01" 2 "Operating overvoltage 02实际为0x02" 3 "Operating under voltage 03实际为0x03" 4 "DC output overvoltage 04实际为0x04" 5 "DC output undervoltage 05实际为0x05" 6 "communication fault 06实际为0x06" 7 "Substrate overheating 07实际为0x07" 8 "output overload 08实际为0x08" ;
VAL_ 2337795739 M2P_TMS_L_TEM_11 0 "open" 1 "close" ;
VAL_ 2337795739 M2P_TMS_L_WPS_11 0 "open" 1 "close" ;
VAL_ 2337795739 M2P_TMS_L_15_fan_fault_11 0 "no fault 00实际为0x00 引号外不能使用字母" 1 "Fan 1 overvoltage 01实际为0x01" 2 "Fan 1 under voltage 02实际为0x02" 3 "Fan 1 is stuck in rotation 03实际为0x03" 4 "Fan 1 overcurrent 04实际为0x04" 5 "Fan 1 motor overheating 05实际为0x05" 6 "Fan 1 drive overheating 06实际为0x06" 7 "Fan 2 overvoltage 07实际为0x07" 8 "Fan 2 under voltage 08实际为0x08" 9 "Fan 2 is stuck in rotation 09实际为0x09" 10 "Fan 2 overcurrent 10实际为0x0A" 11 "Fan 2 motor overheating 11实际为0x0B" 12 "Fan 2 drive overheating 12实际为0x0C" ;
VAL_ 2337795739 M2P_TMS_L_15_fre_fault_11 0 "no fault  00实际为0x00 引号外不能使用字母" 1 "Overcurrent 01实际为0x01" 2 "Operating overvoltage 02实际为0x02" 3 "Operating under voltage 03实际为0x03" 4 "AC input overvoltage 04实际为0x04" 5 "AC input under voltage 05实际为0x05" 6 "communication fault 06实际为0x06" 7 "Overcurrent frequency reduction 07实际为0x07" 8 "Over power frequency reduction 08实际为0x08" 9 "Input phase loss 09实际为0x09" 10 "External malfunction 10实际为0x0A" 11 "NTC overheating 11实际为0x0B" 12 "Power on to ground short circuit detection 12实际为0x0C" 13 "motor overload 13实际为0x0D" ;
VAL_ 2337795739 M2P_TMS_L_15_D_fault_11 0 "no fault 00实际为0x00 引号外不能使用字母" 1 "Overcurrent 01实际为0x01" 2 "Operating overvoltage 02实际为0x02" 3 "Operating under voltage 03实际为0x03" 4 "DC output overvoltage 04实际为0x04" 5 "DC output undervoltage 05实际为0x05" 6 "communication fault 06实际为0x06" 7 "Substrate overheating 07实际为0x07" 8 "output overload 08实际为0x08" ;
VAL_ 2337795740 M2P_TMS_L_TEM_12 0 "open" 1 "close" ;
VAL_ 2337795740 M2P_TMS_L_WPS_12 0 "open" 1 "close" ;
VAL_ 2337795740 M2P_TMS_L_15_fan_fault_12 0 "no fault 00实际为0x00 引号外不能使用字母" 1 "Fan 1 overvoltage 01实际为0x01" 2 "Fan 1 under voltage 02实际为0x02" 3 "Fan 1 is stuck in rotation 03实际为0x03" 4 "Fan 1 overcurrent 04实际为0x04" 5 "Fan 1 motor overheating 05实际为0x05" 6 "Fan 1 drive overheating 06实际为0x06" 7 "Fan 2 overvoltage 07实际为0x07" 8 "Fan 2 under voltage 08实际为0x08" 9 "Fan 2 is stuck in rotation 09实际为0x09" 10 "Fan 2 overcurrent 10实际为0x0A" 11 "Fan 2 motor overheating 11实际为0x0B" 12 "Fan 2 drive overheating 12实际为0x0C" ;
VAL_ 2337795740 M2P_TMS_L_15_fre_fault_12 0 "no fault  00实际为0x00 引号外不能使用字母" 1 "Overcurrent 01实际为0x01" 2 "Operating overvoltage 02实际为0x02" 3 "Operating under voltage 03实际为0x03" 4 "AC input overvoltage 04实际为0x04" 5 "AC input under voltage 05实际为0x05" 6 "communication fault 06实际为0x06" 7 "Overcurrent frequency reduction 07实际为0x07" 8 "Over power frequency reduction 08实际为0x08" 9 "Input phase loss 09实际为0x09" 10 "External malfunction 10实际为0x0A" 11 "NTC overheating 11实际为0x0B" 12 "Power on to ground short circuit detection 12实际为0x0C" 13 "motor overload 13实际为0x0D" ;
VAL_ 2337795740 M2P_TMS_L_15_D_fault_12 0 "no fault 00实际为0x00 引号外不能使用字母" 1 "Overcurrent 01实际为0x01" 2 "Operating overvoltage 02实际为0x02" 3 "Operating under voltage 03实际为0x03" 4 "DC output overvoltage 04实际为0x04" 5 "DC output undervoltage 05实际为0x05" 6 "communication fault 06实际为0x06" 7 "Substrate overheating 07实际为0x07" 8 "output overload 08实际为0x08" ;
VAL_ 2337795741 M2P_TMS_L_TEM_13 0 "open" 1 "close" ;
VAL_ 2337795741 M2P_TMS_L_WPS_13 0 "open" 1 "close" ;
VAL_ 2337795741 M2P_TMS_L_15_fan_fault_13 0 "no fault 00实际为0x00 引号外不能使用字母" 1 "Fan 1 overvoltage 01实际为0x01" 2 "Fan 1 under voltage 02实际为0x02" 3 "Fan 1 is stuck in rotation 03实际为0x03" 4 "Fan 1 overcurrent 04实际为0x04" 5 "Fan 1 motor overheating 05实际为0x05" 6 "Fan 1 drive overheating 06实际为0x06" 7 "Fan 2 overvoltage 07实际为0x07" 8 "Fan 2 under voltage 08实际为0x08" 9 "Fan 2 is stuck in rotation 09实际为0x09" 10 "Fan 2 overcurrent 10实际为0x0A" 11 "Fan 2 motor overheating 11实际为0x0B" 12 "Fan 2 drive overheating 12实际为0x0C" ;
VAL_ 2337795741 M2P_TMS_L_15_fre_fault_13 0 "no fault  00实际为0x00 引号外不能使用字母" 1 "Overcurrent 01实际为0x01" 2 "Operating overvoltage 02实际为0x02" 3 "Operating under voltage 03实际为0x03" 4 "AC input overvoltage 04实际为0x04" 5 "AC input under voltage 05实际为0x05" 6 "communication fault 06实际为0x06" 7 "Overcurrent frequency reduction 07实际为0x07" 8 "Over power frequency reduction 08实际为0x08" 9 "Input phase loss 09实际为0x09" 10 "External malfunction 10实际为0x0A" 11 "NTC overheating 11实际为0x0B" 12 "Power on to ground short circuit detection 12实际为0x0C" 13 "motor overload 13实际为0x0D" ;
VAL_ 2337795741 M2P_TMS_L_15_D_fault_13 0 "no fault 00实际为0x00 引号外不能使用字母" 1 "Overcurrent 01实际为0x01" 2 "Operating overvoltage 02实际为0x02" 3 "Operating under voltage 03实际为0x03" 4 "DC output overvoltage 04实际为0x04" 5 "DC output undervoltage 05实际为0x05" 6 "communication fault 06实际为0x06" 7 "Substrate overheating 07实际为0x07" 8 "output overload 08实际为0x08" ;
VAL_ 2337795742 M2P_TMS_L_TEM_14 0 "open" 1 "close" ;
VAL_ 2337795742 M2P_TMS_L_WPS_14 0 "open" 1 "close" ;
VAL_ 2337795742 M2P_TMS_L_15_fan_fault_14 0 "no fault 00实际为0x00 引号外不能使用字母" 1 "Fan 1 overvoltage 01实际为0x01" 2 "Fan 1 under voltage 02实际为0x02" 3 "Fan 1 is stuck in rotation 03实际为0x03" 4 "Fan 1 overcurrent 04实际为0x04" 5 "Fan 1 motor overheating 05实际为0x05" 6 "Fan 1 drive overheating 06实际为0x06" 7 "Fan 2 overvoltage 07实际为0x07" 8 "Fan 2 under voltage 08实际为0x08" 9 "Fan 2 is stuck in rotation 09实际为0x09" 10 "Fan 2 overcurrent 10实际为0x0A" 11 "Fan 2 motor overheating 11实际为0x0B" 12 "Fan 2 drive overheating 12实际为0x0C" ;
VAL_ 2337795742 M2P_TMS_L_15_fre_fault_14 0 "no fault  00实际为0x00 引号外不能使用字母" 1 "Overcurrent 01实际为0x01" 2 "Operating overvoltage 02实际为0x02" 3 "Operating under voltage 03实际为0x03" 4 "AC input overvoltage 04实际为0x04" 5 "AC input under voltage 05实际为0x05" 6 "communication fault 06实际为0x06" 7 "Overcurrent frequency reduction 07实际为0x07" 8 "Over power frequency reduction 08实际为0x08" 9 "Input phase loss 09实际为0x09" 10 "External malfunction 10实际为0x0A" 11 "NTC overheating 11实际为0x0B" 12 "Power on to ground short circuit detection 12实际为0x0C" 13 "motor overload 13实际为0x0D" ;
VAL_ 2337795742 M2P_TMS_L_15_D_fault_14 0 "no fault 00实际为0x00 引号外不能使用字母" 1 "Overcurrent 01实际为0x01" 2 "Operating overvoltage 02实际为0x02" 3 "Operating under voltage 03实际为0x03" 4 "DC output overvoltage 04实际为0x04" 5 "DC output undervoltage 05实际为0x05" 6 "communication fault 06实际为0x06" 7 "Substrate overheating 07实际为0x07" 8 "output overload 08实际为0x08" ;
VAL_ 2337795743 M2P_TMS_L_TEM_15 0 "open" 1 "close" ;
VAL_ 2337795743 M2P_TMS_L_WPS_15 0 "open" 1 "close" ;
VAL_ 2337795743 M2P_TMS_L_15_fan_fault_15 0 "no fault 00实际为0x00 引号外不能使用字母" 1 "Fan 1 overvoltage 01实际为0x01" 2 "Fan 1 under voltage 02实际为0x02" 3 "Fan 1 is stuck in rotation 03实际为0x03" 4 "Fan 1 overcurrent 04实际为0x04" 5 "Fan 1 motor overheating 05实际为0x05" 6 "Fan 1 drive overheating 06实际为0x06" 7 "Fan 2 overvoltage 07实际为0x07" 8 "Fan 2 under voltage 08实际为0x08" 9 "Fan 2 is stuck in rotation 09实际为0x09" 10 "Fan 2 overcurrent 10实际为0x0A" 11 "Fan 2 motor overheating 11实际为0x0B" 12 "Fan 2 drive overheating 12实际为0x0C" ;
VAL_ 2337795743 M2P_TMS_L_15_fre_fault_15 0 "no fault  00实际为0x00 引号外不能使用字母" 1 "Overcurrent 01实际为0x01" 2 "Operating overvoltage 02实际为0x02" 3 "Operating under voltage 03实际为0x03" 4 "AC input overvoltage 04实际为0x04" 5 "AC input under voltage 05实际为0x05" 6 "communication fault 06实际为0x06" 7 "Overcurrent frequency reduction 07实际为0x07" 8 "Over power frequency reduction 08实际为0x08" 9 "Input phase loss 09实际为0x09" 10 "External malfunction 10实际为0x0A" 11 "NTC overheating 11实际为0x0B" 12 "Power on to ground short circuit detection 12实际为0x0C" 13 "motor overload 13实际为0x0D" ;
VAL_ 2337795743 M2P_TMS_L_15_D_fault_15 0 "no fault 00实际为0x00 引号外不能使用字母" 1 "Overcurrent 01实际为0x01" 2 "Operating overvoltage 02实际为0x02" 3 "Operating under voltage 03实际为0x03" 4 "DC output overvoltage 04实际为0x04" 5 "DC output undervoltage 05实际为0x05" 6 "communication fault 06实际为0x06" 7 "Substrate overheating 07实际为0x07" 8 "output overload 08实际为0x08" ;
VAL_ 2337795744 M2P_TMS_L_TEM_16 0 "open" 1 "close" ;
VAL_ 2337795744 M2P_TMS_L_WPS_16 0 "open" 1 "close" ;
VAL_ 2337795744 M2P_TMS_L_15_fan_fault_16 0 "no fault 00实际为0x00 引号外不能使用字母" 1 "Fan 1 overvoltage 01实际为0x01" 2 "Fan 1 under voltage 02实际为0x02" 3 "Fan 1 is stuck in rotation 03实际为0x03" 4 "Fan 1 overcurrent 04实际为0x04" 5 "Fan 1 motor overheating 05实际为0x05" 6 "Fan 1 drive overheating 06实际为0x06" 7 "Fan 2 overvoltage 07实际为0x07" 8 "Fan 2 under voltage 08实际为0x08" 9 "Fan 2 is stuck in rotation 09实际为0x09" 10 "Fan 2 overcurrent 10实际为0x0A" 11 "Fan 2 motor overheating 11实际为0x0B" 12 "Fan 2 drive overheating 12实际为0x0C" ;
VAL_ 2337795744 M2P_TMS_L_15_fre_fault_16 0 "no fault  00实际为0x00 引号外不能使用字母" 1 "Overcurrent 01实际为0x01" 2 "Operating overvoltage 02实际为0x02" 3 "Operating under voltage 03实际为0x03" 4 "AC input overvoltage 04实际为0x04" 5 "AC input under voltage 05实际为0x05" 6 "communication fault 06实际为0x06" 7 "Overcurrent frequency reduction 07实际为0x07" 8 "Over power frequency reduction 08实际为0x08" 9 "Input phase loss 09实际为0x09" 10 "External malfunction 10实际为0x0A" 11 "NTC overheating 11实际为0x0B" 12 "Power on to ground short circuit detection 12实际为0x0C" 13 "motor overload 13实际为0x0D" ;
VAL_ 2337795744 M2P_TMS_L_15_D_fault_16 0 "no fault 00实际为0x00 引号外不能使用字母" 1 "Overcurrent 01实际为0x01" 2 "Operating overvoltage 02实际为0x02" 3 "Operating under voltage 03实际为0x03" 4 "DC output overvoltage 04实际为0x04" 5 "DC output undervoltage 05实际为0x05" 6 "communication fault 06实际为0x06" 7 "Substrate overheating 07实际为0x07" 8 "output overload 08实际为0x08" ;
VAL_ 2337795745 M2P_TMS_L_TEM_17 0 "open" 1 "close" ;
VAL_ 2337795745 M2P_TMS_L_WPS_17 0 "open" 1 "close" ;
VAL_ 2337795745 M2P_TMS_L_15_fan_fault_17 0 "no fault 00实际为0x00 引号外不能使用字母" 1 "Fan 1 overvoltage 01实际为0x01" 2 "Fan 1 under voltage 02实际为0x02" 3 "Fan 1 is stuck in rotation 03实际为0x03" 4 "Fan 1 overcurrent 04实际为0x04" 5 "Fan 1 motor overheating 05实际为0x05" 6 "Fan 1 drive overheating 06实际为0x06" 7 "Fan 2 overvoltage 07实际为0x07" 8 "Fan 2 under voltage 08实际为0x08" 9 "Fan 2 is stuck in rotation 09实际为0x09" 10 "Fan 2 overcurrent 10实际为0x0A" 11 "Fan 2 motor overheating 11实际为0x0B" 12 "Fan 2 drive overheating 12实际为0x0C" ;
VAL_ 2337795745 M2P_TMS_L_15_fre_fault_17 0 "no fault  00实际为0x00 引号外不能使用字母" 1 "Overcurrent 01实际为0x01" 2 "Operating overvoltage 02实际为0x02" 3 "Operating under voltage 03实际为0x03" 4 "AC input overvoltage 04实际为0x04" 5 "AC input under voltage 05实际为0x05" 6 "communication fault 06实际为0x06" 7 "Overcurrent frequency reduction 07实际为0x07" 8 "Over power frequency reduction 08实际为0x08" 9 "Input phase loss 09实际为0x09" 10 "External malfunction 10实际为0x0A" 11 "NTC overheating 11实际为0x0B" 12 "Power on to ground short circuit detection 12实际为0x0C" 13 "motor overload 13实际为0x0D" ;
VAL_ 2337795745 M2P_TMS_L_15_D_fault_17 0 "no fault 00实际为0x00 引号外不能使用字母" 1 "Overcurrent 01实际为0x01" 2 "Operating overvoltage 02实际为0x02" 3 "Operating under voltage 03实际为0x03" 4 "DC output overvoltage 04实际为0x04" 5 "DC output undervoltage 05实际为0x05" 6 "communication fault 06实际为0x06" 7 "Substrate overheating 07实际为0x07" 8 "output overload 08实际为0x08" ;
VAL_ 2337795746 M2P_TMS_L_TEM_18 0 "open" 1 "close" ;
VAL_ 2337795746 M2P_TMS_L_WPS_18 0 "open" 1 "close" ;
VAL_ 2337795746 M2P_TMS_L_15_fan_fault_18 0 "no fault 00实际为0x00 引号外不能使用字母" 1 "Fan 1 overvoltage 01实际为0x01" 2 "Fan 1 under voltage 02实际为0x02" 3 "Fan 1 is stuck in rotation 03实际为0x03" 4 "Fan 1 overcurrent 04实际为0x04" 5 "Fan 1 motor overheating 05实际为0x05" 6 "Fan 1 drive overheating 06实际为0x06" 7 "Fan 2 overvoltage 07实际为0x07" 8 "Fan 2 under voltage 08实际为0x08" 9 "Fan 2 is stuck in rotation 09实际为0x09" 10 "Fan 2 overcurrent 10实际为0x0A" 11 "Fan 2 motor overheating 11实际为0x0B" 12 "Fan 2 drive overheating 12实际为0x0C" ;
VAL_ 2337795746 M2P_TMS_L_15_fre_fault_18 0 "no fault  00实际为0x00 引号外不能使用字母" 1 "Overcurrent 01实际为0x01" 2 "Operating overvoltage 02实际为0x02" 3 "Operating under voltage 03实际为0x03" 4 "AC input overvoltage 04实际为0x04" 5 "AC input under voltage 05实际为0x05" 6 "communication fault 06实际为0x06" 7 "Overcurrent frequency reduction 07实际为0x07" 8 "Over power frequency reduction 08实际为0x08" 9 "Input phase loss 09实际为0x09" 10 "External malfunction 10实际为0x0A" 11 "NTC overheating 11实际为0x0B" 12 "Power on to ground short circuit detection 12实际为0x0C" 13 "motor overload 13实际为0x0D" ;
VAL_ 2337795746 M2P_TMS_L_15_D_fault_18 0 "no fault 00实际为0x00 引号外不能使用字母" 1 "Overcurrent 01实际为0x01" 2 "Operating overvoltage 02实际为0x02" 3 "Operating under voltage 03实际为0x03" 4 "DC output overvoltage 04实际为0x04" 5 "DC output undervoltage 05实际为0x05" 6 "communication fault 06实际为0x06" 7 "Substrate overheating 07实际为0x07" 8 "output overload 08实际为0x08" ;
VAL_ 2337795747 M2P_TMS_L_TEM_19 0 "open" 1 "close" ;
VAL_ 2337795747 M2P_TMS_L_WPS_19 0 "open" 1 "close" ;
VAL_ 2337795747 M2P_TMS_L_15_fan_fault_19 0 "no fault 00实际为0x00 引号外不能使用字母" 1 "Fan 1 overvoltage 01实际为0x01" 2 "Fan 1 under voltage 02实际为0x02" 3 "Fan 1 is stuck in rotation 03实际为0x03" 4 "Fan 1 overcurrent 04实际为0x04" 5 "Fan 1 motor overheating 05实际为0x05" 6 "Fan 1 drive overheating 06实际为0x06" 7 "Fan 2 overvoltage 07实际为0x07" 8 "Fan 2 under voltage 08实际为0x08" 9 "Fan 2 is stuck in rotation 09实际为0x09" 10 "Fan 2 overcurrent 10实际为0x0A" 11 "Fan 2 motor overheating 11实际为0x0B" 12 "Fan 2 drive overheating 12实际为0x0C" ;
VAL_ 2337795747 M2P_TMS_L_15_fre_fault_19 0 "no fault  00实际为0x00 引号外不能使用字母" 1 "Overcurrent 01实际为0x01" 2 "Operating overvoltage 02实际为0x02" 3 "Operating under voltage 03实际为0x03" 4 "AC input overvoltage 04实际为0x04" 5 "AC input under voltage 05实际为0x05" 6 "communication fault 06实际为0x06" 7 "Overcurrent frequency reduction 07实际为0x07" 8 "Over power frequency reduction 08实际为0x08" 9 "Input phase loss 09实际为0x09" 10 "External malfunction 10实际为0x0A" 11 "NTC overheating 11实际为0x0B" 12 "Power on to ground short circuit detection 12实际为0x0C" 13 "motor overload 13实际为0x0D" ;
VAL_ 2337795747 M2P_TMS_L_15_D_fault_19 0 "no fault 00实际为0x00 引号外不能使用字母" 1 "Overcurrent 01实际为0x01" 2 "Operating overvoltage 02实际为0x02" 3 "Operating under voltage 03实际为0x03" 4 "DC output overvoltage 04实际为0x04" 5 "DC output undervoltage 05实际为0x05" 6 "communication fault 06实际为0x06" 7 "Substrate overheating 07实际为0x07" 8 "output overload 08实际为0x08" ;
VAL_ 2337795748 M2P_TMS_L_TEM_20 0 "open" 1 "close" ;
VAL_ 2337795748 M2P_TMS_L_WPS_20 0 "open" 1 "close" ;
VAL_ 2337795748 M2P_TMS_L_15_fan_fault_20 0 "no fault 00实际为0x00 引号外不能使用字母" 1 "Fan 1 overvoltage 01实际为0x01" 2 "Fan 1 under voltage 02实际为0x02" 3 "Fan 1 is stuck in rotation 03实际为0x03" 4 "Fan 1 overcurrent 04实际为0x04" 5 "Fan 1 motor overheating 05实际为0x05" 6 "Fan 1 drive overheating 06实际为0x06" 7 "Fan 2 overvoltage 07实际为0x07" 8 "Fan 2 under voltage 08实际为0x08" 9 "Fan 2 is stuck in rotation 09实际为0x09" 10 "Fan 2 overcurrent 10实际为0x0A" 11 "Fan 2 motor overheating 11实际为0x0B" 12 "Fan 2 drive overheating 12实际为0x0C" ;
VAL_ 2337795748 M2P_TMS_L_15_fre_fault_20 0 "no fault  00实际为0x00 引号外不能使用字母" 1 "Overcurrent 01实际为0x01" 2 "Operating overvoltage 02实际为0x02" 3 "Operating under voltage 03实际为0x03" 4 "AC input overvoltage 04实际为0x04" 5 "AC input under voltage 05实际为0x05" 6 "communication fault 06实际为0x06" 7 "Overcurrent frequency reduction 07实际为0x07" 8 "Over power frequency reduction 08实际为0x08" 9 "Input phase loss 09实际为0x09" 10 "External malfunction 10实际为0x0A" 11 "NTC overheating 11实际为0x0B" 12 "Power on to ground short circuit detection 12实际为0x0C" 13 "motor overload 13实际为0x0D" ;
VAL_ 2337795748 M2P_TMS_L_15_D_fault_20 0 "no fault 00实际为0x00 引号外不能使用字母" 1 "Overcurrent 01实际为0x01" 2 "Operating overvoltage 02实际为0x02" 3 "Operating under voltage 03实际为0x03" 4 "DC output overvoltage 04实际为0x04" 5 "DC output undervoltage 05实际为0x05" 6 "communication fault 06实际为0x06" 7 "Substrate overheating 07实际为0x07" 8 "output overload 08实际为0x08" ;
VAL_ 2337795749 M2P_TMS_L_TEM_21 0 "open" 1 "close" ;
VAL_ 2337795749 M2P_TMS_L_WPS_21 0 "open" 1 "close" ;
VAL_ 2337795749 M2P_TMS_L_15_fan_fault_21 0 "no fault 00实际为0x00 引号外不能使用字母" 1 "Fan 1 overvoltage 01实际为0x01" 2 "Fan 1 under voltage 02实际为0x02" 3 "Fan 1 is stuck in rotation 03实际为0x03" 4 "Fan 1 overcurrent 04实际为0x04" 5 "Fan 1 motor overheating 05实际为0x05" 6 "Fan 1 drive overheating 06实际为0x06" 7 "Fan 2 overvoltage 07实际为0x07" 8 "Fan 2 under voltage 08实际为0x08" 9 "Fan 2 is stuck in rotation 09实际为0x09" 10 "Fan 2 overcurrent 10实际为0x0A" 11 "Fan 2 motor overheating 11实际为0x0B" 12 "Fan 2 drive overheating 12实际为0x0C" ;
VAL_ 2337795749 M2P_TMS_L_15_fre_fault_21 0 "no fault  00实际为0x00 引号外不能使用字母" 1 "Overcurrent 01实际为0x01" 2 "Operating overvoltage 02实际为0x02" 3 "Operating under voltage 03实际为0x03" 4 "AC input overvoltage 04实际为0x04" 5 "AC input under voltage 05实际为0x05" 6 "communication fault 06实际为0x06" 7 "Overcurrent frequency reduction 07实际为0x07" 8 "Over power frequency reduction 08实际为0x08" 9 "Input phase loss 09实际为0x09" 10 "External malfunction 10实际为0x0A" 11 "NTC overheating 11实际为0x0B" 12 "Power on to ground short circuit detection 12实际为0x0C" 13 "motor overload 13实际为0x0D" ;
VAL_ 2337795749 M2P_TMS_L_15_D_fault_21 0 "no fault 00实际为0x00 引号外不能使用字母" 1 "Overcurrent 01实际为0x01" 2 "Operating overvoltage 02实际为0x02" 3 "Operating under voltage 03实际为0x03" 4 "DC output overvoltage 04实际为0x04" 5 "DC output undervoltage 05实际为0x05" 6 "communication fault 06实际为0x06" 7 "Substrate overheating 07实际为0x07" 8 "output overload 08实际为0x08" ;
VAL_ 2337795750 M2P_TMS_L_TEM_22 0 "open" 1 "close" ;
VAL_ 2337795750 M2P_TMS_L_WPS_22 0 "open" 1 "close" ;
VAL_ 2337795750 M2P_TMS_L_15_fan_fault_22 0 "no fault 00实际为0x00 引号外不能使用字母" 1 "Fan 1 overvoltage 01实际为0x01" 2 "Fan 1 under voltage 02实际为0x02" 3 "Fan 1 is stuck in rotation 03实际为0x03" 4 "Fan 1 overcurrent 04实际为0x04" 5 "Fan 1 motor overheating 05实际为0x05" 6 "Fan 1 drive overheating 06实际为0x06" 7 "Fan 2 overvoltage 07实际为0x07" 8 "Fan 2 under voltage 08实际为0x08" 9 "Fan 2 is stuck in rotation 09实际为0x09" 10 "Fan 2 overcurrent 10实际为0x0A" 11 "Fan 2 motor overheating 11实际为0x0B" 12 "Fan 2 drive overheating 12实际为0x0C" ;
VAL_ 2337795750 M2P_TMS_L_15_fre_fault_22 0 "no fault  00实际为0x00 引号外不能使用字母" 1 "Overcurrent 01实际为0x01" 2 "Operating overvoltage 02实际为0x02" 3 "Operating under voltage 03实际为0x03" 4 "AC input overvoltage 04实际为0x04" 5 "AC input under voltage 05实际为0x05" 6 "communication fault 06实际为0x06" 7 "Overcurrent frequency reduction 07实际为0x07" 8 "Over power frequency reduction 08实际为0x08" 9 "Input phase loss 09实际为0x09" 10 "External malfunction 10实际为0x0A" 11 "NTC overheating 11实际为0x0B" 12 "Power on to ground short circuit detection 12实际为0x0C" 13 "motor overload 13实际为0x0D" ;
VAL_ 2337795750 M2P_TMS_L_15_D_fault_22 0 "no fault 00实际为0x00 引号外不能使用字母" 1 "Overcurrent 01实际为0x01" 2 "Operating overvoltage 02实际为0x02" 3 "Operating under voltage 03实际为0x03" 4 "DC output overvoltage 04实际为0x04" 5 "DC output undervoltage 05实际为0x05" 6 "communication fault 06实际为0x06" 7 "Substrate overheating 07实际为0x07" 8 "output overload 08实际为0x08" ;
VAL_ 2337795751 M2P_TMS_L_TEM_23 0 "open" 1 "close" ;
VAL_ 2337795751 M2P_TMS_L_WPS_23 0 "open" 1 "close" ;
VAL_ 2337795751 M2P_TMS_L_15_fan_fault_23 0 "no fault 00实际为0x00 引号外不能使用字母" 1 "Fan 1 overvoltage 01实际为0x01" 2 "Fan 1 under voltage 02实际为0x02" 3 "Fan 1 is stuck in rotation 03实际为0x03" 4 "Fan 1 overcurrent 04实际为0x04" 5 "Fan 1 motor overheating 05实际为0x05" 6 "Fan 1 drive overheating 06实际为0x06" 7 "Fan 2 overvoltage 07实际为0x07" 8 "Fan 2 under voltage 08实际为0x08" 9 "Fan 2 is stuck in rotation 09实际为0x09" 10 "Fan 2 overcurrent 10实际为0x0A" 11 "Fan 2 motor overheating 11实际为0x0B" 12 "Fan 2 drive overheating 12实际为0x0C" ;
VAL_ 2337795751 M2P_TMS_L_15_fre_fault_23 0 "no fault  00实际为0x00 引号外不能使用字母" 1 "Overcurrent 01实际为0x01" 2 "Operating overvoltage 02实际为0x02" 3 "Operating under voltage 03实际为0x03" 4 "AC input overvoltage 04实际为0x04" 5 "AC input under voltage 05实际为0x05" 6 "communication fault 06实际为0x06" 7 "Overcurrent frequency reduction 07实际为0x07" 8 "Over power frequency reduction 08实际为0x08" 9 "Input phase loss 09实际为0x09" 10 "External malfunction 10实际为0x0A" 11 "NTC overheating 11实际为0x0B" 12 "Power on to ground short circuit detection 12实际为0x0C" 13 "motor overload 13实际为0x0D" ;
VAL_ 2337795751 M2P_TMS_L_15_D_fault_23 0 "no fault 00实际为0x00 引号外不能使用字母" 1 "Overcurrent 01实际为0x01" 2 "Operating overvoltage 02实际为0x02" 3 "Operating under voltage 03实际为0x03" 4 "DC output overvoltage 04实际为0x04" 5 "DC output undervoltage 05实际为0x05" 6 "communication fault 06实际为0x06" 7 "Substrate overheating 07实际为0x07" 8 "output overload 08实际为0x08" ;
VAL_ 2337795752 M2P_TMS_L_TEM_24 0 "open" 1 "close" ;
VAL_ 2337795752 M2P_TMS_L_WPS_24 0 "open" 1 "close" ;
VAL_ 2337795752 M2P_TMS_L_15_fan_fault_24 0 "no fault 00实际为0x00 引号外不能使用字母" 1 "Fan 1 overvoltage 01实际为0x01" 2 "Fan 1 under voltage 02实际为0x02" 3 "Fan 1 is stuck in rotation 03实际为0x03" 4 "Fan 1 overcurrent 04实际为0x04" 5 "Fan 1 motor overheating 05实际为0x05" 6 "Fan 1 drive overheating 06实际为0x06" 7 "Fan 2 overvoltage 07实际为0x07" 8 "Fan 2 under voltage 08实际为0x08" 9 "Fan 2 is stuck in rotation 09实际为0x09" 10 "Fan 2 overcurrent 10实际为0x0A" 11 "Fan 2 motor overheating 11实际为0x0B" 12 "Fan 2 drive overheating 12实际为0x0C" ;
VAL_ 2337795752 M2P_TMS_L_15_fre_fault_24 0 "no fault  00实际为0x00 引号外不能使用字母" 1 "Overcurrent 01实际为0x01" 2 "Operating overvoltage 02实际为0x02" 3 "Operating under voltage 03实际为0x03" 4 "AC input overvoltage 04实际为0x04" 5 "AC input under voltage 05实际为0x05" 6 "communication fault 06实际为0x06" 7 "Overcurrent frequency reduction 07实际为0x07" 8 "Over power frequency reduction 08实际为0x08" 9 "Input phase loss 09实际为0x09" 10 "External malfunction 10实际为0x0A" 11 "NTC overheating 11实际为0x0B" 12 "Power on to ground short circuit detection 12实际为0x0C" 13 "motor overload 13实际为0x0D" ;
VAL_ 2337795752 M2P_TMS_L_15_D_fault_24 0 "no fault 00实际为0x00 引号外不能使用字母" 1 "Overcurrent 01实际为0x01" 2 "Operating overvoltage 02实际为0x02" 3 "Operating under voltage 03实际为0x03" 4 "DC output overvoltage 04实际为0x04" 5 "DC output undervoltage 05实际为0x05" 6 "communication fault 06实际为0x06" 7 "Substrate overheating 07实际为0x07" 8 "output overload 08实际为0x08" ;
VAL_ 2337795753 M2P_TMS_L_TEM_25 0 "open" 1 "close" ;
VAL_ 2337795753 M2P_TMS_L_WPS_25 0 "open" 1 "close" ;
VAL_ 2337795753 M2P_TMS_L_15_fan_fault_25 0 "no fault 00实际为0x00 引号外不能使用字母" 1 "Fan 1 overvoltage 01实际为0x01" 2 "Fan 1 under voltage 02实际为0x02" 3 "Fan 1 is stuck in rotation 03实际为0x03" 4 "Fan 1 overcurrent 04实际为0x04" 5 "Fan 1 motor overheating 05实际为0x05" 6 "Fan 1 drive overheating 06实际为0x06" 7 "Fan 2 overvoltage 07实际为0x07" 8 "Fan 2 under voltage 08实际为0x08" 9 "Fan 2 is stuck in rotation 09实际为0x09" 10 "Fan 2 overcurrent 10实际为0x0A" 11 "Fan 2 motor overheating 11实际为0x0B" 12 "Fan 2 drive overheating 12实际为0x0C" ;
VAL_ 2337795753 M2P_TMS_L_15_fre_fault_25 0 "no fault  00实际为0x00 引号外不能使用字母" 1 "Overcurrent 01实际为0x01" 2 "Operating overvoltage 02实际为0x02" 3 "Operating under voltage 03实际为0x03" 4 "AC input overvoltage 04实际为0x04" 5 "AC input under voltage 05实际为0x05" 6 "communication fault 06实际为0x06" 7 "Overcurrent frequency reduction 07实际为0x07" 8 "Over power frequency reduction 08实际为0x08" 9 "Input phase loss 09实际为0x09" 10 "External malfunction 10实际为0x0A" 11 "NTC overheating 11实际为0x0B" 12 "Power on to ground short circuit detection 12实际为0x0C" 13 "motor overload 13实际为0x0D" ;
VAL_ 2337795753 M2P_TMS_L_15_D_fault_25 0 "no fault 00实际为0x00 引号外不能使用字母" 1 "Overcurrent 01实际为0x01" 2 "Operating overvoltage 02实际为0x02" 3 "Operating under voltage 03实际为0x03" 4 "DC output overvoltage 04实际为0x04" 5 "DC output undervoltage 05实际为0x05" 6 "communication fault 06实际为0x06" 7 "Substrate overheating 07实际为0x07" 8 "output overload 08实际为0x08" ;
VAL_ 2337795754 M2P_TMS_L_TEM_26 0 "open" 1 "close" ;
VAL_ 2337795754 M2P_TMS_L_WPS_26 0 "open" 1 "close" ;
VAL_ 2337795754 M2P_TMS_L_15_fan_fault_26 0 "no fault 00实际为0x00 引号外不能使用字母" 1 "Fan 1 overvoltage 01实际为0x01" 2 "Fan 1 under voltage 02实际为0x02" 3 "Fan 1 is stuck in rotation 03实际为0x03" 4 "Fan 1 overcurrent 04实际为0x04" 5 "Fan 1 motor overheating 05实际为0x05" 6 "Fan 1 drive overheating 06实际为0x06" 7 "Fan 2 overvoltage 07实际为0x07" 8 "Fan 2 under voltage 08实际为0x08" 9 "Fan 2 is stuck in rotation 09实际为0x09" 10 "Fan 2 overcurrent 10实际为0x0A" 11 "Fan 2 motor overheating 11实际为0x0B" 12 "Fan 2 drive overheating 12实际为0x0C" ;
VAL_ 2337795754 M2P_TMS_L_15_fre_fault_26 0 "no fault  00实际为0x00 引号外不能使用字母" 1 "Overcurrent 01实际为0x01" 2 "Operating overvoltage 02实际为0x02" 3 "Operating under voltage 03实际为0x03" 4 "AC input overvoltage 04实际为0x04" 5 "AC input under voltage 05实际为0x05" 6 "communication fault 06实际为0x06" 7 "Overcurrent frequency reduction 07实际为0x07" 8 "Over power frequency reduction 08实际为0x08" 9 "Input phase loss 09实际为0x09" 10 "External malfunction 10实际为0x0A" 11 "NTC overheating 11实际为0x0B" 12 "Power on to ground short circuit detection 12实际为0x0C" 13 "motor overload 13实际为0x0D" ;
VAL_ 2337795754 M2P_TMS_L_15_D_fault_26 0 "no fault 00实际为0x00 引号外不能使用字母" 1 "Overcurrent 01实际为0x01" 2 "Operating overvoltage 02实际为0x02" 3 "Operating under voltage 03实际为0x03" 4 "DC output overvoltage 04实际为0x04" 5 "DC output undervoltage 05实际为0x05" 6 "communication fault 06实际为0x06" 7 "Substrate overheating 07实际为0x07" 8 "output overload 08实际为0x08" ;
VAL_ 2337795755 M2P_TMS_L_TEM_27 0 "open" 1 "close" ;
VAL_ 2337795755 M2P_TMS_L_WPS_27 0 "open" 1 "close" ;
VAL_ 2337795755 M2P_TMS_L_15_fan_fault_27 0 "no fault 00实际为0x00 引号外不能使用字母" 1 "Fan 1 overvoltage 01实际为0x01" 2 "Fan 1 under voltage 02实际为0x02" 3 "Fan 1 is stuck in rotation 03实际为0x03" 4 "Fan 1 overcurrent 04实际为0x04" 5 "Fan 1 motor overheating 05实际为0x05" 6 "Fan 1 drive overheating 06实际为0x06" 7 "Fan 2 overvoltage 07实际为0x07" 8 "Fan 2 under voltage 08实际为0x08" 9 "Fan 2 is stuck in rotation 09实际为0x09" 10 "Fan 2 overcurrent 10实际为0x0A" 11 "Fan 2 motor overheating 11实际为0x0B" 12 "Fan 2 drive overheating 12实际为0x0C" ;
VAL_ 2337795755 M2P_TMS_L_15_fre_fault_27 0 "no fault  00实际为0x00 引号外不能使用字母" 1 "Overcurrent 01实际为0x01" 2 "Operating overvoltage 02实际为0x02" 3 "Operating under voltage 03实际为0x03" 4 "AC input overvoltage 04实际为0x04" 5 "AC input under voltage 05实际为0x05" 6 "communication fault 06实际为0x06" 7 "Overcurrent frequency reduction 07实际为0x07" 8 "Over power frequency reduction 08实际为0x08" 9 "Input phase loss 09实际为0x09" 10 "External malfunction 10实际为0x0A" 11 "NTC overheating 11实际为0x0B" 12 "Power on to ground short circuit detection 12实际为0x0C" 13 "motor overload 13实际为0x0D" ;
VAL_ 2337795755 M2P_TMS_L_15_D_fault_27 0 "no fault 00实际为0x00 引号外不能使用字母" 1 "Overcurrent 01实际为0x01" 2 "Operating overvoltage 02实际为0x02" 3 "Operating under voltage 03实际为0x03" 4 "DC output overvoltage 04实际为0x04" 5 "DC output undervoltage 05实际为0x05" 6 "communication fault 06实际为0x06" 7 "Substrate overheating 07实际为0x07" 8 "output overload 08实际为0x08" ;
VAL_ 2337795756 M2P_TMS_L_TEM_28 0 "open" 1 "close" ;
VAL_ 2337795756 M2P_TMS_L_WPS_28 0 "open" 1 "close" ;
VAL_ 2337795756 M2P_TMS_L_15_fan_fault_28 0 "no fault 00实际为0x00 引号外不能使用字母" 1 "Fan 1 overvoltage 01实际为0x01" 2 "Fan 1 under voltage 02实际为0x02" 3 "Fan 1 is stuck in rotation 03实际为0x03" 4 "Fan 1 overcurrent 04实际为0x04" 5 "Fan 1 motor overheating 05实际为0x05" 6 "Fan 1 drive overheating 06实际为0x06" 7 "Fan 2 overvoltage 07实际为0x07" 8 "Fan 2 under voltage 08实际为0x08" 9 "Fan 2 is stuck in rotation 09实际为0x09" 10 "Fan 2 overcurrent 10实际为0x0A" 11 "Fan 2 motor overheating 11实际为0x0B" 12 "Fan 2 drive overheating 12实际为0x0C" ;
VAL_ 2337795756 M2P_TMS_L_15_fre_fault_28 0 "no fault  00实际为0x00 引号外不能使用字母" 1 "Overcurrent 01实际为0x01" 2 "Operating overvoltage 02实际为0x02" 3 "Operating under voltage 03实际为0x03" 4 "AC input overvoltage 04实际为0x04" 5 "AC input under voltage 05实际为0x05" 6 "communication fault 06实际为0x06" 7 "Overcurrent frequency reduction 07实际为0x07" 8 "Over power frequency reduction 08实际为0x08" 9 "Input phase loss 09实际为0x09" 10 "External malfunction 10实际为0x0A" 11 "NTC overheating 11实际为0x0B" 12 "Power on to ground short circuit detection 12实际为0x0C" 13 "motor overload 13实际为0x0D" ;
VAL_ 2337795756 M2P_TMS_L_15_D_fault_28 0 "no fault 00实际为0x00 引号外不能使用字母" 1 "Overcurrent 01实际为0x01" 2 "Operating overvoltage 02实际为0x02" 3 "Operating under voltage 03实际为0x03" 4 "DC output overvoltage 04实际为0x04" 5 "DC output undervoltage 05实际为0x05" 6 "communication fault 06实际为0x06" 7 "Substrate overheating 07实际为0x07" 8 "output overload 08实际为0x08" ;
VAL_ 2337795757 M2P_TMS_L_TEM_29 0 "open" 1 "close" ;
VAL_ 2337795757 M2P_TMS_L_WPS_29 0 "open" 1 "close" ;
VAL_ 2337795757 M2P_TMS_L_15_fan_fault_29 0 "no fault 00实际为0x00 引号外不能使用字母" 1 "Fan 1 overvoltage 01实际为0x01" 2 "Fan 1 under voltage 02实际为0x02" 3 "Fan 1 is stuck in rotation 03实际为0x03" 4 "Fan 1 overcurrent 04实际为0x04" 5 "Fan 1 motor overheating 05实际为0x05" 6 "Fan 1 drive overheating 06实际为0x06" 7 "Fan 2 overvoltage 07实际为0x07" 8 "Fan 2 under voltage 08实际为0x08" 9 "Fan 2 is stuck in rotation 09实际为0x09" 10 "Fan 2 overcurrent 10实际为0x0A" 11 "Fan 2 motor overheating 11实际为0x0B" 12 "Fan 2 drive overheating 12实际为0x0C" ;
VAL_ 2337795757 M2P_TMS_L_15_fre_fault_29 0 "no fault  00实际为0x00 引号外不能使用字母" 1 "Overcurrent 01实际为0x01" 2 "Operating overvoltage 02实际为0x02" 3 "Operating under voltage 03实际为0x03" 4 "AC input overvoltage 04实际为0x04" 5 "AC input under voltage 05实际为0x05" 6 "communication fault 06实际为0x06" 7 "Overcurrent frequency reduction 07实际为0x07" 8 "Over power frequency reduction 08实际为0x08" 9 "Input phase loss 09实际为0x09" 10 "External malfunction 10实际为0x0A" 11 "NTC overheating 11实际为0x0B" 12 "Power on to ground short circuit detection 12实际为0x0C" 13 "motor overload 13实际为0x0D" ;
VAL_ 2337795757 M2P_TMS_L_15_D_fault_29 0 "no fault 00实际为0x00 引号外不能使用字母" 1 "Overcurrent 01实际为0x01" 2 "Operating overvoltage 02实际为0x02" 3 "Operating under voltage 03实际为0x03" 4 "DC output overvoltage 04实际为0x04" 5 "DC output undervoltage 05实际为0x05" 6 "communication fault 06实际为0x06" 7 "Substrate overheating 07实际为0x07" 8 "output overload 08实际为0x08" ;
VAL_ 2337795758 M2P_TMS_L_TEM_30 0 "open" 1 "close" ;
VAL_ 2337795758 M2P_TMS_L_WPS_30 0 "open" 1 "close" ;
VAL_ 2337795758 M2P_TMS_L_15_fan_fault_30 0 "no fault 00实际为0x00 引号外不能使用字母" 1 "Fan 1 overvoltage 01实际为0x01" 2 "Fan 1 under voltage 02实际为0x02" 3 "Fan 1 is stuck in rotation 03实际为0x03" 4 "Fan 1 overcurrent 04实际为0x04" 5 "Fan 1 motor overheating 05实际为0x05" 6 "Fan 1 drive overheating 06实际为0x06" 7 "Fan 2 overvoltage 07实际为0x07" 8 "Fan 2 under voltage 08实际为0x08" 9 "Fan 2 is stuck in rotation 09实际为0x09" 10 "Fan 2 overcurrent 10实际为0x0A" 11 "Fan 2 motor overheating 11实际为0x0B" 12 "Fan 2 drive overheating 12实际为0x0C" ;
VAL_ 2337795758 M2P_TMS_L_15_fre_fault_30 0 "no fault  00实际为0x00 引号外不能使用字母" 1 "Overcurrent 01实际为0x01" 2 "Operating overvoltage 02实际为0x02" 3 "Operating under voltage 03实际为0x03" 4 "AC input overvoltage 04实际为0x04" 5 "AC input under voltage 05实际为0x05" 6 "communication fault 06实际为0x06" 7 "Overcurrent frequency reduction 07实际为0x07" 8 "Over power frequency reduction 08实际为0x08" 9 "Input phase loss 09实际为0x09" 10 "External malfunction 10实际为0x0A" 11 "NTC overheating 11实际为0x0B" 12 "Power on to ground short circuit detection 12实际为0x0C" 13 "motor overload 13实际为0x0D" ;
VAL_ 2337795758 M2P_TMS_L_15_D_fault_30 0 "no fault 00实际为0x00 引号外不能使用字母" 1 "Overcurrent 01实际为0x01" 2 "Operating overvoltage 02实际为0x02" 3 "Operating under voltage 03实际为0x03" 4 "DC output overvoltage 04实际为0x04" 5 "DC output undervoltage 05实际为0x05" 6 "communication fault 06实际为0x06" 7 "Substrate overheating 07实际为0x07" 8 "output overload 08实际为0x08" ;
VAL_ 2337795759 M2P_TMS_L_TEM_31 0 "open" 1 "close" ;
VAL_ 2337795759 M2P_TMS_L_WPS_31 0 "open" 1 "close" ;
VAL_ 2337795759 M2P_TMS_L_15_fan_fault_31 0 "no fault 00实际为0x00 引号外不能使用字母" 1 "Fan 1 overvoltage 01实际为0x01" 2 "Fan 1 under voltage 02实际为0x02" 3 "Fan 1 is stuck in rotation 03实际为0x03" 4 "Fan 1 overcurrent 04实际为0x04" 5 "Fan 1 motor overheating 05实际为0x05" 6 "Fan 1 drive overheating 06实际为0x06" 7 "Fan 2 overvoltage 07实际为0x07" 8 "Fan 2 under voltage 08实际为0x08" 9 "Fan 2 is stuck in rotation 09实际为0x09" 10 "Fan 2 overcurrent 10实际为0x0A" 11 "Fan 2 motor overheating 11实际为0x0B" 12 "Fan 2 drive overheating 12实际为0x0C" ;
VAL_ 2337795759 M2P_TMS_L_15_fre_fault_31 0 "no fault  00实际为0x00 引号外不能使用字母" 1 "Overcurrent 01实际为0x01" 2 "Operating overvoltage 02实际为0x02" 3 "Operating under voltage 03实际为0x03" 4 "AC input overvoltage 04实际为0x04" 5 "AC input under voltage 05实际为0x05" 6 "communication fault 06实际为0x06" 7 "Overcurrent frequency reduction 07实际为0x07" 8 "Over power frequency reduction 08实际为0x08" 9 "Input phase loss 09实际为0x09" 10 "External malfunction 10实际为0x0A" 11 "NTC overheating 11实际为0x0B" 12 "Power on to ground short circuit detection 12实际为0x0C" 13 "motor overload 13实际为0x0D" ;
VAL_ 2337795759 M2P_TMS_L_15_D_fault_31 0 "no fault 00实际为0x00 引号外不能使用字母" 1 "Overcurrent 01实际为0x01" 2 "Operating overvoltage 02实际为0x02" 3 "Operating under voltage 03实际为0x03" 4 "DC output overvoltage 04实际为0x04" 5 "DC output undervoltage 05实际为0x05" 6 "communication fault 06实际为0x06" 7 "Substrate overheating 07实际为0x07" 8 "output overload 08实际为0x08" ;
VAL_ 2337861265 M2P_TMS_L_25_fan_fault_01 0 "no fault 00实际为0x00 引号外不能使用字母" 1 "Fan 3 overvoltage 01实际为0x01" 2 "Fan 3 under voltage 02实际为0x02" 3 "Fan 3 is stuck in rotation 03实际为0x03" 4 "Fan 3 overcurrent 04实际为0x04" 5 "Fan 3 motor overheating 05实际为0x05" 6 "Fan 3 drive overheating 06实际为0x06" 7 "Fan 4 overvoltage 07实际为0x07" 8 "Fan 4 under voltage 08实际为0x08" 9 "Fan 4 is stuck in rotation 09实际为0x09" 10 "Fan 4 overcurrent 10实际为0x0A" 11 "Fan 4 motor overheating 11实际为0x0B" 12 "Fan 4 drive overheating 12实际为0x0C" 13 "Fan 5 overvoltage 13实际为0x0D" 14 "Fan 5 under voltage 14实际为0x0E" 15 "Fan 5 is stuck in rotation 15实际为0x0F" 16 "Fan 5 overcurrent 16实际为0x10" 17 "Fan 5 motor overheating 17实际为0x11" 18 "Fan 5 drive overheating 18实际为0x12" 19 "Fan 6 overvoltage 19实际为0x13" 20 "Fan 6 under voltage 20实际为0x14" 21 "Fan 6 is stuck in rotation 21实际为0x15" 22 "Fan 6 overcurrent 22实际为0x16" 23 "Fan 6 motor overheating 23实际为0x17" 24 "Fan 6 drive overheating 24实际为0x18" ;
VAL_ 2337861265 M2P_TMS_L_25_fre_fault_01 0 "no fault 00实际为0x00 引号外不能使用字母" 1 "Overcurrent 01实际为0x01" 2 "Operating overvoltage 02实际为0x02" 3 "Operating under voltage 03实际为0x03" 4 "AC input overvoltage 04实际为0x04" 5 "AC input under voltage 05实际为0x05" 6 "communication fault 06实际为0x06" 7 "Overcurrent frequency reduction 07实际为0x07" 8 "Over power frequency reduction 08实际为0x08" 9 "Input phase loss 09实际为0x09" 10 "External malfunction 10实际为0x0A" 11 "NTC overheating 11实际为0x0B" 12 "Power on to ground short circuit detection 12实际为0x0C" 13 "motor overload 13实际为0x0D" ;
VAL_ 2337861265 M2P_TMS_L_25_D_fault_01 0 "no fault 00实际为0x00 引号外不能使用字母" 1 "Overcurrent 01实际为0x01" 2 "Operating overvoltage 02实际为0x02" 3 "Operating under voltage 03实际为0x03" 4 "DC output overvoltage 04实际为0x04" 5 "DC output undervoltage 05实际为0x05" 6 "communication fault 06实际为0x06" 7 "Substrate overheating 07实际为0x07" 8 "output overload 08实际为0x08" ;
VAL_ 2337861266 M2P_TMS_L_25_fan_fault_02 0 "no fault 00实际为0x00 引号外不能使用字母" 1 "Fan 3 overvoltage 01实际为0x01" 2 "Fan 3 under voltage 02实际为0x02" 3 "Fan 3 is stuck in rotation 03实际为0x03" 4 "Fan 3 overcurrent 04实际为0x04" 5 "Fan 3 motor overheating 05实际为0x05" 6 "Fan 3 drive overheating 06实际为0x06" 7 "Fan 4 overvoltage 07实际为0x07" 8 "Fan 4 under voltage 08实际为0x08" 9 "Fan 4 is stuck in rotation 09实际为0x09" 10 "Fan 4 overcurrent 10实际为0x0A" 11 "Fan 4 motor overheating 11实际为0x0B" 12 "Fan 4 drive overheating 12实际为0x0C" 13 "Fan 5 overvoltage 13实际为0x0D" 14 "Fan 5 under voltage 14实际为0x0E" 15 "Fan 5 is stuck in rotation 15实际为0x0F" 16 "Fan 5 overcurrent 16实际为0x10" 17 "Fan 5 motor overheating 17实际为0x11" 18 "Fan 5 drive overheating 18实际为0x12" 19 "Fan 6 overvoltage 19实际为0x13" 20 "Fan 6 under voltage 20实际为0x14" 21 "Fan 6 is stuck in rotation 21实际为0x15" 22 "Fan 6 overcurrent 22实际为0x16" 23 "Fan 6 motor overheating 23实际为0x17" 24 "Fan 6 drive overheating 24实际为0x18" ;
VAL_ 2337861266 M2P_TMS_L_25_fre_fault_02 0 "no fault 00实际为0x00 引号外不能使用字母" 1 "Overcurrent 01实际为0x01" 2 "Operating overvoltage 02实际为0x02" 3 "Operating under voltage 03实际为0x03" 4 "AC input overvoltage 04实际为0x04" 5 "AC input under voltage 05实际为0x05" 6 "communication fault 06实际为0x06" 7 "Overcurrent frequency reduction 07实际为0x07" 8 "Over power frequency reduction 08实际为0x08" 9 "Input phase loss 09实际为0x09" 10 "External malfunction 10实际为0x0A" 11 "NTC overheating 11实际为0x0B" 12 "Power on to ground short circuit detection 12实际为0x0C" 13 "motor overload 13实际为0x0D" ;
VAL_ 2337861266 M2P_TMS_L_25_D_fault_02 0 "no fault 00实际为0x00 引号外不能使用字母" 1 "Overcurrent 01实际为0x01" 2 "Operating overvoltage 02实际为0x02" 3 "Operating under voltage 03实际为0x03" 4 "DC output overvoltage 04实际为0x04" 5 "DC output undervoltage 05实际为0x05" 6 "communication fault 06实际为0x06" 7 "Substrate overheating 07实际为0x07" 8 "output overload 08实际为0x08" ;
VAL_ 2337861267 M2P_TMS_L_25_fan_fault_03 0 "no fault 00实际为0x00 引号外不能使用字母" 1 "Fan 3 overvoltage 01实际为0x01" 2 "Fan 3 under voltage 02实际为0x02" 3 "Fan 3 is stuck in rotation 03实际为0x03" 4 "Fan 3 overcurrent 04实际为0x04" 5 "Fan 3 motor overheating 05实际为0x05" 6 "Fan 3 drive overheating 06实际为0x06" 7 "Fan 4 overvoltage 07实际为0x07" 8 "Fan 4 under voltage 08实际为0x08" 9 "Fan 4 is stuck in rotation 09实际为0x09" 10 "Fan 4 overcurrent 10实际为0x0A" 11 "Fan 4 motor overheating 11实际为0x0B" 12 "Fan 4 drive overheating 12实际为0x0C" 13 "Fan 5 overvoltage 13实际为0x0D" 14 "Fan 5 under voltage 14实际为0x0E" 15 "Fan 5 is stuck in rotation 15实际为0x0F" 16 "Fan 5 overcurrent 16实际为0x10" 17 "Fan 5 motor overheating 17实际为0x11" 18 "Fan 5 drive overheating 18实际为0x12" 19 "Fan 6 overvoltage 19实际为0x13" 20 "Fan 6 under voltage 20实际为0x14" 21 "Fan 6 is stuck in rotation 21实际为0x15" 22 "Fan 6 overcurrent 22实际为0x16" 23 "Fan 6 motor overheating 23实际为0x17" 24 "Fan 6 drive overheating 24实际为0x18" ;
VAL_ 2337861267 M2P_TMS_L_25_fre_fault_03 0 "no fault 00实际为0x00 引号外不能使用字母" 1 "Overcurrent 01实际为0x01" 2 "Operating overvoltage 02实际为0x02" 3 "Operating under voltage 03实际为0x03" 4 "AC input overvoltage 04实际为0x04" 5 "AC input under voltage 05实际为0x05" 6 "communication fault 06实际为0x06" 7 "Overcurrent frequency reduction 07实际为0x07" 8 "Over power frequency reduction 08实际为0x08" 9 "Input phase loss 09实际为0x09" 10 "External malfunction 10实际为0x0A" 11 "NTC overheating 11实际为0x0B" 12 "Power on to ground short circuit detection 12实际为0x0C" 13 "motor overload 13实际为0x0D" ;
VAL_ 2337861267 M2P_TMS_L_25_D_fault_03 0 "no fault 00实际为0x00 引号外不能使用字母" 1 "Overcurrent 01实际为0x01" 2 "Operating overvoltage 02实际为0x02" 3 "Operating under voltage 03实际为0x03" 4 "DC output overvoltage 04实际为0x04" 5 "DC output undervoltage 05实际为0x05" 6 "communication fault 06实际为0x06" 7 "Substrate overheating 07实际为0x07" 8 "output overload 08实际为0x08" ;
VAL_ 2337861268 M2P_TMS_L_25_fan_fault_04 0 "no fault 00实际为0x00 引号外不能使用字母" 1 "Fan 3 overvoltage 01实际为0x01" 2 "Fan 3 under voltage 02实际为0x02" 3 "Fan 3 is stuck in rotation 03实际为0x03" 4 "Fan 3 overcurrent 04实际为0x04" 5 "Fan 3 motor overheating 05实际为0x05" 6 "Fan 3 drive overheating 06实际为0x06" 7 "Fan 4 overvoltage 07实际为0x07" 8 "Fan 4 under voltage 08实际为0x08" 9 "Fan 4 is stuck in rotation 09实际为0x09" 10 "Fan 4 overcurrent 10实际为0x0A" 11 "Fan 4 motor overheating 11实际为0x0B" 12 "Fan 4 drive overheating 12实际为0x0C" 13 "Fan 5 overvoltage 13实际为0x0D" 14 "Fan 5 under voltage 14实际为0x0E" 15 "Fan 5 is stuck in rotation 15实际为0x0F" 16 "Fan 5 overcurrent 16实际为0x10" 17 "Fan 5 motor overheating 17实际为0x11" 18 "Fan 5 drive overheating 18实际为0x12" 19 "Fan 6 overvoltage 19实际为0x13" 20 "Fan 6 under voltage 20实际为0x14" 21 "Fan 6 is stuck in rotation 21实际为0x15" 22 "Fan 6 overcurrent 22实际为0x16" 23 "Fan 6 motor overheating 23实际为0x17" 24 "Fan 6 drive overheating 24实际为0x18" ;
VAL_ 2337861268 M2P_TMS_L_25_fre_fault_04 0 "no fault 00实际为0x00 引号外不能使用字母" 1 "Overcurrent 01实际为0x01" 2 "Operating overvoltage 02实际为0x02" 3 "Operating under voltage 03实际为0x03" 4 "AC input overvoltage 04实际为0x04" 5 "AC input under voltage 05实际为0x05" 6 "communication fault 06实际为0x06" 7 "Overcurrent frequency reduction 07实际为0x07" 8 "Over power frequency reduction 08实际为0x08" 9 "Input phase loss 09实际为0x09" 10 "External malfunction 10实际为0x0A" 11 "NTC overheating 11实际为0x0B" 12 "Power on to ground short circuit detection 12实际为0x0C" 13 "motor overload 13实际为0x0D" ;
VAL_ 2337861268 M2P_TMS_L_25_D_fault_04 0 "no fault 00实际为0x00 引号外不能使用字母" 1 "Overcurrent 01实际为0x01" 2 "Operating overvoltage 02实际为0x02" 3 "Operating under voltage 03实际为0x03" 4 "DC output overvoltage 04实际为0x04" 5 "DC output undervoltage 05实际为0x05" 6 "communication fault 06实际为0x06" 7 "Substrate overheating 07实际为0x07" 8 "output overload 08实际为0x08" ;
VAL_ 2337861269 M2P_TMS_L_25_fan_fault_05 0 "no fault 00实际为0x00 引号外不能使用字母" 1 "Fan 3 overvoltage 01实际为0x01" 2 "Fan 3 under voltage 02实际为0x02" 3 "Fan 3 is stuck in rotation 03实际为0x03" 4 "Fan 3 overcurrent 04实际为0x04" 5 "Fan 3 motor overheating 05实际为0x05" 6 "Fan 3 drive overheating 06实际为0x06" 7 "Fan 4 overvoltage 07实际为0x07" 8 "Fan 4 under voltage 08实际为0x08" 9 "Fan 4 is stuck in rotation 09实际为0x09" 10 "Fan 4 overcurrent 10实际为0x0A" 11 "Fan 4 motor overheating 11实际为0x0B" 12 "Fan 4 drive overheating 12实际为0x0C" 13 "Fan 5 overvoltage 13实际为0x0D" 14 "Fan 5 under voltage 14实际为0x0E" 15 "Fan 5 is stuck in rotation 15实际为0x0F" 16 "Fan 5 overcurrent 16实际为0x10" 17 "Fan 5 motor overheating 17实际为0x11" 18 "Fan 5 drive overheating 18实际为0x12" 19 "Fan 6 overvoltage 19实际为0x13" 20 "Fan 6 under voltage 20实际为0x14" 21 "Fan 6 is stuck in rotation 21实际为0x15" 22 "Fan 6 overcurrent 22实际为0x16" 23 "Fan 6 motor overheating 23实际为0x17" 24 "Fan 6 drive overheating 24实际为0x18" ;
VAL_ 2337861269 M2P_TMS_L_25_fre_fault_05 0 "no fault 00实际为0x00 引号外不能使用字母" 1 "Overcurrent 01实际为0x01" 2 "Operating overvoltage 02实际为0x02" 3 "Operating under voltage 03实际为0x03" 4 "AC input overvoltage 04实际为0x04" 5 "AC input under voltage 05实际为0x05" 6 "communication fault 06实际为0x06" 7 "Overcurrent frequency reduction 07实际为0x07" 8 "Over power frequency reduction 08实际为0x08" 9 "Input phase loss 09实际为0x09" 10 "External malfunction 10实际为0x0A" 11 "NTC overheating 11实际为0x0B" 12 "Power on to ground short circuit detection 12实际为0x0C" 13 "motor overload 13实际为0x0D" ;
VAL_ 2337861269 M2P_TMS_L_25_D_fault_05 0 "no fault 00实际为0x00 引号外不能使用字母" 1 "Overcurrent 01实际为0x01" 2 "Operating overvoltage 02实际为0x02" 3 "Operating under voltage 03实际为0x03" 4 "DC output overvoltage 04实际为0x04" 5 "DC output undervoltage 05实际为0x05" 6 "communication fault 06实际为0x06" 7 "Substrate overheating 07实际为0x07" 8 "output overload 08实际为0x08" ;
VAL_ 2337861270 M2P_TMS_L_25_fan_fault_06 0 "no fault 00实际为0x00 引号外不能使用字母" 1 "Fan 3 overvoltage 01实际为0x01" 2 "Fan 3 under voltage 02实际为0x02" 3 "Fan 3 is stuck in rotation 03实际为0x03" 4 "Fan 3 overcurrent 04实际为0x04" 5 "Fan 3 motor overheating 05实际为0x05" 6 "Fan 3 drive overheating 06实际为0x06" 7 "Fan 4 overvoltage 07实际为0x07" 8 "Fan 4 under voltage 08实际为0x08" 9 "Fan 4 is stuck in rotation 09实际为0x09" 10 "Fan 4 overcurrent 10实际为0x0A" 11 "Fan 4 motor overheating 11实际为0x0B" 12 "Fan 4 drive overheating 12实际为0x0C" 13 "Fan 5 overvoltage 13实际为0x0D" 14 "Fan 5 under voltage 14实际为0x0E" 15 "Fan 5 is stuck in rotation 15实际为0x0F" 16 "Fan 5 overcurrent 16实际为0x10" 17 "Fan 5 motor overheating 17实际为0x11" 18 "Fan 5 drive overheating 18实际为0x12" 19 "Fan 6 overvoltage 19实际为0x13" 20 "Fan 6 under voltage 20实际为0x14" 21 "Fan 6 is stuck in rotation 21实际为0x15" 22 "Fan 6 overcurrent 22实际为0x16" 23 "Fan 6 motor overheating 23实际为0x17" 24 "Fan 6 drive overheating 24实际为0x18" ;
VAL_ 2337861270 M2P_TMS_L_25_fre_fault_06 0 "no fault 00实际为0x00 引号外不能使用字母" 1 "Overcurrent 01实际为0x01" 2 "Operating overvoltage 02实际为0x02" 3 "Operating under voltage 03实际为0x03" 4 "AC input overvoltage 04实际为0x04" 5 "AC input under voltage 05实际为0x05" 6 "communication fault 06实际为0x06" 7 "Overcurrent frequency reduction 07实际为0x07" 8 "Over power frequency reduction 08实际为0x08" 9 "Input phase loss 09实际为0x09" 10 "External malfunction 10实际为0x0A" 11 "NTC overheating 11实际为0x0B" 12 "Power on to ground short circuit detection 12实际为0x0C" 13 "motor overload 13实际为0x0D" ;
VAL_ 2337861270 M2P_TMS_L_25_D_fault_06 0 "no fault 00实际为0x00 引号外不能使用字母" 1 "Overcurrent 01实际为0x01" 2 "Operating overvoltage 02实际为0x02" 3 "Operating under voltage 03实际为0x03" 4 "DC output overvoltage 04实际为0x04" 5 "DC output undervoltage 05实际为0x05" 6 "communication fault 06实际为0x06" 7 "Substrate overheating 07实际为0x07" 8 "output overload 08实际为0x08" ;
VAL_ 2337861271 M2P_TMS_L_25_fan_fault_07 0 "no fault 00实际为0x00 引号外不能使用字母" 1 "Fan 3 overvoltage 01实际为0x01" 2 "Fan 3 under voltage 02实际为0x02" 3 "Fan 3 is stuck in rotation 03实际为0x03" 4 "Fan 3 overcurrent 04实际为0x04" 5 "Fan 3 motor overheating 05实际为0x05" 6 "Fan 3 drive overheating 06实际为0x06" 7 "Fan 4 overvoltage 07实际为0x07" 8 "Fan 4 under voltage 08实际为0x08" 9 "Fan 4 is stuck in rotation 09实际为0x09" 10 "Fan 4 overcurrent 10实际为0x0A" 11 "Fan 4 motor overheating 11实际为0x0B" 12 "Fan 4 drive overheating 12实际为0x0C" 13 "Fan 5 overvoltage 13实际为0x0D" 14 "Fan 5 under voltage 14实际为0x0E" 15 "Fan 5 is stuck in rotation 15实际为0x0F" 16 "Fan 5 overcurrent 16实际为0x10" 17 "Fan 5 motor overheating 17实际为0x11" 18 "Fan 5 drive overheating 18实际为0x12" 19 "Fan 6 overvoltage 19实际为0x13" 20 "Fan 6 under voltage 20实际为0x14" 21 "Fan 6 is stuck in rotation 21实际为0x15" 22 "Fan 6 overcurrent 22实际为0x16" 23 "Fan 6 motor overheating 23实际为0x17" 24 "Fan 6 drive overheating 24实际为0x18" ;
VAL_ 2337861271 M2P_TMS_L_25_fre_fault_07 0 "no fault 00实际为0x00 引号外不能使用字母" 1 "Overcurrent 01实际为0x01" 2 "Operating overvoltage 02实际为0x02" 3 "Operating under voltage 03实际为0x03" 4 "AC input overvoltage 04实际为0x04" 5 "AC input under voltage 05实际为0x05" 6 "communication fault 06实际为0x06" 7 "Overcurrent frequency reduction 07实际为0x07" 8 "Over power frequency reduction 08实际为0x08" 9 "Input phase loss 09实际为0x09" 10 "External malfunction 10实际为0x0A" 11 "NTC overheating 11实际为0x0B" 12 "Power on to ground short circuit detection 12实际为0x0C" 13 "motor overload 13实际为0x0D" ;
VAL_ 2337861271 M2P_TMS_L_25_D_fault_07 0 "no fault 00实际为0x00 引号外不能使用字母" 1 "Overcurrent 01实际为0x01" 2 "Operating overvoltage 02实际为0x02" 3 "Operating under voltage 03实际为0x03" 4 "DC output overvoltage 04实际为0x04" 5 "DC output undervoltage 05实际为0x05" 6 "communication fault 06实际为0x06" 7 "Substrate overheating 07实际为0x07" 8 "output overload 08实际为0x08" ;
VAL_ 2337861272 M2P_TMS_L_25_fan_fault_08 0 "no fault 00实际为0x00 引号外不能使用字母" 1 "Fan 3 overvoltage 01实际为0x01" 2 "Fan 3 under voltage 02实际为0x02" 3 "Fan 3 is stuck in rotation 03实际为0x03" 4 "Fan 3 overcurrent 04实际为0x04" 5 "Fan 3 motor overheating 05实际为0x05" 6 "Fan 3 drive overheating 06实际为0x06" 7 "Fan 4 overvoltage 07实际为0x07" 8 "Fan 4 under voltage 08实际为0x08" 9 "Fan 4 is stuck in rotation 09实际为0x09" 10 "Fan 4 overcurrent 10实际为0x0A" 11 "Fan 4 motor overheating 11实际为0x0B" 12 "Fan 4 drive overheating 12实际为0x0C" 13 "Fan 5 overvoltage 13实际为0x0D" 14 "Fan 5 under voltage 14实际为0x0E" 15 "Fan 5 is stuck in rotation 15实际为0x0F" 16 "Fan 5 overcurrent 16实际为0x10" 17 "Fan 5 motor overheating 17实际为0x11" 18 "Fan 5 drive overheating 18实际为0x12" 19 "Fan 6 overvoltage 19实际为0x13" 20 "Fan 6 under voltage 20实际为0x14" 21 "Fan 6 is stuck in rotation 21实际为0x15" 22 "Fan 6 overcurrent 22实际为0x16" 23 "Fan 6 motor overheating 23实际为0x17" 24 "Fan 6 drive overheating 24实际为0x18" ;
VAL_ 2337861272 M2P_TMS_L_25_fre_fault_08 0 "no fault 00实际为0x00 引号外不能使用字母" 1 "Overcurrent 01实际为0x01" 2 "Operating overvoltage 02实际为0x02" 3 "Operating under voltage 03实际为0x03" 4 "AC input overvoltage 04实际为0x04" 5 "AC input under voltage 05实际为0x05" 6 "communication fault 06实际为0x06" 7 "Overcurrent frequency reduction 07实际为0x07" 8 "Over power frequency reduction 08实际为0x08" 9 "Input phase loss 09实际为0x09" 10 "External malfunction 10实际为0x0A" 11 "NTC overheating 11实际为0x0B" 12 "Power on to ground short circuit detection 12实际为0x0C" 13 "motor overload 13实际为0x0D" ;
VAL_ 2337861272 M2P_TMS_L_25_D_fault_08 0 "no fault 00实际为0x00 引号外不能使用字母" 1 "Overcurrent 01实际为0x01" 2 "Operating overvoltage 02实际为0x02" 3 "Operating under voltage 03实际为0x03" 4 "DC output overvoltage 04实际为0x04" 5 "DC output undervoltage 05实际为0x05" 6 "communication fault 06实际为0x06" 7 "Substrate overheating 07实际为0x07" 8 "output overload 08实际为0x08" ;
VAL_ 2337861273 M2P_TMS_L_25_fan_fault_09 0 "no fault 00实际为0x00 引号外不能使用字母" 1 "Fan 3 overvoltage 01实际为0x01" 2 "Fan 3 under voltage 02实际为0x02" 3 "Fan 3 is stuck in rotation 03实际为0x03" 4 "Fan 3 overcurrent 04实际为0x04" 5 "Fan 3 motor overheating 05实际为0x05" 6 "Fan 3 drive overheating 06实际为0x06" 7 "Fan 4 overvoltage 07实际为0x07" 8 "Fan 4 under voltage 08实际为0x08" 9 "Fan 4 is stuck in rotation 09实际为0x09" 10 "Fan 4 overcurrent 10实际为0x0A" 11 "Fan 4 motor overheating 11实际为0x0B" 12 "Fan 4 drive overheating 12实际为0x0C" 13 "Fan 5 overvoltage 13实际为0x0D" 14 "Fan 5 under voltage 14实际为0x0E" 15 "Fan 5 is stuck in rotation 15实际为0x0F" 16 "Fan 5 overcurrent 16实际为0x10" 17 "Fan 5 motor overheating 17实际为0x11" 18 "Fan 5 drive overheating 18实际为0x12" 19 "Fan 6 overvoltage 19实际为0x13" 20 "Fan 6 under voltage 20实际为0x14" 21 "Fan 6 is stuck in rotation 21实际为0x15" 22 "Fan 6 overcurrent 22实际为0x16" 23 "Fan 6 motor overheating 23实际为0x17" 24 "Fan 6 drive overheating 24实际为0x18" ;
VAL_ 2337861273 M2P_TMS_L_25_fre_fault_09 0 "no fault 00实际为0x00 引号外不能使用字母" 1 "Overcurrent 01实际为0x01" 2 "Operating overvoltage 02实际为0x02" 3 "Operating under voltage 03实际为0x03" 4 "AC input overvoltage 04实际为0x04" 5 "AC input under voltage 05实际为0x05" 6 "communication fault 06实际为0x06" 7 "Overcurrent frequency reduction 07实际为0x07" 8 "Over power frequency reduction 08实际为0x08" 9 "Input phase loss 09实际为0x09" 10 "External malfunction 10实际为0x0A" 11 "NTC overheating 11实际为0x0B" 12 "Power on to ground short circuit detection 12实际为0x0C" 13 "motor overload 13实际为0x0D" ;
VAL_ 2337861273 M2P_TMS_L_25_D_fault_09 0 "no fault 00实际为0x00 引号外不能使用字母" 1 "Overcurrent 01实际为0x01" 2 "Operating overvoltage 02实际为0x02" 3 "Operating under voltage 03实际为0x03" 4 "DC output overvoltage 04实际为0x04" 5 "DC output undervoltage 05实际为0x05" 6 "communication fault 06实际为0x06" 7 "Substrate overheating 07实际为0x07" 8 "output overload 08实际为0x08" ;
VAL_ 2337861274 M2P_TMS_L_25_fan_fault_10 0 "no fault 00实际为0x00 引号外不能使用字母" 1 "Fan 3 overvoltage 01实际为0x01" 2 "Fan 3 under voltage 02实际为0x02" 3 "Fan 3 is stuck in rotation 03实际为0x03" 4 "Fan 3 overcurrent 04实际为0x04" 5 "Fan 3 motor overheating 05实际为0x05" 6 "Fan 3 drive overheating 06实际为0x06" 7 "Fan 4 overvoltage 07实际为0x07" 8 "Fan 4 under voltage 08实际为0x08" 9 "Fan 4 is stuck in rotation 09实际为0x09" 10 "Fan 4 overcurrent 10实际为0x0A" 11 "Fan 4 motor overheating 11实际为0x0B" 12 "Fan 4 drive overheating 12实际为0x0C" 13 "Fan 5 overvoltage 13实际为0x0D" 14 "Fan 5 under voltage 14实际为0x0E" 15 "Fan 5 is stuck in rotation 15实际为0x0F" 16 "Fan 5 overcurrent 16实际为0x10" 17 "Fan 5 motor overheating 17实际为0x11" 18 "Fan 5 drive overheating 18实际为0x12" 19 "Fan 6 overvoltage 19实际为0x13" 20 "Fan 6 under voltage 20实际为0x14" 21 "Fan 6 is stuck in rotation 21实际为0x15" 22 "Fan 6 overcurrent 22实际为0x16" 23 "Fan 6 motor overheating 23实际为0x17" 24 "Fan 6 drive overheating 24实际为0x18" ;
VAL_ 2337861274 M2P_TMS_L_25_fre_fault_10 0 "no fault 00实际为0x00 引号外不能使用字母" 1 "Overcurrent 01实际为0x01" 2 "Operating overvoltage 02实际为0x02" 3 "Operating under voltage 03实际为0x03" 4 "AC input overvoltage 04实际为0x04" 5 "AC input under voltage 05实际为0x05" 6 "communication fault 06实际为0x06" 7 "Overcurrent frequency reduction 07实际为0x07" 8 "Over power frequency reduction 08实际为0x08" 9 "Input phase loss 09实际为0x09" 10 "External malfunction 10实际为0x0A" 11 "NTC overheating 11实际为0x0B" 12 "Power on to ground short circuit detection 12实际为0x0C" 13 "motor overload 13实际为0x0D" ;
VAL_ 2337861274 M2P_TMS_L_25_D_fault_10 0 "no fault 00实际为0x00 引号外不能使用字母" 1 "Overcurrent 01实际为0x01" 2 "Operating overvoltage 02实际为0x02" 3 "Operating under voltage 03实际为0x03" 4 "DC output overvoltage 04实际为0x04" 5 "DC output undervoltage 05实际为0x05" 6 "communication fault 06实际为0x06" 7 "Substrate overheating 07实际为0x07" 8 "output overload 08实际为0x08" ;
VAL_ 2337861275 M2P_TMS_L_25_fan_fault_11 0 "no fault 00实际为0x00 引号外不能使用字母" 1 "Fan 3 overvoltage 01实际为0x01" 2 "Fan 3 under voltage 02实际为0x02" 3 "Fan 3 is stuck in rotation 03实际为0x03" 4 "Fan 3 overcurrent 04实际为0x04" 5 "Fan 3 motor overheating 05实际为0x05" 6 "Fan 3 drive overheating 06实际为0x06" 7 "Fan 4 overvoltage 07实际为0x07" 8 "Fan 4 under voltage 08实际为0x08" 9 "Fan 4 is stuck in rotation 09实际为0x09" 10 "Fan 4 overcurrent 10实际为0x0A" 11 "Fan 4 motor overheating 11实际为0x0B" 12 "Fan 4 drive overheating 12实际为0x0C" 13 "Fan 5 overvoltage 13实际为0x0D" 14 "Fan 5 under voltage 14实际为0x0E" 15 "Fan 5 is stuck in rotation 15实际为0x0F" 16 "Fan 5 overcurrent 16实际为0x10" 17 "Fan 5 motor overheating 17实际为0x11" 18 "Fan 5 drive overheating 18实际为0x12" 19 "Fan 6 overvoltage 19实际为0x13" 20 "Fan 6 under voltage 20实际为0x14" 21 "Fan 6 is stuck in rotation 21实际为0x15" 22 "Fan 6 overcurrent 22实际为0x16" 23 "Fan 6 motor overheating 23实际为0x17" 24 "Fan 6 drive overheating 24实际为0x18" ;
VAL_ 2337861275 M2P_TMS_L_25_fre_fault_11 0 "no fault 00实际为0x00 引号外不能使用字母" 1 "Overcurrent 01实际为0x01" 2 "Operating overvoltage 02实际为0x02" 3 "Operating under voltage 03实际为0x03" 4 "AC input overvoltage 04实际为0x04" 5 "AC input under voltage 05实际为0x05" 6 "communication fault 06实际为0x06" 7 "Overcurrent frequency reduction 07实际为0x07" 8 "Over power frequency reduction 08实际为0x08" 9 "Input phase loss 09实际为0x09" 10 "External malfunction 10实际为0x0A" 11 "NTC overheating 11实际为0x0B" 12 "Power on to ground short circuit detection 12实际为0x0C" 13 "motor overload 13实际为0x0D" ;
VAL_ 2337861275 M2P_TMS_L_25_D_fault_11 0 "no fault 00实际为0x00 引号外不能使用字母" 1 "Overcurrent 01实际为0x01" 2 "Operating overvoltage 02实际为0x02" 3 "Operating under voltage 03实际为0x03" 4 "DC output overvoltage 04实际为0x04" 5 "DC output undervoltage 05实际为0x05" 6 "communication fault 06实际为0x06" 7 "Substrate overheating 07实际为0x07" 8 "output overload 08实际为0x08" ;
VAL_ 2337861276 M2P_TMS_L_25_fan_fault_12 0 "no fault 00实际为0x00 引号外不能使用字母" 1 "Fan 3 overvoltage 01实际为0x01" 2 "Fan 3 under voltage 02实际为0x02" 3 "Fan 3 is stuck in rotation 03实际为0x03" 4 "Fan 3 overcurrent 04实际为0x04" 5 "Fan 3 motor overheating 05实际为0x05" 6 "Fan 3 drive overheating 06实际为0x06" 7 "Fan 4 overvoltage 07实际为0x07" 8 "Fan 4 under voltage 08实际为0x08" 9 "Fan 4 is stuck in rotation 09实际为0x09" 10 "Fan 4 overcurrent 10实际为0x0A" 11 "Fan 4 motor overheating 11实际为0x0B" 12 "Fan 4 drive overheating 12实际为0x0C" 13 "Fan 5 overvoltage 13实际为0x0D" 14 "Fan 5 under voltage 14实际为0x0E" 15 "Fan 5 is stuck in rotation 15实际为0x0F" 16 "Fan 5 overcurrent 16实际为0x10" 17 "Fan 5 motor overheating 17实际为0x11" 18 "Fan 5 drive overheating 18实际为0x12" 19 "Fan 6 overvoltage 19实际为0x13" 20 "Fan 6 under voltage 20实际为0x14" 21 "Fan 6 is stuck in rotation 21实际为0x15" 22 "Fan 6 overcurrent 22实际为0x16" 23 "Fan 6 motor overheating 23实际为0x17" 24 "Fan 6 drive overheating 24实际为0x18" ;
VAL_ 2337861276 M2P_TMS_L_25_fre_fault_12 0 "no fault 00实际为0x00 引号外不能使用字母" 1 "Overcurrent 01实际为0x01" 2 "Operating overvoltage 02实际为0x02" 3 "Operating under voltage 03实际为0x03" 4 "AC input overvoltage 04实际为0x04" 5 "AC input under voltage 05实际为0x05" 6 "communication fault 06实际为0x06" 7 "Overcurrent frequency reduction 07实际为0x07" 8 "Over power frequency reduction 08实际为0x08" 9 "Input phase loss 09实际为0x09" 10 "External malfunction 10实际为0x0A" 11 "NTC overheating 11实际为0x0B" 12 "Power on to ground short circuit detection 12实际为0x0C" 13 "motor overload 13实际为0x0D" ;
VAL_ 2337861276 M2P_TMS_L_25_D_fault_12 0 "no fault 00实际为0x00 引号外不能使用字母" 1 "Overcurrent 01实际为0x01" 2 "Operating overvoltage 02实际为0x02" 3 "Operating under voltage 03实际为0x03" 4 "DC output overvoltage 04实际为0x04" 5 "DC output undervoltage 05实际为0x05" 6 "communication fault 06实际为0x06" 7 "Substrate overheating 07实际为0x07" 8 "output overload 08实际为0x08" ;
VAL_ 2337861277 M2P_TMS_L_25_fan_fault_13 0 "no fault 00实际为0x00 引号外不能使用字母" 1 "Fan 3 overvoltage 01实际为0x01" 2 "Fan 3 under voltage 02实际为0x02" 3 "Fan 3 is stuck in rotation 03实际为0x03" 4 "Fan 3 overcurrent 04实际为0x04" 5 "Fan 3 motor overheating 05实际为0x05" 6 "Fan 3 drive overheating 06实际为0x06" 7 "Fan 4 overvoltage 07实际为0x07" 8 "Fan 4 under voltage 08实际为0x08" 9 "Fan 4 is stuck in rotation 09实际为0x09" 10 "Fan 4 overcurrent 10实际为0x0A" 11 "Fan 4 motor overheating 11实际为0x0B" 12 "Fan 4 drive overheating 12实际为0x0C" 13 "Fan 5 overvoltage 13实际为0x0D" 14 "Fan 5 under voltage 14实际为0x0E" 15 "Fan 5 is stuck in rotation 15实际为0x0F" 16 "Fan 5 overcurrent 16实际为0x10" 17 "Fan 5 motor overheating 17实际为0x11" 18 "Fan 5 drive overheating 18实际为0x12" 19 "Fan 6 overvoltage 19实际为0x13" 20 "Fan 6 under voltage 20实际为0x14" 21 "Fan 6 is stuck in rotation 21实际为0x15" 22 "Fan 6 overcurrent 22实际为0x16" 23 "Fan 6 motor overheating 23实际为0x17" 24 "Fan 6 drive overheating 24实际为0x18" ;
VAL_ 2337861277 M2P_TMS_L_25_fre_fault_13 0 "no fault 00实际为0x00 引号外不能使用字母" 1 "Overcurrent 01实际为0x01" 2 "Operating overvoltage 02实际为0x02" 3 "Operating under voltage 03实际为0x03" 4 "AC input overvoltage 04实际为0x04" 5 "AC input under voltage 05实际为0x05" 6 "communication fault 06实际为0x06" 7 "Overcurrent frequency reduction 07实际为0x07" 8 "Over power frequency reduction 08实际为0x08" 9 "Input phase loss 09实际为0x09" 10 "External malfunction 10实际为0x0A" 11 "NTC overheating 11实际为0x0B" 12 "Power on to ground short circuit detection 12实际为0x0C" 13 "motor overload 13实际为0x0D" ;
VAL_ 2337861277 M2P_TMS_L_25_D_fault_13 0 "no fault 00实际为0x00 引号外不能使用字母" 1 "Overcurrent 01实际为0x01" 2 "Operating overvoltage 02实际为0x02" 3 "Operating under voltage 03实际为0x03" 4 "DC output overvoltage 04实际为0x04" 5 "DC output undervoltage 05实际为0x05" 6 "communication fault 06实际为0x06" 7 "Substrate overheating 07实际为0x07" 8 "output overload 08实际为0x08" ;
VAL_ 2337861278 M2P_TMS_L_25_fan_fault_14 0 "no fault 00实际为0x00 引号外不能使用字母" 1 "Fan 3 overvoltage 01实际为0x01" 2 "Fan 3 under voltage 02实际为0x02" 3 "Fan 3 is stuck in rotation 03实际为0x03" 4 "Fan 3 overcurrent 04实际为0x04" 5 "Fan 3 motor overheating 05实际为0x05" 6 "Fan 3 drive overheating 06实际为0x06" 7 "Fan 4 overvoltage 07实际为0x07" 8 "Fan 4 under voltage 08实际为0x08" 9 "Fan 4 is stuck in rotation 09实际为0x09" 10 "Fan 4 overcurrent 10实际为0x0A" 11 "Fan 4 motor overheating 11实际为0x0B" 12 "Fan 4 drive overheating 12实际为0x0C" 13 "Fan 5 overvoltage 13实际为0x0D" 14 "Fan 5 under voltage 14实际为0x0E" 15 "Fan 5 is stuck in rotation 15实际为0x0F" 16 "Fan 5 overcurrent 16实际为0x10" 17 "Fan 5 motor overheating 17实际为0x11" 18 "Fan 5 drive overheating 18实际为0x12" 19 "Fan 6 overvoltage 19实际为0x13" 20 "Fan 6 under voltage 20实际为0x14" 21 "Fan 6 is stuck in rotation 21实际为0x15" 22 "Fan 6 overcurrent 22实际为0x16" 23 "Fan 6 motor overheating 23实际为0x17" 24 "Fan 6 drive overheating 24实际为0x18" ;
VAL_ 2337861278 M2P_TMS_L_25_fre_fault_14 0 "no fault 00实际为0x00 引号外不能使用字母" 1 "Overcurrent 01实际为0x01" 2 "Operating overvoltage 02实际为0x02" 3 "Operating under voltage 03实际为0x03" 4 "AC input overvoltage 04实际为0x04" 5 "AC input under voltage 05实际为0x05" 6 "communication fault 06实际为0x06" 7 "Overcurrent frequency reduction 07实际为0x07" 8 "Over power frequency reduction 08实际为0x08" 9 "Input phase loss 09实际为0x09" 10 "External malfunction 10实际为0x0A" 11 "NTC overheating 11实际为0x0B" 12 "Power on to ground short circuit detection 12实际为0x0C" 13 "motor overload 13实际为0x0D" ;
VAL_ 2337861278 M2P_TMS_L_25_D_fault_14 0 "no fault 00实际为0x00 引号外不能使用字母" 1 "Overcurrent 01实际为0x01" 2 "Operating overvoltage 02实际为0x02" 3 "Operating under voltage 03实际为0x03" 4 "DC output overvoltage 04实际为0x04" 5 "DC output undervoltage 05实际为0x05" 6 "communication fault 06实际为0x06" 7 "Substrate overheating 07实际为0x07" 8 "output overload 08实际为0x08" ;
VAL_ 2337861279 M2P_TMS_L_25_fan_fault_15 0 "no fault 00实际为0x00 引号外不能使用字母" 1 "Fan 3 overvoltage 01实际为0x01" 2 "Fan 3 under voltage 02实际为0x02" 3 "Fan 3 is stuck in rotation 03实际为0x03" 4 "Fan 3 overcurrent 04实际为0x04" 5 "Fan 3 motor overheating 05实际为0x05" 6 "Fan 3 drive overheating 06实际为0x06" 7 "Fan 4 overvoltage 07实际为0x07" 8 "Fan 4 under voltage 08实际为0x08" 9 "Fan 4 is stuck in rotation 09实际为0x09" 10 "Fan 4 overcurrent 10实际为0x0A" 11 "Fan 4 motor overheating 11实际为0x0B" 12 "Fan 4 drive overheating 12实际为0x0C" 13 "Fan 5 overvoltage 13实际为0x0D" 14 "Fan 5 under voltage 14实际为0x0E" 15 "Fan 5 is stuck in rotation 15实际为0x0F" 16 "Fan 5 overcurrent 16实际为0x10" 17 "Fan 5 motor overheating 17实际为0x11" 18 "Fan 5 drive overheating 18实际为0x12" 19 "Fan 6 overvoltage 19实际为0x13" 20 "Fan 6 under voltage 20实际为0x14" 21 "Fan 6 is stuck in rotation 21实际为0x15" 22 "Fan 6 overcurrent 22实际为0x16" 23 "Fan 6 motor overheating 23实际为0x17" 24 "Fan 6 drive overheating 24实际为0x18" ;
VAL_ 2337861279 M2P_TMS_L_25_fre_fault_15 0 "no fault 00实际为0x00 引号外不能使用字母" 1 "Overcurrent 01实际为0x01" 2 "Operating overvoltage 02实际为0x02" 3 "Operating under voltage 03实际为0x03" 4 "AC input overvoltage 04实际为0x04" 5 "AC input under voltage 05实际为0x05" 6 "communication fault 06实际为0x06" 7 "Overcurrent frequency reduction 07实际为0x07" 8 "Over power frequency reduction 08实际为0x08" 9 "Input phase loss 09实际为0x09" 10 "External malfunction 10实际为0x0A" 11 "NTC overheating 11实际为0x0B" 12 "Power on to ground short circuit detection 12实际为0x0C" 13 "motor overload 13实际为0x0D" ;
VAL_ 2337861279 M2P_TMS_L_25_D_fault_15 0 "no fault 00实际为0x00 引号外不能使用字母" 1 "Overcurrent 01实际为0x01" 2 "Operating overvoltage 02实际为0x02" 3 "Operating under voltage 03实际为0x03" 4 "DC output overvoltage 04实际为0x04" 5 "DC output undervoltage 05实际为0x05" 6 "communication fault 06实际为0x06" 7 "Substrate overheating 07实际为0x07" 8 "output overload 08实际为0x08" ;
VAL_ 2337861280 M2P_TMS_L_25_fan_fault_16 0 "no fault 00实际为0x00 引号外不能使用字母" 1 "Fan 3 overvoltage 01实际为0x01" 2 "Fan 3 under voltage 02实际为0x02" 3 "Fan 3 is stuck in rotation 03实际为0x03" 4 "Fan 3 overcurrent 04实际为0x04" 5 "Fan 3 motor overheating 05实际为0x05" 6 "Fan 3 drive overheating 06实际为0x06" 7 "Fan 4 overvoltage 07实际为0x07" 8 "Fan 4 under voltage 08实际为0x08" 9 "Fan 4 is stuck in rotation 09实际为0x09" 10 "Fan 4 overcurrent 10实际为0x0A" 11 "Fan 4 motor overheating 11实际为0x0B" 12 "Fan 4 drive overheating 12实际为0x0C" 13 "Fan 5 overvoltage 13实际为0x0D" 14 "Fan 5 under voltage 14实际为0x0E" 15 "Fan 5 is stuck in rotation 15实际为0x0F" 16 "Fan 5 overcurrent 16实际为0x10" 17 "Fan 5 motor overheating 17实际为0x11" 18 "Fan 5 drive overheating 18实际为0x12" 19 "Fan 6 overvoltage 19实际为0x13" 20 "Fan 6 under voltage 20实际为0x14" 21 "Fan 6 is stuck in rotation 21实际为0x15" 22 "Fan 6 overcurrent 22实际为0x16" 23 "Fan 6 motor overheating 23实际为0x17" 24 "Fan 6 drive overheating 24实际为0x18" ;
VAL_ 2337861280 M2P_TMS_L_25_fre_fault_16 0 "no fault 00实际为0x00 引号外不能使用字母" 1 "Overcurrent 01实际为0x01" 2 "Operating overvoltage 02实际为0x02" 3 "Operating under voltage 03实际为0x03" 4 "AC input overvoltage 04实际为0x04" 5 "AC input under voltage 05实际为0x05" 6 "communication fault 06实际为0x06" 7 "Overcurrent frequency reduction 07实际为0x07" 8 "Over power frequency reduction 08实际为0x08" 9 "Input phase loss 09实际为0x09" 10 "External malfunction 10实际为0x0A" 11 "NTC overheating 11实际为0x0B" 12 "Power on to ground short circuit detection 12实际为0x0C" 13 "motor overload 13实际为0x0D" ;
VAL_ 2337861280 M2P_TMS_L_25_D_fault_16 0 "no fault 00实际为0x00 引号外不能使用字母" 1 "Overcurrent 01实际为0x01" 2 "Operating overvoltage 02实际为0x02" 3 "Operating under voltage 03实际为0x03" 4 "DC output overvoltage 04实际为0x04" 5 "DC output undervoltage 05实际为0x05" 6 "communication fault 06实际为0x06" 7 "Substrate overheating 07实际为0x07" 8 "output overload 08实际为0x08" ;
VAL_ 2337861281 M2P_TMS_L_25_fan_fault_17 0 "no fault 00实际为0x00 引号外不能使用字母" 1 "Fan 3 overvoltage 01实际为0x01" 2 "Fan 3 under voltage 02实际为0x02" 3 "Fan 3 is stuck in rotation 03实际为0x03" 4 "Fan 3 overcurrent 04实际为0x04" 5 "Fan 3 motor overheating 05实际为0x05" 6 "Fan 3 drive overheating 06实际为0x06" 7 "Fan 4 overvoltage 07实际为0x07" 8 "Fan 4 under voltage 08实际为0x08" 9 "Fan 4 is stuck in rotation 09实际为0x09" 10 "Fan 4 overcurrent 10实际为0x0A" 11 "Fan 4 motor overheating 11实际为0x0B" 12 "Fan 4 drive overheating 12实际为0x0C" 13 "Fan 5 overvoltage 13实际为0x0D" 14 "Fan 5 under voltage 14实际为0x0E" 15 "Fan 5 is stuck in rotation 15实际为0x0F" 16 "Fan 5 overcurrent 16实际为0x10" 17 "Fan 5 motor overheating 17实际为0x11" 18 "Fan 5 drive overheating 18实际为0x12" 19 "Fan 6 overvoltage 19实际为0x13" 20 "Fan 6 under voltage 20实际为0x14" 21 "Fan 6 is stuck in rotation 21实际为0x15" 22 "Fan 6 overcurrent 22实际为0x16" 23 "Fan 6 motor overheating 23实际为0x17" 24 "Fan 6 drive overheating 24实际为0x18" ;
VAL_ 2337861281 M2P_TMS_L_25_fre_fault_17 0 "no fault 00实际为0x00 引号外不能使用字母" 1 "Overcurrent 01实际为0x01" 2 "Operating overvoltage 02实际为0x02" 3 "Operating under voltage 03实际为0x03" 4 "AC input overvoltage 04实际为0x04" 5 "AC input under voltage 05实际为0x05" 6 "communication fault 06实际为0x06" 7 "Overcurrent frequency reduction 07实际为0x07" 8 "Over power frequency reduction 08实际为0x08" 9 "Input phase loss 09实际为0x09" 10 "External malfunction 10实际为0x0A" 11 "NTC overheating 11实际为0x0B" 12 "Power on to ground short circuit detection 12实际为0x0C" 13 "motor overload 13实际为0x0D" ;
VAL_ 2337861281 M2P_TMS_L_25_D_fault_17 0 "no fault 00实际为0x00 引号外不能使用字母" 1 "Overcurrent 01实际为0x01" 2 "Operating overvoltage 02实际为0x02" 3 "Operating under voltage 03实际为0x03" 4 "DC output overvoltage 04实际为0x04" 5 "DC output undervoltage 05实际为0x05" 6 "communication fault 06实际为0x06" 7 "Substrate overheating 07实际为0x07" 8 "output overload 08实际为0x08" ;
VAL_ 2337861282 M2P_TMS_L_25_fan_fault_18 0 "no fault 00实际为0x00 引号外不能使用字母" 1 "Fan 3 overvoltage 01实际为0x01" 2 "Fan 3 under voltage 02实际为0x02" 3 "Fan 3 is stuck in rotation 03实际为0x03" 4 "Fan 3 overcurrent 04实际为0x04" 5 "Fan 3 motor overheating 05实际为0x05" 6 "Fan 3 drive overheating 06实际为0x06" 7 "Fan 4 overvoltage 07实际为0x07" 8 "Fan 4 under voltage 08实际为0x08" 9 "Fan 4 is stuck in rotation 09实际为0x09" 10 "Fan 4 overcurrent 10实际为0x0A" 11 "Fan 4 motor overheating 11实际为0x0B" 12 "Fan 4 drive overheating 12实际为0x0C" 13 "Fan 5 overvoltage 13实际为0x0D" 14 "Fan 5 under voltage 14实际为0x0E" 15 "Fan 5 is stuck in rotation 15实际为0x0F" 16 "Fan 5 overcurrent 16实际为0x10" 17 "Fan 5 motor overheating 17实际为0x11" 18 "Fan 5 drive overheating 18实际为0x12" 19 "Fan 6 overvoltage 19实际为0x13" 20 "Fan 6 under voltage 20实际为0x14" 21 "Fan 6 is stuck in rotation 21实际为0x15" 22 "Fan 6 overcurrent 22实际为0x16" 23 "Fan 6 motor overheating 23实际为0x17" 24 "Fan 6 drive overheating 24实际为0x18" ;
VAL_ 2337861282 M2P_TMS_L_25_fre_fault_18 0 "no fault 00实际为0x00 引号外不能使用字母" 1 "Overcurrent 01实际为0x01" 2 "Operating overvoltage 02实际为0x02" 3 "Operating under voltage 03实际为0x03" 4 "AC input overvoltage 04实际为0x04" 5 "AC input under voltage 05实际为0x05" 6 "communication fault 06实际为0x06" 7 "Overcurrent frequency reduction 07实际为0x07" 8 "Over power frequency reduction 08实际为0x08" 9 "Input phase loss 09实际为0x09" 10 "External malfunction 10实际为0x0A" 11 "NTC overheating 11实际为0x0B" 12 "Power on to ground short circuit detection 12实际为0x0C" 13 "motor overload 13实际为0x0D" ;
VAL_ 2337861282 M2P_TMS_L_25_D_fault_18 0 "no fault 00实际为0x00 引号外不能使用字母" 1 "Overcurrent 01实际为0x01" 2 "Operating overvoltage 02实际为0x02" 3 "Operating under voltage 03实际为0x03" 4 "DC output overvoltage 04实际为0x04" 5 "DC output undervoltage 05实际为0x05" 6 "communication fault 06实际为0x06" 7 "Substrate overheating 07实际为0x07" 8 "output overload 08实际为0x08" ;
VAL_ 2337861283 M2P_TMS_L_25_fan_fault_19 0 "no fault 00实际为0x00 引号外不能使用字母" 1 "Fan 3 overvoltage 01实际为0x01" 2 "Fan 3 under voltage 02实际为0x02" 3 "Fan 3 is stuck in rotation 03实际为0x03" 4 "Fan 3 overcurrent 04实际为0x04" 5 "Fan 3 motor overheating 05实际为0x05" 6 "Fan 3 drive overheating 06实际为0x06" 7 "Fan 4 overvoltage 07实际为0x07" 8 "Fan 4 under voltage 08实际为0x08" 9 "Fan 4 is stuck in rotation 09实际为0x09" 10 "Fan 4 overcurrent 10实际为0x0A" 11 "Fan 4 motor overheating 11实际为0x0B" 12 "Fan 4 drive overheating 12实际为0x0C" 13 "Fan 5 overvoltage 13实际为0x0D" 14 "Fan 5 under voltage 14实际为0x0E" 15 "Fan 5 is stuck in rotation 15实际为0x0F" 16 "Fan 5 overcurrent 16实际为0x10" 17 "Fan 5 motor overheating 17实际为0x11" 18 "Fan 5 drive overheating 18实际为0x12" 19 "Fan 6 overvoltage 19实际为0x13" 20 "Fan 6 under voltage 20实际为0x14" 21 "Fan 6 is stuck in rotation 21实际为0x15" 22 "Fan 6 overcurrent 22实际为0x16" 23 "Fan 6 motor overheating 23实际为0x17" 24 "Fan 6 drive overheating 24实际为0x18" ;
VAL_ 2337861283 M2P_TMS_L_25_fre_fault_19 0 "no fault 00实际为0x00 引号外不能使用字母" 1 "Overcurrent 01实际为0x01" 2 "Operating overvoltage 02实际为0x02" 3 "Operating under voltage 03实际为0x03" 4 "AC input overvoltage 04实际为0x04" 5 "AC input under voltage 05实际为0x05" 6 "communication fault 06实际为0x06" 7 "Overcurrent frequency reduction 07实际为0x07" 8 "Over power frequency reduction 08实际为0x08" 9 "Input phase loss 09实际为0x09" 10 "External malfunction 10实际为0x0A" 11 "NTC overheating 11实际为0x0B" 12 "Power on to ground short circuit detection 12实际为0x0C" 13 "motor overload 13实际为0x0D" ;
VAL_ 2337861283 M2P_TMS_L_25_D_fault_19 0 "no fault 00实际为0x00 引号外不能使用字母" 1 "Overcurrent 01实际为0x01" 2 "Operating overvoltage 02实际为0x02" 3 "Operating under voltage 03实际为0x03" 4 "DC output overvoltage 04实际为0x04" 5 "DC output undervoltage 05实际为0x05" 6 "communication fault 06实际为0x06" 7 "Substrate overheating 07实际为0x07" 8 "output overload 08实际为0x08" ;
VAL_ 2337861284 M2P_TMS_L_25_fan_fault_20 0 "no fault 00实际为0x00 引号外不能使用字母" 1 "Fan 3 overvoltage 01实际为0x01" 2 "Fan 3 under voltage 02实际为0x02" 3 "Fan 3 is stuck in rotation 03实际为0x03" 4 "Fan 3 overcurrent 04实际为0x04" 5 "Fan 3 motor overheating 05实际为0x05" 6 "Fan 3 drive overheating 06实际为0x06" 7 "Fan 4 overvoltage 07实际为0x07" 8 "Fan 4 under voltage 08实际为0x08" 9 "Fan 4 is stuck in rotation 09实际为0x09" 10 "Fan 4 overcurrent 10实际为0x0A" 11 "Fan 4 motor overheating 11实际为0x0B" 12 "Fan 4 drive overheating 12实际为0x0C" 13 "Fan 5 overvoltage 13实际为0x0D" 14 "Fan 5 under voltage 14实际为0x0E" 15 "Fan 5 is stuck in rotation 15实际为0x0F" 16 "Fan 5 overcurrent 16实际为0x10" 17 "Fan 5 motor overheating 17实际为0x11" 18 "Fan 5 drive overheating 18实际为0x12" 19 "Fan 6 overvoltage 19实际为0x13" 20 "Fan 6 under voltage 20实际为0x14" 21 "Fan 6 is stuck in rotation 21实际为0x15" 22 "Fan 6 overcurrent 22实际为0x16" 23 "Fan 6 motor overheating 23实际为0x17" 24 "Fan 6 drive overheating 24实际为0x18" ;
VAL_ 2337861284 M2P_TMS_L_25_fre_fault_20 0 "no fault 00实际为0x00 引号外不能使用字母" 1 "Overcurrent 01实际为0x01" 2 "Operating overvoltage 02实际为0x02" 3 "Operating under voltage 03实际为0x03" 4 "AC input overvoltage 04实际为0x04" 5 "AC input under voltage 05实际为0x05" 6 "communication fault 06实际为0x06" 7 "Overcurrent frequency reduction 07实际为0x07" 8 "Over power frequency reduction 08实际为0x08" 9 "Input phase loss 09实际为0x09" 10 "External malfunction 10实际为0x0A" 11 "NTC overheating 11实际为0x0B" 12 "Power on to ground short circuit detection 12实际为0x0C" 13 "motor overload 13实际为0x0D" ;
VAL_ 2337861284 M2P_TMS_L_25_D_fault_20 0 "no fault 00实际为0x00 引号外不能使用字母" 1 "Overcurrent 01实际为0x01" 2 "Operating overvoltage 02实际为0x02" 3 "Operating under voltage 03实际为0x03" 4 "DC output overvoltage 04实际为0x04" 5 "DC output undervoltage 05实际为0x05" 6 "communication fault 06实际为0x06" 7 "Substrate overheating 07实际为0x07" 8 "output overload 08实际为0x08" ;
VAL_ 2337861285 M2P_TMS_L_25_fan_fault_21 0 "no fault 00实际为0x00 引号外不能使用字母" 1 "Fan 3 overvoltage 01实际为0x01" 2 "Fan 3 under voltage 02实际为0x02" 3 "Fan 3 is stuck in rotation 03实际为0x03" 4 "Fan 3 overcurrent 04实际为0x04" 5 "Fan 3 motor overheating 05实际为0x05" 6 "Fan 3 drive overheating 06实际为0x06" 7 "Fan 4 overvoltage 07实际为0x07" 8 "Fan 4 under voltage 08实际为0x08" 9 "Fan 4 is stuck in rotation 09实际为0x09" 10 "Fan 4 overcurrent 10实际为0x0A" 11 "Fan 4 motor overheating 11实际为0x0B" 12 "Fan 4 drive overheating 12实际为0x0C" 13 "Fan 5 overvoltage 13实际为0x0D" 14 "Fan 5 under voltage 14实际为0x0E" 15 "Fan 5 is stuck in rotation 15实际为0x0F" 16 "Fan 5 overcurrent 16实际为0x10" 17 "Fan 5 motor overheating 17实际为0x11" 18 "Fan 5 drive overheating 18实际为0x12" 19 "Fan 6 overvoltage 19实际为0x13" 20 "Fan 6 under voltage 20实际为0x14" 21 "Fan 6 is stuck in rotation 21实际为0x15" 22 "Fan 6 overcurrent 22实际为0x16" 23 "Fan 6 motor overheating 23实际为0x17" 24 "Fan 6 drive overheating 24实际为0x18" ;
VAL_ 2337861285 M2P_TMS_L_25_fre_fault_21 0 "no fault 00实际为0x00 引号外不能使用字母" 1 "Overcurrent 01实际为0x01" 2 "Operating overvoltage 02实际为0x02" 3 "Operating under voltage 03实际为0x03" 4 "AC input overvoltage 04实际为0x04" 5 "AC input under voltage 05实际为0x05" 6 "communication fault 06实际为0x06" 7 "Overcurrent frequency reduction 07实际为0x07" 8 "Over power frequency reduction 08实际为0x08" 9 "Input phase loss 09实际为0x09" 10 "External malfunction 10实际为0x0A" 11 "NTC overheating 11实际为0x0B" 12 "Power on to ground short circuit detection 12实际为0x0C" 13 "motor overload 13实际为0x0D" ;
VAL_ 2337861285 M2P_TMS_L_25_D_fault_21 0 "no fault 00实际为0x00 引号外不能使用字母" 1 "Overcurrent 01实际为0x01" 2 "Operating overvoltage 02实际为0x02" 3 "Operating under voltage 03实际为0x03" 4 "DC output overvoltage 04实际为0x04" 5 "DC output undervoltage 05实际为0x05" 6 "communication fault 06实际为0x06" 7 "Substrate overheating 07实际为0x07" 8 "output overload 08实际为0x08" ;
VAL_ 2337861286 M2P_TMS_L_25_fan_fault_22 0 "no fault 00实际为0x00 引号外不能使用字母" 1 "Fan 3 overvoltage 01实际为0x01" 2 "Fan 3 under voltage 02实际为0x02" 3 "Fan 3 is stuck in rotation 03实际为0x03" 4 "Fan 3 overcurrent 04实际为0x04" 5 "Fan 3 motor overheating 05实际为0x05" 6 "Fan 3 drive overheating 06实际为0x06" 7 "Fan 4 overvoltage 07实际为0x07" 8 "Fan 4 under voltage 08实际为0x08" 9 "Fan 4 is stuck in rotation 09实际为0x09" 10 "Fan 4 overcurrent 10实际为0x0A" 11 "Fan 4 motor overheating 11实际为0x0B" 12 "Fan 4 drive overheating 12实际为0x0C" 13 "Fan 5 overvoltage 13实际为0x0D" 14 "Fan 5 under voltage 14实际为0x0E" 15 "Fan 5 is stuck in rotation 15实际为0x0F" 16 "Fan 5 overcurrent 16实际为0x10" 17 "Fan 5 motor overheating 17实际为0x11" 18 "Fan 5 drive overheating 18实际为0x12" 19 "Fan 6 overvoltage 19实际为0x13" 20 "Fan 6 under voltage 20实际为0x14" 21 "Fan 6 is stuck in rotation 21实际为0x15" 22 "Fan 6 overcurrent 22实际为0x16" 23 "Fan 6 motor overheating 23实际为0x17" 24 "Fan 6 drive overheating 24实际为0x18" ;
VAL_ 2337861286 M2P_TMS_L_25_fre_fault_22 0 "no fault 00实际为0x00 引号外不能使用字母" 1 "Overcurrent 01实际为0x01" 2 "Operating overvoltage 02实际为0x02" 3 "Operating under voltage 03实际为0x03" 4 "AC input overvoltage 04实际为0x04" 5 "AC input under voltage 05实际为0x05" 6 "communication fault 06实际为0x06" 7 "Overcurrent frequency reduction 07实际为0x07" 8 "Over power frequency reduction 08实际为0x08" 9 "Input phase loss 09实际为0x09" 10 "External malfunction 10实际为0x0A" 11 "NTC overheating 11实际为0x0B" 12 "Power on to ground short circuit detection 12实际为0x0C" 13 "motor overload 13实际为0x0D" ;
VAL_ 2337861286 M2P_TMS_L_25_D_fault_22 0 "no fault 00实际为0x00 引号外不能使用字母" 1 "Overcurrent 01实际为0x01" 2 "Operating overvoltage 02实际为0x02" 3 "Operating under voltage 03实际为0x03" 4 "DC output overvoltage 04实际为0x04" 5 "DC output undervoltage 05实际为0x05" 6 "communication fault 06实际为0x06" 7 "Substrate overheating 07实际为0x07" 8 "output overload 08实际为0x08" ;
VAL_ 2337861287 M2P_TMS_L_25_fan_fault_23 0 "no fault 00实际为0x00 引号外不能使用字母" 1 "Fan 3 overvoltage 01实际为0x01" 2 "Fan 3 under voltage 02实际为0x02" 3 "Fan 3 is stuck in rotation 03实际为0x03" 4 "Fan 3 overcurrent 04实际为0x04" 5 "Fan 3 motor overheating 05实际为0x05" 6 "Fan 3 drive overheating 06实际为0x06" 7 "Fan 4 overvoltage 07实际为0x07" 8 "Fan 4 under voltage 08实际为0x08" 9 "Fan 4 is stuck in rotation 09实际为0x09" 10 "Fan 4 overcurrent 10实际为0x0A" 11 "Fan 4 motor overheating 11实际为0x0B" 12 "Fan 4 drive overheating 12实际为0x0C" 13 "Fan 5 overvoltage 13实际为0x0D" 14 "Fan 5 under voltage 14实际为0x0E" 15 "Fan 5 is stuck in rotation 15实际为0x0F" 16 "Fan 5 overcurrent 16实际为0x10" 17 "Fan 5 motor overheating 17实际为0x11" 18 "Fan 5 drive overheating 18实际为0x12" 19 "Fan 6 overvoltage 19实际为0x13" 20 "Fan 6 under voltage 20实际为0x14" 21 "Fan 6 is stuck in rotation 21实际为0x15" 22 "Fan 6 overcurrent 22实际为0x16" 23 "Fan 6 motor overheating 23实际为0x17" 24 "Fan 6 drive overheating 24实际为0x18" ;
VAL_ 2337861287 M2P_TMS_L_25_fre_fault_23 0 "no fault 00实际为0x00 引号外不能使用字母" 1 "Overcurrent 01实际为0x01" 2 "Operating overvoltage 02实际为0x02" 3 "Operating under voltage 03实际为0x03" 4 "AC input overvoltage 04实际为0x04" 5 "AC input under voltage 05实际为0x05" 6 "communication fault 06实际为0x06" 7 "Overcurrent frequency reduction 07实际为0x07" 8 "Over power frequency reduction 08实际为0x08" 9 "Input phase loss 09实际为0x09" 10 "External malfunction 10实际为0x0A" 11 "NTC overheating 11实际为0x0B" 12 "Power on to ground short circuit detection 12实际为0x0C" 13 "motor overload 13实际为0x0D" ;
VAL_ 2337861287 M2P_TMS_L_25_D_fault_23 0 "no fault 00实际为0x00 引号外不能使用字母" 1 "Overcurrent 01实际为0x01" 2 "Operating overvoltage 02实际为0x02" 3 "Operating under voltage 03实际为0x03" 4 "DC output overvoltage 04实际为0x04" 5 "DC output undervoltage 05实际为0x05" 6 "communication fault 06实际为0x06" 7 "Substrate overheating 07实际为0x07" 8 "output overload 08实际为0x08" ;
VAL_ 2337861288 M2P_TMS_L_25_fan_fault_24 0 "no fault 00实际为0x00 引号外不能使用字母" 1 "Fan 3 overvoltage 01实际为0x01" 2 "Fan 3 under voltage 02实际为0x02" 3 "Fan 3 is stuck in rotation 03实际为0x03" 4 "Fan 3 overcurrent 04实际为0x04" 5 "Fan 3 motor overheating 05实际为0x05" 6 "Fan 3 drive overheating 06实际为0x06" 7 "Fan 4 overvoltage 07实际为0x07" 8 "Fan 4 under voltage 08实际为0x08" 9 "Fan 4 is stuck in rotation 09实际为0x09" 10 "Fan 4 overcurrent 10实际为0x0A" 11 "Fan 4 motor overheating 11实际为0x0B" 12 "Fan 4 drive overheating 12实际为0x0C" 13 "Fan 5 overvoltage 13实际为0x0D" 14 "Fan 5 under voltage 14实际为0x0E" 15 "Fan 5 is stuck in rotation 15实际为0x0F" 16 "Fan 5 overcurrent 16实际为0x10" 17 "Fan 5 motor overheating 17实际为0x11" 18 "Fan 5 drive overheating 18实际为0x12" 19 "Fan 6 overvoltage 19实际为0x13" 20 "Fan 6 under voltage 20实际为0x14" 21 "Fan 6 is stuck in rotation 21实际为0x15" 22 "Fan 6 overcurrent 22实际为0x16" 23 "Fan 6 motor overheating 23实际为0x17" 24 "Fan 6 drive overheating 24实际为0x18" ;
VAL_ 2337861288 M2P_TMS_L_25_fre_fault_24 0 "no fault 00实际为0x00 引号外不能使用字母" 1 "Overcurrent 01实际为0x01" 2 "Operating overvoltage 02实际为0x02" 3 "Operating under voltage 03实际为0x03" 4 "AC input overvoltage 04实际为0x04" 5 "AC input under voltage 05实际为0x05" 6 "communication fault 06实际为0x06" 7 "Overcurrent frequency reduction 07实际为0x07" 8 "Over power frequency reduction 08实际为0x08" 9 "Input phase loss 09实际为0x09" 10 "External malfunction 10实际为0x0A" 11 "NTC overheating 11实际为0x0B" 12 "Power on to ground short circuit detection 12实际为0x0C" 13 "motor overload 13实际为0x0D" ;
VAL_ 2337861288 M2P_TMS_L_25_D_fault_24 0 "no fault 00实际为0x00 引号外不能使用字母" 1 "Overcurrent 01实际为0x01" 2 "Operating overvoltage 02实际为0x02" 3 "Operating under voltage 03实际为0x03" 4 "DC output overvoltage 04实际为0x04" 5 "DC output undervoltage 05实际为0x05" 6 "communication fault 06实际为0x06" 7 "Substrate overheating 07实际为0x07" 8 "output overload 08实际为0x08" ;
VAL_ 2337861289 M2P_TMS_L_25_fan_fault_25 0 "no fault 00实际为0x00 引号外不能使用字母" 1 "Fan 3 overvoltage 01实际为0x01" 2 "Fan 3 under voltage 02实际为0x02" 3 "Fan 3 is stuck in rotation 03实际为0x03" 4 "Fan 3 overcurrent 04实际为0x04" 5 "Fan 3 motor overheating 05实际为0x05" 6 "Fan 3 drive overheating 06实际为0x06" 7 "Fan 4 overvoltage 07实际为0x07" 8 "Fan 4 under voltage 08实际为0x08" 9 "Fan 4 is stuck in rotation 09实际为0x09" 10 "Fan 4 overcurrent 10实际为0x0A" 11 "Fan 4 motor overheating 11实际为0x0B" 12 "Fan 4 drive overheating 12实际为0x0C" 13 "Fan 5 overvoltage 13实际为0x0D" 14 "Fan 5 under voltage 14实际为0x0E" 15 "Fan 5 is stuck in rotation 15实际为0x0F" 16 "Fan 5 overcurrent 16实际为0x10" 17 "Fan 5 motor overheating 17实际为0x11" 18 "Fan 5 drive overheating 18实际为0x12" 19 "Fan 6 overvoltage 19实际为0x13" 20 "Fan 6 under voltage 20实际为0x14" 21 "Fan 6 is stuck in rotation 21实际为0x15" 22 "Fan 6 overcurrent 22实际为0x16" 23 "Fan 6 motor overheating 23实际为0x17" 24 "Fan 6 drive overheating 24实际为0x18" ;
VAL_ 2337861289 M2P_TMS_L_25_fre_fault_25 0 "no fault 00实际为0x00 引号外不能使用字母" 1 "Overcurrent 01实际为0x01" 2 "Operating overvoltage 02实际为0x02" 3 "Operating under voltage 03实际为0x03" 4 "AC input overvoltage 04实际为0x04" 5 "AC input under voltage 05实际为0x05" 6 "communication fault 06实际为0x06" 7 "Overcurrent frequency reduction 07实际为0x07" 8 "Over power frequency reduction 08实际为0x08" 9 "Input phase loss 09实际为0x09" 10 "External malfunction 10实际为0x0A" 11 "NTC overheating 11实际为0x0B" 12 "Power on to ground short circuit detection 12实际为0x0C" 13 "motor overload 13实际为0x0D" ;
VAL_ 2337861289 M2P_TMS_L_25_D_fault_25 0 "no fault 00实际为0x00 引号外不能使用字母" 1 "Overcurrent 01实际为0x01" 2 "Operating overvoltage 02实际为0x02" 3 "Operating under voltage 03实际为0x03" 4 "DC output overvoltage 04实际为0x04" 5 "DC output undervoltage 05实际为0x05" 6 "communication fault 06实际为0x06" 7 "Substrate overheating 07实际为0x07" 8 "output overload 08实际为0x08" ;
VERSION ""

NS_ :

BS_:

BU_: MBMU PC SBMU IMM ETH DCDC LEMS

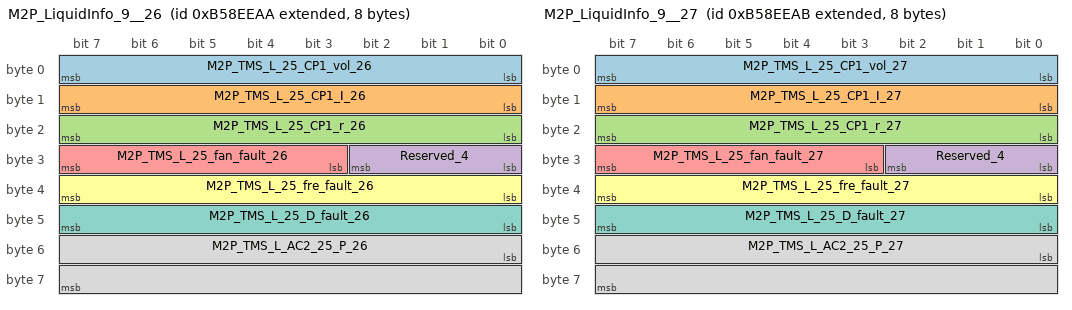
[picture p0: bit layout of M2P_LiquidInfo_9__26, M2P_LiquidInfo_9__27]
BO_ 2337861290 M2P_LiquidInfo_9__26: 8 MBMU
 SG_ M2P_TMS_L_25_CP1_vol_26 : 0|8@1+ (2,0) [0|510] "V"  PC
 SG_ M2P_TMS_L_25_CP1_I_26 : 8|8@1+ (1,0) [0|255] "A"  PC
 SG_ M2P_TMS_L_25_CP1_r_26 : 16|8@1+ (100,0) [0|25500] "rpm"  PC
 SG_ Reserved_4 : 24|3@1+ (1,0) [0|7] ""  PC
 SG_ M2P_TMS_L_25_fan_fault_26 : 27|5@1+ (1,0) [0|31] ""  PC
 SG_ M2P_TMS_L_25_fre_fault_26 : 32|8@1+ (1,0) [0|255] ""  PC
 SG_ M2P_TMS_L_25_D_fault_26 : 40|8@1+ (1,0) [0|255] ""  PC
 SG_ M2P_TMS_L_AC2_25_P_26 : 48|16@1+ (1,0) [0|65535] ""  PC

BO_ 2337861291 M2P_LiquidInfo_9__27: 8 MBMU
 SG_ M2P_TMS_L_25_CP1_vol_27 : 0|8@1+ (2,0) [0|510] "V"  PC
 SG_ M2P_TMS_L_25_CP1_I_27 : 8|8@1+ (1,0) [0|255] "A"  PC
 SG_ M2P_TMS_L_25_CP1_r_27 : 16|8@1+ (100,0) [0|25500] "rpm"  PC
 SG_ Reserved_4 : 24|3@1+ (1,0) [0|7] ""  PC
 SG_ M2P_TMS_L_25_fan_fault_27 : 27|5@1+ (1,0) [0|31] ""  PC
 SG_ M2P_TMS_L_25_fre_fault_27 : 32|8@1+ (1,0) [0|255] ""  PC
 SG_ M2P_TMS_L_25_D_fault_27 : 40|8@1+ (1,0) [0|255] ""  PC
 SG_ M2P_TMS_L_AC2_25_P_27 : 48|16@1+ (1,0) [0|65535] ""  PC

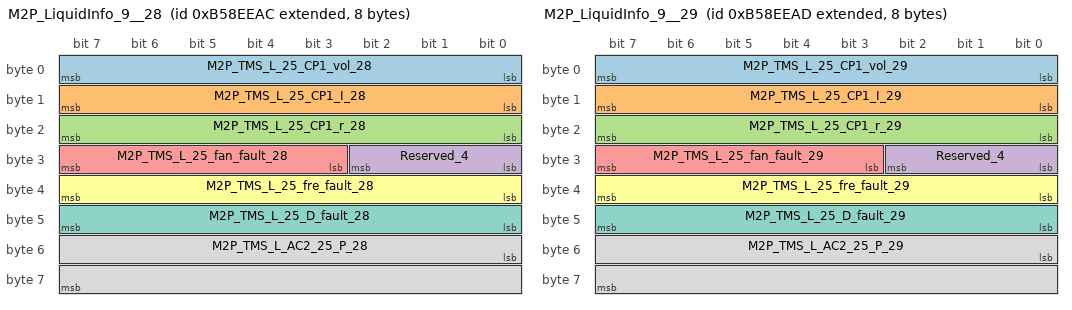
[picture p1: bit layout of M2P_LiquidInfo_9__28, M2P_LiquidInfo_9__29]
BO_ 2337861292 M2P_LiquidInfo_9__28: 8 MBMU
 SG_ M2P_TMS_L_25_CP1_vol_28 : 0|8@1+ (2,0) [0|510] "V"  PC
 SG_ M2P_TMS_L_25_CP1_I_28 : 8|8@1+ (1,0) [0|255] "A"  PC
 SG_ M2P_TMS_L_25_CP1_r_28 : 16|8@1+ (100,0) [0|25500] "rpm"  PC
 SG_ Reserved_4 : 24|3@1+ (1,0) [0|7] ""  PC
 SG_ M2P_TMS_L_25_fan_fault_28 : 27|5@1+ (1,0) [0|31] ""  PC
 SG_ M2P_TMS_L_25_fre_fault_28 : 32|8@1+ (1,0) [0|255] ""  PC
 SG_ M2P_TMS_L_25_D_fault_28 : 40|8@1+ (1,0) [0|255] ""  PC
 SG_ M2P_TMS_L_AC2_25_P_28 : 48|16@1+ (1,0) [0|65535] ""  PC

BO_ 2337861293 M2P_LiquidInfo_9__29: 8 MBMU
 SG_ M2P_TMS_L_25_CP1_vol_29 : 0|8@1+ (2,0) [0|510] "V"  PC
 SG_ M2P_TMS_L_25_CP1_I_29 : 8|8@1+ (1,0) [0|255] "A"  PC
 SG_ M2P_TMS_L_25_CP1_r_29 : 16|8@1+ (100,0) [0|25500] "rpm"  PC
 SG_ Reserved_4 : 24|3@1+ (1,0) [0|7] ""  PC
 SG_ M2P_TMS_L_25_fan_fault_29 : 27|5@1+ (1,0) [0|31] ""  PC
 SG_ M2P_TMS_L_25_fre_fault_29 : 32|8@1+ (1,0) [0|255] ""  PC
 SG_ M2P_TMS_L_25_D_fault_29 : 40|8@1+ (1,0) [0|255] ""  PC
 SG_ M2P_TMS_L_AC2_25_P_29 : 48|16@1+ (1,0) [0|65535] ""  PC

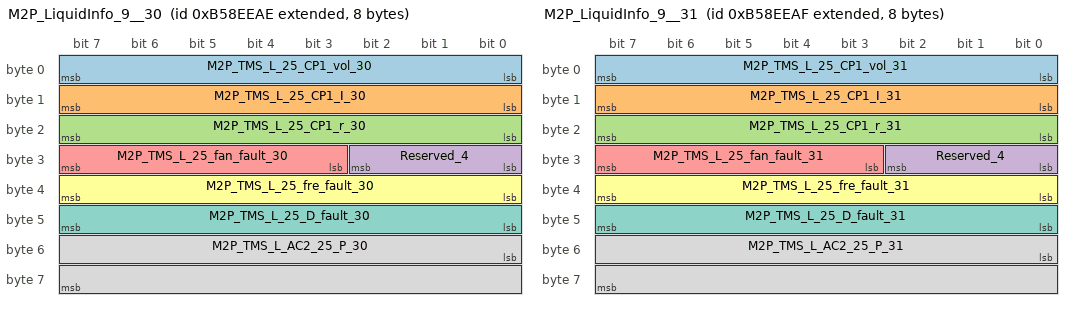
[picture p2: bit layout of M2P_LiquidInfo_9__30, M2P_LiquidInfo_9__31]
BO_ 2337861294 M2P_LiquidInfo_9__30: 8 MBMU
 SG_ M2P_TMS_L_25_CP1_vol_30 : 0|8@1+ (2,0) [0|510] "V"  PC
 SG_ M2P_TMS_L_25_CP1_I_30 : 8|8@1+ (1,0) [0|255] "A"  PC
 SG_ M2P_TMS_L_25_CP1_r_30 : 16|8@1+ (100,0) [0|25500] "rpm"  PC
 SG_ Reserved_4 : 24|3@1+ (1,0) [0|7] ""  PC
 SG_ M2P_TMS_L_25_fan_fault_30 : 27|5@1+ (1,0) [0|31] ""  PC
 SG_ M2P_TMS_L_25_fre_fault_30 : 32|8@1+ (1,0) [0|255] ""  PC
 SG_ M2P_TMS_L_25_D_fault_30 : 40|8@1+ (1,0) [0|255] ""  PC
 SG_ M2P_TMS_L_AC2_25_P_30 : 48|16@1+ (1,0) [0|65535] ""  PC

BO_ 2337861295 M2P_LiquidInfo_9__31: 8 MBMU
 SG_ M2P_TMS_L_25_CP1_vol_31 : 0|8@1+ (2,0) [0|510] "V"  PC
 SG_ M2P_TMS_L_25_CP1_I_31 : 8|8@1+ (1,0) [0|255] "A"  PC
 SG_ M2P_TMS_L_25_CP1_r_31 : 16|8@1+ (100,0) [0|25500] "rpm"  PC
 SG_ Reserved_4 : 24|3@1+ (1,0) [0|7] ""  PC
 SG_ M2P_TMS_L_25_fan_fault_31 : 27|5@1+ (1,0) [0|31] ""  PC
 SG_ M2P_TMS_L_25_fre_fault_31 : 32|8@1+ (1,0) [0|255] ""  PC
 SG_ M2P_TMS_L_25_D_fault_31 : 40|8@1+ (1,0) [0|255] ""  PC
 SG_ M2P_TMS_L_AC2_25_P_31 : 48|16@1+ (1,0) [0|65535] ""  PC

BO_ 2337926801 M2P_LiquidInfo_10__01: 8 MBMU
 SG_ M2P_TMS_L_S_version_01 : 0|40@1+ (1,0) [0|1099511627775] ""  PC
 SG_ M2P_TMS_L_N_S_version_01 : 40|24@1+ (1,0) [0|16777215] ""  PC

BO_ 2337926802 M2P_LiquidInfo_10__02: 8 MBMU
 SG_ M2P_TMS_L_S_version_02 : 0|40@1+ (1,0) [0|1099511627775] ""  PC
 SG_ M2P_TMS_L_N_S_version_02 : 40|24@1+ (1,0) [0|16777215] ""  PC

BO_ 2337926803 M2P_LiquidInfo_10__03: 8 MBMU
 SG_ M2P_TMS_L_S_version_03 : 0|40@1+ (1,0) [0|1099511627775] ""  PC
 SG_ M2P_TMS_L_N_S_version_03 : 40|24@1+ (1,0) [0|16777215] ""  PC

BO_ 2337926804 M2P_LiquidInfo_10__04: 8 MBMU
 SG_ M2P_TMS_L_S_version_04 : 0|40@1+ (1,0) [0|1099511627775] ""  PC
 SG_ M2P_TMS_L_N_S_version_04 : 40|24@1+ (1,0) [0|16777215] ""  PC

BO_ 2337926805 M2P_LiquidInfo_10__05: 8 MBMU
 SG_ M2P_TMS_L_S_version_05 : 0|40@1+ (1,0) [0|1099511627775] ""  PC
 SG_ M2P_TMS_L_N_S_version_05 : 40|24@1+ (1,0) [0|16777215] ""  PC

BO_ 2337926806 M2P_LiquidInfo_10__06: 8 MBMU
 SG_ M2P_TMS_L_S_version_06 : 0|40@1+ (1,0) [0|1099511627775] ""  PC
 SG_ M2P_TMS_L_N_S_version_06 : 40|24@1+ (1,0) [0|16777215] ""  PC

BO_ 2337926807 M2P_LiquidInfo_10__07: 8 MBMU
 SG_ M2P_TMS_L_S_version_07 : 0|40@1+ (1,0) [0|1099511627775] ""  PC
 SG_ M2P_TMS_L_N_S_version_07 : 40|24@1+ (1,0) [0|16777215] ""  PC

BO_ 2337926808 M2P_LiquidInfo_10__08: 8 MBMU
 SG_ M2P_TMS_L_S_version_08 : 0|40@1+ (1,0) [0|1099511627775] ""  PC
 SG_ M2P_TMS_L_N_S_version_08 : 40|24@1+ (1,0) [0|16777215] ""  PC

BO_ 2337926809 M2P_LiquidInfo_10__09: 8 MBMU
 SG_ M2P_TMS_L_S_version_09 : 0|40@1+ (1,0) [0|1099511627775] ""  PC
 SG_ M2P_TMS_L_N_S_version_09 : 40|24@1+ (1,0) [0|16777215] ""  PC

BO_ 2337926810 M2P_LiquidInfo_10__10: 8 MBMU
 SG_ M2P_TMS_L_S_version_10 : 0|40@1+ (1,0) [0|1099511627775] ""  PC
 SG_ M2P_TMS_L_N_S_version_10 : 40|24@1+ (1,0) [0|16777215] ""  PC

BO_ 2337926811 M2P_LiquidInfo_10__11: 8 MBMU
 SG_ M2P_TMS_L_S_version_11 : 0|40@1+ (1,0) [0|1099511627775] ""  PC
 SG_ M2P_TMS_L_N_S_version_11 : 40|24@1+ (1,0) [0|16777215] ""  PC

BO_ 2337926812 M2P_LiquidInfo_10__12: 8 MBMU
 SG_ M2P_TMS_L_S_version_12 : 0|40@1+ (1,0) [0|1099511627775] ""  PC
 SG_ M2P_TMS_L_N_S_version_12 : 40|24@1+ (1,0) [0|16777215] ""  PC

BO_ 2337926813 M2P_LiquidInfo_10__13: 8 MBMU
 SG_ M2P_TMS_L_S_version_13 : 0|40@1+ (1,0) [0|1099511627775] ""  PC
 SG_ M2P_TMS_L_N_S_version_13 : 40|24@1+ (1,0) [0|16777215] ""  PC

BO_ 2337926814 M2P_LiquidInfo_10__14: 8 MBMU
 SG_ M2P_TMS_L_S_version_14 : 0|40@1+ (1,0) [0|1099511627775] ""  PC
 SG_ M2P_TMS_L_N_S_version_14 : 40|24@1+ (1,0) [0|16777215] ""  PC

BO_ 2337926815 M2P_LiquidInfo_10__15: 8 MBMU
 SG_ M2P_TMS_L_S_version_15 : 0|40@1+ (1,0) [0|1099511627775] ""  PC
 SG_ M2P_TMS_L_N_S_version_15 : 40|24@1+ (1,0) [0|16777215] ""  PC

BO_ 2337926816 M2P_LiquidInfo_10__16: 8 MBMU
 SG_ M2P_TMS_L_S_version_16 : 0|40@1+ (1,0) [0|1099511627775] ""  PC
 SG_ M2P_TMS_L_N_S_version_16 : 40|24@1+ (1,0) [0|16777215] ""  PC

BO_ 2337926817 M2P_LiquidInfo_10__17: 8 MBMU
 SG_ M2P_TMS_L_S_version_17 : 0|40@1+ (1,0) [0|1099511627775] ""  PC
 SG_ M2P_TMS_L_N_S_version_17 : 40|24@1+ (1,0) [0|16777215] ""  PC

BO_ 2337926818 M2P_LiquidInfo_10__18: 8 MBMU
 SG_ M2P_TMS_L_S_version_18 : 0|40@1+ (1,0) [0|1099511627775] ""  PC
 SG_ M2P_TMS_L_N_S_version_18 : 40|24@1+ (1,0) [0|16777215] ""  PC

BO_ 2337926819 M2P_LiquidInfo_10__19: 8 MBMU
 SG_ M2P_TMS_L_S_version_19 : 0|40@1+ (1,0) [0|1099511627775] ""  PC
 SG_ M2P_TMS_L_N_S_version_19 : 40|24@1+ (1,0) [0|16777215] ""  PC

BO_ 2337926820 M2P_LiquidInfo_10__20: 8 MBMU
 SG_ M2P_TMS_L_S_version_20 : 0|40@1+ (1,0) [0|1099511627775] ""  PC
 SG_ M2P_TMS_L_N_S_version_20 : 40|24@1+ (1,0) [0|16777215] ""  PC

BO_ 2337926821 M2P_LiquidInfo_10__21: 8 MBMU
 SG_ M2P_TMS_L_S_version_21 : 0|40@1+ (1,0) [0|1099511627775] ""  PC
 SG_ M2P_TMS_L_N_S_version_21 : 40|24@1+ (1,0) [0|16777215] ""  PC

BO_ 2337926822 M2P_LiquidInfo_10__22: 8 MBMU
 SG_ M2P_TMS_L_S_version_22 : 0|40@1+ (1,0) [0|1099511627775] ""  PC
 SG_ M2P_TMS_L_N_S_version_22 : 40|24@1+ (1,0) [0|16777215] ""  PC

BO_ 2337926823 M2P_LiquidInfo_10__23: 8 MBMU
 SG_ M2P_TMS_L_S_version_23 : 0|40@1+ (1,0) [0|1099511627775] ""  PC
 SG_ M2P_TMS_L_N_S_version_23 : 40|24@1+ (1,0) [0|16777215] ""  PC

BO_ 2337926824 M2P_LiquidInfo_10__24: 8 MBMU
 SG_ M2P_TMS_L_S_version_24 : 0|40@1+ (1,0) [0|1099511627775] ""  PC
 SG_ M2P_TMS_L_N_S_version_24 : 40|24@1+ (1,0) [0|16777215] ""  PC

BO_ 2337926825 M2P_LiquidInfo_10__25: 8 MBMU
 SG_ M2P_TMS_L_S_version_25 : 0|40@1+ (1,0) [0|1099511627775] ""  PC
 SG_ M2P_TMS_L_N_S_version_25 : 40|24@1+ (1,0) [0|16777215] ""  PC

BO_ 2337926826 M2P_LiquidInfo_10__26: 8 MBMU
 SG_ M2P_TMS_L_S_version_26 : 0|40@1+ (1,0) [0|1099511627775] ""  PC
 SG_ M2P_TMS_L_N_S_version_26 : 40|24@1+ (1,0) [0|16777215] ""  PC

BO_ 2337926827 M2P_LiquidInfo_10__27: 8 MBMU
 SG_ M2P_TMS_L_S_version_27 : 0|40@1+ (1,0) [0|1099511627775] ""  PC
 SG_ M2P_TMS_L_N_S_version_27 : 40|24@1+ (1,0) [0|16777215] ""  PC

BO_ 2337926828 M2P_LiquidInfo_10__28: 8 MBMU
 SG_ M2P_TMS_L_S_version_28 : 0|40@1+ (1,0) [0|1099511627775] ""  PC
 SG_ M2P_TMS_L_N_S_version_28 : 40|24@1+ (1,0) [0|16777215] ""  PC

BO_ 2337926829 M2P_LiquidInfo_10__29: 8 MBMU
 SG_ M2P_TMS_L_S_version_29 : 0|40@1+ (1,0) [0|1099511627775] ""  PC
 SG_ M2P_TMS_L_N_S_version_29 : 40|24@1+ (1,0) [0|16777215] ""  PC

BO_ 2337926830 M2P_LiquidInfo_10__30: 8 MBMU
 SG_ M2P_TMS_L_S_version_30 : 0|40@1+ (1,0) [0|1099511627775] ""  PC
 SG_ M2P_TMS_L_N_S_version_30 : 40|24@1+ (1,0) [0|16777215] ""  PC

BO_ 2337926831 M2P_LiquidInfo_10__31: 8 MBMU
 SG_ M2P_TMS_L_S_version_31 : 0|40@1+ (1,0) [0|1099511627775] ""  PC
 SG_ M2P_TMS_L_N_S_version_31 : 40|24@1+ (1,0) [0|16777215] ""  PC

BO_ 2333146945 S2A_SUMDATA24__01: 8 SBMU
 SG_ S2A_TotalCapacityAccumul_01 : 0|32@1+ (0.1,0) [0|429496729.5] "Ah"  MBMU
 SG_ S2A_HisTotalLifeTime_01 : 32|32@1+ (1,0) [0|4294967295] "S"  MBMU

BO_ 2333146946 S2A_SUMDATA24__02: 8 SBMU
 SG_ S2A_TotalCapacityAccumul_02 : 0|32@1+ (0.1,0) [0|429496729.5] "Ah"  MBMU
 SG_ S2A_HisTotalLifeTime_02 : 32|32@1+ (1,0) [0|4294967295] "S"  MBMU

BO_ 2333146947 S2A_SUMDATA24__03: 8 SBMU
 SG_ S2A_TotalCapacityAccumul_03 : 0|32@1+ (0.1,0) [0|429496729.5] "Ah"  MBMU
 SG_ S2A_HisTotalLifeTime_03 : 32|32@1+ (1,0) [0|4294967295] "S"  MBMU

BO_ 2333146948 S2A_SUMDATA24__04: 8 SBMU
 SG_ S2A_TotalCapacityAccumul_04 : 0|32@1+ (0.1,0) [0|429496729.5] "Ah"  MBMU
 SG_ S2A_HisTotalLifeTime_04 : 32|32@1+ (1,0) [0|4294967295] "S"  MBMU

BO_ 2333146949 S2A_SUMDATA24__05: 8 SBMU
 SG_ S2A_TotalCapacityAccumul_05 : 0|32@1+ (0.1,0) [0|429496729.5] "Ah"  MBMU
 SG_ S2A_HisTotalLifeTime_05 : 32|32@1+ (1,0) [0|4294967295] "S"  MBMU

BO_ 2333146950 S2A_SUMDATA24__06: 8 SBMU
 SG_ S2A_TotalCapacityAccumul_06 : 0|32@1+ (0.1,0) [0|429496729.5] "Ah"  MBMU
 SG_ S2A_HisTotalLifeTime_06 : 32|32@1+ (1,0) [0|4294967295] "S"  MBMU

BO_ 2333146951 S2A_SUMDATA24__07: 8 SBMU
 SG_ S2A_TotalCapacityAccumul_07 : 0|32@1+ (0.1,0) [0|429496729.5] "Ah"  MBMU
 SG_ S2A_HisTotalLifeTime_07 : 32|32@1+ (1,0) [0|4294967295] "S"  MBMU

BO_ 2333146952 S2A_SUMDATA24__08: 8 SBMU
 SG_ S2A_TotalCapacityAccumul_08 : 0|32@1+ (0.1,0) [0|429496729.5] "Ah"  MBMU
 SG_ S2A_HisTotalLifeTime_08 : 32|32@1+ (1,0) [0|4294967295] "S"  MBMU

BO_ 2333146953 S2A_SUMDATA24__09: 8 SBMU
 SG_ S2A_TotalCapacityAccumul_09 : 0|32@1+ (0.1,0) [0|429496729.5] "Ah"  MBMU
 SG_ S2A_HisTotalLifeTime_09 : 32|32@1+ (1,0) [0|4294967295] "S"  MBMU

BO_ 2333146954 S2A_SUMDATA24__10: 8 SBMU
 SG_ S2A_TotalCapacityAccumul_10 : 0|32@1+ (0.1,0) [0|429496729.5] "Ah"  MBMU
 SG_ S2A_HisTotalLifeTime_10 : 32|32@1+ (1,0) [0|4294967295] "S"  MBMU

BO_ 2333146955 S2A_SUMDATA24__11: 8 SBMU
 SG_ S2A_TotalCapacityAccumul_11 : 0|32@1+ (0.1,0) [0|429496729.5] "Ah"  MBMU
 SG_ S2A_HisTotalLifeTime_11 : 32|32@1+ (1,0) [0|4294967295] "S"  MBMU

BO_ 2333146956 S2A_SUMDATA24__12: 8 SBMU
 SG_ S2A_TotalCapacityAccumul_12 : 0|32@1+ (0.1,0) [0|429496729.5] "Ah"  MBMU
 SG_ S2A_HisTotalLifeTime_12 : 32|32@1+ (1,0) [0|4294967295] "S"  MBMU

BO_ 2333146957 S2A_SUMDATA24__13: 8 SBMU
 SG_ S2A_TotalCapacityAccumul_13 : 0|32@1+ (0.1,0) [0|429496729.5] "Ah"  MBMU
 SG_ S2A_HisTotalLifeTime_13 : 32|32@1+ (1,0) [0|4294967295] "S"  MBMU

BO_ 2333146958 S2A_SUMDATA24__14: 8 SBMU
 SG_ S2A_TotalCapacityAccumul_14 : 0|32@1+ (0.1,0) [0|429496729.5] "Ah"  MBMU
 SG_ S2A_HisTotalLifeTime_14 : 32|32@1+ (1,0) [0|4294967295] "S"  MBMU

BO_ 2333146959 S2A_SUMDATA24__15: 8 SBMU
 SG_ S2A_TotalCapacityAccumul_15 : 0|32@1+ (0.1,0) [0|429496729.5] "Ah"  MBMU
 SG_ S2A_HisTotalLifeTime_15 : 32|32@1+ (1,0) [0|4294967295] "S"  MBMU

BO_ 2333146960 S2A_SUMDATA24__16: 8 SBMU
 SG_ S2A_TotalCapacityAccumul_16 : 0|32@1+ (0.1,0) [0|429496729.5] "Ah"  MBMU
 SG_ S2A_HisTotalLifeTime_16 : 32|32@1+ (1,0) [0|4294967295] "S"  MBMU

BO_ 2333146961 S2A_SUMDATA24__17: 8 SBMU
 SG_ S2A_TotalCapacityAccumul_17 : 0|32@1+ (0.1,0) [0|429496729.5] "Ah"  MBMU
 SG_ S2A_HisTotalLifeTime_17 : 32|32@1+ (1,0) [0|4294967295] "S"  MBMU

BO_ 2333146962 S2A_SUMDATA24__18: 8 SBMU
 SG_ S2A_TotalCapacityAccumul_18 : 0|32@1+ (0.1,0) [0|429496729.5] "Ah"  MBMU
 SG_ S2A_HisTotalLifeTime_18 : 32|32@1+ (1,0) [0|4294967295] "S"  MBMU

BO_ 2333146963 S2A_SUMDATA24__19: 8 SBMU
 SG_ S2A_TotalCapacityAccumul_19 : 0|32@1+ (0.1,0) [0|429496729.5] "Ah"  MBMU
 SG_ S2A_HisTotalLifeTime_19 : 32|32@1+ (1,0) [0|4294967295] "S"  MBMU

BO_ 2333146964 S2A_SUMDATA24__20: 8 SBMU
 SG_ S2A_TotalCapacityAccumul_20 : 0|32@1+ (0.1,0) [0|429496729.5] "Ah"  MBMU
 SG_ S2A_HisTotalLifeTime_20 : 32|32@1+ (1,0) [0|4294967295] "S"  MBMU

BO_ 2333146965 S2A_SUMDATA24__21: 8 SBMU
 SG_ S2A_TotalCapacityAccumul_21 : 0|32@1+ (0.1,0) [0|429496729.5] "Ah"  MBMU
 SG_ S2A_HisTotalLifeTime_21 : 32|32@1+ (1,0) [0|4294967295] "S"  MBMU

BO_ 2333146966 S2A_SUMDATA24__22: 8 SBMU
 SG_ S2A_TotalCapacityAccumul_22 : 0|32@1+ (0.1,0) [0|429496729.5] "Ah"  MBMU
 SG_ S2A_HisTotalLifeTime_22 : 32|32@1+ (1,0) [0|4294967295] "S"  MBMU

BO_ 2333146967 S2A_SUMDATA24__23: 8 SBMU
 SG_ S2A_TotalCapacityAccumul_23 : 0|32@1+ (0.1,0) [0|429496729.5] "Ah"  MBMU
 SG_ S2A_HisTotalLifeTime_23 : 32|32@1+ (1,0) [0|4294967295] "S"  MBMU

BO_ 2333146968 S2A_SUMDATA24__24: 8 SBMU
 SG_ S2A_TotalCapacityAccumul_24 : 0|32@1+ (0.1,0) [0|429496729.5] "Ah"  MBMU
 SG_ S2A_HisTotalLifeTime_24 : 32|32@1+ (1,0) [0|4294967295] "S"  MBMU

BO_ 2333146969 S2A_SUMDATA24__25: 8 SBMU
 SG_ S2A_TotalCapacityAccumul_25 : 0|32@1+ (0.1,0) [0|429496729.5] "Ah"  MBMU
 SG_ S2A_HisTotalLifeTime_25 : 32|32@1+ (1,0) [0|4294967295] "S"  MBMU

BO_ 2333146970 S2A_SUMDATA24__26: 8 SBMU
 SG_ S2A_TotalCapacityAccumul_26 : 0|32@1+ (0.1,0) [0|429496729.5] "Ah"  MBMU
 SG_ S2A_HisTotalLifeTime_26 : 32|32@1+ (1,0) [0|4294967295] "S"  MBMU

BO_ 2333146971 S2A_SUMDATA24__27: 8 SBMU
 SG_ S2A_TotalCapacityAccumul_27 : 0|32@1+ (0.1,0) [0|429496729.5] "Ah"  MBMU
 SG_ S2A_HisTotalLifeTime_27 : 32|32@1+ (1,0) [0|4294967295] "S"  MBMU

BO_ 2333146972 S2A_SUMDATA24__28: 8 SBMU
 SG_ S2A_TotalCapacityAccumul_28 : 0|32@1+ (0.1,0) [0|429496729.5] "Ah"  MBMU
 SG_ S2A_HisTotalLifeTime_28 : 32|32@1+ (1,0) [0|4294967295] "S"  MBMU

BO_ 2333146973 S2A_SUMDATA24__29: 8 SBMU
 SG_ S2A_TotalCapacityAccumul_29 : 0|32@1+ (0.1,0) [0|429496729.5] "Ah"  MBMU
 SG_ S2A_HisTotalLifeTime_29 : 32|32@1+ (1,0) [0|4294967295] "S"  MBMU

BO_ 2333146974 S2A_SUMDATA24__30: 8 SBMU
 SG_ S2A_TotalCapacityAccumul_30 : 0|32@1+ (0.1,0) [0|429496729.5] "Ah"  MBMU
 SG_ S2A_HisTotalLifeTime_30 : 32|32@1+ (1,0) [0|4294967295] "S"  MBMU

BO_ 2333146975 S2A_SUMDATA24__31: 8 SBMU
 SG_ S2A_TotalCapacityAccumul_31 : 0|32@1+ (0.1,0) [0|429496729.5] "Ah"  MBMU
 SG_ S2A_HisTotalLifeTime_31 : 32|32@1+ (1,0) [0|4294967295] "S"  MBMU

BO_ 2333146976 S2A_SUMDATA24__32: 8 SBMU
 SG_ S2A_TotalCapacityAccumul_32 : 0|32@1+ (0.1,0) [0|429496729.5] "Ah"  MBMU
 SG_ S2A_HisTotalLifeTime_32 : 32|32@1+ (1,0) [0|4294967295] "S"  MBMU

BO_ 2333146977 S2A_SUMDATA24__33: 8 SBMU
 SG_ S2A_TotalCapacityAccumul_33 : 0|32@1+ (0.1,0) [0|429496729.5] "Ah"  MBMU
 SG_ S2A_HisTotalLifeTime_33 : 32|32@1+ (1,0) [0|4294967295] "S"  MBMU

BO_ 2333146978 S2A_SUMDATA24__34: 8 SBMU
 SG_ S2A_TotalCapacityAccumul_34 : 0|32@1+ (0.1,0) [0|429496729.5] "Ah"  MBMU
 SG_ S2A_HisTotalLifeTime_34 : 32|32@1+ (1,0) [0|4294967295] "S"  MBMU

BO_ 2333146979 S2A_SUMDATA24__35: 8 SBMU
 SG_ S2A_TotalCapacityAccumul_35 : 0|32@1+ (0.1,0) [0|429496729.5] "Ah"  MBMU
 SG_ S2A_HisTotalLifeTime_35 : 32|32@1+ (1,0) [0|4294967295] "S"  MBMU

BO_ 2333146980 S2A_SUMDATA24__36: 8 SBMU
 SG_ S2A_TotalCapacityAccumul_36 : 0|32@1+ (0.1,0) [0|429496729.5] "Ah"  MBMU
 SG_ S2A_HisTotalLifeTime_36 : 32|32@1+ (1,0) [0|4294967295] "S"  MBMU

BO_ 2333146981 S2A_SUMDATA24__37: 8 SBMU
 SG_ S2A_TotalCapacityAccumul_37 : 0|32@1+ (0.1,0) [0|429496729.5] "Ah"  MBMU
 SG_ S2A_HisTotalLifeTime_37 : 32|32@1+ (1,0) [0|4294967295] "S"  MBMU

BO_ 2333146982 S2A_SUMDATA24__38: 8 SBMU
 SG_ S2A_TotalCapacityAccumul_38 : 0|32@1+ (0.1,0) [0|429496729.5] "Ah"  MBMU
 SG_ S2A_HisTotalLifeTime_38 : 32|32@1+ (1,0) [0|4294967295] "S"  MBMU

BO_ 2333146983 S2A_SUMDATA24__39: 8 SBMU
 SG_ S2A_TotalCapacityAccumul_39 : 0|32@1+ (0.1,0) [0|429496729.5] "Ah"  MBMU
 SG_ S2A_HisTotalLifeTime_39 : 32|32@1+ (1,0) [0|4294967295] "S"  MBMU

BO_ 2333146984 S2A_SUMDATA24__40: 8 SBMU
 SG_ S2A_TotalCapacityAccumul_40 : 0|32@1+ (0.1,0) [0|429496729.5] "Ah"  MBMU
 SG_ S2A_HisTotalLifeTime_40 : 32|32@1+ (1,0) [0|4294967295] "S"  MBMU

BO_ 2333146985 S2A_SUMDATA24__41: 8 SBMU
 SG_ S2A_TotalCapacityAccumul_41 : 0|32@1+ (0.1,0) [0|429496729.5] "Ah"  MBMU
 SG_ S2A_HisTotalLifeTime_41 : 32|32@1+ (1,0) [0|4294967295] "S"  MBMU

BO_ 2333146986 S2A_SUMDATA24__42: 8 SBMU
 SG_ S2A_TotalCapacityAccumul_42 : 0|32@1+ (0.1,0) [0|429496729.5] "Ah"  MBMU
 SG_ S2A_HisTotalLifeTime_42 : 32|32@1+ (1,0) [0|4294967295] "S"  MBMU

BO_ 2333146987 S2A_SUMDATA24__43: 8 SBMU
 SG_ S2A_TotalCapacityAccumul_43 : 0|32@1+ (0.1,0) [0|429496729.5] "Ah"  MBMU
 SG_ S2A_HisTotalLifeTime_43 : 32|32@1+ (1,0) [0|4294967295] "S"  MBMU

BO_ 2333146988 S2A_SUMDATA24__44: 8 SBMU
 SG_ S2A_TotalCapacityAccumul_44 : 0|32@1+ (0.1,0) [0|429496729.5] "Ah"  MBMU
 SG_ S2A_HisTotalLifeTime_44 : 32|32@1+ (1,0) [0|4294967295] "S"  MBMU

BO_ 2333146989 S2A_SUMDATA24__45: 8 SBMU
 SG_ S2A_TotalCapacityAccumul_45 : 0|32@1+ (0.1,0) [0|429496729.5] "Ah"  MBMU
 SG_ S2A_HisTotalLifeTime_45 : 32|32@1+ (1,0) [0|4294967295] "S"  MBMU

BO_ 2333146990 S2A_SUMDATA24__46: 8 SBMU
 SG_ S2A_TotalCapacityAccumul_46 : 0|32@1+ (0.1,0) [0|429496729.5] "Ah"  MBMU
 SG_ S2A_HisTotalLifeTime_46 : 32|32@1+ (1,0) [0|4294967295] "S"  MBMU

BO_ 2333146991 S2A_SUMDATA24__47: 8 SBMU
 SG_ S2A_TotalCapacityAccumul_47 : 0|32@1+ (0.1,0) [0|429496729.5] "Ah"  MBMU
 SG_ S2A_HisTotalLifeTime_47 : 32|32@1+ (1,0) [0|4294967295] "S"  MBMU

BO_ 2333146992 S2A_SUMDATA24__48: 8 SBMU
 SG_ S2A_TotalCapacityAccumul_48 : 0|32@1+ (0.1,0) [0|429496729.5] "Ah"  MBMU
 SG_ S2A_HisTotalLifeTime_48 : 32|32@1+ (1,0) [0|4294967295] "S"  MBMU

BO_ 2333146993 S2A_SUMDATA24__49: 8 SBMU
 SG_ S2A_TotalCapacityAccumul_49 : 0|32@1+ (0.1,0) [0|429496729.5] "Ah"  MBMU
 SG_ S2A_HisTotalLifeTime_49 : 32|32@1+ (1,0) [0|4294967295] "S"  MBMU

BO_ 2333146994 S2A_SUMDATA24__50: 8 SBMU
 SG_ S2A_TotalCapacityAccumul_50 : 0|32@1+ (0.1,0) [0|429496729.5] "Ah"  MBMU
 SG_ S2A_HisTotalLifeTime_50 : 32|32@1+ (1,0) [0|4294967295] "S"  MBMU

BO_ 2333146995 S2A_SUMDATA24__51: 8 SBMU
 SG_ S2A_TotalCapacityAccumul_51 : 0|32@1+ (0.1,0) [0|429496729.5] "Ah"  MBMU
 SG_ S2A_HisTotalLifeTime_51 : 32|32@1+ (1,0) [0|4294967295] "S"  MBMU

BO_ 2333146996 S2A_SUMDATA24__52: 8 SBMU
 SG_ S2A_TotalCapacityAccumul_52 : 0|32@1+ (0.1,0) [0|429496729.5] "Ah"  MBMU
 SG_ S2A_HisTotalLifeTime_52 : 32|32@1+ (1,0) [0|4294967295] "S"  MBMU

BO_ 2333146997 S2A_SUMDATA24__53: 8 SBMU
 SG_ S2A_TotalCapacityAccumul_53 : 0|32@1+ (0.1,0) [0|429496729.5] "Ah"  MBMU
 SG_ S2A_HisTotalLifeTime_53 : 32|32@1+ (1,0) [0|4294967295] "S"  MBMU

BO_ 2333146998 S2A_SUMDATA24__54: 8 SBMU
 SG_ S2A_TotalCapacityAccumul_54 : 0|32@1+ (0.1,0) [0|429496729.5] "Ah"  MBMU
 SG_ S2A_HisTotalLifeTime_54 : 32|32@1+ (1,0) [0|4294967295] "S"  MBMU

BO_ 2333146999 S2A_SUMDATA24__55: 8 SBMU
 SG_ S2A_TotalCapacityAccumul_55 : 0|32@1+ (0.1,0) [0|429496729.5] "Ah"  MBMU
 SG_ S2A_HisTotalLifeTime_55 : 32|32@1+ (1,0) [0|4294967295] "S"  MBMU

BO_ 2333147000 S2A_SUMDATA24__56: 8 SBMU
 SG_ S2A_TotalCapacityAccumul_56 : 0|32@1+ (0.1,0) [0|429496729.5] "Ah"  MBMU
 SG_ S2A_HisTotalLifeTime_56 : 32|32@1+ (1,0) [0|4294967295] "S"  MBMU

BO_ 2333147001 S2A_SUMDATA24__57: 8 SBMU
 SG_ S2A_TotalCapacityAccumul_57 : 0|32@1+ (0.1,0) [0|429496729.5] "Ah"  MBMU
 SG_ S2A_HisTotalLifeTime_57 : 32|32@1+ (1,0) [0|4294967295] "S"  MBMU

BO_ 2333147002 S2A_SUMDATA24__58: 8 SBMU
 SG_ S2A_TotalCapacityAccumul_58 : 0|32@1+ (0.1,0) [0|429496729.5] "Ah"  MBMU
 SG_ S2A_HisTotalLifeTime_58 : 32|32@1+ (1,0) [0|4294967295] "S"  MBMU

BO_ 2333147003 S2A_SUMDATA24__59: 8 SBMU
 SG_ S2A_TotalCapacityAccumul_59 : 0|32@1+ (0.1,0) [0|429496729.5] "Ah"  MBMU
 SG_ S2A_HisTotalLifeTime_59 : 32|32@1+ (1,0) [0|4294967295] "S"  MBMU

BO_ 2333147004 S2A_SUMDATA24__60: 8 SBMU
 SG_ S2A_TotalCapacityAccumul_60 : 0|32@1+ (0.1,0) [0|429496729.5] "Ah"  MBMU
 SG_ S2A_HisTotalLifeTime_60 : 32|32@1+ (1,0) [0|4294967295] "S"  MBMU

BO_ 2333147005 S2A_SUMDATA24__61: 8 SBMU
 SG_ S2A_TotalCapacityAccumul_61 : 0|32@1+ (0.1,0) [0|429496729.5] "Ah"  MBMU
 SG_ S2A_HisTotalLifeTime_61 : 32|32@1+ (1,0) [0|4294967295] "S"  MBMU

BO_ 2333147006 S2A_SUMDATA24__62: 8 SBMU
 SG_ S2A_TotalCapacityAccumul_62 : 0|32@1+ (0.1,0) [0|429496729.5] "Ah"  MBMU
 SG_ S2A_HisTotalLifeTime_62 : 32|32@1+ (1,0) [0|4294967295] "S"  MBMU

BO_ 2333147007 S2A_SUMDATA24__63: 8 SBMU
 SG_ S2A_TotalCapacityAccumul_63 : 0|32@1+ (0.1,0) [0|429496729.5] "Ah"  MBMU
 SG_ S2A_HisTotalLifeTime_63 : 32|32@1+ (1,0) [0|4294967295] "S"  MBMU

BO_ 2334523201 S2A_SUMDATA25__01: 8 SBMU
 SG_ S2A_HisTotalStoreLifeTime_01 : 0|32@1+ (1,0) [0|4294967295] "S"  MBMU

BO_ 2334523202 S2A_SUMDATA25__02: 8 SBMU
 SG_ S2A_HisTotalStoreLifeTime_02 : 0|32@1+ (1,0) [0|4294967295] "S"  MBMU

BO_ 2334523203 S2A_SUMDATA25__03: 8 SBMU
 SG_ S2A_HisTotalStoreLifeTime_03 : 0|32@1+ (1,0) [0|4294967295] "S"  MBMU

BO_ 2334523204 S2A_SUMDATA25__04: 8 SBMU
 SG_ S2A_HisTotalStoreLifeTime_04 : 0|32@1+ (1,0) [0|4294967295] "S"  MBMU

BO_ 2334523205 S2A_SUMDATA25__05: 8 SBMU
 SG_ S2A_HisTotalStoreLifeTime_05 : 0|32@1+ (1,0) [0|4294967295] "S"  MBMU

BO_ 2334523206 S2A_SUMDATA25__06: 8 SBMU
 SG_ S2A_HisTotalStoreLifeTime_06 : 0|32@1+ (1,0) [0|4294967295] "S"  MBMU

BO_ 2334523207 S2A_SUMDATA25__07: 8 SBMU
 SG_ S2A_HisTotalStoreLifeTime_07 : 0|32@1+ (1,0) [0|4294967295] "S"  MBMU

BO_ 2334523208 S2A_SUMDATA25__08: 8 SBMU
 SG_ S2A_HisTotalStoreLifeTime_08 : 0|32@1+ (1,0) [0|4294967295] "S"  MBMU

BO_ 2334523209 S2A_SUMDATA25__09: 8 SBMU
 SG_ S2A_HisTotalStoreLifeTime_09 : 0|32@1+ (1,0) [0|4294967295] "S"  MBMU

BO_ 2334523210 S2A_SUMDATA25__10: 8 SBMU
 SG_ S2A_HisTotalStoreLifeTime_10 : 0|32@1+ (1,0) [0|4294967295] "S"  MBMU

BO_ 2334523211 S2A_SUMDATA25__11: 8 SBMU
 SG_ S2A_HisTotalStoreLifeTime_11 : 0|32@1+ (1,0) [0|4294967295] "S"  MBMU

BO_ 2334523212 S2A_SUMDATA25__12: 8 SBMU
 SG_ S2A_HisTotalStoreLifeTime_12 : 0|32@1+ (1,0) [0|4294967295] "S"  MBMU

BO_ 2334523213 S2A_SUMDATA25__13: 8 SBMU
 SG_ S2A_HisTotalStoreLifeTime_13 : 0|32@1+ (1,0) [0|4294967295] "S"  MBMU

BO_ 2334523214 S2A_SUMDATA25__14: 8 SBMU
 SG_ S2A_HisTotalStoreLifeTime_14 : 0|32@1+ (1,0) [0|4294967295] "S"  MBMU

BO_ 2334523215 S2A_SUMDATA25__15: 8 SBMU
 SG_ S2A_HisTotalStoreLifeTime_15 : 0|32@1+ (1,0) [0|4294967295] "S"  MBMU

BO_ 2334523216 S2A_SUMDATA25__16: 8 SBMU
 SG_ S2A_HisTotalStoreLifeTime_16 : 0|32@1+ (1,0) [0|4294967295] "S"  MBMU

BO_ 2334523217 S2A_SUMDATA25__17: 8 SBMU
 SG_ S2A_HisTotalStoreLifeTime_17 : 0|32@1+ (1,0) [0|4294967295] "S"  MBMU

BO_ 2334523218 S2A_SUMDATA25__18: 8 SBMU
 SG_ S2A_HisTotalStoreLifeTime_18 : 0|32@1+ (1,0) [0|4294967295] "S"  MBMU

BO_ 2334523219 S2A_SUMDATA25__19: 8 SBMU
 SG_ S2A_HisTotalStoreLifeTime_19 : 0|32@1+ (1,0) [0|4294967295] "S"  MBMU

BO_ 2334523220 S2A_SUMDATA25__20: 8 SBMU
 SG_ S2A_HisTotalStoreLifeTime_20 : 0|32@1+ (1,0) [0|4294967295] "S"  MBMU

BO_ 2334523221 S2A_SUMDATA25__21: 8 SBMU
 SG_ S2A_HisTotalStoreLifeTime_21 : 0|32@1+ (1,0) [0|4294967295] "S"  MBMU

BO_ 2334523222 S2A_SUMDATA25__22: 8 SBMU
 SG_ S2A_HisTotalStoreLifeTime_22 : 0|32@1+ (1,0) [0|4294967295] "S"  MBMU

BO_ 2334523223 S2A_SUMDATA25__23: 8 SBMU
 SG_ S2A_HisTotalStoreLifeTime_23 : 0|32@1+ (1,0) [0|4294967295] "S"  MBMU

BO_ 2334523224 S2A_SUMDATA25__24: 8 SBMU
 SG_ S2A_HisTotalStoreLifeTime_24 : 0|32@1+ (1,0) [0|4294967295] "S"  MBMU

BO_ 2334523225 S2A_SUMDATA25__25: 8 SBMU
 SG_ S2A_HisTotalStoreLifeTime_25 : 0|32@1+ (1,0) [0|4294967295] "S"  MBMU

BO_ 2334523226 S2A_SUMDATA25__26: 8 SBMU
 SG_ S2A_HisTotalStoreLifeTime_26 : 0|32@1+ (1,0) [0|4294967295] "S"  MBMU

BO_ 2334523227 S2A_SUMDATA25__27: 8 SBMU
 SG_ S2A_HisTotalStoreLifeTime_27 : 0|32@1+ (1,0) [0|4294967295] "S"  MBMU

BO_ 2334523228 S2A_SUMDATA25__28: 8 SBMU
 SG_ S2A_HisTotalStoreLifeTime_28 : 0|32@1+ (1,0) [0|4294967295] "S"  MBMU

BO_ 2334523229 S2A_SUMDATA25__29: 8 SBMU
 SG_ S2A_HisTotalStoreLifeTime_29 : 0|32@1+ (1,0) [0|4294967295] "S"  MBMU

BO_ 2334523230 S2A_SUMDATA25__30: 8 SBMU
 SG_ S2A_HisTotalStoreLifeTime_30 : 0|32@1+ (1,0) [0|4294967295] "S"  MBMU

BO_ 2334523231 S2A_SUMDATA25__31: 8 SBMU
 SG_ S2A_HisTotalStoreLifeTime_31 : 0|32@1+ (1,0) [0|4294967295] "S"  MBMU

BO_ 2334523232 S2A_SUMDATA25__32: 8 SBMU
 SG_ S2A_HisTotalStoreLifeTime_32 : 0|32@1+ (1,0) [0|4294967295] "S"  MBMU

BO_ 2334523233 S2A_SUMDATA25__33: 8 SBMU
 SG_ S2A_HisTotalStoreLifeTime_33 : 0|32@1+ (1,0) [0|4294967295] "S"  MBMU

BO_ 2334523234 S2A_SUMDATA25__34: 8 SBMU
 SG_ S2A_HisTotalStoreLifeTime_34 : 0|32@1+ (1,0) [0|4294967295] "S"  MBMU

BO_ 2334523235 S2A_SUMDATA25__35: 8 SBMU
 SG_ S2A_HisTotalStoreLifeTime_35 : 0|32@1+ (1,0) [0|4294967295] "S"  MBMU

BO_ 2334523236 S2A_SUMDATA25__36: 8 SBMU
 SG_ S2A_HisTotalStoreLifeTime_36 : 0|32@1+ (1,0) [0|4294967295] "S"  MBMU

BO_ 2334523237 S2A_SUMDATA25__37: 8 SBMU
 SG_ S2A_HisTotalStoreLifeTime_37 : 0|32@1+ (1,0) [0|4294967295] "S"  MBMU

BO_ 2334523238 S2A_SUMDATA25__38: 8 SBMU
 SG_ S2A_HisTotalStoreLifeTime_38 : 0|32@1+ (1,0) [0|4294967295] "S"  MBMU

BO_ 2334523239 S2A_SUMDATA25__39: 8 SBMU
 SG_ S2A_HisTotalStoreLifeTime_39 : 0|32@1+ (1,0) [0|4294967295] "S"  MBMU

BO_ 2334523240 S2A_SUMDATA25__40: 8 SBMU
 SG_ S2A_HisTotalStoreLifeTime_40 : 0|32@1+ (1,0) [0|4294967295] "S"  MBMU

BO_ 2334523241 S2A_SUMDATA25__41: 8 SBMU
 SG_ S2A_HisTotalStoreLifeTime_41 : 0|32@1+ (1,0) [0|4294967295] "S"  MBMU

BO_ 2334523242 S2A_SUMDATA25__42: 8 SBMU
 SG_ S2A_HisTotalStoreLifeTime_42 : 0|32@1+ (1,0) [0|4294967295] "S"  MBMU

BO_ 2334523243 S2A_SUMDATA25__43: 8 SBMU
 SG_ S2A_HisTotalStoreLifeTime_43 : 0|32@1+ (1,0) [0|4294967295] "S"  MBMU

BO_ 2334523244 S2A_SUMDATA25__44: 8 SBMU
 SG_ S2A_HisTotalStoreLifeTime_44 : 0|32@1+ (1,0) [0|4294967295] "S"  MBMU

BO_ 2334523245 S2A_SUMDATA25__45: 8 SBMU
 SG_ S2A_HisTotalStoreLifeTime_45 : 0|32@1+ (1,0) [0|4294967295] "S"  MBMU

BO_ 2334523246 S2A_SUMDATA25__46: 8 SBMU
 SG_ S2A_HisTotalStoreLifeTime_46 : 0|32@1+ (1,0) [0|4294967295] "S"  MBMU

BO_ 2334523247 S2A_SUMDATA25__47: 8 SBMU
 SG_ S2A_HisTotalStoreLifeTime_47 : 0|32@1+ (1,0) [0|4294967295] "S"  MBMU

BO_ 2334523248 S2A_SUMDATA25__48: 8 SBMU
 SG_ S2A_HisTotalStoreLifeTime_48 : 0|32@1+ (1,0) [0|4294967295] "S"  MBMU

BO_ 2334523249 S2A_SUMDATA25__49: 8 SBMU
 SG_ S2A_HisTotalStoreLifeTime_49 : 0|32@1+ (1,0) [0|4294967295] "S"  MBMU

BO_ 2334523250 S2A_SUMDATA25__50: 8 SBMU
 SG_ S2A_HisTotalStoreLifeTime_50 : 0|32@1+ (1,0) [0|4294967295] "S"  MBMU

BO_ 2334523251 S2A_SUMDATA25__51: 8 SBMU
 SG_ S2A_HisTotalStoreLifeTime_51 : 0|32@1+ (1,0) [0|4294967295] "S"  MBMU

BO_ 2334523252 S2A_SUMDATA25__52: 8 SBMU
 SG_ S2A_HisTotalStoreLifeTime_52 : 0|32@1+ (1,0) [0|4294967295] "S"  MBMU

BO_ 2334523253 S2A_SUMDATA25__53: 8 SBMU
 SG_ S2A_HisTotalStoreLifeTime_53 : 0|32@1+ (1,0) [0|4294967295] "S"  MBMU

BO_ 2334523254 S2A_SUMDATA25__54: 8 SBMU
 SG_ S2A_HisTotalStoreLifeTime_54 : 0|32@1+ (1,0) [0|4294967295] "S"  MBMU

BO_ 2334523255 S2A_SUMDATA25__55: 8 SBMU
 SG_ S2A_HisTotalStoreLifeTime_55 : 0|32@1+ (1,0) [0|4294967295] "S"  MBMU

BO_ 2334523256 S2A_SUMDATA25__56: 8 SBMU
 SG_ S2A_HisTotalStoreLifeTime_56 : 0|32@1+ (1,0) [0|4294967295] "S"  MBMU

BO_ 2334523257 S2A_SUMDATA25__57: 8 SBMU
 SG_ S2A_HisTotalStoreLifeTime_57 : 0|32@1+ (1,0) [0|4294967295] "S"  MBMU

BO_ 2334523258 S2A_SUMDATA25__58: 8 SBMU
 SG_ S2A_HisTotalStoreLifeTime_58 : 0|32@1+ (1,0) [0|4294967295] "S"  MBMU

BO_ 2334523259 S2A_SUMDATA25__59: 8 SBMU
 SG_ S2A_HisTotalStoreLifeTime_59 : 0|32@1+ (1,0) [0|4294967295] "S"  MBMU

BO_ 2334523260 S2A_SUMDATA25__60: 8 SBMU
 SG_ S2A_HisTotalStoreLifeTime_60 : 0|32@1+ (1,0) [0|4294967295] "S"  MBMU

BO_ 2334523261 S2A_SUMDATA25__61: 8 SBMU
 SG_ S2A_HisTotalStoreLifeTime_61 : 0|32@1+ (1,0) [0|4294967295] "S"  MBMU

BO_ 2334523262 S2A_SUMDATA25__62: 8 SBMU
 SG_ S2A_HisTotalStoreLifeTime_62 : 0|32@1+ (1,0) [0|4294967295] "S"  MBMU

BO_ 2334523263 S2A_SUMDATA25__63: 8 SBMU
 SG_ S2A_HisTotalStoreLifeTime_63 : 0|32@1+ (1,0) [0|4294967295] "S"  MBMU

BO_ 2337992337 M2P_LiquidInfo_11__01: 8 MBMU
 SG_ Reserved_4 : 0|3@1+ (1,0) [0|7] ""  PC
 SG_ M2P_TMS_BackWaterPress_1 : 0|8@1+ (0.1,0) [0|25.5] "bar"  PC
 SG_ M2P_TMS_OutWaterPress_1 : 8|8@1+ (0.1,0) [0|25.5] "bar"  PC

BO_ 2337992338 M2P_LiquidInfo_11__02: 8 MBMU
 SG_ Reserved_4 : 0|3@1+ (1,0) [0|7] ""  PC
 SG_ M2P_TMS_BackWaterPress_1 : 0|8@1+ (0.1,0) [0|25.5] "bar"  PC
 SG_ M2P_TMS_OutWaterPress_1 : 8|8@1+ (0.1,0) [0|25.5] "bar"  PC

BO_ 2337992339 M2P_LiquidInfo_11__03: 8 MBMU
 SG_ Reserved_4 : 0|3@1+ (1,0) [0|7] ""  PC
 SG_ M2P_TMS_BackWaterPress_1 : 0|8@1+ (0.1,0) [0|25.5] "bar"  PC
 SG_ M2P_TMS_OutWaterPress_1 : 8|8@1+ (0.1,0) [0|25.5] "bar"  PC

BO_ 2337992340 M2P_LiquidInfo_11__04: 8 MBMU
 SG_ Reserved_4 : 0|3@1+ (1,0) [0|7] ""  PC
 SG_ M2P_TMS_BackWaterPress_1 : 0|8@1+ (0.1,0) [0|25.5] "bar"  PC
 SG_ M2P_TMS_OutWaterPress_1 : 8|8@1+ (0.1,0) [0|25.5] "bar"  PC

BO_ 2337992341 M2P_LiquidInfo_11__05: 8 MBMU
 SG_ Reserved_4 : 0|3@1+ (1,0) [0|7] ""  PC
 SG_ M2P_TMS_BackWaterPress_1 : 0|8@1+ (0.1,0) [0|25.5] "bar"  PC
 SG_ M2P_TMS_OutWaterPress_1 : 8|8@1+ (0.1,0) [0|25.5] "bar"  PC

BO_ 2337992342 M2P_LiquidInfo_11__06: 8 MBMU
 SG_ Reserved_4 : 0|3@1+ (1,0) [0|7] ""  PC
 SG_ M2P_TMS_BackWaterPress_1 : 0|8@1+ (0.1,0) [0|25.5] "bar"  PC
 SG_ M2P_TMS_OutWaterPress_1 : 8|8@1+ (0.1,0) [0|25.5] "bar"  PC

BO_ 2337992343 M2P_LiquidInfo_11__07: 8 MBMU
 SG_ Reserved_4 : 0|3@1+ (1,0) [0|7] ""  PC
 SG_ M2P_TMS_BackWaterPress_1 : 0|8@1+ (0.1,0) [0|25.5] "bar"  PC
 SG_ M2P_TMS_OutWaterPress_1 : 8|8@1+ (0.1,0) [0|25.5] "bar"  PC

BO_ 2337992344 M2P_LiquidInfo_11__08: 8 MBMU
 SG_ Reserved_4 : 0|3@1+ (1,0) [0|7] ""  PC
 SG_ M2P_TMS_BackWaterPress_1 : 0|8@1+ (0.1,0) [0|25.5] "bar"  PC
 SG_ M2P_TMS_OutWaterPress_1 : 8|8@1+ (0.1,0) [0|25.5] "bar"  PC

BO_ 2337992345 M2P_LiquidInfo_11__09: 8 MBMU
 SG_ Reserved_4 : 0|3@1+ (1,0) [0|7] ""  PC
 SG_ M2P_TMS_BackWaterPress_1 : 0|8@1+ (0.1,0) [0|25.5] "bar"  PC
 SG_ M2P_TMS_OutWaterPress_1 : 8|8@1+ (0.1,0) [0|25.5] "bar"  PC

BO_ 2337992346 M2P_LiquidInfo_11__10: 8 MBMU
 SG_ Reserved_4 : 0|3@1+ (1,0) [0|7] ""  PC
 SG_ M2P_TMS_BackWaterPress_1 : 0|8@1+ (0.1,0) [0|25.5] "bar"  PC
 SG_ M2P_TMS_OutWaterPress_1 : 8|8@1+ (0.1,0) [0|25.5] "bar"  PC

BO_ 2337992347 M2P_LiquidInfo_11__11: 8 MBMU
 SG_ Reserved_4 : 0|3@1+ (1,0) [0|7] ""  PC
 SG_ M2P_TMS_BackWaterPress_1 : 0|8@1+ (0.1,0) [0|25.5] "bar"  PC
 SG_ M2P_TMS_OutWaterPress_1 : 8|8@1+ (0.1,0) [0|25.5] "bar"  PC

BO_ 2337992348 M2P_LiquidInfo_11__12: 8 MBMU
 SG_ Reserved_4 : 0|3@1+ (1,0) [0|7] ""  PC
 SG_ M2P_TMS_BackWaterPress_1 : 0|8@1+ (0.1,0) [0|25.5] "bar"  PC
 SG_ M2P_TMS_OutWaterPress_1 : 8|8@1+ (0.1,0) [0|25.5] "bar"  PC

BO_ 2337992349 M2P_LiquidInfo_11__13: 8 MBMU
 SG_ Reserved_4 : 0|3@1+ (1,0) [0|7] ""  PC
 SG_ M2P_TMS_BackWaterPress_1 : 0|8@1+ (0.1,0) [0|25.5] "bar"  PC
 SG_ M2P_TMS_OutWaterPress_1 : 8|8@1+ (0.1,0) [0|25.5] "bar"  PC

BO_ 2337992350 M2P_LiquidInfo_11__14: 8 MBMU
 SG_ Reserved_4 : 0|3@1+ (1,0) [0|7] ""  PC
 SG_ M2P_TMS_BackWaterPress_1 : 0|8@1+ (0.1,0) [0|25.5] "bar"  PC
 SG_ M2P_TMS_OutWaterPress_1 : 8|8@1+ (0.1,0) [0|25.5] "bar"  PC

BO_ 2337992351 M2P_LiquidInfo_11__15: 8 MBMU
 SG_ Reserved_4 : 0|3@1+ (1,0) [0|7] ""  PC
 SG_ M2P_TMS_BackWaterPress_1 : 0|8@1+ (0.1,0) [0|25.5] "bar"  PC
 SG_ M2P_TMS_OutWaterPress_1 : 8|8@1+ (0.1,0) [0|25.5] "bar"  PC

BO_ 2337992352 M2P_LiquidInfo_11__16: 8 MBMU
 SG_ Reserved_4 : 0|3@1+ (1,0) [0|7] ""  PC
 SG_ M2P_TMS_BackWaterPress_1 : 0|8@1+ (0.1,0) [0|25.5] "bar"  PC
 SG_ M2P_TMS_OutWaterPress_1 : 8|8@1+ (0.1,0) [0|25.5] "bar"  PC

BO_ 2337992353 M2P_LiquidInfo_11__17: 8 MBMU
 SG_ Reserved_4 : 0|3@1+ (1,0) [0|7] ""  PC
 SG_ M2P_TMS_BackWaterPress_1 : 0|8@1+ (0.1,0) [0|25.5] "bar"  PC
 SG_ M2P_TMS_OutWaterPress_1 : 8|8@1+ (0.1,0) [0|25.5] "bar"  PC

BO_ 2337992354 M2P_LiquidInfo_11__18: 8 MBMU
 SG_ Reserved_4 : 0|3@1+ (1,0) [0|7] ""  PC
 SG_ M2P_TMS_BackWaterPress_1 : 0|8@1+ (0.1,0) [0|25.5] "bar"  PC
 SG_ M2P_TMS_OutWaterPress_1 : 8|8@1+ (0.1,0) [0|25.5] "bar"  PC

BO_ 2337992355 M2P_LiquidInfo_11__19: 8 MBMU
 SG_ Reserved_4 : 0|3@1+ (1,0) [0|7] ""  PC
 SG_ M2P_TMS_BackWaterPress_1 : 0|8@1+ (0.1,0) [0|25.5] "bar"  PC
 SG_ M2P_TMS_OutWaterPress_1 : 8|8@1+ (0.1,0) [0|25.5] "bar"  PC

BO_ 2337992356 M2P_LiquidInfo_11__20: 8 MBMU
 SG_ Reserved_4 : 0|3@1+ (1,0) [0|7] ""  PC
 SG_ M2P_TMS_BackWaterPress_1 : 0|8@1+ (0.1,0) [0|25.5] "bar"  PC
 SG_ M2P_TMS_OutWaterPress_1 : 8|8@1+ (0.1,0) [0|25.5] "bar"  PC

BO_ 2337992357 M2P_LiquidInfo_11__21: 8 MBMU
 SG_ Reserved_4 : 0|3@1+ (1,0) [0|7] ""  PC
 SG_ M2P_TMS_BackWaterPress_1 : 0|8@1+ (0.1,0) [0|25.5] "bar"  PC
 SG_ M2P_TMS_OutWaterPress_1 : 8|8@1+ (0.1,0) [0|25.5] "bar"  PC

BO_ 2337992358 M2P_LiquidInfo_11__22: 8 MBMU
 SG_ Reserved_4 : 0|3@1+ (1,0) [0|7] ""  PC
 SG_ M2P_TMS_BackWaterPress_1 : 0|8@1+ (0.1,0) [0|25.5] "bar"  PC
 SG_ M2P_TMS_OutWaterPress_1 : 8|8@1+ (0.1,0) [0|25.5] "bar"  PC

BO_ 2337992359 M2P_LiquidInfo_11__23: 8 MBMU
 SG_ Reserved_4 : 0|3@1+ (1,0) [0|7] ""  PC
 SG_ M2P_TMS_BackWaterPress_1 : 0|8@1+ (0.1,0) [0|25.5] "bar"  PC
 SG_ M2P_TMS_OutWaterPress_1 : 8|8@1+ (0.1,0) [0|25.5] "bar"  PC

BO_ 2337992360 M2P_LiquidInfo_11__24: 8 MBMU
 SG_ Reserved_4 : 0|3@1+ (1,0) [0|7] ""  PC
 SG_ M2P_TMS_BackWaterPress_1 : 0|8@1+ (0.1,0) [0|25.5] "bar"  PC
 SG_ M2P_TMS_OutWaterPress_1 : 8|8@1+ (0.1,0) [0|25.5] "bar"  PC

BO_ 2337992361 M2P_LiquidInfo_11__25: 8 MBMU
 SG_ Reserved_4 : 0|3@1+ (1,0) [0|7] ""  PC
 SG_ M2P_TMS_BackWaterPress_1 : 0|8@1+ (0.1,0) [0|25.5] "bar"  PC
 SG_ M2P_TMS_OutWaterPress_1 : 8|8@1+ (0.1,0) [0|25.5] "bar"  PC

BO_ 2337992362 M2P_LiquidInfo_11__26: 8 MBMU
 SG_ Reserved_4 : 0|3@1+ (1,0) [0|7] ""  PC
 SG_ M2P_TMS_BackWaterPress_1 : 0|8@1+ (0.1,0) [0|25.5] "bar"  PC
 SG_ M2P_TMS_OutWaterPress_1 : 8|8@1+ (0.1,0) [0|25.5] "bar"  PC

BO_ 2337992363 M2P_LiquidInfo_11__27: 8 MBMU
 SG_ Reserved_4 : 0|3@1+ (1,0) [0|7] ""  PC
 SG_ M2P_TMS_BackWaterPress_1 : 0|8@1+ (0.1,0) [0|25.5] "bar"  PC
 SG_ M2P_TMS_OutWaterPress_1 : 8|8@1+ (0.1,0) [0|25.5] "bar"  PC

BO_ 2337992364 M2P_LiquidInfo_11__28: 8 MBMU
 SG_ Reserved_4 : 0|3@1+ (1,0) [0|7] ""  PC
 SG_ M2P_TMS_BackWaterPress_1 : 0|8@1+ (0.1,0) [0|25.5] "bar"  PC
 SG_ M2P_TMS_OutWaterPress_1 : 8|8@1+ (0.1,0) [0|25.5] "bar"  PC

BO_ 2337992365 M2P_LiquidInfo_11__29: 8 MBMU
 SG_ Reserved_4 : 0|3@1+ (1,0) [0|7] ""  PC
 SG_ M2P_TMS_BackWaterPress_1 : 0|8@1+ (0.1,0) [0|25.5] "bar"  PC
 SG_ M2P_TMS_OutWaterPress_1 : 8|8@1+ (0.1,0) [0|25.5] "bar"  PC

BO_ 2337992366 M2P_LiquidInfo_11__30: 8 MBMU
 SG_ Reserved_4 : 0|3@1+ (1,0) [0|7] ""  PC
 SG_ M2P_TMS_BackWaterPress_1 : 0|8@1+ (0.1,0) [0|25.5] "bar"  PC
 SG_ M2P_TMS_OutWaterPress_1 : 8|8@1+ (0.1,0) [0|25.5] "bar"  PC

BO_ 2337992367 M2P_LiquidInfo_11__31: 8 MBMU
 SG_ Reserved_4 : 0|3@1+ (1,0) [0|7] ""  PC
 SG_ M2P_TMS_BackWaterPress_1 : 0|8@1+ (0.1,0) [0|25.5] "bar"  PC
 SG_ M2P_TMS_OutWaterPress_1 : 8|8@1+ (0.1,0) [0|25.5] "bar"  PC

BO_ 2338057873 M2P_LiquidInfo_12__01: 8 MBMU
 SG_ M2P_TMS_BackWaterPress_2 : 0|8@1+ (0.1,0) [0|25.5] "bar"  PC
 SG_ M2P_TMS_OutWaterPress_2 : 8|8@1+ (0.1,0) [0|25.5] "bar"  PC

BO_ 2338057874 M2P_LiquidInfo_12__02: 8 MBMU
 SG_ M2P_TMS_BackWaterPress_2 : 0|8@1+ (0.1,0) [0|25.5] "bar"  PC
 SG_ M2P_TMS_OutWaterPress_2 : 8|8@1+ (0.1,0) [0|25.5] "bar"  PC

BO_ 2338057875 M2P_LiquidInfo_12__03: 8 MBMU
 SG_ M2P_TMS_BackWaterPress_2 : 0|8@1+ (0.1,0) [0|25.5] "bar"  PC
 SG_ M2P_TMS_OutWaterPress_2 : 8|8@1+ (0.1,0) [0|25.5] "bar"  PC

BO_ 2338057876 M2P_LiquidInfo_12__04: 8 MBMU
 SG_ M2P_TMS_BackWaterPress_2 : 0|8@1+ (0.1,0) [0|25.5] "bar"  PC
 SG_ M2P_TMS_OutWaterPress_2 : 8|8@1+ (0.1,0) [0|25.5] "bar"  PC

BO_ 2338057877 M2P_LiquidInfo_12__05: 8 MBMU
 SG_ M2P_TMS_BackWaterPress_2 : 0|8@1+ (0.1,0) [0|25.5] "bar"  PC
 SG_ M2P_TMS_OutWaterPress_2 : 8|8@1+ (0.1,0) [0|25.5] "bar"  PC

BO_ 2338057878 M2P_LiquidInfo_12__06: 8 MBMU
 SG_ M2P_TMS_BackWaterPress_2 : 0|8@1+ (0.1,0) [0|25.5] "bar"  PC
 SG_ M2P_TMS_OutWaterPress_2 : 8|8@1+ (0.1,0) [0|25.5] "bar"  PC

BO_ 2338057879 M2P_LiquidInfo_12__07: 8 MBMU
 SG_ M2P_TMS_BackWaterPress_2 : 0|8@1+ (0.1,0) [0|25.5] "bar"  PC
 SG_ M2P_TMS_OutWaterPress_2 : 8|8@1+ (0.1,0) [0|25.5] "bar"  PC

BO_ 2338057880 M2P_LiquidInfo_12__08: 8 MBMU
 SG_ M2P_TMS_BackWaterPress_2 : 0|8@1+ (0.1,0) [0|25.5] "bar"  PC
 SG_ M2P_TMS_OutWaterPress_2 : 8|8@1+ (0.1,0) [0|25.5] "bar"  PC

BO_ 2338057881 M2P_LiquidInfo_12__09: 8 MBMU
 SG_ M2P_TMS_BackWaterPress_2 : 0|8@1+ (0.1,0) [0|25.5] "bar"  PC
 SG_ M2P_TMS_OutWaterPress_2 : 8|8@1+ (0.1,0) [0|25.5] "bar"  PC

BO_ 2338057882 M2P_LiquidInfo_12__10: 8 MBMU
 SG_ M2P_TMS_BackWaterPress_2 : 0|8@1+ (0.1,0) [0|25.5] "bar"  PC
 SG_ M2P_TMS_OutWaterPress_2 : 8|8@1+ (0.1,0) [0|25.5] "bar"  PC

BO_ 2338057883 M2P_LiquidInfo_12__11: 8 MBMU
 SG_ M2P_TMS_BackWaterPress_2 : 0|8@1+ (0.1,0) [0|25.5] "bar"  PC
 SG_ M2P_TMS_OutWaterPress_2 : 8|8@1+ (0.1,0) [0|25.5] "bar"  PC

BO_ 2338057884 M2P_LiquidInfo_12__12: 8 MBMU
 SG_ M2P_TMS_BackWaterPress_2 : 0|8@1+ (0.1,0) [0|25.5] "bar"  PC
 SG_ M2P_TMS_OutWaterPress_2 : 8|8@1+ (0.1,0) [0|25.5] "bar"  PC

BO_ 2338057885 M2P_LiquidInfo_12__13: 8 MBMU
 SG_ M2P_TMS_BackWaterPress_2 : 0|8@1+ (0.1,0) [0|25.5] "bar"  PC
 SG_ M2P_TMS_OutWaterPress_2 : 8|8@1+ (0.1,0) [0|25.5] "bar"  PC

BO_ 2338057886 M2P_LiquidInfo_12__14: 8 MBMU
 SG_ M2P_TMS_BackWaterPress_2 : 0|8@1+ (0.1,0) [0|25.5] "bar"  PC
 SG_ M2P_TMS_OutWaterPress_2 : 8|8@1+ (0.1,0) [0|25.5] "bar"  PC

BO_ 2338057887 M2P_LiquidInfo_12__15: 8 MBMU
 SG_ M2P_TMS_BackWaterPress_2 : 0|8@1+ (0.1,0) [0|25.5] "bar"  PC
 SG_ M2P_TMS_OutWaterPress_2 : 8|8@1+ (0.1,0) [0|25.5] "bar"  PC

BO_ 2338057888 M2P_LiquidInfo_12__16: 8 MBMU
 SG_ M2P_TMS_BackWaterPress_2 : 0|8@1+ (0.1,0) [0|25.5] "bar"  PC
 SG_ M2P_TMS_OutWaterPress_2 : 8|8@1+ (0.1,0) [0|25.5] "bar"  PC

BO_ 2338057889 M2P_LiquidInfo_12__17: 8 MBMU
 SG_ M2P_TMS_BackWaterPress_2 : 0|8@1+ (0.1,0) [0|25.5] "bar"  PC
 SG_ M2P_TMS_OutWaterPress_2 : 8|8@1+ (0.1,0) [0|25.5] "bar"  PC

BO_ 2338057890 M2P_LiquidInfo_12__18: 8 MBMU
 SG_ M2P_TMS_BackWaterPress_2 : 0|8@1+ (0.1,0) [0|25.5] "bar"  PC
 SG_ M2P_TMS_OutWaterPress_2 : 8|8@1+ (0.1,0) [0|25.5] "bar"  PC

BO_ 2338057891 M2P_LiquidInfo_12__19: 8 MBMU
 SG_ M2P_TMS_BackWaterPress_2 : 0|8@1+ (0.1,0) [0|25.5] "bar"  PC
 SG_ M2P_TMS_OutWaterPress_2 : 8|8@1+ (0.1,0) [0|25.5] "bar"  PC

BO_ 2338057892 M2P_LiquidInfo_12__20: 8 MBMU
 SG_ M2P_TMS_BackWaterPress_2 : 0|8@1+ (0.1,0) [0|25.5] "bar"  PC
 SG_ M2P_TMS_OutWaterPress_2 : 8|8@1+ (0.1,0) [0|25.5] "bar"  PC

BO_ 2338057893 M2P_LiquidInfo_12__21: 8 MBMU
 SG_ M2P_TMS_BackWaterPress_2 : 0|8@1+ (0.1,0) [0|25.5] "bar"  PC
 SG_ M2P_TMS_OutWaterPress_2 : 8|8@1+ (0.1,0) [0|25.5] "bar"  PC

BO_ 2338057894 M2P_LiquidInfo_12__22: 8 MBMU
 SG_ M2P_TMS_BackWaterPress_2 : 0|8@1+ (0.1,0) [0|25.5] "bar"  PC
 SG_ M2P_TMS_OutWaterPress_2 : 8|8@1+ (0.1,0) [0|25.5] "bar"  PC

BO_ 2338057895 M2P_LiquidInfo_12__23: 8 MBMU
 SG_ M2P_TMS_BackWaterPress_2 : 0|8@1+ (0.1,0) [0|25.5] "bar"  PC
 SG_ M2P_TMS_OutWaterPress_2 : 8|8@1+ (0.1,0) [0|25.5] "bar"  PC

BO_ 2338057896 M2P_LiquidInfo_12__24: 8 MBMU
 SG_ M2P_TMS_BackWaterPress_2 : 0|8@1+ (0.1,0) [0|25.5] "bar"  PC
 SG_ M2P_TMS_OutWaterPress_2 : 8|8@1+ (0.1,0) [0|25.5] "bar"  PC

BO_ 2338057897 M2P_LiquidInfo_12__25: 8 MBMU
 SG_ M2P_TMS_BackWaterPress_2 : 0|8@1+ (0.1,0) [0|25.5] "bar"  PC
 SG_ M2P_TMS_OutWaterPress_2 : 8|8@1+ (0.1,0) [0|25.5] "bar"  PC

BO_ 2338057898 M2P_LiquidInfo_12__26: 8 MBMU
 SG_ M2P_TMS_BackWaterPress_2 : 0|8@1+ (0.1,0) [0|25.5] "bar"  PC
 SG_ M2P_TMS_OutWaterPress_2 : 8|8@1+ (0.1,0) [0|25.5] "bar"  PC

BO_ 2338057899 M2P_LiquidInfo_12__27: 8 MBMU
 SG_ M2P_TMS_BackWaterPress_2 : 0|8@1+ (0.1,0) [0|25.5] "bar"  PC
 SG_ M2P_TMS_OutWaterPress_2 : 8|8@1+ (0.1,0) [0|25.5] "bar"  PC

BO_ 2338057900 M2P_LiquidInfo_12__28: 8 MBMU
 SG_ M2P_TMS_BackWaterPress_2 : 0|8@1+ (0.1,0) [0|25.5] "bar"  PC
 SG_ M2P_TMS_OutWaterPress_2 : 8|8@1+ (0.1,0) [0|25.5] "bar"  PC

BO_ 2338057901 M2P_LiquidInfo_12__29: 8 MBMU
 SG_ M2P_TMS_BackWaterPress_2 : 0|8@1+ (0.1,0) [0|25.5] "bar"  PC
 SG_ M2P_TMS_OutWaterPress_2 : 8|8@1+ (0.1,0) [0|25.5] "bar"  PC

BO_ 2338057902 M2P_LiquidInfo_12__30: 8 MBMU
 SG_ M2P_TMS_BackWaterPress_2 : 0|8@1+ (0.1,0) [0|25.5] "bar"  PC
 SG_ M2P_TMS_OutWaterPress_2 : 8|8@1+ (0.1,0) [0|25.5] "bar"  PC

BO_ 2338057903 M2P_LiquidInfo_12__31: 8 MBMU
 SG_ M2P_TMS_BackWaterPress_2 : 0|8@1+ (0.1,0) [0|25.5] "bar"  PC
 SG_ M2P_TMS_OutWaterPress_2 : 8|8@1+ (0.1,0) [0|25.5] "bar"  PC

BO_ 2337341249 S2A_LiquidInfo_2__01: 8 SBMU
 SG_ S2A_TMS_OutWaterPress : 0|8@1+ (0.1,0) [0|25.5] "bar"  MBMU,PC
 SG_ S2A_TMS_BackWaterPress : 8|8@1+ (0.1,0) [0|25.5] "bar"  MBMU,PC

BO_ 2337341250 S2A_LiquidInfo_2__02: 8 SBMU
 SG_ S2A_TMS_OutWaterPress : 0|8@1+ (0.1,0) [0|25.5] "bar"  MBMU,PC
 SG_ S2A_TMS_BackWaterPress : 8|8@1+ (0.1,0) [0|25.5] "bar"  MBMU,PC

BO_ 2337341251 S2A_LiquidInfo_2__03: 8 SBMU
 SG_ S2A_TMS_OutWaterPress : 0|8@1+ (0.1,0) [0|25.5] "bar"  MBMU,PC
 SG_ S2A_TMS_BackWaterPress : 8|8@1+ (0.1,0) [0|25.5] "bar"  MBMU,PC

BO_ 2337341252 S2A_LiquidInfo_2__04: 8 SBMU
 SG_ S2A_TMS_OutWaterPress : 0|8@1+ (0.1,0) [0|25.5] "bar"  MBMU,PC
 SG_ S2A_TMS_BackWaterPress : 8|8@1+ (0.1,0) [0|25.5] "bar"  MBMU,PC

BO_ 2337341253 S2A_LiquidInfo_2__05: 8 SBMU
 SG_ S2A_TMS_OutWaterPress : 0|8@1+ (0.1,0) [0|25.5] "bar"  MBMU,PC
 SG_ S2A_TMS_BackWaterPress : 8|8@1+ (0.1,0) [0|25.5] "bar"  MBMU,PC

BO_ 2337341254 S2A_LiquidInfo_2__06: 8 SBMU
 SG_ S2A_TMS_OutWaterPress : 0|8@1+ (0.1,0) [0|25.5] "bar"  MBMU,PC
 SG_ S2A_TMS_BackWaterPress : 8|8@1+ (0.1,0) [0|25.5] "bar"  MBMU,PC

BO_ 2337341255 S2A_LiquidInfo_2__07: 8 SBMU
 SG_ S2A_TMS_OutWaterPress : 0|8@1+ (0.1,0) [0|25.5] "bar"  MBMU,PC
 SG_ S2A_TMS_BackWaterPress : 8|8@1+ (0.1,0) [0|25.5] "bar"  MBMU,PC

BO_ 2337341256 S2A_LiquidInfo_2__08: 8 SBMU
 SG_ S2A_TMS_OutWaterPress : 0|8@1+ (0.1,0) [0|25.5] "bar"  MBMU,PC
 SG_ S2A_TMS_BackWaterPress : 8|8@1+ (0.1,0) [0|25.5] "bar"  MBMU,PC

BO_ 2337341257 S2A_LiquidInfo_2__09: 8 SBMU
 SG_ S2A_TMS_OutWaterPress : 0|8@1+ (0.1,0) [0|25.5] "bar"  MBMU,PC
 SG_ S2A_TMS_BackWaterPress : 8|8@1+ (0.1,0) [0|25.5] "bar"  MBMU,PC

BO_ 2337341258 S2A_LiquidInfo_2__10: 8 SBMU
 SG_ S2A_TMS_OutWaterPress : 0|8@1+ (0.1,0) [0|25.5] "bar"  MBMU,PC
 SG_ S2A_TMS_BackWaterPress : 8|8@1+ (0.1,0) [0|25.5] "bar"  MBMU,PC

BO_ 2337341259 S2A_LiquidInfo_2__11: 8 SBMU
 SG_ S2A_TMS_OutWaterPress : 0|8@1+ (0.1,0) [0|25.5] "bar"  MBMU,PC
 SG_ S2A_TMS_BackWaterPress : 8|8@1+ (0.1,0) [0|25.5] "bar"  MBMU,PC

BO_ 2337341260 S2A_LiquidInfo_2__12: 8 SBMU
 SG_ S2A_TMS_OutWaterPress : 0|8@1+ (0.1,0) [0|25.5] "bar"  MBMU,PC
 SG_ S2A_TMS_BackWaterPress : 8|8@1+ (0.1,0) [0|25.5] "bar"  MBMU,PC

BO_ 2337341261 S2A_LiquidInfo_2__13: 8 SBMU
 SG_ S2A_TMS_OutWaterPress : 0|8@1+ (0.1,0) [0|25.5] "bar"  MBMU,PC
 SG_ S2A_TMS_BackWaterPress : 8|8@1+ (0.1,0) [0|25.5] "bar"  MBMU,PC

BO_ 2337341262 S2A_LiquidInfo_2__14: 8 SBMU
 SG_ S2A_TMS_OutWaterPress : 0|8@1+ (0.1,0) [0|25.5] "bar"  MBMU,PC
 SG_ S2A_TMS_BackWaterPress : 8|8@1+ (0.1,0) [0|25.5] "bar"  MBMU,PC

BO_ 2337341263 S2A_LiquidInfo_2__15: 8 SBMU
 SG_ S2A_TMS_OutWaterPress : 0|8@1+ (0.1,0) [0|25.5] "bar"  MBMU,PC
 SG_ S2A_TMS_BackWaterPress : 8|8@1+ (0.1,0) [0|25.5] "bar"  MBMU,PC

BO_ 2337341264 S2A_LiquidInfo_2__16: 8 SBMU
 SG_ S2A_TMS_OutWaterPress : 0|8@1+ (0.1,0) [0|25.5] "bar"  MBMU,PC
 SG_ S2A_TMS_BackWaterPress : 8|8@1+ (0.1,0) [0|25.5] "bar"  MBMU,PC

BO_ 2337341265 S2A_LiquidInfo_2__17: 8 SBMU
 SG_ S2A_TMS_OutWaterPress : 0|8@1+ (0.1,0) [0|25.5] "bar"  MBMU,PC
 SG_ S2A_TMS_BackWaterPress : 8|8@1+ (0.1,0) [0|25.5] "bar"  MBMU,PC

BO_ 2337341266 S2A_LiquidInfo_2__18: 8 SBMU
 SG_ S2A_TMS_OutWaterPress : 0|8@1+ (0.1,0) [0|25.5] "bar"  MBMU,PC
 SG_ S2A_TMS_BackWaterPress : 8|8@1+ (0.1,0) [0|25.5] "bar"  MBMU,PC

BO_ 2337341267 S2A_LiquidInfo_2__19: 8 SBMU
 SG_ S2A_TMS_OutWaterPress : 0|8@1+ (0.1,0) [0|25.5] "bar"  MBMU,PC
 SG_ S2A_TMS_BackWaterPress : 8|8@1+ (0.1,0) [0|25.5] "bar"  MBMU,PC

BO_ 2337341268 S2A_LiquidInfo_2__20: 8 SBMU
 SG_ S2A_TMS_OutWaterPress : 0|8@1+ (0.1,0) [0|25.5] "bar"  MBMU,PC
 SG_ S2A_TMS_BackWaterPress : 8|8@1+ (0.1,0) [0|25.5] "bar"  MBMU,PC

BO_ 2337341269 S2A_LiquidInfo_2__21: 8 SBMU
 SG_ S2A_TMS_OutWaterPress : 0|8@1+ (0.1,0) [0|25.5] "bar"  MBMU,PC
 SG_ S2A_TMS_BackWaterPress : 8|8@1+ (0.1,0) [0|25.5] "bar"  MBMU,PC

BO_ 2337341270 S2A_LiquidInfo_2__22: 8 SBMU
 SG_ S2A_TMS_OutWaterPress : 0|8@1+ (0.1,0) [0|25.5] "bar"  MBMU,PC
 SG_ S2A_TMS_BackWaterPress : 8|8@1+ (0.1,0) [0|25.5] "bar"  MBMU,PC

BO_ 2337341271 S2A_LiquidInfo_2__23: 8 SBMU
 SG_ S2A_TMS_OutWaterPress : 0|8@1+ (0.1,0) [0|25.5] "bar"  MBMU,PC
 SG_ S2A_TMS_BackWaterPress : 8|8@1+ (0.1,0) [0|25.5] "bar"  MBMU,PC

BO_ 2337341272 S2A_LiquidInfo_2__24: 8 SBMU
 SG_ S2A_TMS_OutWaterPress : 0|8@1+ (0.1,0) [0|25.5] "bar"  MBMU,PC
 SG_ S2A_TMS_BackWaterPress : 8|8@1+ (0.1,0) [0|25.5] "bar"  MBMU,PC

BO_ 2337341273 S2A_LiquidInfo_2__25: 8 SBMU
 SG_ S2A_TMS_OutWaterPress : 0|8@1+ (0.1,0) [0|25.5] "bar"  MBMU,PC
 SG_ S2A_TMS_BackWaterPress : 8|8@1+ (0.1,0) [0|25.5] "bar"  MBMU,PC

BO_ 2337341274 S2A_LiquidInfo_2__26: 8 SBMU
 SG_ S2A_TMS_OutWaterPress : 0|8@1+ (0.1,0) [0|25.5] "bar"  MBMU,PC
 SG_ S2A_TMS_BackWaterPress : 8|8@1+ (0.1,0) [0|25.5] "bar"  MBMU,PC

BO_ 2337341275 S2A_LiquidInfo_2__27: 8 SBMU
 SG_ S2A_TMS_OutWaterPress : 0|8@1+ (0.1,0) [0|25.5] "bar"  MBMU,PC
 SG_ S2A_TMS_BackWaterPress : 8|8@1+ (0.1,0) [0|25.5] "bar"  MBMU,PC

BO_ 2337341276 S2A_LiquidInfo_2__28: 8 SBMU
 SG_ S2A_TMS_OutWaterPress : 0|8@1+ (0.1,0) [0|25.5] "bar"  MBMU,PC
 SG_ S2A_TMS_BackWaterPress : 8|8@1+ (0.1,0) [0|25.5] "bar"  MBMU,PC

BO_ 2337341277 S2A_LiquidInfo_2__29: 8 SBMU
 SG_ S2A_TMS_OutWaterPress : 0|8@1+ (0.1,0) [0|25.5] "bar"  MBMU,PC
 SG_ S2A_TMS_BackWaterPress : 8|8@1+ (0.1,0) [0|25.5] "bar"  MBMU,PC

BO_ 2337341278 S2A_LiquidInfo_2__30: 8 SBMU
 SG_ S2A_TMS_OutWaterPress : 0|8@1+ (0.1,0) [0|25.5] "bar"  MBMU,PC
 SG_ S2A_TMS_BackWaterPress : 8|8@1+ (0.1,0) [0|25.5] "bar"  MBMU,PC

BO_ 2337341279 S2A_LiquidInfo_2__31: 8 SBMU
 SG_ S2A_TMS_OutWaterPress : 0|8@1+ (0.1,0) [0|25.5] "bar"  MBMU,PC
 SG_ S2A_TMS_BackWaterPress : 8|8@1+ (0.1,0) [0|25.5] "bar"  MBMU,PC

BO_ 2337341280 S2A_LiquidInfo_2__32: 8 SBMU
 SG_ S2A_TMS_OutWaterPress : 0|8@1+ (0.1,0) [0|25.5] "bar"  MBMU,PC
 SG_ S2A_TMS_BackWaterPress : 8|8@1+ (0.1,0) [0|25.5] "bar"  MBMU,PC

BO_ 2337341281 S2A_LiquidInfo_2__33: 8 SBMU
 SG_ S2A_TMS_OutWaterPress : 0|8@1+ (0.1,0) [0|25.5] "bar"  MBMU,PC
 SG_ S2A_TMS_BackWaterPress : 8|8@1+ (0.1,0) [0|25.5] "bar"  MBMU,PC

BO_ 2337341282 S2A_LiquidInfo_2__34: 8 SBMU
 SG_ S2A_TMS_OutWaterPress : 0|8@1+ (0.1,0) [0|25.5] "bar"  MBMU,PC
 SG_ S2A_TMS_BackWaterPress : 8|8@1+ (0.1,0) [0|25.5] "bar"  MBMU,PC

BO_ 2337341283 S2A_LiquidInfo_2__35: 8 SBMU
 SG_ S2A_TMS_OutWaterPress : 0|8@1+ (0.1,0) [0|25.5] "bar"  MBMU,PC
 SG_ S2A_TMS_BackWaterPress : 8|8@1+ (0.1,0) [0|25.5] "bar"  MBMU,PC

BO_ 2337341284 S2A_LiquidInfo_2__36: 8 SBMU
 SG_ S2A_TMS_OutWaterPress : 0|8@1+ (0.1,0) [0|25.5] "bar"  MBMU,PC
 SG_ S2A_TMS_BackWaterPress : 8|8@1+ (0.1,0) [0|25.5] "bar"  MBMU,PC

BO_ 2337341285 S2A_LiquidInfo_2__37: 8 SBMU
 SG_ S2A_TMS_OutWaterPress : 0|8@1+ (0.1,0) [0|25.5] "bar"  MBMU,PC
 SG_ S2A_TMS_BackWaterPress : 8|8@1+ (0.1,0) [0|25.5] "bar"  MBMU,PC

BO_ 2337341286 S2A_LiquidInfo_2__38: 8 SBMU
 SG_ S2A_TMS_OutWaterPress : 0|8@1+ (0.1,0) [0|25.5] "bar"  MBMU,PC
 SG_ S2A_TMS_BackWaterPress : 8|8@1+ (0.1,0) [0|25.5] "bar"  MBMU,PC

BO_ 2337341287 S2A_LiquidInfo_2__39: 8 SBMU
 SG_ S2A_TMS_OutWaterPress : 0|8@1+ (0.1,0) [0|25.5] "bar"  MBMU,PC
 SG_ S2A_TMS_BackWaterPress : 8|8@1+ (0.1,0) [0|25.5] "bar"  MBMU,PC

BO_ 2337341288 S2A_LiquidInfo_2__40: 8 SBMU
 SG_ S2A_TMS_OutWaterPress : 0|8@1+ (0.1,0) [0|25.5] "bar"  MBMU,PC
 SG_ S2A_TMS_BackWaterPress : 8|8@1+ (0.1,0) [0|25.5] "bar"  MBMU,PC

BO_ 2337341289 S2A_LiquidInfo_2__41: 8 SBMU
 SG_ S2A_TMS_OutWaterPress : 0|8@1+ (0.1,0) [0|25.5] "bar"  MBMU,PC
 SG_ S2A_TMS_BackWaterPress : 8|8@1+ (0.1,0) [0|25.5] "bar"  MBMU,PC

BO_ 2337341290 S2A_LiquidInfo_2__42: 8 SBMU
 SG_ S2A_TMS_OutWaterPress : 0|8@1+ (0.1,0) [0|25.5] "bar"  MBMU,PC
 SG_ S2A_TMS_BackWaterPress : 8|8@1+ (0.1,0) [0|25.5] "bar"  MBMU,PC

BO_ 2337341291 S2A_LiquidInfo_2__43: 8 SBMU
 SG_ S2A_TMS_OutWaterPress : 0|8@1+ (0.1,0) [0|25.5] "bar"  MBMU,PC
 SG_ S2A_TMS_BackWaterPress : 8|8@1+ (0.1,0) [0|25.5] "bar"  MBMU,PC

BO_ 2337341292 S2A_LiquidInfo_2__44: 8 SBMU
 SG_ S2A_TMS_OutWaterPress : 0|8@1+ (0.1,0) [0|25.5] "bar"  MBMU,PC
 SG_ S2A_TMS_BackWaterPress : 8|8@1+ (0.1,0) [0|25.5] "bar"  MBMU,PC

BO_ 2337341293 S2A_LiquidInfo_2__45: 8 SBMU
 SG_ S2A_TMS_OutWaterPress : 0|8@1+ (0.1,0) [0|25.5] "bar"  MBMU,PC
 SG_ S2A_TMS_BackWaterPress : 8|8@1+ (0.1,0) [0|25.5] "bar"  MBMU,PC

BO_ 2337341294 S2A_LiquidInfo_2__46: 8 SBMU
 SG_ S2A_TMS_OutWaterPress : 0|8@1+ (0.1,0) [0|25.5] "bar"  MBMU,PC
 SG_ S2A_TMS_BackWaterPress : 8|8@1+ (0.1,0) [0|25.5] "bar"  MBMU,PC

BO_ 2337341295 S2A_LiquidInfo_2__47: 8 SBMU
 SG_ S2A_TMS_OutWaterPress : 0|8@1+ (0.1,0) [0|25.5] "bar"  MBMU,PC
 SG_ S2A_TMS_BackWaterPress : 8|8@1+ (0.1,0) [0|25.5] "bar"  MBMU,PC

BO_ 2337341296 S2A_LiquidInfo_2__48: 8 SBMU
 SG_ S2A_TMS_OutWaterPress : 0|8@1+ (0.1,0) [0|25.5] "bar"  MBMU,PC
 SG_ S2A_TMS_BackWaterPress : 8|8@1+ (0.1,0) [0|25.5] "bar"  MBMU,PC

BO_ 2337341297 S2A_LiquidInfo_2__49: 8 SBMU
 SG_ S2A_TMS_OutWaterPress : 0|8@1+ (0.1,0) [0|25.5] "bar"  MBMU,PC
 SG_ S2A_TMS_BackWaterPress : 8|8@1+ (0.1,0) [0|25.5] "bar"  MBMU,PC

BO_ 2337341298 S2A_LiquidInfo_2__50: 8 SBMU
 SG_ S2A_TMS_OutWaterPress : 0|8@1+ (0.1,0) [0|25.5] "bar"  MBMU,PC
 SG_ S2A_TMS_BackWaterPress : 8|8@1+ (0.1,0) [0|25.5] "bar"  MBMU,PC

BO_ 2337341299 S2A_LiquidInfo_2__51: 8 SBMU
 SG_ S2A_TMS_OutWaterPress : 0|8@1+ (0.1,0) [0|25.5] "bar"  MBMU,PC
 SG_ S2A_TMS_BackWaterPress : 8|8@1+ (0.1,0) [0|25.5] "bar"  MBMU,PC

BO_ 2337341300 S2A_LiquidInfo_2__52: 8 SBMU
 SG_ S2A_TMS_OutWaterPress : 0|8@1+ (0.1,0) [0|25.5] "bar"  MBMU,PC
 SG_ S2A_TMS_BackWaterPress : 8|8@1+ (0.1,0) [0|25.5] "bar"  MBMU,PC

BO_ 2337341301 S2A_LiquidInfo_2__53: 8 SBMU
 SG_ S2A_TMS_OutWaterPress : 0|8@1+ (0.1,0) [0|25.5] "bar"  MBMU,PC
 SG_ S2A_TMS_BackWaterPress : 8|8@1+ (0.1,0) [0|25.5] "bar"  MBMU,PC

BO_ 2337341302 S2A_LiquidInfo_2__54: 8 SBMU
 SG_ S2A_TMS_OutWaterPress : 0|8@1+ (0.1,0) [0|25.5] "bar"  MBMU,PC
 SG_ S2A_TMS_BackWaterPress : 8|8@1+ (0.1,0) [0|25.5] "bar"  MBMU,PC

BO_ 2337341303 S2A_LiquidInfo_2__55: 8 SBMU
 SG_ S2A_TMS_OutWaterPress : 0|8@1+ (0.1,0) [0|25.5] "bar"  MBMU,PC
 SG_ S2A_TMS_BackWaterPress : 8|8@1+ (0.1,0) [0|25.5] "bar"  MBMU,PC

BO_ 2337341304 S2A_LiquidInfo_2__56: 8 SBMU
 SG_ S2A_TMS_OutWaterPress : 0|8@1+ (0.1,0) [0|25.5] "bar"  MBMU,PC
 SG_ S2A_TMS_BackWaterPress : 8|8@1+ (0.1,0) [0|25.5] "bar"  MBMU,PC

BO_ 2337341305 S2A_LiquidInfo_2__57: 8 SBMU
 SG_ S2A_TMS_OutWaterPress : 0|8@1+ (0.1,0) [0|25.5] "bar"  MBMU,PC
 SG_ S2A_TMS_BackWaterPress : 8|8@1+ (0.1,0) [0|25.5] "bar"  MBMU,PC

BO_ 2337341306 S2A_LiquidInfo_2__58: 8 SBMU
 SG_ S2A_TMS_OutWaterPress : 0|8@1+ (0.1,0) [0|25.5] "bar"  MBMU,PC
 SG_ S2A_TMS_BackWaterPress : 8|8@1+ (0.1,0) [0|25.5] "bar"  MBMU,PC

BO_ 2337341307 S2A_LiquidInfo_2__59: 8 SBMU
 SG_ S2A_TMS_OutWaterPress : 0|8@1+ (0.1,0) [0|25.5] "bar"  MBMU,PC
 SG_ S2A_TMS_BackWaterPress : 8|8@1+ (0.1,0) [0|25.5] "bar"  MBMU,PC

BO_ 2337341308 S2A_LiquidInfo_2__60: 8 SBMU
 SG_ S2A_TMS_OutWaterPress : 0|8@1+ (0.1,0) [0|25.5] "bar"  MBMU,PC
 SG_ S2A_TMS_BackWaterPress : 8|8@1+ (0.1,0) [0|25.5] "bar"  MBMU,PC

BO_ 2337341309 S2A_LiquidInfo_2__61: 8 SBMU
 SG_ S2A_TMS_OutWaterPress : 0|8@1+ (0.1,0) [0|25.5] "bar"  MBMU,PC
 SG_ S2A_TMS_BackWaterPress : 8|8@1+ (0.1,0) [0|25.5] "bar"  MBMU,PC

BO_ 2337341310 S2A_LiquidInfo_2__62: 8 SBMU
 SG_ S2A_TMS_OutWaterPress : 0|8@1+ (0.1,0) [0|25.5] "bar"  MBMU,PC
 SG_ S2A_TMS_BackWaterPress : 8|8@1+ (0.1,0) [0|25.5] "bar"  MBMU,PC

BO_ 2337341311 S2A_LiquidInfo_2__63: 8 SBMU
 SG_ S2A_TMS_OutWaterPress : 0|8@1+ (0.1,0) [0|25.5] "bar"  MBMU,PC
 SG_ S2A_TMS_BackWaterPress : 8|8@1+ (0.1,0) [0|25.5] "bar"  MBMU,PC

BO_ 2334588737 S2A_SUMDATA26__01: 8 SBMU
 SG_ S2A_IMMEncodeFlgFromSBMU_01 : 0|1@1+ (1,0) [0|1] ""  MBMU

BO_ 2334588738 S2A_SUMDATA26__02: 8 SBMU
 SG_ S2A_IMMEncodeFlgFromSBMU_02 : 0|1@1+ (1,0) [0|1] ""  MBMU

BO_ 2334588739 S2A_SUMDATA26__03: 8 SBMU
 SG_ S2A_IMMEncodeFlgFromSBMU_03 : 0|1@1+ (1,0) [0|1] ""  MBMU

BO_ 2334588740 S2A_SUMDATA26__04: 8 SBMU
 SG_ S2A_IMMEncodeFlgFromSBMU_04 : 0|1@1+ (1,0) [0|1] ""  MBMU

BO_ 2334588741 S2A_SUMDATA26__05: 8 SBMU
 SG_ S2A_IMMEncodeFlgFromSBMU_05 : 0|1@1+ (1,0) [0|1] ""  MBMU

BO_ 2334588742 S2A_SUMDATA26__06: 8 SBMU
 SG_ S2A_IMMEncodeFlgFromSBMU_06 : 0|1@1+ (1,0) [0|1] ""  MBMU

BO_ 2334588743 S2A_SUMDATA26__07: 8 SBMU
 SG_ S2A_IMMEncodeFlgFromSBMU_07 : 0|1@1+ (1,0) [0|1] ""  MBMU

BO_ 2334588744 S2A_SUMDATA26__08: 8 SBMU
 SG_ S2A_IMMEncodeFlgFromSBMU_08 : 0|1@1+ (1,0) [0|1] ""  MBMU

BO_ 2334588745 S2A_SUMDATA26__09: 8 SBMU
 SG_ S2A_IMMEncodeFlgFromSBMU_09 : 0|1@1+ (1,0) [0|1] ""  MBMU

BO_ 2334588746 S2A_SUMDATA26__10: 8 SBMU
 SG_ S2A_IMMEncodeFlgFromSBMU_10 : 0|1@1+ (1,0) [0|1] ""  MBMU

BO_ 2334588747 S2A_SUMDATA26__11: 8 SBMU
 SG_ S2A_IMMEncodeFlgFromSBMU_11 : 0|1@1+ (1,0) [0|1] ""  MBMU

BO_ 2334588748 S2A_SUMDATA26__12: 8 SBMU
 SG_ S2A_IMMEncodeFlgFromSBMU_12 : 0|1@1+ (1,0) [0|1] ""  MBMU

BO_ 2334588749 S2A_SUMDATA26__13: 8 SBMU
 SG_ S2A_IMMEncodeFlgFromSBMU_13 : 0|1@1+ (1,0) [0|1] ""  MBMU

BO_ 2334588750 S2A_SUMDATA26__14: 8 SBMU
 SG_ S2A_IMMEncodeFlgFromSBMU_14 : 0|1@1+ (1,0) [0|1] ""  MBMU

BO_ 2334588751 S2A_SUMDATA26__15: 8 SBMU
 SG_ S2A_IMMEncodeFlgFromSBMU_15 : 0|1@1+ (1,0) [0|1] ""  MBMU

BO_ 2334588752 S2A_SUMDATA26__16: 8 SBMU
 SG_ S2A_IMMEncodeFlgFromSBMU_16 : 0|1@1+ (1,0) [0|1] ""  MBMU

BO_ 2334588753 S2A_SUMDATA26__17: 8 SBMU
 SG_ S2A_IMMEncodeFlgFromSBMU_17 : 0|1@1+ (1,0) [0|1] ""  MBMU

BO_ 2334588754 S2A_SUMDATA26__18: 8 SBMU
 SG_ S2A_IMMEncodeFlgFromSBMU_18 : 0|1@1+ (1,0) [0|1] ""  MBMU

BO_ 2334588755 S2A_SUMDATA26__19: 8 SBMU
 SG_ S2A_IMMEncodeFlgFromSBMU_19 : 0|1@1+ (1,0) [0|1] ""  MBMU

BO_ 2334588756 S2A_SUMDATA26__20: 8 SBMU
 SG_ S2A_IMMEncodeFlgFromSBMU_20 : 0|1@1+ (1,0) [0|1] ""  MBMU

BO_ 2334588757 S2A_SUMDATA26__21: 8 SBMU
 SG_ S2A_IMMEncodeFlgFromSBMU_21 : 0|1@1+ (1,0) [0|1] ""  MBMU

BO_ 2334588758 S2A_SUMDATA26__22: 8 SBMU
 SG_ S2A_IMMEncodeFlgFromSBMU_22 : 0|1@1+ (1,0) [0|1] ""  MBMU

BO_ 2334588759 S2A_SUMDATA26__23: 8 SBMU
 SG_ S2A_IMMEncodeFlgFromSBMU_23 : 0|1@1+ (1,0) [0|1] ""  MBMU

BO_ 2334588760 S2A_SUMDATA26__24: 8 SBMU
 SG_ S2A_IMMEncodeFlgFromSBMU_24 : 0|1@1+ (1,0) [0|1] ""  MBMU

BO_ 2334588761 S2A_SUMDATA26__25: 8 SBMU
 SG_ S2A_IMMEncodeFlgFromSBMU_25 : 0|1@1+ (1,0) [0|1] ""  MBMU

BO_ 2334588762 S2A_SUMDATA26__26: 8 SBMU
 SG_ S2A_IMMEncodeFlgFromSBMU_26 : 0|1@1+ (1,0) [0|1] ""  MBMU

BO_ 2334588763 S2A_SUMDATA26__27: 8 SBMU
 SG_ S2A_IMMEncodeFlgFromSBMU_27 : 0|1@1+ (1,0) [0|1] ""  MBMU

BO_ 2334588764 S2A_SUMDATA26__28: 8 SBMU
 SG_ S2A_IMMEncodeFlgFromSBMU_28 : 0|1@1+ (1,0) [0|1] ""  MBMU

BO_ 2334588765 S2A_SUMDATA26__29: 8 SBMU
 SG_ S2A_IMMEncodeFlgFromSBMU_29 : 0|1@1+ (1,0) [0|1] ""  MBMU

BO_ 2334588766 S2A_SUMDATA26__30: 8 SBMU
 SG_ S2A_IMMEncodeFlgFromSBMU_30 : 0|1@1+ (1,0) [0|1] ""  MBMU

BO_ 2334588767 S2A_SUMDATA26__31: 8 SBMU
 SG_ S2A_IMMEncodeFlgFromSBMU_31 : 0|1@1+ (1,0) [0|1] ""  MBMU

BO_ 2334588768 S2A_SUMDATA26__32: 8 SBMU
 SG_ S2A_IMMEncodeFlgFromSBMU_32 : 0|1@1+ (1,0) [0|1] ""  MBMU

BO_ 2334588769 S2A_SUMDATA26__33: 8 SBMU
 SG_ S2A_IMMEncodeFlgFromSBMU_33 : 0|1@1+ (1,0) [0|1] ""  MBMU

BO_ 2334588770 S2A_SUMDATA26__34: 8 SBMU
 SG_ S2A_IMMEncodeFlgFromSBMU_34 : 0|1@1+ (1,0) [0|1] ""  MBMU

BO_ 2334588771 S2A_SUMDATA26__35: 8 SBMU
 SG_ S2A_IMMEncodeFlgFromSBMU_35 : 0|1@1+ (1,0) [0|1] ""  MBMU

BO_ 2334588772 S2A_SUMDATA26__36: 8 SBMU
 SG_ S2A_IMMEncodeFlgFromSBMU_36 : 0|1@1+ (1,0) [0|1] ""  MBMU

BO_ 2334588773 S2A_SUMDATA26__37: 8 SBMU
 SG_ S2A_IMMEncodeFlgFromSBMU_37 : 0|1@1+ (1,0) [0|1] ""  MBMU

BO_ 2334588774 S2A_SUMDATA26__38: 8 SBMU
 SG_ S2A_IMMEncodeFlgFromSBMU_38 : 0|1@1+ (1,0) [0|1] ""  MBMU

BO_ 2334588775 S2A_SUMDATA26__39: 8 SBMU
 SG_ S2A_IMMEncodeFlgFromSBMU_39 : 0|1@1+ (1,0) [0|1] ""  MBMU

BO_ 2334588776 S2A_SUMDATA26__40: 8 SBMU
 SG_ S2A_IMMEncodeFlgFromSBMU_40 : 0|1@1+ (1,0) [0|1] ""  MBMU

BO_ 2334588777 S2A_SUMDATA26__41: 8 SBMU
 SG_ S2A_IMMEncodeFlgFromSBMU_41 : 0|1@1+ (1,0) [0|1] ""  MBMU

BO_ 2334588778 S2A_SUMDATA26__42: 8 SBMU
 SG_ S2A_IMMEncodeFlgFromSBMU_42 : 0|1@1+ (1,0) [0|1] ""  MBMU

BO_ 2334588779 S2A_SUMDATA26__43: 8 SBMU
 SG_ S2A_IMMEncodeFlgFromSBMU_43 : 0|1@1+ (1,0) [0|1] ""  MBMU

BO_ 2334588780 S2A_SUMDATA26__44: 8 SBMU
 SG_ S2A_IMMEncodeFlgFromSBMU_44 : 0|1@1+ (1,0) [0|1] ""  MBMU

BO_ 2334588781 S2A_SUMDATA26__45: 8 SBMU
 SG_ S2A_IMMEncodeFlgFromSBMU_45 : 0|1@1+ (1,0) [0|1] ""  MBMU

BO_ 2334588782 S2A_SUMDATA26__46: 8 SBMU
 SG_ S2A_IMMEncodeFlgFromSBMU_46 : 0|1@1+ (1,0) [0|1] ""  MBMU

BO_ 2334588783 S2A_SUMDATA26__47: 8 SBMU
 SG_ S2A_IMMEncodeFlgFromSBMU_47 : 0|1@1+ (1,0) [0|1] ""  MBMU

BO_ 2334588784 S2A_SUMDATA26__48: 8 SBMU
 SG_ S2A_IMMEncodeFlgFromSBMU_48 : 0|1@1+ (1,0) [0|1] ""  MBMU

BO_ 2334588785 S2A_SUMDATA26__49: 8 SBMU
 SG_ S2A_IMMEncodeFlgFromSBMU_49 : 0|1@1+ (1,0) [0|1] ""  MBMU

BO_ 2334588786 S2A_SUMDATA26__50: 8 SBMU
 SG_ S2A_IMMEncodeFlgFromSBMU_50 : 0|1@1+ (1,0) [0|1] ""  MBMU

BO_ 2334588787 S2A_SUMDATA26__51: 8 SBMU
 SG_ S2A_IMMEncodeFlgFromSBMU_51 : 0|1@1+ (1,0) [0|1] ""  MBMU

BO_ 2334588788 S2A_SUMDATA26__52: 8 SBMU
 SG_ S2A_IMMEncodeFlgFromSBMU_52 : 0|1@1+ (1,0) [0|1] ""  MBMU

BO_ 2334588789 S2A_SUMDATA26__53: 8 SBMU
 SG_ S2A_IMMEncodeFlgFromSBMU_53 : 0|1@1+ (1,0) [0|1] ""  MBMU

BO_ 2334588790 S2A_SUMDATA26__54: 8 SBMU
 SG_ S2A_IMMEncodeFlgFromSBMU_54 : 0|1@1+ (1,0) [0|1] ""  MBMU

BO_ 2334588791 S2A_SUMDATA26__55: 8 SBMU
 SG_ S2A_IMMEncodeFlgFromSBMU_55 : 0|1@1+ (1,0) [0|1] ""  MBMU

BO_ 2334588792 S2A_SUMDATA26__56: 8 SBMU
 SG_ S2A_IMMEncodeFlgFromSBMU_56 : 0|1@1+ (1,0) [0|1] ""  MBMU

BO_ 2334588793 S2A_SUMDATA26__57: 8 SBMU
 SG_ S2A_IMMEncodeFlgFromSBMU_57 : 0|1@1+ (1,0) [0|1] ""  MBMU

BO_ 2334588794 S2A_SUMDATA26__58: 8 SBMU
 SG_ S2A_IMMEncodeFlgFromSBMU_58 : 0|1@1+ (1,0) [0|1] ""  MBMU

BO_ 2334588795 S2A_SUMDATA26__59: 8 SBMU
 SG_ S2A_IMMEncodeFlgFromSBMU_59 : 0|1@1+ (1,0) [0|1] ""  MBMU

BO_ 2334588796 S2A_SUMDATA26__60: 8 SBMU
 SG_ S2A_IMMEncodeFlgFromSBMU_60 : 0|1@1+ (1,0) [0|1] ""  MBMU

BO_ 2334588797 S2A_SUMDATA26__61: 8 SBMU
 SG_ S2A_IMMEncodeFlgFromSBMU_61 : 0|1@1+ (1,0) [0|1] ""  MBMU

BO_ 2334588798 S2A_SUMDATA26__62: 8 SBMU
 SG_ S2A_IMMEncodeFlgFromSBMU_62 : 0|1@1+ (1,0) [0|1] ""  MBMU

BO_ 2334588799 S2A_SUMDATA26__63: 8 SBMU
 SG_ S2A_IMMEncodeFlgFromSBMU_63 : 0|1@1+ (1,0) [0|1] ""  MBMU

BO_ 2467467183 M2S_IMMIndex: 8 MBMU
 SG_ M2S_IMMCode_State : 0|1@1+ (1,0) [0|1] ""  SBMU
 SG_ M2S_IMMIndexPower_SBMUAddr : 1|6@1+ (1,0) [0|63] ""  SBMU

CM_ SG_ 2337861290 M2P_TMS_L_25_CP1_vol_26 "1号TMS压缩机2电压(25kw)";
CM_ SG_ 2337861290 M2P_TMS_L_25_CP1_I_26 "1号TMS压缩机2电流(25kw)";
CM_ SG_ 2337861290 M2P_TMS_L_25_CP1_r_26 "1号TMS压缩机2转速(25kw)";
CM_ SG_ 2337861290 Reserved_4 "保留";
CM_ SG_ 2337861290 M2P_TMS_L_25_fan_fault_26 "1号TMS风机故障(25kw)";
CM_ SG_ 2337861290 M2P_TMS_L_25_fre_fault_26 "1号TMS AC2故障(25kw变频器)";
CM_ SG_ 2337861290 M2P_TMS_L_25_D_fault_26 "1号TMS AC2故障(25kwDC/DC)";
CM_ SG_ 2337861290 M2P_TMS_L_AC2_25_P_26 "1号TMS AC2低压压力值(25kw)";
CM_ SG_ 2337861291 M2P_TMS_L_25_CP1_vol_27 "1号TMS压缩机2电压(25kw)";
CM_ SG_ 2337861291 M2P_TMS_L_25_CP1_I_27 "1号TMS压缩机2电流(25kw)";
CM_ SG_ 2337861291 M2P_TMS_L_25_CP1_r_27 "1号TMS压缩机2转速(25kw)";
CM_ SG_ 2337861291 Reserved_4 "保留";
CM_ SG_ 2337861291 M2P_TMS_L_25_fan_fault_27 "1号TMS风机故障(25kw)";
CM_ SG_ 2337861291 M2P_TMS_L_25_fre_fault_27 "1号TMS AC2故障(25kw变频器)";
CM_ SG_ 2337861291 M2P_TMS_L_25_D_fault_27 "1号TMS AC2故障(25kwDC/DC)";
CM_ SG_ 2337861291 M2P_TMS_L_AC2_25_P_27 "1号TMS AC2低压压力值(25kw)";
CM_ SG_ 2337861292 M2P_TMS_L_25_CP1_vol_28 "1号TMS压缩机2电压(25kw)";
CM_ SG_ 2337861292 M2P_TMS_L_25_CP1_I_28 "1号TMS压缩机2电流(25kw)";
CM_ SG_ 2337861292 M2P_TMS_L_25_CP1_r_28 "1号TMS压缩机2转速(25kw)";
CM_ SG_ 2337861292 Reserved_4 "保留";
CM_ SG_ 2337861292 M2P_TMS_L_25_fan_fault_28 "1号TMS风机故障(25kw)";
CM_ SG_ 2337861292 M2P_TMS_L_25_fre_fault_28 "1号TMS AC2故障(25kw变频器)";
CM_ SG_ 2337861292 M2P_TMS_L_25_D_fault_28 "1号TMS AC2故障(25kwDC/DC)";
CM_ SG_ 2337861292 M2P_TMS_L_AC2_25_P_28 "1号TMS AC2低压压力值(25kw)";
CM_ SG_ 2337861293 M2P_TMS_L_25_CP1_vol_29 "1号TMS压缩机2电压(25kw)";
CM_ SG_ 2337861293 M2P_TMS_L_25_CP1_I_29 "1号TMS压缩机2电流(25kw)";
CM_ SG_ 2337861293 M2P_TMS_L_25_CP1_r_29 "1号TMS压缩机2转速(25kw)";
CM_ SG_ 2337861293 Reserved_4 "保留";
CM_ SG_ 2337861293 M2P_TMS_L_25_fan_fault_29 "1号TMS风机故障(25kw)";
CM_ SG_ 2337861293 M2P_TMS_L_25_fre_fault_29 "1号TMS AC2故障(25kw变频器)";
CM_ SG_ 2337861293 M2P_TMS_L_25_D_fault_29 "1号TMS AC2故障(25kwDC/DC)";
CM_ SG_ 2337861293 M2P_TMS_L_AC2_25_P_29 "1号TMS AC2低压压力值(25kw)";
CM_ SG_ 2337861294 M2P_TMS_L_25_CP1_vol_30 "1号TMS压缩机2电压(25kw)";
CM_ SG_ 2337861294 M2P_TMS_L_25_CP1_I_30 "1号TMS压缩机2电流(25kw)";
CM_ SG_ 2337861294 M2P_TMS_L_25_CP1_r_30 "1号TMS压缩机2转速(25kw)";
CM_ SG_ 2337861294 Reserved_4 "保留";
CM_ SG_ 2337861294 M2P_TMS_L_25_fan_fault_30 "1号TMS风机故障(25kw)";
CM_ SG_ 2337861294 M2P_TMS_L_25_fre_fault_30 "1号TMS AC2故障(25kw变频器)";
CM_ SG_ 2337861294 M2P_TMS_L_25_D_fault_30 "1号TMS AC2故障(25kwDC/DC)";
CM_ SG_ 2337861294 M2P_TMS_L_AC2_25_P_30 "1号TMS AC2低压压力值(25kw)";
CM_ SG_ 2337861295 M2P_TMS_L_25_CP1_vol_31 "1号TMS压缩机2电压(25kw)";
CM_ SG_ 2337861295 M2P_TMS_L_25_CP1_I_31 "1号TMS压缩机2电流(25kw)";
CM_ SG_ 2337861295 M2P_TMS_L_25_CP1_r_31 "1号TMS压缩机2转速(25kw)";
CM_ SG_ 2337861295 Reserved_4 "保留";
CM_ SG_ 2337861295 M2P_TMS_L_25_fan_fault_31 "1号TMS风机故障(25kw)";
CM_ SG_ 2337861295 M2P_TMS_L_25_fre_fault_31 "1号TMS AC2故障(25kw变频器)";
CM_ SG_ 2337861295 M2P_TMS_L_25_D_fault_31 "1号TMS AC2故障(25kwDC/DC)";
CM_ SG_ 2337861295 M2P_TMS_L_AC2_25_P_31 "1号TMS AC2低压压力值(25kw)";
CM_ SG_ 2337926801 M2P_TMS_L_S_version_01 "1号TMS 对应机组的软件号";
CM_ SG_ 2337926801 M2P_TMS_L_N_S_version_01 "1号TMS 对应机组更新的软件版本号";
CM_ SG_ 2337926802 M2P_TMS_L_S_version_02 "1号TMS 对应机组的软件号";
CM_ SG_ 2337926802 M2P_TMS_L_N_S_version_02 "1号TMS 对应机组更新的软件版本号";
CM_ SG_ 2337926803 M2P_TMS_L_S_version_03 "1号TMS 对应机组的软件号";
CM_ SG_ 2337926803 M2P_TMS_L_N_S_version_03 "1号TMS 对应机组更新的软件版本号";
CM_ SG_ 2337926804 M2P_TMS_L_S_version_04 "1号TMS 对应机组的软件号";
CM_ SG_ 2337926804 M2P_TMS_L_N_S_version_04 "1号TMS 对应机组更新的软件版本号";
CM_ SG_ 2337926805 M2P_TMS_L_S_version_05 "1号TMS 对应机组的软件号";
CM_ SG_ 2337926805 M2P_TMS_L_N_S_version_05 "1号TMS 对应机组更新的软件版本号";
CM_ SG_ 2337926806 M2P_TMS_L_S_version_06 "1号TMS 对应机组的软件号";
CM_ SG_ 2337926806 M2P_TMS_L_N_S_version_06 "1号TMS 对应机组更新的软件版本号";
CM_ SG_ 2337926807 M2P_TMS_L_S_version_07 "1号TMS 对应机组的软件号";
CM_ SG_ 2337926807 M2P_TMS_L_N_S_version_07 "1号TMS 对应机组更新的软件版本号";
CM_ SG_ 2337926808 M2P_TMS_L_S_version_08 "1号TMS 对应机组的软件号";
CM_ SG_ 2337926808 M2P_TMS_L_N_S_version_08 "1号TMS 对应机组更新的软件版本号";
CM_ SG_ 2337926809 M2P_TMS_L_S_version_09 "1号TMS 对应机组的软件号";
CM_ SG_ 2337926809 M2P_TMS_L_N_S_version_09 "1号TMS 对应机组更新的软件版本号";
CM_ SG_ 2337926810 M2P_TMS_L_S_version_10 "1号TMS 对应机组的软件号";
CM_ SG_ 2337926810 M2P_TMS_L_N_S_version_10 "1号TMS 对应机组更新的软件版本号";
CM_ SG_ 2337926811 M2P_TMS_L_S_version_11 "1号TMS 对应机组的软件号";
CM_ SG_ 2337926811 M2P_TMS_L_N_S_version_11 "1号TMS 对应机组更新的软件版本号";
CM_ SG_ 2337926812 M2P_TMS_L_S_version_12 "1号TMS 对应机组的软件号";
CM_ SG_ 2337926812 M2P_TMS_L_N_S_version_12 "1号TMS 对应机组更新的软件版本号";
CM_ SG_ 2337926813 M2P_TMS_L_S_version_13 "1号TMS 对应机组的软件号";
CM_ SG_ 2337926813 M2P_TMS_L_N_S_version_13 "1号TMS 对应机组更新的软件版本号";
CM_ SG_ 2337926814 M2P_TMS_L_S_version_14 "1号TMS 对应机组的软件号";
CM_ SG_ 2337926814 M2P_TMS_L_N_S_version_14 "1号TMS 对应机组更新的软件版本号";
CM_ SG_ 2337926815 M2P_TMS_L_S_version_15 "1号TMS 对应机组的软件号";
CM_ SG_ 2337926815 M2P_TMS_L_N_S_version_15 "1号TMS 对应机组更新的软件版本号";
CM_ SG_ 2337926816 M2P_TMS_L_S_version_16 "1号TMS 对应机组的软件号";
CM_ SG_ 2337926816 M2P_TMS_L_N_S_version_16 "1号TMS 对应机组更新的软件版本号";
CM_ SG_ 2337926817 M2P_TMS_L_S_version_17 "1号TMS 对应机组的软件号";
CM_ SG_ 2337926817 M2P_TMS_L_N_S_version_17 "1号TMS 对应机组更新的软件版本号";
CM_ SG_ 2337926818 M2P_TMS_L_S_version_18 "1号TMS 对应机组的软件号";
CM_ SG_ 2337926818 M2P_TMS_L_N_S_version_18 "1号TMS 对应机组更新的软件版本号";
CM_ SG_ 2337926819 M2P_TMS_L_S_version_19 "1号TMS 对应机组的软件号";
CM_ SG_ 2337926819 M2P_TMS_L_N_S_version_19 "1号TMS 对应机组更新的软件版本号";
CM_ SG_ 2337926820 M2P_TMS_L_S_version_20 "1号TMS 对应机组的软件号";
CM_ SG_ 2337926820 M2P_TMS_L_N_S_version_20 "1号TMS 对应机组更新的软件版本号";
CM_ SG_ 2337926821 M2P_TMS_L_S_version_21 "1号TMS 对应机组的软件号";
CM_ SG_ 2337926821 M2P_TMS_L_N_S_version_21 "1号TMS 对应机组更新的软件版本号";
CM_ SG_ 2337926822 M2P_TMS_L_S_version_22 "1号TMS 对应机组的软件号";
CM_ SG_ 2337926822 M2P_TMS_L_N_S_version_22 "1号TMS 对应机组更新的软件版本号";
CM_ SG_ 2337926823 M2P_TMS_L_S_version_23 "1号TMS 对应机组的软件号";
CM_ SG_ 2337926823 M2P_TMS_L_N_S_version_23 "1号TMS 对应机组更新的软件版本号";
CM_ SG_ 2337926824 M2P_TMS_L_S_version_24 "1号TMS 对应机组的软件号";
CM_ SG_ 2337926824 M2P_TMS_L_N_S_version_24 "1号TMS 对应机组更新的软件版本号";
CM_ SG_ 2337926825 M2P_TMS_L_S_version_25 "1号TMS 对应机组的软件号";
CM_ SG_ 2337926825 M2P_TMS_L_N_S_version_25 "1号TMS 对应机组更新的软件版本号";
CM_ SG_ 2337926826 M2P_TMS_L_S_version_26 "1号TMS 对应机组的软件号";
CM_ SG_ 2337926826 M2P_TMS_L_N_S_version_26 "1号TMS 对应机组更新的软件版本号";
CM_ SG_ 2337926827 M2P_TMS_L_S_version_27 "1号TMS 对应机组的软件号";
CM_ SG_ 2337926827 M2P_TMS_L_N_S_version_27 "1号TMS 对应机组更新的软件版本号";
CM_ SG_ 2337926828 M2P_TMS_L_S_version_28 "1号TMS 对应机组的软件号";
CM_ SG_ 2337926828 M2P_TMS_L_N_S_version_28 "1号TMS 对应机组更新的软件版本号";
CM_ SG_ 2337926829 M2P_TMS_L_S_version_29 "1号TMS 对应机组的软件号";
CM_ SG_ 2337926829 M2P_TMS_L_N_S_version_29 "1号TMS 对应机组更新的软件版本号";
CM_ SG_ 2337926830 M2P_TMS_L_S_version_30 "1号TMS 对应机组的软件号";
CM_ SG_ 2337926830 M2P_TMS_L_N_S_version_30 "1号TMS 对应机组更新的软件版本号";
CM_ SG_ 2337926831 M2P_TMS_L_S_version_31 "1号TMS 对应机组的软件号";
CM_ SG_ 2337926831 M2P_TMS_L_N_S_version_31 "1号TMS 对应机组更新的软件版本号";
CM_ SG_ 2333146945 S2A_TotalCapacityAccumul_01 "温度折合后的累计吞吐容量(EaHIST_HisAccumCapAh)";
CM_ SG_ 2333146945 S2A_HisTotalLifeTime_01 "历史存储时间(EcHIST_HisTotalLifeTime)";
CM_ SG_ 2333146946 S2A_TotalCapacityAccumul_02 "温度折合后的累计吞吐容量(EaHIST_HisAccumCapAh)";
CM_ SG_ 2333146946 S2A_HisTotalLifeTime_02 "历史存储时间(EcHIST_HisTotalLifeTime)";
CM_ SG_ 2333146947 S2A_TotalCapacityAccumul_03 "温度折合后的累计吞吐容量(EaHIST_HisAccumCapAh)";
CM_ SG_ 2333146947 S2A_HisTotalLifeTime_03 "历史存储时间(EcHIST_HisTotalLifeTime)";
CM_ SG_ 2333146948 S2A_TotalCapacityAccumul_04 "温度折合后的累计吞吐容量(EaHIST_HisAccumCapAh)";
CM_ SG_ 2333146948 S2A_HisTotalLifeTime_04 "历史存储时间(EcHIST_HisTotalLifeTime)";
CM_ SG_ 2333146949 S2A_TotalCapacityAccumul_05 "温度折合后的累计吞吐容量(EaHIST_HisAccumCapAh)";
CM_ SG_ 2333146949 S2A_HisTotalLifeTime_05 "历史存储时间(EcHIST_HisTotalLifeTime)";
CM_ SG_ 2333146950 S2A_TotalCapacityAccumul_06 "温度折合后的累计吞吐容量(EaHIST_HisAccumCapAh)";
CM_ SG_ 2333146950 S2A_HisTotalLifeTime_06 "历史存储时间(EcHIST_HisTotalLifeTime)";
CM_ SG_ 2333146951 S2A_TotalCapacityAccumul_07 "温度折合后的累计吞吐容量(EaHIST_HisAccumCapAh)";
CM_ SG_ 2333146951 S2A_HisTotalLifeTime_07 "历史存储时间(EcHIST_HisTotalLifeTime)";
CM_ SG_ 2333146952 S2A_TotalCapacityAccumul_08 "温度折合后的累计吞吐容量(EaHIST_HisAccumCapAh)";
CM_ SG_ 2333146952 S2A_HisTotalLifeTime_08 "历史存储时间(EcHIST_HisTotalLifeTime)";
CM_ SG_ 2333146953 S2A_TotalCapacityAccumul_09 "温度折合后的累计吞吐容量(EaHIST_HisAccumCapAh)";
CM_ SG_ 2333146953 S2A_HisTotalLifeTime_09 "历史存储时间(EcHIST_HisTotalLifeTime)";
CM_ SG_ 2333146954 S2A_TotalCapacityAccumul_10 "温度折合后的累计吞吐容量(EaHIST_HisAccumCapAh)";
CM_ SG_ 2333146954 S2A_HisTotalLifeTime_10 "历史存储时间(EcHIST_HisTotalLifeTime)";
CM_ SG_ 2333146955 S2A_TotalCapacityAccumul_11 "温度折合后的累计吞吐容量(EaHIST_HisAccumCapAh)";
CM_ SG_ 2333146955 S2A_HisTotalLifeTime_11 "历史存储时间(EcHIST_HisTotalLifeTime)";
CM_ SG_ 2333146956 S2A_TotalCapacityAccumul_12 "温度折合后的累计吞吐容量(EaHIST_HisAccumCapAh)";
CM_ SG_ 2333146956 S2A_HisTotalLifeTime_12 "历史存储时间(EcHIST_HisTotalLifeTime)";
CM_ SG_ 2333146957 S2A_TotalCapacityAccumul_13 "温度折合后的累计吞吐容量(EaHIST_HisAccumCapAh)";
CM_ SG_ 2333146957 S2A_HisTotalLifeTime_13 "历史存储时间(EcHIST_HisTotalLifeTime)";
CM_ SG_ 2333146958 S2A_TotalCapacityAccumul_14 "温度折合后的累计吞吐容量(EaHIST_HisAccumCapAh)";
CM_ SG_ 2333146958 S2A_HisTotalLifeTime_14 "历史存储时间(EcHIST_HisTotalLifeTime)";
CM_ SG_ 2333146959 S2A_TotalCapacityAccumul_15 "温度折合后的累计吞吐容量(EaHIST_HisAccumCapAh)";
CM_ SG_ 2333146959 S2A_HisTotalLifeTime_15 "历史存储时间(EcHIST_HisTotalLifeTime)";
CM_ SG_ 2333146960 S2A_TotalCapacityAccumul_16 "温度折合后的累计吞吐容量(EaHIST_HisAccumCapAh)";
CM_ SG_ 2333146960 S2A_HisTotalLifeTime_16 "历史存储时间(EcHIST_HisTotalLifeTime)";
CM_ SG_ 2333146961 S2A_TotalCapacityAccumul_17 "温度折合后的累计吞吐容量(EaHIST_HisAccumCapAh)";
CM_ SG_ 2333146961 S2A_HisTotalLifeTime_17 "历史存储时间(EcHIST_HisTotalLifeTime)";
CM_ SG_ 2333146962 S2A_TotalCapacityAccumul_18 "温度折合后的累计吞吐容量(EaHIST_HisAccumCapAh)";
CM_ SG_ 2333146962 S2A_HisTotalLifeTime_18 "历史存储时间(EcHIST_HisTotalLifeTime)";
CM_ SG_ 2333146963 S2A_TotalCapacityAccumul_19 "温度折合后的累计吞吐容量(EaHIST_HisAccumCapAh)";
CM_ SG_ 2333146963 S2A_HisTotalLifeTime_19 "历史存储时间(EcHIST_HisTotalLifeTime)";
CM_ SG_ 2333146964 S2A_TotalCapacityAccumul_20 "温度折合后的累计吞吐容量(EaHIST_HisAccumCapAh)";
CM_ SG_ 2333146964 S2A_HisTotalLifeTime_20 "历史存储时间(EcHIST_HisTotalLifeTime)";
CM_ SG_ 2333146965 S2A_TotalCapacityAccumul_21 "温度折合后的累计吞吐容量(EaHIST_HisAccumCapAh)";
CM_ SG_ 2333146965 S2A_HisTotalLifeTime_21 "历史存储时间(EcHIST_HisTotalLifeTime)";
CM_ SG_ 2333146966 S2A_TotalCapacityAccumul_22 "温度折合后的累计吞吐容量(EaHIST_HisAccumCapAh)";
CM_ SG_ 2333146966 S2A_HisTotalLifeTime_22 "历史存储时间(EcHIST_HisTotalLifeTime)";
CM_ SG_ 2333146967 S2A_TotalCapacityAccumul_23 "温度折合后的累计吞吐容量(EaHIST_HisAccumCapAh)";
CM_ SG_ 2333146967 S2A_HisTotalLifeTime_23 "历史存储时间(EcHIST_HisTotalLifeTime)";
CM_ SG_ 2333146968 S2A_TotalCapacityAccumul_24 "温度折合后的累计吞吐容量(EaHIST_HisAccumCapAh)";
CM_ SG_ 2333146968 S2A_HisTotalLifeTime_24 "历史存储时间(EcHIST_HisTotalLifeTime)";
CM_ SG_ 2333146969 S2A_TotalCapacityAccumul_25 "温度折合后的累计吞吐容量(EaHIST_HisAccumCapAh)";
CM_ SG_ 2333146969 S2A_HisTotalLifeTime_25 "历史存储时间(EcHIST_HisTotalLifeTime)";
CM_ SG_ 2333146970 S2A_TotalCapacityAccumul_26 "温度折合后的累计吞吐容量(EaHIST_HisAccumCapAh)";
CM_ SG_ 2333146970 S2A_HisTotalLifeTime_26 "历史存储时间(EcHIST_HisTotalLifeTime)";
CM_ SG_ 2333146971 S2A_TotalCapacityAccumul_27 "温度折合后的累计吞吐容量(EaHIST_HisAccumCapAh)";
CM_ SG_ 2333146971 S2A_HisTotalLifeTime_27 "历史存储时间(EcHIST_HisTotalLifeTime)";
CM_ SG_ 2333146972 S2A_TotalCapacityAccumul_28 "温度折合后的累计吞吐容量(EaHIST_HisAccumCapAh)";
CM_ SG_ 2333146972 S2A_HisTotalLifeTime_28 "历史存储时间(EcHIST_HisTotalLifeTime)";
CM_ SG_ 2333146973 S2A_TotalCapacityAccumul_29 "温度折合后的累计吞吐容量(EaHIST_HisAccumCapAh)";
CM_ SG_ 2333146973 S2A_HisTotalLifeTime_29 "历史存储时间(EcHIST_HisTotalLifeTime)";
CM_ SG_ 2333146974 S2A_TotalCapacityAccumul_30 "温度折合后的累计吞吐容量(EaHIST_HisAccumCapAh)";
CM_ SG_ 2333146974 S2A_HisTotalLifeTime_30 "历史存储时间(EcHIST_HisTotalLifeTime)";
CM_ SG_ 2333146975 S2A_TotalCapacityAccumul_31 "温度折合后的累计吞吐容量(EaHIST_HisAccumCapAh)";
CM_ SG_ 2333146975 S2A_HisTotalLifeTime_31 "历史存储时间(EcHIST_HisTotalLifeTime)";
CM_ SG_ 2333146976 S2A_TotalCapacityAccumul_32 "温度折合后的累计吞吐容量(EaHIST_HisAccumCapAh)";
CM_ SG_ 2333146976 S2A_HisTotalLifeTime_32 "历史存储时间(EcHIST_HisTotalLifeTime)";
CM_ SG_ 2333146977 S2A_TotalCapacityAccumul_33 "温度折合后的累计吞吐容量(EaHIST_HisAccumCapAh)";
CM_ SG_ 2333146977 S2A_HisTotalLifeTime_33 "历史存储时间(EcHIST_HisTotalLifeTime)";
CM_ SG_ 2333146978 S2A_TotalCapacityAccumul_34 "温度折合后的累计吞吐容量(EaHIST_HisAccumCapAh)";
CM_ SG_ 2333146978 S2A_HisTotalLifeTime_34 "历史存储时间(EcHIST_HisTotalLifeTime)";
CM_ SG_ 2333146979 S2A_TotalCapacityAccumul_35 "温度折合后的累计吞吐容量(EaHIST_HisAccumCapAh)";
CM_ SG_ 2333146979 S2A_HisTotalLifeTime_35 "历史存储时间(EcHIST_HisTotalLifeTime)";
CM_ SG_ 2333146980 S2A_TotalCapacityAccumul_36 "温度折合后的累计吞吐容量(EaHIST_HisAccumCapAh)";
CM_ SG_ 2333146980 S2A_HisTotalLifeTime_36 "历史存储时间(EcHIST_HisTotalLifeTime)";
CM_ SG_ 2333146981 S2A_TotalCapacityAccumul_37 "温度折合后的累计吞吐容量(EaHIST_HisAccumCapAh)";
CM_ SG_ 2333146981 S2A_HisTotalLifeTime_37 "历史存储时间(EcHIST_HisTotalLifeTime)";
CM_ SG_ 2333146982 S2A_TotalCapacityAccumul_38 "温度折合后的累计吞吐容量(EaHIST_HisAccumCapAh)";
CM_ SG_ 2333146982 S2A_HisTotalLifeTime_38 "历史存储时间(EcHIST_HisTotalLifeTime)";
CM_ SG_ 2333146983 S2A_TotalCapacityAccumul_39 "温度折合后的累计吞吐容量(EaHIST_HisAccumCapAh)";
CM_ SG_ 2333146983 S2A_HisTotalLifeTime_39 "历史存储时间(EcHIST_HisTotalLifeTime)";
CM_ SG_ 2333146984 S2A_TotalCapacityAccumul_40 "温度折合后的累计吞吐容量(EaHIST_HisAccumCapAh)";
CM_ SG_ 2333146984 S2A_HisTotalLifeTime_40 "历史存储时间(EcHIST_HisTotalLifeTime)";
CM_ SG_ 2333146985 S2A_TotalCapacityAccumul_41 "温度折合后的累计吞吐容量(EaHIST_HisAccumCapAh)";
CM_ SG_ 2333146985 S2A_HisTotalLifeTime_41 "历史存储时间(EcHIST_HisTotalLifeTime)";
CM_ SG_ 2333146986 S2A_TotalCapacityAccumul_42 "温度折合后的累计吞吐容量(EaHIST_HisAccumCapAh)";
CM_ SG_ 2333146986 S2A_HisTotalLifeTime_42 "历史存储时间(EcHIST_HisTotalLifeTime)";
CM_ SG_ 2333146987 S2A_TotalCapacityAccumul_43 "温度折合后的累计吞吐容量(EaHIST_HisAccumCapAh)";
CM_ SG_ 2333146987 S2A_HisTotalLifeTime_43 "历史存储时间(EcHIST_HisTotalLifeTime)";
CM_ SG_ 2333146988 S2A_TotalCapacityAccumul_44 "温度折合后的累计吞吐容量(EaHIST_HisAccumCapAh)";
CM_ SG_ 2333146988 S2A_HisTotalLifeTime_44 "历史存储时间(EcHIST_HisTotalLifeTime)";
CM_ SG_ 2333146989 S2A_TotalCapacityAccumul_45 "温度折合后的累计吞吐容量(EaHIST_HisAccumCapAh)";
CM_ SG_ 2333146989 S2A_HisTotalLifeTime_45 "历史存储时间(EcHIST_HisTotalLifeTime)";
CM_ SG_ 2333146990 S2A_TotalCapacityAccumul_46 "温度折合后的累计吞吐容量(EaHIST_HisAccumCapAh)";
CM_ SG_ 2333146990 S2A_HisTotalLifeTime_46 "历史存储时间(EcHIST_HisTotalLifeTime)";
CM_ SG_ 2333146991 S2A_TotalCapacityAccumul_47 "温度折合后的累计吞吐容量(EaHIST_HisAccumCapAh)";
CM_ SG_ 2333146991 S2A_HisTotalLifeTime_47 "历史存储时间(EcHIST_HisTotalLifeTime)";
CM_ SG_ 2333146992 S2A_TotalCapacityAccumul_48 "温度折合后的累计吞吐容量(EaHIST_HisAccumCapAh)";
CM_ SG_ 2333146992 S2A_HisTotalLifeTime_48 "历史存储时间(EcHIST_HisTotalLifeTime)";
CM_ SG_ 2333146993 S2A_TotalCapacityAccumul_49 "温度折合后的累计吞吐容量(EaHIST_HisAccumCapAh)";
CM_ SG_ 2333146993 S2A_HisTotalLifeTime_49 "历史存储时间(EcHIST_HisTotalLifeTime)";
CM_ SG_ 2333146994 S2A_TotalCapacityAccumul_50 "温度折合后的累计吞吐容量(EaHIST_HisAccumCapAh)";
CM_ SG_ 2333146994 S2A_HisTotalLifeTime_50 "历史存储时间(EcHIST_HisTotalLifeTime)";
CM_ SG_ 2333146995 S2A_TotalCapacityAccumul_51 "温度折合后的累计吞吐容量(EaHIST_HisAccumCapAh)";
CM_ SG_ 2333146995 S2A_HisTotalLifeTime_51 "历史存储时间(EcHIST_HisTotalLifeTime)";
CM_ SG_ 2333146996 S2A_TotalCapacityAccumul_52 "温度折合后的累计吞吐容量(EaHIST_HisAccumCapAh)";
CM_ SG_ 2333146996 S2A_HisTotalLifeTime_52 "历史存储时间(EcHIST_HisTotalLifeTime)";
CM_ SG_ 2333146997 S2A_TotalCapacityAccumul_53 "温度折合后的累计吞吐容量(EaHIST_HisAccumCapAh)";
CM_ SG_ 2333146997 S2A_HisTotalLifeTime_53 "历史存储时间(EcHIST_HisTotalLifeTime)";
CM_ SG_ 2333146998 S2A_TotalCapacityAccumul_54 "温度折合后的累计吞吐容量(EaHIST_HisAccumCapAh)";
CM_ SG_ 2333146998 S2A_HisTotalLifeTime_54 "历史存储时间(EcHIST_HisTotalLifeTime)";
CM_ SG_ 2333146999 S2A_TotalCapacityAccumul_55 "温度折合后的累计吞吐容量(EaHIST_HisAccumCapAh)";
CM_ SG_ 2333146999 S2A_HisTotalLifeTime_55 "历史存储时间(EcHIST_HisTotalLifeTime)";
CM_ SG_ 2333147000 S2A_TotalCapacityAccumul_56 "温度折合后的累计吞吐容量(EaHIST_HisAccumCapAh)";
CM_ SG_ 2333147000 S2A_HisTotalLifeTime_56 "历史存储时间(EcHIST_HisTotalLifeTime)";
CM_ SG_ 2333147001 S2A_TotalCapacityAccumul_57 "温度折合后的累计吞吐容量(EaHIST_HisAccumCapAh)";
CM_ SG_ 2333147001 S2A_HisTotalLifeTime_57 "历史存储时间(EcHIST_HisTotalLifeTime)";
CM_ SG_ 2333147002 S2A_TotalCapacityAccumul_58 "温度折合后的累计吞吐容量(EaHIST_HisAccumCapAh)";
CM_ SG_ 2333147002 S2A_HisTotalLifeTime_58 "历史存储时间(EcHIST_HisTotalLifeTime)";
CM_ SG_ 2333147003 S2A_TotalCapacityAccumul_59 "温度折合后的累计吞吐容量(EaHIST_HisAccumCapAh)";
CM_ SG_ 2333147003 S2A_HisTotalLifeTime_59 "历史存储时间(EcHIST_HisTotalLifeTime)";
CM_ SG_ 2333147004 S2A_TotalCapacityAccumul_60 "温度折合后的累计吞吐容量(EaHIST_HisAccumCapAh)";
CM_ SG_ 2333147004 S2A_HisTotalLifeTime_60 "历史存储时间(EcHIST_HisTotalLifeTime)";
CM_ SG_ 2333147005 S2A_TotalCapacityAccumul_61 "温度折合后的累计吞吐容量(EaHIST_HisAccumCapAh)";
CM_ SG_ 2333147005 S2A_HisTotalLifeTime_61 "历史存储时间(EcHIST_HisTotalLifeTime)";
CM_ SG_ 2333147006 S2A_TotalCapacityAccumul_62 "温度折合后的累计吞吐容量(EaHIST_HisAccumCapAh)";
CM_ SG_ 2333147006 S2A_HisTotalLifeTime_62 "历史存储时间(EcHIST_HisTotalLifeTime)";
CM_ SG_ 2333147007 S2A_TotalCapacityAccumul_63 "温度折合后的累计吞吐容量(EaHIST_HisAccumCapAh)";
CM_ SG_ 2333147007 S2A_HisTotalLifeTime_63 "历史存储时间(EcHIST_HisTotalLifeTime)";
CM_ SG_ 2334523201 S2A_HisTotalStoreLifeTime_01 "温度折合后的累计存储时间(EaHIST_HisTotalStoreLifeTime)";
CM_ SG_ 2334523202 S2A_HisTotalStoreLifeTime_02 "温度折合后的累计存储时间(EaHIST_HisTotalStoreLifeTime)";
CM_ SG_ 2334523203 S2A_HisTotalStoreLifeTime_03 "温度折合后的累计存储时间(EaHIST_HisTotalStoreLifeTime)";
CM_ SG_ 2334523204 S2A_HisTotalStoreLifeTime_04 "温度折合后的累计存储时间(EaHIST_HisTotalStoreLifeTime)";
CM_ SG_ 2334523205 S2A_HisTotalStoreLifeTime_05 "温度折合后的累计存储时间(EaHIST_HisTotalStoreLifeTime)";
CM_ SG_ 2334523206 S2A_HisTotalStoreLifeTime_06 "温度折合后的累计存储时间(EaHIST_HisTotalStoreLifeTime)";
CM_ SG_ 2334523207 S2A_HisTotalStoreLifeTime_07 "温度折合后的累计存储时间(EaHIST_HisTotalStoreLifeTime)";
CM_ SG_ 2334523208 S2A_HisTotalStoreLifeTime_08 "温度折合后的累计存储时间(EaHIST_HisTotalStoreLifeTime)";
CM_ SG_ 2334523209 S2A_HisTotalStoreLifeTime_09 "温度折合后的累计存储时间(EaHIST_HisTotalStoreLifeTime)";
CM_ SG_ 2334523210 S2A_HisTotalStoreLifeTime_10 "温度折合后的累计存储时间(EaHIST_HisTotalStoreLifeTime)";
CM_ SG_ 2334523211 S2A_HisTotalStoreLifeTime_11 "温度折合后的累计存储时间(EaHIST_HisTotalStoreLifeTime)";
CM_ SG_ 2334523212 S2A_HisTotalStoreLifeTime_12 "温度折合后的累计存储时间(EaHIST_HisTotalStoreLifeTime)";
CM_ SG_ 2334523213 S2A_HisTotalStoreLifeTime_13 "温度折合后的累计存储时间(EaHIST_HisTotalStoreLifeTime)";
CM_ SG_ 2334523214 S2A_HisTotalStoreLifeTime_14 "温度折合后的累计存储时间(EaHIST_HisTotalStoreLifeTime)";
CM_ SG_ 2334523215 S2A_HisTotalStoreLifeTime_15 "温度折合后的累计存储时间(EaHIST_HisTotalStoreLifeTime)";
CM_ SG_ 2334523216 S2A_HisTotalStoreLifeTime_16 "温度折合后的累计存储时间(EaHIST_HisTotalStoreLifeTime)";
CM_ SG_ 2334523217 S2A_HisTotalStoreLifeTime_17 "温度折合后的累计存储时间(EaHIST_HisTotalStoreLifeTime)";
CM_ SG_ 2334523218 S2A_HisTotalStoreLifeTime_18 "温度折合后的累计存储时间(EaHIST_HisTotalStoreLifeTime)";
CM_ SG_ 2334523219 S2A_HisTotalStoreLifeTime_19 "温度折合后的累计存储时间(EaHIST_HisTotalStoreLifeTime)";
CM_ SG_ 2334523220 S2A_HisTotalStoreLifeTime_20 "温度折合后的累计存储时间(EaHIST_HisTotalStoreLifeTime)";
CM_ SG_ 2334523221 S2A_HisTotalStoreLifeTime_21 "温度折合后的累计存储时间(EaHIST_HisTotalStoreLifeTime)";
CM_ SG_ 2334523222 S2A_HisTotalStoreLifeTime_22 "温度折合后的累计存储时间(EaHIST_HisTotalStoreLifeTime)";
CM_ SG_ 2334523223 S2A_HisTotalStoreLifeTime_23 "温度折合后的累计存储时间(EaHIST_HisTotalStoreLifeTime)";
CM_ SG_ 2334523224 S2A_HisTotalStoreLifeTime_24 "温度折合后的累计存储时间(EaHIST_HisTotalStoreLifeTime)";
CM_ SG_ 2334523225 S2A_HisTotalStoreLifeTime_25 "温度折合后的累计存储时间(EaHIST_HisTotalStoreLifeTime)";
CM_ SG_ 2334523226 S2A_HisTotalStoreLifeTime_26 "温度折合后的累计存储时间(EaHIST_HisTotalStoreLifeTime)";
CM_ SG_ 2334523227 S2A_HisTotalStoreLifeTime_27 "温度折合后的累计存储时间(EaHIST_HisTotalStoreLifeTime)";
CM_ SG_ 2334523228 S2A_HisTotalStoreLifeTime_28 "温度折合后的累计存储时间(EaHIST_HisTotalStoreLifeTime)";
CM_ SG_ 2334523229 S2A_HisTotalStoreLifeTime_29 "温度折合后的累计存储时间(EaHIST_HisTotalStoreLifeTime)";
CM_ SG_ 2334523230 S2A_HisTotalStoreLifeTime_30 "温度折合后的累计存储时间(EaHIST_HisTotalStoreLifeTime)";
CM_ SG_ 2334523231 S2A_HisTotalStoreLifeTime_31 "温度折合后的累计存储时间(EaHIST_HisTotalStoreLifeTime)";
CM_ SG_ 2334523232 S2A_HisTotalStoreLifeTime_32 "温度折合后的累计存储时间(EaHIST_HisTotalStoreLifeTime)";
CM_ SG_ 2334523233 S2A_HisTotalStoreLifeTime_33 "温度折合后的累计存储时间(EaHIST_HisTotalStoreLifeTime)";
CM_ SG_ 2334523234 S2A_HisTotalStoreLifeTime_34 "温度折合后的累计存储时间(EaHIST_HisTotalStoreLifeTime)";
CM_ SG_ 2334523235 S2A_HisTotalStoreLifeTime_35 "温度折合后的累计存储时间(EaHIST_HisTotalStoreLifeTime)";
CM_ SG_ 2334523236 S2A_HisTotalStoreLifeTime_36 "温度折合后的累计存储时间(EaHIST_HisTotalStoreLifeTime)";
CM_ SG_ 2334523237 S2A_HisTotalStoreLifeTime_37 "温度折合后的累计存储时间(EaHIST_HisTotalStoreLifeTime)";
CM_ SG_ 2334523238 S2A_HisTotalStoreLifeTime_38 "温度折合后的累计存储时间(EaHIST_HisTotalStoreLifeTime)";
CM_ SG_ 2334523239 S2A_HisTotalStoreLifeTime_39 "温度折合后的累计存储时间(EaHIST_HisTotalStoreLifeTime)";
CM_ SG_ 2334523240 S2A_HisTotalStoreLifeTime_40 "温度折合后的累计存储时间(EaHIST_HisTotalStoreLifeTime)";
CM_ SG_ 2334523241 S2A_HisTotalStoreLifeTime_41 "温度折合后的累计存储时间(EaHIST_HisTotalStoreLifeTime)";
CM_ SG_ 2334523242 S2A_HisTotalStoreLifeTime_42 "温度折合后的累计存储时间(EaHIST_HisTotalStoreLifeTime)";
CM_ SG_ 2334523243 S2A_HisTotalStoreLifeTime_43 "温度折合后的累计存储时间(EaHIST_HisTotalStoreLifeTime)";
CM_ SG_ 2334523244 S2A_HisTotalStoreLifeTime_44 "温度折合后的累计存储时间(EaHIST_HisTotalStoreLifeTime)";
CM_ SG_ 2334523245 S2A_HisTotalStoreLifeTime_45 "温度折合后的累计存储时间(EaHIST_HisTotalStoreLifeTime)";
CM_ SG_ 2334523246 S2A_HisTotalStoreLifeTime_46 "温度折合后的累计存储时间(EaHIST_HisTotalStoreLifeTime)";
CM_ SG_ 2334523247 S2A_HisTotalStoreLifeTime_47 "温度折合后的累计存储时间(EaHIST_HisTotalStoreLifeTime)";
CM_ SG_ 2334523248 S2A_HisTotalStoreLifeTime_48 "温度折合后的累计存储时间(EaHIST_HisTotalStoreLifeTime)";
CM_ SG_ 2334523249 S2A_HisTotalStoreLifeTime_49 "温度折合后的累计存储时间(EaHIST_HisTotalStoreLifeTime)";
CM_ SG_ 2334523250 S2A_HisTotalStoreLifeTime_50 "温度折合后的累计存储时间(EaHIST_HisTotalStoreLifeTime)";
CM_ SG_ 2334523251 S2A_HisTotalStoreLifeTime_51 "温度折合后的累计存储时间(EaHIST_HisTotalStoreLifeTime)";
CM_ SG_ 2334523252 S2A_HisTotalStoreLifeTime_52 "温度折合后的累计存储时间(EaHIST_HisTotalStoreLifeTime)";
CM_ SG_ 2334523253 S2A_HisTotalStoreLifeTime_53 "温度折合后的累计存储时间(EaHIST_HisTotalStoreLifeTime)";
CM_ SG_ 2334523254 S2A_HisTotalStoreLifeTime_54 "温度折合后的累计存储时间(EaHIST_HisTotalStoreLifeTime)";
CM_ SG_ 2334523255 S2A_HisTotalStoreLifeTime_55 "温度折合后的累计存储时间(EaHIST_HisTotalStoreLifeTime)";
CM_ SG_ 2334523256 S2A_HisTotalStoreLifeTime_56 "温度折合后的累计存储时间(EaHIST_HisTotalStoreLifeTime)";
CM_ SG_ 2334523257 S2A_HisTotalStoreLifeTime_57 "温度折合后的累计存储时间(EaHIST_HisTotalStoreLifeTime)";
CM_ SG_ 2334523258 S2A_HisTotalStoreLifeTime_58 "温度折合后的累计存储时间(EaHIST_HisTotalStoreLifeTime)";
CM_ SG_ 2334523259 S2A_HisTotalStoreLifeTime_59 "温度折合后的累计存储时间(EaHIST_HisTotalStoreLifeTime)";
CM_ SG_ 2334523260 S2A_HisTotalStoreLifeTime_60 "温度折合后的累计存储时间(EaHIST_HisTotalStoreLifeTime)";
CM_ SG_ 2334523261 S2A_HisTotalStoreLifeTime_61 "温度折合后的累计存储时间(EaHIST_HisTotalStoreLifeTime)";
CM_ SG_ 2334523262 S2A_HisTotalStoreLifeTime_62 "温度折合后的累计存储时间(EaHIST_HisTotalStoreLifeTime)";
CM_ SG_ 2334523263 S2A_HisTotalStoreLifeTime_63 "温度折合后的累计存储时间(EaHIST_HisTotalStoreLifeTime)";
CM_ SG_ 2337992337 Reserved_4 "保留";
CM_ SG_ 2337992337 M2P_TMS_BackWaterPress_1 "1号TMS回水压力";
CM_ SG_ 2337992337 M2P_TMS_OutWaterPress_1 "1号TMS出水压力";
CM_ SG_ 2337992338 Reserved_4 "保留";
CM_ SG_ 2337992338 M2P_TMS_BackWaterPress_1 "1号TMS回水压力";
CM_ SG_ 2337992338 M2P_TMS_OutWaterPress_1 "1号TMS出水压力";
CM_ SG_ 2337992339 Reserved_4 "保留";
CM_ SG_ 2337992339 M2P_TMS_BackWaterPress_1 "1号TMS回水压力";
CM_ SG_ 2337992339 M2P_TMS_OutWaterPress_1 "1号TMS出水压力";
CM_ SG_ 2337992340 Reserved_4 "保留";
CM_ SG_ 2337992340 M2P_TMS_BackWaterPress_1 "1号TMS回水压力";
CM_ SG_ 2337992340 M2P_TMS_OutWaterPress_1 "1号TMS出水压力";
CM_ SG_ 2337992341 Reserved_4 "保留";
CM_ SG_ 2337992341 M2P_TMS_BackWaterPress_1 "1号TMS回水压力";
CM_ SG_ 2337992341 M2P_TMS_OutWaterPress_1 "1号TMS出水压力";
CM_ SG_ 2337992342 Reserved_4 "保留";
CM_ SG_ 2337992342 M2P_TMS_BackWaterPress_1 "1号TMS回水压力";
CM_ SG_ 2337992342 M2P_TMS_OutWaterPress_1 "1号TMS出水压力";
CM_ SG_ 2337992343 Reserved_4 "保留";
CM_ SG_ 2337992343 M2P_TMS_BackWaterPress_1 "1号TMS回水压力";
CM_ SG_ 2337992343 M2P_TMS_OutWaterPress_1 "1号TMS出水压力";
CM_ SG_ 2337992344 Reserved_4 "保留";
CM_ SG_ 2337992344 M2P_TMS_BackWaterPress_1 "1号TMS回水压力";
CM_ SG_ 2337992344 M2P_TMS_OutWaterPress_1 "1号TMS出水压力";
CM_ SG_ 2337992345 Reserved_4 "保留";
CM_ SG_ 2337992345 M2P_TMS_BackWaterPress_1 "1号TMS回水压力";
CM_ SG_ 2337992345 M2P_TMS_OutWaterPress_1 "1号TMS出水压力";
CM_ SG_ 2337992346 Reserved_4 "保留";
CM_ SG_ 2337992346 M2P_TMS_BackWaterPress_1 "1号TMS回水压力";
CM_ SG_ 2337992346 M2P_TMS_OutWaterPress_1 "1号TMS出水压力";
CM_ SG_ 2337992347 Reserved_4 "保留";
CM_ SG_ 2337992347 M2P_TMS_BackWaterPress_1 "1号TMS回水压力";
CM_ SG_ 2337992347 M2P_TMS_OutWaterPress_1 "1号TMS出水压力";
CM_ SG_ 2337992348 Reserved_4 "保留";
CM_ SG_ 2337992348 M2P_TMS_BackWaterPress_1 "1号TMS回水压力";
CM_ SG_ 2337992348 M2P_TMS_OutWaterPress_1 "1号TMS出水压力";
CM_ SG_ 2337992349 Reserved_4 "保留";
CM_ SG_ 2337992349 M2P_TMS_BackWaterPress_1 "1号TMS回水压力";
CM_ SG_ 2337992349 M2P_TMS_OutWaterPress_1 "1号TMS出水压力";
CM_ SG_ 2337992350 Reserved_4 "保留";
CM_ SG_ 2337992350 M2P_TMS_BackWaterPress_1 "1号TMS回水压力";
CM_ SG_ 2337992350 M2P_TMS_OutWaterPress_1 "1号TMS出水压力";
CM_ SG_ 2337992351 Reserved_4 "保留";
CM_ SG_ 2337992351 M2P_TMS_BackWaterPress_1 "1号TMS回水压力";
CM_ SG_ 2337992351 M2P_TMS_OutWaterPress_1 "1号TMS出水压力";
CM_ SG_ 2337992352 Reserved_4 "保留";
CM_ SG_ 2337992352 M2P_TMS_BackWaterPress_1 "1号TMS回水压力";
CM_ SG_ 2337992352 M2P_TMS_OutWaterPress_1 "1号TMS出水压力";
CM_ SG_ 2337992353 Reserved_4 "保留";
CM_ SG_ 2337992353 M2P_TMS_BackWaterPress_1 "1号TMS回水压力";
CM_ SG_ 2337992353 M2P_TMS_OutWaterPress_1 "1号TMS出水压力";
CM_ SG_ 2337992354 Reserved_4 "保留";
CM_ SG_ 2337992354 M2P_TMS_BackWaterPress_1 "1号TMS回水压力";
CM_ SG_ 2337992354 M2P_TMS_OutWaterPress_1 "1号TMS出水压力";
CM_ SG_ 2337992355 Reserved_4 "保留";
CM_ SG_ 2337992355 M2P_TMS_BackWaterPress_1 "1号TMS回水压力";
CM_ SG_ 2337992355 M2P_TMS_OutWaterPress_1 "1号TMS出水压力";
CM_ SG_ 2337992356 Reserved_4 "保留";
CM_ SG_ 2337992356 M2P_TMS_BackWaterPress_1 "1号TMS回水压力";
CM_ SG_ 2337992356 M2P_TMS_OutWaterPress_1 "1号TMS出水压力";
CM_ SG_ 2337992357 Reserved_4 "保留";
CM_ SG_ 2337992357 M2P_TMS_BackWaterPress_1 "1号TMS回水压力";
CM_ SG_ 2337992357 M2P_TMS_OutWaterPress_1 "1号TMS出水压力";
CM_ SG_ 2337992358 Reserved_4 "保留";
CM_ SG_ 2337992358 M2P_TMS_BackWaterPress_1 "1号TMS回水压力";
CM_ SG_ 2337992358 M2P_TMS_OutWaterPress_1 "1号TMS出水压力";
CM_ SG_ 2337992359 Reserved_4 "保留";
CM_ SG_ 2337992359 M2P_TMS_BackWaterPress_1 "1号TMS回水压力";
CM_ SG_ 2337992359 M2P_TMS_OutWaterPress_1 "1号TMS出水压力";
CM_ SG_ 2337992360 Reserved_4 "保留";
CM_ SG_ 2337992360 M2P_TMS_BackWaterPress_1 "1号TMS回水压力";
CM_ SG_ 2337992360 M2P_TMS_OutWaterPress_1 "1号TMS出水压力";
CM_ SG_ 2337992361 Reserved_4 "保留";
CM_ SG_ 2337992361 M2P_TMS_BackWaterPress_1 "1号TMS回水压力";
CM_ SG_ 2337992361 M2P_TMS_OutWaterPress_1 "1号TMS出水压力";
CM_ SG_ 2337992362 Reserved_4 "保留";
CM_ SG_ 2337992362 M2P_TMS_BackWaterPress_1 "1号TMS回水压力";
CM_ SG_ 2337992362 M2P_TMS_OutWaterPress_1 "1号TMS出水压力";
CM_ SG_ 2337992363 Reserved_4 "保留";
CM_ SG_ 2337992363 M2P_TMS_BackWaterPress_1 "1号TMS回水压力";
CM_ SG_ 2337992363 M2P_TMS_OutWaterPress_1 "1号TMS出水压力";
CM_ SG_ 2337992364 Reserved_4 "保留";
CM_ SG_ 2337992364 M2P_TMS_BackWaterPress_1 "1号TMS回水压力";
CM_ SG_ 2337992364 M2P_TMS_OutWaterPress_1 "1号TMS出水压力";
CM_ SG_ 2337992365 Reserved_4 "保留";
CM_ SG_ 2337992365 M2P_TMS_BackWaterPress_1 "1号TMS回水压力";
CM_ SG_ 2337992365 M2P_TMS_OutWaterPress_1 "1号TMS出水压力";
CM_ SG_ 2337992366 Reserved_4 "保留";
CM_ SG_ 2337992366 M2P_TMS_BackWaterPress_1 "1号TMS回水压力";
CM_ SG_ 2337992366 M2P_TMS_OutWaterPress_1 "1号TMS出水压力";
CM_ SG_ 2337992367 Reserved_4 "保留";
CM_ SG_ 2337992367 M2P_TMS_BackWaterPress_1 "1号TMS回水压力";
CM_ SG_ 2337992367 M2P_TMS_OutWaterPress_1 "1号TMS出水压力";
CM_ SG_ 2338057873 M2P_TMS_BackWaterPress_2 "2号TMS回水压力";
CM_ SG_ 2338057873 M2P_TMS_OutWaterPress_2 "2号TMS出水压力";
CM_ SG_ 2338057874 M2P_TMS_BackWaterPress_2 "2号TMS回水压力";
CM_ SG_ 2338057874 M2P_TMS_OutWaterPress_2 "2号TMS出水压力";
CM_ SG_ 2338057875 M2P_TMS_BackWaterPress_2 "2号TMS回水压力";
CM_ SG_ 2338057875 M2P_TMS_OutWaterPress_2 "2号TMS出水压力";
CM_ SG_ 2338057876 M2P_TMS_BackWaterPress_2 "2号TMS回水压力";
CM_ SG_ 2338057876 M2P_TMS_OutWaterPress_2 "2号TMS出水压力";
CM_ SG_ 2338057877 M2P_TMS_BackWaterPress_2 "2号TMS回水压力";
CM_ SG_ 2338057877 M2P_TMS_OutWaterPress_2 "2号TMS出水压力";
CM_ SG_ 2338057878 M2P_TMS_BackWaterPress_2 "2号TMS回水压力";
CM_ SG_ 2338057878 M2P_TMS_OutWaterPress_2 "2号TMS出水压力";
CM_ SG_ 2338057879 M2P_TMS_BackWaterPress_2 "2号TMS回水压力";
CM_ SG_ 2338057879 M2P_TMS_OutWaterPress_2 "2号TMS出水压力";
CM_ SG_ 2338057880 M2P_TMS_BackWaterPress_2 "2号TMS回水压力";
CM_ SG_ 2338057880 M2P_TMS_OutWaterPress_2 "2号TMS出水压力";
CM_ SG_ 2338057881 M2P_TMS_BackWaterPress_2 "2号TMS回水压力";
CM_ SG_ 2338057881 M2P_TMS_OutWaterPress_2 "2号TMS出水压力";
CM_ SG_ 2338057882 M2P_TMS_BackWaterPress_2 "2号TMS回水压力";
CM_ SG_ 2338057882 M2P_TMS_OutWaterPress_2 "2号TMS出水压力";
CM_ SG_ 2338057883 M2P_TMS_BackWaterPress_2 "2号TMS回水压力";
CM_ SG_ 2338057883 M2P_TMS_OutWaterPress_2 "2号TMS出水压力";
CM_ SG_ 2338057884 M2P_TMS_BackWaterPress_2 "2号TMS回水压力";
CM_ SG_ 2338057884 M2P_TMS_OutWaterPress_2 "2号TMS出水压力";
CM_ SG_ 2338057885 M2P_TMS_BackWaterPress_2 "2号TMS回水压力";
CM_ SG_ 2338057885 M2P_TMS_OutWaterPress_2 "2号TMS出水压力";
CM_ SG_ 2338057886 M2P_TMS_BackWaterPress_2 "2号TMS回水压力";
CM_ SG_ 2338057886 M2P_TMS_OutWaterPress_2 "2号TMS出水压力";
CM_ SG_ 2338057887 M2P_TMS_BackWaterPress_2 "2号TMS回水压力";
CM_ SG_ 2338057887 M2P_TMS_OutWaterPress_2 "2号TMS出水压力";
CM_ SG_ 2338057888 M2P_TMS_BackWaterPress_2 "2号TMS回水压力";
CM_ SG_ 2338057888 M2P_TMS_OutWaterPress_2 "2号TMS出水压力";
CM_ SG_ 2338057889 M2P_TMS_BackWaterPress_2 "2号TMS回水压力";
CM_ SG_ 2338057889 M2P_TMS_OutWaterPress_2 "2号TMS出水压力";
CM_ SG_ 2338057890 M2P_TMS_BackWaterPress_2 "2号TMS回水压力";
CM_ SG_ 2338057890 M2P_TMS_OutWaterPress_2 "2号TMS出水压力";
CM_ SG_ 2338057891 M2P_TMS_BackWaterPress_2 "2号TMS回水压力";
CM_ SG_ 2338057891 M2P_TMS_OutWaterPress_2 "2号TMS出水压力";
CM_ SG_ 2338057892 M2P_TMS_BackWaterPress_2 "2号TMS回水压力";
CM_ SG_ 2338057892 M2P_TMS_OutWaterPress_2 "2号TMS出水压力";
CM_ SG_ 2338057893 M2P_TMS_BackWaterPress_2 "2号TMS回水压力";
CM_ SG_ 2338057893 M2P_TMS_OutWaterPress_2 "2号TMS出水压力";
CM_ SG_ 2338057894 M2P_TMS_BackWaterPress_2 "2号TMS回水压力";
CM_ SG_ 2338057894 M2P_TMS_OutWaterPress_2 "2号TMS出水压力";
CM_ SG_ 2338057895 M2P_TMS_BackWaterPress_2 "2号TMS回水压力";
CM_ SG_ 2338057895 M2P_TMS_OutWaterPress_2 "2号TMS出水压力";
CM_ SG_ 2338057896 M2P_TMS_BackWaterPress_2 "2号TMS回水压力";
CM_ SG_ 2338057896 M2P_TMS_OutWaterPress_2 "2号TMS出水压力";
CM_ SG_ 2338057897 M2P_TMS_BackWaterPress_2 "2号TMS回水压力";
CM_ SG_ 2338057897 M2P_TMS_OutWaterPress_2 "2号TMS出水压力";
CM_ SG_ 2338057898 M2P_TMS_BackWaterPress_2 "2号TMS回水压力";
CM_ SG_ 2338057898 M2P_TMS_OutWaterPress_2 "2号TMS出水压力";
CM_ SG_ 2338057899 M2P_TMS_BackWaterPress_2 "2号TMS回水压力";
CM_ SG_ 2338057899 M2P_TMS_OutWaterPress_2 "2号TMS出水压力";
CM_ SG_ 2338057900 M2P_TMS_BackWaterPress_2 "2号TMS回水压力";
CM_ SG_ 2338057900 M2P_TMS_OutWaterPress_2 "2号TMS出水压力";
CM_ SG_ 2338057901 M2P_TMS_BackWaterPress_2 "2号TMS回水压力";
CM_ SG_ 2338057901 M2P_TMS_OutWaterPress_2 "2号TMS出水压力";
CM_ SG_ 2338057902 M2P_TMS_BackWaterPress_2 "2号TMS回水压力";
CM_ SG_ 2338057902 M2P_TMS_OutWaterPress_2 "2号TMS出水压力";
CM_ SG_ 2338057903 M2P_TMS_BackWaterPress_2 "2号TMS回水压力";
CM_ SG_ 2338057903 M2P_TMS_OutWaterPress_2 "2号TMS出水压力";
CM_ SG_ 2337341249 S2A_TMS_OutWaterPress "分布式TMS出水压力";
CM_ SG_ 2337341249 S2A_TMS_BackWaterPress "分布式TMS回水压力";
CM_ SG_ 2337341250 S2A_TMS_OutWaterPress "分布式TMS出水压力";
CM_ SG_ 2337341250 S2A_TMS_BackWaterPress "分布式TMS回水压力";
CM_ SG_ 2337341251 S2A_TMS_OutWaterPress "分布式TMS出水压力";
CM_ SG_ 2337341251 S2A_TMS_BackWaterPress "分布式TMS回水压力";
CM_ SG_ 2337341252 S2A_TMS_OutWaterPress "分布式TMS出水压力";
CM_ SG_ 2337341252 S2A_TMS_BackWaterPress "分布式TMS回水压力";
CM_ SG_ 2337341253 S2A_TMS_OutWaterPress "分布式TMS出水压力";
CM_ SG_ 2337341253 S2A_TMS_BackWaterPress "分布式TMS回水压力";
CM_ SG_ 2337341254 S2A_TMS_OutWaterPress "分布式TMS出水压力";
CM_ SG_ 2337341254 S2A_TMS_BackWaterPress "分布式TMS回水压力";
CM_ SG_ 2337341255 S2A_TMS_OutWaterPress "分布式TMS出水压力";
CM_ SG_ 2337341255 S2A_TMS_BackWaterPress "分布式TMS回水压力";
CM_ SG_ 2337341256 S2A_TMS_OutWaterPress "分布式TMS出水压力";
CM_ SG_ 2337341256 S2A_TMS_BackWaterPress "分布式TMS回水压力";
CM_ SG_ 2337341257 S2A_TMS_OutWaterPress "分布式TMS出水压力";
CM_ SG_ 2337341257 S2A_TMS_BackWaterPress "分布式TMS回水压力";
CM_ SG_ 2337341258 S2A_TMS_OutWaterPress "分布式TMS出水压力";
CM_ SG_ 2337341258 S2A_TMS_BackWaterPress "分布式TMS回水压力";
CM_ SG_ 2337341259 S2A_TMS_OutWaterPress "分布式TMS出水压力";
CM_ SG_ 2337341259 S2A_TMS_BackWaterPress "分布式TMS回水压力";
CM_ SG_ 2337341260 S2A_TMS_OutWaterPress "分布式TMS出水压力";
CM_ SG_ 2337341260 S2A_TMS_BackWaterPress "分布式TMS回水压力";
CM_ SG_ 2337341261 S2A_TMS_OutWaterPress "分布式TMS出水压力";
CM_ SG_ 2337341261 S2A_TMS_BackWaterPress "分布式TMS回水压力";
CM_ SG_ 2337341262 S2A_TMS_OutWaterPress "分布式TMS出水压力";
CM_ SG_ 2337341262 S2A_TMS_BackWaterPress "分布式TMS回水压力";
CM_ SG_ 2337341263 S2A_TMS_OutWaterPress "分布式TMS出水压力";
CM_ SG_ 2337341263 S2A_TMS_BackWaterPress "分布式TMS回水压力";
CM_ SG_ 2337341264 S2A_TMS_OutWaterPress "分布式TMS出水压力";
CM_ SG_ 2337341264 S2A_TMS_BackWaterPress "分布式TMS回水压力";
CM_ SG_ 2337341265 S2A_TMS_OutWaterPress "分布式TMS出水压力";
CM_ SG_ 2337341265 S2A_TMS_BackWaterPress "分布式TMS回水压力";
CM_ SG_ 2337341266 S2A_TMS_OutWaterPress "分布式TMS出水压力";
CM_ SG_ 2337341266 S2A_TMS_BackWaterPress "分布式TMS回水压力";
CM_ SG_ 2337341267 S2A_TMS_OutWaterPress "分布式TMS出水压力";
CM_ SG_ 2337341267 S2A_TMS_BackWaterPress "分布式TMS回水压力";
CM_ SG_ 2337341268 S2A_TMS_OutWaterPress "分布式TMS出水压力";
CM_ SG_ 2337341268 S2A_TMS_BackWaterPress "分布式TMS回水压力";
CM_ SG_ 2337341269 S2A_TMS_OutWaterPress "分布式TMS出水压力";
CM_ SG_ 2337341269 S2A_TMS_BackWaterPress "分布式TMS回水压力";
CM_ SG_ 2337341270 S2A_TMS_OutWaterPress "分布式TMS出水压力";
CM_ SG_ 2337341270 S2A_TMS_BackWaterPress "分布式TMS回水压力";
CM_ SG_ 2337341271 S2A_TMS_OutWaterPress "分布式TMS出水压力";
CM_ SG_ 2337341271 S2A_TMS_BackWaterPress "分布式TMS回水压力";
CM_ SG_ 2337341272 S2A_TMS_OutWaterPress "分布式TMS出水压力";
CM_ SG_ 2337341272 S2A_TMS_BackWaterPress "分布式TMS回水压力";
CM_ SG_ 2337341273 S2A_TMS_OutWaterPress "分布式TMS出水压力";
CM_ SG_ 2337341273 S2A_TMS_BackWaterPress "分布式TMS回水压力";
CM_ SG_ 2337341274 S2A_TMS_OutWaterPress "分布式TMS出水压力";
CM_ SG_ 2337341274 S2A_TMS_BackWaterPress "分布式TMS回水压力";
CM_ SG_ 2337341275 S2A_TMS_OutWaterPress "分布式TMS出水压力";
CM_ SG_ 2337341275 S2A_TMS_BackWaterPress "分布式TMS回水压力";
CM_ SG_ 2337341276 S2A_TMS_OutWaterPress "分布式TMS出水压力";
CM_ SG_ 2337341276 S2A_TMS_BackWaterPress "分布式TMS回水压力";
CM_ SG_ 2337341277 S2A_TMS_OutWaterPress "分布式TMS出水压力";
CM_ SG_ 2337341277 S2A_TMS_BackWaterPress "分布式TMS回水压力";
CM_ SG_ 2337341278 S2A_TMS_OutWaterPress "分布式TMS出水压力";
CM_ SG_ 2337341278 S2A_TMS_BackWaterPress "分布式TMS回水压力";
CM_ SG_ 2337341279 S2A_TMS_OutWaterPress "分布式TMS出水压力";
CM_ SG_ 2337341279 S2A_TMS_BackWaterPress "分布式TMS回水压力";
CM_ SG_ 2337341280 S2A_TMS_OutWaterPress "分布式TMS出水压力";
CM_ SG_ 2337341280 S2A_TMS_BackWaterPress "分布式TMS回水压力";
CM_ SG_ 2337341281 S2A_TMS_OutWaterPress "分布式TMS出水压力";
CM_ SG_ 2337341281 S2A_TMS_BackWaterPress "分布式TMS回水压力";
CM_ SG_ 2337341282 S2A_TMS_OutWaterPress "分布式TMS出水压力";
CM_ SG_ 2337341282 S2A_TMS_BackWaterPress "分布式TMS回水压力";
CM_ SG_ 2337341283 S2A_TMS_OutWaterPress "分布式TMS出水压力";
CM_ SG_ 2337341283 S2A_TMS_BackWaterPress "分布式TMS回水压力";
CM_ SG_ 2337341284 S2A_TMS_OutWaterPress "分布式TMS出水压力";
CM_ SG_ 2337341284 S2A_TMS_BackWaterPress "分布式TMS回水压力";
CM_ SG_ 2337341285 S2A_TMS_OutWaterPress "分布式TMS出水压力";
CM_ SG_ 2337341285 S2A_TMS_BackWaterPress "分布式TMS回水压力";
CM_ SG_ 2337341286 S2A_TMS_OutWaterPress "分布式TMS出水压力";
CM_ SG_ 2337341286 S2A_TMS_BackWaterPress "分布式TMS回水压力";
CM_ SG_ 2337341287 S2A_TMS_OutWaterPress "分布式TMS出水压力";
CM_ SG_ 2337341287 S2A_TMS_BackWaterPress "分布式TMS回水压力";
CM_ SG_ 2337341288 S2A_TMS_OutWaterPress "分布式TMS出水压力";
CM_ SG_ 2337341288 S2A_TMS_BackWaterPress "分布式TMS回水压力";
CM_ SG_ 2337341289 S2A_TMS_OutWaterPress "分布式TMS出水压力";
CM_ SG_ 2337341289 S2A_TMS_BackWaterPress "分布式TMS回水压力";
CM_ SG_ 2337341290 S2A_TMS_OutWaterPress "分布式TMS出水压力";
CM_ SG_ 2337341290 S2A_TMS_BackWaterPress "分布式TMS回水压力";
CM_ SG_ 2337341291 S2A_TMS_OutWaterPress "分布式TMS出水压力";
CM_ SG_ 2337341291 S2A_TMS_BackWaterPress "分布式TMS回水压力";
CM_ SG_ 2337341292 S2A_TMS_OutWaterPress "分布式TMS出水压力";
CM_ SG_ 2337341292 S2A_TMS_BackWaterPress "分布式TMS回水压力";
CM_ SG_ 2337341293 S2A_TMS_OutWaterPress "分布式TMS出水压力";
CM_ SG_ 2337341293 S2A_TMS_BackWaterPress "分布式TMS回水压力";
CM_ SG_ 2337341294 S2A_TMS_OutWaterPress "分布式TMS出水压力";
CM_ SG_ 2337341294 S2A_TMS_BackWaterPress "分布式TMS回水压力";
CM_ SG_ 2337341295 S2A_TMS_OutWaterPress "分布式TMS出水压力";
CM_ SG_ 2337341295 S2A_TMS_BackWaterPress "分布式TMS回水压力";
CM_ SG_ 2337341296 S2A_TMS_OutWaterPress "分布式TMS出水压力";
CM_ SG_ 2337341296 S2A_TMS_BackWaterPress "分布式TMS回水压力";
CM_ SG_ 2337341297 S2A_TMS_OutWaterPress "分布式TMS出水压力";
CM_ SG_ 2337341297 S2A_TMS_BackWaterPress "分布式TMS回水压力";
CM_ SG_ 2337341298 S2A_TMS_OutWaterPress "分布式TMS出水压力";
CM_ SG_ 2337341298 S2A_TMS_BackWaterPress "分布式TMS回水压力";
CM_ SG_ 2337341299 S2A_TMS_OutWaterPress "分布式TMS出水压力";
CM_ SG_ 2337341299 S2A_TMS_BackWaterPress "分布式TMS回水压力";
CM_ SG_ 2337341300 S2A_TMS_OutWaterPress "分布式TMS出水压力";
CM_ SG_ 2337341300 S2A_TMS_BackWaterPress "分布式TMS回水压力";
CM_ SG_ 2337341301 S2A_TMS_OutWaterPress "分布式TMS出水压力";
CM_ SG_ 2337341301 S2A_TMS_BackWaterPress "分布式TMS回水压力";
CM_ SG_ 2337341302 S2A_TMS_OutWaterPress "分布式TMS出水压力";
CM_ SG_ 2337341302 S2A_TMS_BackWaterPress "分布式TMS回水压力";
CM_ SG_ 2337341303 S2A_TMS_OutWaterPress "分布式TMS出水压力";
CM_ SG_ 2337341303 S2A_TMS_BackWaterPress "分布式TMS回水压力";
CM_ SG_ 2337341304 S2A_TMS_OutWaterPress "分布式TMS出水压力";
CM_ SG_ 2337341304 S2A_TMS_BackWaterPress "分布式TMS回水压力";
CM_ SG_ 2337341305 S2A_TMS_OutWaterPress "分布式TMS出水压力";
CM_ SG_ 2337341305 S2A_TMS_BackWaterPress "分布式TMS回水压力";
CM_ SG_ 2337341306 S2A_TMS_OutWaterPress "分布式TMS出水压力";
CM_ SG_ 2337341306 S2A_TMS_BackWaterPress "分布式TMS回水压力";
CM_ SG_ 2337341307 S2A_TMS_OutWaterPress "分布式TMS出水压力";
CM_ SG_ 2337341307 S2A_TMS_BackWaterPress "分布式TMS回水压力";
CM_ SG_ 2337341308 S2A_TMS_OutWaterPress "分布式TMS出水压力";
CM_ SG_ 2337341308 S2A_TMS_BackWaterPress "分布式TMS回水压力";
CM_ SG_ 2337341309 S2A_TMS_OutWaterPress "分布式TMS出水压力";
CM_ SG_ 2337341309 S2A_TMS_BackWaterPress "分布式TMS回水压力";
CM_ SG_ 2337341310 S2A_TMS_OutWaterPress "分布式TMS出水压力";
CM_ SG_ 2337341310 S2A_TMS_BackWaterPress "分布式TMS回水压力";
CM_ SG_ 2337341311 S2A_TMS_OutWaterPress "分布式TMS出水压力";
CM_ SG_ 2337341311 S2A_TMS_BackWaterPress "分布式TMS回水压力";
CM_ SG_ 2334588737 S2A_IMMEncodeFlgFromSBMU_01 "SBMU反馈给MBMU的IMM驱动状态";
CM_ SG_ 2334588738 S2A_IMMEncodeFlgFromSBMU_02 "SBMU反馈给MBMU的IMM驱动状态";
CM_ SG_ 2334588739 S2A_IMMEncodeFlgFromSBMU_03 "SBMU反馈给MBMU的IMM驱动状态";
CM_ SG_ 2334588740 S2A_IMMEncodeFlgFromSBMU_04 "SBMU反馈给MBMU的IMM驱动状态";
CM_ SG_ 2334588741 S2A_IMMEncodeFlgFromSBMU_05 "SBMU反馈给MBMU的IMM驱动状态";
CM_ SG_ 2334588742 S2A_IMMEncodeFlgFromSBMU_06 "SBMU反馈给MBMU的IMM驱动状态";
CM_ SG_ 2334588743 S2A_IMMEncodeFlgFromSBMU_07 "SBMU反馈给MBMU的IMM驱动状态";
CM_ SG_ 2334588744 S2A_IMMEncodeFlgFromSBMU_08 "SBMU反馈给MBMU的IMM驱动状态";
CM_ SG_ 2334588745 S2A_IMMEncodeFlgFromSBMU_09 "SBMU反馈给MBMU的IMM驱动状态";
CM_ SG_ 2334588746 S2A_IMMEncodeFlgFromSBMU_10 "SBMU反馈给MBMU的IMM驱动状态";
CM_ SG_ 2334588747 S2A_IMMEncodeFlgFromSBMU_11 "SBMU反馈给MBMU的IMM驱动状态";
CM_ SG_ 2334588748 S2A_IMMEncodeFlgFromSBMU_12 "SBMU反馈给MBMU的IMM驱动状态";
CM_ SG_ 2334588749 S2A_IMMEncodeFlgFromSBMU_13 "SBMU反馈给MBMU的IMM驱动状态";
CM_ SG_ 2334588750 S2A_IMMEncodeFlgFromSBMU_14 "SBMU反馈给MBMU的IMM驱动状态";
CM_ SG_ 2334588751 S2A_IMMEncodeFlgFromSBMU_15 "SBMU反馈给MBMU的IMM驱动状态";
CM_ SG_ 2334588752 S2A_IMMEncodeFlgFromSBMU_16 "SBMU反馈给MBMU的IMM驱动状态";
CM_ SG_ 2334588753 S2A_IMMEncodeFlgFromSBMU_17 "SBMU反馈给MBMU的IMM驱动状态";
CM_ SG_ 2334588754 S2A_IMMEncodeFlgFromSBMU_18 "SBMU反馈给MBMU的IMM驱动状态";
CM_ SG_ 2334588755 S2A_IMMEncodeFlgFromSBMU_19 "SBMU反馈给MBMU的IMM驱动状态";
CM_ SG_ 2334588756 S2A_IMMEncodeFlgFromSBMU_20 "SBMU反馈给MBMU的IMM驱动状态";
CM_ SG_ 2334588757 S2A_IMMEncodeFlgFromSBMU_21 "SBMU反馈给MBMU的IMM驱动状态";
CM_ SG_ 2334588758 S2A_IMMEncodeFlgFromSBMU_22 "SBMU反馈给MBMU的IMM驱动状态";
CM_ SG_ 2334588759 S2A_IMMEncodeFlgFromSBMU_23 "SBMU反馈给MBMU的IMM驱动状态";
CM_ SG_ 2334588760 S2A_IMMEncodeFlgFromSBMU_24 "SBMU反馈给MBMU的IMM驱动状态";
CM_ SG_ 2334588761 S2A_IMMEncodeFlgFromSBMU_25 "SBMU反馈给MBMU的IMM驱动状态";
CM_ SG_ 2334588762 S2A_IMMEncodeFlgFromSBMU_26 "SBMU反馈给MBMU的IMM驱动状态";
CM_ SG_ 2334588763 S2A_IMMEncodeFlgFromSBMU_27 "SBMU反馈给MBMU的IMM驱动状态";
CM_ SG_ 2334588764 S2A_IMMEncodeFlgFromSBMU_28 "SBMU反馈给MBMU的IMM驱动状态";
CM_ SG_ 2334588765 S2A_IMMEncodeFlgFromSBMU_29 "SBMU反馈给MBMU的IMM驱动状态";
CM_ SG_ 2334588766 S2A_IMMEncodeFlgFromSBMU_30 "SBMU反馈给MBMU的IMM驱动状态";
CM_ SG_ 2334588767 S2A_IMMEncodeFlgFromSBMU_31 "SBMU反馈给MBMU的IMM驱动状态";
CM_ SG_ 2334588768 S2A_IMMEncodeFlgFromSBMU_32 "SBMU反馈给MBMU的IMM驱动状态";
CM_ SG_ 2334588769 S2A_IMMEncodeFlgFromSBMU_33 "SBMU反馈给MBMU的IMM驱动状态";
CM_ SG_ 2334588770 S2A_IMMEncodeFlgFromSBMU_34 "SBMU反馈给MBMU的IMM驱动状态";
CM_ SG_ 2334588771 S2A_IMMEncodeFlgFromSBMU_35 "SBMU反馈给MBMU的IMM驱动状态";
CM_ SG_ 2334588772 S2A_IMMEncodeFlgFromSBMU_36 "SBMU反馈给MBMU的IMM驱动状态";
CM_ SG_ 2334588773 S2A_IMMEncodeFlgFromSBMU_37 "SBMU反馈给MBMU的IMM驱动状态";
CM_ SG_ 2334588774 S2A_IMMEncodeFlgFromSBMU_38 "SBMU反馈给MBMU的IMM驱动状态";
CM_ SG_ 2334588775 S2A_IMMEncodeFlgFromSBMU_39 "SBMU反馈给MBMU的IMM驱动状态";
CM_ SG_ 2334588776 S2A_IMMEncodeFlgFromSBMU_40 "SBMU反馈给MBMU的IMM驱动状态";
CM_ SG_ 2334588777 S2A_IMMEncodeFlgFromSBMU_41 "SBMU反馈给MBMU的IMM驱动状态";
CM_ SG_ 2334588778 S2A_IMMEncodeFlgFromSBMU_42 "SBMU反馈给MBMU的IMM驱动状态";
CM_ SG_ 2334588779 S2A_IMMEncodeFlgFromSBMU_43 "SBMU反馈给MBMU的IMM驱动状态";
CM_ SG_ 2334588780 S2A_IMMEncodeFlgFromSBMU_44 "SBMU反馈给MBMU的IMM驱动状态";
CM_ SG_ 2334588781 S2A_IMMEncodeFlgFromSBMU_45 "SBMU反馈给MBMU的IMM驱动状态";
CM_ SG_ 2334588782 S2A_IMMEncodeFlgFromSBMU_46 "SBMU反馈给MBMU的IMM驱动状态";
CM_ SG_ 2334588783 S2A_IMMEncodeFlgFromSBMU_47 "SBMU反馈给MBMU的IMM驱动状态";
CM_ SG_ 2334588784 S2A_IMMEncodeFlgFromSBMU_48 "SBMU反馈给MBMU的IMM驱动状态";
CM_ SG_ 2334588785 S2A_IMMEncodeFlgFromSBMU_49 "SBMU反馈给MBMU的IMM驱动状态";
CM_ SG_ 2334588786 S2A_IMMEncodeFlgFromSBMU_50 "SBMU反馈给MBMU的IMM驱动状态";
CM_ SG_ 2334588787 S2A_IMMEncodeFlgFromSBMU_51 "SBMU反馈给MBMU的IMM驱动状态";
CM_ SG_ 2334588788 S2A_IMMEncodeFlgFromSBMU_52 "SBMU反馈给MBMU的IMM驱动状态";
CM_ SG_ 2334588789 S2A_IMMEncodeFlgFromSBMU_53 "SBMU反馈给MBMU的IMM驱动状态";
CM_ SG_ 2334588790 S2A_IMMEncodeFlgFromSBMU_54 "SBMU反馈给MBMU的IMM驱动状态";
CM_ SG_ 2334588791 S2A_IMMEncodeFlgFromSBMU_55 "SBMU反馈给MBMU的IMM驱动状态";
CM_ SG_ 2334588792 S2A_IMMEncodeFlgFromSBMU_56 "SBMU反馈给MBMU的IMM驱动状态";
CM_ SG_ 2334588793 S2A_IMMEncodeFlgFromSBMU_57 "SBMU反馈给MBMU的IMM驱动状态";
CM_ SG_ 2334588794 S2A_IMMEncodeFlgFromSBMU_58 "SBMU反馈给MBMU的IMM驱动状态";
CM_ SG_ 2334588795 S2A_IMMEncodeFlgFromSBMU_59 "SBMU反馈给MBMU的IMM驱动状态";
CM_ SG_ 2334588796 S2A_IMMEncodeFlgFromSBMU_60 "SBMU反馈给MBMU的IMM驱动状态";
CM_ SG_ 2334588797 S2A_IMMEncodeFlgFromSBMU_61 "SBMU反馈给MBMU的IMM驱动状态";
CM_ SG_ 2334588798 S2A_IMMEncodeFlgFromSBMU_62 "SBMU反馈给MBMU的IMM驱动状态";
CM_ SG_ 2334588799 S2A_IMMEncodeFlgFromSBMU_63 "SBMU反馈给MBMU的IMM驱动状态";
CM_ SG_ 2467467183 M2S_IMMCode_State "MBMU发送给SBMU的IMM编码状态";
CM_ SG_ 2467467183 M2S_IMMIndexPower_SBMUAddr "MBMU发送给SBMU对IMM高边供电使能信号";
VAL_ 2337861290 M2P_TMS_L_25_fan_fault_26 0 "no fault 00实际为0x00 引号外不能使用字母" 1 "Fan 3 overvoltage 01实际为0x01" 2 "Fan 3 under voltage 02实际为0x02" 3 "Fan 3 is stuck in rotation 03实际为0x03" 4 "Fan 3 overcurrent 04实际为0x04" 5 "Fan 3 motor overheating 05实际为0x05" 6 "Fan 3 drive overheating 06实际为0x06" 7 "Fan 4 overvoltage 07实际为0x07" 8 "Fan 4 under voltage 08实际为0x08" 9 "Fan 4 is stuck in rotation 09实际为0x09" 10 "Fan 4 overcurrent 10实际为0x0A" 11 "Fan 4 motor overheating 11实际为0x0B" 12 "Fan 4 drive overheating 12实际为0x0C" 13 "Fan 5 overvoltage 13实际为0x0D" 14 "Fan 5 under voltage 14实际为0x0E" 15 "Fan 5 is stuck in rotation 15实际为0x0F" 16 "Fan 5 overcurrent 16实际为0x10" 17 "Fan 5 motor overheating 17实际为0x11" 18 "Fan 5 drive overheating 18实际为0x12" 19 "Fan 6 overvoltage 19实际为0x13" 20 "Fan 6 under voltage 20实际为0x14" 21 "Fan 6 is stuck in rotation 21实际为0x15" 22 "Fan 6 overcurrent 22实际为0x16" 23 "Fan 6 motor overheating 23实际为0x17" 24 "Fan 6 drive overheating 24实际为0x18" ;
VAL_ 2337861290 M2P_TMS_L_25_fre_fault_26 0 "no fault 00实际为0x00 引号外不能使用字母" 1 "Overcurrent 01实际为0x01" 2 "Operating overvoltage 02实际为0x02" 3 "Operating under voltage 03实际为0x03" 4 "AC input overvoltage 04实际为0x04" 5 "AC input under voltage 05实际为0x05" 6 "communication fault 06实际为0x06" 7 "Overcurrent frequency reduction 07实际为0x07" 8 "Over power frequency reduction 08实际为0x08" 9 "Input phase loss 09实际为0x09" 10 "External malfunction 10实际为0x0A" 11 "NTC overheating 11实际为0x0B" 12 "Power on to ground short circuit detection 12实际为0x0C" 13 "motor overload 13实际为0x0D" ;
VAL_ 2337861290 M2P_TMS_L_25_D_fault_26 0 "no fault 00实际为0x00 引号外不能使用字母" 1 "Overcurrent 01实际为0x01" 2 "Operating overvoltage 02实际为0x02" 3 "Operating under voltage 03实际为0x03" 4 "DC output overvoltage 04实际为0x04" 5 "DC output undervoltage 05实际为0x05" 6 "communication fault 06实际为0x06" 7 "Substrate overheating 07实际为0x07" 8 "output overload 08实际为0x08" ;
VAL_ 2337861291 M2P_TMS_L_25_fan_fault_27 0 "no fault 00实际为0x00 引号外不能使用字母" 1 "Fan 3 overvoltage 01实际为0x01" 2 "Fan 3 under voltage 02实际为0x02" 3 "Fan 3 is stuck in rotation 03实际为0x03" 4 "Fan 3 overcurrent 04实际为0x04" 5 "Fan 3 motor overheating 05实际为0x05" 6 "Fan 3 drive overheating 06实际为0x06" 7 "Fan 4 overvoltage 07实际为0x07" 8 "Fan 4 under voltage 08实际为0x08" 9 "Fan 4 is stuck in rotation 09实际为0x09" 10 "Fan 4 overcurrent 10实际为0x0A" 11 "Fan 4 motor overheating 11实际为0x0B" 12 "Fan 4 drive overheating 12实际为0x0C" 13 "Fan 5 overvoltage 13实际为0x0D" 14 "Fan 5 under voltage 14实际为0x0E" 15 "Fan 5 is stuck in rotation 15实际为0x0F" 16 "Fan 5 overcurrent 16实际为0x10" 17 "Fan 5 motor overheating 17实际为0x11" 18 "Fan 5 drive overheating 18实际为0x12" 19 "Fan 6 overvoltage 19实际为0x13" 20 "Fan 6 under voltage 20实际为0x14" 21 "Fan 6 is stuck in rotation 21实际为0x15" 22 "Fan 6 overcurrent 22实际为0x16" 23 "Fan 6 motor overheating 23实际为0x17" 24 "Fan 6 drive overheating 24实际为0x18" ;
VAL_ 2337861291 M2P_TMS_L_25_fre_fault_27 0 "no fault 00实际为0x00 引号外不能使用字母" 1 "Overcurrent 01实际为0x01" 2 "Operating overvoltage 02实际为0x02" 3 "Operating under voltage 03实际为0x03" 4 "AC input overvoltage 04实际为0x04" 5 "AC input under voltage 05实际为0x05" 6 "communication fault 06实际为0x06" 7 "Overcurrent frequency reduction 07实际为0x07" 8 "Over power frequency reduction 08实际为0x08" 9 "Input phase loss 09实际为0x09" 10 "External malfunction 10实际为0x0A" 11 "NTC overheating 11实际为0x0B" 12 "Power on to ground short circuit detection 12实际为0x0C" 13 "motor overload 13实际为0x0D" ;
VAL_ 2337861291 M2P_TMS_L_25_D_fault_27 0 "no fault 00实际为0x00 引号外不能使用字母" 1 "Overcurrent 01实际为0x01" 2 "Operating overvoltage 02实际为0x02" 3 "Operating under voltage 03实际为0x03" 4 "DC output overvoltage 04实际为0x04" 5 "DC output undervoltage 05实际为0x05" 6 "communication fault 06实际为0x06" 7 "Substrate overheating 07实际为0x07" 8 "output overload 08实际为0x08" ;
VAL_ 2337861292 M2P_TMS_L_25_fan_fault_28 0 "no fault 00实际为0x00 引号外不能使用字母" 1 "Fan 3 overvoltage 01实际为0x01" 2 "Fan 3 under voltage 02实际为0x02" 3 "Fan 3 is stuck in rotation 03实际为0x03" 4 "Fan 3 overcurrent 04实际为0x04" 5 "Fan 3 motor overheating 05实际为0x05" 6 "Fan 3 drive overheating 06实际为0x06" 7 "Fan 4 overvoltage 07实际为0x07" 8 "Fan 4 under voltage 08实际为0x08" 9 "Fan 4 is stuck in rotation 09实际为0x09" 10 "Fan 4 overcurrent 10实际为0x0A" 11 "Fan 4 motor overheating 11实际为0x0B" 12 "Fan 4 drive overheating 12实际为0x0C" 13 "Fan 5 overvoltage 13实际为0x0D" 14 "Fan 5 under voltage 14实际为0x0E" 15 "Fan 5 is stuck in rotation 15实际为0x0F" 16 "Fan 5 overcurrent 16实际为0x10" 17 "Fan 5 motor overheating 17实际为0x11" 18 "Fan 5 drive overheating 18实际为0x12" 19 "Fan 6 overvoltage 19实际为0x13" 20 "Fan 6 under voltage 20实际为0x14" 21 "Fan 6 is stuck in rotation 21实际为0x15" 22 "Fan 6 overcurrent 22实际为0x16" 23 "Fan 6 motor overheating 23实际为0x17" 24 "Fan 6 drive overheating 24实际为0x18" ;
VAL_ 2337861292 M2P_TMS_L_25_fre_fault_28 0 "no fault 00实际为0x00 引号外不能使用字母" 1 "Overcurrent 01实际为0x01" 2 "Operating overvoltage 02实际为0x02" 3 "Operating under voltage 03实际为0x03" 4 "AC input overvoltage 04实际为0x04" 5 "AC input under voltage 05实际为0x05" 6 "communication fault 06实际为0x06" 7 "Overcurrent frequency reduction 07实际为0x07" 8 "Over power frequency reduction 08实际为0x08" 9 "Input phase loss 09实际为0x09" 10 "External malfunction 10实际为0x0A" 11 "NTC overheating 11实际为0x0B" 12 "Power on to ground short circuit detection 12实际为0x0C" 13 "motor overload 13实际为0x0D" ;
VAL_ 2337861292 M2P_TMS_L_25_D_fault_28 0 "no fault 00实际为0x00 引号外不能使用字母" 1 "Overcurrent 01实际为0x01" 2 "Operating overvoltage 02实际为0x02" 3 "Operating under voltage 03实际为0x03" 4 "DC output overvoltage 04实际为0x04" 5 "DC output undervoltage 05实际为0x05" 6 "communication fault 06实际为0x06" 7 "Substrate overheating 07实际为0x07" 8 "output overload 08实际为0x08" ;
VAL_ 2337861293 M2P_TMS_L_25_fan_fault_29 0 "no fault 00实际为0x00 引号外不能使用字母" 1 "Fan 3 overvoltage 01实际为0x01" 2 "Fan 3 under voltage 02实际为0x02" 3 "Fan 3 is stuck in rotation 03实际为0x03" 4 "Fan 3 overcurrent 04实际为0x04" 5 "Fan 3 motor overheating 05实际为0x05" 6 "Fan 3 drive overheating 06实际为0x06" 7 "Fan 4 overvoltage 07实际为0x07" 8 "Fan 4 under voltage 08实际为0x08" 9 "Fan 4 is stuck in rotation 09实际为0x09" 10 "Fan 4 overcurrent 10实际为0x0A" 11 "Fan 4 motor overheating 11实际为0x0B" 12 "Fan 4 drive overheating 12实际为0x0C" 13 "Fan 5 overvoltage 13实际为0x0D" 14 "Fan 5 under voltage 14实际为0x0E" 15 "Fan 5 is stuck in rotation 15实际为0x0F" 16 "Fan 5 overcurrent 16实际为0x10" 17 "Fan 5 motor overheating 17实际为0x11" 18 "Fan 5 drive overheating 18实际为0x12" 19 "Fan 6 overvoltage 19实际为0x13" 20 "Fan 6 under voltage 20实际为0x14" 21 "Fan 6 is stuck in rotation 21实际为0x15" 22 "Fan 6 overcurrent 22实际为0x16" 23 "Fan 6 motor overheating 23实际为0x17" 24 "Fan 6 drive overheating 24实际为0x18" ;
VAL_ 2337861293 M2P_TMS_L_25_fre_fault_29 0 "no fault 00实际为0x00 引号外不能使用字母" 1 "Overcurrent 01实际为0x01" 2 "Operating overvoltage 02实际为0x02" 3 "Operating under voltage 03实际为0x03" 4 "AC input overvoltage 04实际为0x04" 5 "AC input under voltage 05实际为0x05" 6 "communication fault 06实际为0x06" 7 "Overcurrent frequency reduction 07实际为0x07" 8 "Over power frequency reduction 08实际为0x08" 9 "Input phase loss 09实际为0x09" 10 "External malfunction 10实际为0x0A" 11 "NTC overheating 11实际为0x0B" 12 "Power on to ground short circuit detection 12实际为0x0C" 13 "motor overload 13实际为0x0D" ;
VAL_ 2337861293 M2P_TMS_L_25_D_fault_29 0 "no fault 00实际为0x00 引号外不能使用字母" 1 "Overcurrent 01实际为0x01" 2 "Operating overvoltage 02实际为0x02" 3 "Operating under voltage 03实际为0x03" 4 "DC output overvoltage 04实际为0x04" 5 "DC output undervoltage 05实际为0x05" 6 "communication fault 06实际为0x06" 7 "Substrate overheating 07实际为0x07" 8 "output overload 08实际为0x08" ;
VAL_ 2337861294 M2P_TMS_L_25_fan_fault_30 0 "no fault 00实际为0x00 引号外不能使用字母" 1 "Fan 3 overvoltage 01实际为0x01" 2 "Fan 3 under voltage 02实际为0x02" 3 "Fan 3 is stuck in rotation 03实际为0x03" 4 "Fan 3 overcurrent 04实际为0x04" 5 "Fan 3 motor overheating 05实际为0x05" 6 "Fan 3 drive overheating 06实际为0x06" 7 "Fan 4 overvoltage 07实际为0x07" 8 "Fan 4 under voltage 08实际为0x08" 9 "Fan 4 is stuck in rotation 09实际为0x09" 10 "Fan 4 overcurrent 10实际为0x0A" 11 "Fan 4 motor overheating 11实际为0x0B" 12 "Fan 4 drive overheating 12实际为0x0C" 13 "Fan 5 overvoltage 13实际为0x0D" 14 "Fan 5 under voltage 14实际为0x0E" 15 "Fan 5 is stuck in rotation 15实际为0x0F" 16 "Fan 5 overcurrent 16实际为0x10" 17 "Fan 5 motor overheating 17实际为0x11" 18 "Fan 5 drive overheating 18实际为0x12" 19 "Fan 6 overvoltage 19实际为0x13" 20 "Fan 6 under voltage 20实际为0x14" 21 "Fan 6 is stuck in rotation 21实际为0x15" 22 "Fan 6 overcurrent 22实际为0x16" 23 "Fan 6 motor overheating 23实际为0x17" 24 "Fan 6 drive overheating 24实际为0x18" ;
VAL_ 2337861294 M2P_TMS_L_25_fre_fault_30 0 "no fault 00实际为0x00 引号外不能使用字母" 1 "Overcurrent 01实际为0x01" 2 "Operating overvoltage 02实际为0x02" 3 "Operating under voltage 03实际为0x03" 4 "AC input overvoltage 04实际为0x04" 5 "AC input under voltage 05实际为0x05" 6 "communication fault 06实际为0x06" 7 "Overcurrent frequency reduction 07实际为0x07" 8 "Over power frequency reduction 08实际为0x08" 9 "Input phase loss 09实际为0x09" 10 "External malfunction 10实际为0x0A" 11 "NTC overheating 11实际为0x0B" 12 "Power on to ground short circuit detection 12实际为0x0C" 13 "motor overload 13实际为0x0D" ;
VAL_ 2337861294 M2P_TMS_L_25_D_fault_30 0 "no fault 00实际为0x00 引号外不能使用字母" 1 "Overcurrent 01实际为0x01" 2 "Operating overvoltage 02实际为0x02" 3 "Operating under voltage 03实际为0x03" 4 "DC output overvoltage 04实际为0x04" 5 "DC output undervoltage 05实际为0x05" 6 "communication fault 06实际为0x06" 7 "Substrate overheating 07实际为0x07" 8 "output overload 08实际为0x08" ;
VAL_ 2337861295 M2P_TMS_L_25_fan_fault_31 0 "no fault 00实际为0x00 引号外不能使用字母" 1 "Fan 3 overvoltage 01实际为0x01" 2 "Fan 3 under voltage 02实际为0x02" 3 "Fan 3 is stuck in rotation 03实际为0x03" 4 "Fan 3 overcurrent 04实际为0x04" 5 "Fan 3 motor overheating 05实际为0x05" 6 "Fan 3 drive overheating 06实际为0x06" 7 "Fan 4 overvoltage 07实际为0x07" 8 "Fan 4 under voltage 08实际为0x08" 9 "Fan 4 is stuck in rotation 09实际为0x09" 10 "Fan 4 overcurrent 10实际为0x0A" 11 "Fan 4 motor overheating 11实际为0x0B" 12 "Fan 4 drive overheating 12实际为0x0C" 13 "Fan 5 overvoltage 13实际为0x0D" 14 "Fan 5 under voltage 14实际为0x0E" 15 "Fan 5 is stuck in rotation 15实际为0x0F" 16 "Fan 5 overcurrent 16实际为0x10" 17 "Fan 5 motor overheating 17实际为0x11" 18 "Fan 5 drive overheating 18实际为0x12" 19 "Fan 6 overvoltage 19实际为0x13" 20 "Fan 6 under voltage 20实际为0x14" 21 "Fan 6 is stuck in rotation 21实际为0x15" 22 "Fan 6 overcurrent 22实际为0x16" 23 "Fan 6 motor overheating 23实际为0x17" 24 "Fan 6 drive overheating 24实际为0x18" ;
VAL_ 2337861295 M2P_TMS_L_25_fre_fault_31 0 "no fault 00实际为0x00 引号外不能使用字母" 1 "Overcurrent 01实际为0x01" 2 "Operating overvoltage 02实际为0x02" 3 "Operating under voltage 03实际为0x03" 4 "AC input overvoltage 04实际为0x04" 5 "AC input under voltage 05实际为0x05" 6 "communication fault 06实际为0x06" 7 "Overcurrent frequency reduction 07实际为0x07" 8 "Over power frequency reduction 08实际为0x08" 9 "Input phase loss 09实际为0x09" 10 "External malfunction 10实际为0x0A" 11 "NTC overheating 11实际为0x0B" 12 "Power on to ground short circuit detection 12实际为0x0C" 13 "motor overload 13实际为0x0D" ;
VAL_ 2337861295 M2P_TMS_L_25_D_fault_31 0 "no fault 00实际为0x00 引号外不能使用字母" 1 "Overcurrent 01实际为0x01" 2 "Operating overvoltage 02实际为0x02" 3 "Operating under voltage 03实际为0x03" 4 "DC output overvoltage 04实际为0x04" 5 "DC output undervoltage 05实际为0x05" 6 "communication fault 06实际为0x06" 7 "Substrate overheating 07实际为0x07" 8 "output overload 08实际为0x08" ;
VAL_ 2337992337 M2P_TMS_BackWaterPress_1 255 "无效" ;
VAL_ 2337992337 M2P_TMS_OutWaterPress_1 255 "无效" ;
VAL_ 2337992338 M2P_TMS_BackWaterPress_1 255 "无效" ;
VAL_ 2337992338 M2P_TMS_OutWaterPress_1 255 "无效" ;
VAL_ 2337992339 M2P_TMS_BackWaterPress_1 255 "无效" ;
VAL_ 2337992339 M2P_TMS_OutWaterPress_1 255 "无效" ;
VAL_ 2337992340 M2P_TMS_BackWaterPress_1 255 "无效" ;
VAL_ 2337992340 M2P_TMS_OutWaterPress_1 255 "无效" ;
VAL_ 2337992341 M2P_TMS_BackWaterPress_1 255 "无效" ;
VAL_ 2337992341 M2P_TMS_OutWaterPress_1 255 "无效" ;
VAL_ 2337992342 M2P_TMS_BackWaterPress_1 255 "无效" ;
VAL_ 2337992342 M2P_TMS_OutWaterPress_1 255 "无效" ;
VAL_ 2337992343 M2P_TMS_BackWaterPress_1 255 "无效" ;
VAL_ 2337992343 M2P_TMS_OutWaterPress_1 255 "无效" ;
VAL_ 2337992344 M2P_TMS_BackWaterPress_1 255 "无效" ;
VAL_ 2337992344 M2P_TMS_OutWaterPress_1 255 "无效" ;
VAL_ 2337992345 M2P_TMS_BackWaterPress_1 255 "无效" ;
VAL_ 2337992345 M2P_TMS_OutWaterPress_1 255 "无效" ;
VAL_ 2337992346 M2P_TMS_BackWaterPress_1 255 "无效" ;
VAL_ 2337992346 M2P_TMS_OutWaterPress_1 255 "无效" ;
VAL_ 2337992347 M2P_TMS_BackWaterPress_1 255 "无效" ;
VAL_ 2337992347 M2P_TMS_OutWaterPress_1 255 "无效" ;
VAL_ 2337992348 M2P_TMS_BackWaterPress_1 255 "无效" ;
VAL_ 2337992348 M2P_TMS_OutWaterPress_1 255 "无效" ;
VAL_ 2337992349 M2P_TMS_BackWaterPress_1 255 "无效" ;
VAL_ 2337992349 M2P_TMS_OutWaterPress_1 255 "无效" ;
VAL_ 2337992350 M2P_TMS_BackWaterPress_1 255 "无效" ;
VAL_ 2337992350 M2P_TMS_OutWaterPress_1 255 "无效" ;
VAL_ 2337992351 M2P_TMS_BackWaterPress_1 255 "无效" ;
VAL_ 2337992351 M2P_TMS_OutWaterPress_1 255 "无效" ;
VAL_ 2337992352 M2P_TMS_BackWaterPress_1 255 "无效" ;
VAL_ 2337992352 M2P_TMS_OutWaterPress_1 255 "无效" ;
VAL_ 2337992353 M2P_TMS_BackWaterPress_1 255 "无效" ;
VAL_ 2337992353 M2P_TMS_OutWaterPress_1 255 "无效" ;
VAL_ 2337992354 M2P_TMS_BackWaterPress_1 255 "无效" ;
VAL_ 2337992354 M2P_TMS_OutWaterPress_1 255 "无效" ;
VAL_ 2337992355 M2P_TMS_BackWaterPress_1 255 "无效" ;
VAL_ 2337992355 M2P_TMS_OutWaterPress_1 255 "无效" ;
VAL_ 2337992356 M2P_TMS_BackWaterPress_1 255 "无效" ;
VAL_ 2337992356 M2P_TMS_OutWaterPress_1 255 "无效" ;
VAL_ 2337992357 M2P_TMS_BackWaterPress_1 255 "无效" ;
VAL_ 2337992357 M2P_TMS_OutWaterPress_1 255 "无效" ;
VAL_ 2337992358 M2P_TMS_BackWaterPress_1 255 "无效" ;
VAL_ 2337992358 M2P_TMS_OutWaterPress_1 255 "无效" ;
VAL_ 2337992359 M2P_TMS_BackWaterPress_1 255 "无效" ;
VAL_ 2337992359 M2P_TMS_OutWaterPress_1 255 "无效" ;
VAL_ 2337992360 M2P_TMS_BackWaterPress_1 255 "无效" ;
VAL_ 2337992360 M2P_TMS_OutWaterPress_1 255 "无效" ;
VAL_ 2337992361 M2P_TMS_BackWaterPress_1 255 "无效" ;
VAL_ 2337992361 M2P_TMS_OutWaterPress_1 255 "无效" ;
VAL_ 2337992362 M2P_TMS_BackWaterPress_1 255 "无效" ;
VAL_ 2337992362 M2P_TMS_OutWaterPress_1 255 "无效" ;
VAL_ 2337992363 M2P_TMS_BackWaterPress_1 255 "无效" ;
VAL_ 2337992363 M2P_TMS_OutWaterPress_1 255 "无效" ;
VAL_ 2337992364 M2P_TMS_BackWaterPress_1 255 "无效" ;
VAL_ 2337992364 M2P_TMS_OutWaterPress_1 255 "无效" ;
VAL_ 2337992365 M2P_TMS_BackWaterPress_1 255 "无效" ;
VAL_ 2337992365 M2P_TMS_OutWaterPress_1 255 "无效" ;
VAL_ 2337992366 M2P_TMS_BackWaterPress_1 255 "无效" ;
VAL_ 2337992366 M2P_TMS_OutWaterPress_1 255 "无效" ;
VAL_ 2337992367 M2P_TMS_BackWaterPress_1 255 "无效" ;
VAL_ 2337992367 M2P_TMS_OutWaterPress_1 255 "无效" ;
VAL_ 2338057873 M2P_TMS_BackWaterPress_2 255 "无效" ;
VAL_ 2338057873 M2P_TMS_OutWaterPress_2 255 "无效" ;
VAL_ 2338057874 M2P_TMS_BackWaterPress_2 255 "无效" ;
VAL_ 2338057874 M2P_TMS_OutWaterPress_2 255 "无效" ;
VAL_ 2338057875 M2P_TMS_BackWaterPress_2 255 "无效" ;
VAL_ 2338057875 M2P_TMS_OutWaterPress_2 255 "无效" ;
VAL_ 2338057876 M2P_TMS_BackWaterPress_2 255 "无效" ;
VAL_ 2338057876 M2P_TMS_OutWaterPress_2 255 "无效" ;
VAL_ 2338057877 M2P_TMS_BackWaterPress_2 255 "无效" ;
VAL_ 2338057877 M2P_TMS_OutWaterPress_2 255 "无效" ;
VAL_ 2338057878 M2P_TMS_BackWaterPress_2 255 "无效" ;
VAL_ 2338057878 M2P_TMS_OutWaterPress_2 255 "无效" ;
VAL_ 2338057879 M2P_TMS_BackWaterPress_2 255 "无效" ;
VAL_ 2338057879 M2P_TMS_OutWaterPress_2 255 "无效" ;
VAL_ 2338057880 M2P_TMS_BackWaterPress_2 255 "无效" ;
VAL_ 2338057880 M2P_TMS_OutWaterPress_2 255 "无效" ;
VAL_ 2338057881 M2P_TMS_BackWaterPress_2 255 "无效" ;
VAL_ 2338057881 M2P_TMS_OutWaterPress_2 255 "无效" ;
VAL_ 2338057882 M2P_TMS_BackWaterPress_2 255 "无效" ;
VAL_ 2338057882 M2P_TMS_OutWaterPress_2 255 "无效" ;
VAL_ 2338057883 M2P_TMS_BackWaterPress_2 255 "无效" ;
VAL_ 2338057883 M2P_TMS_OutWaterPress_2 255 "无效" ;
VAL_ 2338057884 M2P_TMS_BackWaterPress_2 255 "无效" ;
VAL_ 2338057884 M2P_TMS_OutWaterPress_2 255 "无效" ;
VAL_ 2338057885 M2P_TMS_BackWaterPress_2 255 "无效" ;
VAL_ 2338057885 M2P_TMS_OutWaterPress_2 255 "无效" ;
VAL_ 2338057886 M2P_TMS_BackWaterPress_2 255 "无效" ;
VAL_ 2338057886 M2P_TMS_OutWaterPress_2 255 "无效" ;
VAL_ 2338057887 M2P_TMS_BackWaterPress_2 255 "无效" ;
VAL_ 2338057887 M2P_TMS_OutWaterPress_2 255 "无效" ;
VAL_ 2338057888 M2P_TMS_BackWaterPress_2 255 "无效" ;
VAL_ 2338057888 M2P_TMS_OutWaterPress_2 255 "无效" ;
VAL_ 2338057889 M2P_TMS_BackWaterPress_2 255 "无效" ;
VAL_ 2338057889 M2P_TMS_OutWaterPress_2 255 "无效" ;
VAL_ 2338057890 M2P_TMS_BackWaterPress_2 255 "无效" ;
VAL_ 2338057890 M2P_TMS_OutWaterPress_2 255 "无效" ;
VAL_ 2338057891 M2P_TMS_BackWaterPress_2 255 "无效" ;
VAL_ 2338057891 M2P_TMS_OutWaterPress_2 255 "无效" ;
VAL_ 2338057892 M2P_TMS_BackWaterPress_2 255 "无效" ;
VAL_ 2338057892 M2P_TMS_OutWaterPress_2 255 "无效" ;
VAL_ 2338057893 M2P_TMS_BackWaterPress_2 255 "无效" ;
VAL_ 2338057893 M2P_TMS_OutWaterPress_2 255 "无效" ;
VAL_ 2338057894 M2P_TMS_BackWaterPress_2 255 "无效" ;
VAL_ 2338057894 M2P_TMS_OutWaterPress_2 255 "无效" ;
VAL_ 2338057895 M2P_TMS_BackWaterPress_2 255 "无效" ;
VAL_ 2338057895 M2P_TMS_OutWaterPress_2 255 "无效" ;
VAL_ 2338057896 M2P_TMS_BackWaterPress_2 255 "无效" ;
VAL_ 2338057896 M2P_TMS_OutWaterPress_2 255 "无效" ;
VAL_ 2338057897 M2P_TMS_BackWaterPress_2 255 "无效" ;
VAL_ 2338057897 M2P_TMS_OutWaterPress_2 255 "无效" ;
VAL_ 2338057898 M2P_TMS_BackWaterPress_2 255 "无效" ;
VAL_ 2338057898 M2P_TMS_OutWaterPress_2 255 "无效" ;
VAL_ 2338057899 M2P_TMS_BackWaterPress_2 255 "无效" ;
VAL_ 2338057899 M2P_TMS_OutWaterPress_2 255 "无效" ;
VAL_ 2338057900 M2P_TMS_BackWaterPress_2 255 "无效" ;
VAL_ 2338057900 M2P_TMS_OutWaterPress_2 255 "无效" ;
VAL_ 2338057901 M2P_TMS_BackWaterPress_2 255 "无效" ;
VAL_ 2338057901 M2P_TMS_OutWaterPress_2 255 "无效" ;
VAL_ 2338057902 M2P_TMS_BackWaterPress_2 255 "无效" ;
VAL_ 2338057902 M2P_TMS_OutWaterPress_2 255 "无效" ;
VAL_ 2338057903 M2P_TMS_BackWaterPress_2 255 "无效" ;
VAL_ 2338057903 M2P_TMS_OutWaterPress_2 255 "无效" ;
VAL_ 2337341249 S2A_TMS_OutWaterPress 255 "无效" ;
VAL_ 2337341249 S2A_TMS_BackWaterPress 255 "无效" ;
VAL_ 2337341250 S2A_TMS_OutWaterPress 255 "无效" ;
VAL_ 2337341250 S2A_TMS_BackWaterPress 255 "无效" ;
VAL_ 2337341251 S2A_TMS_OutWaterPress 255 "无效" ;
VAL_ 2337341251 S2A_TMS_BackWaterPress 255 "无效" ;
VAL_ 2337341252 S2A_TMS_OutWaterPress 255 "无效" ;
VAL_ 2337341252 S2A_TMS_BackWaterPress 255 "无效" ;
VAL_ 2337341253 S2A_TMS_OutWaterPress 255 "无效" ;
VAL_ 2337341253 S2A_TMS_BackWaterPress 255 "无效" ;
VAL_ 2337341254 S2A_TMS_OutWaterPress 255 "无效" ;
VAL_ 2337341254 S2A_TMS_BackWaterPress 255 "无效" ;
VAL_ 2337341255 S2A_TMS_OutWaterPress 255 "无效" ;
VAL_ 2337341255 S2A_TMS_BackWaterPress 255 "无效" ;
VAL_ 2337341256 S2A_TMS_OutWaterPress 255 "无效" ;
VAL_ 2337341256 S2A_TMS_BackWaterPress 255 "无效" ;
VAL_ 2337341257 S2A_TMS_OutWaterPress 255 "无效" ;
VAL_ 2337341257 S2A_TMS_BackWaterPress 255 "无效" ;
VAL_ 2337341258 S2A_TMS_OutWaterPress 255 "无效" ;
VAL_ 2337341258 S2A_TMS_BackWaterPress 255 "无效" ;
VAL_ 2337341259 S2A_TMS_OutWaterPress 255 "无效" ;
VAL_ 2337341259 S2A_TMS_BackWaterPress 255 "无效" ;
VAL_ 2337341260 S2A_TMS_OutWaterPress 255 "无效" ;
VAL_ 2337341260 S2A_TMS_BackWaterPress 255 "无效" ;
VAL_ 2337341261 S2A_TMS_OutWaterPress 255 "无效" ;
VAL_ 2337341261 S2A_TMS_BackWaterPress 255 "无效" ;
VAL_ 2337341262 S2A_TMS_OutWaterPress 255 "无效" ;
VAL_ 2337341262 S2A_TMS_BackWaterPress 255 "无效" ;
VAL_ 2337341263 S2A_TMS_OutWaterPress 255 "无效" ;
VAL_ 2337341263 S2A_TMS_BackWaterPress 255 "无效" ;
VAL_ 2337341264 S2A_TMS_OutWaterPress 255 "无效" ;
VAL_ 2337341264 S2A_TMS_BackWaterPress 255 "无效" ;
VAL_ 2337341265 S2A_TMS_OutWaterPress 255 "无效" ;
VAL_ 2337341265 S2A_TMS_BackWaterPress 255 "无效" ;
VAL_ 2337341266 S2A_TMS_OutWaterPress 255 "无效" ;
VAL_ 2337341266 S2A_TMS_BackWaterPress 255 "无效" ;
VAL_ 2337341267 S2A_TMS_OutWaterPress 255 "无效" ;
VAL_ 2337341267 S2A_TMS_BackWaterPress 255 "无效" ;
VAL_ 2337341268 S2A_TMS_OutWaterPress 255 "无效" ;
VAL_ 2337341268 S2A_TMS_BackWaterPress 255 "无效" ;
VAL_ 2337341269 S2A_TMS_OutWaterPress 255 "无效" ;
VAL_ 2337341269 S2A_TMS_BackWaterPress 255 "无效" ;
VAL_ 2337341270 S2A_TMS_OutWaterPress 255 "无效" ;
VAL_ 2337341270 S2A_TMS_BackWaterPress 255 "无效" ;
VAL_ 2337341271 S2A_TMS_OutWaterPress 255 "无效" ;
VAL_ 2337341271 S2A_TMS_BackWaterPress 255 "无效" ;
VAL_ 2337341272 S2A_TMS_OutWaterPress 255 "无效" ;
VAL_ 2337341272 S2A_TMS_BackWaterPress 255 "无效" ;
VAL_ 2337341273 S2A_TMS_OutWaterPress 255 "无效" ;
VAL_ 2337341273 S2A_TMS_BackWaterPress 255 "无效" ;
VAL_ 2337341274 S2A_TMS_OutWaterPress 255 "无效" ;
VAL_ 2337341274 S2A_TMS_BackWaterPress 255 "无效" ;
VAL_ 2337341275 S2A_TMS_OutWaterPress 255 "无效" ;
VAL_ 2337341275 S2A_TMS_BackWaterPress 255 "无效" ;
VAL_ 2337341276 S2A_TMS_OutWaterPress 255 "无效" ;
VAL_ 2337341276 S2A_TMS_BackWaterPress 255 "无效" ;
VAL_ 2337341277 S2A_TMS_OutWaterPress 255 "无效" ;
VAL_ 2337341277 S2A_TMS_BackWaterPress 255 "无效" ;
VAL_ 2337341278 S2A_TMS_OutWaterPress 255 "无效" ;
VAL_ 2337341278 S2A_TMS_BackWaterPress 255 "无效" ;
VAL_ 2337341279 S2A_TMS_OutWaterPress 255 "无效" ;
VAL_ 2337341279 S2A_TMS_BackWaterPress 255 "无效" ;
VAL_ 2337341280 S2A_TMS_OutWaterPress 255 "无效" ;
VAL_ 2337341280 S2A_TMS_BackWaterPress 255 "无效" ;
VAL_ 2337341281 S2A_TMS_OutWaterPress 255 "无效" ;
VAL_ 2337341281 S2A_TMS_BackWaterPress 255 "无效" ;
VAL_ 2337341282 S2A_TMS_OutWaterPress 255 "无效" ;
VAL_ 2337341282 S2A_TMS_BackWaterPress 255 "无效" ;
VAL_ 2337341283 S2A_TMS_OutWaterPress 255 "无效" ;
VAL_ 2337341283 S2A_TMS_BackWaterPress 255 "无效" ;
VAL_ 2337341284 S2A_TMS_OutWaterPress 255 "无效" ;
VAL_ 2337341284 S2A_TMS_BackWaterPress 255 "无效" ;
VAL_ 2337341285 S2A_TMS_OutWaterPress 255 "无效" ;
VAL_ 2337341285 S2A_TMS_BackWaterPress 255 "无效" ;
VAL_ 2337341286 S2A_TMS_OutWaterPress 255 "无效" ;
VAL_ 2337341286 S2A_TMS_BackWaterPress 255 "无效" ;
VAL_ 2337341287 S2A_TMS_OutWaterPress 255 "无效" ;
VAL_ 2337341287 S2A_TMS_BackWaterPress 255 "无效" ;
VAL_ 2337341288 S2A_TMS_OutWaterPress 255 "无效" ;
VAL_ 2337341288 S2A_TMS_BackWaterPress 255 "无效" ;
VAL_ 2337341289 S2A_TMS_OutWaterPress 255 "无效" ;
VAL_ 2337341289 S2A_TMS_BackWaterPress 255 "无效" ;
VAL_ 2337341290 S2A_TMS_OutWaterPress 255 "无效" ;
VAL_ 2337341290 S2A_TMS_BackWaterPress 255 "无效" ;
VAL_ 2337341291 S2A_TMS_OutWaterPress 255 "无效" ;
VAL_ 2337341291 S2A_TMS_BackWaterPress 255 "无效" ;
VAL_ 2337341292 S2A_TMS_OutWaterPress 255 "无效" ;
VAL_ 2337341292 S2A_TMS_BackWaterPress 255 "无效" ;
VAL_ 2337341293 S2A_TMS_OutWaterPress 255 "无效" ;
VAL_ 2337341293 S2A_TMS_BackWaterPress 255 "无效" ;
VAL_ 2337341294 S2A_TMS_OutWaterPress 255 "无效" ;
VAL_ 2337341294 S2A_TMS_BackWaterPress 255 "无效" ;
VAL_ 2337341295 S2A_TMS_OutWaterPress 255 "无效" ;
VAL_ 2337341295 S2A_TMS_BackWaterPress 255 "无效" ;
VAL_ 2337341296 S2A_TMS_OutWaterPress 255 "无效" ;
VAL_ 2337341296 S2A_TMS_BackWaterPress 255 "无效" ;
VAL_ 2337341297 S2A_TMS_OutWaterPress 255 "无效" ;
VAL_ 2337341297 S2A_TMS_BackWaterPress 255 "无效" ;
VAL_ 2337341298 S2A_TMS_OutWaterPress 255 "无效" ;
VAL_ 2337341298 S2A_TMS_BackWaterPress 255 "无效" ;
VAL_ 2337341299 S2A_TMS_OutWaterPress 255 "无效" ;
VAL_ 2337341299 S2A_TMS_BackWaterPress 255 "无效" ;
VAL_ 2337341300 S2A_TMS_OutWaterPress 255 "无效" ;
VAL_ 2337341300 S2A_TMS_BackWaterPress 255 "无效" ;
VAL_ 2337341301 S2A_TMS_OutWaterPress 255 "无效" ;
VAL_ 2337341301 S2A_TMS_BackWaterPress 255 "无效" ;
VAL_ 2337341302 S2A_TMS_OutWaterPress 255 "无效" ;
VAL_ 2337341302 S2A_TMS_BackWaterPress 255 "无效" ;
VAL_ 2337341303 S2A_TMS_OutWaterPress 255 "无效" ;
VAL_ 2337341303 S2A_TMS_BackWaterPress 255 "无效" ;
VAL_ 2337341304 S2A_TMS_OutWaterPress 255 "无效" ;
VAL_ 2337341304 S2A_TMS_BackWaterPress 255 "无效" ;
VAL_ 2337341305 S2A_TMS_OutWaterPress 255 "无效" ;
VAL_ 2337341305 S2A_TMS_BackWaterPress 255 "无效" ;
VAL_ 2337341306 S2A_TMS_OutWaterPress 255 "无效" ;
VAL_ 2337341306 S2A_TMS_BackWaterPress 255 "无效" ;
VAL_ 2337341307 S2A_TMS_OutWaterPress 255 "无效" ;
VAL_ 2337341307 S2A_TMS_BackWaterPress 255 "无效" ;
VAL_ 2337341308 S2A_TMS_OutWaterPress 255 "无效" ;
VAL_ 2337341308 S2A_TMS_BackWaterPress 255 "无效" ;
VAL_ 2337341309 S2A_TMS_OutWaterPress 255 "无效" ;
VAL_ 2337341309 S2A_TMS_BackWaterPress 255 "无效" ;
VAL_ 2337341310 S2A_TMS_OutWaterPress 255 "无效" ;
VAL_ 2337341310 S2A_TMS_BackWaterPress 255 "无效" ;
VAL_ 2337341311 S2A_TMS_OutWaterPress 255 "无效" ;
VAL_ 2337341311 S2A_TMS_BackWaterPress 255 "无效" ;
VAL_ 2334588737 S2A_IMMEncodeFlgFromSBMU_01 0 "未驱动" 1 "驱动" ;
VAL_ 2334588738 S2A_IMMEncodeFlgFromSBMU_02 0 "未驱动" 1 "驱动" ;
VAL_ 2334588739 S2A_IMMEncodeFlgFromSBMU_03 0 "未驱动" 1 "驱动" ;
VAL_ 2334588740 S2A_IMMEncodeFlgFromSBMU_04 0 "未驱动" 1 "驱动" ;
VAL_ 2334588741 S2A_IMMEncodeFlgFromSBMU_05 0 "未驱动" 1 "驱动" ;
VAL_ 2334588742 S2A_IMMEncodeFlgFromSBMU_06 0 "未驱动" 1 "驱动" ;
VAL_ 2334588743 S2A_IMMEncodeFlgFromSBMU_07 0 "未驱动" 1 "驱动" ;
VAL_ 2334588744 S2A_IMMEncodeFlgFromSBMU_08 0 "未驱动" 1 "驱动" ;
VAL_ 2334588745 S2A_IMMEncodeFlgFromSBMU_09 0 "未驱动" 1 "驱动" ;
VAL_ 2334588746 S2A_IMMEncodeFlgFromSBMU_10 0 "未驱动" 1 "驱动" ;
VAL_ 2334588747 S2A_IMMEncodeFlgFromSBMU_11 0 "未驱动" 1 "驱动" ;
VAL_ 2334588748 S2A_IMMEncodeFlgFromSBMU_12 0 "未驱动" 1 "驱动" ;
VAL_ 2334588749 S2A_IMMEncodeFlgFromSBMU_13 0 "未驱动" 1 "驱动" ;
VAL_ 2334588750 S2A_IMMEncodeFlgFromSBMU_14 0 "未驱动" 1 "驱动" ;
VAL_ 2334588751 S2A_IMMEncodeFlgFromSBMU_15 0 "未驱动" 1 "驱动" ;
VAL_ 2334588752 S2A_IMMEncodeFlgFromSBMU_16 0 "未驱动" 1 "驱动" ;
VAL_ 2334588753 S2A_IMMEncodeFlgFromSBMU_17 0 "未驱动" 1 "驱动" ;
VAL_ 2334588754 S2A_IMMEncodeFlgFromSBMU_18 0 "未驱动" 1 "驱动" ;
VAL_ 2334588755 S2A_IMMEncodeFlgFromSBMU_19 0 "未驱动" 1 "驱动" ;
VAL_ 2334588756 S2A_IMMEncodeFlgFromSBMU_20 0 "未驱动" 1 "驱动" ;
VAL_ 2334588757 S2A_IMMEncodeFlgFromSBMU_21 0 "未驱动" 1 "驱动" ;
VAL_ 2334588758 S2A_IMMEncodeFlgFromSBMU_22 0 "未驱动" 1 "驱动" ;
VAL_ 2334588759 S2A_IMMEncodeFlgFromSBMU_23 0 "未驱动" 1 "驱动" ;
VAL_ 2334588760 S2A_IMMEncodeFlgFromSBMU_24 0 "未驱动" 1 "驱动" ;
VAL_ 2334588761 S2A_IMMEncodeFlgFromSBMU_25 0 "未驱动" 1 "驱动" ;
VAL_ 2334588762 S2A_IMMEncodeFlgFromSBMU_26 0 "未驱动" 1 "驱动" ;
VAL_ 2334588763 S2A_IMMEncodeFlgFromSBMU_27 0 "未驱动" 1 "驱动" ;
VAL_ 2334588764 S2A_IMMEncodeFlgFromSBMU_28 0 "未驱动" 1 "驱动" ;
VAL_ 2334588765 S2A_IMMEncodeFlgFromSBMU_29 0 "未驱动" 1 "驱动" ;
VAL_ 2334588766 S2A_IMMEncodeFlgFromSBMU_30 0 "未驱动" 1 "驱动" ;
VAL_ 2334588767 S2A_IMMEncodeFlgFromSBMU_31 0 "未驱动" 1 "驱动" ;
VAL_ 2334588768 S2A_IMMEncodeFlgFromSBMU_32 0 "未驱动" 1 "驱动" ;
VAL_ 2334588769 S2A_IMMEncodeFlgFromSBMU_33 0 "未驱动" 1 "驱动" ;
VAL_ 2334588770 S2A_IMMEncodeFlgFromSBMU_34 0 "未驱动" 1 "驱动" ;
VAL_ 2334588771 S2A_IMMEncodeFlgFromSBMU_35 0 "未驱动" 1 "驱动" ;
VAL_ 2334588772 S2A_IMMEncodeFlgFromSBMU_36 0 "未驱动" 1 "驱动" ;
VAL_ 2334588773 S2A_IMMEncodeFlgFromSBMU_37 0 "未驱动" 1 "驱动" ;
VAL_ 2334588774 S2A_IMMEncodeFlgFromSBMU_38 0 "未驱动" 1 "驱动" ;
VAL_ 2334588775 S2A_IMMEncodeFlgFromSBMU_39 0 "未驱动" 1 "驱动" ;
VAL_ 2334588776 S2A_IMMEncodeFlgFromSBMU_40 0 "未驱动" 1 "驱动" ;
VAL_ 2334588777 S2A_IMMEncodeFlgFromSBMU_41 0 "未驱动" 1 "驱动" ;
VAL_ 2334588778 S2A_IMMEncodeFlgFromSBMU_42 0 "未驱动" 1 "驱动" ;
VAL_ 2334588779 S2A_IMMEncodeFlgFromSBMU_43 0 "未驱动" 1 "驱动" ;
VAL_ 2334588780 S2A_IMMEncodeFlgFromSBMU_44 0 "未驱动" 1 "驱动" ;
VAL_ 2334588781 S2A_IMMEncodeFlgFromSBMU_45 0 "未驱动" 1 "驱动" ;
VAL_ 2334588782 S2A_IMMEncodeFlgFromSBMU_46 0 "未驱动" 1 "驱动" ;
VAL_ 2334588783 S2A_IMMEncodeFlgFromSBMU_47 0 "未驱动" 1 "驱动" ;
VAL_ 2334588784 S2A_IMMEncodeFlgFromSBMU_48 0 "未驱动" 1 "驱动" ;
VAL_ 2334588785 S2A_IMMEncodeFlgFromSBMU_49 0 "未驱动" 1 "驱动" ;
VAL_ 2334588786 S2A_IMMEncodeFlgFromSBMU_50 0 "未驱动" 1 "驱动" ;
VAL_ 2334588787 S2A_IMMEncodeFlgFromSBMU_51 0 "未驱动" 1 "驱动" ;
VAL_ 2334588788 S2A_IMMEncodeFlgFromSBMU_52 0 "未驱动" 1 "驱动" ;
VAL_ 2334588789 S2A_IMMEncodeFlgFromSBMU_53 0 "未驱动" 1 "驱动" ;
VAL_ 2334588790 S2A_IMMEncodeFlgFromSBMU_54 0 "未驱动" 1 "驱动" ;
VAL_ 2334588791 S2A_IMMEncodeFlgFromSBMU_55 0 "未驱动" 1 "驱动" ;
VAL_ 2334588792 S2A_IMMEncodeFlgFromSBMU_56 0 "未驱动" 1 "驱动" ;
VAL_ 2334588793 S2A_IMMEncodeFlgFromSBMU_57 0 "未驱动" 1 "驱动" ;
VAL_ 2334588794 S2A_IMMEncodeFlgFromSBMU_58 0 "未驱动" 1 "驱动" ;
VAL_ 2334588795 S2A_IMMEncodeFlgFromSBMU_59 0 "未驱动" 1 "驱动" ;
VAL_ 2334588796 S2A_IMMEncodeFlgFromSBMU_60 0 "未驱动" 1 "驱动" ;
VAL_ 2334588797 S2A_IMMEncodeFlgFromSBMU_61 0 "未驱动" 1 "驱动" ;
VAL_ 2334588798 S2A_IMMEncodeFlgFromSBMU_62 0 "未驱动" 1 "驱动" ;
VAL_ 2334588799 S2A_IMMEncodeFlgFromSBMU_63 0 "未驱动" 1 "驱动" ;
VAL_ 2467467183 M2S_IMMCode_State 0 "非编码中" 1 "编码中" ;
VAL_ 2467467183 M2S_IMMIndexPower_SBMUAddr 0 "不使能" 1 "SBMU1对IMM高边供电使能" 2 "SBMU2对IMM高边供电使能" 3 "SBMU3对IMM高边供电使能" 4 "SBMU4对IMM高边供电使能" 5 "SBMU5对IMM高边供电使能" 6 "SBMU6对IMM高边供电使能" 7 "SBMU7对IMM高边供电使能" 8 "SBMU8对IMM高边供电使能" 9 "SBMU9对IMM高边供电使能" 10 "SBMU10对IMM高边供电使能" 11 "SBMU11对IMM高边供电使能" 12 "SBMU12对IMM高边供电使能" 13 "SBMU13对IMM高边供电使能" 14 "SBMU14对IMM高边供电使能" 15 "SBMU15对IMM高边供电使能" 16 "SBMU16对IMM高边供电使能" 17 "SBMU17对IMM高边供电使能" 18 "SBMU18对IMM高边供电使能" 19 "SBMU19对IMM高边供电使能" 20 "SBMU20对IMM高边供电使能" 21 "SBMU21对IMM高边供电使能" 22 "SBMU22对IMM高边供电使能" 23 "SBMU23对IMM高边供电使能" 24 "SBMU24对IMM高边供电使能" 25 "SBMU25对IMM高边供电使能" 26 "SBMU26对IMM高边供电使能" 27 "SBMU27对IMM高边供电使能" 28 "SBMU28对IMM高边供电使能" 29 "SBMU29对IMM高边供电使能" 30 "SBMU30对IMM高边供电使能" 31 "SBMU31对IMM高边供电使能" 63 "所有SBMU对IMM高边供电使能" ;
